                            <description>Periodic transaction timeout interrupt enable</description>
                            <lsb>3</lsb>
                            <msb>3</msb>
                            <access>read-write</access>
                            <enumeratedValues>
                                <enumeratedValue>
                                    <name>0</name>
                                    <description>Disabled</description>
                                    <value>#0</value>
                                </enumeratedValue>
                                <enumeratedValue>
                                    <name>1</name>
                                    <description>Enabled</description>
                                    <value>#1</value>
                                </enumeratedValue>
                            </enumeratedValues>
                        </field>
                        <field>
                            <name>DSTOCS0E</name>
                            <description>OM_DQS timeout for slave0 interrupt enable</description>
                            <lsb>4</lsb>
                            <msb>4</msb>
                            <access>read-write</access>
                            <enumeratedValues>
                                <enumeratedValue>
                                    <name>0</name>
                                    <description>Disabled</description>
                                    <value>#0</value>
                                </enumeratedValue>
                                <enumeratedValue>
                                    <name>1</name>
                                    <description>Enabled</description>
                                    <value>#1</value>
                                </enumeratedValue>
                            </enumeratedValues>
                        </field>
                        <field>
                            <name>DSTOCS1E</name>
                            <description>OM_DQS timeout for slave1 interrupt enable</description>
                            <lsb>5</lsb>
                            <msb>5</msb>
                            <access>read-write</access>
                            <enumeratedValues>
                                <enumeratedValue>
                                    <name>0</name>
                                    <description>Disabled</description>
                                    <value>#0</value>
                                </enumeratedValue>
                                <enumeratedValue>
                                    <name>1</name>
                                    <description>Enabled</description>
                                    <value>#1</value>
                                </enumeratedValue>
                            </enumeratedValues>
                        </field>
                        <field>
                            <name>ECSCS1E</name>
                            <description>ECC error detection for slave1 interrupt enable</description>
                            <lsb>9</lsb>
                            <msb>9</msb>
                            <access>read-write</access>
                            <enumeratedValues>
                                <enumeratedValue>
                                    <name>0</name>
                                    <description>Disabled</description>
                                    <value>#0</value>
                                </enumeratedValue>
                                <enumeratedValue>
                                    <name>1</name>
                                    <description>Enabled</description>
                                    <value>#1</value>
                                </enumeratedValue>
                            </enumeratedValues>
                        </field>
                        <field>
                            <name>INTCS1E</name>
                            <description>Interrupt detection for slave1 interrupt enable</description>
                            <lsb>13</lsb>
                            <msb>13</msb>
                            <access>read-write</access>
                            <enumeratedValues>
                                <enumeratedValue>
                                    <name>0</name>
                                    <description>Disabled</description>
                                    <value>#0</value>
                                </enumeratedValue>
                                <enumeratedValue>
                                    <name>1</name>
                                    <description>Enabled</description>
                                    <value>#1</value>
                                </enumeratedValue>
                            </enumeratedValues>
                        </field>
                        <field>
                            <name>BUSERRCH0E</name>
                            <description>System bus error for ch0 interrupt enable</description>
                            <lsb>20</lsb>
                            <msb>20</msb>
                            <access>read-write</access>
                            <enumeratedValues>
                                <enumeratedValue>
                                    <name>0</name>
                                    <description>Disabled</description>
                                    <value>#0</value>
                                </enumeratedValue>
                                <enumeratedValue>
                                    <name>1</name>
                                    <description>Enabled</description>
                                    <value>#1</value>
                                </enumeratedValue>
                            </enumeratedValues>
                        </field>
                        <field>
                            <name>CAFAILCS0E</name>
                            <description>Calibration failed for slave0 interrupt enable</description>
                            <lsb>28</lsb>
                            <msb>28</msb>
                            <access>read-write</access>
                            <enumeratedValues>
                                <enumeratedValue>
                                    <name>0</name>
                                    <description>Disabled</description>
                                    <value>#0</value>
                                </enumeratedValue>
                                <enumeratedValue>
                                    <name>1</name>
                                    <description>Enabled</description>
                                    <value>#1</value>
                                </enumeratedValue>
                            </enumeratedValues>
                        </field>
                        <field>
                            <name>CAFAILCS1E</name>
                            <description>Calibration failed for slave1 interrupt enable</description>
                            <lsb>29</lsb>
                            <msb>29</msb>
                            <access>read-write</access>
                            <enumeratedValues>
                                <enumeratedValue>
                                    <name>0</name>
                                    <description>Disabled</description>
                                    <value>#0</value>
                                </enumeratedValue>
                                <enumeratedValue>
                                    <name>1</name>
                                    <description>Enabled</description>
                                    <value>#1</value>
                                </enumeratedValue>
                            </enumeratedValues>
                        </field>
                        <field>
                            <name>CASUCCS0E</name>
                            <description>Calibration success for slave0 interrupt enable</description>
                            <lsb>30</lsb>
                            <msb>30</msb>
                            <access>read-write</access>
                            <enumeratedValues>
                                <enumeratedValue>
                                    <name>0</name>
                                    <description>Disabled</description>
                                    <value>#0</value>
                                </enumeratedValue>
                                <enumeratedValue>
                                    <name>1</name>
                                    <description>Enabled</description>
                                    <value>#1</value>
                                </enumeratedValue>
                            </enumeratedValues>
                        </field>
                        <field>
                            <name>CASUCCS1E</name>
                            <description>Calibration success for slave1 interrupt enable</description>
                            <lsb>31</lsb>
                            <msb>31</msb>
                            <access>read-write</access>
                            <enumeratedValues>
                                <enumeratedValue>
                                    <name>0</name>
                                    <description>Disabled</description>
                                    <value>#0</value>
                                </enumeratedValue>
                                <enumeratedValue>
                                    <name>1</name>
                                    <description>Enabled</description>
                                    <value>#1</value>
                                </enumeratedValue>
                            </enumeratedValues>
                        </field>
                    </fields>
                </register>
            </registers>
        </peripheral>
        <peripheral>
            <name>CRC</name>
            <description>CRC Calculator</description>
            <baseAddress>0x40310000</baseAddress>
            <addressBlock>
                <offset>0x00</offset>
                <size>2</size>
                <usage>registers</usage>
            </addressBlock>
            <addressBlock>
                <offset>0x04</offset>
                <size>4</size>
                <usage>registers</usage>
            </addressBlock>
            <addressBlock>
                <offset>0x08</offset>
                <size>4</size>
                <usage>registers</usage>
            </addressBlock>
            <addressBlock>
                <offset>0x0C</offset>
                <size>2</size>
                <usage>registers</usage>
            </addressBlock>
            <registers>
                <register>
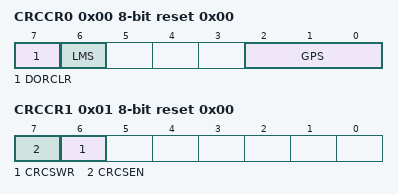
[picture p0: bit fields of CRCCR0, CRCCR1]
                    <name>CRCCR0</name>
                    <description>CRC Control Register 0</description>
                    <addressOffset>0x00</addressOffset>
                    <size>8</size>
                    <access>read-write</access>
                    <resetValue>0x00</resetValue>
                    <resetMask>0xff</resetMask>
                    <fields>
                        <field>
                            <name>GPS</name>
                            <description>CRC Generating Polynomial Switching</description>
                            <lsb>0</lsb>
                            <msb>2</msb>
                            <access>read-write</access>
                            <enumeratedValues>
                                <enumeratedValue>
                                    <name>001</name>
                                    <description>8-bit CRC-8 (X8 + X2 + X + 1)</description>
                                    <value>#001</value>
                                </enumeratedValue>
                                <enumeratedValue>
                                    <name>010</name>
                                    <description>16-bit CRC-16 (X16 + X15 + X2 + 1)</description>
                                    <value>#010</value>
                                </enumeratedValue>
                                <enumeratedValue>
                                    <name>011</name>
                                    <description>16-bit CRC-CCITT (X16 + X12 + X5 + 1)</description>
                                    <value>#011</value>
                                </enumeratedValue>
                                <enumeratedValue>
                                    <name>100</name>
                                    <description>32-bit CRC-32 (X32 + X26 + X23 + X22 + X16 + X12 + X11 +X10 + X8 + X7 + X5 + X4 + X2 + X + 1)</description>
                                    <value>#100</value>
                                </enumeratedValue>
                                <enumeratedValue>
                                    <name>101</name>
                                    <description>32-bit CRC-32C (X32 + X28 + X27 + X26 + X25 + X23 + X22 + X20 + X19 + X18 + X14 + X13 + X11 + X10 + X9 + X8 + X6 + 1)</description>
                                    <value>#101</value>
                                </enumeratedValue>
                                <enumeratedValue>
                                    <name>Others</name>
                                    <description>No calculation is executed</description>
                                    <isDefault>true</isDefault>
                                </enumeratedValue>
                            </enumeratedValues>
                        </field>
                        <field>
                            <name>LMS</name>
                            <description>CRC Calculation Switching</description>
                            <lsb>6</lsb>
                            <msb>6</msb>
                            <access>read-write</access>
                            <enumeratedValues>
                                <enumeratedValue>
                                    <name>0</name>
                                    <description>Generate CRC code for LSB-first communication</description>
                                    <value>#0</value>
                                </enumeratedValue>
                                <enumeratedValue>
                                    <name>1</name>
                                    <description>Generate CRC code for MSB-first communication</description>
                                    <value>#1</value>
                                </enumeratedValue>
                            </enumeratedValues>
                        </field>
                        <field>
                            <name>DORCLR</name>
                            <description>CRCDOR/CRCDOR_HA/CRCDOR_BY Register Clear</description>
                            <lsb>7</lsb>
                            <msb>7</msb>
                            <access>write-only</access>
                            <enumeratedValues>
                                <enumeratedValue>
                                    <name>0</name>
                                    <description>No effect</description>
                                    <value>#0</value>
                                </enumeratedValue>
                                <enumeratedValue>
                                    <name>1</name>
                                    <description>Clear the CRCDOR/CRCDOR_HA/CRCDOR_BY register</description>
                                    <value>#1</value>
                                </enumeratedValue>
                            </enumeratedValues>
                        </field>
                    </fields>
                </register>
                <register>
                    <name>CRCCR1</name>
                    <description>CRC Control Register 1</description>
                    <addressOffset>0x01</addressOffset>
                    <size>8</size>
                    <access>read-write</access>
                    <resetValue>0x00</resetValue>
                    <resetMask>0xff</resetMask>
                    <fields>
                        <field>
                            <name>CRCSWR</name>
                            <description>Snoop-On-Write/Read Switch</description>
                            <lsb>6</lsb>
                            <msb>6</msb>
                            <access>read-write</access>
                            <enumeratedValues>
                                <enumeratedValue>
                                    <name>0</name>
                                    <description>Snoop-on-read</description>
                                    <value>#0</value>
                                </enumeratedValue>
                                <enumeratedValue>
                                    <name>1</name>
                                    <description>Snoop-on-write</description>
                                    <value>#1</value>
                                </enumeratedValue>
                            </enumeratedValues>
                        </field>
                        <field>
                            <name>CRCSEN</name>
                            <description>Snoop Enable</description>
                            <lsb>7</lsb>
                            <msb>7</msb>
                            <access>read-write</access>
                            <enumeratedValues>
                                <enumeratedValue>
                                    <name>0</name>
                                    <description>Disabled</description>
                                    <value>#0</value>
                                </enumeratedValue>
                                <enumeratedValue>
                                    <name>1</name>
                                    <description>Enabled</description>
                                    <value>#1</value>
                                </enumeratedValue>
                            </enumeratedValues>
                        </field>
                    </fields>
                </register>
                <register>
                    <name>CRCDIR</name>
                    <description>CRC Data Input Register</description>
                    <addressOffset>0x04</addressOffset>
                    <size>32</size>
                    <access>read-write</access>
                    <resetValue>0x00000000</resetValue>
                    <resetMask>0xffffffff</resetMask>
                </register>
                <register>
                    <name>CRCDIR_BY</name>
                    <description>CRC Data Input Register</description>
                    <alternateRegister>CRCDIR</alternateRegister>
                    <addressOffset>0x04</addressOffset>
                    <size>8</size>
                    <access>read-write</access>
                    <resetValue>0x00</resetValue>
                    <resetMask>0xff</resetMask>
                </register>
                <register>
                    <name>CRCDOR</name>
                    <description>CRC Data Output Register</description>
                    <addressOffset>0x08</addressOffset>
                    <size>32</size>
                    <access>read-write</access>
                    <resetValue>0x00000000</resetValue>
                    <resetMask>0xffffffff</resetMask>
                </register>
                <register>
                    <name>CRCDOR_HA</name>
                    <description>CRC Data Output Register</description>
                    <alternateRegister>CRCDOR</alternateRegister>
                    <addressOffset>0x08</addressOffset>
                    <size>16</size>
                    <access>read-write</access>
                    <resetValue>0x0000</resetValue>
                    <resetMask>0xffff</resetMask>
                </register>
                <register>
                    <name>CRCDOR_BY</name>
                    <description>CRC Data Output Register</description>
                    <alternateRegister>CRCDOR</alternateRegister>
                    <addressOffset>0x08</addressOffset>
                    <size>8</size>
                    <access>read-write</access>
                    <resetValue>0x00</resetValue>
                    <resetMask>0xff</resetMask>
                </register>
                <register>
                    <name>CRCSAR</name>
                    <description>Snoop Address Register</description>
                    <addressOffset>0x0C</addressOffset>
                    <size>16</size>
                    <access>read-write</access>
                    <resetValue>0x0000</resetValue>
                    <resetMask>0xffff</resetMask>
                    <fields>
                        <field>
                            <name>CRCSA</name>
                            <description>Register Snoop Address</description>
                            <lsb>0</lsb>
                            <msb>13</msb>
                            <access>read-write</access>
                        </field>
                    </fields>
                </register>
            </registers>
        </peripheral>
        <peripheral>
            <name>DOC_B</name>
            <description>Data Operation Circuit</description>
            <baseAddress>0x40311000</baseAddress>
            <addressBlock>
                <offset>0x00</offset>
                <size>1</size>
                <usage>registers</usage>
            </addressBlock>
            <addressBlock>
                <offset>0x04</offset>
                <size>1</size>
                <usage>registers</usage>
            </addressBlock>
            <addressBlock>
                <offset>0x08</offset>
                <size>1</size>
                <usage>registers</usage>
            </addressBlock>
            <addressBlock>
                <offset>0x0C</offset>
                <size>12</size>
                <usage>registers</usage>
            </addressBlock>
            <registers>
                <register>
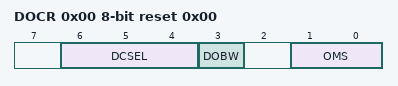
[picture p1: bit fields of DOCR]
                    <name>DOCR</name>
                    <description>DOC Control Register</description>
                    <addressOffset>0x00</addressOffset>
                    <size>8</size>
                    <access>read-write</access>
                    <resetValue>0x00</resetValue>
                    <resetMask>0xff</resetMask>
                    <fields>
                        <field>
                            <name>OMS</name>
                            <description>Operating Mode Select</description>
                            <lsb>0</lsb>
                            <msb>1</msb>
                            <access>read-write</access>
                            <enumeratedValues>
                                <enumeratedValue>
                                    <name>00</name>
                                    <description>Data comparison mode</description>
                                    <value>#00</value>
                                </enumeratedValue>
                                <enumeratedValue>
                                    <name>01</name>
                                    <description>Data addition mode</description>
                                    <value>#01</value>
                                </enumeratedValue>
                                <enumeratedValue>
                                    <name>10</name>
                                    <description>Data subtraction mode</description>
                                    <value>#10</value>
                                </enumeratedValue>
                                <enumeratedValue>
                                    <name>11</name>
                                    <description>Setting prohibited</description>
                                    <value>#11</value>
                                </enumeratedValue>
                            </enumeratedValues>
                        </field>
                        <field>
                            <name>DOBW</name>
                            <description>Data Operation Bit Width Select</description>
                            <lsb>3</lsb>
                            <msb>3</msb>
                            <access>read-write</access>
                            <enumeratedValues>
                                <enumeratedValue>
                                    <name>0</name>
                                    <description>16-bit</description>
                                    <value>#0</value>
                                </enumeratedValue>
                                <enumeratedValue>
                                    <name>1</name>
                                    <description>32-bit</description>
                                    <value>#1</value>
                                </enumeratedValue>
                            </enumeratedValues>
                        </field>
                        <field>
                            <name>DCSEL</name>
                            <description>Detection Condition Select</description>
                            <lsb>4</lsb>
                            <msb>6</msb>
                            <access>read-write</access>
                            <enumeratedValues>
                                <enumeratedValue>
                                    <name>000</name>
                                    <description>Mismatch (DODSR0 ≠ DODIR)</description>
                                    <value>#000</value>
                                </enumeratedValue>
                                <enumeratedValue>
                                    <name>001</name>
                                    <description>Match (DODSR0 = DODIR)</description>
                                    <value>#001</value>
                                </enumeratedValue>
                                <enumeratedValue>
                                    <name>010</name>
                                    <description>Lower (DODSR0 &gt; DODIR)</description>
                                    <value>#010</value>
                                </enumeratedValue>
                                <enumeratedValue>
                                    <name>011</name>
                                    <description>Upper (DODSR0 &lt; DODIR)</description>
                                    <value>#011</value>
                                </enumeratedValue>
                                <enumeratedValue>
                                    <name>100</name>
                                    <description>Inside window (DODSR0 &lt; DODIR &lt; DODSR1)</description>
                                    <value>#100</value>
                                </enumeratedValue>
                                <enumeratedValue>
                                    <name>101</name>
                                    <description>Outside window (DODIR &lt; DODSR0, DODSR1 &lt; DODIR)</description>
                                    <value>#101</value>
                                </enumeratedValue>
                                <enumeratedValue>
                                    <name>Others</name>
                                    <description>Setting prohibited</description>
                                    <isDefault>true</isDefault>
                                </enumeratedValue>
                            </enumeratedValues>
                        </field>
                    </fields>
                </register>
                <register>
                    <name>DOSR</name>
                    <description>DOC Flag Status Register</description>
                    <addressOffset>0x04</addressOffset>
                    <size>8</size>
                    <access>read-only</access>
                    <resetValue>0x00</resetValue>
                    <resetMask>0xff</resetMask>
                    <fields>
                        <field>
                            <name>DOPCF</name>
                            <description>Data Operation Circuit Flag</description>
                            <lsb>0</lsb>
                            <msb>0</msb>
                            <access>read-only</access>
                        </field>
                    </fields>
                </register>
                <register>
                    <name>DOSCR</name>
                    <description>DOC Flag Status Clear Register</description>
                    <addressOffset>0x08</addressOffset>
                    <size>8</size>
                    <access>write-only</access>
                    <resetValue>0x00</resetValue>
                    <resetMask>0xff</resetMask>
                    <fields>
                        <field>
                            <name>DOPCFCL</name>
                            <description>DOPCF Clear</description>
                            <lsb>0</lsb>
                            <msb>0</msb>
                            <access>write-only</access>
                            <enumeratedValues>
                                <enumeratedValue>
                                    <name>0</name>
                                    <description>Maintains the DOPCF flag state.</description>
                                    <value>#0</value>
                                </enumeratedValue>
                                <enumeratedValue>
                                    <name>1</name>
                                    <description>Clears the DOPCF flag.</description>
                                    <value>#1</value>
                                </enumeratedValue>
                            </enumeratedValues>
                        </field>
                    </fields>
                </register>
                <register>
                    <name>DODIR</name>
                    <description>DOC Data Input Register</description>
                    <addressOffset>0x0C</addressOffset>
                    <size>32</size>
                    <access>read-write</access>
                    <resetValue>0x00000000</resetValue>
                    <resetMask>0xffffffff</resetMask>
                </register>
                <register>
                    <name>DODSR0</name>
                    <description>DOC Data Setting Register 0</description>
                    <addressOffset>0x10</addressOffset>
                    <size>32</size>
                    <access>read-write</access>
                    <resetValue>0x00000000</resetValue>
                    <resetMask>0xffffffff</resetMask>
                </register>
                <register>
                    <name>DODSR1</name>
                    <description>DOC Data Setting Register 1</description>
                    <addressOffset>0x14</addressOffset>
                    <size>32</size>
                    <access>read-write</access>
                    <resetValue>0x00000000</resetValue>
                    <resetMask>0xffffffff</resetMask>
                </register>
            </registers>
        </peripheral>
        <peripheral>
            <name>GPT320</name>
            <description>General PWM 32-bit Timer 0</description>
            <baseAddress>0x40322000</baseAddress>
            <addressBlock>
                <offset>0x00</offset>
                <size>68</size>
                <usage>registers</usage>
            </addressBlock>
            <addressBlock>
                <offset>0x48</offset>
                <size>36</size>
                <usage>registers</usage>
            </addressBlock>
            <addressBlock>
                <offset>0x70</offset>
                <size>32</size>
                <usage>registers</usage>
            </addressBlock>
            <addressBlock>
                <offset>0xA4</offset>
                <size>4</size>
                <usage>registers</usage>
            </addressBlock>
            <addressBlock>
                <offset>0xB8</offset>
                <size>8</size>
                <usage>registers</usage>
            </addressBlock>
            <addressBlock>
                <offset>0xD0</offset>
                <size>8</size>
                <usage>registers</usage>
            </addressBlock>
            <registers>
                <register>
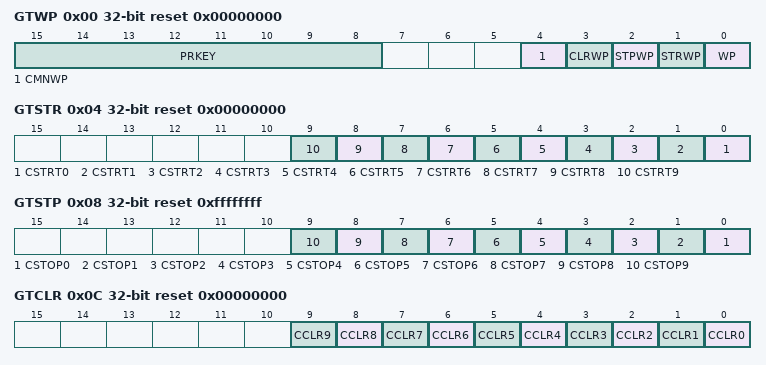
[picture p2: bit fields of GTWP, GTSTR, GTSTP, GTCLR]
                    <name>GTWP</name>
                    <description>General PWM Timer Write-Protection Register</description>
                    <addressOffset>0x00</addressOffset>
                    <size>32</size>
                    <access>read-write</access>
                    <resetValue>0x00000000</resetValue>
                    <resetMask>0xffffffff</resetMask>
                    <fields>
                        <field>
                            <name>WP</name>
                            <description>Register Write Disable</description>
                            <lsb>0</lsb>
                            <msb>0</msb>
                            <access>read-write</access>
                            <enumeratedValues>
                                <enumeratedValue>
                                    <name>0</name>
                                    <description>Write to the register enabled</description>
                                    <value>#0</value>
                                </enumeratedValue>
                                <enumeratedValue>
                                    <name>1</name>
                                    <description>Write to the register disabled</description>
                                    <value>#1</value>
                                </enumeratedValue>
                            </enumeratedValues>
                        </field>
                        <field>
                            <name>STRWP</name>
                            <description>GTSTR.CSTRT Bit Write Disable</description>
                            <lsb>1</lsb>
                            <msb>1</msb>
                            <access>read-write</access>
                            <enumeratedValues>
                                <enumeratedValue>
                                    <name>0</name>
                                    <description>Write to the bit is enabled</description>
                                    <value>#0</value>
                                </enumeratedValue>
                                <enumeratedValue>
                                    <name>1</name>
                                    <description>Write to the bit is disabled</description>
                                    <value>#1</value>
                                </enumeratedValue>
                            </enumeratedValues>
                        </field>
                        <field>
                            <name>STPWP</name>
                            <description>GTSTP.CSTOP Bit Write Disable</description>
                            <lsb>2</lsb>
                            <msb>2</msb>
                            <access>read-write</access>
                            <enumeratedValues>
                                <enumeratedValue>
                                    <name>0</name>
                                    <description>Write to the bit is enabled</description>
                                    <value>#0</value>
                                </enumeratedValue>
                                <enumeratedValue>
                                    <name>1</name>
                                    <description>Write to the bit is disabled</description>
                                    <value>#1</value>
                                </enumeratedValue>
                            </enumeratedValues>
                        </field>
                        <field>
                            <name>CLRWP</name>
                            <description>GTCLR.CCLR Bit Write Disable</description>
                            <lsb>3</lsb>
                            <msb>3</msb>
                            <access>read-write</access>
                            <enumeratedValues>
                                <enumeratedValue>
                                    <name>0</name>
                                    <description>Write to the bit is enabled</description>
                                    <value>#0</value>
                                </enumeratedValue>
                                <enumeratedValue>
                                    <name>1</name>
                                    <description>Write to the bit is disabled</description>
                                    <value>#1</value>
                                </enumeratedValue>
                            </enumeratedValues>
                        </field>
                        <field>
                            <name>CMNWP</name>
                            <description>Common Register Write Disabled</description>
                            <lsb>4</lsb>
                            <msb>4</msb>
                            <access>read-write</access>
                            <enumeratedValues>
                                <enumeratedValue>
                                    <name>0</name>
                                    <description>Write to the register is enabled</description>
                                    <value>#0</value>
                                </enumeratedValue>
                                <enumeratedValue>
                                    <name>1</name>
                                    <description>Write to the register is disabled</description>
                                    <value>#1</value>
                                </enumeratedValue>
                            </enumeratedValues>
                        </field>
                        <field>
                            <name>PRKEY</name>
                            <description>GTWP Key Code</description>
                            <lsb>8</lsb>
                            <msb>15</msb>
                            <access>write-only</access>
                        </field>
                    </fields>
                </register>
                <register>
                    <name>GTSTR</name>
                    <description>General PWM Timer Software Start Register</description>
                    <addressOffset>0x04</addressOffset>
                    <size>32</size>
                    <access>read-write</access>
                    <resetValue>0x00000000</resetValue>
                    <resetMask>0xffffffff</resetMask>
                    <fields>
                        <field>
                            <name>CSTRT0</name>
                            <description>Channel n GTCNT Count Start (n : the same as bit position value)</description>
                            <lsb>0</lsb>
                            <msb>0</msb>
                            <access>read-write</access>
                            <enumeratedValues>
                                <enumeratedValue>
                                    <name>0</name>
                                    <description>GTCNT counter not start</description>
                                    <value>#0</value>
                                </enumeratedValue>
                                <enumeratedValue>
                                    <name>1</name>
                                    <description>GTCNT counter start</description>
                                    <value>#1</value>
                                </enumeratedValue>
                            </enumeratedValues>
                        </field>
                        <field>
                            <name>CSTRT1</name>
                            <description>Channel n GTCNT Count Start (n : the same as bit position value)</description>
                            <lsb>1</lsb>
                            <msb>1</msb>
                            <access>read-write</access>
                            <enumeratedValues>
                                <enumeratedValue>
                                    <name>0</name>
                                    <description>GTCNT counter not start</description>
                                    <value>#0</value>
                                </enumeratedValue>
                                <enumeratedValue>
                                    <name>1</name>
                                    <description>GTCNT counter start</description>
                                    <value>#1</value>
                                </enumeratedValue>
                            </enumeratedValues>
                        </field>
                        <field>
                            <name>CSTRT2</name>
                            <description>Channel n GTCNT Count Start (n : the same as bit position value)</description>
                            <lsb>2</lsb>
                            <msb>2</msb>
                            <access>read-write</access>
                            <enumeratedValues>
                                <enumeratedValue>
                                    <name>0</name>
                                    <description>GTCNT counter not start</description>
                                    <value>#0</value>
                                </enumeratedValue>
                                <enumeratedValue>
                                    <name>1</name>
                                    <description>GTCNT counter start</description>
                                    <value>#1</value>
                                </enumeratedValue>
                            </enumeratedValues>
                        </field>
                        <field>
                            <name>CSTRT3</name>
                            <description>Channel n GTCNT Count Start (n : the same as bit position value)</description>
                            <lsb>3</lsb>
                            <msb>3</msb>
                            <access>read-write</access>
                            <enumeratedValues>
                                <enumeratedValue>
                                    <name>0</name>
                                    <description>GTCNT counter not start</description>
                                    <value>#0</value>
                                </enumeratedValue>
                                <enumeratedValue>
                                    <name>1</name>
                                    <description>GTCNT counter start</description>
                                    <value>#1</value>
                                </enumeratedValue>
                            </enumeratedValues>
                        </field>
                        <field>
                            <name>CSTRT4</name>
                            <description>Channel n GTCNT Count Start (n : the same as bit position value)</description>
                            <lsb>4</lsb>
                            <msb>4</msb>
                            <access>read-write</access>
                            <enumeratedValues>
                                <enumeratedValue>
                                    <name>0</name>
                                    <description>GTCNT counter not start</description>
                                    <value>#0</value>
                                </enumeratedValue>
                                <enumeratedValue>
                                    <name>1</name>
                                    <description>GTCNT counter start</description>
                                    <value>#1</value>
                                </enumeratedValue>
                            </enumeratedValues>
                        </field>
                        <field>
                            <name>CSTRT5</name>
                            <description>Channel n GTCNT Count Start (n : the same as bit position value)</description>
                            <lsb>5</lsb>
                            <msb>5</msb>
                            <access>read-write</access>
                            <enumeratedValues>
                                <enumeratedValue>
                                    <name>0</name>
                                    <description>GTCNT counter not start</description>
                                    <value>#0</value>
                                </enumeratedValue>
                                <enumeratedValue>
                                    <name>1</name>
                                    <description>GTCNT counter start</description>
                                    <value>#1</value>
                                </enumeratedValue>
                            </enumeratedValues>
                        </field>
                        <field>
                            <name>CSTRT6</name>
                            <description>Channel n GTCNT Count Start (n : the same as bit position value)</description>
                            <lsb>6</lsb>
                            <msb>6</msb>
                            <access>read-write</access>
                            <enumeratedValues>
                                <enumeratedValue>
                                    <name>0</name>
                                    <description>GTCNT counter not start</description>
                                    <value>#0</value>
                                </enumeratedValue>
                                <enumeratedValue>
                                    <name>1</name>
                                    <description>GTCNT counter start</description>
                                    <value>#1</value>
                                </enumeratedValue>
                            </enumeratedValues>
                        </field>
                        <field>
                            <name>CSTRT7</name>
                            <description>Channel n GTCNT Count Start (n : the same as bit position value)</description>
                            <lsb>7</lsb>
                            <msb>7</msb>
                            <access>read-write</access>
                            <enumeratedValues>
                                <enumeratedValue>
                                    <name>0</name>
                                    <description>GTCNT counter not start</description>
                                    <value>#0</value>
                                </enumeratedValue>
                                <enumeratedValue>
                                    <name>1</name>
                                    <description>GTCNT counter start</description>
                                    <value>#1</value>
                                </enumeratedValue>
                            </enumeratedValues>
                        </field>
                        <field>
                            <name>CSTRT8</name>
                            <description>Channel n GTCNT Count Start (n : the same as bit position value)</description>
                            <lsb>8</lsb>
                            <msb>8</msb>
                            <access>read-write</access>
                            <enumeratedValues>
                                <enumeratedValue>
                                    <name>0</name>
                                    <description>GTCNT counter not start</description>
                                    <value>#0</value>
                                </enumeratedValue>
                                <enumeratedValue>
                                    <name>1</name>
                                    <description>GTCNT counter start</description>
                                    <value>#1</value>
                                </enumeratedValue>
                            </enumeratedValues>
                        </field>
                        <field>
                            <name>CSTRT9</name>
                            <description>Channel n GTCNT Count Start (n : the same as bit position value)</description>
                            <lsb>9</lsb>
                            <msb>9</msb>
                            <access>read-write</access>
                            <enumeratedValues>
                                <enumeratedValue>
                                    <name>0</name>
                                    <description>GTCNT counter not start</description>
                                    <value>#0</value>
                                </enumeratedValue>
                                <enumeratedValue>
                                    <name>1</name>
                                    <description>GTCNT counter start</description>
                                    <value>#1</value>
                                </enumeratedValue>
                            </enumeratedValues>
                        </field>
                    </fields>
                </register>
                <register>
                    <name>GTSTP</name>
                    <description>General PWM Timer Software Stop Register</description>
                    <addressOffset>0x08</addressOffset>
                    <size>32</size>
                    <access>read-write</access>
                    <resetValue>0xffffffff</resetValue>
                    <resetMask>0xffffffff</resetMask>
                    <fields>
                        <field>
                            <name>CSTOP0</name>
                            <description>Channel n GTCNT Count Stop (n : the same as bit position value)</description>
                            <lsb>0</lsb>
                            <msb>0</msb>
                            <access>read-write</access>
                            <enumeratedValues>
                                <enumeratedValue>
                                    <name>0</name>
                                    <description>GTCNT counter not stop</description>
                                    <value>#0</value>
                                </enumeratedValue>
                                <enumeratedValue>
                                    <name>1</name>
                                    <description>GTCNT counter stop</description>
                                    <value>#1</value>
                                </enumeratedValue>
                            </enumeratedValues>
                        </field>
                        <field>
                            <name>CSTOP1</name>
                            <description>Channel n GTCNT Count Stop (n : the same as bit position value)</description>
                            <lsb>1</lsb>
                            <msb>1</msb>
                            <access>read-write</access>
                            <enumeratedValues>
                                <enumeratedValue>
                                    <name>0</name>
                                    <description>GTCNT counter not stop</description>
                                    <value>#0</value>
                                </enumeratedValue>
                                <enumeratedValue>
                                    <name>1</name>
                                    <description>GTCNT counter stop</description>
                                    <value>#1</value>
                                </enumeratedValue>
                            </enumeratedValues>
                        </field>
                        <field>
                            <name>CSTOP2</name>
                            <description>Channel n GTCNT Count Stop (n : the same as bit position value)</description>
                            <lsb>2</lsb>
                            <msb>2</msb>
                            <access>read-write</access>
                            <enumeratedValues>
                                <enumeratedValue>
                                    <name>0</name>
                                    <description>GTCNT counter not stop</description>
                                    <value>#0</value>
                                </enumeratedValue>
                                <enumeratedValue>
                                    <name>1</name>
                                    <description>GTCNT counter stop</description>
                                    <value>#1</value>
                                </enumeratedValue>
                            </enumeratedValues>
                        </field>
                        <field>
                            <name>CSTOP3</name>
                            <description>Channel n GTCNT Count Stop (n : the same as bit position value)</description>
                            <lsb>3</lsb>
                            <msb>3</msb>
                            <access>read-write</access>
                            <enumeratedValues>
                                <enumeratedValue>
                                    <name>0</name>
                                    <description>GTCNT counter not stop</description>
                                    <value>#0</value>
                                </enumeratedValue>
                                <enumeratedValue>
                                    <name>1</name>
                                    <description>GTCNT counter stop</description>
                                    <value>#1</value>
                                </enumeratedValue>
                            </enumeratedValues>
                        </field>
                        <field>
                            <name>CSTOP4</name>
                            <description>Channel n GTCNT Count Stop (n : the same as bit position value)</description>
                            <lsb>4</lsb>
                            <msb>4</msb>
                            <access>read-write</access>
                            <enumeratedValues>
                                <enumeratedValue>
                                    <name>0</name>
                                    <description>GTCNT counter not stop</description>
                                    <value>#0</value>
                                </enumeratedValue>
                                <enumeratedValue>
                                    <name>1</name>
                                    <description>GTCNT counter stop</description>
                                    <value>#1</value>
                                </enumeratedValue>
                            </enumeratedValues>
                        </field>
                        <field>
                            <name>CSTOP5</name>
                            <description>Channel n GTCNT Count Stop (n : the same as bit position value)</description>
                            <lsb>5</lsb>
                            <msb>5</msb>
                            <access>read-write</access>
                            <enumeratedValues>
                                <enumeratedValue>
                                    <name>0</name>
                                    <description>GTCNT counter not stop</description>
                                    <value>#0</value>
                                </enumeratedValue>
                                <enumeratedValue>
                                    <name>1</name>
                                    <description>GTCNT counter stop</description>
                                    <value>#1</value>
                                </enumeratedValue>
                            </enumeratedValues>
                        </field>
                        <field>
                            <name>CSTOP6</name>
                            <description>Channel n GTCNT Count Stop (n : the same as bit position value)</description>
                            <lsb>6</lsb>
                            <msb>6</msb>
                            <access>read-write</access>
                            <enumeratedValues>
                                <enumeratedValue>
                                    <name>0</name>
                                    <description>GTCNT counter not stop</description>
                                    <value>#0</value>
                                </enumeratedValue>
                                <enumeratedValue>
                                    <name>1</name>
                                    <description>GTCNT counter stop</description>
                                    <value>#1</value>
                                </enumeratedValue>
                            </enumeratedValues>
                        </field>
                        <field>
                            <name>CSTOP7</name>
                            <description>Channel n GTCNT Count Stop (n : the same as bit position value)</description>
                            <lsb>7</lsb>
                            <msb>7</msb>
                            <access>read-write</access>
                            <enumeratedValues>
                                <enumeratedValue>
                                    <name>0</name>
                                    <description>GTCNT counter not stop</description>
                                    <value>#0</value>
                                </enumeratedValue>
                                <enumeratedValue>
                                    <name>1</name>
                                    <description>GTCNT counter stop</description>
                                    <value>#1</value>
                                </enumeratedValue>
                            </enumeratedValues>
                        </field>
                        <field>
                            <name>CSTOP8</name>
                            <description>Channel n GTCNT Count Stop (n : the same as bit position value)</description>
                            <lsb>8</lsb>
                            <msb>8</msb>
                            <access>read-write</access>
                            <enumeratedValues>
                                <enumeratedValue>
                                    <name>0</name>
                                    <description>GTCNT counter not stop</description>
                                    <value>#0</value>
                                </enumeratedValue>
                                <enumeratedValue>
                                    <name>1</name>
                                    <description>GTCNT counter stop</description>
                                    <value>#1</value>
                                </enumeratedValue>
                            </enumeratedValues>
                        </field>
                        <field>
                            <name>CSTOP9</name>
                            <description>Channel n GTCNT Count Stop (n : the same as bit position value)</description>
                            <lsb>9</lsb>
                            <msb>9</msb>
                            <access>read-write</access>
                            <enumeratedValues>
                                <enumeratedValue>
                                    <name>0</name>
                                    <description>GTCNT counter not stop</description>
                                    <value>#0</value>
                                </enumeratedValue>
                                <enumeratedValue>
                                    <name>1</name>
                                    <description>GTCNT counter stop</description>
                                    <value>#1</value>
                                </enumeratedValue>
                            </enumeratedValues>
                        </field>
                    </fields>
                </register>
                <register>
                    <name>GTCLR</name>
                    <description>General PWM Timer Software Clear Register</description>
                    <addressOffset>0x0C</addressOffset>
                    <size>32</size>
                    <access>write-only</access>
                    <resetValue>0x00000000</resetValue>
                    <resetMask>0xffffffff</resetMask>
                    <fields>
                        <field>
                            <name>CCLR0</name>
                            <description>Channel n GTCNT Count Clear (n : the same as bit position value)</description>
                            <lsb>0</lsb>
                            <msb>0</msb>
                            <access>write-only</access>
                            <enumeratedValues>
                                <enumeratedValue>
                                    <name>0</name>
                                    <description>GTCNT counter is not cleared</description>
                                    <value>#0</value>
                                </enumeratedValue>
                                <enumeratedValue>
                                    <name>1</name>
                                    <description>GTCNT counter is cleared</description>
                                    <value>#1</value>
                                </enumeratedValue>
                            </enumeratedValues>
                        </field>
                        <field>
                            <name>CCLR1</name>
                            <description>Channel n GTCNT Count Clear (n : the same as bit position value)</description>
                            <lsb>1</lsb>
                            <msb>1</msb>
                            <access>write-only</access>
                            <enumeratedValues>
                                <enumeratedValue>
                                    <name>0</name>
                                    <description>GTCNT counter is not cleared</description>
                                    <value>#0</value>
                                </enumeratedValue>
                                <enumeratedValue>
                                    <name>1</name>
                                    <description>GTCNT counter is cleared</description>
                                    <value>#1</value>
                                </enumeratedValue>
                            </enumeratedValues>
                        </field>
                        <field>
                            <name>CCLR2</name>
                            <description>Channel n GTCNT Count Clear (n : the same as bit position value)</description>
                            <lsb>2</lsb>
                            <msb>2</msb>
                            <access>write-only</access>
                            <enumeratedValues>
                                <enumeratedValue>
                                    <name>0</name>
                                    <description>GTCNT counter is not cleared</description>
                                    <value>#0</value>
                                </enumeratedValue>
                                <enumeratedValue>
                                    <name>1</name>
                                    <description>GTCNT counter is cleared</description>
                                    <value>#1</value>
                                </enumeratedValue>
                            </enumeratedValues>
                        </field>
                        <field>
                            <name>CCLR3</name>
                            <description>Channel n GTCNT Count Clear (n : the same as bit position value)</description>
                            <lsb>3</lsb>
                            <msb>3</msb>
                            <access>write-only</access>
                            <enumeratedValues>
                                <enumeratedValue>
                                    <name>0</name>
                                    <description>GTCNT counter is not cleared</description>
                                    <value>#0</value>
                                </enumeratedValue>
                                <enumeratedValue>
                                    <name>1</name>
                                    <description>GTCNT counter is cleared</description>
                                    <value>#1</value>
                                </enumeratedValue>
                            </enumeratedValues>
                        </field>
                        <field>
                            <name>CCLR4</name>
                            <description>Channel n GTCNT Count Clear (n : the same as bit position value)</description>
                            <lsb>4</lsb>
                            <msb>4</msb>
                            <access>write-only</access>
                            <enumeratedValues>
                                <enumeratedValue>
                                    <name>0</name>
                                    <description>GTCNT counter is not cleared</description>
                                    <value>#0</value>
                                </enumeratedValue>
                                <enumeratedValue>
                                    <name>1</name>
                                    <description>GTCNT counter is cleared</description>
                                    <value>#1</value>
                                </enumeratedValue>
                            </enumeratedValues>
                        </field>
                        <field>
                            <name>CCLR5</name>
                            <description>Channel n GTCNT Count Clear (n : the same as bit position value)</description>
                            <lsb>5</lsb>
                            <msb>5</msb>
                            <access>write-only</access>
                            <enumeratedValues>
                                <enumeratedValue>
                                    <name>0</name>
                                    <description>GTCNT counter is not cleared</description>
                                    <value>#0</value>
                                </enumeratedValue>
                                <enumeratedValue>
                                    <name>1</name>
                                    <description>GTCNT counter is cleared</description>
                                    <value>#1</value>
                                </enumeratedValue>
                            </enumeratedValues>
                        </field>
                        <field>
                            <name>CCLR6</name>
                            <description>Channel n GTCNT Count Clear (n : the same as bit position value)</description>
                            <lsb>6</lsb>
                            <msb>6</msb>
                            <access>write-only</access>
                            <enumeratedValues>
                                <enumeratedValue>
                                    <name>0</name>
                                    <description>GTCNT counter is not cleared</description>
                                    <value>#0</value>
                                </enumeratedValue>
                                <enumeratedValue>
                                    <name>1</name>
                                    <description>GTCNT counter is cleared</description>
                                    <value>#1</value>
                                </enumeratedValue>
                            </enumeratedValues>
                        </field>
                        <field>
                            <name>CCLR7</name>
                            <description>Channel n GTCNT Count Clear (n : the same as bit position value)</description>
                            <lsb>7</lsb>
                            <msb>7</msb>
                            <access>write-only</access>
                            <enumeratedValues>
                                <enumeratedValue>
                                    <name>0</name>
                                    <description>GTCNT counter is not cleared</description>
                                    <value>#0</value>
                                </enumeratedValue>
                                <enumeratedValue>
                                    <name>1</name>
                                    <description>GTCNT counter is cleared</description>
                                    <value>#1</value>
                                </enumeratedValue>
                            </enumeratedValues>
                        </field>
                        <field>
                            <name>CCLR8</name>
                            <description>Channel n GTCNT Count Clear (n : the same as bit position value)</description>
                            <lsb>8</lsb>
                            <msb>8</msb>
                            <access>write-only</access>
                            <enumeratedValues>
                                <enumeratedValue>
                                    <name>0</name>
                                    <description>GTCNT counter is not cleared</description>
                                    <value>#0</value>
                                </enumeratedValue>
                                <enumeratedValue>
                                    <name>1</name>
                                    <description>GTCNT counter is cleared</description>
                                    <value>#1</value>
                                </enumeratedValue>
                            </enumeratedValues>
                        </field>
                        <field>
                            <name>CCLR9</name>
                            <description>Channel n GTCNT Count Clear (n : the same as bit position value)</description>
                            <lsb>9</lsb>
                            <msb>9</msb>
                            <access>write-only</access>
                            <enumeratedValues>
                                <enumeratedValue>
                                    <name>0</name>
                                    <description>GTCNT counter is not cleared</description>
                                    <value>#0</value>
                                </enumeratedValue>
                                <enumeratedValue>
                                    <name>1</name>
                                    <description>GTCNT counter is cleared</description>
                                    <value>#1</value>
                                </enumeratedValue>
                            </enumeratedValues>
                        </field>
                    </fields>
                </register>
                <register>
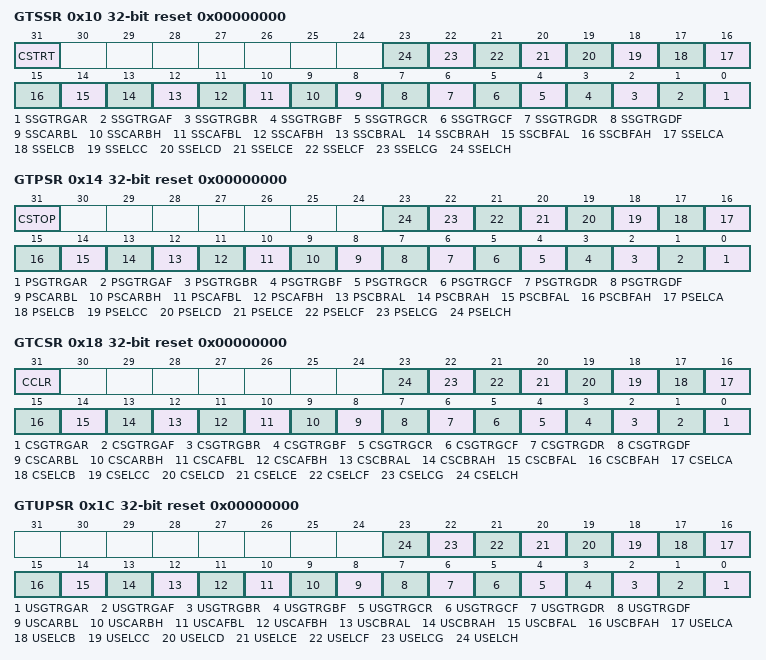
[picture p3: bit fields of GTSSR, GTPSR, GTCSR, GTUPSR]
                    <name>GTSSR</name>
                    <description>General PWM Timer Start Source Select Register</description>
                    <addressOffset>0x10</addressOffset>
                    <size>32</size>
                    <access>read-write</access>
                    <resetValue>0x00000000</resetValue>
                    <resetMask>0xffffffff</resetMask>
                    <fields>
                        <field>
                            <name>SSGTRGAR</name>
                            <description>GTETRGA Pin Rising Input Source Counter Start Enable</description>
                            <lsb>0</lsb>
                            <msb>0</msb>
                            <access>read-write</access>
                            <enumeratedValues>
                                <enumeratedValue>
                                    <name>0</name>
                                    <description>Counter start disabled on the rising edge of GTETRGA input</description>
                                    <value>#0</value>
                                </enumeratedValue>
                                <enumeratedValue>
                                    <name>1</name>
                                    <description>Counter start enabled on the rising edge of GTETRGA input</description>
                                    <value>#1</value>
                                </enumeratedValue>
                            </enumeratedValues>
                        </field>
                        <field>
                            <name>SSGTRGAF</name>
                            <description>GTETRGA Pin Falling Input Source Counter Start Enable</description>
                            <lsb>1</lsb>
                            <msb>1</msb>
                            <access>read-write</access>
                            <enumeratedValues>
                                <enumeratedValue>
                                    <name>0</name>
                                    <description>Counter start disabled on the falling edge of GTETRGA input</description>
                                    <value>#0</value>
                                </enumeratedValue>
                                <enumeratedValue>
                                    <name>1</name>
                                    <description>Counter start enabled on the falling edge of GTETRGA input</description>
                                    <value>#1</value>
                                </enumeratedValue>
                            </enumeratedValues>
                        </field>
                        <field>
                            <name>SSGTRGBR</name>
                            <description>GTETRGB Pin Rising Input Source Counter Start Enable</description>
                            <lsb>2</lsb>
                            <msb>2</msb>
                            <access>read-write</access>
                            <enumeratedValues>
                                <enumeratedValue>
                                    <name>0</name>
                                    <description>Counter start disabled on the rising edge of GTETRGB input</description>
                                    <value>#0</value>
                                </enumeratedValue>
                                <enumeratedValue>
                                    <name>1</name>
                                    <description>Counter start enabled on the rising edge of GTETRGB input</description>
                                    <value>#1</value>
                                </enumeratedValue>
                            </enumeratedValues>
                        </field>
                        <field>
                            <name>SSGTRGBF</name>
                            <description>GTETRGB Pin Falling Input Source Counter Start Enable</description>
                            <lsb>3</lsb>
                            <msb>3</msb>
                            <access>read-write</access>
                            <enumeratedValues>
                                <enumeratedValue>
                                    <name>0</name>
                                    <description>Counter start disabled on the falling edge of GTETRGB input</description>
                                    <value>#0</value>
                                </enumeratedValue>
                                <enumeratedValue>
                                    <name>1</name>
                                    <description>Counter start enabled on the falling edge of GTETRGB input</description>
                                    <value>#1</value>
                                </enumeratedValue>
                            </enumeratedValues>
                        </field>
                        <field>
                            <name>SSGTRGCR</name>
                            <description>GTETRGC Pin Rising Input Source Counter Start Enable</description>
                            <lsb>4</lsb>
                            <msb>4</msb>
                            <access>read-write</access>
                            <enumeratedValues>
                                <enumeratedValue>
                                    <name>0</name>
                                    <description>Counter start disabled on the rising edge of GTETRGC input</description>
                                    <value>#0</value>
                                </enumeratedValue>
                                <enumeratedValue>
                                    <name>1</name>
                                    <description>Counter start enabled on the rising edge of GTETRGC input</description>
                                    <value>#1</value>
                                </enumeratedValue>
                            </enumeratedValues>
                        </field>
                        <field>
                            <name>SSGTRGCF</name>
                            <description>GTETRGC Pin Falling Input Source Counter Start Enable</description>
                            <lsb>5</lsb>
                            <msb>5</msb>
                            <access>read-write</access>
                            <enumeratedValues>
                                <enumeratedValue>
                                    <name>0</name>
                                    <description>Counter start disabled on the falling edge of GTETRGC input</description>
                                    <value>#0</value>
                                </enumeratedValue>
                                <enumeratedValue>
                                    <name>1</name>
                                    <description>Counter start enabled on the falling edge of GTETRGC input</description>
                                    <value>#1</value>
                                </enumeratedValue>
                            </enumeratedValues>
                        </field>
                        <field>
                            <name>SSGTRGDR</name>
                            <description>GTETRGD Pin Rising Input Source Counter Start Enable</description>
                            <lsb>6</lsb>
                            <msb>6</msb>
                            <access>read-write</access>
                            <enumeratedValues>
                                <enumeratedValue>
                                    <name>0</name>
                                    <description>Counter start disabled on the rising edge of GTETRGD input</description>
                                    <value>#0</value>
                                </enumeratedValue>
                                <enumeratedValue>
                                    <name>1</name>
                                    <description>Counter start enabled on the rising edge of GTETRGD input</description>
                                    <value>#1</value>
                                </enumeratedValue>
                            </enumeratedValues>
                        </field>
                        <field>
                            <name>SSGTRGDF</name>
                            <description>GTETRGD Pin Falling Input Source Counter Start Enable</description>
                            <lsb>7</lsb>
                            <msb>7</msb>
                            <access>read-write</access>
                            <enumeratedValues>
                                <enumeratedValue>
                                    <name>0</name>
                                    <description>Counter start disabled on the falling edge of GTETRGD input</description>
                                    <value>#0</value>
                                </enumeratedValue>
                                <enumeratedValue>
                                    <name>1</name>
                                    <description>Counter start enabled on the falling edge of GTETRGD input</description>
                                    <value>#1</value>
                                </enumeratedValue>
                            </enumeratedValues>
                        </field>
                        <field>
                            <name>SSCARBL</name>
                            <description>GTIOCnA Pin Rising Input during GTIOCnB Value Low Source Counter Start Enable</description>
                            <lsb>8</lsb>
                            <msb>8</msb>
                            <access>read-write</access>
                            <enumeratedValues>
                                <enumeratedValue>
                                    <name>0</name>
                                    <description>Counter start disabled on the rising edge of GTIOCnA input when GTIOCnB input is 0</description>
                                    <value>#0</value>
                                </enumeratedValue>
                                <enumeratedValue>
                                    <name>1</name>
                                    <description>Counter start enabled on the rising edge of GTIOCnA input when GTIOCnB input is 0</description>
                                    <value>#1</value>
                                </enumeratedValue>
                            </enumeratedValues>
                        </field>
                        <field>
                            <name>SSCARBH</name>
                            <description>GTIOCnA Pin Rising Input during GTIOCnB Value High Source Counter Start Enable</description>
                            <lsb>9</lsb>
                            <msb>9</msb>
                            <access>read-write</access>
                            <enumeratedValues>
                                <enumeratedValue>
                                    <name>0</name>
                                    <description>Counter start disabled on the rising edge of GTIOCnA input when GTIOCnB input is 1</description>
                                    <value>#0</value>
                                </enumeratedValue>
                                <enumeratedValue>
                                    <name>1</name>
                                    <description>Counter start enabled on the rising edge of GTIOCnA input when GTIOCnB input is 1</description>
                                    <value>#1</value>
                                </enumeratedValue>
                            </enumeratedValues>
                        </field>
                        <field>
                            <name>SSCAFBL</name>
                            <description>GTIOCnA Pin Falling Input during GTIOCnB Value Low Source Counter Start Enable</description>
                            <lsb>10</lsb>
                            <msb>10</msb>
                            <access>read-write</access>
                            <enumeratedValues>
                                <enumeratedValue>
                                    <name>0</name>
                                    <description>Counter start disabled on the falling edge of GTIOCnA input when GTIOCnB input is 0</description>
                                    <value>#0</value>
                                </enumeratedValue>
                                <enumeratedValue>
                                    <name>1</name>
                                    <description>Counter start enabled on the falling edge of GTIOCnA input when GTIOCnB input is 0</description>
                                    <value>#1</value>
                                </enumeratedValue>
                            </enumeratedValues>
                        </field>
                        <field>
                            <name>SSCAFBH</name>
                            <description>GTIOCnA Pin Falling Input during GTIOCnB Value High Source Counter Start Enable</description>
                            <lsb>11</lsb>
                            <msb>11</msb>
                            <access>read-write</access>
                            <enumeratedValues>
                                <enumeratedValue>
                                    <name>0</name>
                                    <description>Counter start disabled on the falling edge of GTIOCnA input when GTIOCnB input is 1</description>
                                    <value>#0</value>
                                </enumeratedValue>
                                <enumeratedValue>
                                    <name>1</name>
                                    <description>Counter start enabled on the falling edge of GTIOCnA input when GTIOCnB input is 1</description>
                                    <value>#1</value>
                                </enumeratedValue>
                            </enumeratedValues>
                        </field>
                        <field>
                            <name>SSCBRAL</name>
                            <description>GTIOCnB Pin Rising Input during GTIOCnA Value Low Source Counter Start Enable</description>
                            <lsb>12</lsb>
                            <msb>12</msb>
                            <access>read-write</access>
                            <enumeratedValues>
                                <enumeratedValue>
                                    <name>0</name>
                                    <description>Counter start disabled on the rising edge of GTIOCnB input when GTIOCnA input is 0</description>
                                    <value>#0</value>
                                </enumeratedValue>
                                <enumeratedValue>
                                    <name>1</name>
                                    <description>Counter start enabled on the rising edge of GTIOCnB input when GTIOCnA input is 0</description>
                                    <value>#1</value>
                                </enumeratedValue>
                            </enumeratedValues>
                        </field>
                        <field>
                            <name>SSCBRAH</name>
                            <description>GTIOCnB Pin Rising Input during GTIOCnA Value High Source Counter Start Enable</description>
                            <lsb>13</lsb>
                            <msb>13</msb>
                            <access>read-write</access>
                            <enumeratedValues>
                                <enumeratedValue>
                                    <name>0</name>
                                    <description>Counter start disabled on the rising edge of GTIOCnB input when GTIOCnA input is 1</description>
                                    <value>#0</value>
                                </enumeratedValue>
                                <enumeratedValue>
                                    <name>1</name>
                                    <description>Counter start enabled on the rising edge of GTIOCnB input when GTIOCnA input is 1</description>
                                    <value>#1</value>
                                </enumeratedValue>
                            </enumeratedValues>
                        </field>
                        <field>
                            <name>SSCBFAL</name>
                            <description>GTIOCnB Pin Falling Input during GTIOCnA Value Low Source Counter Start Enable</description>
                            <lsb>14</lsb>
                            <msb>14</msb>
                            <access>read-write</access>
                            <enumeratedValues>
                                <enumeratedValue>
                                    <name>0</name>
                                    <description>Counter start disabled on the falling edge of GTIOCnB input when GTIOCnA input is 0</description>
                                    <value>#0</value>
                                </enumeratedValue>
                                <enumeratedValue>
                                    <name>1</name>
                                    <description>Counter start enabled on the falling edge of GTIOCnB input when GTIOCnA input is 0</description>
                                    <value>#1</value>
                                </enumeratedValue>
                            </enumeratedValues>
                        </field>
                        <field>
                            <name>SSCBFAH</name>
                            <description>GTIOCnB Pin Falling Input during GTIOCnA Value High Source Counter Start Enable</description>
                            <lsb>15</lsb>
                            <msb>15</msb>
                            <access>read-write</access>
                            <enumeratedValues>
                                <enumeratedValue>
                                    <name>0</name>
                                    <description>Counter start disabled on the falling edge of GTIOCnB input when GTIOCnA input is 1</description>
                                    <value>#0</value>
                                </enumeratedValue>
                                <enumeratedValue>
                                    <name>1</name>
                                    <description>Counter start enabled on the falling edge of GTIOCnB input when GTIOCnA input is 1</description>
                                    <value>#1</value>
                                </enumeratedValue>
                            </enumeratedValues>
                        </field>
                        <field>
                            <name>SSELCA</name>
                            <description>ELC_GPTA Event Source Counter Start Enable</description>
                            <lsb>16</lsb>
                            <msb>16</msb>
                            <access>read-write</access>
                            <enumeratedValues>
                                <enumeratedValue>
                                    <name>0</name>
                                    <description>Counter start disabled at the ELC_GPTA input</description>
                                    <value>#0</value>
                                </enumeratedValue>
                                <enumeratedValue>
                                    <name>1</name>
                                    <description>Counter start enabled at the ELC_GPTA input</description>
                                    <value>#1</value>
                                </enumeratedValue>
                            </enumeratedValues>
                        </field>
                        <field>
                            <name>SSELCB</name>
                            <description>ELC_GPTB Event Source Counter Start Enable</description>
                            <lsb>17</lsb>
                            <msb>17</msb>
                            <access>read-write</access>
                            <enumeratedValues>
                                <enumeratedValue>
                                    <name>0</name>
                                    <description>Counter start disabled at the ELC_GPTB input</description>
                                    <value>#0</value>
                                </enumeratedValue>
                                <enumeratedValue>
                                    <name>1</name>
                                    <description>Counter start enabled at the ELC_GPTB input</description>
                                    <value>#1</value>
                                </enumeratedValue>
                            </enumeratedValues>
                        </field>
                        <field>
                            <name>SSELCC</name>
                            <description>ELC_GPTC Event Source Counter Start Enable</description>
                            <lsb>18</lsb>
                            <msb>18</msb>
                            <access>read-write</access>
                            <enumeratedValues>
                                <enumeratedValue>
                                    <name>0</name>
                                    <description>Counter start disabled at the ELC_GPTC input</description>
                                    <value>#0</value>
                                </enumeratedValue>
                                <enumeratedValue>
                                    <name>1</name>
                                    <description>Counter start enabled at the ELC_GPTC input</description>
                                    <value>#1</value>
                                </enumeratedValue>
                            </enumeratedValues>
                        </field>
                        <field>
                            <name>SSELCD</name>
                            <description>ELC_GPTD Event Source Counter Start Enable</description>
                            <lsb>19</lsb>
                            <msb>19</msb>
                            <access>read-write</access>
                            <enumeratedValues>
                                <enumeratedValue>
                                    <name>0</name>
                                    <description>Counter start disabled at the ELC_GPTD input</description>
                                    <value>#0</value>
                                </enumeratedValue>
                                <enumeratedValue>
                                    <name>1</name>
                                    <description>Counter start enabled at the ELC_GPTD input</description>
                                    <value>#1</value>
                                </enumeratedValue>
                            </enumeratedValues>
                        </field>
                        <field>
                            <name>SSELCE</name>
                            <description>ELC_GPTE Event Source Counter Start Enable</description>
                            <lsb>20</lsb>
                            <msb>20</msb>
                            <access>read-write</access>
                            <enumeratedValues>
                                <enumeratedValue>
                                    <name>0</name>
                                    <description>Counter start disabled at the ELC_GPTE input</description>
                                    <value>#0</value>
                                </enumeratedValue>
                                <enumeratedValue>
                                    <name>1</name>
                                    <description>Counter start enabled at the ELC_GPTE input</description>
                                    <value>#1</value>
                                </enumeratedValue>
                            </enumeratedValues>
                        </field>
                        <field>
                            <name>SSELCF</name>
                            <description>ELC_GPTF Event Source Counter Start Enable</description>
                            <lsb>21</lsb>
                            <msb>21</msb>
                            <access>read-write</access>
                            <enumeratedValues>
                                <enumeratedValue>
                                    <name>0</name>
                                    <description>Counter start disabled at the ELC_GPTF input</description>
                                    <value>#0</value>
                                </enumeratedValue>
                                <enumeratedValue>
                                    <name>1</name>
                                    <description>Counter start enabled at the ELC_GPTF input</description>
                                    <value>#1</value>
                                </enumeratedValue>
                            </enumeratedValues>
                        </field>
                        <field>
                            <name>SSELCG</name>
                            <description>ELC_GPTG Event Source Counter Start Enable</description>
                            <lsb>22</lsb>
                            <msb>22</msb>
                            <access>read-write</access>
                            <enumeratedValues>
                                <enumeratedValue>
                                    <name>0</name>
                                    <description>Counter start disabled at the ELC_GPTG input</description>
                                    <value>#0</value>
                                </enumeratedValue>
                                <enumeratedValue>
                                    <name>1</name>
                                    <description>Counter start enabled at the ELC_GPTG input</description>
                                    <value>#1</value>
                                </enumeratedValue>
                            </enumeratedValues>
                        </field>
                        <field>
                            <name>SSELCH</name>
                            <description>ELC_GPTH Event Source Counter Start Enable</description>
                            <lsb>23</lsb>
                            <msb>23</msb>
                            <access>read-write</access>
                            <enumeratedValues>
                                <enumeratedValue>
                                    <name>0</name>
                                    <description>Counter start disabled at the ELC_GPTH input</description>
                                    <value>#0</value>
                                </enumeratedValue>
                                <enumeratedValue>
                                    <name>1</name>
                                    <description>Counter start enabled at the ELC_GPTH input</description>
                                    <value>#1</value>
                                </enumeratedValue>
                            </enumeratedValues>
                        </field>
                        <field>
                            <name>CSTRT</name>
                            <description>Software Source Counter Start Enable</description>
                            <lsb>31</lsb>
                            <msb>31</msb>
                            <access>read-write</access>
                            <enumeratedValues>
                                <enumeratedValue>
                                    <name>0</name>
                                    <description>Counter start disabled by the GTSTR register</description>
                                    <value>#0</value>
                                </enumeratedValue>
                                <enumeratedValue>
                                    <name>1</name>
                                    <description>Counter start enabled by the GTSTR register</description>
                                    <value>#1</value>
                                </enumeratedValue>
                            </enumeratedValues>
                        </field>
                    </fields>
                </register>
                <register>
                    <name>GTPSR</name>
                    <description>General PWM Timer Stop Source Select Register</description>
                    <addressOffset>0x14</addressOffset>
                    <size>32</size>
                    <access>read-write</access>
                    <resetValue>0x00000000</resetValue>
                    <resetMask>0xffffffff</resetMask>
                    <fields>
                        <field>
                            <name>PSGTRGAR</name>
                            <description>GTETRGA Pin Rising Input Source Counter Stop Enable</description>
                            <lsb>0</lsb>
                            <msb>0</msb>
                            <access>read-write</access>
                            <enumeratedValues>
                                <enumeratedValue>
                                    <name>0</name>
                                    <description>Counter stop disabled on the rising edge of GTETRGA input</description>
                                    <value>#0</value>
                                </enumeratedValue>
                                <enumeratedValue>
                                    <name>1</name>
                                    <description>Counter stop enabled on the rising edge of GTETRGA input</description>
                                    <value>#1</value>
                                </enumeratedValue>
                            </enumeratedValues>
                        </field>
                        <field>
                            <name>PSGTRGAF</name>
                            <description>GTETRGA Pin Falling Input Source Counter Stop Enable</description>
                            <lsb>1</lsb>
                            <msb>1</msb>
                            <access>read-write</access>
                            <enumeratedValues>
                                <enumeratedValue>
                                    <name>0</name>
                                    <description>Counter stop disabled on the falling edge of GTETRGA input</description>
                                    <value>#0</value>
                                </enumeratedValue>
                                <enumeratedValue>
                                    <name>1</name>
                                    <description>Counter stop enabled on the falling edge of GTETRGA input</description>
                                    <value>#1</value>
                                </enumeratedValue>
                            </enumeratedValues>
                        </field>
                        <field>
                            <name>PSGTRGBR</name>
                            <description>GTETRGB Pin Rising Input Source Counter Stop Enable</description>
                            <lsb>2</lsb>
                            <msb>2</msb>
                            <access>read-write</access>
                            <enumeratedValues>
                                <enumeratedValue>
                                    <name>0</name>
                                    <description>Counter stop disabled on the rising edge of GTETRGB input</description>
                                    <value>#0</value>
                                </enumeratedValue>
                                <enumeratedValue>
                                    <name>1</name>
                                    <description>Counter stop enabled on the rising edge of GTETRGB input</description>
                                    <value>#1</value>
                                </enumeratedValue>
                            </enumeratedValues>
                        </field>
                        <field>
                            <name>PSGTRGBF</name>
                            <description>GTETRGB Pin Falling Input Source Counter Stop Enable</description>
                            <lsb>3</lsb>
                            <msb>3</msb>
                            <access>read-write</access>
                            <enumeratedValues>
                                <enumeratedValue>
                                    <name>0</name>
                                    <description>Counter stop disabled on the falling edge of GTETRGB input</description>
                                    <value>#0</value>
                                </enumeratedValue>
                                <enumeratedValue>
                                    <name>1</name>
                                    <description>Counter stop enabled on the falling edge of GTETRGB input</description>
                                    <value>#1</value>
                                </enumeratedValue>
                            </enumeratedValues>
                        </field>
                        <field>
                            <name>PSGTRGCR</name>
                            <description>GTETRGC Pin Rising Input Source Counter Stop Enable</description>
                            <lsb>4</lsb>
                            <msb>4</msb>
                            <access>read-write</access>
                            <enumeratedValues>
                                <enumeratedValue>
                                    <name>0</name>
                                    <description>Counter stop disabled on the rising edge of GTETRGC input</description>
                                    <value>#0</value>
                                </enumeratedValue>
                                <enumeratedValue>
                                    <name>1</name>
                                    <description>Counter stop enabled on the rising edge of GTETRGC input</description>
                                    <value>#1</value>
                                </enumeratedValue>
                            </enumeratedValues>
                        </field>
                        <field>
                            <name>PSGTRGCF</name>
                            <description>GTETRGC Pin Falling Input Source Counter Stop Enable</description>
                            <lsb>5</lsb>
                            <msb>5</msb>
                            <access>read-write</access>
                            <enumeratedValues>
                                <enumeratedValue>
                                    <name>0</name>
                                    <description>Counter stop disabled on the falling edge of GTETRGC input</description>
                                    <value>#0</value>
                                </enumeratedValue>
                                <enumeratedValue>
                                    <name>1</name>
                                    <description>Counter stop enabled on the falling edge of GTETRGC input</description>
                                    <value>#1</value>
                                </enumeratedValue>
                            </enumeratedValues>
                        </field>
                        <field>
                            <name>PSGTRGDR</name>
                            <description>GTETRGD Pin Rising Input Source Counter Stop Enable</description>
                            <lsb>6</lsb>
                            <msb>6</msb>
                            <access>read-write</access>
                            <enumeratedValues>
                                <enumeratedValue>
                                    <name>0</name>
                                    <description>Counter stop disabled on the rising edge of GTETRGD input</description>
                                    <value>#0</value>
                                </enumeratedValue>
                                <enumeratedValue>
                                    <name>1</name>
                                    <description>Counter stop enabled on the rising edge of GTETRGD input</description>
                                    <value>#1</value>
                                </enumeratedValue>
                            </enumeratedValues>
                        </field>
                        <field>
                            <name>PSGTRGDF</name>
                            <description>GTETRGD Pin Falling Input Source Counter Stop Enable</description>
                            <lsb>7</lsb>
                            <msb>7</msb>
                            <access>read-write</access>
                            <enumeratedValues>
                                <enumeratedValue>
                                    <name>0</name>
                                    <description>Counter stop disabled on the falling edge of GTETRGD input</description>
                                    <value>#0</value>
                                </enumeratedValue>
                                <enumeratedValue>
                                    <name>1</name>
                                    <description>Counter stop enabled on the falling edge of GTETRGD input</description>
                                    <value>#1</value>
                                </enumeratedValue>
                            </enumeratedValues>
                        </field>
                        <field>
                            <name>PSCARBL</name>
                            <description>GTIOCnA Pin Rising Input during GTIOCnB Value Low Source Counter Stop Enable</description>
                            <lsb>8</lsb>
                            <msb>8</msb>
                            <access>read-write</access>
                            <enumeratedValues>
                                <enumeratedValue>
                                    <name>0</name>
                                    <description>Counter stop disabled on the rising edge of GTIOCnA input when GTIOCnB input is 0</description>
                                    <value>#0</value>
                                </enumeratedValue>
                                <enumeratedValue>
                                    <name>1</name>
                                    <description>Counter stop enabled on the rising edge of GTIOCnA input when GTIOCnB input is 0</description>
                                    <value>#1</value>
                                </enumeratedValue>
                            </enumeratedValues>
                        </field>
                        <field>
                            <name>PSCARBH</name>
                            <description>GTIOCnA Pin Rising Input during GTIOCnB Value High Source Counter Stop Enable</description>
                            <lsb>9</lsb>
                            <msb>9</msb>
                            <access>read-write</access>
                            <enumeratedValues>
                                <enumeratedValue>
                                    <name>0</name>
                                    <description>Counter stop disabled on the rising edge of GTIOCnA input when GTIOCnB input is 1</description>
                                    <value>#0</value>
                                </enumeratedValue>
                                <enumeratedValue>
                                    <name>1</name>
                                    <description>Counter stop enabled on the rising edge of GTIOCnA input when GTIOCnB input is 1</description>
                                    <value>#1</value>
                                </enumeratedValue>
                            </enumeratedValues>
                        </field>
                        <field>
                            <name>PSCAFBL</name>
                            <description>GTIOCnA Pin Falling Input during GTIOCnB Value Low Source Counter Stop Enable</description>
                            <lsb>10</lsb>
                            <msb>10</msb>
                            <access>read-write</access>
                            <enumeratedValues>
                                <enumeratedValue>
                                    <name>0</name>
                                    <description>Counter stop disabled on the falling edge of GTIOCnA input when GTIOCnB input is 0</description>
                                    <value>#0</value>
                                </enumeratedValue>
                                <enumeratedValue>
                                    <name>1</name>
                                    <description>Counter stop enabled on the falling edge of GTIOCnA input when GTIOCnB input is 0</description>
                                    <value>#1</value>
                                </enumeratedValue>
                            </enumeratedValues>
                        </field>
                        <field>
                            <name>PSCAFBH</name>
                            <description>GTIOCnA Pin Falling Input during GTIOCnB Value High Source Counter Stop Enable</description>
                            <lsb>11</lsb>
                            <msb>11</msb>
                            <access>read-write</access>
                            <enumeratedValues>
                                <enumeratedValue>
                                    <name>0</name>
                                    <description>Counter stop disabled on the falling edge of GTIOCnA input when GTIOCnB input is 1</description>
                                    <value>#0</value>
                                </enumeratedValue>
                                <enumeratedValue>
                                    <name>1</name>
                                    <description>Counter stop enabled on the falling edge of GTIOCnA input when GTIOCnB input is 1</description>
                                    <value>#1</value>
                                </enumeratedValue>
                            </enumeratedValues>
                        </field>
                        <field>
                            <name>PSCBRAL</name>
                            <description>GTIOCnB Pin Rising Input during GTIOCnA Value Low Source Counter Stop Enable</description>
                            <lsb>12</lsb>
                            <msb>12</msb>
                            <access>read-write</access>
                            <enumeratedValues>
                                <enumeratedValue>
                                    <name>0</name>
                                    <description>Counter stop disabled on the rising edge of GTIOCnB input when GTIOCnA input is 0</description>
                                    <value>#0</value>
                                </enumeratedValue>
                                <enumeratedValue>
                                    <name>1</name>
                                    <description>Counter stop enabled on the rising edge of GTIOCnB input when GTIOCnA input is 0</description>
                                    <value>#1</value>
                                </enumeratedValue>
                            </enumeratedValues>
                        </field>
                        <field>
                            <name>PSCBRAH</name>
                            <description>GTIOCnB Pin Rising Input during GTIOCnA Value High Source Counter Stop Enable</description>
                            <lsb>13</lsb>
                            <msb>13</msb>
                            <access>read-write</access>
                            <enumeratedValues>
                                <enumeratedValue>
                                    <name>0</name>
                                    <description>Counter stop disabled on the rising edge of GTIOCnB input when GTIOCnA input is 1</description>
                                    <value>#0</value>
                                </enumeratedValue>
                                <enumeratedValue>
                                    <name>1</name>
                                    <description>Counter stop enabled on the rising edge of GTIOCnB input when GTIOCnA input is 1</description>
                                    <value>#1</value>
                                </enumeratedValue>
                            </enumeratedValues>
                        </field>
                        <field>
                            <name>PSCBFAL</name>
                            <description>GTIOCnB Pin Falling Input during GTIOCnA Value Low Source Counter Stop Enable</description>
                            <lsb>14</lsb>
                            <msb>14</msb>
                            <access>read-write</access>
                            <enumeratedValues>
                                <enumeratedValue>
                                    <name>0</name>
                                    <description>Counter stop disabled on the falling edge of GTIOCnB input when GTIOCnA input is 0</description>
                                    <value>#0</value>
                                </enumeratedValue>
                                <enumeratedValue>
                                    <name>1</name>
                                    <description>Counter stop enabled on the falling edge of GTIOCnB input when GTIOCnA input is 0</description>
                                    <value>#1</value>
                                </enumeratedValue>
                            </enumeratedValues>
                        </field>
                        <field>
                            <name>PSCBFAH</name>
                            <description>GTIOCnB Pin Falling Input during GTIOCnA Value High Source Counter Stop Enable</description>
                            <lsb>15</lsb>
                            <msb>15</msb>
                            <access>read-write</access>
                            <enumeratedValues>
                                <enumeratedValue>
                                    <name>0</name>
                                    <description>Counter stop disabled on the falling edge of GTIOCnB input when GTIOCnA input is 1</description>
                                    <value>#0</value>
                                </enumeratedValue>
                                <enumeratedValue>
                                    <name>1</name>
                                    <description>Counter stop enabled on the falling edge of GTIOCnB input when GTIOCnA input is 1</description>
                                    <value>#1</value>
                                </enumeratedValue>
                            </enumeratedValues>
                        </field>
                        <field>
                            <name>PSELCA</name>
                            <description>ELC_GPTA Event Source Counter Stop Enable</description>
                            <lsb>16</lsb>
                            <msb>16</msb>
                            <access>read-write</access>
                            <enumeratedValues>
                                <enumeratedValue>
                                    <name>0</name>
                                    <description>Counter stop disabled at the ELC_GPTA input</description>
                                    <value>#0</value>
                                </enumeratedValue>
                                <enumeratedValue>
                                    <name>1</name>
                                    <description>Counter stop enabled at the ELC_GPTA input</description>
                                    <value>#1</value>
                                </enumeratedValue>
                            </enumeratedValues>
                        </field>
                        <field>
                            <name>PSELCB</name>
                            <description>ELC_GPTB Event Source Counter Stop Enable</description>
                            <lsb>17</lsb>
                            <msb>17</msb>
                            <access>read-write</access>
                            <enumeratedValues>
                                <enumeratedValue>
                                    <name>0</name>
                                    <description>Counter stop disabled at the ELC_GPTB input</description>
                                    <value>#0</value>
                                </enumeratedValue>
                                <enumeratedValue>
                                    <name>1</name>
                                    <description>Counter stop enabled at the ELC_GPTB input</description>
                                    <value>#1</value>
                                </enumeratedValue>
                            </enumeratedValues>
                        </field>
                        <field>
                            <name>PSELCC</name>
                            <description>ELC_GPTC Event Source Counter Stop Enable</description>
                            <lsb>18</lsb>
                            <msb>18</msb>
                            <access>read-write</access>
                            <enumeratedValues>
                                <enumeratedValue>
                                    <name>0</name>
                                    <description>Counter stop disabled at the ELC_GPTC input</description>
                                    <value>#0</value>
                                </enumeratedValue>
                                <enumeratedValue>
                                    <name>1</name>
                                    <description>Counter stop enabled at the ELC_GPTC input</description>
                                    <value>#1</value>
                                </enumeratedValue>
                            </enumeratedValues>
                        </field>
                        <field>
                            <name>PSELCD</name>
                            <description>ELC_GPTD Event Source Counter Stop Enable</description>
                            <lsb>19</lsb>
                            <msb>19</msb>
                            <access>read-write</access>
                            <enumeratedValues>
                                <enumeratedValue>
                                    <name>0</name>
                                    <description>Counter stop disabled at the ELC_GPTD input</description>
                                    <value>#0</value>
                                </enumeratedValue>
                                <enumeratedValue>
                                    <name>1</name>
                                    <description>Counter stop enabled at the ELC_GPTD input</description>
                                    <value>#1</value>
                                </enumeratedValue>
                            </enumeratedValues>
                        </field>
                        <field>
                            <name>PSELCE</name>
                            <description>ELC_GPTE Event Source Counter Stop Enable</description>
                            <lsb>20</lsb>
                            <msb>20</msb>
                            <access>read-write</access>
                            <enumeratedValues>
                                <enumeratedValue>
                                    <name>0</name>
                                    <description>Counter stop disabled at the ELC_GPTE input</description>
                                    <value>#0</value>
                                </enumeratedValue>
                                <enumeratedValue>
                                    <name>1</name>
                                    <description>Counter stop enabled at the ELC_GPTE input</description>
                                    <value>#1</value>
                                </enumeratedValue>
                            </enumeratedValues>
                        </field>
                        <field>
                            <name>PSELCF</name>
                            <description>ELC_GPTF Event Source Counter Stop Enable</description>
                            <lsb>21</lsb>
                            <msb>21</msb>
                            <access>read-write</access>
                            <enumeratedValues>
                                <enumeratedValue>
                                    <name>0</name>
                                    <description>Counter stop disabled at the ELC_GPTF input</description>
                                    <value>#0</value>
                                </enumeratedValue>
                                <enumeratedValue>
                                    <name>1</name>
                                    <description>Counter stop enabled at the ELC_GPTF input</description>
                                    <value>#1</value>
                                </enumeratedValue>
                            </enumeratedValues>
                        </field>
                        <field>
                            <name>PSELCG</name>
                            <description>ELC_GPTG Event Source Counter Stop Enable</description>
                            <lsb>22</lsb>
                            <msb>22</msb>
                            <access>read-write</access>
                            <enumeratedValues>
                                <enumeratedValue>
                                    <name>0</name>
                                    <description>Counter stop disabled at the ELC_GPTG input</description>
                                    <value>#0</value>
                                </enumeratedValue>
                                <enumeratedValue>
                                    <name>1</name>
                                    <description>Counter stop enabled at the ELC_GPTG input</description>
                                    <value>#1</value>
                                </enumeratedValue>
                            </enumeratedValues>
                        </field>
                        <field>
                            <name>PSELCH</name>
                            <description>ELC_GPTH Event Source Counter Stop Enable</description>
                            <lsb>23</lsb>
                            <msb>23</msb>
                            <access>read-write</access>
                            <enumeratedValues>
                                <enumeratedValue>
                                    <name>0</name>
                                    <description>Counter stop disabled at the ELC_GPTH input</description>
                                    <value>#0</value>
                                </enumeratedValue>
                                <enumeratedValue>
                                    <name>1</name>
                                    <description>Counter stop enabled at the ELC_GPTH input</description>
                                    <value>#1</value>
                                </enumeratedValue>
                            </enumeratedValues>
                        </field>
                        <field>
                            <name>CSTOP</name>
                            <description>Software Source Counter Stop Enable</description>
                            <lsb>31</lsb>
                            <msb>31</msb>
                            <access>read-write</access>
                            <enumeratedValues>
                                <enumeratedValue>
                                    <name>0</name>
                                    <description>Counter stop disabled by the GTSTP register</description>
                                    <value>#0</value>
                                </enumeratedValue>
                                <enumeratedValue>
                                    <name>1</name>
                                    <description>Counter stop enabled by the GTSTP register</description>
                                    <value>#1</value>
                                </enumeratedValue>
                            </enumeratedValues>
                        </field>
                    </fields>
                </register>
                <register>
                    <name>GTCSR</name>
                    <description>General PWM Timer Clear Source Select Register</description>
                    <addressOffset>0x18</addressOffset>
                    <size>32</size>
                    <access>read-write</access>
                    <resetValue>0x00000000</resetValue>
                    <resetMask>0xffffffff</resetMask>
                    <fields>
                        <field>
                            <name>CSGTRGAR</name>
                            <description>GTETRGA Pin Rising Input Source Counter Clear Enable</description>
                            <lsb>0</lsb>
                            <msb>0</msb>
                            <access>read-write</access>
                            <enumeratedValues>
                                <enumeratedValue>
                                    <name>0</name>
                                    <description>Counter clear disabled on the rising edge of GTETRGA input</description>
                                    <value>#0</value>
                                </enumeratedValue>
                                <enumeratedValue>
                                    <name>1</name>
                                    <description>Counter clear enabled on the rising edge of GTETRGA input</description>
                                    <value>#1</value>
                                </enumeratedValue>
                            </enumeratedValues>
                        </field>
                        <field>
                            <name>CSGTRGAF</name>
                            <description>GTETRGA Pin Falling Input Source Counter Clear Enable</description>
                            <lsb>1</lsb>
                            <msb>1</msb>
                            <access>read-write</access>
                            <enumeratedValues>
                                <enumeratedValue>
                                    <name>0</name>
                                    <description>Counter clear disabled on the falling edge of GTETRGA input</description>
                                    <value>#0</value>
                                </enumeratedValue>
                                <enumeratedValue>
                                    <name>1</name>
                                    <description>Counter clear enabled on the falling edge of GTETRGA input</description>
                                    <value>#1</value>
                                </enumeratedValue>
                            </enumeratedValues>
                        </field>
                        <field>
                            <name>CSGTRGBR</name>
                            <description>GTETRGB Pin Rising Input Source Counter Clear Enable</description>
                            <lsb>2</lsb>
                            <msb>2</msb>
                            <access>read-write</access>
                            <enumeratedValues>
                                <enumeratedValue>
                                    <name>0</name>
                                    <description>Disable counter clear on the rising edge of GTETRGB input</description>
                                    <value>#0</value>
                                </enumeratedValue>
                                <enumeratedValue>
                                    <name>1</name>
                                    <description>Enable counter clear on the rising edge of GTETRGB input</description>
                                    <value>#1</value>
                                </enumeratedValue>
                            </enumeratedValues>
                        </field>
                        <field>
                            <name>CSGTRGBF</name>
                            <description>GTETRGB Pin Falling Input Source Counter Clear Enable</description>
                            <lsb>3</lsb>
                            <msb>3</msb>
                            <access>read-write</access>
                            <enumeratedValues>
                                <enumeratedValue>
                                    <name>0</name>
                                    <description>Counter clear disabled on the falling edge of GTETRGB input</description>
                                    <value>#0</value>
                                </enumeratedValue>
                                <enumeratedValue>
                                    <name>1</name>
                                    <description>Counter clear enabled on the falling edge of GTETRGB input</description>
                                    <value>#1</value>
                                </enumeratedValue>
                            </enumeratedValues>
                        </field>
                        <field>
                            <name>CSGTRGCR</name>
                            <description>GTETRGC Pin Rising Input Source Counter Clear Enable</description>
                            <lsb>4</lsb>
                            <msb>4</msb>
                            <access>read-write</access>
                            <enumeratedValues>
                                <enumeratedValue>
                                    <name>0</name>
                                    <description>Disable counter clear on the rising edge of GTETRGC input</description>
                                    <value>#0</value>
                                </enumeratedValue>
                                <enumeratedValue>
                                    <name>1</name>
                                    <description>Enable counter clear on the rising edge of GTETRGC input</description>
                                    <value>#1</value>
                                </enumeratedValue>
                            </enumeratedValues>
                        </field>
                        <field>
                            <name>CSGTRGCF</name>
                            <description>GTETRGC Pin Falling Input Source Counter Clear Enable</description>
                            <lsb>5</lsb>
                            <msb>5</msb>
                            <access>read-write</access>
                            <enumeratedValues>
                                <enumeratedValue>
                                    <name>0</name>
                                    <description>Counter clear disabled on the falling edge of GTETRGC input</description>
                                    <value>#0</value>
                                </enumeratedValue>
                                <enumeratedValue>
                                    <name>1</name>
                                    <description>Counter clear enabled on the falling edge of GTETRGC input</description>
                                    <value>#1</value>
                                </enumeratedValue>
                            </enumeratedValues>
                        </field>
                        <field>
                            <name>CSGTRGDR</name>
                            <description>GTETRGD Pin Rising Input Source Counter Clear Enable</description>
                            <lsb>6</lsb>
                            <msb>6</msb>
                            <access>read-write</access>
                            <enumeratedValues>
                                <enumeratedValue>
                                    <name>0</name>
                                    <description>Disable counter clear on the rising edge of GTETRGD input</description>
                                    <value>#0</value>
                                </enumeratedValue>
                                <enumeratedValue>
                                    <name>1</name>
                                    <description>Enable counter clear on the rising edge of GTETRGD input</description>
                                    <value>#1</value>
                                </enumeratedValue>
                            </enumeratedValues>
                        </field>
                        <field>
                            <name>CSGTRGDF</name>
                            <description>GTETRGD Pin Falling Input Source Counter Clear Enable</description>
                            <lsb>7</lsb>
                            <msb>7</msb>
                            <access>read-write</access>
                            <enumeratedValues>
                                <enumeratedValue>
                                    <name>0</name>
                                    <description>Counter clear disabled on the falling edge of GTETRGD input</description>
                                    <value>#0</value>
                                </enumeratedValue>
                                <enumeratedValue>
                                    <name>1</name>
                                    <description>Counter clear enabled on the falling edge of GTETRGD input</description>
                                    <value>#1</value>
                                </enumeratedValue>
                            </enumeratedValues>
                        </field>
                        <field>
                            <name>CSCARBL</name>
                            <description>GTIOCnA Pin Rising Input during GTIOCnB Value Low Source Counter Clear Enable</description>
                            <lsb>8</lsb>
                            <msb>8</msb>
                            <access>read-write</access>
                            <enumeratedValues>
                                <enumeratedValue>
                                    <name>0</name>
                                    <description>Counter clear disabled on the rising edge of GTIOCnA input when GTIOCnB input is 0</description>
                                    <value>#0</value>
                                </enumeratedValue>
                                <enumeratedValue>
                                    <name>1</name>
                                    <description>Counter clear enabled on the rising edge of GTIOCnA input when GTIOCnB input is 0</description>
                                    <value>#1</value>
                                </enumeratedValue>
                            </enumeratedValues>
                        </field>
                        <field>
                            <name>CSCARBH</name>
                            <description>GTIOCnA Pin Rising Input during GTIOCnB Value High Source Counter Clear Enable</description>
                            <lsb>9</lsb>
                            <msb>9</msb>
                            <access>read-write</access>
                            <enumeratedValues>
                                <enumeratedValue>
                                    <name>0</name>
                                    <description>Counter clear disabled on the rising edge of GTIOCnA input when GTIOCnB input is 1</description>
                                    <value>#0</value>
                                </enumeratedValue>
                                <enumeratedValue>
                                    <name>1</name>
                                    <description>Counter clear enabled on the rising edge of GTIOCnA input when GTIOCnB input is 1</description>
                                    <value>#1</value>
                                </enumeratedValue>
                            </enumeratedValues>
                        </field>
                        <field>
                            <name>CSCAFBL</name>
                            <description>GTIOCnA Pin Falling Input during GTIOCnB Value Low Source Counter Clear Enable</description>
                            <lsb>10</lsb>
                            <msb>10</msb>
                            <access>read-write</access>
                            <enumeratedValues>
                                <enumeratedValue>
                                    <name>0</name>
                                    <description>Counter clear disabled on the falling edge of GTIOCnA input when GTIOCnB input is 0</description>
                                    <value>#0</value>
                                </enumeratedValue>
                                <enumeratedValue>
                                    <name>1</name>
                                    <description>Counter clear enabled on the falling edge of GTIOCnA input when GTIOCnB input is 0</description>
                                    <value>#1</value>
                                </enumeratedValue>
                            </enumeratedValues>
                        </field>
                        <field>
                            <name>CSCAFBH</name>
                            <description>GTIOCnA Pin Falling Input during GTIOCnB Value High Source Counter Clear Enable</description>
                            <lsb>11</lsb>
                            <msb>11</msb>
                            <access>read-write</access>
                            <enumeratedValues>
                                <enumeratedValue>
                                    <name>0</name>
                                    <description>Counter clear disabled on the falling edge of GTIOCnA input when GTIOCnB input is 1</description>
                                    <value>#0</value>
                                </enumeratedValue>
                                <enumeratedValue>
                                    <name>1</name>
                                    <description>Counter clear enabled on the falling edge of GTIOCnA input when GTIOCnB input is 1</description>
                                    <value>#1</value>
                                </enumeratedValue>
                            </enumeratedValues>
                        </field>
                        <field>
                            <name>CSCBRAL</name>
                            <description>GTIOCnB Pin Rising Input during GTIOCnA Value Low Source Counter Clear Enable</description>
                            <lsb>12</lsb>
                            <msb>12</msb>
                            <access>read-write</access>
                            <enumeratedValues>
                                <enumeratedValue>
                                    <name>0</name>
                                    <description>Counter clear disabled on the rising edge of GTIOCnB input when GTIOCnA input is 0</description>
                                    <value>#0</value>
                                </enumeratedValue>
                                <enumeratedValue>
                                    <name>1</name>
                                    <description>Counter clear enabled on the rising edge of GTIOCnB input when GTIOCnA input is 0</description>
                                    <value>#1</value>
                                </enumeratedValue>
                            </enumeratedValues>
                        </field>
                        <field>
                            <name>CSCBRAH</name>
                            <description>GTIOCnB Pin Rising Input during GTIOCnA Value High Source Counter Clear Enable</description>
                            <lsb>13</lsb>
                            <msb>13</msb>
                            <access>read-write</access>
                            <enumeratedValues>
                                <enumeratedValue>
                                    <name>0</name>
                                    <description>Counter clear disabled on the rising edge of GTIOCnB input when GTIOCnA input is 1</description>
                                    <value>#0</value>
                                </enumeratedValue>
                                <enumeratedValue>
                                    <name>1</name>
                                    <description>Counter clear enabled on the rising edge of GTIOCnB input when GTIOCnA input is 1</description>
                                    <value>#1</value>
                                </enumeratedValue>
                            </enumeratedValues>
                        </field>
                        <field>
                            <name>CSCBFAL</name>
                            <description>GTIOCnB Pin Falling Input during GTIOCnA Value Low Source Counter Clear Enable</description>
                            <lsb>14</lsb>
                            <msb>14</msb>
                            <access>read-write</access>
                            <enumeratedValues>
                                <enumeratedValue>
                                    <name>0</name>
                                    <description>Counter clear disabled on the falling edge of GTIOCnB input when GTIOCnA input is 0</description>
                                    <value>#0</value>
                                </enumeratedValue>
                                <enumeratedValue>
                                    <name>1</name>
                                    <description>Counter clear enabled on the falling edge of GTIOCnB input when GTIOCnA input is 0</description>
                                    <value>#1</value>
                                </enumeratedValue>
                            </enumeratedValues>
                        </field>
                        <field>
                            <name>CSCBFAH</name>
                            <description>GTIOCnB Pin Falling Input during GTIOCnA Value High Source Counter Clear Enable</description>
                            <lsb>15</lsb>
                            <msb>15</msb>
                            <access>read-write</access>
                            <enumeratedValues>
                                <enumeratedValue>
                                    <name>0</name>
                                    <description>Counter clear disabled on the falling edge of GTIOCnB input when GTIOCnA input is 1</description>
                                    <value>#0</value>
                                </enumeratedValue>
                                <enumeratedValue>
                                    <name>1</name>
                                    <description>Counter clear enabled on the falling edge of GTIOCnB input when GTIOCnA input is 1</description>
                                    <value>#1</value>
                                </enumeratedValue>
                            </enumeratedValues>
                        </field>
                        <field>
                            <name>CSELCA</name>
                            <description>ELC_GPTA Event Source Counter Clear Enable</description>
                            <lsb>16</lsb>
                            <msb>16</msb>
                            <access>read-write</access>
                            <enumeratedValues>
                                <enumeratedValue>
                                    <name>0</name>
                                    <description>Counter clear disabled at the ELC_GPTA input</description>
                                    <value>#0</value>
                                </enumeratedValue>
                                <enumeratedValue>
                                    <name>1</name>
                                    <description>Counter clear enabled at the ELC_GPTA input</description>
                                    <value>#1</value>
                                </enumeratedValue>
                            </enumeratedValues>
                        </field>
                        <field>
                            <name>CSELCB</name>
                            <description>ELC_GPTB Event Source Counter Clear Enable</description>
                            <lsb>17</lsb>
                            <msb>17</msb>
                            <access>read-write</access>
                            <enumeratedValues>
                                <enumeratedValue>
                                    <name>0</name>
                                    <description>Counter clear disabled at the ELC_GPTB input</description>
                                    <value>#0</value>
                                </enumeratedValue>
                                <enumeratedValue>
                                    <name>1</name>
                                    <description>Counter clear enabled at the ELC_GPTB input</description>
                                    <value>#1</value>
                                </enumeratedValue>
                            </enumeratedValues>
                        </field>
                        <field>
                            <name>CSELCC</name>
                            <description>ELC_GPTC Event Source Counter Clear Enable</description>
                            <lsb>18</lsb>
                            <msb>18</msb>
                            <access>read-write</access>
                            <enumeratedValues>
                                <enumeratedValue>
                                    <name>0</name>
                                    <description>Counter clear disabled at the ELC_GPTC input</description>
                                    <value>#0</value>
                                </enumeratedValue>
                                <enumeratedValue>
                                    <name>1</name>
                                    <description>Counter clear enabled at the ELC_GPTC input</description>
                                    <value>#1</value>
                                </enumeratedValue>
                            </enumeratedValues>
                        </field>
                        <field>
                            <name>CSELCD</name>
                            <description>ELC_GPTD Event Source Counter Clear Enable</description>
                            <lsb>19</lsb>
                            <msb>19</msb>
                            <access>read-write</access>
                            <enumeratedValues>
                                <enumeratedValue>
                                    <name>0</name>
                                    <description>Counter clear disabled at the ELC_GPTD input</description>
                                    <value>#0</value>
                                </enumeratedValue>
                                <enumeratedValue>
                                    <name>1</name>
                                    <description>Counter clear enabled at the ELC_GPTD input</description>
                                    <value>#1</value>
                                </enumeratedValue>
                            </enumeratedValues>
                        </field>
                        <field>
                            <name>CSELCE</name>
                            <description>ELC_GPTE Event Source Counter Clear Enable</description>
                            <lsb>20</lsb>
                            <msb>20</msb>
                            <access>read-write</access>
                            <enumeratedValues>
                                <enumeratedValue>
                                    <name>0</name>
                                    <description>Counter clear disabled at the ELC_GPTE input</description>
                                    <value>#0</value>
                                </enumeratedValue>
                                <enumeratedValue>
                                    <name>1</name>
                                    <description>Counter clear enabled at the ELC_GPTE input</description>
                                    <value>#1</value>
                                </enumeratedValue>
                            </enumeratedValues>
                        </field>
                        <field>
                            <name>CSELCF</name>
                            <description>ELC_GPTF Event Source Counter Clear Enable</description>
                            <lsb>21</lsb>
                            <msb>21</msb>
                            <access>read-write</access>
                            <enumeratedValues>
                                <enumeratedValue>
                                    <name>0</name>
                                    <description>Counter clear disabled at the ELC_GPTF input</description>
                                    <value>#0</value>
                                </enumeratedValue>
                                <enumeratedValue>
                                    <name>1</name>
                                    <description>Counter clear enabled at the ELC_GPTF input</description>
                                    <value>#1</value>
                                </enumeratedValue>
                            </enumeratedValues>
                        </field>
                        <field>
                            <name>CSELCG</name>
                            <description>ELC_GPTG Event Source Counter Clear Enable</description>
                            <lsb>22</lsb>
                            <msb>22</msb>
                            <access>read-write</access>
                            <enumeratedValues>
                                <enumeratedValue>
                                    <name>0</name>
                                    <description>Counter clear disabled at the ELC_GPTG input</description>
                                    <value>#0</value>
                                </enumeratedValue>
                                <enumeratedValue>
                                    <name>1</name>
                                    <description>Counter clear enabled at the ELC_GPTG input</description>
                                    <value>#1</value>
                                </enumeratedValue>
                            </enumeratedValues>
                        </field>
                        <field>
                            <name>CSELCH</name>
                            <description>ELC_GPTH Event Source Counter Clear Enable</description>
                            <lsb>23</lsb>
                            <msb>23</msb>
                            <access>read-write</access>
                            <enumeratedValues>
                                <enumeratedValue>
                                    <name>0</name>
                                    <description>Counter clear disabled at the ELC_GPTH input</description>
                                    <value>#0</value>
                                </enumeratedValue>
                                <enumeratedValue>
                                    <name>1</name>
                                    <description>Counter clear enabled at the ELC_GPTH input</description>
                                    <value>#1</value>
                                </enumeratedValue>
                            </enumeratedValues>
                        </field>
                        <field>
                            <name>CCLR</name>
                            <description>Software Source Counter Clear Enable</description>
                            <lsb>31</lsb>
                            <msb>31</msb>
                            <access>read-write</access>
                            <enumeratedValues>
                                <enumeratedValue>
                                    <name>0</name>
                                    <description>Counter clear disabled by the GTCLR register</description>
                                    <value>#0</value>
                                </enumeratedValue>
                                <enumeratedValue>
                                    <name>1</name>
                                    <description>Counter clear enabled by the GTCLR register</description>
                                    <value>#1</value>
                                </enumeratedValue>
                            </enumeratedValues>
                        </field>
                    </fields>
                </register>
                <register>
                    <name>GTUPSR</name>
                    <description>General PWM Timer Up Count Source Select Register</description>
                    <addressOffset>0x1C</addressOffset>
                    <size>32</size>
                    <access>read-write</access>
                    <resetValue>0x00000000</resetValue>
                    <resetMask>0xffffffff</resetMask>
                    <fields>
                        <field>
                            <name>USGTRGAR</name>
                            <description>GTETRGA Pin Rising Input Source Counter Count Up Enable</description>
                            <lsb>0</lsb>
                            <msb>0</msb>
                            <access>read-write</access>
                            <enumeratedValues>
                                <enumeratedValue>
                                    <name>0</name>
                                    <description>Counter count up disabled on the rising edge of GTETRGA input</description>
                                    <value>#0</value>
                                </enumeratedValue>
                                <enumeratedValue>
                                    <name>1</name>
                                    <description>Counter count up enabled on the rising edge of GTETRGA input</description>
                                    <value>#1</value>
                                </enumeratedValue>
                            </enumeratedValues>
                        </field>
                        <field>
                            <name>USGTRGAF</name>
                            <description>GTETRGA Pin Falling Input Source Counter Count Up Enable</description>
                            <lsb>1</lsb>
                            <msb>1</msb>
                            <access>read-write</access>
                            <enumeratedValues>
                                <enumeratedValue>
                                    <name>0</name>
                                    <description>Counter count up disabled on the falling edge of GTETRGA input</description>
                                    <value>#0</value>
                                </enumeratedValue>
                                <enumeratedValue>
                                    <name>1</name>
                                    <description>Counter count up enabled on the falling edge of GTETRGA input</description>
                                    <value>#1</value>
                                </enumeratedValue>
                            </enumeratedValues>
                        </field>
                        <field>
                            <name>USGTRGBR</name>
                            <description>GTETRGB Pin Rising Input Source Counter Count Up Enable</description>
                            <lsb>2</lsb>
                            <msb>2</msb>
                            <access>read-write</access>
                            <enumeratedValues>
                                <enumeratedValue>
                                    <name>0</name>
                                    <description>Counter count up disabled on the rising edge of GTETRGB input</description>
                                    <value>#0</value>
                                </enumeratedValue>
                                <enumeratedValue>
                                    <name>1</name>
                                    <description>Counter count up enabled on the rising edge of GTETRGB input</description>
                                    <value>#1</value>
                                </enumeratedValue>
                            </enumeratedValues>
                        </field>
                        <field>
                            <name>USGTRGBF</name>
                            <description>GTETRGB Pin Falling Input Source Counter Count Up Enable</description>
                            <lsb>3</lsb>
                            <msb>3</msb>
                            <access>read-write</access>
                            <enumeratedValues>
                                <enumeratedValue>
                                    <name>0</name>
                                    <description>Counter count up disabled on the falling edge of GTETRGB input</description>
                                    <value>#0</value>
                                </enumeratedValue>
                                <enumeratedValue>
                                    <name>1</name>
                                    <description>Counter count up enabled on the falling edge of GTETRGB input</description>
                                    <value>#1</value>
                                </enumeratedValue>
                            </enumeratedValues>
                        </field>
                        <field>
                            <name>USGTRGCR</name>
                            <description>GTETRGC Pin Rising Input Source Counter Count Up Enable</description>
                            <lsb>4</lsb>
                            <msb>4</msb>
                            <access>read-write</access>
                            <enumeratedValues>
                                <enumeratedValue>
                                    <name>0</name>
                                    <description>Counter count up disabled on the rising edge of GTETRGC input</description>
                                    <value>#0</value>
                                </enumeratedValue>
                                <enumeratedValue>
                                    <name>1</name>
                                    <description>Counter count up enabled on the rising edge of GTETRGC input</description>
                                    <value>#1</value>
                                </enumeratedValue>
                            </enumeratedValues>
                        </field>
                        <field>
                            <name>USGTRGCF</name>
                            <description>GTETRGC Pin Falling Input Source Counter Count Up Enable</description>
                            <lsb>5</lsb>
                            <msb>5</msb>
                            <access>read-write</access>
                            <enumeratedValues>
                                <enumeratedValue>
                                    <name>0</name>
                                    <description>Counter count up disabled on the falling edge of GTETRGC input</description>
                                    <value>#0</value>
                                </enumeratedValue>
                                <enumeratedValue>
                                    <name>1</name>
                                    <description>Counter count up enabled on the falling edge of GTETRGC input</description>
                                    <value>#1</value>
                                </enumeratedValue>
                            </enumeratedValues>
                        </field>
                        <field>
                            <name>USGTRGDR</name>
                            <description>GTETRGD Pin Rising Input Source Counter Count Up Enable</description>
                            <lsb>6</lsb>
                            <msb>6</msb>
                            <access>read-write</access>
                            <enumeratedValues>
                                <enumeratedValue>
                                    <name>0</name>
                                    <description>Counter count up disabled on the rising edge of GTETRGD input</description>
                                    <value>#0</value>
                                </enumeratedValue>
                                <enumeratedValue>
                                    <name>1</name>
                                    <description>Counter count up enabled on the rising edge of GTETRGD input</description>
                                    <value>#1</value>
                                </enumeratedValue>
                            </enumeratedValues>
                        </field>
                        <field>
                            <name>USGTRGDF</name>
                            <description>GTETRGD Pin Falling Input Source Counter Count Up Enable</description>
                            <lsb>7</lsb>
                            <msb>7</msb>
                            <access>read-write</access>
                            <enumeratedValues>
                                <enumeratedValue>
                                    <name>0</name>
                                    <description>Counter count up disabled on the falling edge of GTETRGD input</description>
                                    <value>#0</value>
                                </enumeratedValue>
                                <enumeratedValue>
                                    <name>1</name>
                                    <description>Counter count up enabled on the falling edge of GTETRGD input</description>
                                    <value>#1</value>
                                </enumeratedValue>
                            </enumeratedValues>
                        </field>
                        <field>
                            <name>USCARBL</name>
                            <description>GTIOCnA Pin Rising Input during GTIOCnB Value Low Source Counter Count Up Enable</description>
                            <lsb>8</lsb>
                            <msb>8</msb>
                            <access>read-write</access>
                            <enumeratedValues>
                                <enumeratedValue>
                                    <name>0</name>
                                    <description>Counter count up disabled on the rising edge of GTIOCnA input when GTIOCnB input is 0</description>
                                    <value>#0</value>
                                </enumeratedValue>
                                <enumeratedValue>
                                    <name>1</name>
                                    <description>Counter count up enabled on the rising edge of GTIOCnA input when GTIOCnB input is 0</description>
                                    <value>#1</value>
                                </enumeratedValue>
                            </enumeratedValues>
                        </field>
                        <field>
                            <name>USCARBH</name>
                            <description>GTIOCnA Pin Rising Input during GTIOCnB Value High Source Counter Count Up Enable</description>
                            <lsb>9</lsb>
                            <msb>9</msb>
                            <access>read-write</access>
                            <enumeratedValues>
                                <enumeratedValue>
                                    <name>0</name>
                                    <description>Counter count up disabled on the rising edge of GTIOCnA input when GTIOCnB input is 1</description>
                                    <value>#0</value>
                                </enumeratedValue>
                                <enumeratedValue>
                                    <name>1</name>
                                    <description>Counter count up enabled on the rising edge of GTIOCnA input when GTIOCnB input is 1</description>
                                    <value>#1</value>
                                </enumeratedValue>
                            </enumeratedValues>
                        </field>
                        <field>
                            <name>USCAFBL</name>
                            <description>GTIOCnA Pin Falling Input during GTIOCnB Value Low Source Counter Count Up Enable</description>
                            <lsb>10</lsb>
                            <msb>10</msb>
                            <access>read-write</access>
                            <enumeratedValues>
                                <enumeratedValue>
                                    <name>0</name>
                                    <description>Counter count up disabled on the falling edge of GTIOCnA input when GTIOCnB input is 0</description>
                                    <value>#0</value>
                                </enumeratedValue>
                                <enumeratedValue>
                                    <name>1</name>
                                    <description>Counter count up enabled on the falling edge of GTIOCnA input when GTIOCnB input is 0</description>
                                    <value>#1</value>
                                </enumeratedValue>
                            </enumeratedValues>
                        </field>
                        <field>
                            <name>USCAFBH</name>
                            <description>GTIOCnA Pin Falling Input during GTIOCnB Value High Source Counter Count Up Enable</description>
                            <lsb>11</lsb>
                            <msb>11</msb>
                            <access>read-write</access>
                            <enumeratedValues>
                                <enumeratedValue>
                                    <name>0</name>
                                    <description>Counter count up disabled on the falling edge of GTIOCnA input when GTIOCnB input is 1</description>
                                    <value>#0</value>
                                </enumeratedValue>
                                <enumeratedValue>
                                    <name>1</name>
                                    <description>Counter count up enabled on the falling edge of GTIOCnA input when GTIOCnB input is 1</description>
                                    <value>#1</value>
                                </enumeratedValue>
                            </enumeratedValues>
                        </field>
                        <field>
                            <name>USCBRAL</name>
                            <description>GTIOCnB Pin Rising Input during GTIOCnA Value Low Source Counter Count Up Enable</description>
                            <lsb>12</lsb>
                            <msb>12</msb>
                            <access>read-write</access>
                            <enumeratedValues>
                                <enumeratedValue>
                                    <name>0</name>
                                    <description>Counter count up disabled on the rising edge of GTIOCnB input when GTIOCnA input is 0</description>
                                    <value>#0</value>
                                </enumeratedValue>
                                <enumeratedValue>
                                    <name>1</name>
                                    <description>Counter count up enabled on the rising edge of GTIOCnB input when GTIOCnA input is 0</description>
                                    <value>#1</value>
                                </enumeratedValue>
                            </enumeratedValues>
                        </field>
                        <field>
                            <name>USCBRAH</name>
                            <description>GTIOCnB Pin Rising Input during GTIOCnA Value High Source Counter Count Up Enable</description>
                            <lsb>13</lsb>
                            <msb>13</msb>
                            <access>read-write</access>
                            <enumeratedValues>
                                <enumeratedValue>
                                    <name>0</name>
                                    <description>Counter count up disabled on the rising edge of GTIOCnB input when GTIOCnA input is 1</description>
                                    <value>#0</value>
                                </enumeratedValue>
                                <enumeratedValue>
                                    <name>1</name>
                                    <description>Counter count up enabled on the rising edge of GTIOCnB input when GTIOCnA input is 1</description>
                                    <value>#1</value>
                                </enumeratedValue>
                            </enumeratedValues>
                        </field>
                        <field>
                            <name>USCBFAL</name>
                            <description>GTIOCnB Pin Falling Input during GTIOCnA Value Low Source Counter Count Up Enable</description>
                            <lsb>14</lsb>
                            <msb>14</msb>
                            <access>read-write</access>
                            <enumeratedValues>
                                <enumeratedValue>
                                    <name>0</name>
                                    <description>Counter count up disabled on the falling edge of GTIOCnB input when GTIOCnA input is 0</description>
                                    <value>#0</value>
                                </enumeratedValue>
                                <enumeratedValue>
                                    <name>1</name>
                                    <description>Counter count up enabled on the falling edge of GTIOCnB input when GTIOCnA input is 0</description>
                                    <value>#1</value>
                                </enumeratedValue>
                            </enumeratedValues>
                        </field>
                        <field>
                            <name>USCBFAH</name>
                            <description>GTIOCnB Pin Falling Input during GTIOCnA Value High Source Counter Count Up Enable</description>
                            <lsb>15</lsb>
                            <msb>15</msb>
                            <access>read-write</access>
                            <enumeratedValues>
                                <enumeratedValue>
                                    <name>0</name>
                                    <description>Counter count up disabled on the falling edge of GTIOCnB input when GTIOCnA input is 1</description>
                                    <value>#0</value>
                                </enumeratedValue>
                                <enumeratedValue>
                                    <name>1</name>
                                    <description>Counter count up enabled on the falling edge of GTIOCnB input when GTIOCnA input is 1</description>
                                    <value>#1</value>
                                </enumeratedValue>
                            </enumeratedValues>
                        </field>
                        <field>
                            <name>USELCA</name>
                            <description>ELC_GPTA Event Source Counter Count Up Enable</description>
                            <lsb>16</lsb>
                            <msb>16</msb>
                            <access>read-write</access>
                            <enumeratedValues>
                                <enumeratedValue>
                                    <name>0</name>
                                    <description>Counter count up disabled at the ELC_GPTA input</description>
                                    <value>#0</value>
                                </enumeratedValue>
                                <enumeratedValue>
                                    <name>1</name>
                                    <description>Counter count up enabled at the ELC_GPTA input</description>
                                    <value>#1</value>
                                </enumeratedValue>
                            </enumeratedValues>
                        </field>
                        <field>
                            <name>USELCB</name>
                            <description>ELC_GPTB Event Source Counter Count Up Enable</description>
                            <lsb>17</lsb>
                            <msb>17</msb>
                            <access>read-write</access>
                            <enumeratedValues>
                                <enumeratedValue>
                                    <name>0</name>
                                    <description>Counter count up disabled at the ELC_GPTB input</description>
                                    <value>#0</value>
                                </enumeratedValue>
                                <enumeratedValue>
                                    <name>1</name>
                                    <description>Counter count up enabled at the ELC_GPTB input</description>
                                    <value>#1</value>
                                </enumeratedValue>
                            </enumeratedValues>
                        </field>
                        <field>
                            <name>USELCC</name>
                            <description>ELC_GPTC Event Source Counter Count Up Enable</description>
                            <lsb>18</lsb>
                            <msb>18</msb>
                            <access>read-write</access>
                            <enumeratedValues>
                                <enumeratedValue>
                                    <name>0</name>
                                    <description>Counter count up disabled at the ELC_GPTC input</description>
                                    <value>#0</value>
                                </enumeratedValue>
                                <enumeratedValue>
                                    <name>1</name>
                                    <description>Counter count up enabled at the ELC_GPTC input</description>
                                    <value>#1</value>
                                </enumeratedValue>
                            </enumeratedValues>
                        </field>
                        <field>
                            <name>USELCD</name>
                            <description>ELC_GPTD Event Source Counter Count Up Enable</description>
                            <lsb>19</lsb>
                            <msb>19</msb>
                            <access>read-write</access>
                            <enumeratedValues>
                                <enumeratedValue>
                                    <name>0</name>
                                    <description>Counter count up disabled at the ELC_GPTD input</description>
                                    <value>#0</value>
                                </enumeratedValue>
                                <enumeratedValue>
                                    <name>1</name>
                                    <description>Counter count up enabled at the ELC_GPTD input</description>
                                    <value>#1</value>
                                </enumeratedValue>
                            </enumeratedValues>
                        </field>
                        <field>
                            <name>USELCE</name>
                            <description>ELC_GPTE Event Source Counter Count Up Enable</description>
                            <lsb>20</lsb>
                            <msb>20</msb>
                            <access>read-write</access>
                            <enumeratedValues>
                                <enumeratedValue>
                                    <name>0</name>
                                    <description>Counter count up disabled at the ELC_GPTE input</description>
                                    <value>#0</value>
                                </enumeratedValue>
                                <enumeratedValue>
                                    <name>1</name>
                                    <description>Counter count up enabled at the ELC_GPTE input</description>
                                    <value>#1</value>
                                </enumeratedValue>
                            </enumeratedValues>
                        </field>
                        <field>
                            <name>USELCF</name>
                            <description>ELC_GPTF Event Source Counter Count Up Enable</description>
                            <lsb>21</lsb>
                            <msb>21</msb>
                            <access>read-write</access>
                            <enumeratedValues>
                                <enumeratedValue>
                                    <name>0</name>
                                    <description>Counter count up disabled at the ELC_GPTF input</description>
                                    <value>#0</value>
                                </enumeratedValue>
                                <enumeratedValue>
                                    <name>1</name>
                                    <description>Counter count up enabled at the ELC_GPTF input</description>
                                    <value>#1</value>
                                </enumeratedValue>
                            </enumeratedValues>
                        </field>
                        <field>
                            <name>USELCG</name>
                            <description>ELC_GPTG Event Source Counter Count Up Enable</description>
                            <lsb>22</lsb>
                            <msb>22</msb>
                            <access>read-write</access>
                            <enumeratedValues>
                                <enumeratedValue>
                                    <name>0</name>
                                    <description>Counter count up disabled at the ELC_GPTG input</description>
                                    <value>#0</value>
                                </enumeratedValue>
                                <enumeratedValue>
                                    <name>1</name>
                                    <description>Counter count up enabled at the ELC_GPTG input</description>
                                    <value>#1</value>
                                </enumeratedValue>
                            </enumeratedValues>
                        </field>
                        <field>
                            <name>USELCH</name>
                            <description>ELC_GPTH Event Source Counter Count Up Enable</description>
                            <lsb>23</lsb>
                            <msb>23</msb>
                            <access>read-write</access>
                            <enumeratedValues>
                                <enumeratedValue>
                                    <name>0</name>
                                    <description>Counter count up disabled at the ELC_GPTH input</description>
                                    <value>#0</value>
                                </enumeratedValue>
                                <enumeratedValue>
                                    <name>1</name>
                                    <description>Counter count up enabled at the ELC_GPTH input</description>
                                    <value>#1</value>
                                </enumeratedValue>
                            </enumeratedValues>
                        </field>
                    </fields>
                </register>
                <register>
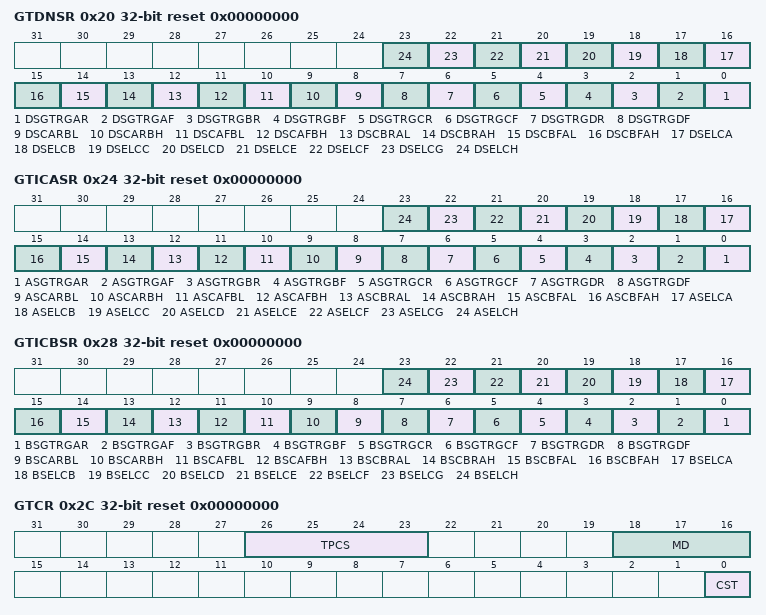
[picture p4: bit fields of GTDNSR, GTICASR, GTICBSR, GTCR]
                    <name>GTDNSR</name>
                    <description>General PWM Timer Down Count Source Select Register</description>
                    <addressOffset>0x20</addressOffset>
                    <size>32</size>
                    <access>read-write</access>
                    <resetValue>0x00000000</resetValue>
                    <resetMask>0xffffffff</resetMask>
                    <fields>
                        <field>
                            <name>DSGTRGAR</name>
                            <description>GTETRGA Pin Rising Input Source Counter Count Down Enable</description>
                            <lsb>0</lsb>
                            <msb>0</msb>
                            <access>read-write</access>
                            <enumeratedValues>
                                <enumeratedValue>
                                    <name>0</name>
                                    <description>Counter count down disabled on the rising edge of GTETRGA input</description>
                                    <value>#0</value>
                                </enumeratedValue>
                                <enumeratedValue>
                                    <name>1</name>
                                    <description>Counter count down enabled on the rising edge of GTETRGA input</description>
                                    <value>#1</value>
                                </enumeratedValue>
                            </enumeratedValues>
                        </field>
                        <field>
                            <name>DSGTRGAF</name>
                            <description>GTETRGA Pin Falling Input Source Counter Count Down Enable</description>
                            <lsb>1</lsb>
                            <msb>1</msb>
                            <access>read-write</access>
                            <enumeratedValues>
                                <enumeratedValue>
                                    <name>0</name>
                                    <description>Counter count down disabled on the falling edge of GTETRGA input</description>
                                    <value>#0</value>
                                </enumeratedValue>
                                <enumeratedValue>
                                    <name>1</name>
                                    <description>Counter count down enabled on the falling edge of GTETRGA input</description>
                                    <value>#1</value>
                                </enumeratedValue>
                            </enumeratedValues>
                        </field>
                        <field>
                            <name>DSGTRGBR</name>
                            <description>GTETRGB Pin Rising Input Source Counter Count Down Enable</description>
                            <lsb>2</lsb>
                            <msb>2</msb>
                            <access>read-write</access>
                            <enumeratedValues>
                                <enumeratedValue>
                                    <name>0</name>
                                    <description>Counter count down disabled on the rising edge of GTETRGB input</description>
                                    <value>#0</value>
                                </enumeratedValue>
                                <enumeratedValue>
                                    <name>1</name>
                                    <description>Counter count down enabled on the rising edge of GTETRGB input</description>
                                    <value>#1</value>
                                </enumeratedValue>
                            </enumeratedValues>
                        </field>
                        <field>
                            <name>DSGTRGBF</name>
                            <description>GTETRGB Pin Falling Input Source Counter Count Down Enable</description>
                            <lsb>3</lsb>
                            <msb>3</msb>
                            <access>read-write</access>
                            <enumeratedValues>
                                <enumeratedValue>
                                    <name>0</name>
                                    <description>Counter count down disabled on the falling edge of GTETRGB input</description>
                                    <value>#0</value>
                                </enumeratedValue>
                                <enumeratedValue>
                                    <name>1</name>
                                    <description>Counter count down enabled on the falling edge of GTETRGB input</description>
                                    <value>#1</value>
                                </enumeratedValue>
                            </enumeratedValues>
                        </field>
                        <field>
                            <name>DSGTRGCR</name>
                            <description>GTETRGC Pin Rising Input Source Counter Count Down Enable</description>
                            <lsb>4</lsb>
                            <msb>4</msb>
                            <access>read-write</access>
                            <enumeratedValues>
                                <enumeratedValue>
                                    <name>0</name>
                                    <description>Counter count down disabled on the rising edge of GTETRGC input</description>
                                    <value>#0</value>
                                </enumeratedValue>
                                <enumeratedValue>
                                    <name>1</name>
                                    <description>Counter count down enabled on the rising edge of GTETRGC input</description>
                                    <value>#1</value>
                                </enumeratedValue>
                            </enumeratedValues>
                        </field>
                        <field>
                            <name>DSGTRGCF</name>
                            <description>GTETRGC Pin Falling Input Source Counter Count Down Enable</description>
                            <lsb>5</lsb>
                            <msb>5</msb>
                            <access>read-write</access>
                            <enumeratedValues>
                                <enumeratedValue>
                                    <name>0</name>
                                    <description>Counter count down disabled on the falling edge of GTETRGC input</description>
                                    <value>#0</value>
                                </enumeratedValue>
                                <enumeratedValue>
                                    <name>1</name>
                                    <description>Counter count down enabled on the falling edge of GTETRGC input</description>
                                    <value>#1</value>
                                </enumeratedValue>
                            </enumeratedValues>
                        </field>
                        <field>
                            <name>DSGTRGDR</name>
                            <description>GTETRGD Pin Rising Input Source Counter Count Down Enable</description>
                            <lsb>6</lsb>
                            <msb>6</msb>
                            <access>read-write</access>
                            <enumeratedValues>
                                <enumeratedValue>
                                    <name>0</name>
                                    <description>Counter count down disabled on the rising edge of GTETRGD input</description>
                                    <value>#0</value>
                                </enumeratedValue>
                                <enumeratedValue>
                                    <name>1</name>
                                    <description>Counter count down enabled on the rising edge of GTETRGD input</description>
                                    <value>#1</value>
                                </enumeratedValue>
                            </enumeratedValues>
                        </field>
                        <field>
                            <name>DSGTRGDF</name>
                            <description>GTETRGD Pin Falling Input Source Counter Count Down Enable</description>
                            <lsb>7</lsb>
                            <msb>7</msb>
                            <access>read-write</access>
                            <enumeratedValues>
                                <enumeratedValue>
                                    <name>0</name>
                                    <description>Counter count down disabled on the falling edge of GTETRGD input</description>
                                    <value>#0</value>
                                </enumeratedValue>
                                <enumeratedValue>
                                    <name>1</name>
                                    <description>Counter count down enabled on the falling edge of GTETRGD input</description>
                                    <value>#1</value>
                                </enumeratedValue>
                            </enumeratedValues>
                        </field>
                        <field>
                            <name>DSCARBL</name>
                            <description>GTIOCnA Pin Rising Input during GTIOCnB Value Low Source Counter Count Down Enable</description>
                            <lsb>8</lsb>
                            <msb>8</msb>
                            <access>read-write</access>
                            <enumeratedValues>
                                <enumeratedValue>
                                    <name>0</name>
                                    <description>Counter count down disabled on the rising edge of GTIOCnA input when GTIOCnB input is 0</description>
                                    <value>#0</value>
                                </enumeratedValue>
                                <enumeratedValue>
                                    <name>1</name>
                                    <description>Counter count down enabled on the rising edge of GTIOCnA input when GTIOCnB input is 0</description>
                                    <value>#1</value>
                                </enumeratedValue>
                            </enumeratedValues>
                        </field>
                        <field>
                            <name>DSCARBH</name>
                            <description>GTIOCnA Pin Rising Input during GTIOCnB Value High Source Counter Count Down Enable</description>
                            <lsb>9</lsb>
                            <msb>9</msb>
                            <access>read-write</access>
                            <enumeratedValues>
                                <enumeratedValue>
                                    <name>0</name>
                                    <description>Counter count down disabled on the rising edge of GTIOCnA input when GTIOCnB input is 1</description>
                                    <value>#0</value>
                                </enumeratedValue>
                                <enumeratedValue>
                                    <name>1</name>
                                    <description>Counter count down enabled on the rising edge of GTIOCnA input when GTIOCnB input is 1</description>
                                    <value>#1</value>
                                </enumeratedValue>
                            </enumeratedValues>
                        </field>
                        <field>
                            <name>DSCAFBL</name>
                            <description>GTIOCnA Pin Falling Input during GTIOCnB Value Low Source Counter Count Down Enable</description>
                            <lsb>10</lsb>
                            <msb>10</msb>
                            <access>read-write</access>
                            <enumeratedValues>
                                <enumeratedValue>
                                    <name>0</name>
                                    <description>Counter count down disabled on the falling edge of GTIOCnA input when GTIOCnB input is 0</description>
                                    <value>#0</value>
                                </enumeratedValue>
                                <enumeratedValue>
                                    <name>1</name>
                                    <description>Counter count down enabled on the falling edge of GTIOCnA input when GTIOCnB input is 0</description>
                                    <value>#1</value>
                                </enumeratedValue>
                            </enumeratedValues>
                        </field>
                        <field>
                            <name>DSCAFBH</name>
                            <description>GTIOCnA Pin Falling Input during GTIOCnB Value High Source Counter Count Down Enable</description>
                            <lsb>11</lsb>
                            <msb>11</msb>
                            <access>read-write</access>
                            <enumeratedValues>
                                <enumeratedValue>
                                    <name>0</name>
                                    <description>Counter count down disabled on the falling edge of GTIOCnA input when GTIOCnB input is 1</description>
                                    <value>#0</value>
                                </enumeratedValue>
                                <enumeratedValue>
                                    <name>1</name>
                                    <description>Counter count down enabled on the falling edge of GTIOCnA input when GTIOCnB input is 1</description>
                                    <value>#1</value>
                                </enumeratedValue>
                            </enumeratedValues>
                        </field>
                        <field>
                            <name>DSCBRAL</name>
                            <description>GTIOCnB Pin Rising Input during GTIOCnA Value Low Source Counter Count Down Enable</description>
                            <lsb>12</lsb>
                            <msb>12</msb>
                            <access>read-write</access>
                            <enumeratedValues>
                                <enumeratedValue>
                                    <name>0</name>
                                    <description>Counter count down disabled on the rising edge of GTIOCnB input when GTIOCnA input is 0</description>
                                    <value>#0</value>
                                </enumeratedValue>
                                <enumeratedValue>
                                    <name>1</name>
                                    <description>Counter count down enabled on the rising edge of GTIOCnB input when GTIOCnA input is 0</description>
                                    <value>#1</value>
                                </enumeratedValue>
                            </enumeratedValues>
                        </field>
                        <field>
                            <name>DSCBRAH</name>
                            <description>GTIOCnB Pin Rising Input during GTIOCnA Value High Source Counter Count Down Enable</description>
                            <lsb>13</lsb>
                            <msb>13</msb>
                            <access>read-write</access>
                            <enumeratedValues>
                                <enumeratedValue>
                                    <name>0</name>
                                    <description>Counter count down disabled on the rising edge of GTIOCnB input when GTIOCnA input is 1</description>
                                    <value>#0</value>
                                </enumeratedValue>
                                <enumeratedValue>
                                    <name>1</name>
                                    <description>Counter count down enabled on the rising edge of GTIOCnB input when GTIOCnA input is 1</description>
                                    <value>#1</value>
                                </enumeratedValue>
                            </enumeratedValues>
                        </field>
                        <field>
                            <name>DSCBFAL</name>
                            <description>GTIOCnB Pin Falling Input during GTIOCnA Value Low Source Counter Count Down Enable</description>
                            <lsb>14</lsb>
                            <msb>14</msb>
                            <access>read-write</access>
                            <enumeratedValues>
                                <enumeratedValue>
                                    <name>0</name>
                                    <description>Counter count down disabled on the falling edge of GTIOCnB input when GTIOCnA input is 0</description>
                                    <value>#0</value>
                                </enumeratedValue>
                                <enumeratedValue>
                                    <name>1</name>
                                    <description>Counter count down enabled on the falling edge of GTIOCnB input when GTIOCnA input is 0</description>
                                    <value>#1</value>
                                </enumeratedValue>
                            </enumeratedValues>
                        </field>
                        <field>
                            <name>DSCBFAH</name>
                            <description>GTIOCnB Pin Falling Input during GTIOCnA Value High Source Counter Count Down Enable</description>
                            <lsb>15</lsb>
                            <msb>15</msb>
                            <access>read-write</access>
                            <enumeratedValues>
                                <enumeratedValue>
                                    <name>0</name>
                                    <description>Counter count down disabled on the falling edge of GTIOCnB input when GTIOCnA input is 1</description>
                                    <value>#0</value>
                                </enumeratedValue>
                                <enumeratedValue>
                                    <name>1</name>
                                    <description>Counter count down enabled on the falling edge of GTIOCnB input when GTIOCnA input is 1</description>
                                    <value>#1</value>
                                </enumeratedValue>
                            </enumeratedValues>
                        </field>
                        <field>
                            <name>DSELCA</name>
                            <description>ELC_GPTA Event Source Counter Count Down Enable</description>
                            <lsb>16</lsb>
                            <msb>16</msb>
                            <access>read-write</access>
                            <enumeratedValues>
                                <enumeratedValue>
                                    <name>0</name>
                                    <description>Counter count down disabled at the ELC_GPTA input</description>
                                    <value>#0</value>
                                </enumeratedValue>
                                <enumeratedValue>
                                    <name>1</name>
                                    <description>Counter count down enabled at the ELC_GPTA input</description>
                                    <value>#1</value>
                                </enumeratedValue>
                            </enumeratedValues>
                        </field>
                        <field>
                            <name>DSELCB</name>
                            <description>ELC_GPTB Event Source Counter Count Down Enable</description>
                            <lsb>17</lsb>
                            <msb>17</msb>
                            <access>read-write</access>
                            <enumeratedValues>
                                <enumeratedValue>
                                    <name>0</name>
                                    <description>Counter count down disabled at the ELC_GPTB input</description>
                                    <value>#0</value>
                                </enumeratedValue>
                                <enumeratedValue>
                                    <name>1</name>
                                    <description>Counter count down enabled at the ELC_GPTB input</description>
                                    <value>#1</value>
                                </enumeratedValue>
                            </enumeratedValues>
                        </field>
                        <field>
                            <name>DSELCC</name>
                            <description>ELC_GPTC Event Source Counter Count Down Enable</description>
                            <lsb>18</lsb>
                            <msb>18</msb>
                            <access>read-write</access>
                            <enumeratedValues>
                                <enumeratedValue>
                                    <name>0</name>
                                    <description>Counter count down disabled at the ELC_GPTC input</description>
                                    <value>#0</value>
                                </enumeratedValue>
                                <enumeratedValue>
                                    <name>1</name>
                                    <description>Counter count down enabled at the ELC_GPTC input</description>
                                    <value>#1</value>
                                </enumeratedValue>
                            </enumeratedValues>
                        </field>
                        <field>
                            <name>DSELCD</name>
                            <description>ELC_GPTD Event Source Counter Count Down Enable</description>
                            <lsb>19</lsb>
                            <msb>19</msb>
                            <access>read-write</access>
                            <enumeratedValues>
                                <enumeratedValue>
                                    <name>0</name>
                                    <description>Counter count down disabled at the ELC_GPTD input</description>
                                    <value>#0</value>
                                </enumeratedValue>
                                <enumeratedValue>
                                    <name>1</name>
                                    <description>Counter count down enabled at the ELC_GPTD input</description>
                                    <value>#1</value>
                                </enumeratedValue>
                            </enumeratedValues>
                        </field>
                        <field>
                            <name>DSELCE</name>
                            <description>ELC_GPTE Event Source Counter Count Down Enable</description>
                            <lsb>20</lsb>
                            <msb>20</msb>
                            <access>read-write</access>
                            <enumeratedValues>
                                <enumeratedValue>
                                    <name>0</name>
                                    <description>Counter count down disabled at the ELC_GPTE input</description>
                                    <value>#0</value>
                                </enumeratedValue>
                                <enumeratedValue>
                                    <name>1</name>
                                    <description>Counter count down enabled at the ELC_GPTE input</description>
                                    <value>#1</value>
                                </enumeratedValue>
                            </enumeratedValues>
                        </field>
                        <field>
                            <name>DSELCF</name>
                            <description>ELC_GPTF Event Source Counter Count Down Enable</description>
                            <lsb>21</lsb>
                            <msb>21</msb>
                            <access>read-write</access>
                            <enumeratedValues>
                                <enumeratedValue>
                                    <name>0</name>
                                    <description>Counter count down disabled at the ELC_GPTF input</description>
                                    <value>#0</value>
                                </enumeratedValue>
                                <enumeratedValue>
                                    <name>1</name>
                                    <description>Counter count down enabled at the ELC_GPTF input</description>
                                    <value>#1</value>
                                </enumeratedValue>
                            </enumeratedValues>
                        </field>
                        <field>
                            <name>DSELCG</name>
                            <description>ELC_GPTG Event Source Counter Count Down Enable</description>
                            <lsb>22</lsb>
                            <msb>22</msb>
                            <access>read-write</access>
                            <enumeratedValues>
                                <enumeratedValue>
                                    <name>0</name>
                                    <description>Counter count down disabled at the ELC_GPTG input</description>
                                    <value>#0</value>
                                </enumeratedValue>
                                <enumeratedValue>
                                    <name>1</name>
                                    <description>Counter count down enabled at the ELC_GPTG input</description>
                                    <value>#1</value>
                                </enumeratedValue>
                            </enumeratedValues>
                        </field>
                        <field>
                            <name>DSELCH</name>
                            <description>ELC_GPTF Event Source Counter Count Down Enable</description>
                            <lsb>23</lsb>
                            <msb>23</msb>
                            <access>read-write</access>
                            <enumeratedValues>
                                <enumeratedValue>
                                    <name>0</name>
                                    <description>Counter count down disabled at the ELC_GPTF input</description>
                                    <value>#0</value>
                                </enumeratedValue>
                                <enumeratedValue>
                                    <name>1</name>
                                    <description>Counter count down enabled at the ELC_GPTF input</description>
                                    <value>#1</value>
                                </enumeratedValue>
                            </enumeratedValues>
                        </field>
                    </fields>
                </register>
                <register>
                    <name>GTICASR</name>
                    <description>General PWM Timer Input Capture Source Select Register A</description>
                    <addressOffset>0x24</addressOffset>
                    <size>32</size>
                    <access>read-write</access>
                    <resetValue>0x00000000</resetValue>
                    <resetMask>0xffffffff</resetMask>
                    <fields>
                        <field>
                            <name>ASGTRGAR</name>
                            <description>GTETRGA Pin Rising Input Source GTCCRA Input Capture Enable</description>
                            <lsb>0</lsb>
                            <msb>0</msb>
                            <access>read-write</access>
                            <enumeratedValues>
                                <enumeratedValue>
                                    <name>0</name>
                                    <description>GTCCRA input capture disabled on the rising edge of GTETRGA input</description>
                                    <value>#0</value>
                                </enumeratedValue>
                                <enumeratedValue>
                                    <name>1</name>
                                    <description>GTCCRA input capture enabled on the rising edge of GTETRGA input</description>
                                    <value>#1</value>
                                </enumeratedValue>
                            </enumeratedValues>
                        </field>
                        <field>
                            <name>ASGTRGAF</name>
                            <description>GTETRGA Pin Falling Input Source GTCCRA Input Capture Enable</description>
                            <lsb>1</lsb>
                            <msb>1</msb>
                            <access>read-write</access>
                            <enumeratedValues>
                                <enumeratedValue>
                                    <name>0</name>
                                    <description>GTCCRA input capture disabled on the falling edge of GTETRGA input</description>
                                    <value>#0</value>
                                </enumeratedValue>
                                <enumeratedValue>
                                    <name>1</name>
                                    <description>GTCCRA input capture enabled on the falling edge of GTETRGA input</description>
                                    <value>#1</value>
                                </enumeratedValue>
                            </enumeratedValues>
                        </field>
                        <field>
                            <name>ASGTRGBR</name>
                            <description>GTETRGB Pin Rising Input Source GTCCRA Input Capture Enable</description>
                            <lsb>2</lsb>
                            <msb>2</msb>
                            <access>read-write</access>
                            <enumeratedValues>
                                <enumeratedValue>
                                    <name>0</name>
                                    <description>GTCCRA input capture disabled on the rising edge of GTETRGB input</description>
                                    <value>#0</value>
                                </enumeratedValue>
                                <enumeratedValue>
                                    <name>1</name>
                                    <description>GTCCRA input capture enabled on the rising edge of GTETRGB input</description>
                                    <value>#1</value>
                                </enumeratedValue>
                            </enumeratedValues>
                        </field>
                        <field>
                            <name>ASGTRGBF</name>
                            <description>GTETRGB Pin Falling Input Source GTCCRA Input Capture Enable</description>
                            <lsb>3</lsb>
                            <msb>3</msb>
                            <access>read-write</access>
                            <enumeratedValues>
                                <enumeratedValue>
                                    <name>0</name>
                                    <description>GTCCRA input capture disabled on the falling edge of GTETRGB input</description>
                                    <value>#0</value>
                                </enumeratedValue>
                                <enumeratedValue>
                                    <name>1</name>
                                    <description>GTCCRA input capture enabled on the falling edge of GTETRGB input</description>
                                    <value>#1</value>
                                </enumeratedValue>
                            </enumeratedValues>
                        </field>
                        <field>
                            <name>ASGTRGCR</name>
                            <description>GTETRGC Pin Rising Input Source GTCCRA Input Capture Enable</description>
                            <lsb>4</lsb>
                            <msb>4</msb>
                            <access>read-write</access>
                            <enumeratedValues>
                                <enumeratedValue>
                                    <name>0</name>
                                    <description>GTCCRA input capture disabled on the rising edge of GTETRGC input</description>
                                    <value>#0</value>
                                </enumeratedValue>
                                <enumeratedValue>
                                    <name>1</name>
                                    <description>GTCCRA input capture enabled on the rising edge of GTETRGC input</description>
                                    <value>#1</value>
                                </enumeratedValue>
                            </enumeratedValues>
                        </field>
                        <field>
                            <name>ASGTRGCF</name>
                            <description>GTETRGC Pin Falling Input Source GTCCRA Input Capture Enable</description>
                            <lsb>5</lsb>
                            <msb>5</msb>
                            <access>read-write</access>
                            <enumeratedValues>
                                <enumeratedValue>
                                    <name>0</name>
                                    <description>GTCCRA input capture disabled on the falling edge of GTETRGC input</description>
                                    <value>#0</value>
                                </enumeratedValue>
                                <enumeratedValue>
                                    <name>1</name>
                                    <description>GTCCRA input capture enabled on the falling edge of GTETRGC input</description>
                                    <value>#1</value>
                                </enumeratedValue>
                            </enumeratedValues>
                        </field>
                        <field>
                            <name>ASGTRGDR</name>
                            <description>GTETRGD Pin Rising Input Source GTCCRA Input Capture Enable</description>
                            <lsb>6</lsb>
                            <msb>6</msb>
                            <access>read-write</access>
                            <enumeratedValues>
                                <enumeratedValue>
                                    <name>0</name>
                                    <description>GTCCRA input capture disabled on the rising edge of GTETRGD input</description>
                                    <value>#0</value>
                                </enumeratedValue>
                                <enumeratedValue>
                                    <name>1</name>
                                    <description>GTCCRA input capture enabled on the rising edge of GTETRGD input</description>
                                    <value>#1</value>
                                </enumeratedValue>
                            </enumeratedValues>
                        </field>
                        <field>
                            <name>ASGTRGDF</name>
                            <description>GTETRGD Pin Falling Input Source GTCCRA Input Capture Enable</description>
                            <lsb>7</lsb>
                            <msb>7</msb>
                            <access>read-write</access>
                            <enumeratedValues>
                                <enumeratedValue>
                                    <name>0</name>
                                    <description>GTCCRA input capture disabled on the falling edge of GTETRGD input</description>
                                    <value>#0</value>
                                </enumeratedValue>
                                <enumeratedValue>
                                    <name>1</name>
                                    <description>GTCCRA input capture enabled on the falling edge of GTETRGD input</description>
                                    <value>#1</value>
                                </enumeratedValue>
                            </enumeratedValues>
                        </field>
                        <field>
                            <name>ASCARBL</name>
                            <description>GTIOCnA Pin Rising Input during GTIOCnB Value Low Source GTCCRA Input Capture Enable</description>
                            <lsb>8</lsb>
                            <msb>8</msb>
                            <access>read-write</access>
                            <enumeratedValues>
                                <enumeratedValue>
                                    <name>0</name>
                                    <description>GTCCRA input capture disabled on the rising edge of GTIOCnA input when GTIOCnB input is 0</description>
                                    <value>#0</value>
                                </enumeratedValue>
                                <enumeratedValue>
                                    <name>1</name>
                                    <description>GTCCRA input capture enabled on the rising edge of GTIOCnA input when GTIOCnB input is 0</description>
                                    <value>#1</value>
                                </enumeratedValue>
                            </enumeratedValues>
                        </field>
                        <field>
                            <name>ASCARBH</name>
                            <description>GTIOCnA Pin Rising Input during GTIOCnB Value High Source GTCCRA Input Capture Enable</description>
                            <lsb>9</lsb>
                            <msb>9</msb>
                            <access>read-write</access>
                            <enumeratedValues>
                                <enumeratedValue>
                                    <name>0</name>
                                    <description>GTCCRA input capture disabled on the rising edge of GTIOCnA input when GTIOCnB input is 1</description>
                                    <value>#0</value>
                                </enumeratedValue>
                                <enumeratedValue>
                                    <name>1</name>
                                    <description>GTCCRA input capture enabled on the rising edge of GTIOCnA input when GTIOCnB input is 1</description>
                                    <value>#1</value>
                                </enumeratedValue>
                            </enumeratedValues>
                        </field>
                        <field>
                            <name>ASCAFBL</name>
                            <description>GTIOCnA Pin Falling Input during GTIOCnB Value Low Source GTCCRA Input Capture Enable</description>
                            <lsb>10</lsb>
                            <msb>10</msb>
                            <access>read-write</access>
                            <enumeratedValues>
                                <enumeratedValue>
                                    <name>0</name>
                                    <description>GTCCRA input capture disabled on the falling edge of GTIOCnA input when GTIOCnB input is 0</description>
                                    <value>#0</value>
                                </enumeratedValue>
                                <enumeratedValue>
                                    <name>1</name>
                                    <description>GTCCRA input capture enabled on the falling edge of GTIOCnA input when GTIOCnB input is 0</description>
                                    <value>#1</value>
                                </enumeratedValue>
                            </enumeratedValues>
                        </field>
                        <field>
                            <name>ASCAFBH</name>
                            <description>GTIOCnA Pin Falling Input during GTIOCnB Value High Source GTCCRA Input Capture Enable</description>
                            <lsb>11</lsb>
                            <msb>11</msb>
                            <access>read-write</access>
                            <enumeratedValues>
                                <enumeratedValue>
                                    <name>0</name>
                                    <description>GTCCRA input capture disabled on the falling edge of GTIOCnA input when GTIOCnB input is 1</description>
                                    <value>#0</value>
                                </enumeratedValue>
                                <enumeratedValue>
                                    <name>1</name>
                                    <description>GTCCRA input capture enabled on the falling edge of GTIOCnA input when GTIOCnB input is 1</description>
                                    <value>#1</value>
                                </enumeratedValue>
                            </enumeratedValues>
                        </field>
                        <field>
                            <name>ASCBRAL</name>
                            <description>GTIOCnB Pin Rising Input during GTIOCnA Value Low Source GTCCRA Input Capture Enable</description>
                            <lsb>12</lsb>
                            <msb>12</msb>
                            <access>read-write</access>
                            <enumeratedValues>
                                <enumeratedValue>
                                    <name>0</name>
                                    <description>GTCCRA input capture disabled on the rising edge of GTIOCnB input when GTIOCnA input is 0</description>
                                    <value>#0</value>
                                </enumeratedValue>
                                <enumeratedValue>
                                    <name>1</name>
                                    <description>GTCCRA input capture enabled on the rising edge of GTIOCnB input when GTIOCnA input is 0</description>
                                    <value>#1</value>
                                </enumeratedValue>
                            </enumeratedValues>
                        </field>
                        <field>
                            <name>ASCBRAH</name>
                            <description>GTIOCnB Pin Rising Input during GTIOCnA Value High Source GTCCRA Input Capture Enable</description>
                            <lsb>13</lsb>
                            <msb>13</msb>
                            <access>read-write</access>
                            <enumeratedValues>
                                <enumeratedValue>
                                    <name>0</name>
                                    <description>GTCCRA input capture disabled on the rising edge of GTIOCnB input when GTIOCnA input is 1</description>
                                    <value>#0</value>
                                </enumeratedValue>
                                <enumeratedValue>
                                    <name>1</name>
                                    <description>GTCCRA input capture enabled on the rising edge of GTIOCnB input when GTIOCnA input is 1</description>
                                    <value>#1</value>
                                </enumeratedValue>
                            </enumeratedValues>
                        </field>
                        <field>
                            <name>ASCBFAL</name>
                            <description>GTIOCnB Pin Falling Input during GTIOCnA Value Low Source GTCCRA Input Capture Enable</description>
                            <lsb>14</lsb>
                            <msb>14</msb>
                            <access>read-write</access>
                            <enumeratedValues>
                                <enumeratedValue>
                                    <name>0</name>
                                    <description>GTCCRA input capture disabled on the falling edge of GTIOCnB input when GTIOCnA input is 0</description>
                                    <value>#0</value>
                                </enumeratedValue>
                                <enumeratedValue>
                                    <name>1</name>
                                    <description>GTCCRA input capture enabled on the falling edge of GTIOCnB input when GTIOCnA input is 0</description>
                                    <value>#1</value>
                                </enumeratedValue>
                            </enumeratedValues>
                        </field>
                        <field>
                            <name>ASCBFAH</name>
                            <description>GTIOCnB Pin Falling Input during GTIOCnA Value High Source GTCCRA Input Capture Enable</description>
                            <lsb>15</lsb>
                            <msb>15</msb>
                            <access>read-write</access>
                            <enumeratedValues>
                                <enumeratedValue>
                                    <name>0</name>
                                    <description>GTCCRA input capture disabled on the falling edge of GTIOCnB input when GTIOCnA input is 1</description>
                                    <value>#0</value>
                                </enumeratedValue>
                                <enumeratedValue>
                                    <name>1</name>
                                    <description>GTCCRA input capture enabled on the falling edge of GTIOCnB input when GTIOCnA input is 1</description>
                                    <value>#1</value>
                                </enumeratedValue>
                            </enumeratedValues>
                        </field>
                        <field>
                            <name>ASELCA</name>
                            <description>ELC_GPTA Event Source GTCCRA Input Capture Enable</description>
                            <lsb>16</lsb>
                            <msb>16</msb>
                            <access>read-write</access>
                            <enumeratedValues>
                                <enumeratedValue>
                                    <name>0</name>
                                    <description>GTCCRA input capture disabled at the ELC_GPTA input</description>
                                    <value>#0</value>
                                </enumeratedValue>
                                <enumeratedValue>
                                    <name>1</name>
                                    <description>GTCCRA input capture enabled at the ELC_GPTA input</description>
                                    <value>#1</value>
                                </enumeratedValue>
                            </enumeratedValues>
                        </field>
                        <field>
                            <name>ASELCB</name>
                            <description>ELC_GPTB Event Source GTCCRA Input Capture Enable</description>
                            <lsb>17</lsb>
                            <msb>17</msb>
                            <access>read-write</access>
                            <enumeratedValues>
                                <enumeratedValue>
                                    <name>0</name>
                                    <description>GTCCRA input capture disabled at the ELC_GPTB input</description>
                                    <value>#0</value>
                                </enumeratedValue>
                                <enumeratedValue>
                                    <name>1</name>
                                    <description>GTCCRA input capture enabled at the ELC_GPTB input</description>
                                    <value>#1</value>
                                </enumeratedValue>
                            </enumeratedValues>
                        </field>
                        <field>
                            <name>ASELCC</name>
                            <description>ELC_GPTC Event Source GTCCRA Input Capture Enable</description>
                            <lsb>18</lsb>
                            <msb>18</msb>
                            <access>read-write</access>
                            <enumeratedValues>
                                <enumeratedValue>
                                    <name>0</name>
                                    <description>GTCCRA input capture disabled at the ELC_GPTC input</description>
                                    <value>#0</value>
                                </enumeratedValue>
                                <enumeratedValue>
                                    <name>1</name>
                                    <description>GTCCRA input capture enabled at the ELC_GPTC input</description>
                                    <value>#1</value>
                                </enumeratedValue>
                            </enumeratedValues>
                        </field>
                        <field>
                            <name>ASELCD</name>
                            <description>ELC_GPTD Event Source GTCCRA Input Capture Enable</description>
                            <lsb>19</lsb>
                            <msb>19</msb>
                            <access>read-write</access>
                            <enumeratedValues>
                                <enumeratedValue>
                                    <name>0</name>
                                    <description>GTCCRA input capture disabled at the ELC_GPTD input</description>
                                    <value>#0</value>
                                </enumeratedValue>
                                <enumeratedValue>
                                    <name>1</name>
                                    <description>GTCCRA input capture enabled at the ELC_GPTD input</description>
                                    <value>#1</value>
                                </enumeratedValue>
                            </enumeratedValues>
                        </field>
                        <field>
                            <name>ASELCE</name>
                            <description>ELC_GPTE Event Source GTCCRA Input Capture Enable</description>
                            <lsb>20</lsb>
                            <msb>20</msb>
                            <access>read-write</access>
                            <enumeratedValues>
                                <enumeratedValue>
                                    <name>0</name>
                                    <description>GTCCRA input capture disabled at the ELC_GPTE input</description>
                                    <value>#0</value>
                                </enumeratedValue>
                                <enumeratedValue>
                                    <name>1</name>
                                    <description>GTCCRA input capture enabled at the ELC_GPTE input</description>
                                    <value>#1</value>
                                </enumeratedValue>
                            </enumeratedValues>
                        </field>
                        <field>
                            <name>ASELCF</name>
                            <description>ELC_GPTF Event Source GTCCRA Input Capture Enable</description>
                            <lsb>21</lsb>
                            <msb>21</msb>
                            <access>read-write</access>
                            <enumeratedValues>
                                <enumeratedValue>
                                    <name>0</name>
                                    <description>GTCCRA input capture disabled at the ELC_GPTF input</description>
                                    <value>#0</value>
                                </enumeratedValue>
                                <enumeratedValue>
                                    <name>1</name>
                                    <description>GTCCRA input capture enabled at the ELC_GPTF input</description>
                                    <value>#1</value>
                                </enumeratedValue>
                            </enumeratedValues>
                        </field>
                        <field>
                            <name>ASELCG</name>
                            <description>ELC_GPTG Event Source GTCCRA Input Capture Enable</description>
                            <lsb>22</lsb>
                            <msb>22</msb>
                            <access>read-write</access>
                            <enumeratedValues>
                                <enumeratedValue>
                                    <name>0</name>
                                    <description>GTCCRA input capture disabled at the ELC_GPTG input</description>
                                    <value>#0</value>
                                </enumeratedValue>
                                <enumeratedValue>
                                    <name>1</name>
                                    <description>GTCCRA input capture enabled at the ELC_GPTG input</description>
                                    <value>#1</value>
                                </enumeratedValue>
                            </enumeratedValues>
                        </field>
                        <field>
                            <name>ASELCH</name>
                            <description>ELC_GPTH Event Source GTCCRA Input Capture Enable</description>
                            <lsb>23</lsb>
                            <msb>23</msb>
                            <access>read-write</access>
                            <enumeratedValues>
                                <enumeratedValue>
                                    <name>0</name>
                                    <description>GTCCRA input capture disabled at the ELC_GPTH input</description>
                                    <value>#0</value>
                                </enumeratedValue>
                                <enumeratedValue>
                                    <name>1</name>
                                    <description>GTCCRA input capture enabled at the ELC_GPTH input</description>
                                    <value>#1</value>
                                </enumeratedValue>
                            </enumeratedValues>
                        </field>
                    </fields>
                </register>
                <register>
                    <name>GTICBSR</name>
                    <description>General PWM Timer Input Capture Source Select Register B</description>
                    <addressOffset>0x28</addressOffset>
                    <size>32</size>
                    <access>read-write</access>
                    <resetValue>0x00000000</resetValue>
                    <resetMask>0xffffffff</resetMask>
                    <fields>
                        <field>
                            <name>BSGTRGAR</name>
                            <description>GTETRGA Pin Rising Input Source GTCCRB Input Capture Enable</description>
                            <lsb>0</lsb>
                            <msb>0</msb>
                            <access>read-write</access>
                            <enumeratedValues>
                                <enumeratedValue>
                                    <name>0</name>
                                    <description>GTCCRB input capture disabled on the rising edge of GTETRGA input</description>
                                    <value>#0</value>
                                </enumeratedValue>
                                <enumeratedValue>
                                    <name>1</name>
                                    <description>GTCCRB input capture enabled on the rising edge of GTETRGA input</description>
                                    <value>#1</value>
                                </enumeratedValue>
                            </enumeratedValues>
                        </field>
                        <field>
                            <name>BSGTRGAF</name>
                            <description>GTETRGA Pin Falling Input Source GTCCRB Input Capture Enable</description>
                            <lsb>1</lsb>
                            <msb>1</msb>
                            <access>read-write</access>
                            <enumeratedValues>
                                <enumeratedValue>
                                    <name>0</name>
                                    <description>GTCCRB input capture disabled on the falling edge of GTETRGA input</description>
                                    <value>#0</value>
                                </enumeratedValue>
                                <enumeratedValue>
                                    <name>1</name>
                                    <description>GTCCRB input capture enabled on the falling edge of GTETRGA input</description>
                                    <value>#1</value>
                                </enumeratedValue>
                            </enumeratedValues>
                        </field>
                        <field>
                            <name>BSGTRGBR</name>
                            <description>GTETRGB Pin Rising Input Source GTCCRB Input Capture Enable</description>
                            <lsb>2</lsb>
                            <msb>2</msb>
                            <access>read-write</access>
                            <enumeratedValues>
                                <enumeratedValue>
                                    <name>0</name>
                                    <description>GTCCRB input capture disabled on the rising edge of GTETRGB input</description>
                                    <value>#0</value>
                                </enumeratedValue>
                                <enumeratedValue>
                                    <name>1</name>
                                    <description>GTCCRB input capture enabled on the rising edge of GTETRGB input</description>
                                    <value>#1</value>
                                </enumeratedValue>
                            </enumeratedValues>
                        </field>
                        <field>
                            <name>BSGTRGBF</name>
                            <description>GTETRGB Pin Falling Input Source GTCCRB Input Capture Enable</description>
                            <lsb>3</lsb>
                            <msb>3</msb>
                            <access>read-write</access>
                            <enumeratedValues>
                                <enumeratedValue>
                                    <name>0</name>
                                    <description>GTCCRB input capture disabled on the falling edge of GTETRGB input</description>
                                    <value>#0</value>
                                </enumeratedValue>
                                <enumeratedValue>
                                    <name>1</name>
                                    <description>GTCCRB input capture enabled on the falling edge of GTETRGB input</description>
                                    <value>#1</value>
                                </enumeratedValue>
                            </enumeratedValues>
                        </field>
                        <field>
                            <name>BSGTRGCR</name>
                            <description>GTETRGC Pin Rising Input Source GTCCRB Input Capture Enable</description>
                            <lsb>4</lsb>
                            <msb>4</msb>
                            <access>read-write</access>
                            <enumeratedValues>
                                <enumeratedValue>
                                    <name>0</name>
                                    <description>GTCCRB input capture disabled on the rising edge of GTETRGC input</description>
                                    <value>#0</value>
                                </enumeratedValue>
                                <enumeratedValue>
                                    <name>1</name>
                                    <description>GTCCRB input capture enabled on the rising edge of GTETRGC input</description>
                                    <value>#1</value>
                                </enumeratedValue>
                            </enumeratedValues>
                        </field>
                        <field>
                            <name>BSGTRGCF</name>
                            <description>GTETRGC Pin Falling Input Source GTCCRB Input Capture Enable</description>
                            <lsb>5</lsb>
                            <msb>5</msb>
                            <access>read-write</access>
                            <enumeratedValues>
                                <enumeratedValue>
                                    <name>0</name>
                                    <description>GTCCRB input capture disabled on the falling edge of GTETRGC input</description>
                                    <value>#0</value>
                                </enumeratedValue>
                                <enumeratedValue>
                                    <name>1</name>
                                    <description>GTCCRB input capture enabled on the falling edge of GTETRGC input</description>
                                    <value>#1</value>
                                </enumeratedValue>
                            </enumeratedValues>
                        </field>
                        <field>
                            <name>BSGTRGDR</name>
                            <description>GTETRGD Pin Rising Input Source GTCCRB Input Capture Enable</description>
                            <lsb>6</lsb>
                            <msb>6</msb>
                            <access>read-write</access>
                            <enumeratedValues>
                                <enumeratedValue>
                                    <name>0</name>
                                    <description>GTCCRB input capture disabled on the rising edge of GTETRGD input</description>
                                    <value>#0</value>
                                </enumeratedValue>
                                <enumeratedValue>
                                    <name>1</name>
                                    <description>GTCCRB input capture enabled on the rising edge of GTETRGD input</description>
                                    <value>#1</value>
                                </enumeratedValue>
                            </enumeratedValues>
                        </field>
                        <field>
                            <name>BSGTRGDF</name>
                            <description>GTETRGD Pin Falling Input Source GTCCRB Input Capture Enable</description>
                            <lsb>7</lsb>
                            <msb>7</msb>
                            <access>read-write</access>
                            <enumeratedValues>
                                <enumeratedValue>
                                    <name>0</name>
                                    <description>GTCCRB input capture disabled on the falling edge of GTETRGD input</description>
                                    <value>#0</value>
                                </enumeratedValue>
                                <enumeratedValue>
                                    <name>1</name>
                                    <description>GTCCRB input capture enabled on the falling edge of GTETRGD input</description>
                                    <value>#1</value>
                                </enumeratedValue>
                            </enumeratedValues>
                        </field>
                        <field>
                            <name>BSCARBL</name>
                            <description>GTIOCnA Pin Rising Input during GTIOCnB Value Low Source GTCCRB Input Capture Enable</description>
                            <lsb>8</lsb>
                            <msb>8</msb>
                            <access>read-write</access>
                            <enumeratedValues>
                                <enumeratedValue>
                                    <name>0</name>
                                    <description>GTCCRB input capture disabled on the rising edge of GTIOCnA input when GTIOCnB input is 0</description>
                                    <value>#0</value>
                                </enumeratedValue>
                                <enumeratedValue>
                                    <name>1</name>
                                    <description>GTCCRB input capture enabled on the rising edge of GTIOCnA input when GTIOCnB input is 0</description>
                                    <value>#1</value>
                                </enumeratedValue>
                            </enumeratedValues>
                        </field>
                        <field>
                            <name>BSCARBH</name>
                            <description>GTIOCnA Pin Rising Input during GTIOCnB Value High Source GTCCRB Input Capture Enable</description>
                            <lsb>9</lsb>
                            <msb>9</msb>
                            <access>read-write</access>
                            <enumeratedValues>
                                <enumeratedValue>
                                    <name>0</name>
                                    <description>GTCCRB input capture disabled on the rising edge of GTIOCnA input when GTIOCnB input is 1</description>
                                    <value>#0</value>
                                </enumeratedValue>
                                <enumeratedValue>
                                    <name>1</name>
                                    <description>GTCCRB input capture enabled on the rising edge of GTIOCnA input when GTIOCnB input is 1</description>
                                    <value>#1</value>
                                </enumeratedValue>
                            </enumeratedValues>
                        </field>
                        <field>
                            <name>BSCAFBL</name>
                            <description>GTIOCnA Pin Falling Input during GTIOCnB Value Low Source GTCCRB Input Capture Enable</description>
                            <lsb>10</lsb>
                            <msb>10</msb>
                            <access>read-write</access>
                            <enumeratedValues>
                                <enumeratedValue>
                                    <name>0</name>
                                    <description>GTCCRB input capture disabled on the falling edge of GTIOCnA input when GTIOCnB input is 0</description>
                                    <value>#0</value>
                                </enumeratedValue>
                                <enumeratedValue>
                                    <name>1</name>
                                    <description>GTCCRB input capture enabled on the falling edge of GTIOCnA input when GTIOCnB input is 0</description>
                                    <value>#1</value>
                                </enumeratedValue>
                            </enumeratedValues>
                        </field>
                        <field>
                            <name>BSCAFBH</name>
                            <description>GTIOCnA Pin Falling Input during GTIOCnB Value High Source GTCCRB Input Capture Enable</description>
                            <lsb>11</lsb>
                            <msb>11</msb>
                            <access>read-write</access>
                            <enumeratedValues>
                                <enumeratedValue>
                                    <name>0</name>
                                    <description>GTCCRB input capture disabled on the falling edge of GTIOCnA input when GTIOCnB input is 1</description>
                                    <value>#0</value>
                                </enumeratedValue>
                                <enumeratedValue>
                                    <name>1</name>
                                    <description>GTCCRB input capture enabled on the falling edge of GTIOCnA input when GTIOCnB input is 1</description>
                                    <value>#1</value>
                                </enumeratedValue>
                            </enumeratedValues>
                        </field>
                        <field>
                            <name>BSCBRAL</name>
                            <description>GTIOCnB Pin Rising Input during GTIOCnA Value Low Source GTCCRB Input Capture Enable</description>
                            <lsb>12</lsb>
                            <msb>12</msb>
                            <access>read-write</access>
                            <enumeratedValues>
                                <enumeratedValue>
                                    <name>0</name>
                                    <description>GTCCRB input capture disabled on the rising edge of GTIOCnB input when GTIOCnA input is 0</description>
                                    <value>#0</value>
                                </enumeratedValue>
                                <enumeratedValue>
                                    <name>1</name>
                                    <description>GTCCRB input capture enabled on the rising edge of GTIOCnB input when GTIOCnA input is 0</description>
                                    <value>#1</value>
                                </enumeratedValue>
                            </enumeratedValues>
                        </field>
                        <field>
                            <name>BSCBRAH</name>
                            <description>GTIOCnB Pin Rising Input during GTIOCnA Value High Source GTCCRB Input Capture Enable</description>
                            <lsb>13</lsb>
                            <msb>13</msb>
                            <access>read-write</access>
                            <enumeratedValues>
                                <enumeratedValue>
                                    <name>0</name>
                                    <description>GTCCRB input capture disabled on the rising edge of GTIOCnB input when GTIOCnA input is 1</description>
                                    <value>#0</value>
                                </enumeratedValue>
                                <enumeratedValue>
                                    <name>1</name>
                                    <description>GTCCRB input capture enabled on the rising edge of GTIOCnB input when GTIOCnA input is 1</description>
                                    <value>#1</value>
                                </enumeratedValue>
                            </enumeratedValues>
                        </field>
                        <field>
                            <name>BSCBFAL</name>
                            <description>GTIOCnB Pin Falling Input during GTIOCnA Value Low Source GTCCRB Input Capture Enable</description>
                            <lsb>14</lsb>
                            <msb>14</msb>
                            <access>read-write</access>
                            <enumeratedValues>
                                <enumeratedValue>
                                    <name>0</name>
                                    <description>GTCCRB input capture disabled on the falling edge of GTIOCnB input when GTIOCnA input is 0</description>
                                    <value>#0</value>
                                </enumeratedValue>
                                <enumeratedValue>
                                    <name>1</name>
                                    <description>GTCCRB input capture enabled on the falling edge of GTIOCnB input when GTIOCnA input is 0</description>
                                    <value>#1</value>
                                </enumeratedValue>
                            </enumeratedValues>
                        </field>
                        <field>
                            <name>BSCBFAH</name>
                            <description>GTIOCnB Pin Falling Input during GTIOCnA Value High Source GTCCRB Input Capture Enable</description>
                            <lsb>15</lsb>
                            <msb>15</msb>
                            <access>read-write</access>
                            <enumeratedValues>
                                <enumeratedValue>
                                    <name>0</name>
                                    <description>GTCCRB input capture disabled on the falling edge of GTIOCnB input when GTIOCnA input is 1</description>
                                    <value>#0</value>
                                </enumeratedValue>
                                <enumeratedValue>
                                    <name>1</name>
                                    <description>GTCCRB input capture enabled on the falling edge of GTIOCnB input when GTIOCnA input is 1</description>
                                    <value>#1</value>
                                </enumeratedValue>
                            </enumeratedValues>
                        </field>
                        <field>
                            <name>BSELCA</name>
                            <description>ELC_GPTA Event Source GTCCRB Input Capture Enable</description>
                            <lsb>16</lsb>
                            <msb>16</msb>
                            <access>read-write</access>
                            <enumeratedValues>
                                <enumeratedValue>
                                    <name>0</name>
                                    <description>GTCCRB input capture disabled at the ELC_GPTA input</description>
                                    <value>#0</value>
                                </enumeratedValue>
                                <enumeratedValue>
                                    <name>1</name>
                                    <description>GTCCRB input capture enabled at the ELC_GPTA input</description>
                                    <value>#1</value>
                                </enumeratedValue>
                            </enumeratedValues>
                        </field>
                        <field>
                            <name>BSELCB</name>
                            <description>ELC_GPTB Event Source GTCCRB Input Capture Enable</description>
                            <lsb>17</lsb>
                            <msb>17</msb>
                            <access>read-write</access>
                            <enumeratedValues>
                                <enumeratedValue>
                                    <name>0</name>
                                    <description>GTCCRB input capture disabled at the ELC_GPTB input</description>
                                    <value>#0</value>
                                </enumeratedValue>
                                <enumeratedValue>
                                    <name>1</name>
                                    <description>GTCCRB input capture enabled at the ELC_GPTB input</description>
                                    <value>#1</value>
                                </enumeratedValue>
                            </enumeratedValues>
                        </field>
                        <field>
                            <name>BSELCC</name>
                            <description>ELC_GPTC Event Source GTCCRB Input Capture Enable</description>
                            <lsb>18</lsb>
                            <msb>18</msb>
                            <access>read-write</access>
                            <enumeratedValues>
                                <enumeratedValue>
                                    <name>0</name>
                                    <description>GTCCRB input capture disabled at the ELC_GPTC input</description>
                                    <value>#0</value>
                                </enumeratedValue>
                                <enumeratedValue>
                                    <name>1</name>
                                    <description>GTCCRB input capture enabled at the ELC_GPTC input</description>
                                    <value>#1</value>
                                </enumeratedValue>
                            </enumeratedValues>
                        </field>
                        <field>
                            <name>BSELCD</name>
                            <description>ELC_GPTD Event Source GTCCRB Input Capture Enable</description>
                            <lsb>19</lsb>
                            <msb>19</msb>
                            <access>read-write</access>
                            <enumeratedValues>
                                <enumeratedValue>
                                    <name>0</name>
                                    <description>GTCCRB input capture disabled at the ELC_GPTD input</description>
                                    <value>#0</value>
                                </enumeratedValue>
                                <enumeratedValue>
                                    <name>1</name>
                                    <description>GTCCRB input capture enabled at the ELC_GPTD input</description>
                                    <value>#1</value>
                                </enumeratedValue>
                            </enumeratedValues>
                        </field>
                        <field>
                            <name>BSELCE</name>
                            <description>ELC_GPTE Event Source GTCCRB Input Capture Enable</description>
                            <lsb>20</lsb>
                            <msb>20</msb>
                            <access>read-write</access>
                            <enumeratedValues>
                                <enumeratedValue>
                                    <name>0</name>
                                    <description>GTCCRB input capture disabled at the ELC_GPTE input</description>
                                    <value>#0</value>
                                </enumeratedValue>
                                <enumeratedValue>
                                    <name>1</name>
                                    <description>GTCCRB input capture enabled at the ELC_GPTE input</description>
                                    <value>#1</value>
                                </enumeratedValue>
                            </enumeratedValues>
                        </field>
                        <field>
                            <name>BSELCF</name>
                            <description>ELC_GPTF Event Source GTCCRB Input Capture Enable</description>
                            <lsb>21</lsb>
                            <msb>21</msb>
                            <access>read-write</access>
                            <enumeratedValues>
                                <enumeratedValue>
                                    <name>0</name>
                                    <description>GTCCRB input capture disabled at the ELC_GPTF input</description>
                                    <value>#0</value>
                                </enumeratedValue>
                                <enumeratedValue>
                                    <name>1</name>
                                    <description>GTCCRB input capture enabled at the ELC_GPTF input</description>
                                    <value>#1</value>
                                </enumeratedValue>
                            </enumeratedValues>
                        </field>
                        <field>
                            <name>BSELCG</name>
                            <description>ELC_GPTG Event Source GTCCRB Input Capture Enable</description>
                            <lsb>22</lsb>
                            <msb>22</msb>
                            <access>read-write</access>
                            <enumeratedValues>
                                <enumeratedValue>
                                    <name>0</name>
                                    <description>GTCCRB input capture disabled at the ELC_GPTG input</description>
                                    <value>#0</value>
                                </enumeratedValue>
                                <enumeratedValue>
                                    <name>1</name>
                                    <description>GTCCRB input capture enabled at the ELC_GPTG input</description>
                                    <value>#1</value>
                                </enumeratedValue>
                            </enumeratedValues>
                        </field>
                        <field>
                            <name>BSELCH</name>
                            <description>ELC_GPTH Event Source GTCCRB Input Capture Enable</description>
                            <lsb>23</lsb>
                            <msb>23</msb>
                            <access>read-write</access>
                            <enumeratedValues>
                                <enumeratedValue>
                                    <name>0</name>
                                    <description>GTCCRB input capture disabled at the ELC_GPTH input</description>
                                    <value>#0</value>
                                </enumeratedValue>
                                <enumeratedValue>
                                    <name>1</name>
                                    <description>GTCCRB input capture enabled at the ELC_GPTH input</description>
                                    <value>#1</value>
                                </enumeratedValue>
                            </enumeratedValues>
                        </field>
                    </fields>
                </register>
                <register>
                    <name>GTCR</name>
                    <description>General PWM Timer Control Register</description>
                    <addressOffset>0x2C</addressOffset>
                    <size>32</size>
                    <access>read-write</access>
                    <resetValue>0x00000000</resetValue>
                    <resetMask>0xffffffff</resetMask>
                    <fields>
                        <field>
                            <name>CST</name>
                            <description>Count Start</description>
                            <lsb>0</lsb>
                            <msb>0</msb>
                            <access>read-write</access>
                            <enumeratedValues>
                                <enumeratedValue>
                                    <name>0</name>
                                    <description>Count operation is stopped</description>
                                    <value>#0</value>
                                </enumeratedValue>
                                <enumeratedValue>
                                    <name>1</name>
                                    <description>Count operation is performed</description>
                                    <value>#1</value>
                                </enumeratedValue>
                            </enumeratedValues>
                        </field>
                        <field>
                            <name>MD</name>
                            <description>Mode Select</description>
                            <lsb>16</lsb>
                            <msb>18</msb>
                            <access>read-write</access>
                            <enumeratedValues>
                                <enumeratedValue>
                                    <name>000</name>
                                    <description>Saw-wave PWM mode (single buffer or double buffer possible)</description>
                                    <value>#000</value>
                                </enumeratedValue>
                                <enumeratedValue>
                                    <name>001</name>
                                    <description>Saw-wave one-shot pulse mode (fixed buffer operation)</description>
                                    <value>#001</value>
                                </enumeratedValue>
                                <enumeratedValue>
                                    <name>010</name>
                                    <description>Setting prohibited</description>
                                    <value>#010</value>
                                </enumeratedValue>
                                <enumeratedValue>
                                    <name>011</name>
                                    <description>Setting prohibited</description>
                                    <value>#011</value>
                                </enumeratedValue>
                                <enumeratedValue>
                                    <name>100</name>
                                    <description>Triangle-wave PWM mode 1 (32-bit transfer at trough) (single buffer or double buffer is possible)</description>
                                    <value>#100</value>
                                </enumeratedValue>
                                <enumeratedValue>
                                    <name>101</name>
                                    <description>Triangle-wave PWM mode 2 (32-bit transfer at crest and trough) (single buffer or double buffer is possible)</description>
                                    <value>#101</value>
                                </enumeratedValue>
                                <enumeratedValue>
                                    <name>110</name>
                                    <description>Triangle-wave PWM mode 3 (64-bit transfer at trough) (fixed buffer operation)</description>
                                    <value>#110</value>
                                </enumeratedValue>
                                <enumeratedValue>
                                    <name>111</name>
                                    <description>Setting prohibited</description>
                                    <value>#111</value>
                                </enumeratedValue>
                            </enumeratedValues>
                        </field>
                        <field>
                            <name>TPCS</name>
                            <description>Timer Prescaler Select</description>
                            <lsb>23</lsb>
                            <msb>26</msb>
                            <access>read-write</access>
                            <enumeratedValues>
                                <enumeratedValue>
                                    <name>0x0</name>
                                    <description>PCLKD/1 </description>
                                    <value>0x0</value>
                                </enumeratedValue>
                                <enumeratedValue>
                                    <name>0x1</name>
                                    <description>PCLKD/2 </description>
                                    <value>0x1</value>
                                </enumeratedValue>
                                <enumeratedValue>
                                    <name>0x2</name>
                                    <description>PCLKD/4 </description>
                                    <value>0x2</value>
                                </enumeratedValue>
                                <enumeratedValue>
                                    <name>0x3</name>
                                    <description>PCLKD/8 </description>
                                    <value>0x3</value>
                                </enumeratedValue>
                                <enumeratedValue>
                                    <name>0x4</name>
                                    <description>PCLKD/16 </description>
                                    <value>0x4</value>
                                </enumeratedValue>
                                <enumeratedValue>
                                    <name>0x5</name>
                                    <description>PCLKD/32 </description>
                                    <value>0x5</value>
                                </enumeratedValue>
                                <enumeratedValue>
                                    <name>0x6</name>
                                    <description>PCLKD/64 </description>
                                    <value>0x6</value>
                                </enumeratedValue>
                                <enumeratedValue>
                                    <name>0x7</name>
                                    <description>Setting prohibited</description>
                                    <value>0x7</value>
                                </enumeratedValue>
                                <enumeratedValue>
                                    <name>0x8</name>
                                    <description>PCLKD/256 </description>
                                    <value>0x8</value>
                                </enumeratedValue>
                                <enumeratedValue>
                                    <name>0x9</name>
                                    <description>Setting prohibited</description>
                                    <value>0x9</value>
                                </enumeratedValue>
                                <enumeratedValue>
                                    <name>0xA</name>
                                    <description>PCLKD/1024 </description>
                                    <value>0xa</value>
                                </enumeratedValue>
                                <enumeratedValue>
                                    <name>0xB</name>
                                    <description>Setting prohibited</description>
                                    <value>0xb</value>
                                </enumeratedValue>
                                <enumeratedValue>
                                    <name>0xC</name>
                                    <description>GTETRGA (Via the POEG)</description>
                                    <value>0xc</value>
                                </enumeratedValue>
                                <enumeratedValue>
                                    <name>0xD</name>
                                    <description>GTETRGB (Via the POEG)</description>
                                    <value>0xd</value>
                                </enumeratedValue>
                                <enumeratedValue>
                                    <name>0xE</name>
                                    <description>GTETRGC (Via the POEG)</description>
                                    <value>0xe</value>
                                </enumeratedValue>
                                <enumeratedValue>
                                    <name>0xF</name>
                                    <description>GTETRGD (Via the POEG)</description>
                                    <value>0xf</value>
                                </enumeratedValue>
                            </enumeratedValues>
                        </field>
                    </fields>
                </register>
                <register>
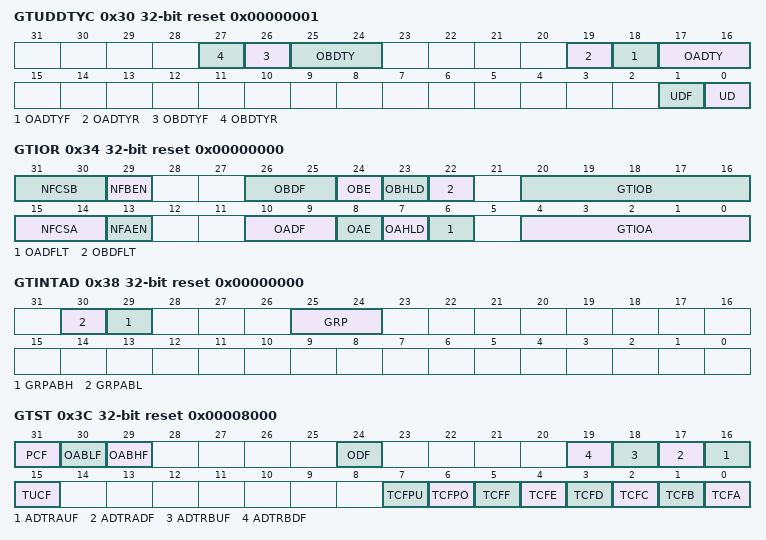
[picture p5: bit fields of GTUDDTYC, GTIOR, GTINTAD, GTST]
                    <name>GTUDDTYC</name>
                    <description>General PWM Timer Count Direction and Duty Setting Register</description>
                    <addressOffset>0x30</addressOffset>
                    <size>32</size>
                    <access>read-write</access>
                    <resetValue>0x00000001</resetValue>
                    <resetMask>0xffffffff</resetMask>
                    <fields>
                        <field>
                            <name>UD</name>
                            <description>Count Direction Setting</description>
                            <lsb>0</lsb>
                            <msb>0</msb>
                            <access>read-write</access>
                            <enumeratedValues>
                                <enumeratedValue>
                                    <name>0</name>
                                    <description>GTCNT counts down</description>
                                    <value>#0</value>
                                </enumeratedValue>
                                <enumeratedValue>
                                    <name>1</name>
                                    <description>GTCNT counts up</description>
                                    <value>#1</value>
                                </enumeratedValue>
                            </enumeratedValues>
                        </field>
                        <field>
                            <name>UDF</name>
                            <description>Forcible Count Direction Setting</description>
                            <lsb>1</lsb>
                            <msb>1</msb>
                            <access>read-write</access>
                            <enumeratedValues>
                                <enumeratedValue>
                                    <name>0</name>
                                    <description>Not forcibly set</description>
                                    <value>#0</value>
                                </enumeratedValue>
                                <enumeratedValue>
                                    <name>1</name>
                                    <description>Forcibly set</description>
                                    <value>#1</value>
                                </enumeratedValue>
                            </enumeratedValues>
                        </field>
                        <field>
                            <name>OADTY</name>
                            <description>GTIOCnA Output Duty Setting</description>
                            <lsb>16</lsb>
                            <msb>17</msb>
                            <access>read-write</access>
                            <enumeratedValues>
                                <enumeratedValue>
                                    <name>00</name>
                                    <description>GTIOCnA pin duty depends on the compare match</description>
                                    <value>#00</value>
                                </enumeratedValue>
                                <enumeratedValue>
                                    <name>01</name>
                                    <description>GTIOCnA pin duty depends on the compare match</description>
                                    <value>#01</value>
                                </enumeratedValue>
                                <enumeratedValue>
                                    <name>10</name>
                                    <description>GTIOCnA pin duty 0%</description>
                                    <value>#10</value>
                                </enumeratedValue>
                                <enumeratedValue>
                                    <name>11</name>
                                    <description>GTIOCnA pin duty 100%</description>
                                    <value>#11</value>
                                </enumeratedValue>
                            </enumeratedValues>
                        </field>
                        <field>
                            <name>OADTYF</name>
                            <description>Forcible GTIOCnA Output Duty Setting</description>
                            <lsb>18</lsb>
                            <msb>18</msb>
                            <access>read-write</access>
                            <enumeratedValues>
                                <enumeratedValue>
                                    <name>0</name>
                                    <description>Not forcibly set</description>
                                    <value>#0</value>
                                </enumeratedValue>
                                <enumeratedValue>
                                    <name>1</name>
                                    <description>Forcibly set</description>
                                    <value>#1</value>
                                </enumeratedValue>
                            </enumeratedValues>
                        </field>
                        <field>
                            <name>OADTYR</name>
                            <description>GTIOCnA Output Value Selecting after Releasing 0%/100% Duty Setting</description>
                            <lsb>19</lsb>
                            <msb>19</msb>
                            <access>read-write</access>
                            <enumeratedValues>
                                <enumeratedValue>
                                    <name>0</name>
                                    <description>The function selected by the GTIOA[3:2] bits is applied to the output value when the duty cycle is set after release from the 0 or 100% duty-cycle setting.</description>
                                    <value>#0</value>
                                </enumeratedValue>
                                <enumeratedValue>
                                    <name>1</name>
                                    <description>The function selected by the GTIOA[3:2] bits is applied to the compare match output value which is masked after release from the 0 or 100% duty-cycle setting.</description>
                                    <value>#1</value>
                                </enumeratedValue>
                            </enumeratedValues>
                        </field>
                        <field>
                            <name>OBDTY</name>
                            <description>GTIOCnB Output Duty Setting</description>
                            <lsb>24</lsb>
                            <msb>25</msb>
                            <access>read-write</access>
                            <enumeratedValues>
                                <enumeratedValue>
                                    <name>00</name>
                                    <description>GTIOCnB pin duty depends on the compare match</description>
                                    <value>#00</value>
                                </enumeratedValue>
                                <enumeratedValue>
                                    <name>01</name>
                                    <description>GTIOCnB pin duty depends on the compare match</description>
                                    <value>#01</value>
                                </enumeratedValue>
                                <enumeratedValue>
                                    <name>10</name>
                                    <description>GTIOCnB pin duty 0%</description>
                                    <value>#10</value>
                                </enumeratedValue>
                                <enumeratedValue>
                                    <name>11</name>
                                    <description>GTIOCnB pin duty 100%</description>
                                    <value>#11</value>
                                </enumeratedValue>
                            </enumeratedValues>
                        </field>
                        <field>
                            <name>OBDTYF</name>
                            <description>Forcible GTIOCnB Output Duty Setting</description>
                            <lsb>26</lsb>
                            <msb>26</msb>
                            <access>read-write</access>
                            <enumeratedValues>
                                <enumeratedValue>
                                    <name>0</name>
                                    <description>Not forcibly set</description>
                                    <value>#0</value>
                                </enumeratedValue>
                                <enumeratedValue>
                                    <name>1</name>
                                    <description>Forcibly set</description>
                                    <value>#1</value>
                                </enumeratedValue>
                            </enumeratedValues>
                        </field>
                        <field>
                            <name>OBDTYR</name>
                            <description>GTIOCnB Output Value Selecting after Releasing 0%/100% Duty Setting</description>
                            <lsb>27</lsb>
                            <msb>27</msb>
                            <access>read-write</access>
                            <enumeratedValues>
                                <enumeratedValue>
                                    <name>0</name>
                                    <description>The function selected by the GTIOB[3:2] bits is applied to the output value when the duty cycle is set after release from the 0 or 100% duty-cycle setting.</description>
                                    <value>#0</value>
                                </enumeratedValue>
                                <enumeratedValue>
                                    <name>1</name>
                                    <description>The function selected by the GTIOB[3:2] bits is applied to the compare match output value which is masked after release from the 0 or 100% duty-cycle setting.</description>
                                    <value>#1</value>
                                </enumeratedValue>
                            </enumeratedValues>
                        </field>
                    </fields>
                </register>
                <register>
                    <name>GTIOR</name>
                    <description>General PWM Timer I/O Control Register</description>
                    <addressOffset>0x34</addressOffset>
                    <size>32</size>
                    <access>read-write</access>
                    <resetValue>0x00000000</resetValue>
                    <resetMask>0xffffffff</resetMask>
                    <fields>
                        <field>
                            <name>GTIOA</name>
                            <description>GTIOCnA Pin Function Select</description>
                            <lsb>0</lsb>
                            <msb>4</msb>
                            <access>read-write</access>
                        </field>
                        <field>
                            <name>OADFLT</name>
                            <description>GTIOCnA Pin Output Value Setting at the Count Stop</description>
                            <lsb>6</lsb>
                            <msb>6</msb>
                            <access>read-write</access>
                            <enumeratedValues>
                                <enumeratedValue>
                                    <name>0</name>
                                    <description>The GTIOCnA pin outputs low when counting stops</description>
                                    <value>#0</value>
                                </enumeratedValue>
                                <enumeratedValue>
                                    <name>1</name>
                                    <description>The GTIOCnA pin outputs high when counting stops</description>
                                    <value>#1</value>
                                </enumeratedValue>
                            </enumeratedValues>
                        </field>
                        <field>
                            <name>OAHLD</name>
                            <description>GTIOCnA Pin Output Setting at the Start/Stop Count</description>
                            <lsb>7</lsb>
                            <msb>7</msb>
                            <access>read-write</access>
                            <enumeratedValues>
                                <enumeratedValue>
                                    <name>0</name>
                                    <description>The GTIOCnA pin output level at the start or stop of counting depends on the register setting</description>
                                    <value>#0</value>
                                </enumeratedValue>
                                <enumeratedValue>
                                    <name>1</name>
                                    <description>The GTIOCnA pin output level is retained at the start or stop of counting</description>
                                    <value>#1</value>
                                </enumeratedValue>
                            </enumeratedValues>
                        </field>
                        <field>
                            <name>OAE</name>
                            <description>GTIOCnA Pin Output Enable</description>
                            <lsb>8</lsb>
                            <msb>8</msb>
                            <access>read-write</access>
                            <enumeratedValues>
                                <enumeratedValue>
                                    <name>0</name>
                                    <description>Output is disabled</description>
                                    <value>#0</value>
                                </enumeratedValue>
                                <enumeratedValue>
                                    <name>1</name>
                                    <description>Output is enabled</description>
                                    <value>#1</value>
                                </enumeratedValue>
                            </enumeratedValues>
                        </field>
                        <field>
                            <name>OADF</name>
                            <description>GTIOCnA Pin Disable Value Setting</description>
                            <lsb>9</lsb>
                            <msb>10</msb>
                            <access>read-write</access>
                            <enumeratedValues>
                                <enumeratedValue>
                                    <name>00</name>
                                    <description>None of the below options are specified</description>
                                    <value>#00</value>
                                </enumeratedValue>
                                <enumeratedValue>
                                    <name>01</name>
                                    <description>GTIOCnA pin is set to Hi-Z in response to controlling the output negation</description>
                                    <value>#01</value>
                                </enumeratedValue>
                                <enumeratedValue>
                                    <name>10</name>
                                    <description>GTIOCnA pin is set to 0 in response to controlling the output negation</description>
                                    <value>#10</value>
                                </enumeratedValue>
                                <enumeratedValue>
                                    <name>11</name>
                                    <description>GTIOCnA pin is set to 1 in response to controlling the output negation</description>
                                    <value>#11</value>
                                </enumeratedValue>
                            </enumeratedValues>
                        </field>
                        <field>
                            <name>NFAEN</name>
                            <description>Noise Filter A Enable</description>
                            <lsb>13</lsb>
                            <msb>13</msb>
                            <access>read-write</access>
                            <enumeratedValues>
                                <enumeratedValue>
                                    <name>0</name>
                                    <description>The noise filter for the GTIOCnA pin is disabled</description>
                                    <value>#0</value>
                                </enumeratedValue>
                                <enumeratedValue>
                                    <name>1</name>
                                    <description>The noise filter for the GTIOCnA pin is enabled</description>
                                    <value>#1</value>
                                </enumeratedValue>
                            </enumeratedValues>
                        </field>
                        <field>
                            <name>NFCSA</name>
                            <description>Noise Filter A Sampling Clock Select</description>
                            <lsb>14</lsb>
                            <msb>15</msb>
                            <access>read-write</access>
                            <enumeratedValues>
                                <enumeratedValue>
                                    <name>00</name>
                                    <description>PCLKD/1</description>
                                    <value>#00</value>
                                </enumeratedValue>
                                <enumeratedValue>
                                    <name>01</name>
                                    <description>PCLKD/4</description>
                                    <value>#01</value>
                                </enumeratedValue>
                                <enumeratedValue>
                                    <name>10</name>
                                    <description>PCLKD/16</description>
                                    <value>#10</value>
                                </enumeratedValue>
                                <enumeratedValue>
                                    <name>11</name>
                                    <description>PCLKD/64</description>
                                    <value>#11</value>
                                </enumeratedValue>
                            </enumeratedValues>
                        </field>
                        <field>
                            <name>GTIOB</name>
                            <description>GTIOCnB Pin Function Select</description>
                            <lsb>16</lsb>
                            <msb>20</msb>
                            <access>read-write</access>
                        </field>
                        <field>
                            <name>OBDFLT</name>
                            <description>GTIOCnB Pin Output Value Setting at the Count Stop</description>
                            <lsb>22</lsb>
                            <msb>22</msb>
                            <access>read-write</access>
                            <enumeratedValues>
                                <enumeratedValue>
                                    <name>0</name>
                                    <description>The GTIOCnB pin outputs low when counting stops</description>
                                    <value>#0</value>
                                </enumeratedValue>
                                <enumeratedValue>
                                    <name>1</name>
                                    <description>The GTIOCnB pin outputs high when counting stops</description>
                                    <value>#1</value>
                                </enumeratedValue>
                            </enumeratedValues>
                        </field>
                        <field>
                            <name>OBHLD</name>
                            <description>GTIOCnB Pin Output Setting at the Start/Stop Count</description>
                            <lsb>23</lsb>
                            <msb>23</msb>
                            <access>read-write</access>
                            <enumeratedValues>
                                <enumeratedValue>
                                    <name>0</name>
                                    <description>The GTIOCnB pin output level at the start/stop of counting depends on the register setting</description>
                                    <value>#0</value>
                                </enumeratedValue>
                                <enumeratedValue>
                                    <name>1</name>
                                    <description>The GTIOCnB pin output level is retained at the start/stop of counting</description>
                                    <value>#1</value>
                                </enumeratedValue>
                            </enumeratedValues>
                        </field>
                        <field>
                            <name>OBE</name>
                            <description>GTIOCnB Pin Output Enable</description>
                            <lsb>24</lsb>
                            <msb>24</msb>
                            <access>read-write</access>
                            <enumeratedValues>
                                <enumeratedValue>
                                    <name>0</name>
                                    <description>Output is disabled</description>
                                    <value>#0</value>
                                </enumeratedValue>
                                <enumeratedValue>
                                    <name>1</name>
                                    <description>Output is enabled</description>
                                    <value>#1</value>
                                </enumeratedValue>
                            </enumeratedValues>
                        </field>
                        <field>
                            <name>OBDF</name>
                            <description>GTIOCnB Pin Disable Value Setting</description>
                            <lsb>25</lsb>
                            <msb>26</msb>
                            <access>read-write</access>
                            <enumeratedValues>
                                <enumeratedValue>
                                    <name>00</name>
                                    <description>None of the below options are specified</description>
                                    <value>#00</value>
                                </enumeratedValue>
                                <enumeratedValue>
                                    <name>01</name>
                                    <description>GTIOCnB pin is set to Hi-Z in response to controlling the output negation</description>
                                    <value>#01</value>
                                </enumeratedValue>
                                <enumeratedValue>
                                    <name>10</name>
                                    <description>GTIOCnB pin is set to 0 in response to controlling the output negation</description>
                                    <value>#10</value>
                                </enumeratedValue>
                                <enumeratedValue>
                                    <name>11</name>
                                    <description>GTIOCnB pin is set to 1 in response to controlling the output negation</description>
                                    <value>#11</value>
                                </enumeratedValue>
                            </enumeratedValues>
                        </field>
                        <field>
                            <name>NFBEN</name>
                            <description>Noise Filter B Enable</description>
                            <lsb>29</lsb>
                            <msb>29</msb>
                            <access>read-write</access>
                            <enumeratedValues>
                                <enumeratedValue>
                                    <name>0</name>
                                    <description>The noise filter for the GTIOCnB pin is disabled</description>
                                    <value>#0</value>
                                </enumeratedValue>
                                <enumeratedValue>
                                    <name>1</name>
                                    <description>The noise filter for the GTIOCnB pin is enabled</description>
                                    <value>#1</value>
                                </enumeratedValue>
                            </enumeratedValues>
                        </field>
                        <field>
                            <name>NFCSB</name>
                            <description>Noise Filter B Sampling Clock Select</description>
                            <lsb>30</lsb>
                            <msb>31</msb>
                            <access>read-write</access>
                            <enumeratedValues>
                                <enumeratedValue>
                                    <name>00</name>
                                    <description>PCLKD/1</description>
                                    <value>#00</value>
                                </enumeratedValue>
                                <enumeratedValue>
                                    <name>01</name>
                                    <description>PCLKD/4</description>
                                    <value>#01</value>
                                </enumeratedValue>
                                <enumeratedValue>
                                    <name>10</name>
                                    <description>PCLKD/16</description>
                                    <value>#10</value>
                                </enumeratedValue>
                                <enumeratedValue>
                                    <name>11</name>
                                    <description>PCLKD/64</description>
                                    <value>#11</value>
                                </enumeratedValue>
                            </enumeratedValues>
                        </field>
                    </fields>
                </register>
                <register>
                    <name>GTINTAD</name>
                    <description>General PWM Timer Interrupt Output Setting Register</description>
                    <addressOffset>0x38</addressOffset>
                    <size>32</size>
                    <access>read-write</access>
                    <resetValue>0x00000000</resetValue>
                    <resetMask>0xffffffff</resetMask>
                    <fields>
                        <field>
                            <name>GRP</name>
                            <description>Output Disable Source Select</description>
                            <lsb>24</lsb>
                            <msb>25</msb>
                            <access>read-write</access>
                            <enumeratedValues>
                                <enumeratedValue>
                                    <name>00</name>
                                    <description>Group A output disable request is selected</description>
                                    <value>#00</value>
                                </enumeratedValue>
                                <enumeratedValue>
                                    <name>01</name>
                                    <description>Group B output disable request is selected</description>
                                    <value>#01</value>
                                </enumeratedValue>
                                <enumeratedValue>
                                    <name>10</name>
                                    <description>Group C output disable request is selected</description>
                                    <value>#10</value>
                                </enumeratedValue>
                                <enumeratedValue>
                                    <name>11</name>
                                    <description>Group D output disable request is selected</description>
                                    <value>#11</value>
                                </enumeratedValue>
                            </enumeratedValues>
                        </field>
                        <field>
                            <name>GRPABH</name>
                            <description>Same Time Output Level High Disable Request Enable</description>
                            <lsb>29</lsb>
                            <msb>29</msb>
                            <access>read-write</access>
                            <enumeratedValues>
                                <enumeratedValue>
                                    <name>0</name>
                                    <description>Same time output level high disable request disabled</description>
                                    <value>#0</value>
                                </enumeratedValue>
                                <enumeratedValue>
                                    <name>1</name>
                                    <description>Same time output level high disable request enabled</description>
                                    <value>#1</value>
                                </enumeratedValue>
                            </enumeratedValues>
                        </field>
                        <field>
                            <name>GRPABL</name>
                            <description>Same Time Output Level Low Disable Request Enable</description>
                            <lsb>30</lsb>
                            <msb>30</msb>
                            <access>read-write</access>
                            <enumeratedValues>
                                <enumeratedValue>
                                    <name>0</name>
                                    <description>Same time output level low disable request disabled</description>
                                    <value>#0</value>
                                </enumeratedValue>
                                <enumeratedValue>
                                    <name>1</name>
                                    <description>Same time output level low disable request enabled</description>
                                    <value>#1</value>
                                </enumeratedValue>
                            </enumeratedValues>
                        </field>
                    </fields>
                </register>
                <register>
                    <name>GTST</name>
                    <description>General PWM Timer Status Register</description>
                    <addressOffset>0x3C</addressOffset>
                    <size>32</size>
                    <access>read-write</access>
                    <resetValue>0x00008000</resetValue>
                    <resetMask>0xffffffff</resetMask>
                    <fields>
                        <field>
                            <name>TCFA</name>
                            <description>Input Capture/Compare Match Flag A</description>
                            <lsb>0</lsb>
                            <msb>0</msb>
                            <access>read-write</access>
                            <enumeratedValues>
                                <enumeratedValue>
                                    <name>0</name>
                                    <description>No input capture/compare match of GTCCRA is generated</description>
                                    <value>#0</value>
                                </enumeratedValue>
                                <enumeratedValue>
                                    <name>1</name>
                                    <description>An input capture/compare match of GTCCRA is generated</description>
                                    <value>#1</value>
                                </enumeratedValue>
                            </enumeratedValues>
                        </field>
                        <field>
                            <name>TCFB</name>
                            <description>Input Capture/Compare Match Flag B</description>
                            <lsb>1</lsb>
                            <msb>1</msb>
                            <access>read-write</access>
                            <enumeratedValues>
                                <enumeratedValue>
                                    <name>0</name>
                                    <description>No input capture/compare match of GTCCRB is generated</description>
                                    <value>#0</value>
                                </enumeratedValue>
                                <enumeratedValue>
                                    <name>1</name>
                                    <description>An input capture/compare match of GTCCRB is generated</description>
                                    <value>#1</value>
                                </enumeratedValue>
                            </enumeratedValues>
                        </field>
                        <field>
                            <name>TCFC</name>
                            <description>Input Compare Match Flag C</description>
                            <lsb>2</lsb>
                            <msb>2</msb>
                            <access>read-write</access>
                            <enumeratedValues>
                                <enumeratedValue>
                                    <name>0</name>
                                    <description>No compare match of GTCCRC is generated</description>
                                    <value>#0</value>
                                </enumeratedValue>
                                <enumeratedValue>
                                    <name>1</name>
                                    <description>A compare match of GTCCRC is generated</description>
                                    <value>#1</value>
                                </enumeratedValue>
                            </enumeratedValues>
                        </field>
                        <field>
                            <name>TCFD</name>
                            <description>Input Compare Match Flag D</description>
                            <lsb>3</lsb>
                            <msb>3</msb>
                            <access>read-write</access>
                            <enumeratedValues>
                                <enumeratedValue>
                                    <name>0</name>
                                    <description>No compare match of GTCCRD is generated</description>
                                    <value>#0</value>
                                </enumeratedValue>
                                <enumeratedValue>
                                    <name>1</name>
                                    <description>A compare match of GTCCRD is generated</description>
                                    <value>#1</value>
                                </enumeratedValue>
                            </enumeratedValues>
                        </field>
                        <field>
                            <name>TCFE</name>
                            <description>Input Compare Match Flag E</description>
                            <lsb>4</lsb>
                            <msb>4</msb>
                            <access>read-write</access>
                            <enumeratedValues>
                                <enumeratedValue>
                                    <name>0</name>
                                    <description>No compare match of GTCCRE is generated</description>
                                    <value>#0</value>
                                </enumeratedValue>
                                <enumeratedValue>
                                    <name>1</name>
                                    <description>A compare match of GTCCRE is generated</description>
                                    <value>#1</value>
                                </enumeratedValue>
                            </enumeratedValues>
                        </field>
                        <field>
                            <name>TCFF</name>
                            <description>Input Compare Match Flag F</description>
                            <lsb>5</lsb>
                            <msb>5</msb>
                            <access>read-write</access>
                            <enumeratedValues>
                                <enumeratedValue>
                                    <name>0</name>
                                    <description>No compare match of GTCCRF is generated</description>
                                    <value>#0</value>
                                </enumeratedValue>
                                <enumeratedValue>
                                    <name>1</name>
                                    <description>A compare match of GTCCRF is generated</description>
                                    <value>#1</value>
                                </enumeratedValue>
                            </enumeratedValues>
                        </field>
                        <field>
                            <name>TCFPO</name>
                            <description>Overflow Flag</description>
                            <lsb>6</lsb>
                            <msb>6</msb>
                            <access>read-write</access>
                            <enumeratedValues>
                                <enumeratedValue>
                                    <name>0</name>
                                    <description>No overflow (crest) occurred</description>
                                    <value>#0</value>
                                </enumeratedValue>
                                <enumeratedValue>
                                    <name>1</name>
                                    <description>An overflow (crest) occurred</description>
                                    <value>#1</value>
                                </enumeratedValue>
                            </enumeratedValues>
                        </field>
                        <field>
                            <name>TCFPU</name>
                            <description>Underflow Flag</description>
                            <lsb>7</lsb>
                            <msb>7</msb>
                            <access>read-write</access>
                            <enumeratedValues>
                                <enumeratedValue>
                                    <name>0</name>
                                    <description>No underflow (trough) occurred</description>
                                    <value>#0</value>
                                </enumeratedValue>
                                <enumeratedValue>
                                    <name>1</name>
                                    <description>An underflow (trough) occurred</description>
                                    <value>#1</value>
                                </enumeratedValue>
                            </enumeratedValues>
                        </field>
                        <field>
                            <name>TUCF</name>
                            <description>Count Direction Flag</description>
                            <lsb>15</lsb>
                            <msb>15</msb>
                            <access>read-only</access>
                            <enumeratedValues>
                                <enumeratedValue>
                                    <name>0</name>
                                    <description>GTCNT counter counts downward</description>
                                    <value>#0</value>
                                </enumeratedValue>
                                <enumeratedValue>
                                    <name>1</name>
                                    <description>GTCNT counter counts upward</description>
                                    <value>#1</value>
                                </enumeratedValue>
                            </enumeratedValues>
                        </field>
                        <field>
                            <name>ADTRAUF</name>
                            <description>GTADTRA Register Compare Match (Up-Counting) A/D Conversion Start Request Flag</description>
                            <lsb>16</lsb>
                            <msb>16</msb>
                            <access>read-write</access>
                            <enumeratedValues>
                                <enumeratedValue>
                                    <name>0</name>
                                    <description>No GTADTRA register compare match has occurred in up-counting.</description>
                                    <value>#0</value>
                                </enumeratedValue>
                                <enumeratedValue>
                                    <name>1</name>
                                    <description>A GTADTRA register compare match has occurred in up-counting.</description>
                                    <value>#1</value>
                                </enumeratedValue>
                            </enumeratedValues>
                        </field>
                        <field>
                            <name>ADTRADF</name>
                            <description>GTADTRA Register Compare Match (Down-Counting) A/D Conversion Start Request Flag</description>
                            <lsb>17</lsb>
                            <msb>17</msb>
                            <access>read-write</access>
                            <enumeratedValues>
                                <enumeratedValue>
                                    <name>0</name>
                                    <description>No GTADTRA register compare match has occurred in down-counting.</description>
                                    <value>#0</value>
                                </enumeratedValue>
                                <enumeratedValue>
                                    <name>1</name>
                                    <description>A GTADTRA register compare match has occurred in down-counting.</description>
                                    <value>#1</value>
                                </enumeratedValue>
                            </enumeratedValues>
                        </field>
                        <field>
                            <name>ADTRBUF</name>
                            <description>GTADTRB Register Compare Match (Up-Counting) A/D Conversion Start Request Flag</description>
                            <lsb>18</lsb>
                            <msb>18</msb>
                            <access>read-write</access>
                            <enumeratedValues>
                                <enumeratedValue>
                                    <name>0</name>
                                    <description>No GTADTRB register compare match has occurred in up-counting.</description>
                                    <value>#0</value>
                                </enumeratedValue>
                                <enumeratedValue>
                                    <name>1</name>
                                    <description>A GTADTRB register compare match has occurred in up-counting.</description>
                                    <value>#1</value>
                                </enumeratedValue>
                            </enumeratedValues>
                        </field>
                        <field>
                            <name>ADTRBDF</name>
                            <description>GTADTRB Register Compare Match (Down-Counting) A/D Conversion Start Request Flag</description>
                            <lsb>19</lsb>
                            <msb>19</msb>
                            <access>read-write</access>
                            <enumeratedValues>
                                <enumeratedValue>
                                    <name>0</name>
                                    <description>No GTADTRB register compare match has occurred in down-counting.</description>
                                    <value>#0</value>
                                </enumeratedValue>
                                <enumeratedValue>
                                    <name>1</name>
                                    <description>A GTADTRB register compare match has occurred in down-counting.</description>
                                    <value>#1</value>
                                </enumeratedValue>
                            </enumeratedValues>
                        </field>
                        <field>
                            <name>ODF</name>
                            <description>Output Disable Flag</description>
                            <lsb>24</lsb>
                            <msb>24</msb>
                            <access>read-only</access>
                            <enumeratedValues>
                                <enumeratedValue>
                                    <name>0</name>
                                    <description>No output disable request is generated</description>
                                    <value>#0</value>
                                </enumeratedValue>
                                <enumeratedValue>
                                    <name>1</name>
                                    <description>An output disable request is generated</description>
                                    <value>#1</value>
                                </enumeratedValue>
                            </enumeratedValues>
                        </field>
                        <field>
                            <name>OABHF</name>
                            <description>Same Time Output Level High Flag</description>
                            <lsb>29</lsb>
                            <msb>29</msb>
                            <access>read-only</access>
                            <enumeratedValues>
                                <enumeratedValue>
                                    <name>0</name>
                                    <description>No simultaneous generation of 1 both for the GTIOCA and GTIOCB pins has occurred.</description>
                                    <value>#0</value>
                                </enumeratedValue>
                                <enumeratedValue>
                                    <name>1</name>
                                    <description>A simultaneous generation of 1 both for the GTIOCA and GTIOCB pins has occurred.</description>
                                    <value>#1</value>
                                </enumeratedValue>
                            </enumeratedValues>
                        </field>
                        <field>
                            <name>OABLF</name>
                            <description>Same Time Output Level Low Flag</description>
                            <lsb>30</lsb>
                            <msb>30</msb>
                            <access>read-only</access>
                            <enumeratedValues>
                                <enumeratedValue>
                                    <name>0</name>
                                    <description>No simultaneous generation of 0 both for the GTIOCA and GTIOCB pins has occurred.</description>
                                    <value>#0</value>
                                </enumeratedValue>
                                <enumeratedValue>
                                    <name>1</name>
                                    <description>A simultaneous generation of 0 both for the GTIOCA and GTIOCB pins has occurred.</description>
                                    <value>#1</value>
                                </enumeratedValue>
                            </enumeratedValues>
                        </field>
                        <field>
                            <name>PCF</name>
                            <description>Period Count Function Finish Flag</description>
                            <lsb>31</lsb>
                            <msb>31</msb>
                            <access>read-write</access>
                            <enumeratedValues>
                                <enumeratedValue>
                                    <name>0</name>
                                    <description>No period count function finish has occurred</description>
                                    <value>#0</value>
                                </enumeratedValue>
                                <enumeratedValue>
                                    <name>1</name>
                                    <description>A period count function finish has occurred</description>
                                    <value>#1</value>
                                </enumeratedValue>
                            </enumeratedValues>
                        </field>
                    </fields>
                </register>
                <register>
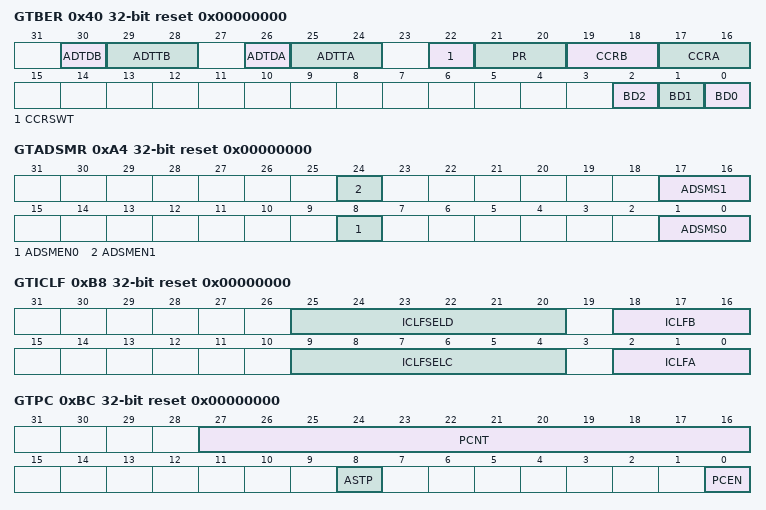
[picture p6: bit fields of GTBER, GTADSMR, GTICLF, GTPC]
                    <name>GTBER</name>
                    <description>General PWM Timer Buffer Enable Register</description>
                    <addressOffset>0x40</addressOffset>
                    <size>32</size>
                    <access>read-write</access>
                    <resetValue>0x00000000</resetValue>
                    <resetMask>0xffffffff</resetMask>
                    <fields>
                        <field>
                            <name>BD0</name>
                            <description>GTCCR Buffer Operation Disable</description>
                            <lsb>0</lsb>
                            <msb>0</msb>
                            <access>read-write</access>
                            <enumeratedValues>
                                <enumeratedValue>
                                    <name>0</name>
                                    <description>Buffer operation is enabled</description>
                                    <value>#0</value>
                                </enumeratedValue>
                                <enumeratedValue>
                                    <name>1</name>
                                    <description>Buffer operation is disabled</description>
                                    <value>#1</value>
                                </enumeratedValue>
                            </enumeratedValues>
                        </field>
                        <field>
                            <name>BD1</name>
                            <description>GTPR Buffer Operation Disable</description>
                            <lsb>1</lsb>
                            <msb>1</msb>
                            <access>read-write</access>
                            <enumeratedValues>
                                <enumeratedValue>
                                    <name>0</name>
                                    <description>Buffer operation is enabled</description>
                                    <value>#0</value>
                                </enumeratedValue>
                                <enumeratedValue>
                                    <name>1</name>
                                    <description>Buffer operation is disabled</description>
                                    <value>#1</value>
                                </enumeratedValue>
                            </enumeratedValues>
                        </field>
                        <field>
                            <name>BD2</name>
                            <description>GTADTRA/GTADTRB Registers Buffer Operation Disable</description>
                            <lsb>2</lsb>
                            <msb>2</msb>
                            <access>read-write</access>
                            <enumeratedValues>
                                <enumeratedValue>
                                    <name>0</name>
                                    <description>Buffer operation is enabled</description>
                                    <value>#0</value>
                                </enumeratedValue>
                                <enumeratedValue>
                                    <name>1</name>
                                    <description>Buffer operation is disabled</description>
                                    <value>#1</value>
                                </enumeratedValue>
                            </enumeratedValues>
                        </field>
                        <field>
                            <name>CCRA</name>
                            <description>GTCCRA Buffer Operation</description>
                            <lsb>16</lsb>
                            <msb>17</msb>
                            <access>read-write</access>
                            <enumeratedValues>
                                <enumeratedValue>
                                    <name>00</name>
                                    <description>No buffer operation</description>
                                    <value>#00</value>
                                </enumeratedValue>
                                <enumeratedValue>
                                    <name>01</name>
                                    <description>Single buffer operation (GTCCRA &lt;----&gt;GTCCRC)</description>
                                    <value>#01</value>
                                </enumeratedValue>
                                <enumeratedValue>
                                    <name>Others</name>
                                    <description>Double buffer operation (GTCCRA &lt;----&gt; GTCCRC &lt;----&gt; GTCCRD)</description>
                                    <isDefault>true</isDefault>
                                </enumeratedValue>
                            </enumeratedValues>
                        </field>
                        <field>
                            <name>CCRB</name>
                            <description>GTCCRB Buffer Operation</description>
                            <lsb>18</lsb>
                            <msb>19</msb>
                            <access>read-write</access>
                            <enumeratedValues>
                                <enumeratedValue>
                                    <name>00</name>
                                    <description>No buffer operation</description>
                                    <value>#00</value>
                                </enumeratedValue>
                                <enumeratedValue>
                                    <name>01</name>
                                    <description>Single buffer operation (GTCCRB &lt;----&gt; GTCCRE)</description>
                                    <value>#01</value>
                                </enumeratedValue>
                                <enumeratedValue>
                                    <name>Others</name>
                                    <description>Double buffer operation (GTCCRB &lt;----&gt; GTCCRE &lt;----&gt; GTCCRF)</description>
                                    <isDefault>true</isDefault>
                                </enumeratedValue>
                            </enumeratedValues>
                        </field>
                        <field>
                            <name>PR</name>
                            <description>GTPR Buffer Operation</description>
                            <lsb>20</lsb>
                            <msb>21</msb>
                            <access>read-write</access>
                            <enumeratedValues>
                                <enumeratedValue>
                                    <name>00</name>
                                    <description>No buffer operation</description>
                                    <value>#00</value>
                                </enumeratedValue>
                                <enumeratedValue>
                                    <name>01</name>
                                    <description>Single buffer operation (GTPBR --&gt; GTPR)</description>
                                    <value>#01</value>
                                </enumeratedValue>
                                <enumeratedValue>
                                    <name>Others</name>
                                    <description>Setting prohibited</description>
                                    <isDefault>true</isDefault>
                                </enumeratedValue>
                            </enumeratedValues>
                        </field>
                        <field>
                            <name>CCRSWT</name>
                            <description>GTCCRA and GTCCRB Forcible Buffer Operation</description>
                            <lsb>22</lsb>
                            <msb>22</msb>
                            <access>write-only</access>
                        </field>
                        <field>
                            <name>ADTTA</name>
                            <description>GTADTRA Register Buffer Transfer Timing Select</description>
                            <lsb>24</lsb>
                            <msb>25</msb>
                            <access>read-write</access>
                            <enumeratedValues>
                                <enumeratedValue>
                                    <name>00</name>
                                    <description>In triangle wave mode, no transfer. In saw-wave mode, no transfer. </description>
                                    <value>#00</value>
                                </enumeratedValue>
                                <enumeratedValue>
                                    <name>01</name>
                                    <description>In triangle wave mode, transfer at crest. In saw-wave mode, transfer at underflow (in down-counting), overflow (in up-counting), or counter clearing. </description>
                                    <value>#01</value>
                                </enumeratedValue>
                                <enumeratedValue>
                                    <name>10</name>
                                    <description>In triangle wave mode, transfer at trough. In saw-wave mode, transfer at underflow (in down-counting), overflow (in up-counting), or counter clearing. </description>
                                    <value>#10</value>
                                </enumeratedValue>
                                <enumeratedValue>
                                    <name>11</name>
                                    <description>In triangle wave, transfer at both crest and trough. In saw-wave mode, transfer at underflow (in down-counting), overflow (in up-counting), or counter clearing. </description>
                                    <value>#11</value>
                                </enumeratedValue>
                            </enumeratedValues>
                        </field>
                        <field>
                            <name>ADTDA</name>
                            <description>GTADTRA Register Double Buffer Operation</description>
                            <lsb>26</lsb>
                            <msb>26</msb>
                            <access>read-write</access>
                            <enumeratedValues>
                                <enumeratedValue>
                                    <name>0</name>
                                    <description>Single buffer operation (GTADTBRA --&gt; GTADTRA)</description>
                                    <value>#0</value>
                                </enumeratedValue>
                                <enumeratedValue>
                                    <name>1</name>
                                    <description>Double buffer operation (GTADTDBRA --&gt; GTADTBRA --&gt; GTADTRA)</description>
                                    <value>#1</value>
                                </enumeratedValue>
                            </enumeratedValues>
                        </field>
                        <field>
                            <name>ADTTB</name>
                            <description>GTADTRB Register Buffer Transfer Timing Select</description>
                            <lsb>28</lsb>
                            <msb>29</msb>
                            <access>read-write</access>
                            <enumeratedValues>
                                <enumeratedValue>
                                    <name>00</name>
                                    <description>In triangle wave mode, no transfer. In saw-wave mode, no transfer. </description>
                                    <value>#00</value>
                                </enumeratedValue>
                                <enumeratedValue>
                                    <name>01</name>
                                    <description>In triangle wave mode, transfer at crest. In saw-wave mode, transfer at underflow (in down-counting), overflow (in up-counting), or counter clearing. </description>
                                    <value>#01</value>
                                </enumeratedValue>
                                <enumeratedValue>
                                    <name>10</name>
                                    <description>In triangle wave mode, transfer at trough. In saw-wave mode, transfer at underflow (in down-counting), overflow (in up-counting), or counter clearing. </description>
                                    <value>#10</value>
                                </enumeratedValue>
                                <enumeratedValue>
                                    <name>11</name>
                                    <description>In triangle wave mode, transfer at both crest and trough. In saw-wave mode, transfer at underflow (in down-counting), overflow (in up-counting), or counter clearing. </description>
                                    <value>#11</value>
                                </enumeratedValue>
                            </enumeratedValues>
                        </field>
                        <field>
                            <name>ADTDB</name>
                            <description>GTADTRB Register Double Buffer Operation</description>
                            <lsb>30</lsb>
                            <msb>30</msb>
                            <access>read-write</access>
                            <enumeratedValues>
                                <enumeratedValue>
                                    <name>0</name>
                                    <description>Single buffer operation (GTADTBRB --&gt; GTADTRB)</description>
                                    <value>#0</value>
                                </enumeratedValue>
                                <enumeratedValue>
                                    <name>1</name>
                                    <description>Double buffer operation (GTADTDBRB --&gt; GTADTBRB --&gt; GTADTRB)</description>
                                    <value>#1</value>
                                </enumeratedValue>
                            </enumeratedValues>
                        </field>
                    </fields>
                </register>
                <register>
                    <name>GTCNT</name>
                    <description>General PWM Timer Counter</description>
                    <addressOffset>0x48</addressOffset>
                    <size>32</size>
                    <access>read-write</access>
                    <resetValue>0x00000000</resetValue>
                    <resetMask>0xffffffff</resetMask>
                </register>
                <register>
                    <name>GTCCRA</name>
                    <description>General PWM Timer Compare Capture Register A</description>
                    <addressOffset>0x4C</addressOffset>
                    <size>32</size>
                    <access>read-write</access>
                    <resetValue>0xffffffff</resetValue>
                    <resetMask>0xffffffff</resetMask>
                </register>
                <register>
                    <name>GTCCRB</name>
                    <description>General PWM Timer Compare Capture Register B</description>
                    <addressOffset>0x50</addressOffset>
                    <size>32</size>
                    <access>read-write</access>
                    <resetValue>0xffffffff</resetValue>
                    <resetMask>0xffffffff</resetMask>
                </register>
                <register>
                    <name>GTCCRC</name>
                    <description>General PWM Timer Compare Capture Register C</description>
                    <addressOffset>0x54</addressOffset>
                    <size>32</size>
                    <access>read-write</access>
                    <resetValue>0xffffffff</resetValue>
                    <resetMask>0xffffffff</resetMask>
                </register>
                <register>
                    <name>GTCCRE</name>
                    <description>General PWM Timer Compare Capture Register E</description>
                    <addressOffset>0x58</addressOffset>
                    <size>32</size>
                    <access>read-write</access>
                    <resetValue>0xffffffff</resetValue>
                    <resetMask>0xffffffff</resetMask>
                </register>
                <register>
                    <name>GTCCRD</name>
                    <description>General PWM Timer Compare Capture Register D</description>
                    <addressOffset>0x5C</addressOffset>
                    <size>32</size>
                    <access>read-write</access>
                    <resetValue>0xffffffff</resetValue>
                    <resetMask>0xffffffff</resetMask>
                </register>
                <register>
                    <name>GTCCRF</name>
                    <description>General PWM Timer Compare Capture Register F</description>
                    <addressOffset>0x60</addressOffset>
                    <size>32</size>
                    <access>read-write</access>
                    <resetValue>0xffffffff</resetValue>
                    <resetMask>0xffffffff</resetMask>
                </register>
                <register>
                    <name>GTPR</name>
                    <description>General PWM Timer Cycle Setting Register</description>
                    <addressOffset>0x64</addressOffset>
                    <size>32</size>
                    <access>read-write</access>
                    <resetValue>0xffffffff</resetValue>
                    <resetMask>0xffffffff</resetMask>
                </register>
                <register>
                    <name>GTPBR</name>
                    <description>General PWM Timer Cycle Setting Buffer Register</description>
                    <addressOffset>0x68</addressOffset>
                    <size>32</size>
                    <access>read-write</access>
                    <resetValue>0xffffffff</resetValue>
                    <resetMask>0xffffffff</resetMask>
                </register>
                <register>
                    <name>GTADTRA</name>
                    <description>A/D Conversion Start Request Timing Register A</description>
                    <addressOffset>0x70</addressOffset>
                    <size>32</size>
                    <access>read-write</access>
                    <resetValue>0xffffffff</resetValue>
                    <resetMask>0xffffffff</resetMask>
                </register>
                <register>
                    <name>GTADTBRA</name>
                    <description>A/D Conversion Start Request Timing Buffer Register A</description>
                    <addressOffset>0x74</addressOffset>
                    <size>32</size>
                    <access>read-write</access>
                    <resetValue>0xffffffff</resetValue>
                    <resetMask>0xffffffff</resetMask>
                </register>
                <register>
                    <name>GTADTDBRA</name>
                    <description>A/D Conversion Start Request Timing Double-Buffer Register A</description>
                    <addressOffset>0x78</addressOffset>
                    <size>32</size>
                    <access>read-write</access>
                    <resetValue>0xffffffff</resetValue>
                    <resetMask>0xffffffff</resetMask>
                </register>
                <register>
                    <name>GTADTRB</name>
                    <description>A/D Conversion Start Request Timing Register B</description>
                    <addressOffset>0x7C</addressOffset>
                    <size>32</size>
                    <access>read-write</access>
                    <resetValue>0xffffffff</resetValue>
                    <resetMask>0xffffffff</resetMask>
                </register>
                <register>
                    <name>GTADTBRB</name>
                    <description>A/D Conversion Start Request Timing Buffer Register B</description>
                    <addressOffset>0x80</addressOffset>
                    <size>32</size>
                    <access>read-write</access>
                    <resetValue>0xffffffff</resetValue>
                    <resetMask>0xffffffff</resetMask>
                </register>
                <register>
                    <name>GTADTDBRB</name>
                    <description>A/D Conversion Start Request Timing Double-Buffer Register B</description>
                    <addressOffset>0x84</addressOffset>
                    <size>32</size>
                    <access>read-write</access>
                    <resetValue>0xffffffff</resetValue>
                    <resetMask>0xffffffff</resetMask>
                </register>
                <register>
                    <name>GTDTCR</name>
                    <description>General PWM Timer Dead Time Control Register</description>
                    <addressOffset>0x88</addressOffset>
                    <size>32</size>
                    <access>read-write</access>
                    <resetValue>0x00000000</resetValue>
                    <resetMask>0xffffffff</resetMask>
                    <fields>
                        <field>
                            <name>TDE</name>
                            <description>Negative-Phase Waveform Setting</description>
                            <lsb>0</lsb>
                            <msb>0</msb>
                            <access>read-write</access>
                            <enumeratedValues>
                                <enumeratedValue>
                                    <name>0</name>
                                    <description>GTCCRB is set without using GTDVU</description>
                                    <value>#0</value>
                                </enumeratedValue>
                                <enumeratedValue>
                                    <name>1</name>
                                    <description>GTDVU is used to set the compare match value for negative-phase waveform with dead time automatically in GTCCRB</description>
                                    <value>#1</value>
                                </enumeratedValue>
                            </enumeratedValues>
                        </field>
                    </fields>
                </register>
                <register>
                    <name>GTDVU</name>
                    <description>General PWM Timer Dead Time Value Register U</description>
                    <addressOffset>0x8C</addressOffset>
                    <size>32</size>
                    <access>read-write</access>
                    <resetValue>0xffffffff</resetValue>
                    <resetMask>0xffffffff</resetMask>
                </register>
                <register>
                    <name>GTADSMR</name>
                    <description>General PWM Timer A/D Conversion Start Request Signal Monitoring Register</description>
                    <addressOffset>0xA4</addressOffset>
                    <size>32</size>
                    <access>read-write</access>
                    <resetValue>0x00000000</resetValue>
                    <resetMask>0xffffffff</resetMask>
                    <fields>
                        <field>
                            <name>ADSMS0</name>
                            <description>A/D Conversion Start Request Signal Monitor 0 Selection</description>
                            <lsb>0</lsb>
                            <msb>1</msb>
                            <access>read-write</access>
                            <enumeratedValues>
                                <enumeratedValue>
                                    <name>00</name>
                                    <description>A/D conversion start request signal generated by the GTADTRA register during up-counting.</description>
                                    <value>#00</value>
                                </enumeratedValue>
                                <enumeratedValue>
                                    <name>01</name>
                                    <description>A/D conversion start request signal generated by the GTADTRA register during down-counting.</description>
                                    <value>#01</value>
                                </enumeratedValue>
                                <enumeratedValue>
                                    <name>10</name>
                                    <description>A/D conversion start request signal generated by the GTADTRB register during up-counting.</description>
                                    <value>#10</value>
                                </enumeratedValue>
                                <enumeratedValue>
                                    <name>11</name>
                                    <description>A/D conversion start request signal generated by the GTADTRB register during down-counting.</description>
                                    <value>#11</value>
                                </enumeratedValue>
                            </enumeratedValues>
                        </field>
                        <field>
                            <name>ADSMEN0</name>
                            <description>A/D Conversion Start Request Signal Monitor 0 Output Enabling</description>
                            <lsb>8</lsb>
                            <msb>8</msb>
                            <access>read-write</access>
                            <enumeratedValues>
                                <enumeratedValue>
                                    <name>0</name>
                                    <description>Output of A/D conversion start request signal monitor 0 is disabled.</description>
                                    <value>#0</value>
                                </enumeratedValue>
                                <enumeratedValue>
                                    <name>1</name>
                                    <description>Output of A/D conversion start request signal monitor 0 is enabled.</description>
                                    <value>#1</value>
                                </enumeratedValue>
                            </enumeratedValues>
                        </field>
                        <field>
                            <name>ADSMS1</name>
                            <description>A/D Conversion Start Request Signal Monitor 1 Selection</description>
                            <lsb>16</lsb>
                            <msb>17</msb>
                            <access>read-write</access>
                            <enumeratedValues>
                                <enumeratedValue>
                                    <name>00</name>
                                    <description>A/D conversion start request signal generated by the GTADTRA register during up-counting.</description>
                                    <value>#00</value>
                                </enumeratedValue>
                                <enumeratedValue>
                                    <name>01</name>
                                    <description>A/D conversion start request signal generated by the GTADTRA register during down-counting.</description>
                                    <value>#01</value>
                                </enumeratedValue>
                                <enumeratedValue>
                                    <name>10</name>
                                    <description>A/D conversion start request signal generated by the GTADTRB register during up-counting.</description>
                                    <value>#10</value>
                                </enumeratedValue>
                                <enumeratedValue>
                                    <name>11</name>
                                    <description>A/D conversion start request signal generated by the GTADTRB register during down-counting.</description>
                                    <value>#11</value>
                                </enumeratedValue>
                            </enumeratedValues>
                        </field>
                        <field>
                            <name>ADSMEN1</name>
                            <description>A/D Conversion Start Request Signal Monitor 1 Output Enabling</description>
                            <lsb>24</lsb>
                            <msb>24</msb>
                            <access>read-write</access>
                            <enumeratedValues>
                                <enumeratedValue>
                                    <name>0</name>
                                    <description>Output of A/D conversion start request signal monitor 1 is disabled.</description>
                                    <value>#0</value>
                                </enumeratedValue>
                                <enumeratedValue>
                                    <name>1</name>
                                    <description>Output of A/D conversion start request signal monitor 1 is enabled.</description>
                                    <value>#1</value>
                                </enumeratedValue>
                            </enumeratedValues>
                        </field>
                    </fields>
                </register>
                <register>
                    <name>GTICLF</name>
                    <description>General PWM Timer Inter Channel Logical Operation Function Setting Register</description>
                    <addressOffset>0xB8</addressOffset>
                    <size>32</size>
                    <access>read-write</access>
                    <resetValue>0x00000000</resetValue>
                    <resetMask>0xffffffff</resetMask>
                    <fields>
                        <field>
                            <name>ICLFA</name>
                            <description>GTIOCnA Output Logical Operation Function Select</description>
                            <lsb>0</lsb>
                            <msb>2</msb>
                            <access>read-write</access>
                            <enumeratedValues>
                                <enumeratedValue>
                                    <name>000</name>
                                    <description>A (no delay)</description>
                                    <value>#000</value>
                                </enumeratedValue>
                                <enumeratedValue>
                                    <name>001</name>
                                    <description>NOT A (no delay)</description>
                                    <value>#001</value>
                                </enumeratedValue>
                                <enumeratedValue>
                                    <name>010</name>
                                    <description>C (1PCLKD delay)</description>
                                    <value>#010</value>
                                </enumeratedValue>
                                <enumeratedValue>
                                    <name>011</name>
                                    <description>NOT C (1PCLKD delay)</description>
                                    <value>#011</value>
                                </enumeratedValue>
                                <enumeratedValue>
                                    <name>100</name>
                                    <description>A AND C (1PCLKD delay)</description>
                                    <value>#100</value>
                                </enumeratedValue>
                                <enumeratedValue>
                                    <name>101</name>
                                    <description>A OR C (1PCLKD delay)</description>
                                    <value>#101</value>
                                </enumeratedValue>
                                <enumeratedValue>
                                    <name>110</name>
                                    <description>A EXOR C (1PCLKD delay)</description>
                                    <value>#110</value>
                                </enumeratedValue>
                                <enumeratedValue>
                                    <name>111</name>
                                    <description>A NOR C (1PCLKD delay)</description>
                                    <value>#111</value>
                                </enumeratedValue>
                            </enumeratedValues>
                        </field>
                        <field>
                            <name>ICLFSELC</name>
                            <description>Inter Channel Signal C Select</description>
                            <lsb>4</lsb>
                            <msb>9</msb>
                            <access>read-write</access>
                            <enumeratedValues>
                                <enumeratedValue>
                                    <name>0x00</name>
                                    <description>GTIOC0A</description>
                                    <value>0x00</value>
                                </enumeratedValue>
                                <enumeratedValue>
                                    <name>0x01</name>
                                    <description>GTIOC0B</description>
                                    <value>0x01</value>
                                </enumeratedValue>
                                <enumeratedValue>
                                    <name>0x02</name>
                                    <description>GTIOC1A</description>
                                    <value>0x02</value>
                                </enumeratedValue>
                                <enumeratedValue>
                                    <name>0x03</name>
                                    <description>GTIOC1B</description>
                                    <value>0x03</value>
                                </enumeratedValue>
                                <enumeratedValue>
                                    <name>0x04</name>
                                    <description>GTIOC2A</description>
                                    <value>0x04</value>
                                </enumeratedValue>
                                <enumeratedValue>
                                    <name>0x05</name>
                                    <description>GTIOC2B</description>
                                    <value>0x05</value>
                                </enumeratedValue>
                                <enumeratedValue>
                                    <name>0x06</name>
                                    <description>GTIOC3A</description>
                                    <value>0x06</value>
                                </enumeratedValue>
                                <enumeratedValue>
                                    <name>0x07</name>
                                    <description>GTIOC3B</description>
                                    <value>0x07</value>
                                </enumeratedValue>
                                <enumeratedValue>
                                    <name>0x08</name>
                                    <description>GTIOC4A</description>
                                    <value>0x08</value>
                                </enumeratedValue>
                                <enumeratedValue>
                                    <name>0x09</name>
                                    <description>GTIOC4B</description>
                                    <value>0x09</value>
                                </enumeratedValue>
                                <enumeratedValue>
                                    <name>0x0A</name>
                                    <description>GTIOC5A</description>
                                    <value>0x0a</value>
                                </enumeratedValue>
                                <enumeratedValue>
                                    <name>0x0B</name>
                                    <description>GTIOC5B</description>
                                    <value>0x0b</value>
                                </enumeratedValue>
                                <enumeratedValue>
                                    <name>0x0C</name>
                                    <description>GTIOC6A</description>
                                    <value>0x0c</value>
                                </enumeratedValue>
                                <enumeratedValue>
                                    <name>0x0D</name>
                                    <description>GTIOC6B</description>
                                    <value>0x0d</value>
                                </enumeratedValue>
                                <enumeratedValue>
                                    <name>0x0E</name>
                                    <description>GTIOC7A</description>
                                    <value>0x0e</value>
                                </enumeratedValue>
                                <enumeratedValue>
                                    <name>0x0F</name>
                                    <description>GTIOC7B</description>
                                    <value>0x0f</value>
                                </enumeratedValue>
                                <enumeratedValue>
                                    <name>0x10</name>
                                    <description>GTIOC8A</description>
                                    <value>0x10</value>
                                </enumeratedValue>
                                <enumeratedValue>
                                    <name>0x11</name>
                                    <description>GTIOC8B</description>
                                    <value>0x11</value>
                                </enumeratedValue>
                                <enumeratedValue>
                                    <name>0x12</name>
                                    <description>GTIOC9A</description>
                                    <value>0x12</value>
                                </enumeratedValue>
                                <enumeratedValue>
                                    <name>0x13</name>
                                    <description>GTIOC9B</description>
                                    <value>0x13</value>
                                </enumeratedValue>
                                <enumeratedValue>
                                    <name>Others</name>
                                    <description>Setting prohibited</description>
                                    <isDefault>true</isDefault>
                                </enumeratedValue>
                            </enumeratedValues>
                        </field>
                        <field>
                            <name>ICLFB</name>
                            <description>GTIOCnB Output Logical Operation Function Select</description>
                            <lsb>16</lsb>
                            <msb>18</msb>
                            <access>read-write</access>
                            <enumeratedValues>
                                <enumeratedValue>
                                    <name>000</name>
                                    <description>B (no delay)</description>
                                    <value>#000</value>
                                </enumeratedValue>
                                <enumeratedValue>
                                    <name>001</name>
                                    <description>NOT B (no delay)</description>
                                    <value>#001</value>
                                </enumeratedValue>
                                <enumeratedValue>
                                    <name>010</name>
                                    <description>D (1PCLKD delay)</description>
                                    <value>#010</value>
                                </enumeratedValue>
                                <enumeratedValue>
                                    <name>011</name>
                                    <description>NOT D (1PCLKD delay)</description>
                                    <value>#011</value>
                                </enumeratedValue>
                                <enumeratedValue>
                                    <name>100</name>
                                    <description>B AND D (1PCLKD delay)</description>
                                    <value>#100</value>
                                </enumeratedValue>
                                <enumeratedValue>
                                    <name>101</name>
                                    <description>B OR D (1PCLKDn delay)</description>
                                    <value>#101</value>
                                </enumeratedValue>
                                <enumeratedValue>
                                    <name>110</name>
                                    <description>B EXOR D (1PCLKD delay)</description>
                                    <value>#110</value>
                                </enumeratedValue>
                                <enumeratedValue>
                                    <name>111</name>
                                    <description>B NOR D (1PCLKD delay)</description>
                                    <value>#111</value>
                                </enumeratedValue>
                            </enumeratedValues>
                        </field>
                        <field>
                            <name>ICLFSELD</name>
                            <description>Inter Channel Signal D Select</description>
                            <lsb>20</lsb>
                            <msb>25</msb>
                            <access>read-write</access>
                            <enumeratedValues>
                                <enumeratedValue>
                                    <name>0x00</name>
                                    <description>GTIOC0A</description>
                                    <value>0x00</value>
                                </enumeratedValue>
                                <enumeratedValue>
                                    <name>0x01</name>
                                    <description>GTIOC0B</description>
                                    <value>0x01</value>
                                </enumeratedValue>
                                <enumeratedValue>
                                    <name>0x02</name>
                                    <description>GTIOC1A</description>
                                    <value>0x02</value>
                                </enumeratedValue>
                                <enumeratedValue>
                                    <name>0x03</name>
                                    <description>GTIOC1B</description>
                                    <value>0x03</value>
                                </enumeratedValue>
                                <enumeratedValue>
                                    <name>0x04</name>
                                    <description>GTIOC2A</description>
                                    <value>0x04</value>
                                </enumeratedValue>
                                <enumeratedValue>
                                    <name>0x05</name>
                                    <description>GTIOC2B</description>
                                    <value>0x05</value>
                                </enumeratedValue>
                                <enumeratedValue>
                                    <name>0x06</name>
                                    <description>GTIOC3A</description>
                                    <value>0x06</value>
                                </enumeratedValue>
                                <enumeratedValue>
                                    <name>0x07</name>
                                    <description>GTIOC3B</description>
                                    <value>0x07</value>
                                </enumeratedValue>
                                <enumeratedValue>
                                    <name>0x08</name>
                                    <description>GTIOC4A</description>
                                    <value>0x08</value>
                                </enumeratedValue>
                                <enumeratedValue>
                                    <name>0x09</name>
                                    <description>GTIOC4B</description>
                                    <value>0x09</value>
                                </enumeratedValue>
                                <enumeratedValue>
                                    <name>0x0A</name>
                                    <description>GTIOC5A</description>
                                    <value>0x0a</value>
                                </enumeratedValue>
                                <enumeratedValue>
                                    <name>0x0B</name>
                                    <description>GTIOC5B</description>
                                    <value>0x0b</value>
                                </enumeratedValue>
                                <enumeratedValue>
                                    <name>0x0C</name>
                                    <description>GTIOC6A</description>
                                    <value>0x0c</value>
                                </enumeratedValue>
                                <enumeratedValue>
                                    <name>0x0D</name>
                                    <description>GTIOC6B</description>
                                    <value>0x0d</value>
                                </enumeratedValue>
                                <enumeratedValue>
                                    <name>0x0E</name>
                                    <description>GTIOC7A</description>
                                    <value>0x0e</value>
                                </enumeratedValue>
                                <enumeratedValue>
                                    <name>0x0F</name>
                                    <description>GTIOC7B</description>
                                    <value>0x0f</value>
                                </enumeratedValue>
                                <enumeratedValue>
                                    <name>0x10</name>
                                    <description>GTIOC8A</description>
                                    <value>0x10</value>
                                </enumeratedValue>
                                <enumeratedValue>
                                    <name>0x11</name>
                                    <description>GTIOC8B</description>
                                    <value>0x11</value>
                                </enumeratedValue>
                                <enumeratedValue>
                                    <name>0x12</name>
                                    <description>GTIOC9A</description>
                                    <value>0x12</value>
                                </enumeratedValue>
                                <enumeratedValue>
                                    <name>0x13</name>
                                    <description>GTIOC9B</description>
                                    <value>0x13</value>
                                </enumeratedValue>
                                <enumeratedValue>
                                    <name>Others</name>
                                    <description>Setting prohibited</description>
                                    <isDefault>true</isDefault>
                                </enumeratedValue>
                            </enumeratedValues>
                        </field>
                    </fields>
                </register>
                <register>
                    <name>GTPC</name>
                    <description>General PWM Timer Period Count Register</description>
                    <addressOffset>0xBC</addressOffset>
                    <size>32</size>
                    <access>read-write</access>
                    <resetValue>0x00000000</resetValue>
                    <resetMask>0xffffffff</resetMask>
                    <fields>
                        <field>
                            <name>PCEN</name>
                            <description>Period Count Function Enable</description>
                            <lsb>0</lsb>
                            <msb>0</msb>
                            <access>read-write</access>
                            <enumeratedValues>
                                <enumeratedValue>
                                    <name>0</name>
                                    <description>Period count function is disabled</description>
                                    <value>#0</value>
                                </enumeratedValue>
                                <enumeratedValue>
                                    <name>1</name>
                                    <description>Period count function is enabled</description>
                                    <value>#1</value>
                                </enumeratedValue>
                            </enumeratedValues>
                        </field>
                        <field>
                            <name>ASTP</name>
                            <description>Automatic Stop Function Enable</description>
                            <lsb>8</lsb>
                            <msb>8</msb>
                            <access>read-write</access>
                            <enumeratedValues>
                                <enumeratedValue>
                                    <name>0</name>
                                    <description>Automatic stop function is disabled</description>
                                    <value>#0</value>
                                </enumeratedValue>
                                <enumeratedValue>
                                    <name>1</name>
                                    <description>Automatic stop function is enabled</description>
                                    <value>#1</value>
                                </enumeratedValue>
                            </enumeratedValues>
                        </field>
                        <field>
                            <name>PCNT</name>
                            <description>Period Counter</description>
                            <lsb>16</lsb>
                            <msb>27</msb>
                            <access>read-write</access>
                        </field>
                    </fields>
                </register>
                <register>
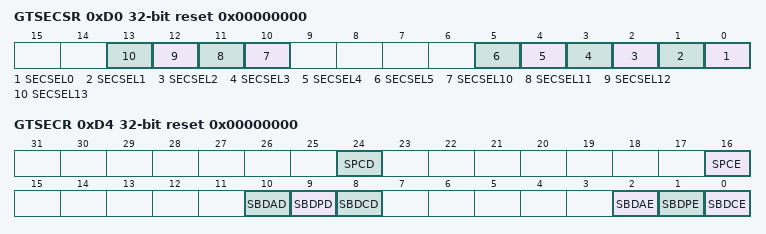
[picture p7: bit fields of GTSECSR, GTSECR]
                    <name>GTSECSR</name>
                    <description>General PWM Timer Operation Enable Bit Simultaneous Control Channel Select Register</description>
                    <addressOffset>0xD0</addressOffset>
                    <size>32</size>
                    <access>read-write</access>
                    <resetValue>0x00000000</resetValue>
                    <resetMask>0xffffffff</resetMask>
                    <fields>
                        <field>
                            <name>SECSEL0</name>
                            <description>Channel 0 Operation Enable Bit Simultaneous Control Channel Select</description>
                            <lsb>0</lsb>
                            <msb>0</msb>
                            <access>read-write</access>
                            <enumeratedValues>
                                <enumeratedValue>
                                    <name>0</name>
                                    <description>Disable simultaneous control</description>
                                    <value>#0</value>
                                </enumeratedValue>
                                <enumeratedValue>
                                    <name>1</name>
                                    <description>Enable simultaneous control</description>
                                    <value>#1</value>
                                </enumeratedValue>
                            </enumeratedValues>
                        </field>
                        <field>
                            <name>SECSEL1</name>
                            <description>Channel 1 Operation Enable Bit Simultaneous Control Channel Select</description>
                            <lsb>1</lsb>
                            <msb>1</msb>
                            <access>read-write</access>
                            <enumeratedValues>
                                <enumeratedValue>
                                    <name>0</name>
                                    <description>Disable simultaneous control</description>
                                    <value>#0</value>
                                </enumeratedValue>
                                <enumeratedValue>
                                    <name>1</name>
                                    <description>Enable simultaneous control</description>
                                    <value>#1</value>
                                </enumeratedValue>
                            </enumeratedValues>
                        </field>
                        <field>
                            <name>SECSEL2</name>
                            <description>Channel 2 Operation Enable Bit Simultaneous Control Channel Select</description>
                            <lsb>2</lsb>
                            <msb>2</msb>
                            <access>read-write</access>
                            <enumeratedValues>
                                <enumeratedValue>
                                    <name>0</name>
                                    <description>Disable simultaneous control</description>
                                    <value>#0</value>
                                </enumeratedValue>
                                <enumeratedValue>
                                    <name>1</name>
                                    <description>Enable simultaneous control</description>
                                    <value>#1</value>
                                </enumeratedValue>
                            </enumeratedValues>
                        </field>
                        <field>
                            <name>SECSEL3</name>
                            <description>Channel 3 Operation Enable Bit Simultaneous Control Channel Select</description>
                            <lsb>3</lsb>
                            <msb>3</msb>
                            <access>read-write</access>
                            <enumeratedValues>
                                <enumeratedValue>
                                    <name>0</name>
                                    <description>Disable simultaneous control</description>
                                    <value>#0</value>
                                </enumeratedValue>
                                <enumeratedValue>
                                    <name>1</name>
                                    <description>Enable simultaneous control</description>
                                    <value>#1</value>
                                </enumeratedValue>
                            </enumeratedValues>
                        </field>
                        <field>
                            <name>SECSEL4</name>
                            <description>Channel 4 Operation Enable Bit Simultaneous Control Channel Select</description>
                            <lsb>4</lsb>
                            <msb>4</msb>
                            <access>read-write</access>
                            <enumeratedValues>
                                <enumeratedValue>
                                    <name>0</name>
                                    <description>Disable simultaneous control</description>
                                    <value>#0</value>
                                </enumeratedValue>
                                <enumeratedValue>
                                    <name>1</name>
                                    <description>Enable simultaneous control</description>
                                    <value>#1</value>
                                </enumeratedValue>
                            </enumeratedValues>
                        </field>
                        <field>
                            <name>SECSEL5</name>
                            <description>Channel 5 Operation Enable Bit Simultaneous Control Channel Select</description>
                            <lsb>5</lsb>
                            <msb>5</msb>
                            <access>read-write</access>
                            <enumeratedValues>
                                <enumeratedValue>
                                    <name>0</name>
                                    <description>Disable simultaneous control</description>
                                    <value>#0</value>
                                </enumeratedValue>
                                <enumeratedValue>
                                    <name>1</name>
                                    <description>Enable simultaneous control</description>
                                    <value>#1</value>
                                </enumeratedValue>
                            </enumeratedValues>
                        </field>
                        <field>
                            <name>SECSEL10</name>
                            <description>Channel 10 Operation Enable Bit Simultaneous Control Channel Select</description>
                            <lsb>10</lsb>
                            <msb>10</msb>
                            <access>read-write</access>
                            <enumeratedValues>
                                <enumeratedValue>
                                    <name>0</name>
                                    <description>Disable simultaneous control</description>
                                    <value>#0</value>
                                </enumeratedValue>
                                <enumeratedValue>
                                    <name>1</name>
                                    <description>Enable simultaneous control</description>
                                    <value>#1</value>
                                </enumeratedValue>
                            </enumeratedValues>
                        </field>
                        <field>
                            <name>SECSEL11</name>
                            <description>Channel 11 Operation Enable Bit Simultaneous Control Channel Select</description>
                            <lsb>11</lsb>
                            <msb>11</msb>
                            <access>read-write</access>
                            <enumeratedValues>
                                <enumeratedValue>
                                    <name>0</name>
                                    <description>Disable simultaneous control</description>
                                    <value>#0</value>
                                </enumeratedValue>
                                <enumeratedValue>
                                    <name>1</name>
                                    <description>Enable simultaneous control</description>
                                    <value>#1</value>
                                </enumeratedValue>
                            </enumeratedValues>
                        </field>
                        <field>
                            <name>SECSEL12</name>
                            <description>Channel 12 Operation Enable Bit Simultaneous Control Channel Select</description>
                            <lsb>12</lsb>
                            <msb>12</msb>
                            <access>read-write</access>
                            <enumeratedValues>
                                <enumeratedValue>
                                    <name>0</name>
                                    <description>Disable simultaneous control</description>
                                    <value>#0</value>
                                </enumeratedValue>
                                <enumeratedValue>
                                    <name>1</name>
                                    <description>Enable simultaneous control</description>
                                    <value>#1</value>
                                </enumeratedValue>
                            </enumeratedValues>
                        </field>
                        <field>
                            <name>SECSEL13</name>
                            <description>Channel 13 Operation Enable Bit Simultaneous Control Channel Select</description>
                            <lsb>13</lsb>
                            <msb>13</msb>
                            <access>read-write</access>
                            <enumeratedValues>
                                <enumeratedValue>
                                    <name>0</name>
                                    <description>Disable simultaneous control</description>
                                    <value>#0</value>
                                </enumeratedValue>
                                <enumeratedValue>
                                    <name>1</name>
                                    <description>Enable simultaneous control</description>
                                    <value>#1</value>
                                </enumeratedValue>
                            </enumeratedValues>
                        </field>
                    </fields>
                </register>
                <register>
                    <name>GTSECR</name>
                    <description>General PWM Timer Operation Enable Bit Simultaneous Control Register</description>
                    <addressOffset>0xD4</addressOffset>
                    <size>32</size>
                    <access>read-write</access>
                    <resetValue>0x00000000</resetValue>
                    <resetMask>0xffffffff</resetMask>
                    <fields>
                        <field>
                            <name>SBDCE</name>
                            <description>GTCCR Register Buffer Operation Simultaneous Enable</description>
                            <lsb>0</lsb>
                            <msb>0</msb>
                            <access>read-write</access>
                            <enumeratedValues>
                                <enumeratedValue>
                                    <name>0</name>
                                    <description>Disable simultaneous enabling GTCCR buffer operations</description>
                                    <value>#0</value>
                                </enumeratedValue>
                                <enumeratedValue>
                                    <name>1</name>
                                    <description>Enable GTCCR register buffer operations simultaneously</description>
                                    <value>#1</value>
                                </enumeratedValue>
                            </enumeratedValues>
                        </field>
                        <field>
                            <name>SBDPE</name>
                            <description>GTPR Register Buffer Operation Simultaneous Enable</description>
                            <lsb>1</lsb>
                            <msb>1</msb>
                            <access>read-write</access>
                            <enumeratedValues>
                                <enumeratedValue>
                                    <name>0</name>
                                    <description>Disable simultaneous enabling GTPR buffer operations</description>
                                    <value>#0</value>
                                </enumeratedValue>
                                <enumeratedValue>
                                    <name>1</name>
                                    <description>Enable GTPR register buffer operations simultaneously</description>
                                    <value>#1</value>
                                </enumeratedValue>
                            </enumeratedValues>
                        </field>
                        <field>
                            <name>SBDAE</name>
                            <description>GTADTR Register Buffer Operation Simultaneous Enable</description>
                            <lsb>2</lsb>
                            <msb>2</msb>
                            <access>read-write</access>
                            <enumeratedValues>
                                <enumeratedValue>
                                    <name>0</name>
                                    <description>Disable simultaneous enabling GTADTR buffer operations</description>
                                    <value>#0</value>
                                </enumeratedValue>
                                <enumeratedValue>
                                    <name>1</name>
                                    <description>Enable GTADTR register buffer operations simultaneously</description>
                                    <value>#1</value>
                                </enumeratedValue>
                            </enumeratedValues>
                        </field>
                        <field>
                            <name>SBDCD</name>
                            <description>GTCCR Register Buffer Operation Simultaneous Disable</description>
                            <lsb>8</lsb>
                            <msb>8</msb>
                            <access>read-write</access>
                            <enumeratedValues>
                                <enumeratedValue>
                                    <name>0</name>
                                    <description>Disable simultaneous disabling GTCCR buffer operations</description>
                                    <value>#0</value>
                                </enumeratedValue>
                                <enumeratedValue>
                                    <name>1</name>
                                    <description>Disable GTCCR register buffer operations simultaneously</description>
                                    <value>#1</value>
                                </enumeratedValue>
                            </enumeratedValues>
                        </field>
                        <field>
                            <name>SBDPD</name>
                            <description>GTPR Register Buffer Operation Simultaneous Disable</description>
                            <lsb>9</lsb>
                            <msb>9</msb>
                            <access>read-write</access>
                            <enumeratedValues>
                                <enumeratedValue>
                                    <name>0</name>
                                    <description>Disable simultaneous disabling GTPR buffer operations</description>
                                    <value>#0</value>
                                </enumeratedValue>
                                <enumeratedValue>
                                    <name>1</name>
                                    <description>Disable GTPR register buffer operations simultaneously</description>
                                    <value>#1</value>
                                </enumeratedValue>
                            </enumeratedValues>
                        </field>
                        <field>
                            <name>SBDAD</name>
                            <description>GTADTR Register Buffer Operation Simultaneous Disable</description>
                            <lsb>10</lsb>
                            <msb>10</msb>
                            <access>read-write</access>
                            <enumeratedValues>
                                <enumeratedValue>
                                    <name>0</name>
                                    <description>Disable simultaneous disabling GTADTR buffer operations</description>
                                    <value>#0</value>
                                </enumeratedValue>
                                <enumeratedValue>
                                    <name>1</name>
                                    <description>Disable GTADTR register buffer operations simultaneously</description>
                                    <value>#1</value>
                                </enumeratedValue>
                            </enumeratedValues>
                        </field>
                        <field>
                            <name>SPCE</name>
                            <description>Period Count Function Simultaneous Enable</description>
                            <lsb>16</lsb>
                            <msb>16</msb>
                            <access>read-write</access>
                            <enumeratedValues>
                                <enumeratedValue>
                                    <name>0</name>
                                    <description>Disable simultaneous enabling period count function</description>
                                    <value>#0</value>
                                </enumeratedValue>
                                <enumeratedValue>
                                    <name>1</name>
                                    <description>Enable period count function simultaneously</description>
                                    <value>#1</value>
                                </enumeratedValue>
                            </enumeratedValues>
                        </field>
                        <field>
                            <name>SPCD</name>
                            <description>Period Count Function Simultaneous Disable</description>
                            <lsb>24</lsb>
                            <msb>24</msb>
                            <access>read-write</access>
                            <enumeratedValues>
                                <enumeratedValue>
                                    <name>0</name>
                                    <description>Disable simultaneous disabling period count function</description>
                                    <value>#0</value>
                                </enumeratedValue>
                                <enumeratedValue>
                                    <name>1</name>
                                    <description>Disable period count function simultaneously</description>
                                    <value>#1</value>
                                </enumeratedValue>
                            </enumeratedValues>
                        </field>
                    </fields>
                </register>
            </registers>
        </peripheral>
        <peripheral derivedFrom="GPT320">
            <name>GPT321</name>
            <description>General PWM 32-bit Timer 1</description>
            <baseAddress>0x40322100</baseAddress>
        </peripheral>
        <peripheral derivedFrom="GPT320">
            <name>GPT322</name>
            <description>General PWM 32-bit Timer 2</description>
            <baseAddress>0x40322200</baseAddress>
        </peripheral>
        <peripheral derivedFrom="GPT320">
            <name>GPT323</name>
            <description>General PWM 32-bit Timer 3</description>
            <baseAddress>0x40322300</baseAddress>
        </peripheral>
        <peripheral derivedFrom="GPT320">
            <name>GPT324</name>
            <description>General PWM 32-bit Timer 4</description>
            <baseAddress>0x40322400</baseAddress>
        </peripheral>
        <peripheral derivedFrom="GPT320">
            <name>GPT325</name>
            <description>General PWM 32-bit Timer 5</description>
            <baseAddress>0x40322500</baseAddress>
        </peripheral>
        <peripheral derivedFrom="GPT320">
            <name>GPT326</name>
            <description>General PWM 32-bit Timer 6</description>
            <baseAddress>0x40322600</baseAddress>
        </peripheral>
        <peripheral derivedFrom="GPT320">
            <name>GPT327</name>
            <description>General PWM 32-bit Timer 7</description>
            <baseAddress>0x40322700</baseAddress>
        </peripheral>
        <peripheral>
            <name>GPT168</name>
            <description>General PWM 16-bit Timer 8</description>
            <baseAddress>0x40322800</baseAddress>
            <addressBlock>
                <offset>0x04</offset>
                <size>44</size>
                <usage>registers</usage>
            </addressBlock>
            <addressBlock>
                <offset>0x38</offset>
                <size>4</size>
                <usage>registers</usage>
            </addressBlock>
            <addressBlock>
                <offset>0x70</offset>
                <size>24</size>
                <usage>registers</usage>
            </addressBlock>
            <addressBlock>
                <offset>0xA4</offset>
                <size>4</size>
                <usage>registers</usage>
            </addressBlock>
            <addressBlock>
                <offset>0xB8</offset>
                <size>4</size>
                <usage>registers</usage>
            </addressBlock>
            <registers>
                <register>
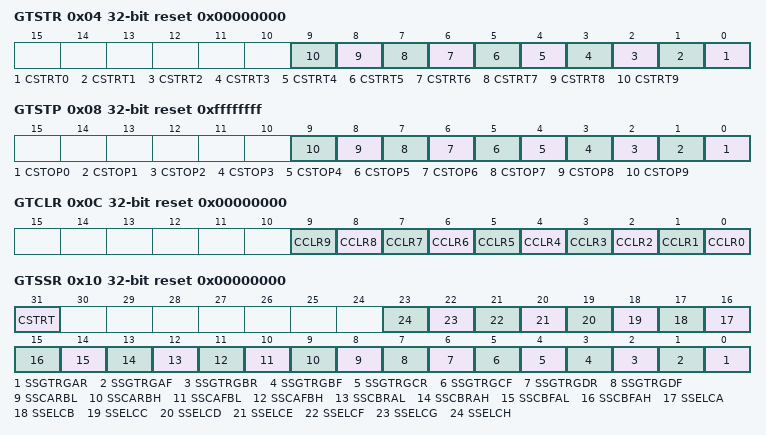
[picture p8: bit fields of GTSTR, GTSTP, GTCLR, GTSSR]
                    <name>GTSTR</name>
                    <description>General PWM Timer Software Start Register</description>
                    <addressOffset>0x04</addressOffset>
                    <size>32</size>
                    <access>read-write</access>
                    <resetValue>0x00000000</resetValue>
                    <resetMask>0xffffffff</resetMask>
                    <fields>
                        <field>
                            <name>CSTRT0</name>
                            <description>Channel n GTCNT Count Start (n : the same as bit position value)</description>
                            <lsb>0</lsb>
                            <msb>0</msb>
                            <access>read-write</access>
                            <enumeratedValues>
                                <enumeratedValue>
                                    <name>0</name>
                                    <description>GTCNT counter not start</description>
                                    <value>#0</value>
                                </enumeratedValue>
                                <enumeratedValue>
                                    <name>1</name>
                                    <description>GTCNT counter start</description>
                                    <value>#1</value>
                                </enumeratedValue>
                            </enumeratedValues>
                        </field>
                        <field>
                            <name>CSTRT1</name>
                            <description>Channel n GTCNT Count Start (n : the same as bit position value)</description>
                            <lsb>1</lsb>
                            <msb>1</msb>
                            <access>read-write</access>
                            <enumeratedValues>
                                <enumeratedValue>
                                    <name>0</name>
                                    <description>GTCNT counter not start</description>
                                    <value>#0</value>
                                </enumeratedValue>
                                <enumeratedValue>
                                    <name>1</name>
                                    <description>GTCNT counter start</description>
                                    <value>#1</value>
                                </enumeratedValue>
                            </enumeratedValues>
                        </field>
                        <field>
                            <name>CSTRT2</name>
                            <description>Channel n GTCNT Count Start (n : the same as bit position value)</description>
                            <lsb>2</lsb>
                            <msb>2</msb>
                            <access>read-write</access>
                            <enumeratedValues>
                                <enumeratedValue>
                                    <name>0</name>
                                    <description>GTCNT counter not start</description>
                                    <value>#0</value>
                                </enumeratedValue>
                                <enumeratedValue>
                                    <name>1</name>
                                    <description>GTCNT counter start</description>
                                    <value>#1</value>
                                </enumeratedValue>
                            </enumeratedValues>
                        </field>
                        <field>
                            <name>CSTRT3</name>
                            <description>Channel n GTCNT Count Start (n : the same as bit position value)</description>
                            <lsb>3</lsb>
                            <msb>3</msb>
                            <access>read-write</access>
                            <enumeratedValues>
                                <enumeratedValue>
                                    <name>0</name>
                                    <description>GTCNT counter not start</description>
                                    <value>#0</value>
                                </enumeratedValue>
                                <enumeratedValue>
                                    <name>1</name>
                                    <description>GTCNT counter start</description>
                                    <value>#1</value>
                                </enumeratedValue>
                            </enumeratedValues>
                        </field>
                        <field>
                            <name>CSTRT4</name>
                            <description>Channel n GTCNT Count Start (n : the same as bit position value)</description>
                            <lsb>4</lsb>
                            <msb>4</msb>
                            <access>read-write</access>
                            <enumeratedValues>
                                <enumeratedValue>
                                    <name>0</name>
                                    <description>GTCNT counter not start</description>
                                    <value>#0</value>
                                </enumeratedValue>
                                <enumeratedValue>
                                    <name>1</name>
                                    <description>GTCNT counter start</description>
                                    <value>#1</value>
                                </enumeratedValue>
                            </enumeratedValues>
                        </field>
                        <field>
                            <name>CSTRT5</name>
                            <description>Channel n GTCNT Count Start (n : the same as bit position value)</description>
                            <lsb>5</lsb>
                            <msb>5</msb>
                            <access>read-write</access>
                            <enumeratedValues>
                                <enumeratedValue>
                                    <name>0</name>
                                    <description>GTCNT counter not start</description>
                                    <value>#0</value>
                                </enumeratedValue>
                                <enumeratedValue>
                                    <name>1</name>
                                    <description>GTCNT counter start</description>
                                    <value>#1</value>
                                </enumeratedValue>
                            </enumeratedValues>
                        </field>
                        <field>
                            <name>CSTRT6</name>
                            <description>Channel n GTCNT Count Start (n : the same as bit position value)</description>
                            <lsb>6</lsb>
                            <msb>6</msb>
                            <access>read-write</access>
                            <enumeratedValues>
                                <enumeratedValue>
                                    <name>0</name>
                                    <description>GTCNT counter not start</description>
                                    <value>#0</value>
                                </enumeratedValue>
                                <enumeratedValue>
                                    <name>1</name>
                                    <description>GTCNT counter start</description>
                                    <value>#1</value>
                                </enumeratedValue>
                            </enumeratedValues>
                        </field>
                        <field>
                            <name>CSTRT7</name>
                            <description>Channel n GTCNT Count Start (n : the same as bit position value)</description>
                            <lsb>7</lsb>
                            <msb>7</msb>
                            <access>read-write</access>
                            <enumeratedValues>
                                <enumeratedValue>
                                    <name>0</name>
                                    <description>GTCNT counter not start</description>
                                    <value>#0</value>
                                </enumeratedValue>
                                <enumeratedValue>
                                    <name>1</name>
                                    <description>GTCNT counter start</description>
                                    <value>#1</value>
                                </enumeratedValue>
                            </enumeratedValues>
                        </field>
                        <field>
                            <name>CSTRT8</name>
                            <description>Channel n GTCNT Count Start (n : the same as bit position value)</description>
                            <lsb>8</lsb>
                            <msb>8</msb>
                            <access>read-write</access>
                            <enumeratedValues>
                                <enumeratedValue>
                                    <name>0</name>
                                    <description>GTCNT counter not start</description>
                                    <value>#0</value>
                                </enumeratedValue>
                                <enumeratedValue>
                                    <name>1</name>
                                    <description>GTCNT counter start</description>
                                    <value>#1</value>
                                </enumeratedValue>
                            </enumeratedValues>
                        </field>
                        <field>
                            <name>CSTRT9</name>
                            <description>Channel n GTCNT Count Start (n : the same as bit position value)</description>
                            <lsb>9</lsb>
                            <msb>9</msb>
                            <access>read-write</access>
                            <enumeratedValues>
                                <enumeratedValue>
                                    <name>0</name>
                                    <description>GTCNT counter not start</description>
                                    <value>#0</value>
                                </enumeratedValue>
                                <enumeratedValue>
                                    <name>1</name>
                                    <description>GTCNT counter start</description>
                                    <value>#1</value>
                                </enumeratedValue>
                            </enumeratedValues>
                        </field>
                    </fields>
                </register>
                <register>
                    <name>GTSTP</name>
                    <description>General PWM Timer Software Stop Register</description>
                    <addressOffset>0x08</addressOffset>
                    <size>32</size>
                    <access>read-write</access>
                    <resetValue>0xffffffff</resetValue>
                    <resetMask>0xffffffff</resetMask>
                    <fields>
                        <field>
                            <name>CSTOP0</name>
                            <description>Channel n GTCNT Count Stop (n : the same as bit position value)</description>
                            <lsb>0</lsb>
                            <msb>0</msb>
                            <access>read-write</access>
                            <enumeratedValues>
                                <enumeratedValue>
                                    <name>0</name>
                                    <description>GTCNT counter not stop</description>
                                    <value>#0</value>
                                </enumeratedValue>
                                <enumeratedValue>
                                    <name>1</name>
                                    <description>GTCNT counter stop</description>
                                    <value>#1</value>
                                </enumeratedValue>
                            </enumeratedValues>
                        </field>
                        <field>
                            <name>CSTOP1</name>
                            <description>Channel n GTCNT Count Stop (n : the same as bit position value)</description>
                            <lsb>1</lsb>
                            <msb>1</msb>
                            <access>read-write</access>
                            <enumeratedValues>
                                <enumeratedValue>
                                    <name>0</name>
                                    <description>GTCNT counter not stop</description>
                                    <value>#0</value>
                                </enumeratedValue>
                                <enumeratedValue>
                                    <name>1</name>
                                    <description>GTCNT counter stop</description>
                                    <value>#1</value>
                                </enumeratedValue>
                            </enumeratedValues>
                        </field>
                        <field>
                            <name>CSTOP2</name>
                            <description>Channel n GTCNT Count Stop (n : the same as bit position value)</description>
                            <lsb>2</lsb>
                            <msb>2</msb>
                            <access>read-write</access>
                            <enumeratedValues>
                                <enumeratedValue>
                                    <name>0</name>
                                    <description>GTCNT counter not stop</description>
                                    <value>#0</value>
                                </enumeratedValue>
                                <enumeratedValue>
                                    <name>1</name>
                                    <description>GTCNT counter stop</description>
                                    <value>#1</value>
                                </enumeratedValue>
                            </enumeratedValues>
                        </field>
                        <field>
                            <name>CSTOP3</name>
                            <description>Channel n GTCNT Count Stop (n : the same as bit position value)</description>
                            <lsb>3</lsb>
                            <msb>3</msb>
                            <access>read-write</access>
                            <enumeratedValues>
                                <enumeratedValue>
                                    <name>0</name>
                                    <description>GTCNT counter not stop</description>
                                    <value>#0</value>
                                </enumeratedValue>
                                <enumeratedValue>
                                    <name>1</name>
                                    <description>GTCNT counter stop</description>
                                    <value>#1</value>
                                </enumeratedValue>
                            </enumeratedValues>
                        </field>
                        <field>
                            <name>CSTOP4</name>
                            <description>Channel n GTCNT Count Stop (n : the same as bit position value)</description>
                            <lsb>4</lsb>
                            <msb>4</msb>
                            <access>read-write</access>
                            <enumeratedValues>
                                <enumeratedValue>
                                    <name>0</name>
                                    <description>GTCNT counter not stop</description>
                                    <value>#0</value>
                                </enumeratedValue>
                                <enumeratedValue>
                                    <name>1</name>
                                    <description>GTCNT counter stop</description>
                                    <value>#1</value>
                                </enumeratedValue>
                            </enumeratedValues>
                        </field>
                        <field>
                            <name>CSTOP5</name>
                            <description>Channel n GTCNT Count Stop (n : the same as bit position value)</description>
                            <lsb>5</lsb>
                            <msb>5</msb>
                            <access>read-write</access>
                            <enumeratedValues>
                                <enumeratedValue>
                                    <name>0</name>
                                    <description>GTCNT counter not stop</description>
                                    <value>#0</value>
                                </enumeratedValue>
                                <enumeratedValue>
                                    <name>1</name>
                                    <description>GTCNT counter stop</description>
                                    <value>#1</value>
                                </enumeratedValue>
                            </enumeratedValues>
                        </field>
                        <field>
                            <name>CSTOP6</name>
                            <description>Channel n GTCNT Count Stop (n : the same as bit position value)</description>
                            <lsb>6</lsb>
                            <msb>6</msb>
                            <access>read-write</access>
                            <enumeratedValues>
                                <enumeratedValue>
                                    <name>0</name>
                                    <description>GTCNT counter not stop</description>
                                    <value>#0</value>
                                </enumeratedValue>
                                <enumeratedValue>
                                    <name>1</name>
                                    <description>GTCNT counter stop</description>
                                    <value>#1</value>
                                </enumeratedValue>
                            </enumeratedValues>
                        </field>
                        <field>
                            <name>CSTOP7</name>
                            <description>Channel n GTCNT Count Stop (n : the same as bit position value)</description>
                            <lsb>7</lsb>
                            <msb>7</msb>
                            <access>read-write</access>
                            <enumeratedValues>
                                <enumeratedValue>
                                    <name>0</name>
                                    <description>GTCNT counter not stop</description>
                                    <value>#0</value>
                                </enumeratedValue>
                                <enumeratedValue>
                                    <name>1</name>
                                    <description>GTCNT counter stop</description>
                                    <value>#1</value>
                                </enumeratedValue>
                            </enumeratedValues>
                        </field>
                        <field>
                            <name>CSTOP8</name>
                            <description>Channel n GTCNT Count Stop (n : the same as bit position value)</description>
                            <lsb>8</lsb>
                            <msb>8</msb>
                            <access>read-write</access>
                            <enumeratedValues>
                                <enumeratedValue>
                                    <name>0</name>
                                    <description>GTCNT counter not stop</description>
                                    <value>#0</value>
                                </enumeratedValue>
                                <enumeratedValue>
                                    <name>1</name>
                                    <description>GTCNT counter stop</description>
                                    <value>#1</value>
                                </enumeratedValue>
                            </enumeratedValues>
                        </field>
                        <field>
                            <name>CSTOP9</name>
                            <description>Channel n GTCNT Count Stop (n : the same as bit position value)</description>
                            <lsb>9</lsb>
                            <msb>9</msb>
                            <access>read-write</access>
                            <enumeratedValues>
                                <enumeratedValue>
                                    <name>0</name>
                                    <description>GTCNT counter not stop</description>
                                    <value>#0</value>
                                </enumeratedValue>
                                <enumeratedValue>
                                    <name>1</name>
                                    <description>GTCNT counter stop</description>
                                    <value>#1</value>
                                </enumeratedValue>
                            </enumeratedValues>
                        </field>
                    </fields>
                </register>
                <register>
                    <name>GTCLR</name>
                    <description>General PWM Timer Software Clear Register</description>
                    <addressOffset>0x0C</addressOffset>
                    <size>32</size>
                    <access>write-only</access>
                    <resetValue>0x00000000</resetValue>
                    <resetMask>0xffffffff</resetMask>
                    <fields>
                        <field>
                            <name>CCLR0</name>
                            <description>Channel n GTCNT Count Clear (n : the same as bit position value)</description>
                            <lsb>0</lsb>
                            <msb>0</msb>
                            <access>write-only</access>
                            <enumeratedValues>
                                <enumeratedValue>
                                    <name>0</name>
                                    <description>GTCNT counter is not cleared</description>
                                    <value>#0</value>
                                </enumeratedValue>
                                <enumeratedValue>
                                    <name>1</name>
                                    <description>GTCNT counter is cleared</description>
                                    <value>#1</value>
                                </enumeratedValue>
                            </enumeratedValues>
                        </field>
                        <field>
                            <name>CCLR1</name>
                            <description>Channel n GTCNT Count Clear (n : the same as bit position value)</description>
                            <lsb>1</lsb>
                            <msb>1</msb>
                            <access>write-only</access>
                            <enumeratedValues>
                                <enumeratedValue>
                                    <name>0</name>
                                    <description>GTCNT counter is not cleared</description>
                                    <value>#0</value>
                                </enumeratedValue>
                                <enumeratedValue>
                                    <name>1</name>
                                    <description>GTCNT counter is cleared</description>
                                    <value>#1</value>
                                </enumeratedValue>
                            </enumeratedValues>
                        </field>
                        <field>
                            <name>CCLR2</name>
                            <description>Channel n GTCNT Count Clear (n : the same as bit position value)</description>
                            <lsb>2</lsb>
                            <msb>2</msb>
                            <access>write-only</access>
                            <enumeratedValues>
                                <enumeratedValue>
                                    <name>0</name>
                                    <description>GTCNT counter is not cleared</description>
                                    <value>#0</value>
                                </enumeratedValue>
                                <enumeratedValue>
                                    <name>1</name>
                                    <description>GTCNT counter is cleared</description>
                                    <value>#1</value>
                                </enumeratedValue>
                            </enumeratedValues>
                        </field>
                        <field>
                            <name>CCLR3</name>
                            <description>Channel n GTCNT Count Clear (n : the same as bit position value)</description>
                            <lsb>3</lsb>
                            <msb>3</msb>
                            <access>write-only</access>
                            <enumeratedValues>
                                <enumeratedValue>
                                    <name>0</name>
                                    <description>GTCNT counter is not cleared</description>
                                    <value>#0</value>
                                </enumeratedValue>
                                <enumeratedValue>
                                    <name>1</name>
                                    <description>GTCNT counter is cleared</description>
                                    <value>#1</value>
                                </enumeratedValue>
                            </enumeratedValues>
                        </field>
                        <field>
                            <name>CCLR4</name>
                            <description>Channel n GTCNT Count Clear (n : the same as bit position value)</description>
                            <lsb>4</lsb>
                            <msb>4</msb>
                            <access>write-only</access>
                            <enumeratedValues>
                                <enumeratedValue>
                                    <name>0</name>
                                    <description>GTCNT counter is not cleared</description>
                                    <value>#0</value>
                                </enumeratedValue>
                                <enumeratedValue>
                                    <name>1</name>
                                    <description>GTCNT counter is cleared</description>
                                    <value>#1</value>
                                </enumeratedValue>
                            </enumeratedValues>
                        </field>
                        <field>
                            <name>CCLR5</name>
                            <description>Channel n GTCNT Count Clear (n : the same as bit position value)</description>
                            <lsb>5</lsb>
                            <msb>5</msb>
                            <access>write-only</access>
                            <enumeratedValues>
                                <enumeratedValue>
                                    <name>0</name>
                                    <description>GTCNT counter is not cleared</description>
                                    <value>#0</value>
                                </enumeratedValue>
                                <enumeratedValue>
                                    <name>1</name>
                                    <description>GTCNT counter is cleared</description>
                                    <value>#1</value>
                                </enumeratedValue>
                            </enumeratedValues>
                        </field>
                        <field>
                            <name>CCLR6</name>
                            <description>Channel n GTCNT Count Clear (n : the same as bit position value)</description>
                            <lsb>6</lsb>
                            <msb>6</msb>
                            <access>write-only</access>
                            <enumeratedValues>
                                <enumeratedValue>
                                    <name>0</name>
                                    <description>GTCNT counter is not cleared</description>
                                    <value>#0</value>
                                </enumeratedValue>
                                <enumeratedValue>
                                    <name>1</name>
                                    <description>GTCNT counter is cleared</description>
                                    <value>#1</value>
                                </enumeratedValue>
                            </enumeratedValues>
                        </field>
                        <field>
                            <name>CCLR7</name>
                            <description>Channel n GTCNT Count Clear (n : the same as bit position value)</description>
                            <lsb>7</lsb>
                            <msb>7</msb>
                            <access>write-only</access>
                            <enumeratedValues>
                                <enumeratedValue>
                                    <name>0</name>
                                    <description>GTCNT counter is not cleared</description>
                                    <value>#0</value>
                                </enumeratedValue>
                                <enumeratedValue>
                                    <name>1</name>
                                    <description>GTCNT counter is cleared</description>
                                    <value>#1</value>
                                </enumeratedValue>
                            </enumeratedValues>
                        </field>
                        <field>
                            <name>CCLR8</name>
                            <description>Channel n GTCNT Count Clear (n : the same as bit position value)</description>
                            <lsb>8</lsb>
                            <msb>8</msb>
                            <access>write-only</access>
                            <enumeratedValues>
                                <enumeratedValue>
                                    <name>0</name>
                                    <description>GTCNT counter is not cleared</description>
                                    <value>#0</value>
                                </enumeratedValue>
                                <enumeratedValue>
                                    <name>1</name>
                                    <description>GTCNT counter is cleared</description>
                                    <value>#1</value>
                                </enumeratedValue>
                            </enumeratedValues>
                        </field>
                        <field>
                            <name>CCLR9</name>
                            <description>Channel n GTCNT Count Clear (n : the same as bit position value)</description>
                            <lsb>9</lsb>
                            <msb>9</msb>
                            <access>write-only</access>
                            <enumeratedValues>
                                <enumeratedValue>
                                    <name>0</name>
                                    <description>GTCNT counter is not cleared</description>
                                    <value>#0</value>
                                </enumeratedValue>
                                <enumeratedValue>
                                    <name>1</name>
                                    <description>GTCNT counter is cleared</description>
                                    <value>#1</value>
                                </enumeratedValue>
                            </enumeratedValues>
                        </field>
                    </fields>
                </register>
                <register>
                    <name>GTSSR</name>
                    <description>General PWM Timer Start Source Select Register</description>
                    <addressOffset>0x10</addressOffset>
                    <size>32</size>
                    <access>read-write</access>
                    <resetValue>0x00000000</resetValue>
                    <resetMask>0xffffffff</resetMask>
                    <fields>
                        <field>
                            <name>SSGTRGAR</name>
                            <description>GTETRGA Pin Rising Input Source Counter Start Enable</description>
                            <lsb>0</lsb>
                            <msb>0</msb>
                            <access>read-write</access>
                            <enumeratedValues>
                                <enumeratedValue>
                                    <name>0</name>
                                    <description>Counter start disabled on the rising edge of GTETRGA input</description>
                                    <value>#0</value>
                                </enumeratedValue>
                                <enumeratedValue>
                                    <name>1</name>
                                    <description>Counter start enabled on the rising edge of GTETRGA input</description>
                                    <value>#1</value>
                                </enumeratedValue>
                            </enumeratedValues>
                        </field>
                        <field>
                            <name>SSGTRGAF</name>
                            <description>GTETRGA Pin Falling Input Source Counter Start Enable</description>
                            <lsb>1</lsb>
                            <msb>1</msb>
                            <access>read-write</access>
                            <enumeratedValues>
                                <enumeratedValue>
                                    <name>0</name>
                                    <description>Counter start disabled on the falling edge of GTETRGA input</description>
                                    <value>#0</value>
                                </enumeratedValue>
                                <enumeratedValue>
                                    <name>1</name>
                                    <description>Counter start enabled on the falling edge of GTETRGA input</description>
                                    <value>#1</value>
                                </enumeratedValue>
                            </enumeratedValues>
                        </field>
                        <field>
                            <name>SSGTRGBR</name>
                            <description>GTETRGB Pin Rising Input Source Counter Start Enable</description>
                            <lsb>2</lsb>
                            <msb>2</msb>
                            <access>read-write</access>
                            <enumeratedValues>
                                <enumeratedValue>
                                    <name>0</name>
                                    <description>Counter start disabled on the rising edge of GTETRGB input</description>
                                    <value>#0</value>
                                </enumeratedValue>
                                <enumeratedValue>
                                    <name>1</name>
                                    <description>Counter start enabled on the rising edge of GTETRGB input</description>
                                    <value>#1</value>
                                </enumeratedValue>
                            </enumeratedValues>
                        </field>
                        <field>
                            <name>SSGTRGBF</name>
                            <description>GTETRGB Pin Falling Input Source Counter Start Enable</description>
                            <lsb>3</lsb>
                            <msb>3</msb>
                            <access>read-write</access>
                            <enumeratedValues>
                                <enumeratedValue>
                                    <name>0</name>
                                    <description>Counter start disabled on the falling edge of GTETRGB input</description>
                                    <value>#0</value>
                                </enumeratedValue>
                                <enumeratedValue>
                                    <name>1</name>
                                    <description>Counter start enabled on the falling edge of GTETRGB input</description>
                                    <value>#1</value>
                                </enumeratedValue>
                            </enumeratedValues>
                        </field>
                        <field>
                            <name>SSGTRGCR</name>
                            <description>GTETRGC Pin Rising Input Source Counter Start Enable</description>
                            <lsb>4</lsb>
                            <msb>4</msb>
                            <access>read-write</access>
                            <enumeratedValues>
                                <enumeratedValue>
                                    <name>0</name>
                                    <description>Counter start disabled on the rising edge of GTETRGC input</description>
                                    <value>#0</value>
                                </enumeratedValue>
                                <enumeratedValue>
                                    <name>1</name>
                                    <description>Counter start enabled on the rising edge of GTETRGC input</description>
                                    <value>#1</value>
                                </enumeratedValue>
                            </enumeratedValues>
                        </field>
                        <field>
                            <name>SSGTRGCF</name>
                            <description>GTETRGC Pin Falling Input Source Counter Start Enable</description>
                            <lsb>5</lsb>
                            <msb>5</msb>
                            <access>read-write</access>
                            <enumeratedValues>
                                <enumeratedValue>
                                    <name>0</name>
                                    <description>Counter start disabled on the falling edge of GTETRGC input</description>
                                    <value>#0</value>
                                </enumeratedValue>
                                <enumeratedValue>
                                    <name>1</name>
                                    <description>Counter start enabled on the falling edge of GTETRGC input</description>
                                    <value>#1</value>
                                </enumeratedValue>
                            </enumeratedValues>
                        </field>
                        <field>
                            <name>SSGTRGDR</name>
                            <description>GTETRGD Pin Rising Input Source Counter Start Enable</description>
                            <lsb>6</lsb>
                            <msb>6</msb>
                            <access>read-write</access>
                            <enumeratedValues>
                                <enumeratedValue>
                                    <name>0</name>
                                    <description>Counter start disabled on the rising edge of GTETRGD input</description>
                                    <value>#0</value>
                                </enumeratedValue>
                                <enumeratedValue>
                                    <name>1</name>
                                    <description>Counter start enabled on the rising edge of GTETRGD input</description>
                                    <value>#1</value>
                                </enumeratedValue>
                            </enumeratedValues>
                        </field>
                        <field>
                            <name>SSGTRGDF</name>
                            <description>GTETRGD Pin Falling Input Source Counter Start Enable</description>
                            <lsb>7</lsb>
                            <msb>7</msb>
                            <access>read-write</access>
                            <enumeratedValues>
                                <enumeratedValue>
                                    <name>0</name>
                                    <description>Counter start disabled on the falling edge of GTETRGD input</description>
                                    <value>#0</value>
                                </enumeratedValue>
                                <enumeratedValue>
                                    <name>1</name>
                                    <description>Counter start enabled on the falling edge of GTETRGD input</description>
                                    <value>#1</value>
                                </enumeratedValue>
                            </enumeratedValues>
                        </field>
                        <field>
                            <name>SSCARBL</name>
                            <description>GTIOCnA Pin Rising Input during GTIOCnB Value Low Source Counter Start Enable</description>
                            <lsb>8</lsb>
                            <msb>8</msb>
                            <access>read-write</access>
                            <enumeratedValues>
                                <enumeratedValue>
                                    <name>0</name>
                                    <description>Counter start disabled on the rising edge of GTIOCnA input when GTIOCnB input is 0</description>
                                    <value>#0</value>
                                </enumeratedValue>
                                <enumeratedValue>
                                    <name>1</name>
                                    <description>Counter start enabled on the rising edge of GTIOCnA input when GTIOCnB input is 0</description>
                                    <value>#1</value>
                                </enumeratedValue>
                            </enumeratedValues>
                        </field>
                        <field>
                            <name>SSCARBH</name>
                            <description>GTIOCnA Pin Rising Input during GTIOCnB Value High Source Counter Start Enable</description>
                            <lsb>9</lsb>
                            <msb>9</msb>
                            <access>read-write</access>
                            <enumeratedValues>
                                <enumeratedValue>
                                    <name>0</name>
                                    <description>Counter start disabled on the rising edge of GTIOCnA input when GTIOCnB input is 1</description>
                                    <value>#0</value>
                                </enumeratedValue>
                                <enumeratedValue>
                                    <name>1</name>
                                    <description>Counter start enabled on the rising edge of GTIOCnA input when GTIOCnB input is 1</description>
                                    <value>#1</value>
                                </enumeratedValue>
                            </enumeratedValues>
                        </field>
                        <field>
                            <name>SSCAFBL</name>
                            <description>GTIOCnA Pin Falling Input during GTIOCnB Value Low Source Counter Start Enable</description>
                            <lsb>10</lsb>
                            <msb>10</msb>
                            <access>read-write</access>
                            <enumeratedValues>
                                <enumeratedValue>
                                    <name>0</name>
                                    <description>Counter start disabled on the falling edge of GTIOCnA input when GTIOCnB input is 0</description>
                                    <value>#0</value>
                                </enumeratedValue>
                                <enumeratedValue>
                                    <name>1</name>
                                    <description>Counter start enabled on the falling edge of GTIOCnA input when GTIOCnB input is 0</description>
                                    <value>#1</value>
                                </enumeratedValue>
                            </enumeratedValues>
                        </field>
                        <field>
                            <name>SSCAFBH</name>
                            <description>GTIOCnA Pin Falling Input during GTIOCnB Value High Source Counter Start Enable</description>
                            <lsb>11</lsb>
                            <msb>11</msb>
                            <access>read-write</access>
                            <enumeratedValues>
                                <enumeratedValue>
                                    <name>0</name>
                                    <description>Counter start disabled on the falling edge of GTIOCnA input when GTIOCnB input is 1</description>
                                    <value>#0</value>
                                </enumeratedValue>
                                <enumeratedValue>
                                    <name>1</name>
                                    <description>Counter start enabled on the falling edge of GTIOCnA input when GTIOCnB input is 1</description>
                                    <value>#1</value>
                                </enumeratedValue>
                            </enumeratedValues>
                        </field>
                        <field>
                            <name>SSCBRAL</name>
                            <description>GTIOCnB Pin Rising Input during GTIOCnA Value Low Source Counter Start Enable</description>
                            <lsb>12</lsb>
                            <msb>12</msb>
                            <access>read-write</access>
                            <enumeratedValues>
                                <enumeratedValue>
                                    <name>0</name>
                                    <description>Counter start disabled on the rising edge of GTIOCnB input when GTIOCnA input is 0</description>
                                    <value>#0</value>
                                </enumeratedValue>
                                <enumeratedValue>
                                    <name>1</name>
                                    <description>Counter start enabled on the rising edge of GTIOCnB input when GTIOCnA input is 0</description>
                                    <value>#1</value>
                                </enumeratedValue>
                            </enumeratedValues>
                        </field>
                        <field>
                            <name>SSCBRAH</name>
                            <description>GTIOCnB Pin Rising Input during GTIOCnA Value High Source Counter Start Enable</description>
                            <lsb>13</lsb>
                            <msb>13</msb>
                            <access>read-write</access>
                            <enumeratedValues>
                                <enumeratedValue>
                                    <name>0</name>
                                    <description>Counter start disabled on the rising edge of GTIOCnB input when GTIOCnA input is 1</description>
                                    <value>#0</value>
                                </enumeratedValue>
                                <enumeratedValue>
                                    <name>1</name>
                                    <description>Counter start enabled on the rising edge of GTIOCnB input when GTIOCnA input is 1</description>
                                    <value>#1</value>
                                </enumeratedValue>
                            </enumeratedValues>
                        </field>
                        <field>
                            <name>SSCBFAL</name>
                            <description>GTIOCnB Pin Falling Input during GTIOCnA Value Low Source Counter Start Enable</description>
                            <lsb>14</lsb>
                            <msb>14</msb>
                            <access>read-write</access>
                            <enumeratedValues>
                                <enumeratedValue>
                                    <name>0</name>
                                    <description>Counter start disabled on the falling edge of GTIOCnB input when GTIOCnA input is 0</description>
                                    <value>#0</value>
                                </enumeratedValue>
                                <enumeratedValue>
                                    <name>1</name>
                                    <description>Counter start enabled on the falling edge of GTIOCnB input when GTIOCnA input is 0</description>
                                    <value>#1</value>
                                </enumeratedValue>
                            </enumeratedValues>
                        </field>
                        <field>
                            <name>SSCBFAH</name>
                            <description>GTIOCnB Pin Falling Input during GTIOCnA Value High Source Counter Start Enable</description>
                            <lsb>15</lsb>
                            <msb>15</msb>
                            <access>read-write</access>
                            <enumeratedValues>
                                <enumeratedValue>
                                    <name>0</name>
                                    <description>Counter start disabled on the falling edge of GTIOCnB input when GTIOCnA input is 1</description>
                                    <value>#0</value>
                                </enumeratedValue>
                                <enumeratedValue>
                                    <name>1</name>
                                    <description>Counter start enabled on the falling edge of GTIOCnB input when GTIOCnA input is 1</description>
                                    <value>#1</value>
                                </enumeratedValue>
                            </enumeratedValues>
                        </field>
                        <field>
                            <name>SSELCA</name>
                            <description>ELC_GPTA Event Source Counter Start Enable</description>
                            <lsb>16</lsb>
                            <msb>16</msb>
                            <access>read-write</access>
                            <enumeratedValues>
                                <enumeratedValue>
                                    <name>0</name>
                                    <description>Counter start disabled at the ELC_GPTA input</description>
                                    <value>#0</value>
                                </enumeratedValue>
                                <enumeratedValue>
                                    <name>1</name>
                                    <description>Counter start enabled at the ELC_GPTA input</description>
                                    <value>#1</value>
                                </enumeratedValue>
                            </enumeratedValues>
                        </field>
                        <field>
                            <name>SSELCB</name>
                            <description>ELC_GPTB Event Source Counter Start Enable</description>
                            <lsb>17</lsb>
                            <msb>17</msb>
                            <access>read-write</access>
                            <enumeratedValues>
                                <enumeratedValue>
                                    <name>0</name>
                                    <description>Counter start disabled at the ELC_GPTB input</description>
                                    <value>#0</value>
                                </enumeratedValue>
                                <enumeratedValue>
                                    <name>1</name>
                                    <description>Counter start enabled at the ELC_GPTB input</description>
                                    <value>#1</value>
                                </enumeratedValue>
                            </enumeratedValues>
                        </field>
                        <field>
                            <name>SSELCC</name>
                            <description>ELC_GPTC Event Source Counter Start Enable</description>
                            <lsb>18</lsb>
                            <msb>18</msb>
                            <access>read-write</access>
                            <enumeratedValues>
                                <enumeratedValue>
                                    <name>0</name>
                                    <description>Counter start disabled at the ELC_GPTC input</description>
                                    <value>#0</value>
                                </enumeratedValue>
                                <enumeratedValue>
                                    <name>1</name>
                                    <description>Counter start enabled at the ELC_GPTC input</description>
                                    <value>#1</value>
                                </enumeratedValue>
                            </enumeratedValues>
                        </field>
                        <field>
                            <name>SSELCD</name>
                            <description>ELC_GPTD Event Source Counter Start Enable</description>
                            <lsb>19</lsb>
                            <msb>19</msb>
                            <access>read-write</access>
                            <enumeratedValues>
                                <enumeratedValue>
                                    <name>0</name>
                                    <description>Counter start disabled at the ELC_GPTD input</description>
                                    <value>#0</value>
                                </enumeratedValue>
                                <enumeratedValue>
                                    <name>1</name>
                                    <description>Counter start enabled at the ELC_GPTD input</description>
                                    <value>#1</value>
                                </enumeratedValue>
                            </enumeratedValues>
                        </field>
                        <field>
                            <name>SSELCE</name>
                            <description>ELC_GPTE Event Source Counter Start Enable</description>
                            <lsb>20</lsb>
                            <msb>20</msb>
                            <access>read-write</access>
                            <enumeratedValues>
                                <enumeratedValue>
                                    <name>0</name>
                                    <description>Counter start disabled at the ELC_GPTE input</description>
                                    <value>#0</value>
                                </enumeratedValue>
                                <enumeratedValue>
                                    <name>1</name>
                                    <description>Counter start enabled at the ELC_GPTE input</description>
                                    <value>#1</value>
                                </enumeratedValue>
                            </enumeratedValues>
                        </field>
                        <field>
                            <name>SSELCF</name>
                            <description>ELC_GPTF Event Source Counter Start Enable</description>
                            <lsb>21</lsb>
                            <msb>21</msb>
                            <access>read-write</access>
                            <enumeratedValues>
                                <enumeratedValue>
                                    <name>0</name>
                                    <description>Counter start disabled at the ELC_GPTF input</description>
                                    <value>#0</value>
                                </enumeratedValue>
                                <enumeratedValue>
                                    <name>1</name>
                                    <description>Counter start enabled at the ELC_GPTF input</description>
                                    <value>#1</value>
                                </enumeratedValue>
                            </enumeratedValues>
                        </field>
                        <field>
                            <name>SSELCG</name>
                            <description>ELC_GPTG Event Source Counter Start Enable</description>
                            <lsb>22</lsb>
                            <msb>22</msb>
                            <access>read-write</access>
                            <enumeratedValues>
                                <enumeratedValue>
                                    <name>0</name>
                                    <description>Counter start disabled at the ELC_GPTG input</description>
                                    <value>#0</value>
                                </enumeratedValue>
                                <enumeratedValue>
                                    <name>1</name>
                                    <description>Counter start enabled at the ELC_GPTG input</description>
                                    <value>#1</value>
                                </enumeratedValue>
                            </enumeratedValues>
                        </field>
                        <field>
                            <name>SSELCH</name>
                            <description>ELC_GPTH Event Source Counter Start Enable</description>
                            <lsb>23</lsb>
                            <msb>23</msb>
                            <access>read-write</access>
                            <enumeratedValues>
                                <enumeratedValue>
                                    <name>0</name>
                                    <description>Counter start disabled at the ELC_GPTH input</description>
                                    <value>#0</value>
                                </enumeratedValue>
                                <enumeratedValue>
                                    <name>1</name>
                                    <description>Counter start enabled at the ELC_GPTH input</description>
                                    <value>#1</value>
                                </enumeratedValue>
                            </enumeratedValues>
                        </field>
                        <field>
                            <name>CSTRT</name>
                            <description>Software Source Counter Start Enable</description>
                            <lsb>31</lsb>
                            <msb>31</msb>
                            <access>read-write</access>
                            <enumeratedValues>
                                <enumeratedValue>
                                    <name>0</name>
                                    <description>Counter start disabled by the GTSTR register</description>
                                    <value>#0</value>
                                </enumeratedValue>
                                <enumeratedValue>
                                    <name>1</name>
                                    <description>Counter start enabled by the GTSTR register</description>
                                    <value>#1</value>
                                </enumeratedValue>
                            </enumeratedValues>
                        </field>
                    </fields>
                </register>
                <register>
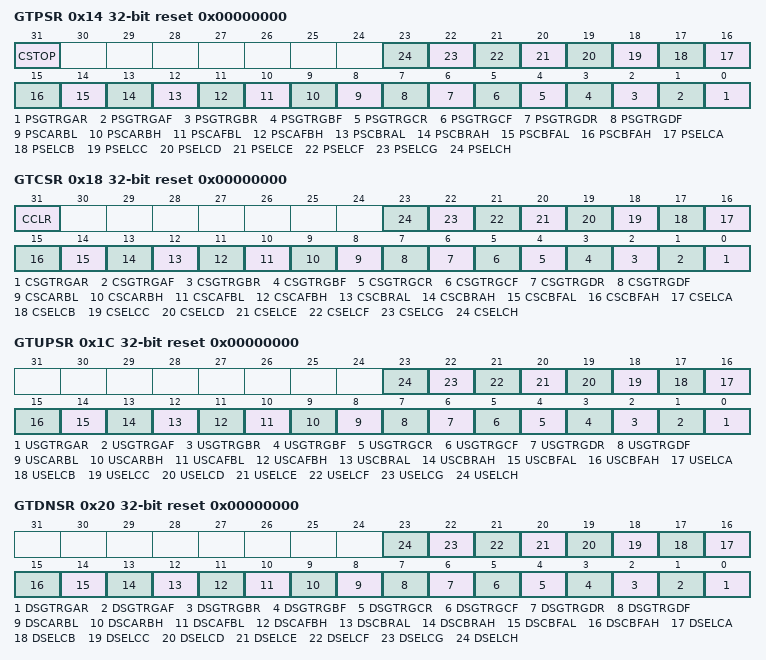
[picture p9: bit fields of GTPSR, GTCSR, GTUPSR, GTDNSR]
                    <name>GTPSR</name>
                    <description>General PWM Timer Stop Source Select Register</description>
                    <addressOffset>0x14</addressOffset>
                    <size>32</size>
                    <access>read-write</access>
                    <resetValue>0x00000000</resetValue>
                    <resetMask>0xffffffff</resetMask>
                    <fields>
                        <field>
                            <name>PSGTRGAR</name>
                            <description>GTETRGA Pin Rising Input Source Counter Stop Enable</description>
                            <lsb>0</lsb>
                            <msb>0</msb>
                            <access>read-write</access>
                            <enumeratedValues>
                                <enumeratedValue>
                                    <name>0</name>
                                    <description>Counter stop disabled on the rising edge of GTETRGA input</description>
                                    <value>#0</value>
                                </enumeratedValue>
                                <enumeratedValue>
                                    <name>1</name>
                                    <description>Counter stop enabled on the rising edge of GTETRGA input</description>
                                    <value>#1</value>
                                </enumeratedValue>
                            </enumeratedValues>
                        </field>
                        <field>
                            <name>PSGTRGAF</name>
                            <description>GTETRGA Pin Falling Input Source Counter Stop Enable</description>
                            <lsb>1</lsb>
                            <msb>1</msb>
                            <access>read-write</access>
                            <enumeratedValues>
                                <enumeratedValue>
                                    <name>0</name>
                                    <description>Counter stop disabled on the falling edge of GTETRGA input</description>
                                    <value>#0</value>
                                </enumeratedValue>
                                <enumeratedValue>
                                    <name>1</name>
                                    <description>Counter stop enabled on the falling edge of GTETRGA input</description>
                                    <value>#1</value>
                                </enumeratedValue>
                            </enumeratedValues>
                        </field>
                        <field>
                            <name>PSGTRGBR</name>
                            <description>GTETRGB Pin Rising Input Source Counter Stop Enable</description>
                            <lsb>2</lsb>
                            <msb>2</msb>
                            <access>read-write</access>
                            <enumeratedValues>
                                <enumeratedValue>
                                    <name>0</name>
                                    <description>Counter stop disabled on the rising edge of GTETRGB input</description>
                                    <value>#0</value>
                                </enumeratedValue>
                                <enumeratedValue>
                                    <name>1</name>
                                    <description>Counter stop enabled on the rising edge of GTETRGB input</description>
                                    <value>#1</value>
                                </enumeratedValue>
                            </enumeratedValues>
                        </field>
                        <field>
                            <name>PSGTRGBF</name>
                            <description>GTETRGB Pin Falling Input Source Counter Stop Enable</description>
                            <lsb>3</lsb>
                            <msb>3</msb>
                            <access>read-write</access>
                            <enumeratedValues>
                                <enumeratedValue>
                                    <name>0</name>
                                    <description>Counter stop disabled on the falling edge of GTETRGB input</description>
                                    <value>#0</value>
                                </enumeratedValue>
                                <enumeratedValue>
                                    <name>1</name>
                                    <description>Counter stop enabled on the falling edge of GTETRGB input</description>
                                    <value>#1</value>
                                </enumeratedValue>
                            </enumeratedValues>
                        </field>
                        <field>
                            <name>PSGTRGCR</name>
                            <description>GTETRGC Pin Rising Input Source Counter Stop Enable</description>
                            <lsb>4</lsb>
                            <msb>4</msb>
                            <access>read-write</access>
                            <enumeratedValues>
                                <enumeratedValue>
                                    <name>0</name>
                                    <description>Counter stop disabled on the rising edge of GTETRGC input</description>
                                    <value>#0</value>
                                </enumeratedValue>
                                <enumeratedValue>
                                    <name>1</name>
                                    <description>Counter stop enabled on the rising edge of GTETRGC input</description>
                                    <value>#1</value>
                                </enumeratedValue>
                            </enumeratedValues>
                        </field>
                        <field>
                            <name>PSGTRGCF</name>
                            <description>GTETRGC Pin Falling Input Source Counter Stop Enable</description>
                            <lsb>5</lsb>
                            <msb>5</msb>
                            <access>read-write</access>
                            <enumeratedValues>
                                <enumeratedValue>
                                    <name>0</name>
                                    <description>Counter stop disabled on the falling edge of GTETRGC input</description>
                                    <value>#0</value>
                                </enumeratedValue>
                                <enumeratedValue>
                                    <name>1</name>
                                    <description>Counter stop enabled on the falling edge of GTETRGC input</description>
                                    <value>#1</value>
                                </enumeratedValue>
                            </enumeratedValues>
                        </field>
                        <field>
                            <name>PSGTRGDR</name>
                            <description>GTETRGD Pin Rising Input Source Counter Stop Enable</description>
                            <lsb>6</lsb>
                            <msb>6</msb>
                            <access>read-write</access>
                            <enumeratedValues>
                                <enumeratedValue>
                                    <name>0</name>
                                    <description>Counter stop disabled on the rising edge of GTETRGD input</description>
                                    <value>#0</value>
                                </enumeratedValue>
                                <enumeratedValue>
                                    <name>1</name>
                                    <description>Counter stop enabled on the rising edge of GTETRGD input</description>
                                    <value>#1</value>
                                </enumeratedValue>
                            </enumeratedValues>
                        </field>
                        <field>
                            <name>PSGTRGDF</name>
                            <description>GTETRGD Pin Falling Input Source Counter Stop Enable</description>
                            <lsb>7</lsb>
                            <msb>7</msb>
                            <access>read-write</access>
                            <enumeratedValues>
                                <enumeratedValue>
                                    <name>0</name>
                                    <description>Counter stop disabled on the falling edge of GTETRGD input</description>
                                    <value>#0</value>
                                </enumeratedValue>
                                <enumeratedValue>
                                    <name>1</name>
                                    <description>Counter stop enabled on the falling edge of GTETRGD input</description>
                                    <value>#1</value>
                                </enumeratedValue>
                            </enumeratedValues>
                        </field>
                        <field>
                            <name>PSCARBL</name>
                            <description>GTIOCnA Pin Rising Input during GTIOCnB Value Low Source Counter Stop Enable</description>
                            <lsb>8</lsb>
                            <msb>8</msb>
                            <access>read-write</access>
                            <enumeratedValues>
                                <enumeratedValue>
                                    <name>0</name>
                                    <description>Counter stop disabled on the rising edge of GTIOCnA input when GTIOCnB input is 0</description>
                                    <value>#0</value>
                                </enumeratedValue>
                                <enumeratedValue>
                                    <name>1</name>
                                    <description>Counter stop enabled on the rising edge of GTIOCnA input when GTIOCnB input is 0</description>
                                    <value>#1</value>
                                </enumeratedValue>
                            </enumeratedValues>
                        </field>
                        <field>
                            <name>PSCARBH</name>
                            <description>GTIOCnA Pin Rising Input during GTIOCnB Value High Source Counter Stop Enable</description>
                            <lsb>9</lsb>
                            <msb>9</msb>
                            <access>read-write</access>
                            <enumeratedValues>
                                <enumeratedValue>
                                    <name>0</name>
                                    <description>Counter stop disabled on the rising edge of GTIOCnA input when GTIOCnB input is 1</description>
                                    <value>#0</value>
                                </enumeratedValue>
                                <enumeratedValue>
                                    <name>1</name>
                                    <description>Counter stop enabled on the rising edge of GTIOCnA input when GTIOCnB input is 1</description>
                                    <value>#1</value>
                                </enumeratedValue>
                            </enumeratedValues>
                        </field>
                        <field>
                            <name>PSCAFBL</name>
                            <description>GTIOCnA Pin Falling Input during GTIOCnB Value Low Source Counter Stop Enable</description>
                            <lsb>10</lsb>
                            <msb>10</msb>
                            <access>read-write</access>
                            <enumeratedValues>
                                <enumeratedValue>
                                    <name>0</name>
                                    <description>Counter stop disabled on the falling edge of GTIOCnA input when GTIOCnB input is 0</description>
                                    <value>#0</value>
                                </enumeratedValue>
                                <enumeratedValue>
                                    <name>1</name>
                                    <description>Counter stop enabled on the falling edge of GTIOCnA input when GTIOCnB input is 0</description>
                                    <value>#1</value>
                                </enumeratedValue>
                            </enumeratedValues>
                        </field>
                        <field>
                            <name>PSCAFBH</name>
                            <description>GTIOCnA Pin Falling Input during GTIOCnB Value High Source Counter Stop Enable</description>
                            <lsb>11</lsb>
                            <msb>11</msb>
                            <access>read-write</access>
                            <enumeratedValues>
                                <enumeratedValue>
                                    <name>0</name>
                                    <description>Counter stop disabled on the falling edge of GTIOCnA input when GTIOCnB input is 1</description>
                                    <value>#0</value>
                                </enumeratedValue>
                                <enumeratedValue>
                                    <name>1</name>
                                    <description>Counter stop enabled on the falling edge of GTIOCnA input when GTIOCnB input is 1</description>
                                    <value>#1</value>
                                </enumeratedValue>
                            </enumeratedValues>
                        </field>
                        <field>
                            <name>PSCBRAL</name>
                            <description>GTIOCnB Pin Rising Input during GTIOCnA Value Low Source Counter Stop Enable</description>
                            <lsb>12</lsb>
                            <msb>12</msb>
                            <access>read-write</access>
                            <enumeratedValues>
                                <enumeratedValue>
                                    <name>0</name>
                                    <description>Counter stop disabled on the rising edge of GTIOCnB input when GTIOCnA input is 0</description>
                                    <value>#0</value>
                                </enumeratedValue>
                                <enumeratedValue>
                                    <name>1</name>
                                    <description>Counter stop enabled on the rising edge of GTIOCnB input when GTIOCnA input is 0</description>
                                    <value>#1</value>
                                </enumeratedValue>
                            </enumeratedValues>
                        </field>
                        <field>
                            <name>PSCBRAH</name>
                            <description>GTIOCnB Pin Rising Input during GTIOCnA Value High Source Counter Stop Enable</description>
                            <lsb>13</lsb>
                            <msb>13</msb>
                            <access>read-write</access>
                            <enumeratedValues>
                                <enumeratedValue>
                                    <name>0</name>
                                    <description>Counter stop disabled on the rising edge of GTIOCnB input when GTIOCnA input is 1</description>
                                    <value>#0</value>
                                </enumeratedValue>
                                <enumeratedValue>
                                    <name>1</name>
                                    <description>Counter stop enabled on the rising edge of GTIOCnB input when GTIOCnA input is 1</description>
                                    <value>#1</value>
                                </enumeratedValue>
                            </enumeratedValues>
                        </field>
                        <field>
                            <name>PSCBFAL</name>
                            <description>GTIOCnB Pin Falling Input during GTIOCnA Value Low Source Counter Stop Enable</description>
                            <lsb>14</lsb>
                            <msb>14</msb>
                            <access>read-write</access>
                            <enumeratedValues>
                                <enumeratedValue>
                                    <name>0</name>
                                    <description>Counter stop disabled on the falling edge of GTIOCnB input when GTIOCnA input is 0</description>
                                    <value>#0</value>
                                </enumeratedValue>
                                <enumeratedValue>
                                    <name>1</name>
                                    <description>Counter stop enabled on the falling edge of GTIOCnB input when GTIOCnA input is 0</description>
                                    <value>#1</value>
                                </enumeratedValue>
                            </enumeratedValues>
                        </field>
                        <field>
                            <name>PSCBFAH</name>
                            <description>GTIOCnB Pin Falling Input during GTIOCnA Value High Source Counter Stop Enable</description>
                            <lsb>15</lsb>
                            <msb>15</msb>
                            <access>read-write</access>
                            <enumeratedValues>
                                <enumeratedValue>
                                    <name>0</name>
                                    <description>Counter stop disabled on the falling edge of GTIOCnB input when GTIOCnA input is 1</description>
                                    <value>#0</value>
                                </enumeratedValue>
                                <enumeratedValue>
                                    <name>1</name>
                                    <description>Counter stop enabled on the falling edge of GTIOCnB input when GTIOCnA input is 1</description>
                                    <value>#1</value>
                                </enumeratedValue>
                            </enumeratedValues>
                        </field>
                        <field>
                            <name>PSELCA</name>
                            <description>ELC_GPTA Event Source Counter Stop Enable</description>
                            <lsb>16</lsb>
                            <msb>16</msb>
                            <access>read-write</access>
                            <enumeratedValues>
                                <enumeratedValue>
                                    <name>0</name>
                                    <description>Counter stop disabled at the ELC_GPTA input</description>
                                    <value>#0</value>
                                </enumeratedValue>
                                <enumeratedValue>
                                    <name>1</name>
                                    <description>Counter stop enabled at the ELC_GPTA input</description>
                                    <value>#1</value>
                                </enumeratedValue>
                            </enumeratedValues>
                        </field>
                        <field>
                            <name>PSELCB</name>
                            <description>ELC_GPTB Event Source Counter Stop Enable</description>
                            <lsb>17</lsb>
                            <msb>17</msb>
                            <access>read-write</access>
                            <enumeratedValues>
                                <enumeratedValue>
                                    <name>0</name>
                                    <description>Counter stop disabled at the ELC_GPTB input</description>
                                    <value>#0</value>
                                </enumeratedValue>
                                <enumeratedValue>
                                    <name>1</name>
                                    <description>Counter stop enabled at the ELC_GPTB input</description>
                                    <value>#1</value>
                                </enumeratedValue>
                            </enumeratedValues>
                        </field>
                        <field>
                            <name>PSELCC</name>
                            <description>ELC_GPTC Event Source Counter Stop Enable</description>
                            <lsb>18</lsb>
                            <msb>18</msb>
                            <access>read-write</access>
                            <enumeratedValues>
                                <enumeratedValue>
                                    <name>0</name>
                                    <description>Counter stop disabled at the ELC_GPTC input</description>
                                    <value>#0</value>
                                </enumeratedValue>
                                <enumeratedValue>
                                    <name>1</name>
                                    <description>Counter stop enabled at the ELC_GPTC input</description>
                                    <value>#1</value>
                                </enumeratedValue>
                            </enumeratedValues>
                        </field>
                        <field>
                            <name>PSELCD</name>
                            <description>ELC_GPTD Event Source Counter Stop Enable</description>
                            <lsb>19</lsb>
                            <msb>19</msb>
                            <access>read-write</access>
                            <enumeratedValues>
                                <enumeratedValue>
                                    <name>0</name>
                                    <description>Counter stop disabled at the ELC_GPTD input</description>
                                    <value>#0</value>
                                </enumeratedValue>
                                <enumeratedValue>
                                    <name>1</name>
                                    <description>Counter stop enabled at the ELC_GPTD input</description>
                                    <value>#1</value>
                                </enumeratedValue>
                            </enumeratedValues>
                        </field>
                        <field>
                            <name>PSELCE</name>
                            <description>ELC_GPTE Event Source Counter Stop Enable</description>
                            <lsb>20</lsb>
                            <msb>20</msb>
                            <access>read-write</access>
                            <enumeratedValues>
                                <enumeratedValue>
                                    <name>0</name>
                                    <description>Counter stop disabled at the ELC_GPTE input</description>
                                    <value>#0</value>
                                </enumeratedValue>
                                <enumeratedValue>
                                    <name>1</name>
                                    <description>Counter stop enabled at the ELC_GPTE input</description>
                                    <value>#1</value>
                                </enumeratedValue>
                            </enumeratedValues>
                        </field>
                        <field>
                            <name>PSELCF</name>
                            <description>ELC_GPTF Event Source Counter Stop Enable</description>
                            <lsb>21</lsb>
                            <msb>21</msb>
                            <access>read-write</access>
                            <enumeratedValues>
                                <enumeratedValue>
                                    <name>0</name>
                                    <description>Counter stop disabled at the ELC_GPTF input</description>
                                    <value>#0</value>
                                </enumeratedValue>
                                <enumeratedValue>
                                    <name>1</name>
                                    <description>Counter stop enabled at the ELC_GPTF input</description>
                                    <value>#1</value>
                                </enumeratedValue>
                            </enumeratedValues>
                        </field>
                        <field>
                            <name>PSELCG</name>
                            <description>ELC_GPTG Event Source Counter Stop Enable</description>
                            <lsb>22</lsb>
                            <msb>22</msb>
                            <access>read-write</access>
                            <enumeratedValues>
                                <enumeratedValue>
                                    <name>0</name>
                                    <description>Counter stop disabled at the ELC_GPTG input</description>
                                    <value>#0</value>
                                </enumeratedValue>
                                <enumeratedValue>
                                    <name>1</name>
                                    <description>Counter stop enabled at the ELC_GPTG input</description>
                                    <value>#1</value>
                                </enumeratedValue>
                            </enumeratedValues>
                        </field>
                        <field>
                            <name>PSELCH</name>
                            <description>ELC_GPTH Event Source Counter Stop Enable</description>
                            <lsb>23</lsb>
                            <msb>23</msb>
                            <access>read-write</access>
                            <enumeratedValues>
                                <enumeratedValue>
                                    <name>0</name>
                                    <description>Counter stop disabled at the ELC_GPTH input</description>
                                    <value>#0</value>
                                </enumeratedValue>
                                <enumeratedValue>
                                    <name>1</name>
                                    <description>Counter stop enabled at the ELC_GPTH input</description>
                                    <value>#1</value>
                                </enumeratedValue>
                            </enumeratedValues>
                        </field>
                        <field>
                            <name>CSTOP</name>
                            <description>Software Source Counter Stop Enable</description>
                            <lsb>31</lsb>
                            <msb>31</msb>
                            <access>read-write</access>
                            <enumeratedValues>
                                <enumeratedValue>
                                    <name>0</name>
                                    <description>Counter stop disabled by the GTSTP register</description>
                                    <value>#0</value>
                                </enumeratedValue>
                                <enumeratedValue>
                                    <name>1</name>
                                    <description>Counter stop enabled by the GTSTP register</description>
                                    <value>#1</value>
                                </enumeratedValue>
                            </enumeratedValues>
                        </field>
                    </fields>
                </register>
                <register>
                    <name>GTCSR</name>
                    <description>General PWM Timer Clear Source Select Register</description>
                    <addressOffset>0x18</addressOffset>
                    <size>32</size>
                    <access>read-write</access>
                    <resetValue>0x00000000</resetValue>
                    <resetMask>0xffffffff</resetMask>
                    <fields>
                        <field>
                            <name>CSGTRGAR</name>
                            <description>GTETRGA Pin Rising Input Source Counter Clear Enable</description>
                            <lsb>0</lsb>
                            <msb>0</msb>
                            <access>read-write</access>
                            <enumeratedValues>
                                <enumeratedValue>
                                    <name>0</name>
                                    <description>Counter clear disabled on the rising edge of GTETRGA input</description>
                                    <value>#0</value>
                                </enumeratedValue>
                                <enumeratedValue>
                                    <name>1</name>
                                    <description>Counter clear enabled on the rising edge of GTETRGA input</description>
                                    <value>#1</value>
                                </enumeratedValue>
                            </enumeratedValues>
                        </field>
                        <field>
                            <name>CSGTRGAF</name>
                            <description>GTETRGA Pin Falling Input Source Counter Clear Enable</description>
                            <lsb>1</lsb>
                            <msb>1</msb>
                            <access>read-write</access>
                            <enumeratedValues>
                                <enumeratedValue>
                                    <name>0</name>
                                    <description>Counter clear disabled on the falling edge of GTETRGA input</description>
                                    <value>#0</value>
                                </enumeratedValue>
                                <enumeratedValue>
                                    <name>1</name>
                                    <description>Counter clear enabled on the falling edge of GTETRGA input</description>
                                    <value>#1</value>
                                </enumeratedValue>
                            </enumeratedValues>
                        </field>
                        <field>
                            <name>CSGTRGBR</name>
                            <description>GTETRGB Pin Rising Input Source Counter Clear Enable</description>
                            <lsb>2</lsb>
                            <msb>2</msb>
                            <access>read-write</access>
                            <enumeratedValues>
                                <enumeratedValue>
                                    <name>0</name>
                                    <description>Disable counter clear on the rising edge of GTETRGB input</description>
                                    <value>#0</value>
                                </enumeratedValue>
                                <enumeratedValue>
                                    <name>1</name>
                                    <description>Enable counter clear on the rising edge of GTETRGB input</description>
                                    <value>#1</value>
                                </enumeratedValue>
                            </enumeratedValues>
                        </field>
                        <field>
                            <name>CSGTRGBF</name>
                            <description>GTETRGB Pin Falling Input Source Counter Clear Enable</description>
                            <lsb>3</lsb>
                            <msb>3</msb>
                            <access>read-write</access>
                            <enumeratedValues>
                                <enumeratedValue>
                                    <name>0</name>
                                    <description>Counter clear disabled on the falling edge of GTETRGB input</description>
                                    <value>#0</value>
                                </enumeratedValue>
                                <enumeratedValue>
                                    <name>1</name>
                                    <description>Counter clear enabled on the falling edge of GTETRGB input</description>
                                    <value>#1</value>
                                </enumeratedValue>
                            </enumeratedValues>
                        </field>
                        <field>
                            <name>CSGTRGCR</name>
                            <description>GTETRGC Pin Rising Input Source Counter Clear Enable</description>
                            <lsb>4</lsb>
                            <msb>4</msb>
                            <access>read-write</access>
                            <enumeratedValues>
                                <enumeratedValue>
                                    <name>0</name>
                                    <description>Disable counter clear on the rising edge of GTETRGC input</description>
                                    <value>#0</value>
                                </enumeratedValue>
                                <enumeratedValue>
                                    <name>1</name>
                                    <description>Enable counter clear on the rising edge of GTETRGC input</description>
                                    <value>#1</value>
                                </enumeratedValue>
                            </enumeratedValues>
                        </field>
                        <field>
                            <name>CSGTRGCF</name>
                            <description>GTETRGC Pin Falling Input Source Counter Clear Enable</description>
                            <lsb>5</lsb>
                            <msb>5</msb>
                            <access>read-write</access>
                            <enumeratedValues>
                                <enumeratedValue>
                                    <name>0</name>
                                    <description>Counter clear disabled on the falling edge of GTETRGC input</description>
                                    <value>#0</value>
                                </enumeratedValue>
                                <enumeratedValue>
                                    <name>1</name>
                                    <description>Counter clear enabled on the falling edge of GTETRGC input</description>
                                    <value>#1</value>
                                </enumeratedValue>
                            </enumeratedValues>
                        </field>
                        <field>
                            <name>CSGTRGDR</name>
                            <description>GTETRGD Pin Rising Input Source Counter Clear Enable</description>
                            <lsb>6</lsb>
                            <msb>6</msb>
                            <access>read-write</access>
                            <enumeratedValues>
                                <enumeratedValue>
                                    <name>0</name>
                                    <description>Disable counter clear on the rising edge of GTETRGD input</description>
                                    <value>#0</value>
                                </enumeratedValue>
                                <enumeratedValue>
                                    <name>1</name>
                                    <description>Enable counter clear on the rising edge of GTETRGD input</description>
                                    <value>#1</value>
                                </enumeratedValue>
                            </enumeratedValues>
                        </field>
                        <field>
                            <name>CSGTRGDF</name>
                            <description>GTETRGD Pin Falling Input Source Counter Clear Enable</description>
                            <lsb>7</lsb>
                            <msb>7</msb>
                            <access>read-write</access>
                            <enumeratedValues>
                                <enumeratedValue>
                                    <name>0</name>
                                    <description>Counter clear disabled on the falling edge of GTETRGD input</description>
                                    <value>#0</value>
                                </enumeratedValue>
                                <enumeratedValue>
                                    <name>1</name>
                                    <description>Counter clear enabled on the falling edge of GTETRGD input</description>
                                    <value>#1</value>
                                </enumeratedValue>
                            </enumeratedValues>
                        </field>
                        <field>
                            <name>CSCARBL</name>
                            <description>GTIOCnA Pin Rising Input during GTIOCnB Value Low Source Counter Clear Enable</description>
                            <lsb>8</lsb>
                            <msb>8</msb>
                            <access>read-write</access>
                            <enumeratedValues>
                                <enumeratedValue>
                                    <name>0</name>
                                    <description>Counter clear disabled on the rising edge of GTIOCnA input when GTIOCnB input is 0</description>
                                    <value>#0</value>
                                </enumeratedValue>
                                <enumeratedValue>
                                    <name>1</name>
                                    <description>Counter clear enabled on the rising edge of GTIOCnA input when GTIOCnB input is 0</description>
                                    <value>#1</value>
                                </enumeratedValue>
                            </enumeratedValues>
                        </field>
                        <field>
                            <name>CSCARBH</name>
                            <description>GTIOCnA Pin Rising Input during GTIOCnB Value High Source Counter Clear Enable</description>
                            <lsb>9</lsb>
                            <msb>9</msb>
                            <access>read-write</access>
                            <enumeratedValues>
                                <enumeratedValue>
                                    <name>0</name>
                                    <description>Counter clear disabled on the rising edge of GTIOCnA input when GTIOCnB input is 1</description>
                                    <value>#0</value>
                                </enumeratedValue>
                                <enumeratedValue>
                                    <name>1</name>
                                    <description>Counter clear enabled on the rising edge of GTIOCnA input when GTIOCnB input is 1</description>
                                    <value>#1</value>
                                </enumeratedValue>
                            </enumeratedValues>
                        </field>
                        <field>
                            <name>CSCAFBL</name>
                            <description>GTIOCnA Pin Falling Input during GTIOCnB Value Low Source Counter Clear Enable</description>
                            <lsb>10</lsb>
                            <msb>10</msb>
                            <access>read-write</access>
                            <enumeratedValues>
                                <enumeratedValue>
                                    <name>0</name>
                                    <description>Counter clear disabled on the falling edge of GTIOCnA input when GTIOCnB input is 0</description>
                                    <value>#0</value>
                                </enumeratedValue>
                                <enumeratedValue>
                                    <name>1</name>
                                    <description>Counter clear enabled on the falling edge of GTIOCnA input when GTIOCnB input is 0</description>
                                    <value>#1</value>
                                </enumeratedValue>
                            </enumeratedValues>
                        </field>
                        <field>
                            <name>CSCAFBH</name>
                            <description>GTIOCnA Pin Falling Input during GTIOCnB Value High Source Counter Clear Enable</description>
                            <lsb>11</lsb>
                            <msb>11</msb>
                            <access>read-write</access>
                            <enumeratedValues>
                                <enumeratedValue>
                                    <name>0</name>
                                    <description>Counter clear disabled on the falling edge of GTIOCnA input when GTIOCnB input is 1</description>
                                    <value>#0</value>
                                </enumeratedValue>
                                <enumeratedValue>
                                    <name>1</name>
                                    <description>Counter clear enabled on the falling edge of GTIOCnA input when GTIOCnB input is 1</description>
                                    <value>#1</value>
                                </enumeratedValue>
                            </enumeratedValues>
                        </field>
                        <field>
                            <name>CSCBRAL</name>
                            <description>GTIOCnB Pin Rising Input during GTIOCnA Value Low Source Counter Clear Enable</description>
                            <lsb>12</lsb>
                            <msb>12</msb>
                            <access>read-write</access>
                            <enumeratedValues>
                                <enumeratedValue>
                                    <name>0</name>
                                    <description>Counter clear disabled on the rising edge of GTIOCnB input when GTIOCnA input is 0</description>
                                    <value>#0</value>
                                </enumeratedValue>
                                <enumeratedValue>
                                    <name>1</name>
                                    <description>Counter clear enabled on the rising edge of GTIOCnB input when GTIOCnA input is 0</description>
                                    <value>#1</value>
                                </enumeratedValue>
                            </enumeratedValues>
                        </field>
                        <field>
                            <name>CSCBRAH</name>
                            <description>GTIOCnB Pin Rising Input during GTIOCnA Value High Source Counter Clear Enable</description>
                            <lsb>13</lsb>
                            <msb>13</msb>
                            <access>read-write</access>
                            <enumeratedValues>
                                <enumeratedValue>
                                    <name>0</name>
                                    <description>Counter clear disabled on the rising edge of GTIOCnB input when GTIOCnA input is 1</description>
                                    <value>#0</value>
                                </enumeratedValue>
                                <enumeratedValue>
                                    <name>1</name>
                                    <description>Counter clear enabled on the rising edge of GTIOCnB input when GTIOCnA input is 1</description>
                                    <value>#1</value>
                                </enumeratedValue>
                            </enumeratedValues>
                        </field>
                        <field>
                            <name>CSCBFAL</name>
                            <description>GTIOCnB Pin Falling Input during GTIOCnA Value Low Source Counter Clear Enable</description>
                            <lsb>14</lsb>
                            <msb>14</msb>
                            <access>read-write</access>
                            <enumeratedValues>
                                <enumeratedValue>
                                    <name>0</name>
                                    <description>Counter clear disabled on the falling edge of GTIOCnB input when GTIOCnA input is 0</description>
                                    <value>#0</value>
                                </enumeratedValue>
                                <enumeratedValue>
                                    <name>1</name>
                                    <description>Counter clear enabled on the falling edge of GTIOCnB input when GTIOCnA input is 0</description>
                                    <value>#1</value>
                                </enumeratedValue>
                            </enumeratedValues>
                        </field>
                        <field>
                            <name>CSCBFAH</name>
                            <description>GTIOCnB Pin Falling Input during GTIOCnA Value High Source Counter Clear Enable</description>
                            <lsb>15</lsb>
                            <msb>15</msb>
                            <access>read-write</access>
                            <enumeratedValues>
                                <enumeratedValue>
                                    <name>0</name>
                                    <description>Counter clear disabled on the falling edge of GTIOCnB input when GTIOCnA input is 1</description>
                                    <value>#0</value>
                                </enumeratedValue>
                                <enumeratedValue>
                                    <name>1</name>
                                    <description>Counter clear enabled on the falling edge of GTIOCnB input when GTIOCnA input is 1</description>
                                    <value>#1</value>
                                </enumeratedValue>
                            </enumeratedValues>
                        </field>
                        <field>
                            <name>CSELCA</name>
                            <description>ELC_GPTA Event Source Counter Clear Enable</description>
                            <lsb>16</lsb>
                            <msb>16</msb>
                            <access>read-write</access>
                            <enumeratedValues>
                                <enumeratedValue>
                                    <name>0</name>
                                    <description>Counter clear disabled at the ELC_GPTA input</description>
                                    <value>#0</value>
                                </enumeratedValue>
                                <enumeratedValue>
                                    <name>1</name>
                                    <description>Counter clear enabled at the ELC_GPTA input</description>
                                    <value>#1</value>
                                </enumeratedValue>
                            </enumeratedValues>
                        </field>
                        <field>
                            <name>CSELCB</name>
                            <description>ELC_GPTB Event Source Counter Clear Enable</description>
                            <lsb>17</lsb>
                            <msb>17</msb>
                            <access>read-write</access>
                            <enumeratedValues>
                                <enumeratedValue>
                                    <name>0</name>
                                    <description>Counter clear disabled at the ELC_GPTB input</description>
                                    <value>#0</value>
                                </enumeratedValue>
                                <enumeratedValue>
                                    <name>1</name>
                                    <description>Counter clear enabled at the ELC_GPTB input</description>
                                    <value>#1</value>
                                </enumeratedValue>
                            </enumeratedValues>
                        </field>
                        <field>
                            <name>CSELCC</name>
                            <description>ELC_GPTC Event Source Counter Clear Enable</description>
                            <lsb>18</lsb>
                            <msb>18</msb>
                            <access>read-write</access>
                            <enumeratedValues>
                                <enumeratedValue>
                                    <name>0</name>
                                    <description>Counter clear disabled at the ELC_GPTC input</description>
                                    <value>#0</value>
                                </enumeratedValue>
                                <enumeratedValue>
                                    <name>1</name>
                                    <description>Counter clear enabled at the ELC_GPTC input</description>
                                    <value>#1</value>
                                </enumeratedValue>
                            </enumeratedValues>
                        </field>
                        <field>
                            <name>CSELCD</name>
                            <description>ELC_GPTD Event Source Counter Clear Enable</description>
                            <lsb>19</lsb>
                            <msb>19</msb>
                            <access>read-write</access>
                            <enumeratedValues>
                                <enumeratedValue>
                                    <name>0</name>
                                    <description>Counter clear disabled at the ELC_GPTD input</description>
                                    <value>#0</value>
                                </enumeratedValue>
                                <enumeratedValue>
                                    <name>1</name>
                                    <description>Counter clear enabled at the ELC_GPTD input</description>
                                    <value>#1</value>
                                </enumeratedValue>
                            </enumeratedValues>
                        </field>
                        <field>
                            <name>CSELCE</name>
                            <description>ELC_GPTE Event Source Counter Clear Enable</description>
                            <lsb>20</lsb>
                            <msb>20</msb>
                            <access>read-write</access>
                            <enumeratedValues>
                                <enumeratedValue>
                                    <name>0</name>
                                    <description>Counter clear disabled at the ELC_GPTE input</description>
                                    <value>#0</value>
                                </enumeratedValue>
                                <enumeratedValue>
                                    <name>1</name>
                                    <description>Counter clear enabled at the ELC_GPTE input</description>
                                    <value>#1</value>
                                </enumeratedValue>
                            </enumeratedValues>
                        </field>
                        <field>
                            <name>CSELCF</name>
                            <description>ELC_GPTF Event Source Counter Clear Enable</description>
                            <lsb>21</lsb>
                            <msb>21</msb>
                            <access>read-write</access>
                            <enumeratedValues>
                                <enumeratedValue>
                                    <name>0</name>
                                    <description>Counter clear disabled at the ELC_GPTF input</description>
                                    <value>#0</value>
                                </enumeratedValue>
                                <enumeratedValue>
                                    <name>1</name>
                                    <description>Counter clear enabled at the ELC_GPTF input</description>
                                    <value>#1</value>
                                </enumeratedValue>
                            </enumeratedValues>
                        </field>
                        <field>
                            <name>CSELCG</name>
                            <description>ELC_GPTG Event Source Counter Clear Enable</description>
                            <lsb>22</lsb>
                            <msb>22</msb>
                            <access>read-write</access>
                            <enumeratedValues>
                                <enumeratedValue>
                                    <name>0</name>
                                    <description>Counter clear disabled at the ELC_GPTG input</description>
                                    <value>#0</value>
                                </enumeratedValue>
                                <enumeratedValue>
                                    <name>1</name>
                                    <description>Counter clear enabled at the ELC_GPTG input</description>
                                    <value>#1</value>
                                </enumeratedValue>
                            </enumeratedValues>
                        </field>
                        <field>
                            <name>CSELCH</name>
                            <description>ELC_GPTH Event Source Counter Clear Enable</description>
                            <lsb>23</lsb>
                            <msb>23</msb>
                            <access>read-write</access>
                            <enumeratedValues>
                                <enumeratedValue>
                                    <name>0</name>
                                    <description>Counter clear disabled at the ELC_GPTH input</description>
                                    <value>#0</value>
                                </enumeratedValue>
                                <enumeratedValue>
                                    <name>1</name>
                                    <description>Counter clear enabled at the ELC_GPTH input</description>
                                    <value>#1</value>
                                </enumeratedValue>
                            </enumeratedValues>
                        </field>
                        <field>
                            <name>CCLR</name>
                            <description>Software Source Counter Clear Enable</description>
                            <lsb>31</lsb>
                            <msb>31</msb>
                            <access>read-write</access>
                            <enumeratedValues>
                                <enumeratedValue>
                                    <name>0</name>
                                    <description>Counter clear disabled by the GTCLR register</description>
                                    <value>#0</value>
                                </enumeratedValue>
                                <enumeratedValue>
                                    <name>1</name>
                                    <description>Counter clear enabled by the GTCLR register</description>
                                    <value>#1</value>
                                </enumeratedValue>
                            </enumeratedValues>
                        </field>
                    </fields>
                </register>
                <register>
                    <name>GTUPSR</name>
                    <description>General PWM Timer Up Count Source Select Register</description>
                    <addressOffset>0x1C</addressOffset>
                    <size>32</size>
                    <access>read-write</access>
                    <resetValue>0x00000000</resetValue>
                    <resetMask>0xffffffff</resetMask>
                    <fields>
                        <field>
                            <name>USGTRGAR</name>
                            <description>GTETRGA Pin Rising Input Source Counter Count Up Enable</description>
                            <lsb>0</lsb>
                            <msb>0</msb>
                            <access>read-write</access>
                            <enumeratedValues>
                                <enumeratedValue>
                                    <name>0</name>
                                    <description>Counter count up disabled on the rising edge of GTETRGA input</description>
                                    <value>#0</value>
                                </enumeratedValue>
                                <enumeratedValue>
                                    <name>1</name>
                                    <description>Counter count up enabled on the rising edge of GTETRGA input</description>
                                    <value>#1</value>
                                </enumeratedValue>
                            </enumeratedValues>
                        </field>
                        <field>
                            <name>USGTRGAF</name>
                            <description>GTETRGA Pin Falling Input Source Counter Count Up Enable</description>
                            <lsb>1</lsb>
                            <msb>1</msb>
                            <access>read-write</access>
                            <enumeratedValues>
                                <enumeratedValue>
                                    <name>0</name>
                                    <description>Counter count up disabled on the falling edge of GTETRGA input</description>
                                    <value>#0</value>
                                </enumeratedValue>
                                <enumeratedValue>
                                    <name>1</name>
                                    <description>Counter count up enabled on the falling edge of GTETRGA input</description>
                                    <value>#1</value>
                                </enumeratedValue>
                            </enumeratedValues>
                        </field>
                        <field>
                            <name>USGTRGBR</name>
                            <description>GTETRGB Pin Rising Input Source Counter Count Up Enable</description>
                            <lsb>2</lsb>
                            <msb>2</msb>
                            <access>read-write</access>
                            <enumeratedValues>
                                <enumeratedValue>
                                    <name>0</name>
                                    <description>Counter count up disabled on the rising edge of GTETRGB input</description>
                                    <value>#0</value>
                                </enumeratedValue>
                                <enumeratedValue>
                                    <name>1</name>
                                    <description>Counter count up enabled on the rising edge of GTETRGB input</description>
                                    <value>#1</value>
                                </enumeratedValue>
                            </enumeratedValues>
                        </field>
                        <field>
                            <name>USGTRGBF</name>
                            <description>GTETRGB Pin Falling Input Source Counter Count Up Enable</description>
                            <lsb>3</lsb>
                            <msb>3</msb>
                            <access>read-write</access>
                            <enumeratedValues>
                                <enumeratedValue>
                                    <name>0</name>
                                    <description>Counter count up disabled on the falling edge of GTETRGB input</description>
                                    <value>#0</value>
                                </enumeratedValue>
                                <enumeratedValue>
                                    <name>1</name>
                                    <description>Counter count up enabled on the falling edge of GTETRGB input</description>
                                    <value>#1</value>
                                </enumeratedValue>
                            </enumeratedValues>
                        </field>
                        <field>
                            <name>USGTRGCR</name>
                            <description>GTETRGC Pin Rising Input Source Counter Count Up Enable</description>
                            <lsb>4</lsb>
                            <msb>4</msb>
                            <access>read-write</access>
                            <enumeratedValues>
                                <enumeratedValue>
                                    <name>0</name>
                                    <description>Counter count up disabled on the rising edge of GTETRGC input</description>
                                    <value>#0</value>
                                </enumeratedValue>
                                <enumeratedValue>
                                    <name>1</name>
                                    <description>Counter count up enabled on the rising edge of GTETRGC input</description>
                                    <value>#1</value>
                                </enumeratedValue>
                            </enumeratedValues>
                        </field>
                        <field>
                            <name>USGTRGCF</name>
                            <description>GTETRGC Pin Falling Input Source Counter Count Up Enable</description>
                            <lsb>5</lsb>
                            <msb>5</msb>
                            <access>read-write</access>
                            <enumeratedValues>
                                <enumeratedValue>
                                    <name>0</name>
                                    <description>Counter count up disabled on the falling edge of GTETRGC input</description>
                                    <value>#0</value>
                                </enumeratedValue>
                                <enumeratedValue>
                                    <name>1</name>
                                    <description>Counter count up enabled on the falling edge of GTETRGC input</description>
                                    <value>#1</value>
                                </enumeratedValue>
                            </enumeratedValues>
                        </field>
                        <field>
                            <name>USGTRGDR</name>
                            <description>GTETRGD Pin Rising Input Source Counter Count Up Enable</description>
                            <lsb>6</lsb>
                            <msb>6</msb>
                            <access>read-write</access>
                            <enumeratedValues>
                                <enumeratedValue>
                                    <name>0</name>
                                    <description>Counter count up disabled on the rising edge of GTETRGD input</description>
                                    <value>#0</value>
                                </enumeratedValue>
                                <enumeratedValue>
                                    <name>1</name>
                                    <description>Counter count up enabled on the rising edge of GTETRGD input</description>
                                    <value>#1</value>
                                </enumeratedValue>
                            </enumeratedValues>
                        </field>
                        <field>
                            <name>USGTRGDF</name>
                            <description>GTETRGD Pin Falling Input Source Counter Count Up Enable</description>
                            <lsb>7</lsb>
                            <msb>7</msb>
                            <access>read-write</access>
                            <enumeratedValues>
                                <enumeratedValue>
                                    <name>0</name>
                                    <description>Counter count up disabled on the falling edge of GTETRGD input</description>
                                    <value>#0</value>
                                </enumeratedValue>
                                <enumeratedValue>
                                    <name>1</name>
                                    <description>Counter count up enabled on the falling edge of GTETRGD input</description>
                                    <value>#1</value>
                                </enumeratedValue>
                            </enumeratedValues>
                        </field>
                        <field>
                            <name>USCARBL</name>
                            <description>GTIOCnA Pin Rising Input during GTIOCnB Value Low Source Counter Count Up Enable</description>
                            <lsb>8</lsb>
                            <msb>8</msb>
                            <access>read-write</access>
                            <enumeratedValues>
                                <enumeratedValue>
                                    <name>0</name>
                                    <description>Counter count up disabled on the rising edge of GTIOCnA input when GTIOCnB input is 0</description>
                                    <value>#0</value>
                                </enumeratedValue>
                                <enumeratedValue>
                                    <name>1</name>
                                    <description>Counter count up enabled on the rising edge of GTIOCnA input when GTIOCnB input is 0</description>
                                    <value>#1</value>
                                </enumeratedValue>
                            </enumeratedValues>
                        </field>
                        <field>
                            <name>USCARBH</name>
                            <description>GTIOCnA Pin Rising Input during GTIOCnB Value High Source Counter Count Up Enable</description>
                            <lsb>9</lsb>
                            <msb>9</msb>
                            <access>read-write</access>
                            <enumeratedValues>
                                <enumeratedValue>
                                    <name>0</name>
                                    <description>Counter count up disabled on the rising edge of GTIOCnA input when GTIOCnB input is 1</description>
                                    <value>#0</value>
                                </enumeratedValue>
                                <enumeratedValue>
                                    <name>1</name>
                                    <description>Counter count up enabled on the rising edge of GTIOCnA input when GTIOCnB input is 1</description>
                                    <value>#1</value>
                                </enumeratedValue>
                            </enumeratedValues>
                        </field>
                        <field>
                            <name>USCAFBL</name>
                            <description>GTIOCnA Pin Falling Input during GTIOCnB Value Low Source Counter Count Up Enable</description>
                            <lsb>10</lsb>
                            <msb>10</msb>
                            <access>read-write</access>
                            <enumeratedValues>
                                <enumeratedValue>
                                    <name>0</name>
                                    <description>Counter count up disabled on the falling edge of GTIOCnA input when GTIOCnB input is 0</description>
                                    <value>#0</value>
                                </enumeratedValue>
                                <enumeratedValue>
                                    <name>1</name>
                                    <description>Counter count up enabled on the falling edge of GTIOCnA input when GTIOCnB input is 0</description>
                                    <value>#1</value>
                                </enumeratedValue>
                            </enumeratedValues>
                        </field>
                        <field>
                            <name>USCAFBH</name>
                            <description>GTIOCnA Pin Falling Input during GTIOCnB Value High Source Counter Count Up Enable</description>
                            <lsb>11</lsb>
                            <msb>11</msb>
                            <access>read-write</access>
                            <enumeratedValues>
                                <enumeratedValue>
                                    <name>0</name>
                                    <description>Counter count up disabled on the falling edge of GTIOCnA input when GTIOCnB input is 1</description>
                                    <value>#0</value>
                                </enumeratedValue>
                                <enumeratedValue>
                                    <name>1</name>
                                    <description>Counter count up enabled on the falling edge of GTIOCnA input when GTIOCnB input is 1</description>
                                    <value>#1</value>
                                </enumeratedValue>
                            </enumeratedValues>
                        </field>
                        <field>
                            <name>USCBRAL</name>
                            <description>GTIOCnB Pin Rising Input during GTIOCnA Value Low Source Counter Count Up Enable</description>
                            <lsb>12</lsb>
                            <msb>12</msb>
                            <access>read-write</access>
                            <enumeratedValues>
                                <enumeratedValue>
                                    <name>0</name>
                                    <description>Counter count up disabled on the rising edge of GTIOCnB input when GTIOCnA input is 0</description>
                                    <value>#0</value>
                                </enumeratedValue>
                                <enumeratedValue>
                                    <name>1</name>
                                    <description>Counter count up enabled on the rising edge of GTIOCnB input when GTIOCnA input is 0</description>
                                    <value>#1</value>
                                </enumeratedValue>
                            </enumeratedValues>
                        </field>
                        <field>
                            <name>USCBRAH</name>
                            <description>GTIOCnB Pin Rising Input during GTIOCnA Value High Source Counter Count Up Enable</description>
                            <lsb>13</lsb>
                            <msb>13</msb>
                            <access>read-write</access>
                            <enumeratedValues>
                                <enumeratedValue>
                                    <name>0</name>
                                    <description>Counter count up disabled on the rising edge of GTIOCnB input when GTIOCnA input is 1</description>
                                    <value>#0</value>
                                </enumeratedValue>
                                <enumeratedValue>
                                    <name>1</name>
                                    <description>Counter count up enabled on the rising edge of GTIOCnB input when GTIOCnA input is 1</description>
                                    <value>#1</value>
                                </enumeratedValue>
                            </enumeratedValues>
                        </field>
                        <field>
                            <name>USCBFAL</name>
                            <description>GTIOCnB Pin Falling Input during GTIOCnA Value Low Source Counter Count Up Enable</description>
                            <lsb>14</lsb>
                            <msb>14</msb>
                            <access>read-write</access>
                            <enumeratedValues>
                                <enumeratedValue>
                                    <name>0</name>
                                    <description>Counter count up disabled on the falling edge of GTIOCnB input when GTIOCnA input is 0</description>
                                    <value>#0</value>
                                </enumeratedValue>
                                <enumeratedValue>
                                    <name>1</name>
                                    <description>Counter count up enabled on the falling edge of GTIOCnB input when GTIOCnA input is 0</description>
                                    <value>#1</value>
                                </enumeratedValue>
                            </enumeratedValues>
                        </field>
                        <field>
                            <name>USCBFAH</name>
                            <description>GTIOCnB Pin Falling Input during GTIOCnA Value High Source Counter Count Up Enable</description>
                            <lsb>15</lsb>
                            <msb>15</msb>
                            <access>read-write</access>
                            <enumeratedValues>
                                <enumeratedValue>
                                    <name>0</name>
                                    <description>Counter count up disabled on the falling edge of GTIOCnB input when GTIOCnA input is 1</description>
                                    <value>#0</value>
                                </enumeratedValue>
                                <enumeratedValue>
                                    <name>1</name>
                                    <description>Counter count up enabled on the falling edge of GTIOCnB input when GTIOCnA input is 1</description>
                                    <value>#1</value>
                                </enumeratedValue>
                            </enumeratedValues>
                        </field>
                        <field>
                            <name>USELCA</name>
                            <description>ELC_GPTA Event Source Counter Count Up Enable</description>
                            <lsb>16</lsb>
                            <msb>16</msb>
                            <access>read-write</access>
                            <enumeratedValues>
                                <enumeratedValue>
                                    <name>0</name>
                                    <description>Counter count up disabled at the ELC_GPTA input</description>
                                    <value>#0</value>
                                </enumeratedValue>
                                <enumeratedValue>
                                    <name>1</name>
                                    <description>Counter count up enabled at the ELC_GPTA input</description>
                                    <value>#1</value>
                                </enumeratedValue>
                            </enumeratedValues>
                        </field>
                        <field>
                            <name>USELCB</name>
                            <description>ELC_GPTB Event Source Counter Count Up Enable</description>
                            <lsb>17</lsb>
                            <msb>17</msb>
                            <access>read-write</access>
                            <enumeratedValues>
                                <enumeratedValue>
                                    <name>0</name>
                                    <description>Counter count up disabled at the ELC_GPTB input</description>
                                    <value>#0</value>
                                </enumeratedValue>
                                <enumeratedValue>
                                    <name>1</name>
                                    <description>Counter count up enabled at the ELC_GPTB input</description>
                                    <value>#1</value>
                                </enumeratedValue>
                            </enumeratedValues>
                        </field>
                        <field>
                            <name>USELCC</name>
                            <description>ELC_GPTC Event Source Counter Count Up Enable</description>
                            <lsb>18</lsb>
                            <msb>18</msb>
                            <access>read-write</access>
                            <enumeratedValues>
                                <enumeratedValue>
                                    <name>0</name>
                                    <description>Counter count up disabled at the ELC_GPTC input</description>
                                    <value>#0</value>
                                </enumeratedValue>
                                <enumeratedValue>
                                    <name>1</name>
                                    <description>Counter count up enabled at the ELC_GPTC input</description>
                                    <value>#1</value>
                                </enumeratedValue>
                            </enumeratedValues>
                        </field>
                        <field>
                            <name>USELCD</name>
                            <description>ELC_GPTD Event Source Counter Count Up Enable</description>
                            <lsb>19</lsb>
                            <msb>19</msb>
                            <access>read-write</access>
                            <enumeratedValues>
                                <enumeratedValue>
                                    <name>0</name>
                                    <description>Counter count up disabled at the ELC_GPTD input</description>
                                    <value>#0</value>
                                </enumeratedValue>
                                <enumeratedValue>
                                    <name>1</name>
                                    <description>Counter count up enabled at the ELC_GPTD input</description>
                                    <value>#1</value>
                                </enumeratedValue>
                            </enumeratedValues>
                        </field>
                        <field>
                            <name>USELCE</name>
                            <description>ELC_GPTE Event Source Counter Count Up Enable</description>
                            <lsb>20</lsb>
                            <msb>20</msb>
                            <access>read-write</access>
                            <enumeratedValues>
                                <enumeratedValue>
                                    <name>0</name>
                                    <description>Counter count up disabled at the ELC_GPTE input</description>
                                    <value>#0</value>
                                </enumeratedValue>
                                <enumeratedValue>
                                    <name>1</name>
                                    <description>Counter count up enabled at the ELC_GPTE input</description>
                                    <value>#1</value>
                                </enumeratedValue>
                            </enumeratedValues>
                        </field>
                        <field>
                            <name>USELCF</name>
                            <description>ELC_GPTF Event Source Counter Count Up Enable</description>
                            <lsb>21</lsb>
                            <msb>21</msb>
                            <access>read-write</access>
                            <enumeratedValues>
                                <enumeratedValue>
                                    <name>0</name>
                                    <description>Counter count up disabled at the ELC_GPTF input</description>
                                    <value>#0</value>
                                </enumeratedValue>
                                <enumeratedValue>
                                    <name>1</name>
                                    <description>Counter count up enabled at the ELC_GPTF input</description>
                                    <value>#1</value>
                                </enumeratedValue>
                            </enumeratedValues>
                        </field>
                        <field>
                            <name>USELCG</name>
                            <description>ELC_GPTG Event Source Counter Count Up Enable</description>
                            <lsb>22</lsb>
                            <msb>22</msb>
                            <access>read-write</access>
                            <enumeratedValues>
                                <enumeratedValue>
                                    <name>0</name>
                                    <description>Counter count up disabled at the ELC_GPTG input</description>
                                    <value>#0</value>
                                </enumeratedValue>
                                <enumeratedValue>
                                    <name>1</name>
                                    <description>Counter count up enabled at the ELC_GPTG input</description>
                                    <value>#1</value>
                                </enumeratedValue>
                            </enumeratedValues>
                        </field>
                        <field>
                            <name>USELCH</name>
                            <description>ELC_GPTH Event Source Counter Count Up Enable</description>
                            <lsb>23</lsb>
                            <msb>23</msb>
                            <access>read-write</access>
                            <enumeratedValues>
                                <enumeratedValue>
                                    <name>0</name>
                                    <description>Counter count up disabled at the ELC_GPTH input</description>
                                    <value>#0</value>
                                </enumeratedValue>
                                <enumeratedValue>
                                    <name>1</name>
                                    <description>Counter count up enabled at the ELC_GPTH input</description>
                                    <value>#1</value>
                                </enumeratedValue>
                            </enumeratedValues>
                        </field>
                    </fields>
                </register>
                <register>
                    <name>GTDNSR</name>
                    <description>General PWM Timer Down Count Source Select Register</description>
                    <addressOffset>0x20</addressOffset>
                    <size>32</size>
                    <access>read-write</access>
                    <resetValue>0x00000000</resetValue>
                    <resetMask>0xffffffff</resetMask>
                    <fields>
                        <field>
                            <name>DSGTRGAR</name>
                            <description>GTETRGA Pin Rising Input Source Counter Count Down Enable</description>
                            <lsb>0</lsb>
                            <msb>0</msb>
                            <access>read-write</access>
                            <enumeratedValues>
                                <enumeratedValue>
                                    <name>0</name>
                                    <description>Counter count down disabled on the rising edge of GTETRGA input</description>
                                    <value>#0</value>
                                </enumeratedValue>
                                <enumeratedValue>
                                    <name>1</name>
                                    <description>Counter count down enabled on the rising edge of GTETRGA input</description>
                                    <value>#1</value>
                                </enumeratedValue>
                            </enumeratedValues>
                        </field>
                        <field>
                            <name>DSGTRGAF</name>
                            <description>GTETRGA Pin Falling Input Source Counter Count Down Enable</description>
                            <lsb>1</lsb>
                            <msb>1</msb>
                            <access>read-write</access>
                            <enumeratedValues>
                                <enumeratedValue>
                                    <name>0</name>
                                    <description>Counter count down disabled on the falling edge of GTETRGA input</description>
                                    <value>#0</value>
                                </enumeratedValue>
                                <enumeratedValue>
                                    <name>1</name>
                                    <description>Counter count down enabled on the falling edge of GTETRGA input</description>
                                    <value>#1</value>
                                </enumeratedValue>
                            </enumeratedValues>
                        </field>
                        <field>
                            <name>DSGTRGBR</name>
                            <description>GTETRGB Pin Rising Input Source Counter Count Down Enable</description>
                            <lsb>2</lsb>
                            <msb>2</msb>
                            <access>read-write</access>
                            <enumeratedValues>
                                <enumeratedValue>
                                    <name>0</name>
                                    <description>Counter count down disabled on the rising edge of GTETRGB input</description>
                                    <value>#0</value>
                                </enumeratedValue>
                                <enumeratedValue>
                                    <name>1</name>
                                    <description>Counter count down enabled on the rising edge of GTETRGB input</description>
                                    <value>#1</value>
                                </enumeratedValue>
                            </enumeratedValues>
                        </field>
                        <field>
                            <name>DSGTRGBF</name>
                            <description>GTETRGB Pin Falling Input Source Counter Count Down Enable</description>
                            <lsb>3</lsb>
                            <msb>3</msb>
                            <access>read-write</access>
                            <enumeratedValues>
                                <enumeratedValue>
                                    <name>0</name>
                                    <description>Counter count down disabled on the falling edge of GTETRGB input</description>
                                    <value>#0</value>
                                </enumeratedValue>
                                <enumeratedValue>
                                    <name>1</name>
                                    <description>Counter count down enabled on the falling edge of GTETRGB input</description>
                                    <value>#1</value>
                                </enumeratedValue>
                            </enumeratedValues>
                        </field>
                        <field>
                            <name>DSGTRGCR</name>
                            <description>GTETRGC Pin Rising Input Source Counter Count Down Enable</description>
                            <lsb>4</lsb>
                            <msb>4</msb>
                            <access>read-write</access>
                            <enumeratedValues>
                                <enumeratedValue>
                                    <name>0</name>
                                    <description>Counter count down disabled on the rising edge of GTETRGC input</description>
                                    <value>#0</value>
                                </enumeratedValue>
                                <enumeratedValue>
                                    <name>1</name>
                                    <description>Counter count down enabled on the rising edge of GTETRGC input</description>
                                    <value>#1</value>
                                </enumeratedValue>
                            </enumeratedValues>
                        </field>
                        <field>
                            <name>DSGTRGCF</name>
                            <description>GTETRGC Pin Falling Input Source Counter Count Down Enable</description>
                            <lsb>5</lsb>
                            <msb>5</msb>
                            <access>read-write</access>
                            <enumeratedValues>
                                <enumeratedValue>
                                    <name>0</name>
                                    <description>Counter count down disabled on the falling edge of GTETRGC input</description>
                                    <value>#0</value>
                                </enumeratedValue>
                                <enumeratedValue>
                                    <name>1</name>
                                    <description>Counter count down enabled on the falling edge of GTETRGC input</description>
                                    <value>#1</value>
                                </enumeratedValue>
                            </enumeratedValues>
                        </field>
                        <field>
                            <name>DSGTRGDR</name>
                            <description>GTETRGD Pin Rising Input Source Counter Count Down Enable</description>
                            <lsb>6</lsb>
                            <msb>6</msb>
                            <access>read-write</access>
                            <enumeratedValues>
                                <enumeratedValue>
                                    <name>0</name>
                                    <description>Counter count down disabled on the rising edge of GTETRGD input</description>
                                    <value>#0</value>
                                </enumeratedValue>
                                <enumeratedValue>
                                    <name>1</name>
                                    <description>Counter count down enabled on the rising edge of GTETRGD input</description>
                                    <value>#1</value>
                                </enumeratedValue>
                            </enumeratedValues>
                        </field>
                        <field>
                            <name>DSGTRGDF</name>
                            <description>GTETRGD Pin Falling Input Source Counter Count Down Enable</description>
                            <lsb>7</lsb>
                            <msb>7</msb>
                            <access>read-write</access>
                            <enumeratedValues>
                                <enumeratedValue>
                                    <name>0</name>
                                    <description>Counter count down disabled on the falling edge of GTETRGD input</description>
                                    <value>#0</value>
                                </enumeratedValue>
                                <enumeratedValue>
                                    <name>1</name>
                                    <description>Counter count down enabled on the falling edge of GTETRGD input</description>
                                    <value>#1</value>
                                </enumeratedValue>
                            </enumeratedValues>
                        </field>
                        <field>
                            <name>DSCARBL</name>
                            <description>GTIOCnA Pin Rising Input during GTIOCnB Value Low Source Counter Count Down Enable</description>
                            <lsb>8</lsb>
                            <msb>8</msb>
                            <access>read-write</access>
                            <enumeratedValues>
                                <enumeratedValue>
                                    <name>0</name>
                                    <description>Counter count down disabled on the rising edge of GTIOCnA input when GTIOCnB input is 0</description>
                                    <value>#0</value>
                                </enumeratedValue>
                                <enumeratedValue>
                                    <name>1</name>
                                    <description>Counter count down enabled on the rising edge of GTIOCnA input when GTIOCnB input is 0</description>
                                    <value>#1</value>
                                </enumeratedValue>
                            </enumeratedValues>
                        </field>
                        <field>
                            <name>DSCARBH</name>
                            <description>GTIOCnA Pin Rising Input during GTIOCnB Value High Source Counter Count Down Enable</description>
                            <lsb>9</lsb>
                            <msb>9</msb>
                            <access>read-write</access>
                            <enumeratedValues>
                                <enumeratedValue>
                                    <name>0</name>
                                    <description>Counter count down disabled on the rising edge of GTIOCnA input when GTIOCnB input is 1</description>
                                    <value>#0</value>
                                </enumeratedValue>
                                <enumeratedValue>
                                    <name>1</name>
                                    <description>Counter count down enabled on the rising edge of GTIOCnA input when GTIOCnB input is 1</description>
                                    <value>#1</value>
                                </enumeratedValue>
                            </enumeratedValues>
                        </field>
                        <field>
                            <name>DSCAFBL</name>
                            <description>GTIOCnA Pin Falling Input during GTIOCnB Value Low Source Counter Count Down Enable</description>
                            <lsb>10</lsb>
                            <msb>10</msb>
                            <access>read-write</access>
                            <enumeratedValues>
                                <enumeratedValue>
                                    <name>0</name>
                                    <description>Counter count down disabled on the falling edge of GTIOCnA input when GTIOCnB input is 0</description>
                                    <value>#0</value>
                                </enumeratedValue>
                                <enumeratedValue>
                                    <name>1</name>
                                    <description>Counter count down enabled on the falling edge of GTIOCnA input when GTIOCnB input is 0</description>
                                    <value>#1</value>
                                </enumeratedValue>
                            </enumeratedValues>
                        </field>
                        <field>
                            <name>DSCAFBH</name>
                            <description>GTIOCnA Pin Falling Input during GTIOCnB Value High Source Counter Count Down Enable</description>
                            <lsb>11</lsb>
                            <msb>11</msb>
                            <access>read-write</access>
                            <enumeratedValues>
                                <enumeratedValue>
                                    <name>0</name>
                                    <description>Counter count down disabled on the falling edge of GTIOCnA input when GTIOCnB input is 1</description>
                                    <value>#0</value>
                                </enumeratedValue>
                                <enumeratedValue>
                                    <name>1</name>
                                    <description>Counter count down enabled on the falling edge of GTIOCnA input when GTIOCnB input is 1</description>
                                    <value>#1</value>
                                </enumeratedValue>
                            </enumeratedValues>
                        </field>
                        <field>
                            <name>DSCBRAL</name>
                            <description>GTIOCnB Pin Rising Input during GTIOCnA Value Low Source Counter Count Down Enable</description>
                            <lsb>12</lsb>
                            <msb>12</msb>
                            <access>read-write</access>
                            <enumeratedValues>
                                <enumeratedValue>
                                    <name>0</name>
                                    <description>Counter count down disabled on the rising edge of GTIOCnB input when GTIOCnA input is 0</description>
                                    <value>#0</value>
                                </enumeratedValue>
                                <enumeratedValue>
                                    <name>1</name>
                                    <description>Counter count down enabled on the rising edge of GTIOCnB input when GTIOCnA input is 0</description>
                                    <value>#1</value>
                                </enumeratedValue>
                            </enumeratedValues>
                        </field>
                        <field>
                            <name>DSCBRAH</name>
                            <description>GTIOCnB Pin Rising Input during GTIOCnA Value High Source Counter Count Down Enable</description>
                            <lsb>13</lsb>
                            <msb>13</msb>
                            <access>read-write</access>
                            <enumeratedValues>
                                <enumeratedValue>
                                    <name>0</name>
                                    <description>Counter count down disabled on the rising edge of GTIOCnB input when GTIOCnA input is 1</description>
                                    <value>#0</value>
                                </enumeratedValue>
                                <enumeratedValue>
                                    <name>1</name>
                                    <description>Counter count down enabled on the rising edge of GTIOCnB input when GTIOCnA input is 1</description>
                                    <value>#1</value>
                                </enumeratedValue>
                            </enumeratedValues>
                        </field>
                        <field>
                            <name>DSCBFAL</name>
                            <description>GTIOCnB Pin Falling Input during GTIOCnA Value Low Source Counter Count Down Enable</description>
                            <lsb>14</lsb>
                            <msb>14</msb>
                            <access>read-write</access>
                            <enumeratedValues>
                                <enumeratedValue>
                                    <name>0</name>
                                    <description>Counter count down disabled on the falling edge of GTIOCnB input when GTIOCnA input is 0</description>
                                    <value>#0</value>
                                </enumeratedValue>
                                <enumeratedValue>
                                    <name>1</name>
                                    <description>Counter count down enabled on the falling edge of GTIOCnB input when GTIOCnA input is 0</description>
                                    <value>#1</value>
                                </enumeratedValue>
                            </enumeratedValues>
                        </field>
                        <field>
                            <name>DSCBFAH</name>
                            <description>GTIOCnB Pin Falling Input during GTIOCnA Value High Source Counter Count Down Enable</description>
                            <lsb>15</lsb>
                            <msb>15</msb>
                            <access>read-write</access>
                            <enumeratedValues>
                                <enumeratedValue>
                                    <name>0</name>
                                    <description>Counter count down disabled on the falling edge of GTIOCnB input when GTIOCnA input is 1</description>
                                    <value>#0</value>
                                </enumeratedValue>
                                <enumeratedValue>
                                    <name>1</name>
                                    <description>Counter count down enabled on the falling edge of GTIOCnB input when GTIOCnA input is 1</description>
                                    <value>#1</value>
                                </enumeratedValue>
                            </enumeratedValues>
                        </field>
                        <field>
                            <name>DSELCA</name>
                            <description>ELC_GPTA Event Source Counter Count Down Enable</description>
                            <lsb>16</lsb>
                            <msb>16</msb>
                            <access>read-write</access>
                            <enumeratedValues>
                                <enumeratedValue>
                                    <name>0</name>
                                    <description>Counter count down disabled at the ELC_GPTA input</description>
                                    <value>#0</value>
                                </enumeratedValue>
                                <enumeratedValue>
                                    <name>1</name>
                                    <description>Counter count down enabled at the ELC_GPTA input</description>
                                    <value>#1</value>
                                </enumeratedValue>
                            </enumeratedValues>
                        </field>
                        <field>
                            <name>DSELCB</name>
                            <description>ELC_GPTB Event Source Counter Count Down Enable</description>
                            <lsb>17</lsb>
                            <msb>17</msb>
                            <access>read-write</access>
                            <enumeratedValues>
                                <enumeratedValue>
                                    <name>0</name>
                                    <description>Counter count down disabled at the ELC_GPTB input</description>
                                    <value>#0</value>
                                </enumeratedValue>
                                <enumeratedValue>
                                    <name>1</name>
                                    <description>Counter count down enabled at the ELC_GPTB input</description>
                                    <value>#1</value>
                                </enumeratedValue>
                            </enumeratedValues>
                        </field>
                        <field>
                            <name>DSELCC</name>
                            <description>ELC_GPTC Event Source Counter Count Down Enable</description>
                            <lsb>18</lsb>
                            <msb>18</msb>
                            <access>read-write</access>
                            <enumeratedValues>
                                <enumeratedValue>
                                    <name>0</name>
                                    <description>Counter count down disabled at the ELC_GPTC input</description>
                                    <value>#0</value>
                                </enumeratedValue>
                                <enumeratedValue>
                                    <name>1</name>
                                    <description>Counter count down enabled at the ELC_GPTC input</description>
                                    <value>#1</value>
                                </enumeratedValue>
                            </enumeratedValues>
                        </field>
                        <field>
                            <name>DSELCD</name>
                            <description>ELC_GPTD Event Source Counter Count Down Enable</description>
                            <lsb>19</lsb>
                            <msb>19</msb>
                            <access>read-write</access>
                            <enumeratedValues>
                                <enumeratedValue>
                                    <name>0</name>
                                    <description>Counter count down disabled at the ELC_GPTD input</description>
                                    <value>#0</value>
                                </enumeratedValue>
                                <enumeratedValue>
                                    <name>1</name>
                                    <description>Counter count down enabled at the ELC_GPTD input</description>
                                    <value>#1</value>
                                </enumeratedValue>
                            </enumeratedValues>
                        </field>
                        <field>
                            <name>DSELCE</name>
                            <description>ELC_GPTE Event Source Counter Count Down Enable</description>
                            <lsb>20</lsb>
                            <msb>20</msb>
                            <access>read-write</access>
                            <enumeratedValues>
                                <enumeratedValue>
                                    <name>0</name>
                                    <description>Counter count down disabled at the ELC_GPTE input</description>
                                    <value>#0</value>
                                </enumeratedValue>
                                <enumeratedValue>
                                    <name>1</name>
                                    <description>Counter count down enabled at the ELC_GPTE input</description>
                                    <value>#1</value>
                                </enumeratedValue>
                            </enumeratedValues>
                        </field>
                        <field>
                            <name>DSELCF</name>
                            <description>ELC_GPTF Event Source Counter Count Down Enable</description>
                            <lsb>21</lsb>
                            <msb>21</msb>
                            <access>read-write</access>
                            <enumeratedValues>
                                <enumeratedValue>
                                    <name>0</name>
                                    <description>Counter count down disabled at the ELC_GPTF input</description>
                                    <value>#0</value>
                                </enumeratedValue>
                                <enumeratedValue>
                                    <name>1</name>
                                    <description>Counter count down enabled at the ELC_GPTF input</description>
                                    <value>#1</value>
                                </enumeratedValue>
                            </enumeratedValues>
                        </field>
                        <field>
                            <name>DSELCG</name>
                            <description>ELC_GPTG Event Source Counter Count Down Enable</description>
                            <lsb>22</lsb>
                            <msb>22</msb>
                            <access>read-write</access>
                            <enumeratedValues>
                                <enumeratedValue>
                                    <name>0</name>
                                    <description>Counter count down disabled at the ELC_GPTG input</description>
                                    <value>#0</value>
                                </enumeratedValue>
                                <enumeratedValue>
                                    <name>1</name>
                                    <description>Counter count down enabled at the ELC_GPTG input</description>
                                    <value>#1</value>
                                </enumeratedValue>
                            </enumeratedValues>
                        </field>
                        <field>
                            <name>DSELCH</name>
                            <description>ELC_GPTF Event Source Counter Count Down Enable</description>
                            <lsb>23</lsb>
                            <msb>23</msb>
                            <access>read-write</access>
                            <enumeratedValues>
                                <enumeratedValue>
                                    <name>0</name>
                                    <description>Counter count down disabled at the ELC_GPTF input</description>
                                    <value>#0</value>
                                </enumeratedValue>
                                <enumeratedValue>
                                    <name>1</name>
                                    <description>Counter count down enabled at the ELC_GPTF input</description>
                                    <value>#1</value>
                                </enumeratedValue>
                            </enumeratedValues>
                        </field>
                    </fields>
                </register>
                <register>
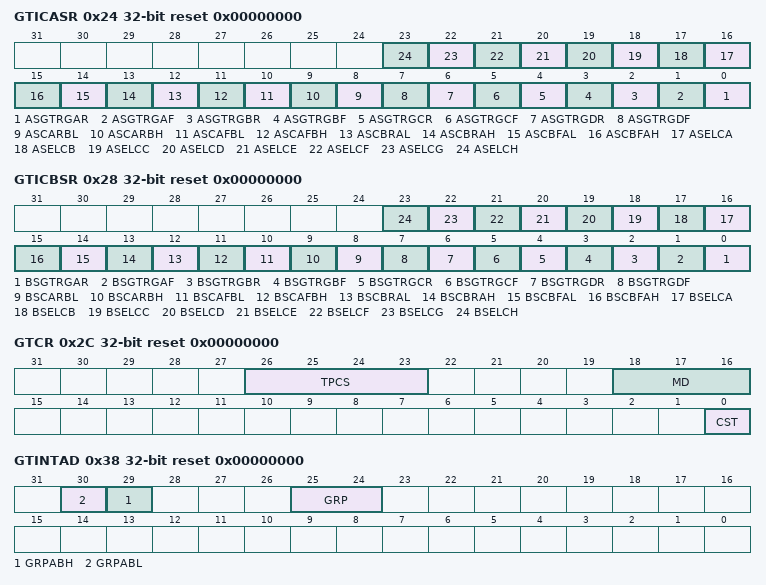
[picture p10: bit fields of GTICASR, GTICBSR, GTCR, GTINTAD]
                    <name>GTICASR</name>
                    <description>General PWM Timer Input Capture Source Select Register A</description>
                    <addressOffset>0x24</addressOffset>
                    <size>32</size>
                    <access>read-write</access>
                    <resetValue>0x00000000</resetValue>
                    <resetMask>0xffffffff</resetMask>
                    <fields>
                        <field>
                            <name>ASGTRGAR</name>
                            <description>GTETRGA Pin Rising Input Source GTCCRA Input Capture Enable</description>
                            <lsb>0</lsb>
                            <msb>0</msb>
                            <access>read-write</access>
                            <enumeratedValues>
                                <enumeratedValue>
                                    <name>0</name>
                                    <description>GTCCRA input capture disabled on the rising edge of GTETRGA input</description>
                                    <value>#0</value>
                                </enumeratedValue>
                                <enumeratedValue>
                                    <name>1</name>
                                    <description>GTCCRA input capture enabled on the rising edge of GTETRGA input</description>
                                    <value>#1</value>
                                </enumeratedValue>
                            </enumeratedValues>
                        </field>
                        <field>
                            <name>ASGTRGAF</name>
                            <description>GTETRGA Pin Falling Input Source GTCCRA Input Capture Enable</description>
                            <lsb>1</lsb>
                            <msb>1</msb>
                            <access>read-write</access>
                            <enumeratedValues>
                                <enumeratedValue>
                                    <name>0</name>
                                    <description>GTCCRA input capture disabled on the falling edge of GTETRGA input</description>
                                    <value>#0</value>
                                </enumeratedValue>
                                <enumeratedValue>
                                    <name>1</name>
                                    <description>GTCCRA input capture enabled on the falling edge of GTETRGA input</description>
                                    <value>#1</value>
                                </enumeratedValue>
                            </enumeratedValues>
                        </field>
                        <field>
                            <name>ASGTRGBR</name>
                            <description>GTETRGB Pin Rising Input Source GTCCRA Input Capture Enable</description>
                            <lsb>2</lsb>
                            <msb>2</msb>
                            <access>read-write</access>
                            <enumeratedValues>
                                <enumeratedValue>
                                    <name>0</name>
                                    <description>GTCCRA input capture disabled on the rising edge of GTETRGB input</description>
                                    <value>#0</value>
                                </enumeratedValue>
                                <enumeratedValue>
                                    <name>1</name>
                                    <description>GTCCRA input capture enabled on the rising edge of GTETRGB input</description>
                                    <value>#1</value>
                                </enumeratedValue>
                            </enumeratedValues>
                        </field>
                        <field>
                            <name>ASGTRGBF</name>
                            <description>GTETRGB Pin Falling Input Source GTCCRA Input Capture Enable</description>
                            <lsb>3</lsb>
                            <msb>3</msb>
                            <access>read-write</access>
                            <enumeratedValues>
                                <enumeratedValue>
                                    <name>0</name>
                                    <description>GTCCRA input capture disabled on the falling edge of GTETRGB input</description>
                                    <value>#0</value>
                                </enumeratedValue>
                                <enumeratedValue>
                                    <name>1</name>
                                    <description>GTCCRA input capture enabled on the falling edge of GTETRGB input</description>
                                    <value>#1</value>
                                </enumeratedValue>
                            </enumeratedValues>
                        </field>
                        <field>
                            <name>ASGTRGCR</name>
                            <description>GTETRGC Pin Rising Input Source GTCCRA Input Capture Enable</description>
                            <lsb>4</lsb>
                            <msb>4</msb>
                            <access>read-write</access>
                            <enumeratedValues>
                                <enumeratedValue>
                                    <name>0</name>
                                    <description>GTCCRA input capture disabled on the rising edge of GTETRGC input</description>
                                    <value>#0</value>
                                </enumeratedValue>
                                <enumeratedValue>
                                    <name>1</name>
                                    <description>GTCCRA input capture enabled on the rising edge of GTETRGC input</description>
                                    <value>#1</value>
                                </enumeratedValue>
                            </enumeratedValues>
                        </field>
                        <field>
                            <name>ASGTRGCF</name>
                            <description>GTETRGC Pin Falling Input Source GTCCRA Input Capture Enable</description>
                            <lsb>5</lsb>
                            <msb>5</msb>
                            <access>read-write</access>
                            <enumeratedValues>
                                <enumeratedValue>
                                    <name>0</name>
                                    <description>GTCCRA input capture disabled on the falling edge of GTETRGC input</description>
                                    <value>#0</value>
                                </enumeratedValue>
                                <enumeratedValue>
                                    <name>1</name>
                                    <description>GTCCRA input capture enabled on the falling edge of GTETRGC input</description>
                                    <value>#1</value>
                                </enumeratedValue>
                            </enumeratedValues>
                        </field>
                        <field>
                            <name>ASGTRGDR</name>
                            <description>GTETRGD Pin Rising Input Source GTCCRA Input Capture Enable</description>
                            <lsb>6</lsb>
                            <msb>6</msb>
                            <access>read-write</access>
                            <enumeratedValues>
                                <enumeratedValue>
                                    <name>0</name>
                                    <description>GTCCRA input capture disabled on the rising edge of GTETRGD input</description>
                                    <value>#0</value>
                                </enumeratedValue>
                                <enumeratedValue>
                                    <name>1</name>
                                    <description>GTCCRA input capture enabled on the rising edge of GTETRGD input</description>
                                    <value>#1</value>
                                </enumeratedValue>
                            </enumeratedValues>
                        </field>
                        <field>
                            <name>ASGTRGDF</name>
                            <description>GTETRGD Pin Falling Input Source GTCCRA Input Capture Enable</description>
                            <lsb>7</lsb>
                            <msb>7</msb>
                            <access>read-write</access>
                            <enumeratedValues>
                                <enumeratedValue>
                                    <name>0</name>
                                    <description>GTCCRA input capture disabled on the falling edge of GTETRGD input</description>
                                    <value>#0</value>
                                </enumeratedValue>
                                <enumeratedValue>
                                    <name>1</name>
                                    <description>GTCCRA input capture enabled on the falling edge of GTETRGD input</description>
                                    <value>#1</value>
                                </enumeratedValue>
                            </enumeratedValues>
                        </field>
                        <field>
                            <name>ASCARBL</name>
                            <description>GTIOCnA Pin Rising Input during GTIOCnB Value Low Source GTCCRA Input Capture Enable</description>
                            <lsb>8</lsb>
                            <msb>8</msb>
                            <access>read-write</access>
                            <enumeratedValues>
                                <enumeratedValue>
                                    <name>0</name>
                                    <description>GTCCRA input capture disabled on the rising edge of GTIOCnA input when GTIOCnB input is 0</description>
                                    <value>#0</value>
                                </enumeratedValue>
                                <enumeratedValue>
                                    <name>1</name>
                                    <description>GTCCRA input capture enabled on the rising edge of GTIOCnA input when GTIOCnB input is 0</description>
                                    <value>#1</value>
                                </enumeratedValue>
                            </enumeratedValues>
                        </field>
                        <field>
                            <name>ASCARBH</name>
                            <description>GTIOCnA Pin Rising Input during GTIOCnB Value High Source GTCCRA Input Capture Enable</description>
                            <lsb>9</lsb>
                            <msb>9</msb>
                            <access>read-write</access>
                            <enumeratedValues>
                                <enumeratedValue>
                                    <name>0</name>
                                    <description>GTCCRA input capture disabled on the rising edge of GTIOCnA input when GTIOCnB input is 1</description>
                                    <value>#0</value>
                                </enumeratedValue>
                                <enumeratedValue>
                                    <name>1</name>
                                    <description>GTCCRA input capture enabled on the rising edge of GTIOCnA input when GTIOCnB input is 1</description>
                                    <value>#1</value>
                                </enumeratedValue>
                            </enumeratedValues>
                        </field>
                        <field>
                            <name>ASCAFBL</name>
                            <description>GTIOCnA Pin Falling Input during GTIOCnB Value Low Source GTCCRA Input Capture Enable</description>
                            <lsb>10</lsb>
                            <msb>10</msb>
                            <access>read-write</access>
                            <enumeratedValues>
                                <enumeratedValue>
                                    <name>0</name>
                                    <description>GTCCRA input capture disabled on the falling edge of GTIOCnA input when GTIOCnB input is 0</description>
                                    <value>#0</value>
                                </enumeratedValue>
                                <enumeratedValue>
                                    <name>1</name>
                                    <description>GTCCRA input capture enabled on the falling edge of GTIOCnA input when GTIOCnB input is 0</description>
                                    <value>#1</value>
                                </enumeratedValue>
                            </enumeratedValues>
                        </field>
                        <field>
                            <name>ASCAFBH</name>
                            <description>GTIOCnA Pin Falling Input during GTIOCnB Value High Source GTCCRA Input Capture Enable</description>
                            <lsb>11</lsb>
                            <msb>11</msb>
                            <access>read-write</access>
                            <enumeratedValues>
                                <enumeratedValue>
                                    <name>0</name>
                                    <description>GTCCRA input capture disabled on the falling edge of GTIOCnA input when GTIOCnB input is 1</description>
                                    <value>#0</value>
                                </enumeratedValue>
                                <enumeratedValue>
                                    <name>1</name>
                                    <description>GTCCRA input capture enabled on the falling edge of GTIOCnA input when GTIOCnB input is 1</description>
                                    <value>#1</value>
                                </enumeratedValue>
                            </enumeratedValues>
                        </field>
                        <field>
                            <name>ASCBRAL</name>
                            <description>GTIOCnB Pin Rising Input during GTIOCnA Value Low Source GTCCRA Input Capture Enable</description>
                            <lsb>12</lsb>
                            <msb>12</msb>
                            <access>read-write</access>
                            <enumeratedValues>
                                <enumeratedValue>
                                    <name>0</name>
                                    <description>GTCCRA input capture disabled on the rising edge of GTIOCnB input when GTIOCnA input is 0</description>
                                    <value>#0</value>
                                </enumeratedValue>
                                <enumeratedValue>
                                    <name>1</name>
                                    <description>GTCCRA input capture enabled on the rising edge of GTIOCnB input when GTIOCnA input is 0</description>
                                    <value>#1</value>
                                </enumeratedValue>
                            </enumeratedValues>
                        </field>
                        <field>
                            <name>ASCBRAH</name>
                            <description>GTIOCnB Pin Rising Input during GTIOCnA Value High Source GTCCRA Input Capture Enable</description>
                            <lsb>13</lsb>
                            <msb>13</msb>
                            <access>read-write</access>
                            <enumeratedValues>
                                <enumeratedValue>
                                    <name>0</name>
                                    <description>GTCCRA input capture disabled on the rising edge of GTIOCnB input when GTIOCnA input is 1</description>
                                    <value>#0</value>
                                </enumeratedValue>
                                <enumeratedValue>
                                    <name>1</name>
                                    <description>GTCCRA input capture enabled on the rising edge of GTIOCnB input when GTIOCnA input is 1</description>
                                    <value>#1</value>
                                </enumeratedValue>
                            </enumeratedValues>
                        </field>
                        <field>
                            <name>ASCBFAL</name>
                            <description>GTIOCnB Pin Falling Input during GTIOCnA Value Low Source GTCCRA Input Capture Enable</description>
                            <lsb>14</lsb>
                            <msb>14</msb>
                            <access>read-write</access>
                            <enumeratedValues>
                                <enumeratedValue>
                                    <name>0</name>
                                    <description>GTCCRA input capture disabled on the falling edge of GTIOCnB input when GTIOCnA input is 0</description>
                                    <value>#0</value>
                                </enumeratedValue>
                                <enumeratedValue>
                                    <name>1</name>
                                    <description>GTCCRA input capture enabled on the falling edge of GTIOCnB input when GTIOCnA input is 0</description>
                                    <value>#1</value>
                                </enumeratedValue>
                            </enumeratedValues>
                        </field>
                        <field>
                            <name>ASCBFAH</name>
                            <description>GTIOCnB Pin Falling Input during GTIOCnA Value High Source GTCCRA Input Capture Enable</description>
                            <lsb>15</lsb>
                            <msb>15</msb>
                            <access>read-write</access>
                            <enumeratedValues>
                                <enumeratedValue>
                                    <name>0</name>
                                    <description>GTCCRA input capture disabled on the falling edge of GTIOCnB input when GTIOCnA input is 1</description>
                                    <value>#0</value>
                                </enumeratedValue>
                                <enumeratedValue>
                                    <name>1</name>
                                    <description>GTCCRA input capture enabled on the falling edge of GTIOCnB input when GTIOCnA input is 1</description>
                                    <value>#1</value>
                                </enumeratedValue>
                            </enumeratedValues>
                        </field>
                        <field>
                            <name>ASELCA</name>
                            <description>ELC_GPTA Event Source GTCCRA Input Capture Enable</description>
                            <lsb>16</lsb>
                            <msb>16</msb>
                            <access>read-write</access>
                            <enumeratedValues>
                                <enumeratedValue>
                                    <name>0</name>
                                    <description>GTCCRA input capture disabled at the ELC_GPTA input</description>
                                    <value>#0</value>
                                </enumeratedValue>
                                <enumeratedValue>
                                    <name>1</name>
                                    <description>GTCCRA input capture enabled at the ELC_GPTA input</description>
                                    <value>#1</value>
                                </enumeratedValue>
                            </enumeratedValues>
                        </field>
                        <field>
                            <name>ASELCB</name>
                            <description>ELC_GPTB Event Source GTCCRA Input Capture Enable</description>
                            <lsb>17</lsb>
                            <msb>17</msb>
                            <access>read-write</access>
                            <enumeratedValues>
                                <enumeratedValue>
                                    <name>0</name>
                                    <description>GTCCRA input capture disabled at the ELC_GPTB input</description>
                                    <value>#0</value>
                                </enumeratedValue>
                                <enumeratedValue>
                                    <name>1</name>
                                    <description>GTCCRA input capture enabled at the ELC_GPTB input</description>
                                    <value>#1</value>
                                </enumeratedValue>
                            </enumeratedValues>
                        </field>
                        <field>
                            <name>ASELCC</name>
                            <description>ELC_GPTC Event Source GTCCRA Input Capture Enable</description>
                            <lsb>18</lsb>
                            <msb>18</msb>
                            <access>read-write</access>
                            <enumeratedValues>
                                <enumeratedValue>
                                    <name>0</name>
                                    <description>GTCCRA input capture disabled at the ELC_GPTC input</description>
                                    <value>#0</value>
                                </enumeratedValue>
                                <enumeratedValue>
                                    <name>1</name>
                                    <description>GTCCRA input capture enabled at the ELC_GPTC input</description>
                                    <value>#1</value>
                                </enumeratedValue>
                            </enumeratedValues>
                        </field>
                        <field>
                            <name>ASELCD</name>
                            <description>ELC_GPTD Event Source GTCCRA Input Capture Enable</description>
                            <lsb>19</lsb>
                            <msb>19</msb>
                            <access>read-write</access>
                            <enumeratedValues>
                                <enumeratedValue>
                                    <name>0</name>
                                    <description>GTCCRA input capture disabled at the ELC_GPTD input</description>
                                    <value>#0</value>
                                </enumeratedValue>
                                <enumeratedValue>
                                    <name>1</name>
                                    <description>GTCCRA input capture enabled at the ELC_GPTD input</description>
                                    <value>#1</value>
                                </enumeratedValue>
                            </enumeratedValues>
                        </field>
                        <field>
                            <name>ASELCE</name>
                            <description>ELC_GPTE Event Source GTCCRA Input Capture Enable</description>
                            <lsb>20</lsb>
                            <msb>20</msb>
                            <access>read-write</access>
                            <enumeratedValues>
                                <enumeratedValue>
                                    <name>0</name>
                                    <description>GTCCRA input capture disabled at the ELC_GPTE input</description>
                                    <value>#0</value>
                                </enumeratedValue>
                                <enumeratedValue>
                                    <name>1</name>
                                    <description>GTCCRA input capture enabled at the ELC_GPTE input</description>
                                    <value>#1</value>
                                </enumeratedValue>
                            </enumeratedValues>
                        </field>
                        <field>
                            <name>ASELCF</name>
                            <description>ELC_GPTF Event Source GTCCRA Input Capture Enable</description>
                            <lsb>21</lsb>
                            <msb>21</msb>
                            <access>read-write</access>
                            <enumeratedValues>
                                <enumeratedValue>
                                    <name>0</name>
                                    <description>GTCCRA input capture disabled at the ELC_GPTF input</description>
                                    <value>#0</value>
                                </enumeratedValue>
                                <enumeratedValue>
                                    <name>1</name>
                                    <description>GTCCRA input capture enabled at the ELC_GPTF input</description>
                                    <value>#1</value>
                                </enumeratedValue>
                            </enumeratedValues>
                        </field>
                        <field>
                            <name>ASELCG</name>
                            <description>ELC_GPTG Event Source GTCCRA Input Capture Enable</description>
                            <lsb>22</lsb>
                            <msb>22</msb>
                            <access>read-write</access>
                            <enumeratedValues>
                                <enumeratedValue>
                                    <name>0</name>
                                    <description>GTCCRA input capture disabled at the ELC_GPTG input</description>
                                    <value>#0</value>
                                </enumeratedValue>
                                <enumeratedValue>
                                    <name>1</name>
                                    <description>GTCCRA input capture enabled at the ELC_GPTG input</description>
                                    <value>#1</value>
                                </enumeratedValue>
                            </enumeratedValues>
                        </field>
                        <field>
                            <name>ASELCH</name>
                            <description>ELC_GPTH Event Source GTCCRA Input Capture Enable</description>
                            <lsb>23</lsb>
                            <msb>23</msb>
                            <access>read-write</access>
                            <enumeratedValues>
                                <enumeratedValue>
                                    <name>0</name>
                                    <description>GTCCRA input capture disabled at the ELC_GPTH input</description>
                                    <value>#0</value>
                                </enumeratedValue>
                                <enumeratedValue>
                                    <name>1</name>
                                    <description>GTCCRA input capture enabled at the ELC_GPTH input</description>
                                    <value>#1</value>
                                </enumeratedValue>
                            </enumeratedValues>
                        </field>
                    </fields>
                </register>
                <register>
                    <name>GTICBSR</name>
                    <description>General PWM Timer Input Capture Source Select Register B</description>
                    <addressOffset>0x28</addressOffset>
                    <size>32</size>
                    <access>read-write</access>
                    <resetValue>0x00000000</resetValue>
                    <resetMask>0xffffffff</resetMask>
                    <fields>
                        <field>
                            <name>BSGTRGAR</name>
                            <description>GTETRGA Pin Rising Input Source GTCCRB Input Capture Enable</description>
                            <lsb>0</lsb>
                            <msb>0</msb>
                            <access>read-write</access>
                            <enumeratedValues>
                                <enumeratedValue>
                                    <name>0</name>
                                    <description>GTCCRB input capture disabled on the rising edge of GTETRGA input</description>
                                    <value>#0</value>
                                </enumeratedValue>
                                <enumeratedValue>
                                    <name>1</name>
                                    <description>GTCCRB input capture enabled on the rising edge of GTETRGA input</description>
                                    <value>#1</value>
                                </enumeratedValue>
                            </enumeratedValues>
                        </field>
                        <field>
                            <name>BSGTRGAF</name>
                            <description>GTETRGA Pin Falling Input Source GTCCRB Input Capture Enable</description>
                            <lsb>1</lsb>
                            <msb>1</msb>
                            <access>read-write</access>
                            <enumeratedValues>
                                <enumeratedValue>
                                    <name>0</name>
                                    <description>GTCCRB input capture disabled on the falling edge of GTETRGA input</description>
                                    <value>#0</value>
                                </enumeratedValue>
                                <enumeratedValue>
                                    <name>1</name>
                                    <description>GTCCRB input capture enabled on the falling edge of GTETRGA input</description>
                                    <value>#1</value>
                                </enumeratedValue>
                            </enumeratedValues>
                        </field>
                        <field>
                            <name>BSGTRGBR</name>
                            <description>GTETRGB Pin Rising Input Source GTCCRB Input Capture Enable</description>
                            <lsb>2</lsb>
                            <msb>2</msb>
                            <access>read-write</access>
                            <enumeratedValues>
                                <enumeratedValue>
                                    <name>0</name>
                                    <description>GTCCRB input capture disabled on the rising edge of GTETRGB input</description>
                                    <value>#0</value>
                                </enumeratedValue>
                                <enumeratedValue>
                                    <name>1</name>
                                    <description>GTCCRB input capture enabled on the rising edge of GTETRGB input</description>
                                    <value>#1</value>
                                </enumeratedValue>
                            </enumeratedValues>
                        </field>
                        <field>
                            <name>BSGTRGBF</name>
                            <description>GTETRGB Pin Falling Input Source GTCCRB Input Capture Enable</description>
                            <lsb>3</lsb>
                            <msb>3</msb>
                            <access>read-write</access>
                            <enumeratedValues>
                                <enumeratedValue>
                                    <name>0</name>
                                    <description>GTCCRB input capture disabled on the falling edge of GTETRGB input</description>
                                    <value>#0</value>
                                </enumeratedValue>
                                <enumeratedValue>
                                    <name>1</name>
                                    <description>GTCCRB input capture enabled on the falling edge of GTETRGB input</description>
                                    <value>#1</value>
                                </enumeratedValue>
                            </enumeratedValues>
                        </field>
                        <field>
                            <name>BSGTRGCR</name>
                            <description>GTETRGC Pin Rising Input Source GTCCRB Input Capture Enable</description>
                            <lsb>4</lsb>
                            <msb>4</msb>
                            <access>read-write</access>
                            <enumeratedValues>
                                <enumeratedValue>
                                    <name>0</name>
                                    <description>GTCCRB input capture disabled on the rising edge of GTETRGC input</description>
                                    <value>#0</value>
                                </enumeratedValue>
                                <enumeratedValue>
                                    <name>1</name>
                                    <description>GTCCRB input capture enabled on the rising edge of GTETRGC input</description>
                                    <value>#1</value>
                                </enumeratedValue>
                            </enumeratedValues>
                        </field>
                        <field>
                            <name>BSGTRGCF</name>
                            <description>GTETRGC Pin Falling Input Source GTCCRB Input Capture Enable</description>
                            <lsb>5</lsb>
                            <msb>5</msb>
                            <access>read-write</access>
                            <enumeratedValues>
                                <enumeratedValue>
                                    <name>0</name>
                                    <description>GTCCRB input capture disabled on the falling edge of GTETRGC input</description>
                                    <value>#0</value>
                                </enumeratedValue>
                                <enumeratedValue>
                                    <name>1</name>
                                    <description>GTCCRB input capture enabled on the falling edge of GTETRGC input</description>
                                    <value>#1</value>
                                </enumeratedValue>
                            </enumeratedValues>
                        </field>
                        <field>
                            <name>BSGTRGDR</name>
                            <description>GTETRGD Pin Rising Input Source GTCCRB Input Capture Enable</description>
                            <lsb>6</lsb>
                            <msb>6</msb>
                            <access>read-write</access>
                            <enumeratedValues>
                                <enumeratedValue>
                                    <name>0</name>
                                    <description>GTCCRB input capture disabled on the rising edge of GTETRGD input</description>
                                    <value>#0</value>
                                </enumeratedValue>
                                <enumeratedValue>
                                    <name>1</name>
                                    <description>GTCCRB input capture enabled on the rising edge of GTETRGD input</description>
                                    <value>#1</value>
                                </enumeratedValue>
                            </enumeratedValues>
                        </field>
                        <field>
                            <name>BSGTRGDF</name>
                            <description>GTETRGD Pin Falling Input Source GTCCRB Input Capture Enable</description>
                            <lsb>7</lsb>
                            <msb>7</msb>
                            <access>read-write</access>
                            <enumeratedValues>
                                <enumeratedValue>
                                    <name>0</name>
                                    <description>GTCCRB input capture disabled on the falling edge of GTETRGD input</description>
                                    <value>#0</value>
                                </enumeratedValue>
                                <enumeratedValue>
                                    <name>1</name>
                                    <description>GTCCRB input capture enabled on the falling edge of GTETRGD input</description>
                                    <value>#1</value>
                                </enumeratedValue>
                            </enumeratedValues>
                        </field>
                        <field>
                            <name>BSCARBL</name>
                            <description>GTIOCnA Pin Rising Input during GTIOCnB Value Low Source GTCCRB Input Capture Enable</description>
                            <lsb>8</lsb>
                            <msb>8</msb>
                            <access>read-write</access>
                            <enumeratedValues>
                                <enumeratedValue>
                                    <name>0</name>
                                    <description>GTCCRB input capture disabled on the rising edge of GTIOCnA input when GTIOCnB input is 0</description>
                                    <value>#0</value>
                                </enumeratedValue>
                                <enumeratedValue>
                                    <name>1</name>
                                    <description>GTCCRB input capture enabled on the rising edge of GTIOCnA input when GTIOCnB input is 0</description>
                                    <value>#1</value>
                                </enumeratedValue>
                            </enumeratedValues>
                        </field>
                        <field>
                            <name>BSCARBH</name>
                            <description>GTIOCnA Pin Rising Input during GTIOCnB Value High Source GTCCRB Input Capture Enable</description>
                            <lsb>9</lsb>
                            <msb>9</msb>
                            <access>read-write</access>
                            <enumeratedValues>
                                <enumeratedValue>
                                    <name>0</name>
                                    <description>GTCCRB input capture disabled on the rising edge of GTIOCnA input when GTIOCnB input is 1</description>
                                    <value>#0</value>
                                </enumeratedValue>
                                <enumeratedValue>
                                    <name>1</name>
                                    <description>GTCCRB input capture enabled on the rising edge of GTIOCnA input when GTIOCnB input is 1</description>
                                    <value>#1</value>
                                </enumeratedValue>
                            </enumeratedValues>
                        </field>
                        <field>
                            <name>BSCAFBL</name>
                            <description>GTIOCnA Pin Falling Input during GTIOCnB Value Low Source GTCCRB Input Capture Enable</description>
                            <lsb>10</lsb>
                            <msb>10</msb>
                            <access>read-write</access>
                            <enumeratedValues>
                                <enumeratedValue>
                                    <name>0</name>
                                    <description>GTCCRB input capture disabled on the falling edge of GTIOCnA input when GTIOCnB input is 0</description>
                                    <value>#0</value>
                                </enumeratedValue>
                                <enumeratedValue>
                                    <name>1</name>
                                    <description>GTCCRB input capture enabled on the falling edge of GTIOCnA input when GTIOCnB input is 0</description>
                                    <value>#1</value>
                                </enumeratedValue>
                            </enumeratedValues>
                        </field>
                        <field>
                            <name>BSCAFBH</name>
                            <description>GTIOCnA Pin Falling Input during GTIOCnB Value High Source GTCCRB Input Capture Enable</description>
                            <lsb>11</lsb>
                            <msb>11</msb>
                            <access>read-write</access>
                            <enumeratedValues>
                                <enumeratedValue>
                                    <name>0</name>
                                    <description>GTCCRB input capture disabled on the falling edge of GTIOCnA input when GTIOCnB input is 1</description>
                                    <value>#0</value>
                                </enumeratedValue>
                                <enumeratedValue>
                                    <name>1</name>
                                    <description>GTCCRB input capture enabled on the falling edge of GTIOCnA input when GTIOCnB input is 1</description>
                                    <value>#1</value>
                                </enumeratedValue>
                            </enumeratedValues>
                        </field>
                        <field>
                            <name>BSCBRAL</name>
                            <description>GTIOCnB Pin Rising Input during GTIOCnA Value Low Source GTCCRB Input Capture Enable</description>
                            <lsb>12</lsb>
                            <msb>12</msb>
                            <access>read-write</access>
                            <enumeratedValues>
                                <enumeratedValue>
                                    <name>0</name>
                                    <description>GTCCRB input capture disabled on the rising edge of GTIOCnB input when GTIOCnA input is 0</description>
                                    <value>#0</value>
                                </enumeratedValue>
                                <enumeratedValue>
                                    <name>1</name>
                                    <description>GTCCRB input capture enabled on the rising edge of GTIOCnB input when GTIOCnA input is 0</description>
                                    <value>#1</value>
                                </enumeratedValue>
                            </enumeratedValues>
                        </field>
                        <field>
                            <name>BSCBRAH</name>
                            <description>GTIOCnB Pin Rising Input during GTIOCnA Value High Source GTCCRB Input Capture Enable</description>
                            <lsb>13</lsb>
                            <msb>13</msb>
                            <access>read-write</access>
                            <enumeratedValues>
                                <enumeratedValue>
                                    <name>0</name>
                                    <description>GTCCRB input capture disabled on the rising edge of GTIOCnB input when GTIOCnA input is 1</description>
                                    <value>#0</value>
                                </enumeratedValue>
                                <enumeratedValue>
                                    <name>1</name>
                                    <description>GTCCRB input capture enabled on the rising edge of GTIOCnB input when GTIOCnA input is 1</description>
                                    <value>#1</value>
                                </enumeratedValue>
                            </enumeratedValues>
                        </field>
                        <field>
                            <name>BSCBFAL</name>
                            <description>GTIOCnB Pin Falling Input during GTIOCnA Value Low Source GTCCRB Input Capture Enable</description>
                            <lsb>14</lsb>
                            <msb>14</msb>
                            <access>read-write</access>
                            <enumeratedValues>
                                <enumeratedValue>
                                    <name>0</name>
                                    <description>GTCCRB input capture disabled on the falling edge of GTIOCnB input when GTIOCnA input is 0</description>
                                    <value>#0</value>
                                </enumeratedValue>
                                <enumeratedValue>
                                    <name>1</name>
                                    <description>GTCCRB input capture enabled on the falling edge of GTIOCnB input when GTIOCnA input is 0</description>
                                    <value>#1</value>
                                </enumeratedValue>
                            </enumeratedValues>
                        </field>
                        <field>
                            <name>BSCBFAH</name>
                            <description>GTIOCnB Pin Falling Input during GTIOCnA Value High Source GTCCRB Input Capture Enable</description>
                            <lsb>15</lsb>
                            <msb>15</msb>
                            <access>read-write</access>
                            <enumeratedValues>
                                <enumeratedValue>
                                    <name>0</name>
                                    <description>GTCCRB input capture disabled on the falling edge of GTIOCnB input when GTIOCnA input is 1</description>
                                    <value>#0</value>
                                </enumeratedValue>
                                <enumeratedValue>
                                    <name>1</name>
                                    <description>GTCCRB input capture enabled on the falling edge of GTIOCnB input when GTIOCnA input is 1</description>
                                    <value>#1</value>
                                </enumeratedValue>
                            </enumeratedValues>
                        </field>
                        <field>
                            <name>BSELCA</name>
                            <description>ELC_GPTA Event Source GTCCRB Input Capture Enable</description>
                            <lsb>16</lsb>
                            <msb>16</msb>
                            <access>read-write</access>
                            <enumeratedValues>
                                <enumeratedValue>
                                    <name>0</name>
                                    <description>GTCCRB input capture disabled at the ELC_GPTA input</description>
                                    <value>#0</value>
                                </enumeratedValue>
                                <enumeratedValue>
                                    <name>1</name>
                                    <description>GTCCRB input capture enabled at the ELC_GPTA input</description>
                                    <value>#1</value>
                                </enumeratedValue>
                            </enumeratedValues>
                        </field>
                        <field>
                            <name>BSELCB</name>
                            <description>ELC_GPTB Event Source GTCCRB Input Capture Enable</description>
                            <lsb>17</lsb>
                            <msb>17</msb>
                            <access>read-write</access>
                            <enumeratedValues>
                                <enumeratedValue>
                                    <name>0</name>
                                    <description>GTCCRB input capture disabled at the ELC_GPTB input</description>
                                    <value>#0</value>
                                </enumeratedValue>
                                <enumeratedValue>
                                    <name>1</name>
                                    <description>GTCCRB input capture enabled at the ELC_GPTB input</description>
                                    <value>#1</value>
                                </enumeratedValue>
                            </enumeratedValues>
                        </field>
                        <field>
                            <name>BSELCC</name>
                            <description>ELC_GPTC Event Source GTCCRB Input Capture Enable</description>
                            <lsb>18</lsb>
                            <msb>18</msb>
                            <access>read-write</access>
                            <enumeratedValues>
                                <enumeratedValue>
                                    <name>0</name>
                                    <description>GTCCRB input capture disabled at the ELC_GPTC input</description>
                                    <value>#0</value>
                                </enumeratedValue>
                                <enumeratedValue>
                                    <name>1</name>
                                    <description>GTCCRB input capture enabled at the ELC_GPTC input</description>
                                    <value>#1</value>
                                </enumeratedValue>
                            </enumeratedValues>
                        </field>
                        <field>
                            <name>BSELCD</name>
                            <description>ELC_GPTD Event Source GTCCRB Input Capture Enable</description>
                            <lsb>19</lsb>
                            <msb>19</msb>
                            <access>read-write</access>
                            <enumeratedValues>
                                <enumeratedValue>
                                    <name>0</name>
                                    <description>GTCCRB input capture disabled at the ELC_GPTD input</description>
                                    <value>#0</value>
                                </enumeratedValue>
                                <enumeratedValue>
                                    <name>1</name>
                                    <description>GTCCRB input capture enabled at the ELC_GPTD input</description>
                                    <value>#1</value>
                                </enumeratedValue>
                            </enumeratedValues>
                        </field>
                        <field>
                            <name>BSELCE</name>
                            <description>ELC_GPTE Event Source GTCCRB Input Capture Enable</description>
                            <lsb>20</lsb>
                            <msb>20</msb>
                            <access>read-write</access>
                            <enumeratedValues>
                                <enumeratedValue>
                                    <name>0</name>
                                    <description>GTCCRB input capture disabled at the ELC_GPTE input</description>
                                    <value>#0</value>
                                </enumeratedValue>
                                <enumeratedValue>
                                    <name>1</name>
                                    <description>GTCCRB input capture enabled at the ELC_GPTE input</description>
                                    <value>#1</value>
                                </enumeratedValue>
                            </enumeratedValues>
                        </field>
                        <field>
                            <name>BSELCF</name>
                            <description>ELC_GPTF Event Source GTCCRB Input Capture Enable</description>
                            <lsb>21</lsb>
                            <msb>21</msb>
                            <access>read-write</access>
                            <enumeratedValues>
                                <enumeratedValue>
                                    <name>0</name>
                                    <description>GTCCRB input capture disabled at the ELC_GPTF input</description>
                                    <value>#0</value>
                                </enumeratedValue>
                                <enumeratedValue>
                                    <name>1</name>
                                    <description>GTCCRB input capture enabled at the ELC_GPTF input</description>
                                    <value>#1</value>
                                </enumeratedValue>
                            </enumeratedValues>
                        </field>
                        <field>
                            <name>BSELCG</name>
                            <description>ELC_GPTG Event Source GTCCRB Input Capture Enable</description>
                            <lsb>22</lsb>
                            <msb>22</msb>
                            <access>read-write</access>
                            <enumeratedValues>
                                <enumeratedValue>
                                    <name>0</name>
                                    <description>GTCCRB input capture disabled at the ELC_GPTG input</description>
                                    <value>#0</value>
                                </enumeratedValue>
                                <enumeratedValue>
                                    <name>1</name>
                                    <description>GTCCRB input capture enabled at the ELC_GPTG input</description>
                                    <value>#1</value>
                                </enumeratedValue>
                            </enumeratedValues>
                        </field>
                        <field>
                            <name>BSELCH</name>
                            <description>ELC_GPTH Event Source GTCCRB Input Capture Enable</description>
                            <lsb>23</lsb>
                            <msb>23</msb>
                            <access>read-write</access>
                            <enumeratedValues>
                                <enumeratedValue>
                                    <name>0</name>
                                    <description>GTCCRB input capture disabled at the ELC_GPTH input</description>
                                    <value>#0</value>
                                </enumeratedValue>
                                <enumeratedValue>
                                    <name>1</name>
                                    <description>GTCCRB input capture enabled at the ELC_GPTH input</description>
                                    <value>#1</value>
                                </enumeratedValue>
                            </enumeratedValues>
                        </field>
                    </fields>
                </register>
                <register>
                    <name>GTCR</name>
                    <description>General PWM Timer Control Register</description>
                    <addressOffset>0x2C</addressOffset>
                    <size>32</size>
                    <access>read-write</access>
                    <resetValue>0x00000000</resetValue>
                    <resetMask>0xffffffff</resetMask>
                    <fields>
                        <field>
                            <name>CST</name>
                            <description>Count Start</description>
                            <lsb>0</lsb>
                            <msb>0</msb>
                            <access>read-write</access>
                            <enumeratedValues>
                                <enumeratedValue>
                                    <name>0</name>
                                    <description>Count operation is stopped</description>
                                    <value>#0</value>
                                </enumeratedValue>
                                <enumeratedValue>
                                    <name>1</name>
                                    <description>Count operation is performed</description>
                                    <value>#1</value>
                                </enumeratedValue>
                            </enumeratedValues>
                        </field>
                        <field>
                            <name>MD</name>
                            <description>Mode Select</description>
                            <lsb>16</lsb>
                            <msb>18</msb>
                            <access>read-write</access>
                            <enumeratedValues>
                                <enumeratedValue>
                                    <name>000</name>
                                    <description>Saw-wave PWM mode (single buffer or double buffer possible)</description>
                                    <value>#000</value>
                                </enumeratedValue>
                                <enumeratedValue>
                                    <name>001</name>
                                    <description>Saw-wave one-shot pulse mode (fixed buffer operation)</description>
                                    <value>#001</value>
                                </enumeratedValue>
                                <enumeratedValue>
                                    <name>010</name>
                                    <description>Setting prohibited</description>
                                    <value>#010</value>
                                </enumeratedValue>
                                <enumeratedValue>
                                    <name>011</name>
                                    <description>Setting prohibited</description>
                                    <value>#011</value>
                                </enumeratedValue>
                                <enumeratedValue>
                                    <name>100</name>
                                    <description>Triangle-wave PWM mode 1 (32-bit transfer at trough) (single buffer or double buffer is possible)</description>
                                    <value>#100</value>
                                </enumeratedValue>
                                <enumeratedValue>
                                    <name>101</name>
                                    <description>Triangle-wave PWM mode 2 (32-bit transfer at crest and trough) (single buffer or double buffer is possible)</description>
                                    <value>#101</value>
                                </enumeratedValue>
                                <enumeratedValue>
                                    <name>110</name>
                                    <description>Triangle-wave PWM mode 3 (64-bit transfer at trough) (fixed buffer operation)</description>
                                    <value>#110</value>
                                </enumeratedValue>
                                <enumeratedValue>
                                    <name>111</name>
                                    <description>Setting prohibited</description>
                                    <value>#111</value>
                                </enumeratedValue>
                            </enumeratedValues>
                        </field>
                        <field>
                            <name>TPCS</name>
                            <description>Timer Prescaler Select</description>
                            <lsb>23</lsb>
                            <msb>26</msb>
                            <access>read-write</access>
                            <enumeratedValues>
                                <enumeratedValue>
                                    <name>0x0</name>
                                    <description>PCLKD/1 </description>
                                    <value>0x0</value>
                                </enumeratedValue>
                                <enumeratedValue>
                                    <name>0x1</name>
                                    <description>PCLKD/2 </description>
                                    <value>0x1</value>
                                </enumeratedValue>
                                <enumeratedValue>
                                    <name>0x2</name>
                                    <description>PCLKD/4 </description>
                                    <value>0x2</value>
                                </enumeratedValue>
                                <enumeratedValue>
                                    <name>0x3</name>
                                    <description>PCLKD/8 </description>
                                    <value>0x3</value>
                                </enumeratedValue>
                                <enumeratedValue>
                                    <name>0x4</name>
                                    <description>PCLKD/16 </description>
                                    <value>0x4</value>
                                </enumeratedValue>
                                <enumeratedValue>
                                    <name>0x5</name>
                                    <description>PCLKD/32 </description>
                                    <value>0x5</value>
                                </enumeratedValue>
                                <enumeratedValue>
                                    <name>0x6</name>
                                    <description>PCLKD/64 </description>
                                    <value>0x6</value>
                                </enumeratedValue>
                                <enumeratedValue>
                                    <name>0x7</name>
                                    <description>Setting prohibited</description>
                                    <value>0x7</value>
                                </enumeratedValue>
                                <enumeratedValue>
                                    <name>0x8</name>
                                    <description>PCLKD/256 </description>
                                    <value>0x8</value>
                                </enumeratedValue>
                                <enumeratedValue>
                                    <name>0x9</name>
                                    <description>Setting prohibited</description>
                                    <value>0x9</value>
                                </enumeratedValue>
                                <enumeratedValue>
                                    <name>0xA</name>
                                    <description>PCLKD/1024 </description>
                                    <value>0xa</value>
                                </enumeratedValue>
                                <enumeratedValue>
                                    <name>0xB</name>
                                    <description>Setting prohibited</description>
                                    <value>0xb</value>
                                </enumeratedValue>
                                <enumeratedValue>
                                    <name>0xC</name>
                                    <description>GTETRGA (Via the POEG)</description>
                                    <value>0xc</value>
                                </enumeratedValue>
                                <enumeratedValue>
                                    <name>0xD</name>
                                    <description>GTETRGB (Via the POEG)</description>
                                    <value>0xd</value>
                                </enumeratedValue>
                                <enumeratedValue>
                                    <name>0xE</name>
                                    <description>GTETRGC (Via the POEG)</description>
                                    <value>0xe</value>
                                </enumeratedValue>
                                <enumeratedValue>
                                    <name>0xF</name>
                                    <description>GTETRGD (Via the POEG)</description>
                                    <value>0xf</value>
                                </enumeratedValue>
                            </enumeratedValues>
                        </field>
                    </fields>
                </register>
                <register>
                    <name>GTINTAD</name>
                    <description>General PWM Timer Interrupt Output Setting Register</description>
                    <addressOffset>0x38</addressOffset>
                    <size>32</size>
                    <access>read-write</access>
                    <resetValue>0x00000000</resetValue>
                    <resetMask>0xffffffff</resetMask>
                    <fields>
                        <field>
                            <name>GRP</name>
                            <description>Output Disable Source Select</description>
                            <lsb>24</lsb>
                            <msb>25</msb>
                            <access>read-write</access>
                            <enumeratedValues>
                                <enumeratedValue>
                                    <name>00</name>
                                    <description>Group A output disable request is selected</description>
                                    <value>#00</value>
                                </enumeratedValue>
                                <enumeratedValue>
                                    <name>01</name>
                                    <description>Group B output disable request is selected</description>
                                    <value>#01</value>
                                </enumeratedValue>
                                <enumeratedValue>
                                    <name>10</name>
                                    <description>Group C output disable request is selected</description>
                                    <value>#10</value>
                                </enumeratedValue>
                                <enumeratedValue>
                                    <name>11</name>
                                    <description>Group D output disable request is selected</description>
                                    <value>#11</value>
                                </enumeratedValue>
                            </enumeratedValues>
                        </field>
                        <field>
                            <name>GRPABH</name>
                            <description>Same Time Output Level High Disable Request Enable</description>
                            <lsb>29</lsb>
                            <msb>29</msb>
                            <access>read-write</access>
                            <enumeratedValues>
                                <enumeratedValue>
                                    <name>0</name>
                                    <description>Same time output level high disable request disabled</description>
                                    <value>#0</value>
                                </enumeratedValue>
                                <enumeratedValue>
                                    <name>1</name>
                                    <description>Same time output level high disable request enabled</description>
                                    <value>#1</value>
                                </enumeratedValue>
                            </enumeratedValues>
                        </field>
                        <field>
                            <name>GRPABL</name>
                            <description>Same Time Output Level Low Disable Request Enable</description>
                            <lsb>30</lsb>
                            <msb>30</msb>
                            <access>read-write</access>
                            <enumeratedValues>
                                <enumeratedValue>
                                    <name>0</name>
                                    <description>Same time output level low disable request disabled</description>
                                    <value>#0</value>
                                </enumeratedValue>
                                <enumeratedValue>
                                    <name>1</name>
                                    <description>Same time output level low disable request enabled</description>
                                    <value>#1</value>
                                </enumeratedValue>
                            </enumeratedValues>
                        </field>
                    </fields>
                </register>
                <register>
                    <name>GTADTRA</name>
                    <description>A/D Conversion Start Request Timing Register A</description>
                    <addressOffset>0x70</addressOffset>
                    <size>32</size>
                    <access>read-write</access>
                    <resetValue>0xffffffff</resetValue>
                    <resetMask>0xffffffff</resetMask>
                </register>
                <register>
                    <name>GTADTBRA</name>
                    <description>A/D Conversion Start Request Timing Buffer Register A</description>
                    <addressOffset>0x74</addressOffset>
                    <size>32</size>
                    <access>read-write</access>
                    <resetValue>0xffffffff</resetValue>
                    <resetMask>0xffffffff</resetMask>
                </register>
                <register>
                    <name>GTADTDBRA</name>
                    <description>A/D Conversion Start Request Timing Double-Buffer Register A</description>
                    <addressOffset>0x78</addressOffset>
                    <size>32</size>
                    <access>read-write</access>
                    <resetValue>0xffffffff</resetValue>
                    <resetMask>0xffffffff</resetMask>
                </register>
                <register>
                    <name>GTADTRB</name>
                    <description>A/D Conversion Start Request Timing Register B</description>
                    <addressOffset>0x7C</addressOffset>
                    <size>32</size>
                    <access>read-write</access>
                    <resetValue>0xffffffff</resetValue>
                    <resetMask>0xffffffff</resetMask>
                </register>
                <register>
                    <name>GTADTBRB</name>
                    <description>A/D Conversion Start Request Timing Buffer Register B</description>
                    <addressOffset>0x80</addressOffset>
                    <size>32</size>
                    <access>read-write</access>
                    <resetValue>0xffffffff</resetValue>
                    <resetMask>0xffffffff</resetMask>
                </register>
                <register>
                    <name>GTADTDBRB</name>
                    <description>A/D Conversion Start Request Timing Double-Buffer Register B</description>
                    <addressOffset>0x84</addressOffset>
                    <size>32</size>
                    <access>read-write</access>
                    <resetValue>0xffffffff</resetValue>
                    <resetMask>0xffffffff</resetMask>
                </register>
                <register>
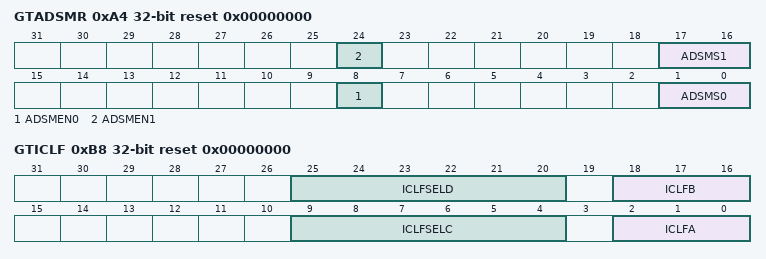
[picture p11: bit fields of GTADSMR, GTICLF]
                    <name>GTADSMR</name>
                    <description>General PWM Timer A/D Conversion Start Request Signal Monitoring Register</description>
                    <addressOffset>0xA4</addressOffset>
                    <size>32</size>
                    <access>read-write</access>
                    <resetValue>0x00000000</resetValue>
                    <resetMask>0xffffffff</resetMask>
                    <fields>
                        <field>
                            <name>ADSMS0</name>
                            <description>A/D Conversion Start Request Signal Monitor 0 Selection</description>
                            <lsb>0</lsb>
                            <msb>1</msb>
                            <access>read-write</access>
                            <enumeratedValues>
                                <enumeratedValue>
                                    <name>00</name>
                                    <description>A/D conversion start request signal generated by the GTADTRA register during up-counting.</description>
                                    <value>#00</value>
                                </enumeratedValue>
                                <enumeratedValue>
                                    <name>01</name>
                                    <description>A/D conversion start request signal generated by the GTADTRA register during down-counting.</description>
                                    <value>#01</value>
                                </enumeratedValue>
                                <enumeratedValue>
                                    <name>10</name>
                                    <description>A/D conversion start request signal generated by the GTADTRB register during up-counting.</description>
                                    <value>#10</value>
                                </enumeratedValue>
                                <enumeratedValue>
                                    <name>11</name>
                                    <description>A/D conversion start request signal generated by the GTADTRB register during down-counting.</description>
                                    <value>#11</value>
                                </enumeratedValue>
                            </enumeratedValues>
                        </field>
                        <field>
                            <name>ADSMEN0</name>
                            <description>A/D Conversion Start Request Signal Monitor 0 Output Enabling</description>
                            <lsb>8</lsb>
                            <msb>8</msb>
                            <access>read-write</access>
                            <enumeratedValues>
                                <enumeratedValue>
                                    <name>0</name>
                                    <description>Output of A/D conversion start request signal monitor 0 is disabled.</description>
                                    <value>#0</value>
                                </enumeratedValue>
                                <enumeratedValue>
                                    <name>1</name>
                                    <description>Output of A/D conversion start request signal monitor 0 is enabled.</description>
                                    <value>#1</value>
                                </enumeratedValue>
                            </enumeratedValues>
                        </field>
                        <field>
                            <name>ADSMS1</name>
                            <description>A/D Conversion Start Request Signal Monitor 1 Selection</description>
                            <lsb>16</lsb>
                            <msb>17</msb>
                            <access>read-write</access>
                            <enumeratedValues>
                                <enumeratedValue>
                                    <name>00</name>
                                    <description>A/D conversion start request signal generated by the GTADTRA register during up-counting.</description>
                                    <value>#00</value>
                                </enumeratedValue>
                                <enumeratedValue>
                                    <name>01</name>
                                    <description>A/D conversion start request signal generated by the GTADTRA register during down-counting.</description>
                                    <value>#01</value>
                                </enumeratedValue>
                                <enumeratedValue>
                                    <name>10</name>
                                    <description>A/D conversion start request signal generated by the GTADTRB register during up-counting.</description>
                                    <value>#10</value>
                                </enumeratedValue>
                                <enumeratedValue>
                                    <name>11</name>
                                    <description>A/D conversion start request signal generated by the GTADTRB register during down-counting.</description>
                                    <value>#11</value>
                                </enumeratedValue>
                            </enumeratedValues>
                        </field>
                        <field>
                            <name>ADSMEN1</name>
                            <description>A/D Conversion Start Request Signal Monitor 1 Output Enabling</description>
                            <lsb>24</lsb>
                            <msb>24</msb>
                            <access>read-write</access>
                            <enumeratedValues>
                                <enumeratedValue>
                                    <name>0</name>
                                    <description>Output of A/D conversion start request signal monitor 1 is disabled.</description>
                                    <value>#0</value>
                                </enumeratedValue>
                                <enumeratedValue>
                                    <name>1</name>
                                    <description>Output of A/D conversion start request signal monitor 1 is enabled.</description>
                                    <value>#1</value>
                                </enumeratedValue>
                            </enumeratedValues>
                        </field>
                    </fields>
                </register>
                <register>
                    <name>GTICLF</name>
                    <description>General PWM Timer Inter Channel Logical Operation Function Setting Register</description>
                    <addressOffset>0xB8</addressOffset>
                    <size>32</size>
                    <access>read-write</access>
                    <resetValue>0x00000000</resetValue>
                    <resetMask>0xffffffff</resetMask>
                    <fields>
                        <field>
                            <name>ICLFA</name>
                            <description>GTIOCnA Output Logical Operation Function Select</description>
                            <lsb>0</lsb>
                            <msb>2</msb>
                            <access>read-write</access>
                            <enumeratedValues>
                                <enumeratedValue>
                                    <name>000</name>
                                    <description>A (no delay)</description>
                                    <value>#000</value>
                                </enumeratedValue>
                                <enumeratedValue>
                                    <name>001</name>
                                    <description>NOT A (no delay)</description>
                                    <value>#001</value>
                                </enumeratedValue>
                                <enumeratedValue>
                                    <name>010</name>
                                    <description>C (1PCLKD delay)</description>
                                    <value>#010</value>
                                </enumeratedValue>
                                <enumeratedValue>
                                    <name>011</name>
                                    <description>NOT C (1PCLKD delay)</description>
                                    <value>#011</value>
                                </enumeratedValue>
                                <enumeratedValue>
                                    <name>100</name>
                                    <description>A AND C (1PCLKD delay)</description>
                                    <value>#100</value>
                                </enumeratedValue>
                                <enumeratedValue>
                                    <name>101</name>
                                    <description>A OR C (1PCLKD delay)</description>
                                    <value>#101</value>
                                </enumeratedValue>
                                <enumeratedValue>
                                    <name>110</name>
                                    <description>A EXOR C (1PCLKD delay)</description>
                                    <value>#110</value>
                                </enumeratedValue>
                                <enumeratedValue>
                                    <name>111</name>
                                    <description>A NOR C (1PCLKD delay)</description>
                                    <value>#111</value>
                                </enumeratedValue>
                            </enumeratedValues>
                        </field>
                        <field>
                            <name>ICLFSELC</name>
                            <description>Inter Channel Signal C Select</description>
                            <lsb>4</lsb>
                            <msb>9</msb>
                            <access>read-write</access>
                            <enumeratedValues>
                                <enumeratedValue>
                                    <name>0x00</name>
                                    <description>GTIOC0A</description>
                                    <value>0x00</value>
                                </enumeratedValue>
                                <enumeratedValue>
                                    <name>0x01</name>
                                    <description>GTIOC0B</description>
                                    <value>0x01</value>
                                </enumeratedValue>
                                <enumeratedValue>
                                    <name>0x02</name>
                                    <description>GTIOC1A</description>
                                    <value>0x02</value>
                                </enumeratedValue>
                                <enumeratedValue>
                                    <name>0x03</name>
                                    <description>GTIOC1B</description>
                                    <value>0x03</value>
                                </enumeratedValue>
                                <enumeratedValue>
                                    <name>0x04</name>
                                    <description>GTIOC2A</description>
                                    <value>0x04</value>
                                </enumeratedValue>
                                <enumeratedValue>
                                    <name>0x05</name>
                                    <description>GTIOC2B</description>
                                    <value>0x05</value>
                                </enumeratedValue>
                                <enumeratedValue>
                                    <name>0x06</name>
                                    <description>GTIOC3A</description>
                                    <value>0x06</value>
                                </enumeratedValue>
                                <enumeratedValue>
                                    <name>0x07</name>
                                    <description>GTIOC3B</description>
                                    <value>0x07</value>
                                </enumeratedValue>
                                <enumeratedValue>
                                    <name>0x08</name>
                                    <description>GTIOC4A</description>
                                    <value>0x08</value>
                                </enumeratedValue>
                                <enumeratedValue>
                                    <name>0x09</name>
                                    <description>GTIOC4B</description>
                                    <value>0x09</value>
                                </enumeratedValue>
                                <enumeratedValue>
                                    <name>0x0A</name>
                                    <description>GTIOC5A</description>
                                    <value>0x0a</value>
                                </enumeratedValue>
                                <enumeratedValue>
                                    <name>0x0B</name>
                                    <description>GTIOC5B</description>
                                    <value>0x0b</value>
                                </enumeratedValue>
                                <enumeratedValue>
                                    <name>0x0C</name>
                                    <description>GTIOC6A</description>
                                    <value>0x0c</value>
                                </enumeratedValue>
                                <enumeratedValue>
                                    <name>0x0D</name>
                                    <description>GTIOC6B</description>
                                    <value>0x0d</value>
                                </enumeratedValue>
                                <enumeratedValue>
                                    <name>0x0E</name>
                                    <description>GTIOC7A</description>
                                    <value>0x0e</value>
                                </enumeratedValue>
                                <enumeratedValue>
                                    <name>0x0F</name>
                                    <description>GTIOC7B</description>
                                    <value>0x0f</value>
                                </enumeratedValue>
                                <enumeratedValue>
                                    <name>0x10</name>
                                    <description>GTIOC8A</description>
                                    <value>0x10</value>
                                </enumeratedValue>
                                <enumeratedValue>
                                    <name>0x11</name>
                                    <description>GTIOC8B</description>
                                    <value>0x11</value>
                                </enumeratedValue>
                                <enumeratedValue>
                                    <name>0x12</name>
                                    <description>GTIOC9A</description>
                                    <value>0x12</value>
                                </enumeratedValue>
                                <enumeratedValue>
                                    <name>0x13</name>
                                    <description>GTIOC9B</description>
                                    <value>0x13</value>
                                </enumeratedValue>
                                <enumeratedValue>
                                    <name>Others</name>
                                    <description>Setting prohibited</description>
                                    <isDefault>true</isDefault>
                                </enumeratedValue>
                            </enumeratedValues>
                        </field>
                        <field>
                            <name>ICLFB</name>
                            <description>GTIOCnB Output Logical Operation Function Select</description>
                            <lsb>16</lsb>
                            <msb>18</msb>
                            <access>read-write</access>
                            <enumeratedValues>
                                <enumeratedValue>
                                    <name>000</name>
                                    <description>B (no delay)</description>
                                    <value>#000</value>
                                </enumeratedValue>
                                <enumeratedValue>
                                    <name>001</name>
                                    <description>NOT B (no delay)</description>
                                    <value>#001</value>
                                </enumeratedValue>
                                <enumeratedValue>
                                    <name>010</name>
                                    <description>D (1PCLKD delay)</description>
                                    <value>#010</value>
                                </enumeratedValue>
                                <enumeratedValue>
                                    <name>011</name>
                                    <description>NOT D (1PCLKD delay)</description>
                                    <value>#011</value>
                                </enumeratedValue>
                                <enumeratedValue>
                                    <name>100</name>
                                    <description>B AND D (1PCLKD delay)</description>
                                    <value>#100</value>
                                </enumeratedValue>
                                <enumeratedValue>
                                    <name>101</name>
                                    <description>B OR D (1PCLKDn delay)</description>
                                    <value>#101</value>
                                </enumeratedValue>
                                <enumeratedValue>
                                    <name>110</name>
                                    <description>B EXOR D (1PCLKD delay)</description>
                                    <value>#110</value>
                                </enumeratedValue>
                                <enumeratedValue>
                                    <name>111</name>
                                    <description>B NOR D (1PCLKD delay)</description>
                                    <value>#111</value>
                                </enumeratedValue>
                            </enumeratedValues>
                        </field>
                        <field>
                            <name>ICLFSELD</name>
                            <description>Inter Channel Signal D Select</description>
                            <lsb>20</lsb>
                            <msb>25</msb>
                            <access>read-write</access>
                            <enumeratedValues>
                                <enumeratedValue>
                                    <name>0x00</name>
                                    <description>GTIOC0A</description>
                                    <value>0x00</value>
                                </enumeratedValue>
                                <enumeratedValue>
                                    <name>0x01</name>
                                    <description>GTIOC0B</description>
                                    <value>0x01</value>
                                </enumeratedValue>
                                <enumeratedValue>
                                    <name>0x02</name>
                                    <description>GTIOC1A</description>
                                    <value>0x02</value>
                                </enumeratedValue>
                                <enumeratedValue>
                                    <name>0x03</name>
                                    <description>GTIOC1B</description>
                                    <value>0x03</value>
                                </enumeratedValue>
                                <enumeratedValue>
                                    <name>0x04</name>
                                    <description>GTIOC2A</description>
                                    <value>0x04</value>
                                </enumeratedValue>
                                <enumeratedValue>
                                    <name>0x05</name>
                                    <description>GTIOC2B</description>
                                    <value>0x05</value>
                                </enumeratedValue>
                                <enumeratedValue>
                                    <name>0x06</name>
                                    <description>GTIOC3A</description>
                                    <value>0x06</value>
                                </enumeratedValue>
                                <enumeratedValue>
                                    <name>0x07</name>
                                    <description>GTIOC3B</description>
                                    <value>0x07</value>
                                </enumeratedValue>
                                <enumeratedValue>
                                    <name>0x08</name>
                                    <description>GTIOC4A</description>
                                    <value>0x08</value>
                                </enumeratedValue>
                                <enumeratedValue>
                                    <name>0x09</name>
                                    <description>GTIOC4B</description>
                                    <value>0x09</value>
                                </enumeratedValue>
                                <enumeratedValue>
                                    <name>0x0A</name>
                                    <description>GTIOC5A</description>
                                    <value>0x0a</value>
                                </enumeratedValue>
                                <enumeratedValue>
                                    <name>0x0B</name>
                                    <description>GTIOC5B</description>
                                    <value>0x0b</value>
                                </enumeratedValue>
                                <enumeratedValue>
                                    <name>0x0C</name>
                                    <description>GTIOC6A</description>
                                    <value>0x0c</value>
                                </enumeratedValue>
                                <enumeratedValue>
                                    <name>0x0D</name>
                                    <description>GTIOC6B</description>
                                    <value>0x0d</value>
                                </enumeratedValue>
                                <enumeratedValue>
                                    <name>0x0E</name>
                                    <description>GTIOC7A</description>
                                    <value>0x0e</value>
                                </enumeratedValue>
                                <enumeratedValue>
                                    <name>0x0F</name>
                                    <description>GTIOC7B</description>
                                    <value>0x0f</value>
                                </enumeratedValue>
                                <enumeratedValue>
                                    <name>0x10</name>
                                    <description>GTIOC8A</description>
                                    <value>0x10</value>
                                </enumeratedValue>
                                <enumeratedValue>
                                    <name>0x11</name>
                                    <description>GTIOC8B</description>
                                    <value>0x11</value>
                                </enumeratedValue>
                                <enumeratedValue>
                                    <name>0x12</name>
                                    <description>GTIOC9A</description>
                                    <value>0x12</value>
                                </enumeratedValue>
                                <enumeratedValue>
                                    <name>0x13</name>
                                    <description>GTIOC9B</description>
                                    <value>0x13</value>
                                </enumeratedValue>
                                <enumeratedValue>
                                    <name>Others</name>
                                    <description>Setting prohibited</description>
                                    <isDefault>true</isDefault>
                                </enumeratedValue>
                            </enumeratedValues>
                        </field>
                    </fields>
                </register>
            </registers>
        </peripheral>
        <peripheral derivedFrom="GPT168">
            <name>GPT169</name>
            <description>General PWM 16-bit Timer 9</description>
            <baseAddress>0x40322900</baseAddress>
        </peripheral>
        <peripheral>
            <name>GPT1610</name>
            <description>General PWM 16-bit Timer 10</description>
            <baseAddress>0x40322A00</baseAddress>
            <addressBlock>
                <offset>0x00</offset>
                <size>4</size>
                <usage>registers</usage>
            </addressBlock>
            <addressBlock>
                <offset>0x30</offset>
                <size>8</size>
                <usage>registers</usage>
            </addressBlock>
            <addressBlock>
                <offset>0x3C</offset>
                <size>8</size>
                <usage>registers</usage>
            </addressBlock>
            <addressBlock>
                <offset>0x48</offset>
                <size>36</size>
                <usage>registers</usage>
            </addressBlock>
            <addressBlock>
                <offset>0x88</offset>
                <size>8</size>
                <usage>registers</usage>
            </addressBlock>
            <addressBlock>
                <offset>0xBC</offset>
                <size>4</size>
                <usage>registers</usage>
            </addressBlock>
            <addressBlock>
                <offset>0xD0</offset>
                <size>8</size>
                <usage>registers</usage>
            </addressBlock>
            <registers>
                <register>
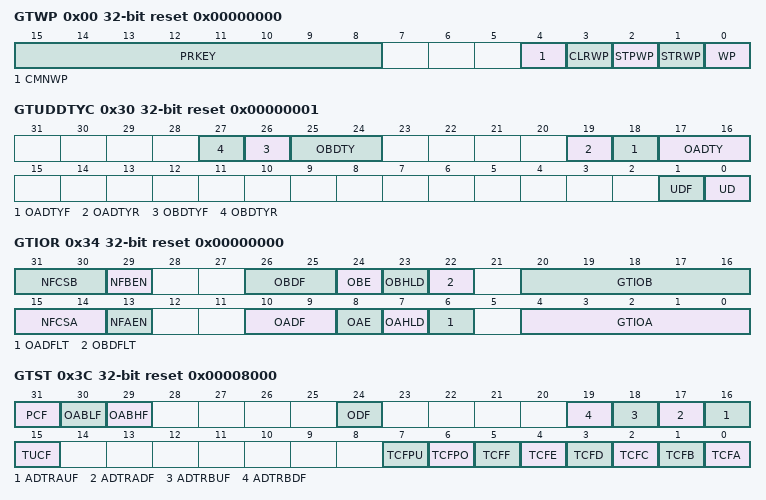
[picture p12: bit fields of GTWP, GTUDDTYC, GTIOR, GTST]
                    <name>GTWP</name>
                    <description>General PWM Timer Write-Protection Register</description>
                    <addressOffset>0x00</addressOffset>
                    <size>32</size>
                    <access>read-write</access>
                    <resetValue>0x00000000</resetValue>
                    <resetMask>0xffffffff</resetMask>
                    <fields>
                        <field>
                            <name>WP</name>
                            <description>Register Write Disable</description>
                            <lsb>0</lsb>
                            <msb>0</msb>
                            <access>read-write</access>
                            <enumeratedValues>
                                <enumeratedValue>
                                    <name>0</name>
                                    <description>Write to the register enabled</description>
                                    <value>#0</value>
                                </enumeratedValue>
                                <enumeratedValue>
                                    <name>1</name>
                                    <description>Write to the register disabled</description>
                                    <value>#1</value>
                                </enumeratedValue>
                            </enumeratedValues>
                        </field>
                        <field>
                            <name>STRWP</name>
                            <description>GTSTR.CSTRT Bit Write Disable</description>
                            <lsb>1</lsb>
                            <msb>1</msb>
                            <access>read-write</access>
                            <enumeratedValues>
                                <enumeratedValue>
                                    <name>0</name>
                                    <description>Write to the bit is enabled</description>
                                    <value>#0</value>
                                </enumeratedValue>
                                <enumeratedValue>
                                    <name>1</name>
                                    <description>Write to the bit is disabled</description>
                                    <value>#1</value>
                                </enumeratedValue>
                            </enumeratedValues>
                        </field>
                        <field>
                            <name>STPWP</name>
                            <description>GTSTP.CSTOP Bit Write Disable</description>
                            <lsb>2</lsb>
                            <msb>2</msb>
                            <access>read-write</access>
                            <enumeratedValues>
                                <enumeratedValue>
                                    <name>0</name>
                                    <description>Write to the bit is enabled</description>
                                    <value>#0</value>
                                </enumeratedValue>
                                <enumeratedValue>
                                    <name>1</name>
                                    <description>Write to the bit is disabled</description>
                                    <value>#1</value>
                                </enumeratedValue>
                            </enumeratedValues>
                        </field>
                        <field>
                            <name>CLRWP</name>
                            <description>GTCLR.CCLR Bit Write Disable</description>
                            <lsb>3</lsb>
                            <msb>3</msb>
                            <access>read-write</access>
                            <enumeratedValues>
                                <enumeratedValue>
                                    <name>0</name>
                                    <description>Write to the bit is enabled</description>
                                    <value>#0</value>
                                </enumeratedValue>
                                <enumeratedValue>
                                    <name>1</name>
                                    <description>Write to the bit is disabled</description>
                                    <value>#1</value>
                                </enumeratedValue>
                            </enumeratedValues>
                        </field>
                        <field>
                            <name>CMNWP</name>
                            <description>Common Register Write Disabled</description>
                            <lsb>4</lsb>
                            <msb>4</msb>
                            <access>read-write</access>
                            <enumeratedValues>
                                <enumeratedValue>
                                    <name>0</name>
                                    <description>Write to the register is enabled</description>
                                    <value>#0</value>
                                </enumeratedValue>
                                <enumeratedValue>
                                    <name>1</name>
                                    <description>Write to the register is disabled</description>
                                    <value>#1</value>
                                </enumeratedValue>
                            </enumeratedValues>
                        </field>
                        <field>
                            <name>PRKEY</name>
                            <description>GTWP Key Code</description>
                            <lsb>8</lsb>
                            <msb>15</msb>
                            <access>write-only</access>
                        </field>
                    </fields>
                </register>
                <register>
                    <name>GTUDDTYC</name>
                    <description>General PWM Timer Count Direction and Duty Setting Register</description>
                    <addressOffset>0x30</addressOffset>
                    <size>32</size>
                    <access>read-write</access>
                    <resetValue>0x00000001</resetValue>
                    <resetMask>0xffffffff</resetMask>
                    <fields>
                        <field>
                            <name>UD</name>
                            <description>Count Direction Setting</description>
                            <lsb>0</lsb>
                            <msb>0</msb>
                            <access>read-write</access>
                            <enumeratedValues>
                                <enumeratedValue>
                                    <name>0</name>
                                    <description>GTCNT counts down</description>
                                    <value>#0</value>
                                </enumeratedValue>
                                <enumeratedValue>
                                    <name>1</name>
                                    <description>GTCNT counts up</description>
                                    <value>#1</value>
                                </enumeratedValue>
                            </enumeratedValues>
                        </field>
                        <field>
                            <name>UDF</name>
                            <description>Forcible Count Direction Setting</description>
                            <lsb>1</lsb>
                            <msb>1</msb>
                            <access>read-write</access>
                            <enumeratedValues>
                                <enumeratedValue>
                                    <name>0</name>
                                    <description>Not forcibly set</description>
                                    <value>#0</value>
                                </enumeratedValue>
                                <enumeratedValue>
                                    <name>1</name>
                                    <description>Forcibly set</description>
                                    <value>#1</value>
                                </enumeratedValue>
                            </enumeratedValues>
                        </field>
                        <field>
                            <name>OADTY</name>
                            <description>GTIOCnA Output Duty Setting</description>
                            <lsb>16</lsb>
                            <msb>17</msb>
                            <access>read-write</access>
                            <enumeratedValues>
                                <enumeratedValue>
                                    <name>00</name>
                                    <description>GTIOCnA pin duty depends on the compare match</description>
                                    <value>#00</value>
                                </enumeratedValue>
                                <enumeratedValue>
                                    <name>01</name>
                                    <description>GTIOCnA pin duty depends on the compare match</description>
                                    <value>#01</value>
                                </enumeratedValue>
                                <enumeratedValue>
                                    <name>10</name>
                                    <description>GTIOCnA pin duty 0%</description>
                                    <value>#10</value>
                                </enumeratedValue>
                                <enumeratedValue>
                                    <name>11</name>
                                    <description>GTIOCnA pin duty 100%</description>
                                    <value>#11</value>
                                </enumeratedValue>
                            </enumeratedValues>
                        </field>
                        <field>
                            <name>OADTYF</name>
                            <description>Forcible GTIOCnA Output Duty Setting</description>
                            <lsb>18</lsb>
                            <msb>18</msb>
                            <access>read-write</access>
                            <enumeratedValues>
                                <enumeratedValue>
                                    <name>0</name>
                                    <description>Not forcibly set</description>
                                    <value>#0</value>
                                </enumeratedValue>
                                <enumeratedValue>
                                    <name>1</name>
                                    <description>Forcibly set</description>
                                    <value>#1</value>
                                </enumeratedValue>
                            </enumeratedValues>
                        </field>
                        <field>
                            <name>OADTYR</name>
                            <description>GTIOCnA Output Value Selecting after Releasing 0%/100% Duty Setting</description>
                            <lsb>19</lsb>
                            <msb>19</msb>
                            <access>read-write</access>
                            <enumeratedValues>
                                <enumeratedValue>
                                    <name>0</name>
                                    <description>The function selected by the GTIOA[3:2] bits is applied to the output value when the duty cycle is set after release from the 0 or 100% duty-cycle setting.</description>
                                    <value>#0</value>
                                </enumeratedValue>
                                <enumeratedValue>
                                    <name>1</name>
                                    <description>The function selected by the GTIOA[3:2] bits is applied to the compare match output value which is masked after release from the 0 or 100% duty-cycle setting.</description>
                                    <value>#1</value>
                                </enumeratedValue>
                            </enumeratedValues>
                        </field>
                        <field>
                            <name>OBDTY</name>
                            <description>GTIOCnB Output Duty Setting</description>
                            <lsb>24</lsb>
                            <msb>25</msb>
                            <access>read-write</access>
                            <enumeratedValues>
                                <enumeratedValue>
                                    <name>00</name>
                                    <description>GTIOCnB pin duty depends on the compare match</description>
                                    <value>#00</value>
                                </enumeratedValue>
                                <enumeratedValue>
                                    <name>01</name>
                                    <description>GTIOCnB pin duty depends on the compare match</description>
                                    <value>#01</value>
                                </enumeratedValue>
                                <enumeratedValue>
                                    <name>10</name>
                                    <description>GTIOCnB pin duty 0%</description>
                                    <value>#10</value>
                                </enumeratedValue>
                                <enumeratedValue>
                                    <name>11</name>
                                    <description>GTIOCnB pin duty 100%</description>
                                    <value>#11</value>
                                </enumeratedValue>
                            </enumeratedValues>
                        </field>
                        <field>
                            <name>OBDTYF</name>
                            <description>Forcible GTIOCnB Output Duty Setting</description>
                            <lsb>26</lsb>
                            <msb>26</msb>
                            <access>read-write</access>
                            <enumeratedValues>
                                <enumeratedValue>
                                    <name>0</name>
                                    <description>Not forcibly set</description>
                                    <value>#0</value>
                                </enumeratedValue>
                                <enumeratedValue>
                                    <name>1</name>
                                    <description>Forcibly set</description>
                                    <value>#1</value>
                                </enumeratedValue>
                            </enumeratedValues>
                        </field>
                        <field>
                            <name>OBDTYR</name>
                            <description>GTIOCnB Output Value Selecting after Releasing 0%/100% Duty Setting</description>
                            <lsb>27</lsb>
                            <msb>27</msb>
                            <access>read-write</access>
                            <enumeratedValues>
                                <enumeratedValue>
                                    <name>0</name>
                                    <description>The function selected by the GTIOB[3:2] bits is applied to the output value when the duty cycle is set after release from the 0 or 100% duty-cycle setting.</description>
                                    <value>#0</value>
                                </enumeratedValue>
                                <enumeratedValue>
                                    <name>1</name>
                                    <description>The function selected by the GTIOB[3:2] bits is applied to the compare match output value which is masked after release from the 0 or 100% duty-cycle setting.</description>
                                    <value>#1</value>
                                </enumeratedValue>
                            </enumeratedValues>
                        </field>
                    </fields>
                </register>
                <register>
                    <name>GTIOR</name>
                    <description>General PWM Timer I/O Control Register</description>
                    <addressOffset>0x34</addressOffset>
                    <size>32</size>
                    <access>read-write</access>
                    <resetValue>0x00000000</resetValue>
                    <resetMask>0xffffffff</resetMask>
                    <fields>
                        <field>
                            <name>GTIOA</name>
                            <description>GTIOCnA Pin Function Select</description>
                            <lsb>0</lsb>
                            <msb>4</msb>
                            <access>read-write</access>
                        </field>
                        <field>
                            <name>OADFLT</name>
                            <description>GTIOCnA Pin Output Value Setting at the Count Stop</description>
                            <lsb>6</lsb>
                            <msb>6</msb>
                            <access>read-write</access>
                            <enumeratedValues>
                                <enumeratedValue>
                                    <name>0</name>
                                    <description>The GTIOCnA pin outputs low when counting stops</description>
                                    <value>#0</value>
                                </enumeratedValue>
                                <enumeratedValue>
                                    <name>1</name>
                                    <description>The GTIOCnA pin outputs high when counting stops</description>
                                    <value>#1</value>
                                </enumeratedValue>
                            </enumeratedValues>
                        </field>
                        <field>
                            <name>OAHLD</name>
                            <description>GTIOCnA Pin Output Setting at the Start/Stop Count</description>
                            <lsb>7</lsb>
                            <msb>7</msb>
                            <access>read-write</access>
                            <enumeratedValues>
                                <enumeratedValue>
                                    <name>0</name>
                                    <description>The GTIOCnA pin output level at the start or stop of counting depends on the register setting</description>
                                    <value>#0</value>
                                </enumeratedValue>
                                <enumeratedValue>
                                    <name>1</name>
                                    <description>The GTIOCnA pin output level is retained at the start or stop of counting</description>
                                    <value>#1</value>
                                </enumeratedValue>
                            </enumeratedValues>
                        </field>
                        <field>
                            <name>OAE</name>
                            <description>GTIOCnA Pin Output Enable</description>
                            <lsb>8</lsb>
                            <msb>8</msb>
                            <access>read-write</access>
                            <enumeratedValues>
                                <enumeratedValue>
                                    <name>0</name>
                                    <description>Output is disabled</description>
                                    <value>#0</value>
                                </enumeratedValue>
                                <enumeratedValue>
                                    <name>1</name>
                                    <description>Output is enabled</description>
                                    <value>#1</value>
                                </enumeratedValue>
                            </enumeratedValues>
                        </field>
                        <field>
                            <name>OADF</name>
                            <description>GTIOCnA Pin Disable Value Setting</description>
                            <lsb>9</lsb>
                            <msb>10</msb>
                            <access>read-write</access>
                            <enumeratedValues>
                                <enumeratedValue>
                                    <name>00</name>
                                    <description>None of the below options are specified</description>
                                    <value>#00</value>
                                </enumeratedValue>
                                <enumeratedValue>
                                    <name>01</name>
                                    <description>GTIOCnA pin is set to Hi-Z in response to controlling the output negation</description>
                                    <value>#01</value>
                                </enumeratedValue>
                                <enumeratedValue>
                                    <name>10</name>
                                    <description>GTIOCnA pin is set to 0 in response to controlling the output negation</description>
                                    <value>#10</value>
                                </enumeratedValue>
                                <enumeratedValue>
                                    <name>11</name>
                                    <description>GTIOCnA pin is set to 1 in response to controlling the output negation</description>
                                    <value>#11</value>
                                </enumeratedValue>
                            </enumeratedValues>
                        </field>
                        <field>
                            <name>NFAEN</name>
                            <description>Noise Filter A Enable</description>
                            <lsb>13</lsb>
                            <msb>13</msb>
                            <access>read-write</access>
                            <enumeratedValues>
                                <enumeratedValue>
                                    <name>0</name>
                                    <description>The noise filter for the GTIOCnA pin is disabled</description>
                                    <value>#0</value>
                                </enumeratedValue>
                                <enumeratedValue>
                                    <name>1</name>
                                    <description>The noise filter for the GTIOCnA pin is enabled</description>
                                    <value>#1</value>
                                </enumeratedValue>
                            </enumeratedValues>
                        </field>
                        <field>
                            <name>NFCSA</name>
                            <description>Noise Filter A Sampling Clock Select</description>
                            <lsb>14</lsb>
                            <msb>15</msb>
                            <access>read-write</access>
                            <enumeratedValues>
                                <enumeratedValue>
                                    <name>00</name>
                                    <description>PCLKD/1</description>
                                    <value>#00</value>
                                </enumeratedValue>
                                <enumeratedValue>
                                    <name>01</name>
                                    <description>PCLKD/4</description>
                                    <value>#01</value>
                                </enumeratedValue>
                                <enumeratedValue>
                                    <name>10</name>
                                    <description>PCLKD/16</description>
                                    <value>#10</value>
                                </enumeratedValue>
                                <enumeratedValue>
                                    <name>11</name>
                                    <description>PCLKD/64</description>
                                    <value>#11</value>
                                </enumeratedValue>
                            </enumeratedValues>
                        </field>
                        <field>
                            <name>GTIOB</name>
                            <description>GTIOCnB Pin Function Select</description>
                            <lsb>16</lsb>
                            <msb>20</msb>
                            <access>read-write</access>
                        </field>
                        <field>
                            <name>OBDFLT</name>
                            <description>GTIOCnB Pin Output Value Setting at the Count Stop</description>
                            <lsb>22</lsb>
                            <msb>22</msb>
                            <access>read-write</access>
                            <enumeratedValues>
                                <enumeratedValue>
                                    <name>0</name>
                                    <description>The GTIOCnB pin outputs low when counting stops</description>
                                    <value>#0</value>
                                </enumeratedValue>
                                <enumeratedValue>
                                    <name>1</name>
                                    <description>The GTIOCnB pin outputs high when counting stops</description>
                                    <value>#1</value>
                                </enumeratedValue>
                            </enumeratedValues>
                        </field>
                        <field>
                            <name>OBHLD</name>
                            <description>GTIOCnB Pin Output Setting at the Start/Stop Count</description>
                            <lsb>23</lsb>
                            <msb>23</msb>
                            <access>read-write</access>
                            <enumeratedValues>
                                <enumeratedValue>
                                    <name>0</name>
                                    <description>The GTIOCnB pin output level at the start/stop of counting depends on the register setting</description>
                                    <value>#0</value>
                                </enumeratedValue>
                                <enumeratedValue>
                                    <name>1</name>
                                    <description>The GTIOCnB pin output level is retained at the start/stop of counting</description>
                                    <value>#1</value>
                                </enumeratedValue>
                            </enumeratedValues>
                        </field>
                        <field>
                            <name>OBE</name>
                            <description>GTIOCnB Pin Output Enable</description>
                            <lsb>24</lsb>
                            <msb>24</msb>
                            <access>read-write</access>
                            <enumeratedValues>
                                <enumeratedValue>
                                    <name>0</name>
                                    <description>Output is disabled</description>
                                    <value>#0</value>
                                </enumeratedValue>
                                <enumeratedValue>
                                    <name>1</name>
                                    <description>Output is enabled</description>
                                    <value>#1</value>
                                </enumeratedValue>
                            </enumeratedValues>
                        </field>
                        <field>
                            <name>OBDF</name>
                            <description>GTIOCnB Pin Disable Value Setting</description>
                            <lsb>25</lsb>
                            <msb>26</msb>
                            <access>read-write</access>
                            <enumeratedValues>
                                <enumeratedValue>
                                    <name>00</name>
                                    <description>None of the below options are specified</description>
                                    <value>#00</value>
                                </enumeratedValue>
                                <enumeratedValue>
                                    <name>01</name>
                                    <description>GTIOCnB pin is set to Hi-Z in response to controlling the output negation</description>
                                    <value>#01</value>
                                </enumeratedValue>
                                <enumeratedValue>
                                    <name>10</name>
                                    <description>GTIOCnB pin is set to 0 in response to controlling the output negation</description>
                                    <value>#10</value>
                                </enumeratedValue>
                                <enumeratedValue>
                                    <name>11</name>
                                    <description>GTIOCnB pin is set to 1 in response to controlling the output negation</description>
                                    <value>#11</value>
                                </enumeratedValue>
                            </enumeratedValues>
                        </field>
                        <field>
                            <name>NFBEN</name>
                            <description>Noise Filter B Enable</description>
                            <lsb>29</lsb>
                            <msb>29</msb>
                            <access>read-write</access>
                            <enumeratedValues>
                                <enumeratedValue>
                                    <name>0</name>
                                    <description>The noise filter for the GTIOCnB pin is disabled</description>
                                    <value>#0</value>
                                </enumeratedValue>
                                <enumeratedValue>
                                    <name>1</name>
                                    <description>The noise filter for the GTIOCnB pin is enabled</description>
                                    <value>#1</value>
                                </enumeratedValue>
                            </enumeratedValues>
                        </field>
                        <field>
                            <name>NFCSB</name>
                            <description>Noise Filter B Sampling Clock Select</description>
                            <lsb>30</lsb>
                            <msb>31</msb>
                            <access>read-write</access>
                            <enumeratedValues>
                                <enumeratedValue>
                                    <name>00</name>
                                    <description>PCLKD/1</description>
                                    <value>#00</value>
                                </enumeratedValue>
                                <enumeratedValue>
                                    <name>01</name>
                                    <description>PCLKD/4</description>
                                    <value>#01</value>
                                </enumeratedValue>
                                <enumeratedValue>
                                    <name>10</name>
                                    <description>PCLKD/16</description>
                                    <value>#10</value>
                                </enumeratedValue>
                                <enumeratedValue>
                                    <name>11</name>
                                    <description>PCLKD/64</description>
                                    <value>#11</value>
                                </enumeratedValue>
                            </enumeratedValues>
                        </field>
                    </fields>
                </register>
                <register>
                    <name>GTST</name>
                    <description>General PWM Timer Status Register</description>
                    <addressOffset>0x3C</addressOffset>
                    <size>32</size>
                    <access>read-write</access>
                    <resetValue>0x00008000</resetValue>
                    <resetMask>0xffffffff</resetMask>
                    <fields>
                        <field>
                            <name>TCFA</name>
                            <description>Input Capture/Compare Match Flag A</description>
                            <lsb>0</lsb>
                            <msb>0</msb>
                            <access>read-write</access>
                            <enumeratedValues>
                                <enumeratedValue>
                                    <name>0</name>
                                    <description>No input capture/compare match of GTCCRA is generated</description>
                                    <value>#0</value>
                                </enumeratedValue>
                                <enumeratedValue>
                                    <name>1</name>
                                    <description>An input capture/compare match of GTCCRA is generated</description>
                                    <value>#1</value>
                                </enumeratedValue>
                            </enumeratedValues>
                        </field>
                        <field>
                            <name>TCFB</name>
                            <description>Input Capture/Compare Match Flag B</description>
                            <lsb>1</lsb>
                            <msb>1</msb>
                            <access>read-write</access>
                            <enumeratedValues>
                                <enumeratedValue>
                                    <name>0</name>
                                    <description>No input capture/compare match of GTCCRB is generated</description>
                                    <value>#0</value>
                                </enumeratedValue>
                                <enumeratedValue>
                                    <name>1</name>
                                    <description>An input capture/compare match of GTCCRB is generated</description>
                                    <value>#1</value>
                                </enumeratedValue>
                            </enumeratedValues>
                        </field>
                        <field>
                            <name>TCFC</name>
                            <description>Input Compare Match Flag C</description>
                            <lsb>2</lsb>
                            <msb>2</msb>
                            <access>read-write</access>
                            <enumeratedValues>
                                <enumeratedValue>
                                    <name>0</name>
                                    <description>No compare match of GTCCRC is generated</description>
                                    <value>#0</value>
                                </enumeratedValue>
                                <enumeratedValue>
                                    <name>1</name>
                                    <description>A compare match of GTCCRC is generated</description>
                                    <value>#1</value>
                                </enumeratedValue>
                            </enumeratedValues>
                        </field>
                        <field>
                            <name>TCFD</name>
                            <description>Input Compare Match Flag D</description>
                            <lsb>3</lsb>
                            <msb>3</msb>
                            <access>read-write</access>
                            <enumeratedValues>
                                <enumeratedValue>
                                    <name>0</name>
                                    <description>No compare match of GTCCRD is generated</description>
                                    <value>#0</value>
                                </enumeratedValue>
                                <enumeratedValue>
                                    <name>1</name>
                                    <description>A compare match of GTCCRD is generated</description>
                                    <value>#1</value>
                                </enumeratedValue>
                            </enumeratedValues>
                        </field>
                        <field>
                            <name>TCFE</name>
                            <description>Input Compare Match Flag E</description>
                            <lsb>4</lsb>
                            <msb>4</msb>
                            <access>read-write</access>
                            <enumeratedValues>
                                <enumeratedValue>
                                    <name>0</name>
                                    <description>No compare match of GTCCRE is generated</description>
                                    <value>#0</value>
                                </enumeratedValue>
                                <enumeratedValue>
                                    <name>1</name>
                                    <description>A compare match of GTCCRE is generated</description>
                                    <value>#1</value>
                                </enumeratedValue>
                            </enumeratedValues>
                        </field>
                        <field>
                            <name>TCFF</name>
                            <description>Input Compare Match Flag F</description>
                            <lsb>5</lsb>
                            <msb>5</msb>
                            <access>read-write</access>
                            <enumeratedValues>
                                <enumeratedValue>
                                    <name>0</name>
                                    <description>No compare match of GTCCRF is generated</description>
                                    <value>#0</value>
                                </enumeratedValue>
                                <enumeratedValue>
                                    <name>1</name>
                                    <description>A compare match of GTCCRF is generated</description>
                                    <value>#1</value>
                                </enumeratedValue>
                            </enumeratedValues>
                        </field>
                        <field>
                            <name>TCFPO</name>
                            <description>Overflow Flag</description>
                            <lsb>6</lsb>
                            <msb>6</msb>
                            <access>read-write</access>
                            <enumeratedValues>
                                <enumeratedValue>
                                    <name>0</name>
                                    <description>No overflow (crest) occurred</description>
                                    <value>#0</value>
                                </enumeratedValue>
                                <enumeratedValue>
                                    <name>1</name>
                                    <description>An overflow (crest) occurred</description>
                                    <value>#1</value>
                                </enumeratedValue>
                            </enumeratedValues>
                        </field>
                        <field>
                            <name>TCFPU</name>
                            <description>Underflow Flag</description>
                            <lsb>7</lsb>
                            <msb>7</msb>
                            <access>read-write</access>
                            <enumeratedValues>
                                <enumeratedValue>
                                    <name>0</name>
                                    <description>No underflow (trough) occurred</description>
                                    <value>#0</value>
                                </enumeratedValue>
                                <enumeratedValue>
                                    <name>1</name>
                                    <description>An underflow (trough) occurred</description>
                                    <value>#1</value>
                                </enumeratedValue>
                            </enumeratedValues>
                        </field>
                        <field>
                            <name>TUCF</name>
                            <description>Count Direction Flag</description>
                            <lsb>15</lsb>
                            <msb>15</msb>
                            <access>read-only</access>
                            <enumeratedValues>
                                <enumeratedValue>
                                    <name>0</name>
                                    <description>GTCNT counter counts downward</description>
                                    <value>#0</value>
                                </enumeratedValue>
                                <enumeratedValue>
                                    <name>1</name>
                                    <description>GTCNT counter counts upward</description>
                                    <value>#1</value>
                                </enumeratedValue>
                            </enumeratedValues>
                        </field>
                        <field>
                            <name>ADTRAUF</name>
                            <description>GTADTRA Register Compare Match (Up-Counting) A/D Conversion Start Request Flag</description>
                            <lsb>16</lsb>
                            <msb>16</msb>
                            <access>read-write</access>
                            <enumeratedValues>
                                <enumeratedValue>
                                    <name>0</name>
                                    <description>No GTADTRA register compare match has occurred in up-counting.</description>
                                    <value>#0</value>
                                </enumeratedValue>
                                <enumeratedValue>
                                    <name>1</name>
                                    <description>A GTADTRA register compare match has occurred in up-counting.</description>
                                    <value>#1</value>
                                </enumeratedValue>
                            </enumeratedValues>
                        </field>
                        <field>
                            <name>ADTRADF</name>
                            <description>GTADTRA Register Compare Match (Down-Counting) A/D Conversion Start Request Flag</description>
                            <lsb>17</lsb>
                            <msb>17</msb>
                            <access>read-write</access>
                            <enumeratedValues>
                                <enumeratedValue>
                                    <name>0</name>
                                    <description>No GTADTRA register compare match has occurred in down-counting.</description>
                                    <value>#0</value>
                                </enumeratedValue>
                                <enumeratedValue>
                                    <name>1</name>
                                    <description>A GTADTRA register compare match has occurred in down-counting.</description>
                                    <value>#1</value>
                                </enumeratedValue>
                            </enumeratedValues>
                        </field>
                        <field>
                            <name>ADTRBUF</name>
                            <description>GTADTRB Register Compare Match (Up-Counting) A/D Conversion Start Request Flag</description>
                            <lsb>18</lsb>
                            <msb>18</msb>
                            <access>read-write</access>
                            <enumeratedValues>
                                <enumeratedValue>
                                    <name>0</name>
                                    <description>No GTADTRB register compare match has occurred in up-counting.</description>
                                    <value>#0</value>
                                </enumeratedValue>
                                <enumeratedValue>
                                    <name>1</name>
                                    <description>A GTADTRB register compare match has occurred in up-counting.</description>
                                    <value>#1</value>
                                </enumeratedValue>
                            </enumeratedValues>
                        </field>
                        <field>
                            <name>ADTRBDF</name>
                            <description>GTADTRB Register Compare Match (Down-Counting) A/D Conversion Start Request Flag</description>
                            <lsb>19</lsb>
                            <msb>19</msb>
                            <access>read-write</access>
                            <enumeratedValues>
                                <enumeratedValue>
                                    <name>0</name>
                                    <description>No GTADTRB register compare match has occurred in down-counting.</description>
                                    <value>#0</value>
                                </enumeratedValue>
                                <enumeratedValue>
                                    <name>1</name>
                                    <description>A GTADTRB register compare match has occurred in down-counting.</description>
                                    <value>#1</value>
                                </enumeratedValue>
                            </enumeratedValues>
                        </field>
                        <field>
                            <name>ODF</name>
                            <description>Output Disable Flag</description>
                            <lsb>24</lsb>
                            <msb>24</msb>
                            <access>read-only</access>
                            <enumeratedValues>
                                <enumeratedValue>
                                    <name>0</name>
                                    <description>No output disable request is generated</description>
                                    <value>#0</value>
                                </enumeratedValue>
                                <enumeratedValue>
                                    <name>1</name>
                                    <description>An output disable request is generated</description>
                                    <value>#1</value>
                                </enumeratedValue>
                            </enumeratedValues>
                        </field>
                        <field>
                            <name>OABHF</name>
                            <description>Same Time Output Level High Flag</description>
                            <lsb>29</lsb>
                            <msb>29</msb>
                            <access>read-only</access>
                            <enumeratedValues>
                                <enumeratedValue>
                                    <name>0</name>
                                    <description>No simultaneous generation of 1 both for the GTIOCA and GTIOCB pins has occurred.</description>
                                    <value>#0</value>
                                </enumeratedValue>
                                <enumeratedValue>
                                    <name>1</name>
                                    <description>A simultaneous generation of 1 both for the GTIOCA and GTIOCB pins has occurred.</description>
                                    <value>#1</value>
                                </enumeratedValue>
                            </enumeratedValues>
                        </field>
                        <field>
                            <name>OABLF</name>
                            <description>Same Time Output Level Low Flag</description>
                            <lsb>30</lsb>
                            <msb>30</msb>
                            <access>read-only</access>
                            <enumeratedValues>
                                <enumeratedValue>
                                    <name>0</name>
                                    <description>No simultaneous generation of 0 both for the GTIOCA and GTIOCB pins has occurred.</description>
                                    <value>#0</value>
                                </enumeratedValue>
                                <enumeratedValue>
                                    <name>1</name>
                                    <description>A simultaneous generation of 0 both for the GTIOCA and GTIOCB pins has occurred.</description>
                                    <value>#1</value>
                                </enumeratedValue>
                            </enumeratedValues>
                        </field>
                        <field>
                            <name>PCF</name>
                            <description>Period Count Function Finish Flag</description>
                            <lsb>31</lsb>
                            <msb>31</msb>
                            <access>read-write</access>
                            <enumeratedValues>
                                <enumeratedValue>
                                    <name>0</name>
                                    <description>No period count function finish has occurred</description>
                                    <value>#0</value>
                                </enumeratedValue>
                                <enumeratedValue>
                                    <name>1</name>
                                    <description>A period count function finish has occurred</description>
                                    <value>#1</value>
                                </enumeratedValue>
                            </enumeratedValues>
                        </field>
                    </fields>
                </register>
                <register>
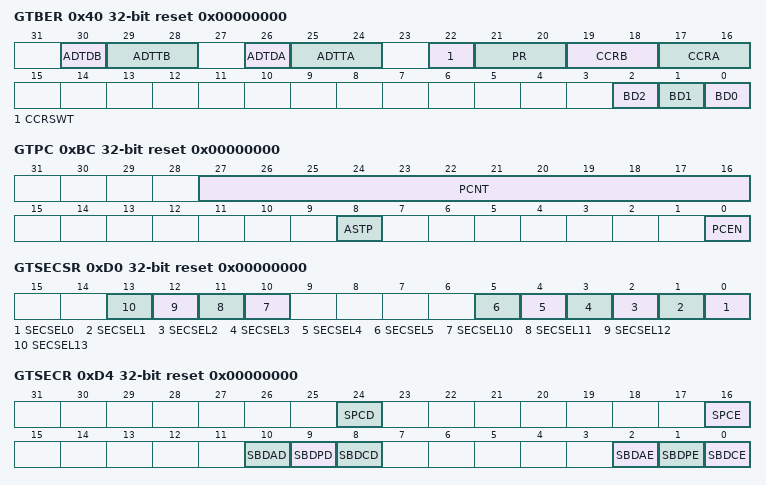
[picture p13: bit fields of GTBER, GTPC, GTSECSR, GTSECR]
                    <name>GTBER</name>
                    <description>General PWM Timer Buffer Enable Register</description>
                    <addressOffset>0x40</addressOffset>
                    <size>32</size>
                    <access>read-write</access>
                    <resetValue>0x00000000</resetValue>
                    <resetMask>0xffffffff</resetMask>
                    <fields>
                        <field>
                            <name>BD0</name>
                            <description>GTCCR Buffer Operation Disable</description>
                            <lsb>0</lsb>
                            <msb>0</msb>
                            <access>read-write</access>
                            <enumeratedValues>
                                <enumeratedValue>
                                    <name>0</name>
                                    <description>Buffer operation is enabled</description>
                                    <value>#0</value>
                                </enumeratedValue>
                                <enumeratedValue>
                                    <name>1</name>
                                    <description>Buffer operation is disabled</description>
                                    <value>#1</value>
                                </enumeratedValue>
                            </enumeratedValues>
                        </field>
                        <field>
                            <name>BD1</name>
                            <description>GTPR Buffer Operation Disable</description>
                            <lsb>1</lsb>
                            <msb>1</msb>
                            <access>read-write</access>
                            <enumeratedValues>
                                <enumeratedValue>
                                    <name>0</name>
                                    <description>Buffer operation is enabled</description>
                                    <value>#0</value>
                                </enumeratedValue>
                                <enumeratedValue>
                                    <name>1</name>
                                    <description>Buffer operation is disabled</description>
                                    <value>#1</value>
                                </enumeratedValue>
                            </enumeratedValues>
                        </field>
                        <field>
                            <name>BD2</name>
                            <description>GTADTRA/GTADTRB Registers Buffer Operation Disable</description>
                            <lsb>2</lsb>
                            <msb>2</msb>
                            <access>read-write</access>
                            <enumeratedValues>
                                <enumeratedValue>
                                    <name>0</name>
                                    <description>Buffer operation is enabled</description>
                                    <value>#0</value>
                                </enumeratedValue>
                                <enumeratedValue>
                                    <name>1</name>
                                    <description>Buffer operation is disabled</description>
                                    <value>#1</value>
                                </enumeratedValue>
                            </enumeratedValues>
                        </field>
                        <field>
                            <name>CCRA</name>
                            <description>GTCCRA Buffer Operation</description>
                            <lsb>16</lsb>
                            <msb>17</msb>
                            <access>read-write</access>
                            <enumeratedValues>
                                <enumeratedValue>
                                    <name>00</name>
                                    <description>No buffer operation</description>
                                    <value>#00</value>
                                </enumeratedValue>
                                <enumeratedValue>
                                    <name>01</name>
                                    <description>Single buffer operation (GTCCRA &lt;----&gt;GTCCRC)</description>
                                    <value>#01</value>
                                </enumeratedValue>
                                <enumeratedValue>
                                    <name>Others</name>
                                    <description>Double buffer operation (GTCCRA &lt;----&gt; GTCCRC &lt;----&gt; GTCCRD)</description>
                                    <isDefault>true</isDefault>
                                </enumeratedValue>
                            </enumeratedValues>
                        </field>
                        <field>
                            <name>CCRB</name>
                            <description>GTCCRB Buffer Operation</description>
                            <lsb>18</lsb>
                            <msb>19</msb>
                            <access>read-write</access>
                            <enumeratedValues>
                                <enumeratedValue>
                                    <name>00</name>
                                    <description>No buffer operation</description>
                                    <value>#00</value>
                                </enumeratedValue>
                                <enumeratedValue>
                                    <name>01</name>
                                    <description>Single buffer operation (GTCCRB &lt;----&gt; GTCCRE)</description>
                                    <value>#01</value>
                                </enumeratedValue>
                                <enumeratedValue>
                                    <name>Others</name>
                                    <description>Double buffer operation (GTCCRB &lt;----&gt; GTCCRE &lt;----&gt; GTCCRF)</description>
                                    <isDefault>true</isDefault>
                                </enumeratedValue>
                            </enumeratedValues>
                        </field>
                        <field>
                            <name>PR</name>
                            <description>GTPR Buffer Operation</description>
                            <lsb>20</lsb>
                            <msb>21</msb>
                            <access>read-write</access>
                            <enumeratedValues>
                                <enumeratedValue>
                                    <name>00</name>
                                    <description>No buffer operation</description>
                                    <value>#00</value>
                                </enumeratedValue>
                                <enumeratedValue>
                                    <name>01</name>
                                    <description>Single buffer operation (GTPBR --&gt; GTPR)</description>
                                    <value>#01</value>
                                </enumeratedValue>
                                <enumeratedValue>
                                    <name>Others</name>
                                    <description>Setting prohibited</description>
                                    <isDefault>true</isDefault>
                                </enumeratedValue>
                            </enumeratedValues>
                        </field>
                        <field>
                            <name>CCRSWT</name>
                            <description>GTCCRA and GTCCRB Forcible Buffer Operation</description>
                            <lsb>22</lsb>
                            <msb>22</msb>
                            <access>write-only</access>
                        </field>
                        <field>
                            <name>ADTTA</name>
                            <description>GTADTRA Register Buffer Transfer Timing Select</description>
                            <lsb>24</lsb>
                            <msb>25</msb>
                            <access>read-write</access>
                            <enumeratedValues>
                                <enumeratedValue>
                                    <name>00</name>
                                    <description>In triangle wave mode, no transfer. In saw-wave mode, no transfer. </description>
                                    <value>#00</value>
                                </enumeratedValue>
                                <enumeratedValue>
                                    <name>01</name>
                                    <description>In triangle wave mode, transfer at crest. In saw-wave mode, transfer at underflow (in down-counting), overflow (in up-counting), or counter clearing. </description>
                                    <value>#01</value>
                                </enumeratedValue>
                                <enumeratedValue>
                                    <name>10</name>
                                    <description>In triangle wave mode, transfer at trough. In saw-wave mode, transfer at underflow (in down-counting), overflow (in up-counting), or counter clearing. </description>
                                    <value>#10</value>
                                </enumeratedValue>
                                <enumeratedValue>
                                    <name>11</name>
                                    <description>In triangle wave, transfer at both crest and trough. In saw-wave mode, transfer at underflow (in down-counting), overflow (in up-counting), or counter clearing. </description>
                                    <value>#11</value>
                                </enumeratedValue>
                            </enumeratedValues>
                        </field>
                        <field>
                            <name>ADTDA</name>
                            <description>GTADTRA Register Double Buffer Operation</description>
                            <lsb>26</lsb>
                            <msb>26</msb>
                            <access>read-write</access>
                            <enumeratedValues>
                                <enumeratedValue>
                                    <name>0</name>
                                    <description>Single buffer operation (GTADTBRA --&gt; GTADTRA)</description>
                                    <value>#0</value>
                                </enumeratedValue>
                                <enumeratedValue>
                                    <name>1</name>
                                    <description>Double buffer operation (GTADTDBRA --&gt; GTADTBRA --&gt; GTADTRA)</description>
                                    <value>#1</value>
                                </enumeratedValue>
                            </enumeratedValues>
                        </field>
                        <field>
                            <name>ADTTB</name>
                            <description>GTADTRB Register Buffer Transfer Timing Select</description>
                            <lsb>28</lsb>
                            <msb>29</msb>
                            <access>read-write</access>
                            <enumeratedValues>
                                <enumeratedValue>
                                    <name>00</name>
                                    <description>In triangle wave mode, no transfer. In saw-wave mode, no transfer. </description>
                                    <value>#00</value>
                                </enumeratedValue>
                                <enumeratedValue>
                                    <name>01</name>
                                    <description>In triangle wave mode, transfer at crest. In saw-wave mode, transfer at underflow (in down-counting), overflow (in up-counting), or counter clearing. </description>
                                    <value>#01</value>
                                </enumeratedValue>
                                <enumeratedValue>
                                    <name>10</name>
                                    <description>In triangle wave mode, transfer at trough. In saw-wave mode, transfer at underflow (in down-counting), overflow (in up-counting), or counter clearing. </description>
                                    <value>#10</value>
                                </enumeratedValue>
                                <enumeratedValue>
                                    <name>11</name>
                                    <description>In triangle wave mode, transfer at both crest and trough. In saw-wave mode, transfer at underflow (in down-counting), overflow (in up-counting), or counter clearing. </description>
                                    <value>#11</value>
                                </enumeratedValue>
                            </enumeratedValues>
                        </field>
                        <field>
                            <name>ADTDB</name>
                            <description>GTADTRB Register Double Buffer Operation</description>
                            <lsb>30</lsb>
                            <msb>30</msb>
                            <access>read-write</access>
                            <enumeratedValues>
                                <enumeratedValue>
                                    <name>0</name>
                                    <description>Single buffer operation (GTADTBRB --&gt; GTADTRB)</description>
                                    <value>#0</value>
                                </enumeratedValue>
                                <enumeratedValue>
                                    <name>1</name>
                                    <description>Double buffer operation (GTADTDBRB --&gt; GTADTBRB --&gt; GTADTRB)</description>
                                    <value>#1</value>
                                </enumeratedValue>
                            </enumeratedValues>
                        </field>
                    </fields>
                </register>
                <register>
                    <name>GTCNT</name>
                    <description>General PWM Timer Counter</description>
                    <addressOffset>0x48</addressOffset>
                    <size>32</size>
                    <access>read-write</access>
                    <resetValue>0x00000000</resetValue>
                    <resetMask>0xffffffff</resetMask>
                </register>
                <register>
                    <name>GTCCRA</name>
                    <description>General PWM Timer Compare Capture Register A</description>
                    <addressOffset>0x4C</addressOffset>
                    <size>32</size>
                    <access>read-write</access>
                    <resetValue>0x0000ffff</resetValue>
                    <resetMask>0xffffffff</resetMask>
                </register>
                <register>
                    <name>GTCCRB</name>
                    <description>General PWM Timer Compare Capture Register B</description>
                    <addressOffset>0x50</addressOffset>
                    <size>32</size>
                    <access>read-write</access>
                    <resetValue>0x0000ffff</resetValue>
                    <resetMask>0xffffffff</resetMask>
                </register>
                <register>
                    <name>GTCCRC</name>
                    <description>General PWM Timer Compare Capture Register C</description>
                    <addressOffset>0x54</addressOffset>
                    <size>32</size>
                    <access>read-write</access>
                    <resetValue>0x0000ffff</resetValue>
                    <resetMask>0xffffffff</resetMask>
                </register>
                <register>
                    <name>GTCCRE</name>
                    <description>General PWM Timer Compare Capture Register E</description>
                    <addressOffset>0x58</addressOffset>
                    <size>32</size>
                    <access>read-write</access>
                    <resetValue>0x0000ffff</resetValue>
                    <resetMask>0xffffffff</resetMask>
                </register>
                <register>
                    <name>GTCCRD</name>
                    <description>General PWM Timer Compare Capture Register D</description>
                    <addressOffset>0x5C</addressOffset>
                    <size>32</size>
                    <access>read-write</access>
                    <resetValue>0x0000ffff</resetValue>
                    <resetMask>0xffffffff</resetMask>
                </register>
                <register>
                    <name>GTCCRF</name>
                    <description>General PWM Timer Compare Capture Register F</description>
                    <addressOffset>0x60</addressOffset>
                    <size>32</size>
                    <access>read-write</access>
                    <resetValue>0x0000ffff</resetValue>
                    <resetMask>0xffffffff</resetMask>
                </register>
                <register>
                    <name>GTPR</name>
                    <description>General PWM Timer Cycle Setting Register</description>
                    <addressOffset>0x64</addressOffset>
                    <size>32</size>
                    <access>read-write</access>
                    <resetValue>0x0000ffff</resetValue>
                    <resetMask>0xffffffff</resetMask>
                </register>
                <register>
                    <name>GTPBR</name>
                    <description>General PWM Timer Cycle Setting Buffer Register</description>
                    <addressOffset>0x68</addressOffset>
                    <size>32</size>
                    <access>read-write</access>
                    <resetValue>0x0000ffff</resetValue>
                    <resetMask>0xffffffff</resetMask>
                </register>
                <register>
                    <name>GTDTCR</name>
                    <description>General PWM Timer Dead Time Control Register</description>
                    <addressOffset>0x88</addressOffset>
                    <size>32</size>
                    <access>read-write</access>
                    <resetValue>0x00000000</resetValue>
                    <resetMask>0xffffffff</resetMask>
                    <fields>
                        <field>
                            <name>TDE</name>
                            <description>Negative-Phase Waveform Setting</description>
                            <lsb>0</lsb>
                            <msb>0</msb>
                            <access>read-write</access>
                            <enumeratedValues>
                                <enumeratedValue>
                                    <name>0</name>
                                    <description>GTCCRB is set without using GTDVU</description>
                                    <value>#0</value>
                                </enumeratedValue>
                                <enumeratedValue>
                                    <name>1</name>
                                    <description>GTDVU is used to set the compare match value for negative-phase waveform with dead time automatically in GTCCRB</description>
                                    <value>#1</value>
                                </enumeratedValue>
                            </enumeratedValues>
                        </field>
                    </fields>
                </register>
                <register>
                    <name>GTDVU</name>
                    <description>General PWM Timer Dead Time Value Register U</description>
                    <addressOffset>0x8C</addressOffset>
                    <size>32</size>
                    <access>read-write</access>
                    <resetValue>0x0000ffff</resetValue>
                    <resetMask>0xffffffff</resetMask>
                </register>
                <register>
                    <name>GTPC</name>
                    <description>General PWM Timer Period Count Register</description>
                    <addressOffset>0xBC</addressOffset>
                    <size>32</size>
                    <access>read-write</access>
                    <resetValue>0x00000000</resetValue>
                    <resetMask>0xffffffff</resetMask>
                    <fields>
                        <field>
                            <name>PCEN</name>
                            <description>Period Count Function Enable</description>
                            <lsb>0</lsb>
                            <msb>0</msb>
                            <access>read-write</access>
                            <enumeratedValues>
                                <enumeratedValue>
                                    <name>0</name>
                                    <description>Period count function is disabled</description>
                                    <value>#0</value>
                                </enumeratedValue>
                                <enumeratedValue>
                                    <name>1</name>
                                    <description>Period count function is enabled</description>
                                    <value>#1</value>
                                </enumeratedValue>
                            </enumeratedValues>
                        </field>
                        <field>
                            <name>ASTP</name>
                            <description>Automatic Stop Function Enable</description>
                            <lsb>8</lsb>
                            <msb>8</msb>
                            <access>read-write</access>
                            <enumeratedValues>
                                <enumeratedValue>
                                    <name>0</name>
                                    <description>Automatic stop function is disabled</description>
                                    <value>#0</value>
                                </enumeratedValue>
                                <enumeratedValue>
                                    <name>1</name>
                                    <description>Automatic stop function is enabled</description>
                                    <value>#1</value>
                                </enumeratedValue>
                            </enumeratedValues>
                        </field>
                        <field>
                            <name>PCNT</name>
                            <description>Period Counter</description>
                            <lsb>16</lsb>
                            <msb>27</msb>
                            <access>read-write</access>
                        </field>
                    </fields>
                </register>
                <register>
                    <name>GTSECSR</name>
                    <description>General PWM Timer Operation Enable Bit Simultaneous Control Channel Select Register</description>
                    <addressOffset>0xD0</addressOffset>
                    <size>32</size>
                    <access>read-write</access>
                    <resetValue>0x00000000</resetValue>
                    <resetMask>0xffffffff</resetMask>
                    <fields>
                        <field>
                            <name>SECSEL0</name>
                            <description>Channel 0 Operation Enable Bit Simultaneous Control Channel Select</description>
                            <lsb>0</lsb>
                            <msb>0</msb>
                            <access>read-write</access>
                            <enumeratedValues>
                                <enumeratedValue>
                                    <name>0</name>
                                    <description>Disable simultaneous control</description>
                                    <value>#0</value>
                                </enumeratedValue>
                                <enumeratedValue>
                                    <name>1</name>
                                    <description>Enable simultaneous control</description>
                                    <value>#1</value>
                                </enumeratedValue>
                            </enumeratedValues>
                        </field>
                        <field>
                            <name>SECSEL1</name>
                            <description>Channel 1 Operation Enable Bit Simultaneous Control Channel Select</description>
                            <lsb>1</lsb>
                            <msb>1</msb>
                            <access>read-write</access>
                            <enumeratedValues>
                                <enumeratedValue>
                                    <name>0</name>
                                    <description>Disable simultaneous control</description>
                                    <value>#0</value>
                                </enumeratedValue>
                                <enumeratedValue>
                                    <name>1</name>
                                    <description>Enable simultaneous control</description>
                                    <value>#1</value>
                                </enumeratedValue>
                            </enumeratedValues>
                        </field>
                        <field>
                            <name>SECSEL2</name>
                            <description>Channel 2 Operation Enable Bit Simultaneous Control Channel Select</description>
                            <lsb>2</lsb>
                            <msb>2</msb>
                            <access>read-write</access>
                            <enumeratedValues>
                                <enumeratedValue>
                                    <name>0</name>
                                    <description>Disable simultaneous control</description>
                                    <value>#0</value>
                                </enumeratedValue>
                                <enumeratedValue>
                                    <name>1</name>
                                    <description>Enable simultaneous control</description>
                                    <value>#1</value>
                                </enumeratedValue>
                            </enumeratedValues>
                        </field>
                        <field>
                            <name>SECSEL3</name>
                            <description>Channel 3 Operation Enable Bit Simultaneous Control Channel Select</description>
                            <lsb>3</lsb>
                            <msb>3</msb>
                            <access>read-write</access>
                            <enumeratedValues>
                                <enumeratedValue>
                                    <name>0</name>
                                    <description>Disable simultaneous control</description>
                                    <value>#0</value>
                                </enumeratedValue>
                                <enumeratedValue>
                                    <name>1</name>
                                    <description>Enable simultaneous control</description>
                                    <value>#1</value>
                                </enumeratedValue>
                            </enumeratedValues>
                        </field>
                        <field>
                            <name>SECSEL4</name>
                            <description>Channel 4 Operation Enable Bit Simultaneous Control Channel Select</description>
                            <lsb>4</lsb>
                            <msb>4</msb>
                            <access>read-write</access>
                            <enumeratedValues>
                                <enumeratedValue>
                                    <name>0</name>
                                    <description>Disable simultaneous control</description>
                                    <value>#0</value>
                                </enumeratedValue>
                                <enumeratedValue>
                                    <name>1</name>
                                    <description>Enable simultaneous control</description>
                                    <value>#1</value>
                                </enumeratedValue>
                            </enumeratedValues>
                        </field>
                        <field>
                            <name>SECSEL5</name>
                            <description>Channel 5 Operation Enable Bit Simultaneous Control Channel Select</description>
                            <lsb>5</lsb>
                            <msb>5</msb>
                            <access>read-write</access>
                            <enumeratedValues>
                                <enumeratedValue>
                                    <name>0</name>
                                    <description>Disable simultaneous control</description>
                                    <value>#0</value>
                                </enumeratedValue>
                                <enumeratedValue>
                                    <name>1</name>
                                    <description>Enable simultaneous control</description>
                                    <value>#1</value>
                                </enumeratedValue>
                            </enumeratedValues>
                        </field>
                        <field>
                            <name>SECSEL10</name>
                            <description>Channel 10 Operation Enable Bit Simultaneous Control Channel Select</description>
                            <lsb>10</lsb>
                            <msb>10</msb>
                            <access>read-write</access>
                            <enumeratedValues>
                                <enumeratedValue>
                                    <name>0</name>
                                    <description>Disable simultaneous control</description>
                                    <value>#0</value>
                                </enumeratedValue>
                                <enumeratedValue>
                                    <name>1</name>
                                    <description>Enable simultaneous control</description>
                                    <value>#1</value>
                                </enumeratedValue>
                            </enumeratedValues>
                        </field>
                        <field>
                            <name>SECSEL11</name>
                            <description>Channel 11 Operation Enable Bit Simultaneous Control Channel Select</description>
                            <lsb>11</lsb>
                            <msb>11</msb>
                            <access>read-write</access>
                            <enumeratedValues>
                                <enumeratedValue>
                                    <name>0</name>
                                    <description>Disable simultaneous control</description>
                                    <value>#0</value>
                                </enumeratedValue>
                                <enumeratedValue>
                                    <name>1</name>
                                    <description>Enable simultaneous control</description>
                                    <value>#1</value>
                                </enumeratedValue>
                            </enumeratedValues>
                        </field>
                        <field>
                            <name>SECSEL12</name>
                            <description>Channel 12 Operation Enable Bit Simultaneous Control Channel Select</description>
                            <lsb>12</lsb>
                            <msb>12</msb>
                            <access>read-write</access>
                            <enumeratedValues>
                                <enumeratedValue>
                                    <name>0</name>
                                    <description>Disable simultaneous control</description>
                                    <value>#0</value>
                                </enumeratedValue>
                                <enumeratedValue>
                                    <name>1</name>
                                    <description>Enable simultaneous control</description>
                                    <value>#1</value>
                                </enumeratedValue>
                            </enumeratedValues>
                        </field>
                        <field>
                            <name>SECSEL13</name>
                            <description>Channel 13 Operation Enable Bit Simultaneous Control Channel Select</description>
                            <lsb>13</lsb>
                            <msb>13</msb>
                            <access>read-write</access>
                            <enumeratedValues>
                                <enumeratedValue>
                                    <name>0</name>
                                    <description>Disable simultaneous control</description>
                                    <value>#0</value>
                                </enumeratedValue>
                                <enumeratedValue>
                                    <name>1</name>
                                    <description>Enable simultaneous control</description>
                                    <value>#1</value>
                                </enumeratedValue>
                            </enumeratedValues>
                        </field>
                    </fields>
                </register>
                <register>
                    <name>GTSECR</name>
                    <description>General PWM Timer Operation Enable Bit Simultaneous Control Register</description>
                    <addressOffset>0xD4</addressOffset>
                    <size>32</size>
                    <access>read-write</access>
                    <resetValue>0x00000000</resetValue>
                    <resetMask>0xffffffff</resetMask>
                    <fields>
                        <field>
                            <name>SBDCE</name>
                            <description>GTCCR Register Buffer Operation Simultaneous Enable</description>
                            <lsb>0</lsb>
                            <msb>0</msb>
                            <access>read-write</access>
                            <enumeratedValues>
                                <enumeratedValue>
                                    <name>0</name>
                                    <description>Disable simultaneous enabling GTCCR buffer operations</description>
                                    <value>#0</value>
                                </enumeratedValue>
                                <enumeratedValue>
                                    <name>1</name>
                                    <description>Enable GTCCR register buffer operations simultaneously</description>
                                    <value>#1</value>
                                </enumeratedValue>
                            </enumeratedValues>
                        </field>
                        <field>
                            <name>SBDPE</name>
                            <description>GTPR Register Buffer Operation Simultaneous Enable</description>
                            <lsb>1</lsb>
                            <msb>1</msb>
                            <access>read-write</access>
                            <enumeratedValues>
                                <enumeratedValue>
                                    <name>0</name>
                                    <description>Disable simultaneous enabling GTPR buffer operations</description>
                                    <value>#0</value>
                                </enumeratedValue>
                                <enumeratedValue>
                                    <name>1</name>
                                    <description>Enable GTPR register buffer operations simultaneously</description>
                                    <value>#1</value>
                                </enumeratedValue>
                            </enumeratedValues>
                        </field>
                        <field>
                            <name>SBDAE</name>
                            <description>GTADTR Register Buffer Operation Simultaneous Enable</description>
                            <lsb>2</lsb>
                            <msb>2</msb>
                            <access>read-write</access>
                            <enumeratedValues>
                                <enumeratedValue>
                                    <name>0</name>
                                    <description>Disable simultaneous enabling GTADTR buffer operations</description>
                                    <value>#0</value>
                                </enumeratedValue>
                                <enumeratedValue>
                                    <name>1</name>
                                    <description>Enable GTADTR register buffer operations simultaneously</description>
                                    <value>#1</value>
                                </enumeratedValue>
                            </enumeratedValues>
                        </field>
                        <field>
                            <name>SBDCD</name>
                            <description>GTCCR Register Buffer Operation Simultaneous Disable</description>
                            <lsb>8</lsb>
                            <msb>8</msb>
                            <access>read-write</access>
                            <enumeratedValues>
                                <enumeratedValue>
                                    <name>0</name>
                                    <description>Disable simultaneous disabling GTCCR buffer operations</description>
                                    <value>#0</value>
                                </enumeratedValue>
                                <enumeratedValue>
                                    <name>1</name>
                                    <description>Disable GTCCR register buffer operations simultaneously</description>
                                    <value>#1</value>
                                </enumeratedValue>
                            </enumeratedValues>
                        </field>
                        <field>
                            <name>SBDPD</name>
                            <description>GTPR Register Buffer Operation Simultaneous Disable</description>
                            <lsb>9</lsb>
                            <msb>9</msb>
                            <access>read-write</access>
                            <enumeratedValues>
                                <enumeratedValue>
                                    <name>0</name>
                                    <description>Disable simultaneous disabling GTPR buffer operations</description>
                                    <value>#0</value>
                                </enumeratedValue>
                                <enumeratedValue>
                                    <name>1</name>
                                    <description>Disable GTPR register buffer operations simultaneously</description>
                                    <value>#1</value>
                                </enumeratedValue>
                            </enumeratedValues>
                        </field>
                        <field>
                            <name>SBDAD</name>
                            <description>GTADTR Register Buffer Operation Simultaneous Disable</description>
                            <lsb>10</lsb>
                            <msb>10</msb>
                            <access>read-write</access>
                            <enumeratedValues>
                                <enumeratedValue>
                                    <name>0</name>
                                    <description>Disable simultaneous disabling GTADTR buffer operations</description>
                                    <value>#0</value>
                                </enumeratedValue>
                                <enumeratedValue>
                                    <name>1</name>
                                    <description>Disable GTADTR register buffer operations simultaneously</description>
                                    <value>#1</value>
                                </enumeratedValue>
                            </enumeratedValues>
                        </field>
                        <field>
                            <name>SPCE</name>
                            <description>Period Count Function Simultaneous Enable</description>
                            <lsb>16</lsb>
                            <msb>16</msb>
                            <access>read-write</access>
                            <enumeratedValues>
                                <enumeratedValue>
                                    <name>0</name>
                                    <description>Disable simultaneous enabling period count function</description>
                                    <value>#0</value>
                                </enumeratedValue>
                                <enumeratedValue>
                                    <name>1</name>
                                    <description>Enable period count function simultaneously</description>
                                    <value>#1</value>
                                </enumeratedValue>
                            </enumeratedValues>
                        </field>
                        <field>
                            <name>SPCD</name>
                            <description>Period Count Function Simultaneous Disable</description>
                            <lsb>24</lsb>
                            <msb>24</msb>
                            <access>read-write</access>
                            <enumeratedValues>
                                <enumeratedValue>
                                    <name>0</name>
                                    <description>Disable simultaneous disabling period count function</description>
                                    <value>#0</value>
                                </enumeratedValue>
                                <enumeratedValue>
                                    <name>1</name>
                                    <description>Disable period count function simultaneously</description>
                                    <value>#1</value>
                                </enumeratedValue>
                            </enumeratedValues>
                        </field>
                    </fields>
                </register>
            </registers>
        </peripheral>
        <peripheral derivedFrom="GPT1610">
            <name>GPT1611</name>
            <description>General PWM 16-bit Timer 11</description>
            <baseAddress>0x40322B00</baseAddress>
        </peripheral>
        <peripheral derivedFrom="GPT1610">
            <name>GPT1612</name>
            <description>General PWM 16-bit Timer 12</description>
            <baseAddress>0x40322C00</baseAddress>
        </peripheral>
        <peripheral derivedFrom="GPT1610">
            <name>GPT1613</name>
            <description>General PWM 16-bit Timer 13</description>
            <baseAddress>0x40322D00</baseAddress>
        </peripheral>
        <peripheral>
            <name>ADC120</name>
            <description>12-bit A/D Converter 0</description>
            <baseAddress>0x40332000</baseAddress>
            <addressBlock>
                <offset>0x00</offset>
                <size>2</size>
                <usage>registers</usage>
            </addressBlock>
            <addressBlock>
                <offset>0x04</offset>
                <size>9</size>
                <usage>registers</usage>
            </addressBlock>
            <addressBlock>
                <offset>0x0E</offset>
                <size>36</size>
                <usage>registers</usage>
            </addressBlock>
            <addressBlock>
                <offset>0x66</offset>
                <size>2</size>
                <usage>registers</usage>
            </addressBlock>
            <addressBlock>
                <offset>0x7A</offset>
                <size>1</size>
                <usage>registers</usage>
            </addressBlock>
            <addressBlock>
                <offset>0x7C</offset>
                <size>1</size>
                <usage>registers</usage>
            </addressBlock>
            <addressBlock>
                <offset>0x80</offset>
                <size>2</size>
                <usage>registers</usage>
            </addressBlock>
            <addressBlock>
                <offset>0x84</offset>
                <size>4</size>
                <usage>registers</usage>
            </addressBlock>
            <addressBlock>
                <offset>0x8C</offset>
                <size>1</size>
                <usage>registers</usage>
            </addressBlock>
            <addressBlock>
                <offset>0x90</offset>
                <size>6</size>
                <usage>registers</usage>
            </addressBlock>
            <addressBlock>
                <offset>0x98</offset>
                <size>2</size>
                <usage>registers</usage>
            </addressBlock>
            <addressBlock>
                <offset>0x9C</offset>
                <size>6</size>
                <usage>registers</usage>
            </addressBlock>
            <addressBlock>
                <offset>0xA4</offset>
                <size>1</size>
                <usage>registers</usage>
            </addressBlock>
            <addressBlock>
                <offset>0xA6</offset>
                <size>1</size>
                <usage>registers</usage>
            </addressBlock>
            <addressBlock>
                <offset>0xA8</offset>
                <size>5</size>
                <usage>registers</usage>
            </addressBlock>
            <addressBlock>
                <offset>0xB0</offset>
                <size>33</size>
                <usage>registers</usage>
            </addressBlock>
            <addressBlock>
                <offset>0xD2</offset>
                <size>1</size>
                <usage>registers</usage>
            </addressBlock>
            <addressBlock>
                <offset>0xDD</offset>
                <size>12</size>
                <usage>registers</usage>
            </addressBlock>
            <addressBlock>
                <offset>0xEC</offset>
                <size>4</size>
                <usage>registers</usage>
            </addressBlock>
            <registers>
                <register>
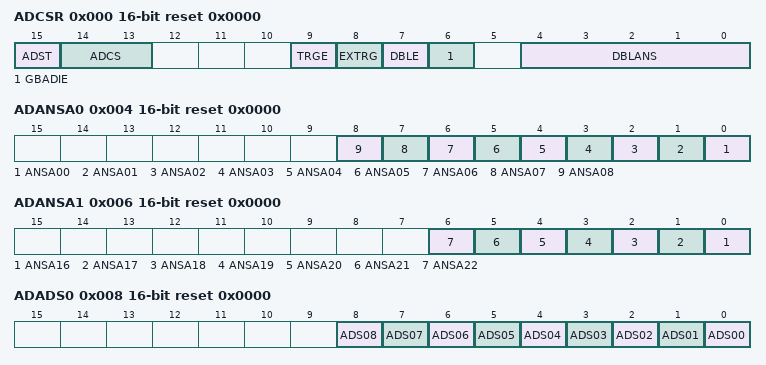
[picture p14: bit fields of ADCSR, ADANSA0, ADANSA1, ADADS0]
                    <name>ADCSR</name>
                    <description>A/D Control Register</description>
                    <addressOffset>0x000</addressOffset>
                    <size>16</size>
                    <access>read-write</access>
                    <resetValue>0x0000</resetValue>
                    <resetMask>0xffff</resetMask>
                    <fields>
                        <field>
                            <name>DBLANS</name>
                            <description>Double Trigger Channel Select</description>
                            <lsb>0</lsb>
                            <msb>4</msb>
                            <access>read-write</access>
                        </field>
                        <field>
                            <name>GBADIE</name>
                            <description>Group B Scan End Interrupt and ELC Event Enable</description>
                            <lsb>6</lsb>
                            <msb>6</msb>
                            <access>read-write</access>
                            <enumeratedValues>
                                <enumeratedValue>
                                    <name>0</name>
                                    <description>Disable ADC12i_GBADI (i = 0, 1) interrupt generation on group B scan completion.</description>
                                    <value>#0</value>
                                </enumeratedValue>
                                <enumeratedValue>
                                    <name>1</name>
                                    <description>Enable ADC12i_GBADI (i = 0, 1) interrupt generation on group B scan completion.</description>
                                    <value>#1</value>
                                </enumeratedValue>
                            </enumeratedValues>
                        </field>
                        <field>
                            <name>DBLE</name>
                            <description>Double Trigger Mode Select</description>
                            <lsb>7</lsb>
                            <msb>7</msb>
                            <access>read-write</access>
                            <enumeratedValues>
                                <enumeratedValue>
                                    <name>0</name>
                                    <description>Deselect double-trigger mode.</description>
                                    <value>#0</value>
                                </enumeratedValue>
                                <enumeratedValue>
                                    <name>1</name>
                                    <description>Select double-trigger mode.</description>
                                    <value>#1</value>
                                </enumeratedValue>
                            </enumeratedValues>
                        </field>
                        <field>
                            <name>EXTRG</name>
                            <description>Trigger Select</description>
                            <lsb>8</lsb>
                            <msb>8</msb>
                            <access>read-write</access>
                            <enumeratedValues>
                                <enumeratedValue>
                                    <name>0</name>
                                    <description>Start A/D conversion by the synchronous trigger (GPT, ELC).</description>
                                    <value>#0</value>
                                </enumeratedValue>
                                <enumeratedValue>
                                    <name>1</name>
                                    <description>Start A/D conversion by the asynchronous trigger (ADTRGn).</description>
                                    <value>#1</value>
                                </enumeratedValue>
                            </enumeratedValues>
                        </field>
                        <field>
                            <name>TRGE</name>
                            <description>Trigger Start Enable</description>
                            <lsb>9</lsb>
                            <msb>9</msb>
                            <access>read-write</access>
                            <enumeratedValues>
                                <enumeratedValue>
                                    <name>0</name>
                                    <description>Disable A/D conversion to be started by the synchronous or asynchronous trigger</description>
                                    <value>#0</value>
                                </enumeratedValue>
                                <enumeratedValue>
                                    <name>1</name>
                                    <description>Enable A/D conversion to be started by the synchronous or asynchronous trigger</description>
                                    <value>#1</value>
                                </enumeratedValue>
                            </enumeratedValues>
                        </field>
                        <field>
                            <name>ADCS</name>
                            <description>Scan Mode Select</description>
                            <lsb>13</lsb>
                            <msb>14</msb>
                            <access>read-write</access>
                            <enumeratedValues>
                                <enumeratedValue>
                                    <name>00</name>
                                    <description>Single scan mode</description>
                                    <value>#00</value>
                                </enumeratedValue>
                                <enumeratedValue>
                                    <name>01</name>
                                    <description>Group scan mode</description>
                                    <value>#01</value>
                                </enumeratedValue>
                                <enumeratedValue>
                                    <name>10</name>
                                    <description>Continuous scan mode</description>
                                    <value>#10</value>
                                </enumeratedValue>
                                <enumeratedValue>
                                    <name>11</name>
                                    <description>Setting prohibited</description>
                                    <value>#11</value>
                                </enumeratedValue>
                            </enumeratedValues>
                        </field>
                        <field>
                            <name>ADST</name>
                            <description>A/D Conversion Start</description>
                            <lsb>15</lsb>
                            <msb>15</msb>
                            <access>read-write</access>
                            <enumeratedValues>
                                <enumeratedValue>
                                    <name>0</name>
                                    <description>Stop A/D conversion process.</description>
                                    <value>#0</value>
                                </enumeratedValue>
                                <enumeratedValue>
                                    <name>1</name>
                                    <description>Start A/D conversion process.</description>
                                    <value>#1</value>
                                </enumeratedValue>
                            </enumeratedValues>
                        </field>
                    </fields>
                </register>
                <register>
                    <name>ADANSA0</name>
                    <description>A/D Channel Select Register A0</description>
                    <addressOffset>0x004</addressOffset>
                    <size>16</size>
                    <access>read-write</access>
                    <resetValue>0x0000</resetValue>
                    <resetMask>0xffff</resetMask>
                    <fields>
                        <field>
                            <name>ANSA00</name>
                            <description>A/D Conversion Channels Select</description>
                            <lsb>0</lsb>
                            <msb>0</msb>
                            <access>read-write</access>
                            <enumeratedValues>
                                <enumeratedValue>
                                    <name>0</name>
                                    <description>Do not select associated input channel.</description>
                                    <value>#0</value>
                                </enumeratedValue>
                                <enumeratedValue>
                                    <name>1</name>
                                    <description>Select associated input channel. </description>
                                    <value>#1</value>
                                </enumeratedValue>
                            </enumeratedValues>
                        </field>
                        <field>
                            <name>ANSA01</name>
                            <description>A/D Conversion Channels Select</description>
                            <lsb>1</lsb>
                            <msb>1</msb>
                            <access>read-write</access>
                            <enumeratedValues>
                                <enumeratedValue>
                                    <name>0</name>
                                    <description>Do not select associated input channel.</description>
                                    <value>#0</value>
                                </enumeratedValue>
                                <enumeratedValue>
                                    <name>1</name>
                                    <description>Select associated input channel. </description>
                                    <value>#1</value>
                                </enumeratedValue>
                            </enumeratedValues>
                        </field>
                        <field>
                            <name>ANSA02</name>
                            <description>A/D Conversion Channels Select</description>
                            <lsb>2</lsb>
                            <msb>2</msb>
                            <access>read-write</access>
                            <enumeratedValues>
                                <enumeratedValue>
                                    <name>0</name>
                                    <description>Do not select associated input channel.</description>
                                    <value>#0</value>
                                </enumeratedValue>
                                <enumeratedValue>
                                    <name>1</name>
                                    <description>Select associated input channel. </description>
                                    <value>#1</value>
                                </enumeratedValue>
                            </enumeratedValues>
                        </field>
                        <field>
                            <name>ANSA03</name>
                            <description>A/D Conversion Channels Select</description>
                            <lsb>3</lsb>
                            <msb>3</msb>
                            <access>read-write</access>
                            <enumeratedValues>
                                <enumeratedValue>
                                    <name>0</name>
                                    <description>Do not select associated input channel.</description>
                                    <value>#0</value>
                                </enumeratedValue>
                                <enumeratedValue>
                                    <name>1</name>
                                    <description>Select associated input channel. </description>
                                    <value>#1</value>
                                </enumeratedValue>
                            </enumeratedValues>
                        </field>
                        <field>
                            <name>ANSA04</name>
                            <description>A/D Conversion Channels Select</description>
                            <lsb>4</lsb>
                            <msb>4</msb>
                            <access>read-write</access>
                            <enumeratedValues>
                                <enumeratedValue>
                                    <name>0</name>
                                    <description>Do not select associated input channel.</description>
                                    <value>#0</value>
                                </enumeratedValue>
                                <enumeratedValue>
                                    <name>1</name>
                                    <description>Select associated input channel. </description>
                                    <value>#1</value>
                                </enumeratedValue>
                            </enumeratedValues>
                        </field>
                        <field>
                            <name>ANSA05</name>
                            <description>A/D Conversion Channels Select</description>
                            <lsb>5</lsb>
                            <msb>5</msb>
                            <access>read-write</access>
                            <enumeratedValues>
                                <enumeratedValue>
                                    <name>0</name>
                                    <description>Do not select associated input channel.</description>
                                    <value>#0</value>
                                </enumeratedValue>
                                <enumeratedValue>
                                    <name>1</name>
                                    <description>Select associated input channel. </description>
                                    <value>#1</value>
                                </enumeratedValue>
                            </enumeratedValues>
                        </field>
                        <field>
                            <name>ANSA06</name>
                            <description>A/D Conversion Channels Select</description>
                            <lsb>6</lsb>
                            <msb>6</msb>
                            <access>read-write</access>
                            <enumeratedValues>
                                <enumeratedValue>
                                    <name>0</name>
                                    <description>Do not select associated input channel.</description>
                                    <value>#0</value>
                                </enumeratedValue>
                                <enumeratedValue>
                                    <name>1</name>
                                    <description>Select associated input channel. </description>
                                    <value>#1</value>
                                </enumeratedValue>
                            </enumeratedValues>
                        </field>
                        <field>
                            <name>ANSA07</name>
                            <description>A/D Conversion Channels Select</description>
                            <lsb>7</lsb>
                            <msb>7</msb>
                            <access>read-write</access>
                            <enumeratedValues>
                                <enumeratedValue>
                                    <name>0</name>
                                    <description>Do not select associated input channel.</description>
                                    <value>#0</value>
                                </enumeratedValue>
                                <enumeratedValue>
                                    <name>1</name>
                                    <description>Select associated input channel. </description>
                                    <value>#1</value>
                                </enumeratedValue>
                            </enumeratedValues>
                        </field>
                        <field>
                            <name>ANSA08</name>
                            <description>A/D Conversion Channels Select</description>
                            <lsb>8</lsb>
                            <msb>8</msb>
                            <access>read-write</access>
                            <enumeratedValues>
                                <enumeratedValue>
                                    <name>0</name>
                                    <description>Do not select associated input channel.</description>
                                    <value>#0</value>
                                </enumeratedValue>
                                <enumeratedValue>
                                    <name>1</name>
                                    <description>Select associated input channel. </description>
                                    <value>#1</value>
                                </enumeratedValue>
                            </enumeratedValues>
                        </field>
                    </fields>
                </register>
                <register>
                    <name>ADANSA1</name>
                    <description>A/D Channel Select Register A1</description>
                    <addressOffset>0x006</addressOffset>
                    <size>16</size>
                    <access>read-write</access>
                    <resetValue>0x0000</resetValue>
                    <resetMask>0xffff</resetMask>
                    <fields>
                        <field>
                            <name>ANSA16</name>
                            <description>A/D Conversion Channels Select</description>
                            <lsb>0</lsb>
                            <msb>0</msb>
                            <access>read-write</access>
                            <enumeratedValues>
                                <enumeratedValue>
                                    <name>0</name>
                                    <description>Do not select associated input channel.</description>
                                    <value>#0</value>
                                </enumeratedValue>
                                <enumeratedValue>
                                    <name>1</name>
                                    <description>Select associated input channel. </description>
                                    <value>#1</value>
                                </enumeratedValue>
                            </enumeratedValues>
                        </field>
                        <field>
                            <name>ANSA17</name>
                            <description>A/D Conversion Channels Select</description>
                            <lsb>1</lsb>
                            <msb>1</msb>
                            <access>read-write</access>
                            <enumeratedValues>
                                <enumeratedValue>
                                    <name>0</name>
                                    <description>Do not select associated input channel.</description>
                                    <value>#0</value>
                                </enumeratedValue>
                                <enumeratedValue>
                                    <name>1</name>
                                    <description>Select associated input channel. </description>
                                    <value>#1</value>
                                </enumeratedValue>
                            </enumeratedValues>
                        </field>
                        <field>
                            <name>ANSA18</name>
                            <description>A/D Conversion Channels Select</description>
                            <lsb>2</lsb>
                            <msb>2</msb>
                            <access>read-write</access>
                            <enumeratedValues>
                                <enumeratedValue>
                                    <name>0</name>
                                    <description>Do not select associated input channel.</description>
                                    <value>#0</value>
                                </enumeratedValue>
                                <enumeratedValue>
                                    <name>1</name>
                                    <description>Select associated input channel. </description>
                                    <value>#1</value>
                                </enumeratedValue>
                            </enumeratedValues>
                        </field>
                        <field>
                            <name>ANSA19</name>
                            <description>A/D Conversion Channels Select</description>
                            <lsb>3</lsb>
                            <msb>3</msb>
                            <access>read-write</access>
                            <enumeratedValues>
                                <enumeratedValue>
                                    <name>0</name>
                                    <description>Do not select associated input channel.</description>
                                    <value>#0</value>
                                </enumeratedValue>
                                <enumeratedValue>
                                    <name>1</name>
                                    <description>Select associated input channel. </description>
                                    <value>#1</value>
                                </enumeratedValue>
                            </enumeratedValues>
                        </field>
                        <field>
                            <name>ANSA20</name>
                            <description>A/D Conversion Channels Select</description>
                            <lsb>4</lsb>
                            <msb>4</msb>
                            <access>read-write</access>
                            <enumeratedValues>
                                <enumeratedValue>
                                    <name>0</name>
                                    <description>Do not select associated input channel.</description>
                                    <value>#0</value>
                                </enumeratedValue>
                                <enumeratedValue>
                                    <name>1</name>
                                    <description>Select associated input channel. </description>
                                    <value>#1</value>
                                </enumeratedValue>
                            </enumeratedValues>
                        </field>
                        <field>
                            <name>ANSA21</name>
                            <description>A/D Conversion Channels Select</description>
                            <lsb>5</lsb>
                            <msb>5</msb>
                            <access>read-write</access>
                            <enumeratedValues>
                                <enumeratedValue>
                                    <name>0</name>
                                    <description>Do not select associated input channel.</description>
                                    <value>#0</value>
                                </enumeratedValue>
                                <enumeratedValue>
                                    <name>1</name>
                                    <description>Select associated input channel. </description>
                                    <value>#1</value>
                                </enumeratedValue>
                            </enumeratedValues>
                        </field>
                        <field>
                            <name>ANSA22</name>
                            <description>A/D Conversion Channels Select</description>
                            <lsb>6</lsb>
                            <msb>6</msb>
                            <access>read-write</access>
                            <enumeratedValues>
                                <enumeratedValue>
                                    <name>0</name>
                                    <description>Do not select associated input channel.</description>
                                    <value>#0</value>
                                </enumeratedValue>
                                <enumeratedValue>
                                    <name>1</name>
                                    <description>Select associated input channel. </description>
                                    <value>#1</value>
                                </enumeratedValue>
                            </enumeratedValues>
                        </field>
                    </fields>
                </register>
                <register>
                    <name>ADADS0</name>
                    <description>A/D-Converted Value Addition/Average Channel Select Register 0</description>
                    <addressOffset>0x008</addressOffset>
                    <size>16</size>
                    <access>read-write</access>
                    <resetValue>0x0000</resetValue>
                    <resetMask>0xffff</resetMask>
                    <fields>
                        <field>
                            <name>ADS00</name>
                            <description>A/D-Converted Value Addition/Average Channel Select</description>
                            <lsb>0</lsb>
                            <msb>0</msb>
                            <access>read-write</access>
                            <enumeratedValues>
                                <enumeratedValue>
                                    <name>0</name>
                                    <description>Do not select associated input channel.</description>
                                    <value>#0</value>
                                </enumeratedValue>
                                <enumeratedValue>
                                    <name>1</name>
                                    <description>Select associated input channel. </description>
                                    <value>#1</value>
                                </enumeratedValue>
                            </enumeratedValues>
                        </field>
                        <field>
                            <name>ADS01</name>
                            <description>A/D-Converted Value Addition/Average Channel Select</description>
                            <lsb>1</lsb>
                            <msb>1</msb>
                            <access>read-write</access>
                            <enumeratedValues>
                                <enumeratedValue>
                                    <name>0</name>
                                    <description>Do not select associated input channel.</description>
                                    <value>#0</value>
                                </enumeratedValue>
                                <enumeratedValue>
                                    <name>1</name>
                                    <description>Select associated input channel. </description>
                                    <value>#1</value>
                                </enumeratedValue>
                            </enumeratedValues>
                        </field>
                        <field>
                            <name>ADS02</name>
                            <description>A/D-Converted Value Addition/Average Channel Select</description>
                            <lsb>2</lsb>
                            <msb>2</msb>
                            <access>read-write</access>
                            <enumeratedValues>
                                <enumeratedValue>
                                    <name>0</name>
                                    <description>Do not select associated input channel.</description>
                                    <value>#0</value>
                                </enumeratedValue>
                                <enumeratedValue>
                                    <name>1</name>
                                    <description>Select associated input channel. </description>
                                    <value>#1</value>
                                </enumeratedValue>
                            </enumeratedValues>
                        </field>
                        <field>
                            <name>ADS03</name>
                            <description>A/D-Converted Value Addition/Average Channel Select</description>
                            <lsb>3</lsb>
                            <msb>3</msb>
                            <access>read-write</access>
                            <enumeratedValues>
                                <enumeratedValue>
                                    <name>0</name>
                                    <description>Do not select associated input channel.</description>
                                    <value>#0</value>
                                </enumeratedValue>
                                <enumeratedValue>
                                    <name>1</name>
                                    <description>Select associated input channel. </description>
                                    <value>#1</value>
                                </enumeratedValue>
                            </enumeratedValues>
                        </field>
                        <field>
                            <name>ADS04</name>
                            <description>A/D-Converted Value Addition/Average Channel Select</description>
                            <lsb>4</lsb>
                            <msb>4</msb>
                            <access>read-write</access>
                            <enumeratedValues>
                                <enumeratedValue>
                                    <name>0</name>
                                    <description>Do not select associated input channel.</description>
                                    <value>#0</value>
                                </enumeratedValue>
                                <enumeratedValue>
                                    <name>1</name>
                                    <description>Select associated input channel. </description>
                                    <value>#1</value>
                                </enumeratedValue>
                            </enumeratedValues>
                        </field>
                        <field>
                            <name>ADS05</name>
                            <description>A/D-Converted Value Addition/Average Channel Select</description>
                            <lsb>5</lsb>
                            <msb>5</msb>
                            <access>read-write</access>
                            <enumeratedValues>
                                <enumeratedValue>
                                    <name>0</name>
                                    <description>Do not select associated input channel.</description>
                                    <value>#0</value>
                                </enumeratedValue>
                                <enumeratedValue>
                                    <name>1</name>
                                    <description>Select associated input channel. </description>
                                    <value>#1</value>
                                </enumeratedValue>
                            </enumeratedValues>
                        </field>
                        <field>
                            <name>ADS06</name>
                            <description>A/D-Converted Value Addition/Average Channel Select</description>
                            <lsb>6</lsb>
                            <msb>6</msb>
                            <access>read-write</access>
                            <enumeratedValues>
                                <enumeratedValue>
                                    <name>0</name>
                                    <description>Do not select associated input channel.</description>
                                    <value>#0</value>
                                </enumeratedValue>
                                <enumeratedValue>
                                    <name>1</name>
                                    <description>Select associated input channel. </description>
                                    <value>#1</value>
                                </enumeratedValue>
                            </enumeratedValues>
                        </field>
                        <field>
                            <name>ADS07</name>
                            <description>A/D-Converted Value Addition/Average Channel Select</description>
                            <lsb>7</lsb>
                            <msb>7</msb>
                            <access>read-write</access>
                            <enumeratedValues>
                                <enumeratedValue>
                                    <name>0</name>
                                    <description>Do not select associated input channel.</description>
                                    <value>#0</value>
                                </enumeratedValue>
                                <enumeratedValue>
                                    <name>1</name>
                                    <description>Select associated input channel. </description>
                                    <value>#1</value>
                                </enumeratedValue>
                            </enumeratedValues>
                        </field>
                        <field>
                            <name>ADS08</name>
                            <description>A/D-Converted Value Addition/Average Channel Select</description>
                            <lsb>8</lsb>
                            <msb>8</msb>
                            <access>read-write</access>
                            <enumeratedValues>
                                <enumeratedValue>
                                    <name>0</name>
                                    <description>Do not select associated input channel.</description>
                                    <value>#0</value>
                                </enumeratedValue>
                                <enumeratedValue>
                                    <name>1</name>
                                    <description>Select associated input channel. </description>
                                    <value>#1</value>
                                </enumeratedValue>
                            </enumeratedValues>
                        </field>
                    </fields>
                </register>
                <register>
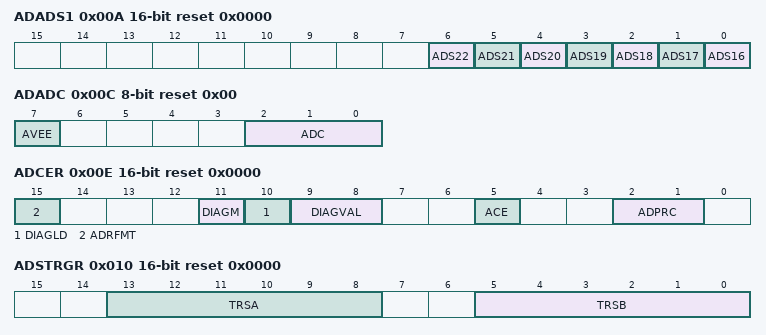
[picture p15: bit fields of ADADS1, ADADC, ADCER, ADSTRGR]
                    <name>ADADS1</name>
                    <description>A/D-Converted Value Addition/Average Channel Select Register 1</description>
                    <addressOffset>0x00A</addressOffset>
                    <size>16</size>
                    <access>read-write</access>
                    <resetValue>0x0000</resetValue>
                    <resetMask>0xffff</resetMask>
                    <fields>
                        <field>
                            <name>ADS16</name>
                            <description>A/D Conversion Channels Select/Average Channel Select</description>
                            <lsb>0</lsb>
                            <msb>0</msb>
                            <access>read-write</access>
                            <enumeratedValues>
                                <enumeratedValue>
                                    <name>0</name>
                                    <description>Do not select associated input channel.</description>
                                    <value>#0</value>
                                </enumeratedValue>
                                <enumeratedValue>
                                    <name>1</name>
                                    <description>Select associated input channel. </description>
                                    <value>#1</value>
                                </enumeratedValue>
                            </enumeratedValues>
                        </field>
                        <field>
                            <name>ADS17</name>
                            <description>A/D Conversion Channels Select/Average Channel Select</description>
                            <lsb>1</lsb>
                            <msb>1</msb>
                            <access>read-write</access>
                            <enumeratedValues>
                                <enumeratedValue>
                                    <name>0</name>
                                    <description>Do not select associated input channel.</description>
                                    <value>#0</value>
                                </enumeratedValue>
                                <enumeratedValue>
                                    <name>1</name>
                                    <description>Select associated input channel. </description>
                                    <value>#1</value>
                                </enumeratedValue>
                            </enumeratedValues>
                        </field>
                        <field>
                            <name>ADS18</name>
                            <description>A/D Conversion Channels Select/Average Channel Select</description>
                            <lsb>2</lsb>
                            <msb>2</msb>
                            <access>read-write</access>
                            <enumeratedValues>
                                <enumeratedValue>
                                    <name>0</name>
                                    <description>Do not select associated input channel.</description>
                                    <value>#0</value>
                                </enumeratedValue>
                                <enumeratedValue>
                                    <name>1</name>
                                    <description>Select associated input channel. </description>
                                    <value>#1</value>
                                </enumeratedValue>
                            </enumeratedValues>
                        </field>
                        <field>
                            <name>ADS19</name>
                            <description>A/D Conversion Channels Select/Average Channel Select</description>
                            <lsb>3</lsb>
                            <msb>3</msb>
                            <access>read-write</access>
                            <enumeratedValues>
                                <enumeratedValue>
                                    <name>0</name>
                                    <description>Do not select associated input channel.</description>
                                    <value>#0</value>
                                </enumeratedValue>
                                <enumeratedValue>
                                    <name>1</name>
                                    <description>Select associated input channel. </description>
                                    <value>#1</value>
                                </enumeratedValue>
                            </enumeratedValues>
                        </field>
                        <field>
                            <name>ADS20</name>
                            <description>A/D Conversion Channels Select/Average Channel Select</description>
                            <lsb>4</lsb>
                            <msb>4</msb>
                            <access>read-write</access>
                            <enumeratedValues>
                                <enumeratedValue>
                                    <name>0</name>
                                    <description>Do not select associated input channel.</description>
                                    <value>#0</value>
                                </enumeratedValue>
                                <enumeratedValue>
                                    <name>1</name>
                                    <description>Select associated input channel. </description>
                                    <value>#1</value>
                                </enumeratedValue>
                            </enumeratedValues>
                        </field>
                        <field>
                            <name>ADS21</name>
                            <description>A/D Conversion Channels Select/Average Channel Select</description>
                            <lsb>5</lsb>
                            <msb>5</msb>
                            <access>read-write</access>
                            <enumeratedValues>
                                <enumeratedValue>
                                    <name>0</name>
                                    <description>Do not select associated input channel.</description>
                                    <value>#0</value>
                                </enumeratedValue>
                                <enumeratedValue>
                                    <name>1</name>
                                    <description>Select associated input channel. </description>
                                    <value>#1</value>
                                </enumeratedValue>
                            </enumeratedValues>
                        </field>
                        <field>
                            <name>ADS22</name>
                            <description>A/D Conversion Channels Select/Average Channel Select</description>
                            <lsb>6</lsb>
                            <msb>6</msb>
                            <access>read-write</access>
                            <enumeratedValues>
                                <enumeratedValue>
                                    <name>0</name>
                                    <description>Do not select associated input channel.</description>
                                    <value>#0</value>
                                </enumeratedValue>
                                <enumeratedValue>
                                    <name>1</name>
                                    <description>Select associated input channel. </description>
                                    <value>#1</value>
                                </enumeratedValue>
                            </enumeratedValues>
                        </field>
                    </fields>
                </register>
                <register>
                    <name>ADADC</name>
                    <description>A/D-Converted Value Addition/Average Count Select Register</description>
                    <addressOffset>0x00C</addressOffset>
                    <size>8</size>
                    <access>read-write</access>
                    <resetValue>0x00</resetValue>
                    <resetMask>0xff</resetMask>
                    <fields>
                        <field>
                            <name>ADC</name>
                            <description>Addition/Average Count Select</description>
                            <lsb>0</lsb>
                            <msb>2</msb>
                            <access>read-write</access>
                            <enumeratedValues>
                                <enumeratedValue>
                                    <name>000</name>
                                    <description>1-time conversion (no addition, same as normal conversion)</description>
                                    <value>#000</value>
                                </enumeratedValue>
                                <enumeratedValue>
                                    <name>001</name>
                                    <description>2-time conversion (1 addition)</description>
                                    <value>#001</value>
                                </enumeratedValue>
                                <enumeratedValue>
                                    <name>010</name>
                                    <description>3-time conversion (2 additions)</description>
                                    <value>#010</value>
                                </enumeratedValue>
                                <enumeratedValue>
                                    <name>011</name>
                                    <description>4-time conversion (3 additions)</description>
                                    <value>#011</value>
                                </enumeratedValue>
                                <enumeratedValue>
                                    <name>101</name>
                                    <description>16-time conversion (15 additions)</description>
                                    <value>#101</value>
                                </enumeratedValue>
                                <enumeratedValue>
                                    <name>Others</name>
                                    <description>Setting prohibited</description>
                                    <isDefault>true</isDefault>
                                </enumeratedValue>
                            </enumeratedValues>
                        </field>
                        <field>
                            <name>AVEE</name>
                            <description>Average Mode Select</description>
                            <lsb>7</lsb>
                            <msb>7</msb>
                            <access>read-write</access>
                            <enumeratedValues>
                                <enumeratedValue>
                                    <name>0</name>
                                    <description>Enable addition mode</description>
                                    <value>#0</value>
                                </enumeratedValue>
                                <enumeratedValue>
                                    <name>1</name>
                                    <description>Enable average mode</description>
                                    <value>#1</value>
                                </enumeratedValue>
                            </enumeratedValues>
                        </field>
                    </fields>
                </register>
                <register>
                    <name>ADCER</name>
                    <description>A/D Control Extended Register</description>
                    <addressOffset>0x00E</addressOffset>
                    <size>16</size>
                    <access>read-write</access>
                    <resetValue>0x0000</resetValue>
                    <resetMask>0xffff</resetMask>
                    <fields>
                        <field>
                            <name>ADPRC</name>
                            <lsb>1</lsb>
                            <msb>2</msb>
                            <access>read-write</access>
                            <enumeratedValues>
                                <enumeratedValue>
                                    <name>00</name>
                                    <description>12-bit accuracy</description>
                                    <value>#00</value>
                                </enumeratedValue>
                                <enumeratedValue>
                                    <name>01</name>
                                    <description>10-bit accuracy</description>
                                    <value>#01</value>
                                </enumeratedValue>
                                <enumeratedValue>
                                    <name>10</name>
                                    <description>8-bit accuracy</description>
                                    <value>#10</value>
                                </enumeratedValue>
                                <enumeratedValue>
                                    <name>11</name>
                                    <description>Setting prohibited</description>
                                    <value>#11</value>
                                </enumeratedValue>
                            </enumeratedValues>
                        </field>
                        <field>
                            <name>ACE</name>
                            <description>A/D Data Register Automatic Clearing Enable</description>
                            <lsb>5</lsb>
                            <msb>5</msb>
                            <access>read-write</access>
                            <enumeratedValues>
                                <enumeratedValue>
                                    <name>0</name>
                                    <description>Disable automatic clearing</description>
                                    <value>#0</value>
                                </enumeratedValue>
                                <enumeratedValue>
                                    <name>1</name>
                                    <description>Enable automatic clearing</description>
                                    <value>#1</value>
                                </enumeratedValue>
                            </enumeratedValues>
                        </field>
                        <field>
                            <name>DIAGVAL</name>
                            <description>Self-Diagnosis Conversion Voltage Select</description>
                            <lsb>8</lsb>
                            <msb>9</msb>
                            <access>read-write</access>
                            <enumeratedValues>
                                <enumeratedValue>
                                    <name>00</name>
                                    <description>Setting prohibited when self-diagnosis is enabled</description>
                                    <value>#00</value>
                                </enumeratedValue>
                                <enumeratedValue>
                                    <name>01</name>
                                    <description>0 volts</description>
                                    <value>#01</value>
                                </enumeratedValue>
                                <enumeratedValue>
                                    <name>10</name>
                                    <description>Reference voltage × 1/2</description>
                                    <value>#10</value>
                                </enumeratedValue>
                                <enumeratedValue>
                                    <name>11</name>
                                    <description>Reference voltage</description>
                                    <value>#11</value>
                                </enumeratedValue>
                            </enumeratedValues>
                        </field>
                        <field>
                            <name>DIAGLD</name>
                            <description>Self-Diagnosis Mode Select</description>
                            <lsb>10</lsb>
                            <msb>10</msb>
                            <access>read-write</access>
                            <enumeratedValues>
                                <enumeratedValue>
                                    <name>0</name>
                                    <description>Select rotation mode for self-diagnosis voltage</description>
                                    <value>#0</value>
                                </enumeratedValue>
                                <enumeratedValue>
                                    <name>1</name>
                                    <description>Select mixed mode for self-diagnosis voltage</description>
                                    <value>#1</value>
                                </enumeratedValue>
                            </enumeratedValues>
                        </field>
                        <field>
                            <name>DIAGM</name>
                            <description>Self-Diagnosis Enable</description>
                            <lsb>11</lsb>
                            <msb>11</msb>
                            <access>read-write</access>
                            <enumeratedValues>
                                <enumeratedValue>
                                    <name>0</name>
                                    <description>Disable ADC12 self-diagnosis</description>
                                    <value>#0</value>
                                </enumeratedValue>
                                <enumeratedValue>
                                    <name>1</name>
                                    <description>Enable ADC12 self-diagnosis</description>
                                    <value>#1</value>
                                </enumeratedValue>
                            </enumeratedValues>
                        </field>
                        <field>
                            <name>ADRFMT</name>
                            <description>A/D Data Register Format Select</description>
                            <lsb>15</lsb>
                            <msb>15</msb>
                            <access>read-write</access>
                            <enumeratedValues>
                                <enumeratedValue>
                                    <name>0</name>
                                    <description>Select right-justified for the A/D data register format</description>
                                    <value>#0</value>
                                </enumeratedValue>
                                <enumeratedValue>
                                    <name>1</name>
                                    <description>Select left-justified for the A/D data register format</description>
                                    <value>#1</value>
                                </enumeratedValue>
                            </enumeratedValues>
                        </field>
                    </fields>
                </register>
                <register>
                    <name>ADSTRGR</name>
                    <description>A/D Conversion Start Trigger Select Register</description>
                    <addressOffset>0x010</addressOffset>
                    <size>16</size>
                    <access>read-write</access>
                    <resetValue>0x0000</resetValue>
                    <resetMask>0xffff</resetMask>
                    <fields>
                        <field>
                            <name>TRSB</name>
                            <description>A/D Conversion Start Trigger Select for Group B</description>
                            <lsb>0</lsb>
                            <msb>5</msb>
                            <access>read-write</access>
                        </field>
                        <field>
                            <name>TRSA</name>
                            <description>A/D Conversion Start Trigger Select</description>
                            <lsb>8</lsb>
                            <msb>13</msb>
                            <access>read-write</access>
                        </field>
                    </fields>
                </register>
                <register>
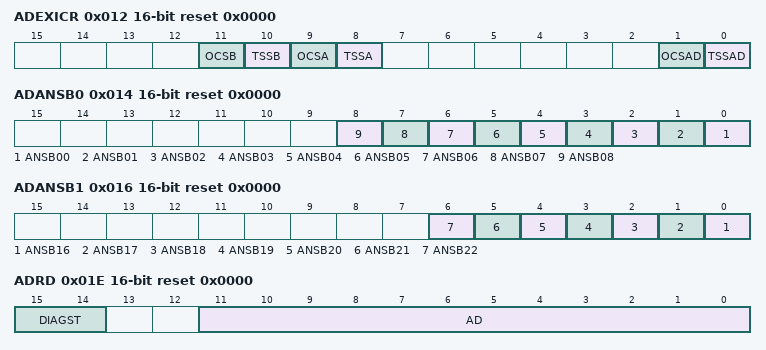
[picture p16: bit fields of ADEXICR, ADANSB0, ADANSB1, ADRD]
                    <name>ADEXICR</name>
                    <description>A/D Conversion Extended Input Control Registers</description>
                    <addressOffset>0x012</addressOffset>
                    <size>16</size>
                    <access>read-write</access>
                    <resetValue>0x0000</resetValue>
                    <resetMask>0xffff</resetMask>
                    <fields>
                        <field>
                            <name>TSSAD</name>
                            <description>Temperature Sensor Output A/D-Converted Value Addition/Average Mode Select</description>
                            <lsb>0</lsb>
                            <msb>0</msb>
                            <access>read-write</access>
                            <enumeratedValues>
                                <enumeratedValue>
                                    <name>0</name>
                                    <description>Do not select addition/average mode for temperature sensor output.</description>
                                    <value>#0</value>
                                </enumeratedValue>
                                <enumeratedValue>
                                    <name>1</name>
                                    <description>Select addition/average mode for temperature sensor output.</description>
                                    <value>#1</value>
                                </enumeratedValue>
                            </enumeratedValues>
                        </field>
                        <field>
                            <name>OCSAD</name>
                            <description>Internal Reference Voltage A/D-Converted Value Addition/Average Mode Select</description>
                            <lsb>1</lsb>
                            <msb>1</msb>
                            <access>read-write</access>
                            <enumeratedValues>
                                <enumeratedValue>
                                    <name>0</name>
                                    <description>Do not select addition/average mode for internal reference voltage.</description>
                                    <value>#0</value>
                                </enumeratedValue>
                                <enumeratedValue>
                                    <name>1</name>
                                    <description>Select addition/average mode for internal reference voltage.</description>
                                    <value>#1</value>
                                </enumeratedValue>
                            </enumeratedValues>
                        </field>
                        <field>
                            <name>TSSA</name>
                            <description>Temperature Sensor Output A/D Conversion Select</description>
                            <lsb>8</lsb>
                            <msb>8</msb>
                            <access>read-write</access>
                            <enumeratedValues>
                                <enumeratedValue>
                                    <name>0</name>
                                    <description>Disable A/D conversion of temperature sensor output</description>
                                    <value>#0</value>
                                </enumeratedValue>
                                <enumeratedValue>
                                    <name>1</name>
                                    <description>Enable A/D conversion of temperature sensor output</description>
                                    <value>#1</value>
                                </enumeratedValue>
                            </enumeratedValues>
                        </field>
                        <field>
                            <name>OCSA</name>
                            <description>Internal Reference Voltage A/D Conversion Select</description>
                            <lsb>9</lsb>
                            <msb>9</msb>
                            <access>read-write</access>
                            <enumeratedValues>
                                <enumeratedValue>
                                    <name>0</name>
                                    <description>Disable A/D conversion of internal reference voltage</description>
                                    <value>#0</value>
                                </enumeratedValue>
                                <enumeratedValue>
                                    <name>1</name>
                                    <description>Enable A/D conversion of internal reference voltage</description>
                                    <value>#1</value>
                                </enumeratedValue>
                            </enumeratedValues>
                        </field>
                        <field>
                            <name>TSSB</name>
                            <description>Temperature Sensor Output A/D Conversion Select for Group B</description>
                            <lsb>10</lsb>
                            <msb>10</msb>
                            <access>read-write</access>
                            <enumeratedValues>
                                <enumeratedValue>
                                    <name>0</name>
                                    <description>Disable A/D conversion of temperature sensor output</description>
                                    <value>#0</value>
                                </enumeratedValue>
                                <enumeratedValue>
                                    <name>1</name>
                                    <description>Enable A/D conversion of temperature sensor output</description>
                                    <value>#1</value>
                                </enumeratedValue>
                            </enumeratedValues>
                        </field>
                        <field>
                            <name>OCSB</name>
                            <description>Internal Reference Voltage A/D Conversion Select for Group B</description>
                            <lsb>11</lsb>
                            <msb>11</msb>
                            <access>read-write</access>
                            <enumeratedValues>
                                <enumeratedValue>
                                    <name>0</name>
                                    <description>Disable A/D conversion of internal reference voltage</description>
                                    <value>#0</value>
                                </enumeratedValue>
                                <enumeratedValue>
                                    <name>1</name>
                                    <description>Enable A/D conversion of internal reference voltage</description>
                                    <value>#1</value>
                                </enumeratedValue>
                            </enumeratedValues>
                        </field>
                    </fields>
                </register>
                <register>
                    <name>ADANSB0</name>
                    <description>A/D Channel Select Register B0</description>
                    <addressOffset>0x014</addressOffset>
                    <size>16</size>
                    <access>read-write</access>
                    <resetValue>0x0000</resetValue>
                    <resetMask>0xffff</resetMask>
                    <fields>
                        <field>
                            <name>ANSB00</name>
                            <description>A/D Conversion Channels Select</description>
                            <lsb>0</lsb>
                            <msb>0</msb>
                            <access>read-write</access>
                            <enumeratedValues>
                                <enumeratedValue>
                                    <name>0</name>
                                    <description>Do not select associated input channel.</description>
                                    <value>#0</value>
                                </enumeratedValue>
                                <enumeratedValue>
                                    <name>1</name>
                                    <description>Select associated input channel. </description>
                                    <value>#1</value>
                                </enumeratedValue>
                            </enumeratedValues>
                        </field>
                        <field>
                            <name>ANSB01</name>
                            <description>A/D Conversion Channels Select</description>
                            <lsb>1</lsb>
                            <msb>1</msb>
                            <access>read-write</access>
                            <enumeratedValues>
                                <enumeratedValue>
                                    <name>0</name>
                                    <description>Do not select associated input channel.</description>
                                    <value>#0</value>
                                </enumeratedValue>
                                <enumeratedValue>
                                    <name>1</name>
                                    <description>Select associated input channel. </description>
                                    <value>#1</value>
                                </enumeratedValue>
                            </enumeratedValues>
                        </field>
                        <field>
                            <name>ANSB02</name>
                            <description>A/D Conversion Channels Select</description>
                            <lsb>2</lsb>
                            <msb>2</msb>
                            <access>read-write</access>
                            <enumeratedValues>
                                <enumeratedValue>
                                    <name>0</name>
                                    <description>Do not select associated input channel.</description>
                                    <value>#0</value>
                                </enumeratedValue>
                                <enumeratedValue>
                                    <name>1</name>
                                    <description>Select associated input channel. </description>
                                    <value>#1</value>
                                </enumeratedValue>
                            </enumeratedValues>
                        </field>
                        <field>
                            <name>ANSB03</name>
                            <description>A/D Conversion Channels Select</description>
                            <lsb>3</lsb>
                            <msb>3</msb>
                            <access>read-write</access>
                            <enumeratedValues>
                                <enumeratedValue>
                                    <name>0</name>
                                    <description>Do not select associated input channel.</description>
                                    <value>#0</value>
                                </enumeratedValue>
                                <enumeratedValue>
                                    <name>1</name>
                                    <description>Select associated input channel. </description>
                                    <value>#1</value>
                                </enumeratedValue>
                            </enumeratedValues>
                        </field>
                        <field>
                            <name>ANSB04</name>
                            <description>A/D Conversion Channels Select</description>
                            <lsb>4</lsb>
                            <msb>4</msb>
                            <access>read-write</access>
                            <enumeratedValues>
                                <enumeratedValue>
                                    <name>0</name>
                                    <description>Do not select associated input channel.</description>
                                    <value>#0</value>
                                </enumeratedValue>
                                <enumeratedValue>
                                    <name>1</name>
                                    <description>Select associated input channel. </description>
                                    <value>#1</value>
                                </enumeratedValue>
                            </enumeratedValues>
                        </field>
                        <field>
                            <name>ANSB05</name>
                            <description>A/D Conversion Channels Select</description>
                            <lsb>5</lsb>
                            <msb>5</msb>
                            <access>read-write</access>
                            <enumeratedValues>
                                <enumeratedValue>
                                    <name>0</name>
                                    <description>Do not select associated input channel.</description>
                                    <value>#0</value>
                                </enumeratedValue>
                                <enumeratedValue>
                                    <name>1</name>
                                    <description>Select associated input channel. </description>
                                    <value>#1</value>
                                </enumeratedValue>
                            </enumeratedValues>
                        </field>
                        <field>
                            <name>ANSB06</name>
                            <description>A/D Conversion Channels Select</description>
                            <lsb>6</lsb>
                            <msb>6</msb>
                            <access>read-write</access>
                            <enumeratedValues>
                                <enumeratedValue>
                                    <name>0</name>
                                    <description>Do not select associated input channel.</description>
                                    <value>#0</value>
                                </enumeratedValue>
                                <enumeratedValue>
                                    <name>1</name>
                                    <description>Select associated input channel. </description>
                                    <value>#1</value>
                                </enumeratedValue>
                            </enumeratedValues>
                        </field>
                        <field>
                            <name>ANSB07</name>
                            <description>A/D Conversion Channels Select</description>
                            <lsb>7</lsb>
                            <msb>7</msb>
                            <access>read-write</access>
                            <enumeratedValues>
                                <enumeratedValue>
                                    <name>0</name>
                                    <description>Do not select associated input channel.</description>
                                    <value>#0</value>
                                </enumeratedValue>
                                <enumeratedValue>
                                    <name>1</name>
                                    <description>Select associated input channel. </description>
                                    <value>#1</value>
                                </enumeratedValue>
                            </enumeratedValues>
                        </field>
                        <field>
                            <name>ANSB08</name>
                            <description>A/D Conversion Channels Select</description>
                            <lsb>8</lsb>
                            <msb>8</msb>
                            <access>read-write</access>
                            <enumeratedValues>
                                <enumeratedValue>
                                    <name>0</name>
                                    <description>Do not select associated input channel.</description>
                                    <value>#0</value>
                                </enumeratedValue>
                                <enumeratedValue>
                                    <name>1</name>
                                    <description>Select associated input channel. </description>
                                    <value>#1</value>
                                </enumeratedValue>
                            </enumeratedValues>
                        </field>
                    </fields>
                </register>
                <register>
                    <name>ADANSB1</name>
                    <description>A/D Channel Select Register B1</description>
                    <addressOffset>0x016</addressOffset>
                    <size>16</size>
                    <access>read-write</access>
                    <resetValue>0x0000</resetValue>
                    <resetMask>0xffff</resetMask>
                    <fields>
                        <field>
                            <name>ANSB16</name>
                            <description>A/D Conversion Channels Select</description>
                            <lsb>0</lsb>
                            <msb>0</msb>
                            <access>read-write</access>
                            <enumeratedValues>
                                <enumeratedValue>
                                    <name>0</name>
                                    <description>Do not select associated input channel.</description>
                                    <value>#0</value>
                                </enumeratedValue>
                                <enumeratedValue>
                                    <name>1</name>
                                    <description>Select associated input channel. </description>
                                    <value>#1</value>
                                </enumeratedValue>
                            </enumeratedValues>
                        </field>
                        <field>
                            <name>ANSB17</name>
                            <description>A/D Conversion Channels Select</description>
                            <lsb>1</lsb>
                            <msb>1</msb>
                            <access>read-write</access>
                            <enumeratedValues>
                                <enumeratedValue>
                                    <name>0</name>
                                    <description>Do not select associated input channel.</description>
                                    <value>#0</value>
                                </enumeratedValue>
                                <enumeratedValue>
                                    <name>1</name>
                                    <description>Select associated input channel. </description>
                                    <value>#1</value>
                                </enumeratedValue>
                            </enumeratedValues>
                        </field>
                        <field>
                            <name>ANSB18</name>
                            <description>A/D Conversion Channels Select</description>
                            <lsb>2</lsb>
                            <msb>2</msb>
                            <access>read-write</access>
                            <enumeratedValues>
                                <enumeratedValue>
                                    <name>0</name>
                                    <description>Do not select associated input channel.</description>
                                    <value>#0</value>
                                </enumeratedValue>
                                <enumeratedValue>
                                    <name>1</name>
                                    <description>Select associated input channel. </description>
                                    <value>#1</value>
                                </enumeratedValue>
                            </enumeratedValues>
                        </field>
                        <field>
                            <name>ANSB19</name>
                            <description>A/D Conversion Channels Select</description>
                            <lsb>3</lsb>
                            <msb>3</msb>
                            <access>read-write</access>
                            <enumeratedValues>
                                <enumeratedValue>
                                    <name>0</name>
                                    <description>Do not select associated input channel.</description>
                                    <value>#0</value>
                                </enumeratedValue>
                                <enumeratedValue>
                                    <name>1</name>
                                    <description>Select associated input channel. </description>
                                    <value>#1</value>
                                </enumeratedValue>
                            </enumeratedValues>
                        </field>
                        <field>
                            <name>ANSB20</name>
                            <description>A/D Conversion Channels Select</description>
                            <lsb>4</lsb>
                            <msb>4</msb>
                            <access>read-write</access>
                            <enumeratedValues>
                                <enumeratedValue>
                                    <name>0</name>
                                    <description>Do not select associated input channel.</description>
                                    <value>#0</value>
                                </enumeratedValue>
                                <enumeratedValue>
                                    <name>1</name>
                                    <description>Select associated input channel. </description>
                                    <value>#1</value>
                                </enumeratedValue>
                            </enumeratedValues>
                        </field>
                        <field>
                            <name>ANSB21</name>
                            <description>A/D Conversion Channels Select</description>
                            <lsb>5</lsb>
                            <msb>5</msb>
                            <access>read-write</access>
                            <enumeratedValues>
                                <enumeratedValue>
                                    <name>0</name>
                                    <description>Do not select associated input channel.</description>
                                    <value>#0</value>
                                </enumeratedValue>
                                <enumeratedValue>
                                    <name>1</name>
                                    <description>Select associated input channel. </description>
                                    <value>#1</value>
                                </enumeratedValue>
                            </enumeratedValues>
                        </field>
                        <field>
                            <name>ANSB22</name>
                            <description>A/D Conversion Channels Select</description>
                            <lsb>6</lsb>
                            <msb>6</msb>
                            <access>read-write</access>
                            <enumeratedValues>
                                <enumeratedValue>
                                    <name>0</name>
                                    <description>Do not select associated input channel.</description>
                                    <value>#0</value>
                                </enumeratedValue>
                                <enumeratedValue>
                                    <name>1</name>
                                    <description>Select associated input channel. </description>
                                    <value>#1</value>
                                </enumeratedValue>
                            </enumeratedValues>
                        </field>
                    </fields>
                </register>
                <register>
                    <name>ADDBLDR</name>
                    <description>A/D Data Duplexing Register</description>
                    <addressOffset>0x018</addressOffset>
                    <size>16</size>
                    <access>read-only</access>
                    <resetValue>0x0000</resetValue>
                    <resetMask>0xffff</resetMask>
                    <fields>
                        <field>
                            <name>ADDBLDR</name>
                            <description>Converted Value 15 to 0</description>
                            <lsb>0</lsb>
                            <msb>15</msb>
                            <access>read-only</access>
                        </field>
                    </fields>
                </register>
                <register>
                    <name>ADTSDR</name>
                    <description>A/D Temperature Sensor Data Register</description>
                    <addressOffset>0x01A</addressOffset>
                    <size>16</size>
                    <access>read-only</access>
                    <resetValue>0x0000</resetValue>
                    <resetMask>0xffff</resetMask>
                    <fields>
                        <field>
                            <name>ADTSDR</name>
                            <description>Converted Value 15 to 0</description>
                            <lsb>0</lsb>
                            <msb>15</msb>
                            <access>read-only</access>
                        </field>
                    </fields>
                </register>
                <register>
                    <name>ADOCDR</name>
                    <description>A/D Internal Reference Voltage Data Register</description>
                    <addressOffset>0x01C</addressOffset>
                    <size>16</size>
                    <access>read-only</access>
                    <resetValue>0x0000</resetValue>
                    <resetMask>0xffff</resetMask>
                    <fields>
                        <field>
                            <name>ADOCDR</name>
                            <description>Converted Value 15 to 0</description>
                            <lsb>0</lsb>
                            <msb>15</msb>
                            <access>read-only</access>
                        </field>
                    </fields>
                </register>
                <register>
                    <name>ADRD</name>
                    <description>A/D Self-Diagnosis Data Register</description>
                    <addressOffset>0x01E</addressOffset>
                    <size>16</size>
                    <access>read-only</access>
                    <resetValue>0x0000</resetValue>
                    <resetMask>0xffff</resetMask>
                    <fields>
                        <field>
                            <name>AD</name>
                            <description>Converted Value 11 to 0</description>
                            <lsb>0</lsb>
                            <msb>11</msb>
                            <access>read-only</access>
                        </field>
                        <field>
                            <name>DIAGST</name>
                            <description>Self-Diagnosis Status</description>
                            <lsb>14</lsb>
                            <msb>15</msb>
                            <access>read-only</access>
                            <enumeratedValues>
                                <enumeratedValue>
                                    <name>00</name>
                                    <description>Self-diagnosis not executed after power-on.</description>
                                    <value>#00</value>
                                </enumeratedValue>
                                <enumeratedValue>
                                    <name>01</name>
                                    <description>Self-diagnosis was executed using the 0 V voltage.</description>
                                    <value>#01</value>
                                </enumeratedValue>
                                <enumeratedValue>
                                    <name>10</name>
                                    <description>Self-diagnosis was executed using the reference voltage × 1/2.</description>
                                    <value>#10</value>
                                </enumeratedValue>
                                <enumeratedValue>
                                    <name>11</name>
                                    <description>Self-diagnosis was executed using the reference voltage .</description>
                                    <value>#11</value>
                                </enumeratedValue>
                            </enumeratedValues>
                        </field>
                    </fields>
                </register>
                <register>
                    <dim>9</dim>
                    <dimIncrement>0x2</dimIncrement>
                    <dimIndex>0-8</dimIndex>
                    <name>ADDR%s</name>
                    <description>A/D Data Registers %s</description>
                    <addressOffset>0x020</addressOffset>
                    <size>16</size>
                    <access>read-only</access>
                    <resetValue>0x0000</resetValue>
                    <resetMask>0xffff</resetMask>
                    <fields>
                        <field>
                            <name>ADDR</name>
                            <description>Converted Value 15 to 0</description>
                            <lsb>0</lsb>
                            <msb>15</msb>
                            <access>read-only</access>
                        </field>
                    </fields>
                </register>
                <register>
                    <dim>4</dim>
                    <dimIncrement>0x2</dimIncrement>
                    <dimIndex>16-19</dimIndex>
                    <name>ADDR%s</name>
                    <description>A/D Data Registers %s</description>
                    <addressOffset>0x020</addressOffset>
                    <size>16</size>
                    <access>read-only</access>
                    <resetValue>0x0000</resetValue>
                    <resetMask>0xffff</resetMask>
                    <fields>
                        <field>
                            <name>ADDR</name>
                            <description>Converted Value 15 to 0</description>
                            <lsb>0</lsb>
                            <msb>15</msb>
                            <access>read-only</access>
                        </field>
                    </fields>
                </register>
                <register>
                    <name>ADVMDR</name>
                    <description>A/D VBATT Monitor Data Register</description>
                    <addressOffset>0x026</addressOffset>
                    <size>16</size>
                    <access>read-only</access>
                    <resetValue>0x0000</resetValue>
                    <resetMask>0xffff</resetMask>
                    <fields>
                        <field>
                            <name>ADDR</name>
                            <description>Converted Value 15 to 0</description>
                            <lsb>0</lsb>
                            <msb>15</msb>
                            <access>read-only</access>
                        </field>
                    </fields>
                </register>
                <register>
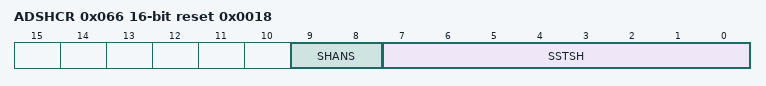
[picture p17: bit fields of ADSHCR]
                    <name>ADSHCR</name>
                    <description>A/D Sample and Hold Circuit Control Register</description>
                    <addressOffset>0x066</addressOffset>
                    <size>16</size>
                    <access>read-write</access>
                    <resetValue>0x0018</resetValue>
                    <resetMask>0xffff</resetMask>
                    <fields>
                        <field>
                            <name>SSTSH</name>
                            <description>Channel-Dedicated Sample-and-Hold Circuit Sampling Time Setting</description>
                            <lsb>0</lsb>
                            <msb>7</msb>
                            <access>read-write</access>
                        </field>
                        <field>
                            <name>SHANS</name>
                            <description>Channel-Dedicated Sample-and-Hold Circuit Bypass Select</description>
                            <lsb>8</lsb>
                            <msb>9</msb>
                            <access>read-write</access>
                            <enumeratedValues>
                                <enumeratedValue>
                                    <name>0</name>
                                    <description>Bypass the circuits</description>
                                    <value>#0</value>
                                </enumeratedValue>
                                <enumeratedValue>
                                    <name>1</name>
                                    <description>Use the circuits</description>
                                    <value>#1</value>
                                </enumeratedValue>
                            </enumeratedValues>
                        </field>
                    </fields>
                </register>
                <register>
                    <name>ADDISCR</name>
                    <description>A/D Disconnection Detection Control Register</description>
                    <addressOffset>0x07A</addressOffset>
                    <size>8</size>
                    <access>read-write</access>
                    <resetValue>0x00</resetValue>
                    <resetMask>0xff</resetMask>
                    <fields>
                        <field>
                            <name>ADNDIS</name>
                            <description>Disconnection Detection Assist Setting</description>
                            <lsb>0</lsb>
                            <msb>3</msb>
                            <access>read-write</access>
                            <enumeratedValues>
                                <enumeratedValue>
                                    <name>0x0</name>
                                    <description>The disconnection detection assist function is disabled</description>
                                    <value>0x0</value>
                                </enumeratedValue>
                                <enumeratedValue>
                                    <name>0x1</name>
                                    <description>Setting prohibited</description>
                                    <value>0x1</value>
                                </enumeratedValue>
                                <enumeratedValue>
                                    <name>Others</name>
                                    <description>The number of states for the discharge or precharge period.</description>
                                    <isDefault>true</isDefault>
                                </enumeratedValue>
                            </enumeratedValues>
                        </field>
                        <field>
                            <name>PCHG</name>
                            <description>Precharge/discharge select</description>
                            <lsb>4</lsb>
                            <msb>4</msb>
                            <access>read-write</access>
                            <enumeratedValues>
                                <enumeratedValue>
                                    <name>0</name>
                                    <description>Discharge</description>
                                    <value>#0</value>
                                </enumeratedValue>
                                <enumeratedValue>
                                    <name>1</name>
                                    <description>Precharge</description>
                                    <value>#1</value>
                                </enumeratedValue>
                            </enumeratedValues>
                        </field>
                    </fields>
                </register>
                <register>
                    <name>ADSHMSR</name>
                    <description>A/D Sample and Hold Operation Mode Selection Register</description>
                    <addressOffset>0x07C</addressOffset>
                    <size>8</size>
                    <access>read-write</access>
                    <resetValue>0x00</resetValue>
                    <resetMask>0xff</resetMask>
                    <fields>
                        <field>
                            <name>SHMD</name>
                            <description>Sampling Operation Selection</description>
                            <lsb>0</lsb>
                            <msb>0</msb>
                            <access>read-write</access>
                            <enumeratedValues>
                                <enumeratedValue>
                                    <name>0</name>
                                    <description>Sampling Operation Selection</description>
                                    <value>#0</value>
                                </enumeratedValue>
                                <enumeratedValue>
                                    <name>1</name>
                                    <description>Enable continuous sampling function</description>
                                    <value>#1</value>
                                </enumeratedValue>
                            </enumeratedValues>
                        </field>
                    </fields>
                </register>
                <register>
                    <name>ADGSPCR</name>
                    <description>A/D Group Scan Priority Control Register</description>
                    <addressOffset>0x080</addressOffset>
                    <size>16</size>
                    <access>read-write</access>
                    <resetValue>0x0000</resetValue>
                    <resetMask>0xffff</resetMask>
                    <fields>
                        <field>
                            <name>PGS</name>
                            <description>Group Priority Operation Setting</description>
                            <lsb>0</lsb>
                            <msb>0</msb>
                            <access>read-write</access>
                            <enumeratedValues>
                                <enumeratedValue>
                                    <name>0</name>
                                    <description>Operate without group priority control.</description>
                                    <value>#0</value>
                                </enumeratedValue>
                                <enumeratedValue>
                                    <name>1</name>
                                    <description>Operate with group priority control.</description>
                                    <value>#1</value>
                                </enumeratedValue>
                            </enumeratedValues>
                        </field>
                        <field>
                            <name>GBRSCN</name>
                            <description>Lower-Priority Group Restart Setting</description>
                            <lsb>1</lsb>
                            <msb>1</msb>
                            <access>read-write</access>
                            <enumeratedValues>
                                <enumeratedValue>
                                    <name>0</name>
                                    <description>Disable rescanning of the group that was stopped in group priority operation</description>
                                    <value>#0</value>
                                </enumeratedValue>
                                <enumeratedValue>
                                    <name>1</name>
                                    <description>Enable rescanning of the group that was stopped in group priority operation.</description>
                                    <value>#1</value>
                                </enumeratedValue>
                            </enumeratedValues>
                        </field>
                        <field>
                            <name>LGRRS</name>
                            <description>Enabled only when PGS = 1 and GBRSCN = 1.</description>
                            <lsb>14</lsb>
                            <msb>14</msb>
                            <access>read-write</access>
                            <enumeratedValues>
                                <enumeratedValue>
                                    <name>0</name>
                                    <description>Start rescanning from the first channel for scanning</description>
                                    <value>#0</value>
                                </enumeratedValue>
                                <enumeratedValue>
                                    <name>1</name>
                                    <description>Start rescanning from the channel for which A/D conversion is not completed.</description>
                                    <value>#1</value>
                                </enumeratedValue>
                            </enumeratedValues>
                        </field>
                        <field>
                            <name>GBRP</name>
                            <description>Single Scan Continuous Start</description>
                            <lsb>15</lsb>
                            <msb>15</msb>
                            <access>read-write</access>
                            <enumeratedValues>
                                <enumeratedValue>
                                    <name>0</name>
                                    <description>Single scan is not continuously activated.</description>
                                    <value>#0</value>
                                </enumeratedValue>
                                <enumeratedValue>
                                    <name>1</name>
                                    <description>Single scan for the group with the lower-priority is continuously activated.</description>
                                    <value>#1</value>
                                </enumeratedValue>
                            </enumeratedValues>
                        </field>
                    </fields>
                </register>
                <register>
                    <name>ADDBLDRA</name>
                    <description>A/D Data Duplexing Register A</description>
                    <addressOffset>0x084</addressOffset>
                    <size>16</size>
                    <access>read-only</access>
                    <resetValue>0x0000</resetValue>
                    <resetMask>0xffff</resetMask>
                    <fields>
                        <field>
                            <name>ADDBLDR</name>
                            <description>Converted Value 15 to 0</description>
                            <lsb>0</lsb>
                            <msb>15</msb>
                            <access>read-only</access>
                        </field>
                    </fields>
                </register>
                <register>
                    <name>ADDBLDRB</name>
                    <description>A/D Data Duplexing Register B</description>
                    <addressOffset>0x086</addressOffset>
                    <size>16</size>
                    <access>read-only</access>
                    <resetValue>0x0000</resetValue>
                    <resetMask>0xffff</resetMask>
                    <fields>
                        <field>
                            <name>ADDBLDR</name>
                            <description>Converted Value 15 to 0</description>
                            <lsb>0</lsb>
                            <msb>15</msb>
                            <access>read-only</access>
                        </field>
                    </fields>
                </register>
                <register>
                    <name>ADWINMON</name>
                    <description>A/D Compare Function Window A/B Status Monitor Register</description>
                    <addressOffset>0x08C</addressOffset>
                    <size>8</size>
                    <access>read-only</access>
                    <resetValue>0x00</resetValue>
                    <resetMask>0xff</resetMask>
                    <fields>
                        <field>
                            <name>MONCOMB</name>
                            <description>Combination Result Monitor</description>
                            <lsb>0</lsb>
                            <msb>0</msb>
                            <access>read-only</access>
                            <enumeratedValues>
                                <enumeratedValue>
                                    <name>0</name>
                                    <description>Window A/B composite conditions are not met.</description>
                                    <value>#0</value>
                                </enumeratedValue>
                                <enumeratedValue>
                                    <name>1</name>
                                    <description>Window A/B composite conditions are met.</description>
                                    <value>#1</value>
                                </enumeratedValue>
                            </enumeratedValues>
                        </field>
                        <field>
                            <name>MONCMPA</name>
                            <description>Comparison Result Monitor A</description>
                            <lsb>4</lsb>
                            <msb>4</msb>
                            <access>read-only</access>
                            <enumeratedValues>
                                <enumeratedValue>
                                    <name>0</name>
                                    <description>Window A comparison conditions are not met.</description>
                                    <value>#0</value>
                                </enumeratedValue>
                                <enumeratedValue>
                                    <name>1</name>
                                    <description>Window A comparison conditions are met.</description>
                                    <value>#1</value>
                                </enumeratedValue>
                            </enumeratedValues>
                        </field>
                        <field>
                            <name>MONCMPB</name>
                            <description>Comparison Result Monitor B</description>
                            <lsb>5</lsb>
                            <msb>5</msb>
                            <access>read-only</access>
                            <enumeratedValues>
                                <enumeratedValue>
                                    <name>0</name>
                                    <description>Window B comparison conditions are not met.</description>
                                    <value>#0</value>
                                </enumeratedValue>
                                <enumeratedValue>
                                    <name>1</name>
                                    <description>Window B comparison conditions are met.</description>
                                    <value>#1</value>
                                </enumeratedValue>
                            </enumeratedValues>
                        </field>
                    </fields>
                </register>
                <register>
                    <name>ADCMPCR</name>
                    <description>A/D Compare Function Control Register</description>
                    <addressOffset>0x090</addressOffset>
                    <size>16</size>
                    <access>read-write</access>
                    <resetValue>0x0000</resetValue>
                    <resetMask>0xffff</resetMask>
                    <fields>
                        <field>
                            <name>CMPAB</name>
                            <description>Window A/B Composite Conditions Setting</description>
                            <lsb>0</lsb>
                            <msb>1</msb>
                            <access>read-write</access>
                            <enumeratedValues>
                                <enumeratedValue>
                                    <name>00</name>
                                    <description>Output ADC12i_WCMPM (i = 0, 1) when window A OR window B comparison conditions are met. Otherwise, output ADC12i_WCMPUM (i = 0, 1).</description>
                                    <value>#00</value>
                                </enumeratedValue>
                                <enumeratedValue>
                                    <name>01</name>
                                    <description>Output ADC12i_WCMPM (i = 0, 1) when window A EXOR window B comparison conditions are met. Otherwise, output ADC12i_WCMPUM (i = 0, 1).</description>
                                    <value>#01</value>
                                </enumeratedValue>
                                <enumeratedValue>
                                    <name>10</name>
                                    <description>Output ADC12i_WCMPM (i = 0, 1) when window A AND window B comparison conditions are met. Otherwise, output ADC12i_WCMPUM (i = 0, 1).</description>
                                    <value>#10</value>
                                </enumeratedValue>
                                <enumeratedValue>
                                    <name>11</name>
                                    <description>Setting prohibited.</description>
                                    <value>#11</value>
                                </enumeratedValue>
                            </enumeratedValues>
                        </field>
                        <field>
                            <name>CMPBE</name>
                            <description>Compare Window B Operation Enable</description>
                            <lsb>9</lsb>
                            <msb>9</msb>
                            <access>read-write</access>
                            <enumeratedValues>
                                <enumeratedValue>
                                    <name>0</name>
                                    <description>Disable compare window B operation. Disable ADC12i_WCMPM (i = 0, 1) and ADC12i_WCMPUM (i = 0, 1) outputs. </description>
                                    <value>#0</value>
                                </enumeratedValue>
                                <enumeratedValue>
                                    <name>1</name>
                                    <description>Enable compare window B operation.</description>
                                    <value>#1</value>
                                </enumeratedValue>
                            </enumeratedValues>
                        </field>
                        <field>
                            <name>CMPAE</name>
                            <description>Compare Window A Operation Enable</description>
                            <lsb>11</lsb>
                            <msb>11</msb>
                            <access>read-write</access>
                            <enumeratedValues>
                                <enumeratedValue>
                                    <name>0</name>
                                    <description>Disable compare window A operation. Disable ADC12i_WCMPM (i = 0, 1) and ADC12i_WCMPUM (i = 0, 1) outputs. </description>
                                    <value>#0</value>
                                </enumeratedValue>
                                <enumeratedValue>
                                    <name>1</name>
                                    <description>Enable compare window A operation.</description>
                                    <value>#1</value>
                                </enumeratedValue>
                            </enumeratedValues>
                        </field>
                        <field>
                            <name>CMPBIE</name>
                            <description>Compare B Interrupt Enable</description>
                            <lsb>13</lsb>
                            <msb>13</msb>
                            <access>read-write</access>
                            <enumeratedValues>
                                <enumeratedValue>
                                    <name>0</name>
                                    <description>Disable ADC12i_CMPBI (i = 0, 1) interrupt when comparison conditions (window B) are met.</description>
                                    <value>#0</value>
                                </enumeratedValue>
                                <enumeratedValue>
                                    <name>1</name>
                                    <description>Enable ADC12i_CMPBI (i = 0, 1) interrupt when comparison conditions (window B) are met.</description>
                                    <value>#1</value>
                                </enumeratedValue>
                            </enumeratedValues>
                        </field>
                        <field>
                            <name>WCMPE</name>
                            <description>Window Function Setting</description>
                            <lsb>14</lsb>
                            <msb>14</msb>
                            <access>read-write</access>
                            <enumeratedValues>
                                <enumeratedValue>
                                    <name>0</name>
                                    <description>Disable window function Window A and window B operate as a comparator to compare the single value on the lower side with the A/D conversion result. </description>
                                    <value>#0</value>
                                </enumeratedValue>
                                <enumeratedValue>
                                    <name>1</name>
                                    <description>Enable window function Window A and window B operate as a comparator to compare the two values on the upper and lower sides with the A/D conversion result. </description>
                                    <value>#1</value>
                                </enumeratedValue>
                            </enumeratedValues>
                        </field>
                        <field>
                            <name>CMPAIE</name>
                            <description>Compare A Interrupt Enable</description>
                            <lsb>15</lsb>
                            <msb>15</msb>
                            <access>read-write</access>
                            <enumeratedValues>
                                <enumeratedValue>
                                    <name>0</name>
                                    <description>Disable ADC12i_CMPAI (i = 0, 1) interrupt when comparison conditions (window A) are met.</description>
                                    <value>#0</value>
                                </enumeratedValue>
                                <enumeratedValue>
                                    <name>1</name>
                                    <description>Enable ADC12i_CMPAI (i = 0, 1) interrupt when comparison conditions (window A) are met.</description>
                                    <value>#1</value>
                                </enumeratedValue>
                            </enumeratedValues>
                        </field>
                    </fields>
                </register>
                <register>
                    <name>ADCMPANSER</name>
                    <description>A/D Compare Function Window A Extended Input Select Register</description>
                    <addressOffset>0x092</addressOffset>
                    <size>8</size>
                    <access>read-write</access>
                    <resetValue>0x00</resetValue>
                    <resetMask>0xff</resetMask>
                    <fields>
                        <field>
                            <name>CMPTSA</name>
                            <description>Temperature Sensor Output Compare Select</description>
                            <lsb>0</lsb>
                            <msb>0</msb>
                            <access>read-write</access>
                            <enumeratedValues>
                                <enumeratedValue>
                                    <name>0</name>
                                    <description>Exclude the temperature sensor output from the compare Window A target range.</description>
                                    <value>#0</value>
                                </enumeratedValue>
                                <enumeratedValue>
                                    <name>1</name>
                                    <description>Include the temperature sensor output in the compare Window A target range.</description>
                                    <value>#1</value>
                                </enumeratedValue>
                            </enumeratedValues>
                        </field>
                        <field>
                            <name>CMPOCA</name>
                            <description>Internal Reference Voltage Compare Select</description>
                            <lsb>1</lsb>
                            <msb>1</msb>
                            <access>read-write</access>
                            <enumeratedValues>
                                <enumeratedValue>
                                    <name>0</name>
                                    <description>Exclude the internal reference voltage from the compare Window A target range.</description>
                                    <value>#0</value>
                                </enumeratedValue>
                                <enumeratedValue>
                                    <name>1</name>
                                    <description>Include the internal reference voltage in the compare Window A target range. </description>
                                    <value>#1</value>
                                </enumeratedValue>
                            </enumeratedValues>
                        </field>
                    </fields>
                </register>
                <register>
                    <name>ADCMPLER</name>
                    <description>A/D Compare Function Window A Extended Input Comparison Condition Setting Register</description>
                    <addressOffset>0x093</addressOffset>
                    <size>8</size>
                    <access>read-write</access>
                    <resetValue>0x00</resetValue>
                    <resetMask>0xff</resetMask>
                    <fields>
                        <field>
                            <name>CMPLTSA</name>
                            <description>Compare Window A Temperature Sensor Output Comparison Condition Select</description>
                            <lsb>0</lsb>
                            <msb>0</msb>
                            <access>read-write</access>
                            <enumeratedValues>
                                <enumeratedValue>
                                    <name>0</name>
                                    <description>When window function is disabled (ADCMPCR.WCMPE = 0) : ADCMPDR0 value &gt; A/D-converted valueCompare Window A Temperature Sensor Output Comparison Condition Select When window function is enabled (ADCMPCR.WCMPE = 1) : Compare Window A Temperature Sensor Output Comparison ConditionA/D-converted value &lt; ADCMPDR0 value, or A/D-converted value &gt; ADCMPDR1 value </description>
                                    <value>#0</value>
                                </enumeratedValue>
                                <enumeratedValue>
                                    <name>1</name>
                                    <description>When window function is disabled (ADCMPCR.WCMPE = 0) : ADCMPDR0 value &lt; A/D-converted value When window function is enabled (ADCMPCR.WCMPE = 1) : ADCMPDR0 value &lt; A/D-converted value &lt; ADCMPDR1 value </description>
                                    <value>#1</value>
                                </enumeratedValue>
                            </enumeratedValues>
                        </field>
                        <field>
                            <name>CMPLOCA</name>
                            <description>Compare Window A Internal Reference Voltage Comparison Condition Select</description>
                            <lsb>1</lsb>
                            <msb>1</msb>
                            <access>read-write</access>
                            <enumeratedValues>
                                <enumeratedValue>
                                    <name>0</name>
                                    <description>When window function is disabled (ADCMPCR.WCMPE = 0) : ADCMPDR0 value &gt; A/D-converted value When window function is enabled (ADCMPCR.WCMPE = 1): A/D-converted value &lt; ADCMPDR0 value, or A/D-converted value &gt; ADCMPDR1 value </description>
                                    <value>#0</value>
                                </enumeratedValue>
                                <enumeratedValue>
                                    <name>1</name>
                                    <description>When window function is disabled (ADCMPCR.WCMPE = 0): ADCMPDR0 value &lt; A/D-converted value When window function is enabled (ADCMPCR.WCMPE = 1): ADCMPDR0 value &lt; A/D-converted value &lt; ADCMPDR1 value </description>
                                    <value>#1</value>
                                </enumeratedValue>
                            </enumeratedValues>
                        </field>
                    </fields>
                </register>
                <register>
                    <name>ADCMPANSR0</name>
                    <description>A/D Compare Function Window A Channel Select Register 0</description>
                    <addressOffset>0x094</addressOffset>
                    <size>16</size>
                    <access>read-write</access>
                    <resetValue>0x0000</resetValue>
                    <resetMask>0xffff</resetMask>
                    <fields>
                        <field>
                            <name>CMPCHA00</name>
                            <description>Compare Window A Channel Select</description>
                            <lsb>0</lsb>
                            <msb>0</msb>
                            <access>read-write</access>
                            <enumeratedValues>
                                <enumeratedValue>
                                    <name>0</name>
                                    <description>Disable compare function for associated input channel</description>
                                    <value>#0</value>
                                </enumeratedValue>
                                <enumeratedValue>
                                    <name>1</name>
                                    <description>Enable compare function for associated input channel</description>
                                    <value>#1</value>
                                </enumeratedValue>
                            </enumeratedValues>
                        </field>
                        <field>
                            <name>CMPCHA01</name>
                            <description>Compare Window A Channel Select</description>
                            <lsb>1</lsb>
                            <msb>1</msb>
                            <access>read-write</access>
                            <enumeratedValues>
                                <enumeratedValue>
                                    <name>0</name>
                                    <description>Disable compare function for associated input channel</description>
                                    <value>#0</value>
                                </enumeratedValue>
                                <enumeratedValue>
                                    <name>1</name>
                                    <description>Enable compare function for associated input channel</description>
                                    <value>#1</value>
                                </enumeratedValue>
                            </enumeratedValues>
                        </field>
                        <field>
                            <name>CMPCHA02</name>
                            <description>Compare Window A Channel Select</description>
                            <lsb>2</lsb>
                            <msb>2</msb>
                            <access>read-write</access>
                            <enumeratedValues>
                                <enumeratedValue>
                                    <name>0</name>
                                    <description>Disable compare function for associated input channel</description>
                                    <value>#0</value>
                                </enumeratedValue>
                                <enumeratedValue>
                                    <name>1</name>
                                    <description>Enable compare function for associated input channel</description>
                                    <value>#1</value>
                                </enumeratedValue>
                            </enumeratedValues>
                        </field>
                        <field>
                            <name>CMPCHA03</name>
                            <description>Compare Window A Channel Select</description>
                            <lsb>3</lsb>
                            <msb>3</msb>
                            <access>read-write</access>
                            <enumeratedValues>
                                <enumeratedValue>
                                    <name>0</name>
                                    <description>Disable compare function for associated input channel</description>
                                    <value>#0</value>
                                </enumeratedValue>
                                <enumeratedValue>
                                    <name>1</name>
                                    <description>Enable compare function for associated input channel</description>
                                    <value>#1</value>
                                </enumeratedValue>
                            </enumeratedValues>
                        </field>
                        <field>
                            <name>CMPCHA04</name>
                            <description>Compare Window A Channel Select</description>
                            <lsb>4</lsb>
                            <msb>4</msb>
                            <access>read-write</access>
                            <enumeratedValues>
                                <enumeratedValue>
                                    <name>0</name>
                                    <description>Disable compare function for associated input channel</description>
                                    <value>#0</value>
                                </enumeratedValue>
                                <enumeratedValue>
                                    <name>1</name>
                                    <description>Enable compare function for associated input channel</description>
                                    <value>#1</value>
                                </enumeratedValue>
                            </enumeratedValues>
                        </field>
                        <field>
                            <name>CMPCHA05</name>
                            <description>Compare Window A Channel Select</description>
                            <lsb>5</lsb>
                            <msb>5</msb>
                            <access>read-write</access>
                            <enumeratedValues>
                                <enumeratedValue>
                                    <name>0</name>
                                    <description>Disable compare function for associated input channel</description>
                                    <value>#0</value>
                                </enumeratedValue>
                                <enumeratedValue>
                                    <name>1</name>
                                    <description>Enable compare function for associated input channel</description>
                                    <value>#1</value>
                                </enumeratedValue>
                            </enumeratedValues>
                        </field>
                        <field>
                            <name>CMPCHA06</name>
                            <description>Compare Window A Channel Select</description>
                            <lsb>6</lsb>
                            <msb>6</msb>
                            <access>read-write</access>
                            <enumeratedValues>
                                <enumeratedValue>
                                    <name>0</name>
                                    <description>Disable compare function for associated input channel</description>
                                    <value>#0</value>
                                </enumeratedValue>
                                <enumeratedValue>
                                    <name>1</name>
                                    <description>Enable compare function for associated input channel</description>
                                    <value>#1</value>
                                </enumeratedValue>
                            </enumeratedValues>
                        </field>
                        <field>
                            <name>CMPCHA07</name>
                            <description>Compare Window A Channel Select</description>
                            <lsb>7</lsb>
                            <msb>7</msb>
                            <access>read-write</access>
                            <enumeratedValues>
                                <enumeratedValue>
                                    <name>0</name>
                                    <description>Disable compare function for associated input channel</description>
                                    <value>#0</value>
                                </enumeratedValue>
                                <enumeratedValue>
                                    <name>1</name>
                                    <description>Enable compare function for associated input channel</description>
                                    <value>#1</value>
                                </enumeratedValue>
                            </enumeratedValues>
                        </field>
                        <field>
                            <name>CMPCHA08</name>
                            <description>Compare Window A Channel Select</description>
                            <lsb>8</lsb>
                            <msb>8</msb>
                            <access>read-write</access>
                            <enumeratedValues>
                                <enumeratedValue>
                                    <name>0</name>
                                    <description>Disable compare function for associated input channel</description>
                                    <value>#0</value>
                                </enumeratedValue>
                                <enumeratedValue>
                                    <name>1</name>
                                    <description>Enable compare function for associated input channel</description>
                                    <value>#1</value>
                                </enumeratedValue>
                            </enumeratedValues>
                        </field>
                        <field>
                            <name>CMPCHA09</name>
                            <description>Compare Window A Channel Select</description>
                            <lsb>9</lsb>
                            <msb>9</msb>
                            <access>read-write</access>
                            <enumeratedValues>
                                <enumeratedValue>
                                    <name>0</name>
                                    <description>Disable compare function for associated input channel</description>
                                    <value>#0</value>
                                </enumeratedValue>
                                <enumeratedValue>
                                    <name>1</name>
                                    <description>Enable compare function for associated input channel</description>
                                    <value>#1</value>
                                </enumeratedValue>
                            </enumeratedValues>
                        </field>
                        <field>
                            <name>CMPCHA10</name>
                            <description>Compare Window A Channel Select</description>
                            <lsb>10</lsb>
                            <msb>10</msb>
                            <access>read-write</access>
                            <enumeratedValues>
                                <enumeratedValue>
                                    <name>0</name>
                                    <description>Disable compare function for associated input channel</description>
                                    <value>#0</value>
                                </enumeratedValue>
                                <enumeratedValue>
                                    <name>1</name>
                                    <description>Enable compare function for associated input channel</description>
                                    <value>#1</value>
                                </enumeratedValue>
                            </enumeratedValues>
                        </field>
                        <field>
                            <name>CMPCHA11</name>
                            <description>Compare Window A Channel Select</description>
                            <lsb>11</lsb>
                            <msb>11</msb>
                            <access>read-write</access>
                            <enumeratedValues>
                                <enumeratedValue>
                                    <name>0</name>
                                    <description>Disable compare function for associated input channel</description>
                                    <value>#0</value>
                                </enumeratedValue>
                                <enumeratedValue>
                                    <name>1</name>
                                    <description>Enable compare function for associated input channel</description>
                                    <value>#1</value>
                                </enumeratedValue>
                            </enumeratedValues>
                        </field>
                        <field>
                            <name>CMPCHA12</name>
                            <description>Compare Window A Channel Select</description>
                            <lsb>12</lsb>
                            <msb>12</msb>
                            <access>read-write</access>
                            <enumeratedValues>
                                <enumeratedValue>
                                    <name>0</name>
                                    <description>Disable compare function for associated input channel</description>
                                    <value>#0</value>
                                </enumeratedValue>
                                <enumeratedValue>
                                    <name>1</name>
                                    <description>Enable compare function for associated input channel</description>
                                    <value>#1</value>
                                </enumeratedValue>
                            </enumeratedValues>
                        </field>
                        <field>
                            <name>CMPCHA13</name>
                            <description>Compare Window A Channel Select</description>
                            <lsb>13</lsb>
                            <msb>13</msb>
                            <access>read-write</access>
                            <enumeratedValues>
                                <enumeratedValue>
                                    <name>0</name>
                                    <description>Disable compare function for associated input channel</description>
                                    <value>#0</value>
                                </enumeratedValue>
                                <enumeratedValue>
                                    <name>1</name>
                                    <description>Enable compare function for associated input channel</description>
                                    <value>#1</value>
                                </enumeratedValue>
                            </enumeratedValues>
                        </field>
                        <field>
                            <name>CMPCHA14</name>
                            <description>Compare Window A Channel Select</description>
                            <lsb>14</lsb>
                            <msb>14</msb>
                            <access>read-write</access>
                            <enumeratedValues>
                                <enumeratedValue>
                                    <name>0</name>
                                    <description>Disable compare function for associated input channel</description>
                                    <value>#0</value>
                                </enumeratedValue>
                                <enumeratedValue>
                                    <name>1</name>
                                    <description>Enable compare function for associated input channel</description>
                                    <value>#1</value>
                                </enumeratedValue>
                            </enumeratedValues>
                        </field>
                        <field>
                            <name>CMPCHA15</name>
                            <description>Compare Window A Channel Select</description>
                            <lsb>15</lsb>
                            <msb>15</msb>
                            <access>read-write</access>
                            <enumeratedValues>
                                <enumeratedValue>
                                    <name>0</name>
                                    <description>Disable compare function for associated input channel</description>
                                    <value>#0</value>
                                </enumeratedValue>
                                <enumeratedValue>
                                    <name>1</name>
                                    <description>Enable compare function for associated input channel</description>
                                    <value>#1</value>
                                </enumeratedValue>
                            </enumeratedValues>
                        </field>
                    </fields>
                </register>
                <register>
                    <name>ADCMPLR0</name>
                    <description>A/D Compare Function Window A Comparison Condition Setting Register 0</description>
                    <addressOffset>0x098</addressOffset>
                    <size>16</size>
                    <access>read-write</access>
                    <resetValue>0x0000</resetValue>
                    <resetMask>0xffff</resetMask>
                    <fields>
                        <field>
                            <name>CMPLCHA00</name>
                            <description>Compare Window A Comparison Condition Select</description>
                            <lsb>0</lsb>
                            <msb>0</msb>
                            <access>read-write</access>
                            <enumeratedValues>
                                <enumeratedValue>
                                    <name>0</name>
                                    <description>When window function is disabled (ADCMPCR.WCMPE = 0): ADCMPDR0 value &gt; A/D-converted value When window function is enabled (ADCMPCR.WCMPE = 1): A/D-converted value &lt; ADCMPDR0 value, or ADCMPDR1 value &lt; A/D-converted value </description>
                                    <value>#0</value>
                                </enumeratedValue>
                                <enumeratedValue>
                                    <name>1</name>
                                    <description>When window function is disabled (ADCMPCR.WCMPE = 0): ADCMPDR0 value &lt; A/D-converted value When window function is enabled (ADCMPCR.WCMPE = 1): ADCMPDR0 value &lt; A/D-converted value &lt; ADCMPDR1 value </description>
                                    <value>#1</value>
                                </enumeratedValue>
                            </enumeratedValues>
                        </field>
                        <field>
                            <name>CMPLCHA01</name>
                            <description>Compare Window A Comparison Condition Select</description>
                            <lsb>1</lsb>
                            <msb>1</msb>
                            <access>read-write</access>
                            <enumeratedValues>
                                <enumeratedValue>
                                    <name>0</name>
                                    <description>When window function is disabled (ADCMPCR.WCMPE = 0): ADCMPDR0 value &gt; A/D-converted value When window function is enabled (ADCMPCR.WCMPE = 1): A/D-converted value &lt; ADCMPDR0 value, or ADCMPDR1 value &lt; A/D-converted value </description>
                                    <value>#0</value>
                                </enumeratedValue>
                                <enumeratedValue>
                                    <name>1</name>
                                    <description>When window function is disabled (ADCMPCR.WCMPE = 0): ADCMPDR0 value &lt; A/D-converted value When window function is enabled (ADCMPCR.WCMPE = 1): ADCMPDR0 value &lt; A/D-converted value &lt; ADCMPDR1 value </description>
                                    <value>#1</value>
                                </enumeratedValue>
                            </enumeratedValues>
                        </field>
                        <field>
                            <name>CMPLCHA02</name>
                            <description>Compare Window A Comparison Condition Select</description>
                            <lsb>2</lsb>
                            <msb>2</msb>
                            <access>read-write</access>
                            <enumeratedValues>
                                <enumeratedValue>
                                    <name>0</name>
                                    <description>When window function is disabled (ADCMPCR.WCMPE = 0): ADCMPDR0 value &gt; A/D-converted value When window function is enabled (ADCMPCR.WCMPE = 1): A/D-converted value &lt; ADCMPDR0 value, or ADCMPDR1 value &lt; A/D-converted value </description>
                                    <value>#0</value>
                                </enumeratedValue>
                                <enumeratedValue>
                                    <name>1</name>
                                    <description>When window function is disabled (ADCMPCR.WCMPE = 0): ADCMPDR0 value &lt; A/D-converted value When window function is enabled (ADCMPCR.WCMPE = 1): ADCMPDR0 value &lt; A/D-converted value &lt; ADCMPDR1 value </description>
                                    <value>#1</value>
                                </enumeratedValue>
                            </enumeratedValues>
                        </field>
                        <field>
                            <name>CMPLCHA03</name>
                            <description>Compare Window A Comparison Condition Select</description>
                            <lsb>3</lsb>
                            <msb>3</msb>
                            <access>read-write</access>
                            <enumeratedValues>
                                <enumeratedValue>
                                    <name>0</name>
                                    <description>When window function is disabled (ADCMPCR.WCMPE = 0): ADCMPDR0 value &gt; A/D-converted value When window function is enabled (ADCMPCR.WCMPE = 1): A/D-converted value &lt; ADCMPDR0 value, or ADCMPDR1 value &lt; A/D-converted value </description>
                                    <value>#0</value>
                                </enumeratedValue>
                                <enumeratedValue>
                                    <name>1</name>
                                    <description>When window function is disabled (ADCMPCR.WCMPE = 0): ADCMPDR0 value &lt; A/D-converted value When window function is enabled (ADCMPCR.WCMPE = 1): ADCMPDR0 value &lt; A/D-converted value &lt; ADCMPDR1 value </description>
                                    <value>#1</value>
                                </enumeratedValue>
                            </enumeratedValues>
                        </field>
                        <field>
                            <name>CMPLCHA04</name>
                            <description>Compare Window A Comparison Condition Select</description>
                            <lsb>4</lsb>
                            <msb>4</msb>
                            <access>read-write</access>
                            <enumeratedValues>
                                <enumeratedValue>
                                    <name>0</name>
                                    <description>When window function is disabled (ADCMPCR.WCMPE = 0): ADCMPDR0 value &gt; A/D-converted value When window function is enabled (ADCMPCR.WCMPE = 1): A/D-converted value &lt; ADCMPDR0 value, or ADCMPDR1 value &lt; A/D-converted value </description>
                                    <value>#0</value>
                                </enumeratedValue>
                                <enumeratedValue>
                                    <name>1</name>
                                    <description>When window function is disabled (ADCMPCR.WCMPE = 0): ADCMPDR0 value &lt; A/D-converted value When window function is enabled (ADCMPCR.WCMPE = 1): ADCMPDR0 value &lt; A/D-converted value &lt; ADCMPDR1 value </description>
                                    <value>#1</value>
                                </enumeratedValue>
                            </enumeratedValues>
                        </field>
                        <field>
                            <name>CMPLCHA05</name>
                            <description>Compare Window A Comparison Condition Select</description>
                            <lsb>5</lsb>
                            <msb>5</msb>
                            <access>read-write</access>
                            <enumeratedValues>
                                <enumeratedValue>
                                    <name>0</name>
                                    <description>When window function is disabled (ADCMPCR.WCMPE = 0): ADCMPDR0 value &gt; A/D-converted value When window function is enabled (ADCMPCR.WCMPE = 1): A/D-converted value &lt; ADCMPDR0 value, or ADCMPDR1 value &lt; A/D-converted value </description>
                                    <value>#0</value>
                                </enumeratedValue>
                                <enumeratedValue>
                                    <name>1</name>
                                    <description>When window function is disabled (ADCMPCR.WCMPE = 0): ADCMPDR0 value &lt; A/D-converted value When window function is enabled (ADCMPCR.WCMPE = 1): ADCMPDR0 value &lt; A/D-converted value &lt; ADCMPDR1 value </description>
                                    <value>#1</value>
                                </enumeratedValue>
                            </enumeratedValues>
                        </field>
                        <field>
                            <name>CMPLCHA06</name>
                            <description>Compare Window A Comparison Condition Select</description>
                            <lsb>6</lsb>
                            <msb>6</msb>
                            <access>read-write</access>
                            <enumeratedValues>
                                <enumeratedValue>
                                    <name>0</name>
                                    <description>When window function is disabled (ADCMPCR.WCMPE = 0): ADCMPDR0 value &gt; A/D-converted value When window function is enabled (ADCMPCR.WCMPE = 1): A/D-converted value &lt; ADCMPDR0 value, or ADCMPDR1 value &lt; A/D-converted value </description>
                                    <value>#0</value>
                                </enumeratedValue>
                                <enumeratedValue>
                                    <name>1</name>
                                    <description>When window function is disabled (ADCMPCR.WCMPE = 0): ADCMPDR0 value &lt; A/D-converted value When window function is enabled (ADCMPCR.WCMPE = 1): ADCMPDR0 value &lt; A/D-converted value &lt; ADCMPDR1 value </description>
                                    <value>#1</value>
                                </enumeratedValue>
                            </enumeratedValues>
                        </field>
                        <field>
                            <name>CMPLCHA07</name>
                            <description>Compare Window A Comparison Condition Select</description>
                            <lsb>7</lsb>
                            <msb>7</msb>
                            <access>read-write</access>
                            <enumeratedValues>
                                <enumeratedValue>
                                    <name>0</name>
                                    <description>When window function is disabled (ADCMPCR.WCMPE = 0): ADCMPDR0 value &gt; A/D-converted value When window function is enabled (ADCMPCR.WCMPE = 1): A/D-converted value &lt; ADCMPDR0 value, or ADCMPDR1 value &lt; A/D-converted value </description>
                                    <value>#0</value>
                                </enumeratedValue>
                                <enumeratedValue>
                                    <name>1</name>
                                    <description>When window function is disabled (ADCMPCR.WCMPE = 0): ADCMPDR0 value &lt; A/D-converted value When window function is enabled (ADCMPCR.WCMPE = 1): ADCMPDR0 value &lt; A/D-converted value &lt; ADCMPDR1 value </description>
                                    <value>#1</value>
                                </enumeratedValue>
                            </enumeratedValues>
                        </field>
                        <field>
                            <name>CMPLCHA08</name>
                            <description>Compare Window A Comparison Condition Select</description>
                            <lsb>8</lsb>
                            <msb>8</msb>
                            <access>read-write</access>
                            <enumeratedValues>
                                <enumeratedValue>
                                    <name>0</name>
                                    <description>When window function is disabled (ADCMPCR.WCMPE = 0): ADCMPDR0 value &gt; A/D-converted value When window function is enabled (ADCMPCR.WCMPE = 1): A/D-converted value &lt; ADCMPDR0 value, or ADCMPDR1 value &lt; A/D-converted value </description>
                                    <value>#0</value>
                                </enumeratedValue>
                                <enumeratedValue>
                                    <name>1</name>
                                    <description>When window function is disabled (ADCMPCR.WCMPE = 0): ADCMPDR0 value &lt; A/D-converted value When window function is enabled (ADCMPCR.WCMPE = 1): ADCMPDR0 value &lt; A/D-converted value &lt; ADCMPDR1 value </description>
                                    <value>#1</value>
                                </enumeratedValue>
                            </enumeratedValues>
                        </field>
                        <field>
                            <name>CMPLCHA09</name>
                            <description>Compare Window A Comparison Condition Select</description>
                            <lsb>9</lsb>
                            <msb>9</msb>
                            <access>read-write</access>
                            <enumeratedValues>
                                <enumeratedValue>
                                    <name>0</name>
                                    <description>When window function is disabled (ADCMPCR.WCMPE = 0): ADCMPDR0 value &gt; A/D-converted value When window function is enabled (ADCMPCR.WCMPE = 1): A/D-converted value &lt; ADCMPDR0 value, or ADCMPDR1 value &lt; A/D-converted value </description>
                                    <value>#0</value>
                                </enumeratedValue>
                                <enumeratedValue>
                                    <name>1</name>
                                    <description>When window function is disabled (ADCMPCR.WCMPE = 0): ADCMPDR0 value &lt; A/D-converted value When window function is enabled (ADCMPCR.WCMPE = 1): ADCMPDR0 value &lt; A/D-converted value &lt; ADCMPDR1 value </description>
                                    <value>#1</value>
                                </enumeratedValue>
                            </enumeratedValues>
                        </field>
                        <field>
                            <name>CMPLCHA10</name>
                            <description>Compare Window A Comparison Condition Select</description>
                            <lsb>10</lsb>
                            <msb>10</msb>
                            <access>read-write</access>
                            <enumeratedValues>
                                <enumeratedValue>
                                    <name>0</name>
                                    <description>When window function is disabled (ADCMPCR.WCMPE = 0): ADCMPDR0 value &gt; A/D-converted value When window function is enabled (ADCMPCR.WCMPE = 1): A/D-converted value &lt; ADCMPDR0 value, or ADCMPDR1 value &lt; A/D-converted value </description>
                                    <value>#0</value>
                                </enumeratedValue>
                                <enumeratedValue>
                                    <name>1</name>
                                    <description>When window function is disabled (ADCMPCR.WCMPE = 0): ADCMPDR0 value &lt; A/D-converted value When window function is enabled (ADCMPCR.WCMPE = 1): ADCMPDR0 value &lt; A/D-converted value &lt; ADCMPDR1 value </description>
                                    <value>#1</value>
                                </enumeratedValue>
                            </enumeratedValues>
                        </field>
                        <field>
                            <name>CMPLCHA11</name>
                            <description>Compare Window A Comparison Condition Select</description>
                            <lsb>11</lsb>
                            <msb>11</msb>
                            <access>read-write</access>
                            <enumeratedValues>
                                <enumeratedValue>
                                    <name>0</name>
                                    <description>When window function is disabled (ADCMPCR.WCMPE = 0): ADCMPDR0 value &gt; A/D-converted value When window function is enabled (ADCMPCR.WCMPE = 1): A/D-converted value &lt; ADCMPDR0 value, or ADCMPDR1 value &lt; A/D-converted value </description>
                                    <value>#0</value>
                                </enumeratedValue>
                                <enumeratedValue>
                                    <name>1</name>
                                    <description>When window function is disabled (ADCMPCR.WCMPE = 0): ADCMPDR0 value &lt; A/D-converted value When window function is enabled (ADCMPCR.WCMPE = 1): ADCMPDR0 value &lt; A/D-converted value &lt; ADCMPDR1 value </description>
                                    <value>#1</value>
                                </enumeratedValue>
                            </enumeratedValues>
                        </field>
                        <field>
                            <name>CMPLCHA12</name>
                            <description>Compare Window A Comparison Condition Select</description>
                            <lsb>12</lsb>
                            <msb>12</msb>
                            <access>read-write</access>
                            <enumeratedValues>
                                <enumeratedValue>
                                    <name>0</name>
                                    <description>When window function is disabled (ADCMPCR.WCMPE = 0): ADCMPDR0 value &gt; A/D-converted value When window function is enabled (ADCMPCR.WCMPE = 1): A/D-converted value &lt; ADCMPDR0 value, or ADCMPDR1 value &lt; A/D-converted value </description>
                                    <value>#0</value>
                                </enumeratedValue>
                                <enumeratedValue>
                                    <name>1</name>
                                    <description>When window function is disabled (ADCMPCR.WCMPE = 0): ADCMPDR0 value &lt; A/D-converted value When window function is enabled (ADCMPCR.WCMPE = 1): ADCMPDR0 value &lt; A/D-converted value &lt; ADCMPDR1 value </description>
                                    <value>#1</value>
                                </enumeratedValue>
                            </enumeratedValues>
                        </field>
                        <field>
                            <name>CMPLCHA13</name>
                            <description>Compare Window A Comparison Condition Select</description>
                            <lsb>13</lsb>
                            <msb>13</msb>
                            <access>read-write</access>
                            <enumeratedValues>
                                <enumeratedValue>
                                    <name>0</name>
                                    <description>When window function is disabled (ADCMPCR.WCMPE = 0): ADCMPDR0 value &gt; A/D-converted value When window function is enabled (ADCMPCR.WCMPE = 1): A/D-converted value &lt; ADCMPDR0 value, or ADCMPDR1 value &lt; A/D-converted value </description>
                                    <value>#0</value>
                                </enumeratedValue>
                                <enumeratedValue>
                                    <name>1</name>
                                    <description>When window function is disabled (ADCMPCR.WCMPE = 0): ADCMPDR0 value &lt; A/D-converted value When window function is enabled (ADCMPCR.WCMPE = 1): ADCMPDR0 value &lt; A/D-converted value &lt; ADCMPDR1 value </description>
                                    <value>#1</value>
                                </enumeratedValue>
                            </enumeratedValues>
                        </field>
                        <field>
                            <name>CMPLCHA14</name>
                            <description>Compare Window A Comparison Condition Select</description>
                            <lsb>14</lsb>
                            <msb>14</msb>
                            <access>read-write</access>
                            <enumeratedValues>
                                <enumeratedValue>
                                    <name>0</name>
                                    <description>When window function is disabled (ADCMPCR.WCMPE = 0): ADCMPDR0 value &gt; A/D-converted value When window function is enabled (ADCMPCR.WCMPE = 1): A/D-converted value &lt; ADCMPDR0 value, or ADCMPDR1 value &lt; A/D-converted value </description>
                                    <value>#0</value>
                                </enumeratedValue>
                                <enumeratedValue>
                                    <name>1</name>
                                    <description>When window function is disabled (ADCMPCR.WCMPE = 0): ADCMPDR0 value &lt; A/D-converted value When window function is enabled (ADCMPCR.WCMPE = 1): ADCMPDR0 value &lt; A/D-converted value &lt; ADCMPDR1 value </description>
                                    <value>#1</value>
                                </enumeratedValue>
                            </enumeratedValues>
                        </field>
                        <field>
                            <name>CMPLCHA15</name>
                            <description>Compare Window A Comparison Condition Select</description>
                            <lsb>15</lsb>
                            <msb>15</msb>
                            <access>read-write</access>
                            <enumeratedValues>
                                <enumeratedValue>
                                    <name>0</name>
                                    <description>When window function is disabled (ADCMPCR.WCMPE = 0): ADCMPDR0 value &gt; A/D-converted value When window function is enabled (ADCMPCR.WCMPE = 1): A/D-converted value &lt; ADCMPDR0 value, or ADCMPDR1 value &lt; A/D-converted value </description>
                                    <value>#0</value>
                                </enumeratedValue>
                                <enumeratedValue>
                                    <name>1</name>
                                    <description>When window function is disabled (ADCMPCR.WCMPE = 0): ADCMPDR0 value &lt; A/D-converted value When window function is enabled (ADCMPCR.WCMPE = 1): ADCMPDR0 value &lt; A/D-converted value &lt; ADCMPDR1 value </description>
                                    <value>#1</value>
                                </enumeratedValue>
                            </enumeratedValues>
                        </field>
                    </fields>
                </register>
                <register>
                    <dim>2</dim>
                    <dimIncrement>0x2</dimIncrement>
                    <dimIndex>0-1</dimIndex>
                    <name>ADCMPDR%s</name>
                    <description>A/D Compare Function Window A Lower-Side/Upper-Side Level Setting Register</description>
                    <addressOffset>0x09C</addressOffset>
                    <size>16</size>
                    <access>read-write</access>
                    <resetValue>0x0000</resetValue>
                    <resetMask>0xffff</resetMask>
                </register>
                <register>
                    <name>ADCMPSR0</name>
                    <description>A/D Compare Function Window A Channel Status Register 0</description>
                    <addressOffset>0x0A0</addressOffset>
                    <size>16</size>
                    <access>read-write</access>
                    <resetValue>0x0000</resetValue>
                    <resetMask>0xffff</resetMask>
                    <fields>
                        <field>
                            <name>CMPSTCHA00</name>
                            <description>Compare Window A Flag</description>
                            <lsb>0</lsb>
                            <msb>0</msb>
                            <access>read-write</access>
                            <enumeratedValues>
                                <enumeratedValue>
                                    <name>0</name>
                                    <description>Comparison conditions are not met.</description>
                                    <value>#0</value>
                                </enumeratedValue>
                                <enumeratedValue>
                                    <name>1</name>
                                    <description>Comparison conditions are met.</description>
                                    <value>#1</value>
                                </enumeratedValue>
                            </enumeratedValues>
                        </field>
                        <field>
                            <name>CMPSTCHA01</name>
                            <description>Compare Window A Flag</description>
                            <lsb>1</lsb>
                            <msb>1</msb>
                            <access>read-write</access>
                            <enumeratedValues>
                                <enumeratedValue>
                                    <name>0</name>
                                    <description>Comparison conditions are not met.</description>
                                    <value>#0</value>
                                </enumeratedValue>
                                <enumeratedValue>
                                    <name>1</name>
                                    <description>Comparison conditions are met.</description>
                                    <value>#1</value>
                                </enumeratedValue>
                            </enumeratedValues>
                        </field>
                        <field>
                            <name>CMPSTCHA02</name>
                            <description>Compare Window A Flag</description>
                            <lsb>2</lsb>
                            <msb>2</msb>
                            <access>read-write</access>
                            <enumeratedValues>
                                <enumeratedValue>
                                    <name>0</name>
                                    <description>Comparison conditions are not met.</description>
                                    <value>#0</value>
                                </enumeratedValue>
                                <enumeratedValue>
                                    <name>1</name>
                                    <description>Comparison conditions are met.</description>
                                    <value>#1</value>
                                </enumeratedValue>
                            </enumeratedValues>
                        </field>
                        <field>
                            <name>CMPSTCHA03</name>
                            <description>Compare Window A Flag</description>
                            <lsb>3</lsb>
                            <msb>3</msb>
                            <access>read-write</access>
                            <enumeratedValues>
                                <enumeratedValue>
                                    <name>0</name>
                                    <description>Comparison conditions are not met.</description>
                                    <value>#0</value>
                                </enumeratedValue>
                                <enumeratedValue>
                                    <name>1</name>
                                    <description>Comparison conditions are met.</description>
                                    <value>#1</value>
                                </enumeratedValue>
                            </enumeratedValues>
                        </field>
                        <field>
                            <name>CMPSTCHA04</name>
                            <description>Compare Window A Flag</description>
                            <lsb>4</lsb>
                            <msb>4</msb>
                            <access>read-write</access>
                            <enumeratedValues>
                                <enumeratedValue>
                                    <name>0</name>
                                    <description>Comparison conditions are not met.</description>
                                    <value>#0</value>
                                </enumeratedValue>
                                <enumeratedValue>
                                    <name>1</name>
                                    <description>Comparison conditions are met.</description>
                                    <value>#1</value>
                                </enumeratedValue>
                            </enumeratedValues>
                        </field>
                        <field>
                            <name>CMPSTCHA05</name>
                            <description>Compare Window A Flag</description>
                            <lsb>5</lsb>
                            <msb>5</msb>
                            <access>read-write</access>
                            <enumeratedValues>
                                <enumeratedValue>
                                    <name>0</name>
                                    <description>Comparison conditions are not met.</description>
                                    <value>#0</value>
                                </enumeratedValue>
                                <enumeratedValue>
                                    <name>1</name>
                                    <description>Comparison conditions are met.</description>
                                    <value>#1</value>
                                </enumeratedValue>
                            </enumeratedValues>
                        </field>
                        <field>
                            <name>CMPSTCHA06</name>
                            <description>Compare Window A Flag</description>
                            <lsb>6</lsb>
                            <msb>6</msb>
                            <access>read-write</access>
                            <enumeratedValues>
                                <enumeratedValue>
                                    <name>0</name>
                                    <description>Comparison conditions are not met.</description>
                                    <value>#0</value>
                                </enumeratedValue>
                                <enumeratedValue>
                                    <name>1</name>
                                    <description>Comparison conditions are met.</description>
                                    <value>#1</value>
                                </enumeratedValue>
                            </enumeratedValues>
                        </field>
                        <field>
                            <name>CMPSTCHA07</name>
                            <description>Compare Window A Flag</description>
                            <lsb>7</lsb>
                            <msb>7</msb>
                            <access>read-write</access>
                            <enumeratedValues>
                                <enumeratedValue>
                                    <name>0</name>
                                    <description>Comparison conditions are not met.</description>
                                    <value>#0</value>
                                </enumeratedValue>
                                <enumeratedValue>
                                    <name>1</name>
                                    <description>Comparison conditions are met.</description>
                                    <value>#1</value>
                                </enumeratedValue>
                            </enumeratedValues>
                        </field>
                        <field>
                            <name>CMPSTCHA08</name>
                            <description>Compare Window A Flag</description>
                            <lsb>8</lsb>
                            <msb>8</msb>
                            <access>read-write</access>
                            <enumeratedValues>
                                <enumeratedValue>
                                    <name>0</name>
                                    <description>Comparison conditions are not met.</description>
                                    <value>#0</value>
                                </enumeratedValue>
                                <enumeratedValue>
                                    <name>1</name>
                                    <description>Comparison conditions are met.</description>
                                    <value>#1</value>
                                </enumeratedValue>
                            </enumeratedValues>
                        </field>
                        <field>
                            <name>CMPSTCHA09</name>
                            <description>Compare Window A Flag</description>
                            <lsb>9</lsb>
                            <msb>9</msb>
                            <access>read-write</access>
                            <enumeratedValues>
                                <enumeratedValue>
                                    <name>0</name>
                                    <description>Comparison conditions are not met.</description>
                                    <value>#0</value>
                                </enumeratedValue>
                                <enumeratedValue>
                                    <name>1</name>
                                    <description>Comparison conditions are met.</description>
                                    <value>#1</value>
                                </enumeratedValue>
                            </enumeratedValues>
                        </field>
                        <field>
                            <name>CMPSTCHA10</name>
                            <description>Compare Window A Flag</description>
                            <lsb>10</lsb>
                            <msb>10</msb>
                            <access>read-write</access>
                            <enumeratedValues>
                                <enumeratedValue>
                                    <name>0</name>
                                    <description>Comparison conditions are not met.</description>
                                    <value>#0</value>
                                </enumeratedValue>
                                <enumeratedValue>
                                    <name>1</name>
                                    <description>Comparison conditions are met.</description>
                                    <value>#1</value>
                                </enumeratedValue>
                            </enumeratedValues>
                        </field>
                        <field>
                            <name>CMPSTCHA11</name>
                            <description>Compare Window A Flag</description>
                            <lsb>11</lsb>
                            <msb>11</msb>
                            <access>read-write</access>
                            <enumeratedValues>
                                <enumeratedValue>
                                    <name>0</name>
                                    <description>Comparison conditions are not met.</description>
                                    <value>#0</value>
                                </enumeratedValue>
                                <enumeratedValue>
                                    <name>1</name>
                                    <description>Comparison conditions are met.</description>
                                    <value>#1</value>
                                </enumeratedValue>
                            </enumeratedValues>
                        </field>
                        <field>
                            <name>CMPSTCHA12</name>
                            <description>Compare Window A Flag</description>
                            <lsb>12</lsb>
                            <msb>12</msb>
                            <access>read-write</access>
                            <enumeratedValues>
                                <enumeratedValue>
                                    <name>0</name>
                                    <description>Comparison conditions are not met.</description>
                                    <value>#0</value>
                                </enumeratedValue>
                                <enumeratedValue>
                                    <name>1</name>
                                    <description>Comparison conditions are met.</description>
                                    <value>#1</value>
                                </enumeratedValue>
                            </enumeratedValues>
                        </field>
                        <field>
                            <name>CMPSTCHA13</name>
                            <description>Compare Window A Flag</description>
                            <lsb>13</lsb>
                            <msb>13</msb>
                            <access>read-write</access>
                            <enumeratedValues>
                                <enumeratedValue>
                                    <name>0</name>
                                    <description>Comparison conditions are not met.</description>
                                    <value>#0</value>
                                </enumeratedValue>
                                <enumeratedValue>
                                    <name>1</name>
                                    <description>Comparison conditions are met.</description>
                                    <value>#1</value>
                                </enumeratedValue>
                            </enumeratedValues>
                        </field>
                        <field>
                            <name>CMPSTCHA14</name>
                            <description>Compare Window A Flag</description>
                            <lsb>14</lsb>
                            <msb>14</msb>
                            <access>read-write</access>
                            <enumeratedValues>
                                <enumeratedValue>
                                    <name>0</name>
                                    <description>Comparison conditions are not met.</description>
                                    <value>#0</value>
                                </enumeratedValue>
                                <enumeratedValue>
                                    <name>1</name>
                                    <description>Comparison conditions are met.</description>
                                    <value>#1</value>
                                </enumeratedValue>
                            </enumeratedValues>
                        </field>
                        <field>
                            <name>CMPSTCHA15</name>
                            <description>Compare Window A Flag</description>
                            <lsb>15</lsb>
                            <msb>15</msb>
                            <access>read-write</access>
                            <enumeratedValues>
                                <enumeratedValue>
                                    <name>0</name>
                                    <description>Comparison conditions are not met.</description>
                                    <value>#0</value>
                                </enumeratedValue>
                                <enumeratedValue>
                                    <name>1</name>
                                    <description>Comparison conditions are met.</description>
                                    <value>#1</value>
                                </enumeratedValue>
                            </enumeratedValues>
                        </field>
                    </fields>
                </register>
                <register>
                    <name>ADCMPSER</name>
                    <description>A/D Compare Function Window A Extended Input Channel Status Register</description>
                    <addressOffset>0x0A4</addressOffset>
                    <size>8</size>
                    <access>read-write</access>
                    <resetValue>0x00</resetValue>
                    <resetMask>0xff</resetMask>
                    <fields>
                        <field>
                            <name>CMPSTTSA</name>
                            <description>Compare Window A Temperature Sensor Output Compare Flag</description>
                            <lsb>0</lsb>
                            <msb>0</msb>
                            <access>read-write</access>
                            <enumeratedValues>
                                <enumeratedValue>
                                    <name>0</name>
                                    <description>Comparison conditions are not met.</description>
                                    <value>#0</value>
                                </enumeratedValue>
                                <enumeratedValue>
                                    <name>1</name>
                                    <description>Comparison conditions are met.</description>
                                    <value>#1</value>
                                </enumeratedValue>
                            </enumeratedValues>
                        </field>
                        <field>
                            <name>CMPSTOCA</name>
                            <description>Compare Window A Internal Reference Voltage Compare Flag</description>
                            <lsb>1</lsb>
                            <msb>1</msb>
                            <access>read-write</access>
                            <enumeratedValues>
                                <enumeratedValue>
                                    <name>0</name>
                                    <description>Comparison conditions are not met.</description>
                                    <value>#0</value>
                                </enumeratedValue>
                                <enumeratedValue>
                                    <name>1</name>
                                    <description>Comparison conditions are met.</description>
                                    <value>#1</value>
                                </enumeratedValue>
                            </enumeratedValues>
                        </field>
                    </fields>
                </register>
                <register>
                    <name>ADCMPBNSR</name>
                    <description>A/D Compare Function Window B Channel Select Register</description>
                    <addressOffset>0x0A6</addressOffset>
                    <size>8</size>
                    <access>read-write</access>
                    <resetValue>0x00</resetValue>
                    <resetMask>0xff</resetMask>
                    <fields>
                        <field>
                            <name>CMPCHB</name>
                            <description>Compare Window B Channel Select</description>
                            <lsb>0</lsb>
                            <msb>5</msb>
                            <access>read-write</access>
                        </field>
                        <field>
                            <name>CMPLB</name>
                            <description>Compare Window B Comparison Condition Setting</description>
                            <lsb>7</lsb>
                            <msb>7</msb>
                            <access>read-write</access>
                            <enumeratedValues>
                                <enumeratedValue>
                                    <name>0</name>
                                    <description>When window function is disabled (ADCMPCR.WCMPE = 0): ADWINLLB value &gt; A/D-converted value When window function is enabled (ADCMPCR.WCMPE = 1): A/D-converted value &lt; ADWINLLB value, or ADWINULB value &lt; A/D-converted value </description>
                                    <value>#0</value>
                                </enumeratedValue>
                                <enumeratedValue>
                                    <name>1</name>
                                    <description>When window function is disabled (ADCMPCR.WCMPE = 0): ADWINLLB value &lt; A/D-converted value When window function is enabled (ADCMPCR.WCMPE = 1): ADWINLLB value &lt; A/D-converted value &lt; ADWINULB value </description>
                                    <value>#1</value>
                                </enumeratedValue>
                            </enumeratedValues>
                        </field>
                    </fields>
                </register>
                <register>
                    <name>ADWINLLB</name>
                    <description>A/D Compare Function Window B Lower-Side/Upper-Side Level Setting Register</description>
                    <addressOffset>0x0A8</addressOffset>
                    <size>16</size>
                    <access>read-write</access>
                    <resetValue>0x0000</resetValue>
                    <resetMask>0xffff</resetMask>
                </register>
                <register>
                    <name>ADWINULB</name>
                    <description>A/D Compare Function Window B Lower-Side/Upper-Side Level Setting Register</description>
                    <addressOffset>0x0AA</addressOffset>
                    <size>16</size>
                    <access>read-write</access>
                    <resetValue>0x0000</resetValue>
                    <resetMask>0xffff</resetMask>
                </register>
                <register>
                    <name>ADCMPBSR</name>
                    <description>A/D Compare Function Window B Status Register</description>
                    <addressOffset>0x0AC</addressOffset>
                    <size>8</size>
                    <access>read-write</access>
                    <resetValue>0x00</resetValue>
                    <resetMask>0xff</resetMask>
                    <fields>
                        <field>
                            <name>CMPSTB</name>
                            <description>Compare Window B Flag</description>
                            <lsb>0</lsb>
                            <msb>0</msb>
                            <access>read-write</access>
                            <enumeratedValues>
                                <enumeratedValue>
                                    <name>0</name>
                                    <description>Comparison conditions are not met.</description>
                                    <value>#0</value>
                                </enumeratedValue>
                                <enumeratedValue>
                                    <name>1</name>
                                    <description>Comparison conditions are met.</description>
                                    <value>#1</value>
                                </enumeratedValue>
                            </enumeratedValues>
                        </field>
                    </fields>
                </register>
                <register>
                    <dim>16</dim>
                    <dimIncrement>0x2</dimIncrement>
                    <dimIndex>0-15</dimIndex>
                    <name>ADBUF%s</name>
                    <description>A/D Data Buffer Registers %s</description>
                    <addressOffset>0x0B0</addressOffset>
                    <size>16</size>
                    <access>read-only</access>
                    <resetValue>0x0000</resetValue>
                    <resetMask>0xffff</resetMask>
                    <fields>
                        <field>
                            <name>ADBUF</name>
                            <description>Converted Value 15 to 0</description>
                            <lsb>0</lsb>
                            <msb>15</msb>
                            <access>read-only</access>
                        </field>
                    </fields>
                </register>
                <register>
                    <name>ADBUFEN</name>
                    <description>A/D Data Buffer Enable Register</description>
                    <addressOffset>0x0D0</addressOffset>
                    <size>8</size>
                    <access>read-write</access>
                    <resetValue>0x00</resetValue>
                    <resetMask>0xff</resetMask>
                    <fields>
                        <field>
                            <name>BUFEN</name>
                            <description>Data Buffer Enable</description>
                            <lsb>0</lsb>
                            <msb>0</msb>
                            <access>read-write</access>
                            <enumeratedValues>
                                <enumeratedValue>
                                    <name>0</name>
                                    <description>The data buffer is not used.</description>
                                    <value>#0</value>
                                </enumeratedValue>
                                <enumeratedValue>
                                    <name>1</name>
                                    <description>The data buffer is used.</description>
                                    <value>#1</value>
                                </enumeratedValue>
                            </enumeratedValues>
                        </field>
                    </fields>
                </register>
                <register>
                    <name>ADBUFPTR</name>
                    <description>A/D Data Buffer Pointer Register</description>
                    <addressOffset>0x0D2</addressOffset>
                    <size>8</size>
                    <access>read-write</access>
                    <resetValue>0x00</resetValue>
                    <resetMask>0xff</resetMask>
                    <fields>
                        <field>
                            <name>BUFPTR</name>
                            <description>Data Buffer Pointer</description>
                            <lsb>0</lsb>
                            <msb>3</msb>
                            <access>read-write</access>
                        </field>
                        <field>
                            <name>PTROVF</name>
                            <description>Pointer Overflow Flag</description>
                            <lsb>4</lsb>
                            <msb>4</msb>
                            <access>read-write</access>
                            <enumeratedValues>
                                <enumeratedValue>
                                    <name>0</name>
                                    <description>The data buffer pointer has not overflowed.</description>
                                    <value>#0</value>
                                </enumeratedValue>
                                <enumeratedValue>
                                    <name>1</name>
                                    <description>The data buffer pointer has overflowed.</description>
                                    <value>#1</value>
                                </enumeratedValue>
                            </enumeratedValues>
                        </field>
                    </fields>
                </register>
                <register>
                    <name>ADSSTRL</name>
                    <description>A/D Sampling State Register</description>
                    <addressOffset>0x0DD</addressOffset>
                    <size>8</size>
                    <access>read-write</access>
                    <resetValue>0x0b</resetValue>
                    <resetMask>0xff</resetMask>
                    <fields>
                        <field>
                            <name>SST</name>
                            <description>Sampling Time Setting</description>
                            <lsb>0</lsb>
                            <msb>7</msb>
                            <access>read-write</access>
                        </field>
                    </fields>
                </register>
                <register>
                    <name>ADSSTRT</name>
                    <description>A/D Sampling State Register</description>
                    <addressOffset>0x0DE</addressOffset>
                    <size>8</size>
                    <access>read-write</access>
                    <resetValue>0x0b</resetValue>
                    <resetMask>0xff</resetMask>
                    <fields>
                        <field>
                            <name>SST</name>
                            <description>Sampling Time Setting</description>
                            <lsb>0</lsb>
                            <msb>7</msb>
                            <access>read-write</access>
                        </field>
                    </fields>
                </register>
                <register>
                    <name>ADSSTRO</name>
                    <description>A/D Sampling State Register</description>
                    <addressOffset>0x0DF</addressOffset>
                    <size>8</size>
                    <access>read-write</access>
                    <resetValue>0x0b</resetValue>
                    <resetMask>0xff</resetMask>
                    <fields>
                        <field>
                            <name>SST</name>
                            <description>Sampling Time Setting</description>
                            <lsb>0</lsb>
                            <msb>7</msb>
                            <access>read-write</access>
                        </field>
                    </fields>
                </register>
                <register>
                    <dim>9</dim>
                    <dimIncrement>0x1</dimIncrement>
                    <dimIndex>0-8</dimIndex>
                    <name>ADSSTR%s</name>
                    <description>A/D Sampling State Register</description>
                    <addressOffset>0x0E0</addressOffset>
                    <size>8</size>
                    <access>read-write</access>
                    <resetValue>0x0b</resetValue>
                    <resetMask>0xff</resetMask>
                    <fields>
                        <field>
                            <name>SST</name>
                            <description>Sampling Time Setting</description>
                            <lsb>0</lsb>
                            <msb>7</msb>
                            <access>read-write</access>
                        </field>
                    </fields>
                </register>
                <register>
                    <name>ADSSTRV</name>
                    <description>A/D Sampling State Register</description>
                    <addressOffset>0x0E3</addressOffset>
                    <size>8</size>
                    <access>read-write</access>
                    <resetValue>0x0b</resetValue>
                    <resetMask>0xff</resetMask>
                    <fields>
                        <field>
                            <name>SST</name>
                            <description>Sampling Time Setting</description>
                            <lsb>0</lsb>
                            <msb>7</msb>
                            <access>read-write</access>
                        </field>
                    </fields>
                </register>
                <register>
                    <dim>4</dim>
                    <dimIncrement>0x1</dimIncrement>
                    <dimIndex>16-19</dimIndex>
                    <name>ADSSTR%s</name>
                    <description>A/D Sampling State Register</description>
                    <addressOffset>0x0EC</addressOffset>
                    <size>8</size>
                    <access>read-write</access>
                    <resetValue>0x0b</resetValue>
                    <resetMask>0xff</resetMask>
                    <fields>
                        <field>
                            <name>SST</name>
                            <description>Sampling Time Setting</description>
                            <lsb>0</lsb>
                            <msb>7</msb>
                            <access>read-write</access>
                        </field>
                    </fields>
                </register>
            </registers>
        </peripheral>
        <peripheral>
            <name>ADC121</name>
            <description>12-bit A/D Converter 1</description>
            <baseAddress>0x40332200</baseAddress>
            <addressBlock>
                <offset>0x00</offset>
                <size>2</size>
                <usage>registers</usage>
            </addressBlock>
            <addressBlock>
                <offset>0x04</offset>
                <size>9</size>
                <usage>registers</usage>
            </addressBlock>
            <addressBlock>
                <offset>0x0E</offset>
                <size>32</size>
                <usage>registers</usage>
            </addressBlock>
            <addressBlock>
                <offset>0x66</offset>
                <size>2</size>
                <usage>registers</usage>
            </addressBlock>
            <addressBlock>
                <offset>0x7A</offset>
                <size>1</size>
                <usage>registers</usage>
            </addressBlock>
            <addressBlock>
                <offset>0x7C</offset>
                <size>1</size>
                <usage>registers</usage>
            </addressBlock>
            <addressBlock>
                <offset>0x80</offset>
                <size>2</size>
                <usage>registers</usage>
            </addressBlock>
            <addressBlock>
                <offset>0x84</offset>
                <size>4</size>
                <usage>registers</usage>
            </addressBlock>
            <addressBlock>
                <offset>0x8C</offset>
                <size>1</size>
                <usage>registers</usage>
            </addressBlock>
            <addressBlock>
                <offset>0x90</offset>
                <size>6</size>
                <usage>registers</usage>
            </addressBlock>
            <addressBlock>
                <offset>0x98</offset>
                <size>2</size>
                <usage>registers</usage>
            </addressBlock>
            <addressBlock>
                <offset>0x9C</offset>
                <size>6</size>
                <usage>registers</usage>
            </addressBlock>
            <addressBlock>
                <offset>0xA4</offset>
                <size>1</size>
                <usage>registers</usage>
            </addressBlock>
            <addressBlock>
                <offset>0xA6</offset>
                <size>1</size>
                <usage>registers</usage>
            </addressBlock>
            <addressBlock>
                <offset>0xA8</offset>
                <size>5</size>
                <usage>registers</usage>
            </addressBlock>
            <addressBlock>
                <offset>0xB0</offset>
                <size>33</size>
                <usage>registers</usage>
            </addressBlock>
            <addressBlock>
                <offset>0xD2</offset>
                <size>1</size>
                <usage>registers</usage>
            </addressBlock>
            <addressBlock>
                <offset>0xDD</offset>
                <size>10</size>
                <usage>registers</usage>
            </addressBlock>
            <registers>
                <register>
                    <name>ADCSR</name>
                    <description>A/D Control Register</description>
                    <addressOffset>0x000</addressOffset>
                    <size>16</size>
                    <access>read-write</access>
                    <resetValue>0x0000</resetValue>
                    <resetMask>0xffff</resetMask>
                    <fields>
                        <field>
                            <name>DBLANS</name>
                            <description>Double Trigger Channel Select</description>
                            <lsb>0</lsb>
                            <msb>4</msb>
                            <access>read-write</access>
                        </field>
                        <field>
                            <name>GBADIE</name>
                            <description>Group B Scan End Interrupt and ELC Event Enable</description>
                            <lsb>6</lsb>
                            <msb>6</msb>
                            <access>read-write</access>
                            <enumeratedValues>
                                <enumeratedValue>
                                    <name>0</name>
                                    <description>Disable ADC12i_GBADI (i = 0, 1) interrupt generation on group B scan completion.</description>
                                    <value>#0</value>
                                </enumeratedValue>
                                <enumeratedValue>
                                    <name>1</name>
                                    <description>Enable ADC12i_GBADI (i = 0, 1) interrupt generation on group B scan completion.</description>
                                    <value>#1</value>
                                </enumeratedValue>
                            </enumeratedValues>
                        </field>
                        <field>
                            <name>DBLE</name>
                            <description>Double Trigger Mode Select</description>
                            <lsb>7</lsb>
                            <msb>7</msb>
                            <access>read-write</access>
                            <enumeratedValues>
                                <enumeratedValue>
                                    <name>0</name>
                                    <description>Deselect double-trigger mode.</description>
                                    <value>#0</value>
                                </enumeratedValue>
                                <enumeratedValue>
                                    <name>1</name>
                                    <description>Select double-trigger mode.</description>
                                    <value>#1</value>
                                </enumeratedValue>
                            </enumeratedValues>
                        </field>
                        <field>
                            <name>EXTRG</name>
                            <description>Trigger Select</description>
                            <lsb>8</lsb>
                            <msb>8</msb>
                            <access>read-write</access>
                            <enumeratedValues>
                                <enumeratedValue>
                                    <name>0</name>
                                    <description>Start A/D conversion by the synchronous trigger (GPT, ELC).</description>
                                    <value>#0</value>
                                </enumeratedValue>
                                <enumeratedValue>
                                    <name>1</name>
                                    <description>Start A/D conversion by the asynchronous trigger (ADTRGn).</description>
                                    <value>#1</value>
                                </enumeratedValue>
                            </enumeratedValues>
                        </field>
                        <field>
                            <name>TRGE</name>
                            <description>Trigger Start Enable</description>
                            <lsb>9</lsb>
                            <msb>9</msb>
                            <access>read-write</access>
                            <enumeratedValues>
                                <enumeratedValue>
                                    <name>0</name>
                                    <description>Disable A/D conversion to be started by the synchronous or asynchronous trigger</description>
                                    <value>#0</value>
                                </enumeratedValue>
                                <enumeratedValue>
                                    <name>1</name>
                                    <description>Enable A/D conversion to be started by the synchronous or asynchronous trigger</description>
                                    <value>#1</value>
                                </enumeratedValue>
                            </enumeratedValues>
                        </field>
                        <field>
                            <name>ADCS</name>
                            <description>Scan Mode Select</description>
                            <lsb>13</lsb>
                            <msb>14</msb>
                            <access>read-write</access>
                            <enumeratedValues>
                                <enumeratedValue>
                                    <name>00</name>
                                    <description>Single scan mode</description>
                                    <value>#00</value>
                                </enumeratedValue>
                                <enumeratedValue>
                                    <name>01</name>
                                    <description>Group scan mode</description>
                                    <value>#01</value>
                                </enumeratedValue>
                                <enumeratedValue>
                                    <name>10</name>
                                    <description>Continuous scan mode</description>
                                    <value>#10</value>
                                </enumeratedValue>
                                <enumeratedValue>
                                    <name>11</name>
                                    <description>Setting prohibited</description>
                                    <value>#11</value>
                                </enumeratedValue>
                            </enumeratedValues>
                        </field>
                        <field>
                            <name>ADST</name>
                            <description>A/D Conversion Start</description>
                            <lsb>15</lsb>
                            <msb>15</msb>
                            <access>read-write</access>
                            <enumeratedValues>
                                <enumeratedValue>
                                    <name>0</name>
                                    <description>Stop A/D conversion process.</description>
                                    <value>#0</value>
                                </enumeratedValue>
                                <enumeratedValue>
                                    <name>1</name>
                                    <description>Start A/D conversion process.</description>
                                    <value>#1</value>
                                </enumeratedValue>
                            </enumeratedValues>
                        </field>
                    </fields>
                </register>
                <register>
                    <name>ADANSA0</name>
                    <description>A/D Channel Select Register A0</description>
                    <addressOffset>0x004</addressOffset>
                    <size>16</size>
                    <access>read-write</access>
                    <resetValue>0x0000</resetValue>
                    <resetMask>0xffff</resetMask>
                    <fields>
                        <field>
                            <name>ANSA00</name>
                            <description>A/D Conversion Channels Select</description>
                            <lsb>0</lsb>
                            <msb>0</msb>
                            <access>read-write</access>
                            <enumeratedValues>
                                <enumeratedValue>
                                    <name>0</name>
                                    <description>Do not select associated input channel.</description>
                                    <value>#0</value>
                                </enumeratedValue>
                                <enumeratedValue>
                                    <name>1</name>
                                    <description>Select associated input channel. </description>
                                    <value>#1</value>
                                </enumeratedValue>
                            </enumeratedValues>
                        </field>
                        <field>
                            <name>ANSA01</name>
                            <description>A/D Conversion Channels Select</description>
                            <lsb>1</lsb>
                            <msb>1</msb>
                            <access>read-write</access>
                            <enumeratedValues>
                                <enumeratedValue>
                                    <name>0</name>
                                    <description>Do not select associated input channel.</description>
                                    <value>#0</value>
                                </enumeratedValue>
                                <enumeratedValue>
                                    <name>1</name>
                                    <description>Select associated input channel. </description>
                                    <value>#1</value>
                                </enumeratedValue>
                            </enumeratedValues>
                        </field>
                        <field>
                            <name>ANSA02</name>
                            <description>A/D Conversion Channels Select</description>
                            <lsb>2</lsb>
                            <msb>2</msb>
                            <access>read-write</access>
                            <enumeratedValues>
                                <enumeratedValue>
                                    <name>0</name>
                                    <description>Do not select associated input channel.</description>
                                    <value>#0</value>
                                </enumeratedValue>
                                <enumeratedValue>
                                    <name>1</name>
                                    <description>Select associated input channel. </description>
                                    <value>#1</value>
                                </enumeratedValue>
                            </enumeratedValues>
                        </field>
                        <field>
                            <name>ANSA03</name>
                            <description>A/D Conversion Channels Select</description>
                            <lsb>3</lsb>
                            <msb>3</msb>
                            <access>read-write</access>
                            <enumeratedValues>
                                <enumeratedValue>
                                    <name>0</name>
                                    <description>Do not select associated input channel.</description>
                                    <value>#0</value>
                                </enumeratedValue>
                                <enumeratedValue>
                                    <name>1</name>
                                    <description>Select associated input channel. </description>
                                    <value>#1</value>
                                </enumeratedValue>
                            </enumeratedValues>
                        </field>
                        <field>
                            <name>ANSA04</name>
                            <description>A/D Conversion Channels Select</description>
                            <lsb>4</lsb>
                            <msb>4</msb>
                            <access>read-write</access>
                            <enumeratedValues>
                                <enumeratedValue>
                                    <name>0</name>
                                    <description>Do not select associated input channel.</description>
                                    <value>#0</value>
                                </enumeratedValue>
                                <enumeratedValue>
                                    <name>1</name>
                                    <description>Select associated input channel. </description>
                                    <value>#1</value>
                                </enumeratedValue>
                            </enumeratedValues>
                        </field>
                        <field>
                            <name>ANSA05</name>
                            <description>A/D Conversion Channels Select</description>
                            <lsb>5</lsb>
                            <msb>5</msb>
                            <access>read-write</access>
                            <enumeratedValues>
                                <enumeratedValue>
                                    <name>0</name>
                                    <description>Do not select associated input channel.</description>
                                    <value>#0</value>
                                </enumeratedValue>
                                <enumeratedValue>
                                    <name>1</name>
                                    <description>Select associated input channel. </description>
                                    <value>#1</value>
                                </enumeratedValue>
                            </enumeratedValues>
                        </field>
                        <field>
                            <name>ANSA06</name>
                            <description>A/D Conversion Channels Select</description>
                            <lsb>6</lsb>
                            <msb>6</msb>
                            <access>read-write</access>
                            <enumeratedValues>
                                <enumeratedValue>
                                    <name>0</name>
                                    <description>Do not select associated input channel.</description>
                                    <value>#0</value>
                                </enumeratedValue>
                                <enumeratedValue>
                                    <name>1</name>
                                    <description>Select associated input channel. </description>
                                    <value>#1</value>
                                </enumeratedValue>
                            </enumeratedValues>
                        </field>
                    </fields>
                </register>
                <register>
                    <name>ADANSA1</name>
                    <description>A/D Channel Select Register A1</description>
                    <addressOffset>0x006</addressOffset>
                    <size>16</size>
                    <access>read-write</access>
                    <resetValue>0x0000</resetValue>
                    <resetMask>0xffff</resetMask>
                    <fields>
                        <field>
                            <name>ANSA16</name>
                            <description>A/D Conversion Channels Select</description>
                            <lsb>0</lsb>
                            <msb>0</msb>
                            <access>read-write</access>
                            <enumeratedValues>
                                <enumeratedValue>
                                    <name>0</name>
                                    <description>Do not select associated input channel.</description>
                                    <value>#0</value>
                                </enumeratedValue>
                                <enumeratedValue>
                                    <name>1</name>
                                    <description>Select associated input channel. </description>
                                    <value>#1</value>
                                </enumeratedValue>
                            </enumeratedValues>
                        </field>
                        <field>
                            <name>ANSA17</name>
                            <description>A/D Conversion Channels Select</description>
                            <lsb>1</lsb>
                            <msb>1</msb>
                            <access>read-write</access>
                            <enumeratedValues>
                                <enumeratedValue>
                                    <name>0</name>
                                    <description>Do not select associated input channel.</description>
                                    <value>#0</value>
                                </enumeratedValue>
                                <enumeratedValue>
                                    <name>1</name>
                                    <description>Select associated input channel. </description>
                                    <value>#1</value>
                                </enumeratedValue>
                            </enumeratedValues>
                        </field>
                        <field>
                            <name>ANSA18</name>
                            <description>A/D Conversion Channels Select</description>
                            <lsb>2</lsb>
                            <msb>2</msb>
                            <access>read-write</access>
                            <enumeratedValues>
                                <enumeratedValue>
                                    <name>0</name>
                                    <description>Do not select associated input channel.</description>
                                    <value>#0</value>
                                </enumeratedValue>
                                <enumeratedValue>
                                    <name>1</name>
                                    <description>Select associated input channel. </description>
                                    <value>#1</value>
                                </enumeratedValue>
                            </enumeratedValues>
                        </field>
                        <field>
                            <name>ANSA19</name>
                            <description>A/D Conversion Channels Select</description>
                            <lsb>3</lsb>
                            <msb>3</msb>
                            <access>read-write</access>
                            <enumeratedValues>
                                <enumeratedValue>
                                    <name>0</name>
                                    <description>Do not select associated input channel.</description>
                                    <value>#0</value>
                                </enumeratedValue>
                                <enumeratedValue>
                                    <name>1</name>
                                    <description>Select associated input channel. </description>
                                    <value>#1</value>
                                </enumeratedValue>
                            </enumeratedValues>
                        </field>
                    </fields>
                </register>
                <register>
                    <name>ADADS0</name>
                    <description>A/D-Converted Value Addition/Average Channel Select Register 0</description>
                    <addressOffset>0x008</addressOffset>
                    <size>16</size>
                    <access>read-write</access>
                    <resetValue>0x0000</resetValue>
                    <resetMask>0xffff</resetMask>
                    <fields>
                        <field>
                            <name>ADS00</name>
                            <description>A/D-Converted Value Addition/Average Channel Select</description>
                            <lsb>0</lsb>
                            <msb>0</msb>
                            <access>read-write</access>
                            <enumeratedValues>
                                <enumeratedValue>
                                    <name>0</name>
                                    <description>Do not select associated input channel.</description>
                                    <value>#0</value>
                                </enumeratedValue>
                                <enumeratedValue>
                                    <name>1</name>
                                    <description>Select associated input channel. </description>
                                    <value>#1</value>
                                </enumeratedValue>
                            </enumeratedValues>
                        </field>
                        <field>
                            <name>ADS01</name>
                            <description>A/D-Converted Value Addition/Average Channel Select</description>
                            <lsb>1</lsb>
                            <msb>1</msb>
                            <access>read-write</access>
                            <enumeratedValues>
                                <enumeratedValue>
                                    <name>0</name>
                                    <description>Do not select associated input channel.</description>
                                    <value>#0</value>
                                </enumeratedValue>
                                <enumeratedValue>
                                    <name>1</name>
                                    <description>Select associated input channel. </description>
                                    <value>#1</value>
                                </enumeratedValue>
                            </enumeratedValues>
                        </field>
                        <field>
                            <name>ADS02</name>
                            <description>A/D-Converted Value Addition/Average Channel Select</description>
                            <lsb>2</lsb>
                            <msb>2</msb>
                            <access>read-write</access>
                            <enumeratedValues>
                                <enumeratedValue>
                                    <name>0</name>
                                    <description>Do not select associated input channel.</description>
                                    <value>#0</value>
                                </enumeratedValue>
                                <enumeratedValue>
                                    <name>1</name>
                                    <description>Select associated input channel. </description>
                                    <value>#1</value>
                                </enumeratedValue>
                            </enumeratedValues>
                        </field>
                        <field>
                            <name>ADS03</name>
                            <description>A/D-Converted Value Addition/Average Channel Select</description>
                            <lsb>3</lsb>
                            <msb>3</msb>
                            <access>read-write</access>
                            <enumeratedValues>
                                <enumeratedValue>
                                    <name>0</name>
                                    <description>Do not select associated input channel.</description>
                                    <value>#0</value>
                                </enumeratedValue>
                                <enumeratedValue>
                                    <name>1</name>
                                    <description>Select associated input channel. </description>
                                    <value>#1</value>
                                </enumeratedValue>
                            </enumeratedValues>
                        </field>
                        <field>
                            <name>ADS04</name>
                            <description>A/D-Converted Value Addition/Average Channel Select</description>
                            <lsb>4</lsb>
                            <msb>4</msb>
                            <access>read-write</access>
                            <enumeratedValues>
                                <enumeratedValue>
                                    <name>0</name>
                                    <description>Do not select associated input channel.</description>
                                    <value>#0</value>
                                </enumeratedValue>
                                <enumeratedValue>
                                    <name>1</name>
                                    <description>Select associated input channel. </description>
                                    <value>#1</value>
                                </enumeratedValue>
                            </enumeratedValues>
                        </field>
                        <field>
                            <name>ADS05</name>
                            <description>A/D-Converted Value Addition/Average Channel Select</description>
                            <lsb>5</lsb>
                            <msb>5</msb>
                            <access>read-write</access>
                            <enumeratedValues>
                                <enumeratedValue>
                                    <name>0</name>
                                    <description>Do not select associated input channel.</description>
                                    <value>#0</value>
                                </enumeratedValue>
                                <enumeratedValue>
                                    <name>1</name>
                                    <description>Select associated input channel. </description>
                                    <value>#1</value>
                                </enumeratedValue>
                            </enumeratedValues>
                        </field>
                        <field>
                            <name>ADS06</name>
                            <description>A/D-Converted Value Addition/Average Channel Select</description>
                            <lsb>6</lsb>
                            <msb>6</msb>
                            <access>read-write</access>
                            <enumeratedValues>
                                <enumeratedValue>
                                    <name>0</name>
                                    <description>Do not select associated input channel.</description>
                                    <value>#0</value>
                                </enumeratedValue>
                                <enumeratedValue>
                                    <name>1</name>
                                    <description>Select associated input channel. </description>
                                    <value>#1</value>
                                </enumeratedValue>
                            </enumeratedValues>
                        </field>
                    </fields>
                </register>
                <register>
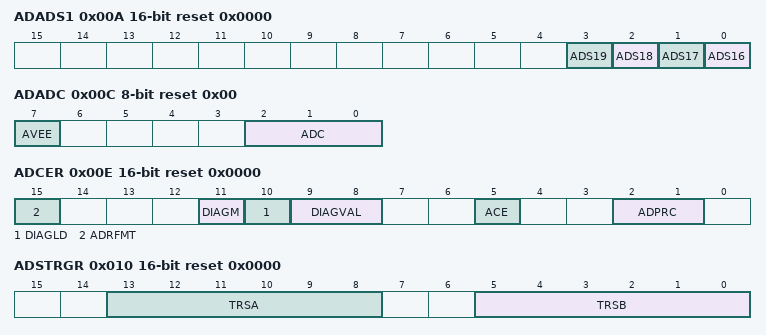
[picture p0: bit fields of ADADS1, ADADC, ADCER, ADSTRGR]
                    <name>ADADS1</name>
                    <description>A/D-Converted Value Addition/Average Channel Select Register 1</description>
                    <addressOffset>0x00A</addressOffset>
                    <size>16</size>
                    <access>read-write</access>
                    <resetValue>0x0000</resetValue>
                    <resetMask>0xffff</resetMask>
                    <fields>
                        <field>
                            <name>ADS16</name>
                            <description>A/D Conversion Channels Select/Average Channel Select</description>
                            <lsb>0</lsb>
                            <msb>0</msb>
                            <access>read-write</access>
                            <enumeratedValues>
                                <enumeratedValue>
                                    <name>0</name>
                                    <description>Do not select associated input channel.</description>
                                    <value>#0</value>
                                </enumeratedValue>
                                <enumeratedValue>
                                    <name>1</name>
                                    <description>Select associated input channel. </description>
                                    <value>#1</value>
                                </enumeratedValue>
                            </enumeratedValues>
                        </field>
                        <field>
                            <name>ADS17</name>
                            <description>A/D Conversion Channels Select/Average Channel Select</description>
                            <lsb>1</lsb>
                            <msb>1</msb>
                            <access>read-write</access>
                            <enumeratedValues>
                                <enumeratedValue>
                                    <name>0</name>
                                    <description>Do not select associated input channel.</description>
                                    <value>#0</value>
                                </enumeratedValue>
                                <enumeratedValue>
                                    <name>1</name>
                                    <description>Select associated input channel. </description>
                                    <value>#1</value>
                                </enumeratedValue>
                            </enumeratedValues>
                        </field>
                        <field>
                            <name>ADS18</name>
                            <description>A/D Conversion Channels Select/Average Channel Select</description>
                            <lsb>2</lsb>
                            <msb>2</msb>
                            <access>read-write</access>
                            <enumeratedValues>
                                <enumeratedValue>
                                    <name>0</name>
                                    <description>Do not select associated input channel.</description>
                                    <value>#0</value>
                                </enumeratedValue>
                                <enumeratedValue>
                                    <name>1</name>
                                    <description>Select associated input channel. </description>
                                    <value>#1</value>
                                </enumeratedValue>
                            </enumeratedValues>
                        </field>
                        <field>
                            <name>ADS19</name>
                            <description>A/D Conversion Channels Select/Average Channel Select</description>
                            <lsb>3</lsb>
                            <msb>3</msb>
                            <access>read-write</access>
                            <enumeratedValues>
                                <enumeratedValue>
                                    <name>0</name>
                                    <description>Do not select associated input channel.</description>
                                    <value>#0</value>
                                </enumeratedValue>
                                <enumeratedValue>
                                    <name>1</name>
                                    <description>Select associated input channel. </description>
                                    <value>#1</value>
                                </enumeratedValue>
                            </enumeratedValues>
                        </field>
                    </fields>
                </register>
                <register>
                    <name>ADADC</name>
                    <description>A/D-Converted Value Addition/Average Count Select Register</description>
                    <addressOffset>0x00C</addressOffset>
                    <size>8</size>
                    <access>read-write</access>
                    <resetValue>0x00</resetValue>
                    <resetMask>0xff</resetMask>
                    <fields>
                        <field>
                            <name>ADC</name>
                            <description>Addition/Average Count Select</description>
                            <lsb>0</lsb>
                            <msb>2</msb>
                            <access>read-write</access>
                            <enumeratedValues>
                                <enumeratedValue>
                                    <name>000</name>
                                    <description>1-time conversion (no addition, same as normal conversion)</description>
                                    <value>#000</value>
                                </enumeratedValue>
                                <enumeratedValue>
                                    <name>001</name>
                                    <description>2-time conversion (1 addition)</description>
                                    <value>#001</value>
                                </enumeratedValue>
                                <enumeratedValue>
                                    <name>010</name>
                                    <description>3-time conversion (2 additions)</description>
                                    <value>#010</value>
                                </enumeratedValue>
                                <enumeratedValue>
                                    <name>011</name>
                                    <description>4-time conversion (3 additions)</description>
                                    <value>#011</value>
                                </enumeratedValue>
                                <enumeratedValue>
                                    <name>101</name>
                                    <description>16-time conversion (15 additions)</description>
                                    <value>#101</value>
                                </enumeratedValue>
                                <enumeratedValue>
                                    <name>Others</name>
                                    <description>Setting prohibited</description>
                                    <isDefault>true</isDefault>
                                </enumeratedValue>
                            </enumeratedValues>
                        </field>
                        <field>
                            <name>AVEE</name>
                            <description>Average Mode Select</description>
                            <lsb>7</lsb>
                            <msb>7</msb>
                            <access>read-write</access>
                            <enumeratedValues>
                                <enumeratedValue>
                                    <name>0</name>
                                    <description>Enable addition mode</description>
                                    <value>#0</value>
                                </enumeratedValue>
                                <enumeratedValue>
                                    <name>1</name>
                                    <description>Enable average mode</description>
                                    <value>#1</value>
                                </enumeratedValue>
                            </enumeratedValues>
                        </field>
                    </fields>
                </register>
                <register>
                    <name>ADCER</name>
                    <description>A/D Control Extended Register</description>
                    <addressOffset>0x00E</addressOffset>
                    <size>16</size>
                    <access>read-write</access>
                    <resetValue>0x0000</resetValue>
                    <resetMask>0xffff</resetMask>
                    <fields>
                        <field>
                            <name>ADPRC</name>
                            <lsb>1</lsb>
                            <msb>2</msb>
                            <access>read-write</access>
                            <enumeratedValues>
                                <enumeratedValue>
                                    <name>00</name>
                                    <description>12-bit accuracy</description>
                                    <value>#00</value>
                                </enumeratedValue>
                                <enumeratedValue>
                                    <name>01</name>
                                    <description>10-bit accuracy</description>
                                    <value>#01</value>
                                </enumeratedValue>
                                <enumeratedValue>
                                    <name>10</name>
                                    <description>8-bit accuracy</description>
                                    <value>#10</value>
                                </enumeratedValue>
                                <enumeratedValue>
                                    <name>11</name>
                                    <description>Setting prohibited</description>
                                    <value>#11</value>
                                </enumeratedValue>
                            </enumeratedValues>
                        </field>
                        <field>
                            <name>ACE</name>
                            <description>A/D Data Register Automatic Clearing Enable</description>
                            <lsb>5</lsb>
                            <msb>5</msb>
                            <access>read-write</access>
                            <enumeratedValues>
                                <enumeratedValue>
                                    <name>0</name>
                                    <description>Disable automatic clearing</description>
                                    <value>#0</value>
                                </enumeratedValue>
                                <enumeratedValue>
                                    <name>1</name>
                                    <description>Enable automatic clearing</description>
                                    <value>#1</value>
                                </enumeratedValue>
                            </enumeratedValues>
                        </field>
                        <field>
                            <name>DIAGVAL</name>
                            <description>Self-Diagnosis Conversion Voltage Select</description>
                            <lsb>8</lsb>
                            <msb>9</msb>
                            <access>read-write</access>
                            <enumeratedValues>
                                <enumeratedValue>
                                    <name>00</name>
                                    <description>Setting prohibited when self-diagnosis is enabled</description>
                                    <value>#00</value>
                                </enumeratedValue>
                                <enumeratedValue>
                                    <name>01</name>
                                    <description>0 volts</description>
                                    <value>#01</value>
                                </enumeratedValue>
                                <enumeratedValue>
                                    <name>10</name>
                                    <description>Reference voltage × 1/2</description>
                                    <value>#10</value>
                                </enumeratedValue>
                                <enumeratedValue>
                                    <name>11</name>
                                    <description>Reference voltage</description>
                                    <value>#11</value>
                                </enumeratedValue>
                            </enumeratedValues>
                        </field>
                        <field>
                            <name>DIAGLD</name>
                            <description>Self-Diagnosis Mode Select</description>
                            <lsb>10</lsb>
                            <msb>10</msb>
                            <access>read-write</access>
                            <enumeratedValues>
                                <enumeratedValue>
                                    <name>0</name>
                                    <description>Select rotation mode for self-diagnosis voltage</description>
                                    <value>#0</value>
                                </enumeratedValue>
                                <enumeratedValue>
                                    <name>1</name>
                                    <description>Select mixed mode for self-diagnosis voltage</description>
                                    <value>#1</value>
                                </enumeratedValue>
                            </enumeratedValues>
                        </field>
                        <field>
                            <name>DIAGM</name>
                            <description>Self-Diagnosis Enable</description>
                            <lsb>11</lsb>
                            <msb>11</msb>
                            <access>read-write</access>
                            <enumeratedValues>
                                <enumeratedValue>
                                    <name>0</name>
                                    <description>Disable ADC12 self-diagnosis</description>
                                    <value>#0</value>
                                </enumeratedValue>
                                <enumeratedValue>
                                    <name>1</name>
                                    <description>Enable ADC12 self-diagnosis</description>
                                    <value>#1</value>
                                </enumeratedValue>
                            </enumeratedValues>
                        </field>
                        <field>
                            <name>ADRFMT</name>
                            <description>A/D Data Register Format Select</description>
                            <lsb>15</lsb>
                            <msb>15</msb>
                            <access>read-write</access>
                            <enumeratedValues>
                                <enumeratedValue>
                                    <name>0</name>
                                    <description>Select right-justified for the A/D data register format</description>
                                    <value>#0</value>
                                </enumeratedValue>
                                <enumeratedValue>
                                    <name>1</name>
                                    <description>Select left-justified for the A/D data register format</description>
                                    <value>#1</value>
                                </enumeratedValue>
                            </enumeratedValues>
                        </field>
                    </fields>
                </register>
                <register>
                    <name>ADSTRGR</name>
                    <description>A/D Conversion Start Trigger Select Register</description>
                    <addressOffset>0x010</addressOffset>
                    <size>16</size>
                    <access>read-write</access>
                    <resetValue>0x0000</resetValue>
                    <resetMask>0xffff</resetMask>
                    <fields>
                        <field>
                            <name>TRSB</name>
                            <description>A/D Conversion Start Trigger Select for Group B</description>
                            <lsb>0</lsb>
                            <msb>5</msb>
                            <access>read-write</access>
                        </field>
                        <field>
                            <name>TRSA</name>
                            <description>A/D Conversion Start Trigger Select</description>
                            <lsb>8</lsb>
                            <msb>13</msb>
                            <access>read-write</access>
                        </field>
                    </fields>
                </register>
                <register>
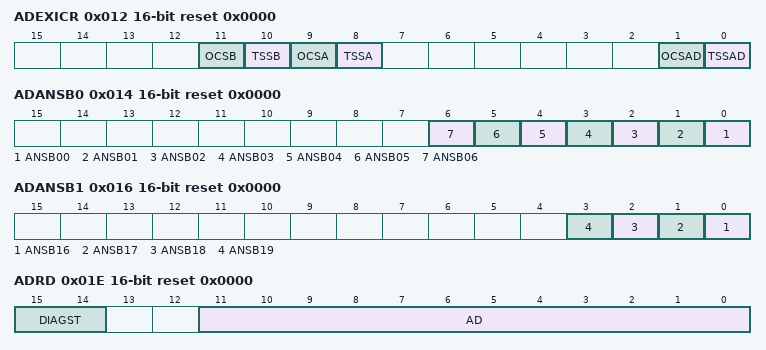
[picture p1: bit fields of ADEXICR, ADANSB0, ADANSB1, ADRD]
                    <name>ADEXICR</name>
                    <description>A/D Conversion Extended Input Control Registers</description>
                    <addressOffset>0x012</addressOffset>
                    <size>16</size>
                    <access>read-write</access>
                    <resetValue>0x0000</resetValue>
                    <resetMask>0xffff</resetMask>
                    <fields>
                        <field>
                            <name>TSSAD</name>
                            <description>Temperature Sensor Output A/D-Converted Value Addition/Average Mode Select</description>
                            <lsb>0</lsb>
                            <msb>0</msb>
                            <access>read-write</access>
                            <enumeratedValues>
                                <enumeratedValue>
                                    <name>0</name>
                                    <description>Do not select addition/average mode for temperature sensor output.</description>
                                    <value>#0</value>
                                </enumeratedValue>
                                <enumeratedValue>
                                    <name>1</name>
                                    <description>Select addition/average mode for temperature sensor output.</description>
                                    <value>#1</value>
                                </enumeratedValue>
                            </enumeratedValues>
                        </field>
                        <field>
                            <name>OCSAD</name>
                            <description>Internal Reference Voltage A/D-Converted Value Addition/Average Mode Select</description>
                            <lsb>1</lsb>
                            <msb>1</msb>
                            <access>read-write</access>
                            <enumeratedValues>
                                <enumeratedValue>
                                    <name>0</name>
                                    <description>Do not select addition/average mode for internal reference voltage.</description>
                                    <value>#0</value>
                                </enumeratedValue>
                                <enumeratedValue>
                                    <name>1</name>
                                    <description>Select addition/average mode for internal reference voltage.</description>
                                    <value>#1</value>
                                </enumeratedValue>
                            </enumeratedValues>
                        </field>
                        <field>
                            <name>TSSA</name>
                            <description>Temperature Sensor Output A/D Conversion Select</description>
                            <lsb>8</lsb>
                            <msb>8</msb>
                            <access>read-write</access>
                            <enumeratedValues>
                                <enumeratedValue>
                                    <name>0</name>
                                    <description>Disable A/D conversion of temperature sensor output</description>
                                    <value>#0</value>
                                </enumeratedValue>
                                <enumeratedValue>
                                    <name>1</name>
                                    <description>Enable A/D conversion of temperature sensor output</description>
                                    <value>#1</value>
                                </enumeratedValue>
                            </enumeratedValues>
                        </field>
                        <field>
                            <name>OCSA</name>
                            <description>Internal Reference Voltage A/D Conversion Select</description>
                            <lsb>9</lsb>
                            <msb>9</msb>
                            <access>read-write</access>
                            <enumeratedValues>
                                <enumeratedValue>
                                    <name>0</name>
                                    <description>Disable A/D conversion of internal reference voltage</description>
                                    <value>#0</value>
                                </enumeratedValue>
                                <enumeratedValue>
                                    <name>1</name>
                                    <description>Enable A/D conversion of internal reference voltage</description>
                                    <value>#1</value>
                                </enumeratedValue>
                            </enumeratedValues>
                        </field>
                        <field>
                            <name>TSSB</name>
                            <description>Temperature Sensor Output A/D Conversion Select for Group B</description>
                            <lsb>10</lsb>
                            <msb>10</msb>
                            <access>read-write</access>
                            <enumeratedValues>
                                <enumeratedValue>
                                    <name>0</name>
                                    <description>Disable A/D conversion of temperature sensor output</description>
                                    <value>#0</value>
                                </enumeratedValue>
                                <enumeratedValue>
                                    <name>1</name>
                                    <description>Enable A/D conversion of temperature sensor output</description>
                                    <value>#1</value>
                                </enumeratedValue>
                            </enumeratedValues>
                        </field>
                        <field>
                            <name>OCSB</name>
                            <description>Internal Reference Voltage A/D Conversion Select for Group B</description>
                            <lsb>11</lsb>
                            <msb>11</msb>
                            <access>read-write</access>
                            <enumeratedValues>
                                <enumeratedValue>
                                    <name>0</name>
                                    <description>Disable A/D conversion of internal reference voltage</description>
                                    <value>#0</value>
                                </enumeratedValue>
                                <enumeratedValue>
                                    <name>1</name>
                                    <description>Enable A/D conversion of internal reference voltage</description>
                                    <value>#1</value>
                                </enumeratedValue>
                            </enumeratedValues>
                        </field>
                    </fields>
                </register>
                <register>
                    <name>ADANSB0</name>
                    <description>A/D Channel Select Register B0</description>
                    <addressOffset>0x014</addressOffset>
                    <size>16</size>
                    <access>read-write</access>
                    <resetValue>0x0000</resetValue>
                    <resetMask>0xffff</resetMask>
                    <fields>
                        <field>
                            <name>ANSB00</name>
                            <description>A/D Conversion Channels Select</description>
                            <lsb>0</lsb>
                            <msb>0</msb>
                            <access>read-write</access>
                            <enumeratedValues>
                                <enumeratedValue>
                                    <name>0</name>
                                    <description>Do not select associated input channel.</description>
                                    <value>#0</value>
                                </enumeratedValue>
                                <enumeratedValue>
                                    <name>1</name>
                                    <description>Select associated input channel. </description>
                                    <value>#1</value>
                                </enumeratedValue>
                            </enumeratedValues>
                        </field>
                        <field>
                            <name>ANSB01</name>
                            <description>A/D Conversion Channels Select</description>
                            <lsb>1</lsb>
                            <msb>1</msb>
                            <access>read-write</access>
                            <enumeratedValues>
                                <enumeratedValue>
                                    <name>0</name>
                                    <description>Do not select associated input channel.</description>
                                    <value>#0</value>
                                </enumeratedValue>
                                <enumeratedValue>
                                    <name>1</name>
                                    <description>Select associated input channel. </description>
                                    <value>#1</value>
                                </enumeratedValue>
                            </enumeratedValues>
                        </field>
                        <field>
                            <name>ANSB02</name>
                            <description>A/D Conversion Channels Select</description>
                            <lsb>2</lsb>
                            <msb>2</msb>
                            <access>read-write</access>
                            <enumeratedValues>
                                <enumeratedValue>
                                    <name>0</name>
                                    <description>Do not select associated input channel.</description>
                                    <value>#0</value>
                                </enumeratedValue>
                                <enumeratedValue>
                                    <name>1</name>
                                    <description>Select associated input channel. </description>
                                    <value>#1</value>
                                </enumeratedValue>
                            </enumeratedValues>
                        </field>
                        <field>
                            <name>ANSB03</name>
                            <description>A/D Conversion Channels Select</description>
                            <lsb>3</lsb>
                            <msb>3</msb>
                            <access>read-write</access>
                            <enumeratedValues>
                                <enumeratedValue>
                                    <name>0</name>
                                    <description>Do not select associated input channel.</description>
                                    <value>#0</value>
                                </enumeratedValue>
                                <enumeratedValue>
                                    <name>1</name>
                                    <description>Select associated input channel. </description>
                                    <value>#1</value>
                                </enumeratedValue>
                            </enumeratedValues>
                        </field>
                        <field>
                            <name>ANSB04</name>
                            <description>A/D Conversion Channels Select</description>
                            <lsb>4</lsb>
                            <msb>4</msb>
                            <access>read-write</access>
                            <enumeratedValues>
                                <enumeratedValue>
                                    <name>0</name>
                                    <description>Do not select associated input channel.</description>
                                    <value>#0</value>
                                </enumeratedValue>
                                <enumeratedValue>
                                    <name>1</name>
                                    <description>Select associated input channel. </description>
                                    <value>#1</value>
                                </enumeratedValue>
                            </enumeratedValues>
                        </field>
                        <field>
                            <name>ANSB05</name>
                            <description>A/D Conversion Channels Select</description>
                            <lsb>5</lsb>
                            <msb>5</msb>
                            <access>read-write</access>
                            <enumeratedValues>
                                <enumeratedValue>
                                    <name>0</name>
                                    <description>Do not select associated input channel.</description>
                                    <value>#0</value>
                                </enumeratedValue>
                                <enumeratedValue>
                                    <name>1</name>
                                    <description>Select associated input channel. </description>
                                    <value>#1</value>
                                </enumeratedValue>
                            </enumeratedValues>
                        </field>
                        <field>
                            <name>ANSB06</name>
                            <description>A/D Conversion Channels Select</description>
                            <lsb>6</lsb>
                            <msb>6</msb>
                            <access>read-write</access>
                            <enumeratedValues>
                                <enumeratedValue>
                                    <name>0</name>
                                    <description>Do not select associated input channel.</description>
                                    <value>#0</value>
                                </enumeratedValue>
                                <enumeratedValue>
                                    <name>1</name>
                                    <description>Select associated input channel. </description>
                                    <value>#1</value>
                                </enumeratedValue>
                            </enumeratedValues>
                        </field>
                    </fields>
                </register>
                <register>
                    <name>ADANSB1</name>
                    <description>A/D Channel Select Register B1</description>
                    <addressOffset>0x016</addressOffset>
                    <size>16</size>
                    <access>read-write</access>
                    <resetValue>0x0000</resetValue>
                    <resetMask>0xffff</resetMask>
                    <fields>
                        <field>
                            <name>ANSB16</name>
                            <description>A/D Conversion Channels Select</description>
                            <lsb>0</lsb>
                            <msb>0</msb>
                            <access>read-write</access>
                            <enumeratedValues>
                                <enumeratedValue>
                                    <name>0</name>
                                    <description>Do not select associated input channel.</description>
                                    <value>#0</value>
                                </enumeratedValue>
                                <enumeratedValue>
                                    <name>1</name>
                                    <description>Select associated input channel. </description>
                                    <value>#1</value>
                                </enumeratedValue>
                            </enumeratedValues>
                        </field>
                        <field>
                            <name>ANSB17</name>
                            <description>A/D Conversion Channels Select</description>
                            <lsb>1</lsb>
                            <msb>1</msb>
                            <access>read-write</access>
                            <enumeratedValues>
                                <enumeratedValue>
                                    <name>0</name>
                                    <description>Do not select associated input channel.</description>
                                    <value>#0</value>
                                </enumeratedValue>
                                <enumeratedValue>
                                    <name>1</name>
                                    <description>Select associated input channel. </description>
                                    <value>#1</value>
                                </enumeratedValue>
                            </enumeratedValues>
                        </field>
                        <field>
                            <name>ANSB18</name>
                            <description>A/D Conversion Channels Select</description>
                            <lsb>2</lsb>
                            <msb>2</msb>
                            <access>read-write</access>
                            <enumeratedValues>
                                <enumeratedValue>
                                    <name>0</name>
                                    <description>Do not select associated input channel.</description>
                                    <value>#0</value>
                                </enumeratedValue>
                                <enumeratedValue>
                                    <name>1</name>
                                    <description>Select associated input channel. </description>
                                    <value>#1</value>
                                </enumeratedValue>
                            </enumeratedValues>
                        </field>
                        <field>
                            <name>ANSB19</name>
                            <description>A/D Conversion Channels Select</description>
                            <lsb>3</lsb>
                            <msb>3</msb>
                            <access>read-write</access>
                            <enumeratedValues>
                                <enumeratedValue>
                                    <name>0</name>
                                    <description>Do not select associated input channel.</description>
                                    <value>#0</value>
                                </enumeratedValue>
                                <enumeratedValue>
                                    <name>1</name>
                                    <description>Select associated input channel. </description>
                                    <value>#1</value>
                                </enumeratedValue>
                            </enumeratedValues>
                        </field>
                    </fields>
                </register>
                <register>
                    <name>ADDBLDR</name>
                    <description>A/D Data Duplexing Register</description>
                    <addressOffset>0x018</addressOffset>
                    <size>16</size>
                    <access>read-only</access>
                    <resetValue>0x0000</resetValue>
                    <resetMask>0xffff</resetMask>
                    <fields>
                        <field>
                            <name>ADDBLDR</name>
                            <description>Converted Value 15 to 0</description>
                            <lsb>0</lsb>
                            <msb>15</msb>
                            <access>read-only</access>
                        </field>
                    </fields>
                </register>
                <register>
                    <name>ADTSDR</name>
                    <description>A/D Temperature Sensor Data Register</description>
                    <addressOffset>0x01A</addressOffset>
                    <size>16</size>
                    <access>read-only</access>
                    <resetValue>0x0000</resetValue>
                    <resetMask>0xffff</resetMask>
                    <fields>
                        <field>
                            <name>ADTSDR</name>
                            <description>Converted Value 15 to 0</description>
                            <lsb>0</lsb>
                            <msb>15</msb>
                            <access>read-only</access>
                        </field>
                    </fields>
                </register>
                <register>
                    <name>ADOCDR</name>
                    <description>A/D Internal Reference Voltage Data Register</description>
                    <addressOffset>0x01C</addressOffset>
                    <size>16</size>
                    <access>read-only</access>
                    <resetValue>0x0000</resetValue>
                    <resetMask>0xffff</resetMask>
                    <fields>
                        <field>
                            <name>ADOCDR</name>
                            <description>Converted Value 15 to 0</description>
                            <lsb>0</lsb>
                            <msb>15</msb>
                            <access>read-only</access>
                        </field>
                    </fields>
                </register>
                <register>
                    <name>ADRD</name>
                    <description>A/D Self-Diagnosis Data Register</description>
                    <addressOffset>0x01E</addressOffset>
                    <size>16</size>
                    <access>read-only</access>
                    <resetValue>0x0000</resetValue>
                    <resetMask>0xffff</resetMask>
                    <fields>
                        <field>
                            <name>AD</name>
                            <description>Converted Value 11 to 0</description>
                            <lsb>0</lsb>
                            <msb>11</msb>
                            <access>read-only</access>
                        </field>
                        <field>
                            <name>DIAGST</name>
                            <description>Self-Diagnosis Status</description>
                            <lsb>14</lsb>
                            <msb>15</msb>
                            <access>read-only</access>
                            <enumeratedValues>
                                <enumeratedValue>
                                    <name>00</name>
                                    <description>Self-diagnosis not executed after power-on.</description>
                                    <value>#00</value>
                                </enumeratedValue>
                                <enumeratedValue>
                                    <name>01</name>
                                    <description>Self-diagnosis was executed using the 0 V voltage.</description>
                                    <value>#01</value>
                                </enumeratedValue>
                                <enumeratedValue>
                                    <name>10</name>
                                    <description>Self-diagnosis was executed using the reference voltage × 1/2.</description>
                                    <value>#10</value>
                                </enumeratedValue>
                                <enumeratedValue>
                                    <name>11</name>
                                    <description>Self-diagnosis was executed using the reference voltage .</description>
                                    <value>#11</value>
                                </enumeratedValue>
                            </enumeratedValues>
                        </field>
                    </fields>
                </register>
                <register>
                    <dim>7</dim>
                    <dimIncrement>0x2</dimIncrement>
                    <dimIndex>0-6</dimIndex>
                    <name>ADDR%s</name>
                    <description>A/D Data Registers %s</description>
                    <addressOffset>0x020</addressOffset>
                    <size>16</size>
                    <access>read-only</access>
                    <resetValue>0x0000</resetValue>
                    <resetMask>0xffff</resetMask>
                    <fields>
                        <field>
                            <name>ADDR</name>
                            <description>Converted Value 15 to 0</description>
                            <lsb>0</lsb>
                            <msb>15</msb>
                            <access>read-only</access>
                        </field>
                    </fields>
                </register>
                <register>
                    <dim>7</dim>
                    <dimIncrement>0x2</dimIncrement>
                    <dimIndex>16-22</dimIndex>
                    <name>ADDR%s</name>
                    <description>A/D Data Registers %s</description>
                    <addressOffset>0x020</addressOffset>
                    <size>16</size>
                    <access>read-only</access>
                    <resetValue>0x0000</resetValue>
                    <resetMask>0xffff</resetMask>
                    <fields>
                        <field>
                            <name>ADDR</name>
                            <description>Converted Value 15 to 0</description>
                            <lsb>0</lsb>
                            <msb>15</msb>
                            <access>read-only</access>
                        </field>
                    </fields>
                </register>
                <register>
                    <name>ADVMDR</name>
                    <description>A/D VBATT Monitor Data Register</description>
                    <addressOffset>0x026</addressOffset>
                    <size>16</size>
                    <access>read-only</access>
                    <resetValue>0x0000</resetValue>
                    <resetMask>0xffff</resetMask>
                    <fields>
                        <field>
                            <name>ADDR</name>
                            <description>Converted Value 15 to 0</description>
                            <lsb>0</lsb>
                            <msb>15</msb>
                            <access>read-only</access>
                        </field>
                    </fields>
                </register>
                <register>
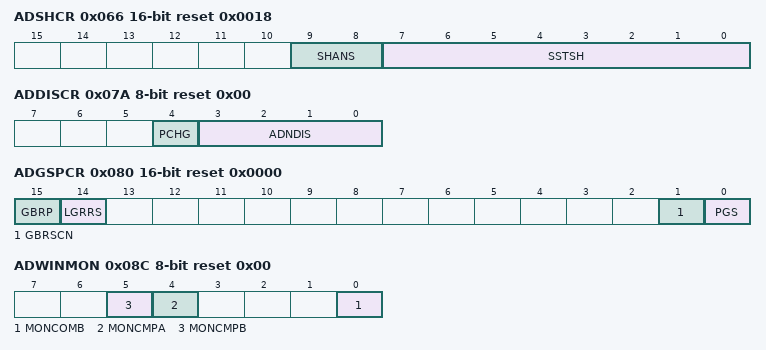
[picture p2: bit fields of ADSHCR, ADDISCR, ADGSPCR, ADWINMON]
                    <name>ADSHCR</name>
                    <description>A/D Sample and Hold Circuit Control Register</description>
                    <addressOffset>0x066</addressOffset>
                    <size>16</size>
                    <access>read-write</access>
                    <resetValue>0x0018</resetValue>
                    <resetMask>0xffff</resetMask>
                    <fields>
                        <field>
                            <name>SSTSH</name>
                            <description>Channel-Dedicated Sample-and-Hold Circuit Sampling Time Setting</description>
                            <lsb>0</lsb>
                            <msb>7</msb>
                            <access>read-write</access>
                        </field>
                        <field>
                            <name>SHANS</name>
                            <description>Channel-Dedicated Sample-and-Hold Circuit Bypass Select</description>
                            <lsb>8</lsb>
                            <msb>9</msb>
                            <access>read-write</access>
                            <enumeratedValues>
                                <enumeratedValue>
                                    <name>0</name>
                                    <description>Bypass the circuits</description>
                                    <value>#0</value>
                                </enumeratedValue>
                                <enumeratedValue>
                                    <name>1</name>
                                    <description>Use the circuits</description>
                                    <value>#1</value>
                                </enumeratedValue>
                            </enumeratedValues>
                        </field>
                    </fields>
                </register>
                <register>
                    <name>ADDISCR</name>
                    <description>A/D Disconnection Detection Control Register</description>
                    <addressOffset>0x07A</addressOffset>
                    <size>8</size>
                    <access>read-write</access>
                    <resetValue>0x00</resetValue>
                    <resetMask>0xff</resetMask>
                    <fields>
                        <field>
                            <name>ADNDIS</name>
                            <description>Disconnection Detection Assist Setting</description>
                            <lsb>0</lsb>
                            <msb>3</msb>
                            <access>read-write</access>
                            <enumeratedValues>
                                <enumeratedValue>
                                    <name>0x0</name>
                                    <description>The disconnection detection assist function is disabled</description>
                                    <value>0x0</value>
                                </enumeratedValue>
                                <enumeratedValue>
                                    <name>0x1</name>
                                    <description>Setting prohibited</description>
                                    <value>0x1</value>
                                </enumeratedValue>
                                <enumeratedValue>
                                    <name>Others</name>
                                    <description>The number of states for the discharge or precharge period.</description>
                                    <isDefault>true</isDefault>
                                </enumeratedValue>
                            </enumeratedValues>
                        </field>
                        <field>
                            <name>PCHG</name>
                            <description>Precharge/discharge select</description>
                            <lsb>4</lsb>
                            <msb>4</msb>
                            <access>read-write</access>
                            <enumeratedValues>
                                <enumeratedValue>
                                    <name>0</name>
                                    <description>Discharge</description>
                                    <value>#0</value>
                                </enumeratedValue>
                                <enumeratedValue>
                                    <name>1</name>
                                    <description>Precharge</description>
                                    <value>#1</value>
                                </enumeratedValue>
                            </enumeratedValues>
                        </field>
                    </fields>
                </register>
                <register>
                    <name>ADSHMSR</name>
                    <description>A/D Sample and Hold Operation Mode Selection Register</description>
                    <addressOffset>0x07C</addressOffset>
                    <size>8</size>
                    <access>read-write</access>
                    <resetValue>0x00</resetValue>
                    <resetMask>0xff</resetMask>
                    <fields>
                        <field>
                            <name>SHMD</name>
                            <description>Sampling Operation Selection</description>
                            <lsb>0</lsb>
                            <msb>0</msb>
                            <access>read-write</access>
                            <enumeratedValues>
                                <enumeratedValue>
                                    <name>0</name>
                                    <description>Sampling Operation Selection</description>
                                    <value>#0</value>
                                </enumeratedValue>
                                <enumeratedValue>
                                    <name>1</name>
                                    <description>Enable continuous sampling function</description>
                                    <value>#1</value>
                                </enumeratedValue>
                            </enumeratedValues>
                        </field>
                    </fields>
                </register>
                <register>
                    <name>ADGSPCR</name>
                    <description>A/D Group Scan Priority Control Register</description>
                    <addressOffset>0x080</addressOffset>
                    <size>16</size>
                    <access>read-write</access>
                    <resetValue>0x0000</resetValue>
                    <resetMask>0xffff</resetMask>
                    <fields>
                        <field>
                            <name>PGS</name>
                            <description>Group Priority Operation Setting</description>
                            <lsb>0</lsb>
                            <msb>0</msb>
                            <access>read-write</access>
                            <enumeratedValues>
                                <enumeratedValue>
                                    <name>0</name>
                                    <description>Operate without group priority control.</description>
                                    <value>#0</value>
                                </enumeratedValue>
                                <enumeratedValue>
                                    <name>1</name>
                                    <description>Operate with group priority control.</description>
                                    <value>#1</value>
                                </enumeratedValue>
                            </enumeratedValues>
                        </field>
                        <field>
                            <name>GBRSCN</name>
                            <description>Lower-Priority Group Restart Setting</description>
                            <lsb>1</lsb>
                            <msb>1</msb>
                            <access>read-write</access>
                            <enumeratedValues>
                                <enumeratedValue>
                                    <name>0</name>
                                    <description>Disable rescanning of the group that was stopped in group priority operation</description>
                                    <value>#0</value>
                                </enumeratedValue>
                                <enumeratedValue>
                                    <name>1</name>
                                    <description>Enable rescanning of the group that was stopped in group priority operation.</description>
                                    <value>#1</value>
                                </enumeratedValue>
                            </enumeratedValues>
                        </field>
                        <field>
                            <name>LGRRS</name>
                            <description>Enabled only when PGS = 1 and GBRSCN = 1.</description>
                            <lsb>14</lsb>
                            <msb>14</msb>
                            <access>read-write</access>
                            <enumeratedValues>
                                <enumeratedValue>
                                    <name>0</name>
                                    <description>Start rescanning from the first channel for scanning</description>
                                    <value>#0</value>
                                </enumeratedValue>
                                <enumeratedValue>
                                    <name>1</name>
                                    <description>Start rescanning from the channel for which A/D conversion is not completed.</description>
                                    <value>#1</value>
                                </enumeratedValue>
                            </enumeratedValues>
                        </field>
                        <field>
                            <name>GBRP</name>
                            <description>Single Scan Continuous Start</description>
                            <lsb>15</lsb>
                            <msb>15</msb>
                            <access>read-write</access>
                            <enumeratedValues>
                                <enumeratedValue>
                                    <name>0</name>
                                    <description>Single scan is not continuously activated.</description>
                                    <value>#0</value>
                                </enumeratedValue>
                                <enumeratedValue>
                                    <name>1</name>
                                    <description>Single scan for the group with the lower-priority is continuously activated.</description>
                                    <value>#1</value>
                                </enumeratedValue>
                            </enumeratedValues>
                        </field>
                    </fields>
                </register>
                <register>
                    <name>ADDBLDRA</name>
                    <description>A/D Data Duplexing Register A</description>
                    <addressOffset>0x084</addressOffset>
                    <size>16</size>
                    <access>read-only</access>
                    <resetValue>0x0000</resetValue>
                    <resetMask>0xffff</resetMask>
                    <fields>
                        <field>
                            <name>ADDBLDR</name>
                            <description>Converted Value 15 to 0</description>
                            <lsb>0</lsb>
                            <msb>15</msb>
                            <access>read-only</access>
                        </field>
                    </fields>
                </register>
                <register>
                    <name>ADDBLDRB</name>
                    <description>A/D Data Duplexing Register B</description>
                    <addressOffset>0x086</addressOffset>
                    <size>16</size>
                    <access>read-only</access>
                    <resetValue>0x0000</resetValue>
                    <resetMask>0xffff</resetMask>
                    <fields>
                        <field>
                            <name>ADDBLDR</name>
                            <description>Converted Value 15 to 0</description>
                            <lsb>0</lsb>
                            <msb>15</msb>
                            <access>read-only</access>
                        </field>
                    </fields>
                </register>
                <register>
                    <name>ADWINMON</name>
                    <description>A/D Compare Function Window A/B Status Monitor Register</description>
                    <addressOffset>0x08C</addressOffset>
                    <size>8</size>
                    <access>read-only</access>
                    <resetValue>0x00</resetValue>
                    <resetMask>0xff</resetMask>
                    <fields>
                        <field>
                            <name>MONCOMB</name>
                            <description>Combination Result Monitor</description>
                            <lsb>0</lsb>
                            <msb>0</msb>
                            <access>read-only</access>
                            <enumeratedValues>
                                <enumeratedValue>
                                    <name>0</name>
                                    <description>Window A/B composite conditions are not met.</description>
                                    <value>#0</value>
                                </enumeratedValue>
                                <enumeratedValue>
                                    <name>1</name>
                                    <description>Window A/B composite conditions are met.</description>
                                    <value>#1</value>
                                </enumeratedValue>
                            </enumeratedValues>
                        </field>
                        <field>
                            <name>MONCMPA</name>
                            <description>Comparison Result Monitor A</description>
                            <lsb>4</lsb>
                            <msb>4</msb>
                            <access>read-only</access>
                            <enumeratedValues>
                                <enumeratedValue>
                                    <name>0</name>
                                    <description>Window A comparison conditions are not met.</description>
                                    <value>#0</value>
                                </enumeratedValue>
                                <enumeratedValue>
                                    <name>1</name>
                                    <description>Window A comparison conditions are met.</description>
                                    <value>#1</value>
                                </enumeratedValue>
                            </enumeratedValues>
                        </field>
                        <field>
                            <name>MONCMPB</name>
                            <description>Comparison Result Monitor B</description>
                            <lsb>5</lsb>
                            <msb>5</msb>
                            <access>read-only</access>
                            <enumeratedValues>
                                <enumeratedValue>
                                    <name>0</name>
                                    <description>Window B comparison conditions are not met.</description>
                                    <value>#0</value>
                                </enumeratedValue>
                                <enumeratedValue>
                                    <name>1</name>
                                    <description>Window B comparison conditions are met.</description>
                                    <value>#1</value>
                                </enumeratedValue>
                            </enumeratedValues>
                        </field>
                    </fields>
                </register>
                <register>
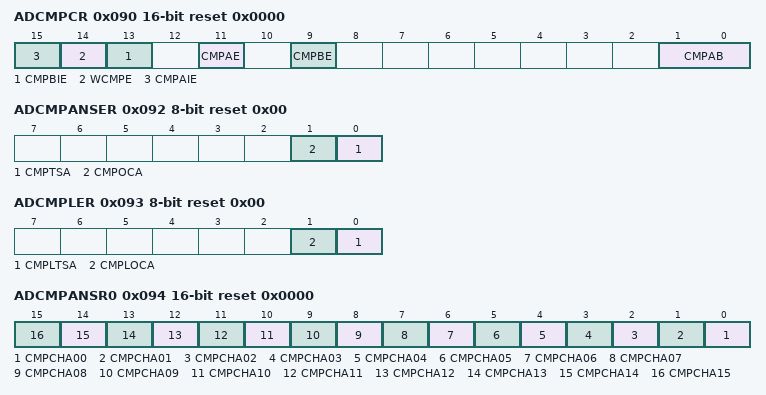
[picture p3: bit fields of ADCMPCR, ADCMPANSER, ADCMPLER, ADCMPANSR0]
                    <name>ADCMPCR</name>
                    <description>A/D Compare Function Control Register</description>
                    <addressOffset>0x090</addressOffset>
                    <size>16</size>
                    <access>read-write</access>
                    <resetValue>0x0000</resetValue>
                    <resetMask>0xffff</resetMask>
                    <fields>
                        <field>
                            <name>CMPAB</name>
                            <description>Window A/B Composite Conditions Setting</description>
                            <lsb>0</lsb>
                            <msb>1</msb>
                            <access>read-write</access>
                            <enumeratedValues>
                                <enumeratedValue>
                                    <name>00</name>
                                    <description>Output ADC12i_WCMPM (i = 0, 1) when window A OR window B comparison conditions are met. Otherwise, output ADC12i_WCMPUM (i = 0, 1).</description>
                                    <value>#00</value>
                                </enumeratedValue>
                                <enumeratedValue>
                                    <name>01</name>
                                    <description>Output ADC12i_WCMPM (i = 0, 1) when window A EXOR window B comparison conditions are met. Otherwise, output ADC12i_WCMPUM (i = 0, 1).</description>
                                    <value>#01</value>
                                </enumeratedValue>
                                <enumeratedValue>
                                    <name>10</name>
                                    <description>Output ADC12i_WCMPM (i = 0, 1) when window A AND window B comparison conditions are met. Otherwise, output ADC12i_WCMPUM (i = 0, 1).</description>
                                    <value>#10</value>
                                </enumeratedValue>
                                <enumeratedValue>
                                    <name>11</name>
                                    <description>Setting prohibited.</description>
                                    <value>#11</value>
                                </enumeratedValue>
                            </enumeratedValues>
                        </field>
                        <field>
                            <name>CMPBE</name>
                            <description>Compare Window B Operation Enable</description>
                            <lsb>9</lsb>
                            <msb>9</msb>
                            <access>read-write</access>
                            <enumeratedValues>
                                <enumeratedValue>
                                    <name>0</name>
                                    <description>Disable compare window B operation. Disable ADC12i_WCMPM (i = 0, 1) and ADC12i_WCMPUM (i = 0, 1) outputs. </description>
                                    <value>#0</value>
                                </enumeratedValue>
                                <enumeratedValue>
                                    <name>1</name>
                                    <description>Enable compare window B operation.</description>
                                    <value>#1</value>
                                </enumeratedValue>
                            </enumeratedValues>
                        </field>
                        <field>
                            <name>CMPAE</name>
                            <description>Compare Window A Operation Enable</description>
                            <lsb>11</lsb>
                            <msb>11</msb>
                            <access>read-write</access>
                            <enumeratedValues>
                                <enumeratedValue>
                                    <name>0</name>
                                    <description>Disable compare window A operation. Disable ADC12i_WCMPM (i = 0, 1) and ADC12i_WCMPUM (i = 0, 1) outputs. </description>
                                    <value>#0</value>
                                </enumeratedValue>
                                <enumeratedValue>
                                    <name>1</name>
                                    <description>Enable compare window A operation.</description>
                                    <value>#1</value>
                                </enumeratedValue>
                            </enumeratedValues>
                        </field>
                        <field>
                            <name>CMPBIE</name>
                            <description>Compare B Interrupt Enable</description>
                            <lsb>13</lsb>
                            <msb>13</msb>
                            <access>read-write</access>
                            <enumeratedValues>
                                <enumeratedValue>
                                    <name>0</name>
                                    <description>Disable ADC12i_CMPBI (i = 0, 1) interrupt when comparison conditions (window B) are met.</description>
                                    <value>#0</value>
                                </enumeratedValue>
                                <enumeratedValue>
                                    <name>1</name>
                                    <description>Enable ADC12i_CMPBI (i = 0, 1) interrupt when comparison conditions (window B) are met.</description>
                                    <value>#1</value>
                                </enumeratedValue>
                            </enumeratedValues>
                        </field>
                        <field>
                            <name>WCMPE</name>
                            <description>Window Function Setting</description>
                            <lsb>14</lsb>
                            <msb>14</msb>
                            <access>read-write</access>
                            <enumeratedValues>
                                <enumeratedValue>
                                    <name>0</name>
                                    <description>Disable window function Window A and window B operate as a comparator to compare the single value on the lower side with the A/D conversion result. </description>
                                    <value>#0</value>
                                </enumeratedValue>
                                <enumeratedValue>
                                    <name>1</name>
                                    <description>Enable window function Window A and window B operate as a comparator to compare the two values on the upper and lower sides with the A/D conversion result. </description>
                                    <value>#1</value>
                                </enumeratedValue>
                            </enumeratedValues>
                        </field>
                        <field>
                            <name>CMPAIE</name>
                            <description>Compare A Interrupt Enable</description>
                            <lsb>15</lsb>
                            <msb>15</msb>
                            <access>read-write</access>
                            <enumeratedValues>
                                <enumeratedValue>
                                    <name>0</name>
                                    <description>Disable ADC12i_CMPAI (i = 0, 1) interrupt when comparison conditions (window A) are met.</description>
                                    <value>#0</value>
                                </enumeratedValue>
                                <enumeratedValue>
                                    <name>1</name>
                                    <description>Enable ADC12i_CMPAI (i = 0, 1) interrupt when comparison conditions (window A) are met.</description>
                                    <value>#1</value>
                                </enumeratedValue>
                            </enumeratedValues>
                        </field>
                    </fields>
                </register>
                <register>
                    <name>ADCMPANSER</name>
                    <description>A/D Compare Function Window A Extended Input Select Register</description>
                    <addressOffset>0x092</addressOffset>
                    <size>8</size>
                    <access>read-write</access>
                    <resetValue>0x00</resetValue>
                    <resetMask>0xff</resetMask>
                    <fields>
                        <field>
                            <name>CMPTSA</name>
                            <description>Temperature Sensor Output Compare Select</description>
                            <lsb>0</lsb>
                            <msb>0</msb>
                            <access>read-write</access>
                            <enumeratedValues>
                                <enumeratedValue>
                                    <name>0</name>
                                    <description>Exclude the temperature sensor output from the compare Window A target range.</description>
                                    <value>#0</value>
                                </enumeratedValue>
                                <enumeratedValue>
                                    <name>1</name>
                                    <description>Include the temperature sensor output in the compare Window A target range.</description>
                                    <value>#1</value>
                                </enumeratedValue>
                            </enumeratedValues>
                        </field>
                        <field>
                            <name>CMPOCA</name>
                            <description>Internal Reference Voltage Compare Select</description>
                            <lsb>1</lsb>
                            <msb>1</msb>
                            <access>read-write</access>
                            <enumeratedValues>
                                <enumeratedValue>
                                    <name>0</name>
                                    <description>Exclude the internal reference voltage from the compare Window A target range.</description>
                                    <value>#0</value>
                                </enumeratedValue>
                                <enumeratedValue>
                                    <name>1</name>
                                    <description>Include the internal reference voltage in the compare Window A target range. </description>
                                    <value>#1</value>
                                </enumeratedValue>
                            </enumeratedValues>
                        </field>
                    </fields>
                </register>
                <register>
                    <name>ADCMPLER</name>
                    <description>A/D Compare Function Window A Extended Input Comparison Condition Setting Register</description>
                    <addressOffset>0x093</addressOffset>
                    <size>8</size>
                    <access>read-write</access>
                    <resetValue>0x00</resetValue>
                    <resetMask>0xff</resetMask>
                    <fields>
                        <field>
                            <name>CMPLTSA</name>
                            <description>Compare Window A Temperature Sensor Output Comparison Condition Select</description>
                            <lsb>0</lsb>
                            <msb>0</msb>
                            <access>read-write</access>
                            <enumeratedValues>
                                <enumeratedValue>
                                    <name>0</name>
                                    <description>When window function is disabled (ADCMPCR.WCMPE = 0) : ADCMPDR0 value &gt; A/D-converted valueCompare Window A Temperature Sensor Output Comparison Condition Select When window function is enabled (ADCMPCR.WCMPE = 1) : Compare Window A Temperature Sensor Output Comparison ConditionA/D-converted value &lt; ADCMPDR0 value, or A/D-converted value &gt; ADCMPDR1 value </description>
                                    <value>#0</value>
                                </enumeratedValue>
                                <enumeratedValue>
                                    <name>1</name>
                                    <description>When window function is disabled (ADCMPCR.WCMPE = 0) : ADCMPDR0 value &lt; A/D-converted value When window function is enabled (ADCMPCR.WCMPE = 1) : ADCMPDR0 value &lt; A/D-converted value &lt; ADCMPDR1 value </description>
                                    <value>#1</value>
                                </enumeratedValue>
                            </enumeratedValues>
                        </field>
                        <field>
                            <name>CMPLOCA</name>
                            <description>Compare Window A Internal Reference Voltage Comparison Condition Select</description>
                            <lsb>1</lsb>
                            <msb>1</msb>
                            <access>read-write</access>
                            <enumeratedValues>
                                <enumeratedValue>
                                    <name>0</name>
                                    <description>When window function is disabled (ADCMPCR.WCMPE = 0) : ADCMPDR0 value &gt; A/D-converted value When window function is enabled (ADCMPCR.WCMPE = 1): A/D-converted value &lt; ADCMPDR0 value, or A/D-converted value &gt; ADCMPDR1 value </description>
                                    <value>#0</value>
                                </enumeratedValue>
                                <enumeratedValue>
                                    <name>1</name>
                                    <description>When window function is disabled (ADCMPCR.WCMPE = 0): ADCMPDR0 value &lt; A/D-converted value When window function is enabled (ADCMPCR.WCMPE = 1): ADCMPDR0 value &lt; A/D-converted value &lt; ADCMPDR1 value </description>
                                    <value>#1</value>
                                </enumeratedValue>
                            </enumeratedValues>
                        </field>
                    </fields>
                </register>
                <register>
                    <name>ADCMPANSR0</name>
                    <description>A/D Compare Function Window A Channel Select Register 0</description>
                    <addressOffset>0x094</addressOffset>
                    <size>16</size>
                    <access>read-write</access>
                    <resetValue>0x0000</resetValue>
                    <resetMask>0xffff</resetMask>
                    <fields>
                        <field>
                            <name>CMPCHA00</name>
                            <description>Compare Window A Channel Select</description>
                            <lsb>0</lsb>
                            <msb>0</msb>
                            <access>read-write</access>
                            <enumeratedValues>
                                <enumeratedValue>
                                    <name>0</name>
                                    <description>Disable compare function for associated input channel</description>
                                    <value>#0</value>
                                </enumeratedValue>
                                <enumeratedValue>
                                    <name>1</name>
                                    <description>Enable compare function for associated input channel</description>
                                    <value>#1</value>
                                </enumeratedValue>
                            </enumeratedValues>
                        </field>
                        <field>
                            <name>CMPCHA01</name>
                            <description>Compare Window A Channel Select</description>
                            <lsb>1</lsb>
                            <msb>1</msb>
                            <access>read-write</access>
                            <enumeratedValues>
                                <enumeratedValue>
                                    <name>0</name>
                                    <description>Disable compare function for associated input channel</description>
                                    <value>#0</value>
                                </enumeratedValue>
                                <enumeratedValue>
                                    <name>1</name>
                                    <description>Enable compare function for associated input channel</description>
                                    <value>#1</value>
                                </enumeratedValue>
                            </enumeratedValues>
                        </field>
                        <field>
                            <name>CMPCHA02</name>
                            <description>Compare Window A Channel Select</description>
                            <lsb>2</lsb>
                            <msb>2</msb>
                            <access>read-write</access>
                            <enumeratedValues>
                                <enumeratedValue>
                                    <name>0</name>
                                    <description>Disable compare function for associated input channel</description>
                                    <value>#0</value>
                                </enumeratedValue>
                                <enumeratedValue>
                                    <name>1</name>
                                    <description>Enable compare function for associated input channel</description>
                                    <value>#1</value>
                                </enumeratedValue>
                            </enumeratedValues>
                        </field>
                        <field>
                            <name>CMPCHA03</name>
                            <description>Compare Window A Channel Select</description>
                            <lsb>3</lsb>
                            <msb>3</msb>
                            <access>read-write</access>
                            <enumeratedValues>
                                <enumeratedValue>
                                    <name>0</name>
                                    <description>Disable compare function for associated input channel</description>
                                    <value>#0</value>
                                </enumeratedValue>
                                <enumeratedValue>
                                    <name>1</name>
                                    <description>Enable compare function for associated input channel</description>
                                    <value>#1</value>
                                </enumeratedValue>
                            </enumeratedValues>
                        </field>
                        <field>
                            <name>CMPCHA04</name>
                            <description>Compare Window A Channel Select</description>
                            <lsb>4</lsb>
                            <msb>4</msb>
                            <access>read-write</access>
                            <enumeratedValues>
                                <enumeratedValue>
                                    <name>0</name>
                                    <description>Disable compare function for associated input channel</description>
                                    <value>#0</value>
                                </enumeratedValue>
                                <enumeratedValue>
                                    <name>1</name>
                                    <description>Enable compare function for associated input channel</description>
                                    <value>#1</value>
                                </enumeratedValue>
                            </enumeratedValues>
                        </field>
                        <field>
                            <name>CMPCHA05</name>
                            <description>Compare Window A Channel Select</description>
                            <lsb>5</lsb>
                            <msb>5</msb>
                            <access>read-write</access>
                            <enumeratedValues>
                                <enumeratedValue>
                                    <name>0</name>
                                    <description>Disable compare function for associated input channel</description>
                                    <value>#0</value>
                                </enumeratedValue>
                                <enumeratedValue>
                                    <name>1</name>
                                    <description>Enable compare function for associated input channel</description>
                                    <value>#1</value>
                                </enumeratedValue>
                            </enumeratedValues>
                        </field>
                        <field>
                            <name>CMPCHA06</name>
                            <description>Compare Window A Channel Select</description>
                            <lsb>6</lsb>
                            <msb>6</msb>
                            <access>read-write</access>
                            <enumeratedValues>
                                <enumeratedValue>
                                    <name>0</name>
                                    <description>Disable compare function for associated input channel</description>
                                    <value>#0</value>
                                </enumeratedValue>
                                <enumeratedValue>
                                    <name>1</name>
                                    <description>Enable compare function for associated input channel</description>
                                    <value>#1</value>
                                </enumeratedValue>
                            </enumeratedValues>
                        </field>
                        <field>
                            <name>CMPCHA07</name>
                            <description>Compare Window A Channel Select</description>
                            <lsb>7</lsb>
                            <msb>7</msb>
                            <access>read-write</access>
                            <enumeratedValues>
                                <enumeratedValue>
                                    <name>0</name>
                                    <description>Disable compare function for associated input channel</description>
                                    <value>#0</value>
                                </enumeratedValue>
                                <enumeratedValue>
                                    <name>1</name>
                                    <description>Enable compare function for associated input channel</description>
                                    <value>#1</value>
                                </enumeratedValue>
                            </enumeratedValues>
                        </field>
                        <field>
                            <name>CMPCHA08</name>
                            <description>Compare Window A Channel Select</description>
                            <lsb>8</lsb>
                            <msb>8</msb>
                            <access>read-write</access>
                            <enumeratedValues>
                                <enumeratedValue>
                                    <name>0</name>
                                    <description>Disable compare function for associated input channel</description>
                                    <value>#0</value>
                                </enumeratedValue>
                                <enumeratedValue>
                                    <name>1</name>
                                    <description>Enable compare function for associated input channel</description>
                                    <value>#1</value>
                                </enumeratedValue>
                            </enumeratedValues>
                        </field>
                        <field>
                            <name>CMPCHA09</name>
                            <description>Compare Window A Channel Select</description>
                            <lsb>9</lsb>
                            <msb>9</msb>
                            <access>read-write</access>
                            <enumeratedValues>
                                <enumeratedValue>
                                    <name>0</name>
                                    <description>Disable compare function for associated input channel</description>
                                    <value>#0</value>
                                </enumeratedValue>
                                <enumeratedValue>
                                    <name>1</name>
                                    <description>Enable compare function for associated input channel</description>
                                    <value>#1</value>
                                </enumeratedValue>
                            </enumeratedValues>
                        </field>
                        <field>
                            <name>CMPCHA10</name>
                            <description>Compare Window A Channel Select</description>
                            <lsb>10</lsb>
                            <msb>10</msb>
                            <access>read-write</access>
                            <enumeratedValues>
                                <enumeratedValue>
                                    <name>0</name>
                                    <description>Disable compare function for associated input channel</description>
                                    <value>#0</value>
                                </enumeratedValue>
                                <enumeratedValue>
                                    <name>1</name>
                                    <description>Enable compare function for associated input channel</description>
                                    <value>#1</value>
                                </enumeratedValue>
                            </enumeratedValues>
                        </field>
                        <field>
                            <name>CMPCHA11</name>
                            <description>Compare Window A Channel Select</description>
                            <lsb>11</lsb>
                            <msb>11</msb>
                            <access>read-write</access>
                            <enumeratedValues>
                                <enumeratedValue>
                                    <name>0</name>
                                    <description>Disable compare function for associated input channel</description>
                                    <value>#0</value>
                                </enumeratedValue>
                                <enumeratedValue>
                                    <name>1</name>
                                    <description>Enable compare function for associated input channel</description>
                                    <value>#1</value>
                                </enumeratedValue>
                            </enumeratedValues>
                        </field>
                        <field>
                            <name>CMPCHA12</name>
                            <description>Compare Window A Channel Select</description>
                            <lsb>12</lsb>
                            <msb>12</msb>
                            <access>read-write</access>
                            <enumeratedValues>
                                <enumeratedValue>
                                    <name>0</name>
                                    <description>Disable compare function for associated input channel</description>
                                    <value>#0</value>
                                </enumeratedValue>
                                <enumeratedValue>
                                    <name>1</name>
                                    <description>Enable compare function for associated input channel</description>
                                    <value>#1</value>
                                </enumeratedValue>
                            </enumeratedValues>
                        </field>
                        <field>
                            <name>CMPCHA13</name>
                            <description>Compare Window A Channel Select</description>
                            <lsb>13</lsb>
                            <msb>13</msb>
                            <access>read-write</access>
                            <enumeratedValues>
                                <enumeratedValue>
                                    <name>0</name>
                                    <description>Disable compare function for associated input channel</description>
                                    <value>#0</value>
                                </enumeratedValue>
                                <enumeratedValue>
                                    <name>1</name>
                                    <description>Enable compare function for associated input channel</description>
                                    <value>#1</value>
                                </enumeratedValue>
                            </enumeratedValues>
                        </field>
                        <field>
                            <name>CMPCHA14</name>
                            <description>Compare Window A Channel Select</description>
                            <lsb>14</lsb>
                            <msb>14</msb>
                            <access>read-write</access>
                            <enumeratedValues>
                                <enumeratedValue>
                                    <name>0</name>
                                    <description>Disable compare function for associated input channel</description>
                                    <value>#0</value>
                                </enumeratedValue>
                                <enumeratedValue>
                                    <name>1</name>
                                    <description>Enable compare function for associated input channel</description>
                                    <value>#1</value>
                                </enumeratedValue>
                            </enumeratedValues>
                        </field>
                        <field>
                            <name>CMPCHA15</name>
                            <description>Compare Window A Channel Select</description>
                            <lsb>15</lsb>
                            <msb>15</msb>
                            <access>read-write</access>
                            <enumeratedValues>
                                <enumeratedValue>
                                    <name>0</name>
                                    <description>Disable compare function for associated input channel</description>
                                    <value>#0</value>
                                </enumeratedValue>
                                <enumeratedValue>
                                    <name>1</name>
                                    <description>Enable compare function for associated input channel</description>
                                    <value>#1</value>
                                </enumeratedValue>
                            </enumeratedValues>
                        </field>
                    </fields>
                </register>
                <register>
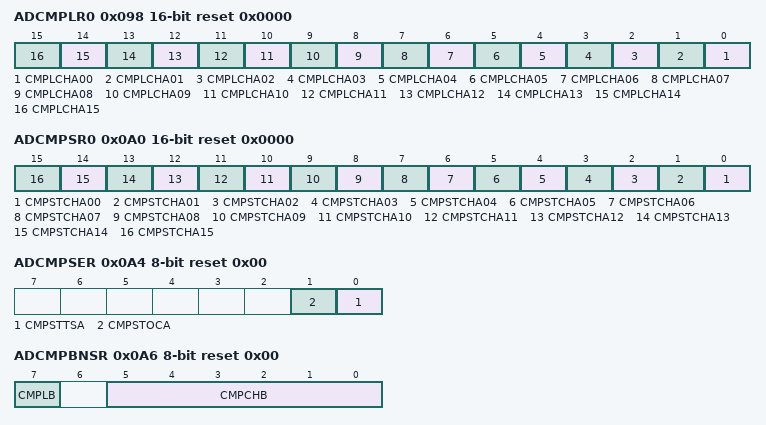
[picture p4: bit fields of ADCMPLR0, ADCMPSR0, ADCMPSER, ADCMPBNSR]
                    <name>ADCMPLR0</name>
                    <description>A/D Compare Function Window A Comparison Condition Setting Register 0</description>
                    <addressOffset>0x098</addressOffset>
                    <size>16</size>
                    <access>read-write</access>
                    <resetValue>0x0000</resetValue>
                    <resetMask>0xffff</resetMask>
                    <fields>
                        <field>
                            <name>CMPLCHA00</name>
                            <description>Compare Window A Comparison Condition Select</description>
                            <lsb>0</lsb>
                            <msb>0</msb>
                            <access>read-write</access>
                            <enumeratedValues>
                                <enumeratedValue>
                                    <name>0</name>
                                    <description>When window function is disabled (ADCMPCR.WCMPE = 0): ADCMPDR0 value &gt; A/D-converted value When window function is enabled (ADCMPCR.WCMPE = 1): A/D-converted value &lt; ADCMPDR0 value, or ADCMPDR1 value &lt; A/D-converted value </description>
                                    <value>#0</value>
                                </enumeratedValue>
                                <enumeratedValue>
                                    <name>1</name>
                                    <description>When window function is disabled (ADCMPCR.WCMPE = 0): ADCMPDR0 value &lt; A/D-converted value When window function is enabled (ADCMPCR.WCMPE = 1): ADCMPDR0 value &lt; A/D-converted value &lt; ADCMPDR1 value </description>
                                    <value>#1</value>
                                </enumeratedValue>
                            </enumeratedValues>
                        </field>
                        <field>
                            <name>CMPLCHA01</name>
                            <description>Compare Window A Comparison Condition Select</description>
                            <lsb>1</lsb>
                            <msb>1</msb>
                            <access>read-write</access>
                            <enumeratedValues>
                                <enumeratedValue>
                                    <name>0</name>
                                    <description>When window function is disabled (ADCMPCR.WCMPE = 0): ADCMPDR0 value &gt; A/D-converted value When window function is enabled (ADCMPCR.WCMPE = 1): A/D-converted value &lt; ADCMPDR0 value, or ADCMPDR1 value &lt; A/D-converted value </description>
                                    <value>#0</value>
                                </enumeratedValue>
                                <enumeratedValue>
                                    <name>1</name>
                                    <description>When window function is disabled (ADCMPCR.WCMPE = 0): ADCMPDR0 value &lt; A/D-converted value When window function is enabled (ADCMPCR.WCMPE = 1): ADCMPDR0 value &lt; A/D-converted value &lt; ADCMPDR1 value </description>
                                    <value>#1</value>
                                </enumeratedValue>
                            </enumeratedValues>
                        </field>
                        <field>
                            <name>CMPLCHA02</name>
                            <description>Compare Window A Comparison Condition Select</description>
                            <lsb>2</lsb>
                            <msb>2</msb>
                            <access>read-write</access>
                            <enumeratedValues>
                                <enumeratedValue>
                                    <name>0</name>
                                    <description>When window function is disabled (ADCMPCR.WCMPE = 0): ADCMPDR0 value &gt; A/D-converted value When window function is enabled (ADCMPCR.WCMPE = 1): A/D-converted value &lt; ADCMPDR0 value, or ADCMPDR1 value &lt; A/D-converted value </description>
                                    <value>#0</value>
                                </enumeratedValue>
                                <enumeratedValue>
                                    <name>1</name>
                                    <description>When window function is disabled (ADCMPCR.WCMPE = 0): ADCMPDR0 value &lt; A/D-converted value When window function is enabled (ADCMPCR.WCMPE = 1): ADCMPDR0 value &lt; A/D-converted value &lt; ADCMPDR1 value </description>
                                    <value>#1</value>
                                </enumeratedValue>
                            </enumeratedValues>
                        </field>
                        <field>
                            <name>CMPLCHA03</name>
                            <description>Compare Window A Comparison Condition Select</description>
                            <lsb>3</lsb>
                            <msb>3</msb>
                            <access>read-write</access>
                            <enumeratedValues>
                                <enumeratedValue>
                                    <name>0</name>
                                    <description>When window function is disabled (ADCMPCR.WCMPE = 0): ADCMPDR0 value &gt; A/D-converted value When window function is enabled (ADCMPCR.WCMPE = 1): A/D-converted value &lt; ADCMPDR0 value, or ADCMPDR1 value &lt; A/D-converted value </description>
                                    <value>#0</value>
                                </enumeratedValue>
                                <enumeratedValue>
                                    <name>1</name>
                                    <description>When window function is disabled (ADCMPCR.WCMPE = 0): ADCMPDR0 value &lt; A/D-converted value When window function is enabled (ADCMPCR.WCMPE = 1): ADCMPDR0 value &lt; A/D-converted value &lt; ADCMPDR1 value </description>
                                    <value>#1</value>
                                </enumeratedValue>
                            </enumeratedValues>
                        </field>
                        <field>
                            <name>CMPLCHA04</name>
                            <description>Compare Window A Comparison Condition Select</description>
                            <lsb>4</lsb>
                            <msb>4</msb>
                            <access>read-write</access>
                            <enumeratedValues>
                                <enumeratedValue>
                                    <name>0</name>
                                    <description>When window function is disabled (ADCMPCR.WCMPE = 0): ADCMPDR0 value &gt; A/D-converted value When window function is enabled (ADCMPCR.WCMPE = 1): A/D-converted value &lt; ADCMPDR0 value, or ADCMPDR1 value &lt; A/D-converted value </description>
                                    <value>#0</value>
                                </enumeratedValue>
                                <enumeratedValue>
                                    <name>1</name>
                                    <description>When window function is disabled (ADCMPCR.WCMPE = 0): ADCMPDR0 value &lt; A/D-converted value When window function is enabled (ADCMPCR.WCMPE = 1): ADCMPDR0 value &lt; A/D-converted value &lt; ADCMPDR1 value </description>
                                    <value>#1</value>
                                </enumeratedValue>
                            </enumeratedValues>
                        </field>
                        <field>
                            <name>CMPLCHA05</name>
                            <description>Compare Window A Comparison Condition Select</description>
                            <lsb>5</lsb>
                            <msb>5</msb>
                            <access>read-write</access>
                            <enumeratedValues>
                                <enumeratedValue>
                                    <name>0</name>
                                    <description>When window function is disabled (ADCMPCR.WCMPE = 0): ADCMPDR0 value &gt; A/D-converted value When window function is enabled (ADCMPCR.WCMPE = 1): A/D-converted value &lt; ADCMPDR0 value, or ADCMPDR1 value &lt; A/D-converted value </description>
                                    <value>#0</value>
                                </enumeratedValue>
                                <enumeratedValue>
                                    <name>1</name>
                                    <description>When window function is disabled (ADCMPCR.WCMPE = 0): ADCMPDR0 value &lt; A/D-converted value When window function is enabled (ADCMPCR.WCMPE = 1): ADCMPDR0 value &lt; A/D-converted value &lt; ADCMPDR1 value </description>
                                    <value>#1</value>
                                </enumeratedValue>
                            </enumeratedValues>
                        </field>
                        <field>
                            <name>CMPLCHA06</name>
                            <description>Compare Window A Comparison Condition Select</description>
                            <lsb>6</lsb>
                            <msb>6</msb>
                            <access>read-write</access>
                            <enumeratedValues>
                                <enumeratedValue>
                                    <name>0</name>
                                    <description>When window function is disabled (ADCMPCR.WCMPE = 0): ADCMPDR0 value &gt; A/D-converted value When window function is enabled (ADCMPCR.WCMPE = 1): A/D-converted value &lt; ADCMPDR0 value, or ADCMPDR1 value &lt; A/D-converted value </description>
                                    <value>#0</value>
                                </enumeratedValue>
                                <enumeratedValue>
                                    <name>1</name>
                                    <description>When window function is disabled (ADCMPCR.WCMPE = 0): ADCMPDR0 value &lt; A/D-converted value When window function is enabled (ADCMPCR.WCMPE = 1): ADCMPDR0 value &lt; A/D-converted value &lt; ADCMPDR1 value </description>
                                    <value>#1</value>
                                </enumeratedValue>
                            </enumeratedValues>
                        </field>
                        <field>
                            <name>CMPLCHA07</name>
                            <description>Compare Window A Comparison Condition Select</description>
                            <lsb>7</lsb>
                            <msb>7</msb>
                            <access>read-write</access>
                            <enumeratedValues>
                                <enumeratedValue>
                                    <name>0</name>
                                    <description>When window function is disabled (ADCMPCR.WCMPE = 0): ADCMPDR0 value &gt; A/D-converted value When window function is enabled (ADCMPCR.WCMPE = 1): A/D-converted value &lt; ADCMPDR0 value, or ADCMPDR1 value &lt; A/D-converted value </description>
                                    <value>#0</value>
                                </enumeratedValue>
                                <enumeratedValue>
                                    <name>1</name>
                                    <description>When window function is disabled (ADCMPCR.WCMPE = 0): ADCMPDR0 value &lt; A/D-converted value When window function is enabled (ADCMPCR.WCMPE = 1): ADCMPDR0 value &lt; A/D-converted value &lt; ADCMPDR1 value </description>
                                    <value>#1</value>
                                </enumeratedValue>
                            </enumeratedValues>
                        </field>
                        <field>
                            <name>CMPLCHA08</name>
                            <description>Compare Window A Comparison Condition Select</description>
                            <lsb>8</lsb>
                            <msb>8</msb>
                            <access>read-write</access>
                            <enumeratedValues>
                                <enumeratedValue>
                                    <name>0</name>
                                    <description>When window function is disabled (ADCMPCR.WCMPE = 0): ADCMPDR0 value &gt; A/D-converted value When window function is enabled (ADCMPCR.WCMPE = 1): A/D-converted value &lt; ADCMPDR0 value, or ADCMPDR1 value &lt; A/D-converted value </description>
                                    <value>#0</value>
                                </enumeratedValue>
                                <enumeratedValue>
                                    <name>1</name>
                                    <description>When window function is disabled (ADCMPCR.WCMPE = 0): ADCMPDR0 value &lt; A/D-converted value When window function is enabled (ADCMPCR.WCMPE = 1): ADCMPDR0 value &lt; A/D-converted value &lt; ADCMPDR1 value </description>
                                    <value>#1</value>
                                </enumeratedValue>
                            </enumeratedValues>
                        </field>
                        <field>
                            <name>CMPLCHA09</name>
                            <description>Compare Window A Comparison Condition Select</description>
                            <lsb>9</lsb>
                            <msb>9</msb>
                            <access>read-write</access>
                            <enumeratedValues>
                                <enumeratedValue>
                                    <name>0</name>
                                    <description>When window function is disabled (ADCMPCR.WCMPE = 0): ADCMPDR0 value &gt; A/D-converted value When window function is enabled (ADCMPCR.WCMPE = 1): A/D-converted value &lt; ADCMPDR0 value, or ADCMPDR1 value &lt; A/D-converted value </description>
                                    <value>#0</value>
                                </enumeratedValue>
                                <enumeratedValue>
                                    <name>1</name>
                                    <description>When window function is disabled (ADCMPCR.WCMPE = 0): ADCMPDR0 value &lt; A/D-converted value When window function is enabled (ADCMPCR.WCMPE = 1): ADCMPDR0 value &lt; A/D-converted value &lt; ADCMPDR1 value </description>
                                    <value>#1</value>
                                </enumeratedValue>
                            </enumeratedValues>
                        </field>
                        <field>
                            <name>CMPLCHA10</name>
                            <description>Compare Window A Comparison Condition Select</description>
                            <lsb>10</lsb>
                            <msb>10</msb>
                            <access>read-write</access>
                            <enumeratedValues>
                                <enumeratedValue>
                                    <name>0</name>
                                    <description>When window function is disabled (ADCMPCR.WCMPE = 0): ADCMPDR0 value &gt; A/D-converted value When window function is enabled (ADCMPCR.WCMPE = 1): A/D-converted value &lt; ADCMPDR0 value, or ADCMPDR1 value &lt; A/D-converted value </description>
                                    <value>#0</value>
                                </enumeratedValue>
                                <enumeratedValue>
                                    <name>1</name>
                                    <description>When window function is disabled (ADCMPCR.WCMPE = 0): ADCMPDR0 value &lt; A/D-converted value When window function is enabled (ADCMPCR.WCMPE = 1): ADCMPDR0 value &lt; A/D-converted value &lt; ADCMPDR1 value </description>
                                    <value>#1</value>
                                </enumeratedValue>
                            </enumeratedValues>
                        </field>
                        <field>
                            <name>CMPLCHA11</name>
                            <description>Compare Window A Comparison Condition Select</description>
                            <lsb>11</lsb>
                            <msb>11</msb>
                            <access>read-write</access>
                            <enumeratedValues>
                                <enumeratedValue>
                                    <name>0</name>
                                    <description>When window function is disabled (ADCMPCR.WCMPE = 0): ADCMPDR0 value &gt; A/D-converted value When window function is enabled (ADCMPCR.WCMPE = 1): A/D-converted value &lt; ADCMPDR0 value, or ADCMPDR1 value &lt; A/D-converted value </description>
                                    <value>#0</value>
                                </enumeratedValue>
                                <enumeratedValue>
                                    <name>1</name>
                                    <description>When window function is disabled (ADCMPCR.WCMPE = 0): ADCMPDR0 value &lt; A/D-converted value When window function is enabled (ADCMPCR.WCMPE = 1): ADCMPDR0 value &lt; A/D-converted value &lt; ADCMPDR1 value </description>
                                    <value>#1</value>
                                </enumeratedValue>
                            </enumeratedValues>
                        </field>
                        <field>
                            <name>CMPLCHA12</name>
                            <description>Compare Window A Comparison Condition Select</description>
                            <lsb>12</lsb>
                            <msb>12</msb>
                            <access>read-write</access>
                            <enumeratedValues>
                                <enumeratedValue>
                                    <name>0</name>
                                    <description>When window function is disabled (ADCMPCR.WCMPE = 0): ADCMPDR0 value &gt; A/D-converted value When window function is enabled (ADCMPCR.WCMPE = 1): A/D-converted value &lt; ADCMPDR0 value, or ADCMPDR1 value &lt; A/D-converted value </description>
                                    <value>#0</value>
                                </enumeratedValue>
                                <enumeratedValue>
                                    <name>1</name>
                                    <description>When window function is disabled (ADCMPCR.WCMPE = 0): ADCMPDR0 value &lt; A/D-converted value When window function is enabled (ADCMPCR.WCMPE = 1): ADCMPDR0 value &lt; A/D-converted value &lt; ADCMPDR1 value </description>
                                    <value>#1</value>
                                </enumeratedValue>
                            </enumeratedValues>
                        </field>
                        <field>
                            <name>CMPLCHA13</name>
                            <description>Compare Window A Comparison Condition Select</description>
                            <lsb>13</lsb>
                            <msb>13</msb>
                            <access>read-write</access>
                            <enumeratedValues>
                                <enumeratedValue>
                                    <name>0</name>
                                    <description>When window function is disabled (ADCMPCR.WCMPE = 0): ADCMPDR0 value &gt; A/D-converted value When window function is enabled (ADCMPCR.WCMPE = 1): A/D-converted value &lt; ADCMPDR0 value, or ADCMPDR1 value &lt; A/D-converted value </description>
                                    <value>#0</value>
                                </enumeratedValue>
                                <enumeratedValue>
                                    <name>1</name>
                                    <description>When window function is disabled (ADCMPCR.WCMPE = 0): ADCMPDR0 value &lt; A/D-converted value When window function is enabled (ADCMPCR.WCMPE = 1): ADCMPDR0 value &lt; A/D-converted value &lt; ADCMPDR1 value </description>
                                    <value>#1</value>
                                </enumeratedValue>
                            </enumeratedValues>
                        </field>
                        <field>
                            <name>CMPLCHA14</name>
                            <description>Compare Window A Comparison Condition Select</description>
                            <lsb>14</lsb>
                            <msb>14</msb>
                            <access>read-write</access>
                            <enumeratedValues>
                                <enumeratedValue>
                                    <name>0</name>
                                    <description>When window function is disabled (ADCMPCR.WCMPE = 0): ADCMPDR0 value &gt; A/D-converted value When window function is enabled (ADCMPCR.WCMPE = 1): A/D-converted value &lt; ADCMPDR0 value, or ADCMPDR1 value &lt; A/D-converted value </description>
                                    <value>#0</value>
                                </enumeratedValue>
                                <enumeratedValue>
                                    <name>1</name>
                                    <description>When window function is disabled (ADCMPCR.WCMPE = 0): ADCMPDR0 value &lt; A/D-converted value When window function is enabled (ADCMPCR.WCMPE = 1): ADCMPDR0 value &lt; A/D-converted value &lt; ADCMPDR1 value </description>
                                    <value>#1</value>
                                </enumeratedValue>
                            </enumeratedValues>
                        </field>
                        <field>
                            <name>CMPLCHA15</name>
                            <description>Compare Window A Comparison Condition Select</description>
                            <lsb>15</lsb>
                            <msb>15</msb>
                            <access>read-write</access>
                            <enumeratedValues>
                                <enumeratedValue>
                                    <name>0</name>
                                    <description>When window function is disabled (ADCMPCR.WCMPE = 0): ADCMPDR0 value &gt; A/D-converted value When window function is enabled (ADCMPCR.WCMPE = 1): A/D-converted value &lt; ADCMPDR0 value, or ADCMPDR1 value &lt; A/D-converted value </description>
                                    <value>#0</value>
                                </enumeratedValue>
                                <enumeratedValue>
                                    <name>1</name>
                                    <description>When window function is disabled (ADCMPCR.WCMPE = 0): ADCMPDR0 value &lt; A/D-converted value When window function is enabled (ADCMPCR.WCMPE = 1): ADCMPDR0 value &lt; A/D-converted value &lt; ADCMPDR1 value </description>
                                    <value>#1</value>
                                </enumeratedValue>
                            </enumeratedValues>
                        </field>
                    </fields>
                </register>
                <register>
                    <dim>2</dim>
                    <dimIncrement>0x2</dimIncrement>
                    <dimIndex>0-1</dimIndex>
                    <name>ADCMPDR%s</name>
                    <description>A/D Compare Function Window A Lower-Side/Upper-Side Level Setting Register</description>
                    <addressOffset>0x09C</addressOffset>
                    <size>16</size>
                    <access>read-write</access>
                    <resetValue>0x0000</resetValue>
                    <resetMask>0xffff</resetMask>
                </register>
                <register>
                    <name>ADCMPSR0</name>
                    <description>A/D Compare Function Window A Channel Status Register 0</description>
                    <addressOffset>0x0A0</addressOffset>
                    <size>16</size>
                    <access>read-write</access>
                    <resetValue>0x0000</resetValue>
                    <resetMask>0xffff</resetMask>
                    <fields>
                        <field>
                            <name>CMPSTCHA00</name>
                            <description>Compare Window A Flag</description>
                            <lsb>0</lsb>
                            <msb>0</msb>
                            <access>read-write</access>
                            <enumeratedValues>
                                <enumeratedValue>
                                    <name>0</name>
                                    <description>Comparison conditions are not met.</description>
                                    <value>#0</value>
                                </enumeratedValue>
                                <enumeratedValue>
                                    <name>1</name>
                                    <description>Comparison conditions are met.</description>
                                    <value>#1</value>
                                </enumeratedValue>
                            </enumeratedValues>
                        </field>
                        <field>
                            <name>CMPSTCHA01</name>
                            <description>Compare Window A Flag</description>
                            <lsb>1</lsb>
                            <msb>1</msb>
                            <access>read-write</access>
                            <enumeratedValues>
                                <enumeratedValue>
                                    <name>0</name>
                                    <description>Comparison conditions are not met.</description>
                                    <value>#0</value>
                                </enumeratedValue>
                                <enumeratedValue>
                                    <name>1</name>
                                    <description>Comparison conditions are met.</description>
                                    <value>#1</value>
                                </enumeratedValue>
                            </enumeratedValues>
                        </field>
                        <field>
                            <name>CMPSTCHA02</name>
                            <description>Compare Window A Flag</description>
                            <lsb>2</lsb>
                            <msb>2</msb>
                            <access>read-write</access>
                            <enumeratedValues>
                                <enumeratedValue>
                                    <name>0</name>
                                    <description>Comparison conditions are not met.</description>
                                    <value>#0</value>
                                </enumeratedValue>
                                <enumeratedValue>
                                    <name>1</name>
                                    <description>Comparison conditions are met.</description>
                                    <value>#1</value>
                                </enumeratedValue>
                            </enumeratedValues>
                        </field>
                        <field>
                            <name>CMPSTCHA03</name>
                            <description>Compare Window A Flag</description>
                            <lsb>3</lsb>
                            <msb>3</msb>
                            <access>read-write</access>
                            <enumeratedValues>
                                <enumeratedValue>
                                    <name>0</name>
                                    <description>Comparison conditions are not met.</description>
                                    <value>#0</value>
                                </enumeratedValue>
                                <enumeratedValue>
                                    <name>1</name>
                                    <description>Comparison conditions are met.</description>
                                    <value>#1</value>
                                </enumeratedValue>
                            </enumeratedValues>
                        </field>
                        <field>
                            <name>CMPSTCHA04</name>
                            <description>Compare Window A Flag</description>
                            <lsb>4</lsb>
                            <msb>4</msb>
                            <access>read-write</access>
                            <enumeratedValues>
                                <enumeratedValue>
                                    <name>0</name>
                                    <description>Comparison conditions are not met.</description>
                                    <value>#0</value>
                                </enumeratedValue>
                                <enumeratedValue>
                                    <name>1</name>
                                    <description>Comparison conditions are met.</description>
                                    <value>#1</value>
                                </enumeratedValue>
                            </enumeratedValues>
                        </field>
                        <field>
                            <name>CMPSTCHA05</name>
                            <description>Compare Window A Flag</description>
                            <lsb>5</lsb>
                            <msb>5</msb>
                            <access>read-write</access>
                            <enumeratedValues>
                                <enumeratedValue>
                                    <name>0</name>
                                    <description>Comparison conditions are not met.</description>
                                    <value>#0</value>
                                </enumeratedValue>
                                <enumeratedValue>
                                    <name>1</name>
                                    <description>Comparison conditions are met.</description>
                                    <value>#1</value>
                                </enumeratedValue>
                            </enumeratedValues>
                        </field>
                        <field>
                            <name>CMPSTCHA06</name>
                            <description>Compare Window A Flag</description>
                            <lsb>6</lsb>
                            <msb>6</msb>
                            <access>read-write</access>
                            <enumeratedValues>
                                <enumeratedValue>
                                    <name>0</name>
                                    <description>Comparison conditions are not met.</description>
                                    <value>#0</value>
                                </enumeratedValue>
                                <enumeratedValue>
                                    <name>1</name>
                                    <description>Comparison conditions are met.</description>
                                    <value>#1</value>
                                </enumeratedValue>
                            </enumeratedValues>
                        </field>
                        <field>
                            <name>CMPSTCHA07</name>
                            <description>Compare Window A Flag</description>
                            <lsb>7</lsb>
                            <msb>7</msb>
                            <access>read-write</access>
                            <enumeratedValues>
                                <enumeratedValue>
                                    <name>0</name>
                                    <description>Comparison conditions are not met.</description>
                                    <value>#0</value>
                                </enumeratedValue>
                                <enumeratedValue>
                                    <name>1</name>
                                    <description>Comparison conditions are met.</description>
                                    <value>#1</value>
                                </enumeratedValue>
                            </enumeratedValues>
                        </field>
                        <field>
                            <name>CMPSTCHA08</name>
                            <description>Compare Window A Flag</description>
                            <lsb>8</lsb>
                            <msb>8</msb>
                            <access>read-write</access>
                            <enumeratedValues>
                                <enumeratedValue>
                                    <name>0</name>
                                    <description>Comparison conditions are not met.</description>
                                    <value>#0</value>
                                </enumeratedValue>
                                <enumeratedValue>
                                    <name>1</name>
                                    <description>Comparison conditions are met.</description>
                                    <value>#1</value>
                                </enumeratedValue>
                            </enumeratedValues>
                        </field>
                        <field>
                            <name>CMPSTCHA09</name>
                            <description>Compare Window A Flag</description>
                            <lsb>9</lsb>
                            <msb>9</msb>
                            <access>read-write</access>
                            <enumeratedValues>
                                <enumeratedValue>
                                    <name>0</name>
                                    <description>Comparison conditions are not met.</description>
                                    <value>#0</value>
                                </enumeratedValue>
                                <enumeratedValue>
                                    <name>1</name>
                                    <description>Comparison conditions are met.</description>
                                    <value>#1</value>
                                </enumeratedValue>
                            </enumeratedValues>
                        </field>
                        <field>
                            <name>CMPSTCHA10</name>
                            <description>Compare Window A Flag</description>
                            <lsb>10</lsb>
                            <msb>10</msb>
                            <access>read-write</access>
                            <enumeratedValues>
                                <enumeratedValue>
                                    <name>0</name>
                                    <description>Comparison conditions are not met.</description>
                                    <value>#0</value>
                                </enumeratedValue>
                                <enumeratedValue>
                                    <name>1</name>
                                    <description>Comparison conditions are met.</description>
                                    <value>#1</value>
                                </enumeratedValue>
                            </enumeratedValues>
                        </field>
                        <field>
                            <name>CMPSTCHA11</name>
                            <description>Compare Window A Flag</description>
                            <lsb>11</lsb>
                            <msb>11</msb>
                            <access>read-write</access>
                            <enumeratedValues>
                                <enumeratedValue>
                                    <name>0</name>
                                    <description>Comparison conditions are not met.</description>
                                    <value>#0</value>
                                </enumeratedValue>
                                <enumeratedValue>
                                    <name>1</name>
                                    <description>Comparison conditions are met.</description>
                                    <value>#1</value>
                                </enumeratedValue>
                            </enumeratedValues>
                        </field>
                        <field>
                            <name>CMPSTCHA12</name>
                            <description>Compare Window A Flag</description>
                            <lsb>12</lsb>
                            <msb>12</msb>
                            <access>read-write</access>
                            <enumeratedValues>
                                <enumeratedValue>
                                    <name>0</name>
                                    <description>Comparison conditions are not met.</description>
                                    <value>#0</value>
                                </enumeratedValue>
                                <enumeratedValue>
                                    <name>1</name>
                                    <description>Comparison conditions are met.</description>
                                    <value>#1</value>
                                </enumeratedValue>
                            </enumeratedValues>
                        </field>
                        <field>
                            <name>CMPSTCHA13</name>
                            <description>Compare Window A Flag</description>
                            <lsb>13</lsb>
                            <msb>13</msb>
                            <access>read-write</access>
                            <enumeratedValues>
                                <enumeratedValue>
                                    <name>0</name>
                                    <description>Comparison conditions are not met.</description>
                                    <value>#0</value>
                                </enumeratedValue>
                                <enumeratedValue>
                                    <name>1</name>
                                    <description>Comparison conditions are met.</description>
                                    <value>#1</value>
                                </enumeratedValue>
                            </enumeratedValues>
                        </field>
                        <field>
                            <name>CMPSTCHA14</name>
                            <description>Compare Window A Flag</description>
                            <lsb>14</lsb>
                            <msb>14</msb>
                            <access>read-write</access>
                            <enumeratedValues>
                                <enumeratedValue>
                                    <name>0</name>
                                    <description>Comparison conditions are not met.</description>
                                    <value>#0</value>
                                </enumeratedValue>
                                <enumeratedValue>
                                    <name>1</name>
                                    <description>Comparison conditions are met.</description>
                                    <value>#1</value>
                                </enumeratedValue>
                            </enumeratedValues>
                        </field>
                        <field>
                            <name>CMPSTCHA15</name>
                            <description>Compare Window A Flag</description>
                            <lsb>15</lsb>
                            <msb>15</msb>
                            <access>read-write</access>
                            <enumeratedValues>
                                <enumeratedValue>
                                    <name>0</name>
                                    <description>Comparison conditions are not met.</description>
                                    <value>#0</value>
                                </enumeratedValue>
                                <enumeratedValue>
                                    <name>1</name>
                                    <description>Comparison conditions are met.</description>
                                    <value>#1</value>
                                </enumeratedValue>
                            </enumeratedValues>
                        </field>
                    </fields>
                </register>
                <register>
                    <name>ADCMPSER</name>
                    <description>A/D Compare Function Window A Extended Input Channel Status Register</description>
                    <addressOffset>0x0A4</addressOffset>
                    <size>8</size>
                    <access>read-write</access>
                    <resetValue>0x00</resetValue>
                    <resetMask>0xff</resetMask>
                    <fields>
                        <field>
                            <name>CMPSTTSA</name>
                            <description>Compare Window A Temperature Sensor Output Compare Flag</description>
                            <lsb>0</lsb>
                            <msb>0</msb>
                            <access>read-write</access>
                            <enumeratedValues>
                                <enumeratedValue>
                                    <name>0</name>
                                    <description>Comparison conditions are not met.</description>
                                    <value>#0</value>
                                </enumeratedValue>
                                <enumeratedValue>
                                    <name>1</name>
                                    <description>Comparison conditions are met.</description>
                                    <value>#1</value>
                                </enumeratedValue>
                            </enumeratedValues>
                        </field>
                        <field>
                            <name>CMPSTOCA</name>
                            <description>Compare Window A Internal Reference Voltage Compare Flag</description>
                            <lsb>1</lsb>
                            <msb>1</msb>
                            <access>read-write</access>
                            <enumeratedValues>
                                <enumeratedValue>
                                    <name>0</name>
                                    <description>Comparison conditions are not met.</description>
                                    <value>#0</value>
                                </enumeratedValue>
                                <enumeratedValue>
                                    <name>1</name>
                                    <description>Comparison conditions are met.</description>
                                    <value>#1</value>
                                </enumeratedValue>
                            </enumeratedValues>
                        </field>
                    </fields>
                </register>
                <register>
                    <name>ADCMPBNSR</name>
                    <description>A/D Compare Function Window B Channel Select Register</description>
                    <addressOffset>0x0A6</addressOffset>
                    <size>8</size>
                    <access>read-write</access>
                    <resetValue>0x00</resetValue>
                    <resetMask>0xff</resetMask>
                    <fields>
                        <field>
                            <name>CMPCHB</name>
                            <description>Compare Window B Channel Select</description>
                            <lsb>0</lsb>
                            <msb>5</msb>
                            <access>read-write</access>
                        </field>
                        <field>
                            <name>CMPLB</name>
                            <description>Compare Window B Comparison Condition Setting</description>
                            <lsb>7</lsb>
                            <msb>7</msb>
                            <access>read-write</access>
                            <enumeratedValues>
                                <enumeratedValue>
                                    <name>0</name>
                                    <description>When window function is disabled (ADCMPCR.WCMPE = 0): ADWINLLB value &gt; A/D-converted value When window function is enabled (ADCMPCR.WCMPE = 1): A/D-converted value &lt; ADWINLLB value, or ADWINULB value &lt; A/D-converted value </description>
                                    <value>#0</value>
                                </enumeratedValue>
                                <enumeratedValue>
                                    <name>1</name>
                                    <description>When window function is disabled (ADCMPCR.WCMPE = 0): ADWINLLB value &lt; A/D-converted value When window function is enabled (ADCMPCR.WCMPE = 1): ADWINLLB value &lt; A/D-converted value &lt; ADWINULB value </description>
                                    <value>#1</value>
                                </enumeratedValue>
                            </enumeratedValues>
                        </field>
                    </fields>
                </register>
                <register>
                    <name>ADWINLLB</name>
                    <description>A/D Compare Function Window B Lower-Side/Upper-Side Level Setting Register</description>
                    <addressOffset>0x0A8</addressOffset>
                    <size>16</size>
                    <access>read-write</access>
                    <resetValue>0x0000</resetValue>
                    <resetMask>0xffff</resetMask>
                </register>
                <register>
                    <name>ADWINULB</name>
                    <description>A/D Compare Function Window B Lower-Side/Upper-Side Level Setting Register</description>
                    <addressOffset>0x0AA</addressOffset>
                    <size>16</size>
                    <access>read-write</access>
                    <resetValue>0x0000</resetValue>
                    <resetMask>0xffff</resetMask>
                </register>
                <register>
                    <name>ADCMPBSR</name>
                    <description>A/D Compare Function Window B Status Register</description>
                    <addressOffset>0x0AC</addressOffset>
                    <size>8</size>
                    <access>read-write</access>
                    <resetValue>0x00</resetValue>
                    <resetMask>0xff</resetMask>
                    <fields>
                        <field>
                            <name>CMPSTB</name>
                            <description>Compare Window B Flag</description>
                            <lsb>0</lsb>
                            <msb>0</msb>
                            <access>read-write</access>
                            <enumeratedValues>
                                <enumeratedValue>
                                    <name>0</name>
                                    <description>Comparison conditions are not met.</description>
                                    <value>#0</value>
                                </enumeratedValue>
                                <enumeratedValue>
                                    <name>1</name>
                                    <description>Comparison conditions are met.</description>
                                    <value>#1</value>
                                </enumeratedValue>
                            </enumeratedValues>
                        </field>
                    </fields>
                </register>
                <register>
                    <dim>16</dim>
                    <dimIncrement>0x2</dimIncrement>
                    <dimIndex>0-15</dimIndex>
                    <name>ADBUF%s</name>
                    <description>A/D Data Buffer Registers %s</description>
                    <addressOffset>0x0B0</addressOffset>
                    <size>16</size>
                    <access>read-only</access>
                    <resetValue>0x0000</resetValue>
                    <resetMask>0xffff</resetMask>
                    <fields>
                        <field>
                            <name>ADBUF</name>
                            <description>Converted Value 15 to 0</description>
                            <lsb>0</lsb>
                            <msb>15</msb>
                            <access>read-only</access>
                        </field>
                    </fields>
                </register>
                <register>
                    <name>ADBUFEN</name>
                    <description>A/D Data Buffer Enable Register</description>
                    <addressOffset>0x0D0</addressOffset>
                    <size>8</size>
                    <access>read-write</access>
                    <resetValue>0x00</resetValue>
                    <resetMask>0xff</resetMask>
                    <fields>
                        <field>
                            <name>BUFEN</name>
                            <description>Data Buffer Enable</description>
                            <lsb>0</lsb>
                            <msb>0</msb>
                            <access>read-write</access>
                            <enumeratedValues>
                                <enumeratedValue>
                                    <name>0</name>
                                    <description>The data buffer is not used.</description>
                                    <value>#0</value>
                                </enumeratedValue>
                                <enumeratedValue>
                                    <name>1</name>
                                    <description>The data buffer is used.</description>
                                    <value>#1</value>
                                </enumeratedValue>
                            </enumeratedValues>
                        </field>
                    </fields>
                </register>
                <register>
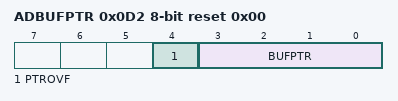
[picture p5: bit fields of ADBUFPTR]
                    <name>ADBUFPTR</name>
                    <description>A/D Data Buffer Pointer Register</description>
                    <addressOffset>0x0D2</addressOffset>
                    <size>8</size>
                    <access>read-write</access>
                    <resetValue>0x00</resetValue>
                    <resetMask>0xff</resetMask>
                    <fields>
                        <field>
                            <name>BUFPTR</name>
                            <description>Data Buffer Pointer</description>
                            <lsb>0</lsb>
                            <msb>3</msb>
                            <access>read-write</access>
                        </field>
                        <field>
                            <name>PTROVF</name>
                            <description>Pointer Overflow Flag</description>
                            <lsb>4</lsb>
                            <msb>4</msb>
                            <access>read-write</access>
                            <enumeratedValues>
                                <enumeratedValue>
                                    <name>0</name>
                                    <description>The data buffer pointer has not overflowed.</description>
                                    <value>#0</value>
                                </enumeratedValue>
                                <enumeratedValue>
                                    <name>1</name>
                                    <description>The data buffer pointer has overflowed.</description>
                                    <value>#1</value>
                                </enumeratedValue>
                            </enumeratedValues>
                        </field>
                    </fields>
                </register>
                <register>
                    <name>ADSSTRL</name>
                    <description>A/D Sampling State Register</description>
                    <addressOffset>0x0DD</addressOffset>
                    <size>8</size>
                    <access>read-write</access>
                    <resetValue>0x0b</resetValue>
                    <resetMask>0xff</resetMask>
                    <fields>
                        <field>
                            <name>SST</name>
                            <description>Sampling Time Setting</description>
                            <lsb>0</lsb>
                            <msb>7</msb>
                            <access>read-write</access>
                        </field>
                    </fields>
                </register>
                <register>
                    <name>ADSSTRT</name>
                    <description>A/D Sampling State Register</description>
                    <addressOffset>0x0DE</addressOffset>
                    <size>8</size>
                    <access>read-write</access>
                    <resetValue>0x0b</resetValue>
                    <resetMask>0xff</resetMask>
                    <fields>
                        <field>
                            <name>SST</name>
                            <description>Sampling Time Setting</description>
                            <lsb>0</lsb>
                            <msb>7</msb>
                            <access>read-write</access>
                        </field>
                    </fields>
                </register>
                <register>
                    <name>ADSSTRO</name>
                    <description>A/D Sampling State Register</description>
                    <addressOffset>0x0DF</addressOffset>
                    <size>8</size>
                    <access>read-write</access>
                    <resetValue>0x0b</resetValue>
                    <resetMask>0xff</resetMask>
                    <fields>
                        <field>
                            <name>SST</name>
                            <description>Sampling Time Setting</description>
                            <lsb>0</lsb>
                            <msb>7</msb>
                            <access>read-write</access>
                        </field>
                    </fields>
                </register>
                <register>
                    <dim>7</dim>
                    <dimIncrement>0x1</dimIncrement>
                    <dimIndex>0-6</dimIndex>
                    <name>ADSSTR%s</name>
                    <description>A/D Sampling State Register</description>
                    <addressOffset>0x0E0</addressOffset>
                    <size>8</size>
                    <access>read-write</access>
                    <resetValue>0x0b</resetValue>
                    <resetMask>0xff</resetMask>
                    <fields>
                        <field>
                            <name>SST</name>
                            <description>Sampling Time Setting</description>
                            <lsb>0</lsb>
                            <msb>7</msb>
                            <access>read-write</access>
                        </field>
                    </fields>
                </register>
                <register>
                    <name>ADSSTRV</name>
                    <description>A/D Sampling State Register</description>
                    <addressOffset>0x0E3</addressOffset>
                    <size>8</size>
                    <access>read-write</access>
                    <resetValue>0x0b</resetValue>
                    <resetMask>0xff</resetMask>
                    <fields>
                        <field>
                            <name>SST</name>
                            <description>Sampling Time Setting</description>
                            <lsb>0</lsb>
                            <msb>7</msb>
                            <access>read-write</access>
                        </field>
                    </fields>
                </register>
            </registers>
        </peripheral>
        <peripheral>
            <name>DAC12</name>
            <description>12-bit D/A converter</description>
            <baseAddress>0x40333000</baseAddress>
            <addressBlock>
                <offset>0x00</offset>
                <size>2</size>
                <usage>registers</usage>
            </addressBlock>
            <addressBlock>
                <offset>0x04</offset>
                <size>3</size>
                <usage>registers</usage>
            </addressBlock>
            <addressBlock>
                <offset>0x08</offset>
                <size>1</size>
                <usage>registers</usage>
            </addressBlock>
            <addressBlock>
                <offset>0x1C</offset>
                <size>1</size>
                <usage>registers</usage>
            </addressBlock>
            <addressBlock>
                <offset>0x10C0</offset>
                <size>1</size>
                <usage>registers</usage>
            </addressBlock>
            <registers>
                <register>
                    <dim>1</dim>
                    <dimIncrement>0x02</dimIncrement>
                    <dimIndex>0</dimIndex>
                    <name>DADR%s</name>
                    <description>D/A Data Register %s</description>
                    <addressOffset>0x00</addressOffset>
                    <size>16</size>
                    <access>read-write</access>
                    <resetValue>0x0000</resetValue>
                    <resetMask>0xffff</resetMask>
                </register>
                <register>
                    <name>DACR</name>
                    <description>D/A Control Register</description>
                    <addressOffset>0x04</addressOffset>
                    <size>8</size>
                    <access>read-write</access>
                    <resetValue>0x1f</resetValue>
                    <resetMask>0xff</resetMask>
                    <fields>
                        <field>
                            <name>DAOE0</name>
                            <description>D/A Output Enable 0</description>
                            <lsb>6</lsb>
                            <msb>6</msb>
                            <access>read-write</access>
                            <enumeratedValues>
                                <enumeratedValue>
                                    <name>0</name>
                                    <description>Disable analog output of channel 0 (DA0)</description>
                                    <value>#0</value>
                                </enumeratedValue>
                                <enumeratedValue>
                                    <name>1</name>
                                    <description>Enable D/A conversion of channel 0 (DA0)</description>
                                    <value>#1</value>
                                </enumeratedValue>
                            </enumeratedValues>
                        </field>
                    </fields>
                </register>
                <register>
                    <name>DADPR</name>
                    <description>DADRn Format Select Register</description>
                    <addressOffset>0x05</addressOffset>
                    <size>8</size>
                    <access>read-write</access>
                    <resetValue>0x00</resetValue>
                    <resetMask>0xff</resetMask>
                    <fields>
                        <field>
                            <name>DPSEL</name>
                            <description>DADRn Format Select</description>
                            <lsb>7</lsb>
                            <msb>7</msb>
                            <access>read-write</access>
                            <enumeratedValues>
                                <enumeratedValue>
                                    <name>0</name>
                                    <description>Right-justified format</description>
                                    <value>#0</value>
                                </enumeratedValue>
                                <enumeratedValue>
                                    <name>1</name>
                                    <description>Left-justified format</description>
                                    <value>#1</value>
                                </enumeratedValue>
                            </enumeratedValues>
                        </field>
                    </fields>
                </register>
                <register>
                    <name>DAADSCR</name>
                    <description>D/A A/D Synchronous Start Control Register</description>
                    <addressOffset>0x06</addressOffset>
                    <size>8</size>
                    <access>read-write</access>
                    <resetValue>0x00</resetValue>
                    <resetMask>0xff</resetMask>
                    <fields>
                        <field>
                            <name>DAADST</name>
                            <description>D/A A/D Synchronous Conversion</description>
                            <lsb>7</lsb>
                            <msb>7</msb>
                            <access>read-write</access>
                            <enumeratedValues>
                                <enumeratedValue>
                                    <name>0</name>
                                    <description>Do not synchronize DAC12 with ADC12 (unit 1) operation (disable interference reduction between D/A and A/D conversion).</description>
                                    <value>#0</value>
                                </enumeratedValue>
                                <enumeratedValue>
                                    <name>1</name>
                                    <description>Synchronize DAC12 with ADC12 (unit 1) operation (enable interference reduction between D/A and A/D conversion).</description>
                                    <value>#1</value>
                                </enumeratedValue>
                            </enumeratedValues>
                        </field>
                    </fields>
                </register>
                <register>
                    <name>DAAMPCR</name>
                    <description>D/A Output Amplifier Control Register</description>
                    <addressOffset>0x08</addressOffset>
                    <size>8</size>
                    <access>read-write</access>
                    <resetValue>0x00</resetValue>
                    <resetMask>0xff</resetMask>
                    <fields>
                        <field>
                            <name>DAAMP0</name>
                            <description>Amplifier Control 0</description>
                            <lsb>6</lsb>
                            <msb>6</msb>
                            <access>read-write</access>
                            <enumeratedValues>
                                <enumeratedValue>
                                    <name>0</name>
                                    <description>Do not use channel 0 output amplifier</description>
                                    <value>#0</value>
                                </enumeratedValue>
                                <enumeratedValue>
                                    <name>1</name>
                                    <description>Use channel 0 output amplifier</description>
                                    <value>#1</value>
                                </enumeratedValue>
                            </enumeratedValues>
                        </field>
                    </fields>
                </register>
                <register>
                    <name>DAASWCR</name>
                    <description>D/A Amplifier Stabilization Wait Control Register</description>
                    <addressOffset>0x1C</addressOffset>
                    <size>8</size>
                    <access>read-write</access>
                    <resetValue>0x00</resetValue>
                    <resetMask>0xff</resetMask>
                    <fields>
                        <field>
                            <name>DAASW0</name>
                            <description>D/A Amplifier Stabilization Wait 0 and D/A internal output control</description>
                            <lsb>6</lsb>
                            <msb>6</msb>
                            <access>read-write</access>
                            <enumeratedValues>
                                <enumeratedValue>
                                    <name>0</name>
                                    <description>For output to external pin: Amplifier stabilization wait off (output) for channel 0 For output to internal module: Disable output for channel 0 </description>
                                    <value>#0</value>
                                </enumeratedValue>
                                <enumeratedValue>
                                    <name>1</name>
                                    <description>For output to external pin: Amplifier stabilization wait on (high-Z) for channel 0 For output to internal module: Enable output for channel 0 </description>
                                    <value>#1</value>
                                </enumeratedValue>
                            </enumeratedValues>
                        </field>
                    </fields>
                </register>
                <register>
                    <name>DAADUSR</name>
                    <description>D/A A/D Synchronous Unit Select Register</description>
                    <addressOffset>0x10C0</addressOffset>
                    <size>8</size>
                    <access>read-write</access>
                    <resetValue>0x00</resetValue>
                    <resetMask>0xff</resetMask>
                    <fields>
                        <field>
                            <name>AMADSEL1</name>
                            <description>A/D Unit 1 Select</description>
                            <lsb>1</lsb>
                            <msb>1</msb>
                            <access>read-write</access>
                            <enumeratedValues>
                                <enumeratedValue>
                                    <name>0</name>
                                    <description>Do not select unit 1</description>
                                    <value>#0</value>
                                </enumeratedValue>
                                <enumeratedValue>
                                    <name>1</name>
                                    <description>Select unit 1</description>
                                    <value>#1</value>
                                </enumeratedValue>
                            </enumeratedValues>
                        </field>
                    </fields>
                </register>
            </registers>
        </peripheral>
        <peripheral>
            <name>CEU</name>
            <description>Capture Engine Unit</description>
            <baseAddress>0x40348000</baseAddress>
            <addressBlock>
                <offset>0x00</offset>
                <size>28</size>
                <usage>registers</usage>
            </addressBlock>
            <addressBlock>
                <offset>0x28</offset>
                <size>40</size>
                <usage>registers</usage>
            </addressBlock>
            <addressBlock>
                <offset>0x5C</offset>
                <size>12</size>
                <usage>registers</usage>
            </addressBlock>
            <addressBlock>
                <offset>0x70</offset>
                <size>8</size>
                <usage>registers</usage>
            </addressBlock>
            <addressBlock>
                <offset>0x7C</offset>
                <size>4</size>
                <usage>registers</usage>
            </addressBlock>
            <addressBlock>
                <offset>0x84</offset>
                <size>4</size>
                <usage>registers</usage>
            </addressBlock>
            <addressBlock>
                <offset>0x90</offset>
                <size>20</size>
                <usage>registers</usage>
            </addressBlock>
            <addressBlock>
                <offset>0x1010</offset>
                <size>8</size>
                <usage>registers</usage>
            </addressBlock>
            <addressBlock>
                <offset>0x1030</offset>
                <size>32</size>
                <usage>registers</usage>
            </addressBlock>
            <addressBlock>
                <offset>0x1060</offset>
                <size>8</size>
                <usage>registers</usage>
            </addressBlock>
            <addressBlock>
                <offset>0x1090</offset>
                <size>16</size>
                <usage>registers</usage>
            </addressBlock>
            <addressBlock>
                <offset>0x2010</offset>
                <size>8</size>
                <usage>registers</usage>
            </addressBlock>
            <addressBlock>
                <offset>0x2030</offset>
                <size>32</size>
                <usage>registers</usage>
            </addressBlock>
            <addressBlock>
                <offset>0x2060</offset>
                <size>8</size>
                <usage>registers</usage>
            </addressBlock>
            <addressBlock>
                <offset>0x2090</offset>
                <size>16</size>
                <usage>registers</usage>
            </addressBlock>
            <registers>
                <register>
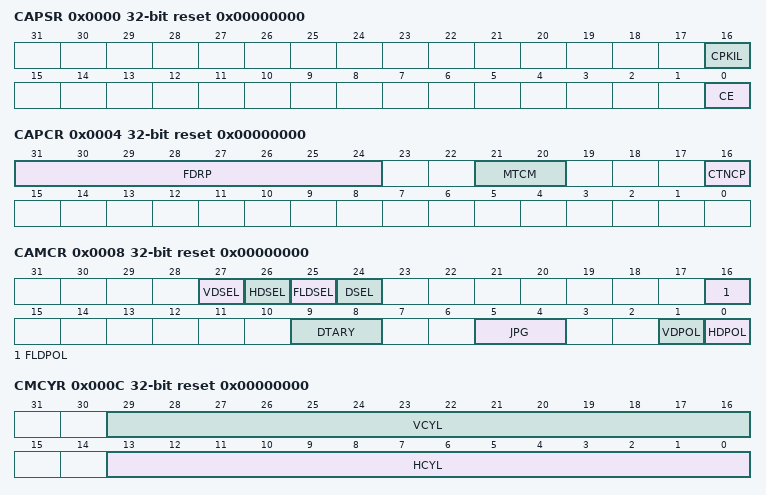
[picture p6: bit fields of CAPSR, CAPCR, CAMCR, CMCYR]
                    <name>CAPSR</name>
                    <description>Capture Start Register</description>
                    <addressOffset>0x0000</addressOffset>
                    <size>32</size>
                    <access>read-write</access>
                    <resetValue>0x00000000</resetValue>
                    <resetMask>0xffffffff</resetMask>
                    <fields>
                        <field>
                            <name>CE</name>
                            <description>Capture enable</description>
                            <lsb>0</lsb>
                            <msb>0</msb>
                            <access>read-write</access>
                            <enumeratedValues>
                                <enumeratedValue>
                                    <name>0</name>
                                    <description>Stops capturing</description>
                                    <value>#0</value>
                                </enumeratedValue>
                                <enumeratedValue>
                                    <name>1</name>
                                    <description>Starts capturing</description>
                                    <value>#1</value>
                                </enumeratedValue>
                            </enumeratedValues>
                        </field>
                        <field>
                            <name>CPKIL</name>
                            <description>Software reset of capturing</description>
                            <lsb>16</lsb>
                            <msb>16</msb>
                            <access>read-write</access>
                            <enumeratedValues>
                                <enumeratedValue>
                                    <name>0</name>
                                    <description>Normal state</description>
                                    <value>#0</value>
                                </enumeratedValue>
                                <enumeratedValue>
                                    <name>1</name>
                                    <description>Software reset of capturing</description>
                                    <value>#1</value>
                                </enumeratedValue>
                            </enumeratedValues>
                        </field>
                    </fields>
                </register>
                <register>
                    <name>CAPCR</name>
                    <description>Capture Control Register</description>
                    <addressOffset>0x0004</addressOffset>
                    <size>32</size>
                    <access>read-write</access>
                    <resetValue>0x00000000</resetValue>
                    <resetMask>0xffffffff</resetMask>
                    <fields>
                        <field>
                            <name>CTNCP</name>
                            <description>Continuous capture</description>
                            <lsb>16</lsb>
                            <msb>16</msb>
                            <access>read-write</access>
                            <enumeratedValues>
                                <enumeratedValue>
                                    <name>0</name>
                                    <description>One-frame capture when CAPSR.CE = 1</description>
                                    <value>#0</value>
                                </enumeratedValue>
                                <enumeratedValue>
                                    <name>1</name>
                                    <description>Continuous capture until CAPSR.CE = 0</description>
                                    <value>#1</value>
                                </enumeratedValue>
                            </enumeratedValues>
                        </field>
                        <field>
                            <name>MTCM</name>
                            <description>Specify the unit for transferring data to a bus bridge module.</description>
                            <lsb>20</lsb>
                            <msb>21</msb>
                            <access>read-write</access>
                            <enumeratedValues>
                                <enumeratedValue>
                                    <name>00</name>
                                    <description>Image capture: Y data and C data are transferred in 32-byte units Data fetch : Data is transferred in 32-byte units </description>
                                    <value>#00</value>
                                </enumeratedValue>
                                <enumeratedValue>
                                    <name>01</name>
                                    <description>Image capture: Y data and C data are transferred in 64-byte units Data fetch : Data is transferred in 64-byte </description>
                                    <value>#01</value>
                                </enumeratedValue>
                                <enumeratedValue>
                                    <name>10</name>
                                    <description>Image capture: Y data and C data are transferred in 128-byte units Data fetch : Data is transferred in 128-byte </description>
                                    <value>#10</value>
                                </enumeratedValue>
                                <enumeratedValue>
                                    <name>11</name>
                                    <description>Image capture: Y data and C data are transferred in 256-byte units Data fetch : Data is transferred in 256-byte </description>
                                    <value>#11</value>
                                </enumeratedValue>
                            </enumeratedValues>
                        </field>
                        <field>
                            <name>FDRP</name>
                            <description>Set the frame drop interval in continuous-frame capture.</description>
                            <lsb>24</lsb>
                            <msb>31</msb>
                            <access>read-write</access>
                        </field>
                    </fields>
                </register>
                <register>
                    <name>CAMCR</name>
                    <description>Capture Interface Control Register</description>
                    <addressOffset>0x0008</addressOffset>
                    <size>32</size>
                    <access>read-write</access>
                    <resetValue>0x00000000</resetValue>
                    <resetMask>0xffffffff</resetMask>
                    <fields>
                        <field>
                            <name>HDPOL</name>
                            <description>Sets the polarity for detection of the horizontal sync signal (HD) input from an external module.</description>
                            <lsb>0</lsb>
                            <msb>0</msb>
                            <access>read-write</access>
                            <enumeratedValues>
                                <enumeratedValue>
                                    <name>0</name>
                                    <description>Horizontal sync signal (HD) from an external module is detected as high active</description>
                                    <value>#0</value>
                                </enumeratedValue>
                                <enumeratedValue>
                                    <name>1</name>
                                    <description>Horizontal sync signal (HD) from an external module is detected as low active</description>
                                    <value>#1</value>
                                </enumeratedValue>
                            </enumeratedValues>
                        </field>
                        <field>
                            <name>VDPOL</name>
                            <description>Sets the polarity for detection of the vertical sync signal (VD) input from an external module.</description>
                            <lsb>1</lsb>
                            <msb>1</msb>
                            <access>read-write</access>
                            <enumeratedValues>
                                <enumeratedValue>
                                    <name>0</name>
                                    <description>Vertical sync signal (VD) from an external module is detected as high active</description>
                                    <value>#0</value>
                                </enumeratedValue>
                                <enumeratedValue>
                                    <name>1</name>
                                    <description>Vertical sync signal (VD) from an external module is detected as low active</description>
                                    <value>#1</value>
                                </enumeratedValue>
                            </enumeratedValues>
                        </field>
                        <field>
                            <name>JPG</name>
                            <description>These bits select the fetched data type.</description>
                            <lsb>4</lsb>
                            <msb>5</msb>
                            <access>read-write</access>
                            <enumeratedValues>
                                <enumeratedValue>
                                    <name>00</name>
                                    <description>Image capture mode (input data are separated into the luminance component data (Y) and the chrominance component data (CbCr) for output to the memory) </description>
                                    <value>#00</value>
                                </enumeratedValue>
                                <enumeratedValue>
                                    <name>01</name>
                                    <description>Data synchronous fetch mode (specified size of input data are output to the specified memory addresses in order of input and in synchronization with the sync signal) </description>
                                    <value>#01</value>
                                </enumeratedValue>
                                <enumeratedValue>
                                    <name>10</name>
                                    <description>Data enable fetch mode (input data are fetched with HD as an enable signal and output to the specified addresses in memory in order of input) </description>
                                    <value>#10</value>
                                </enumeratedValue>
                                <enumeratedValue>
                                    <name>11</name>
                                    <description>Setting prohibited</description>
                                    <value>#11</value>
                                </enumeratedValue>
                            </enumeratedValues>
                        </field>
                        <field>
                            <name>DTARY</name>
                            <description>Set the input order of the luminance component and chrominance component.</description>
                            <lsb>8</lsb>
                            <msb>9</msb>
                            <access>read-write</access>
                            <enumeratedValues>
                                <enumeratedValue>
                                    <name>00</name>
                                    <description>Image input data is fetched in the order of Cb0, Y0, Cr0, and Y1 </description>
                                    <value>#00</value>
                                </enumeratedValue>
                                <enumeratedValue>
                                    <name>01</name>
                                    <description>Image input data is fetched in the order of Cr0, Y0, Cb0, and Y1 </description>
                                    <value>#01</value>
                                </enumeratedValue>
                                <enumeratedValue>
                                    <name>10</name>
                                    <description>Image input data is fetched in the order of Y0, Cb0, Y1, and Cr0 </description>
                                    <value>#10</value>
                                </enumeratedValue>
                                <enumeratedValue>
                                    <name>11</name>
                                    <description>Image input data is fetched in the order of Y0, Cr0, Y1, and Cb0 </description>
                                    <value>#11</value>
                                </enumeratedValue>
                            </enumeratedValues>
                        </field>
                        <field>
                            <name>FLDPOL</name>
                            <description>Sets the polarity of the field identification signal (FLD) from an external module.</description>
                            <lsb>16</lsb>
                            <msb>16</msb>
                            <access>read-write</access>
                            <enumeratedValues>
                                <enumeratedValue>
                                    <name>0</name>
                                    <description>When the FLD signal is high-active, the field is detected as the top field and when low-active, the field is detected as the bottom field. </description>
                                    <value>#0</value>
                                </enumeratedValue>
                                <enumeratedValue>
                                    <name>1</name>
                                    <description>When the FLD signal is low-active, the field is detected as the top field and when high-active, the field is detected as the bottom field. </description>
                                    <value>#1</value>
                                </enumeratedValue>
                            </enumeratedValues>
                        </field>
                        <field>
                            <name>DSEL</name>
                            <description>Sets the edge for fetching the image data (D7 to D0) from an external module.</description>
                            <lsb>24</lsb>
                            <msb>24</msb>
                            <access>read-write</access>
                            <enumeratedValues>
                                <enumeratedValue>
                                    <name>0</name>
                                    <description>D7 to D0 are fetched at the rising edge of the camera clock.</description>
                                    <value>#0</value>
                                </enumeratedValue>
                                <enumeratedValue>
                                    <name>1</name>
                                    <description>D7 to D0 are fetched at the falling edge of the camera clock.</description>
                                    <value>#1</value>
                                </enumeratedValue>
                            </enumeratedValues>
                        </field>
                        <field>
                            <name>FLDSEL</name>
                            <description>Sets the edge for capturing FLD from an external module.</description>
                            <lsb>25</lsb>
                            <msb>25</msb>
                            <access>read-write</access>
                            <enumeratedValues>
                                <enumeratedValue>
                                    <name>0</name>
                                    <description>FLD is captured at the rising edge of the camera clock.</description>
                                    <value>#0</value>
                                </enumeratedValue>
                                <enumeratedValue>
                                    <name>1</name>
                                    <description>FLD is captured at the falling edge of the camera clock.</description>
                                    <value>#1</value>
                                </enumeratedValue>
                            </enumeratedValues>
                        </field>
                        <field>
                            <name>HDSEL</name>
                            <description>Sets the edge for capturing HD from an external module.</description>
                            <lsb>26</lsb>
                            <msb>26</msb>
                            <access>read-write</access>
                            <enumeratedValues>
                                <enumeratedValue>
                                    <name>0</name>
                                    <description>HD is captured at the rising edge of the camera clock.</description>
                                    <value>#0</value>
                                </enumeratedValue>
                                <enumeratedValue>
                                    <name>1</name>
                                    <description>HD is captured at the falling edge of the camera clock.</description>
                                    <value>#1</value>
                                </enumeratedValue>
                            </enumeratedValues>
                        </field>
                        <field>
                            <name>VDSEL</name>
                            <description>Sets the edge for capturing VD from an external module.</description>
                            <lsb>27</lsb>
                            <msb>27</msb>
                            <access>read-write</access>
                            <enumeratedValues>
                                <enumeratedValue>
                                    <name>0</name>
                                    <description>VD is captured at the rising edge of the camera clock.</description>
                                    <value>#0</value>
                                </enumeratedValue>
                                <enumeratedValue>
                                    <name>1</name>
                                    <description>VD is captured at the falling edge of the camera clock.</description>
                                    <value>#1</value>
                                </enumeratedValue>
                            </enumeratedValues>
                        </field>
                    </fields>
                </register>
                <register>
                    <name>CMCYR</name>
                    <description>Capture Interface Cycle Register</description>
                    <addressOffset>0x000C</addressOffset>
                    <size>32</size>
                    <access>read-write</access>
                    <resetValue>0x00000000</resetValue>
                    <resetMask>0xffffffff</resetMask>
                    <fields>
                        <field>
                            <name>HCYL</name>
                            <description>Horizontal Cycle Count of External Module</description>
                            <lsb>0</lsb>
                            <msb>13</msb>
                            <access>read-write</access>
                        </field>
                        <field>
                            <name>VCYL</name>
                            <description>Vertical HD Count of External Module</description>
                            <lsb>16</lsb>
                            <msb>29</msb>
                            <access>read-write</access>
                        </field>
                    </fields>
                </register>
                <register>
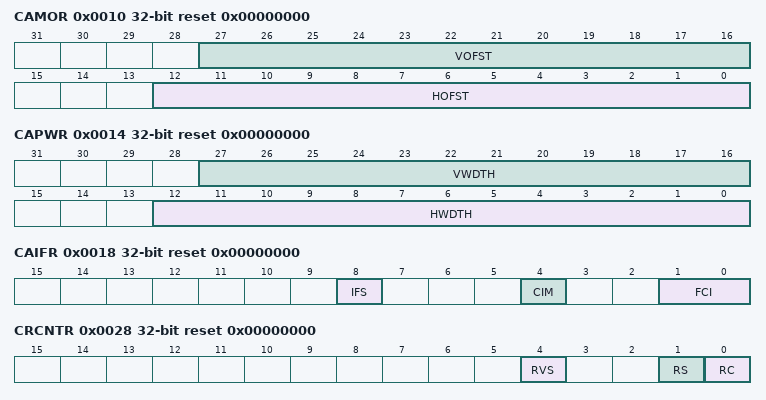
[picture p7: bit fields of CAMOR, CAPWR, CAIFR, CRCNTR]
                    <name>CAMOR</name>
                    <description>Capture Interface Offset Register</description>
                    <addressOffset>0x0010</addressOffset>
                    <size>32</size>
                    <access>read-write</access>
                    <resetValue>0x00000000</resetValue>
                    <resetMask>0xffffffff</resetMask>
                    <fields>
                        <field>
                            <name>HOFST</name>
                            <description>Specify the capture start location in terms of the number of clock cycles from a horizontal sync signal (1-cycle units).</description>
                            <lsb>0</lsb>
                            <msb>12</msb>
                            <access>read-write</access>
                        </field>
                        <field>
                            <name>VOFST</name>
                            <description>Specify the capture start location in terms of the HD count from a vertical sync signal (1-HD units).</description>
                            <lsb>16</lsb>
                            <msb>27</msb>
                            <access>read-write</access>
                        </field>
                    </fields>
                </register>
                <register>
                    <name>CAPWR</name>
                    <description>Capture Interface Width Register</description>
                    <addressOffset>0x0014</addressOffset>
                    <size>32</size>
                    <access>read-write</access>
                    <resetValue>0x00000000</resetValue>
                    <resetMask>0xffffffff</resetMask>
                    <fields>
                        <field>
                            <name>HWDTH</name>
                            <description>Specify the horizontal capture period.</description>
                            <lsb>0</lsb>
                            <msb>12</msb>
                            <access>read-write</access>
                        </field>
                        <field>
                            <name>VWDTH</name>
                            <description>Specify the vertical capture period (4-HD units).</description>
                            <lsb>16</lsb>
                            <msb>27</msb>
                            <access>read-write</access>
                        </field>
                    </fields>
                </register>
                <register>
                    <name>CAIFR</name>
                    <description>Capture Interface Input Format Register</description>
                    <addressOffset>0x0018</addressOffset>
                    <size>32</size>
                    <access>read-write</access>
                    <resetValue>0x00000000</resetValue>
                    <resetMask>0xffffffff</resetMask>
                    <fields>
                        <field>
                            <name>FCI</name>
                            <description>Set the timing to start capturing.</description>
                            <lsb>0</lsb>
                            <msb>1</msb>
                            <access>read-write</access>
                            <enumeratedValues>
                                <enumeratedValue>
                                    <name>00</name>
                                    <description>Capture starts from the VD input immediately after the CEU activation regardless of it being a top or bottom field </description>
                                    <value>#00</value>
                                </enumeratedValue>
                                <enumeratedValue>
                                    <name>01</name>
                                    <description>After the CEU activation, input of a top-field image is waited, and then capture starts from the top field </description>
                                    <value>#01</value>
                                </enumeratedValue>
                                <enumeratedValue>
                                    <name>10</name>
                                    <description>After the CEU activation, input of a bottom-field image is waited, and then capture starts from the bottom field </description>
                                    <value>#10</value>
                                </enumeratedValue>
                                <enumeratedValue>
                                    <name>11</name>
                                    <description>Setting prohibited</description>
                                    <value>#11</value>
                                </enumeratedValue>
                            </enumeratedValues>
                        </field>
                        <field>
                            <name>CIM</name>
                            <description>Sets the images to be captured.</description>
                            <lsb>4</lsb>
                            <msb>4</msb>
                            <access>read-write</access>
                            <enumeratedValues>
                                <enumeratedValue>
                                    <name>0</name>
                                    <description>Capture of frame image (1 VD) or both-field image (2 VD)</description>
                                    <value>#0</value>
                                </enumeratedValue>
                                <enumeratedValue>
                                    <name>1</name>
                                    <description>Capture of one-field image (1 VD)</description>
                                    <value>#1</value>
                                </enumeratedValue>
                            </enumeratedValues>
                        </field>
                        <field>
                            <name>IFS</name>
                            <description>Sets the input mode for capturing images.</description>
                            <lsb>8</lsb>
                            <msb>8</msb>
                            <access>read-write</access>
                            <enumeratedValues>
                                <enumeratedValue>
                                    <name>0</name>
                                    <description>Progressive</description>
                                    <value>#0</value>
                                </enumeratedValue>
                                <enumeratedValue>
                                    <name>1</name>
                                    <description>Interlace</description>
                                    <value>#1</value>
                                </enumeratedValue>
                            </enumeratedValues>
                        </field>
                    </fields>
                </register>
                <register>
                    <name>CRCNTR</name>
                    <description>CEU Register Control Register</description>
                    <addressOffset>0x0028</addressOffset>
                    <size>32</size>
                    <access>read-write</access>
                    <resetValue>0x00000000</resetValue>
                    <resetMask>0xffffffff</resetMask>
                    <fields>
                        <field>
                            <name>RC</name>
                            <description>Specifies switching of the register plane used by the CEU in synchronization with VD.</description>
                            <lsb>0</lsb>
                            <msb>0</msb>
                            <access>read-write</access>
                            <enumeratedValues>
                                <enumeratedValue>
                                    <name>0</name>
                                    <description>Uses the specified register plane in synchronization with VD</description>
                                    <value>#0</value>
                                </enumeratedValue>
                                <enumeratedValue>
                                    <name>1</name>
                                    <description>Switches the register plane in synchronization with VD</description>
                                    <value>#1</value>
                                </enumeratedValue>
                            </enumeratedValues>
                        </field>
                        <field>
                            <name>RS</name>
                            <description>Specifies which register plane is used by the CEU in synchronization with VD.</description>
                            <lsb>1</lsb>
                            <msb>1</msb>
                            <access>read-write</access>
                            <enumeratedValues>
                                <enumeratedValue>
                                    <name>0</name>
                                    <description>Uses plane A of the register</description>
                                    <value>#0</value>
                                </enumeratedValue>
                                <enumeratedValue>
                                    <name>1</name>
                                    <description>Uses plane B of the register</description>
                                    <value>#1</value>
                                </enumeratedValue>
                            </enumeratedValues>
                        </field>
                        <field>
                            <name>RVS</name>
                            <description>Sets the timing to switch the register plane in both-field capture.</description>
                            <lsb>4</lsb>
                            <msb>4</msb>
                            <access>read-write</access>
                            <enumeratedValues>
                                <enumeratedValue>
                                    <name>0</name>
                                    <description>Switches the register plane every 2 VD</description>
                                    <value>#0</value>
                                </enumeratedValue>
                                <enumeratedValue>
                                    <name>1</name>
                                    <description>Switches the register plane every 1 VD</description>
                                    <value>#1</value>
                                </enumeratedValue>
                            </enumeratedValues>
                        </field>
                    </fields>
                </register>
                <register>
                    <name>CRCMPR</name>
                    <description>CEU Register Forcible Control Register</description>
                    <addressOffset>0x002C</addressOffset>
                    <size>32</size>
                    <access>read-write</access>
                    <resetValue>0x00000000</resetValue>
                    <resetMask>0xffffffff</resetMask>
                    <fields>
                        <field>
                            <name>RA</name>
                            <description>Indicates the register plane currently specified.</description>
                            <lsb>0</lsb>
                            <msb>0</msb>
                            <access>read-write</access>
                            <enumeratedValues>
                                <enumeratedValue>
                                    <name>0</name>
                                    <description>Specifies plane A of the register</description>
                                    <value>#0</value>
                                </enumeratedValue>
                                <enumeratedValue>
                                    <name>1</name>
                                    <description>Specifies plane B of the register</description>
                                    <value>#1</value>
                                </enumeratedValue>
                            </enumeratedValues>
                        </field>
                    </fields>
                </register>
                <register>
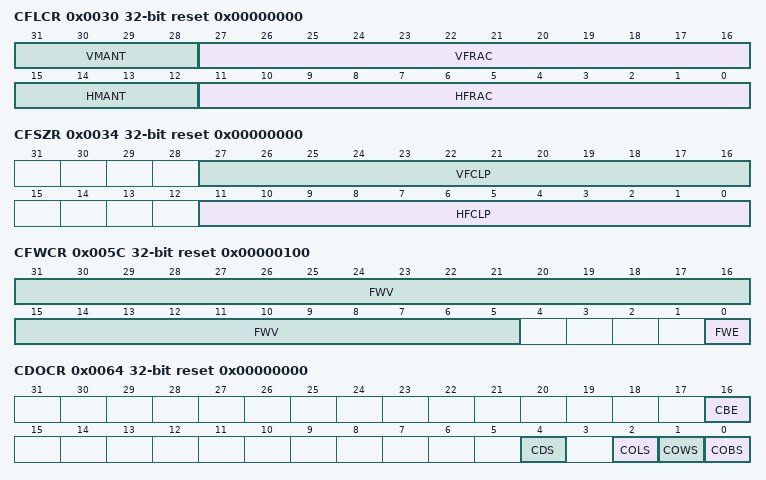
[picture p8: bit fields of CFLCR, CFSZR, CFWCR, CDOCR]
                    <name>CFLCR</name>
                    <description>Capture Filter Control Register</description>
                    <addressOffset>0x0030</addressOffset>
                    <size>32</size>
                    <access>read-write</access>
                    <resetValue>0x00000000</resetValue>
                    <resetMask>0xffffffff</resetMask>
                    <fields>
                        <field>
                            <name>HFRAC</name>
                            <description>Fraction Part of Horizontal Scale-Down Factor</description>
                            <lsb>0</lsb>
                            <msb>11</msb>
                            <access>read-write</access>
                        </field>
                        <field>
                            <name>HMANT</name>
                            <description>Mantissa Part of Horizontal Scale-Down Factor</description>
                            <lsb>12</lsb>
                            <msb>15</msb>
                            <access>read-write</access>
                        </field>
                        <field>
                            <name>VFRAC</name>
                            <description>Fraction Part of Vertical Scale-Down Factor</description>
                            <lsb>16</lsb>
                            <msb>27</msb>
                            <access>read-write</access>
                        </field>
                        <field>
                            <name>VMANT</name>
                            <description>Mantissa Part of Vertical Scale-Down Factor</description>
                            <lsb>28</lsb>
                            <msb>31</msb>
                            <access>read-write</access>
                        </field>
                    </fields>
                </register>
                <register>
                    <name>CFSZR</name>
                    <description>Capture Filter Size Clip Register</description>
                    <addressOffset>0x0034</addressOffset>
                    <size>32</size>
                    <access>read-write</access>
                    <resetValue>0x00000000</resetValue>
                    <resetMask>0xffffffff</resetMask>
                    <fields>
                        <field>
                            <name>HFCLP</name>
                            <description>Specify the horizontal clipping value of the filter output size (8-pixel units).</description>
                            <lsb>0</lsb>
                            <msb>11</msb>
                            <access>read-write</access>
                        </field>
                        <field>
                            <name>VFCLP</name>
                            <description>Specify the vertical clipping value of the filter output size (4-pixel units).</description>
                            <lsb>16</lsb>
                            <msb>27</msb>
                            <access>read-write</access>
                        </field>
                    </fields>
                </register>
                <register>
                    <name>CDWDR</name>
                    <description>Capture Destination Width Register</description>
                    <addressOffset>0x0038</addressOffset>
                    <size>32</size>
                    <access>read-write</access>
                    <resetValue>0x00000000</resetValue>
                    <resetMask>0xffffffff</resetMask>
                    <fields>
                        <field>
                            <name>CHDW</name>
                            <description>Specify the horizontal image size in the memory area where the captured image is to be stored (8-byte units).</description>
                            <lsb>0</lsb>
                            <msb>12</msb>
                            <access>read-write</access>
                        </field>
                    </fields>
                </register>
                <register>
                    <name>CDAYR</name>
                    <description>Capture Data Address Y Register</description>
                    <addressOffset>0x003C</addressOffset>
                    <size>32</size>
                    <access>read-write</access>
                    <resetValue>0x00000000</resetValue>
                    <resetMask>0xffffffff</resetMask>
                    <fields>
                        <field>
                            <name>CAYR</name>
                            <description>Capture Data Address Y</description>
                            <lsb>0</lsb>
                            <msb>31</msb>
                            <access>read-write</access>
                        </field>
                    </fields>
                </register>
                <register>
                    <name>CDACR</name>
                    <description>Capture Data Address C Register</description>
                    <addressOffset>0x0040</addressOffset>
                    <size>32</size>
                    <access>read-write</access>
                    <resetValue>0x00000000</resetValue>
                    <resetMask>0xffffffff</resetMask>
                    <fields>
                        <field>
                            <name>CACR</name>
                            <description>Capture Data Address C</description>
                            <lsb>0</lsb>
                            <msb>31</msb>
                            <access>read-write</access>
                        </field>
                    </fields>
                </register>
                <register>
                    <name>CDBYR</name>
                    <description>Capture Data Bottom-Field Address Y Register</description>
                    <addressOffset>0x0044</addressOffset>
                    <size>32</size>
                    <access>read-write</access>
                    <resetValue>0x00000000</resetValue>
                    <resetMask>0xffffffff</resetMask>
                    <fields>
                        <field>
                            <name>CBYR</name>
                            <description>Set the address for storing the luminance component data of the captured bottom-field data (8-pixel units).</description>
                            <lsb>0</lsb>
                            <msb>31</msb>
                            <access>read-write</access>
                        </field>
                    </fields>
                </register>
                <register>
                    <name>CDBCR</name>
                    <description>Capture Data Bottom-Field Address C Register</description>
                    <addressOffset>0x0048</addressOffset>
                    <size>32</size>
                    <access>read-write</access>
                    <resetValue>0x00000000</resetValue>
                    <resetMask>0xffffffff</resetMask>
                    <fields>
                        <field>
                            <name>CBCR</name>
                            <description>Set the address for storing the chrominance component data of the captured bottom-field data (8-pixel units).</description>
                            <lsb>0</lsb>
                            <msb>31</msb>
                            <access>read-write</access>
                        </field>
                    </fields>
                </register>
                <register>
                    <name>CBDSR</name>
                    <description>Capture Bundle Destination Size Register</description>
                    <addressOffset>0x004C</addressOffset>
                    <size>32</size>
                    <access>read-write</access>
                    <resetValue>0x00000000</resetValue>
                    <resetMask>0xffffffff</resetMask>
                    <fields>
                        <field>
                            <name>CBVS</name>
                            <description>Select the number of lines or number of bytes for output to the memory in a bundle write.</description>
                            <lsb>0</lsb>
                            <msb>22</msb>
                            <access>read-write</access>
                        </field>
                    </fields>
                </register>
                <register>
                    <name>CFWCR</name>
                    <description>Firewall Operation Control Register</description>
                    <addressOffset>0x005C</addressOffset>
                    <size>32</size>
                    <access>read-write</access>
                    <resetValue>0x00000100</resetValue>
                    <resetMask>0xffffffff</resetMask>
                    <fields>
                        <field>
                            <name>FWE</name>
                            <description>Firewall Operation</description>
                            <lsb>0</lsb>
                            <msb>0</msb>
                            <access>read-write</access>
                            <enumeratedValues>
                                <enumeratedValue>
                                    <name>0</name>
                                    <description>Firewall is not activated.</description>
                                    <value>#0</value>
                                </enumeratedValue>
                                <enumeratedValue>
                                    <name>1</name>
                                    <description>Firewall is activated.</description>
                                    <value>#1</value>
                                </enumeratedValue>
                            </enumeratedValues>
                        </field>
                        <field>
                            <name>FWV</name>
                            <description>Specify the upper limit of a write address.</description>
                            <lsb>5</lsb>
                            <msb>31</msb>
                            <access>read-write</access>
                        </field>
                    </fields>
                </register>
                <register>
                    <name>CLFCR</name>
                    <description>Capture Low-Pass Filter Control Register</description>
                    <addressOffset>0x0060</addressOffset>
                    <size>32</size>
                    <access>read-write</access>
                    <resetValue>0x00000000</resetValue>
                    <resetMask>0xffffffff</resetMask>
                    <fields>
                        <field>
                            <name>LPF</name>
                            <description>Enables or disables operation of the low-pass filter.</description>
                            <lsb>0</lsb>
                            <msb>0</msb>
                            <access>read-write</access>
                            <enumeratedValues>
                                <enumeratedValue>
                                    <name>0</name>
                                    <description>Low-pass filter not used</description>
                                    <value>#0</value>
                                </enumeratedValue>
                                <enumeratedValue>
                                    <name>1</name>
                                    <description>Low-pass filter used (only in the horizontal direction)</description>
                                    <value>#1</value>
                                </enumeratedValue>
                            </enumeratedValues>
                        </field>
                    </fields>
                </register>
                <register>
                    <name>CDOCR</name>
                    <description>Capture Data Output Control Register</description>
                    <addressOffset>0x0064</addressOffset>
                    <size>32</size>
                    <access>read-write</access>
                    <resetValue>0x00000000</resetValue>
                    <resetMask>0xffffffff</resetMask>
                    <fields>
                        <field>
                            <name>COBS</name>
                            <description>Controls swapping in 8-bit units for data output from the CEU.</description>
                            <lsb>0</lsb>
                            <msb>0</msb>
                            <access>read-write</access>
                            <enumeratedValues>
                                <enumeratedValue>
                                    <name>0</name>
                                    <description>Data is not swapped in 8-bit units</description>
                                    <value>#0</value>
                                </enumeratedValue>
                                <enumeratedValue>
                                    <name>1</name>
                                    <description>Data is swapped in 8-bit units</description>
                                    <value>#1</value>
                                </enumeratedValue>
                            </enumeratedValues>
                        </field>
                        <field>
                            <name>COWS</name>
                            <description>Controls swapping in 16-bit units for data output from the CEU.</description>
                            <lsb>1</lsb>
                            <msb>1</msb>
                            <access>read-write</access>
                            <enumeratedValues>
                                <enumeratedValue>
                                    <name>0</name>
                                    <description>Data is not swapped in 16-bit units</description>
                                    <value>#0</value>
                                </enumeratedValue>
                                <enumeratedValue>
                                    <name>1</name>
                                    <description>Data is swapped in 16-bit units</description>
                                    <value>#1</value>
                                </enumeratedValue>
                            </enumeratedValues>
                        </field>
                        <field>
                            <name>COLS</name>
                            <description>Controls swapping in 32-bit units for data output from the CEU.</description>
                            <lsb>2</lsb>
                            <msb>2</msb>
                            <access>read-write</access>
                            <enumeratedValues>
                                <enumeratedValue>
                                    <name>0</name>
                                    <description>Data is not swapped in 32-bit units</description>
                                    <value>#0</value>
                                </enumeratedValue>
                                <enumeratedValue>
                                    <name>1</name>
                                    <description>Data is swapped in 32-bit units</description>
                                    <value>#1</value>
                                </enumeratedValue>
                            </enumeratedValues>
                        </field>
                        <field>
                            <name>CDS</name>
                            <description>Sets the image format when outputting the image data captured in the YCbCr422 format to the memory.</description>
                            <lsb>4</lsb>
                            <msb>4</msb>
                            <access>read-write</access>
                            <enumeratedValues>
                                <enumeratedValue>
                                    <name>0</name>
                                    <description>Converts the YCbCr422 format to the YCbCr420 format before outputting data to the memory</description>
                                    <value>#0</value>
                                </enumeratedValue>
                                <enumeratedValue>
                                    <name>1</name>
                                    <description>Outputs data in the YCbCr422 format to the memory without conversion</description>
                                    <value>#1</value>
                                </enumeratedValue>
                            </enumeratedValues>
                        </field>
                        <field>
                            <name>CBE</name>
                            <description> Controls the number of lines of captured data to be written to the memory.</description>
                            <lsb>16</lsb>
                            <msb>16</msb>
                            <access>read-write</access>
                            <enumeratedValues>
                                <enumeratedValue>
                                    <name>0</name>
                                    <description>Normal write</description>
                                    <value>#0</value>
                                </enumeratedValue>
                                <enumeratedValue>
                                    <name>1</name>
                                    <description>Bundle write</description>
                                    <value>#1</value>
                                </enumeratedValue>
                            </enumeratedValues>
                        </field>
                    </fields>
                </register>
                <register>
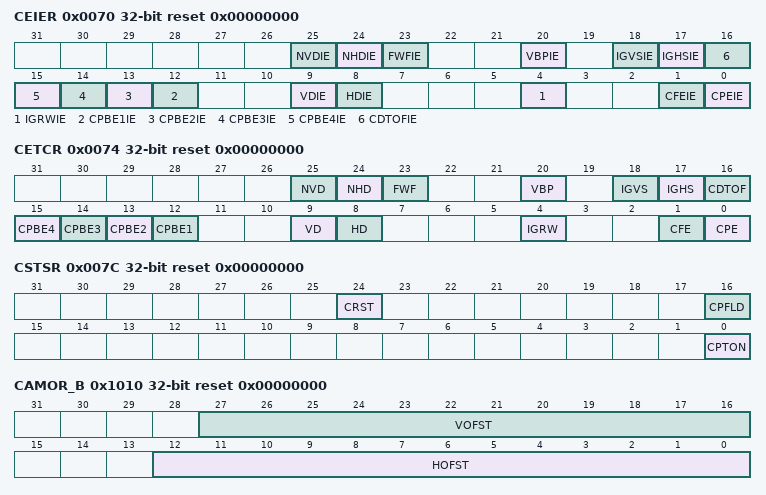
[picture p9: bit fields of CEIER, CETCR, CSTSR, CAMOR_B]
                    <name>CEIER</name>
                    <description>Capture Event Interrupt Enable Register</description>
                    <addressOffset>0x0070</addressOffset>
                    <size>32</size>
                    <access>read-write</access>
                    <resetValue>0x00000000</resetValue>
                    <resetMask>0xffffffff</resetMask>
                    <fields>
                        <field>
                            <name>CPEIE</name>
                            <description>One-Frame Capture End Interrupt Enable</description>
                            <lsb>0</lsb>
                            <msb>0</msb>
                            <access>read-write</access>
                            <enumeratedValues>
                                <enumeratedValue>
                                    <name>0</name>
                                    <description>Disables a one-frame capture end interrupt</description>
                                    <value>#0</value>
                                </enumeratedValue>
                                <enumeratedValue>
                                    <name>1</name>
                                    <description>Enables a one-frame capture end interrupt</description>
                                    <value>#1</value>
                                </enumeratedValue>
                            </enumeratedValues>
                        </field>
                        <field>
                            <name>CFEIE</name>
                            <description>CFE Interrupt Enable</description>
                            <lsb>1</lsb>
                            <msb>1</msb>
                            <access>read-write</access>
                            <enumeratedValues>
                                <enumeratedValue>
                                    <name>0</name>
                                    <description>Disables a CFE interrupt</description>
                                    <value>#0</value>
                                </enumeratedValue>
                                <enumeratedValue>
                                    <name>1</name>
                                    <description>Enables a CFE interrupt</description>
                                    <value>#1</value>
                                </enumeratedValue>
                            </enumeratedValues>
                        </field>
                        <field>
                            <name>IGRWIE</name>
                            <description>Register-Access-During-Capture Interrupt Enable</description>
                            <lsb>4</lsb>
                            <msb>4</msb>
                            <access>read-write</access>
                            <enumeratedValues>
                                <enumeratedValue>
                                    <name>0</name>
                                    <description>Disables a register-access-during-capture interrupt</description>
                                    <value>#0</value>
                                </enumeratedValue>
                                <enumeratedValue>
                                    <name>1</name>
                                    <description>Enables a register-access-during-capture interrupt</description>
                                    <value>#1</value>
                                </enumeratedValue>
                            </enumeratedValues>
                        </field>
                        <field>
                            <name>HDIE</name>
                            <description>HD Interrupt Enable</description>
                            <lsb>8</lsb>
                            <msb>8</msb>
                            <access>read-write</access>
                            <enumeratedValues>
                                <enumeratedValue>
                                    <name>0</name>
                                    <description>Disables an HD interrupt</description>
                                    <value>#0</value>
                                </enumeratedValue>
                                <enumeratedValue>
                                    <name>1</name>
                                    <description>Enables an HD interrupt</description>
                                    <value>#1</value>
                                </enumeratedValue>
                            </enumeratedValues>
                        </field>
                        <field>
                            <name>VDIE</name>
                            <description>VD Interrupt Enable</description>
                            <lsb>9</lsb>
                            <msb>9</msb>
                            <access>read-write</access>
                            <enumeratedValues>
                                <enumeratedValue>
                                    <name>0</name>
                                    <description>Disables a VD interrupt</description>
                                    <value>#0</value>
                                </enumeratedValue>
                                <enumeratedValue>
                                    <name>1</name>
                                    <description>Enables a VD interrupt</description>
                                    <value>#1</value>
                                </enumeratedValue>
                            </enumeratedValues>
                        </field>
                        <field>
                            <name>CPBE1IE</name>
                            <description>CPBE1 Interrupt Enable</description>
                            <lsb>12</lsb>
                            <msb>12</msb>
                            <access>read-write</access>
                            <enumeratedValues>
                                <enumeratedValue>
                                    <name>0</name>
                                    <description>Disables a CPBE1 interrupt</description>
                                    <value>#0</value>
                                </enumeratedValue>
                                <enumeratedValue>
                                    <name>1</name>
                                    <description>Enables a CPBE1 interrupt</description>
                                    <value>#1</value>
                                </enumeratedValue>
                            </enumeratedValues>
                        </field>
                        <field>
                            <name>CPBE2IE</name>
                            <description>CPBE2 Interrupt Enable</description>
                            <lsb>13</lsb>
                            <msb>13</msb>
                            <access>read-write</access>
                            <enumeratedValues>
                                <enumeratedValue>
                                    <name>0</name>
                                    <description>Disables a CPBE2 interrupt</description>
                                    <value>#0</value>
                                </enumeratedValue>
                                <enumeratedValue>
                                    <name>1</name>
                                    <description>Enables a CPBE2 interrupt</description>
                                    <value>#1</value>
                                </enumeratedValue>
                            </enumeratedValues>
                        </field>
                        <field>
                            <name>CPBE3IE</name>
                            <description>CPBE3 Interrupt Enable</description>
                            <lsb>14</lsb>
                            <msb>14</msb>
                            <access>read-write</access>
                            <enumeratedValues>
                                <enumeratedValue>
                                    <name>0</name>
                                    <description>Disables a CPBE3 interrupt</description>
                                    <value>#0</value>
                                </enumeratedValue>
                                <enumeratedValue>
                                    <name>1</name>
                                    <description>Enables a CPBE3 interrupt</description>
                                    <value>#1</value>
                                </enumeratedValue>
                            </enumeratedValues>
                        </field>
                        <field>
                            <name>CPBE4IE</name>
                            <description>CPBE4 Interrupt Enable</description>
                            <lsb>15</lsb>
                            <msb>15</msb>
                            <access>read-write</access>
                            <enumeratedValues>
                                <enumeratedValue>
                                    <name>0</name>
                                    <description>Disables a CPBE4 interrupt</description>
                                    <value>#0</value>
                                </enumeratedValue>
                                <enumeratedValue>
                                    <name>1</name>
                                    <description>Enables a CPBE4 interrupt</description>
                                    <value>#1</value>
                                </enumeratedValue>
                            </enumeratedValues>
                        </field>
                        <field>
                            <name>CDTOFIE</name>
                            <description>CDTOF Interrupt Enable</description>
                            <lsb>16</lsb>
                            <msb>16</msb>
                            <access>read-write</access>
                            <enumeratedValues>
                                <enumeratedValue>
                                    <name>0</name>
                                    <description>Disables a CDTOF interrupt</description>
                                    <value>#0</value>
                                </enumeratedValue>
                                <enumeratedValue>
                                    <name>1</name>
                                    <description>Enables a CDTOF interrupt</description>
                                    <value>#1</value>
                                </enumeratedValue>
                            </enumeratedValues>
                        </field>
                        <field>
                            <name>IGHSIE</name>
                            <description>IGHS Interrupt Enable</description>
                            <lsb>17</lsb>
                            <msb>17</msb>
                            <access>read-write</access>
                            <enumeratedValues>
                                <enumeratedValue>
                                    <name>0</name>
                                    <description>Disables an IGHS interrupt</description>
                                    <value>#0</value>
                                </enumeratedValue>
                                <enumeratedValue>
                                    <name>1</name>
                                    <description>Enables an IGHS interrupt</description>
                                    <value>#1</value>
                                </enumeratedValue>
                            </enumeratedValues>
                        </field>
                        <field>
                            <name>IGVSIE</name>
                            <description>IGVS Interrupt Enable</description>
                            <lsb>18</lsb>
                            <msb>18</msb>
                            <access>read-write</access>
                            <enumeratedValues>
                                <enumeratedValue>
                                    <name>0</name>
                                    <description>Disables an IGVS interrupt</description>
                                    <value>#0</value>
                                </enumeratedValue>
                                <enumeratedValue>
                                    <name>1</name>
                                    <description>Enables an IGVS interrupt</description>
                                    <value>#1</value>
                                </enumeratedValue>
                            </enumeratedValues>
                        </field>
                        <field>
                            <name>VBPIE</name>
                            <description>VBP Interrupt Enable</description>
                            <lsb>20</lsb>
                            <msb>20</msb>
                            <access>read-write</access>
                            <enumeratedValues>
                                <enumeratedValue>
                                    <name>0</name>
                                    <description>Disables a VBP interrupt</description>
                                    <value>#0</value>
                                </enumeratedValue>
                                <enumeratedValue>
                                    <name>1</name>
                                    <description>Enables a VBP interrupt</description>
                                    <value>#1</value>
                                </enumeratedValue>
                            </enumeratedValues>
                        </field>
                        <field>
                            <name>FWFIE</name>
                            <description>FWF Interrupt Enable</description>
                            <lsb>23</lsb>
                            <msb>23</msb>
                            <access>read-write</access>
                            <enumeratedValues>
                                <enumeratedValue>
                                    <name>0</name>
                                    <description>Disables a FWF interrupt</description>
                                    <value>#0</value>
                                </enumeratedValue>
                                <enumeratedValue>
                                    <name>1</name>
                                    <description>Enables a FWF interrupt</description>
                                    <value>#1</value>
                                </enumeratedValue>
                            </enumeratedValues>
                        </field>
                        <field>
                            <name>NHDIE</name>
                            <description>Non-HD Interrupt Enable</description>
                            <lsb>24</lsb>
                            <msb>24</msb>
                            <access>read-write</access>
                            <enumeratedValues>
                                <enumeratedValue>
                                    <name>0</name>
                                    <description>Disables a non-HD interrupt</description>
                                    <value>#0</value>
                                </enumeratedValue>
                                <enumeratedValue>
                                    <name>1</name>
                                    <description>Enables a non-HD interrupt</description>
                                    <value>#1</value>
                                </enumeratedValue>
                            </enumeratedValues>
                        </field>
                        <field>
                            <name>NVDIE</name>
                            <description>Non-VD Interrupt Enable</description>
                            <lsb>25</lsb>
                            <msb>25</msb>
                            <access>read-write</access>
                            <enumeratedValues>
                                <enumeratedValue>
                                    <name>0</name>
                                    <description>Disables a non-VD interrupt</description>
                                    <value>#0</value>
                                </enumeratedValue>
                                <enumeratedValue>
                                    <name>1</name>
                                    <description>Enables a non-VD interrupt</description>
                                    <value>#1</value>
                                </enumeratedValue>
                            </enumeratedValues>
                        </field>
                    </fields>
                </register>
                <register>
                    <name>CETCR</name>
                    <description>Capture Event Flag Clear Register</description>
                    <addressOffset>0x0074</addressOffset>
                    <size>32</size>
                    <access>read-write</access>
                    <resetValue>0x00000000</resetValue>
                    <resetMask>0xfffffcff</resetMask>
                    <fields>
                        <field>
                            <name>CPE</name>
                            <description>An interrupt indicating that capturing of one frame from an external module has finished.</description>
                            <lsb>0</lsb>
                            <msb>0</msb>
                            <access>read-write</access>
                        </field>
                        <field>
                            <name>CFE</name>
                            <description>An interrupt indicating that capturing of one field from an external module has finished.</description>
                            <lsb>1</lsb>
                            <msb>1</msb>
                            <access>read-write</access>
                        </field>
                        <field>
                            <name>IGRW</name>
                            <description>An interrupt indicating that during capturing, access was attempted to a register to which writing during operation is prohibited.</description>
                            <lsb>4</lsb>
                            <msb>4</msb>
                            <access>read-write</access>
                        </field>
                        <field>
                            <name>HD</name>
                            <description>An interrupt indicating that HD (horizontal sync signal) was input from an external module.</description>
                            <lsb>8</lsb>
                            <msb>8</msb>
                            <access>read-write</access>
                        </field>
                        <field>
                            <name>VD</name>
                            <description>An interrupt indicating that VD (vertical sync signal) was input from an external module.</description>
                            <lsb>9</lsb>
                            <msb>9</msb>
                            <access>read-write</access>
                        </field>
                        <field>
                            <name>CPBE1</name>
                            <description>An interrupt indicating that writing to CDAYR and CDACR in a bundle write has finished.</description>
                            <lsb>12</lsb>
                            <msb>12</msb>
                            <access>read-write</access>
                        </field>
                        <field>
                            <name>CPBE2</name>
                            <description>An interrupt indicating that writing to CDAYR2 and CDACR2 in a bundle write has finished.</description>
                            <lsb>13</lsb>
                            <msb>13</msb>
                            <access>read-write</access>
                        </field>
                        <field>
                            <name>CPBE3</name>
                            <description>An interrupt indicating that writing to CDBYR and CDBCR in a bundle write has finished.</description>
                            <lsb>14</lsb>
                            <msb>14</msb>
                            <access>read-write</access>
                        </field>
                        <field>
                            <name>CPBE4</name>
                            <description>An interrupt indicating that writing to CDBYR2 and CDBCR2 in a bundle write has finished.</description>
                            <lsb>15</lsb>
                            <msb>15</msb>
                            <access>read-write</access>
                        </field>
                        <field>
                            <name>CDTOF</name>
                            <description>An interrupt indicating that data overflowed in the CRAM of the write buffer</description>
                            <lsb>16</lsb>
                            <msb>16</msb>
                            <access>read-write</access>
                        </field>
                        <field>
                            <name>IGHS</name>
                            <description>An interrupt generated when the number of HD cycles set in CMCYR differ from the number of HD cycles input from an external module.</description>
                            <lsb>17</lsb>
                            <msb>17</msb>
                            <access>read-write</access>
                        </field>
                        <field>
                            <name>IGVS</name>
                            <description>An interrupt generated when the number of VD cycles set in CMCYR differ from the number of VD cycles input from an external module.</description>
                            <lsb>18</lsb>
                            <msb>18</msb>
                            <access>read-write</access>
                        </field>
                        <field>
                            <name>VBP</name>
                            <description>An interrupt indicating that VD has been input while the CEU holds data (insufficient vertical-sync front porch).</description>
                            <lsb>20</lsb>
                            <msb>20</msb>
                            <access>read-write</access>
                        </field>
                        <field>
                            <name>FWF</name>
                            <description>The interrupt is generated when data is written to the address that exceeds the value specified with CFWCR.FMV.</description>
                            <lsb>23</lsb>
                            <msb>23</msb>
                            <access>read-write</access>
                        </field>
                        <field>
                            <name>NHD</name>
                            <description>An interrupt indicating that no HD was input.</description>
                            <lsb>24</lsb>
                            <msb>24</msb>
                            <access>read-write</access>
                        </field>
                        <field>
                            <name>NVD</name>
                            <description>An interrupt indicating that no VD was input.</description>
                            <lsb>25</lsb>
                            <msb>25</msb>
                            <access>read-write</access>
                        </field>
                    </fields>
                </register>
                <register>
                    <name>CSTSR</name>
                    <description>Capture Status Register</description>
                    <addressOffset>0x007C</addressOffset>
                    <size>32</size>
                    <access>read-only</access>
                    <resetValue>0x00000000</resetValue>
                    <resetMask>0xffffffff</resetMask>
                    <fields>
                        <field>
                            <name>CPTON</name>
                            <description>Indicates that the CEU is operating.</description>
                            <lsb>0</lsb>
                            <msb>0</msb>
                            <access>read-only</access>
                        </field>
                        <field>
                            <name>CPFLD</name>
                            <description>Indicates which field is being captured.</description>
                            <lsb>16</lsb>
                            <msb>16</msb>
                            <access>read-only</access>
                            <enumeratedValues>
                                <enumeratedValue>
                                    <name>0</name>
                                    <description>Bottom field is being captured</description>
                                    <value>#0</value>
                                </enumeratedValue>
                                <enumeratedValue>
                                    <name>1</name>
                                    <description>Top field is being captured</description>
                                    <value>#1</value>
                                </enumeratedValue>
                            </enumeratedValues>
                        </field>
                        <field>
                            <name>CRST</name>
                            <description>Indicates which register plane is currently used.</description>
                            <lsb>24</lsb>
                            <msb>24</msb>
                            <access>read-only</access>
                            <enumeratedValues>
                                <enumeratedValue>
                                    <name>0</name>
                                    <description>Plane A of the register is being used</description>
                                    <value>#0</value>
                                </enumeratedValue>
                                <enumeratedValue>
                                    <name>1</name>
                                    <description>Plane B of the register is being used</description>
                                    <value>#1</value>
                                </enumeratedValue>
                            </enumeratedValues>
                        </field>
                    </fields>
                </register>
                <register>
                    <name>CDSSR</name>
                    <description>Capture Data Size Register</description>
                    <addressOffset>0x0084</addressOffset>
                    <size>32</size>
                    <access>read-only</access>
                    <resetValue>0x00000000</resetValue>
                    <resetMask>0xffffffff</resetMask>
                    <fields>
                        <field>
                            <name>CDSS</name>
                            <description>Indicate the size of data written to the memory in data enable fetch.</description>
                            <lsb>0</lsb>
                            <msb>31</msb>
                            <access>read-only</access>
                        </field>
                    </fields>
                </register>
                <register>
                    <name>CDAYR2</name>
                    <description>Capture Data Address Y Register 2</description>
                    <addressOffset>0x0090</addressOffset>
                    <size>32</size>
                    <access>read-write</access>
                    <resetValue>0x00000000</resetValue>
                    <resetMask>0xffffffff</resetMask>
                    <fields>
                        <field>
                            <name>CAYR2</name>
                            <description>Capture Data Address Y</description>
                            <lsb>0</lsb>
                            <msb>31</msb>
                            <access>read-write</access>
                        </field>
                    </fields>
                </register>
                <register>
                    <name>CDACR2</name>
                    <description>Capture Data Address C Register 2</description>
                    <addressOffset>0x0094</addressOffset>
                    <size>32</size>
                    <access>read-write</access>
                    <resetValue>0x00000000</resetValue>
                    <resetMask>0xffffffff</resetMask>
                    <fields>
                        <field>
                            <name>CACR2</name>
                            <description>Capture Data Address C</description>
                            <lsb>0</lsb>
                            <msb>31</msb>
                            <access>read-write</access>
                        </field>
                    </fields>
                </register>
                <register>
                    <name>CDBYR2</name>
                    <description>Capture Data Bottom-Field Address Y Register 2</description>
                    <addressOffset>0x0098</addressOffset>
                    <size>32</size>
                    <access>read-write</access>
                    <resetValue>0x00000000</resetValue>
                    <resetMask>0xffffffff</resetMask>
                    <fields>
                        <field>
                            <name>CBYR2</name>
                            <description>Set the address for storing the luminance component data of the captured bottom-field data (8-pixel units).</description>
                            <lsb>0</lsb>
                            <msb>31</msb>
                            <access>read-write</access>
                        </field>
                    </fields>
                </register>
                <register>
                    <name>CDBCR2</name>
                    <description>Capture Data Bottom-Field Address C Register 2</description>
                    <addressOffset>0x009C</addressOffset>
                    <size>32</size>
                    <access>read-write</access>
                    <resetValue>0x00000000</resetValue>
                    <resetMask>0xffffffff</resetMask>
                    <fields>
                        <field>
                            <name>CBCR2</name>
                            <description>Set the address for storing the chrominance component data of the captured bottom-field data (8-pixel units).</description>
                            <lsb>0</lsb>
                            <msb>31</msb>
                            <access>read-write</access>
                        </field>
                    </fields>
                </register>
                <register>
                    <name>CBWER</name>
                    <description>CEU Bufferable Write Enable Register</description>
                    <addressOffset>0x00A0</addressOffset>
                    <size>32</size>
                    <access>read-write</access>
                    <resetValue>0x00000000</resetValue>
                    <resetMask>0xffffffff</resetMask>
                    <fields>
                        <field>
                            <name>BWE</name>
                            <lsb>0</lsb>
                            <msb>0</msb>
                            <access>read-write</access>
                            <enumeratedValues>
                                <enumeratedValue>
                                    <name>0</name>
                                    <description>Disables Bufferable Write</description>
                                    <value>#0</value>
                                </enumeratedValue>
                                <enumeratedValue>
                                    <name>1</name>
                                    <description>Enables Bufferable Write</description>
                                    <value>#1</value>
                                </enumeratedValue>
                            </enumeratedValues>
                        </field>
                    </fields>
                </register>
                <register>
                    <name>CAMOR_B</name>
                    <description>Capture Interface Offset Register</description>
                    <addressOffset>0x1010</addressOffset>
                    <size>32</size>
                    <access>read-write</access>
                    <resetValue>0x00000000</resetValue>
                    <resetMask>0xffffffff</resetMask>
                    <fields>
                        <field>
                            <name>HOFST</name>
                            <description>Specify the capture start location in terms of the number of clock cycles from a horizontal sync signal (1-cycle units).</description>
                            <lsb>0</lsb>
                            <msb>12</msb>
                            <access>read-write</access>
                        </field>
                        <field>
                            <name>VOFST</name>
                            <description>Specify the capture start location in terms of the HD count from a vertical sync signal (1-HD units).</description>
                            <lsb>16</lsb>
                            <msb>27</msb>
                            <access>read-write</access>
                        </field>
                    </fields>
                </register>
                <register>
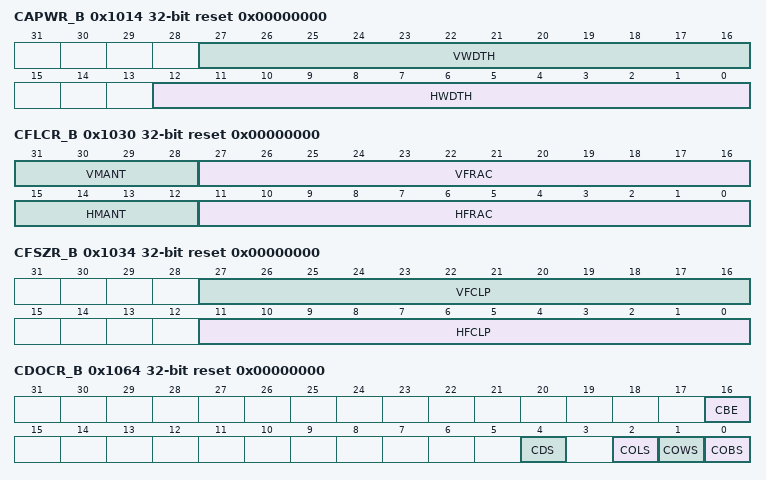
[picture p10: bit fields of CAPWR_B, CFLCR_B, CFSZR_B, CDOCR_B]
                    <name>CAPWR_B</name>
                    <description>Capture Interface Width Register</description>
                    <addressOffset>0x1014</addressOffset>
                    <size>32</size>
                    <access>read-write</access>
                    <resetValue>0x00000000</resetValue>
                    <resetMask>0xffffffff</resetMask>
                    <fields>
                        <field>
                            <name>HWDTH</name>
                            <description>Specify the horizontal capture period.</description>
                            <lsb>0</lsb>
                            <msb>12</msb>
                            <access>read-write</access>
                        </field>
                        <field>
                            <name>VWDTH</name>
                            <description>Specify the vertical capture period (4-HD units).</description>
                            <lsb>16</lsb>
                            <msb>27</msb>
                            <access>read-write</access>
                        </field>
                    </fields>
                </register>
                <register>
                    <name>CFLCR_B</name>
                    <description>Capture Filter Control Register</description>
                    <addressOffset>0x1030</addressOffset>
                    <size>32</size>
                    <access>read-write</access>
                    <resetValue>0x00000000</resetValue>
                    <resetMask>0xffffffff</resetMask>
                    <fields>
                        <field>
                            <name>HFRAC</name>
                            <description>Fraction Part of Horizontal Scale-Down Factor</description>
                            <lsb>0</lsb>
                            <msb>11</msb>
                            <access>read-write</access>
                        </field>
                        <field>
                            <name>HMANT</name>
                            <description>Mantissa Part of Horizontal Scale-Down Factor</description>
                            <lsb>12</lsb>
                            <msb>15</msb>
                            <access>read-write</access>
                        </field>
                        <field>
                            <name>VFRAC</name>
                            <description>Fraction Part of Vertical Scale-Down Factor</description>
                            <lsb>16</lsb>
                            <msb>27</msb>
                            <access>read-write</access>
                        </field>
                        <field>
                            <name>VMANT</name>
                            <description>Mantissa Part of Vertical Scale-Down Factor</description>
                            <lsb>28</lsb>
                            <msb>31</msb>
                            <access>read-write</access>
                        </field>
                    </fields>
                </register>
                <register>
                    <name>CFSZR_B</name>
                    <description>Capture Filter Size Clip Register</description>
                    <addressOffset>0x1034</addressOffset>
                    <size>32</size>
                    <access>read-write</access>
                    <resetValue>0x00000000</resetValue>
                    <resetMask>0xffffffff</resetMask>
                    <fields>
                        <field>
                            <name>HFCLP</name>
                            <description>Specify the horizontal clipping value of the filter output size (8-pixel units).</description>
                            <lsb>0</lsb>
                            <msb>11</msb>
                            <access>read-write</access>
                        </field>
                        <field>
                            <name>VFCLP</name>
                            <description>Specify the vertical clipping value of the filter output size (4-pixel units).</description>
                            <lsb>16</lsb>
                            <msb>27</msb>
                            <access>read-write</access>
                        </field>
                    </fields>
                </register>
                <register>
                    <name>CDWDR_B</name>
                    <description>Capture Destination Width Register</description>
                    <addressOffset>0x1038</addressOffset>
                    <size>32</size>
                    <access>read-write</access>
                    <resetValue>0x00000000</resetValue>
                    <resetMask>0xffffffff</resetMask>
                    <fields>
                        <field>
                            <name>CHDW</name>
                            <description>Specify the horizontal image size in the memory area where the captured image is to be stored (8-byte units).</description>
                            <lsb>0</lsb>
                            <msb>12</msb>
                            <access>read-write</access>
                        </field>
                    </fields>
                </register>
                <register>
                    <name>CDAYR_B</name>
                    <description>Capture Data Address Y Register</description>
                    <addressOffset>0x103C</addressOffset>
                    <size>32</size>
                    <access>read-write</access>
                    <resetValue>0x00000000</resetValue>
                    <resetMask>0xffffffff</resetMask>
                    <fields>
                        <field>
                            <name>CAYR</name>
                            <description>Capture Data Address Y</description>
                            <lsb>0</lsb>
                            <msb>31</msb>
                            <access>read-write</access>
                        </field>
                    </fields>
                </register>
                <register>
                    <name>CDACR_B</name>
                    <description>Capture Data Address C Register</description>
                    <addressOffset>0x1040</addressOffset>
                    <size>32</size>
                    <access>read-write</access>
                    <resetValue>0x00000000</resetValue>
                    <resetMask>0xffffffff</resetMask>
                    <fields>
                        <field>
                            <name>CACR</name>
                            <description>Capture Data Address C</description>
                            <lsb>0</lsb>
                            <msb>31</msb>
                            <access>read-write</access>
                        </field>
                    </fields>
                </register>
                <register>
                    <name>CDBYR_B</name>
                    <description>Capture Data Bottom-Field Address Y Register</description>
                    <addressOffset>0x1044</addressOffset>
                    <size>32</size>
                    <access>read-write</access>
                    <resetValue>0x00000000</resetValue>
                    <resetMask>0xffffffff</resetMask>
                    <fields>
                        <field>
                            <name>CBYR</name>
                            <description>Set the address for storing the luminance component data of the captured bottom-field data (8-pixel units).</description>
                            <lsb>0</lsb>
                            <msb>31</msb>
                            <access>read-write</access>
                        </field>
                    </fields>
                </register>
                <register>
                    <name>CDBCR_B</name>
                    <description>Capture Data Bottom-Field Address C Register</description>
                    <addressOffset>0x1048</addressOffset>
                    <size>32</size>
                    <access>read-write</access>
                    <resetValue>0x00000000</resetValue>
                    <resetMask>0xffffffff</resetMask>
                    <fields>
                        <field>
                            <name>CBCR</name>
                            <description>Set the address for storing the chrominance component data of the captured bottom-field data (8-pixel units).</description>
                            <lsb>0</lsb>
                            <msb>31</msb>
                            <access>read-write</access>
                        </field>
                    </fields>
                </register>
                <register>
                    <name>CBDSR_B</name>
                    <description>Capture Bundle Destination Size Register</description>
                    <addressOffset>0x104C</addressOffset>
                    <size>32</size>
                    <access>read-write</access>
                    <resetValue>0x00000000</resetValue>
                    <resetMask>0xffffffff</resetMask>
                    <fields>
                        <field>
                            <name>CBVS</name>
                            <description>Select the number of lines or number of bytes for output to the memory in a bundle write.</description>
                            <lsb>0</lsb>
                            <msb>22</msb>
                            <access>read-write</access>
                        </field>
                    </fields>
                </register>
                <register>
                    <name>CLFCR_B</name>
                    <description>Capture Low-Pass Filter Control Register</description>
                    <addressOffset>0x1060</addressOffset>
                    <size>32</size>
                    <access>read-write</access>
                    <resetValue>0x00000000</resetValue>
                    <resetMask>0xffffffff</resetMask>
                    <fields>
                        <field>
                            <name>LPF</name>
                            <description>Enables or disables operation of the low-pass filter.</description>
                            <lsb>0</lsb>
                            <msb>0</msb>
                            <access>read-write</access>
                            <enumeratedValues>
                                <enumeratedValue>
                                    <name>0</name>
                                    <description>Low-pass filter not used</description>
                                    <value>#0</value>
                                </enumeratedValue>
                                <enumeratedValue>
                                    <name>1</name>
                                    <description>Low-pass filter used (only in the horizontal direction)</description>
                                    <value>#1</value>
                                </enumeratedValue>
                            </enumeratedValues>
                        </field>
                    </fields>
                </register>
                <register>
                    <name>CDOCR_B</name>
                    <description>Capture Data Output Control Register</description>
                    <addressOffset>0x1064</addressOffset>
                    <size>32</size>
                    <access>read-write</access>
                    <resetValue>0x00000000</resetValue>
                    <resetMask>0xffffffff</resetMask>
                    <fields>
                        <field>
                            <name>COBS</name>
                            <description>Controls swapping in 8-bit units for data output from the CEU.</description>
                            <lsb>0</lsb>
                            <msb>0</msb>
                            <access>read-write</access>
                            <enumeratedValues>
                                <enumeratedValue>
                                    <name>0</name>
                                    <description>Data is not swapped in 8-bit units</description>
                                    <value>#0</value>
                                </enumeratedValue>
                                <enumeratedValue>
                                    <name>1</name>
                                    <description>Data is swapped in 8-bit units</description>
                                    <value>#1</value>
                                </enumeratedValue>
                            </enumeratedValues>
                        </field>
                        <field>
                            <name>COWS</name>
                            <description>Controls swapping in 16-bit units for data output from the CEU.</description>
                            <lsb>1</lsb>
                            <msb>1</msb>
                            <access>read-write</access>
                            <enumeratedValues>
                                <enumeratedValue>
                                    <name>0</name>
                                    <description>Data is not swapped in 16-bit units</description>
                                    <value>#0</value>
                                </enumeratedValue>
                                <enumeratedValue>
                                    <name>1</name>
                                    <description>Data is swapped in 16-bit units</description>
                                    <value>#1</value>
                                </enumeratedValue>
                            </enumeratedValues>
                        </field>
                        <field>
                            <name>COLS</name>
                            <description>Controls swapping in 32-bit units for data output from the CEU.</description>
                            <lsb>2</lsb>
                            <msb>2</msb>
                            <access>read-write</access>
                            <enumeratedValues>
                                <enumeratedValue>
                                    <name>0</name>
                                    <description>Data is not swapped in 32-bit units</description>
                                    <value>#0</value>
                                </enumeratedValue>
                                <enumeratedValue>
                                    <name>1</name>
                                    <description>Data is swapped in 32-bit units</description>
                                    <value>#1</value>
                                </enumeratedValue>
                            </enumeratedValues>
                        </field>
                        <field>
                            <name>CDS</name>
                            <description>Sets the image format when outputting the image data captured in the YCbCr422 format to the memory.</description>
                            <lsb>4</lsb>
                            <msb>4</msb>
                            <access>read-write</access>
                            <enumeratedValues>
                                <enumeratedValue>
                                    <name>0</name>
                                    <description>Converts the YCbCr422 format to the YCbCr420 format before outputting data to the memory</description>
                                    <value>#0</value>
                                </enumeratedValue>
                                <enumeratedValue>
                                    <name>1</name>
                                    <description>Outputs data in the YCbCr422 format to the memory without conversion</description>
                                    <value>#1</value>
                                </enumeratedValue>
                            </enumeratedValues>
                        </field>
                        <field>
                            <name>CBE</name>
                            <description> Controls the number of lines of captured data to be written to the memory.</description>
                            <lsb>16</lsb>
                            <msb>16</msb>
                            <access>read-write</access>
                            <enumeratedValues>
                                <enumeratedValue>
                                    <name>0</name>
                                    <description>Normal write</description>
                                    <value>#0</value>
                                </enumeratedValue>
                                <enumeratedValue>
                                    <name>1</name>
                                    <description>Bundle write</description>
                                    <value>#1</value>
                                </enumeratedValue>
                            </enumeratedValues>
                        </field>
                    </fields>
                </register>
                <register>
                    <name>CDAYR2_B</name>
                    <description>Capture Data Address Y Register 2</description>
                    <addressOffset>0x1090</addressOffset>
                    <size>32</size>
                    <access>read-write</access>
                    <resetValue>0x00000000</resetValue>
                    <resetMask>0xffffffff</resetMask>
                    <fields>
                        <field>
                            <name>CAYR2</name>
                            <description>Capture Data Address Y</description>
                            <lsb>0</lsb>
                            <msb>31</msb>
                            <access>read-write</access>
                        </field>
                    </fields>
                </register>
                <register>
                    <name>CDACR2_B</name>
                    <description>Capture Data Address C Register 2</description>
                    <addressOffset>0x1094</addressOffset>
                    <size>32</size>
                    <access>read-write</access>
                    <resetValue>0x00000000</resetValue>
                    <resetMask>0xffffffff</resetMask>
                    <fields>
                        <field>
                            <name>CACR2</name>
                            <description>Capture Data Address C</description>
                            <lsb>0</lsb>
                            <msb>31</msb>
                            <access>read-write</access>
                        </field>
                    </fields>
                </register>
                <register>
                    <name>CDBYR2_B</name>
                    <description>Capture Data Bottom-Field Address Y Register 2</description>
                    <addressOffset>0x1098</addressOffset>
                    <size>32</size>
                    <access>read-write</access>
                    <resetValue>0x00000000</resetValue>
                    <resetMask>0xffffffff</resetMask>
                    <fields>
                        <field>
                            <name>CBYR2</name>
                            <description>Set the address for storing the luminance component data of the captured bottom-field data (8-pixel units).</description>
                            <lsb>0</lsb>
                            <msb>31</msb>
                            <access>read-write</access>
                        </field>
                    </fields>
                </register>
                <register>
                    <name>CDBCR2_B</name>
                    <description>Capture Data Bottom-Field Address C Register 2</description>
                    <addressOffset>0x109C</addressOffset>
                    <size>32</size>
                    <access>read-write</access>
                    <resetValue>0x00000000</resetValue>
                    <resetMask>0xffffffff</resetMask>
                    <fields>
                        <field>
                            <name>CBCR2</name>
                            <description>Set the address for storing the chrominance component data of the captured bottom-field data (8-pixel units).</description>
                            <lsb>0</lsb>
                            <msb>31</msb>
                            <access>read-write</access>
                        </field>
                    </fields>
                </register>
                <register>
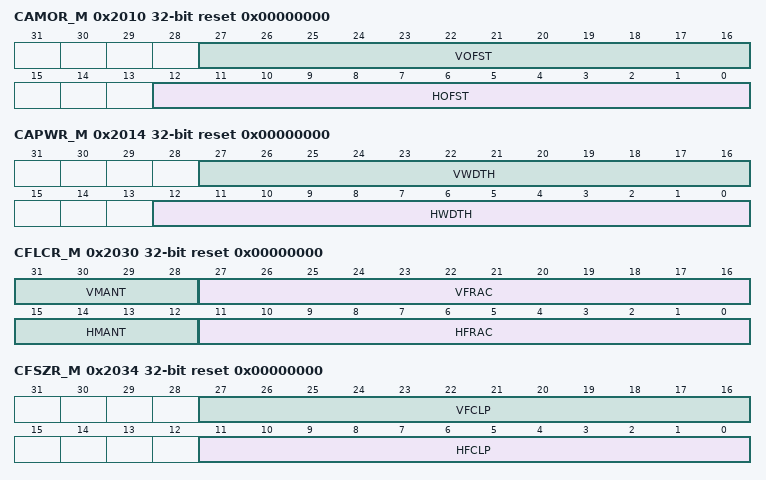
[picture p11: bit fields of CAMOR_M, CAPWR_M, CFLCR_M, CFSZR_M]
                    <name>CAMOR_M</name>
                    <description>Capture Interface Offset Register</description>
                    <addressOffset>0x2010</addressOffset>
                    <size>32</size>
                    <access>read-write</access>
                    <resetValue>0x00000000</resetValue>
                    <resetMask>0xffffffff</resetMask>
                    <fields>
                        <field>
                            <name>HOFST</name>
                            <description>Specify the capture start location in terms of the number of clock cycles from a horizontal sync signal (1-cycle units).</description>
                            <lsb>0</lsb>
                            <msb>12</msb>
                            <access>read-write</access>
                        </field>
                        <field>
                            <name>VOFST</name>
                            <description>Specify the capture start location in terms of the HD count from a vertical sync signal (1-HD units).</description>
                            <lsb>16</lsb>
                            <msb>27</msb>
                            <access>read-write</access>
                        </field>
                    </fields>
                </register>
                <register>
                    <name>CAPWR_M</name>
                    <description>Capture Interface Width Register</description>
                    <addressOffset>0x2014</addressOffset>
                    <size>32</size>
                    <access>read-write</access>
                    <resetValue>0x00000000</resetValue>
                    <resetMask>0xffffffff</resetMask>
                    <fields>
                        <field>
                            <name>HWDTH</name>
                            <description>Specify the horizontal capture period.</description>
                            <lsb>0</lsb>
                            <msb>12</msb>
                            <access>read-write</access>
                        </field>
                        <field>
                            <name>VWDTH</name>
                            <description>Specify the vertical capture period (4-HD units).</description>
                            <lsb>16</lsb>
                            <msb>27</msb>
                            <access>read-write</access>
                        </field>
                    </fields>
                </register>
                <register>
                    <name>CFLCR_M</name>
                    <description>Capture Filter Control Register</description>
                    <addressOffset>0x2030</addressOffset>
                    <size>32</size>
                    <access>read-write</access>
                    <resetValue>0x00000000</resetValue>
                    <resetMask>0xffffffff</resetMask>
                    <fields>
                        <field>
                            <name>HFRAC</name>
                            <description>Fraction Part of Horizontal Scale-Down Factor</description>
                            <lsb>0</lsb>
                            <msb>11</msb>
                            <access>read-write</access>
                        </field>
                        <field>
                            <name>HMANT</name>
                            <description>Mantissa Part of Horizontal Scale-Down Factor</description>
                            <lsb>12</lsb>
                            <msb>15</msb>
                            <access>read-write</access>
                        </field>
                        <field>
                            <name>VFRAC</name>
                            <description>Fraction Part of Vertical Scale-Down Factor</description>
                            <lsb>16</lsb>
                            <msb>27</msb>
                            <access>read-write</access>
                        </field>
                        <field>
                            <name>VMANT</name>
                            <description>Mantissa Part of Vertical Scale-Down Factor</description>
                            <lsb>28</lsb>
                            <msb>31</msb>
                            <access>read-write</access>
                        </field>
                    </fields>
                </register>
                <register>
                    <name>CFSZR_M</name>
                    <description>Capture Filter Size Clip Register</description>
                    <addressOffset>0x2034</addressOffset>
                    <size>32</size>
                    <access>read-write</access>
                    <resetValue>0x00000000</resetValue>
                    <resetMask>0xffffffff</resetMask>
                    <fields>
                        <field>
                            <name>HFCLP</name>
                            <description>Specify the horizontal clipping value of the filter output size (8-pixel units).</description>
                            <lsb>0</lsb>
                            <msb>11</msb>
                            <access>read-write</access>
                        </field>
                        <field>
                            <name>VFCLP</name>
                            <description>Specify the vertical clipping value of the filter output size (4-pixel units).</description>
                            <lsb>16</lsb>
                            <msb>27</msb>
                            <access>read-write</access>
                        </field>
                    </fields>
                </register>
                <register>
                    <name>CDWDR_M</name>
                    <description>Capture Destination Width Register</description>
                    <addressOffset>0x2038</addressOffset>
                    <size>32</size>
                    <access>read-write</access>
                    <resetValue>0x00000000</resetValue>
                    <resetMask>0xffffffff</resetMask>
                    <fields>
                        <field>
                            <name>CHDW</name>
                            <description>Specify the horizontal image size in the memory area where the captured image is to be stored (8-byte units).</description>
                            <lsb>0</lsb>
                            <msb>12</msb>
                            <access>read-write</access>
                        </field>
                    </fields>
                </register>
                <register>
                    <name>CDAYR_M</name>
                    <description>Capture Data Address Y Register</description>
                    <addressOffset>0x203C</addressOffset>
                    <size>32</size>
                    <access>read-write</access>
                    <resetValue>0x00000000</resetValue>
                    <resetMask>0xffffffff</resetMask>
                    <fields>
                        <field>
                            <name>CAYR</name>
                            <description>Capture Data Address Y</description>
                            <lsb>0</lsb>
                            <msb>31</msb>
                            <access>read-write</access>
                        </field>
                    </fields>
                </register>
                <register>
                    <name>CDACR_M</name>
                    <description>Capture Data Address C Register</description>
                    <addressOffset>0x2040</addressOffset>
                    <size>32</size>
                    <access>read-write</access>
                    <resetValue>0x00000000</resetValue>
                    <resetMask>0xffffffff</resetMask>
                    <fields>
                        <field>
                            <name>CACR</name>
                            <description>Capture Data Address C</description>
                            <lsb>0</lsb>
                            <msb>31</msb>
                            <access>read-write</access>
                        </field>
                    </fields>
                </register>
                <register>
                    <name>CDBYR_M</name>
                    <description>Capture Data Bottom-Field Address Y Register</description>
                    <addressOffset>0x2044</addressOffset>
                    <size>32</size>
                    <access>read-write</access>
                    <resetValue>0x00000000</resetValue>
                    <resetMask>0xffffffff</resetMask>
                    <fields>
                        <field>
                            <name>CBYR</name>
                            <description>Set the address for storing the luminance component data of the captured bottom-field data (8-pixel units).</description>
                            <lsb>0</lsb>
                            <msb>31</msb>
                            <access>read-write</access>
                        </field>
                    </fields>
                </register>
                <register>
                    <name>CDBCR_M</name>
                    <description>Capture Data Bottom-Field Address C Register</description>
                    <addressOffset>0x2048</addressOffset>
                    <size>32</size>
                    <access>read-write</access>
                    <resetValue>0x00000000</resetValue>
                    <resetMask>0xffffffff</resetMask>
                    <fields>
                        <field>
                            <name>CBCR</name>
                            <description>Set the address for storing the chrominance component data of the captured bottom-field data (8-pixel units).</description>
                            <lsb>0</lsb>
                            <msb>31</msb>
                            <access>read-write</access>
                        </field>
                    </fields>
                </register>
                <register>
                    <name>CBDSR_M</name>
                    <description>Capture Bundle Destination Size Register</description>
                    <addressOffset>0x204C</addressOffset>
                    <size>32</size>
                    <access>read-write</access>
                    <resetValue>0x00000000</resetValue>
                    <resetMask>0xffffffff</resetMask>
                    <fields>
                        <field>
                            <name>CBVS</name>
                            <description>Select the number of lines or number of bytes for output to the memory in a bundle write.</description>
                            <lsb>0</lsb>
                            <msb>22</msb>
                            <access>read-write</access>
                        </field>
                    </fields>
                </register>
                <register>
                    <name>CLFCR_M</name>
                    <description>Capture Low-Pass Filter Control Register</description>
                    <addressOffset>0x2060</addressOffset>
                    <size>32</size>
                    <access>read-write</access>
                    <resetValue>0x00000000</resetValue>
                    <resetMask>0xffffffff</resetMask>
                    <fields>
                        <field>
                            <name>LPF</name>
                            <description>Enables or disables operation of the low-pass filter.</description>
                            <lsb>0</lsb>
                            <msb>0</msb>
                            <access>read-write</access>
                            <enumeratedValues>
                                <enumeratedValue>
                                    <name>0</name>
                                    <description>Low-pass filter not used</description>
                                    <value>#0</value>
                                </enumeratedValue>
                                <enumeratedValue>
                                    <name>1</name>
                                    <description>Low-pass filter used (only in the horizontal direction)</description>
                                    <value>#1</value>
                                </enumeratedValue>
                            </enumeratedValues>
                        </field>
                    </fields>
                </register>
                <register>
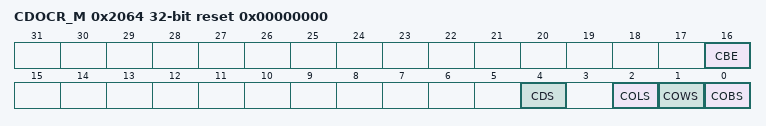
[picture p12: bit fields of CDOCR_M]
                    <name>CDOCR_M</name>
                    <description>Capture Data Output Control Register</description>
                    <addressOffset>0x2064</addressOffset>
                    <size>32</size>
                    <access>read-write</access>
                    <resetValue>0x00000000</resetValue>
                    <resetMask>0xffffffff</resetMask>
                    <fields>
                        <field>
                            <name>COBS</name>
                            <description>Controls swapping in 8-bit units for data output from the CEU.</description>
                            <lsb>0</lsb>
                            <msb>0</msb>
                            <access>read-write</access>
                            <enumeratedValues>
                                <enumeratedValue>
                                    <name>0</name>
                                    <description>Data is not swapped in 8-bit units</description>
                                    <value>#0</value>
                                </enumeratedValue>
                                <enumeratedValue>
                                    <name>1</name>
                                    <description>Data is swapped in 8-bit units</description>
                                    <value>#1</value>
                                </enumeratedValue>
                            </enumeratedValues>
                        </field>
                        <field>
                            <name>COWS</name>
                            <description>Controls swapping in 16-bit units for data output from the CEU.</description>
                            <lsb>1</lsb>
                            <msb>1</msb>
                            <access>read-write</access>
                            <enumeratedValues>
                                <enumeratedValue>
                                    <name>0</name>
                                    <description>Data is not swapped in 16-bit units</description>
                                    <value>#0</value>
                                </enumeratedValue>
                                <enumeratedValue>
                                    <name>1</name>
                                    <description>Data is swapped in 16-bit units</description>
                                    <value>#1</value>
                                </enumeratedValue>
                            </enumeratedValues>
                        </field>
                        <field>
                            <name>COLS</name>
                            <description>Controls swapping in 32-bit units for data output from the CEU.</description>
                            <lsb>2</lsb>
                            <msb>2</msb>
                            <access>read-write</access>
                            <enumeratedValues>
                                <enumeratedValue>
                                    <name>0</name>
                                    <description>Data is not swapped in 32-bit units</description>
                                    <value>#0</value>
                                </enumeratedValue>
                                <enumeratedValue>
                                    <name>1</name>
                                    <description>Data is swapped in 32-bit units</description>
                                    <value>#1</value>
                                </enumeratedValue>
                            </enumeratedValues>
                        </field>
                        <field>
                            <name>CDS</name>
                            <description>Sets the image format when outputting the image data captured in the YCbCr422 format to the memory.</description>
                            <lsb>4</lsb>
                            <msb>4</msb>
                            <access>read-write</access>
                            <enumeratedValues>
                                <enumeratedValue>
                                    <name>0</name>
                                    <description>Converts the YCbCr422 format to the YCbCr420 format before outputting data to the memory</description>
                                    <value>#0</value>
                                </enumeratedValue>
                                <enumeratedValue>
                                    <name>1</name>
                                    <description>Outputs data in the YCbCr422 format to the memory without conversion</description>
                                    <value>#1</value>
                                </enumeratedValue>
                            </enumeratedValues>
                        </field>
                        <field>
                            <name>CBE</name>
                            <description> Controls the number of lines of captured data to be written to the memory.</description>
                            <lsb>16</lsb>
                            <msb>16</msb>
                            <access>read-write</access>
                            <enumeratedValues>
                                <enumeratedValue>
                                    <name>0</name>
                                    <description>Normal write</description>
                                    <value>#0</value>
                                </enumeratedValue>
                                <enumeratedValue>
                                    <name>1</name>
                                    <description>Bundle write</description>
                                    <value>#1</value>
                                </enumeratedValue>
                            </enumeratedValues>
                        </field>
                    </fields>
                </register>
                <register>
                    <name>CDAYR2_M</name>
                    <description>Capture Data Address Y Register 2</description>
                    <addressOffset>0x2090</addressOffset>
                    <size>32</size>
                    <access>read-write</access>
                    <resetValue>0x00000000</resetValue>
                    <resetMask>0xffffffff</resetMask>
                    <fields>
                        <field>
                            <name>CAYR2</name>
                            <description>Capture Data Address Y</description>
                            <lsb>0</lsb>
                            <msb>31</msb>
                            <access>read-write</access>
                        </field>
                    </fields>
                </register>
                <register>
                    <name>CDACR2_M</name>
                    <description>Capture Data Address C Register 2</description>
                    <addressOffset>0x2094</addressOffset>
                    <size>32</size>
                    <access>read-write</access>
                    <resetValue>0x00000000</resetValue>
                    <resetMask>0xffffffff</resetMask>
                    <fields>
                        <field>
                            <name>CACR2</name>
                            <description>Capture Data Address C</description>
                            <lsb>0</lsb>
                            <msb>31</msb>
                            <access>read-write</access>
                        </field>
                    </fields>
                </register>
                <register>
                    <name>CDBYR2_M</name>
                    <description>Capture Data Bottom-Field Address Y Register 2</description>
                    <addressOffset>0x2098</addressOffset>
                    <size>32</size>
                    <access>read-write</access>
                    <resetValue>0x00000000</resetValue>
                    <resetMask>0xffffffff</resetMask>
                    <fields>
                        <field>
                            <name>CBYR2</name>
                            <description>Set the address for storing the luminance component data of the captured bottom-field data (8-pixel units).</description>
                            <lsb>0</lsb>
                            <msb>31</msb>
                            <access>read-write</access>
                        </field>
                    </fields>
                </register>
                <register>
                    <name>CDBCR2_M</name>
                    <description>Capture Data Bottom-Field Address C Register 2</description>
                    <addressOffset>0x209C</addressOffset>
                    <size>32</size>
                    <access>read-write</access>
                    <resetValue>0x00000000</resetValue>
                    <resetMask>0xffffffff</resetMask>
                    <fields>
                        <field>
                            <name>CBCR2</name>
                            <description>Set the address for storing the chrominance component data of the captured bottom-field data (8-pixel units).</description>
                            <lsb>0</lsb>
                            <msb>31</msb>
                            <access>read-write</access>
                        </field>
                    </fields>
                </register>
            </registers>
        </peripheral>
        <peripheral>
            <name>EDMAC0</name>
            <description>DMA Controller for the Ethernet Controller Channel 0</description>
            <baseAddress>0x40354000</baseAddress>
            <addressBlock>
                <offset>0x00</offset>
                <size>4</size>
                <usage>registers</usage>
            </addressBlock>
            <addressBlock>
                <offset>0x08</offset>
                <size>4</size>
                <usage>registers</usage>
            </addressBlock>
            <addressBlock>
                <offset>0x10</offset>
                <size>4</size>
                <usage>registers</usage>
            </addressBlock>
            <addressBlock>
                <offset>0x18</offset>
                <size>4</size>
                <usage>registers</usage>
            </addressBlock>
            <addressBlock>
                <offset>0x20</offset>
                <size>4</size>
                <usage>registers</usage>
            </addressBlock>
            <addressBlock>
                <offset>0x28</offset>
                <size>4</size>
                <usage>registers</usage>
            </addressBlock>
            <addressBlock>
                <offset>0x30</offset>
                <size>4</size>
                <usage>registers</usage>
            </addressBlock>
            <addressBlock>
                <offset>0x38</offset>
                <size>4</size>
                <usage>registers</usage>
            </addressBlock>
            <addressBlock>
                <offset>0x40</offset>
                <size>4</size>
                <usage>registers</usage>
            </addressBlock>
            <addressBlock>
                <offset>0x48</offset>
                <size>4</size>
                <usage>registers</usage>
            </addressBlock>
            <addressBlock>
                <offset>0x50</offset>
                <size>4</size>
                <usage>registers</usage>
            </addressBlock>
            <addressBlock>
                <offset>0x58</offset>
                <size>4</size>
                <usage>registers</usage>
            </addressBlock>
            <addressBlock>
                <offset>0x64</offset>
                <size>16</size>
                <usage>registers</usage>
            </addressBlock>
            <addressBlock>
                <offset>0x78</offset>
                <size>8</size>
                <usage>registers</usage>
            </addressBlock>
            <addressBlock>
                <offset>0xC8</offset>
                <size>8</size>
                <usage>registers</usage>
            </addressBlock>
            <addressBlock>
                <offset>0xD4</offset>
                <size>8</size>
                <usage>registers</usage>
            </addressBlock>
            <registers>
                <register>
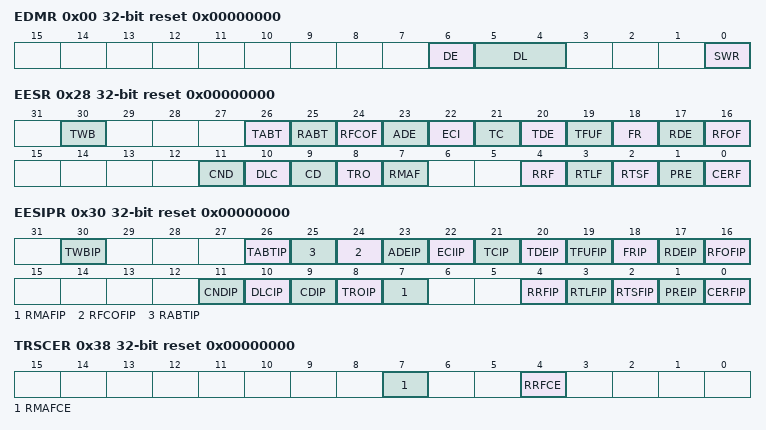
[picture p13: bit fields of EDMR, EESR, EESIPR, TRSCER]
                    <name>EDMR</name>
                    <description>EDMAC Mode Register</description>
                    <addressOffset>0x00</addressOffset>
                    <size>32</size>
                    <access>read-write</access>
                    <resetValue>0x00000000</resetValue>
                    <resetMask>0xffffffff</resetMask>
                    <fields>
                        <field>
                            <name>SWR</name>
                            <description>Software Reset</description>
                            <lsb>0</lsb>
                            <msb>0</msb>
                            <access>read-write</access>
                        </field>
                        <field>
                            <name>DL</name>
                            <description>Transmit/Receive Descriptor Length</description>
                            <lsb>4</lsb>
                            <msb>5</msb>
                            <access>read-write</access>
                            <enumeratedValues>
                                <enumeratedValue>
                                    <name>00</name>
                                    <description>16 bytes</description>
                                    <value>#00</value>
                                </enumeratedValue>
                                <enumeratedValue>
                                    <name>01</name>
                                    <description>32 bytes</description>
                                    <value>#01</value>
                                </enumeratedValue>
                                <enumeratedValue>
                                    <name>10</name>
                                    <description>64 bytes</description>
                                    <value>#10</value>
                                </enumeratedValue>
                                <enumeratedValue>
                                    <name>11</name>
                                    <description>16 bytes.</description>
                                    <value>#11</value>
                                </enumeratedValue>
                            </enumeratedValues>
                        </field>
                        <field>
                            <name>DE</name>
                            <description>Big Endian Mode/Little Endian Mode</description>
                            <lsb>6</lsb>
                            <msb>6</msb>
                            <access>read-write</access>
                            <enumeratedValues>
                                <enumeratedValue>
                                    <name>0</name>
                                    <description>Big endian mode</description>
                                    <value>#0</value>
                                </enumeratedValue>
                                <enumeratedValue>
                                    <name>1</name>
                                    <description>Little endian mode.</description>
                                    <value>#1</value>
                                </enumeratedValue>
                            </enumeratedValues>
                        </field>
                    </fields>
                </register>
                <register>
                    <name>EDTRR</name>
                    <description>EDMAC Transmit Request Register</description>
                    <addressOffset>0x08</addressOffset>
                    <size>32</size>
                    <access>read-write</access>
                    <resetValue>0x00000000</resetValue>
                    <resetMask>0xffffffff</resetMask>
                    <fields>
                        <field>
                            <name>TR</name>
                            <description>Transmit Request</description>
                            <lsb>0</lsb>
                            <msb>0</msb>
                            <access>read-write</access>
                        </field>
                    </fields>
                </register>
                <register>
                    <name>EDRRR</name>
                    <description>EDMAC Receive Request Register</description>
                    <addressOffset>0x10</addressOffset>
                    <size>32</size>
                    <access>read-write</access>
                    <resetValue>0x00000000</resetValue>
                    <resetMask>0xffffffff</resetMask>
                    <fields>
                        <field>
                            <name>RR</name>
                            <description>Receive Request</description>
                            <lsb>0</lsb>
                            <msb>0</msb>
                            <access>read-write</access>
                            <enumeratedValues>
                                <enumeratedValue>
                                    <name>0</name>
                                    <description>Disable the receive function</description>
                                    <value>#0</value>
                                </enumeratedValue>
                                <enumeratedValue>
                                    <name>1</name>
                                    <description>Read receive descriptor and enable the receive function.</description>
                                    <value>#1</value>
                                </enumeratedValue>
                            </enumeratedValues>
                        </field>
                    </fields>
                </register>
                <register>
                    <name>TDLAR</name>
                    <description>Transmit Descriptor List Start Address Register</description>
                    <addressOffset>0x18</addressOffset>
                    <size>32</size>
                    <access>read-write</access>
                    <resetValue>0x00000000</resetValue>
                    <resetMask>0xffffffff</resetMask>
                </register>
                <register>
                    <name>RDLAR</name>
                    <description>Receive Descriptor List Start Address Register</description>
                    <addressOffset>0x20</addressOffset>
                    <size>32</size>
                    <access>read-write</access>
                    <resetValue>0x00000000</resetValue>
                    <resetMask>0xffffffff</resetMask>
                </register>
                <register>
                    <name>EESR</name>
                    <description>ETHERC/EDMAC Status Register</description>
                    <addressOffset>0x28</addressOffset>
                    <size>32</size>
                    <access>read-write</access>
                    <resetValue>0x00000000</resetValue>
                    <resetMask>0xffffffff</resetMask>
                    <fields>
                        <field>
                            <name>CERF</name>
                            <description>CRC Error Flag</description>
                            <lsb>0</lsb>
                            <msb>0</msb>
                            <access>read-write</access>
                            <enumeratedValues>
                                <enumeratedValue>
                                    <name>0</name>
                                    <description>CRC error not detected</description>
                                    <value>#0</value>
                                </enumeratedValue>
                                <enumeratedValue>
                                    <name>1</name>
                                    <description>CRC error detected.</description>
                                    <value>#1</value>
                                </enumeratedValue>
                            </enumeratedValues>
                        </field>
                        <field>
                            <name>PRE</name>
                            <description>PHY-LSI Receive Error Flag</description>
                            <lsb>1</lsb>
                            <msb>1</msb>
                            <access>read-write</access>
                            <enumeratedValues>
                                <enumeratedValue>
                                    <name>0</name>
                                    <description>PHY-LSI receive error not detected</description>
                                    <value>#0</value>
                                </enumeratedValue>
                                <enumeratedValue>
                                    <name>1</name>
                                    <description>PHY-LSI receive error detected.</description>
                                    <value>#1</value>
                                </enumeratedValue>
                            </enumeratedValues>
                        </field>
                        <field>
                            <name>RTSF</name>
                            <description>Frame-Too-Short Error Flag</description>
                            <lsb>2</lsb>
                            <msb>2</msb>
                            <access>read-write</access>
                            <enumeratedValues>
                                <enumeratedValue>
                                    <name>0</name>
                                    <description>Frame-too-short error not detected</description>
                                    <value>#0</value>
                                </enumeratedValue>
                                <enumeratedValue>
                                    <name>1</name>
                                    <description>Frame-too-short error detected.</description>
                                    <value>#1</value>
                                </enumeratedValue>
                            </enumeratedValues>
                        </field>
                        <field>
                            <name>RTLF</name>
                            <description>Frame-Too-Long Error Flag</description>
                            <lsb>3</lsb>
                            <msb>3</msb>
                            <access>read-write</access>
                            <enumeratedValues>
                                <enumeratedValue>
                                    <name>0</name>
                                    <description>Frame-too-long error not detected</description>
                                    <value>#0</value>
                                </enumeratedValue>
                                <enumeratedValue>
                                    <name>1</name>
                                    <description>Frame-too-long error detected.</description>
                                    <value>#1</value>
                                </enumeratedValue>
                            </enumeratedValues>
                        </field>
                        <field>
                            <name>RRF</name>
                            <description>Alignment Error Flag</description>
                            <lsb>4</lsb>
                            <msb>4</msb>
                            <access>read-write</access>
                            <enumeratedValues>
                                <enumeratedValue>
                                    <name>0</name>
                                    <description>Alignment error not detected</description>
                                    <value>#0</value>
                                </enumeratedValue>
                                <enumeratedValue>
                                    <name>1</name>
                                    <description>Alignment error detected.</description>
                                    <value>#1</value>
                                </enumeratedValue>
                            </enumeratedValues>
                        </field>
                        <field>
                            <name>RMAF</name>
                            <description>Multicast Address Frame Receive Flag</description>
                            <lsb>7</lsb>
                            <msb>7</msb>
                            <access>read-write</access>
                            <enumeratedValues>
                                <enumeratedValue>
                                    <name>0</name>
                                    <description>Multicast address frame not received</description>
                                    <value>#0</value>
                                </enumeratedValue>
                                <enumeratedValue>
                                    <name>1</name>
                                    <description>Multicast address frame received.</description>
                                    <value>#1</value>
                                </enumeratedValue>
                            </enumeratedValues>
                        </field>
                        <field>
                            <name>TRO</name>
                            <description>Transmit Retry Over Flag</description>
                            <lsb>8</lsb>
                            <msb>8</msb>
                            <access>read-write</access>
                            <enumeratedValues>
                                <enumeratedValue>
                                    <name>0</name>
                                    <description>Transmit retry-over condition not detected</description>
                                    <value>#0</value>
                                </enumeratedValue>
                                <enumeratedValue>
                                    <name>1</name>
                                    <description>Transmit retry-over condition detected.</description>
                                    <value>#1</value>
                                </enumeratedValue>
                            </enumeratedValues>
                        </field>
                        <field>
                            <name>CD</name>
                            <description>Late Collision Detect Flag</description>
                            <lsb>9</lsb>
                            <msb>9</msb>
                            <access>read-write</access>
                            <enumeratedValues>
                                <enumeratedValue>
                                    <name>0</name>
                                    <description>Late collision not detected</description>
                                    <value>#0</value>
                                </enumeratedValue>
                                <enumeratedValue>
                                    <name>1</name>
                                    <description>Late collision detected during frame transmission.</description>
                                    <value>#1</value>
                                </enumeratedValue>
                            </enumeratedValues>
                        </field>
                        <field>
                            <name>DLC</name>
                            <description>Loss of Carrier Detect Flag</description>
                            <lsb>10</lsb>
                            <msb>10</msb>
                            <access>read-write</access>
                            <enumeratedValues>
                                <enumeratedValue>
                                    <name>0</name>
                                    <description>Loss of carrier not detected</description>
                                    <value>#0</value>
                                </enumeratedValue>
                                <enumeratedValue>
                                    <name>1</name>
                                    <description>Loss of carrier detected during frame transmission.</description>
                                    <value>#1</value>
                                </enumeratedValue>
                            </enumeratedValues>
                        </field>
                        <field>
                            <name>CND</name>
                            <description>Carrier Not Detect Flag</description>
                            <lsb>11</lsb>
                            <msb>11</msb>
                            <access>read-write</access>
                            <enumeratedValues>
                                <enumeratedValue>
                                    <name>0</name>
                                    <description>Carrier detected when transmission started</description>
                                    <value>#0</value>
                                </enumeratedValue>
                                <enumeratedValue>
                                    <name>1</name>
                                    <description>Carrier not detected during preamble transmission.</description>
                                    <value>#1</value>
                                </enumeratedValue>
                            </enumeratedValues>
                        </field>
                        <field>
                            <name>RFOF</name>
                            <description>Receive FIFO Overflow Flag</description>
                            <lsb>16</lsb>
                            <msb>16</msb>
                            <access>read-write</access>
                            <enumeratedValues>
                                <enumeratedValue>
                                    <name>0</name>
                                    <description>No overflow occurred</description>
                                    <value>#0</value>
                                </enumeratedValue>
                                <enumeratedValue>
                                    <name>1</name>
                                    <description>Overflow occurred.</description>
                                    <value>#1</value>
                                </enumeratedValue>
                            </enumeratedValues>
                        </field>
                        <field>
                            <name>RDE</name>
                            <description>Receive Descriptor Empty Flag</description>
                            <lsb>17</lsb>
                            <msb>17</msb>
                            <access>read-write</access>
                            <enumeratedValues>
                                <enumeratedValue>
                                    <name>0</name>
                                    <description>EDMAC detected that the receive descriptor valid bit (RD0.RACT) is 1 </description>
                                    <value>#0</value>
                                </enumeratedValue>
                                <enumeratedValue>
                                    <name>1</name>
                                    <description>EDMAC detected that the receive descriptor valid bit (RD0.RACT) is 0. </description>
                                    <value>#1</value>
                                </enumeratedValue>
                            </enumeratedValues>
                        </field>
                        <field>
                            <name>FR</name>
                            <description>Frame Receive Flag</description>
                            <lsb>18</lsb>
                            <msb>18</msb>
                            <access>read-write</access>
                            <enumeratedValues>
                                <enumeratedValue>
                                    <name>0</name>
                                    <description>Frame not received</description>
                                    <value>#0</value>
                                </enumeratedValue>
                                <enumeratedValue>
                                    <name>1</name>
                                    <description>Frame received and update of the receive descriptor is complete. </description>
                                    <value>#1</value>
                                </enumeratedValue>
                            </enumeratedValues>
                        </field>
                        <field>
                            <name>TFUF</name>
                            <description>Transmit FIFO Underflow Flag</description>
                            <lsb>19</lsb>
                            <msb>19</msb>
                            <access>read-write</access>
                            <enumeratedValues>
                                <enumeratedValue>
                                    <name>0</name>
                                    <description>No underflow occurred</description>
                                    <value>#0</value>
                                </enumeratedValue>
                                <enumeratedValue>
                                    <name>1</name>
                                    <description>Underflow occurred.</description>
                                    <value>#1</value>
                                </enumeratedValue>
                            </enumeratedValues>
                        </field>
                        <field>
                            <name>TDE</name>
                            <description>Transmit Descriptor Empty Flag</description>
                            <lsb>20</lsb>
                            <msb>20</msb>
                            <access>read-write</access>
                            <enumeratedValues>
                                <enumeratedValue>
                                    <name>0</name>
                                    <description>EDMAC detected that the transmit descriptor valid bit (TD0.TACT) is 1 </description>
                                    <value>#0</value>
                                </enumeratedValue>
                                <enumeratedValue>
                                    <name>1</name>
                                    <description>EDMAC detected that the transmit descriptor valid bit (TD0.TACT) is 0. </description>
                                    <value>#1</value>
                                </enumeratedValue>
                            </enumeratedValues>
                        </field>
                        <field>
                            <name>TC</name>
                            <description>Frame Transfer Complete Flag</description>
                            <lsb>21</lsb>
                            <msb>21</msb>
                            <access>read-write</access>
                            <enumeratedValues>
                                <enumeratedValue>
                                    <name>0</name>
                                    <description>Transfer not complete or no transfer requested</description>
                                    <value>#0</value>
                                </enumeratedValue>
                                <enumeratedValue>
                                    <name>1</name>
                                    <description>All frames indicated in the transmit descriptor were completely transferred to the transmit FIFO. </description>
                                    <value>#1</value>
                                </enumeratedValue>
                            </enumeratedValues>
                        </field>
                        <field>
                            <name>ECI</name>
                            <description>ETHERC Status Register Source Flag</description>
                            <lsb>22</lsb>
                            <msb>22</msb>
                            <access>read-only</access>
                            <enumeratedValues>
                                <enumeratedValue>
                                    <name>0</name>
                                    <description>ETHERC status interrupt source not detected</description>
                                    <value>#0</value>
                                </enumeratedValue>
                                <enumeratedValue>
                                    <name>1</name>
                                    <description>ETHERC status interrupt source detected.</description>
                                    <value>#1</value>
                                </enumeratedValue>
                            </enumeratedValues>
                        </field>
                        <field>
                            <name>ADE</name>
                            <description>Address Error Flag</description>
                            <lsb>23</lsb>
                            <msb>23</msb>
                            <access>read-write</access>
                            <enumeratedValues>
                                <enumeratedValue>
                                    <name>0</name>
                                    <description>Invalid memory address not detected (normal operation)</description>
                                    <value>#0</value>
                                </enumeratedValue>
                                <enumeratedValue>
                                    <name>1</name>
                                    <description>Invalid memory address detected.</description>
                                    <value>#1</value>
                                </enumeratedValue>
                            </enumeratedValues>
                        </field>
                        <field>
                            <name>RFCOF</name>
                            <description>Receive Frame Counter Overflow Flag</description>
                            <lsb>24</lsb>
                            <msb>24</msb>
                            <access>read-write</access>
                            <enumeratedValues>
                                <enumeratedValue>
                                    <name>0</name>
                                    <description>Receive frame counter did not overflow</description>
                                    <value>#0</value>
                                </enumeratedValue>
                                <enumeratedValue>
                                    <name>1</name>
                                    <description>Receive frame counter overflowed.</description>
                                    <value>#1</value>
                                </enumeratedValue>
                            </enumeratedValues>
                        </field>
                        <field>
                            <name>RABT</name>
                            <description>Receive Abort Detect Flag</description>
                            <lsb>25</lsb>
                            <msb>25</msb>
                            <access>read-write</access>
                            <enumeratedValues>
                                <enumeratedValue>
                                    <name>0</name>
                                    <description>Frame reception not aborted or no reception requested</description>
                                    <value>#0</value>
                                </enumeratedValue>
                                <enumeratedValue>
                                    <name>1</name>
                                    <description>Frame reception aborted.</description>
                                    <value>#1</value>
                                </enumeratedValue>
                            </enumeratedValues>
                        </field>
                        <field>
                            <name>TABT</name>
                            <description>Transmit Abort Detect Flag</description>
                            <lsb>26</lsb>
                            <msb>26</msb>
                            <access>read-write</access>
                            <enumeratedValues>
                                <enumeratedValue>
                                    <name>0</name>
                                    <description>Frame transmission not aborted or no transmission requested. </description>
                                    <value>#0</value>
                                </enumeratedValue>
                                <enumeratedValue>
                                    <name>1</name>
                                    <description>Frame transmission aborted.</description>
                                    <value>#1</value>
                                </enumeratedValue>
                            </enumeratedValues>
                        </field>
                        <field>
                            <name>TWB</name>
                            <description>Write-Back Complete Flag</description>
                            <lsb>30</lsb>
                            <msb>30</msb>
                            <access>read-write</access>
                            <enumeratedValues>
                                <enumeratedValue>
                                    <name>0</name>
                                    <description>Write-back not complete or no transmission requested</description>
                                    <value>#0</value>
                                </enumeratedValue>
                                <enumeratedValue>
                                    <name>1</name>
                                    <description>Write-back to the transmit descriptor completed.</description>
                                    <value>#1</value>
                                </enumeratedValue>
                            </enumeratedValues>
                        </field>
                    </fields>
                </register>
                <register>
                    <name>EESIPR</name>
                    <description>ETHERC/EDMAC Status Interrupt Enable Register</description>
                    <addressOffset>0x30</addressOffset>
                    <size>32</size>
                    <access>read-write</access>
                    <resetValue>0x00000000</resetValue>
                    <resetMask>0xffffffff</resetMask>
                    <fields>
                        <field>
                            <name>CERFIP</name>
                            <description>CRC Error Interrupt Request Enable</description>
                            <lsb>0</lsb>
                            <msb>0</msb>
                            <access>read-write</access>
                            <enumeratedValues>
                                <enumeratedValue>
                                    <name>0</name>
                                    <description>Disable CRC error interrupt requests</description>
                                    <value>#0</value>
                                </enumeratedValue>
                                <enumeratedValue>
                                    <name>1</name>
                                    <description>Enable CRC error interrupt requests.</description>
                                    <value>#1</value>
                                </enumeratedValue>
                            </enumeratedValues>
                        </field>
                        <field>
                            <name>PREIP</name>
                            <description>PHY-LSI Receive Error Interrupt Request Enable</description>
                            <lsb>1</lsb>
                            <msb>1</msb>
                            <access>read-write</access>
                            <enumeratedValues>
                                <enumeratedValue>
                                    <name>0</name>
                                    <description>Disable PHY-LSI receive error interrupt requests</description>
                                    <value>#0</value>
                                </enumeratedValue>
                                <enumeratedValue>
                                    <name>1</name>
                                    <description>Enable PHY-LSI receive error interrupt requests.</description>
                                    <value>#1</value>
                                </enumeratedValue>
                            </enumeratedValues>
                        </field>
                        <field>
                            <name>RTSFIP</name>
                            <description>Frame-Too-Short Error Interrupt Request Enable</description>
                            <lsb>2</lsb>
                            <msb>2</msb>
                            <access>read-write</access>
                            <enumeratedValues>
                                <enumeratedValue>
                                    <name>0</name>
                                    <description>Disable frame-too-short error interrupt requests</description>
                                    <value>#0</value>
                                </enumeratedValue>
                                <enumeratedValue>
                                    <name>1</name>
                                    <description>Enable frame-too-short error interrupt requests.</description>
                                    <value>#1</value>
                                </enumeratedValue>
                            </enumeratedValues>
                        </field>
                        <field>
                            <name>RTLFIP</name>
                            <description>Frame-Too-Long Error Interrupt Request Enable</description>
                            <lsb>3</lsb>
                            <msb>3</msb>
                            <access>read-write</access>
                            <enumeratedValues>
                                <enumeratedValue>
                                    <name>0</name>
                                    <description>Disable frame-too-long error interrupt requests</description>
                                    <value>#0</value>
                                </enumeratedValue>
                                <enumeratedValue>
                                    <name>1</name>
                                    <description>Enable frame-too-long error interrupt requests.</description>
                                    <value>#1</value>
                                </enumeratedValue>
                            </enumeratedValues>
                        </field>
                        <field>
                            <name>RRFIP</name>
                            <description>Alignment Error Interrupt Request Enable</description>
                            <lsb>4</lsb>
                            <msb>4</msb>
                            <access>read-write</access>
                            <enumeratedValues>
                                <enumeratedValue>
                                    <name>0</name>
                                    <description>Disable alignment error interrupt requests</description>
                                    <value>#0</value>
                                </enumeratedValue>
                                <enumeratedValue>
                                    <name>1</name>
                                    <description>Enable alignment error interrupt requests.</description>
                                    <value>#1</value>
                                </enumeratedValue>
                            </enumeratedValues>
                        </field>
                        <field>
                            <name>RMAFIP</name>
                            <description>Multicast Address Frame Receive Interrupt Request Enable</description>
                            <lsb>7</lsb>
                            <msb>7</msb>
                            <access>read-write</access>
                            <enumeratedValues>
                                <enumeratedValue>
                                    <name>0</name>
                                    <description>Disable multicast address frame receive interrupt requests </description>
                                    <value>#0</value>
                                </enumeratedValue>
                                <enumeratedValue>
                                    <name>1</name>
                                    <description>Enable multicast address frame receive interrupt requests. </description>
                                    <value>#1</value>
                                </enumeratedValue>
                            </enumeratedValues>
                        </field>
                        <field>
                            <name>TROIP</name>
                            <description>Transmit Retry Over Interrupt Request Enable</description>
                            <lsb>8</lsb>
                            <msb>8</msb>
                            <access>read-write</access>
                            <enumeratedValues>
                                <enumeratedValue>
                                    <name>0</name>
                                    <description>Disable transmit retry over interrupt requests</description>
                                    <value>#0</value>
                                </enumeratedValue>
                                <enumeratedValue>
                                    <name>1</name>
                                    <description>Enable transmit retry over interrupt requests.</description>
                                    <value>#1</value>
                                </enumeratedValue>
                            </enumeratedValues>
                        </field>
                        <field>
                            <name>CDIP</name>
                            <description>Late Collision Detect Interrupt Request Enable</description>
                            <lsb>9</lsb>
                            <msb>9</msb>
                            <access>read-write</access>
                            <enumeratedValues>
                                <enumeratedValue>
                                    <name>0</name>
                                    <description>Disable late collision detected interrupt requests</description>
                                    <value>#0</value>
                                </enumeratedValue>
                                <enumeratedValue>
                                    <name>1</name>
                                    <description>Enable late collision detected interrupt requests.</description>
                                    <value>#1</value>
                                </enumeratedValue>
                            </enumeratedValues>
                        </field>
                        <field>
                            <name>DLCIP</name>
                            <description>Loss of Carrier Detect Interrupt Request Enable</description>
                            <lsb>10</lsb>
                            <msb>10</msb>
                            <access>read-write</access>
                            <enumeratedValues>
                                <enumeratedValue>
                                    <name>0</name>
                                    <description>Disable loss of carrier detected interrupt requests</description>
                                    <value>#0</value>
                                </enumeratedValue>
                                <enumeratedValue>
                                    <name>1</name>
                                    <description>Enable loss of carrier detected interrupt requests.</description>
                                    <value>#1</value>
                                </enumeratedValue>
                            </enumeratedValues>
                        </field>
                        <field>
                            <name>CNDIP</name>
                            <description>Carrier Not Detect Interrupt Request Enable</description>
                            <lsb>11</lsb>
                            <msb>11</msb>
                            <access>read-write</access>
                            <enumeratedValues>
                                <enumeratedValue>
                                    <name>0</name>
                                    <description>Disable carrier not detected interrupt requests</description>
                                    <value>#0</value>
                                </enumeratedValue>
                                <enumeratedValue>
                                    <name>1</name>
                                    <description>Enable carrier not detected interrupt requests.</description>
                                    <value>#1</value>
                                </enumeratedValue>
                            </enumeratedValues>
                        </field>
                        <field>
                            <name>RFOFIP</name>
                            <description>Receive FIFO Overflow Interrupt Request Enable</description>
                            <lsb>16</lsb>
                            <msb>16</msb>
                            <access>read-write</access>
                            <enumeratedValues>
                                <enumeratedValue>
                                    <name>0</name>
                                    <description>Disable overflow interrupt requests</description>
                                    <value>#0</value>
                                </enumeratedValue>
                                <enumeratedValue>
                                    <name>1</name>
                                    <description>Enable overflow interrupt requests.</description>
                                    <value>#1</value>
                                </enumeratedValue>
                            </enumeratedValues>
                        </field>
                        <field>
                            <name>RDEIP</name>
                            <description>Receive Descriptor Empty Interrupt Request Enable</description>
                            <lsb>17</lsb>
                            <msb>17</msb>
                            <access>read-write</access>
                            <enumeratedValues>
                                <enumeratedValue>
                                    <name>0</name>
                                    <description>Disable receive descriptor empty interrupt requests</description>
                                    <value>#0</value>
                                </enumeratedValue>
                                <enumeratedValue>
                                    <name>1</name>
                                    <description>Enable receive descriptor empty interrupt requests.</description>
                                    <value>#1</value>
                                </enumeratedValue>
                            </enumeratedValues>
                        </field>
                        <field>
                            <name>FRIP</name>
                            <description>Frame Receive Interrupt Request Enable</description>
                            <lsb>18</lsb>
                            <msb>18</msb>
                            <access>read-write</access>
                            <enumeratedValues>
                                <enumeratedValue>
                                    <name>0</name>
                                    <description>Disable frame reception interrupt requests</description>
                                    <value>#0</value>
                                </enumeratedValue>
                                <enumeratedValue>
                                    <name>1</name>
                                    <description>Enable frame reception interrupt requests.</description>
                                    <value>#1</value>
                                </enumeratedValue>
                            </enumeratedValues>
                        </field>
                        <field>
                            <name>TFUFIP</name>
                            <description>Transmit FIFO Underflow Interrupt Request Enable</description>
                            <lsb>19</lsb>
                            <msb>19</msb>
                            <access>read-write</access>
                            <enumeratedValues>
                                <enumeratedValue>
                                    <name>0</name>
                                    <description>Disable underflow interrupt requests</description>
                                    <value>#0</value>
                                </enumeratedValue>
                                <enumeratedValue>
                                    <name>1</name>
                                    <description>Enable underflow interrupt requests.</description>
                                    <value>#1</value>
                                </enumeratedValue>
                            </enumeratedValues>
                        </field>
                        <field>
                            <name>TDEIP</name>
                            <description>Transmit Descriptor Empty Interrupt Request Enable</description>
                            <lsb>20</lsb>
                            <msb>20</msb>
                            <access>read-write</access>
                            <enumeratedValues>
                                <enumeratedValue>
                                    <name>0</name>
                                    <description>Disable transmit descriptor empty interrupt requests</description>
                                    <value>#0</value>
                                </enumeratedValue>
                                <enumeratedValue>
                                    <name>1</name>
                                    <description>Enable transmit descriptor empty interrupt requests.</description>
                                    <value>#1</value>
                                </enumeratedValue>
                            </enumeratedValues>
                        </field>
                        <field>
                            <name>TCIP</name>
                            <description>Frame Transfer Complete Interrupt Request Enable</description>
                            <lsb>21</lsb>
                            <msb>21</msb>
                            <access>read-write</access>
                            <enumeratedValues>
                                <enumeratedValue>
                                    <name>0</name>
                                    <description>Disable frame transmission complete interrupt requests </description>
                                    <value>#0</value>
                                </enumeratedValue>
                                <enumeratedValue>
                                    <name>1</name>
                                    <description>Enable frame transmission complete interrupt requests. </description>
                                    <value>#1</value>
                                </enumeratedValue>
                            </enumeratedValues>
                        </field>
                        <field>
                            <name>ECIIP</name>
                            <description>ETHERC Status Register Source Interrupt Request Enable</description>
                            <lsb>22</lsb>
                            <msb>22</msb>
                            <access>read-write</access>
                            <enumeratedValues>
                                <enumeratedValue>
                                    <name>0</name>
                                    <description>Disable ETHERC status interrupt requests</description>
                                    <value>#0</value>
                                </enumeratedValue>
                                <enumeratedValue>
                                    <name>1</name>
                                    <description>Enable ETHERC status interrupt requests.</description>
                                    <value>#1</value>
                                </enumeratedValue>
                            </enumeratedValues>
                        </field>
                        <field>
                            <name>ADEIP</name>
                            <description>Address Error Interrupt Request Enable</description>
                            <lsb>23</lsb>
                            <msb>23</msb>
                            <access>read-write</access>
                            <enumeratedValues>
                                <enumeratedValue>
                                    <name>0</name>
                                    <description>Disable address error interrupt requests</description>
                                    <value>#0</value>
                                </enumeratedValue>
                                <enumeratedValue>
                                    <name>1</name>
                                    <description>Enable address error interrupt requests.</description>
                                    <value>#1</value>
                                </enumeratedValue>
                            </enumeratedValues>
                        </field>
                        <field>
                            <name>RFCOFIP</name>
                            <description>Receive Frame Counter Overflow Interrupt Request Enable</description>
                            <lsb>24</lsb>
                            <msb>24</msb>
                            <access>read-write</access>
                            <enumeratedValues>
                                <enumeratedValue>
                                    <name>0</name>
                                    <description>Disable receive frame counter overflow interrupt requests </description>
                                    <value>#0</value>
                                </enumeratedValue>
                                <enumeratedValue>
                                    <name>1</name>
                                    <description>Enable receive frame counter overflow interrupt requests. </description>
                                    <value>#1</value>
                                </enumeratedValue>
                            </enumeratedValues>
                        </field>
                        <field>
                            <name>RABTIP</name>
                            <description>Receive Abort Detect Interrupt Request Enable</description>
                            <lsb>25</lsb>
                            <msb>25</msb>
                            <access>read-write</access>
                            <enumeratedValues>
                                <enumeratedValue>
                                    <name>0</name>
                                    <description>Disable receive abort detected interrupt requests</description>
                                    <value>#0</value>
                                </enumeratedValue>
                                <enumeratedValue>
                                    <name>1</name>
                                    <description>Enable receive abort detected interrupt requests.</description>
                                    <value>#1</value>
                                </enumeratedValue>
                            </enumeratedValues>
                        </field>
                        <field>
                            <name>TABTIP</name>
                            <description>Transmit Abort Detect Interrupt Request Enable</description>
                            <lsb>26</lsb>
                            <msb>26</msb>
                            <access>read-write</access>
                            <enumeratedValues>
                                <enumeratedValue>
                                    <name>0</name>
                                    <description>Disable transmit abort detected interrupt requests</description>
                                    <value>#0</value>
                                </enumeratedValue>
                                <enumeratedValue>
                                    <name>1</name>
                                    <description>Enable transmit abort detected interrupt requests.</description>
                                    <value>#1</value>
                                </enumeratedValue>
                            </enumeratedValues>
                        </field>
                        <field>
                            <name>TWBIP</name>
                            <description>Write-Back Complete Interrupt Request Enable</description>
                            <lsb>30</lsb>
                            <msb>30</msb>
                            <access>read-write</access>
                            <enumeratedValues>
                                <enumeratedValue>
                                    <name>0</name>
                                    <description>Disable write-back complete interrupt requests</description>
                                    <value>#0</value>
                                </enumeratedValue>
                                <enumeratedValue>
                                    <name>1</name>
                                    <description>Enable write-back complete interrupt requests.</description>
                                    <value>#1</value>
                                </enumeratedValue>
                            </enumeratedValues>
                        </field>
                    </fields>
                </register>
                <register>
                    <name>TRSCER</name>
                    <description>ETHERC/EDMAC Transmit/Receive Status Copy Enable Register</description>
                    <addressOffset>0x38</addressOffset>
                    <size>32</size>
                    <access>read-write</access>
                    <resetValue>0x00000000</resetValue>
                    <resetMask>0xffffffff</resetMask>
                    <fields>
                        <field>
                            <name>RRFCE</name>
                            <description>RRF Flag Copy Enable</description>
                            <lsb>4</lsb>
                            <msb>4</msb>
                            <access>read-write</access>
                            <enumeratedValues>
                                <enumeratedValue>
                                    <name>0</name>
                                    <description>Reflect the EESR.RRF flag status in the RD0.RFE bit of the receive descriptor </description>
                                    <value>#0</value>
                                </enumeratedValue>
                                <enumeratedValue>
                                    <name>1</name>
                                    <description>Do not reflect the EESR.RRF flag status in the RD0.RFE bit of the receive descriptor. </description>
                                    <value>#1</value>
                                </enumeratedValue>
                            </enumeratedValues>
                        </field>
                        <field>
                            <name>RMAFCE</name>
                            <description>RMAF Flag Copy Enable</description>
                            <lsb>7</lsb>
                            <msb>7</msb>
                            <access>read-write</access>
                            <enumeratedValues>
                                <enumeratedValue>
                                    <name>0</name>
                                    <description>Reflect the EESR.RMAF flag status in the RD0.RFE bit of the receive descriptor </description>
                                    <value>#0</value>
                                </enumeratedValue>
                                <enumeratedValue>
                                    <name>1</name>
                                    <description>Do not reflect the EESR.RMAF flag status in the RD0.RFE bit of the receive descriptor. </description>
                                    <value>#1</value>
                                </enumeratedValue>
                            </enumeratedValues>
                        </field>
                    </fields>
                </register>
                <register>
                    <name>RMFCR</name>
                    <description>Missed-Frame Counter Register</description>
                    <addressOffset>0x40</addressOffset>
                    <size>32</size>
                    <access>read-write</access>
                    <resetValue>0x00000000</resetValue>
                    <resetMask>0xffffffff</resetMask>
                    <fields>
                        <field>
                            <name>MFC</name>
                            <description>Missed-Frame Counter</description>
                            <lsb>0</lsb>
                            <msb>15</msb>
                            <access>read-write</access>
                        </field>
                    </fields>
                </register>
                <register>
                    <name>TFTR</name>
                    <description>Transmit FIFO Threshold Register</description>
                    <addressOffset>0x48</addressOffset>
                    <size>32</size>
                    <access>read-write</access>
                    <resetValue>0x00000000</resetValue>
                    <resetMask>0xffffffff</resetMask>
                    <fields>
                        <field>
                            <name>TFT</name>
                            <description>Transmit FIFO Threshold</description>
                            <lsb>0</lsb>
                            <msb>10</msb>
                            <access>read-write</access>
                        </field>
                    </fields>
                </register>
                <register>
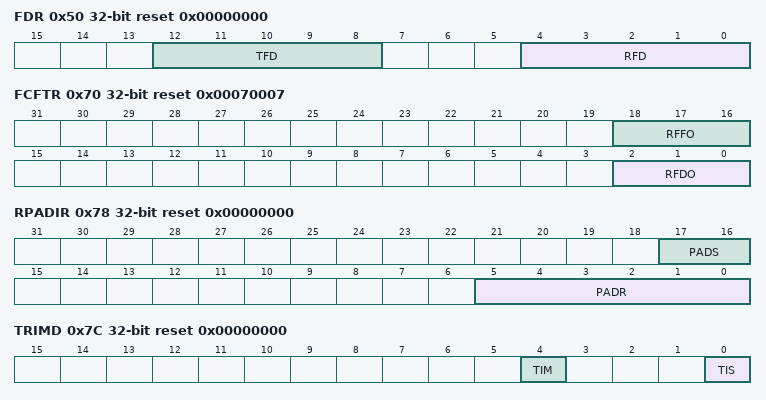
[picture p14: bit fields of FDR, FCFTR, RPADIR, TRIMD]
                    <name>FDR</name>
                    <description>FIFO Depth Register</description>
                    <addressOffset>0x50</addressOffset>
                    <size>32</size>
                    <access>read-write</access>
                    <resetValue>0x00000000</resetValue>
                    <resetMask>0xffffffff</resetMask>
                    <fields>
                        <field>
                            <name>RFD</name>
                            <description>Receive FIFO Depth</description>
                            <lsb>0</lsb>
                            <msb>4</msb>
                            <access>read-write</access>
                            <enumeratedValues>
                                <enumeratedValue>
                                    <name>0x0F</name>
                                    <description>4096 bytes</description>
                                    <value>0x0f</value>
                                </enumeratedValue>
                                <enumeratedValue>
                                    <name>Others</name>
                                    <description>settings prohibited</description>
                                    <isDefault>true</isDefault>
                                </enumeratedValue>
                            </enumeratedValues>
                        </field>
                        <field>
                            <name>TFD</name>
                            <description>Transmit FIFO Depth</description>
                            <lsb>8</lsb>
                            <msb>12</msb>
                            <access>read-write</access>
                            <enumeratedValues>
                                <enumeratedValue>
                                    <name>0x07</name>
                                    <description>2048 bytes</description>
                                    <value>0x07</value>
                                </enumeratedValue>
                                <enumeratedValue>
                                    <name>Others</name>
                                    <description>settings prohibited</description>
                                    <isDefault>true</isDefault>
                                </enumeratedValue>
                            </enumeratedValues>
                        </field>
                    </fields>
                </register>
                <register>
                    <name>RMCR</name>
                    <description>Receive Method Control Register</description>
                    <addressOffset>0x58</addressOffset>
                    <size>32</size>
                    <access>read-write</access>
                    <resetValue>0x00000000</resetValue>
                    <resetMask>0xffffffff</resetMask>
                    <fields>
                        <field>
                            <name>RNR</name>
                            <description>Receive Request Reset</description>
                            <lsb>0</lsb>
                            <msb>0</msb>
                            <access>read-write</access>
                            <enumeratedValues>
                                <enumeratedValue>
                                    <name>0</name>
                                    <description>EDRRR.RR bit (receive request bit) is cleared to 0 when one frame is received </description>
                                    <value>#0</value>
                                </enumeratedValue>
                                <enumeratedValue>
                                    <name>1</name>
                                    <description>EDRRR.RR bit (receive request bit) is not cleared to 0 when one frame is received. </description>
                                    <value>#1</value>
                                </enumeratedValue>
                            </enumeratedValues>
                        </field>
                    </fields>
                </register>
                <register>
                    <name>TFUCR</name>
                    <description>Transmit FIFO Underflow Counter</description>
                    <addressOffset>0x64</addressOffset>
                    <size>32</size>
                    <access>read-write</access>
                    <resetValue>0x00000000</resetValue>
                    <resetMask>0xffffffff</resetMask>
                    <fields>
                        <field>
                            <name>UNDER</name>
                            <description>Transmit FIFO Underflow Count</description>
                            <lsb>0</lsb>
                            <msb>15</msb>
                            <access>read-write</access>
                        </field>
                    </fields>
                </register>
                <register>
                    <name>RFOCR</name>
                    <description>Receive FIFO Overflow Counter</description>
                    <addressOffset>0x68</addressOffset>
                    <size>32</size>
                    <access>read-write</access>
                    <resetValue>0x00000000</resetValue>
                    <resetMask>0xffffffff</resetMask>
                    <fields>
                        <field>
                            <name>OVER</name>
                            <description>Receive FIFO Overflow Count</description>
                            <lsb>0</lsb>
                            <msb>15</msb>
                            <access>read-write</access>
                        </field>
                    </fields>
                </register>
                <register>
                    <name>IOSR</name>
                    <description>Independent Output Signal Setting Register</description>
                    <addressOffset>0x6C</addressOffset>
                    <size>32</size>
                    <access>read-write</access>
                    <resetValue>0x00000000</resetValue>
                    <resetMask>0xffffffff</resetMask>
                    <fields>
                        <field>
                            <name>ELB</name>
                            <description>External Loopback Mode</description>
                            <lsb>0</lsb>
                            <msb>0</msb>
                            <access>read-write</access>
                            <enumeratedValues>
                                <enumeratedValue>
                                    <name>0</name>
                                    <description>Output low on the ET0_EXOUT pin</description>
                                    <value>#0</value>
                                </enumeratedValue>
                                <enumeratedValue>
                                    <name>1</name>
                                    <description>Output high on the ET0_EXOUT pin.</description>
                                    <value>#1</value>
                                </enumeratedValue>
                            </enumeratedValues>
                        </field>
                    </fields>
                </register>
                <register>
                    <name>FCFTR</name>
                    <description>Flow Control Start FIFO Threshold Setting Register</description>
                    <addressOffset>0x70</addressOffset>
                    <size>32</size>
                    <access>read-write</access>
                    <resetValue>0x00070007</resetValue>
                    <resetMask>0xffffffff</resetMask>
                    <fields>
                        <field>
                            <name>RFDO</name>
                            <description>Receive FIFO Data PAUSE Output Threshold</description>
                            <lsb>0</lsb>
                            <msb>2</msb>
                            <access>read-write</access>
                        </field>
                        <field>
                            <name>RFFO</name>
                            <description>Receive FIFO Frame PAUSE Output Threshold</description>
                            <lsb>16</lsb>
                            <msb>18</msb>
                            <access>read-write</access>
                        </field>
                    </fields>
                </register>
                <register>
                    <name>RPADIR</name>
                    <description>Receive Data Padding Insert Register</description>
                    <addressOffset>0x78</addressOffset>
                    <size>32</size>
                    <access>read-write</access>
                    <resetValue>0x00000000</resetValue>
                    <resetMask>0xffffffff</resetMask>
                    <fields>
                        <field>
                            <name>PADR</name>
                            <description>Padding Slot</description>
                            <lsb>0</lsb>
                            <msb>5</msb>
                            <access>read-write</access>
                        </field>
                        <field>
                            <name>PADS</name>
                            <description>Padding Size</description>
                            <lsb>16</lsb>
                            <msb>17</msb>
                            <access>read-write</access>
                            <enumeratedValues>
                                <enumeratedValue>
                                    <name>00</name>
                                    <description>Do not insert padding</description>
                                    <value>#00</value>
                                </enumeratedValue>
                                <enumeratedValue>
                                    <name>Others</name>
                                    <description>settings prohibited</description>
                                    <isDefault>true</isDefault>
                                </enumeratedValue>
                            </enumeratedValues>
                        </field>
                    </fields>
                </register>
                <register>
                    <name>TRIMD</name>
                    <description>Transmit Interrupt Setting Register</description>
                    <addressOffset>0x7C</addressOffset>
                    <size>32</size>
                    <access>read-write</access>
                    <resetValue>0x00000000</resetValue>
                    <resetMask>0xffffffff</resetMask>
                    <fields>
                        <field>
                            <name>TIS</name>
                            <description>Transmit Interrupt Enable</description>
                            <lsb>0</lsb>
                            <msb>0</msb>
                            <access>read-write</access>
                            <enumeratedValues>
                                <enumeratedValue>
                                    <name>0</name>
                                    <description>Disable transmit interrupts</description>
                                    <value>#0</value>
                                </enumeratedValue>
                                <enumeratedValue>
                                    <name>1</name>
                                    <description>Enable transmit Interrupts.</description>
                                    <value>#1</value>
                                </enumeratedValue>
                            </enumeratedValues>
                        </field>
                        <field>
                            <name>TIM</name>
                            <description>Transmit Interrupt Mode</description>
                            <lsb>4</lsb>
                            <msb>4</msb>
                            <access>read-write</access>
                            <enumeratedValues>
                                <enumeratedValue>
                                    <name>0</name>
                                    <description>Select transmission complete interrupt mode, where an interrupt occurs when a frame is transmitted </description>
                                    <value>#0</value>
                                </enumeratedValue>
                                <enumeratedValue>
                                    <name>1</name>
                                    <description>Select write-back complete interrupt mode, where an interrupt occurs when write-back to the transmit descriptor is complete while the TWBI bit is 1. </description>
                                    <value>#1</value>
                                </enumeratedValue>
                            </enumeratedValues>
                        </field>
                    </fields>
                </register>
                <register>
                    <name>RBWAR</name>
                    <description>Receive Buffer Write Address Register</description>
                    <addressOffset>0xC8</addressOffset>
                    <size>32</size>
                    <access>read-only</access>
                    <resetValue>0x00000000</resetValue>
                    <resetMask>0xffffffff</resetMask>
                </register>
                <register>
                    <name>RDFAR</name>
                    <description>Receive Descriptor Fetch Address Register</description>
                    <addressOffset>0xCC</addressOffset>
                    <size>32</size>
                    <access>read-only</access>
                    <resetValue>0x00000000</resetValue>
                    <resetMask>0xffffffff</resetMask>
                </register>
                <register>
                    <name>TBRAR</name>
                    <description>Transmit Buffer Read Address Register</description>
                    <addressOffset>0xD4</addressOffset>
                    <size>32</size>
                    <access>read-only</access>
                    <resetValue>0x00000000</resetValue>
                    <resetMask>0xffffffff</resetMask>
                </register>
                <register>
                    <name>TDFAR</name>
                    <description>Transmit Descriptor Fetch Address Register</description>
                    <addressOffset>0xD8</addressOffset>
                    <size>32</size>
                    <access>read-only</access>
                    <resetValue>0x00000000</resetValue>
                    <resetMask>0xffffffff</resetMask>
                </register>
            </registers>
        </peripheral>
        <peripheral>
            <name>ETHERC0</name>
            <description>Ethernet Controller Channel 0</description>
            <baseAddress>0x40354100</baseAddress>
            <addressBlock>
                <offset>0x00</offset>
                <size>4</size>
                <usage>registers</usage>
            </addressBlock>
            <addressBlock>
                <offset>0x08</offset>
                <size>4</size>
                <usage>registers</usage>
            </addressBlock>
            <addressBlock>
                <offset>0x10</offset>
                <size>4</size>
                <usage>registers</usage>
            </addressBlock>
            <addressBlock>
                <offset>0x18</offset>
                <size>4</size>
                <usage>registers</usage>
            </addressBlock>
            <addressBlock>
                <offset>0x20</offset>
                <size>4</size>
                <usage>registers</usage>
            </addressBlock>
            <addressBlock>
                <offset>0x28</offset>
                <size>4</size>
                <usage>registers</usage>
            </addressBlock>
            <addressBlock>
                <offset>0x40</offset>
                <size>4</size>
                <usage>registers</usage>
            </addressBlock>
            <addressBlock>
                <offset>0x50</offset>
                <size>12</size>
                <usage>registers</usage>
            </addressBlock>
            <addressBlock>
                <offset>0x60</offset>
                <size>16</size>
                <usage>registers</usage>
            </addressBlock>
            <addressBlock>
                <offset>0xC0</offset>
                <size>4</size>
                <usage>registers</usage>
            </addressBlock>
            <addressBlock>
                <offset>0xC8</offset>
                <size>4</size>
                <usage>registers</usage>
            </addressBlock>
            <addressBlock>
                <offset>0xD0</offset>
                <size>16</size>
                <usage>registers</usage>
            </addressBlock>
            <addressBlock>
                <offset>0xE4</offset>
                <size>24</size>
                <usage>registers</usage>
            </addressBlock>
            <registers>
                <register>
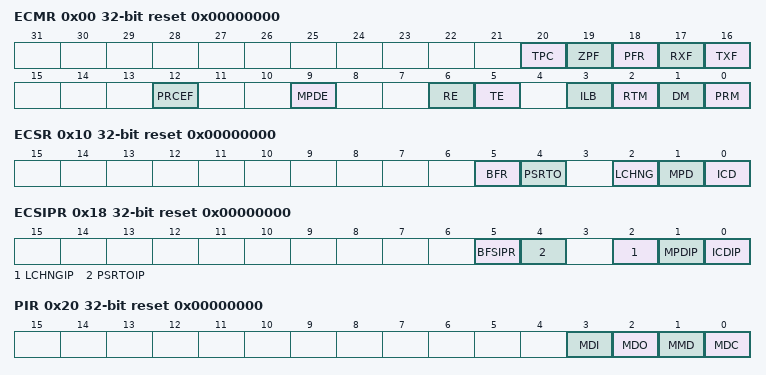
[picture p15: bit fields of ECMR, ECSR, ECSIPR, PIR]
                    <name>ECMR</name>
                    <description>ETHERC Mode Register</description>
                    <addressOffset>0x00</addressOffset>
                    <size>32</size>
                    <access>read-write</access>
                    <resetValue>0x00000000</resetValue>
                    <resetMask>0xffffffff</resetMask>
                    <fields>
                        <field>
                            <name>PRM</name>
                            <description>Promiscuous Mode</description>
                            <lsb>0</lsb>
                            <msb>0</msb>
                            <access>read-write</access>
                            <enumeratedValues>
                                <enumeratedValue>
                                    <name>0</name>
                                    <description>Disable promiscuous mode</description>
                                    <value>#0</value>
                                </enumeratedValue>
                                <enumeratedValue>
                                    <name>1</name>
                                    <description>Enable promiscuous mode.</description>
                                    <value>#1</value>
                                </enumeratedValue>
                            </enumeratedValues>
                        </field>
                        <field>
                            <name>DM</name>
                            <description>Duplex Mode</description>
                            <lsb>1</lsb>
                            <msb>1</msb>
                            <access>read-write</access>
                            <enumeratedValues>
                                <enumeratedValue>
                                    <name>0</name>
                                    <description>Half-duplex mode</description>
                                    <value>#0</value>
                                </enumeratedValue>
                                <enumeratedValue>
                                    <name>1</name>
                                    <description>Full-duplex mode.</description>
                                    <value>#1</value>
                                </enumeratedValue>
                            </enumeratedValues>
                        </field>
                        <field>
                            <name>RTM</name>
                            <description>Bit Rate</description>
                            <lsb>2</lsb>
                            <msb>2</msb>
                            <access>read-write</access>
                            <enumeratedValues>
                                <enumeratedValue>
                                    <name>0</name>
                                    <description>10 Mbps</description>
                                    <value>#0</value>
                                </enumeratedValue>
                                <enumeratedValue>
                                    <name>1</name>
                                    <description>100 Mbps.</description>
                                    <value>#1</value>
                                </enumeratedValue>
                            </enumeratedValues>
                        </field>
                        <field>
                            <name>ILB</name>
                            <description>Internal Loopback Mode</description>
                            <lsb>3</lsb>
                            <msb>3</msb>
                            <access>read-write</access>
                            <enumeratedValues>
                                <enumeratedValue>
                                    <name>0</name>
                                    <description>Perform normal data transmission or reception</description>
                                    <value>#0</value>
                                </enumeratedValue>
                                <enumeratedValue>
                                    <name>1</name>
                                    <description>Loop data back in the ETHERC when full-duplex mode is selected.</description>
                                    <value>#1</value>
                                </enumeratedValue>
                            </enumeratedValues>
                        </field>
                        <field>
                            <name>TE</name>
                            <description>Transmission Enable</description>
                            <lsb>5</lsb>
                            <msb>5</msb>
                            <access>read-write</access>
                            <enumeratedValues>
                                <enumeratedValue>
                                    <name>0</name>
                                    <description>Disable transmit function</description>
                                    <value>#0</value>
                                </enumeratedValue>
                                <enumeratedValue>
                                    <name>1</name>
                                    <description>Enable transmit function.</description>
                                    <value>#1</value>
                                </enumeratedValue>
                            </enumeratedValues>
                        </field>
                        <field>
                            <name>RE</name>
                            <description>Reception Enable</description>
                            <lsb>6</lsb>
                            <msb>6</msb>
                            <access>read-write</access>
                            <enumeratedValues>
                                <enumeratedValue>
                                    <name>0</name>
                                    <description>Disable receive function</description>
                                    <value>#0</value>
                                </enumeratedValue>
                                <enumeratedValue>
                                    <name>1</name>
                                    <description>Enable receive function.</description>
                                    <value>#1</value>
                                </enumeratedValue>
                            </enumeratedValues>
                        </field>
                        <field>
                            <name>MPDE</name>
                            <description>Magic Packet Detection Enable</description>
                            <lsb>9</lsb>
                            <msb>9</msb>
                            <access>read-write</access>
                            <enumeratedValues>
                                <enumeratedValue>
                                    <name>0</name>
                                    <description>Disable Magic Packet detection</description>
                                    <value>#0</value>
                                </enumeratedValue>
                                <enumeratedValue>
                                    <name>1</name>
                                    <description>Enable Magic Packet detection.</description>
                                    <value>#1</value>
                                </enumeratedValue>
                            </enumeratedValues>
                        </field>
                        <field>
                            <name>PRCEF</name>
                            <description>CRC Error Frame Receive Mode</description>
                            <lsb>12</lsb>
                            <msb>12</msb>
                            <access>read-write</access>
                            <enumeratedValues>
                                <enumeratedValue>
                                    <name>0</name>
                                    <description>Notify EDMAC of a CRC error</description>
                                    <value>#0</value>
                                </enumeratedValue>
                                <enumeratedValue>
                                    <name>1</name>
                                    <description>Do not notify EDMAC of a CRC error.</description>
                                    <value>#1</value>
                                </enumeratedValue>
                            </enumeratedValues>
                        </field>
                        <field>
                            <name>TXF</name>
                            <description>Transmit Flow Control Operating Mode</description>
                            <lsb>16</lsb>
                            <msb>16</msb>
                            <access>read-write</access>
                            <enumeratedValues>
                                <enumeratedValue>
                                    <name>0</name>
                                    <description>Disable automatic PAUSE frame transmission (PAUSE frame is not automatically transmitted) </description>
                                    <value>#0</value>
                                </enumeratedValue>
                                <enumeratedValue>
                                    <name>1</name>
                                    <description>Enable automatic PAUSE frame transmission (PAUSE frame is automatically transmitted as required). </description>
                                    <value>#1</value>
                                </enumeratedValue>
                            </enumeratedValues>
                        </field>
                        <field>
                            <name>RXF</name>
                            <description>Receive Flow Control Operating Mode</description>
                            <lsb>17</lsb>
                            <msb>17</msb>
                            <access>read-write</access>
                            <enumeratedValues>
                                <enumeratedValue>
                                    <name>0</name>
                                    <description>Disable PAUSE frame detection</description>
                                    <value>#0</value>
                                </enumeratedValue>
                                <enumeratedValue>
                                    <name>1</name>
                                    <description>Enable PAUSE frame detection.</description>
                                    <value>#1</value>
                                </enumeratedValue>
                            </enumeratedValues>
                        </field>
                        <field>
                            <name>PFR</name>
                            <description>PAUSE Frame Receive Mode</description>
                            <lsb>18</lsb>
                            <msb>18</msb>
                            <access>read-write</access>
                            <enumeratedValues>
                                <enumeratedValue>
                                    <name>0</name>
                                    <description>Do not transfer PAUSE frame to the EDMAC</description>
                                    <value>#0</value>
                                </enumeratedValue>
                                <enumeratedValue>
                                    <name>1</name>
                                    <description>Transfer PAUSE frame to the EDMAC.</description>
                                    <value>#1</value>
                                </enumeratedValue>
                            </enumeratedValues>
                        </field>
                        <field>
                            <name>ZPF</name>
                            <description>0 Time PAUSE Frame Enable</description>
                            <lsb>19</lsb>
                            <msb>19</msb>
                            <access>read-write</access>
                            <enumeratedValues>
                                <enumeratedValue>
                                    <name>0</name>
                                    <description>Do not use PAUSE frames that containing a pause_time parameter of 0 </description>
                                    <value>#0</value>
                                </enumeratedValue>
                                <enumeratedValue>
                                    <name>1</name>
                                    <description>Use PAUSE frames that containing a pause_time parameter of 0.</description>
                                    <value>#1</value>
                                </enumeratedValue>
                            </enumeratedValues>
                        </field>
                        <field>
                            <name>TPC</name>
                            <description>PAUSE Frame Transmit</description>
                            <lsb>20</lsb>
                            <msb>20</msb>
                            <access>read-write</access>
                            <enumeratedValues>
                                <enumeratedValue>
                                    <name>0</name>
                                    <description>Transmit PAUSE frame even during a PAUSE period</description>
                                    <value>#0</value>
                                </enumeratedValue>
                                <enumeratedValue>
                                    <name>1</name>
                                    <description>Do not transmit PAUSE frame during a PAUSE period.</description>
                                    <value>#1</value>
                                </enumeratedValue>
                            </enumeratedValues>
                        </field>
                    </fields>
                </register>
                <register>
                    <name>RFLR</name>
                    <description>Receive Frame Maximum Length Register</description>
                    <addressOffset>0x08</addressOffset>
                    <size>32</size>
                    <access>read-write</access>
                    <resetValue>0x00000000</resetValue>
                    <resetMask>0xffffffff</resetMask>
                    <fields>
                        <field>
                            <name>RFL</name>
                            <description>Receive Frame Maximum Length</description>
                            <lsb>0</lsb>
                            <msb>11</msb>
                            <access>read-write</access>
                        </field>
                    </fields>
                </register>
                <register>
                    <name>ECSR</name>
                    <description>ETHERC Status Register</description>
                    <addressOffset>0x10</addressOffset>
                    <size>32</size>
                    <access>read-write</access>
                    <resetValue>0x00000000</resetValue>
                    <resetMask>0xffffffff</resetMask>
                    <fields>
                        <field>
                            <name>ICD</name>
                            <description>False Carrier Detect Flag</description>
                            <lsb>0</lsb>
                            <msb>0</msb>
                            <access>read-write</access>
                            <enumeratedValues>
                                <enumeratedValue>
                                    <name>0</name>
                                    <description>PHY-LSI has not detected a false carrier on the line</description>
                                    <value>#0</value>
                                </enumeratedValue>
                                <enumeratedValue>
                                    <name>1</name>
                                    <description>PHY-LSI detected a false carrier on the line.</description>
                                    <value>#1</value>
                                </enumeratedValue>
                            </enumeratedValues>
                        </field>
                        <field>
                            <name>MPD</name>
                            <description>Magic Packet Detect Flag</description>
                            <lsb>1</lsb>
                            <msb>1</msb>
                            <access>read-write</access>
                            <enumeratedValues>
                                <enumeratedValue>
                                    <name>0</name>
                                    <description>Magic Packet not detected</description>
                                    <value>#0</value>
                                </enumeratedValue>
                                <enumeratedValue>
                                    <name>1</name>
                                    <description>Magic Packet detected.</description>
                                    <value>#1</value>
                                </enumeratedValue>
                            </enumeratedValues>
                        </field>
                        <field>
                            <name>LCHNG</name>
                            <description>Link Signal Change Flag</description>
                            <lsb>2</lsb>
                            <msb>2</msb>
                            <access>read-write</access>
                            <enumeratedValues>
                                <enumeratedValue>
                                    <name>0</name>
                                    <description>Change in the ET0_LINKSTA signal not detected</description>
                                    <value>#0</value>
                                </enumeratedValue>
                                <enumeratedValue>
                                    <name>1</name>
                                    <description>Change in the ET0_LINKSTA signal detected (high to low, or low to high). </description>
                                    <value>#1</value>
                                </enumeratedValue>
                            </enumeratedValues>
                        </field>
                        <field>
                            <name>PSRTO</name>
                            <description>PAUSE Frame Retransmit Over Flag</description>
                            <lsb>4</lsb>
                            <msb>4</msb>
                            <access>read-write</access>
                            <enumeratedValues>
                                <enumeratedValue>
                                    <name>0</name>
                                    <description>PAUSE frame retransmit count has not reached the upper limit</description>
                                    <value>#0</value>
                                </enumeratedValue>
                                <enumeratedValue>
                                    <name>1</name>
                                    <description>PAUSE frame retransmit count reached the upper limit.</description>
                                    <value>#1</value>
                                </enumeratedValue>
                            </enumeratedValues>
                        </field>
                        <field>
                            <name>BFR</name>
                            <description>Continuous Broadcast Frame Reception Flag</description>
                            <lsb>5</lsb>
                            <msb>5</msb>
                            <access>read-write</access>
                            <enumeratedValues>
                                <enumeratedValue>
                                    <name>0</name>
                                    <description>Continuous reception of broadcast frames not detected</description>
                                    <value>#0</value>
                                </enumeratedValue>
                                <enumeratedValue>
                                    <name>1</name>
                                    <description>Continuous reception of broadcast frames detected.</description>
                                    <value>#1</value>
                                </enumeratedValue>
                            </enumeratedValues>
                        </field>
                    </fields>
                </register>
                <register>
                    <name>ECSIPR</name>
                    <description>ETHERC Interrupt Enable Register</description>
                    <addressOffset>0x18</addressOffset>
                    <size>32</size>
                    <access>read-write</access>
                    <resetValue>0x00000000</resetValue>
                    <resetMask>0xffffffff</resetMask>
                    <fields>
                        <field>
                            <name>ICDIP</name>
                            <description>False Carrier Detect Interrupt Enable</description>
                            <lsb>0</lsb>
                            <msb>0</msb>
                            <access>read-write</access>
                            <enumeratedValues>
                                <enumeratedValue>
                                    <name>0</name>
                                    <description>Disable interrupt notification</description>
                                    <value>#0</value>
                                </enumeratedValue>
                                <enumeratedValue>
                                    <name>1</name>
                                    <description>Enable interrupt notification.</description>
                                    <value>#1</value>
                                </enumeratedValue>
                            </enumeratedValues>
                        </field>
                        <field>
                            <name>MPDIP</name>
                            <description>Magic Packet Detect Interrupt Enable</description>
                            <lsb>1</lsb>
                            <msb>1</msb>
                            <access>read-write</access>
                            <enumeratedValues>
                                <enumeratedValue>
                                    <name>0</name>
                                    <description>Disable interrupt notification</description>
                                    <value>#0</value>
                                </enumeratedValue>
                                <enumeratedValue>
                                    <name>1</name>
                                    <description>Enable interrupt notification.</description>
                                    <value>#1</value>
                                </enumeratedValue>
                            </enumeratedValues>
                        </field>
                        <field>
                            <name>LCHNGIP</name>
                            <description>LINK Signal Change Interrupt Enable</description>
                            <lsb>2</lsb>
                            <msb>2</msb>
                            <access>read-write</access>
                            <enumeratedValues>
                                <enumeratedValue>
                                    <name>0</name>
                                    <description>Disable interrupt notification</description>
                                    <value>#0</value>
                                </enumeratedValue>
                                <enumeratedValue>
                                    <name>1</name>
                                    <description>Enable interrupt notification.</description>
                                    <value>#1</value>
                                </enumeratedValue>
                            </enumeratedValues>
                        </field>
                        <field>
                            <name>PSRTOIP</name>
                            <description>PAUSE Frame Retransmit Over Interrupt Enable</description>
                            <lsb>4</lsb>
                            <msb>4</msb>
                            <access>read-write</access>
                            <enumeratedValues>
                                <enumeratedValue>
                                    <name>0</name>
                                    <description>Disable interrupt notification</description>
                                    <value>#0</value>
                                </enumeratedValue>
                                <enumeratedValue>
                                    <name>1</name>
                                    <description>Enable interrupt notification.</description>
                                    <value>#1</value>
                                </enumeratedValue>
                            </enumeratedValues>
                        </field>
                        <field>
                            <name>BFSIPR</name>
                            <description>Continuous Broadcast Frame Reception Interrupt Enable</description>
                            <lsb>5</lsb>
                            <msb>5</msb>
                            <access>read-write</access>
                            <enumeratedValues>
                                <enumeratedValue>
                                    <name>0</name>
                                    <description>Disable interrupt notification</description>
                                    <value>#0</value>
                                </enumeratedValue>
                                <enumeratedValue>
                                    <name>1</name>
                                    <description>Enable interrupt notification.</description>
                                    <value>#1</value>
                                </enumeratedValue>
                            </enumeratedValues>
                        </field>
                    </fields>
                </register>
                <register>
                    <name>PIR</name>
                    <description>PHY Interface Register</description>
                    <addressOffset>0x20</addressOffset>
                    <size>32</size>
                    <access>read-write</access>
                    <resetValue>0x00000000</resetValue>
                    <resetMask>0xfffffff7</resetMask>
                    <fields>
                        <field>
                            <name>MDC</name>
                            <description>MII/RMII Management Data Clock</description>
                            <lsb>0</lsb>
                            <msb>0</msb>
                            <access>read-write</access>
                        </field>
                        <field>
                            <name>MMD</name>
                            <description>MII/RMII Management Mode</description>
                            <lsb>1</lsb>
                            <msb>1</msb>
                            <access>read-write</access>
                            <enumeratedValues>
                                <enumeratedValue>
                                    <name>0</name>
                                    <description>Read</description>
                                    <value>#0</value>
                                </enumeratedValue>
                                <enumeratedValue>
                                    <name>1</name>
                                    <description>Write.</description>
                                    <value>#1</value>
                                </enumeratedValue>
                            </enumeratedValues>
                        </field>
                        <field>
                            <name>MDO</name>
                            <description>MII/RMII Management Data-Out</description>
                            <lsb>2</lsb>
                            <msb>2</msb>
                            <access>read-write</access>
                        </field>
                        <field>
                            <name>MDI</name>
                            <description>MII/RMII Management Data-In</description>
                            <lsb>3</lsb>
                            <msb>3</msb>
                            <access>read-only</access>
                        </field>
                    </fields>
                </register>
                <register>
                    <name>PSR</name>
                    <description>PHY Status Register</description>
                    <addressOffset>0x28</addressOffset>
                    <size>32</size>
                    <access>read-only</access>
                    <resetValue>0x00000000</resetValue>
                    <resetMask>0xfffffffe</resetMask>
                    <fields>
                        <field>
                            <name>LMON</name>
                            <description>ET0_LINKSTA Pin Status Flag</description>
                            <lsb>0</lsb>
                            <msb>0</msb>
                            <access>read-only</access>
                        </field>
                    </fields>
                </register>
                <register>
                    <name>RDMLR</name>
                    <description>Random Number Generation Counter Upper Limit Setting Register</description>
                    <addressOffset>0x40</addressOffset>
                    <size>32</size>
                    <access>read-write</access>
                    <resetValue>0x00000000</resetValue>
                    <resetMask>0xffff0000</resetMask>
                    <fields>
                        <field>
                            <name>RMD</name>
                            <description>Random Number Generation Counter</description>
                            <lsb>0</lsb>
                            <msb>19</msb>
                            <access>read-write</access>
                        </field>
                    </fields>
                </register>
                <register>
                    <name>IPGR</name>
                    <description>Interpacket Gap Register</description>
                    <addressOffset>0x50</addressOffset>
                    <size>32</size>
                    <access>read-write</access>
                    <resetValue>0x00000014</resetValue>
                    <resetMask>0xffffffff</resetMask>
                    <fields>
                        <field>
                            <name>IPG</name>
                            <lsb>0</lsb>
                            <msb>4</msb>
                            <access>read-write</access>
                        </field>
                    </fields>
                </register>
                <register>
                    <name>APR</name>
                    <description>Automatic PAUSE Frame Register</description>
                    <addressOffset>0x54</addressOffset>
                    <size>32</size>
                    <access>read-write</access>
                    <resetValue>0x00000000</resetValue>
                    <resetMask>0xffffffff</resetMask>
                    <fields>
                        <field>
                            <name>AP</name>
                            <description>Automatic PAUSE Time Setting</description>
                            <lsb>0</lsb>
                            <msb>15</msb>
                            <access>read-write</access>
                        </field>
                    </fields>
                </register>
                <register>
                    <name>MPR</name>
                    <description>Manual PAUSE Frame Register</description>
                    <addressOffset>0x58</addressOffset>
                    <size>32</size>
                    <access>read-write</access>
                    <resetValue>0x00000000</resetValue>
                    <resetMask>0xffff0000</resetMask>
                    <fields>
                        <field>
                            <name>MP</name>
                            <description>Manual PAUSE Time Setting</description>
                            <lsb>0</lsb>
                            <msb>15</msb>
                            <access>read-write</access>
                        </field>
                    </fields>
                </register>
                <register>
                    <name>RFCF</name>
                    <description>Received PAUSE Frame Counter</description>
                    <addressOffset>0x60</addressOffset>
                    <size>32</size>
                    <access>read-only</access>
                    <resetValue>0x00000000</resetValue>
                    <resetMask>0xffffffff</resetMask>
                    <fields>
                        <field>
                            <name>RPAUSE</name>
                            <description>Received PAUSE Frame Count</description>
                            <lsb>0</lsb>
                            <msb>7</msb>
                            <access>read-only</access>
                        </field>
                    </fields>
                </register>
                <register>
                    <name>TPAUSER</name>
                    <description>PAUSE Frame Retransmit Count Setting Register</description>
                    <addressOffset>0x64</addressOffset>
                    <size>32</size>
                    <access>read-write</access>
                    <resetValue>0x00000000</resetValue>
                    <resetMask>0xffffffff</resetMask>
                    <fields>
                        <field>
                            <name>TPAUSE</name>
                            <lsb>0</lsb>
                            <msb>15</msb>
                            <access>read-write</access>
                        </field>
                    </fields>
                </register>
                <register>
                    <name>TPAUSECR</name>
                    <description>PAUSE Frame Retransmit Counter</description>
                    <addressOffset>0x68</addressOffset>
                    <size>32</size>
                    <access>read-only</access>
                    <resetValue>0x00000000</resetValue>
                    <resetMask>0xffffffff</resetMask>
                    <fields>
                        <field>
                            <name>TXP</name>
                            <description>PAUSE Frame Retransmit Count</description>
                            <lsb>0</lsb>
                            <msb>7</msb>
                            <access>read-only</access>
                        </field>
                    </fields>
                </register>
                <register>
                    <name>BCFRR</name>
                    <description>Broadcast Frame Receive Count Setting Register</description>
                    <addressOffset>0x6C</addressOffset>
                    <size>32</size>
                    <access>read-write</access>
                    <resetValue>0x00000000</resetValue>
                    <resetMask>0xffffffff</resetMask>
                    <fields>
                        <field>
                            <name>BCF</name>
                            <lsb>0</lsb>
                            <msb>15</msb>
                            <access>read-write</access>
                        </field>
                    </fields>
                </register>
                <register>
                    <name>MAHR</name>
                    <description>MAC Address Upper Bit Register</description>
                    <addressOffset>0xC0</addressOffset>
                    <size>32</size>
                    <access>read-write</access>
                    <resetValue>0x00000000</resetValue>
                    <resetMask>0xffffffff</resetMask>
                    <fields>
                        <field>
                            <name>MAHR</name>
                            <description>MAC Address Upper Bit</description>
                            <lsb>0</lsb>
                            <msb>31</msb>
                            <access>read-write</access>
                        </field>
                    </fields>
                </register>
                <register>
                    <name>MALR</name>
                    <description>MAC Address Lower Bit Register</description>
                    <addressOffset>0xC8</addressOffset>
                    <size>32</size>
                    <access>read-write</access>
                    <resetValue>0x00000000</resetValue>
                    <resetMask>0xffffffff</resetMask>
                    <fields>
                        <field>
                            <name>MALR</name>
                            <description>MAC Address Lower Bit</description>
                            <lsb>0</lsb>
                            <msb>15</msb>
                            <access>read-write</access>
                        </field>
                    </fields>
                </register>
                <register>
                    <name>TROCR</name>
                    <description>Transmit Retry Over Counter Register</description>
                    <addressOffset>0xD0</addressOffset>
                    <size>32</size>
                    <access>read-write</access>
                    <resetValue>0x00000000</resetValue>
                    <resetMask>0xffffffff</resetMask>
                    <fields>
                        <field>
                            <name>TROCR</name>
                            <description>Transmit Retry Over Counter</description>
                            <lsb>0</lsb>
                            <msb>31</msb>
                            <access>read-write</access>
                        </field>
                    </fields>
                </register>
                <register>
                    <name>CDCR</name>
                    <description>Late Collision Detect Counter Register</description>
                    <addressOffset>0xD4</addressOffset>
                    <size>32</size>
                    <access>read-write</access>
                    <resetValue>0x00000000</resetValue>
                    <resetMask>0xffffffff</resetMask>
                    <fields>
                        <field>
                            <name>CDCR</name>
                            <description>Late Collision Detect Counter</description>
                            <lsb>0</lsb>
                            <msb>31</msb>
                            <access>read-write</access>
                        </field>
                    </fields>
                </register>
                <register>
                    <name>LCCR</name>
                    <description>Lost Carrier Counter Register</description>
                    <addressOffset>0xD8</addressOffset>
                    <size>32</size>
                    <access>read-write</access>
                    <resetValue>0x00000000</resetValue>
                    <resetMask>0xffffffff</resetMask>
                    <fields>
                        <field>
                            <name>LCCR</name>
                            <description>Lost Carrier Counter</description>
                            <lsb>0</lsb>
                            <msb>31</msb>
                            <access>read-write</access>
                        </field>
                    </fields>
                </register>
                <register>
                    <name>CNDCR</name>
                    <description>Carrier Not Detect Counter Register</description>
                    <addressOffset>0xDC</addressOffset>
                    <size>32</size>
                    <access>read-write</access>
                    <resetValue>0x00000000</resetValue>
                    <resetMask>0xffffffff</resetMask>
                    <fields>
                        <field>
                            <name>CNDCR</name>
                            <description>Carrier Not Detect Counter</description>
                            <lsb>0</lsb>
                            <msb>31</msb>
                            <access>read-write</access>
                        </field>
                    </fields>
                </register>
                <register>
                    <name>CEFCR</name>
                    <description>CRC Error Frame Receive Counter Register</description>
                    <addressOffset>0xE4</addressOffset>
                    <size>32</size>
                    <access>read-write</access>
                    <resetValue>0x00000000</resetValue>
                    <resetMask>0xffffffff</resetMask>
                    <fields>
                        <field>
                            <name>CEFCR</name>
                            <description>CRC Error Frame Receive Counter</description>
                            <lsb>0</lsb>
                            <msb>31</msb>
                            <access>read-write</access>
                        </field>
                    </fields>
                </register>
                <register>
                    <name>FRECR</name>
                    <description>Frame Receive Error Counter Register</description>
                    <addressOffset>0xE8</addressOffset>
                    <size>32</size>
                    <access>read-write</access>
                    <resetValue>0x00000000</resetValue>
                    <resetMask>0xffffffff</resetMask>
                    <fields>
                        <field>
                            <name>FRECR</name>
                            <description>Frame Receive Error Counter</description>
                            <lsb>0</lsb>
                            <msb>31</msb>
                            <access>read-write</access>
                        </field>
                    </fields>
                </register>
                <register>
                    <name>TSFRCR</name>
                    <description>Too-Short Frame Receive Counter Register</description>
                    <addressOffset>0xEC</addressOffset>
                    <size>32</size>
                    <access>read-write</access>
                    <resetValue>0x00000000</resetValue>
                    <resetMask>0xffffffff</resetMask>
                    <fields>
                        <field>
                            <name>TSFRCR</name>
                            <description>Too-Short Frame Receive Counter</description>
                            <lsb>0</lsb>
                            <msb>31</msb>
                            <access>read-write</access>
                        </field>
                    </fields>
                </register>
                <register>
                    <name>TLFRCR</name>
                    <description>Too-Long Frame Receive Counter Register</description>
                    <addressOffset>0xF0</addressOffset>
                    <size>32</size>
                    <access>read-write</access>
                    <resetValue>0x00000000</resetValue>
                    <resetMask>0xffffffff</resetMask>
                    <fields>
                        <field>
                            <name>TLFRCR</name>
                            <description>Too-Long Frame Receive Counter</description>
                            <lsb>0</lsb>
                            <msb>31</msb>
                            <access>read-write</access>
                        </field>
                    </fields>
                </register>
                <register>
                    <name>RFCR</name>
                    <description>Received Alignment Error Frame Counter Register</description>
                    <addressOffset>0xF4</addressOffset>
                    <size>32</size>
                    <access>read-write</access>
                    <resetValue>0x00000000</resetValue>
                    <resetMask>0xffffffff</resetMask>
                    <fields>
                        <field>
                            <name>RFCR</name>
                            <description>Received Alignment Error Frame Counter</description>
                            <lsb>0</lsb>
                            <msb>31</msb>
                            <access>read-write</access>
                        </field>
                    </fields>
                </register>
                <register>
                    <name>MAFCR</name>
                    <description>Multicast Address Frame Receive Counter Register</description>
                    <addressOffset>0xF8</addressOffset>
                    <size>32</size>
                    <access>read-write</access>
                    <resetValue>0x00000000</resetValue>
                    <resetMask>0xffffffff</resetMask>
                    <fields>
                        <field>
                            <name>MAFCR</name>
                            <description>Multicast Address Frame Receive Counter</description>
                            <lsb>0</lsb>
                            <msb>31</msb>
                            <access>read-write</access>
                        </field>
                    </fields>
                </register>
            </registers>
        </peripheral>
        <peripheral>
            <name>SCI0_B</name>
            <description>Serial Communication Interface 0</description>
            <baseAddress>0x40358000</baseAddress>
            <addressBlock>
                <offset>0x00</offset>
                <size>4</size>
                <usage>registers</usage>
            </addressBlock>
            <addressBlock>
                <offset>0x04</offset>
                <size>4</size>
                <usage>registers</usage>
            </addressBlock>
            <addressBlock>
                <offset>0x08</offset>
                <size>21</size>
                <usage>registers</usage>
            </addressBlock>
            <addressBlock>
                <offset>0x20</offset>
                <size>8</size>
                <usage>registers</usage>
            </addressBlock>
            <addressBlock>
                <offset>0x2C</offset>
                <size>20</size>
                <usage>registers</usage>
            </addressBlock>
            <addressBlock>
                <offset>0x48</offset>
                <size>28</size>
                <usage>registers</usage>
            </addressBlock>
            <addressBlock>
                <offset>0x68</offset>
                <size>20</size>
                <usage>registers</usage>
            </addressBlock>
            <registers>
                <register>
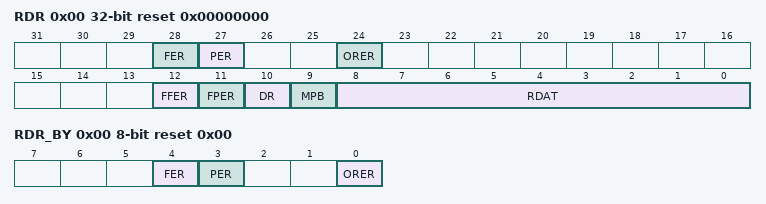
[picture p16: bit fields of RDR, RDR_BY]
                    <name>RDR</name>
                    <description>Receive Data Register</description>
                    <addressOffset>0x00</addressOffset>
                    <size>32</size>
                    <access>read-only</access>
                    <resetValue>0x00000000</resetValue>
                    <resetMask>0xffffffff</resetMask>
                    <fields>
                        <field>
                            <name>RDAT</name>
                            <description>Serial receive data</description>
                            <lsb>0</lsb>
                            <msb>8</msb>
                            <access>read-only</access>
                        </field>
                        <field>
                            <name>MPB</name>
                            <description>Multi-processor flag</description>
                            <lsb>9</lsb>
                            <msb>9</msb>
                            <access>read-only</access>
                            <enumeratedValues>
                                <enumeratedValue>
                                    <name>0</name>
                                    <description>Data transmission cycles</description>
                                    <value>#0</value>
                                </enumeratedValue>
                                <enumeratedValue>
                                    <name>1</name>
                                    <description>ID transmission cycles</description>
                                    <value>#1</value>
                                </enumeratedValue>
                            </enumeratedValues>
                        </field>
                        <field>
                            <name>DR</name>
                            <description>Receive data ready flag</description>
                            <lsb>10</lsb>
                            <msb>10</msb>
                            <access>read-only</access>
                        </field>
                        <field>
                            <name>FPER</name>
                            <description>FIFO parity error flag</description>
                            <lsb>11</lsb>
                            <msb>11</msb>
                            <access>read-only</access>
                            <enumeratedValues>
                                <enumeratedValue>
                                    <name>0</name>
                                    <description>There is no parity error in the data read from the receive-FIFO</description>
                                    <value>#0</value>
                                </enumeratedValue>
                                <enumeratedValue>
                                    <name>1</name>
                                    <description>There is parity error in the data read from the receive-FIFO</description>
                                    <value>#1</value>
                                </enumeratedValue>
                            </enumeratedValues>
                        </field>
                        <field>
                            <name>FFER</name>
                            <description>FIFO framing error flag</description>
                            <lsb>12</lsb>
                            <msb>12</msb>
                            <access>read-only</access>
                            <enumeratedValues>
                                <enumeratedValue>
                                    <name>0</name>
                                    <description>There is no framing error in the data read from the receive-FIFO</description>
                                    <value>#0</value>
                                </enumeratedValue>
                                <enumeratedValue>
                                    <name>1</name>
                                    <description>There is framing error in the data read from the receive-FIFO</description>
                                    <value>#1</value>
                                </enumeratedValue>
                            </enumeratedValues>
                        </field>
                        <field>
                            <name>ORER</name>
                            <description>Overrun Error flag</description>
                            <lsb>24</lsb>
                            <msb>24</msb>
                            <access>read-only</access>
                        </field>
                        <field>
                            <name>PER</name>
                            <description>Parity error flag</description>
                            <lsb>27</lsb>
                            <msb>27</msb>
                            <access>read-only</access>
                        </field>
                        <field>
                            <name>FER</name>
                            <description>Framing error flag</description>
                            <lsb>28</lsb>
                            <msb>28</msb>
                            <access>read-only</access>
                        </field>
                    </fields>
                </register>
                <register>
                    <name>RDR_BY</name>
                    <description>Receive Data Register</description>
                    <alternateRegister>RDR</alternateRegister>
                    <addressOffset>0x00</addressOffset>
                    <size>8</size>
                    <access>read-only</access>
                    <resetValue>0x00</resetValue>
                    <resetMask>0xff</resetMask>
                    <fields>
                        <field>
                            <name>ORER</name>
                            <description>Overrun Error flag</description>
                            <lsb>0</lsb>
                            <msb>0</msb>
                            <access>read-only</access>
                        </field>
                        <field>
                            <name>PER</name>
                            <description>Parity error flag</description>
                            <lsb>3</lsb>
                            <msb>3</msb>
                            <access>read-only</access>
                        </field>
                        <field>
                            <name>FER</name>
                            <description>Framing error flag</description>
                            <lsb>4</lsb>
                            <msb>4</msb>
                            <access>read-only</access>
                        </field>
                    </fields>
                </register>
                <register>
                    <name>TDR</name>
                    <description>Transmit Data Register</description>
                    <addressOffset>0x04</addressOffset>
                    <size>32</size>
                    <access>read-write</access>
                    <resetValue>0xffffffff</resetValue>
                    <resetMask>0xffffffff</resetMask>
                    <fields>
                        <field>
                            <name>TDAT</name>
                            <description>Serial transmit data</description>
                            <lsb>0</lsb>
                            <msb>8</msb>
                            <access>read-write</access>
                        </field>
                        <field>
                            <name>MPBT</name>
                            <description>Multi-processor transfer bit flag</description>
                            <lsb>9</lsb>
                            <msb>9</msb>
                            <access>read-write</access>
                            <enumeratedValues>
                                <enumeratedValue>
                                    <name>0</name>
                                    <description>Data transmission cycles</description>
                                    <value>#0</value>
                                </enumeratedValue>
                                <enumeratedValue>
                                    <name>1</name>
                                    <description>ID transmission cycles</description>
                                    <value>#1</value>
                                </enumeratedValue>
                            </enumeratedValues>
                        </field>
                        <field>
                            <name>TSYNC</name>
                            <description>Transmit SYNC data</description>
                            <lsb>12</lsb>
                            <msb>12</msb>
                            <access>read-write</access>
                            <enumeratedValues>
                                <enumeratedValue>
                                    <name>0</name>
                                    <description>The Start Bit is transmitted as DATA SYNC.</description>
                                    <value>#0</value>
                                </enumeratedValue>
                                <enumeratedValue>
                                    <name>1</name>
                                    <description>The Start Bit is transmitted as COMMAND SYNC.</description>
                                    <value>#1</value>
                                </enumeratedValue>
                            </enumeratedValues>
                        </field>
                    </fields>
                </register>
                <register>
                    <name>TDRLL</name>
                    <description>Transmit Data Register</description>
                    <alternateRegister>TDR</alternateRegister>
                    <addressOffset>0x04</addressOffset>
                    <size>16</size>
                    <access>read-write</access>
                    <resetValue>0xffff</resetValue>
                    <resetMask>0xffff</resetMask>
                </register>
                <register>
                    <name>TDRLH</name>
                    <description>Transmit Data Register</description>
                    <alternateRegister>TDR</alternateRegister>
                    <addressOffset>0x05</addressOffset>
                    <size>16</size>
                    <access>read-write</access>
                    <resetValue>0xffff</resetValue>
                    <resetMask>0xffff</resetMask>
                    <fields>
                        <field>
                            <name>TDAT</name>
                            <description>Serial transmit data</description>
                            <lsb>0</lsb>
                            <msb>0</msb>
                            <access>read-write</access>
                        </field>
                        <field>
                            <name>MPBT</name>
                            <description>Multi-processor transfer bit flag</description>
                            <lsb>1</lsb>
                            <msb>1</msb>
                            <access>read-write</access>
                            <enumeratedValues>
                                <enumeratedValue>
                                    <name>0</name>
                                    <description>Data transmission cycles</description>
                                    <value>#0</value>
                                </enumeratedValue>
                                <enumeratedValue>
                                    <name>1</name>
                                    <description>ID transmission cycles</description>
                                    <value>#1</value>
                                </enumeratedValue>
                            </enumeratedValues>
                        </field>
                        <field>
                            <name>TSYNC</name>
                            <description>Transmit SYNC data</description>
                            <lsb>4</lsb>
                            <msb>4</msb>
                            <access>read-write</access>
                            <enumeratedValues>
                                <enumeratedValue>
                                    <name>0</name>
                                    <description>The Start Bit is transmitted as DATA SYNC.</description>
                                    <value>#0</value>
                                </enumeratedValue>
                                <enumeratedValue>
                                    <name>1</name>
                                    <description>The Start Bit is transmitted as COMMAND SYNC.</description>
                                    <value>#1</value>
                                </enumeratedValue>
                            </enumeratedValues>
                        </field>
                    </fields>
                </register>
                <register>
                    <name>CCR0</name>
                    <description>Common Control Register 0</description>
                    <addressOffset>0x08</addressOffset>
                    <size>32</size>
                    <access>read-write</access>
                    <resetValue>0x00000000</resetValue>
                    <resetMask>0xffffffff</resetMask>
                    <fields>
                        <field>
                            <name>RE</name>
                            <description>Receive Enable</description>
                            <lsb>0</lsb>
                            <msb>0</msb>
                            <access>read-write</access>
                            <enumeratedValues>
                                <enumeratedValue>
                                    <name>0</name>
                                    <description>Serial reception is disabled</description>
                                    <value>#0</value>
                                </enumeratedValue>
                                <enumeratedValue>
                                    <name>1</name>
                                    <description>Serial reception is enabled</description>
                                    <value>#1</value>
                                </enumeratedValue>
                            </enumeratedValues>
                        </field>
                        <field>
                            <name>TE</name>
                            <description>Transmit Enable</description>
                            <lsb>4</lsb>
                            <msb>4</msb>
                            <access>read-write</access>
                            <enumeratedValues>
                                <enumeratedValue>
                                    <name>0</name>
                                    <description>Serial transmission is disabled</description>
                                    <value>#0</value>
                                </enumeratedValue>
                                <enumeratedValue>
                                    <name>1</name>
                                    <description>Serial transmission is enabled</description>
                                    <value>#1</value>
                                </enumeratedValue>
                            </enumeratedValues>
                        </field>
                        <field>
                            <name>MPIE</name>
                            <description>Multi-Processor Interrupt Enable</description>
                            <lsb>8</lsb>
                            <msb>8</msb>
                            <access>read-write</access>
                            <enumeratedValues>
                                <enumeratedValue>
                                    <name>0</name>
                                    <description>Non-multi-processor reception</description>
                                    <value>#0</value>
                                </enumeratedValue>
                                <enumeratedValue>
                                    <name>1</name>
                                    <description>Multi-processor reception When the data with the multi-processor bit set to 0 is received, the data is not read, and setting the status flags to 1 is disabled. When the data with the multi-processor bit set to 1 is received, the MPIE bit is automatically cleared to 0, and non-multi-processor reception is resumed. If you want to continue receiving operation using the multiprocessor function, set this bit to 1 sufficiently earlier than receiving the STOP bit of the next received frame (consider the synchronization delay time). </description>
                                    <value>#1</value>
                                </enumeratedValue>
                            </enumeratedValues>
                        </field>
                        <field>
                            <name>DCME</name>
                            <description>Data Compare Match Enable</description>
                            <lsb>9</lsb>
                            <msb>9</msb>
                            <access>read-write</access>
                            <enumeratedValues>
                                <enumeratedValue>
                                    <name>0</name>
                                    <description>Address match function is disabled</description>
                                    <value>#0</value>
                                </enumeratedValue>
                                <enumeratedValue>
                                    <name>1</name>
                                    <description>Address match function is enabled</description>
                                    <value>#1</value>
                                </enumeratedValue>
                            </enumeratedValues>
                        </field>
                        <field>
                            <name>IDSEL</name>
                            <description>ID Frame Select</description>
                            <lsb>10</lsb>
                            <msb>10</msb>
                            <access>read-write</access>
                            <enumeratedValues>
                                <enumeratedValue>
                                    <name>0</name>
                                    <description>Compare data irrespective of the value of the MPB bit</description>
                                    <value>#0</value>
                                </enumeratedValue>
                                <enumeratedValue>
                                    <name>1</name>
                                    <description>Compare data only when the MPB bit is 1 (ID frame)</description>
                                    <value>#1</value>
                                </enumeratedValue>
                            </enumeratedValues>
                        </field>
                        <field>
                            <name>RIE</name>
                            <description>Receive Interrupt Enable</description>
                            <lsb>16</lsb>
                            <msb>16</msb>
                            <access>read-write</access>
                            <enumeratedValues>
                                <enumeratedValue>
                                    <name>0</name>
                                    <description>SCIn_RXI and SCIn_ERI interrupt requests are disabled</description>
                                    <value>#0</value>
                                </enumeratedValue>
                                <enumeratedValue>
                                    <name>1</name>
                                    <description>SCIn_RXI and SCIn_ERI interrupt requests are enabled</description>
                                    <value>#1</value>
                                </enumeratedValue>
                            </enumeratedValues>
                        </field>
                        <field>
                            <name>TIE</name>
                            <description>Transmit Interrupt Enable</description>
                            <lsb>20</lsb>
                            <msb>20</msb>
                            <access>read-write</access>
                            <enumeratedValues>
                                <enumeratedValue>
                                    <name>0</name>
                                    <description>SCIn_TXI interrupt request is disabled</description>
                                    <value>#0</value>
                                </enumeratedValue>
                                <enumeratedValue>
                                    <name>1</name>
                                    <description>SCIn_TXI interrupt request is enabled</description>
                                    <value>#1</value>
                                </enumeratedValue>
                            </enumeratedValues>
                        </field>
                        <field>
                            <name>TEIE</name>
                            <description>Transmit End Interrupt Enable</description>
                            <lsb>21</lsb>
                            <msb>21</msb>
                            <access>read-write</access>
                            <enumeratedValues>
                                <enumeratedValue>
                                    <name>0</name>
                                    <description>SCIn_TEI interrupt request is disabled</description>
                                    <value>#0</value>
                                </enumeratedValue>
                                <enumeratedValue>
                                    <name>1</name>
                                    <description>SCIn_TEI interrupt request is enabled</description>
                                    <value>#1</value>
                                </enumeratedValue>
                            </enumeratedValues>
                        </field>
                        <field>
                            <name>SSE</name>
                            <description>SSn Pin Function Enable</description>
                            <lsb>24</lsb>
                            <msb>24</msb>
                            <access>read-write</access>
                            <enumeratedValues>
                                <enumeratedValue>
                                    <name>0</name>
                                    <description>SSn pin function is disabled</description>
                                    <value>#0</value>
                                </enumeratedValue>
                                <enumeratedValue>
                                    <name>1</name>
                                    <description>SSn pin function is enabled</description>
                                    <value>#1</value>
                                </enumeratedValue>
                            </enumeratedValues>
                        </field>
                    </fields>
                </register>
                <register>
                    <name>CCR1</name>
                    <description>Common Control Register 1</description>
                    <addressOffset>0x0C</addressOffset>
                    <size>32</size>
                    <access>read-write</access>
                    <resetValue>0x00000010</resetValue>
                    <resetMask>0xffffffff</resetMask>
                    <fields>
                        <field>
                            <name>CTSE</name>
                            <description>CTS Enable</description>
                            <lsb>0</lsb>
                            <msb>0</msb>
                            <access>read-write</access>
                            <enumeratedValues>
                                <enumeratedValue>
                                    <name>0</name>
                                    <description>CTS function is disabled (RTS output function is enabled)</description>
                                    <value>#0</value>
                                </enumeratedValue>
                                <enumeratedValue>
                                    <name>1</name>
                                    <description>CTS function is enabled</description>
                                    <value>#1</value>
                                </enumeratedValue>
                            </enumeratedValues>
                        </field>
                        <field>
                            <name>CTSPEN</name>
                            <description>CTS External Pin Enable</description>
                            <lsb>1</lsb>
                            <msb>1</msb>
                            <access>read-write</access>
                            <enumeratedValues>
                                <enumeratedValue>
                                    <name>0</name>
                                    <description>Alternate setting to use CTS and RTS functions as either 1 pin</description>
                                    <value>#0</value>
                                </enumeratedValue>
                                <enumeratedValue>
                                    <name>1</name>
                                    <description>Dedicated setting for separately using CTS and RTS functions with 2 pins</description>
                                    <value>#1</value>
                                </enumeratedValue>
                            </enumeratedValues>
                        </field>
                        <field>
                            <name>SPB2DT</name>
                            <description>Serial Port Break Data Select</description>
                            <lsb>4</lsb>
                            <msb>4</msb>
                            <access>read-write</access>
                            <enumeratedValues>
                                <enumeratedValue>
                                    <name>0</name>
                                    <description>When TINV is 0, low level is output in TXDn pin. When TINV is 1, high level is output in TXDn pin. </description>
                                    <value>#0</value>
                                </enumeratedValue>
                                <enumeratedValue>
                                    <name>1</name>
                                    <description>When TINV is 0, high level is output in TXDn pin. When TINV is 1, low level is output in TXDn pin. </description>
                                    <value>#1</value>
                                </enumeratedValue>
                            </enumeratedValues>
                        </field>
                        <field>
                            <name>SPB2IO</name>
                            <description>Serial Port Break I/O</description>
                            <lsb>5</lsb>
                            <msb>5</msb>
                            <access>read-write</access>
                            <enumeratedValues>
                                <enumeratedValue>
                                    <name>0</name>
                                    <description>The value of SPB2DT bit is not output in TXDn pin</description>
                                    <value>#0</value>
                                </enumeratedValue>
                                <enumeratedValue>
                                    <name>1</name>
                                    <description>The value of SPB2DT bit is output in TXDn pin</description>
                                    <value>#1</value>
                                </enumeratedValue>
                            </enumeratedValues>
                        </field>
                        <field>
                            <name>PE</name>
                            <description>Parity Enable</description>
                            <lsb>8</lsb>
                            <msb>8</msb>
                            <access>read-write</access>
                            <enumeratedValues>
                                <enumeratedValue>
                                    <name>0</name>
                                    <description>When transmitting: Do not add parity bit When receiving: Do not check parity bit </description>
                                    <value>#0</value>
                                </enumeratedValue>
                                <enumeratedValue>
                                    <name>1</name>
                                    <description>When transmitting: Add parity bit When receiving: Check parity bit </description>
                                    <value>#1</value>
                                </enumeratedValue>
                            </enumeratedValues>
                        </field>
                        <field>
                            <name>PM</name>
                            <description>Parity Mode</description>
                            <lsb>9</lsb>
                            <msb>9</msb>
                            <access>read-write</access>
                            <enumeratedValues>
                                <enumeratedValue>
                                    <name>0</name>
                                    <description>Selects even parity</description>
                                    <value>#0</value>
                                </enumeratedValue>
                                <enumeratedValue>
                                    <name>1</name>
                                    <description>Selects odd parity</description>
                                    <value>#1</value>
                                </enumeratedValue>
                            </enumeratedValues>
                        </field>
                        <field>
                            <name>TINV</name>
                            <description>TXD Invert</description>
                            <lsb>12</lsb>
                            <msb>12</msb>
                            <access>read-write</access>
                            <enumeratedValues>
                                <enumeratedValue>
                                    <name>0</name>
                                    <description>Transmit data is not inverted and output to TXDn</description>
                                    <value>#0</value>
                                </enumeratedValue>
                                <enumeratedValue>
                                    <name>1</name>
                                    <description>Transmit data is inverted and output to TXDn</description>
                                    <value>#1</value>
                                </enumeratedValue>
                            </enumeratedValues>
                        </field>
                        <field>
                            <name>RINV</name>
                            <description>RXD Invert</description>
                            <lsb>13</lsb>
                            <msb>13</msb>
                            <access>read-write</access>
                            <enumeratedValues>
                                <enumeratedValue>
                                    <name>0</name>
                                    <description>Received data from RXDn is not inverted and input</description>
                                    <value>#0</value>
                                </enumeratedValue>
                                <enumeratedValue>
                                    <name>1</name>
                                    <description>Received data from RXDn is inverted and input</description>
                                    <value>#1</value>
                                </enumeratedValue>
                            </enumeratedValues>
                        </field>
                        <field>
                            <name>SPLP</name>
                            <description>Loopback Control</description>
                            <lsb>16</lsb>
                            <msb>16</msb>
                            <access>read-write</access>
                            <enumeratedValues>
                                <enumeratedValue>
                                    <name>0</name>
                                    <description>Normal mode</description>
                                    <value>#0</value>
                                </enumeratedValue>
                                <enumeratedValue>
                                    <name>1</name>
                                    <description>Loopback mode</description>
                                    <value>#1</value>
                                </enumeratedValue>
                            </enumeratedValues>
                        </field>
                        <field>
                            <name>SHARPS</name>
                            <description>Half-Duplex Communication Select</description>
                            <lsb>20</lsb>
                            <msb>20</msb>
                            <access>read-write</access>
                            <enumeratedValues>
                                <enumeratedValue>
                                    <name>0</name>
                                    <description>TXDn pin, RXDn pin independent</description>
                                    <value>#0</value>
                                </enumeratedValue>
                                <enumeratedValue>
                                    <name>1</name>
                                    <description>TXDn/RXDn pin combination use (half-duplex communication using TXDn pin) </description>
                                    <value>#1</value>
                                </enumeratedValue>
                            </enumeratedValues>
                        </field>
                        <field>
                            <name>NFCS</name>
                            <description>Noise Filter Clock Select</description>
                            <lsb>24</lsb>
                            <msb>26</msb>
                            <access>read-write</access>
                            <enumeratedValues>
                                <enumeratedValue>
                                    <name>000</name>
                                    <description>The base clock signal divided by 1</description>
                                    <value>#000</value>
                                </enumeratedValue>
                                <enumeratedValue>
                                    <name>001</name>
                                    <description>The on-chip baud rate generator source clock divided by 1</description>
                                    <value>#001</value>
                                </enumeratedValue>
                                <enumeratedValue>
                                    <name>010</name>
                                    <description>The on-chip baud rate generator source clock divided by 2</description>
                                    <value>#010</value>
                                </enumeratedValue>
                                <enumeratedValue>
                                    <name>011</name>
                                    <description>The on-chip baud rate generator source clock divided by 4</description>
                                    <value>#011</value>
                                </enumeratedValue>
                                <enumeratedValue>
                                    <name>100</name>
                                    <description>The on-chip baud rate generator source clock divided by 8</description>
                                    <value>#100</value>
                                </enumeratedValue>
                                <enumeratedValue>
                                    <name>others</name>
                                    <description>Setting prohibited</description>
                                    <isDefault>true</isDefault>
                                </enumeratedValue>
                            </enumeratedValues>
                        </field>
                        <field>
                            <name>NFEN</name>
                            <description>Digital Noise Filter Function Enable</description>
                            <lsb>28</lsb>
                            <msb>28</msb>
                            <access>read-write</access>
                            <enumeratedValues>
                                <enumeratedValue>
                                    <name>0</name>
                                    <description>In Asynchronous, Manchester, Simple LIN modes: Disable noise cancellation function for RXDn input signal In Simple IIC mode: Disable noise cancellation function for SCLn and SDAn input signals </description>
                                    <value>#0</value>
                                </enumeratedValue>
                                <enumeratedValue>
                                    <name>1</name>
                                    <description>In Asynchronous, Manchester, Simple LIN modes: Enable noise cancellation function for RXDn input signal In Simple IIC mode: Enable noise cancellation function for SCLn and SDAn input signals </description>
                                    <value>#1</value>
                                </enumeratedValue>
                            </enumeratedValues>
                        </field>
                        <field>
                            <name>NFM</name>
                            <description>Noise Filter Mode</description>
                            <lsb>29</lsb>
                            <msb>29</msb>
                            <access>read-write</access>
                            <enumeratedValues>
                                <enumeratedValue>
                                    <name>0</name>
                                    <description>3-point matching mode</description>
                                    <value>#0</value>
                                </enumeratedValue>
                                <enumeratedValue>
                                    <name>1</name>
                                    <description>Majority vote mode</description>
                                    <value>#1</value>
                                </enumeratedValue>
                            </enumeratedValues>
                        </field>
                    </fields>
                </register>
                <register>
                    <name>CCR2</name>
                    <description>Common Control Register 2</description>
                    <addressOffset>0x10</addressOffset>
                    <size>32</size>
                    <access>read-write</access>
                    <resetValue>0xff00ff04</resetValue>
                    <resetMask>0xffffffff</resetMask>
                    <fields>
                        <field>
                            <name>BCP</name>
                            <description>Base Clock Pulse</description>
                            <lsb>0</lsb>
                            <msb>2</msb>
                            <access>read-write</access>
                            <enumeratedValues>
                                <enumeratedValue>
                                    <name>000</name>
                                    <description>93 clock cycles (S = 93)</description>
                                    <value>#000</value>
                                </enumeratedValue>
                                <enumeratedValue>
                                    <name>001</name>
                                    <description>128 clock cycles (S = 128)</description>
                                    <value>#001</value>
                                </enumeratedValue>
                                <enumeratedValue>
                                    <name>010</name>
                                    <description>186 clock cycles (S = 186)</description>
                                    <value>#010</value>
                                </enumeratedValue>
                                <enumeratedValue>
                                    <name>011</name>
                                    <description>512 clock cycles (S = 512)</description>
                                    <value>#011</value>
                                </enumeratedValue>
                                <enumeratedValue>
                                    <name>100</name>
                                    <description>32 clock cycles (S = 32) (Initial value)</description>
                                    <value>#100</value>
                                </enumeratedValue>
                                <enumeratedValue>
                                    <name>101</name>
                                    <description>64 clock cycles (S = 64)</description>
                                    <value>#101</value>
                                </enumeratedValue>
                                <enumeratedValue>
                                    <name>110</name>
                                    <description>372 clock cycles (S = 372)</description>
                                    <value>#110</value>
                                </enumeratedValue>
                                <enumeratedValue>
                                    <name>111</name>
                                    <description>256 clock cycles (S = 256)</description>
                                    <value>#111</value>
                                </enumeratedValue>
                            </enumeratedValues>
                        </field>
                        <field>
                            <name>BGDM</name>
                            <description>Baud Rate Generator Double-Speed Mode Select</description>
                            <lsb>4</lsb>
                            <msb>4</msb>
                            <access>read-write</access>
                            <enumeratedValues>
                                <enumeratedValue>
                                    <name>0</name>
                                    <description>Baud rate generator outputs the clock with single frequency</description>
                                    <value>#0</value>
                                </enumeratedValue>
                                <enumeratedValue>
                                    <name>1</name>
                                    <description>Baud rate generator outputs the clock with doubled frequency</description>
                                    <value>#1</value>
                                </enumeratedValue>
                            </enumeratedValues>
                        </field>
                        <field>
                            <name>ABCS</name>
                            <description>Asynchronous Mode Base Clock Select</description>
                            <lsb>5</lsb>
                            <msb>5</msb>
                            <access>read-write</access>
                            <enumeratedValues>
                                <enumeratedValue>
                                    <name>0</name>
                                    <description>Selects 16 base clock cycles for 1-bit period</description>
                                    <value>#0</value>
                                </enumeratedValue>
                                <enumeratedValue>
                                    <name>1</name>
                                    <description>Selects 8 base clock cycles for 1-bit period</description>
                                    <value>#1</value>
                                </enumeratedValue>
                            </enumeratedValues>
                        </field>
                        <field>
                            <name>ABCSE</name>
                            <description>Asynchronous Mode Extended Base Clock Select</description>
                            <lsb>6</lsb>
                            <msb>6</msb>
                            <access>read-write</access>
                            <enumeratedValues>
                                <enumeratedValue>
                                    <name>0</name>
                                    <description>Clock cycles for 1-bit period is determined by combination between CCR2.BGDM and CCR2.ABCS.</description>
                                    <value>#0</value>
                                </enumeratedValue>
                                <enumeratedValue>
                                    <name>1</name>
                                    <description>Baud rate is 6 base clock cycles for 1-bit period and the clock of a double frequency is output from the baud rate generator.</description>
                                    <value>#1</value>
                                </enumeratedValue>
                            </enumeratedValues>
                        </field>
                        <field>
                            <name>ABCSE2</name>
                            <description>Asynchronous Mode Extended Base Clock Select 2</description>
                            <lsb>7</lsb>
                            <msb>7</msb>
                            <access>read-write</access>
                            <enumeratedValues>
                                <enumeratedValue>
                                    <name>0</name>
                                    <description>Clock cycles for 1-bit period is decided with combination between CCR2.BGDM and CCR2.ABCS.</description>
                                    <value>#0</value>
                                </enumeratedValue>
                                <enumeratedValue>
                                    <name>1</name>
                                    <description>Baud rate is 4 base clock cycles for 1-bit period and the clock of a double frequency is output from the baud rate generator.</description>
                                    <value>#1</value>
                                </enumeratedValue>
                            </enumeratedValues>
                        </field>
                        <field>
                            <name>BRR</name>
                            <description>Bit Rate Setting</description>
                            <lsb>8</lsb>
                            <msb>15</msb>
                            <access>read-write</access>
                        </field>
                        <field>
                            <name>BRME</name>
                            <description>Bit Rate Modulation Enable</description>
                            <lsb>16</lsb>
                            <msb>16</msb>
                            <access>read-write</access>
                            <enumeratedValues>
                                <enumeratedValue>
                                    <name>0</name>
                                    <description>Bit rate modulation function is disabled</description>
                                    <value>#0</value>
                                </enumeratedValue>
                                <enumeratedValue>
                                    <name>1</name>
                                    <description>Bit rate modulation function is enabled</description>
                                    <value>#1</value>
                                </enumeratedValue>
                            </enumeratedValues>
                        </field>
                        <field>
                            <name>CKS</name>
                            <description>Clock Select</description>
                            <lsb>20</lsb>
                            <msb>21</msb>
                            <access>read-write</access>
                            <enumeratedValues>
                                <enumeratedValue>
                                    <name>00</name>
                                    <description>TCLK clock (n = 0)</description>
                                    <value>#00</value>
                                </enumeratedValue>
                                <enumeratedValue>
                                    <name>01</name>
                                    <description>TCLK/4 clock (n = 1)</description>
                                    <value>#01</value>
                                </enumeratedValue>
                                <enumeratedValue>
                                    <name>10</name>
                                    <description>TCLK/16 clock (n = 2)</description>
                                    <value>#10</value>
                                </enumeratedValue>
                                <enumeratedValue>
                                    <name>11</name>
                                    <description>TCLK/64 clock (n = 3)</description>
                                    <value>#11</value>
                                </enumeratedValue>
                            </enumeratedValues>
                        </field>
                        <field>
                            <name>MDDR</name>
                            <description>Modulation Duty Setting</description>
                            <lsb>24</lsb>
                            <msb>31</msb>
                            <access>read-write</access>
                        </field>
                    </fields>
                </register>
                <register>
                    <name>CCR3</name>
                    <description>Common Control Register 3</description>
                    <addressOffset>0x14</addressOffset>
                    <size>32</size>
                    <access>read-write</access>
                    <resetValue>0x00001203</resetValue>
                    <resetMask>0xffffffff</resetMask>
                    <fields>
                        <field>
                            <name>CPHA</name>
                            <description>Clock Phase Select</description>
                            <lsb>0</lsb>
                            <msb>0</msb>
                            <access>read-write</access>
                            <enumeratedValues>
                                <enumeratedValue>
                                    <name>0</name>
                                    <description>Data is sampled at an odd edge and changes at an even edge (clock is delayed)</description>
                                    <value>#0</value>
                                </enumeratedValue>
                                <enumeratedValue>
                                    <name>1</name>
                                    <description>Data changes at an odd edge and is sampled at an even edge (clock is not delayed)</description>
                                    <value>#1</value>
                                </enumeratedValue>
                            </enumeratedValues>
                        </field>
                        <field>
                            <name>CPOL</name>
                            <description>Clock Polarity Select</description>
                            <lsb>1</lsb>
                            <msb>1</msb>
                            <access>read-write</access>
                            <enumeratedValues>
                                <enumeratedValue>
                                    <name>0</name>
                                    <description>SCKn in idle state is 0</description>
                                    <value>#0</value>
                                </enumeratedValue>
                                <enumeratedValue>
                                    <name>1</name>
                                    <description>SCKn in idle state is 1</description>
                                    <value>#1</value>
                                </enumeratedValue>
                            </enumeratedValues>
                        </field>
                        <field>
                            <name>BPEN</name>
                            <description>Synchronizer Bypass Enable</description>
                            <lsb>7</lsb>
                            <msb>7</msb>
                            <access>read-write</access>
                            <enumeratedValues>
                                <enumeratedValue>
                                    <name>0</name>
                                    <description>Synchronizer circuit is not bypassed</description>
                                    <value>#0</value>
                                </enumeratedValue>
                                <enumeratedValue>
                                    <name>1</name>
                                    <description>Synchronizer circuit is bypassed</description>
                                    <value>#1</value>
                                </enumeratedValue>
                            </enumeratedValues>
                        </field>
                        <field>
                            <name>CHR</name>
                            <description>Character Length</description>
                            <lsb>8</lsb>
                            <msb>9</msb>
                            <access>read-write</access>
                            <enumeratedValues>
                                <enumeratedValue>
                                    <name>00</name>
                                    <description>Transmit/receive in 9-bit data length</description>
                                    <value>#00</value>
                                </enumeratedValue>
                                <enumeratedValue>
                                    <name>01</name>
                                    <description>Transmit/receive in 9-bit data length</description>
                                    <value>#01</value>
                                </enumeratedValue>
                                <enumeratedValue>
                                    <name>10</name>
                                    <description>Transmit/receive in 8-bit data length (initial value)</description>
                                    <value>#10</value>
                                </enumeratedValue>
                                <enumeratedValue>
                                    <name>11</name>
                                    <description>Transmit/receive in 7-bit data length</description>
                                    <value>#11</value>
                                </enumeratedValue>
                            </enumeratedValues>
                        </field>
                        <field>
                            <name>LSBF</name>
                            <description>LSB First select</description>
                            <lsb>12</lsb>
                            <msb>12</msb>
                            <access>read-write</access>
                            <enumeratedValues>
                                <enumeratedValue>
                                    <name>0</name>
                                    <description>MSB-first</description>
                                    <value>#0</value>
                                </enumeratedValue>
                                <enumeratedValue>
                                    <name>1</name>
                                    <description>LSB-first</description>
                                    <value>#1</value>
                                </enumeratedValue>
                            </enumeratedValues>
                        </field>
                        <field>
                            <name>SINV</name>
                            <description>Transmitted/Received Data Invert</description>
                            <lsb>13</lsb>
                            <msb>13</msb>
                            <access>read-write</access>
                            <enumeratedValues>
                                <enumeratedValue>
                                    <name>0</name>
                                    <description>TDR contents are transmitted to TSR as is. RSR contents are stored to RDR as is. </description>
                                    <value>#0</value>
                                </enumeratedValue>
                                <enumeratedValue>
                                    <name>1</name>
                                    <description>TDR contents are inverted before being transmitted to TSR. RSR contents are inverted and stored to RDR. </description>
                                    <value>#1</value>
                                </enumeratedValue>
                            </enumeratedValues>
                        </field>
                        <field>
                            <name>STP</name>
                            <description>Stop Bit Length</description>
                            <lsb>14</lsb>
                            <msb>14</msb>
                            <access>read-write</access>
                            <enumeratedValues>
                                <enumeratedValue>
                                    <name>0</name>
                                    <description>1 stop bit/break delimiter length is 1-bit</description>
                                    <value>#0</value>
                                </enumeratedValue>
                                <enumeratedValue>
                                    <name>1</name>
                                    <description>2 stop bits/break delimiter length is 2-bit</description>
                                    <value>#1</value>
                                </enumeratedValue>
                            </enumeratedValues>
                        </field>
                        <field>
                            <name>RXDESEL</name>
                            <description>Asynchronous Start Bit Edge Detection Select</description>
                            <lsb>15</lsb>
                            <msb>15</msb>
                            <access>read-write</access>
                            <enumeratedValues>
                                <enumeratedValue>
                                    <name>0</name>
                                    <description>The low level on the RXDn pin is detected as the start bit</description>
                                    <value>#0</value>
                                </enumeratedValue>
                                <enumeratedValue>
                                    <name>1</name>
                                    <description>A falling edge on the RXDn pin is detected as the start bit</description>
                                    <value>#1</value>
                                </enumeratedValue>
                            </enumeratedValues>
                        </field>
                        <field>
                            <name>MOD</name>
                            <description>Communication Mode Select</description>
                            <lsb>16</lsb>
                            <msb>18</msb>
                            <access>read-write</access>
                            <enumeratedValues>
                                <enumeratedValue>
                                    <name>000</name>
                                    <description>Asynchronous mode (multi-processor mode)</description>
                                    <value>#000</value>
                                </enumeratedValue>
                                <enumeratedValue>
                                    <name>001</name>
                                    <description>Smart card interface mode</description>
                                    <value>#001</value>
                                </enumeratedValue>
                                <enumeratedValue>
                                    <name>010</name>
                                    <description>Clock synchronous mode</description>
                                    <value>#010</value>
                                </enumeratedValue>
                                <enumeratedValue>
                                    <name>011</name>
                                    <description>Simple SPI mode</description>
                                    <value>#011</value>
                                </enumeratedValue>
                                <enumeratedValue>
                                    <name>100</name>
                                    <description>Simple IIC mode</description>
                                    <value>#100</value>
                                </enumeratedValue>
                                <enumeratedValue>
                                    <name>101</name>
                                    <description>Manchester mode</description>
                                    <value>#101</value>
                                </enumeratedValue>
                                <enumeratedValue>
                                    <name>110</name>
                                    <description>Simple LIN mode</description>
                                    <value>#110</value>
                                </enumeratedValue>
                                <enumeratedValue>
                                    <name>111</name>
                                    <description>Setting prohibited</description>
                                    <value>#111</value>
                                </enumeratedValue>
                            </enumeratedValues>
                        </field>
                        <field>
                            <name>MP</name>
                            <description>Multi-Processor Mode</description>
                            <lsb>19</lsb>
                            <msb>19</msb>
                            <access>read-write</access>
                            <enumeratedValues>
                                <enumeratedValue>
                                    <name>0</name>
                                    <description>Multi-processor communications function is disabled</description>
                                    <value>#0</value>
                                </enumeratedValue>
                                <enumeratedValue>
                                    <name>1</name>
                                    <description>Multi-processor communications function is enabled</description>
                                    <value>#1</value>
                                </enumeratedValue>
                            </enumeratedValues>
                        </field>
                        <field>
                            <name>FM</name>
                            <description>FIFO Mode Select</description>
                            <lsb>20</lsb>
                            <msb>20</msb>
                            <access>read-write</access>
                            <enumeratedValues>
                                <enumeratedValue>
                                    <name>0</name>
                                    <description>TDR register and RDR register are non-FIFO buffer configuration</description>
                                    <value>#0</value>
                                </enumeratedValue>
                                <enumeratedValue>
                                    <name>1</name>
                                    <description>TDR register and RDR register are FIFO buffer configuration</description>
                                    <value>#1</value>
                                </enumeratedValue>
                            </enumeratedValues>
                        </field>
                        <field>
                            <name>DEN</name>
                            <description>Driver Enable</description>
                            <lsb>21</lsb>
                            <msb>21</msb>
                            <access>read-write</access>
                            <enumeratedValues>
                                <enumeratedValue>
                                    <name>0</name>
                                    <description>RS-485 driver control function disabled</description>
                                    <value>#0</value>
                                </enumeratedValue>
                                <enumeratedValue>
                                    <name>1</name>
                                    <description>RS-485 driver control function enabled</description>
                                    <value>#1</value>
                                </enumeratedValue>
                            </enumeratedValues>
                        </field>
                        <field>
                            <name>CKE</name>
                            <description>Clock Enable</description>
                            <lsb>24</lsb>
                            <msb>25</msb>
                            <access>read-write</access>
                        </field>
                        <field>
                            <name>ACS0</name>
                            <description>Asynchronous Mode Clock Source Select</description>
                            <lsb>26</lsb>
                            <msb>26</msb>
                            <access>read-write</access>
                            <enumeratedValues>
                                <enumeratedValue>
                                    <name>0</name>
                                    <description>External clock input</description>
                                    <value>#0</value>
                                </enumeratedValue>
                                <enumeratedValue>
                                    <name>1</name>
                                    <description>Logical AND of compare matches output from the internal GPT</description>
                                    <value>#1</value>
                                </enumeratedValue>
                            </enumeratedValues>
                        </field>
                        <field>
                            <name>GM</name>
                            <description>GSM Mode</description>
                            <lsb>28</lsb>
                            <msb>28</msb>
                            <access>read-write</access>
                            <enumeratedValues>
                                <enumeratedValue>
                                    <name>0</name>
                                    <description>Non-GSM mode operation</description>
                                    <value>#0</value>
                                </enumeratedValue>
                                <enumeratedValue>
                                    <name>1</name>
                                    <description>GSM mode operation</description>
                                    <value>#1</value>
                                </enumeratedValue>
                            </enumeratedValues>
                        </field>
                        <field>
                            <name>BLK</name>
                            <description>Block Transfer Mode</description>
                            <lsb>29</lsb>
                            <msb>29</msb>
                            <access>read-write</access>
                            <enumeratedValues>
                                <enumeratedValue>
                                    <name>0</name>
                                    <description>Non-block transfer mode operation</description>
                                    <value>#0</value>
                                </enumeratedValue>
                                <enumeratedValue>
                                    <name>1</name>
                                    <description>Block transfer mode operation</description>
                                    <value>#1</value>
                                </enumeratedValue>
                            </enumeratedValues>
                        </field>
                    </fields>
                </register>
                <register>
                    <name>CCR4</name>
                    <description>Common Control Register 4</description>
                    <addressOffset>0x18</addressOffset>
                    <size>32</size>
                    <access>read-write</access>
                    <resetValue>0x00000000</resetValue>
                    <resetMask>0xffffffff</resetMask>
                    <fields>
                        <field>
                            <name>CMPD</name>
                            <description>Compare Match Data</description>
                            <lsb>0</lsb>
                            <msb>8</msb>
                            <access>read-write</access>
                        </field>
                        <field>
                            <name>ASEN</name>
                            <description>Adjust Receive Sampling Timing Enable</description>
                            <lsb>16</lsb>
                            <msb>16</msb>
                            <access>read-write</access>
                            <enumeratedValues>
                                <enumeratedValue>
                                    <name>0</name>
                                    <description>Adjust sampling timing disabled</description>
                                    <value>#0</value>
                                </enumeratedValue>
                                <enumeratedValue>
                                    <name>1</name>
                                    <description>Adjust sampling timing enabled</description>
                                    <value>#1</value>
                                </enumeratedValue>
                            </enumeratedValues>
                        </field>
                        <field>
                            <name>ATEN</name>
                            <description>Adjust Transmit Timing Enable</description>
                            <lsb>17</lsb>
                            <msb>17</msb>
                            <access>read-write</access>
                            <enumeratedValues>
                                <enumeratedValue>
                                    <name>0</name>
                                    <description>Adjust transmit timing disabled</description>
                                    <value>#0</value>
                                </enumeratedValue>
                                <enumeratedValue>
                                    <name>1</name>
                                    <description>Adjust transmit timing enabled</description>
                                    <value>#1</value>
                                </enumeratedValue>
                            </enumeratedValues>
                        </field>
                        <field>
                            <name>SCKSEL</name>
                            <description>Master receive clock selection</description>
                            <lsb>19</lsb>
                            <msb>19</msb>
                            <access>read-write</access>
                            <enumeratedValues>
                                <enumeratedValue>
                                    <name>0</name>
                                    <description>Master receive clock is disabled</description>
                                    <value>#0</value>
                                </enumeratedValue>
                                <enumeratedValue>
                                    <name>1</name>
                                    <description>Master receive clock is enabled</description>
                                    <value>#1</value>
                                </enumeratedValue>
                            </enumeratedValues>
                        </field>
                        <field>
                            <name>AST</name>
                            <description>Adjustment Value for Receive Sampling Timing</description>
                            <lsb>24</lsb>
                            <msb>26</msb>
                            <access>read-write</access>
                            <enumeratedValues>
                                <enumeratedValue>
                                    <name>000</name>
                                    <description>1-TCLK delay</description>
                                    <value>#000</value>
                                </enumeratedValue>
                                <enumeratedValue>
                                    <name>001</name>
                                    <description>2-TCLK delay</description>
                                    <value>#001</value>
                                </enumeratedValue>
                                <enumeratedValue>
                                    <name>010</name>
                                    <description>3-TCLK delay</description>
                                    <value>#010</value>
                                </enumeratedValue>
                                <enumeratedValue>
                                    <name>011</name>
                                    <description>4-TCLK delay</description>
                                    <value>#011</value>
                                </enumeratedValue>
                                <enumeratedValue>
                                    <name>Others</name>
                                    <description>Setting prohibited</description>
                                    <isDefault>true</isDefault>
                                </enumeratedValue>
                            </enumeratedValues>
                        </field>
                        <field>
                            <name>AJD</name>
                            <description>Adjustment Direction for Receive Sampling Timing</description>
                            <lsb>27</lsb>
                            <msb>27</msb>
                            <access>read-write</access>
                            <enumeratedValues>
                                <enumeratedValue>
                                    <name>0</name>
                                    <description>The sampling timing is adjusted backward to the middle of bit.</description>
                                    <value>#0</value>
                                </enumeratedValue>
                                <enumeratedValue>
                                    <name>1</name>
                                    <description>The sampling timing is adjusted forward to the middle of bit.</description>
                                    <value>#1</value>
                                </enumeratedValue>
                            </enumeratedValues>
                        </field>
                        <field>
                            <name>ATT</name>
                            <description>Adjustment Value for Transmit Timing</description>
                            <lsb>28</lsb>
                            <msb>30</msb>
                            <access>read-write</access>
                        </field>
                        <field>
                            <name>AET</name>
                            <description>Adjustment Edge for Transmit Timing</description>
                            <lsb>31</lsb>
                            <msb>31</msb>
                            <access>read-write</access>
                            <enumeratedValues>
                                <enumeratedValue>
                                    <name>0</name>
                                    <description>When CCR1.TINV is 0, adjust the rising edge timing. When CCR1.TINV is 1, adjust the falling edge timing. </description>
                                    <value>#0</value>
                                </enumeratedValue>
                                <enumeratedValue>
                                    <name>1</name>
                                    <description>When CCR1.TINV is 0, adjust the falling edge timing. When CCR1.TINV is 1, adjust the rising edge timing. </description>
                                    <value>#1</value>
                                </enumeratedValue>
                            </enumeratedValues>
                        </field>
                    </fields>
                </register>
                <register>
                    <name>CESR</name>
                    <description>Communication Enable Status Register</description>
                    <addressOffset>0x1C</addressOffset>
                    <size>8</size>
                    <access>read-only</access>
                    <resetValue>0x00</resetValue>
                    <resetMask>0xff</resetMask>
                    <fields>
                        <field>
                            <name>RIST</name>
                            <description>RE Internal Status</description>
                            <lsb>0</lsb>
                            <msb>0</msb>
                            <access>read-only</access>
                            <enumeratedValues>
                                <enumeratedValue>
                                    <name>0</name>
                                    <description>RE signal internal state value 0</description>
                                    <value>#0</value>
                                </enumeratedValue>
                                <enumeratedValue>
                                    <name>1</name>
                                    <description>RE signal internal state value 1</description>
                                    <value>#1</value>
                                </enumeratedValue>
                            </enumeratedValues>
                        </field>
                        <field>
                            <name>TIST</name>
                            <description>TE Internal Status</description>
                            <lsb>4</lsb>
                            <msb>4</msb>
                            <access>read-only</access>
                            <enumeratedValues>
                                <enumeratedValue>
                                    <name>0</name>
                                    <description>TE signal internal state value 0</description>
                                    <value>#0</value>
                                </enumeratedValue>
                                <enumeratedValue>
                                    <name>1</name>
                                    <description>TE signal internal state value 1</description>
                                    <value>#1</value>
                                </enumeratedValue>
                            </enumeratedValues>
                        </field>
                    </fields>
                </register>
                <register>
                    <name>ICR</name>
                    <description>Simple IIC Control Register</description>
                    <addressOffset>0x20</addressOffset>
                    <size>32</size>
                    <access>read-write</access>
                    <resetValue>0x00000000</resetValue>
                    <resetMask>0xffffffff</resetMask>
                    <fields>
                        <field>
                            <name>IICDL</name>
                            <description>SDA Delay Output Select</description>
                            <lsb>0</lsb>
                            <msb>4</msb>
                            <access>read-write</access>
                        </field>
                        <field>
                            <name>IICINTM</name>
                            <description>IIC Interrupt Mode Select</description>
                            <lsb>8</lsb>
                            <msb>8</msb>
                            <access>read-write</access>
                            <enumeratedValues>
                                <enumeratedValue>
                                    <name>0</name>
                                    <description>Use ACK/NACK interrupts</description>
                                    <value>#0</value>
                                </enumeratedValue>
                                <enumeratedValue>
                                    <name>1</name>
                                    <description>Use reception and transmission interrupts</description>
                                    <value>#1</value>
                                </enumeratedValue>
                            </enumeratedValues>
                        </field>
                        <field>
                            <name>IICCSC</name>
                            <description>Clock Synchronization</description>
                            <lsb>9</lsb>
                            <msb>9</msb>
                            <access>read-write</access>
                            <enumeratedValues>
                                <enumeratedValue>
                                    <name>0</name>
                                    <description>No synchronization with the clock signal</description>
                                    <value>#0</value>
                                </enumeratedValue>
                                <enumeratedValue>
                                    <name>1</name>
                                    <description>Synchronization with the clock signal</description>
                                    <value>#1</value>
                                </enumeratedValue>
                            </enumeratedValues>
                        </field>
                        <field>
                            <name>IICACKT</name>
                            <description>ACK Transmission Data</description>
                            <lsb>13</lsb>
                            <msb>13</msb>
                            <access>read-write</access>
                            <enumeratedValues>
                                <enumeratedValue>
                                    <name>0</name>
                                    <description>ACK transmission</description>
                                    <value>#0</value>
                                </enumeratedValue>
                                <enumeratedValue>
                                    <name>1</name>
                                    <description>NACK transmission and reception of ACK/NACK</description>
                                    <value>#1</value>
                                </enumeratedValue>
                            </enumeratedValues>
                        </field>
                        <field>
                            <name>IICSTAREQ</name>
                            <description>Start Condition Generation</description>
                            <lsb>16</lsb>
                            <msb>16</msb>
                            <access>read-write</access>
                            <enumeratedValues>
                                <enumeratedValue>
                                    <name>0</name>
                                    <description>A start condition is not generated</description>
                                    <value>#0</value>
                                </enumeratedValue>
                                <enumeratedValue>
                                    <name>1</name>
                                    <description>A start condition is generated </description>
                                    <value>#1</value>
                                </enumeratedValue>
                            </enumeratedValues>
                        </field>
                        <field>
                            <name>IICRSTAREQ</name>
                            <description>Restart Condition Generation</description>
                            <lsb>17</lsb>
                            <msb>17</msb>
                            <access>read-write</access>
                            <enumeratedValues>
                                <enumeratedValue>
                                    <name>0</name>
                                    <description>A restart condition is not generated</description>
                                    <value>#0</value>
                                </enumeratedValue>
                                <enumeratedValue>
                                    <name>1</name>
                                    <description>A restart condition is generated </description>
                                    <value>#1</value>
                                </enumeratedValue>
                            </enumeratedValues>
                        </field>
                        <field>
                            <name>IICSTPREQ</name>
                            <description>Stop Condition Generation</description>
                            <lsb>18</lsb>
                            <msb>18</msb>
                            <access>read-write</access>
                            <enumeratedValues>
                                <enumeratedValue>
                                    <name>0</name>
                                    <description>A stop condition is not generated.</description>
                                    <value>#0</value>
                                </enumeratedValue>
                                <enumeratedValue>
                                    <name>1</name>
                                    <description>A stop condition is generated </description>
                                    <value>#1</value>
                                </enumeratedValue>
                            </enumeratedValues>
                        </field>
                        <field>
                            <name>IICSDAS</name>
                            <description>SDA Output Select</description>
                            <lsb>20</lsb>
                            <msb>21</msb>
                            <access>read-write</access>
                            <enumeratedValues>
                                <enumeratedValue>
                                    <name>00</name>
                                    <description>Serial data output</description>
                                    <value>#00</value>
                                </enumeratedValue>
                                <enumeratedValue>
                                    <name>01</name>
                                    <description>Generate a start, restart, or stop condition</description>
                                    <value>#01</value>
                                </enumeratedValue>
                                <enumeratedValue>
                                    <name>10</name>
                                    <description>Output the low level on the SDAn pin</description>
                                    <value>#10</value>
                                </enumeratedValue>
                                <enumeratedValue>
                                    <name>11</name>
                                    <description>Place the SDAn pin in the high-impedance state</description>
                                    <value>#11</value>
                                </enumeratedValue>
                            </enumeratedValues>
                        </field>
                        <field>
                            <name>IICSCLS</name>
                            <description>SCL Output Select</description>
                            <lsb>22</lsb>
                            <msb>23</msb>
                            <access>read-write</access>
                            <enumeratedValues>
                                <enumeratedValue>
                                    <name>00</name>
                                    <description>Serial clock output</description>
                                    <value>#00</value>
                                </enumeratedValue>
                                <enumeratedValue>
                                    <name>01</name>
                                    <description>Generate a start, restart, or stop condition</description>
                                    <value>#01</value>
                                </enumeratedValue>
                                <enumeratedValue>
                                    <name>10</name>
                                    <description>Output the low level on the SCLn pin</description>
                                    <value>#10</value>
                                </enumeratedValue>
                                <enumeratedValue>
                                    <name>11</name>
                                    <description>Place the SCLn pin in the high-impedance state</description>
                                    <value>#11</value>
                                </enumeratedValue>
                            </enumeratedValues>
                        </field>
                    </fields>
                </register>
                <register>
                    <name>FCR</name>
                    <description>FIFO Control Register</description>
                    <addressOffset>0x24</addressOffset>
                    <size>32</size>
                    <access>read-write</access>
                    <resetValue>0x1f1f0000</resetValue>
                    <resetMask>0xffffffff</resetMask>
                    <fields>
                        <field>
                            <name>DRES</name>
                            <description>Receive Data Ready Error Select Bit</description>
                            <lsb>0</lsb>
                            <msb>0</msb>
                            <access>read-write</access>
                            <enumeratedValues>
                                <enumeratedValue>
                                    <name>0</name>
                                    <description>Reception data full interrupt (SCIn_RXI)</description>
                                    <value>#0</value>
                                </enumeratedValue>
                                <enumeratedValue>
                                    <name>1</name>
                                    <description>Receive error interrupt (SCIn_ERI)</description>
                                    <value>#1</value>
                                </enumeratedValue>
                            </enumeratedValues>
                        </field>
                        <field>
                            <name>TTRG</name>
                            <description>Transmit FIFO Data Trigger Number</description>
                            <lsb>8</lsb>
                            <msb>12</msb>
                            <access>read-write</access>
                        </field>
                        <field>
                            <name>TFRST</name>
                            <description>Transmit FIFO Data Register Reset</description>
                            <lsb>15</lsb>
                            <msb>15</msb>
                            <access>write-only</access>
                            <enumeratedValues>
                                <enumeratedValue>
                                    <name>0</name>
                                    <description>When set, this bit is invalid and does not affect operation</description>
                                    <value>#0</value>
                                </enumeratedValue>
                                <enumeratedValue>
                                    <name>1</name>
                                    <description>The number of data stored in Transmit-FIFO (TDR register) is 0</description>
                                    <value>#1</value>
                                </enumeratedValue>
                            </enumeratedValues>
                        </field>
                        <field>
                            <name>RTRG</name>
                            <description>Receive FIFO Data Trigger Number</description>
                            <lsb>16</lsb>
                            <msb>20</msb>
                            <access>read-write</access>
                        </field>
                        <field>
                            <name>RFRST</name>
                            <description>Receive FIFO Data Register Reset</description>
                            <lsb>23</lsb>
                            <msb>23</msb>
                            <access>write-only</access>
                            <enumeratedValues>
                                <enumeratedValue>
                                    <name>0</name>
                                    <description>When set, this bit is invalid and does not affect operation</description>
                                    <value>#0</value>
                                </enumeratedValue>
                                <enumeratedValue>
                                    <name>1</name>
                                    <description>The number of data stored in Receive-FIFO(RDR register) is 0</description>
                                    <value>#1</value>
                                </enumeratedValue>
                            </enumeratedValues>
                        </field>
                        <field>
                            <name>RSTRG</name>
                            <description>RTS Output Active Trigger Number Select</description>
                            <lsb>24</lsb>
                            <msb>28</msb>
                            <access>read-write</access>
                        </field>
                    </fields>
                </register>
                <register>
                    <name>MCR</name>
                    <description>Manchester Control Register</description>
                    <addressOffset>0x2C</addressOffset>
                    <size>32</size>
                    <access>read-write</access>
                    <resetValue>0x00000000</resetValue>
                    <resetMask>0xffffffff</resetMask>
                    <fields>
                        <field>
                            <name>RMPOL</name>
                            <description>Polarity of Received Manchester Code</description>
                            <lsb>0</lsb>
                            <msb>0</msb>
                            <access>read-write</access>
                            <enumeratedValues>
                                <enumeratedValue>
                                    <name>0</name>
                                    <description>Logic 0 is coded as a zero-to-one transition in Manchester code Logic 1 is coded as a one-to-zero transition in Manchester code </description>
                                    <value>#0</value>
                                </enumeratedValue>
                                <enumeratedValue>
                                    <name>1</name>
                                    <description>Logic 0 is coded as a one-to-zero transition in Manchester code Logic 1 is coded as a zero-to-one transition in Manchester code </description>
                                    <value>#1</value>
                                </enumeratedValue>
                            </enumeratedValues>
                        </field>
                        <field>
                            <name>TMPOL</name>
                            <description>Polarity of Transmit Manchester Code</description>
                            <lsb>1</lsb>
                            <msb>1</msb>
                            <access>read-write</access>
                            <enumeratedValues>
                                <enumeratedValue>
                                    <name>0</name>
                                    <description>Logic 0 is coded as a zero-to-one transition in Manchester code Logic 1 is coded as a one-to-zero transition in Manchester code </description>
                                    <value>#0</value>
                                </enumeratedValue>
                                <enumeratedValue>
                                    <name>1</name>
                                    <description>Logic 0 is coded as a one-to-zero transition in Manchester code Logic 1 is coded as a zero-to-one transition in Manchester code </description>
                                    <value>#1</value>
                                </enumeratedValue>
                            </enumeratedValues>
                        </field>
                        <field>
                            <name>ERTEN</name>
                            <description>Manchester Edge Retiming Enable</description>
                            <lsb>2</lsb>
                            <msb>2</msb>
                            <access>read-write</access>
                            <enumeratedValues>
                                <enumeratedValue>
                                    <name>0</name>
                                    <description>Disables the receive retiming function</description>
                                    <value>#0</value>
                                </enumeratedValue>
                                <enumeratedValue>
                                    <name>1</name>
                                    <description>Enables the receive retiming function</description>
                                    <value>#1</value>
                                </enumeratedValue>
                            </enumeratedValues>
                        </field>
                        <field>
                            <name>SYNVAL</name>
                            <description>SYNC value Setting</description>
                            <lsb>4</lsb>
                            <msb>4</msb>
                            <access>read-write</access>
                        </field>
                        <field>
                            <name>SYNSEL</name>
                            <description>SYNC Select</description>
                            <lsb>5</lsb>
                            <msb>5</msb>
                            <access>read-write</access>
                            <enumeratedValues>
                                <enumeratedValue>
                                    <name>0</name>
                                    <description>The start bit pattern is set with the SYNVAL bit</description>
                                    <value>#0</value>
                                </enumeratedValue>
                                <enumeratedValue>
                                    <name>1</name>
                                    <description>The start bit pattern is set with the TSYNC bit</description>
                                    <value>#1</value>
                                </enumeratedValue>
                            </enumeratedValues>
                        </field>
                        <field>
                            <name>SBSEL</name>
                            <description>Start Bit Select</description>
                            <lsb>6</lsb>
                            <msb>6</msb>
                            <access>read-write</access>
                            <enumeratedValues>
                                <enumeratedValue>
                                    <name>0</name>
                                    <description>The start bit area consists of one bit</description>
                                    <value>#0</value>
                                </enumeratedValue>
                                <enumeratedValue>
                                    <name>1</name>
                                    <description>The start bit area consists of three bits (COMMAND SYNC or DATA SYNC) </description>
                                    <value>#1</value>
                                </enumeratedValue>
                            </enumeratedValues>
                        </field>
                        <field>
                            <name>TPLEN</name>
                            <description>Transmit Preface Length</description>
                            <lsb>8</lsb>
                            <msb>11</msb>
                            <access>read-write</access>
                            <enumeratedValues>
                                <enumeratedValue>
                                    <name>0x0</name>
                                    <description>Disables the transmit preface generation</description>
                                    <value>0x0</value>
                                </enumeratedValue>
                                <enumeratedValue>
                                    <name>Others</name>
                                    <description>Transmit preface length (bit length)</description>
                                    <isDefault>true</isDefault>
                                </enumeratedValue>
                            </enumeratedValues>
                        </field>
                        <field>
                            <name>TPPAT</name>
                            <description>Transmit Preface Pattern</description>
                            <lsb>12</lsb>
                            <msb>13</msb>
                            <access>read-write</access>
                            <enumeratedValues>
                                <enumeratedValue>
                                    <name>00</name>
                                    <description>ALL ZERO</description>
                                    <value>#00</value>
                                </enumeratedValue>
                                <enumeratedValue>
                                    <name>01</name>
                                    <description>ZERO ONE</description>
                                    <value>#01</value>
                                </enumeratedValue>
                                <enumeratedValue>
                                    <name>10</name>
                                    <description>ONE ZERO</description>
                                    <value>#10</value>
                                </enumeratedValue>
                                <enumeratedValue>
                                    <name>11</name>
                                    <description>ALL ONE</description>
                                    <value>#11</value>
                                </enumeratedValue>
                            </enumeratedValues>
                        </field>
                        <field>
                            <name>RPLEN</name>
                            <description>Receive Preface Length</description>
                            <lsb>16</lsb>
                            <msb>19</msb>
                            <access>read-write</access>
                            <enumeratedValues>
                                <enumeratedValue>
                                    <name>0x0</name>
                                    <description>Disables the receive preface generation</description>
                                    <value>0x0</value>
                                </enumeratedValue>
                                <enumeratedValue>
                                    <name>Others</name>
                                    <description>Receive preface length (bit length)</description>
                                    <isDefault>true</isDefault>
                                </enumeratedValue>
                            </enumeratedValues>
                        </field>
                        <field>
                            <name>RPPAT</name>
                            <description>Receive Preface Pattern</description>
                            <lsb>20</lsb>
                            <msb>21</msb>
                            <access>read-write</access>
                            <enumeratedValues>
                                <enumeratedValue>
                                    <name>00</name>
                                    <description>ALL ZERO</description>
                                    <value>#00</value>
                                </enumeratedValue>
                                <enumeratedValue>
                                    <name>01</name>
                                    <description>ZERO ONE</description>
                                    <value>#01</value>
                                </enumeratedValue>
                                <enumeratedValue>
                                    <name>10</name>
                                    <description>ONE ZERO</description>
                                    <value>#10</value>
                                </enumeratedValue>
                                <enumeratedValue>
                                    <name>11</name>
                                    <description>ALL ONE</description>
                                    <value>#11</value>
                                </enumeratedValue>
                            </enumeratedValues>
                        </field>
                        <field>
                            <name>PFEREN</name>
                            <description>Preface Error Enable</description>
                            <lsb>24</lsb>
                            <msb>24</msb>
                            <access>read-write</access>
                            <enumeratedValues>
                                <enumeratedValue>
                                    <name>0</name>
                                    <description>Does not handle a preface error as an interrupt source</description>
                                    <value>#0</value>
                                </enumeratedValue>
                                <enumeratedValue>
                                    <name>1</name>
                                    <description>Handles a preface error as an interrupt source</description>
                                    <value>#1</value>
                                </enumeratedValue>
                            </enumeratedValues>
                        </field>
                        <field>
                            <name>SYEREN</name>
                            <description>Receive SYNC Error Enable</description>
                            <lsb>25</lsb>
                            <msb>25</msb>
                            <access>read-write</access>
                            <enumeratedValues>
                                <enumeratedValue>
                                    <name>0</name>
                                    <description>Does not handle a receive SYNC error as an interrupt source</description>
                                    <value>#0</value>
                                </enumeratedValue>
                                <enumeratedValue>
                                    <name>1</name>
                                    <description>Handles a receive SYNC error as an interrupt source</description>
                                    <value>#1</value>
                                </enumeratedValue>
                            </enumeratedValues>
                        </field>
                        <field>
                            <name>SBEREN</name>
                            <description>Start Bit Error Enable</description>
                            <lsb>26</lsb>
                            <msb>26</msb>
                            <access>read-write</access>
                            <enumeratedValues>
                                <enumeratedValue>
                                    <name>0</name>
                                    <description>Does not handle a start bit error as an interrupt source</description>
                                    <value>#0</value>
                                </enumeratedValue>
                                <enumeratedValue>
                                    <name>1</name>
                                    <description>Handles a start bit error as an interrupt source</description>
                                    <value>#1</value>
                                </enumeratedValue>
                            </enumeratedValues>
                        </field>
                    </fields>
                </register>
                <register>
                    <name>DCR</name>
                    <description>Driver Control Register</description>
                    <addressOffset>0x30</addressOffset>
                    <size>32</size>
                    <access>read-write</access>
                    <resetValue>0x00000000</resetValue>
                    <resetMask>0xffffffff</resetMask>
                    <fields>
                        <field>
                            <name>DEPOL</name>
                            <description>Driver Effective Polarity Select</description>
                            <lsb>0</lsb>
                            <msb>0</msb>
                            <access>read-write</access>
                            <enumeratedValues>
                                <enumeratedValue>
                                    <name>0</name>
                                    <description>The DEn signal is active-high</description>
                                    <value>#0</value>
                                </enumeratedValue>
                                <enumeratedValue>
                                    <name>1</name>
                                    <description>The DEn signal is active-low</description>
                                    <value>#1</value>
                                </enumeratedValue>
                            </enumeratedValues>
                        </field>
                        <field>
                            <name>DEAST</name>
                            <description>Driver Assertion Time</description>
                            <lsb>8</lsb>
                            <msb>12</msb>
                            <access>read-write</access>
                        </field>
                        <field>
                            <name>DENGT</name>
                            <description>Driver Negate Time</description>
                            <lsb>16</lsb>
                            <msb>20</msb>
                            <access>read-write</access>
                        </field>
                    </fields>
                </register>
                <register>
                    <name>XCR0</name>
                    <description>Simple LIN Control Register 0</description>
                    <addressOffset>0x34</addressOffset>
                    <size>32</size>
                    <access>read-write</access>
                    <resetValue>0x00000000</resetValue>
                    <resetMask>0xffffffff</resetMask>
                    <fields>
                        <field>
                            <name>TCSS</name>
                            <description>Timer Count Clock Source Selection</description>
                            <lsb>0</lsb>
                            <msb>1</msb>
                            <access>read-write</access>
                            <enumeratedValues>
                                <enumeratedValue>
                                    <name>01</name>
                                    <description>TCLK/4</description>
                                    <value>#01</value>
                                </enumeratedValue>
                                <enumeratedValue>
                                    <name>10</name>
                                    <description>TCLK/16</description>
                                    <value>#10</value>
                                </enumeratedValue>
                                <enumeratedValue>
                                    <name>11</name>
                                    <description>TCLK/64</description>
                                    <value>#11</value>
                                </enumeratedValue>
                            </enumeratedValues>
                        </field>
                        <field>
                            <name>BFE</name>
                            <description>Break Field Enable</description>
                            <lsb>8</lsb>
                            <msb>8</msb>
                            <access>read-write</access>
                            <enumeratedValues>
                                <enumeratedValue>
                                    <name>0</name>
                                    <description>No Break Field</description>
                                    <value>#0</value>
                                </enumeratedValue>
                                <enumeratedValue>
                                    <name>1</name>
                                    <description>With Break Field</description>
                                    <value>#1</value>
                                </enumeratedValue>
                            </enumeratedValues>
                        </field>
                        <field>
                            <name>CF0RE</name>
                            <description>Control Field 0 Enable</description>
                            <lsb>9</lsb>
                            <msb>9</msb>
                            <access>read-write</access>
                            <enumeratedValues>
                                <enumeratedValue>
                                    <name>0</name>
                                    <description>No Control Field 0</description>
                                    <value>#0</value>
                                </enumeratedValue>
                                <enumeratedValue>
                                    <name>1</name>
                                    <description>With Control Field 0</description>
                                    <value>#1</value>
                                </enumeratedValue>
                            </enumeratedValues>
                        </field>
                        <field>
                            <name>CF1DS</name>
                            <description>Control Field1 Compare Data Select</description>
                            <lsb>10</lsb>
                            <msb>11</msb>
                            <access>read-write</access>
                            <enumeratedValues>
                                <enumeratedValue>
                                    <name>00</name>
                                    <description>Select XCR1.PCF1D[7:0] as the compare data</description>
                                    <value>#00</value>
                                </enumeratedValue>
                                <enumeratedValue>
                                    <name>01</name>
                                    <description>Select XCR1.SCF1D[7:0] as the compare data</description>
                                    <value>#01</value>
                                </enumeratedValue>
                                <enumeratedValue>
                                    <name>10</name>
                                    <description>Select both XCR1.PCF1D[7:0] and XCR1.SCF1D[7:0] as the compare data</description>
                                    <value>#10</value>
                                </enumeratedValue>
                                <enumeratedValue>
                                    <name>11</name>
                                    <description>Setting prohibited</description>
                                    <value>#11</value>
                                </enumeratedValue>
                            </enumeratedValues>
                        </field>
                        <field>
                            <name>PIBE</name>
                            <description>Priority Interrupt Bit Enable</description>
                            <lsb>12</lsb>
                            <msb>12</msb>
                            <access>read-write</access>
                            <enumeratedValues>
                                <enumeratedValue>
                                    <name>0</name>
                                    <description>Priority interrupt bit disabled</description>
                                    <value>#0</value>
                                </enumeratedValue>
                                <enumeratedValue>
                                    <name>1</name>
                                    <description>Priority interrupt bit enabled</description>
                                    <value>#1</value>
                                </enumeratedValue>
                            </enumeratedValues>
                        </field>
                        <field>
                            <name>PIBS</name>
                            <description>Priority Interrupt Bit Select</description>
                            <lsb>13</lsb>
                            <msb>15</msb>
                            <access>read-write</access>
                            <enumeratedValues>
                                <enumeratedValue>
                                    <name>000</name>
                                    <description>Bit 0 of Control Field 1</description>
                                    <value>#000</value>
                                </enumeratedValue>
                                <enumeratedValue>
                                    <name>001</name>
                                    <description>Bit 1 of Control Field 1</description>
                                    <value>#001</value>
                                </enumeratedValue>
                                <enumeratedValue>
                                    <name>010</name>
                                    <description>Bit 2 of Control Field 1</description>
                                    <value>#010</value>
                                </enumeratedValue>
                                <enumeratedValue>
                                    <name>011</name>
                                    <description>Bit 3 of Control Field 1</description>
                                    <value>#011</value>
                                </enumeratedValue>
                                <enumeratedValue>
                                    <name>100</name>
                                    <description>Bit 4 of Control Field 1</description>
                                    <value>#100</value>
                                </enumeratedValue>
                                <enumeratedValue>
                                    <name>101</name>
                                    <description>Bit 5 of Control Field 1</description>
                                    <value>#101</value>
                                </enumeratedValue>
                                <enumeratedValue>
                                    <name>110</name>
                                    <description>Bit 6 of Control Field 1</description>
                                    <value>#110</value>
                                </enumeratedValue>
                                <enumeratedValue>
                                    <name>111</name>
                                    <description>Bit 7 of Control Field 1</description>
                                    <value>#111</value>
                                </enumeratedValue>
                            </enumeratedValues>
                        </field>
                        <field>
                            <name>BFOIE</name>
                            <description>Break Field Output Completion Interrupt Enable</description>
                            <lsb>16</lsb>
                            <msb>16</msb>
                            <access>read-write</access>
                            <enumeratedValues>
                                <enumeratedValue>
                                    <name>0</name>
                                    <description>Break Field output completion is not included in SCIn_TXI interrupt factor</description>
                                    <value>#0</value>
                                </enumeratedValue>
                                <enumeratedValue>
                                    <name>1</name>
                                    <description>Break Field output completion is included in SCIn_TXI interrupt factor</description>
                                    <value>#1</value>
                                </enumeratedValue>
                            </enumeratedValues>
                        </field>
                        <field>
                            <name>BCDIE</name>
                            <description>Bus Conflict Detection Interrupt Enable</description>
                            <lsb>17</lsb>
                            <msb>17</msb>
                            <access>read-write</access>
                            <enumeratedValues>
                                <enumeratedValue>
                                    <name>0</name>
                                    <description>Bus conflict detection is not included in SCIn_ERI interrupt factor</description>
                                    <value>#0</value>
                                </enumeratedValue>
                                <enumeratedValue>
                                    <name>1</name>
                                    <description>Bus conflict detection is included in SCIn_ERI interrupt factor</description>
                                    <value>#1</value>
                                </enumeratedValue>
                            </enumeratedValues>
                        </field>
                        <field>
                            <name>BFDIE</name>
                            <description>Break Field Detection Interrupt Enable</description>
                            <lsb>20</lsb>
                            <msb>20</msb>
                            <access>read-write</access>
                            <enumeratedValues>
                                <enumeratedValue>
                                    <name>0</name>
                                    <description>Break Field detection interrupt disabled</description>
                                    <value>#0</value>
                                </enumeratedValue>
                                <enumeratedValue>
                                    <name>1</name>
                                    <description>Break Field detection interrupt enabled</description>
                                    <value>#1</value>
                                </enumeratedValue>
                            </enumeratedValues>
                        </field>
                        <field>
                            <name>COFIE</name>
                            <description>Counter Overflow Interrupt Enable</description>
                            <lsb>21</lsb>
                            <msb>21</msb>
                            <access>read-write</access>
                            <enumeratedValues>
                                <enumeratedValue>
                                    <name>0</name>
                                    <description>Counter overflow is not included in SCIn_ERI interrupt factor</description>
                                    <value>#0</value>
                                </enumeratedValue>
                                <enumeratedValue>
                                    <name>1</name>
                                    <description>Counter overflow is included in SCIn_ERI interrupt factor</description>
                                    <value>#1</value>
                                </enumeratedValue>
                            </enumeratedValues>
                        </field>
                        <field>
                            <name>AEDIE</name>
                            <description>Active Edge Detection Interrupt Enable</description>
                            <lsb>22</lsb>
                            <msb>22</msb>
                            <access>read-write</access>
                            <enumeratedValues>
                                <enumeratedValue>
                                    <name>0</name>
                                    <description>Active edge detection interrupt disabled</description>
                                    <value>#0</value>
                                </enumeratedValue>
                                <enumeratedValue>
                                    <name>1</name>
                                    <description>Active edge detection interrupt enabled</description>
                                    <value>#1</value>
                                </enumeratedValue>
                            </enumeratedValues>
                        </field>
                        <field>
                            <name>BCCS</name>
                            <description>Bus Conflict Detection Clock Selection</description>
                            <lsb>24</lsb>
                            <msb>25</msb>
                            <access>read-write</access>
                            <enumeratedValues>
                                <enumeratedValue>
                                    <name>00</name>
                                    <description>Base clock</description>
                                    <value>#00</value>
                                </enumeratedValue>
                                <enumeratedValue>
                                    <name>01</name>
                                    <description>Base clock/2</description>
                                    <value>#01</value>
                                </enumeratedValue>
                                <enumeratedValue>
                                    <name>10</name>
                                    <description>Base clock/4</description>
                                    <value>#10</value>
                                </enumeratedValue>
                                <enumeratedValue>
                                    <name>11</name>
                                    <description>Setting prohibited</description>
                                    <value>#11</value>
                                </enumeratedValue>
                            </enumeratedValues>
                        </field>
                    </fields>
                </register>
                <register>
                    <name>XCR1</name>
                    <description>Simple LIN Control Register 1</description>
                    <addressOffset>0x38</addressOffset>
                    <size>32</size>
                    <access>read-write</access>
                    <resetValue>0x00000000</resetValue>
                    <resetMask>0xffffffff</resetMask>
                    <fields>
                        <field>
                            <name>TCST</name>
                            <description>Break Field Output Timer Count Start Trigger</description>
                            <lsb>0</lsb>
                            <msb>0</msb>
                            <access>read-write</access>
                            <enumeratedValues>
                                <enumeratedValue>
                                    <name>0</name>
                                    <description>Break Field output timer count stopped</description>
                                    <value>#0</value>
                                </enumeratedValue>
                                <enumeratedValue>
                                    <name>1</name>
                                    <description>Break Field output timer count start</description>
                                    <value>#1</value>
                                </enumeratedValue>
                            </enumeratedValues>
                        </field>
                        <field>
                            <name>SDST</name>
                            <description>Start Frame Detection Enable</description>
                            <lsb>4</lsb>
                            <msb>4</msb>
                            <access>read-write</access>
                            <enumeratedValues>
                                <enumeratedValue>
                                    <name>0</name>
                                    <description>Start Frame/Break Field detection disabled</description>
                                    <value>#0</value>
                                </enumeratedValue>
                                <enumeratedValue>
                                    <name>1</name>
                                    <description>Start Frame/Break Field detection enabled</description>
                                    <value>#1</value>
                                </enumeratedValue>
                            </enumeratedValues>
                        </field>
                        <field>
                            <name>BMEN</name>
                            <description>Bit Rate Measurement Enable</description>
                            <lsb>5</lsb>
                            <msb>5</msb>
                            <access>read-write</access>
                            <enumeratedValues>
                                <enumeratedValue>
                                    <name>0</name>
                                    <description>Bit rate measurement disabled</description>
                                    <value>#0</value>
                                </enumeratedValue>
                                <enumeratedValue>
                                    <name>1</name>
                                    <description>Bit rate measurement enabled</description>
                                    <value>#1</value>
                                </enumeratedValue>
                            </enumeratedValues>
                        </field>
                        <field>
                            <name>PCF1D</name>
                            <description>Priority Compare Data for Control Field 1</description>
                            <lsb>8</lsb>
                            <msb>15</msb>
                            <access>read-write</access>
                        </field>
                        <field>
                            <name>SCF1D</name>
                            <description>Secondary Compare Data for Control Field 1</description>
                            <lsb>16</lsb>
                            <msb>23</msb>
                            <access>read-write</access>
                        </field>
                        <field>
                            <name>CF1CE</name>
                            <description>Control Field 1 Compare Bit Enable</description>
                            <lsb>24</lsb>
                            <msb>31</msb>
                            <access>read-write</access>
                            <enumeratedValues>
                                <enumeratedValue>
                                    <name>0</name>
                                    <description>Control Field 1 bit N compare disabled</description>
                                    <value>#0</value>
                                </enumeratedValue>
                                <enumeratedValue>
                                    <name>1</name>
                                    <description>Control Field 1 bit N compare enabled</description>
                                    <value>#1</value>
                                </enumeratedValue>
                            </enumeratedValues>
                        </field>
                    </fields>
                </register>
                <register>
                    <name>XCR2</name>
                    <description>Simple LIN Control Register 2</description>
                    <addressOffset>0x3C</addressOffset>
                    <size>32</size>
                    <access>read-write</access>
                    <resetValue>0xfffe0000</resetValue>
                    <resetMask>0xffffffff</resetMask>
                    <fields>
                        <field>
                            <name>CF0D</name>
                            <description>Control Field 0 Compare Data</description>
                            <lsb>0</lsb>
                            <msb>7</msb>
                            <access>read-write</access>
                        </field>
                        <field>
                            <name>CF0CE</name>
                            <description>Control Field 0 Compare Bit Enable</description>
                            <lsb>8</lsb>
                            <msb>15</msb>
                            <access>read-write</access>
                            <enumeratedValues>
                                <enumeratedValue>
                                    <name>0</name>
                                    <description>Control Field 0 bit N compare disabled</description>
                                    <value>#0</value>
                                </enumeratedValue>
                                <enumeratedValue>
                                    <name>1</name>
                                    <description>Control Field 0 bit N compare enabled</description>
                                    <value>#1</value>
                                </enumeratedValue>
                            </enumeratedValues>
                        </field>
                        <field>
                            <name>BFLW</name>
                            <description>Break Field Length Setting</description>
                            <lsb>16</lsb>
                            <msb>31</msb>
                            <access>read-write</access>
                        </field>
                    </fields>
                </register>
                <register>
                    <name>CSR</name>
                    <description>Common Status Register</description>
                    <addressOffset>0x48</addressOffset>
                    <size>32</size>
                    <access>read-only</access>
                    <resetValue>0x60008000</resetValue>
                    <resetMask>0xffffffff</resetMask>
                    <fields>
                        <field>
                            <name>ERS</name>
                            <description>Error Signal Status Flag</description>
                            <lsb>4</lsb>
                            <msb>4</msb>
                            <access>read-only</access>
                            <enumeratedValues>
                                <enumeratedValue>
                                    <name>0</name>
                                    <description>Error signal low not responded</description>
                                    <value>#0</value>
                                </enumeratedValue>
                                <enumeratedValue>
                                    <name>1</name>
                                    <description>Error signal low responded</description>
                                    <value>#1</value>
                                </enumeratedValue>
                            </enumeratedValues>
                        </field>
                        <field>
                            <name>RXDMON</name>
                            <description>Serial Input Data Monitor Bit</description>
                            <lsb>15</lsb>
                            <msb>15</msb>
                            <access>read-only</access>
                            <enumeratedValues>
                                <enumeratedValue>
                                    <name>0</name>
                                    <description>When RINV is 0, RXDn pin is the low level. When RINV is 1, RXDn pin is the high level. </description>
                                    <value>#0</value>
                                </enumeratedValue>
                                <enumeratedValue>
                                    <name>1</name>
                                    <description>When RINV is 0, RXDn pin is the high level. When RINV is 1, RXDn pin is the low level. </description>
                                    <value>#1</value>
                                </enumeratedValue>
                            </enumeratedValues>
                        </field>
                        <field>
                            <name>DCMF</name>
                            <description>Data Compare Match Flag</description>
                            <lsb>16</lsb>
                            <msb>16</msb>
                            <access>read-only</access>
                            <enumeratedValues>
                                <enumeratedValue>
                                    <name>0</name>
                                    <description>No matched</description>
                                    <value>#0</value>
                                </enumeratedValue>
                                <enumeratedValue>
                                    <name>1</name>
                                    <description>Matched</description>
                                    <value>#1</value>
                                </enumeratedValue>
                            </enumeratedValues>
                        </field>
                        <field>
                            <name>DPER</name>
                            <description>Data Compare Match Parity Error Flag</description>
                            <lsb>17</lsb>
                            <msb>17</msb>
                            <access>read-only</access>
                            <enumeratedValues>
                                <enumeratedValue>
                                    <name>0</name>
                                    <description>No parity error occurred at address match detection</description>
                                    <value>#0</value>
                                </enumeratedValue>
                                <enumeratedValue>
                                    <name>1</name>
                                    <description>A parity error has occurred at address match detection</description>
                                    <value>#1</value>
                                </enumeratedValue>
                            </enumeratedValues>
                        </field>
                        <field>
                            <name>DFER</name>
                            <description>Data Compare Match Framing Error Flag</description>
                            <lsb>18</lsb>
                            <msb>18</msb>
                            <access>read-only</access>
                            <enumeratedValues>
                                <enumeratedValue>
                                    <name>0</name>
                                    <description>No framing error occurred at address match detection</description>
                                    <value>#0</value>
                                </enumeratedValue>
                                <enumeratedValue>
                                    <name>1</name>
                                    <description>A framing error has occurred at address match detection</description>
                                    <value>#1</value>
                                </enumeratedValue>
                            </enumeratedValues>
                        </field>
                        <field>
                            <name>ORER</name>
                            <description>Overrun Error Flag</description>
                            <lsb>24</lsb>
                            <msb>24</msb>
                            <access>read-only</access>
                            <enumeratedValues>
                                <enumeratedValue>
                                    <name>0</name>
                                    <description>No overrun error occurred</description>
                                    <value>#0</value>
                                </enumeratedValue>
                                <enumeratedValue>
                                    <name>1</name>
                                    <description>An overrun error has occurred</description>
                                    <value>#1</value>
                                </enumeratedValue>
                            </enumeratedValues>
                        </field>
                        <field>
                            <name>MFF</name>
                            <description>Mode Fault Error Flag</description>
                            <lsb>26</lsb>
                            <msb>26</msb>
                            <access>read-only</access>
                            <enumeratedValues>
                                <enumeratedValue>
                                    <name>0</name>
                                    <description>No mode fault error</description>
                                    <value>#0</value>
                                </enumeratedValue>
                                <enumeratedValue>
                                    <name>1</name>
                                    <description>Mode fault error</description>
                                    <value>#1</value>
                                </enumeratedValue>
                            </enumeratedValues>
                        </field>
                        <field>
                            <name>PER</name>
                            <description>Parity Error Flag</description>
                            <lsb>27</lsb>
                            <msb>27</msb>
                            <access>read-only</access>
                            <enumeratedValues>
                                <enumeratedValue>
                                    <name>0</name>
                                    <description>Non-FIFO selected (CCR3.FM = 0): No parity error occurred FIFO selected (CCR3.FM = 1): No parity error in all received data in receive-FIFO </description>
                                    <value>#0</value>
                                </enumeratedValue>
                                <enumeratedValue>
                                    <name>1</name>
                                    <description>Non-FIFO selected (CCR3.FM = 0): A parity error has occurred FIFO selected (CCR3.FM = 1): One or more parity errors occurred in received data in receive-FIFO </description>
                                    <value>#1</value>
                                </enumeratedValue>
                            </enumeratedValues>
                        </field>
                        <field>
                            <name>FER</name>
                            <description>Framing Error Flag</description>
                            <lsb>28</lsb>
                            <msb>28</msb>
                            <access>read-only</access>
                            <enumeratedValues>
                                <enumeratedValue>
                                    <name>0</name>
                                    <description>Non-FIFO selected (CCR3.FM = 0): No framing error occurred FIFO selected (CCR3.FM = 1): No framing error in all received data in receive-FIFO </description>
                                    <value>#0</value>
                                </enumeratedValue>
                                <enumeratedValue>
                                    <name>1</name>
                                    <description>Non-FIFO selected (CCR3.FM = 0): A framing error has occurred FIFO selected (CCR3.FM = 1): One or more framing errors occurred in received data in receive-FIFO </description>
                                    <value>#1</value>
                                </enumeratedValue>
                            </enumeratedValues>
                        </field>
                        <field>
                            <name>TDRE</name>
                            <description>Transmit Data Empty Flag</description>
                            <lsb>29</lsb>
                            <msb>29</msb>
                            <access>read-only</access>
                            <enumeratedValues>
                                <enumeratedValue>
                                    <name>0</name>
                                    <description>Non-FIFO selected (CCR3.FM = 0): Transmit data is in TDR register FIFO selected (CCR3.FM = 1): The quantity of transmit data written in transmit-FIFO exceeds the specified transmit triggering number. </description>
                                    <value>#0</value>
                                </enumeratedValue>
                                <enumeratedValue>
                                    <name>1</name>
                                    <description>Non-FIFO selected (CCR3.FM = 0): No transmit data is in TDR register FIFO selected (CCR3.FM = 1): The quantity of transmit data written in transmit-FIFO is equal to or less than the specified transmit triggering number. </description>
                                    <value>#1</value>
                                </enumeratedValue>
                            </enumeratedValues>
                        </field>
                        <field>
                            <name>TEND</name>
                            <description>Transmit End Flag</description>
                            <lsb>30</lsb>
                            <msb>30</msb>
                            <access>read-only</access>
                            <enumeratedValues>
                                <enumeratedValue>
                                    <name>0</name>
                                    <description>A character is being transmitted or standing by for transmission.</description>
                                    <value>#0</value>
                                </enumeratedValue>
                                <enumeratedValue>
                                    <name>1</name>
                                    <description>Character transfer has been completed, or sending Break Field.</description>
                                    <value>#1</value>
                                </enumeratedValue>
                            </enumeratedValues>
                        </field>
                        <field>
                            <name>RDRF</name>
                            <description>Receive Data Full Flag</description>
                            <lsb>31</lsb>
                            <msb>31</msb>
                            <access>read-only</access>
                            <enumeratedValues>
                                <enumeratedValue>
                                    <name>0</name>
                                    <description>Non-FIFO selected (CCR3.FM = 0): No received data is in RDR register FIFO selected (CCR3.FM = 1): The quantity of receive data written in receive-FIFO falls below the specified receive triggering number. </description>
                                    <value>#0</value>
                                </enumeratedValue>
                                <enumeratedValue>
                                    <name>1</name>
                                    <description>Non-FIFO selected (CCR3.FM = 0): Received data is in RDR register FIFO selected (CCR3.FM = 1): The quantity of receive data written in receive-FIFO is equal to or greater than the specified receive triggering number. </description>
                                    <value>#1</value>
                                </enumeratedValue>
                            </enumeratedValues>
                        </field>
                    </fields>
                </register>
                <register>
                    <name>ISR</name>
                    <description>Simple IIC Status Register</description>
                    <addressOffset>0x4C</addressOffset>
                    <size>32</size>
                    <access>read-only</access>
                    <resetValue>0x00000000</resetValue>
                    <resetMask>0xffffffff</resetMask>
                    <fields>
                        <field>
                            <name>IICACKR</name>
                            <description>ACK Reception Data Flag</description>
                            <lsb>0</lsb>
                            <msb>0</msb>
                            <access>read-only</access>
                            <enumeratedValues>
                                <enumeratedValue>
                                    <name>0</name>
                                    <description>ACK received</description>
                                    <value>#0</value>
                                </enumeratedValue>
                                <enumeratedValue>
                                    <name>1</name>
                                    <description>NACK received</description>
                                    <value>#1</value>
                                </enumeratedValue>
                            </enumeratedValues>
                        </field>
                        <field>
                            <name>IICSTIF</name>
                            <description>Issuing of Start, Restart, or Stop Condition Completed Flag</description>
                            <lsb>3</lsb>
                            <msb>3</msb>
                            <access>read-only</access>
                            <enumeratedValues>
                                <enumeratedValue>
                                    <name>0</name>
                                    <description>There are no requests for generating conditions or a condition is being generated.</description>
                                    <value>#0</value>
                                </enumeratedValue>
                                <enumeratedValue>
                                    <name>1</name>
                                    <description>A start, restart, or stop condition is completely generated.</description>
                                    <value>#1</value>
                                </enumeratedValue>
                            </enumeratedValues>
                        </field>
                    </fields>
                </register>
                <register>
                    <name>FRSR</name>
                    <description>FIFO Receive Status Register</description>
                    <addressOffset>0x50</addressOffset>
                    <size>32</size>
                    <access>read-only</access>
                    <resetValue>0x00000000</resetValue>
                    <resetMask>0xfffffffd</resetMask>
                    <fields>
                        <field>
                            <name>DR</name>
                            <description>Receive Data Ready Flag</description>
                            <lsb>0</lsb>
                            <msb>0</msb>
                            <access>read-only</access>
                            <enumeratedValues>
                                <enumeratedValue>
                                    <name>0</name>
                                    <description>Receiving is in progress, or no received data remains in the receive-FIFO after a successful reception (receive-FIFO is empty)</description>
                                    <value>#0</value>
                                </enumeratedValue>
                                <enumeratedValue>
                                    <name>1</name>
                                    <description>The following receive data is not received for a fixed period after storing data under the threshold in the receive-FIFO</description>
                                    <value>#1</value>
                                </enumeratedValue>
                            </enumeratedValues>
                        </field>
                        <field>
                            <name>R</name>
                            <description>Receive-FIFO Data Count</description>
                            <lsb>8</lsb>
                            <msb>13</msb>
                            <access>read-only</access>
                        </field>
                        <field>
                            <name>PNUM</name>
                            <description>Parity Error Count</description>
                            <lsb>16</lsb>
                            <msb>21</msb>
                            <access>read-only</access>
                        </field>
                        <field>
                            <name>FNUM</name>
                            <description>Framing Error Count</description>
                            <lsb>24</lsb>
                            <msb>29</msb>
                            <access>read-only</access>
                        </field>
                    </fields>
                </register>
                <register>
                    <name>FTSR</name>
                    <description>FIFO Transmit Status Register</description>
                    <addressOffset>0x54</addressOffset>
                    <size>32</size>
                    <access>read-only</access>
                    <resetValue>0x00000000</resetValue>
                    <resetMask>0xffffffff</resetMask>
                    <fields>
                        <field>
                            <name>T</name>
                            <description>Transmit-FIFO Data Count</description>
                            <lsb>0</lsb>
                            <msb>5</msb>
                            <access>read-only</access>
                        </field>
                    </fields>
                </register>
                <register>
                    <name>MSR</name>
                    <description>Manchester Status Register</description>
                    <addressOffset>0x58</addressOffset>
                    <size>32</size>
                    <access>read-only</access>
                    <resetValue>0x00000000</resetValue>
                    <resetMask>0xffffffff</resetMask>
                    <fields>
                        <field>
                            <name>PFER</name>
                            <description>Preface Error Flag</description>
                            <lsb>0</lsb>
                            <msb>0</msb>
                            <access>read-only</access>
                            <enumeratedValues>
                                <enumeratedValue>
                                    <name>0</name>
                                    <description>No preface error detected</description>
                                    <value>#0</value>
                                </enumeratedValue>
                                <enumeratedValue>
                                    <name>1</name>
                                    <description>Preface error detected</description>
                                    <value>#1</value>
                                </enumeratedValue>
                            </enumeratedValues>
                        </field>
                        <field>
                            <name>SYER</name>
                            <description>SYNC Error Flag</description>
                            <lsb>1</lsb>
                            <msb>1</msb>
                            <access>read-only</access>
                            <enumeratedValues>
                                <enumeratedValue>
                                    <name>0</name>
                                    <description>No receive SYNC error detected</description>
                                    <value>#0</value>
                                </enumeratedValue>
                                <enumeratedValue>
                                    <name>1</name>
                                    <description>Receive SYNC error detected</description>
                                    <value>#1</value>
                                </enumeratedValue>
                            </enumeratedValues>
                        </field>
                        <field>
                            <name>SBER</name>
                            <description>Start Bit Error Flag</description>
                            <lsb>2</lsb>
                            <msb>2</msb>
                            <access>read-only</access>
                            <enumeratedValues>
                                <enumeratedValue>
                                    <name>0</name>
                                    <description>No start bit error detected</description>
                                    <value>#0</value>
                                </enumeratedValue>
                                <enumeratedValue>
                                    <name>1</name>
                                    <description>Start bit error detected</description>
                                    <value>#1</value>
                                </enumeratedValue>
                            </enumeratedValues>
                        </field>
                        <field>
                            <name>MER</name>
                            <description>Manchester Error Flag</description>
                            <lsb>4</lsb>
                            <msb>4</msb>
                            <access>read-only</access>
                            <enumeratedValues>
                                <enumeratedValue>
                                    <name>0</name>
                                    <description>No Manchester error occurred</description>
                                    <value>#0</value>
                                </enumeratedValue>
                                <enumeratedValue>
                                    <name>1</name>
                                    <description>Manchester error has occurred</description>
                                    <value>#1</value>
                                </enumeratedValue>
                            </enumeratedValues>
                        </field>
                        <field>
                            <name>RSYNC</name>
                            <description>Receive SYNC Data Bit</description>
                            <lsb>6</lsb>
                            <msb>6</msb>
                            <access>read-only</access>
                            <enumeratedValues>
                                <enumeratedValue>
                                    <name>0</name>
                                    <description>The received start bit is DATA SYNC</description>
                                    <value>#0</value>
                                </enumeratedValue>
                                <enumeratedValue>
                                    <name>1</name>
                                    <description>The received start bit is COMMAND SYNC</description>
                                    <value>#1</value>
                                </enumeratedValue>
                            </enumeratedValues>
                        </field>
                    </fields>
                </register>
                <register>
                    <name>XSR0</name>
                    <description>Simple LIN Status Register 0</description>
                    <addressOffset>0x5C</addressOffset>
                    <size>32</size>
                    <access>read-only</access>
                    <resetValue>0x00000000</resetValue>
                    <resetMask>0xffffffff</resetMask>
                    <fields>
                        <field>
                            <name>SFSF</name>
                            <description>Start Frame Status Flag</description>
                            <lsb>0</lsb>
                            <msb>0</msb>
                            <access>read-only</access>
                            <enumeratedValues>
                                <enumeratedValue>
                                    <name>0</name>
                                    <description>Start Frame detection disabled or Start Frame detection complete</description>
                                    <value>#0</value>
                                </enumeratedValue>
                                <enumeratedValue>
                                    <name>1</name>
                                    <description>Before Start Frame detection or during detection</description>
                                    <value>#1</value>
                                </enumeratedValue>
                            </enumeratedValues>
                        </field>
                        <field>
                            <name>RXDSF</name>
                            <description>RXDn Input Status Flag</description>
                            <lsb>1</lsb>
                            <msb>1</msb>
                            <access>read-only</access>
                            <enumeratedValues>
                                <enumeratedValue>
                                    <name>0</name>
                                    <description>RXDn input to SCI is enabled</description>
                                    <value>#0</value>
                                </enumeratedValue>
                                <enumeratedValue>
                                    <name>1</name>
                                    <description>RXDn input to SCI is disabled</description>
                                    <value>#1</value>
                                </enumeratedValue>
                            </enumeratedValues>
                        </field>
                        <field>
                            <name>BFOF</name>
                            <description>Break Field Output Completion Flag</description>
                            <lsb>8</lsb>
                            <msb>8</msb>
                            <access>read-only</access>
                            <enumeratedValues>
                                <enumeratedValue>
                                    <name>0</name>
                                    <description>Break Field is being output or is not being output</description>
                                    <value>#0</value>
                                </enumeratedValue>
                                <enumeratedValue>
                                    <name>1</name>
                                    <description>Completed BF output</description>
                                    <value>#1</value>
                                </enumeratedValue>
                            </enumeratedValues>
                        </field>
                        <field>
                            <name>BCDF</name>
                            <description>Bus Conflict Detection Flag</description>
                            <lsb>9</lsb>
                            <msb>9</msb>
                            <access>read-only</access>
                            <enumeratedValues>
                                <enumeratedValue>
                                    <name>0</name>
                                    <description>No bus collision detected</description>
                                    <value>#0</value>
                                </enumeratedValue>
                                <enumeratedValue>
                                    <name>1</name>
                                    <description>Detected a bus collision</description>
                                    <value>#1</value>
                                </enumeratedValue>
                            </enumeratedValues>
                        </field>
                        <field>
                            <name>BFDF</name>
                            <description>Break Field Detection Flag</description>
                            <lsb>10</lsb>
                            <msb>10</msb>
                            <access>read-only</access>
                            <enumeratedValues>
                                <enumeratedValue>
                                    <name>0</name>
                                    <description>Break Field is not detected</description>
                                    <value>#0</value>
                                </enumeratedValue>
                                <enumeratedValue>
                                    <name>1</name>
                                    <description>Break Field is detected</description>
                                    <value>#1</value>
                                </enumeratedValue>
                            </enumeratedValues>
                        </field>
                        <field>
                            <name>CF0MF</name>
                            <description>Control Field 0 Compare Match Flag</description>
                            <lsb>11</lsb>
                            <msb>11</msb>
                            <access>read-only</access>
                            <enumeratedValues>
                                <enumeratedValue>
                                    <name>0</name>
                                    <description>Control Field 0 received data does not match the setting data</description>
                                    <value>#0</value>
                                </enumeratedValue>
                                <enumeratedValue>
                                    <name>1</name>
                                    <description>Control Field 0 received data matches the setting data</description>
                                    <value>#1</value>
                                </enumeratedValue>
                            </enumeratedValues>
                        </field>
                        <field>
                            <name>CF1MF</name>
                            <description>Control Field 1 Compare Match Flag</description>
                            <lsb>12</lsb>
                            <msb>12</msb>
                            <access>read-only</access>
                            <enumeratedValues>
                                <enumeratedValue>
                                    <name>0</name>
                                    <description>Control Field 1 received data does not match the setting data</description>
                                    <value>#0</value>
                                </enumeratedValue>
                                <enumeratedValue>
                                    <name>1</name>
                                    <description>Control Field 1 received data matches the setting data</description>
                                    <value>#1</value>
                                </enumeratedValue>
                            </enumeratedValues>
                        </field>
                        <field>
                            <name>PIBDF</name>
                            <description>Priority Interrupt Bit Detection Flag</description>
                            <lsb>13</lsb>
                            <msb>13</msb>
                            <access>read-only</access>
                            <enumeratedValues>
                                <enumeratedValue>
                                    <name>0</name>
                                    <description>Priority interrupt bit is not detected</description>
                                    <value>#0</value>
                                </enumeratedValue>
                                <enumeratedValue>
                                    <name>1</name>
                                    <description>Priority interrupt bit is detected</description>
                                    <value>#1</value>
                                </enumeratedValue>
                            </enumeratedValues>
                        </field>
                        <field>
                            <name>COF</name>
                            <description>Counter Overflow Flag</description>
                            <lsb>14</lsb>
                            <msb>14</msb>
                            <access>read-only</access>
                            <enumeratedValues>
                                <enumeratedValue>
                                    <name>0</name>
                                    <description>Break Field detection counter has not overflowed</description>
                                    <value>#0</value>
                                </enumeratedValue>
                                <enumeratedValue>
                                    <name>1</name>
                                    <description>Break Field detection counter overflowed</description>
                                    <value>#1</value>
                                </enumeratedValue>
                            </enumeratedValues>
                        </field>
                        <field>
                            <name>AEDF</name>
                            <description>Active Edge Detection Flag</description>
                            <lsb>15</lsb>
                            <msb>15</msb>
                            <access>read-only</access>
                            <enumeratedValues>
                                <enumeratedValue>
                                    <name>0</name>
                                    <description>No valid edge detected</description>
                                    <value>#0</value>
                                </enumeratedValue>
                                <enumeratedValue>
                                    <name>1</name>
                                    <description>Detected a valid edge</description>
                                    <value>#1</value>
                                </enumeratedValue>
                            </enumeratedValues>
                        </field>
                        <field>
                            <name>CF0RD</name>
                            <description>Control Field 0 received data</description>
                            <lsb>16</lsb>
                            <msb>23</msb>
                            <access>read-only</access>
                        </field>
                        <field>
                            <name>CF1RD</name>
                            <description>Control Field 1 received data</description>
                            <lsb>24</lsb>
                            <msb>31</msb>
                            <access>read-only</access>
                        </field>
                    </fields>
                </register>
                <register>
                    <name>XSR1</name>
                    <description>Simple LIN Status Register 1</description>
                    <addressOffset>0x60</addressOffset>
                    <size>32</size>
                    <access>read-only</access>
                    <resetValue>0x00000000</resetValue>
                    <resetMask>0xffffffff</resetMask>
                    <fields>
                        <field>
                            <name>TCNT</name>
                            <description>Timer Count Capture Value</description>
                            <lsb>0</lsb>
                            <msb>15</msb>
                            <access>read-only</access>
                        </field>
                    </fields>
                </register>
                <register>
                    <name>CFCLR</name>
                    <description>Common Flag Clear Register</description>
                    <addressOffset>0x68</addressOffset>
                    <size>32</size>
                    <access>write-only</access>
                    <resetValue>0x00000000</resetValue>
                    <resetMask>0xffffffff</resetMask>
                    <fields>
                        <field>
                            <name>ERSC</name>
                            <description>ERS Clear Bit</description>
                            <lsb>4</lsb>
                            <msb>4</msb>
                            <access>write-only</access>
                        </field>
                        <field>
                            <name>DCMFC</name>
                            <description>DCMF Clear Bit</description>
                            <lsb>16</lsb>
                            <msb>16</msb>
                            <access>write-only</access>
                        </field>
                        <field>
                            <name>DPERC</name>
                            <description>DPER Clear Bit</description>
                            <lsb>17</lsb>
                            <msb>17</msb>
                            <access>write-only</access>
                        </field>
                        <field>
                            <name>DFERC</name>
                            <description>DFER Clear Bit</description>
                            <lsb>18</lsb>
                            <msb>18</msb>
                            <access>write-only</access>
                        </field>
                        <field>
                            <name>ORERC</name>
                            <description>ORER Clear Bit</description>
                            <lsb>24</lsb>
                            <msb>24</msb>
                            <access>write-only</access>
                        </field>
                        <field>
                            <name>MFFC</name>
                            <description>MFF Clear Bit</description>
                            <lsb>26</lsb>
                            <msb>26</msb>
                            <access>write-only</access>
                        </field>
                        <field>
                            <name>PERC</name>
                            <description>PER Clear Bit</description>
                            <lsb>27</lsb>
                            <msb>27</msb>
                            <access>write-only</access>
                        </field>
                        <field>
                            <name>FERC</name>
                            <description>FER Clear Bit</description>
                            <lsb>28</lsb>
                            <msb>28</msb>
                            <access>write-only</access>
                        </field>
                        <field>
                            <name>TDREC</name>
                            <description>TDRE Clear Bit</description>
                            <lsb>29</lsb>
                            <msb>29</msb>
                            <access>write-only</access>
                        </field>
                        <field>
                            <name>RDRFC</name>
                            <description>RDRF Clear Bit</description>
                            <lsb>31</lsb>
                            <msb>31</msb>
                            <access>write-only</access>
                        </field>
                    </fields>
                </register>
                <register>
                    <name>ICFCLR</name>
                    <description>Simple IIC Flag Clear Register</description>
                    <addressOffset>0x6C</addressOffset>
                    <size>32</size>
                    <access>write-only</access>
                    <resetValue>0x00000000</resetValue>
                    <resetMask>0xffffffff</resetMask>
                    <fields>
                        <field>
                            <name>IICSTIFC</name>
                            <description>IICSTIF Clear Bit</description>
                            <lsb>3</lsb>
                            <msb>3</msb>
                            <access>write-only</access>
                        </field>
                    </fields>
                </register>
                <register>
                    <name>FFCLR</name>
                    <description>FIFO Flag Clear Register</description>
                    <addressOffset>0x70</addressOffset>
                    <size>32</size>
                    <access>write-only</access>
                    <resetValue>0x00000000</resetValue>
                    <resetMask>0xffffffff</resetMask>
                    <fields>
                        <field>
                            <name>DRC</name>
                            <description>DR Clear Bit</description>
                            <lsb>0</lsb>
                            <msb>0</msb>
                            <access>write-only</access>
                        </field>
                    </fields>
                </register>
                <register>
                    <name>MFCLR</name>
                    <description>Manchester Flag Clear Register</description>
                    <addressOffset>0x74</addressOffset>
                    <size>32</size>
                    <access>write-only</access>
                    <resetValue>0x00000000</resetValue>
                    <resetMask>0xffffffff</resetMask>
                    <fields>
                        <field>
                            <name>PFERC</name>
                            <description>PFER Clear Bit</description>
                            <lsb>0</lsb>
                            <msb>0</msb>
                            <access>write-only</access>
                        </field>
                        <field>
                            <name>SYERC</name>
                            <description>SYER Clear Bit</description>
                            <lsb>1</lsb>
                            <msb>1</msb>
                            <access>write-only</access>
                        </field>
                        <field>
                            <name>SBERC</name>
                            <description>SBER Clear Bit</description>
                            <lsb>2</lsb>
                            <msb>2</msb>
                            <access>write-only</access>
                        </field>
                        <field>
                            <name>MERC</name>
                            <description>MER Clear Bit</description>
                            <lsb>4</lsb>
                            <msb>4</msb>
                            <access>write-only</access>
                        </field>
                    </fields>
                </register>
                <register>
                    <name>XFCLR</name>
                    <description>Simple LIN Flag Clear Register</description>
                    <addressOffset>0x78</addressOffset>
                    <size>32</size>
                    <access>write-only</access>
                    <resetValue>0x00000000</resetValue>
                    <resetMask>0xffffffff</resetMask>
                    <fields>
                        <field>
                            <name>BFOC</name>
                            <description>BFOF Clear Bit</description>
                            <lsb>8</lsb>
                            <msb>8</msb>
                            <access>write-only</access>
                        </field>
                        <field>
                            <name>BCDC</name>
                            <description>BCDF Clear Bit</description>
                            <lsb>9</lsb>
                            <msb>9</msb>
                            <access>write-only</access>
                        </field>
                        <field>
                            <name>BFDC</name>
                            <description>BFDF Clear Bit</description>
                            <lsb>10</lsb>
                            <msb>10</msb>
                            <access>write-only</access>
                        </field>
                        <field>
                            <name>CF0MC</name>
                            <description>CF0MF Clear Bit</description>
                            <lsb>11</lsb>
                            <msb>11</msb>
                            <access>write-only</access>
                        </field>
                        <field>
                            <name>CF1MC</name>
                            <description>CF1MF Clear Bit</description>
                            <lsb>12</lsb>
                            <msb>12</msb>
                            <access>write-only</access>
                        </field>
                        <field>
                            <name>PIBDC</name>
                            <description>PIBDF Clear Bit</description>
                            <lsb>13</lsb>
                            <msb>13</msb>
                            <access>write-only</access>
                        </field>
                        <field>
                            <name>COFC</name>
                            <description>COFF Clear Bit</description>
                            <lsb>14</lsb>
                            <msb>14</msb>
                            <access>write-only</access>
                        </field>
                        <field>
                            <name>AEDC</name>
                            <description>AEDF Clear Bit</description>
                            <lsb>15</lsb>
                            <msb>15</msb>
                            <access>write-only</access>
                        </field>
                    </fields>
                </register>
            </registers>
        </peripheral>
        <peripheral derivedFrom="SCI0_B">
            <name>SCI1_B</name>
            <description>Serial Communication Interface 1</description>
            <baseAddress>0x40358100</baseAddress>
        </peripheral>
        <peripheral derivedFrom="SCI0_B">
            <name>SCI2_B</name>
            <description>Serial Communication Interface 2</description>
            <baseAddress>0x40358200</baseAddress>
        </peripheral>
        <peripheral derivedFrom="SCI0_B">
            <name>SCI3_B</name>
            <description>Serial Communication Interface 3</description>
            <baseAddress>0x40358300</baseAddress>
        </peripheral>
        <peripheral derivedFrom="SCI0_B">
            <name>SCI4_B</name>
            <description>Serial Communication Interface 4</description>
            <baseAddress>0x40358400</baseAddress>
        </peripheral>
        <peripheral derivedFrom="SCI0_B">
            <name>SCI9_B</name>
            <description>Serial Communication Interface 9</description>
            <baseAddress>0x40358900</baseAddress>
        </peripheral>
        <peripheral>
            <name>SPI0_B</name>
            <description>Serial Peripheral Interface 0</description>
            <baseAddress>0x4035C000</baseAddress>
            <addressBlock>
                <offset>0x00</offset>
                <size>52</size>
                <usage>registers</usage>
            </addressBlock>
            <addressBlock>
                <offset>0x40</offset>
                <size>8</size>
                <usage>registers</usage>
            </addressBlock>
            <addressBlock>
                <offset>0x50</offset>
                <size>4</size>
                <usage>registers</usage>
            </addressBlock>
            <addressBlock>
                <offset>0x58</offset>
                <size>12</size>
                <usage>registers</usage>
            </addressBlock>
            <addressBlock>
                <offset>0x68</offset>
                <size>8</size>
                <usage>registers</usage>
            </addressBlock>
            <registers>
                <register>
                    <name>SPDR</name>
                    <description>SPI Data Register</description>
                    <addressOffset>0x00</addressOffset>
                    <size>32</size>
                    <access>read-write</access>
                    <resetValue>0x00000000</resetValue>
                    <resetMask>0xffffffff</resetMask>
                    <fields>
                        <field>
                            <name>SPD</name>
                            <description>These bits are the interface with the buffers that hold data for transmission and reception by the SPI.</description>
                            <lsb>0</lsb>
                            <msb>31</msb>
                            <access>read-write</access>
                        </field>
                    </fields>
                </register>
                <register>
                    <name>SPDECR</name>
                    <description>SPI Delay Control Register</description>
                    <addressOffset>0x04</addressOffset>
                    <size>32</size>
                    <access>read-write</access>
                    <resetValue>0x00000000</resetValue>
                    <resetMask>0xffffffff</resetMask>
                    <fields>
                        <field>
                            <name>SCKDL</name>
                            <description>RSPCK Delay</description>
                            <lsb>0</lsb>
                            <msb>2</msb>
                            <access>read-write</access>
                            <enumeratedValues>
                                <enumeratedValue>
                                    <name>000</name>
                                    <description>1RSPCK</description>
                                    <value>#000</value>
                                </enumeratedValue>
                                <enumeratedValue>
                                    <name>001</name>
                                    <description>2RSPCK</description>
                                    <value>#001</value>
                                </enumeratedValue>
                                <enumeratedValue>
                                    <name>010</name>
                                    <description>3RSPCK</description>
                                    <value>#010</value>
                                </enumeratedValue>
                                <enumeratedValue>
                                    <name>011</name>
                                    <description>4RSPCK</description>
                                    <value>#011</value>
                                </enumeratedValue>
                                <enumeratedValue>
                                    <name>100</name>
                                    <description>5RSPCK</description>
                                    <value>#100</value>
                                </enumeratedValue>
                                <enumeratedValue>
                                    <name>101</name>
                                    <description>6RSPCK</description>
                                    <value>#101</value>
                                </enumeratedValue>
                                <enumeratedValue>
                                    <name>110</name>
                                    <description>7RSPCK</description>
                                    <value>#110</value>
                                </enumeratedValue>
                                <enumeratedValue>
                                    <name>111</name>
                                    <description>8RSPCK</description>
                                    <value>#111</value>
                                </enumeratedValue>
                            </enumeratedValues>
                        </field>
                        <field>
                            <name>SLNDL</name>
                            <description>SSL Negation Delay</description>
                            <lsb>8</lsb>
                            <msb>10</msb>
                            <access>read-write</access>
                            <enumeratedValues>
                                <enumeratedValue>
                                    <name>000</name>
                                    <description>1RSPCK</description>
                                    <value>#000</value>
                                </enumeratedValue>
                                <enumeratedValue>
                                    <name>001</name>
                                    <description>2RSPCK</description>
                                    <value>#001</value>
                                </enumeratedValue>
                                <enumeratedValue>
                                    <name>010</name>
                                    <description>3RSPCK</description>
                                    <value>#010</value>
                                </enumeratedValue>
                                <enumeratedValue>
                                    <name>011</name>
                                    <description>4RSPCK</description>
                                    <value>#011</value>
                                </enumeratedValue>
                                <enumeratedValue>
                                    <name>100</name>
                                    <description>5RSPCK</description>
                                    <value>#100</value>
                                </enumeratedValue>
                                <enumeratedValue>
                                    <name>101</name>
                                    <description>6RSPCK</description>
                                    <value>#101</value>
                                </enumeratedValue>
                                <enumeratedValue>
                                    <name>110</name>
                                    <description>7RSPCK</description>
                                    <value>#110</value>
                                </enumeratedValue>
                                <enumeratedValue>
                                    <name>111</name>
                                    <description>8RSPCK</description>
                                    <value>#111</value>
                                </enumeratedValue>
                            </enumeratedValues>
                        </field>
                        <field>
                            <name>SPNDL</name>
                            <description>SPI Next-Access Delay</description>
                            <lsb>16</lsb>
                            <msb>18</msb>
                            <access>read-write</access>
                            <enumeratedValues>
                                <enumeratedValue>
                                    <name>000</name>
                                    <description>1RSPCK + 5TCLK</description>
                                    <value>#000</value>
                                </enumeratedValue>
                                <enumeratedValue>
                                    <name>001</name>
                                    <description>2RSPCK + 5TCLK</description>
                                    <value>#001</value>
                                </enumeratedValue>
                                <enumeratedValue>
                                    <name>010</name>
                                    <description>3RSPCK + 5TCLK</description>
                                    <value>#010</value>
                                </enumeratedValue>
                                <enumeratedValue>
                                    <name>011</name>
                                    <description>4RSPCK + 5TCLK</description>
                                    <value>#011</value>
                                </enumeratedValue>
                                <enumeratedValue>
                                    <name>100</name>
                                    <description>5RSPCK + 5TCLK</description>
                                    <value>#100</value>
                                </enumeratedValue>
                                <enumeratedValue>
                                    <name>101</name>
                                    <description>6RSPCK + 5TCLK</description>
                                    <value>#101</value>
                                </enumeratedValue>
                                <enumeratedValue>
                                    <name>110</name>
                                    <description>7RSPCK + 5TCLK</description>
                                    <value>#110</value>
                                </enumeratedValue>
                                <enumeratedValue>
                                    <name>111</name>
                                    <description>8RSPCK + 5TCLK</description>
                                    <value>#111</value>
                                </enumeratedValue>
                            </enumeratedValues>
                        </field>
                    </fields>
                </register>
                <register>
                    <name>SPCR</name>
                    <description>SPI Control Register</description>
                    <addressOffset>0x08</addressOffset>
                    <size>32</size>
                    <access>read-write</access>
                    <resetValue>0x00000000</resetValue>
                    <resetMask>0xffffffff</resetMask>
                    <fields>
                        <field>
                            <name>SPE</name>
                            <description>SPI Function Enable</description>
                            <lsb>0</lsb>
                            <msb>0</msb>
                            <access>read-write</access>
                            <enumeratedValues>
                                <enumeratedValue>
                                    <name>0</name>
                                    <description>SPI function is disabled.</description>
                                    <value>#0</value>
                                </enumeratedValue>
                                <enumeratedValue>
                                    <name>1</name>
                                    <description>SPI function is enabled.</description>
                                    <value>#1</value>
                                </enumeratedValue>
                            </enumeratedValues>
                        </field>
                        <field>
                            <name>SPPE</name>
                            <description>Parity Enable</description>
                            <lsb>8</lsb>
                            <msb>8</msb>
                            <access>read-write</access>
                            <enumeratedValues>
                                <enumeratedValue>
                                    <name>0</name>
                                    <description>A parity bit is not added to transmit data. Received-data parity check is not performed. </description>
                                    <value>#0</value>
                                </enumeratedValue>
                                <enumeratedValue>
                                    <name>1</name>
                                    <description>A parity bit is added to transmit data. Received-data parity check is performed. </description>
                                    <value>#1</value>
                                </enumeratedValue>
                            </enumeratedValues>
                        </field>
                        <field>
                            <name>SPOE</name>
                            <description>Parity Mode</description>
                            <lsb>9</lsb>
                            <msb>9</msb>
                            <access>read-write</access>
                            <enumeratedValues>
                                <enumeratedValue>
                                    <name>0</name>
                                    <description>Even parity is used for transmission and reception.</description>
                                    <value>#0</value>
                                </enumeratedValue>
                                <enumeratedValue>
                                    <name>1</name>
                                    <description>Odd parity is used for transmission and reception.</description>
                                    <value>#1</value>
                                </enumeratedValue>
                            </enumeratedValues>
                        </field>
                        <field>
                            <name>PTE</name>
                            <description>Parity Self-Diagnosis Enable</description>
                            <lsb>11</lsb>
                            <msb>11</msb>
                            <access>read-write</access>
                            <enumeratedValues>
                                <enumeratedValue>
                                    <name>0</name>
                                    <description>Parity circuit self-diagnosis function is disabled.</description>
                                    <value>#0</value>
                                </enumeratedValue>
                                <enumeratedValue>
                                    <name>1</name>
                                    <description>Parity circuit self-diagnosis function is enabled.</description>
                                    <value>#1</value>
                                </enumeratedValue>
                            </enumeratedValues>
                        </field>
                        <field>
                            <name>SCKASE</name>
                            <description>RSPCK Auto-Stop Function Enable</description>
                            <lsb>12</lsb>
                            <msb>12</msb>
                            <access>read-write</access>
                            <enumeratedValues>
                                <enumeratedValue>
                                    <name>0</name>
                                    <description>RSPCK auto-stop function is disabled.</description>
                                    <value>#0</value>
                                </enumeratedValue>
                                <enumeratedValue>
                                    <name>1</name>
                                    <description>RSPCK auto-stop function is enabled.</description>
                                    <value>#1</value>
                                </enumeratedValue>
                            </enumeratedValues>
                        </field>
                        <field>
                            <name>BFDS</name>
                            <description>Between Burst Transfer Frames Delay Select</description>
                            <lsb>13</lsb>
                            <msb>13</msb>
                            <access>read-write</access>
                            <enumeratedValues>
                                <enumeratedValue>
                                    <name>0</name>
                                    <description>Delay (RSPCK delay, SSL negation delay and next-access delay) between frames is inserted in burst transfer</description>
                                    <value>#0</value>
                                </enumeratedValue>
                                <enumeratedValue>
                                    <name>1</name>
                                    <description>Delay between frames is not inserted in burst transfer.</description>
                                    <value>#1</value>
                                </enumeratedValue>
                            </enumeratedValues>
                        </field>
                        <field>
                            <name>MODFEN</name>
                            <description>Mode Fault Error Detection Enable</description>
                            <lsb>14</lsb>
                            <msb>14</msb>
                            <access>read-write</access>
                            <enumeratedValues>
                                <enumeratedValue>
                                    <name>0</name>
                                    <description>Mode fault error detection is disabled.</description>
                                    <value>#0</value>
                                </enumeratedValue>
                                <enumeratedValue>
                                    <name>1</name>
                                    <description>Mode fault error detection is enabled.</description>
                                    <value>#1</value>
                                </enumeratedValue>
                            </enumeratedValues>
                        </field>
                        <field>
                            <name>SPEIE</name>
                            <description>SPI Error Interrupt Enable</description>
                            <lsb>16</lsb>
                            <msb>16</msb>
                            <access>read-write</access>
                            <enumeratedValues>
                                <enumeratedValue>
                                    <name>0</name>
                                    <description>SPI error interrupt request is disabled.</description>
                                    <value>#0</value>
                                </enumeratedValue>
                                <enumeratedValue>
                                    <name>1</name>
                                    <description>SPI error interrupt request is enabled.</description>
                                    <value>#1</value>
                                </enumeratedValue>
                            </enumeratedValues>
                        </field>
                        <field>
                            <name>SPRIE</name>
                            <description>SPI Receive Buffer Full Interrupt Enable</description>
                            <lsb>17</lsb>
                            <msb>17</msb>
                            <access>read-write</access>
                            <enumeratedValues>
                                <enumeratedValue>
                                    <name>0</name>
                                    <description>SPI receive buffer full interrupt request is disabled.</description>
                                    <value>#0</value>
                                </enumeratedValue>
                                <enumeratedValue>
                                    <name>1</name>
                                    <description>SPI receive buffer full interrupt request is enabled.</description>
                                    <value>#1</value>
                                </enumeratedValue>
                            </enumeratedValues>
                        </field>
                        <field>
                            <name>SPIIE</name>
                            <description>SPI Idle Interrupt Enable</description>
                            <lsb>18</lsb>
                            <msb>18</msb>
                            <access>read-write</access>
                            <enumeratedValues>
                                <enumeratedValue>
                                    <name>0</name>
                                    <description>Idle interrupt request is disabled.</description>
                                    <value>#0</value>
                                </enumeratedValue>
                                <enumeratedValue>
                                    <name>1</name>
                                    <description>Idle interrupt request is enabled.</description>
                                    <value>#1</value>
                                </enumeratedValue>
                            </enumeratedValues>
                        </field>
                        <field>
                            <name>SPDRES</name>
                            <description>SPI receive data ready error select</description>
                            <lsb>19</lsb>
                            <msb>19</msb>
                            <access>read-write</access>
                            <enumeratedValues>
                                <enumeratedValue>
                                    <name>0</name>
                                    <description>Receive data full interrupt</description>
                                    <value>#0</value>
                                </enumeratedValue>
                                <enumeratedValue>
                                    <name>1</name>
                                    <description>Error interrupt</description>
                                    <value>#1</value>
                                </enumeratedValue>
                            </enumeratedValues>
                        </field>
                        <field>
                            <name>SPTIE</name>
                            <description>SPI Transmit Buffer Empty Interrupt Enable</description>
                            <lsb>20</lsb>
                            <msb>20</msb>
                            <access>read-write</access>
                            <enumeratedValues>
                                <enumeratedValue>
                                    <name>0</name>
                                    <description>SPI transmit buffer empty interrupt request is disabled.</description>
                                    <value>#0</value>
                                </enumeratedValue>
                                <enumeratedValue>
                                    <name>1</name>
                                    <description>SPI transmit buffer empty interrupt request is enabled.</description>
                                    <value>#1</value>
                                </enumeratedValue>
                            </enumeratedValues>
                        </field>
                        <field>
                            <name>CENDIE</name>
                            <description>SPI Communication End Interrupt Enable</description>
                            <lsb>21</lsb>
                            <msb>21</msb>
                            <access>read-write</access>
                            <enumeratedValues>
                                <enumeratedValue>
                                    <name>0</name>
                                    <description>Communication end interrupt request is disabled.</description>
                                    <value>#0</value>
                                </enumeratedValue>
                                <enumeratedValue>
                                    <name>1</name>
                                    <description>Communication end interrupt request is enabled.</description>
                                    <value>#1</value>
                                </enumeratedValue>
                            </enumeratedValues>
                        </field>
                        <field>
                            <name>SPMS</name>
                            <description>SPI Mode Select</description>
                            <lsb>24</lsb>
                            <msb>24</msb>
                            <access>read-write</access>
                            <enumeratedValues>
                                <enumeratedValue>
                                    <name>0</name>
                                    <description>SPI operation (4-wire)</description>
                                    <value>#0</value>
                                </enumeratedValue>
                                <enumeratedValue>
                                    <name>1</name>
                                    <description>Clock synchronous operation (3-wire)</description>
                                    <value>#1</value>
                                </enumeratedValue>
                            </enumeratedValues>
                        </field>
                        <field>
                            <name>SPFRF</name>
                            <description>SPI Frame Format Select</description>
                            <lsb>25</lsb>
                            <msb>25</msb>
                            <access>read-write</access>
                            <enumeratedValues>
                                <enumeratedValue>
                                    <name>0</name>
                                    <description>Motorola-SPI</description>
                                    <value>#0</value>
                                </enumeratedValue>
                                <enumeratedValue>
                                    <name>1</name>
                                    <description>TI-SSP</description>
                                    <value>#1</value>
                                </enumeratedValue>
                            </enumeratedValues>
                        </field>
                        <field>
                            <name>TXMD</name>
                            <description>Communication Mode Select</description>
                            <lsb>28</lsb>
                            <msb>29</msb>
                            <access>read-write</access>
                            <enumeratedValues>
                                <enumeratedValue>
                                    <name>00</name>
                                    <description>Transmit-Receive</description>
                                    <value>#00</value>
                                </enumeratedValue>
                                <enumeratedValue>
                                    <name>01</name>
                                    <description>Transmit only</description>
                                    <value>#01</value>
                                </enumeratedValue>
                                <enumeratedValue>
                                    <name>Others</name>
                                    <description>Receive only</description>
                                    <isDefault>true</isDefault>
                                </enumeratedValue>
                            </enumeratedValues>
                        </field>
                        <field>
                            <name>MSTR</name>
                            <description>SPI Master/Slave Mode Select</description>
                            <lsb>30</lsb>
                            <msb>30</msb>
                            <access>read-write</access>
                            <enumeratedValues>
                                <enumeratedValue>
                                    <name>0</name>
                                    <description>Slave mode</description>
                                    <value>#0</value>
                                </enumeratedValue>
                                <enumeratedValue>
                                    <name>1</name>
                                    <description>Master mode</description>
                                    <value>#1</value>
                                </enumeratedValue>
                            </enumeratedValues>
                        </field>
                        <field>
                            <name>BPEN</name>
                            <description>Synchronization Circuit Bypass Enable</description>
                            <lsb>31</lsb>
                            <msb>31</msb>
                            <access>read-write</access>
                            <enumeratedValues>
                                <enumeratedValue>
                                    <name>0</name>
                                    <description>Non-Bypass</description>
                                    <value>#0</value>
                                </enumeratedValue>
                                <enumeratedValue>
                                    <name>1</name>
                                    <description>Bypass</description>
                                    <value>#1</value>
                                </enumeratedValue>
                            </enumeratedValues>
                        </field>
                    </fields>
                </register>
                <register>
                    <name>SPCR2</name>
                    <description>SPI Control Register 2</description>
                    <addressOffset>0x0C</addressOffset>
                    <size>32</size>
                    <access>read-write</access>
                    <resetValue>0x00000000</resetValue>
                    <resetMask>0xffffffff</resetMask>
                    <fields>
                        <field>
                            <name>RMFM</name>
                            <description>Frame processing count setting in Master Receive only</description>
                            <lsb>0</lsb>
                            <msb>4</msb>
                            <access>read-write</access>
                        </field>
                        <field>
                            <name>RMEDTG</name>
                            <description>End Trigger in Master Receive only</description>
                            <lsb>6</lsb>
                            <msb>6</msb>
                            <access>write-only</access>
                            <enumeratedValues>
                                <enumeratedValue>
                                    <name>1</name>
                                    <description>Receive End (Writable only when Master Receive only) Reading value is always 0 </description>
                                    <value>#1</value>
                                </enumeratedValue>
                            </enumeratedValues>
                        </field>
                        <field>
                            <name>RMSTTG</name>
                            <description>Start Trigger in Master Receive only</description>
                            <lsb>7</lsb>
                            <msb>7</msb>
                            <access>write-only</access>
                            <enumeratedValues>
                                <enumeratedValue>
                                    <name>1</name>
                                    <description>Receive Start (Writable only when Master Receive only)  Reading value is always 0</description>
                                    <value>#1</value>
                                </enumeratedValue>
                            </enumeratedValues>
                        </field>
                        <field>
                            <name>SPDRC</name>
                            <description>SPI received data ready detect adjustment</description>
                            <lsb>8</lsb>
                            <msb>15</msb>
                            <access>read-write</access>
                        </field>
                        <field>
                            <name>SPLP</name>
                            <description>SPI Loopback</description>
                            <lsb>16</lsb>
                            <msb>16</msb>
                            <access>read-write</access>
                            <enumeratedValues>
                                <enumeratedValue>
                                    <name>0</name>
                                    <description>Normal mode</description>
                                    <value>#0</value>
                                </enumeratedValue>
                                <enumeratedValue>
                                    <name>1</name>
                                    <description>Loopback mode (inverted transmit data = receive data)</description>
                                    <value>#1</value>
                                </enumeratedValue>
                            </enumeratedValues>
                        </field>
                        <field>
                            <name>SPLP2</name>
                            <description>SPI Loopback 2</description>
                            <lsb>17</lsb>
                            <msb>17</msb>
                            <access>read-write</access>
                            <enumeratedValues>
                                <enumeratedValue>
                                    <name>0</name>
                                    <description>Normal mode</description>
                                    <value>#0</value>
                                </enumeratedValue>
                                <enumeratedValue>
                                    <name>1</name>
                                    <description>Loopback mode (transmit data = receive data)</description>
                                    <value>#1</value>
                                </enumeratedValue>
                            </enumeratedValues>
                        </field>
                        <field>
                            <name>MOIFV</name>
                            <description>MOSI Idle Fixed Value</description>
                            <lsb>20</lsb>
                            <msb>20</msb>
                            <access>read-write</access>
                            <enumeratedValues>
                                <enumeratedValue>
                                    <name>0</name>
                                    <description>The fixed value of MOSI idle = 0.</description>
                                    <value>#0</value>
                                </enumeratedValue>
                                <enumeratedValue>
                                    <name>1</name>
                                    <description>The fixed value of MOSI idle = 1.</description>
                                    <value>#1</value>
                                </enumeratedValue>
                            </enumeratedValues>
                        </field>
                        <field>
                            <name>MOIFE</name>
                            <description>MOSI Idle Fixed Value Enable</description>
                            <lsb>21</lsb>
                            <msb>21</msb>
                            <access>read-write</access>
                            <enumeratedValues>
                                <enumeratedValue>
                                    <name>0</name>
                                    <description>The MOSI output value is the last data of previous transfer.</description>
                                    <value>#0</value>
                                </enumeratedValue>
                                <enumeratedValue>
                                    <name>1</name>
                                    <description>The MOSI output value is the set MOIFV bit value.</description>
                                    <value>#1</value>
                                </enumeratedValue>
                            </enumeratedValues>
                        </field>
                    </fields>
                </register>
                <register>
                    <name>SPCR3</name>
                    <description>SPI Control Register 3</description>
                    <addressOffset>0x10</addressOffset>
                    <size>32</size>
                    <access>read-write</access>
                    <resetValue>0x0000ff00</resetValue>
                    <resetMask>0xffffffff</resetMask>
                    <fields>
                        <field>
                            <name>SSL0P</name>
                            <description>SSL0 Signal Polarity</description>
                            <lsb>0</lsb>
                            <msb>0</msb>
                            <access>read-write</access>
                            <enumeratedValues>
                                <enumeratedValue>
                                    <name>0</name>
                                    <description>The SSL0 signal is active low.</description>
                                    <value>#0</value>
                                </enumeratedValue>
                                <enumeratedValue>
                                    <name>1</name>
                                    <description>The SSL0 signal is active high.</description>
                                    <value>#1</value>
                                </enumeratedValue>
                            </enumeratedValues>
                        </field>
                        <field>
                            <name>SSL1P</name>
                            <description>SSL1 Signal Polarity</description>
                            <lsb>1</lsb>
                            <msb>1</msb>
                            <access>read-write</access>
                            <enumeratedValues>
                                <enumeratedValue>
                                    <name>0</name>
                                    <description>The SSL1 signal is active low.</description>
                                    <value>#0</value>
                                </enumeratedValue>
                                <enumeratedValue>
                                    <name>1</name>
                                    <description>The SSL1 signal is active high.</description>
                                    <value>#1</value>
                                </enumeratedValue>
                            </enumeratedValues>
                        </field>
                        <field>
                            <name>SSL2P</name>
                            <description>SSL2 Signal Polarity</description>
                            <lsb>2</lsb>
                            <msb>2</msb>
                            <access>read-write</access>
                            <enumeratedValues>
                                <enumeratedValue>
                                    <name>0</name>
                                    <description>The SSL2 signal is active low.</description>
                                    <value>#0</value>
                                </enumeratedValue>
                                <enumeratedValue>
                                    <name>1</name>
                                    <description>The SSL2 signal is active high.</description>
                                    <value>#1</value>
                                </enumeratedValue>
                            </enumeratedValues>
                        </field>
                        <field>
                            <name>SSL3P</name>
                            <description>SSL3 Signal Polarity</description>
                            <lsb>3</lsb>
                            <msb>3</msb>
                            <access>read-write</access>
                            <enumeratedValues>
                                <enumeratedValue>
                                    <name>0</name>
                                    <description>The SSL3 signal is active low.</description>
                                    <value>#0</value>
                                </enumeratedValue>
                                <enumeratedValue>
                                    <name>1</name>
                                    <description>The SSL3 signal is active high.</description>
                                    <value>#1</value>
                                </enumeratedValue>
                            </enumeratedValues>
                        </field>
                        <field>
                            <name>SPBR</name>
                            <description>SPI Bit Rate</description>
                            <lsb>8</lsb>
                            <msb>15</msb>
                            <access>read-write</access>
                        </field>
                        <field>
                            <name>SPSLN</name>
                            <description>SPI Sequence Length</description>
                            <lsb>24</lsb>
                            <msb>26</msb>
                            <access>read-write</access>
                            <enumeratedValues>
                                <enumeratedValue>
                                    <name>000</name>
                                    <description>Sequence Length is 1 (Referenced SPCMDn, n = 0→0→…)</description>
                                    <value>#000</value>
                                </enumeratedValue>
                                <enumeratedValue>
                                    <name>001</name>
                                    <description>Sequence Length is 2 (Referenced SPCMDn, n = 0→1→0→…)</description>
                                    <value>#001</value>
                                </enumeratedValue>
                                <enumeratedValue>
                                    <name>010</name>
                                    <description>Sequence Length is 3 (Referenced SPCMDn, n = 0→1→2→0→…)</description>
                                    <value>#010</value>
                                </enumeratedValue>
                                <enumeratedValue>
                                    <name>011</name>
                                    <description>Sequence Length is 4 (Referenced SPCMDn, n = 0→1→2→3→0→…)</description>
                                    <value>#011</value>
                                </enumeratedValue>
                                <enumeratedValue>
                                    <name>100</name>
                                    <description>Sequence Length is 5 (Referenced SPCMDn, n = 0→1→2→3→4→0→…)</description>
                                    <value>#100</value>
                                </enumeratedValue>
                                <enumeratedValue>
                                    <name>101</name>
                                    <description>Sequence Length is 6 (Referenced SPCMDn, n = 0→1→2→3→4→5→0→…)</description>
                                    <value>#101</value>
                                </enumeratedValue>
                                <enumeratedValue>
                                    <name>110</name>
                                    <description>Sequence Length is 7 (Referenced SPCMDn, n = 0→1→2→3→4→5→6→0→…)</description>
                                    <value>#110</value>
                                </enumeratedValue>
                                <enumeratedValue>
                                    <name>111</name>
                                    <description>Sequence Length is 8 (Referenced SPCMDn, n = 0→1→2→3→4→5→6→7→0→…)</description>
                                    <value>#111</value>
                                </enumeratedValue>
                            </enumeratedValues>
                        </field>
                    </fields>
                </register>
                <register>
                    <dim>8</dim>
                    <dimIncrement>0x04</dimIncrement>
                    <dimIndex>0-7</dimIndex>
                    <name>SPCMD%s</name>
                    <description>SPI Command Register</description>
                    <addressOffset>0x14</addressOffset>
                    <size>32</size>
                    <access>read-write</access>
                    <resetValue>0x00070000</resetValue>
                    <resetMask>0xffffffff</resetMask>
                    <fields>
                        <field>
                            <name>CPHA</name>
                            <description>RSPCK Phase</description>
                            <lsb>0</lsb>
                            <msb>0</msb>
                            <access>read-write</access>
                            <enumeratedValues>
                                <enumeratedValue>
                                    <name>0</name>
                                    <description>Data is sampled at an odd edge and changes at an even edge.</description>
                                    <value>#0</value>
                                </enumeratedValue>
                                <enumeratedValue>
                                    <name>1</name>
                                    <description>Data changes at an odd edge and is sampled at an even edge.</description>
                                    <value>#1</value>
                                </enumeratedValue>
                            </enumeratedValues>
                        </field>
                        <field>
                            <name>CPOL</name>
                            <description>RSPCK Polarity</description>
                            <lsb>1</lsb>
                            <msb>1</msb>
                            <access>read-write</access>
                            <enumeratedValues>
                                <enumeratedValue>
                                    <name>0</name>
                                    <description>RSPCK in idle state is 0.</description>
                                    <value>#0</value>
                                </enumeratedValue>
                                <enumeratedValue>
                                    <name>1</name>
                                    <description>RSPCK in idle state is 1.</description>
                                    <value>#1</value>
                                </enumeratedValue>
                            </enumeratedValues>
                        </field>
                        <field>
                            <name>BRDV</name>
                            <description>Bit Rate Division</description>
                            <lsb>2</lsb>
                            <msb>3</msb>
                            <access>read-write</access>
                            <enumeratedValues>
                                <enumeratedValue>
                                    <name>00</name>
                                    <description>Base bit rate</description>
                                    <value>#00</value>
                                </enumeratedValue>
                                <enumeratedValue>
                                    <name>01</name>
                                    <description>Base bit rate divided by 2</description>
                                    <value>#01</value>
                                </enumeratedValue>
                                <enumeratedValue>
                                    <name>10</name>
                                    <description>Base bit rate divided by 4</description>
                                    <value>#10</value>
                                </enumeratedValue>
                                <enumeratedValue>
                                    <name>11</name>
                                    <description>Base bit rate divided by 8</description>
                                    <value>#11</value>
                                </enumeratedValue>
                            </enumeratedValues>
                        </field>
                        <field>
                            <name>SSLKP</name>
                            <description>SSL Signal Level Hold</description>
                            <lsb>7</lsb>
                            <msb>7</msb>
                            <access>read-write</access>
                            <enumeratedValues>
                                <enumeratedValue>
                                    <name>0</name>
                                    <description>All SSL signals are negated at the end of transfer.</description>
                                    <value>#0</value>
                                </enumeratedValue>
                                <enumeratedValue>
                                    <name>1</name>
                                    <description>SSL signal level is held after the transfer ends until the next access starts.</description>
                                    <value>#1</value>
                                </enumeratedValue>
                            </enumeratedValues>
                        </field>
                        <field>
                            <name>LSBF</name>
                            <description>SPI LSB First</description>
                            <lsb>12</lsb>
                            <msb>12</msb>
                            <access>read-write</access>
                            <enumeratedValues>
                                <enumeratedValue>
                                    <name>0</name>
                                    <description>MSB first</description>
                                    <value>#0</value>
                                </enumeratedValue>
                                <enumeratedValue>
                                    <name>1</name>
                                    <description>LSB first</description>
                                    <value>#1</value>
                                </enumeratedValue>
                            </enumeratedValues>
                        </field>
                        <field>
                            <name>SPNDEN</name>
                            <description>SPI Next-Access Delay Enable</description>
                            <lsb>13</lsb>
                            <msb>13</msb>
                            <access>read-write</access>
                            <enumeratedValues>
                                <enumeratedValue>
                                    <name>0</name>
                                    <description>Next-access delay is 1RSPCK + 5TCLK</description>
                                    <value>#0</value>
                                </enumeratedValue>
                                <enumeratedValue>
                                    <name>1</name>
                                    <description>Next-access delay is the set value of the SPI next-access delay (SPDECR.SPNDL).</description>
                                    <value>#1</value>
                                </enumeratedValue>
                            </enumeratedValues>
                        </field>
                        <field>
                            <name>SLNDEN</name>
                            <description>SSL Negation Delay Setting Enable</description>
                            <lsb>14</lsb>
                            <msb>14</msb>
                            <access>read-write</access>
                            <enumeratedValues>
                                <enumeratedValue>
                                    <name>0</name>
                                    <description>[Master] SSL negation delay is 1RSPCK. [Slave in the TI-SSP] SSL negation delay is 1TCLK </description>
                                    <value>#0</value>
                                </enumeratedValue>
                                <enumeratedValue>
                                    <name>1</name>
                                    <description>SSL negation delay is the set value of the slave select negation delay (SPDECR.SLNDL).</description>
                                    <value>#1</value>
                                </enumeratedValue>
                            </enumeratedValues>
                        </field>
                        <field>
                            <name>SCKDEN</name>
                            <description>RSPCK Delay Setting Enable</description>
                            <lsb>15</lsb>
                            <msb>15</msb>
                            <access>read-write</access>
                            <enumeratedValues>
                                <enumeratedValue>
                                    <name>0</name>
                                    <description>RSPCK delay is 1 RSPCK.</description>
                                    <value>#0</value>
                                </enumeratedValue>
                                <enumeratedValue>
                                    <name>1</name>
                                    <description>RSPCK delay is the set value of the RSPCK delay (SPDECR.SCKDL).</description>
                                    <value>#1</value>
                                </enumeratedValue>
                            </enumeratedValues>
                        </field>
                        <field>
                            <name>SPB</name>
                            <description>SPI Data Length</description>
                            <lsb>16</lsb>
                            <msb>20</msb>
                            <access>read-write</access>
                        </field>
                        <field>
                            <name>SSLA</name>
                            <description>SSL Signal Assertion</description>
                            <lsb>24</lsb>
                            <msb>26</msb>
                            <access>read-write</access>
                            <enumeratedValues>
                                <enumeratedValue>
                                    <name>000</name>
                                    <description>SSL0</description>
                                    <value>#000</value>
                                </enumeratedValue>
                                <enumeratedValue>
                                    <name>001</name>
                                    <description>SSL1</description>
                                    <value>#001</value>
                                </enumeratedValue>
                                <enumeratedValue>
                                    <name>010</name>
                                    <description>SSL2</description>
                                    <value>#010</value>
                                </enumeratedValue>
                                <enumeratedValue>
                                    <name>011</name>
                                    <description>SSL3</description>
                                    <value>#011</value>
                                </enumeratedValue>
                                <enumeratedValue>
                                    <name>Others</name>
                                    <description>Setting prohibited</description>
                                    <isDefault>true</isDefault>
                                </enumeratedValue>
                            </enumeratedValues>
                        </field>
                    </fields>
                </register>
                <register>
                    <name>SPDCR</name>
                    <description>SPI Data Control Register</description>
                    <addressOffset>0x40</addressOffset>
                    <size>32</size>
                    <access>read-write</access>
                    <resetValue>0x00000000</resetValue>
                    <resetMask>0xffffffff</resetMask>
                    <fields>
                        <field>
                            <name>BYSW</name>
                            <description>Byte Swap Operating Mode Select</description>
                            <lsb>0</lsb>
                            <msb>0</msb>
                            <access>read-write</access>
                            <enumeratedValues>
                                <enumeratedValue>
                                    <name>0</name>
                                    <description>Byte Swap OFF</description>
                                    <value>#0</value>
                                </enumeratedValue>
                                <enumeratedValue>
                                    <name>1</name>
                                    <description>Byte Swap ON</description>
                                    <value>#1</value>
                                </enumeratedValue>
                            </enumeratedValues>
                        </field>
                        <field>
                            <name>SPRDTD</name>
                            <description>SPI Receive Data or Transmit Data Select</description>
                            <lsb>3</lsb>
                            <msb>3</msb>
                            <access>read-write</access>
                            <enumeratedValues>
                                <enumeratedValue>
                                    <name>0</name>
                                    <description>The SPDR reads the receive buffer.</description>
                                    <value>#0</value>
                                </enumeratedValue>
                                <enumeratedValue>
                                    <name>1</name>
                                    <description>The SPDR reads the transmit buffer</description>
                                    <value>#1</value>
                                </enumeratedValue>
                            </enumeratedValues>
                        </field>
                        <field>
                            <name>SINV</name>
                            <description>Serial data invert bit</description>
                            <lsb>4</lsb>
                            <msb>4</msb>
                            <access>read-write</access>
                            <enumeratedValues>
                                <enumeratedValue>
                                    <name>0</name>
                                    <description>Not invert serial data</description>
                                    <value>#0</value>
                                </enumeratedValue>
                                <enumeratedValue>
                                    <name>1</name>
                                    <description>Invert serial data.</description>
                                    <value>#1</value>
                                </enumeratedValue>
                            </enumeratedValues>
                        </field>
                        <field>
                            <name>SPFC</name>
                            <description>Frame Count</description>
                            <lsb>8</lsb>
                            <msb>9</msb>
                            <access>read-write</access>
                            <enumeratedValues>
                                <enumeratedValue>
                                    <name>00</name>
                                    <description>1 frame</description>
                                    <value>#00</value>
                                </enumeratedValue>
                                <enumeratedValue>
                                    <name>01</name>
                                    <description>2 frames</description>
                                    <value>#01</value>
                                </enumeratedValue>
                                <enumeratedValue>
                                    <name>10</name>
                                    <description>3 frames</description>
                                    <value>#10</value>
                                </enumeratedValue>
                                <enumeratedValue>
                                    <name>11</name>
                                    <description>4 frames</description>
                                    <value>#11</value>
                                </enumeratedValue>
                            </enumeratedValues>
                        </field>
                    </fields>
                </register>
                <register>
                    <name>SPDCR2</name>
                    <description>SPI Data Control Register 2</description>
                    <addressOffset>0x44</addressOffset>
                    <size>32</size>
                    <access>read-write</access>
                    <resetValue>0x00000000</resetValue>
                    <resetMask>0xffffffff</resetMask>
                    <fields>
                        <field>
                            <name>RTRG</name>
                            <description>Receive FIFO threshold setting</description>
                            <lsb>0</lsb>
                            <msb>1</msb>
                            <access>read-write</access>
                            <enumeratedValues>
                                <enumeratedValue>
                                    <name>00</name>
                                    <description>threshold 0</description>
                                    <value>#00</value>
                                </enumeratedValue>
                                <enumeratedValue>
                                    <name>01</name>
                                    <description>threshold 1</description>
                                    <value>#01</value>
                                </enumeratedValue>
                                <enumeratedValue>
                                    <name>10</name>
                                    <description>threshold 2</description>
                                    <value>#10</value>
                                </enumeratedValue>
                                <enumeratedValue>
                                    <name>11</name>
                                    <description>threshold 3</description>
                                    <value>#11</value>
                                </enumeratedValue>
                            </enumeratedValues>
                        </field>
                        <field>
                            <name>TTRG</name>
                            <description>Transmission FIFO threshold setting</description>
                            <lsb>8</lsb>
                            <msb>9</msb>
                            <access>read-write</access>
                            <enumeratedValues>
                                <enumeratedValue>
                                    <name>00</name>
                                    <description>threshold 0</description>
                                    <value>#00</value>
                                </enumeratedValue>
                                <enumeratedValue>
                                    <name>01</name>
                                    <description>threshold 1</description>
                                    <value>#01</value>
                                </enumeratedValue>
                                <enumeratedValue>
                                    <name>10</name>
                                    <description>threshold 2</description>
                                    <value>#10</value>
                                </enumeratedValue>
                                <enumeratedValue>
                                    <name>11</name>
                                    <description>threshold 3</description>
                                    <value>#11</value>
                                </enumeratedValue>
                            </enumeratedValues>
                        </field>
                    </fields>
                </register>
                <register>
                    <name>SPSR</name>
                    <description>SPI Status Register</description>
                    <addressOffset>0x50</addressOffset>
                    <size>32</size>
                    <access>read-only</access>
                    <resetValue>0x20000000</resetValue>
                    <resetMask>0xffffffff</resetMask>
                    <fields>
                        <field>
                            <name>SPCP</name>
                            <description>SPI Command Pointer</description>
                            <lsb>8</lsb>
                            <msb>10</msb>
                            <access>read-only</access>
                            <enumeratedValues>
                                <enumeratedValue>
                                    <name>000</name>
                                    <description>SPCMD0</description>
                                    <value>#000</value>
                                </enumeratedValue>
                                <enumeratedValue>
                                    <name>001</name>
                                    <description>SPCMD1</description>
                                    <value>#001</value>
                                </enumeratedValue>
                                <enumeratedValue>
                                    <name>010</name>
                                    <description>SPCMD2</description>
                                    <value>#010</value>
                                </enumeratedValue>
                                <enumeratedValue>
                                    <name>011</name>
                                    <description>SPCMD3</description>
                                    <value>#011</value>
                                </enumeratedValue>
                                <enumeratedValue>
                                    <name>100</name>
                                    <description>SPCMD4</description>
                                    <value>#100</value>
                                </enumeratedValue>
                                <enumeratedValue>
                                    <name>101</name>
                                    <description>SPCMD5</description>
                                    <value>#101</value>
                                </enumeratedValue>
                                <enumeratedValue>
                                    <name>110</name>
                                    <description>SPCMD6</description>
                                    <value>#110</value>
                                </enumeratedValue>
                                <enumeratedValue>
                                    <name>111</name>
                                    <description>SPCMD7</description>
                                    <value>#111</value>
                                </enumeratedValue>
                            </enumeratedValues>
                        </field>
                        <field>
                            <name>SPECM</name>
                            <description>SPI Error Command</description>
                            <lsb>12</lsb>
                            <msb>14</msb>
                            <access>read-only</access>
                            <enumeratedValues>
                                <enumeratedValue>
                                    <name>000</name>
                                    <description>SPCMD0</description>
                                    <value>#000</value>
                                </enumeratedValue>
                                <enumeratedValue>
                                    <name>001</name>
                                    <description>SPCMD1</description>
                                    <value>#001</value>
                                </enumeratedValue>
                                <enumeratedValue>
                                    <name>010</name>
                                    <description>SPCMD2</description>
                                    <value>#010</value>
                                </enumeratedValue>
                                <enumeratedValue>
                                    <name>011</name>
                                    <description>SPCMD3</description>
                                    <value>#011</value>
                                </enumeratedValue>
                                <enumeratedValue>
                                    <name>100</name>
                                    <description>SPCMD4</description>
                                    <value>#100</value>
                                </enumeratedValue>
                                <enumeratedValue>
                                    <name>101</name>
                                    <description>SPCMD5</description>
                                    <value>#101</value>
                                </enumeratedValue>
                                <enumeratedValue>
                                    <name>110</name>
                                    <description>SPCMD6</description>
                                    <value>#110</value>
                                </enumeratedValue>
                                <enumeratedValue>
                                    <name>111</name>
                                    <description>SPCMD7</description>
                                    <value>#111</value>
                                </enumeratedValue>
                            </enumeratedValues>
                        </field>
                        <field>
                            <name>SPDRF</name>
                            <description>SPI Receive Data Ready Flag</description>
                            <lsb>23</lsb>
                            <msb>23</msb>
                            <access>read-only</access>
                            <enumeratedValues>
                                <enumeratedValue>
                                    <name>0</name>
                                    <description>Receive data ready not detected</description>
                                    <value>#0</value>
                                </enumeratedValue>
                                <enumeratedValue>
                                    <name>1</name>
                                    <description>Receive data ready detected</description>
                                    <value>#1</value>
                                </enumeratedValue>
                            </enumeratedValues>
                        </field>
                        <field>
                            <name>OVRF</name>
                            <description>Overrun Error Flag</description>
                            <lsb>24</lsb>
                            <msb>24</msb>
                            <access>read-only</access>
                            <enumeratedValues>
                                <enumeratedValue>
                                    <name>0</name>
                                    <description>No overrun error is present.</description>
                                    <value>#0</value>
                                </enumeratedValue>
                                <enumeratedValue>
                                    <name>1</name>
                                    <description>An overrun error is present.</description>
                                    <value>#1</value>
                                </enumeratedValue>
                            </enumeratedValues>
                        </field>
                        <field>
                            <name>IDLNF</name>
                            <description>SPI Idle Flag</description>
                            <lsb>25</lsb>
                            <msb>25</msb>
                            <access>read-only</access>
                            <enumeratedValues>
                                <enumeratedValue>
                                    <name>0</name>
                                    <description>The SPI is in the idle state.</description>
                                    <value>#0</value>
                                </enumeratedValue>
                                <enumeratedValue>
                                    <name>1</name>
                                    <description>The SPI is in the transfer state.</description>
                                    <value>#1</value>
                                </enumeratedValue>
                            </enumeratedValues>
                        </field>
                        <field>
                            <name>MODF</name>
                            <description>Mode Fault Error Flag</description>
                            <lsb>26</lsb>
                            <msb>26</msb>
                            <access>read-only</access>
                            <enumeratedValues>
                                <enumeratedValue>
                                    <name>0</name>
                                    <description>Neither mode fault error nor underrun error is present.</description>
                                    <value>#0</value>
                                </enumeratedValue>
                                <enumeratedValue>
                                    <name>1</name>
                                    <description>A mode fault error or underrun error is present.</description>
                                    <value>#1</value>
                                </enumeratedValue>
                            </enumeratedValues>
                        </field>
                        <field>
                            <name>PERF</name>
                            <description>Parity Error Flag</description>
                            <lsb>27</lsb>
                            <msb>27</msb>
                            <access>read-only</access>
                            <enumeratedValues>
                                <enumeratedValue>
                                    <name>0</name>
                                    <description>No parity error is present.</description>
                                    <value>#0</value>
                                </enumeratedValue>
                                <enumeratedValue>
                                    <name>1</name>
                                    <description>A parity error is present.</description>
                                    <value>#1</value>
                                </enumeratedValue>
                            </enumeratedValues>
                        </field>
                        <field>
                            <name>UDRF</name>
                            <description>Underrun Error Flag</description>
                            <lsb>28</lsb>
                            <msb>28</msb>
                            <access>read-only</access>
                            <enumeratedValues>
                                <enumeratedValue>
                                    <name>0</name>
                                    <description>When MODF=0, neither mode fault error nor underrun error is present. When MODF=1, a mode fault error is present. </description>
                                    <value>#0</value>
                                </enumeratedValue>
                                <enumeratedValue>
                                    <name>1</name>
                                    <description>When MODF=0, neither mode fault error nor underrun error is present. When MODF=1, an underrun error is present. </description>
                                    <value>#1</value>
                                </enumeratedValue>
                            </enumeratedValues>
                        </field>
                        <field>
                            <name>SPTEF</name>
                            <description>SPI Transmit Buffer Empty Flag</description>
                            <lsb>29</lsb>
                            <msb>29</msb>
                            <access>read-only</access>
                            <enumeratedValues>
                                <enumeratedValue>
                                    <name>0</name>
                                    <description>The number of empty stages in the transmit FIFO ≤ the value set in SPDCR2.TTRG</description>
                                    <value>#0</value>
                                </enumeratedValue>
                                <enumeratedValue>
                                    <name>1</name>
                                    <description>The number of empty stages in the transmit FIFO &gt; the value set in SPDCR2.TTRG</description>
                                    <value>#1</value>
                                </enumeratedValue>
                            </enumeratedValues>
                        </field>
                        <field>
                            <name>CENDF</name>
                            <description>Communication End Flag</description>
                            <lsb>30</lsb>
                            <msb>30</msb>
                            <access>read-only</access>
                            <enumeratedValues>
                                <enumeratedValue>
                                    <name>0</name>
                                    <description>The SPI is not communicating or communicating.</description>
                                    <value>#0</value>
                                </enumeratedValue>
                                <enumeratedValue>
                                    <name>1</name>
                                    <description>The SPI communication completed.</description>
                                    <value>#1</value>
                                </enumeratedValue>
                            </enumeratedValues>
                        </field>
                        <field>
                            <name>SPRF</name>
                            <description>SPI Receive Buffer Full Flag</description>
                            <lsb>31</lsb>
                            <msb>31</msb>
                            <access>read-only</access>
                            <enumeratedValues>
                                <enumeratedValue>
                                    <name>0</name>
                                    <description>The number of data stored in the receive FIFO ≤ number of frames set by the SPDCR2.RTRG bit.</description>
                                    <value>#0</value>
                                </enumeratedValue>
                                <enumeratedValue>
                                    <name>1</name>
                                    <description>The number of data stored in the receive FIFO &gt; number of frames set by the SPDCR2.RTRG bit.</description>
                                    <value>#1</value>
                                </enumeratedValue>
                            </enumeratedValues>
                        </field>
                    </fields>
                </register>
                <register>
                    <name>SPTFSR</name>
                    <description>SPI Transfer FIFO Status Register</description>
                    <addressOffset>0x58</addressOffset>
                    <size>32</size>
                    <access>read-only</access>
                    <resetValue>0x00000000</resetValue>
                    <resetMask>0xffffffff</resetMask>
                    <fields>
                        <field>
                            <name>TFDN</name>
                            <description>Transmit FIFO data empty stage number</description>
                            <lsb>0</lsb>
                            <msb>2</msb>
                            <access>read-only</access>
                        </field>
                    </fields>
                </register>
                <register>
                    <name>SPRFSR</name>
                    <description>SPI Receive FIFO Status Register</description>
                    <addressOffset>0x5C</addressOffset>
                    <size>32</size>
                    <access>read-only</access>
                    <resetValue>0x00000004</resetValue>
                    <resetMask>0xffffffff</resetMask>
                    <fields>
                        <field>
                            <name>RFDN</name>
                            <description>Receive FIFO data store stage number</description>
                            <lsb>0</lsb>
                            <msb>2</msb>
                            <access>read-only</access>
                        </field>
                    </fields>
                </register>
                <register>
                    <name>SPPSR</name>
                    <description>SPI Polling Register</description>
                    <addressOffset>0x60</addressOffset>
                    <size>32</size>
                    <access>read-only</access>
                    <resetValue>0x00000000</resetValue>
                    <resetMask>0xffffffff</resetMask>
                    <fields>
                        <field>
                            <name>SPEPS</name>
                            <description>SPI Polling Status</description>
                            <lsb>0</lsb>
                            <msb>0</msb>
                            <access>read-only</access>
                            <enumeratedValues>
                                <enumeratedValue>
                                    <name>0</name>
                                    <description>SPCR.SPE is 0</description>
                                    <value>#0</value>
                                </enumeratedValue>
                                <enumeratedValue>
                                    <name>1</name>
                                    <description>SPCR.SPE is 1</description>
                                    <value>#1</value>
                                </enumeratedValue>
                            </enumeratedValues>
                        </field>
                    </fields>
                </register>
                <register>
                    <name>SPSRC</name>
                    <description>SPI Status Clear Register</description>
                    <addressOffset>0x68</addressOffset>
                    <size>32</size>
                    <access>write-only</access>
                    <resetValue>0x00000000</resetValue>
                    <resetMask>0xffffffff</resetMask>
                    <fields>
                        <field>
                            <name>SPDRFC</name>
                            <description>SPI Receive Data Ready Flag Clear</description>
                            <lsb>23</lsb>
                            <msb>23</msb>
                            <access>write-only</access>
                        </field>
                        <field>
                            <name>OVRFC</name>
                            <description>Overrun Error Flag Clear</description>
                            <lsb>24</lsb>
                            <msb>24</msb>
                            <access>write-only</access>
                        </field>
                        <field>
                            <name>MODFC</name>
                            <description>Mode Fault Error Flag Clear</description>
                            <lsb>26</lsb>
                            <msb>26</msb>
                            <access>write-only</access>
                        </field>
                        <field>
                            <name>PERFC</name>
                            <description>Parity Error Flag Clear</description>
                            <lsb>27</lsb>
                            <msb>27</msb>
                            <access>write-only</access>
                        </field>
                        <field>
                            <name>UDRFC</name>
                            <description>Underrun Error Flag Clear</description>
                            <lsb>28</lsb>
                            <msb>28</msb>
                            <access>write-only</access>
                        </field>
                        <field>
                            <name>SPTEFC</name>
                            <description>SPI Transmit Buffer Empty Flag Clear</description>
                            <lsb>29</lsb>
                            <msb>29</msb>
                            <access>write-only</access>
                        </field>
                        <field>
                            <name>CENDFC</name>
                            <description>Communication End Flag Clear</description>
                            <lsb>30</lsb>
                            <msb>30</msb>
                            <access>write-only</access>
                        </field>
                        <field>
                            <name>SPRFC</name>
                            <description>SPI Receive Buffer Full Flag Clear</description>
                            <lsb>31</lsb>
                            <msb>31</msb>
                            <access>write-only</access>
                        </field>
                    </fields>
                </register>
                <register>
                    <name>SPFCR</name>
                    <description>SPI FIFO Clear Register</description>
                    <addressOffset>0x6C</addressOffset>
                    <size>32</size>
                    <access>write-only</access>
                    <resetValue>0x00000000</resetValue>
                    <resetMask>0xffffffff</resetMask>
                    <fields>
                        <field>
                            <name>SPFRST</name>
                            <description>SPI FIFO clear</description>
                            <lsb>0</lsb>
                            <msb>0</msb>
                            <access>write-only</access>
                        </field>
                    </fields>
                </register>
            </registers>
        </peripheral>
        <peripheral derivedFrom="SPI0_B">
            <name>SPI1_B</name>
            <description>Serial Peripheral Interface 1</description>
            <baseAddress>0x4035C100</baseAddress>
        </peripheral>
        <peripheral>
            <name>ECCMB0</name>
            <description>Error Correction Circuit for MBRAMn</description>
            <baseAddress>0x4036F200</baseAddress>
            <addressBlock>
                <offset>0x00</offset>
                <size>6</size>
                <usage>registers</usage>
            </addressBlock>
            <addressBlock>
                <offset>0x0C</offset>
                <size>8</size>
                <usage>registers</usage>
            </addressBlock>
            <registers>
                <register>
                    <name>EC710CTL</name>
                    <description>ECC Control Register</description>
                    <addressOffset>0x00</addressOffset>
                    <size>32</size>
                    <access>read-write</access>
                    <resetValue>0x00000010</resetValue>
                    <resetMask>0xffffffff</resetMask>
                    <fields>
                        <field>
                            <name>ECEMF</name>
                            <description>ECC Error Message Flag</description>
                            <lsb>0</lsb>
                            <msb>0</msb>
                            <access>read-only</access>
                            <enumeratedValues>
                                <enumeratedValue>
                                    <name>0</name>
                                    <description>There is no bit error in present RAM output data</description>
                                    <value>#0</value>
                                </enumeratedValue>
                                <enumeratedValue>
                                    <name>1</name>
                                    <description>There is bit error in present RAM output data</description>
                                    <value>#1</value>
                                </enumeratedValue>
                            </enumeratedValues>
                        </field>
                        <field>
                            <name>ECER1F</name>
                            <description>ECC Error Detection and Correction Flag</description>
                            <lsb>1</lsb>
                            <msb>1</msb>
                            <access>read-only</access>
                            <enumeratedValues>
                                <enumeratedValue>
                                    <name>0</name>
                                    <description>After clearing this bit, 1-bit error correction has not occurred</description>
                                    <value>#0</value>
                                </enumeratedValue>
                                <enumeratedValue>
                                    <name>1</name>
                                    <description>1-bit error has occurred</description>
                                    <value>#1</value>
                                </enumeratedValue>
                            </enumeratedValues>
                        </field>
                        <field>
                            <name>ECER2F</name>
                            <description>2-bit ECC Error Detection Flag</description>
                            <lsb>2</lsb>
                            <msb>2</msb>
                            <access>read-only</access>
                            <enumeratedValues>
                                <enumeratedValue>
                                    <name>0</name>
                                    <description>After clearing this bit, 2-bit error has not occurred</description>
                                    <value>#0</value>
                                </enumeratedValue>
                                <enumeratedValue>
                                    <name>1</name>
                                    <description>2-bit error has occurred</description>
                                    <value>#1</value>
                                </enumeratedValue>
                            </enumeratedValues>
                        </field>
                        <field>
                            <name>EC1EDIC</name>
                            <description>ECC 1-bit Error Detection Interrupt Control</description>
                            <lsb>3</lsb>
                            <msb>3</msb>
                            <access>read-write</access>
                            <enumeratedValues>
                                <enumeratedValue>
                                    <name>0</name>
                                    <description>Disable 1-bit error detection interrupt request</description>
                                    <value>#0</value>
                                </enumeratedValue>
                                <enumeratedValue>
                                    <name>1</name>
                                    <description>Enable 1-bit error detection interrupt request</description>
                                    <value>#1</value>
                                </enumeratedValue>
                            </enumeratedValues>
                        </field>
                        <field>
                            <name>EC2EDIC</name>
                            <description>ECC 2-bit Error Detection Interrupt Control</description>
                            <lsb>4</lsb>
                            <msb>4</msb>
                            <access>read-write</access>
                            <enumeratedValues>
                                <enumeratedValue>
                                    <name>0</name>
                                    <description>Disable 2-bit error detection interrupt request</description>
                                    <value>#0</value>
                                </enumeratedValue>
                                <enumeratedValue>
                                    <name>1</name>
                                    <description>Enable 2-bit error detection interrupt request</description>
                                    <value>#1</value>
                                </enumeratedValue>
                            </enumeratedValues>
                        </field>
                        <field>
                            <name>EC1ECP</name>
                            <description>ECC 1-bit Error Correction Permission</description>
                            <lsb>5</lsb>
                            <msb>5</msb>
                            <access>read-write</access>
                            <enumeratedValues>
                                <enumeratedValue>
                                    <name>0</name>
                                    <description>At 1-bit error detection, the error correction is executed</description>
                                    <value>#0</value>
                                </enumeratedValue>
                                <enumeratedValue>
                                    <name>1</name>
                                    <description>At 1-bit error detection, the error correction is not executed</description>
                                    <value>#1</value>
                                </enumeratedValue>
                            </enumeratedValues>
                        </field>
                        <field>
                            <name>ECERVF</name>
                            <description>ECC Error Judgment Enable Flag</description>
                            <lsb>6</lsb>
                            <msb>6</msb>
                            <access>read-write</access>
                            <enumeratedValues>
                                <enumeratedValue>
                                    <name>0</name>
                                    <description>Error judgment disable</description>
                                    <value>#0</value>
                                </enumeratedValue>
                                <enumeratedValue>
                                    <name>1</name>
                                    <description>Error judgment enable</description>
                                    <value>#1</value>
                                </enumeratedValue>
                            </enumeratedValues>
                        </field>
                        <field>
                            <name>ECER1C</name>
                            <description>Accumulating ECC Error Detection and Correction Flag Clear</description>
                            <lsb>9</lsb>
                            <msb>9</msb>
                            <access>read-write</access>
                            <enumeratedValues>
                                <enumeratedValue>
                                    <name>0</name>
                                    <description>No effect</description>
                                    <value>#0</value>
                                </enumeratedValue>
                                <enumeratedValue>
                                    <name>1</name>
                                    <description>Clear accumulating ECC error detection and correction flag</description>
                                    <value>#1</value>
                                </enumeratedValue>
                            </enumeratedValues>
                        </field>
                        <field>
                            <name>ECER2C</name>
                            <description>2-bit ECC Error Detection Flag Clear</description>
                            <lsb>10</lsb>
                            <msb>10</msb>
                            <access>read-write</access>
                            <enumeratedValues>
                                <enumeratedValue>
                                    <name>0</name>
                                    <description>No effect</description>
                                    <value>#0</value>
                                </enumeratedValue>
                                <enumeratedValue>
                                    <name>1</name>
                                    <description>Clear 2-bit ECC error detection flag</description>
                                    <value>#1</value>
                                </enumeratedValue>
                            </enumeratedValues>
                        </field>
                        <field>
                            <name>ECOVFF</name>
                            <description>ECC Overflow Detection Flag</description>
                            <lsb>11</lsb>
                            <msb>11</msb>
                            <access>read-only</access>
                            <enumeratedValues>
                                <enumeratedValue>
                                    <name>0</name>
                                    <description>No effect</description>
                                    <value>#0</value>
                                </enumeratedValue>
                                <enumeratedValue>
                                    <name>1</name>
                                    <description>ECC overflow detection flag</description>
                                    <value>#1</value>
                                </enumeratedValue>
                            </enumeratedValues>
                        </field>
                        <field>
                            <name>EMCA</name>
                            <description>Access Control to ECC Mode Select bit</description>
                            <lsb>14</lsb>
                            <msb>15</msb>
                            <access>read-write</access>
                        </field>
                        <field>
                            <name>ECSEDF0</name>
                            <description>ECC Single bit Error Address Detection Flag</description>
                            <lsb>16</lsb>
                            <msb>16</msb>
                            <access>read-only</access>
                            <enumeratedValues>
                                <enumeratedValue>
                                    <name>0</name>
                                    <description>There is no bit error in EC710EAD0 after reset or clearing ECER1F bit</description>
                                    <value>#0</value>
                                </enumeratedValue>
                                <enumeratedValue>
                                    <name>1</name>
                                    <description>Address captured in EC710EAD0 shows that 1-bit error occurred and captured</description>
                                    <value>#1</value>
                                </enumeratedValue>
                            </enumeratedValues>
                        </field>
                        <field>
                            <name>ECDEDF0</name>
                            <description>ECC Dual Bit Error Address Detection Flag</description>
                            <lsb>17</lsb>
                            <msb>17</msb>
                            <access>read-only</access>
                            <enumeratedValues>
                                <enumeratedValue>
                                    <name>0</name>
                                    <description>There is no bit error in EC710EAD0 after reset or clearing ECER2F bit</description>
                                    <value>#0</value>
                                </enumeratedValue>
                                <enumeratedValue>
                                    <name>1</name>
                                    <description>Address captured in EC710EAD0 shows that 2-bit error occurred and captured</description>
                                    <value>#1</value>
                                </enumeratedValue>
                            </enumeratedValues>
                        </field>
                    </fields>
                </register>
                <register>
                    <name>EC710TMC</name>
                    <description>ECC Test Mode Control Register</description>
                    <addressOffset>0x04</addressOffset>
                    <size>16</size>
                    <access>read-write</access>
                    <resetValue>0x0000</resetValue>
                    <resetMask>0xffff</resetMask>
                    <fields>
                        <field>
                            <name>ECDCS</name>
                            <description>ECC Decode Input Select</description>
                            <lsb>1</lsb>
                            <msb>1</msb>
                            <access>read-write</access>
                            <enumeratedValues>
                                <enumeratedValue>
                                    <name>0</name>
                                    <description>Input lower 32 bits of RAM output data to data area of decode circuit</description>
                                    <value>#0</value>
                                </enumeratedValue>
                                <enumeratedValue>
                                    <name>1</name>
                                    <description>Input ECEDB31-0 in EC710TED register to data area of decode circuit</description>
                                    <value>#1</value>
                                </enumeratedValue>
                            </enumeratedValues>
                        </field>
                        <field>
                            <name>ECTMCE</name>
                            <description>ECC Test Mode Control Enable</description>
                            <lsb>7</lsb>
                            <msb>7</msb>
                            <access>read-write</access>
                            <enumeratedValues>
                                <enumeratedValue>
                                    <name>0</name>
                                    <description>The access to test mode register and bit is disabled</description>
                                    <value>#0</value>
                                </enumeratedValue>
                                <enumeratedValue>
                                    <name>1</name>
                                    <description>The access to test mode register and bit is enabled</description>
                                    <value>#1</value>
                                </enumeratedValue>
                            </enumeratedValues>
                        </field>
                        <field>
                            <name>ETMA</name>
                            <description>ECC Test Mode Bit Access Control</description>
                            <lsb>14</lsb>
                            <msb>15</msb>
                            <access>read-write</access>
                        </field>
                    </fields>
                </register>
                <register>
                    <name>EC710TED</name>
                    <description>ECC Test Substitute Data Register</description>
                    <addressOffset>0x0C</addressOffset>
                    <size>32</size>
                    <access>read-write</access>
                    <resetValue>0x00000000</resetValue>
                    <resetMask>0xffffffff</resetMask>
                    <fields>
                        <field>
                            <name>ECEDB</name>
                            <description>ECC Test Substitute Data</description>
                            <lsb>0</lsb>
                            <msb>31</msb>
                            <access>read-write</access>
                        </field>
                    </fields>
                </register>
                <register>
                    <name>EC710EAD0</name>
                    <description>ECC Error Address Register</description>
                    <addressOffset>0x10</addressOffset>
                    <size>32</size>
                    <access>read-only</access>
                    <resetValue>0x00000000</resetValue>
                    <resetMask>0xffffffff</resetMask>
                    <fields>
                        <field>
                            <name>ECEAD</name>
                            <description>ECC Error Address</description>
                            <lsb>0</lsb>
                            <msb>9</msb>
                            <access>read-only</access>
                        </field>
                    </fields>
                </register>
            </registers>
        </peripheral>
        <peripheral derivedFrom="ECCMB0">
            <name>ECCMB1</name>
            <description>Error Correction Circuit for MBRAMn</description>
            <baseAddress>0x4036F300</baseAddress>
        </peripheral>
        <peripheral>
            <name>CANFD0</name>
            <description>CANFD Module 0</description>
            <baseAddress>0x40380000</baseAddress>
            <addressBlock>
                <offset>0x00</offset>
                <size>16</size>
                <usage>registers</usage>
            </addressBlock>
            <addressBlock>
                <offset>0x14</offset>
                <size>34</size>
                <usage>registers</usage>
            </addressBlock>
            <addressBlock>
                <offset>0x38</offset>
                <size>2</size>
                <usage>registers</usage>
            </addressBlock>
            <addressBlock>
                <offset>0x3C</offset>
                <size>120</size>
                <usage>registers</usage>
            </addressBlock>
            <addressBlock>
                <offset>0xB8</offset>
                <size>4</size>
                <usage>registers</usage>
            </addressBlock>
            <addressBlock>
                <offset>0xC0</offset>
                <size>16</size>
                <usage>registers</usage>
            </addressBlock>
            <addressBlock>
                <offset>0xD8</offset>
                <size>4</size>
                <usage>registers</usage>
            </addressBlock>
            <addressBlock>
                <offset>0x100</offset>
                <size>20</size>
                <usage>registers</usage>
            </addressBlock>
            <addressBlock>
                <offset>0x120</offset>
                <size>268</size>
                <usage>registers</usage>
            </addressBlock>
            <addressBlock>
                <offset>0x280</offset>
                <size>256</size>
                <usage>registers</usage>
            </addressBlock>
            <addressBlock>
                <offset>0x520</offset>
                <size>604</size>
                <usage>registers</usage>
            </addressBlock>
            <addressBlock>
                <offset>0x920</offset>
                <size>680</size>
                <usage>registers</usage>
            </addressBlock>
            <addressBlock>
                <offset>0xD20</offset>
                <size>680</size>
                <usage>registers</usage>
            </addressBlock>
            <addressBlock>
                <offset>0x1124</offset>
                <size>676</size>
                <usage>registers</usage>
            </addressBlock>
            <addressBlock>
                <offset>0x1524</offset>
                <size>676</size>
                <usage>registers</usage>
            </addressBlock>
            <registers>
                <register>
                    <name>CFDC0NCFG</name>
                    <description>Nominal Bitrate Configuration Register</description>
                    <addressOffset>0x0000</addressOffset>
                    <size>32</size>
                    <access>read-write</access>
                    <resetValue>0x00000000</resetValue>
                    <resetMask>0xffffffff</resetMask>
                    <fields>
                        <field>
                            <name>NBRP</name>
                            <description>Channel Nominal Baud Rate Prescaler</description>
                            <lsb>0</lsb>
                            <msb>9</msb>
                            <access>read-write</access>
                        </field>
                        <field>
                            <name>NSJW</name>
                            <description>Resynchronization Jump Width</description>
                            <lsb>10</lsb>
                            <msb>16</msb>
                            <access>read-write</access>
                        </field>
                        <field>
                            <name>NTSEG1</name>
                            <description>Timing Segment 1</description>
                            <lsb>17</lsb>
                            <msb>24</msb>
                            <access>read-write</access>
                        </field>
                        <field>
                            <name>NTSEG2</name>
                            <description>Timing Segment 2</description>
                            <lsb>25</lsb>
                            <msb>31</msb>
                            <access>read-write</access>
                        </field>
                    </fields>
                </register>
                <register>
                    <name>CFDC0CTR</name>
                    <description>Control Register</description>
                    <addressOffset>0x0004</addressOffset>
                    <size>32</size>
                    <access>read-write</access>
                    <resetValue>0x00000005</resetValue>
                    <resetMask>0xffffffff</resetMask>
                    <fields>
                        <field>
                            <name>CHMDC</name>
                            <description>Channel Mode Control</description>
                            <lsb>0</lsb>
                            <msb>1</msb>
                            <access>read-write</access>
                            <enumeratedValues>
                                <enumeratedValue>
                                    <name>00</name>
                                    <description>Channel operation mode request</description>
                                    <value>#00</value>
                                </enumeratedValue>
                                <enumeratedValue>
                                    <name>01</name>
                                    <description>Channel reset request</description>
                                    <value>#01</value>
                                </enumeratedValue>
                                <enumeratedValue>
                                    <name>10</name>
                                    <description>Channel halt request</description>
                                    <value>#10</value>
                                </enumeratedValue>
                                <enumeratedValue>
                                    <name>11</name>
                                    <description>Keep current value</description>
                                    <value>#11</value>
                                </enumeratedValue>
                            </enumeratedValues>
                        </field>
                        <field>
                            <name>CSLPR</name>
                            <description>Channel Sleep Request</description>
                            <lsb>2</lsb>
                            <msb>2</msb>
                            <access>read-write</access>
                            <enumeratedValues>
                                <enumeratedValue>
                                    <name>0</name>
                                    <description>Channel sleep request disabled</description>
                                    <value>#0</value>
                                </enumeratedValue>
                                <enumeratedValue>
                                    <name>1</name>
                                    <description>Channel sleep request enabled</description>
                                    <value>#1</value>
                                </enumeratedValue>
                            </enumeratedValues>
                        </field>
                        <field>
                            <name>RTBO</name>
                            <description>Return from Bus-Off</description>
                            <lsb>3</lsb>
                            <msb>3</msb>
                            <access>read-write</access>
                            <enumeratedValues>
                                <enumeratedValue>
                                    <name>0</name>
                                    <description>Channel is not forced to return from bus-off</description>
                                    <value>#0</value>
                                </enumeratedValue>
                                <enumeratedValue>
                                    <name>1</name>
                                    <description>Channel is forced to return from bus-off</description>
                                    <value>#1</value>
                                </enumeratedValue>
                            </enumeratedValues>
                        </field>
                        <field>
                            <name>BEIE</name>
                            <description>Bus Error Interrupt Enable</description>
                            <lsb>8</lsb>
                            <msb>8</msb>
                            <access>read-write</access>
                            <enumeratedValues>
                                <enumeratedValue>
                                    <name>0</name>
                                    <description>Bus error interrupt disabled</description>
                                    <value>#0</value>
                                </enumeratedValue>
                                <enumeratedValue>
                                    <name>1</name>
                                    <description>Bus error interrupt enabled</description>
                                    <value>#1</value>
                                </enumeratedValue>
                            </enumeratedValues>
                        </field>
                        <field>
                            <name>EWIE</name>
                            <description>Error Warning Interrupt Enable</description>
                            <lsb>9</lsb>
                            <msb>9</msb>
                            <access>read-write</access>
                            <enumeratedValues>
                                <enumeratedValue>
                                    <name>0</name>
                                    <description>Error warning interrupt disabled</description>
                                    <value>#0</value>
                                </enumeratedValue>
                                <enumeratedValue>
                                    <name>1</name>
                                    <description>Error warning interrupt enabled</description>
                                    <value>#1</value>
                                </enumeratedValue>
                            </enumeratedValues>
                        </field>
                        <field>
                            <name>EPIE</name>
                            <description>Error Passive Interrupt Enable</description>
                            <lsb>10</lsb>
                            <msb>10</msb>
                            <access>read-write</access>
                            <enumeratedValues>
                                <enumeratedValue>
                                    <name>0</name>
                                    <description>Error passive interrupt disabled</description>
                                    <value>#0</value>
                                </enumeratedValue>
                                <enumeratedValue>
                                    <name>1</name>
                                    <description>Error passive interrupt enabled</description>
                                    <value>#1</value>
                                </enumeratedValue>
                            </enumeratedValues>
                        </field>
                        <field>
                            <name>BOEIE</name>
                            <description>Bus-Off Entry Interrupt Enable</description>
                            <lsb>11</lsb>
                            <msb>11</msb>
                            <access>read-write</access>
                            <enumeratedValues>
                                <enumeratedValue>
                                    <name>0</name>
                                    <description>Bus-off entry interrupt disabled</description>
                                    <value>#0</value>
                                </enumeratedValue>
                                <enumeratedValue>
                                    <name>1</name>
                                    <description>Bus-off entry interrupt enabled</description>
                                    <value>#1</value>
                                </enumeratedValue>
                            </enumeratedValues>
                        </field>
                        <field>
                            <name>BORIE</name>
                            <description>Bus-Off Recovery Interrupt Enable</description>
                            <lsb>12</lsb>
                            <msb>12</msb>
                            <access>read-write</access>
                            <enumeratedValues>
                                <enumeratedValue>
                                    <name>0</name>
                                    <description>Bus-off recovery interrupt disabled</description>
                                    <value>#0</value>
                                </enumeratedValue>
                                <enumeratedValue>
                                    <name>1</name>
                                    <description>Bus-off recovery interrupt enabled</description>
                                    <value>#1</value>
                                </enumeratedValue>
                            </enumeratedValues>
                        </field>
                        <field>
                            <name>OLIE</name>
                            <description>Overload Interrupt Enable</description>
                            <lsb>13</lsb>
                            <msb>13</msb>
                            <access>read-write</access>
                            <enumeratedValues>
                                <enumeratedValue>
                                    <name>0</name>
                                    <description>Overload interrupt disabled</description>
                                    <value>#0</value>
                                </enumeratedValue>
                                <enumeratedValue>
                                    <name>1</name>
                                    <description>Overload interrupt enabled</description>
                                    <value>#1</value>
                                </enumeratedValue>
                            </enumeratedValues>
                        </field>
                        <field>
                            <name>BLIE</name>
                            <description>Bus Lock Interrupt Enable</description>
                            <lsb>14</lsb>
                            <msb>14</msb>
                            <access>read-write</access>
                            <enumeratedValues>
                                <enumeratedValue>
                                    <name>0</name>
                                    <description>Bus lock interrupt disabled</description>
                                    <value>#0</value>
                                </enumeratedValue>
                                <enumeratedValue>
                                    <name>1</name>
                                    <description>Bus lock interrupt enabled</description>
                                    <value>#1</value>
                                </enumeratedValue>
                            </enumeratedValues>
                        </field>
                        <field>
                            <name>ALIE</name>
                            <description>Arbitration Lost Interrupt Enable</description>
                            <lsb>15</lsb>
                            <msb>15</msb>
                            <access>read-write</access>
                            <enumeratedValues>
                                <enumeratedValue>
                                    <name>0</name>
                                    <description>Arbitration lost interrupt disabled</description>
                                    <value>#0</value>
                                </enumeratedValue>
                                <enumeratedValue>
                                    <name>1</name>
                                    <description>Arbitration lost interrupt enabled</description>
                                    <value>#1</value>
                                </enumeratedValue>
                            </enumeratedValues>
                        </field>
                        <field>
                            <name>TAIE</name>
                            <description>Transmission Abort Interrupt Enable</description>
                            <lsb>16</lsb>
                            <msb>16</msb>
                            <access>read-write</access>
                            <enumeratedValues>
                                <enumeratedValue>
                                    <name>0</name>
                                    <description>TX abort interrupt disabled</description>
                                    <value>#0</value>
                                </enumeratedValue>
                                <enumeratedValue>
                                    <name>1</name>
                                    <description>TX abort interrupt enabled</description>
                                    <value>#1</value>
                                </enumeratedValue>
                            </enumeratedValues>
                        </field>
                        <field>
                            <name>EOCOIE</name>
                            <description>Error Occurrence Counter Overflow Interrupt Enable</description>
                            <lsb>17</lsb>
                            <msb>17</msb>
                            <access>read-write</access>
                            <enumeratedValues>
                                <enumeratedValue>
                                    <name>0</name>
                                    <description>Error occurrence counter overflow interrupt disabled</description>
                                    <value>#0</value>
                                </enumeratedValue>
                                <enumeratedValue>
                                    <name>1</name>
                                    <description>Error occurrence counter overflow interrupt enabled</description>
                                    <value>#1</value>
                                </enumeratedValue>
                            </enumeratedValues>
                        </field>
                        <field>
                            <name>SOCOIE</name>
                            <description>Successful Occurrence Counter Overflow Interrupt Enable</description>
                            <lsb>18</lsb>
                            <msb>18</msb>
                            <access>read-write</access>
                            <enumeratedValues>
                                <enumeratedValue>
                                    <name>0</name>
                                    <description>Successful occurrence counter overflow interrupt disabled</description>
                                    <value>#0</value>
                                </enumeratedValue>
                                <enumeratedValue>
                                    <name>1</name>
                                    <description>Successful occurrence counter overflow interrupt enabled</description>
                                    <value>#1</value>
                                </enumeratedValue>
                            </enumeratedValues>
                        </field>
                        <field>
                            <name>TDCVFIE</name>
                            <description>Transceiver Delay Compensation Violation Interrupt Enable</description>
                            <lsb>19</lsb>
                            <msb>19</msb>
                            <access>read-write</access>
                            <enumeratedValues>
                                <enumeratedValue>
                                    <name>0</name>
                                    <description>Transceiver delay compensation violation interrupt disabled</description>
                                    <value>#0</value>
                                </enumeratedValue>
                                <enumeratedValue>
                                    <name>1</name>
                                    <description>Transceiver delay compensation violation interrupt enabled</description>
                                    <value>#1</value>
                                </enumeratedValue>
                            </enumeratedValues>
                        </field>
                        <field>
                            <name>BOM</name>
                            <description>Channel Bus-Off Mode</description>
                            <lsb>21</lsb>
                            <msb>22</msb>
                            <access>read-write</access>
                            <enumeratedValues>
                                <enumeratedValue>
                                    <name>00</name>
                                    <description>Normal mode (comply with ISO 11898-1)</description>
                                    <value>#00</value>
                                </enumeratedValue>
                                <enumeratedValue>
                                    <name>01</name>
                                    <description>Entry to Halt mode automatically at bus-off start</description>
                                    <value>#01</value>
                                </enumeratedValue>
                                <enumeratedValue>
                                    <name>10</name>
                                    <description>Entry to Halt mode automatically at bus-off end</description>
                                    <value>#10</value>
                                </enumeratedValue>
                                <enumeratedValue>
                                    <name>11</name>
                                    <description>Entry to Halt mode (during bus-off recovery period) by software</description>
                                    <value>#11</value>
                                </enumeratedValue>
                            </enumeratedValues>
                        </field>
                        <field>
                            <name>ERRD</name>
                            <description>Channel Error Display</description>
                            <lsb>23</lsb>
                            <msb>23</msb>
                            <access>read-write</access>
                            <enumeratedValues>
                                <enumeratedValue>
                                    <name>0</name>
                                    <description>Only the first set of error codes displayed</description>
                                    <value>#0</value>
                                </enumeratedValue>
                                <enumeratedValue>
                                    <name>1</name>
                                    <description>Accumulated error codes displayed</description>
                                    <value>#1</value>
                                </enumeratedValue>
                            </enumeratedValues>
                        </field>
                        <field>
                            <name>CTME</name>
                            <description>Channel Test Mode Enable</description>
                            <lsb>24</lsb>
                            <msb>24</msb>
                            <access>read-write</access>
                            <enumeratedValues>
                                <enumeratedValue>
                                    <name>0</name>
                                    <description>Channel test mode disabled</description>
                                    <value>#0</value>
                                </enumeratedValue>
                                <enumeratedValue>
                                    <name>1</name>
                                    <description>Channel test mode enabled</description>
                                    <value>#1</value>
                                </enumeratedValue>
                            </enumeratedValues>
                        </field>
                        <field>
                            <name>CTMS</name>
                            <description>Channel Test Mode Select</description>
                            <lsb>25</lsb>
                            <msb>26</msb>
                            <access>read-write</access>
                            <enumeratedValues>
                                <enumeratedValue>
                                    <name>00</name>
                                    <description>Basic test mode</description>
                                    <value>#00</value>
                                </enumeratedValue>
                                <enumeratedValue>
                                    <name>01</name>
                                    <description>Listen-only mode</description>
                                    <value>#01</value>
                                </enumeratedValue>
                                <enumeratedValue>
                                    <name>10</name>
                                    <description>Self-test mode 0 (External loopback mode)</description>
                                    <value>#10</value>
                                </enumeratedValue>
                                <enumeratedValue>
                                    <name>11</name>
                                    <description>Self-test mode 1 (Internal loopback mode)</description>
                                    <value>#11</value>
                                </enumeratedValue>
                            </enumeratedValues>
                        </field>
                        <field>
                            <name>BFT</name>
                            <description>Bit Flip Test</description>
                            <lsb>30</lsb>
                            <msb>30</msb>
                            <access>read-write</access>
                            <enumeratedValues>
                                <enumeratedValue>
                                    <name>0</name>
                                    <description>First data bit of reception stream not inverted</description>
                                    <value>#0</value>
                                </enumeratedValue>
                                <enumeratedValue>
                                    <name>1</name>
                                    <description>First data bit of reception stream inverted</description>
                                    <value>#1</value>
                                </enumeratedValue>
                            </enumeratedValues>
                        </field>
                        <field>
                            <name>ROM</name>
                            <description>Restricted Operation Mode</description>
                            <lsb>31</lsb>
                            <msb>31</msb>
                            <access>read-write</access>
                            <enumeratedValues>
                                <enumeratedValue>
                                    <name>0</name>
                                    <description>Restricted operation mode disabled</description>
                                    <value>#0</value>
                                </enumeratedValue>
                                <enumeratedValue>
                                    <name>1</name>
                                    <description>Restricted operation mode enabled</description>
                                    <value>#1</value>
                                </enumeratedValue>
                            </enumeratedValues>
                        </field>
                    </fields>
                </register>
                <register>
                    <name>CFDC0STS</name>
                    <description>Status Register</description>
                    <addressOffset>0x0008</addressOffset>
                    <size>32</size>
                    <access>read-write</access>
                    <resetValue>0x00000005</resetValue>
                    <resetMask>0xffffffff</resetMask>
                    <fields>
                        <field>
                            <name>CRSTSTS</name>
                            <description>Channel Reset Status</description>
                            <lsb>0</lsb>
                            <msb>0</msb>
                            <access>read-only</access>
                            <enumeratedValues>
                                <enumeratedValue>
                                    <name>0</name>
                                    <description>Channel not in Reset mode</description>
                                    <value>#0</value>
                                </enumeratedValue>
                                <enumeratedValue>
                                    <name>1</name>
                                    <description>Channel in Reset mode</description>
                                    <value>#1</value>
                                </enumeratedValue>
                            </enumeratedValues>
                        </field>
                        <field>
                            <name>CHLTSTS</name>
                            <description>Channel Halt Status</description>
                            <lsb>1</lsb>
                            <msb>1</msb>
                            <access>read-only</access>
                            <enumeratedValues>
                                <enumeratedValue>
                                    <name>0</name>
                                    <description>Channel not in Halt mode</description>
                                    <value>#0</value>
                                </enumeratedValue>
                                <enumeratedValue>
                                    <name>1</name>
                                    <description>Channel in Halt mode</description>
                                    <value>#1</value>
                                </enumeratedValue>
                            </enumeratedValues>
                        </field>
                        <field>
                            <name>CSLPSTS</name>
                            <description>Channel Sleep Status</description>
                            <lsb>2</lsb>
                            <msb>2</msb>
                            <access>read-only</access>
                            <enumeratedValues>
                                <enumeratedValue>
                                    <name>0</name>
                                    <description>Channel not in Sleep mode</description>
                                    <value>#0</value>
                                </enumeratedValue>
                                <enumeratedValue>
                                    <name>1</name>
                                    <description>Channel in Sleep mode</description>
                                    <value>#1</value>
                                </enumeratedValue>
                            </enumeratedValues>
                        </field>
                        <field>
                            <name>EPSTS</name>
                            <description>Channel Error Passive Status</description>
                            <lsb>3</lsb>
                            <msb>3</msb>
                            <access>read-only</access>
                            <enumeratedValues>
                                <enumeratedValue>
                                    <name>0</name>
                                    <description>Channel not in error passive state</description>
                                    <value>#0</value>
                                </enumeratedValue>
                                <enumeratedValue>
                                    <name>1</name>
                                    <description>Channel in error passive state</description>
                                    <value>#1</value>
                                </enumeratedValue>
                            </enumeratedValues>
                        </field>
                        <field>
                            <name>BOSTS</name>
                            <description>Channel Bus-Off Status</description>
                            <lsb>4</lsb>
                            <msb>4</msb>
                            <access>read-only</access>
                            <enumeratedValues>
                                <enumeratedValue>
                                    <name>0</name>
                                    <description>Channel not in bus-off state</description>
                                    <value>#0</value>
                                </enumeratedValue>
                                <enumeratedValue>
                                    <name>1</name>
                                    <description>Channel in bus-off state</description>
                                    <value>#1</value>
                                </enumeratedValue>
                            </enumeratedValues>
                        </field>
                        <field>
                            <name>TRMSTS</name>
                            <description>Channel Transmit Status</description>
                            <lsb>5</lsb>
                            <msb>5</msb>
                            <access>read-only</access>
                            <enumeratedValues>
                                <enumeratedValue>
                                    <name>0</name>
                                    <description>Channel is not transmitting</description>
                                    <value>#0</value>
                                </enumeratedValue>
                                <enumeratedValue>
                                    <name>1</name>
                                    <description>Channel is transmitting</description>
                                    <value>#1</value>
                                </enumeratedValue>
                            </enumeratedValues>
                        </field>
                        <field>
                            <name>RECSTS</name>
                            <description>Channel Receive Status</description>
                            <lsb>6</lsb>
                            <msb>6</msb>
                            <access>read-only</access>
                            <enumeratedValues>
                                <enumeratedValue>
                                    <name>0</name>
                                    <description>Channel is not receiving</description>
                                    <value>#0</value>
                                </enumeratedValue>
                                <enumeratedValue>
                                    <name>1</name>
                                    <description>Channel is receiving</description>
                                    <value>#1</value>
                                </enumeratedValue>
                            </enumeratedValues>
                        </field>
                        <field>
                            <name>COMSTS</name>
                            <description>Channel Communication Status</description>
                            <lsb>7</lsb>
                            <msb>7</msb>
                            <access>read-only</access>
                            <enumeratedValues>
                                <enumeratedValue>
                                    <name>0</name>
                                    <description>Channel is not ready for communication</description>
                                    <value>#0</value>
                                </enumeratedValue>
                                <enumeratedValue>
                                    <name>1</name>
                                    <description>Channel is ready for communication</description>
                                    <value>#1</value>
                                </enumeratedValue>
                            </enumeratedValues>
                        </field>
                        <field>
                            <name>ESIF</name>
                            <description>Error State Indication Flag</description>
                            <lsb>8</lsb>
                            <msb>8</msb>
                            <access>read-write</access>
                            <enumeratedValues>
                                <enumeratedValue>
                                    <name>0</name>
                                    <description>No CANFD message has been received when the ESI flag was set</description>
                                    <value>#0</value>
                                </enumeratedValue>
                                <enumeratedValue>
                                    <name>1</name>
                                    <description>At least one CANFD message was received when the ESI flag was set</description>
                                    <value>#1</value>
                                </enumeratedValue>
                            </enumeratedValues>
                        </field>
                        <field>
                            <name>REC</name>
                            <description>Reception Error Count</description>
                            <lsb>16</lsb>
                            <msb>23</msb>
                            <access>read-only</access>
                        </field>
                        <field>
                            <name>TEC</name>
                            <description>Transmission Error Count</description>
                            <lsb>24</lsb>
                            <msb>31</msb>
                            <access>read-only</access>
                        </field>
                    </fields>
                </register>
                <register>
                    <name>CFDC0ERFL</name>
                    <description> Error Flag Register</description>
                    <addressOffset>0x000C</addressOffset>
                    <size>32</size>
                    <access>read-write</access>
                    <resetValue>0x00000000</resetValue>
                    <resetMask>0xffffffff</resetMask>
                    <fields>
                        <field>
                            <name>BEF</name>
                            <description>Bus Error Flag</description>
                            <lsb>0</lsb>
                            <msb>0</msb>
                            <access>read-write</access>
                            <enumeratedValues>
                                <enumeratedValue>
                                    <name>0</name>
                                    <description>Channel bus error not detected</description>
                                    <value>#0</value>
                                </enumeratedValue>
                                <enumeratedValue>
                                    <name>1</name>
                                    <description>Channel bus error detected</description>
                                    <value>#1</value>
                                </enumeratedValue>
                            </enumeratedValues>
                        </field>
                        <field>
                            <name>EWF</name>
                            <description>Error Warning Flag</description>
                            <lsb>1</lsb>
                            <msb>1</msb>
                            <access>read-write</access>
                            <enumeratedValues>
                                <enumeratedValue>
                                    <name>0</name>
                                    <description>Channel error warning not detected</description>
                                    <value>#0</value>
                                </enumeratedValue>
                                <enumeratedValue>
                                    <name>1</name>
                                    <description>Channel error warning detected</description>
                                    <value>#1</value>
                                </enumeratedValue>
                            </enumeratedValues>
                        </field>
                        <field>
                            <name>EPF</name>
                            <description>Error Passive Flag</description>
                            <lsb>2</lsb>
                            <msb>2</msb>
                            <access>read-write</access>
                            <enumeratedValues>
                                <enumeratedValue>
                                    <name>0</name>
                                    <description>Channel error passive not detected</description>
                                    <value>#0</value>
                                </enumeratedValue>
                                <enumeratedValue>
                                    <name>1</name>
                                    <description>Channel error passive detected</description>
                                    <value>#1</value>
                                </enumeratedValue>
                            </enumeratedValues>
                        </field>
                        <field>
                            <name>BOEF</name>
                            <description>Bus-Off Entry Flag</description>
                            <lsb>3</lsb>
                            <msb>3</msb>
                            <access>read-write</access>
                            <enumeratedValues>
                                <enumeratedValue>
                                    <name>0</name>
                                    <description>Channel bus-off entry not detected</description>
                                    <value>#0</value>
                                </enumeratedValue>
                                <enumeratedValue>
                                    <name>1</name>
                                    <description>Channel bus-off entry detected</description>
                                    <value>#1</value>
                                </enumeratedValue>
                            </enumeratedValues>
                        </field>
                        <field>
                            <name>BORF</name>
                            <description>Bus-Off Recovery Flag</description>
                            <lsb>4</lsb>
                            <msb>4</msb>
                            <access>read-write</access>
                            <enumeratedValues>
                                <enumeratedValue>
                                    <name>0</name>
                                    <description>Channel bus-off recovery not detected</description>
                                    <value>#0</value>
                                </enumeratedValue>
                                <enumeratedValue>
                                    <name>1</name>
                                    <description>Channel bus-off recovery detected</description>
                                    <value>#1</value>
                                </enumeratedValue>
                            </enumeratedValues>
                        </field>
                        <field>
                            <name>OVLF</name>
                            <description>Overload Flag</description>
                            <lsb>5</lsb>
                            <msb>5</msb>
                            <access>read-write</access>
                            <enumeratedValues>
                                <enumeratedValue>
                                    <name>0</name>
                                    <description>Channel overload not detected</description>
                                    <value>#0</value>
                                </enumeratedValue>
                                <enumeratedValue>
                                    <name>1</name>
                                    <description>Channel overload detected</description>
                                    <value>#1</value>
                                </enumeratedValue>
                            </enumeratedValues>
                        </field>
                        <field>
                            <name>BLF</name>
                            <description>Bus Lock Flag</description>
                            <lsb>6</lsb>
                            <msb>6</msb>
                            <access>read-write</access>
                            <enumeratedValues>
                                <enumeratedValue>
                                    <name>0</name>
                                    <description>Channel bus lock not detected</description>
                                    <value>#0</value>
                                </enumeratedValue>
                                <enumeratedValue>
                                    <name>1</name>
                                    <description>Channel bus lock detected</description>
                                    <value>#1</value>
                                </enumeratedValue>
                            </enumeratedValues>
                        </field>
                        <field>
                            <name>ALF</name>
                            <description>Arbitration Lost Flag</description>
                            <lsb>7</lsb>
                            <msb>7</msb>
                            <access>read-write</access>
                            <enumeratedValues>
                                <enumeratedValue>
                                    <name>0</name>
                                    <description>Channel arbitration lost not detected</description>
                                    <value>#0</value>
                                </enumeratedValue>
                                <enumeratedValue>
                                    <name>1</name>
                                    <description>Channel arbitration lost detected</description>
                                    <value>#1</value>
                                </enumeratedValue>
                            </enumeratedValues>
                        </field>
                        <field>
                            <name>SERR</name>
                            <description>Stuff Error</description>
                            <lsb>8</lsb>
                            <msb>8</msb>
                            <access>read-write</access>
                            <enumeratedValues>
                                <enumeratedValue>
                                    <name>0</name>
                                    <description>Channel stuff error not detected</description>
                                    <value>#0</value>
                                </enumeratedValue>
                                <enumeratedValue>
                                    <name>1</name>
                                    <description>Channel stuff error detected</description>
                                    <value>#1</value>
                                </enumeratedValue>
                            </enumeratedValues>
                        </field>
                        <field>
                            <name>FERR</name>
                            <description>Form Error</description>
                            <lsb>9</lsb>
                            <msb>9</msb>
                            <access>read-write</access>
                            <enumeratedValues>
                                <enumeratedValue>
                                    <name>0</name>
                                    <description>Channel form error not detected</description>
                                    <value>#0</value>
                                </enumeratedValue>
                                <enumeratedValue>
                                    <name>1</name>
                                    <description>Channel form error detected</description>
                                    <value>#1</value>
                                </enumeratedValue>
                            </enumeratedValues>
                        </field>
                        <field>
                            <name>AERR</name>
                            <description>Acknowledge Error</description>
                            <lsb>10</lsb>
                            <msb>10</msb>
                            <access>read-write</access>
                            <enumeratedValues>
                                <enumeratedValue>
                                    <name>0</name>
                                    <description>Channel acknowledge error not detected</description>
                                    <value>#0</value>
                                </enumeratedValue>
                                <enumeratedValue>
                                    <name>1</name>
                                    <description>Channel acknowledge error detected</description>
                                    <value>#1</value>
                                </enumeratedValue>
                            </enumeratedValues>
                        </field>
                        <field>
                            <name>CERR</name>
                            <description>CRC Error</description>
                            <lsb>11</lsb>
                            <msb>11</msb>
                            <access>read-write</access>
                            <enumeratedValues>
                                <enumeratedValue>
                                    <name>0</name>
                                    <description>Channel CRC error not detected</description>
                                    <value>#0</value>
                                </enumeratedValue>
                                <enumeratedValue>
                                    <name>1</name>
                                    <description>Channel CRC error detected</description>
                                    <value>#1</value>
                                </enumeratedValue>
                            </enumeratedValues>
                        </field>
                        <field>
                            <name>B1ERR</name>
                            <description>Bit 1 Error</description>
                            <lsb>12</lsb>
                            <msb>12</msb>
                            <access>read-write</access>
                            <enumeratedValues>
                                <enumeratedValue>
                                    <name>0</name>
                                    <description>Channel bit 1 error not detected</description>
                                    <value>#0</value>
                                </enumeratedValue>
                                <enumeratedValue>
                                    <name>1</name>
                                    <description>Channel bit 1 error detected</description>
                                    <value>#1</value>
                                </enumeratedValue>
                            </enumeratedValues>
                        </field>
                        <field>
                            <name>B0ERR</name>
                            <description>Bit 0 Error</description>
                            <lsb>13</lsb>
                            <msb>13</msb>
                            <access>read-write</access>
                            <enumeratedValues>
                                <enumeratedValue>
                                    <name>0</name>
                                    <description>Channel bit 0 error not detected</description>
                                    <value>#0</value>
                                </enumeratedValue>
                                <enumeratedValue>
                                    <name>1</name>
                                    <description>Channel bit 0 error detected</description>
                                    <value>#1</value>
                                </enumeratedValue>
                            </enumeratedValues>
                        </field>
                        <field>
                            <name>ADERR</name>
                            <description>Acknowledge Delimiter Error</description>
                            <lsb>14</lsb>
                            <msb>14</msb>
                            <access>read-write</access>
                            <enumeratedValues>
                                <enumeratedValue>
                                    <name>0</name>
                                    <description>Channel acknowledge delimiter error not detected</description>
                                    <value>#0</value>
                                </enumeratedValue>
                                <enumeratedValue>
                                    <name>1</name>
                                    <description>Channel acknowledge delimiter error detected</description>
                                    <value>#1</value>
                                </enumeratedValue>
                            </enumeratedValues>
                        </field>
                        <field>
                            <name>CRCREG</name>
                            <description>CRC Register value</description>
                            <lsb>16</lsb>
                            <msb>30</msb>
                            <access>read-only</access>
                        </field>
                    </fields>
                </register>
                <register>
                    <name>CFDGCFG</name>
                    <description>Global Configuration Register</description>
                    <addressOffset>0x0014</addressOffset>
                    <size>32</size>
                    <access>read-write</access>
                    <resetValue>0x00000000</resetValue>
                    <resetMask>0xffffffff</resetMask>
                    <fields>
                        <field>
                            <name>TPRI</name>
                            <description>Transmission Priority</description>
                            <lsb>0</lsb>
                            <msb>0</msb>
                            <access>read-write</access>
                            <enumeratedValues>
                                <enumeratedValue>
                                    <name>0</name>
                                    <description>ID priority</description>
                                    <value>#0</value>
                                </enumeratedValue>
                                <enumeratedValue>
                                    <name>1</name>
                                    <description>Message buffer number priority</description>
                                    <value>#1</value>
                                </enumeratedValue>
                            </enumeratedValues>
                        </field>
                        <field>
                            <name>DCE</name>
                            <description>DLC Check Enable</description>
                            <lsb>1</lsb>
                            <msb>1</msb>
                            <access>read-write</access>
                            <enumeratedValues>
                                <enumeratedValue>
                                    <name>0</name>
                                    <description>DLC check disabled</description>
                                    <value>#0</value>
                                </enumeratedValue>
                                <enumeratedValue>
                                    <name>1</name>
                                    <description>DLC check enabled</description>
                                    <value>#1</value>
                                </enumeratedValue>
                            </enumeratedValues>
                        </field>
                        <field>
                            <name>DRE</name>
                            <description>DLC Replacement Enable</description>
                            <lsb>2</lsb>
                            <msb>2</msb>
                            <access>read-write</access>
                            <enumeratedValues>
                                <enumeratedValue>
                                    <name>0</name>
                                    <description>DLC replacement disabled</description>
                                    <value>#0</value>
                                </enumeratedValue>
                                <enumeratedValue>
                                    <name>1</name>
                                    <description>DLC replacement enabled</description>
                                    <value>#1</value>
                                </enumeratedValue>
                            </enumeratedValues>
                        </field>
                        <field>
                            <name>MME</name>
                            <description>Mirror Mode Enable</description>
                            <lsb>3</lsb>
                            <msb>3</msb>
                            <access>read-write</access>
                            <enumeratedValues>
                                <enumeratedValue>
                                    <name>0</name>
                                    <description>Mirror mode disabled</description>
                                    <value>#0</value>
                                </enumeratedValue>
                                <enumeratedValue>
                                    <name>1</name>
                                    <description>Mirror mode enabled</description>
                                    <value>#1</value>
                                </enumeratedValue>
                            </enumeratedValues>
                        </field>
                        <field>
                            <name>DCS</name>
                            <description>Data Link Controller Clock Select</description>
                            <lsb>4</lsb>
                            <msb>4</msb>
                            <access>read-write</access>
                            <enumeratedValues>
                                <enumeratedValue>
                                    <name>0</name>
                                    <description>CANFD core clock (CANFDCLK)</description>
                                    <value>#0</value>
                                </enumeratedValue>
                                <enumeratedValue>
                                    <name>1</name>
                                    <description>External oscillator clock (CANMCLK)</description>
                                    <value>#1</value>
                                </enumeratedValue>
                            </enumeratedValues>
                        </field>
                        <field>
                            <name>CMPOC</name>
                            <description>CANFD Message Payload Overflow Configuration</description>
                            <lsb>5</lsb>
                            <msb>5</msb>
                            <access>read-write</access>
                            <enumeratedValues>
                                <enumeratedValue>
                                    <name>0</name>
                                    <description>Message is rejected</description>
                                    <value>#0</value>
                                </enumeratedValue>
                                <enumeratedValue>
                                    <name>1</name>
                                    <description>Message payload is cut to fit to configured message size</description>
                                    <value>#1</value>
                                </enumeratedValue>
                            </enumeratedValues>
                        </field>
                        <field>
                            <name>TSP</name>
                            <description>Timestamp Prescaler</description>
                            <lsb>8</lsb>
                            <msb>11</msb>
                            <access>read-write</access>
                        </field>
                        <field>
                            <name>TSSS</name>
                            <description>Timestamp Source Select</description>
                            <lsb>12</lsb>
                            <msb>12</msb>
                            <access>read-write</access>
                            <enumeratedValues>
                                <enumeratedValue>
                                    <name>0</name>
                                    <description>Source clock for timestamp counter is peripheral clock</description>
                                    <value>#0</value>
                                </enumeratedValue>
                                <enumeratedValue>
                                    <name>1</name>
                                    <description>Source clock for timestamp counter is bit time clock</description>
                                    <value>#1</value>
                                </enumeratedValue>
                            </enumeratedValues>
                        </field>
                        <field>
                            <name>ITRCP</name>
                            <description>Interval Timer Reference Clock Prescaler</description>
                            <lsb>16</lsb>
                            <msb>31</msb>
                            <access>read-write</access>
                        </field>
                    </fields>
                </register>
                <register>
                    <name>CFDGCTR</name>
                    <description>Global Control Register</description>
                    <addressOffset>0x0018</addressOffset>
                    <size>32</size>
                    <access>read-write</access>
                    <resetValue>0x00000005</resetValue>
                    <resetMask>0xffffffff</resetMask>
                    <fields>
                        <field>
                            <name>GMDC</name>
                            <description>Global Mode Control</description>
                            <lsb>0</lsb>
                            <msb>1</msb>
                            <access>read-write</access>
                            <enumeratedValues>
                                <enumeratedValue>
                                    <name>00</name>
                                    <description>Global operation mode request</description>
                                    <value>#00</value>
                                </enumeratedValue>
                                <enumeratedValue>
                                    <name>01</name>
                                    <description>Global reset mode request</description>
                                    <value>#01</value>
                                </enumeratedValue>
                                <enumeratedValue>
                                    <name>10</name>
                                    <description>Global halt mode request</description>
                                    <value>#10</value>
                                </enumeratedValue>
                                <enumeratedValue>
                                    <name>11</name>
                                    <description>Keep current value</description>
                                    <value>#11</value>
                                </enumeratedValue>
                            </enumeratedValues>
                        </field>
                        <field>
                            <name>GSLPR</name>
                            <description>Global Sleep Request</description>
                            <lsb>2</lsb>
                            <msb>2</msb>
                            <access>read-write</access>
                            <enumeratedValues>
                                <enumeratedValue>
                                    <name>0</name>
                                    <description>Global sleep request disabled</description>
                                    <value>#0</value>
                                </enumeratedValue>
                                <enumeratedValue>
                                    <name>1</name>
                                    <description>Global sleep request enabled</description>
                                    <value>#1</value>
                                </enumeratedValue>
                            </enumeratedValues>
                        </field>
                        <field>
                            <name>DEIE</name>
                            <description>DLC Check Interrupt Enable</description>
                            <lsb>8</lsb>
                            <msb>8</msb>
                            <access>read-write</access>
                            <enumeratedValues>
                                <enumeratedValue>
                                    <name>0</name>
                                    <description>DLC check interrupt disabled</description>
                                    <value>#0</value>
                                </enumeratedValue>
                                <enumeratedValue>
                                    <name>1</name>
                                    <description>DLC check interrupt enabled</description>
                                    <value>#1</value>
                                </enumeratedValue>
                            </enumeratedValues>
                        </field>
                        <field>
                            <name>MEIE</name>
                            <description>Message Lost Error Interrupt Enable</description>
                            <lsb>9</lsb>
                            <msb>9</msb>
                            <access>read-write</access>
                            <enumeratedValues>
                                <enumeratedValue>
                                    <name>0</name>
                                    <description>Message lost error interrupt disabled</description>
                                    <value>#0</value>
                                </enumeratedValue>
                                <enumeratedValue>
                                    <name>1</name>
                                    <description>Message lost error interrupt enabled</description>
                                    <value>#1</value>
                                </enumeratedValue>
                            </enumeratedValues>
                        </field>
                        <field>
                            <name>THLEIE</name>
                            <description>TX History List Entry Lost Interrupt Enable</description>
                            <lsb>10</lsb>
                            <msb>10</msb>
                            <access>read-write</access>
                            <enumeratedValues>
                                <enumeratedValue>
                                    <name>0</name>
                                    <description>TX history list entry lost interrupt disabled</description>
                                    <value>#0</value>
                                </enumeratedValue>
                                <enumeratedValue>
                                    <name>1</name>
                                    <description>TX history list entry lost interrupt enabled</description>
                                    <value>#1</value>
                                </enumeratedValue>
                            </enumeratedValues>
                        </field>
                        <field>
                            <name>CMPOFIE</name>
                            <description>CANFD Message Payload Overflow Flag Interrupt Enable</description>
                            <lsb>11</lsb>
                            <msb>11</msb>
                            <access>read-write</access>
                            <enumeratedValues>
                                <enumeratedValue>
                                    <name>0</name>
                                    <description>CANFD message payload overflow flag interrupt disabled</description>
                                    <value>#0</value>
                                </enumeratedValue>
                                <enumeratedValue>
                                    <name>1</name>
                                    <description>CANFD message payload overflow flag interrupt enabled</description>
                                    <value>#1</value>
                                </enumeratedValue>
                            </enumeratedValues>
                        </field>
                        <field>
                            <name>TSRST</name>
                            <description>Timestamp Reset</description>
                            <lsb>16</lsb>
                            <msb>16</msb>
                            <access>read-write</access>
                            <enumeratedValues>
                                <enumeratedValue>
                                    <name>0</name>
                                    <description>Timestamp not reset</description>
                                    <value>#0</value>
                                </enumeratedValue>
                                <enumeratedValue>
                                    <name>1</name>
                                    <description>Timestamp reset</description>
                                    <value>#1</value>
                                </enumeratedValue>
                            </enumeratedValues>
                        </field>
                    </fields>
                </register>
                <register>
                    <name>CFDGSTS</name>
                    <description>Global Status Register</description>
                    <addressOffset>0x001C</addressOffset>
                    <size>32</size>
                    <access>read-only</access>
                    <resetValue>0x0000000d</resetValue>
                    <resetMask>0xffffffff</resetMask>
                    <fields>
                        <field>
                            <name>GRSTSTS</name>
                            <description>Global Reset Status</description>
                            <lsb>0</lsb>
                            <msb>0</msb>
                            <access>read-only</access>
                            <enumeratedValues>
                                <enumeratedValue>
                                    <name>0</name>
                                    <description>Not in Reset mode</description>
                                    <value>#0</value>
                                </enumeratedValue>
                                <enumeratedValue>
                                    <name>1</name>
                                    <description>In Reset mode</description>
                                    <value>#1</value>
                                </enumeratedValue>
                            </enumeratedValues>
                        </field>
                        <field>
                            <name>GHLTSTS</name>
                            <description>Global Halt Status</description>
                            <lsb>1</lsb>
                            <msb>1</msb>
                            <access>read-only</access>
                            <enumeratedValues>
                                <enumeratedValue>
                                    <name>0</name>
                                    <description>Not in Halt mode</description>
                                    <value>#0</value>
                                </enumeratedValue>
                                <enumeratedValue>
                                    <name>1</name>
                                    <description>In Halt mode</description>
                                    <value>#1</value>
                                </enumeratedValue>
                            </enumeratedValues>
                        </field>
                        <field>
                            <name>GSLPSTS</name>
                            <description>Global Sleep Status</description>
                            <lsb>2</lsb>
                            <msb>2</msb>
                            <access>read-only</access>
                            <enumeratedValues>
                                <enumeratedValue>
                                    <name>0</name>
                                    <description>Not in Sleep mode</description>
                                    <value>#0</value>
                                </enumeratedValue>
                                <enumeratedValue>
                                    <name>1</name>
                                    <description>In Sleep mode</description>
                                    <value>#1</value>
                                </enumeratedValue>
                            </enumeratedValues>
                        </field>
                        <field>
                            <name>GRAMINIT</name>
                            <description>Global RAM Initialization</description>
                            <lsb>3</lsb>
                            <msb>3</msb>
                            <access>read-only</access>
                            <enumeratedValues>
                                <enumeratedValue>
                                    <name>0</name>
                                    <description>RAM initialization is complete</description>
                                    <value>#0</value>
                                </enumeratedValue>
                                <enumeratedValue>
                                    <name>1</name>
                                    <description>RAM initialization is ongoing</description>
                                    <value>#1</value>
                                </enumeratedValue>
                            </enumeratedValues>
                        </field>
                    </fields>
                </register>
                <register>
                    <name>CFDGERFL</name>
                    <description>Global Error Flag Register</description>
                    <addressOffset>0x0020</addressOffset>
                    <size>32</size>
                    <access>read-write</access>
                    <resetValue>0x00000000</resetValue>
                    <resetMask>0xffffffff</resetMask>
                    <fields>
                        <field>
                            <name>DEF</name>
                            <description>DLC Error Flag</description>
                            <lsb>0</lsb>
                            <msb>0</msb>
                            <access>read-write</access>
                            <enumeratedValues>
                                <enumeratedValue>
                                    <name>0</name>
                                    <description>DLC error not detected</description>
                                    <value>#0</value>
                                </enumeratedValue>
                                <enumeratedValue>
                                    <name>1</name>
                                    <description>DLC error detected</description>
                                    <value>#1</value>
                                </enumeratedValue>
                            </enumeratedValues>
                        </field>
                        <field>
                            <name>MES</name>
                            <description>Message Lost Error Status</description>
                            <lsb>1</lsb>
                            <msb>1</msb>
                            <access>read-only</access>
                            <enumeratedValues>
                                <enumeratedValue>
                                    <name>0</name>
                                    <description>Message lost error not detected</description>
                                    <value>#0</value>
                                </enumeratedValue>
                                <enumeratedValue>
                                    <name>1</name>
                                    <description>Message lost error detected</description>
                                    <value>#1</value>
                                </enumeratedValue>
                            </enumeratedValues>
                        </field>
                        <field>
                            <name>THLES</name>
                            <description>TX History List Entry Lost Error Status</description>
                            <lsb>2</lsb>
                            <msb>2</msb>
                            <access>read-only</access>
                            <enumeratedValues>
                                <enumeratedValue>
                                    <name>0</name>
                                    <description>TX history list entry lost error not detected</description>
                                    <value>#0</value>
                                </enumeratedValue>
                                <enumeratedValue>
                                    <name>1</name>
                                    <description>TX history list entry lost error detected</description>
                                    <value>#1</value>
                                </enumeratedValue>
                            </enumeratedValues>
                        </field>
                        <field>
                            <name>CMPOF</name>
                            <description>CANFD Message Payload Overflow Flag</description>
                            <lsb>3</lsb>
                            <msb>3</msb>
                            <access>read-write</access>
                            <enumeratedValues>
                                <enumeratedValue>
                                    <name>0</name>
                                    <description>CANFD message payload overflow not detected</description>
                                    <value>#0</value>
                                </enumeratedValue>
                                <enumeratedValue>
                                    <name>1</name>
                                    <description>CANFD message payload overflow detected</description>
                                    <value>#1</value>
                                </enumeratedValue>
                            </enumeratedValues>
                        </field>
                        <field>
                            <name>EEF0</name>
                            <description>ECC Error Flag</description>
                            <lsb>16</lsb>
                            <msb>16</msb>
                            <access>read-write</access>
                            <enumeratedValues>
                                <enumeratedValue>
                                    <name>0</name>
                                    <description>ECC error not detected during TX-SCAN</description>
                                    <value>#0</value>
                                </enumeratedValue>
                                <enumeratedValue>
                                    <name>1</name>
                                    <description>ECC error detected during TX-SCAN</description>
                                    <value>#1</value>
                                </enumeratedValue>
                            </enumeratedValues>
                        </field>
                    </fields>
                </register>
                <register>
                    <name>CFDGTSC</name>
                    <description>Global Timestamp Counter Register</description>
                    <addressOffset>0x0024</addressOffset>
                    <size>32</size>
                    <access>read-only</access>
                    <resetValue>0x00000000</resetValue>
                    <resetMask>0xffffffff</resetMask>
                    <fields>
                        <field>
                            <name>TS</name>
                            <description>Timestamp value</description>
                            <lsb>0</lsb>
                            <msb>15</msb>
                            <access>read-only</access>
                        </field>
                    </fields>
                </register>
                <register>
                    <name>CFDGAFLECTR</name>
                    <description>Global Acceptance Filter List Entry Control Register</description>
                    <addressOffset>0x0028</addressOffset>
                    <size>32</size>
                    <access>read-write</access>
                    <resetValue>0x00000000</resetValue>
                    <resetMask>0xffffffff</resetMask>
                    <fields>
                        <field>
                            <name>AFLDAE</name>
                            <description>Acceptance Filter List Data Access Enable</description>
                            <lsb>8</lsb>
                            <msb>8</msb>
                            <access>read-write</access>
                            <enumeratedValues>
                                <enumeratedValue>
                                    <name>0</name>
                                    <description>Acceptance Filter List data access disabled</description>
                                    <value>#0</value>
                                </enumeratedValue>
                                <enumeratedValue>
                                    <name>1</name>
                                    <description>Acceptance Filter List data access enabled</description>
                                    <value>#1</value>
                                </enumeratedValue>
                            </enumeratedValues>
                        </field>
                    </fields>
                </register>
                <register>
                    <name>CFDGAFLCFG</name>
                    <description>Global Acceptance Filter List Configuration Register</description>
                    <addressOffset>0x002C</addressOffset>
                    <size>32</size>
                    <access>read-write</access>
                    <resetValue>0x00000000</resetValue>
                    <resetMask>0xffffffff</resetMask>
                    <fields>
                        <field>
                            <name>RNC0</name>
                            <description>Rule Number</description>
                            <lsb>16</lsb>
                            <msb>20</msb>
                            <access>read-write</access>
                        </field>
                    </fields>
                </register>
                <register>
                    <name>CFDRMNB</name>
                    <description>RX Message Buffer Number Register</description>
                    <addressOffset>0x0030</addressOffset>
                    <size>32</size>
                    <access>read-write</access>
                    <resetValue>0x00000000</resetValue>
                    <resetMask>0xffffffff</resetMask>
                    <fields>
                        <field>
                            <name>NRXMB</name>
                            <description>Number of RX Message Buffers</description>
                            <lsb>0</lsb>
                            <msb>4</msb>
                            <access>read-write</access>
                        </field>
                        <field>
                            <name>RMPLS</name>
                            <description>Reception Message Buffer Payload Data Size</description>
                            <lsb>8</lsb>
                            <msb>10</msb>
                            <access>read-write</access>
                            <enumeratedValues>
                                <enumeratedValue>
                                    <name>000</name>
                                    <description>8 bytes</description>
                                    <value>#000</value>
                                </enumeratedValue>
                                <enumeratedValue>
                                    <name>001</name>
                                    <description>12 bytes</description>
                                    <value>#001</value>
                                </enumeratedValue>
                                <enumeratedValue>
                                    <name>010</name>
                                    <description>16 bytes</description>
                                    <value>#010</value>
                                </enumeratedValue>
                                <enumeratedValue>
                                    <name>011</name>
                                    <description>20 bytes</description>
                                    <value>#011</value>
                                </enumeratedValue>
                                <enumeratedValue>
                                    <name>100</name>
                                    <description>24 bytes</description>
                                    <value>#100</value>
                                </enumeratedValue>
                                <enumeratedValue>
                                    <name>101</name>
                                    <description>32 bytes</description>
                                    <value>#101</value>
                                </enumeratedValue>
                                <enumeratedValue>
                                    <name>110</name>
                                    <description>48 bytes</description>
                                    <value>#110</value>
                                </enumeratedValue>
                                <enumeratedValue>
                                    <name>111</name>
                                    <description>64 bytes</description>
                                    <value>#111</value>
                                </enumeratedValue>
                            </enumeratedValues>
                        </field>
                    </fields>
                </register>
                <register>
                    <name>CFDRMND</name>
                    <description>RX Message Buffer New Data Register</description>
                    <addressOffset>0x0034</addressOffset>
                    <size>16</size>
                    <access>read-write</access>
                    <resetValue>0x0000</resetValue>
                    <resetMask>0xffff</resetMask>
                    <fields>
                        <field>
                            <name>RMNS</name>
                            <description>RX Message Buffer New Data Status</description>
                            <lsb>0</lsb>
                            <msb>15</msb>
                            <access>read-write</access>
                            <enumeratedValues>
                                <enumeratedValue>
                                    <name>0</name>
                                    <description>New data not stored in corresponding RX message buffer</description>
                                    <value>#0</value>
                                </enumeratedValue>
                                <enumeratedValue>
                                    <name>1</name>
                                    <description>New data stored in corresponding RX message buffer</description>
                                    <value>#1</value>
                                </enumeratedValue>
                            </enumeratedValues>
                        </field>
                    </fields>
                </register>
                <register>
                    <name>CFDRMIEC</name>
                    <description>RX Message Buffer Interrupt Enable Configuration Register</description>
                    <addressOffset>0x0038</addressOffset>
                    <size>16</size>
                    <access>read-write</access>
                    <resetValue>0x0000</resetValue>
                    <resetMask>0xffff</resetMask>
                    <fields>
                        <field>
                            <name>RMIE</name>
                            <description>RX Message Buffer Interrupt Enable</description>
                            <lsb>0</lsb>
                            <msb>15</msb>
                            <access>read-write</access>
                            <enumeratedValues>
                                <enumeratedValue>
                                    <name>0</name>
                                    <description>RX Message Buffer Interrupt disabled for corresponding RX message buffer</description>
                                    <value>#0</value>
                                </enumeratedValue>
                                <enumeratedValue>
                                    <name>1</name>
                                    <description>RX Message Buffer Interrupt enabled for corresponding RX message buffer</description>
                                    <value>#1</value>
                                </enumeratedValue>
                            </enumeratedValues>
                        </field>
                    </fields>
                </register>
                <register>
                    <dim>2</dim>
                    <dimIncrement>0x04</dimIncrement>
                    <dimIndex>0-1</dimIndex>
                    <name>CFDRFCC%s</name>
                    <description>RX FIFO Configuration/Control Registers %s</description>
                    <addressOffset>0x003C</addressOffset>
                    <size>32</size>
                    <access>read-write</access>
                    <resetValue>0x00000000</resetValue>
                    <resetMask>0xffffffff</resetMask>
                    <fields>
                        <field>
                            <name>RFE</name>
                            <description>RX FIFO Enable</description>
                            <lsb>0</lsb>
                            <msb>0</msb>
                            <access>read-write</access>
                            <enumeratedValues>
                                <enumeratedValue>
                                    <name>0</name>
                                    <description>FIFO disabled</description>
                                    <value>#0</value>
                                </enumeratedValue>
                                <enumeratedValue>
                                    <name>1</name>
                                    <description>FIFO enabled</description>
                                    <value>#1</value>
                                </enumeratedValue>
                            </enumeratedValues>
                        </field>
                        <field>
                            <name>RFIE</name>
                            <description>RX FIFO Interrupt Enable</description>
                            <lsb>1</lsb>
                            <msb>1</msb>
                            <access>read-write</access>
                            <enumeratedValues>
                                <enumeratedValue>
                                    <name>0</name>
                                    <description>FIFO interrupt generation disabled</description>
                                    <value>#0</value>
                                </enumeratedValue>
                                <enumeratedValue>
                                    <name>1</name>
                                    <description>FIFO interrupt generation enabled</description>
                                    <value>#1</value>
                                </enumeratedValue>
                            </enumeratedValues>
                        </field>
                        <field>
                            <name>RFPLS</name>
                            <description>Rx FIFO Payload Data Size Configuration</description>
                            <lsb>4</lsb>
                            <msb>6</msb>
                            <access>read-write</access>
                            <enumeratedValues>
                                <enumeratedValue>
                                    <name>000</name>
                                    <description>8 bytes</description>
                                    <value>#000</value>
                                </enumeratedValue>
                                <enumeratedValue>
                                    <name>001</name>
                                    <description>12 bytes</description>
                                    <value>#001</value>
                                </enumeratedValue>
                                <enumeratedValue>
                                    <name>010</name>
                                    <description>16 bytes</description>
                                    <value>#010</value>
                                </enumeratedValue>
                                <enumeratedValue>
                                    <name>011</name>
                                    <description>20 bytes</description>
                                    <value>#011</value>
                                </enumeratedValue>
                                <enumeratedValue>
                                    <name>100</name>
                                    <description>24 bytes</description>
                                    <value>#100</value>
                                </enumeratedValue>
                                <enumeratedValue>
                                    <name>101</name>
                                    <description>32 bytes</description>
                                    <value>#101</value>
                                </enumeratedValue>
                                <enumeratedValue>
                                    <name>110</name>
                                    <description>48 bytes</description>
                                    <value>#110</value>
                                </enumeratedValue>
                                <enumeratedValue>
                                    <name>111</name>
                                    <description>64 bytes</description>
                                    <value>#111</value>
                                </enumeratedValue>
                            </enumeratedValues>
                        </field>
                        <field>
                            <name>RFDC</name>
                            <description>RX FIFO Depth Configuration</description>
                            <lsb>8</lsb>
                            <msb>10</msb>
                            <access>read-write</access>
                            <enumeratedValues>
                                <enumeratedValue>
                                    <name>000</name>
                                    <description>FIFO Depth = 0 message</description>
                                    <value>#000</value>
                                </enumeratedValue>
                                <enumeratedValue>
                                    <name>001</name>
                                    <description>FIFO Depth = 4 messages</description>
                                    <value>#001</value>
                                </enumeratedValue>
                                <enumeratedValue>
                                    <name>010</name>
                                    <description>FIFO Depth = 8 messages</description>
                                    <value>#010</value>
                                </enumeratedValue>
                                <enumeratedValue>
                                    <name>011</name>
                                    <description>FIFO Depth = 16 messages</description>
                                    <value>#011</value>
                                </enumeratedValue>
                                <enumeratedValue>
                                    <name>100</name>
                                    <description>FIFO Depth = 32 essages</description>
                                    <value>#100</value>
                                </enumeratedValue>
                                <enumeratedValue>
                                    <name>101</name>
                                    <description>FIFO Depth = 48 messages</description>
                                    <value>#101</value>
                                </enumeratedValue>
                                <enumeratedValue>
                                    <name>110</name>
                                    <description>Reserved</description>
                                    <value>#110</value>
                                </enumeratedValue>
                                <enumeratedValue>
                                    <name>111</name>
                                    <description>Reserved</description>
                                    <value>#111</value>
                                </enumeratedValue>
                            </enumeratedValues>
                        </field>
                        <field>
                            <name>RFIM</name>
                            <description>RX FIFO Interrupt Mode</description>
                            <lsb>12</lsb>
                            <msb>12</msb>
                            <access>read-write</access>
                            <enumeratedValues>
                                <enumeratedValue>
                                    <name>0</name>
                                    <description>Interrupt generated when RX FIFO counter reaches RFIGCV value from values smaller than RFIGCV</description>
                                    <value>#0</value>
                                </enumeratedValue>
                                <enumeratedValue>
                                    <name>1</name>
                                    <description>Interrupt generated at the end of every received message storage</description>
                                    <value>#1</value>
                                </enumeratedValue>
                            </enumeratedValues>
                        </field>
                        <field>
                            <name>RFIGCV</name>
                            <description>RX FIFO Interrupt Generation Counter Value</description>
                            <lsb>13</lsb>
                            <msb>15</msb>
                            <access>read-write</access>
                            <enumeratedValues>
                                <enumeratedValue>
                                    <name>000</name>
                                    <description>Interrupt generated when FIFO is 1/8th full</description>
                                    <value>#000</value>
                                </enumeratedValue>
                                <enumeratedValue>
                                    <name>001</name>
                                    <description>Interrupt generated when FIFO is 1/4th full</description>
                                    <value>#001</value>
                                </enumeratedValue>
                                <enumeratedValue>
                                    <name>010</name>
                                    <description>Interrupt generated when FIFO is 3/8th full</description>
                                    <value>#010</value>
                                </enumeratedValue>
                                <enumeratedValue>
                                    <name>011</name>
                                    <description>Interrupt generated when FIFO is 1/2 full</description>
                                    <value>#011</value>
                                </enumeratedValue>
                                <enumeratedValue>
                                    <name>100</name>
                                    <description>Interrupt generated when FIFO is 5/8th full</description>
                                    <value>#100</value>
                                </enumeratedValue>
                                <enumeratedValue>
                                    <name>101</name>
                                    <description>Interrupt generated when FIFO is 3/4th full</description>
                                    <value>#101</value>
                                </enumeratedValue>
                                <enumeratedValue>
                                    <name>110</name>
                                    <description>Interrupt generated when FIFO is 7/8th full</description>
                                    <value>#110</value>
                                </enumeratedValue>
                                <enumeratedValue>
                                    <name>111</name>
                                    <description>Interrupt generated when FIFO is full</description>
                                    <value>#111</value>
                                </enumeratedValue>
                            </enumeratedValues>
                        </field>
                    </fields>
                </register>
                <register>
                    <dim>2</dim>
                    <dimIncrement>0x04</dimIncrement>
                    <dimIndex>0-1</dimIndex>
                    <name>CFDRFSTS%s</name>
                    <description>RX FIFO Status Registers %s</description>
                    <addressOffset>0x0044</addressOffset>
                    <size>32</size>
                    <access>read-write</access>
                    <resetValue>0x00000001</resetValue>
                    <resetMask>0xffffffff</resetMask>
                    <fields>
                        <field>
                            <name>RFEMP</name>
                            <description>RX FIFO Empty</description>
                            <lsb>0</lsb>
                            <msb>0</msb>
                            <access>read-only</access>
                            <enumeratedValues>
                                <enumeratedValue>
                                    <name>0</name>
                                    <description>FIFO not empty</description>
                                    <value>#0</value>
                                </enumeratedValue>
                                <enumeratedValue>
                                    <name>1</name>
                                    <description>FIFO empty</description>
                                    <value>#1</value>
                                </enumeratedValue>
                            </enumeratedValues>
                        </field>
                        <field>
                            <name>RFFLL</name>
                            <description>RX FIFO Full</description>
                            <lsb>1</lsb>
                            <msb>1</msb>
                            <access>read-only</access>
                            <enumeratedValues>
                                <enumeratedValue>
                                    <name>0</name>
                                    <description>FIFO not full</description>
                                    <value>#0</value>
                                </enumeratedValue>
                                <enumeratedValue>
                                    <name>1</name>
                                    <description>FIFO full</description>
                                    <value>#1</value>
                                </enumeratedValue>
                            </enumeratedValues>
                        </field>
                        <field>
                            <name>RFMLT</name>
                            <description>RX FIFO Message Lost</description>
                            <lsb>2</lsb>
                            <msb>2</msb>
                            <access>read-write</access>
                            <enumeratedValues>
                                <enumeratedValue>
                                    <name>0</name>
                                    <description>No message lost in FIFO</description>
                                    <value>#0</value>
                                </enumeratedValue>
                                <enumeratedValue>
                                    <name>1</name>
                                    <description>FIFO message lost</description>
                                    <value>#1</value>
                                </enumeratedValue>
                            </enumeratedValues>
                        </field>
                        <field>
                            <name>RFIF</name>
                            <description>RX FIFO Interrupt Flag</description>
                            <lsb>3</lsb>
                            <msb>3</msb>
                            <access>read-write</access>
                            <enumeratedValues>
                                <enumeratedValue>
                                    <name>0</name>
                                    <description>FIFO interrupt condition not satisfied</description>
                                    <value>#0</value>
                                </enumeratedValue>
                                <enumeratedValue>
                                    <name>1</name>
                                    <description>FIFO interrupt condition satisfied</description>
                                    <value>#1</value>
                                </enumeratedValue>
                            </enumeratedValues>
                        </field>
                        <field>
                            <name>RFMC</name>
                            <description>RX FIFO Message Count</description>
                            <lsb>8</lsb>
                            <msb>13</msb>
                            <access>read-only</access>
                        </field>
                    </fields>
                </register>
                <register>
                    <dim>2</dim>
                    <dimIncrement>0x04</dimIncrement>
                    <dimIndex>0-1</dimIndex>
                    <name>CFDRFPCTR%s</name>
                    <description>RX FIFO Pointer Control Registers %s</description>
                    <addressOffset>0x004C</addressOffset>
                    <size>32</size>
                    <access>write-only</access>
                    <resetValue>0x00000000</resetValue>
                    <resetMask>0xffffffff</resetMask>
                    <fields>
                        <field>
                            <name>RFPC</name>
                            <description>RX FIFO Pointer Control</description>
                            <lsb>0</lsb>
                            <msb>7</msb>
                            <access>write-only</access>
                        </field>
                    </fields>
                </register>
                <register>
                    <name>CFDCFCC</name>
                    <description>Common FIFO Configuration/Control Register</description>
                    <addressOffset>0x0054</addressOffset>
                    <size>32</size>
                    <access>read-write</access>
                    <resetValue>0x00000000</resetValue>
                    <resetMask>0xffffffff</resetMask>
                    <fields>
                        <field>
                            <name>CFE</name>
                            <description>Common FIFO Enable</description>
                            <lsb>0</lsb>
                            <msb>0</msb>
                            <access>read-write</access>
                            <enumeratedValues>
                                <enumeratedValue>
                                    <name>0</name>
                                    <description>FIFO disabled</description>
                                    <value>#0</value>
                                </enumeratedValue>
                                <enumeratedValue>
                                    <name>1</name>
                                    <description>FIFO enabled</description>
                                    <value>#1</value>
                                </enumeratedValue>
                            </enumeratedValues>
                        </field>
                        <field>
                            <name>CFRXIE</name>
                            <description>Common FIFO RX Interrupt Enable</description>
                            <lsb>1</lsb>
                            <msb>1</msb>
                            <access>read-write</access>
                            <enumeratedValues>
                                <enumeratedValue>
                                    <name>0</name>
                                    <description>FIFO interrupt generation disabled for Frame RX</description>
                                    <value>#0</value>
                                </enumeratedValue>
                                <enumeratedValue>
                                    <name>1</name>
                                    <description>FIFO interrupt generation enabled for Frame RX</description>
                                    <value>#1</value>
                                </enumeratedValue>
                            </enumeratedValues>
                        </field>
                        <field>
                            <name>CFTXIE</name>
                            <description>Common FIFO TX Interrupt Enable</description>
                            <lsb>2</lsb>
                            <msb>2</msb>
                            <access>read-write</access>
                            <enumeratedValues>
                                <enumeratedValue>
                                    <name>0</name>
                                    <description>FIFO interrupt generation disabled for Frame TX</description>
                                    <value>#0</value>
                                </enumeratedValue>
                                <enumeratedValue>
                                    <name>1</name>
                                    <description>FIFO interrupt generation enabled for Frame TX</description>
                                    <value>#1</value>
                                </enumeratedValue>
                            </enumeratedValues>
                        </field>
                        <field>
                            <name>CFPLS</name>
                            <description>Common FIFO Payload Data Size Configuration</description>
                            <lsb>4</lsb>
                            <msb>6</msb>
                            <access>read-write</access>
                            <enumeratedValues>
                                <enumeratedValue>
                                    <name>000</name>
                                    <description>8 bytes</description>
                                    <value>#000</value>
                                </enumeratedValue>
                                <enumeratedValue>
                                    <name>001</name>
                                    <description>12 bytes</description>
                                    <value>#001</value>
                                </enumeratedValue>
                                <enumeratedValue>
                                    <name>010</name>
                                    <description>16 bytes</description>
                                    <value>#010</value>
                                </enumeratedValue>
                                <enumeratedValue>
                                    <name>011</name>
                                    <description>20 bytes</description>
                                    <value>#011</value>
                                </enumeratedValue>
                                <enumeratedValue>
                                    <name>100</name>
                                    <description>24 bytes</description>
                                    <value>#100</value>
                                </enumeratedValue>
                                <enumeratedValue>
                                    <name>101</name>
                                    <description>32 bytes</description>
                                    <value>#101</value>
                                </enumeratedValue>
                                <enumeratedValue>
                                    <name>110</name>
                                    <description>48 bytes</description>
                                    <value>#110</value>
                                </enumeratedValue>
                                <enumeratedValue>
                                    <name>111</name>
                                    <description>64 bytes</description>
                                    <value>#111</value>
                                </enumeratedValue>
                            </enumeratedValues>
                        </field>
                        <field>
                            <name>CFM</name>
                            <description>Common FIFO Mode</description>
                            <lsb>8</lsb>
                            <msb>8</msb>
                            <access>read-write</access>
                            <enumeratedValues>
                                <enumeratedValue>
                                    <name>0</name>
                                    <description>RX FIFO mode</description>
                                    <value>#0</value>
                                </enumeratedValue>
                                <enumeratedValue>
                                    <name>1</name>
                                    <description>TX FIFO mode</description>
                                    <value>#1</value>
                                </enumeratedValue>
                            </enumeratedValues>
                        </field>
                        <field>
                            <name>CFITSS</name>
                            <description>Common FIFO Interval Timer Source Select</description>
                            <lsb>10</lsb>
                            <msb>10</msb>
                            <access>read-write</access>
                            <enumeratedValues>
                                <enumeratedValue>
                                    <name>0</name>
                                    <description>Reference clock (× 1 / × 10 period)</description>
                                    <value>#0</value>
                                </enumeratedValue>
                                <enumeratedValue>
                                    <name>1</name>
                                    <description>Bit time clock of related channel (FIFO is linked to fixed channel)</description>
                                    <value>#1</value>
                                </enumeratedValue>
                            </enumeratedValues>
                        </field>
                        <field>
                            <name>CFITR</name>
                            <description>Common FIFO Interval Timer Resolution</description>
                            <lsb>11</lsb>
                            <msb>11</msb>
                            <access>read-write</access>
                            <enumeratedValues>
                                <enumeratedValue>
                                    <name>0</name>
                                    <description>Reference clock period × 1</description>
                                    <value>#0</value>
                                </enumeratedValue>
                                <enumeratedValue>
                                    <name>1</name>
                                    <description>Reference clock period × 10</description>
                                    <value>#1</value>
                                </enumeratedValue>
                            </enumeratedValues>
                        </field>
                        <field>
                            <name>CFIM</name>
                            <description>Common FIFO Interrupt Mode</description>
                            <lsb>12</lsb>
                            <msb>12</msb>
                            <access>read-write</access>
                            <enumeratedValues>
                                <enumeratedValue>
                                    <name>0</name>
                                    <description>RX FIFO mode: RX interrupt generated when Common FIFO counter reaches CFIGCV value from a lower value TX FIFO mode: TX interrupt generated when Common FIFO transmits the last message successfully </description>
                                    <value>#0</value>
                                </enumeratedValue>
                                <enumeratedValue>
                                    <name>1</name>
                                    <description>RX FIFO mode: RX interrupt generated at the end of every received message storage TX FIFO mode: interrupt generated for every successfully transmitted message </description>
                                    <value>#1</value>
                                </enumeratedValue>
                            </enumeratedValues>
                        </field>
                        <field>
                            <name>CFIGCV</name>
                            <description>Common FIFO Interrupt Generation Counter Value</description>
                            <lsb>13</lsb>
                            <msb>15</msb>
                            <access>read-write</access>
                            <enumeratedValues>
                                <enumeratedValue>
                                    <name>000</name>
                                    <description>Interrupt generated when FIFO is 1/8th full</description>
                                    <value>#000</value>
                                </enumeratedValue>
                                <enumeratedValue>
                                    <name>001</name>
                                    <description>Interrupt generated when FIFO is 1/4th full</description>
                                    <value>#001</value>
                                </enumeratedValue>
                                <enumeratedValue>
                                    <name>010</name>
                                    <description>Interrupt generated when FIFO is 3/8th full</description>
                                    <value>#010</value>
                                </enumeratedValue>
                                <enumeratedValue>
                                    <name>011</name>
                                    <description>Interrupt generated when FIFO is 1/2 full</description>
                                    <value>#011</value>
                                </enumeratedValue>
                                <enumeratedValue>
                                    <name>100</name>
                                    <description>Interrupt generated when FIFO is 5/8th full</description>
                                    <value>#100</value>
                                </enumeratedValue>
                                <enumeratedValue>
                                    <name>101</name>
                                    <description>Interrupt generated when FIFO is 3/4th full</description>
                                    <value>#101</value>
                                </enumeratedValue>
                                <enumeratedValue>
                                    <name>110</name>
                                    <description>Interrupt generated when FIFO is 7/8th full</description>
                                    <value>#110</value>
                                </enumeratedValue>
                                <enumeratedValue>
                                    <name>111</name>
                                    <description>Interrupt generated when FIFO is full</description>
                                    <value>#111</value>
                                </enumeratedValue>
                            </enumeratedValues>
                        </field>
                        <field>
                            <name>CFTML</name>
                            <description>Common FIFO TX Message Buffer Link</description>
                            <lsb>16</lsb>
                            <msb>17</msb>
                            <access>read-write</access>
                        </field>
                        <field>
                            <name>CFDC</name>
                            <description>Common FIFO Depth Configuration</description>
                            <lsb>21</lsb>
                            <msb>23</msb>
                            <access>read-write</access>
                            <enumeratedValues>
                                <enumeratedValue>
                                    <name>000</name>
                                    <description>FIFO Depth = 0 message</description>
                                    <value>#000</value>
                                </enumeratedValue>
                                <enumeratedValue>
                                    <name>001</name>
                                    <description>FIFO Depth = 4 messages</description>
                                    <value>#001</value>
                                </enumeratedValue>
                                <enumeratedValue>
                                    <name>010</name>
                                    <description>FIFO Depth = 8 messages</description>
                                    <value>#010</value>
                                </enumeratedValue>
                                <enumeratedValue>
                                    <name>011</name>
                                    <description>FIFO Depth = 16 messages</description>
                                    <value>#011</value>
                                </enumeratedValue>
                                <enumeratedValue>
                                    <name>100</name>
                                    <description>FIFO Depth = 32 messages</description>
                                    <value>#100</value>
                                </enumeratedValue>
                                <enumeratedValue>
                                    <name>101</name>
                                    <description>FIFO Depth = 48 messages</description>
                                    <value>#101</value>
                                </enumeratedValue>
                                <enumeratedValue>
                                    <name>110</name>
                                    <description>FIFO Depth = Reserved</description>
                                    <value>#110</value>
                                </enumeratedValue>
                                <enumeratedValue>
                                    <name>111</name>
                                    <description>FIFO Depth = Reserved</description>
                                    <value>#111</value>
                                </enumeratedValue>
                            </enumeratedValues>
                        </field>
                        <field>
                            <name>CFITT</name>
                            <description>Common FIFO Interval Transmission Time</description>
                            <lsb>24</lsb>
                            <msb>31</msb>
                            <access>read-write</access>
                        </field>
                    </fields>
                </register>
                <register>
                    <name>CFDCFSTS</name>
                    <description>Common FIFO Status Register</description>
                    <addressOffset>0x0058</addressOffset>
                    <size>32</size>
                    <access>read-write</access>
                    <resetValue>0x00000001</resetValue>
                    <resetMask>0xffffffff</resetMask>
                    <fields>
                        <field>
                            <name>CFEMP</name>
                            <description>Common FIFO Empty</description>
                            <lsb>0</lsb>
                            <msb>0</msb>
                            <access>read-only</access>
                            <enumeratedValues>
                                <enumeratedValue>
                                    <name>0</name>
                                    <description>FIFO not empty</description>
                                    <value>#0</value>
                                </enumeratedValue>
                                <enumeratedValue>
                                    <name>1</name>
                                    <description>FIFO empty</description>
                                    <value>#1</value>
                                </enumeratedValue>
                            </enumeratedValues>
                        </field>
                        <field>
                            <name>CFFLL</name>
                            <description>Common FIFO Full</description>
                            <lsb>1</lsb>
                            <msb>1</msb>
                            <access>read-only</access>
                            <enumeratedValues>
                                <enumeratedValue>
                                    <name>0</name>
                                    <description>FIFO not full</description>
                                    <value>#0</value>
                                </enumeratedValue>
                                <enumeratedValue>
                                    <name>1</name>
                                    <description>FIFO full</description>
                                    <value>#1</value>
                                </enumeratedValue>
                            </enumeratedValues>
                        </field>
                        <field>
                            <name>CFMLT</name>
                            <description>Common FIFO Message Lost</description>
                            <lsb>2</lsb>
                            <msb>2</msb>
                            <access>read-write</access>
                            <enumeratedValues>
                                <enumeratedValue>
                                    <name>0</name>
                                    <description>Number of message lost in FIFO</description>
                                    <value>#0</value>
                                </enumeratedValue>
                                <enumeratedValue>
                                    <name>1</name>
                                    <description>FIFO message lost</description>
                                    <value>#1</value>
                                </enumeratedValue>
                            </enumeratedValues>
                        </field>
                        <field>
                            <name>CFRXIF</name>
                            <description>Common RX FIFO Interrupt Flag</description>
                            <lsb>3</lsb>
                            <msb>3</msb>
                            <access>read-write</access>
                            <enumeratedValues>
                                <enumeratedValue>
                                    <name>0</name>
                                    <description>FIFO interrupt condition not satisfied after frame reception</description>
                                    <value>#0</value>
                                </enumeratedValue>
                                <enumeratedValue>
                                    <name>1</name>
                                    <description>FIFO interrupt condition satisfied after frame reception</description>
                                    <value>#1</value>
                                </enumeratedValue>
                            </enumeratedValues>
                        </field>
                        <field>
                            <name>CFTXIF</name>
                            <description>Common TX FIFO Interrupt Flag</description>
                            <lsb>4</lsb>
                            <msb>4</msb>
                            <access>read-write</access>
                            <enumeratedValues>
                                <enumeratedValue>
                                    <name>0</name>
                                    <description>FIFO interrupt condition not satisfied after frame transmission</description>
                                    <value>#0</value>
                                </enumeratedValue>
                                <enumeratedValue>
                                    <name>1</name>
                                    <description>FIFO Interrupt condition satisfied after frame transmission</description>
                                    <value>#1</value>
                                </enumeratedValue>
                            </enumeratedValues>
                        </field>
                        <field>
                            <name>CFMC</name>
                            <description>Common FIFO Message Count</description>
                            <lsb>8</lsb>
                            <msb>13</msb>
                            <access>read-only</access>
                        </field>
                    </fields>
                </register>
                <register>
                    <name>CFDCFPCTR</name>
                    <description>Common FIFO Pointer Control Register</description>
                    <addressOffset>0x005C</addressOffset>
                    <size>32</size>
                    <access>write-only</access>
                    <resetValue>0x00000000</resetValue>
                    <resetMask>0xffffffff</resetMask>
                    <fields>
                        <field>
                            <name>CFPC</name>
                            <description>Common FIFO Pointer Control</description>
                            <lsb>0</lsb>
                            <msb>7</msb>
                            <access>write-only</access>
                        </field>
                    </fields>
                </register>
                <register>
                    <name>CFDFESTS</name>
                    <description>FIFO Empty Status Register</description>
                    <addressOffset>0x0060</addressOffset>
                    <size>32</size>
                    <access>read-only</access>
                    <resetValue>0x00000103</resetValue>
                    <resetMask>0xffffffff</resetMask>
                    <fields>
                        <field>
                            <name>RFXEMP</name>
                            <description>RX FIFO Empty Status</description>
                            <lsb>0</lsb>
                            <msb>1</msb>
                            <access>read-only</access>
                            <enumeratedValues>
                                <enumeratedValue>
                                    <name>0</name>
                                    <description>Corresponding FIFO not empty</description>
                                    <value>#0</value>
                                </enumeratedValue>
                                <enumeratedValue>
                                    <name>1</name>
                                    <description>Corresponding FIFO empty</description>
                                    <value>#1</value>
                                </enumeratedValue>
                            </enumeratedValues>
                        </field>
                        <field>
                            <name>CFEMP</name>
                            <description>Common FIFO Empty Status</description>
                            <lsb>8</lsb>
                            <msb>8</msb>
                            <access>read-only</access>
                            <enumeratedValues>
                                <enumeratedValue>
                                    <name>0</name>
                                    <description>Corresponding FIFO not empty</description>
                                    <value>#0</value>
                                </enumeratedValue>
                                <enumeratedValue>
                                    <name>1</name>
                                    <description>Corresponding FIFO empty</description>
                                    <value>#1</value>
                                </enumeratedValue>
                            </enumeratedValues>
                        </field>
                    </fields>
                </register>
                <register>
                    <name>CFDFFSTS</name>
                    <description>FIFO Full Status Register</description>
                    <addressOffset>0x0064</addressOffset>
                    <size>32</size>
                    <access>read-only</access>
                    <resetValue>0x00000000</resetValue>
                    <resetMask>0xffffffff</resetMask>
                    <fields>
                        <field>
                            <name>RFXFLL</name>
                            <description>RX FIF0 Full Status</description>
                            <lsb>0</lsb>
                            <msb>1</msb>
                            <access>read-only</access>
                            <enumeratedValues>
                                <enumeratedValue>
                                    <name>0</name>
                                    <description>Corresponding FIFO not full</description>
                                    <value>#0</value>
                                </enumeratedValue>
                                <enumeratedValue>
                                    <name>1</name>
                                    <description>Corresponding FIFO full</description>
                                    <value>#1</value>
                                </enumeratedValue>
                            </enumeratedValues>
                        </field>
                        <field>
                            <name>CFFLL</name>
                            <description>Common FIF0 Full Status</description>
                            <lsb>8</lsb>
                            <msb>8</msb>
                            <access>read-only</access>
                            <enumeratedValues>
                                <enumeratedValue>
                                    <name>0</name>
                                    <description>Corresponding FIFO not full</description>
                                    <value>#0</value>
                                </enumeratedValue>
                                <enumeratedValue>
                                    <name>1</name>
                                    <description>Corresponding FIFO full</description>
                                    <value>#1</value>
                                </enumeratedValue>
                            </enumeratedValues>
                        </field>
                    </fields>
                </register>
                <register>
                    <name>CFDFMSTS</name>
                    <description>FIFO Message Lost Status Register</description>
                    <addressOffset>0x0068</addressOffset>
                    <size>32</size>
                    <access>read-only</access>
                    <resetValue>0x00000000</resetValue>
                    <resetMask>0xffffffff</resetMask>
                    <fields>
                        <field>
                            <name>RFXMLT</name>
                            <description>RX FIFO Message Lost Status</description>
                            <lsb>0</lsb>
                            <msb>1</msb>
                            <access>read-only</access>
                            <enumeratedValues>
                                <enumeratedValue>
                                    <name>0</name>
                                    <description>Corresponding FIFO Message Lost flag not set</description>
                                    <value>#0</value>
                                </enumeratedValue>
                                <enumeratedValue>
                                    <name>1</name>
                                    <description>Corresponding FIFO Message Lost flag set</description>
                                    <value>#1</value>
                                </enumeratedValue>
                            </enumeratedValues>
                        </field>
                        <field>
                            <name>CFMLT</name>
                            <description>Common FIFO Message Lost Status</description>
                            <lsb>8</lsb>
                            <msb>8</msb>
                            <access>read-only</access>
                            <enumeratedValues>
                                <enumeratedValue>
                                    <name>0</name>
                                    <description>Corresponding FIFO Message Lost flag not set</description>
                                    <value>#0</value>
                                </enumeratedValue>
                                <enumeratedValue>
                                    <name>1</name>
                                    <description>Corresponding FIFO Message Lost flag set</description>
                                    <value>#1</value>
                                </enumeratedValue>
                            </enumeratedValues>
                        </field>
                    </fields>
                </register>
                <register>
                    <name>CFDRFISTS</name>
                    <description>RX FIFO Interrupt Flag Status Register</description>
                    <addressOffset>0x006C</addressOffset>
                    <size>32</size>
                    <access>read-only</access>
                    <resetValue>0x00000000</resetValue>
                    <resetMask>0xffffffff</resetMask>
                    <fields>
                        <field>
                            <name>RFXIF</name>
                            <description>RX FIFO[x] Interrupt Flag Status</description>
                            <lsb>0</lsb>
                            <msb>1</msb>
                            <access>read-only</access>
                            <enumeratedValues>
                                <enumeratedValue>
                                    <name>0</name>
                                    <description>Corresponding RX FIFO Interrupt flag not set</description>
                                    <value>#0</value>
                                </enumeratedValue>
                                <enumeratedValue>
                                    <name>1</name>
                                    <description>Corresponding RX FIFO Interrupt flag set</description>
                                    <value>#1</value>
                                </enumeratedValue>
                            </enumeratedValues>
                        </field>
                    </fields>
                </register>
                <register>
                    <dim>4</dim>
                    <dimIncrement>0x01</dimIncrement>
                    <dimIndex>0-3</dimIndex>
                    <name>CFDTMC%s</name>
                    <description>TX Message Buffer Control Registers %s</description>
                    <addressOffset>0x0070</addressOffset>
                    <size>8</size>
                    <access>read-write</access>
                    <resetValue>0x00</resetValue>
                    <resetMask>0xff</resetMask>
                    <fields>
                        <field>
                            <name>TMTR</name>
                            <description>TX Message Buffer Transmission Request</description>
                            <lsb>0</lsb>
                            <msb>0</msb>
                            <access>read-write</access>
                            <enumeratedValues>
                                <enumeratedValue>
                                    <name>0</name>
                                    <description>TX Message buffer transmission not requested</description>
                                    <value>#0</value>
                                </enumeratedValue>
                                <enumeratedValue>
                                    <name>1</name>
                                    <description>TX message buffer transmission requested</description>
                                    <value>#1</value>
                                </enumeratedValue>
                            </enumeratedValues>
                        </field>
                        <field>
                            <name>TMTAR</name>
                            <description>TX Message Buffer Transmission Abort Request</description>
                            <lsb>1</lsb>
                            <msb>1</msb>
                            <access>read-write</access>
                            <enumeratedValues>
                                <enumeratedValue>
                                    <name>0</name>
                                    <description>TX message buffer transmission request abort not requested</description>
                                    <value>#0</value>
                                </enumeratedValue>
                                <enumeratedValue>
                                    <name>1</name>
                                    <description>TX message buffer transmission request abort requested</description>
                                    <value>#1</value>
                                </enumeratedValue>
                            </enumeratedValues>
                        </field>
                        <field>
                            <name>TMOM</name>
                            <description>TX Message Buffer One-shot Mode</description>
                            <lsb>2</lsb>
                            <msb>2</msb>
                            <access>read-write</access>
                            <enumeratedValues>
                                <enumeratedValue>
                                    <name>0</name>
                                    <description>TX message buffer not configured in one-shot mode</description>
                                    <value>#0</value>
                                </enumeratedValue>
                                <enumeratedValue>
                                    <name>1</name>
                                    <description>TX message buffer configured in one-shot mode</description>
                                    <value>#1</value>
                                </enumeratedValue>
                            </enumeratedValues>
                        </field>
                    </fields>
                </register>
                <register>
                    <dim>4</dim>
                    <dimIncrement>0x01</dimIncrement>
                    <dimIndex>0-3</dimIndex>
                    <name>CFDTMSTS%s</name>
                    <description>TX Message Buffer Status Registers %s</description>
                    <addressOffset>0x0074</addressOffset>
                    <size>8</size>
                    <access>read-write</access>
                    <resetValue>0x00</resetValue>
                    <resetMask>0xff</resetMask>
                    <fields>
                        <field>
                            <name>TMTSTS</name>
                            <description>TX Message Buffer Transmission Status</description>
                            <lsb>0</lsb>
                            <msb>0</msb>
                            <access>read-only</access>
                            <enumeratedValues>
                                <enumeratedValue>
                                    <name>0</name>
                                    <description>No on-going transmission</description>
                                    <value>#0</value>
                                </enumeratedValue>
                                <enumeratedValue>
                                    <name>1</name>
                                    <description>On-going transmission</description>
                                    <value>#1</value>
                                </enumeratedValue>
                            </enumeratedValues>
                        </field>
                        <field>
                            <name>TMTRF</name>
                            <description>TX Message Buffer Transmission Result Flag</description>
                            <lsb>1</lsb>
                            <msb>2</msb>
                            <access>read-write</access>
                            <enumeratedValues>
                                <enumeratedValue>
                                    <name>00</name>
                                    <description>No result</description>
                                    <value>#00</value>
                                </enumeratedValue>
                                <enumeratedValue>
                                    <name>01</name>
                                    <description>Transmission aborted from the TX message buffer</description>
                                    <value>#01</value>
                                </enumeratedValue>
                                <enumeratedValue>
                                    <name>10</name>
                                    <description>Transmission successful from the TX message buffer and transmission abort was not requested</description>
                                    <value>#10</value>
                                </enumeratedValue>
                                <enumeratedValue>
                                    <name>11</name>
                                    <description>Transmission successful from the TX message buffer and transmission abort was requested</description>
                                    <value>#11</value>
                                </enumeratedValue>
                            </enumeratedValues>
                        </field>
                        <field>
                            <name>TMTRM</name>
                            <description>TX Message Buffer Transmission Request Mirrored</description>
                            <lsb>3</lsb>
                            <msb>3</msb>
                            <access>read-only</access>
                            <enumeratedValues>
                                <enumeratedValue>
                                    <name>0</name>
                                    <description>TX message buffer transmission not requested</description>
                                    <value>#0</value>
                                </enumeratedValue>
                                <enumeratedValue>
                                    <name>1</name>
                                    <description>TX message buffer transmission requested</description>
                                    <value>#1</value>
                                </enumeratedValue>
                            </enumeratedValues>
                        </field>
                        <field>
                            <name>TMTARM</name>
                            <description>TX Message Buffer Transmission Abort Request Mirrored</description>
                            <lsb>4</lsb>
                            <msb>4</msb>
                            <access>read-only</access>
                            <enumeratedValues>
                                <enumeratedValue>
                                    <name>0</name>
                                    <description>TX message buffer transmission request abort not requested</description>
                                    <value>#0</value>
                                </enumeratedValue>
                                <enumeratedValue>
                                    <name>1</name>
                                    <description>TX message buffer transmission request abort requested</description>
                                    <value>#1</value>
                                </enumeratedValue>
                            </enumeratedValues>
                        </field>
                    </fields>
                </register>
                <register>
                    <name>CFDTMTRSTS</name>
                    <description>TX Message Buffer Transmission Request Status Register</description>
                    <addressOffset>0x0078</addressOffset>
                    <size>32</size>
                    <access>read-only</access>
                    <resetValue>0x00000000</resetValue>
                    <resetMask>0xffffffff</resetMask>
                    <fields>
                        <field>
                            <name>CFDTMTRSTS</name>
                            <description>TX Message Buffer Transmission Request Status</description>
                            <lsb>0</lsb>
                            <msb>3</msb>
                            <access>read-only</access>
                            <enumeratedValues>
                                <enumeratedValue>
                                    <name>0</name>
                                    <description>Transmission not requested for corresponding TX message buffer</description>
                                    <value>#0</value>
                                </enumeratedValue>
                                <enumeratedValue>
                                    <name>1</name>
                                    <description>Transmission requested for corresponding TX message buffer</description>
                                    <value>#1</value>
                                </enumeratedValue>
                            </enumeratedValues>
                        </field>
                    </fields>
                </register>
                <register>
                    <name>CFDTMTARSTS</name>
                    <description>TX Message Buffer Transmission Abort Request Status Register</description>
                    <addressOffset>0x007C</addressOffset>
                    <size>32</size>
                    <access>read-only</access>
                    <resetValue>0x00000000</resetValue>
                    <resetMask>0xffffffff</resetMask>
                    <fields>
                        <field>
                            <name>CFDTMTARSTS</name>
                            <description>TX Message Buffer Transmission Abort Request Status</description>
                            <lsb>0</lsb>
                            <msb>3</msb>
                            <access>read-only</access>
                            <enumeratedValues>
                                <enumeratedValue>
                                    <name>0</name>
                                    <description>Transmission abort not requested for corresponding TX message buffer</description>
                                    <value>#0</value>
                                </enumeratedValue>
                                <enumeratedValue>
                                    <name>1</name>
                                    <description>Transmission abort requested for corresponding TX message buffer</description>
                                    <value>#1</value>
                                </enumeratedValue>
                            </enumeratedValues>
                        </field>
                    </fields>
                </register>
                <register>
                    <name>CFDTMTCSTS</name>
                    <description>TX Message Buffer Transmission Completion Status Register</description>
                    <addressOffset>0x0080</addressOffset>
                    <size>32</size>
                    <access>read-only</access>
                    <resetValue>0x00000000</resetValue>
                    <resetMask>0xffffffff</resetMask>
                    <fields>
                        <field>
                            <name>CFDTMTCSTS</name>
                            <description>TX Message Buffer Transmission Completion Status</description>
                            <lsb>0</lsb>
                            <msb>3</msb>
                            <access>read-only</access>
                            <enumeratedValues>
                                <enumeratedValue>
                                    <name>0</name>
                                    <description>Transmission not complete for corresponding TX message buffer</description>
                                    <value>#0</value>
                                </enumeratedValue>
                                <enumeratedValue>
                                    <name>1</name>
                                    <description>Transmission completed for corresponding TX message buffer</description>
                                    <value>#1</value>
                                </enumeratedValue>
                            </enumeratedValues>
                        </field>
                    </fields>
                </register>
                <register>
                    <name>CFDTMTASTS</name>
                    <description>TX Message Buffer Transmission Abort Status Register</description>
                    <addressOffset>0x0084</addressOffset>
                    <size>32</size>
                    <access>read-only</access>
                    <resetValue>0x00000000</resetValue>
                    <resetMask>0xffffffff</resetMask>
                    <fields>
                        <field>
                            <name>CFDTMTASTS</name>
                            <description>TX Message Buffer Transmission Abort Status</description>
                            <lsb>0</lsb>
                            <msb>3</msb>
                            <access>read-only</access>
                            <enumeratedValues>
                                <enumeratedValue>
                                    <name>0</name>
                                    <description>Transmission not aborted for corresponding TX message buffer</description>
                                    <value>#0</value>
                                </enumeratedValue>
                                <enumeratedValue>
                                    <name>1</name>
                                    <description>Transmission aborted for corresponding TX message buffer</description>
                                    <value>#1</value>
                                </enumeratedValue>
                            </enumeratedValues>
                        </field>
                    </fields>
                </register>
                <register>
                    <name>CFDTMIEC</name>
                    <description>TX Message Buffer Interrupt Enable Configuration Register</description>
                    <addressOffset>0x0088</addressOffset>
                    <size>32</size>
                    <access>read-write</access>
                    <resetValue>0x00000000</resetValue>
                    <resetMask>0xffffffff</resetMask>
                    <fields>
                        <field>
                            <name>TMIEg</name>
                            <description>TX Message Buffer Interrupt Enable</description>
                            <lsb>0</lsb>
                            <msb>3</msb>
                            <access>read-write</access>
                            <enumeratedValues>
                                <enumeratedValue>
                                    <name>0</name>
                                    <description>TX message buffer interrupt disabled for corresponding TX message buffer</description>
                                    <value>#0</value>
                                </enumeratedValue>
                                <enumeratedValue>
                                    <name>1</name>
                                    <description>TX message buffer interrupt enabled for corresponding TX message buffer</description>
                                    <value>#1</value>
                                </enumeratedValue>
                            </enumeratedValues>
                        </field>
                    </fields>
                </register>
                <register>
                    <name>CFDTXQCC</name>
                    <description>TX Queue Configuration/Control Register</description>
                    <addressOffset>0x008C</addressOffset>
                    <size>32</size>
                    <access>read-write</access>
                    <resetValue>0x00000000</resetValue>
                    <resetMask>0xffffffff</resetMask>
                    <fields>
                        <field>
                            <name>TXQE</name>
                            <description>TX Queue Enable</description>
                            <lsb>0</lsb>
                            <msb>0</msb>
                            <access>read-write</access>
                            <enumeratedValues>
                                <enumeratedValue>
                                    <name>0</name>
                                    <description>TX Queue disabled</description>
                                    <value>#0</value>
                                </enumeratedValue>
                                <enumeratedValue>
                                    <name>1</name>
                                    <description>TX Queue enabled</description>
                                    <value>#1</value>
                                </enumeratedValue>
                            </enumeratedValues>
                        </field>
                        <field>
                            <name>TXQTXIE</name>
                            <description>TX Queue TX Interrupt Enable</description>
                            <lsb>5</lsb>
                            <msb>5</msb>
                            <access>read-write</access>
                            <enumeratedValues>
                                <enumeratedValue>
                                    <name>0</name>
                                    <description>TX Queue TX interrupt disabled</description>
                                    <value>#0</value>
                                </enumeratedValue>
                                <enumeratedValue>
                                    <name>1</name>
                                    <description>TX Queue TX interrupt enabled</description>
                                    <value>#1</value>
                                </enumeratedValue>
                            </enumeratedValues>
                        </field>
                        <field>
                            <name>TXQIM</name>
                            <description>TX Queue Interrupt Mode</description>
                            <lsb>7</lsb>
                            <msb>7</msb>
                            <access>read-write</access>
                            <enumeratedValues>
                                <enumeratedValue>
                                    <name>0</name>
                                    <description>When the last message is successfully transmitted</description>
                                    <value>#0</value>
                                </enumeratedValue>
                                <enumeratedValue>
                                    <name>1</name>
                                    <description>At every successful transmission</description>
                                    <value>#1</value>
                                </enumeratedValue>
                            </enumeratedValues>
                        </field>
                        <field>
                            <name>TXQDC</name>
                            <description>TX Queue Depth Configuration</description>
                            <lsb>8</lsb>
                            <msb>9</msb>
                            <access>read-write</access>
                            <enumeratedValues>
                                <enumeratedValue>
                                    <name>0x00</name>
                                    <description>0 messages</description>
                                    <value>0x00</value>
                                </enumeratedValue>
                                <enumeratedValue>
                                    <name>0x01</name>
                                    <description>Reserved</description>
                                    <value>0x01</value>
                                </enumeratedValue>
                                <enumeratedValue>
                                    <name>0x10</name>
                                    <description>3 messages</description>
                                    <value>0x10</value>
                                </enumeratedValue>
                                <enumeratedValue>
                                    <name>0x11</name>
                                    <description>4 messages</description>
                                    <value>0x11</value>
                                </enumeratedValue>
                            </enumeratedValues>
                        </field>
                    </fields>
                </register>
                <register>
                    <name>CFDTXQSTS</name>
                    <description>TX Queue Status Register</description>
                    <addressOffset>0x0090</addressOffset>
                    <size>32</size>
                    <access>read-write</access>
                    <resetValue>0x00000001</resetValue>
                    <resetMask>0xffffffff</resetMask>
                    <fields>
                        <field>
                            <name>TXQEMP</name>
                            <description>TX Queue Empty</description>
                            <lsb>0</lsb>
                            <msb>0</msb>
                            <access>read-only</access>
                            <enumeratedValues>
                                <enumeratedValue>
                                    <name>0</name>
                                    <description>TX Queue not empty</description>
                                    <value>#0</value>
                                </enumeratedValue>
                                <enumeratedValue>
                                    <name>1</name>
                                    <description>TX Queue empty</description>
                                    <value>#1</value>
                                </enumeratedValue>
                            </enumeratedValues>
                        </field>
                        <field>
                            <name>TXQFLL</name>
                            <description>TX Queue Full</description>
                            <lsb>1</lsb>
                            <msb>1</msb>
                            <access>read-only</access>
                            <enumeratedValues>
                                <enumeratedValue>
                                    <name>0</name>
                                    <description>TX Queue not full</description>
                                    <value>#0</value>
                                </enumeratedValue>
                                <enumeratedValue>
                                    <name>1</name>
                                    <description>TX Queue full</description>
                                    <value>#1</value>
                                </enumeratedValue>
                            </enumeratedValues>
                        </field>
                        <field>
                            <name>TXQTXIF</name>
                            <description>TX Queue TX Interrupt Flag</description>
                            <lsb>2</lsb>
                            <msb>2</msb>
                            <access>read-write</access>
                            <enumeratedValues>
                                <enumeratedValue>
                                    <name>0</name>
                                    <description>TX Queue interrupt condition not satisfied after a frame TX</description>
                                    <value>#0</value>
                                </enumeratedValue>
                                <enumeratedValue>
                                    <name>1</name>
                                    <description>TX Queue interrupt condition satisfied after a frame TX</description>
                                    <value>#1</value>
                                </enumeratedValue>
                            </enumeratedValues>
                        </field>
                        <field>
                            <name>TXQMC</name>
                            <description>TX Queue Message Count</description>
                            <lsb>8</lsb>
                            <msb>10</msb>
                            <access>read-only</access>
                        </field>
                    </fields>
                </register>
                <register>
                    <name>CFDTXQPCTR</name>
                    <description>TX Queue Pointer Control Register</description>
                    <addressOffset>0x0094</addressOffset>
                    <size>32</size>
                    <access>write-only</access>
                    <resetValue>0x00000000</resetValue>
                    <resetMask>0xffffffff</resetMask>
                    <fields>
                        <field>
                            <name>TXQPC</name>
                            <description>TX Queue Pointer Control</description>
                            <lsb>0</lsb>
                            <msb>7</msb>
                            <access>write-only</access>
                        </field>
                    </fields>
                </register>
                <register>
                    <name>CFDTHLCC</name>
                    <description>TX History List Configuration/Control Register</description>
                    <addressOffset>0x0098</addressOffset>
                    <size>32</size>
                    <access>read-write</access>
                    <resetValue>0x00000000</resetValue>
                    <resetMask>0xffffffff</resetMask>
                    <fields>
                        <field>
                            <name>THLE</name>
                            <description>TX History List Enable</description>
                            <lsb>0</lsb>
                            <msb>0</msb>
                            <access>read-write</access>
                            <enumeratedValues>
                                <enumeratedValue>
                                    <name>0</name>
                                    <description>TX History List disabled</description>
                                    <value>#0</value>
                                </enumeratedValue>
                                <enumeratedValue>
                                    <name>1</name>
                                    <description>TX History List enabled</description>
                                    <value>#1</value>
                                </enumeratedValue>
                            </enumeratedValues>
                        </field>
                        <field>
                            <name>THLIE</name>
                            <description>TX History List Interrupt Enable</description>
                            <lsb>8</lsb>
                            <msb>8</msb>
                            <access>read-write</access>
                            <enumeratedValues>
                                <enumeratedValue>
                                    <name>0</name>
                                    <description>TX History List Interrupt disabled</description>
                                    <value>#0</value>
                                </enumeratedValue>
                                <enumeratedValue>
                                    <name>1</name>
                                    <description>TX History List Interrupt enabled</description>
                                    <value>#1</value>
                                </enumeratedValue>
                            </enumeratedValues>
                        </field>
                        <field>
                            <name>THLIM</name>
                            <description>TX History List Interrupt Mode</description>
                            <lsb>9</lsb>
                            <msb>9</msb>
                            <access>read-write</access>
                            <enumeratedValues>
                                <enumeratedValue>
                                    <name>0</name>
                                    <description>Interrupt generated if TX History List level reaches ¾ of the TX History List depth</description>
                                    <value>#0</value>
                                </enumeratedValue>
                                <enumeratedValue>
                                    <name>1</name>
                                    <description>Interrupt generated for every successfully stored entry</description>
                                    <value>#1</value>
                                </enumeratedValue>
                            </enumeratedValues>
                        </field>
                        <field>
                            <name>THLDTE</name>
                            <description>TX History List Dedicated TX Enable</description>
                            <lsb>10</lsb>
                            <msb>10</msb>
                            <access>read-write</access>
                            <enumeratedValues>
                                <enumeratedValue>
                                    <name>0</name>
                                    <description>TX FIFO + TX Queue</description>
                                    <value>#0</value>
                                </enumeratedValue>
                                <enumeratedValue>
                                    <name>1</name>
                                    <description>Flat TX MB + TX FIFO + TX Queue</description>
                                    <value>#1</value>
                                </enumeratedValue>
                            </enumeratedValues>
                        </field>
                    </fields>
                </register>
                <register>
                    <name>CFDTHLSTS</name>
                    <description>TX History List Status Register</description>
                    <addressOffset>0x009C</addressOffset>
                    <size>32</size>
                    <access>read-write</access>
                    <resetValue>0x00000001</resetValue>
                    <resetMask>0xffffffff</resetMask>
                    <fields>
                        <field>
                            <name>THLEMP</name>
                            <description>TX History List Empty</description>
                            <lsb>0</lsb>
                            <msb>0</msb>
                            <access>read-only</access>
                            <enumeratedValues>
                                <enumeratedValue>
                                    <name>0</name>
                                    <description>TX History List not empty</description>
                                    <value>#0</value>
                                </enumeratedValue>
                                <enumeratedValue>
                                    <name>1</name>
                                    <description>TX History List empty</description>
                                    <value>#1</value>
                                </enumeratedValue>
                            </enumeratedValues>
                        </field>
                        <field>
                            <name>THLFLL</name>
                            <description>TX History List Full</description>
                            <lsb>1</lsb>
                            <msb>1</msb>
                            <access>read-only</access>
                            <enumeratedValues>
                                <enumeratedValue>
                                    <name>0</name>
                                    <description>TX History List not full</description>
                                    <value>#0</value>
                                </enumeratedValue>
                                <enumeratedValue>
                                    <name>1</name>
                                    <description>TX History List full</description>
                                    <value>#1</value>
                                </enumeratedValue>
                            </enumeratedValues>
                        </field>
                        <field>
                            <name>THLELT</name>
                            <description>TX History List Entry Lost</description>
                            <lsb>2</lsb>
                            <msb>2</msb>
                            <access>read-write</access>
                            <enumeratedValues>
                                <enumeratedValue>
                                    <name>0</name>
                                    <description>No entry lost in TX History List</description>
                                    <value>#0</value>
                                </enumeratedValue>
                                <enumeratedValue>
                                    <name>1</name>
                                    <description>TX History List entry Lost</description>
                                    <value>#1</value>
                                </enumeratedValue>
                            </enumeratedValues>
                        </field>
                        <field>
                            <name>THLIF</name>
                            <description>TX History List Interrupt Flag</description>
                            <lsb>3</lsb>
                            <msb>3</msb>
                            <access>read-write</access>
                            <enumeratedValues>
                                <enumeratedValue>
                                    <name>0</name>
                                    <description>TX History List interrupt condition not satisfied</description>
                                    <value>#0</value>
                                </enumeratedValue>
                                <enumeratedValue>
                                    <name>1</name>
                                    <description>TX History List interrupt condition satisfied</description>
                                    <value>#1</value>
                                </enumeratedValue>
                            </enumeratedValues>
                        </field>
                        <field>
                            <name>THLMC</name>
                            <description>TX History List Message Count</description>
                            <lsb>8</lsb>
                            <msb>11</msb>
                            <access>read-only</access>
                        </field>
                    </fields>
                </register>
                <register>
                    <name>CFDTHLPCTR</name>
                    <description>TX History List Pointer Control Register</description>
                    <addressOffset>0x00A0</addressOffset>
                    <size>32</size>
                    <access>write-only</access>
                    <resetValue>0x00000000</resetValue>
                    <resetMask>0xffffffff</resetMask>
                    <fields>
                        <field>
                            <name>THLPC</name>
                            <description>TX History List Pointer Control</description>
                            <lsb>0</lsb>
                            <msb>7</msb>
                            <access>write-only</access>
                        </field>
                    </fields>
                </register>
                <register>
                    <name>CFDGTINTSTS</name>
                    <description>Global TX Interrupt Status Register</description>
                    <addressOffset>0x00A4</addressOffset>
                    <size>32</size>
                    <access>read-only</access>
                    <resetValue>0x00000000</resetValue>
                    <resetMask>0xffffffff</resetMask>
                    <fields>
                        <field>
                            <name>TSIF0</name>
                            <description>TX Successful Interrupt Flag</description>
                            <lsb>0</lsb>
                            <msb>0</msb>
                            <access>read-only</access>
                            <enumeratedValues>
                                <enumeratedValue>
                                    <name>0</name>
                                    <description>Channel n TX Successful Interrupt flag not set</description>
                                    <value>#0</value>
                                </enumeratedValue>
                                <enumeratedValue>
                                    <name>1</name>
                                    <description>Channel n TX Successful Interrupt flag set</description>
                                    <value>#1</value>
                                </enumeratedValue>
                            </enumeratedValues>
                        </field>
                        <field>
                            <name>TAI0</name>
                            <description>TX Abort Interrupt Flag</description>
                            <lsb>1</lsb>
                            <msb>1</msb>
                            <access>read-only</access>
                            <enumeratedValues>
                                <enumeratedValue>
                                    <name>0</name>
                                    <description>Channel n TX Abort Interrupt flag not set</description>
                                    <value>#0</value>
                                </enumeratedValue>
                                <enumeratedValue>
                                    <name>1</name>
                                    <description>Channel n TX Abort Interrupt flag set</description>
                                    <value>#1</value>
                                </enumeratedValue>
                            </enumeratedValues>
                        </field>
                        <field>
                            <name>TQIF0</name>
                            <description>TX Queue Interrupt Flag</description>
                            <lsb>2</lsb>
                            <msb>2</msb>
                            <access>read-only</access>
                            <enumeratedValues>
                                <enumeratedValue>
                                    <name>0</name>
                                    <description>Channel n TX Queue Interrupt flag not set</description>
                                    <value>#0</value>
                                </enumeratedValue>
                                <enumeratedValue>
                                    <name>1</name>
                                    <description>Channel n TX Queue Interrupt flag set</description>
                                    <value>#1</value>
                                </enumeratedValue>
                            </enumeratedValues>
                        </field>
                        <field>
                            <name>CFTIF0</name>
                            <description>COM FIFO TX Mode Interrupt Flag</description>
                            <lsb>3</lsb>
                            <msb>3</msb>
                            <access>read-only</access>
                            <enumeratedValues>
                                <enumeratedValue>
                                    <name>0</name>
                                    <description>Channel n COM FIFO TX Mode Interrupt flag not set</description>
                                    <value>#0</value>
                                </enumeratedValue>
                                <enumeratedValue>
                                    <name>1</name>
                                    <description>Channel n COM FIFO TX Mode Interrupt flag set</description>
                                    <value>#1</value>
                                </enumeratedValue>
                            </enumeratedValues>
                        </field>
                        <field>
                            <name>THIF0</name>
                            <description>TX History List Interrupt</description>
                            <lsb>4</lsb>
                            <msb>4</msb>
                            <access>read-only</access>
                            <enumeratedValues>
                                <enumeratedValue>
                                    <name>0</name>
                                    <description>Channel n TX History List Interrupt flag not set</description>
                                    <value>#0</value>
                                </enumeratedValue>
                                <enumeratedValue>
                                    <name>1</name>
                                    <description>Channel n TX History List Interrupt flag set</description>
                                    <value>#1</value>
                                </enumeratedValue>
                            </enumeratedValues>
                        </field>
                    </fields>
                </register>
                <register>
                    <name>CFDGTSTCFG</name>
                    <description>Global Test Configuration Register</description>
                    <addressOffset>0x00A8</addressOffset>
                    <size>32</size>
                    <access>read-write</access>
                    <resetValue>0x00000000</resetValue>
                    <resetMask>0xffffffff</resetMask>
                    <fields>
                        <field>
                            <name>RTMPS</name>
                            <description>RAM Test Mode Page Select</description>
                            <lsb>16</lsb>
                            <msb>19</msb>
                            <access>read-write</access>
                        </field>
                    </fields>
                </register>
                <register>
                    <name>CFDGTSTCTR</name>
                    <description>Global Test Control Register</description>
                    <addressOffset>0x00AC</addressOffset>
                    <size>32</size>
                    <access>read-write</access>
                    <resetValue>0x00000000</resetValue>
                    <resetMask>0xffffffff</resetMask>
                    <fields>
                        <field>
                            <name>RTME</name>
                            <description>RAM Test Mode Enable</description>
                            <lsb>2</lsb>
                            <msb>2</msb>
                            <access>read-write</access>
                            <enumeratedValues>
                                <enumeratedValue>
                                    <name>0</name>
                                    <description>RAM test mode disabled</description>
                                    <value>#0</value>
                                </enumeratedValue>
                                <enumeratedValue>
                                    <name>1</name>
                                    <description>RAM test mode enabled</description>
                                    <value>#1</value>
                                </enumeratedValue>
                            </enumeratedValues>
                        </field>
                    </fields>
                </register>
                <register>
                    <name>CFDGFDCFG</name>
                    <description>Global FD Configuration Register</description>
                    <addressOffset>0x00B0</addressOffset>
                    <size>32</size>
                    <access>read-write</access>
                    <resetValue>0x00000000</resetValue>
                    <resetMask>0xffffffff</resetMask>
                    <fields>
                        <field>
                            <name>RPED</name>
                            <description>RES Bit Protocol Exception Disable</description>
                            <lsb>0</lsb>
                            <msb>0</msb>
                            <access>read-write</access>
                            <enumeratedValues>
                                <enumeratedValue>
                                    <name>0</name>
                                    <description>Protocol exception event detection enabled</description>
                                    <value>#0</value>
                                </enumeratedValue>
                                <enumeratedValue>
                                    <name>1</name>
                                    <description>Protocol exception event detection disabled</description>
                                    <value>#1</value>
                                </enumeratedValue>
                            </enumeratedValues>
                        </field>
                        <field>
                            <name>TSCCFG</name>
                            <description>Timestamp Capture Configuration</description>
                            <lsb>8</lsb>
                            <msb>9</msb>
                            <access>read-write</access>
                            <enumeratedValues>
                                <enumeratedValue>
                                    <name>00</name>
                                    <description>Timestamp capture at the sample point of SOF (start of frame)</description>
                                    <value>#00</value>
                                </enumeratedValue>
                                <enumeratedValue>
                                    <name>01</name>
                                    <description>Timestamp capture at frame valid indication</description>
                                    <value>#01</value>
                                </enumeratedValue>
                                <enumeratedValue>
                                    <name>10</name>
                                    <description>Timestamp capture at the sample point of RES bit</description>
                                    <value>#10</value>
                                </enumeratedValue>
                                <enumeratedValue>
                                    <name>11</name>
                                    <description>Reserved</description>
                                    <value>#11</value>
                                </enumeratedValue>
                            </enumeratedValues>
                        </field>
                    </fields>
                </register>
                <register>
                    <name>CFDGLOCKK</name>
                    <description>Global Lock Key Register</description>
                    <addressOffset>0x00B8</addressOffset>
                    <size>32</size>
                    <access>write-only</access>
                    <resetValue>0x00000000</resetValue>
                    <resetMask>0xffffffff</resetMask>
                    <fields>
                        <field>
                            <name>LOCK</name>
                            <description>Lock Key</description>
                            <lsb>0</lsb>
                            <msb>15</msb>
                            <access>write-only</access>
                        </field>
                    </fields>
                </register>
                <register>
                    <name>CFDGAFLIGNENT</name>
                    <description>Global AFL Ignore Entry Register</description>
                    <addressOffset>0x00C0</addressOffset>
                    <size>32</size>
                    <access>read-write</access>
                    <resetValue>0x00000000</resetValue>
                    <resetMask>0xffffffff</resetMask>
                    <fields>
                        <field>
                            <name>IRN</name>
                            <description>Ignore Rule Number</description>
                            <lsb>0</lsb>
                            <msb>3</msb>
                            <access>read-write</access>
                        </field>
                    </fields>
                </register>
                <register>
                    <name>CFDGAFLIGNCTR</name>
                    <description>Global AFL Ignore Control Register</description>
                    <addressOffset>0x00C4</addressOffset>
                    <size>32</size>
                    <access>read-write</access>
                    <resetValue>0x00000000</resetValue>
                    <resetMask>0xffffffff</resetMask>
                    <fields>
                        <field>
                            <name>IREN</name>
                            <description>Ignore Rule Enable</description>
                            <lsb>0</lsb>
                            <msb>0</msb>
                            <access>read-write</access>
                            <enumeratedValues>
                                <enumeratedValue>
                                    <name>0</name>
                                    <description>AFL entry number is not ignored</description>
                                    <value>#0</value>
                                </enumeratedValue>
                                <enumeratedValue>
                                    <name>1</name>
                                    <description>AFL entry number is ignored</description>
                                    <value>#1</value>
                                </enumeratedValue>
                            </enumeratedValues>
                        </field>
                        <field>
                            <name>KEY</name>
                            <description>Key Code</description>
                            <lsb>8</lsb>
                            <msb>15</msb>
                            <access>write-only</access>
                        </field>
                    </fields>
                </register>
                <register>
                    <name>CFDCDTCT</name>
                    <description>DMA Transfer Control Register</description>
                    <addressOffset>0x00C8</addressOffset>
                    <size>32</size>
                    <access>read-write</access>
                    <resetValue>0x00000000</resetValue>
                    <resetMask>0xffffffff</resetMask>
                    <fields>
                        <field>
                            <name>RFDMAE0</name>
                            <description>DMA Transfer Enable for RXFIFO 0</description>
                            <lsb>0</lsb>
                            <msb>0</msb>
                            <access>read-write</access>
                            <enumeratedValues>
                                <enumeratedValue>
                                    <name>0</name>
                                    <description>DMA transfer request disabled</description>
                                    <value>#0</value>
                                </enumeratedValue>
                                <enumeratedValue>
                                    <name>1</name>
                                    <description>DMA transfer request enabled</description>
                                    <value>#1</value>
                                </enumeratedValue>
                            </enumeratedValues>
                        </field>
                        <field>
                            <name>RFDMAE1</name>
                            <description>DMA Transfer Enable for RXFIFO 1</description>
                            <lsb>1</lsb>
                            <msb>1</msb>
                            <access>read-write</access>
                            <enumeratedValues>
                                <enumeratedValue>
                                    <name>0</name>
                                    <description>DMA transfer request disabled</description>
                                    <value>#0</value>
                                </enumeratedValue>
                                <enumeratedValue>
                                    <name>1</name>
                                    <description>DMA transfer request enabled</description>
                                    <value>#1</value>
                                </enumeratedValue>
                            </enumeratedValues>
                        </field>
                        <field>
                            <name>CFDMAE</name>
                            <description>DMA Transfer Enable for Common FIFO 0</description>
                            <lsb>8</lsb>
                            <msb>8</msb>
                            <access>read-write</access>
                            <enumeratedValues>
                                <enumeratedValue>
                                    <name>0</name>
                                    <description>DMA transfer request disabled</description>
                                    <value>#0</value>
                                </enumeratedValue>
                                <enumeratedValue>
                                    <name>1</name>
                                    <description>DMA transfer request enabled</description>
                                    <value>#1</value>
                                </enumeratedValue>
                            </enumeratedValues>
                        </field>
                    </fields>
                </register>
                <register>
                    <name>CFDCDTSTS</name>
                    <description>DMA Transfer Status Register</description>
                    <addressOffset>0x00CC</addressOffset>
                    <size>32</size>
                    <access>read-only</access>
                    <resetValue>0x00000000</resetValue>
                    <resetMask>0xffffffff</resetMask>
                    <fields>
                        <field>
                            <name>RFDMASTS0</name>
                            <description>DMA Transfer Status for RX FIFO 0</description>
                            <lsb>0</lsb>
                            <msb>0</msb>
                            <access>read-only</access>
                            <enumeratedValues>
                                <enumeratedValue>
                                    <name>0</name>
                                    <description>DMA transfer stopped</description>
                                    <value>#0</value>
                                </enumeratedValue>
                                <enumeratedValue>
                                    <name>1</name>
                                    <description>DMA transfer on going</description>
                                    <value>#1</value>
                                </enumeratedValue>
                            </enumeratedValues>
                        </field>
                        <field>
                            <name>RFDMASTS1</name>
                            <description>DMA Transfer Status for RX FIFO 1</description>
                            <lsb>1</lsb>
                            <msb>1</msb>
                            <access>read-only</access>
                            <enumeratedValues>
                                <enumeratedValue>
                                    <name>0</name>
                                    <description>DMA transfer stopped</description>
                                    <value>#0</value>
                                </enumeratedValue>
                                <enumeratedValue>
                                    <name>1</name>
                                    <description>DMA transfer on going</description>
                                    <value>#1</value>
                                </enumeratedValue>
                            </enumeratedValues>
                        </field>
                        <field>
                            <name>CFDMASTS</name>
                            <description>DMA Transfer Status only for Common FIFO</description>
                            <lsb>8</lsb>
                            <msb>8</msb>
                            <access>read-only</access>
                            <enumeratedValues>
                                <enumeratedValue>
                                    <name>0</name>
                                    <description>DMA transfer stopped</description>
                                    <value>#0</value>
                                </enumeratedValue>
                                <enumeratedValue>
                                    <name>1</name>
                                    <description>DMA transfer on going</description>
                                    <value>#1</value>
                                </enumeratedValue>
                            </enumeratedValues>
                        </field>
                    </fields>
                </register>
                <register>
                    <name>CFDGRSTC</name>
                    <description>Global SW reset Register</description>
                    <addressOffset>0x00D8</addressOffset>
                    <size>32</size>
                    <access>read-write</access>
                    <resetValue>0x00000000</resetValue>
                    <resetMask>0xffffffff</resetMask>
                    <fields>
                        <field>
                            <name>SRST</name>
                            <description>SW Reset</description>
                            <lsb>0</lsb>
                            <msb>0</msb>
                            <access>read-write</access>
                            <enumeratedValues>
                                <enumeratedValue>
                                    <name>0</name>
                                    <description>Normal state</description>
                                    <value>#0</value>
                                </enumeratedValue>
                                <enumeratedValue>
                                    <name>1</name>
                                    <description>SW reset state</description>
                                    <value>#1</value>
                                </enumeratedValue>
                            </enumeratedValues>
                        </field>
                        <field>
                            <name>KEY</name>
                            <description>Key Code</description>
                            <lsb>8</lsb>
                            <msb>15</msb>
                            <access>write-only</access>
                        </field>
                    </fields>
                </register>
                <register>
                    <name>CFDC0DCFG</name>
                    <description> Data Bitrate Configuration Register</description>
                    <addressOffset>0x0100</addressOffset>
                    <size>32</size>
                    <access>read-write</access>
                    <resetValue>0x00000000</resetValue>
                    <resetMask>0xffffffff</resetMask>
                    <fields>
                        <field>
                            <name>DBRP</name>
                            <description>Channel Data Baud Rate Prescaler</description>
                            <lsb>0</lsb>
                            <msb>7</msb>
                            <access>read-write</access>
                        </field>
                        <field>
                            <name>DTSEG1</name>
                            <description>Timing Segment 1</description>
                            <lsb>8</lsb>
                            <msb>12</msb>
                            <access>read-write</access>
                        </field>
                        <field>
                            <name>DTSEG2</name>
                            <description>Timing Segment 2</description>
                            <lsb>16</lsb>
                            <msb>19</msb>
                            <access>read-write</access>
                        </field>
                        <field>
                            <name>DSJW</name>
                            <description>Resynchronization Jump Width</description>
                            <lsb>24</lsb>
                            <msb>27</msb>
                            <access>read-write</access>
                        </field>
                    </fields>
                </register>
                <register>
                    <name>CFDC0FDCFG</name>
                    <description>CANFD Configuration Register</description>
                    <addressOffset>0x0104</addressOffset>
                    <size>32</size>
                    <access>read-write</access>
                    <resetValue>0x00000000</resetValue>
                    <resetMask>0xbfffffff</resetMask>
                    <fields>
                        <field>
                            <name>EOCCFG</name>
                            <description>Error Occurrence Counter Configuration</description>
                            <lsb>0</lsb>
                            <msb>2</msb>
                            <access>read-write</access>
                            <enumeratedValues>
                                <enumeratedValue>
                                    <name>000</name>
                                    <description>All transmitter or receiver CAN frames</description>
                                    <value>#000</value>
                                </enumeratedValue>
                                <enumeratedValue>
                                    <name>001</name>
                                    <description>All transmitter CAN frames</description>
                                    <value>#001</value>
                                </enumeratedValue>
                                <enumeratedValue>
                                    <name>010</name>
                                    <description>All receiver CAN frames</description>
                                    <value>#010</value>
                                </enumeratedValue>
                                <enumeratedValue>
                                    <name>011</name>
                                    <description>Reserved</description>
                                    <value>#011</value>
                                </enumeratedValue>
                                <enumeratedValue>
                                    <name>100</name>
                                    <description>Only transmitter or receiver CANFD data-phase (fast bits)</description>
                                    <value>#100</value>
                                </enumeratedValue>
                                <enumeratedValue>
                                    <name>101</name>
                                    <description>Only transmitter CANFD data-phase (fast bits)</description>
                                    <value>#101</value>
                                </enumeratedValue>
                                <enumeratedValue>
                                    <name>110</name>
                                    <description>Only receiver CANFD data-phase (fast bits)</description>
                                    <value>#110</value>
                                </enumeratedValue>
                                <enumeratedValue>
                                    <name>111</name>
                                    <description>Reserved</description>
                                    <value>#111</value>
                                </enumeratedValue>
                            </enumeratedValues>
                        </field>
                        <field>
                            <name>TDCOC</name>
                            <description>Transceiver Delay Compensation Offset Configuration</description>
                            <lsb>8</lsb>
                            <msb>8</msb>
                            <access>read-write</access>
                            <enumeratedValues>
                                <enumeratedValue>
                                    <name>0</name>
                                    <description>Measured + offset</description>
                                    <value>#0</value>
                                </enumeratedValue>
                                <enumeratedValue>
                                    <name>1</name>
                                    <description>Offset-only</description>
                                    <value>#1</value>
                                </enumeratedValue>
                            </enumeratedValues>
                        </field>
                        <field>
                            <name>TDCE</name>
                            <description>Transceiver Delay Compensation Enable</description>
                            <lsb>9</lsb>
                            <msb>9</msb>
                            <access>read-write</access>
                            <enumeratedValues>
                                <enumeratedValue>
                                    <name>0</name>
                                    <description>Transceiver delay compensation disabled</description>
                                    <value>#0</value>
                                </enumeratedValue>
                                <enumeratedValue>
                                    <name>1</name>
                                    <description>Transceiver delay compensation enabled</description>
                                    <value>#1</value>
                                </enumeratedValue>
                            </enumeratedValues>
                        </field>
                        <field>
                            <name>ESIC</name>
                            <description>Error State Indication Configuration</description>
                            <lsb>10</lsb>
                            <msb>10</msb>
                            <access>read-write</access>
                            <enumeratedValues>
                                <enumeratedValue>
                                    <name>0</name>
                                    <description>The ESI bit in the frame represents the error state of the node itself</description>
                                    <value>#0</value>
                                </enumeratedValue>
                                <enumeratedValue>
                                    <name>1</name>
                                    <description>The ESI bit in the frame represents the error state of the message buffer if the node itself is not in error passive. If the node is in error passive, then the ESI bit is driven by the node itself.</description>
                                    <value>#1</value>
                                </enumeratedValue>
                            </enumeratedValues>
                        </field>
                        <field>
                            <name>TDCO</name>
                            <description>Transceiver Delay Compensation Offset</description>
                            <lsb>16</lsb>
                            <msb>23</msb>
                            <access>read-write</access>
                        </field>
                        <field>
                            <name>FDOE</name>
                            <description>FD-Only Enable</description>
                            <lsb>28</lsb>
                            <msb>28</msb>
                            <access>read-write</access>
                            <enumeratedValues>
                                <enumeratedValue>
                                    <name>0</name>
                                    <description>FD-only mode disabled</description>
                                    <value>#0</value>
                                </enumeratedValue>
                                <enumeratedValue>
                                    <name>1</name>
                                    <description>FD-only mode enabled</description>
                                    <value>#1</value>
                                </enumeratedValue>
                            </enumeratedValues>
                        </field>
                        <field>
                            <name>REFE</name>
                            <description>RX Edge Filter Enable</description>
                            <lsb>29</lsb>
                            <msb>29</msb>
                            <access>read-write</access>
                            <enumeratedValues>
                                <enumeratedValue>
                                    <name>0</name>
                                    <description>RX edge filter disabled</description>
                                    <value>#0</value>
                                </enumeratedValue>
                                <enumeratedValue>
                                    <name>1</name>
                                    <description>RX edge filter enabled</description>
                                    <value>#1</value>
                                </enumeratedValue>
                            </enumeratedValues>
                        </field>
                        <field>
                            <name>CLOE</name>
                            <description>Classical CAN Enable</description>
                            <lsb>30</lsb>
                            <msb>30</msb>
                            <access>read-write</access>
                            <enumeratedValues>
                                <enumeratedValue>
                                    <name>0</name>
                                    <description>Classical CAN mode disabled</description>
                                    <value>#0</value>
                                </enumeratedValue>
                                <enumeratedValue>
                                    <name>1</name>
                                    <description>Classical CAN mode enabled</description>
                                    <value>#1</value>
                                </enumeratedValue>
                            </enumeratedValues>
                        </field>
                    </fields>
                </register>
                <register>
                    <name>CFDC0FDCTR</name>
                    <description>CANFD Control Register</description>
                    <addressOffset>0x0108</addressOffset>
                    <size>32</size>
                    <access>read-write</access>
                    <resetValue>0x00000000</resetValue>
                    <resetMask>0xffffffff</resetMask>
                    <fields>
                        <field>
                            <name>EOCCLR</name>
                            <description>Error Occurrence Counter Clear</description>
                            <lsb>0</lsb>
                            <msb>0</msb>
                            <access>read-write</access>
                            <enumeratedValues>
                                <enumeratedValue>
                                    <name>0</name>
                                    <description>No error occurrence counter clear</description>
                                    <value>#0</value>
                                </enumeratedValue>
                                <enumeratedValue>
                                    <name>1</name>
                                    <description>Clear error occurrence counter</description>
                                    <value>#1</value>
                                </enumeratedValue>
                            </enumeratedValues>
                        </field>
                        <field>
                            <name>SOCCLR</name>
                            <description>Successful Occurrence Counter Clear</description>
                            <lsb>1</lsb>
                            <msb>1</msb>
                            <access>read-write</access>
                            <enumeratedValues>
                                <enumeratedValue>
                                    <name>0</name>
                                    <description>No successful occurrence counter clear</description>
                                    <value>#0</value>
                                </enumeratedValue>
                                <enumeratedValue>
                                    <name>1</name>
                                    <description>Clear successful occurrence counter</description>
                                    <value>#1</value>
                                </enumeratedValue>
                            </enumeratedValues>
                        </field>
                    </fields>
                </register>
                <register>
                    <name>CFDC0FDSTS</name>
                    <description>CANFD Status Register</description>
                    <addressOffset>0x010C</addressOffset>
                    <size>32</size>
                    <access>read-write</access>
                    <resetValue>0x00000000</resetValue>
                    <resetMask>0xffffffff</resetMask>
                    <fields>
                        <field>
                            <name>TDCR</name>
                            <description>Transceiver Delay Compensation Result</description>
                            <lsb>0</lsb>
                            <msb>7</msb>
                            <access>read-only</access>
                        </field>
                        <field>
                            <name>EOCO</name>
                            <description>Error Occurrence Counter Overflow</description>
                            <lsb>8</lsb>
                            <msb>8</msb>
                            <access>read-write</access>
                            <enumeratedValues>
                                <enumeratedValue>
                                    <name>0</name>
                                    <description>Error occurrence counter has not overflowed</description>
                                    <value>#0</value>
                                </enumeratedValue>
                                <enumeratedValue>
                                    <name>1</name>
                                    <description>Error occurrence counter has overflowed</description>
                                    <value>#1</value>
                                </enumeratedValue>
                            </enumeratedValues>
                        </field>
                        <field>
                            <name>SOCO</name>
                            <description>Successful Occurrence Counter Overflow</description>
                            <lsb>9</lsb>
                            <msb>9</msb>
                            <access>read-write</access>
                            <enumeratedValues>
                                <enumeratedValue>
                                    <name>0</name>
                                    <description>Successful occurrence counter has not overflowed</description>
                                    <value>#0</value>
                                </enumeratedValue>
                                <enumeratedValue>
                                    <name>1</name>
                                    <description>Successful occurrence counter has overflowed</description>
                                    <value>#1</value>
                                </enumeratedValue>
                            </enumeratedValues>
                        </field>
                        <field>
                            <name>TDCVF</name>
                            <description>Transceiver Delay Compensation Violation Flag</description>
                            <lsb>15</lsb>
                            <msb>15</msb>
                            <access>read-write</access>
                            <enumeratedValues>
                                <enumeratedValue>
                                    <name>0</name>
                                    <description>Transceiver delay compensation violation has not occurred</description>
                                    <value>#0</value>
                                </enumeratedValue>
                                <enumeratedValue>
                                    <name>1</name>
                                    <description>Transceiver delay compensation violation has occurred</description>
                                    <value>#1</value>
                                </enumeratedValue>
                            </enumeratedValues>
                        </field>
                        <field>
                            <name>EOC</name>
                            <description>Error Occurrence Counter</description>
                            <lsb>16</lsb>
                            <msb>23</msb>
                            <access>read-only</access>
                        </field>
                        <field>
                            <name>SOC</name>
                            <description>Successful occurrence counter</description>
                            <lsb>24</lsb>
                            <msb>31</msb>
                            <access>read-only</access>
                        </field>
                    </fields>
                </register>
                <register>
                    <name>CFDC0FDCRC</name>
                    <description>CANFD CRC Register</description>
                    <addressOffset>0x0110</addressOffset>
                    <size>32</size>
                    <access>read-only</access>
                    <resetValue>0x00000000</resetValue>
                    <resetMask>0xffffffff</resetMask>
                    <fields>
                        <field>
                            <name>CRCREG</name>
                            <description>CRC Register value</description>
                            <lsb>0</lsb>
                            <msb>20</msb>
                            <access>read-only</access>
                        </field>
                        <field>
                            <name>SCNT</name>
                            <description>Stuff bit count</description>
                            <lsb>24</lsb>
                            <msb>27</msb>
                            <access>read-only</access>
                        </field>
                    </fields>
                </register>
                <register>
                    <dim>16</dim>
                    <dimIncrement>0x0010</dimIncrement>
                    <dimIndex>1-16</dimIndex>
                    <name>CFDGAFLID%s</name>
                    <description>Global Acceptance Filter List ID Registers</description>
                    <addressOffset>0x0120</addressOffset>
                    <size>32</size>
                    <access>read-write</access>
                    <resetValue>0x00000000</resetValue>
                    <resetMask>0xffffffff</resetMask>
                    <fields>
                        <field>
                            <name>GAFLID</name>
                            <description>Global Acceptance Filter List Entry ID Field</description>
                            <lsb>0</lsb>
                            <msb>28</msb>
                            <access>read-write</access>
                        </field>
                        <field>
                            <name>GAFLLB</name>
                            <description>Global Acceptance Filter List Entry Loopback Configuration</description>
                            <lsb>29</lsb>
                            <msb>29</msb>
                            <access>read-write</access>
                            <enumeratedValues>
                                <enumeratedValue>
                                    <name>0</name>
                                    <description>Global Acceptance Filter List entry ID for acceptance filtering with attribute RX</description>
                                    <value>#0</value>
                                </enumeratedValue>
                                <enumeratedValue>
                                    <name>1</name>
                                    <description>Global Acceptance Filter List entry ID for acceptance filtering with attribute TX</description>
                                    <value>#1</value>
                                </enumeratedValue>
                            </enumeratedValues>
                        </field>
                        <field>
                            <name>GAFLRTR</name>
                            <description>Global Acceptance Filter List Entry RTR Field</description>
                            <lsb>30</lsb>
                            <msb>30</msb>
                            <access>read-write</access>
                            <enumeratedValues>
                                <enumeratedValue>
                                    <name>0</name>
                                    <description>Data frame</description>
                                    <value>#0</value>
                                </enumeratedValue>
                                <enumeratedValue>
                                    <name>1</name>
                                    <description>Remote frame</description>
                                    <value>#1</value>
                                </enumeratedValue>
                            </enumeratedValues>
                        </field>
                        <field>
                            <name>GAFLIDE</name>
                            <description>Global Acceptance Filter List Entry IDE Field</description>
                            <lsb>31</lsb>
                            <msb>31</msb>
                            <access>read-write</access>
                            <enumeratedValues>
                                <enumeratedValue>
                                    <name>0</name>
                                    <description>Standard identifier of rule entry ID is valid for acceptance filtering</description>
                                    <value>#0</value>
                                </enumeratedValue>
                                <enumeratedValue>
                                    <name>1</name>
                                    <description>Extended identifier of rule entry ID is valid for acceptance filtering</description>
                                    <value>#1</value>
                                </enumeratedValue>
                            </enumeratedValues>
                        </field>
                    </fields>
                </register>
                <register>
                    <dim>16</dim>
                    <dimIncrement>0x0010</dimIncrement>
                    <dimIndex>1-16</dimIndex>
                    <name>CFDGAFLM%s</name>
                    <description>Global Acceptance Filter List Mask Registers</description>
                    <addressOffset>0x0124</addressOffset>
                    <size>32</size>
                    <access>read-write</access>
                    <resetValue>0x00000000</resetValue>
                    <resetMask>0xffffffff</resetMask>
                    <fields>
                        <field>
                            <name>GAFLIDM</name>
                            <description>Global Acceptance Filter List ID Mask Field</description>
                            <lsb>0</lsb>
                            <msb>28</msb>
                            <access>read-write</access>
                        </field>
                        <field>
                            <name>GAFLIFL1</name>
                            <description>Global Acceptance Filter List Information Label 1</description>
                            <lsb>29</lsb>
                            <msb>29</msb>
                            <access>read-write</access>
                        </field>
                        <field>
                            <name>GAFLRTRM</name>
                            <description>Global Acceptance Filter List Entry RTR Mask</description>
                            <lsb>30</lsb>
                            <msb>30</msb>
                            <access>read-write</access>
                            <enumeratedValues>
                                <enumeratedValue>
                                    <name>0</name>
                                    <description>RTR bit is not used for ID matching</description>
                                    <value>#0</value>
                                </enumeratedValue>
                                <enumeratedValue>
                                    <name>1</name>
                                    <description>RTR bit is used for ID matching</description>
                                    <value>#1</value>
                                </enumeratedValue>
                            </enumeratedValues>
                        </field>
                        <field>
                            <name>GAFLIDEM</name>
                            <description>Global Acceptance Filter List IDE Mask</description>
                            <lsb>31</lsb>
                            <msb>31</msb>
                            <access>read-write</access>
                            <enumeratedValues>
                                <enumeratedValue>
                                    <name>0</name>
                                    <description>IDE bit is not used for ID matching</description>
                                    <value>#0</value>
                                </enumeratedValue>
                                <enumeratedValue>
                                    <name>1</name>
                                    <description>IDE bit is used for ID matching</description>
                                    <value>#1</value>
                                </enumeratedValue>
                            </enumeratedValues>
                        </field>
                    </fields>
                </register>
                <register>
                    <dim>16</dim>
                    <dimIncrement>0x0010</dimIncrement>
                    <dimIndex>1-16</dimIndex>
                    <name>CFDGAFLP0%s</name>
                    <description>Global Acceptance Filter List Pointer 0 Registers</description>
                    <addressOffset>0x0128</addressOffset>
                    <size>32</size>
                    <access>read-write</access>
                    <resetValue>0x00000000</resetValue>
                    <resetMask>0xffffffff</resetMask>
                    <fields>
                        <field>
                            <name>GAFLDLC</name>
                            <description>Global Acceptance Filter List DLC Field</description>
                            <lsb>0</lsb>
                            <msb>3</msb>
                            <access>read-write</access>
                        </field>
                        <field>
                            <name>GAFLIFL0</name>
                            <description>Global Acceptance Filter List Information Label 0</description>
                            <lsb>7</lsb>
                            <msb>7</msb>
                            <access>read-write</access>
                        </field>
                        <field>
                            <name>GAFLRMDP</name>
                            <description>Global Acceptance Filter List RX Message Buffer Direction Pointer</description>
                            <lsb>8</lsb>
                            <msb>12</msb>
                            <access>read-write</access>
                        </field>
                        <field>
                            <name>GAFLRMV</name>
                            <description>Global Acceptance Filter List RX Message Buffer Valid</description>
                            <lsb>15</lsb>
                            <msb>15</msb>
                            <access>read-write</access>
                            <enumeratedValues>
                                <enumeratedValue>
                                    <name>0</name>
                                    <description>Single message buffer direction pointer is invalid</description>
                                    <value>#0</value>
                                </enumeratedValue>
                                <enumeratedValue>
                                    <name>1</name>
                                    <description>Single message buffer direction pointer is valid</description>
                                    <value>#1</value>
                                </enumeratedValue>
                            </enumeratedValues>
                        </field>
                        <field>
                            <name>GAFLPTR</name>
                            <description>Global Acceptance Filter List Pointer</description>
                            <lsb>16</lsb>
                            <msb>31</msb>
                            <access>read-write</access>
                        </field>
                    </fields>
                </register>
                <register>
                    <dim>16</dim>
                    <dimIncrement>0x0010</dimIncrement>
                    <dimIndex>1-16</dimIndex>
                    <name>CFDGAFLP1%s</name>
                    <description>Global Acceptance Filter List Pointer 1 Registers</description>
                    <addressOffset>0x012C</addressOffset>
                    <size>32</size>
                    <access>read-write</access>
                    <resetValue>0x00000000</resetValue>
                    <resetMask>0xffffffff</resetMask>
                    <fields>
                        <field>
                            <name>GAFLFDP0</name>
                            <description>Global Acceptance Filter List FIFO Direction Pointer</description>
                            <lsb>0</lsb>
                            <msb>0</msb>
                            <access>read-write</access>
                            <enumeratedValues>
                                <enumeratedValue>
                                    <name>0</name>
                                    <description>Disable RX FIFO 0 as target for reception</description>
                                    <value>#0</value>
                                </enumeratedValue>
                                <enumeratedValue>
                                    <name>1</name>
                                    <description>Enable RX FIFO 0 as target for reception</description>
                                    <value>#1</value>
                                </enumeratedValue>
                            </enumeratedValues>
                        </field>
                        <field>
                            <name>GAFLFDP1</name>
                            <description>Global Acceptance Filter List FIFO Direction Pointer</description>
                            <lsb>1</lsb>
                            <msb>1</msb>
                            <access>read-write</access>
                            <enumeratedValues>
                                <enumeratedValue>
                                    <name>0</name>
                                    <description>Disable RX FIFO 1 as target for reception</description>
                                    <value>#0</value>
                                </enumeratedValue>
                                <enumeratedValue>
                                    <name>1</name>
                                    <description>Enable RX FIFO 1 as target for reception</description>
                                    <value>#1</value>
                                </enumeratedValue>
                            </enumeratedValues>
                        </field>
                        <field>
                            <name>GAFLFDP8</name>
                            <description>Global Acceptance Filter List FIFO Direction Pointer</description>
                            <lsb>8</lsb>
                            <msb>8</msb>
                            <access>read-write</access>
                            <enumeratedValues>
                                <enumeratedValue>
                                    <name>0</name>
                                    <description>Disable Common FIFO as target for reception</description>
                                    <value>#0</value>
                                </enumeratedValue>
                                <enumeratedValue>
                                    <name>1</name>
                                    <description>Enable Common FIFO as target for reception</description>
                                    <value>#1</value>
                                </enumeratedValue>
                            </enumeratedValues>
                        </field>
                    </fields>
                </register>
                <register>
                    <dim>64</dim>
                    <dimIncrement>0x0004</dimIncrement>
                    <dimIndex>0-63</dimIndex>
                    <name>CFDRPGACC%s</name>
                    <description>RAM Test Page Access Registers %s</description>
                    <addressOffset>0x0280</addressOffset>
                    <size>32</size>
                    <access>read-write</access>
                    <resetValue>0x00000000</resetValue>
                    <resetMask>0xffffffff</resetMask>
                    <fields>
                        <field>
                            <name>RDTA</name>
                            <description>RAM Data Test Access</description>
                            <lsb>0</lsb>
                            <msb>31</msb>
                            <access>read-write</access>
                        </field>
                    </fields>
                </register>
                <register>
                    <dim>2</dim>
                    <dimIncrement>0x004C</dimIncrement>
                    <dimIndex>0-1</dimIndex>
                    <name>CFDRFID%s</name>
                    <description>RX FIFO Access ID Register %s</description>
                    <addressOffset>0x0520</addressOffset>
                    <size>32</size>
                    <access>read-only</access>
                    <resetValue>0x00000000</resetValue>
                    <resetMask>0xffffffff</resetMask>
                    <fields>
                        <field>
                            <name>RFID</name>
                            <description>RX FIFO Buffer ID Field</description>
                            <lsb>0</lsb>
                            <msb>28</msb>
                            <access>read-only</access>
                        </field>
                        <field>
                            <name>RFRTR</name>
                            <description>RX FIFO Buffer RTR bit</description>
                            <lsb>30</lsb>
                            <msb>30</msb>
                            <access>read-only</access>
                            <enumeratedValues>
                                <enumeratedValue>
                                    <name>0</name>
                                    <description>Data frame</description>
                                    <value>#0</value>
                                </enumeratedValue>
                                <enumeratedValue>
                                    <name>1</name>
                                    <description>Remote frame</description>
                                    <value>#1</value>
                                </enumeratedValue>
                            </enumeratedValues>
                        </field>
                        <field>
                            <name>RFIDE</name>
                            <description>RX FIFO Buffer IDE bit</description>
                            <lsb>31</lsb>
                            <msb>31</msb>
                            <access>read-only</access>
                            <enumeratedValues>
                                <enumeratedValue>
                                    <name>0</name>
                                    <description>STD-ID has been received</description>
                                    <value>#0</value>
                                </enumeratedValue>
                                <enumeratedValue>
                                    <name>1</name>
                                    <description>EXT-ID has been received</description>
                                    <value>#1</value>
                                </enumeratedValue>
                            </enumeratedValues>
                        </field>
                    </fields>
                </register>
                <register>
                    <dim>2</dim>
                    <dimIncrement>0x004C</dimIncrement>
                    <dimIndex>0-1</dimIndex>
                    <name>CFDRFPTR%s</name>
                    <description>RX FIFO Access Pointer Register %s</description>
                    <addressOffset>0x0524</addressOffset>
                    <size>32</size>
                    <access>read-only</access>
                    <resetValue>0x00000000</resetValue>
                    <resetMask>0xffffffff</resetMask>
                    <fields>
                        <field>
                            <name>RFTS</name>
                            <description>RX FIFO Timestamp Value</description>
                            <lsb>0</lsb>
                            <msb>15</msb>
                            <access>read-only</access>
                        </field>
                        <field>
                            <name>RFDLC</name>
                            <description>RX FIFO Buffer DLC Field</description>
                            <lsb>28</lsb>
                            <msb>31</msb>
                            <access>read-only</access>
                        </field>
                    </fields>
                </register>
                <register>
                    <dim>2</dim>
                    <dimIncrement>0x004C</dimIncrement>
                    <dimIndex>0-1</dimIndex>
                    <name>CFDRFFDSTS%s</name>
                    <description>RX FIFO Access CANFD Status Register %s</description>
                    <addressOffset>0x0528</addressOffset>
                    <size>32</size>
                    <access>read-only</access>
                    <resetValue>0x00000000</resetValue>
                    <resetMask>0xffffffff</resetMask>
                    <fields>
                        <field>
                            <name>RFESI</name>
                            <description>Error State Indicator bit</description>
                            <lsb>0</lsb>
                            <msb>0</msb>
                            <access>read-only</access>
                            <enumeratedValues>
                                <enumeratedValue>
                                    <name>0</name>
                                    <description>CANFD frame received from error active node</description>
                                    <value>#0</value>
                                </enumeratedValue>
                                <enumeratedValue>
                                    <name>1</name>
                                    <description>CANFD frame received from error passive node</description>
                                    <value>#1</value>
                                </enumeratedValue>
                            </enumeratedValues>
                        </field>
                        <field>
                            <name>RFBRS</name>
                            <description>Bit Rate Switch bit</description>
                            <lsb>1</lsb>
                            <msb>1</msb>
                            <access>read-only</access>
                            <enumeratedValues>
                                <enumeratedValue>
                                    <name>0</name>
                                    <description>CANFD frame received with no bit rate switch</description>
                                    <value>#0</value>
                                </enumeratedValue>
                                <enumeratedValue>
                                    <name>1</name>
                                    <description>CANFD frame received with bit rate switch</description>
                                    <value>#1</value>
                                </enumeratedValue>
                            </enumeratedValues>
                        </field>
                        <field>
                            <name>RFFDF</name>
                            <description>CAN FD Format bit</description>
                            <lsb>2</lsb>
                            <msb>2</msb>
                            <access>read-only</access>
                            <enumeratedValues>
                                <enumeratedValue>
                                    <name>0</name>
                                    <description>Non CANFD frame received</description>
                                    <value>#0</value>
                                </enumeratedValue>
                                <enumeratedValue>
                                    <name>1</name>
                                    <description>CANFD frame received</description>
                                    <value>#1</value>
                                </enumeratedValue>
                            </enumeratedValues>
                        </field>
                        <field>
                            <name>RFIFL</name>
                            <description>RX FIFO Buffer Information Label Field</description>
                            <lsb>8</lsb>
                            <msb>9</msb>
                            <access>read-only</access>
                        </field>
                        <field>
                            <name>CFDRFPTR</name>
                            <description>RX FIFO Buffer Pointer Field</description>
                            <lsb>16</lsb>
                            <msb>31</msb>
                            <access>read-only</access>
                        </field>
                    </fields>
                </register>
                <register>
                    <dim>2</dim>
                    <dimIncrement>0x04C</dimIncrement>
                    <dimIndex>0-1</dimIndex>
                    <name>CFDRFDF%s_0</name>
                    <description>RX FIFO Access Data Field 0 Register %s</description>
                    <addressOffset>0x052C</addressOffset>
                    <size>32</size>
                    <access>read-only</access>
                    <resetValue>0x00000000</resetValue>
                    <resetMask>0xffffffff</resetMask>
                    <fields>
                        <field>
                            <name>RFDB_LL</name>
                            <description>RX FIFO Buffer Data Byte (p × 4)</description>
                            <lsb>0</lsb>
                            <msb>7</msb>
                            <access>read-only</access>
                        </field>
                        <field>
                            <name>RFDB_LH</name>
                            <description>RX FIFO Buffer Data Byte ((p × 4) + 1)</description>
                            <lsb>8</lsb>
                            <msb>15</msb>
                            <access>read-only</access>
                        </field>
                        <field>
                            <name>RFDB_HL</name>
                            <description>RX FIFO Buffer Data Byte ((p × 4) + 2)</description>
                            <lsb>16</lsb>
                            <msb>23</msb>
                            <access>read-only</access>
                        </field>
                        <field>
                            <name>RFDB_HH</name>
                            <description>RX FIFO Buffer Data Byte ((p × 4) + 3)</description>
                            <lsb>24</lsb>
                            <msb>31</msb>
                            <access>read-only</access>
                        </field>
                    </fields>
                </register>
                <register>
                    <dim>2</dim>
                    <dimIncrement>0x04C</dimIncrement>
                    <dimIndex>0-1</dimIndex>
                    <name>CFDRFDF%s_1</name>
                    <description>RX FIFO Access Data Field 1 Register %s</description>
                    <addressOffset>0x0530</addressOffset>
                    <size>32</size>
                    <access>read-only</access>
                    <resetValue>0x00000000</resetValue>
                    <resetMask>0xffffffff</resetMask>
                    <fields>
                        <field>
                            <name>RFDB_LL</name>
                            <description>RX FIFO Buffer Data Byte (p × 4)</description>
                            <lsb>0</lsb>
                            <msb>7</msb>
                            <access>read-only</access>
                        </field>
                        <field>
                            <name>RFDB_LH</name>
                            <description>RX FIFO Buffer Data Byte ((p × 4) + 1)</description>
                            <lsb>8</lsb>
                            <msb>15</msb>
                            <access>read-only</access>
                        </field>
                        <field>
                            <name>RFDB_HL</name>
                            <description>RX FIFO Buffer Data Byte ((p × 4) + 2)</description>
                            <lsb>16</lsb>
                            <msb>23</msb>
                            <access>read-only</access>
                        </field>
                        <field>
                            <name>RFDB_HH</name>
                            <description>RX FIFO Buffer Data Byte ((p × 4) + 3)</description>
                            <lsb>24</lsb>
                            <msb>31</msb>
                            <access>read-only</access>
                        </field>
                    </fields>
                </register>
                <register>
                    <dim>2</dim>
                    <dimIncrement>0x04C</dimIncrement>
                    <dimIndex>0-1</dimIndex>
                    <name>CFDRFDF%s_2</name>
                    <description>RX FIFO Access Data Field 2 Register %s</description>
                    <addressOffset>0x0534</addressOffset>
                    <size>32</size>
                    <access>read-only</access>
                    <resetValue>0x00000000</resetValue>
                    <resetMask>0xffffffff</resetMask>
                    <fields>
                        <field>
                            <name>RFDB_LL</name>
                            <description>RX FIFO Buffer Data Byte (p × 4)</description>
                            <lsb>0</lsb>
                            <msb>7</msb>
                            <access>read-only</access>
                        </field>
                        <field>
                            <name>RFDB_LH</name>
                            <description>RX FIFO Buffer Data Byte ((p × 4) + 1)</description>
                            <lsb>8</lsb>
                            <msb>15</msb>
                            <access>read-only</access>
                        </field>
                        <field>
                            <name>RFDB_HL</name>
                            <description>RX FIFO Buffer Data Byte ((p × 4) + 2)</description>
                            <lsb>16</lsb>
                            <msb>23</msb>
                            <access>read-only</access>
                        </field>
                        <field>
                            <name>RFDB_HH</name>
                            <description>RX FIFO Buffer Data Byte ((p × 4) + 3)</description>
                            <lsb>24</lsb>
                            <msb>31</msb>
                            <access>read-only</access>
                        </field>
                    </fields>
                </register>
                <register>
                    <dim>2</dim>
                    <dimIncrement>0x04C</dimIncrement>
                    <dimIndex>0-1</dimIndex>
                    <name>CFDRFDF%s_3</name>
                    <description>RX FIFO Access Data Field 3 Register %s</description>
                    <addressOffset>0x0538</addressOffset>
                    <size>32</size>
                    <access>read-only</access>
                    <resetValue>0x00000000</resetValue>
                    <resetMask>0xffffffff</resetMask>
                    <fields>
                        <field>
                            <name>RFDB_LL</name>
                            <description>RX FIFO Buffer Data Byte (p × 4)</description>
                            <lsb>0</lsb>
                            <msb>7</msb>
                            <access>read-only</access>
                        </field>
                        <field>
                            <name>RFDB_LH</name>
                            <description>RX FIFO Buffer Data Byte ((p × 4) + 1)</description>
                            <lsb>8</lsb>
                            <msb>15</msb>
                            <access>read-only</access>
                        </field>
                        <field>
                            <name>RFDB_HL</name>
                            <description>RX FIFO Buffer Data Byte ((p × 4) + 2)</description>
                            <lsb>16</lsb>
                            <msb>23</msb>
                            <access>read-only</access>
                        </field>
                        <field>
                            <name>RFDB_HH</name>
                            <description>RX FIFO Buffer Data Byte ((p × 4) + 3)</description>
                            <lsb>24</lsb>
                            <msb>31</msb>
                            <access>read-only</access>
                        </field>
                    </fields>
                </register>
                <register>
                    <dim>2</dim>
                    <dimIncrement>0x04C</dimIncrement>
                    <dimIndex>0-1</dimIndex>
                    <name>CFDRFDF%s_4</name>
                    <description>RX FIFO Access Data Field 4 Register %s</description>
                    <addressOffset>0x053C</addressOffset>
                    <size>32</size>
                    <access>read-only</access>
                    <resetValue>0x00000000</resetValue>
                    <resetMask>0xffffffff</resetMask>
                    <fields>
                        <field>
                            <name>RFDB_LL</name>
                            <description>RX FIFO Buffer Data Byte (p × 4)</description>
                            <lsb>0</lsb>
                            <msb>7</msb>
                            <access>read-only</access>
                        </field>
                        <field>
                            <name>RFDB_LH</name>
                            <description>RX FIFO Buffer Data Byte ((p × 4) + 1)</description>
                            <lsb>8</lsb>
                            <msb>15</msb>
                            <access>read-only</access>
                        </field>
                        <field>
                            <name>RFDB_HL</name>
                            <description>RX FIFO Buffer Data Byte ((p × 4) + 2)</description>
                            <lsb>16</lsb>
                            <msb>23</msb>
                            <access>read-only</access>
                        </field>
                        <field>
                            <name>RFDB_HH</name>
                            <description>RX FIFO Buffer Data Byte ((p × 4) + 3)</description>
                            <lsb>24</lsb>
                            <msb>31</msb>
                            <access>read-only</access>
                        </field>
                    </fields>
                </register>
                <register>
                    <dim>2</dim>
                    <dimIncrement>0x04C</dimIncrement>
                    <dimIndex>0-1</dimIndex>
                    <name>CFDRFDF%s_5</name>
                    <description>RX FIFO Access Data Field 5 Register %s</description>
                    <addressOffset>0x0540</addressOffset>
                    <size>32</size>
                    <access>read-only</access>
                    <resetValue>0x00000000</resetValue>
                    <resetMask>0xffffffff</resetMask>
                    <fields>
                        <field>
                            <name>RFDB_LL</name>
                            <description>RX FIFO Buffer Data Byte (p × 4)</description>
                            <lsb>0</lsb>
                            <msb>7</msb>
                            <access>read-only</access>
                        </field>
                        <field>
                            <name>RFDB_LH</name>
                            <description>RX FIFO Buffer Data Byte ((p × 4) + 1)</description>
                            <lsb>8</lsb>
                            <msb>15</msb>
                            <access>read-only</access>
                        </field>
                        <field>
                            <name>RFDB_HL</name>
                            <description>RX FIFO Buffer Data Byte ((p × 4) + 2)</description>
                            <lsb>16</lsb>
                            <msb>23</msb>
                            <access>read-only</access>
                        </field>
                        <field>
                            <name>RFDB_HH</name>
                            <description>RX FIFO Buffer Data Byte ((p × 4) + 3)</description>
                            <lsb>24</lsb>
                            <msb>31</msb>
                            <access>read-only</access>
                        </field>
                    </fields>
                </register>
                <register>
                    <dim>2</dim>
                    <dimIncrement>0x04C</dimIncrement>
                    <dimIndex>0-1</dimIndex>
                    <name>CFDRFDF%s_6</name>
                    <description>RX FIFO Access Data Field 6 Register %s</description>
                    <addressOffset>0x0544</addressOffset>
                    <size>32</size>
                    <access>read-only</access>
                    <resetValue>0x00000000</resetValue>
                    <resetMask>0xffffffff</resetMask>
                    <fields>
                        <field>
                            <name>RFDB_LL</name>
                            <description>RX FIFO Buffer Data Byte (p × 4)</description>
                            <lsb>0</lsb>
                            <msb>7</msb>
                            <access>read-only</access>
                        </field>
                        <field>
                            <name>RFDB_LH</name>
                            <description>RX FIFO Buffer Data Byte ((p × 4) + 1)</description>
                            <lsb>8</lsb>
                            <msb>15</msb>
                            <access>read-only</access>
                        </field>
                        <field>
                            <name>RFDB_HL</name>
                            <description>RX FIFO Buffer Data Byte ((p × 4) + 2)</description>
                            <lsb>16</lsb>
                            <msb>23</msb>
                            <access>read-only</access>
                        </field>
                        <field>
                            <name>RFDB_HH</name>
                            <description>RX FIFO Buffer Data Byte ((p × 4) + 3)</description>
                            <lsb>24</lsb>
                            <msb>31</msb>
                            <access>read-only</access>
                        </field>
                    </fields>
                </register>
                <register>
                    <dim>2</dim>
                    <dimIncrement>0x04C</dimIncrement>
                    <dimIndex>0-1</dimIndex>
                    <name>CFDRFDF%s_7</name>
                    <description>RX FIFO Access Data Field 7 Register %s</description>
                    <addressOffset>0x0548</addressOffset>
                    <size>32</size>
                    <access>read-only</access>
                    <resetValue>0x00000000</resetValue>
                    <resetMask>0xffffffff</resetMask>
                    <fields>
                        <field>
                            <name>RFDB_LL</name>
                            <description>RX FIFO Buffer Data Byte (p × 4)</description>
                            <lsb>0</lsb>
                            <msb>7</msb>
                            <access>read-only</access>
                        </field>
                        <field>
                            <name>RFDB_LH</name>
                            <description>RX FIFO Buffer Data Byte ((p × 4) + 1)</description>
                            <lsb>8</lsb>
                            <msb>15</msb>
                            <access>read-only</access>
                        </field>
                        <field>
                            <name>RFDB_HL</name>
                            <description>RX FIFO Buffer Data Byte ((p × 4) + 2)</description>
                            <lsb>16</lsb>
                            <msb>23</msb>
                            <access>read-only</access>
                        </field>
                        <field>
                            <name>RFDB_HH</name>
                            <description>RX FIFO Buffer Data Byte ((p × 4) + 3)</description>
                            <lsb>24</lsb>
                            <msb>31</msb>
                            <access>read-only</access>
                        </field>
                    </fields>
                </register>
                <register>
                    <dim>2</dim>
                    <dimIncrement>0x04C</dimIncrement>
                    <dimIndex>0-1</dimIndex>
                    <name>CFDRFDF%s_8</name>
                    <description>RX FIFO Access Data Field 8 Register %s</description>
                    <addressOffset>0x054C</addressOffset>
                    <size>32</size>
                    <access>read-only</access>
                    <resetValue>0x00000000</resetValue>
                    <resetMask>0xffffffff</resetMask>
                    <fields>
                        <field>
                            <name>RFDB_LL</name>
                            <description>RX FIFO Buffer Data Byte (p × 4)</description>
                            <lsb>0</lsb>
                            <msb>7</msb>
                            <access>read-only</access>
                        </field>
                        <field>
                            <name>RFDB_LH</name>
                            <description>RX FIFO Buffer Data Byte ((p × 4) + 1)</description>
                            <lsb>8</lsb>
                            <msb>15</msb>
                            <access>read-only</access>
                        </field>
                        <field>
                            <name>RFDB_HL</name>
                            <description>RX FIFO Buffer Data Byte ((p × 4) + 2)</description>
                            <lsb>16</lsb>
                            <msb>23</msb>
                            <access>read-only</access>
                        </field>
                        <field>
                            <name>RFDB_HH</name>
                            <description>RX FIFO Buffer Data Byte ((p × 4) + 3)</description>
                            <lsb>24</lsb>
                            <msb>31</msb>
                            <access>read-only</access>
                        </field>
                    </fields>
                </register>
                <register>
                    <dim>2</dim>
                    <dimIncrement>0x04C</dimIncrement>
                    <dimIndex>0-1</dimIndex>
                    <name>CFDRFDF%s_9</name>
                    <description>RX FIFO Access Data Field 9 Register %s</description>
                    <addressOffset>0x0550</addressOffset>
                    <size>32</size>
                    <access>read-only</access>
                    <resetValue>0x00000000</resetValue>
                    <resetMask>0xffffffff</resetMask>
                    <fields>
                        <field>
                            <name>RFDB_LL</name>
                            <description>RX FIFO Buffer Data Byte (p × 4)</description>
                            <lsb>0</lsb>
                            <msb>7</msb>
                            <access>read-only</access>
                        </field>
                        <field>
                            <name>RFDB_LH</name>
                            <description>RX FIFO Buffer Data Byte ((p × 4) + 1)</description>
                            <lsb>8</lsb>
                            <msb>15</msb>
                            <access>read-only</access>
                        </field>
                        <field>
                            <name>RFDB_HL</name>
                            <description>RX FIFO Buffer Data Byte ((p × 4) + 2)</description>
                            <lsb>16</lsb>
                            <msb>23</msb>
                            <access>read-only</access>
                        </field>
                        <field>
                            <name>RFDB_HH</name>
                            <description>RX FIFO Buffer Data Byte ((p × 4) + 3)</description>
                            <lsb>24</lsb>
                            <msb>31</msb>
                            <access>read-only</access>
                        </field>
                    </fields>
                </register>
                <register>
                    <dim>2</dim>
                    <dimIncrement>0x04C</dimIncrement>
                    <dimIndex>0-1</dimIndex>
                    <name>CFDRFDF%s_10</name>
                    <description>RX FIFO Access Data Field 10 Register %s</description>
                    <addressOffset>0x0554</addressOffset>
                    <size>32</size>
                    <access>read-only</access>
                    <resetValue>0x00000000</resetValue>
                    <resetMask>0xffffffff</resetMask>
                    <fields>
                        <field>
                            <name>RFDB_LL</name>
                            <description>RX FIFO Buffer Data Byte (p × 4)</description>
                            <lsb>0</lsb>
                            <msb>7</msb>
                            <access>read-only</access>
                        </field>
                        <field>
                            <name>RFDB_LH</name>
                            <description>RX FIFO Buffer Data Byte ((p × 4) + 1)</description>
                            <lsb>8</lsb>
                            <msb>15</msb>
                            <access>read-only</access>
                        </field>
                        <field>
                            <name>RFDB_HL</name>
                            <description>RX FIFO Buffer Data Byte ((p × 4) + 2)</description>
                            <lsb>16</lsb>
                            <msb>23</msb>
                            <access>read-only</access>
                        </field>
                        <field>
                            <name>RFDB_HH</name>
                            <description>RX FIFO Buffer Data Byte ((p × 4) + 3)</description>
                            <lsb>24</lsb>
                            <msb>31</msb>
                            <access>read-only</access>
                        </field>
                    </fields>
                </register>
                <register>
                    <dim>2</dim>
                    <dimIncrement>0x04C</dimIncrement>
                    <dimIndex>0-1</dimIndex>
                    <name>CFDRFDF%s_11</name>
                    <description>RX FIFO Access Data Field 11 Register %s</description>
                    <addressOffset>0x0558</addressOffset>
                    <size>32</size>
                    <access>read-only</access>
                    <resetValue>0x00000000</resetValue>
                    <resetMask>0xffffffff</resetMask>
                    <fields>
                        <field>
                            <name>RFDB_LL</name>
                            <description>RX FIFO Buffer Data Byte (p × 4)</description>
                            <lsb>0</lsb>
                            <msb>7</msb>
                            <access>read-only</access>
                        </field>
                        <field>
                            <name>RFDB_LH</name>
                            <description>RX FIFO Buffer Data Byte ((p × 4) + 1)</description>
                            <lsb>8</lsb>
                            <msb>15</msb>
                            <access>read-only</access>
                        </field>
                        <field>
                            <name>RFDB_HL</name>
                            <description>RX FIFO Buffer Data Byte ((p × 4) + 2)</description>
                            <lsb>16</lsb>
                            <msb>23</msb>
                            <access>read-only</access>
                        </field>
                        <field>
                            <name>RFDB_HH</name>
                            <description>RX FIFO Buffer Data Byte ((p × 4) + 3)</description>
                            <lsb>24</lsb>
                            <msb>31</msb>
                            <access>read-only</access>
                        </field>
                    </fields>
                </register>
                <register>
                    <dim>2</dim>
                    <dimIncrement>0x04C</dimIncrement>
                    <dimIndex>0-1</dimIndex>
                    <name>CFDRFDF%s_12</name>
                    <description>RX FIFO Access Data Field 12 Register %s</description>
                    <addressOffset>0x055C</addressOffset>
                    <size>32</size>
                    <access>read-only</access>
                    <resetValue>0x00000000</resetValue>
                    <resetMask>0xffffffff</resetMask>
                    <fields>
                        <field>
                            <name>RFDB_LL</name>
                            <description>RX FIFO Buffer Data Byte (p × 4)</description>
                            <lsb>0</lsb>
                            <msb>7</msb>
                            <access>read-only</access>
                        </field>
                        <field>
                            <name>RFDB_LH</name>
                            <description>RX FIFO Buffer Data Byte ((p × 4) + 1)</description>
                            <lsb>8</lsb>
                            <msb>15</msb>
                            <access>read-only</access>
                        </field>
                        <field>
                            <name>RFDB_HL</name>
                            <description>RX FIFO Buffer Data Byte ((p × 4) + 2)</description>
                            <lsb>16</lsb>
                            <msb>23</msb>
                            <access>read-only</access>
                        </field>
                        <field>
                            <name>RFDB_HH</name>
                            <description>RX FIFO Buffer Data Byte ((p × 4) + 3)</description>
                            <lsb>24</lsb>
                            <msb>31</msb>
                            <access>read-only</access>
                        </field>
                    </fields>
                </register>
                <register>
                    <dim>2</dim>
                    <dimIncrement>0x04C</dimIncrement>
                    <dimIndex>0-1</dimIndex>
                    <name>CFDRFDF%s_13</name>
                    <description>RX FIFO Access Data Field 13 Register %s</description>
                    <addressOffset>0x0560</addressOffset>
                    <size>32</size>
                    <access>read-only</access>
                    <resetValue>0x00000000</resetValue>
                    <resetMask>0xffffffff</resetMask>
                    <fields>
                        <field>
                            <name>RFDB_LL</name>
                            <description>RX FIFO Buffer Data Byte (p × 4)</description>
                            <lsb>0</lsb>
                            <msb>7</msb>
                            <access>read-only</access>
                        </field>
                        <field>
                            <name>RFDB_LH</name>
                            <description>RX FIFO Buffer Data Byte ((p × 4) + 1)</description>
                            <lsb>8</lsb>
                            <msb>15</msb>
                            <access>read-only</access>
                        </field>
                        <field>
                            <name>RFDB_HL</name>
                            <description>RX FIFO Buffer Data Byte ((p × 4) + 2)</description>
                            <lsb>16</lsb>
                            <msb>23</msb>
                            <access>read-only</access>
                        </field>
                        <field>
                            <name>RFDB_HH</name>
                            <description>RX FIFO Buffer Data Byte ((p × 4) + 3)</description>
                            <lsb>24</lsb>
                            <msb>31</msb>
                            <access>read-only</access>
                        </field>
                    </fields>
                </register>
                <register>
                    <dim>2</dim>
                    <dimIncrement>0x04C</dimIncrement>
                    <dimIndex>0-1</dimIndex>
                    <name>CFDRFDF%s_14</name>
                    <description>RX FIFO Access Data Field 14 Register %s</description>
                    <addressOffset>0x0564</addressOffset>
                    <size>32</size>
                    <access>read-only</access>
                    <resetValue>0x00000000</resetValue>
                    <resetMask>0xffffffff</resetMask>
                    <fields>
                        <field>
                            <name>RFDB_LL</name>
                            <description>RX FIFO Buffer Data Byte (p × 4)</description>
                            <lsb>0</lsb>
                            <msb>7</msb>
                            <access>read-only</access>
                        </field>
                        <field>
                            <name>RFDB_LH</name>
                            <description>RX FIFO Buffer Data Byte ((p × 4) + 1)</description>
                            <lsb>8</lsb>
                            <msb>15</msb>
                            <access>read-only</access>
                        </field>
                        <field>
                            <name>RFDB_HL</name>
                            <description>RX FIFO Buffer Data Byte ((p × 4) + 2)</description>
                            <lsb>16</lsb>
                            <msb>23</msb>
                            <access>read-only</access>
                        </field>
                        <field>
                            <name>RFDB_HH</name>
                            <description>RX FIFO Buffer Data Byte ((p × 4) + 3)</description>
                            <lsb>24</lsb>
                            <msb>31</msb>
                            <access>read-only</access>
                        </field>
                    </fields>
                </register>
                <register>
                    <dim>2</dim>
                    <dimIncrement>0x04C</dimIncrement>
                    <dimIndex>0-1</dimIndex>
                    <name>CFDRFDF%s_15</name>
                    <description>RX FIFO Access Data Field 15 Register %s</description>
                    <addressOffset>0x0568</addressOffset>
                    <size>32</size>
                    <access>read-only</access>
                    <resetValue>0x00000000</resetValue>
                    <resetMask>0xffffffff</resetMask>
                    <fields>
                        <field>
                            <name>RFDB_LL</name>
                            <description>RX FIFO Buffer Data Byte (p × 4)</description>
                            <lsb>0</lsb>
                            <msb>7</msb>
                            <access>read-only</access>
                        </field>
                        <field>
                            <name>RFDB_LH</name>
                            <description>RX FIFO Buffer Data Byte ((p × 4) + 1)</description>
                            <lsb>8</lsb>
                            <msb>15</msb>
                            <access>read-only</access>
                        </field>
                        <field>
                            <name>RFDB_HL</name>
                            <description>RX FIFO Buffer Data Byte ((p × 4) + 2)</description>
                            <lsb>16</lsb>
                            <msb>23</msb>
                            <access>read-only</access>
                        </field>
                        <field>
                            <name>RFDB_HH</name>
                            <description>RX FIFO Buffer Data Byte ((p × 4) + 3)</description>
                            <lsb>24</lsb>
                            <msb>31</msb>
                            <access>read-only</access>
                        </field>
                    </fields>
                </register>
                <register>
                    <name>CFDCFID</name>
                    <description>Common FIFO Access ID Register</description>
                    <addressOffset>0x05B8</addressOffset>
                    <size>32</size>
                    <access>read-write</access>
                    <resetValue>0x00000000</resetValue>
                    <resetMask>0xffffffff</resetMask>
                    <fields>
                        <field>
                            <name>CFID</name>
                            <description>Common FIFO Buffer ID Field</description>
                            <lsb>0</lsb>
                            <msb>28</msb>
                            <access>read-write</access>
                        </field>
                        <field>
                            <name>THLEN</name>
                            <description>THL Entry enable</description>
                            <lsb>29</lsb>
                            <msb>29</msb>
                            <access>read-write</access>
                            <enumeratedValues>
                                <enumeratedValue>
                                    <name>0</name>
                                    <description>Entry will not be stored in THL after successful TX.</description>
                                    <value>#0</value>
                                </enumeratedValue>
                                <enumeratedValue>
                                    <name>1</name>
                                    <description>Entry will be stored in THL after successful TX.</description>
                                    <value>#1</value>
                                </enumeratedValue>
                            </enumeratedValues>
                        </field>
                        <field>
                            <name>CFRTR</name>
                            <description>Common FIFO Buffer RTR Bit</description>
                            <lsb>30</lsb>
                            <msb>30</msb>
                            <access>read-write</access>
                            <enumeratedValues>
                                <enumeratedValue>
                                    <name>0</name>
                                    <description>Data Frame</description>
                                    <value>#0</value>
                                </enumeratedValue>
                                <enumeratedValue>
                                    <name>1</name>
                                    <description>Remote Frame</description>
                                    <value>#1</value>
                                </enumeratedValue>
                            </enumeratedValues>
                        </field>
                        <field>
                            <name>CFIDE</name>
                            <description>Common FIFO Buffer IDE Bit</description>
                            <lsb>31</lsb>
                            <msb>31</msb>
                            <access>read-write</access>
                            <enumeratedValues>
                                <enumeratedValue>
                                    <name>0</name>
                                    <description>STD-ID will be transmitted or has been received</description>
                                    <value>#0</value>
                                </enumeratedValue>
                                <enumeratedValue>
                                    <name>1</name>
                                    <description>EXT-ID will be transmitted or has been received</description>
                                    <value>#1</value>
                                </enumeratedValue>
                            </enumeratedValues>
                        </field>
                    </fields>
                </register>
                <register>
                    <name>CFDCFPTR</name>
                    <description>Common FIFO Access Pointer Register</description>
                    <addressOffset>0x05BC</addressOffset>
                    <size>32</size>
                    <access>read-write</access>
                    <resetValue>0x00000000</resetValue>
                    <resetMask>0xffffffff</resetMask>
                    <fields>
                        <field>
                            <name>CFTS</name>
                            <description>Common FIFO Timestamp Value</description>
                            <lsb>0</lsb>
                            <msb>15</msb>
                            <access>read-write</access>
                        </field>
                        <field>
                            <name>CFDLC</name>
                            <description>Common FIFO Buffer DLC Field</description>
                            <lsb>28</lsb>
                            <msb>31</msb>
                            <access>read-write</access>
                        </field>
                    </fields>
                </register>
                <register>
                    <name>CFDCFFDCSTS</name>
                    <description>Common FIFO Access CANFD Control/Status Register</description>
                    <addressOffset>0x05C0</addressOffset>
                    <size>32</size>
                    <access>read-write</access>
                    <resetValue>0x00000000</resetValue>
                    <resetMask>0xffffffff</resetMask>
                    <fields>
                        <field>
                            <name>CFESI</name>
                            <description>Error State Indicator bit</description>
                            <lsb>0</lsb>
                            <msb>0</msb>
                            <access>read-write</access>
                            <enumeratedValues>
                                <enumeratedValue>
                                    <name>0</name>
                                    <description>CANFD frame received or to transmit by error active node</description>
                                    <value>#0</value>
                                </enumeratedValue>
                                <enumeratedValue>
                                    <name>1</name>
                                    <description>CANFD frame received or to transmit by error passive node</description>
                                    <value>#1</value>
                                </enumeratedValue>
                            </enumeratedValues>
                        </field>
                        <field>
                            <name>CFBRS</name>
                            <description>Bit Rate Switch bit</description>
                            <lsb>1</lsb>
                            <msb>1</msb>
                            <access>read-write</access>
                            <enumeratedValues>
                                <enumeratedValue>
                                    <name>0</name>
                                    <description>CANFD frame received or to transmit with no bit rate switch</description>
                                    <value>#0</value>
                                </enumeratedValue>
                                <enumeratedValue>
                                    <name>1</name>
                                    <description>CANFD frame received or to transmit with bit rate switch</description>
                                    <value>#1</value>
                                </enumeratedValue>
                            </enumeratedValues>
                        </field>
                        <field>
                            <name>CFFDF</name>
                            <description>CAN FD Format bit</description>
                            <lsb>2</lsb>
                            <msb>2</msb>
                            <access>read-write</access>
                            <enumeratedValues>
                                <enumeratedValue>
                                    <name>0</name>
                                    <description>Non CANFD frame received or to transmit</description>
                                    <value>#0</value>
                                </enumeratedValue>
                                <enumeratedValue>
                                    <name>1</name>
                                    <description>CANFD frame received or to transmit</description>
                                    <value>#1</value>
                                </enumeratedValue>
                            </enumeratedValues>
                        </field>
                        <field>
                            <name>CFIFL</name>
                            <description>COMMON FIFO Buffer Information Label Field</description>
                            <lsb>8</lsb>
                            <msb>9</msb>
                            <access>read-write</access>
                        </field>
                        <field>
                            <name>CFPTR</name>
                            <description>Common FIFO Buffer Pointer Field</description>
                            <lsb>16</lsb>
                            <msb>31</msb>
                            <access>read-write</access>
                        </field>
                    </fields>
                </register>
                <register>
                    <dim>16</dim>
                    <dimIncrement>0x004</dimIncrement>
                    <dimIndex>0-15</dimIndex>
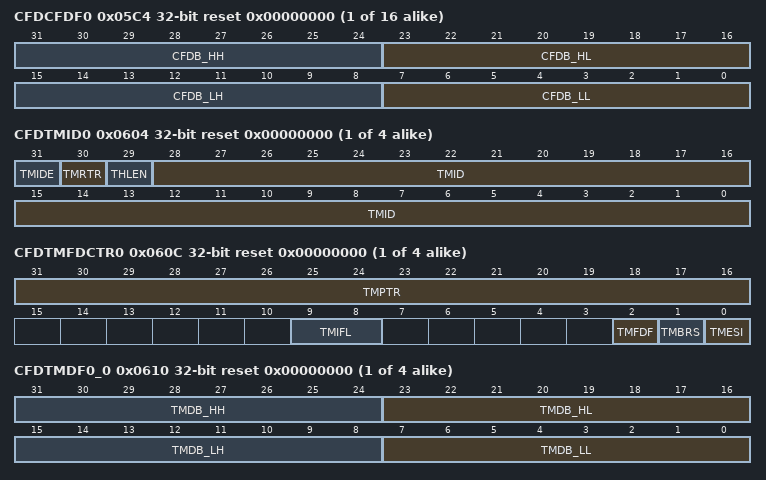
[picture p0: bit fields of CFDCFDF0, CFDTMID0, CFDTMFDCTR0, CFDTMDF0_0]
                    <name>CFDCFDF%s</name>
                    <description>Common FIFO Access Data Field %s Registers</description>
                    <addressOffset>0x05C4</addressOffset>
                    <size>32</size>
                    <access>read-write</access>
                    <resetValue>0x00000000</resetValue>
                    <resetMask>0xffffffff</resetMask>
                    <fields>
                        <field>
                            <name>CFDB_LL</name>
                            <description>Common FIFO Buffer Data Bytes (p × 4)</description>
                            <lsb>0</lsb>
                            <msb>7</msb>
                            <access>read-write</access>
                        </field>
                        <field>
                            <name>CFDB_LH</name>
                            <description>Common FIFO Buffer Data Bytes ((p × 4) + 1)</description>
                            <lsb>8</lsb>
                            <msb>15</msb>
                            <access>read-write</access>
                        </field>
                        <field>
                            <name>CFDB_HL</name>
                            <description>Common FIFO Buffer Data Bytes ((p × 4) + 2)</description>
                            <lsb>16</lsb>
                            <msb>23</msb>
                            <access>read-write</access>
                        </field>
                        <field>
                            <name>CFDB_HH</name>
                            <description>Common FIFO Buffer Data Bytes ((p × 4) + 3)</description>
                            <lsb>24</lsb>
                            <msb>31</msb>
                            <access>read-write</access>
                        </field>
                    </fields>
                </register>
                <register>
                    <dim>4</dim>
                    <dimIncrement>0x004C</dimIncrement>
                    <dimIndex>0-3</dimIndex>
                    <name>CFDTMID%s</name>
                    <description>TX Message Buffer ID Registers</description>
                    <addressOffset>0x0604</addressOffset>
                    <size>32</size>
                    <access>read-write</access>
                    <resetValue>0x00000000</resetValue>
                    <resetMask>0xffffffff</resetMask>
                    <fields>
                        <field>
                            <name>TMID</name>
                            <description>TX Message Buffer ID Field</description>
                            <lsb>0</lsb>
                            <msb>28</msb>
                            <access>read-write</access>
                        </field>
                        <field>
                            <name>THLEN</name>
                            <description>Tx History List Entry</description>
                            <lsb>29</lsb>
                            <msb>29</msb>
                            <access>read-write</access>
                            <enumeratedValues>
                                <enumeratedValue>
                                    <name>0</name>
                                    <description>Entry not stored in THL after successful TX</description>
                                    <value>#0</value>
                                </enumeratedValue>
                                <enumeratedValue>
                                    <name>1</name>
                                    <description>Entry stored in THL after successful TX</description>
                                    <value>#1</value>
                                </enumeratedValue>
                            </enumeratedValues>
                        </field>
                        <field>
                            <name>TMRTR</name>
                            <description>TX Message Buffer RTR bit</description>
                            <lsb>30</lsb>
                            <msb>30</msb>
                            <access>read-write</access>
                            <enumeratedValues>
                                <enumeratedValue>
                                    <name>0</name>
                                    <description>Data frame</description>
                                    <value>#0</value>
                                </enumeratedValue>
                                <enumeratedValue>
                                    <name>1</name>
                                    <description>Remote frame</description>
                                    <value>#1</value>
                                </enumeratedValue>
                            </enumeratedValues>
                        </field>
                        <field>
                            <name>TMIDE</name>
                            <description>TX Message Buffer IDE bit</description>
                            <lsb>31</lsb>
                            <msb>31</msb>
                            <access>read-write</access>
                            <enumeratedValues>
                                <enumeratedValue>
                                    <name>0</name>
                                    <description>STD-ID is transmitted</description>
                                    <value>#0</value>
                                </enumeratedValue>
                                <enumeratedValue>
                                    <name>1</name>
                                    <description>EXT-ID is transmitted</description>
                                    <value>#1</value>
                                </enumeratedValue>
                            </enumeratedValues>
                        </field>
                    </fields>
                </register>
                <register>
                    <dim>4</dim>
                    <dimIncrement>0x004C</dimIncrement>
                    <dimIndex>0-3</dimIndex>
                    <name>CFDTMPTR%s</name>
                    <description>TX Message Buffer Pointer Register </description>
                    <addressOffset>0x0608</addressOffset>
                    <size>32</size>
                    <access>read-write</access>
                    <resetValue>0x00000000</resetValue>
                    <resetMask>0xffffffff</resetMask>
                    <fields>
                        <field>
                            <name>TMDLC</name>
                            <description>TX Message Buffer DLC Field</description>
                            <lsb>28</lsb>
                            <msb>31</msb>
                            <access>read-write</access>
                        </field>
                    </fields>
                </register>
                <register>
                    <dim>4</dim>
                    <dimIncrement>0x004C</dimIncrement>
                    <dimIndex>0-3</dimIndex>
                    <name>CFDTMFDCTR%s</name>
                    <description>TX Message Buffer CANFD Control Register </description>
                    <addressOffset>0x060C</addressOffset>
                    <size>32</size>
                    <access>read-write</access>
                    <resetValue>0x00000000</resetValue>
                    <resetMask>0xffffffff</resetMask>
                    <fields>
                        <field>
                            <name>TMESI</name>
                            <description>Error State Indicator bit</description>
                            <lsb>0</lsb>
                            <msb>0</msb>
                            <access>read-write</access>
                            <enumeratedValues>
                                <enumeratedValue>
                                    <name>0</name>
                                    <description>CANFD frame to transmit by error active node</description>
                                    <value>#0</value>
                                </enumeratedValue>
                                <enumeratedValue>
                                    <name>1</name>
                                    <description>CANFD frame to transmit by error passive node</description>
                                    <value>#1</value>
                                </enumeratedValue>
                            </enumeratedValues>
                        </field>
                        <field>
                            <name>TMBRS</name>
                            <description>Bit Rate Switch bit</description>
                            <lsb>1</lsb>
                            <msb>1</msb>
                            <access>read-write</access>
                            <enumeratedValues>
                                <enumeratedValue>
                                    <name>0</name>
                                    <description>CANFD frame to transmit with no bit rate switch</description>
                                    <value>#0</value>
                                </enumeratedValue>
                                <enumeratedValue>
                                    <name>1</name>
                                    <description>CANFD frame to transmit with bit rate switch</description>
                                    <value>#1</value>
                                </enumeratedValue>
                            </enumeratedValues>
                        </field>
                        <field>
                            <name>TMFDF</name>
                            <description>CAN FD Format bit</description>
                            <lsb>2</lsb>
                            <msb>2</msb>
                            <access>read-write</access>
                            <enumeratedValues>
                                <enumeratedValue>
                                    <name>0</name>
                                    <description>Non CANFD frame to transmit</description>
                                    <value>#0</value>
                                </enumeratedValue>
                                <enumeratedValue>
                                    <name>1</name>
                                    <description>CANFD frame to transmit</description>
                                    <value>#1</value>
                                </enumeratedValue>
                            </enumeratedValues>
                        </field>
                        <field>
                            <name>TMIFL</name>
                            <description>TX Message Buffer Information Label Field</description>
                            <lsb>8</lsb>
                            <msb>9</msb>
                            <access>read-write</access>
                        </field>
                        <field>
                            <name>TMPTR</name>
                            <description>TX Message Buffer Pointer Field</description>
                            <lsb>16</lsb>
                            <msb>31</msb>
                            <access>read-write</access>
                        </field>
                    </fields>
                </register>
                <register>
                    <dim>4</dim>
                    <dimIncrement>0x04c</dimIncrement>
                    <dimIndex>0-3</dimIndex>
                    <name>CFDTMDF%s_0</name>
                    <description>TX Message Buffer Data Field Register</description>
                    <addressOffset>0x0610</addressOffset>
                    <size>32</size>
                    <access>read-write</access>
                    <resetValue>0x00000000</resetValue>
                    <resetMask>0xffffffff</resetMask>
                    <fields>
                        <field>
                            <name>TMDB_LL</name>
                            <description>TX Message Buffer Data Byte ((p × 4)</description>
                            <lsb>0</lsb>
                            <msb>7</msb>
                            <access>read-write</access>
                        </field>
                        <field>
                            <name>TMDB_LH</name>
                            <description>TX Message Buffer Data Byte ((p × 4) + 1)</description>
                            <lsb>8</lsb>
                            <msb>15</msb>
                            <access>read-write</access>
                        </field>
                        <field>
                            <name>TMDB_HL</name>
                            <description>TX Message Buffer Data Byte ((p × 4) + 2)</description>
                            <lsb>16</lsb>
                            <msb>23</msb>
                            <access>read-write</access>
                        </field>
                        <field>
                            <name>TMDB_HH</name>
                            <description>TX Message Buffer Data Byte ((p × 4) + 3)</description>
                            <lsb>24</lsb>
                            <msb>31</msb>
                            <access>read-write</access>
                        </field>
                    </fields>
                </register>
                <register>
                    <dim>4</dim>
                    <dimIncrement>0x04c</dimIncrement>
                    <dimIndex>0-3</dimIndex>
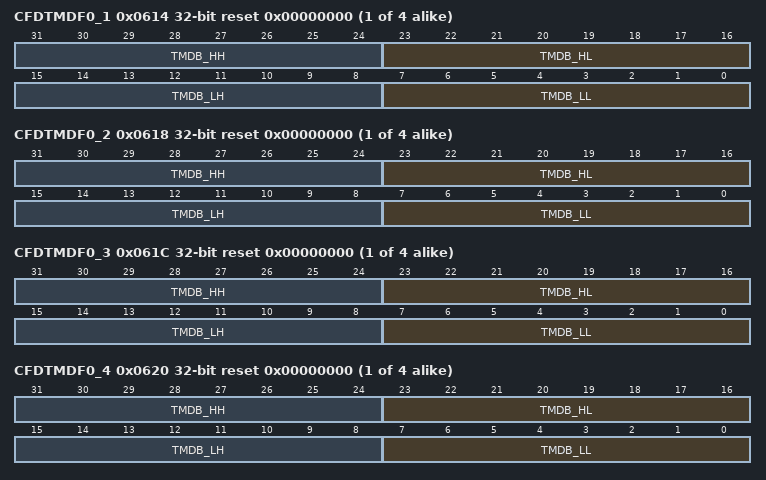
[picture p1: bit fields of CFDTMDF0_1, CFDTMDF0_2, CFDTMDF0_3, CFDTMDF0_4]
                    <name>CFDTMDF%s_1</name>
                    <description>TX Message Buffer Data Field Register</description>
                    <addressOffset>0x0614</addressOffset>
                    <size>32</size>
                    <access>read-write</access>
                    <resetValue>0x00000000</resetValue>
                    <resetMask>0xffffffff</resetMask>
                    <fields>
                        <field>
                            <name>TMDB_LL</name>
                            <description>TX Message Buffer Data Byte ((p × 4)</description>
                            <lsb>0</lsb>
                            <msb>7</msb>
                            <access>read-write</access>
                        </field>
                        <field>
                            <name>TMDB_LH</name>
                            <description>TX Message Buffer Data Byte ((p × 4) + 1)</description>
                            <lsb>8</lsb>
                            <msb>15</msb>
                            <access>read-write</access>
                        </field>
                        <field>
                            <name>TMDB_HL</name>
                            <description>TX Message Buffer Data Byte ((p × 4) + 2)</description>
                            <lsb>16</lsb>
                            <msb>23</msb>
                            <access>read-write</access>
                        </field>
                        <field>
                            <name>TMDB_HH</name>
                            <description>TX Message Buffer Data Byte ((p × 4) + 3)</description>
                            <lsb>24</lsb>
                            <msb>31</msb>
                            <access>read-write</access>
                        </field>
                    </fields>
                </register>
                <register>
                    <dim>4</dim>
                    <dimIncrement>0x04c</dimIncrement>
                    <dimIndex>0-3</dimIndex>
                    <name>CFDTMDF%s_2</name>
                    <description>TX Message Buffer Data Field Register</description>
                    <addressOffset>0x0618</addressOffset>
                    <size>32</size>
                    <access>read-write</access>
                    <resetValue>0x00000000</resetValue>
                    <resetMask>0xffffffff</resetMask>
                    <fields>
                        <field>
                            <name>TMDB_LL</name>
                            <description>TX Message Buffer Data Byte ((p × 4)</description>
                            <lsb>0</lsb>
                            <msb>7</msb>
                            <access>read-write</access>
                        </field>
                        <field>
                            <name>TMDB_LH</name>
                            <description>TX Message Buffer Data Byte ((p × 4) + 1)</description>
                            <lsb>8</lsb>
                            <msb>15</msb>
                            <access>read-write</access>
                        </field>
                        <field>
                            <name>TMDB_HL</name>
                            <description>TX Message Buffer Data Byte ((p × 4) + 2)</description>
                            <lsb>16</lsb>
                            <msb>23</msb>
                            <access>read-write</access>
                        </field>
                        <field>
                            <name>TMDB_HH</name>
                            <description>TX Message Buffer Data Byte ((p × 4) + 3)</description>
                            <lsb>24</lsb>
                            <msb>31</msb>
                            <access>read-write</access>
                        </field>
                    </fields>
                </register>
                <register>
                    <dim>4</dim>
                    <dimIncrement>0x04c</dimIncrement>
                    <dimIndex>0-3</dimIndex>
                    <name>CFDTMDF%s_3</name>
                    <description>TX Message Buffer Data Field Register</description>
                    <addressOffset>0x061C</addressOffset>
                    <size>32</size>
                    <access>read-write</access>
                    <resetValue>0x00000000</resetValue>
                    <resetMask>0xffffffff</resetMask>
                    <fields>
                        <field>
                            <name>TMDB_LL</name>
                            <description>TX Message Buffer Data Byte ((p × 4)</description>
                            <lsb>0</lsb>
                            <msb>7</msb>
                            <access>read-write</access>
                        </field>
                        <field>
                            <name>TMDB_LH</name>
                            <description>TX Message Buffer Data Byte ((p × 4) + 1)</description>
                            <lsb>8</lsb>
                            <msb>15</msb>
                            <access>read-write</access>
                        </field>
                        <field>
                            <name>TMDB_HL</name>
                            <description>TX Message Buffer Data Byte ((p × 4) + 2)</description>
                            <lsb>16</lsb>
                            <msb>23</msb>
                            <access>read-write</access>
                        </field>
                        <field>
                            <name>TMDB_HH</name>
                            <description>TX Message Buffer Data Byte ((p × 4) + 3)</description>
                            <lsb>24</lsb>
                            <msb>31</msb>
                            <access>read-write</access>
                        </field>
                    </fields>
                </register>
                <register>
                    <dim>4</dim>
                    <dimIncrement>0x04c</dimIncrement>
                    <dimIndex>0-3</dimIndex>
                    <name>CFDTMDF%s_4</name>
                    <description>TX Message Buffer Data Field Register</description>
                    <addressOffset>0x0620</addressOffset>
                    <size>32</size>
                    <access>read-write</access>
                    <resetValue>0x00000000</resetValue>
                    <resetMask>0xffffffff</resetMask>
                    <fields>
                        <field>
                            <name>TMDB_LL</name>
                            <description>TX Message Buffer Data Byte ((p × 4)</description>
                            <lsb>0</lsb>
                            <msb>7</msb>
                            <access>read-write</access>
                        </field>
                        <field>
                            <name>TMDB_LH</name>
                            <description>TX Message Buffer Data Byte ((p × 4) + 1)</description>
                            <lsb>8</lsb>
                            <msb>15</msb>
                            <access>read-write</access>
                        </field>
                        <field>
                            <name>TMDB_HL</name>
                            <description>TX Message Buffer Data Byte ((p × 4) + 2)</description>
                            <lsb>16</lsb>
                            <msb>23</msb>
                            <access>read-write</access>
                        </field>
                        <field>
                            <name>TMDB_HH</name>
                            <description>TX Message Buffer Data Byte ((p × 4) + 3)</description>
                            <lsb>24</lsb>
                            <msb>31</msb>
                            <access>read-write</access>
                        </field>
                    </fields>
                </register>
                <register>
                    <dim>4</dim>
                    <dimIncrement>0x04c</dimIncrement>
                    <dimIndex>0-3</dimIndex>
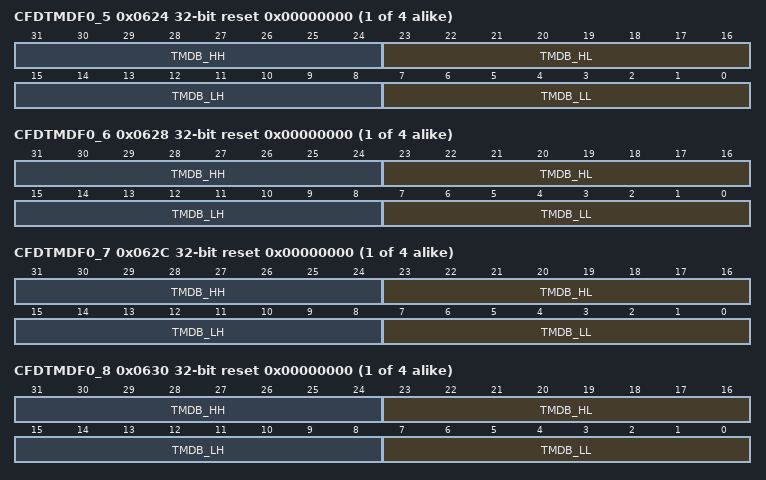
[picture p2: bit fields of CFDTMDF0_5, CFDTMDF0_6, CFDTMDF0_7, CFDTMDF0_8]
                    <name>CFDTMDF%s_5</name>
                    <description>TX Message Buffer Data Field Register</description>
                    <addressOffset>0x0624</addressOffset>
                    <size>32</size>
                    <access>read-write</access>
                    <resetValue>0x00000000</resetValue>
                    <resetMask>0xffffffff</resetMask>
                    <fields>
                        <field>
                            <name>TMDB_LL</name>
                            <description>TX Message Buffer Data Byte ((p × 4)</description>
                            <lsb>0</lsb>
                            <msb>7</msb>
                            <access>read-write</access>
                        </field>
                        <field>
                            <name>TMDB_LH</name>
                            <description>TX Message Buffer Data Byte ((p × 4) + 1)</description>
                            <lsb>8</lsb>
                            <msb>15</msb>
                            <access>read-write</access>
                        </field>
                        <field>
                            <name>TMDB_HL</name>
                            <description>TX Message Buffer Data Byte ((p × 4) + 2)</description>
                            <lsb>16</lsb>
                            <msb>23</msb>
                            <access>read-write</access>
                        </field>
                        <field>
                            <name>TMDB_HH</name>
                            <description>TX Message Buffer Data Byte ((p × 4) + 3)</description>
                            <lsb>24</lsb>
                            <msb>31</msb>
                            <access>read-write</access>
                        </field>
                    </fields>
                </register>
                <register>
                    <dim>4</dim>
                    <dimIncrement>0x04c</dimIncrement>
                    <dimIndex>0-3</dimIndex>
                    <name>CFDTMDF%s_6</name>
                    <description>TX Message Buffer Data Field Register </description>
                    <addressOffset>0x0628</addressOffset>
                    <size>32</size>
                    <access>read-write</access>
                    <resetValue>0x00000000</resetValue>
                    <resetMask>0xffffffff</resetMask>
                    <fields>
                        <field>
                            <name>TMDB_LL</name>
                            <description>TX Message Buffer Data Byte ((p × 4)</description>
                            <lsb>0</lsb>
                            <msb>7</msb>
                            <access>read-write</access>
                        </field>
                        <field>
                            <name>TMDB_LH</name>
                            <description>TX Message Buffer Data Byte ((p × 4) + 1)</description>
                            <lsb>8</lsb>
                            <msb>15</msb>
                            <access>read-write</access>
                        </field>
                        <field>
                            <name>TMDB_HL</name>
                            <description>TX Message Buffer Data Byte ((p × 4) + 2)</description>
                            <lsb>16</lsb>
                            <msb>23</msb>
                            <access>read-write</access>
                        </field>
                        <field>
                            <name>TMDB_HH</name>
                            <description>TX Message Buffer Data Byte ((p × 4) + 3)</description>
                            <lsb>24</lsb>
                            <msb>31</msb>
                            <access>read-write</access>
                        </field>
                    </fields>
                </register>
                <register>
                    <dim>4</dim>
                    <dimIncrement>0x04c</dimIncrement>
                    <dimIndex>0-3</dimIndex>
                    <name>CFDTMDF%s_7</name>
                    <description>TX Message Buffer Data Field Register</description>
                    <addressOffset>0x062C</addressOffset>
                    <size>32</size>
                    <access>read-write</access>
                    <resetValue>0x00000000</resetValue>
                    <resetMask>0xffffffff</resetMask>
                    <fields>
                        <field>
                            <name>TMDB_LL</name>
                            <description>TX Message Buffer Data Byte ((p × 4)</description>
                            <lsb>0</lsb>
                            <msb>7</msb>
                            <access>read-write</access>
                        </field>
                        <field>
                            <name>TMDB_LH</name>
                            <description>TX Message Buffer Data Byte ((p × 4) + 1)</description>
                            <lsb>8</lsb>
                            <msb>15</msb>
                            <access>read-write</access>
                        </field>
                        <field>
                            <name>TMDB_HL</name>
                            <description>TX Message Buffer Data Byte ((p × 4) + 2)</description>
                            <lsb>16</lsb>
                            <msb>23</msb>
                            <access>read-write</access>
                        </field>
                        <field>
                            <name>TMDB_HH</name>
                            <description>TX Message Buffer Data Byte ((p × 4) + 3)</description>
                            <lsb>24</lsb>
                            <msb>31</msb>
                            <access>read-write</access>
                        </field>
                    </fields>
                </register>
                <register>
                    <dim>4</dim>
                    <dimIncrement>0x04c</dimIncrement>
                    <dimIndex>0-3</dimIndex>
                    <name>CFDTMDF%s_8</name>
                    <description>TX Message Buffer Data Field Register</description>
                    <addressOffset>0x0630</addressOffset>
                    <size>32</size>
                    <access>read-write</access>
                    <resetValue>0x00000000</resetValue>
                    <resetMask>0xffffffff</resetMask>
                    <fields>
                        <field>
                            <name>TMDB_LL</name>
                            <description>TX Message Buffer Data Byte ((p × 4)</description>
                            <lsb>0</lsb>
                            <msb>7</msb>
                            <access>read-write</access>
                        </field>
                        <field>
                            <name>TMDB_LH</name>
                            <description>TX Message Buffer Data Byte ((p × 4) + 1)</description>
                            <lsb>8</lsb>
                            <msb>15</msb>
                            <access>read-write</access>
                        </field>
                        <field>
                            <name>TMDB_HL</name>
                            <description>TX Message Buffer Data Byte ((p × 4) + 2)</description>
                            <lsb>16</lsb>
                            <msb>23</msb>
                            <access>read-write</access>
                        </field>
                        <field>
                            <name>TMDB_HH</name>
                            <description>TX Message Buffer Data Byte ((p × 4) + 3)</description>
                            <lsb>24</lsb>
                            <msb>31</msb>
                            <access>read-write</access>
                        </field>
                    </fields>
                </register>
                <register>
                    <dim>4</dim>
                    <dimIncrement>0x04c</dimIncrement>
                    <dimIndex>0-3</dimIndex>
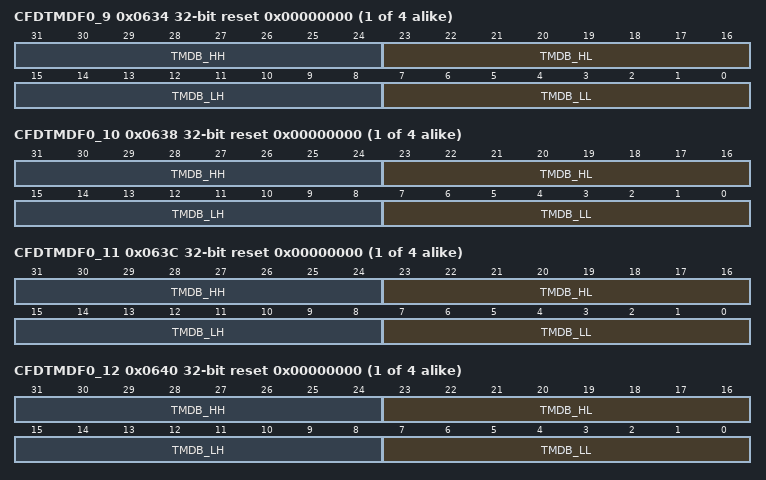
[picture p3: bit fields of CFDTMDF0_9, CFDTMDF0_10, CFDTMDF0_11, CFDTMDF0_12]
                    <name>CFDTMDF%s_9</name>
                    <description>TX Message Buffer Data Field Register</description>
                    <addressOffset>0x0634</addressOffset>
                    <size>32</size>
                    <access>read-write</access>
                    <resetValue>0x00000000</resetValue>
                    <resetMask>0xffffffff</resetMask>
                    <fields>
                        <field>
                            <name>TMDB_LL</name>
                            <description>TX Message Buffer Data Byte ((p × 4)</description>
                            <lsb>0</lsb>
                            <msb>7</msb>
                            <access>read-write</access>
                        </field>
                        <field>
                            <name>TMDB_LH</name>
                            <description>TX Message Buffer Data Byte ((p × 4) + 1)</description>
                            <lsb>8</lsb>
                            <msb>15</msb>
                            <access>read-write</access>
                        </field>
                        <field>
                            <name>TMDB_HL</name>
                            <description>TX Message Buffer Data Byte ((p × 4) + 2)</description>
                            <lsb>16</lsb>
                            <msb>23</msb>
                            <access>read-write</access>
                        </field>
                        <field>
                            <name>TMDB_HH</name>
                            <description>TX Message Buffer Data Byte ((p × 4) + 3)</description>
                            <lsb>24</lsb>
                            <msb>31</msb>
                            <access>read-write</access>
                        </field>
                    </fields>
                </register>
                <register>
                    <dim>4</dim>
                    <dimIncrement>0x04c</dimIncrement>
                    <dimIndex>0-3</dimIndex>
                    <name>CFDTMDF%s_10</name>
                    <description>TX Message Buffer Data Field Register </description>
                    <addressOffset>0x0638</addressOffset>
                    <size>32</size>
                    <access>read-write</access>
                    <resetValue>0x00000000</resetValue>
                    <resetMask>0xffffffff</resetMask>
                    <fields>
                        <field>
                            <name>TMDB_LL</name>
                            <description>TX Message Buffer Data Byte ((p × 4)</description>
                            <lsb>0</lsb>
                            <msb>7</msb>
                            <access>read-write</access>
                        </field>
                        <field>
                            <name>TMDB_LH</name>
                            <description>TX Message Buffer Data Byte ((p × 4) + 1)</description>
                            <lsb>8</lsb>
                            <msb>15</msb>
                            <access>read-write</access>
                        </field>
                        <field>
                            <name>TMDB_HL</name>
                            <description>TX Message Buffer Data Byte ((p × 4) + 2)</description>
                            <lsb>16</lsb>
                            <msb>23</msb>
                            <access>read-write</access>
                        </field>
                        <field>
                            <name>TMDB_HH</name>
                            <description>TX Message Buffer Data Byte ((p × 4) + 3)</description>
                            <lsb>24</lsb>
                            <msb>31</msb>
                            <access>read-write</access>
                        </field>
                    </fields>
                </register>
                <register>
                    <dim>4</dim>
                    <dimIncrement>0x04c</dimIncrement>
                    <dimIndex>0-3</dimIndex>
                    <name>CFDTMDF%s_11</name>
                    <description>TX Message Buffer Data Field Register</description>
                    <addressOffset>0x063C</addressOffset>
                    <size>32</size>
                    <access>read-write</access>
                    <resetValue>0x00000000</resetValue>
                    <resetMask>0xffffffff</resetMask>
                    <fields>
                        <field>
                            <name>TMDB_LL</name>
                            <description>TX Message Buffer Data Byte ((p × 4)</description>
                            <lsb>0</lsb>
                            <msb>7</msb>
                            <access>read-write</access>
                        </field>
                        <field>
                            <name>TMDB_LH</name>
                            <description>TX Message Buffer Data Byte ((p × 4) + 1)</description>
                            <lsb>8</lsb>
                            <msb>15</msb>
                            <access>read-write</access>
                        </field>
                        <field>
                            <name>TMDB_HL</name>
                            <description>TX Message Buffer Data Byte ((p × 4) + 2)</description>
                            <lsb>16</lsb>
                            <msb>23</msb>
                            <access>read-write</access>
                        </field>
                        <field>
                            <name>TMDB_HH</name>
                            <description>TX Message Buffer Data Byte ((p × 4) + 3)</description>
                            <lsb>24</lsb>
                            <msb>31</msb>
                            <access>read-write</access>
                        </field>
                    </fields>
                </register>
                <register>
                    <dim>4</dim>
                    <dimIncrement>0x04c</dimIncrement>
                    <dimIndex>0-3</dimIndex>
                    <name>CFDTMDF%s_12</name>
                    <description>TX Message Buffer Data Field Register</description>
                    <addressOffset>0x0640</addressOffset>
                    <size>32</size>
                    <access>read-write</access>
                    <resetValue>0x00000000</resetValue>
                    <resetMask>0xffffffff</resetMask>
                    <fields>
                        <field>
                            <name>TMDB_LL</name>
                            <description>TX Message Buffer Data Byte ((p × 4)</description>
                            <lsb>0</lsb>
                            <msb>7</msb>
                            <access>read-write</access>
                        </field>
                        <field>
                            <name>TMDB_LH</name>
                            <description>TX Message Buffer Data Byte ((p × 4) + 1)</description>
                            <lsb>8</lsb>
                            <msb>15</msb>
                            <access>read-write</access>
                        </field>
                        <field>
                            <name>TMDB_HL</name>
                            <description>TX Message Buffer Data Byte ((p × 4) + 2)</description>
                            <lsb>16</lsb>
                            <msb>23</msb>
                            <access>read-write</access>
                        </field>
                        <field>
                            <name>TMDB_HH</name>
                            <description>TX Message Buffer Data Byte ((p × 4) + 3)</description>
                            <lsb>24</lsb>
                            <msb>31</msb>
                            <access>read-write</access>
                        </field>
                    </fields>
                </register>
                <register>
                    <dim>4</dim>
                    <dimIncrement>0x04c</dimIncrement>
                    <dimIndex>0-3</dimIndex>
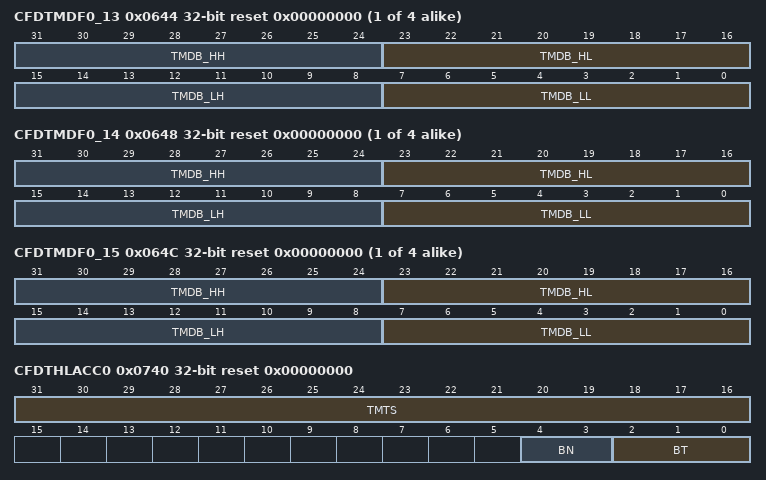
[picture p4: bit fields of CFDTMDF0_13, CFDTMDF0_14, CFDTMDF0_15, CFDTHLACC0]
                    <name>CFDTMDF%s_13</name>
                    <description>TX Message Buffer Data Field Register</description>
                    <addressOffset>0x0644</addressOffset>
                    <size>32</size>
                    <access>read-write</access>
                    <resetValue>0x00000000</resetValue>
                    <resetMask>0xffffffff</resetMask>
                    <fields>
                        <field>
                            <name>TMDB_LL</name>
                            <description>TX Message Buffer Data Byte ((p × 4)</description>
                            <lsb>0</lsb>
                            <msb>7</msb>
                            <access>read-write</access>
                        </field>
                        <field>
                            <name>TMDB_LH</name>
                            <description>TX Message Buffer Data Byte ((p × 4) + 1)</description>
                            <lsb>8</lsb>
                            <msb>15</msb>
                            <access>read-write</access>
                        </field>
                        <field>
                            <name>TMDB_HL</name>
                            <description>TX Message Buffer Data Byte ((p × 4) + 2)</description>
                            <lsb>16</lsb>
                            <msb>23</msb>
                            <access>read-write</access>
                        </field>
                        <field>
                            <name>TMDB_HH</name>
                            <description>TX Message Buffer Data Byte ((p × 4) + 3)</description>
                            <lsb>24</lsb>
                            <msb>31</msb>
                            <access>read-write</access>
                        </field>
                    </fields>
                </register>
                <register>
                    <dim>4</dim>
                    <dimIncrement>0x04c</dimIncrement>
                    <dimIndex>0-3</dimIndex>
                    <name>CFDTMDF%s_14</name>
                    <description>TX Message Buffer Data Field Register</description>
                    <addressOffset>0x0648</addressOffset>
                    <size>32</size>
                    <access>read-write</access>
                    <resetValue>0x00000000</resetValue>
                    <resetMask>0xffffffff</resetMask>
                    <fields>
                        <field>
                            <name>TMDB_LL</name>
                            <description>TX Message Buffer Data Byte ((p × 4)</description>
                            <lsb>0</lsb>
                            <msb>7</msb>
                            <access>read-write</access>
                        </field>
                        <field>
                            <name>TMDB_LH</name>
                            <description>TX Message Buffer Data Byte ((p × 4) + 1)</description>
                            <lsb>8</lsb>
                            <msb>15</msb>
                            <access>read-write</access>
                        </field>
                        <field>
                            <name>TMDB_HL</name>
                            <description>TX Message Buffer Data Byte ((p × 4) + 2)</description>
                            <lsb>16</lsb>
                            <msb>23</msb>
                            <access>read-write</access>
                        </field>
                        <field>
                            <name>TMDB_HH</name>
                            <description>TX Message Buffer Data Byte ((p × 4) + 3)</description>
                            <lsb>24</lsb>
                            <msb>31</msb>
                            <access>read-write</access>
                        </field>
                    </fields>
                </register>
                <register>
                    <dim>4</dim>
                    <dimIncrement>0x04c</dimIncrement>
                    <dimIndex>0-3</dimIndex>
                    <name>CFDTMDF%s_15</name>
                    <description>TX Message Buffer Data Field Register</description>
                    <addressOffset>0x064C</addressOffset>
                    <size>32</size>
                    <access>read-write</access>
                    <resetValue>0x00000000</resetValue>
                    <resetMask>0xffffffff</resetMask>
                    <fields>
                        <field>
                            <name>TMDB_LL</name>
                            <description>TX Message Buffer Data Byte ((p × 4)</description>
                            <lsb>0</lsb>
                            <msb>7</msb>
                            <access>read-write</access>
                        </field>
                        <field>
                            <name>TMDB_LH</name>
                            <description>TX Message Buffer Data Byte ((p × 4) + 1)</description>
                            <lsb>8</lsb>
                            <msb>15</msb>
                            <access>read-write</access>
                        </field>
                        <field>
                            <name>TMDB_HL</name>
                            <description>TX Message Buffer Data Byte ((p × 4) + 2)</description>
                            <lsb>16</lsb>
                            <msb>23</msb>
                            <access>read-write</access>
                        </field>
                        <field>
                            <name>TMDB_HH</name>
                            <description>TX Message Buffer Data Byte ((p × 4) + 3)</description>
                            <lsb>24</lsb>
                            <msb>31</msb>
                            <access>read-write</access>
                        </field>
                    </fields>
                </register>
                <register>
                    <name>CFDTHLACC0</name>
                    <description>TX History List Access Register 0</description>
                    <addressOffset>0x0740</addressOffset>
                    <size>32</size>
                    <access>read-only</access>
                    <resetValue>0x00000000</resetValue>
                    <resetMask>0xffffffff</resetMask>
                    <fields>
                        <field>
                            <name>BT</name>
                            <description>Buffer Type</description>
                            <lsb>0</lsb>
                            <msb>2</msb>
                            <access>read-only</access>
                            <enumeratedValues>
                                <enumeratedValue>
                                    <name>001</name>
                                    <description>Flat TX message buffer</description>
                                    <value>#001</value>
                                </enumeratedValue>
                                <enumeratedValue>
                                    <name>010</name>
                                    <description>TX FIFO message buffer number</description>
                                    <value>#010</value>
                                </enumeratedValue>
                                <enumeratedValue>
                                    <name>100</name>
                                    <description>TX Queue message buffer number</description>
                                    <value>#100</value>
                                </enumeratedValue>
                            </enumeratedValues>
                        </field>
                        <field>
                            <name>BN</name>
                            <description>Buffer Number</description>
                            <lsb>3</lsb>
                            <msb>4</msb>
                            <access>read-only</access>
                        </field>
                        <field>
                            <name>TMTS</name>
                            <description>Transmit Timestamp</description>
                            <lsb>16</lsb>
                            <msb>31</msb>
                            <access>read-only</access>
                        </field>
                    </fields>
                </register>
                <register>
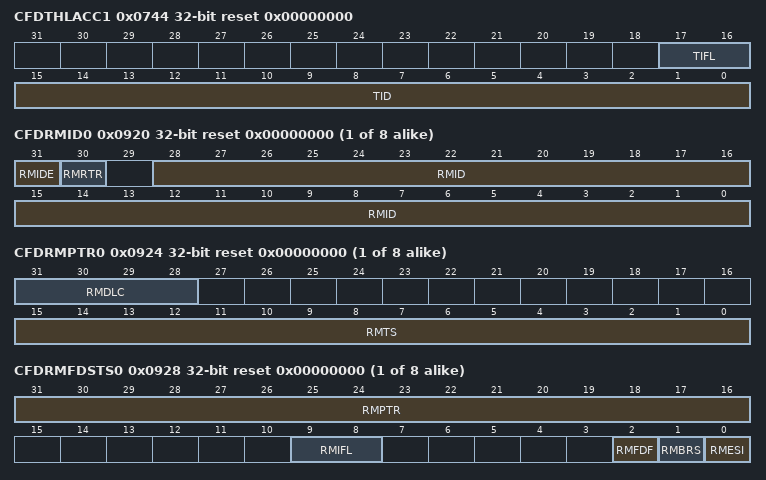
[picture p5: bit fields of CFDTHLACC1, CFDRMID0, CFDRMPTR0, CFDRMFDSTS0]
                    <name>CFDTHLACC1</name>
                    <description>TX History List Access Register 1</description>
                    <addressOffset>0x0744</addressOffset>
                    <size>32</size>
                    <access>read-only</access>
                    <resetValue>0x00000000</resetValue>
                    <resetMask>0xffffffff</resetMask>
                    <fields>
                        <field>
                            <name>TID</name>
                            <description>Transmit ID</description>
                            <lsb>0</lsb>
                            <msb>15</msb>
                            <access>read-only</access>
                        </field>
                        <field>
                            <name>TIFL</name>
                            <description>Transmit Information Label</description>
                            <lsb>16</lsb>
                            <msb>17</msb>
                            <access>read-only</access>
                        </field>
                    </fields>
                </register>
                <register>
                    <dim>8</dim>
                    <dimIncrement>0x004C</dimIncrement>
                    <dimIndex>0-7</dimIndex>
                    <name>CFDRMID%s</name>
                    <description>RX Message Buffer ID Registers</description>
                    <addressOffset>0x0920</addressOffset>
                    <size>32</size>
                    <access>read-only</access>
                    <resetValue>0x00000000</resetValue>
                    <resetMask>0xffffffff</resetMask>
                    <fields>
                        <field>
                            <name>RMID</name>
                            <description>RX Message Buffer ID Field</description>
                            <lsb>0</lsb>
                            <msb>28</msb>
                            <access>read-only</access>
                        </field>
                        <field>
                            <name>RMRTR</name>
                            <description>RX Message Buffer RTR Bit</description>
                            <lsb>30</lsb>
                            <msb>30</msb>
                            <access>read-only</access>
                            <enumeratedValues>
                                <enumeratedValue>
                                    <name>0</name>
                                    <description>Data frame</description>
                                    <value>#0</value>
                                </enumeratedValue>
                                <enumeratedValue>
                                    <name>1</name>
                                    <description>Remote frame</description>
                                    <value>#1</value>
                                </enumeratedValue>
                            </enumeratedValues>
                        </field>
                        <field>
                            <name>RMIDE</name>
                            <description>RX Message Buffer IDE Bit</description>
                            <lsb>31</lsb>
                            <msb>31</msb>
                            <access>read-only</access>
                            <enumeratedValues>
                                <enumeratedValue>
                                    <name>0</name>
                                    <description>STD-ID is stored</description>
                                    <value>#0</value>
                                </enumeratedValue>
                                <enumeratedValue>
                                    <name>1</name>
                                    <description>EXT-ID is stored</description>
                                    <value>#1</value>
                                </enumeratedValue>
                            </enumeratedValues>
                        </field>
                    </fields>
                </register>
                <register>
                    <dim>8</dim>
                    <dimIncrement>0x004C</dimIncrement>
                    <dimIndex>0-7</dimIndex>
                    <name>CFDRMPTR%s</name>
                    <description>RX Message Buffer Pointer Registers</description>
                    <addressOffset>0x0924</addressOffset>
                    <size>32</size>
                    <access>read-only</access>
                    <resetValue>0x00000000</resetValue>
                    <resetMask>0xffffffff</resetMask>
                    <fields>
                        <field>
                            <name>RMTS</name>
                            <description>RX Message Buffer Timestamp Field</description>
                            <lsb>0</lsb>
                            <msb>15</msb>
                            <access>read-only</access>
                        </field>
                        <field>
                            <name>RMDLC</name>
                            <description>RX Message Buffer DLC Field</description>
                            <lsb>28</lsb>
                            <msb>31</msb>
                            <access>read-only</access>
                        </field>
                    </fields>
                </register>
                <register>
                    <dim>8</dim>
                    <dimIncrement>0x004C</dimIncrement>
                    <dimIndex>0-7</dimIndex>
                    <name>CFDRMFDSTS%s</name>
                    <description>RX Message Buffer CANFD Status Registers</description>
                    <addressOffset>0x0928</addressOffset>
                    <size>32</size>
                    <access>read-only</access>
                    <resetValue>0x00000000</resetValue>
                    <resetMask>0xffffffff</resetMask>
                    <fields>
                        <field>
                            <name>RMESI</name>
                            <description>Error State Indicator bit</description>
                            <lsb>0</lsb>
                            <msb>0</msb>
                            <access>read-only</access>
                            <enumeratedValues>
                                <enumeratedValue>
                                    <name>0</name>
                                    <description>CANFD frame received from error active node</description>
                                    <value>#0</value>
                                </enumeratedValue>
                                <enumeratedValue>
                                    <name>1</name>
                                    <description>CANFD frame received from error passive node</description>
                                    <value>#1</value>
                                </enumeratedValue>
                            </enumeratedValues>
                        </field>
                        <field>
                            <name>RMBRS</name>
                            <description>Bit Rate Switch bit</description>
                            <lsb>1</lsb>
                            <msb>1</msb>
                            <access>read-only</access>
                            <enumeratedValues>
                                <enumeratedValue>
                                    <name>0</name>
                                    <description>CANFD frame received with no bit rate switch</description>
                                    <value>#0</value>
                                </enumeratedValue>
                                <enumeratedValue>
                                    <name>1</name>
                                    <description>CANFD frame received with bit rate switch</description>
                                    <value>#1</value>
                                </enumeratedValue>
                            </enumeratedValues>
                        </field>
                        <field>
                            <name>RMFDF</name>
                            <description>CAN FD Format bit</description>
                            <lsb>2</lsb>
                            <msb>2</msb>
                            <access>read-only</access>
                            <enumeratedValues>
                                <enumeratedValue>
                                    <name>0</name>
                                    <description>Non CANFD frame received</description>
                                    <value>#0</value>
                                </enumeratedValue>
                                <enumeratedValue>
                                    <name>1</name>
                                    <description>CANFD frame received</description>
                                    <value>#1</value>
                                </enumeratedValue>
                            </enumeratedValues>
                        </field>
                        <field>
                            <name>RMIFL</name>
                            <description>RX Message Buffer Information Label Field</description>
                            <lsb>8</lsb>
                            <msb>9</msb>
                            <access>read-only</access>
                        </field>
                        <field>
                            <name>RMPTR</name>
                            <description>RX Message Buffer Pointer Field</description>
                            <lsb>16</lsb>
                            <msb>31</msb>
                            <access>read-only</access>
                        </field>
                    </fields>
                </register>
                <register>
                    <dim>8</dim>
                    <dimIncrement>0x004C</dimIncrement>
                    <dimIndex>0-7</dimIndex>
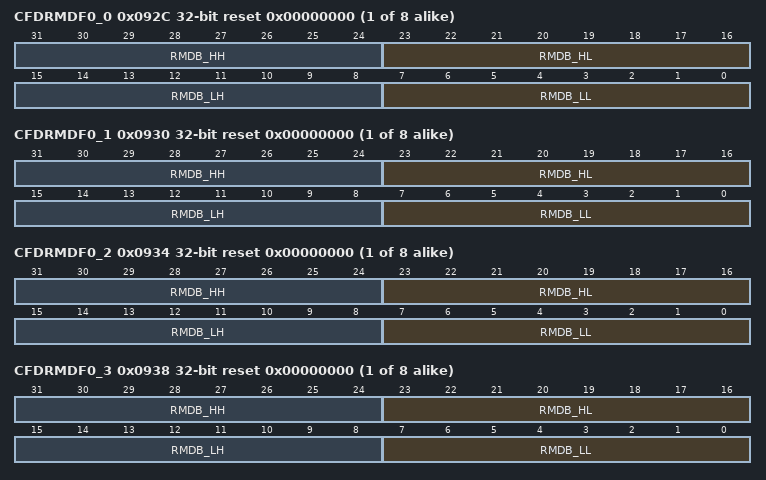
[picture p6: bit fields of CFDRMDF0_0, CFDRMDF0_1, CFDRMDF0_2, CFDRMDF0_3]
                    <name>CFDRMDF%s_0</name>
                    <description>RX Message Buffer Data Field 0 Registers</description>
                    <addressOffset>0x092C</addressOffset>
                    <size>32</size>
                    <access>read-only</access>
                    <resetValue>0x00000000</resetValue>
                    <resetMask>0xffffffff</resetMask>
                    <fields>
                        <field>
                            <name>RMDB_LL</name>
                            <description>RX Message Buffer Data Byte (p × 4)</description>
                            <lsb>0</lsb>
                            <msb>7</msb>
                            <access>read-only</access>
                        </field>
                        <field>
                            <name>RMDB_LH</name>
                            <description>RX Message Buffer Data Byte ((p × 4) + 1)</description>
                            <lsb>8</lsb>
                            <msb>15</msb>
                            <access>read-only</access>
                        </field>
                        <field>
                            <name>RMDB_HL</name>
                            <description>RX Message Buffer Data Byte ((p × 4) + 2)</description>
                            <lsb>16</lsb>
                            <msb>23</msb>
                            <access>read-only</access>
                        </field>
                        <field>
                            <name>RMDB_HH</name>
                            <description>RX Message Buffer Data Byte ((p × 4) + 3)</description>
                            <lsb>24</lsb>
                            <msb>31</msb>
                            <access>read-only</access>
                        </field>
                    </fields>
                </register>
                <register>
                    <dim>8</dim>
                    <dimIncrement>0x004C</dimIncrement>
                    <dimIndex>0-7</dimIndex>
                    <name>CFDRMDF%s_1</name>
                    <description>RX Message Buffer Data Field 1 Registers</description>
                    <addressOffset>0x0930</addressOffset>
                    <size>32</size>
                    <access>read-only</access>
                    <resetValue>0x00000000</resetValue>
                    <resetMask>0xffffffff</resetMask>
                    <fields>
                        <field>
                            <name>RMDB_LL</name>
                            <description>RX Message Buffer Data Byte (p × 4)</description>
                            <lsb>0</lsb>
                            <msb>7</msb>
                            <access>read-only</access>
                        </field>
                        <field>
                            <name>RMDB_LH</name>
                            <description>RX Message Buffer Data Byte ((p × 4) + 1)</description>
                            <lsb>8</lsb>
                            <msb>15</msb>
                            <access>read-only</access>
                        </field>
                        <field>
                            <name>RMDB_HL</name>
                            <description>RX Message Buffer Data Byte ((p × 4) + 2)</description>
                            <lsb>16</lsb>
                            <msb>23</msb>
                            <access>read-only</access>
                        </field>
                        <field>
                            <name>RMDB_HH</name>
                            <description>RX Message Buffer Data Byte ((p × 4) + 3)</description>
                            <lsb>24</lsb>
                            <msb>31</msb>
                            <access>read-only</access>
                        </field>
                    </fields>
                </register>
                <register>
                    <dim>8</dim>
                    <dimIncrement>0x004C</dimIncrement>
                    <dimIndex>0-7</dimIndex>
                    <name>CFDRMDF%s_2</name>
                    <description>RX Message Buffer Data Field 2 Registers</description>
                    <addressOffset>0x0934</addressOffset>
                    <size>32</size>
                    <access>read-only</access>
                    <resetValue>0x00000000</resetValue>
                    <resetMask>0xffffffff</resetMask>
                    <fields>
                        <field>
                            <name>RMDB_LL</name>
                            <description>RX Message Buffer Data Byte (p × 4)</description>
                            <lsb>0</lsb>
                            <msb>7</msb>
                            <access>read-only</access>
                        </field>
                        <field>
                            <name>RMDB_LH</name>
                            <description>RX Message Buffer Data Byte ((p × 4) + 1)</description>
                            <lsb>8</lsb>
                            <msb>15</msb>
                            <access>read-only</access>
                        </field>
                        <field>
                            <name>RMDB_HL</name>
                            <description>RX Message Buffer Data Byte ((p × 4) + 2)</description>
                            <lsb>16</lsb>
                            <msb>23</msb>
                            <access>read-only</access>
                        </field>
                        <field>
                            <name>RMDB_HH</name>
                            <description>RX Message Buffer Data Byte ((p × 4) + 3)</description>
                            <lsb>24</lsb>
                            <msb>31</msb>
                            <access>read-only</access>
                        </field>
                    </fields>
                </register>
                <register>
                    <dim>8</dim>
                    <dimIncrement>0x004C</dimIncrement>
                    <dimIndex>0-7</dimIndex>
                    <name>CFDRMDF%s_3</name>
                    <description>RX Message Buffer Data Field 3 Registers</description>
                    <addressOffset>0x0938</addressOffset>
                    <size>32</size>
                    <access>read-only</access>
                    <resetValue>0x00000000</resetValue>
                    <resetMask>0xffffffff</resetMask>
                    <fields>
                        <field>
                            <name>RMDB_LL</name>
                            <description>RX Message Buffer Data Byte (p × 4)</description>
                            <lsb>0</lsb>
                            <msb>7</msb>
                            <access>read-only</access>
                        </field>
                        <field>
                            <name>RMDB_LH</name>
                            <description>RX Message Buffer Data Byte ((p × 4) + 1)</description>
                            <lsb>8</lsb>
                            <msb>15</msb>
                            <access>read-only</access>
                        </field>
                        <field>
                            <name>RMDB_HL</name>
                            <description>RX Message Buffer Data Byte ((p × 4) + 2)</description>
                            <lsb>16</lsb>
                            <msb>23</msb>
                            <access>read-only</access>
                        </field>
                        <field>
                            <name>RMDB_HH</name>
                            <description>RX Message Buffer Data Byte ((p × 4) + 3)</description>
                            <lsb>24</lsb>
                            <msb>31</msb>
                            <access>read-only</access>
                        </field>
                    </fields>
                </register>
                <register>
                    <dim>8</dim>
                    <dimIncrement>0x004C</dimIncrement>
                    <dimIndex>0-7</dimIndex>
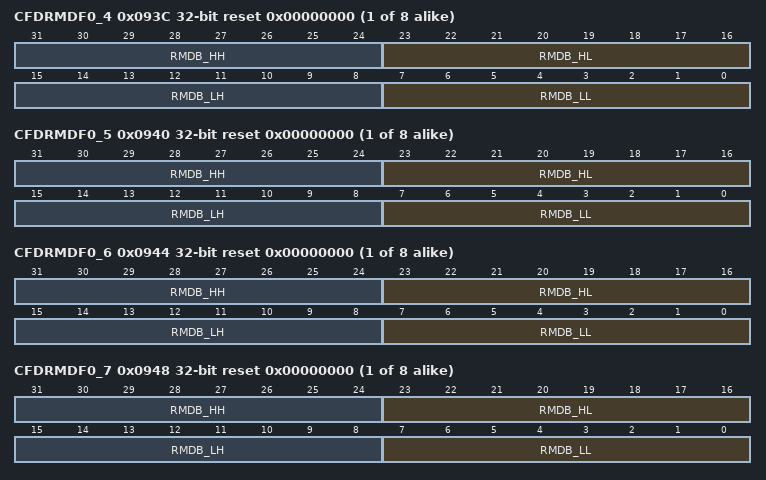
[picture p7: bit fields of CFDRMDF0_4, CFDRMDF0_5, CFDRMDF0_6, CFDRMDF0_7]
                    <name>CFDRMDF%s_4</name>
                    <description>RX Message Buffer Data Field 4 Registers</description>
                    <addressOffset>0x093C</addressOffset>
                    <size>32</size>
                    <access>read-only</access>
                    <resetValue>0x00000000</resetValue>
                    <resetMask>0xffffffff</resetMask>
                    <fields>
                        <field>
                            <name>RMDB_LL</name>
                            <description>RX Message Buffer Data Byte (p × 4)</description>
                            <lsb>0</lsb>
                            <msb>7</msb>
                            <access>read-only</access>
                        </field>
                        <field>
                            <name>RMDB_LH</name>
                            <description>RX Message Buffer Data Byte ((p × 4) + 1)</description>
                            <lsb>8</lsb>
                            <msb>15</msb>
                            <access>read-only</access>
                        </field>
                        <field>
                            <name>RMDB_HL</name>
                            <description>RX Message Buffer Data Byte ((p × 4) + 2)</description>
                            <lsb>16</lsb>
                            <msb>23</msb>
                            <access>read-only</access>
                        </field>
                        <field>
                            <name>RMDB_HH</name>
                            <description>RX Message Buffer Data Byte ((p × 4) + 3)</description>
                            <lsb>24</lsb>
                            <msb>31</msb>
                            <access>read-only</access>
                        </field>
                    </fields>
                </register>
                <register>
                    <dim>8</dim>
                    <dimIncrement>0x004C</dimIncrement>
                    <dimIndex>0-7</dimIndex>
                    <name>CFDRMDF%s_5</name>
                    <description>RX Message Buffer Data Field 5 Registers</description>
                    <addressOffset>0x0940</addressOffset>
                    <size>32</size>
                    <access>read-only</access>
                    <resetValue>0x00000000</resetValue>
                    <resetMask>0xffffffff</resetMask>
                    <fields>
                        <field>
                            <name>RMDB_LL</name>
                            <description>RX Message Buffer Data Byte (p × 4)</description>
                            <lsb>0</lsb>
                            <msb>7</msb>
                            <access>read-only</access>
                        </field>
                        <field>
                            <name>RMDB_LH</name>
                            <description>RX Message Buffer Data Byte ((p × 4) + 1)</description>
                            <lsb>8</lsb>
                            <msb>15</msb>
                            <access>read-only</access>
                        </field>
                        <field>
                            <name>RMDB_HL</name>
                            <description>RX Message Buffer Data Byte ((p × 4) + 2)</description>
                            <lsb>16</lsb>
                            <msb>23</msb>
                            <access>read-only</access>
                        </field>
                        <field>
                            <name>RMDB_HH</name>
                            <description>RX Message Buffer Data Byte ((p × 4) + 3)</description>
                            <lsb>24</lsb>
                            <msb>31</msb>
                            <access>read-only</access>
                        </field>
                    </fields>
                </register>
                <register>
                    <dim>8</dim>
                    <dimIncrement>0x004C</dimIncrement>
                    <dimIndex>0-7</dimIndex>
                    <name>CFDRMDF%s_6</name>
                    <description>RX Message Buffer Data Field 6 Registers</description>
                    <addressOffset>0x0944</addressOffset>
                    <size>32</size>
                    <access>read-only</access>
                    <resetValue>0x00000000</resetValue>
                    <resetMask>0xffffffff</resetMask>
                    <fields>
                        <field>
                            <name>RMDB_LL</name>
                            <description>RX Message Buffer Data Byte (p × 4)</description>
                            <lsb>0</lsb>
                            <msb>7</msb>
                            <access>read-only</access>
                        </field>
                        <field>
                            <name>RMDB_LH</name>
                            <description>RX Message Buffer Data Byte ((p × 4) + 1)</description>
                            <lsb>8</lsb>
                            <msb>15</msb>
                            <access>read-only</access>
                        </field>
                        <field>
                            <name>RMDB_HL</name>
                            <description>RX Message Buffer Data Byte ((p × 4) + 2)</description>
                            <lsb>16</lsb>
                            <msb>23</msb>
                            <access>read-only</access>
                        </field>
                        <field>
                            <name>RMDB_HH</name>
                            <description>RX Message Buffer Data Byte ((p × 4) + 3)</description>
                            <lsb>24</lsb>
                            <msb>31</msb>
                            <access>read-only</access>
                        </field>
                    </fields>
                </register>
                <register>
                    <dim>8</dim>
                    <dimIncrement>0x004C</dimIncrement>
                    <dimIndex>0-7</dimIndex>
                    <name>CFDRMDF%s_7</name>
                    <description>RX Message Buffer Data Field 7 Registers</description>
                    <addressOffset>0x0948</addressOffset>
                    <size>32</size>
                    <access>read-only</access>
                    <resetValue>0x00000000</resetValue>
                    <resetMask>0xffffffff</resetMask>
                    <fields>
                        <field>
                            <name>RMDB_LL</name>
                            <description>RX Message Buffer Data Byte (p × 4)</description>
                            <lsb>0</lsb>
                            <msb>7</msb>
                            <access>read-only</access>
                        </field>
                        <field>
                            <name>RMDB_LH</name>
                            <description>RX Message Buffer Data Byte ((p × 4) + 1)</description>
                            <lsb>8</lsb>
                            <msb>15</msb>
                            <access>read-only</access>
                        </field>
                        <field>
                            <name>RMDB_HL</name>
                            <description>RX Message Buffer Data Byte ((p × 4) + 2)</description>
                            <lsb>16</lsb>
                            <msb>23</msb>
                            <access>read-only</access>
                        </field>
                        <field>
                            <name>RMDB_HH</name>
                            <description>RX Message Buffer Data Byte ((p × 4) + 3)</description>
                            <lsb>24</lsb>
                            <msb>31</msb>
                            <access>read-only</access>
                        </field>
                    </fields>
                </register>
                <register>
                    <dim>8</dim>
                    <dimIncrement>0x004C</dimIncrement>
                    <dimIndex>0-7</dimIndex>
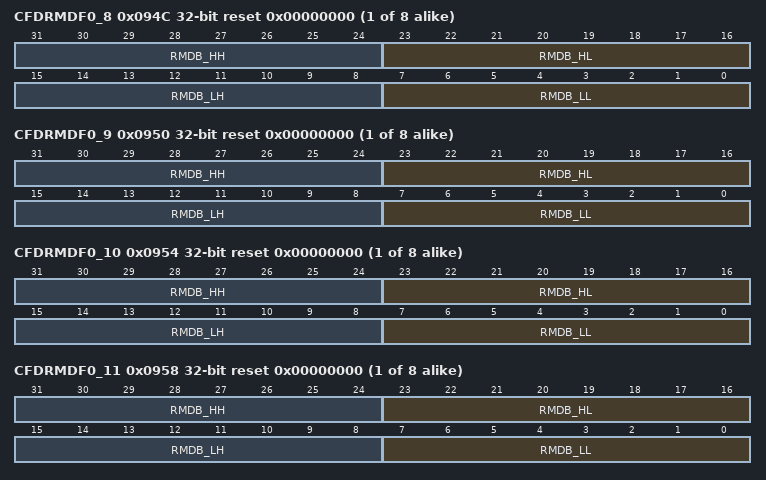
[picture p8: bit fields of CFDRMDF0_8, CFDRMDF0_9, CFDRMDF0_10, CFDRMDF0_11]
                    <name>CFDRMDF%s_8</name>
                    <description>RX Message Buffer Data Field 8 Registers</description>
                    <addressOffset>0x094C</addressOffset>
                    <size>32</size>
                    <access>read-only</access>
                    <resetValue>0x00000000</resetValue>
                    <resetMask>0xffffffff</resetMask>
                    <fields>
                        <field>
                            <name>RMDB_LL</name>
                            <description>RX Message Buffer Data Byte (p × 4)</description>
                            <lsb>0</lsb>
                            <msb>7</msb>
                            <access>read-only</access>
                        </field>
                        <field>
                            <name>RMDB_LH</name>
                            <description>RX Message Buffer Data Byte ((p × 4) + 1)</description>
                            <lsb>8</lsb>
                            <msb>15</msb>
                            <access>read-only</access>
                        </field>
                        <field>
                            <name>RMDB_HL</name>
                            <description>RX Message Buffer Data Byte ((p × 4) + 2)</description>
                            <lsb>16</lsb>
                            <msb>23</msb>
                            <access>read-only</access>
                        </field>
                        <field>
                            <name>RMDB_HH</name>
                            <description>RX Message Buffer Data Byte ((p × 4) + 3)</description>
                            <lsb>24</lsb>
                            <msb>31</msb>
                            <access>read-only</access>
                        </field>
                    </fields>
                </register>
                <register>
                    <dim>8</dim>
                    <dimIncrement>0x004C</dimIncrement>
                    <dimIndex>0-7</dimIndex>
                    <name>CFDRMDF%s_9</name>
                    <description>RX Message Buffer Data Field 9 Registers</description>
                    <addressOffset>0x0950</addressOffset>
                    <size>32</size>
                    <access>read-only</access>
                    <resetValue>0x00000000</resetValue>
                    <resetMask>0xffffffff</resetMask>
                    <fields>
                        <field>
                            <name>RMDB_LL</name>
                            <description>RX Message Buffer Data Byte (p × 4)</description>
                            <lsb>0</lsb>
                            <msb>7</msb>
                            <access>read-only</access>
                        </field>
                        <field>
                            <name>RMDB_LH</name>
                            <description>RX Message Buffer Data Byte ((p × 4) + 1)</description>
                            <lsb>8</lsb>
                            <msb>15</msb>
                            <access>read-only</access>
                        </field>
                        <field>
                            <name>RMDB_HL</name>
                            <description>RX Message Buffer Data Byte ((p × 4) + 2)</description>
                            <lsb>16</lsb>
                            <msb>23</msb>
                            <access>read-only</access>
                        </field>
                        <field>
                            <name>RMDB_HH</name>
                            <description>RX Message Buffer Data Byte ((p × 4) + 3)</description>
                            <lsb>24</lsb>
                            <msb>31</msb>
                            <access>read-only</access>
                        </field>
                    </fields>
                </register>
                <register>
                    <dim>8</dim>
                    <dimIncrement>0x004C</dimIncrement>
                    <dimIndex>0-7</dimIndex>
                    <name>CFDRMDF%s_10</name>
                    <description>RX Message Buffer Data Field 10 Registers</description>
                    <addressOffset>0x0954</addressOffset>
                    <size>32</size>
                    <access>read-only</access>
                    <resetValue>0x00000000</resetValue>
                    <resetMask>0xffffffff</resetMask>
                    <fields>
                        <field>
                            <name>RMDB_LL</name>
                            <description>RX Message Buffer Data Byte (p × 4)</description>
                            <lsb>0</lsb>
                            <msb>7</msb>
                            <access>read-only</access>
                        </field>
                        <field>
                            <name>RMDB_LH</name>
                            <description>RX Message Buffer Data Byte ((p × 4) + 1)</description>
                            <lsb>8</lsb>
                            <msb>15</msb>
                            <access>read-only</access>
                        </field>
                        <field>
                            <name>RMDB_HL</name>
                            <description>RX Message Buffer Data Byte ((p × 4) + 2)</description>
                            <lsb>16</lsb>
                            <msb>23</msb>
                            <access>read-only</access>
                        </field>
                        <field>
                            <name>RMDB_HH</name>
                            <description>RX Message Buffer Data Byte ((p × 4) + 3)</description>
                            <lsb>24</lsb>
                            <msb>31</msb>
                            <access>read-only</access>
                        </field>
                    </fields>
                </register>
                <register>
                    <dim>8</dim>
                    <dimIncrement>0x004C</dimIncrement>
                    <dimIndex>0-7</dimIndex>
                    <name>CFDRMDF%s_11</name>
                    <description>RX Message Buffer Data Field 11 Registers</description>
                    <addressOffset>0x0958</addressOffset>
                    <size>32</size>
                    <access>read-only</access>
                    <resetValue>0x00000000</resetValue>
                    <resetMask>0xffffffff</resetMask>
                    <fields>
                        <field>
                            <name>RMDB_LL</name>
                            <description>RX Message Buffer Data Byte (p × 4)</description>
                            <lsb>0</lsb>
                            <msb>7</msb>
                            <access>read-only</access>
                        </field>
                        <field>
                            <name>RMDB_LH</name>
                            <description>RX Message Buffer Data Byte ((p × 4) + 1)</description>
                            <lsb>8</lsb>
                            <msb>15</msb>
                            <access>read-only</access>
                        </field>
                        <field>
                            <name>RMDB_HL</name>
                            <description>RX Message Buffer Data Byte ((p × 4) + 2)</description>
                            <lsb>16</lsb>
                            <msb>23</msb>
                            <access>read-only</access>
                        </field>
                        <field>
                            <name>RMDB_HH</name>
                            <description>RX Message Buffer Data Byte ((p × 4) + 3)</description>
                            <lsb>24</lsb>
                            <msb>31</msb>
                            <access>read-only</access>
                        </field>
                    </fields>
                </register>
                <register>
                    <dim>8</dim>
                    <dimIncrement>0x004C</dimIncrement>
                    <dimIndex>0-7</dimIndex>
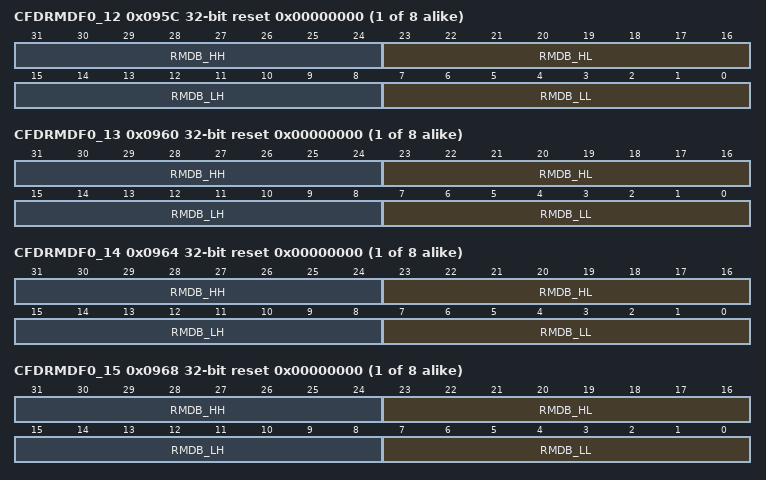
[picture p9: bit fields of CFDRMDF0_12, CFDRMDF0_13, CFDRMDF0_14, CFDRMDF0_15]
                    <name>CFDRMDF%s_12</name>
                    <description>RX Message Buffer Data Field 12 Registers</description>
                    <addressOffset>0x095C</addressOffset>
                    <size>32</size>
                    <access>read-only</access>
                    <resetValue>0x00000000</resetValue>
                    <resetMask>0xffffffff</resetMask>
                    <fields>
                        <field>
                            <name>RMDB_LL</name>
                            <description>RX Message Buffer Data Byte (p × 4)</description>
                            <lsb>0</lsb>
                            <msb>7</msb>
                            <access>read-only</access>
                        </field>
                        <field>
                            <name>RMDB_LH</name>
                            <description>RX Message Buffer Data Byte ((p × 4) + 1)</description>
                            <lsb>8</lsb>
                            <msb>15</msb>
                            <access>read-only</access>
                        </field>
                        <field>
                            <name>RMDB_HL</name>
                            <description>RX Message Buffer Data Byte ((p × 4) + 2)</description>
                            <lsb>16</lsb>
                            <msb>23</msb>
                            <access>read-only</access>
                        </field>
                        <field>
                            <name>RMDB_HH</name>
                            <description>RX Message Buffer Data Byte ((p × 4) + 3)</description>
                            <lsb>24</lsb>
                            <msb>31</msb>
                            <access>read-only</access>
                        </field>
                    </fields>
                </register>
                <register>
                    <dim>8</dim>
                    <dimIncrement>0x004C</dimIncrement>
                    <dimIndex>0-7</dimIndex>
                    <name>CFDRMDF%s_13</name>
                    <description>RX Message Buffer Data Field 13 Registers</description>
                    <addressOffset>0x0960</addressOffset>
                    <size>32</size>
                    <access>read-only</access>
                    <resetValue>0x00000000</resetValue>
                    <resetMask>0xffffffff</resetMask>
                    <fields>
                        <field>
                            <name>RMDB_LL</name>
                            <description>RX Message Buffer Data Byte (p × 4)</description>
                            <lsb>0</lsb>
                            <msb>7</msb>
                            <access>read-only</access>
                        </field>
                        <field>
                            <name>RMDB_LH</name>
                            <description>RX Message Buffer Data Byte ((p × 4) + 1)</description>
                            <lsb>8</lsb>
                            <msb>15</msb>
                            <access>read-only</access>
                        </field>
                        <field>
                            <name>RMDB_HL</name>
                            <description>RX Message Buffer Data Byte ((p × 4) + 2)</description>
                            <lsb>16</lsb>
                            <msb>23</msb>
                            <access>read-only</access>
                        </field>
                        <field>
                            <name>RMDB_HH</name>
                            <description>RX Message Buffer Data Byte ((p × 4) + 3)</description>
                            <lsb>24</lsb>
                            <msb>31</msb>
                            <access>read-only</access>
                        </field>
                    </fields>
                </register>
                <register>
                    <dim>8</dim>
                    <dimIncrement>0x004C</dimIncrement>
                    <dimIndex>0-7</dimIndex>
                    <name>CFDRMDF%s_14</name>
                    <description>RX Message Buffer Data Field 14 Registers</description>
                    <addressOffset>0x0964</addressOffset>
                    <size>32</size>
                    <access>read-only</access>
                    <resetValue>0x00000000</resetValue>
                    <resetMask>0xffffffff</resetMask>
                    <fields>
                        <field>
                            <name>RMDB_LL</name>
                            <description>RX Message Buffer Data Byte (p × 4)</description>
                            <lsb>0</lsb>
                            <msb>7</msb>
                            <access>read-only</access>
                        </field>
                        <field>
                            <name>RMDB_LH</name>
                            <description>RX Message Buffer Data Byte ((p × 4) + 1)</description>
                            <lsb>8</lsb>
                            <msb>15</msb>
                            <access>read-only</access>
                        </field>
                        <field>
                            <name>RMDB_HL</name>
                            <description>RX Message Buffer Data Byte ((p × 4) + 2)</description>
                            <lsb>16</lsb>
                            <msb>23</msb>
                            <access>read-only</access>
                        </field>
                        <field>
                            <name>RMDB_HH</name>
                            <description>RX Message Buffer Data Byte ((p × 4) + 3)</description>
                            <lsb>24</lsb>
                            <msb>31</msb>
                            <access>read-only</access>
                        </field>
                    </fields>
                </register>
                <register>
                    <dim>8</dim>
                    <dimIncrement>0x004C</dimIncrement>
                    <dimIndex>0-7</dimIndex>
                    <name>CFDRMDF%s_15</name>
                    <description>RX Message Buffer Data Field 15 Registers</description>
                    <addressOffset>0x0968</addressOffset>
                    <size>32</size>
                    <access>read-only</access>
                    <resetValue>0x00000000</resetValue>
                    <resetMask>0xffffffff</resetMask>
                    <fields>
                        <field>
                            <name>RMDB_LL</name>
                            <description>RX Message Buffer Data Byte (p × 4)</description>
                            <lsb>0</lsb>
                            <msb>7</msb>
                            <access>read-only</access>
                        </field>
                        <field>
                            <name>RMDB_LH</name>
                            <description>RX Message Buffer Data Byte ((p × 4) + 1)</description>
                            <lsb>8</lsb>
                            <msb>15</msb>
                            <access>read-only</access>
                        </field>
                        <field>
                            <name>RMDB_HL</name>
                            <description>RX Message Buffer Data Byte ((p × 4) + 2)</description>
                            <lsb>16</lsb>
                            <msb>23</msb>
                            <access>read-only</access>
                        </field>
                        <field>
                            <name>RMDB_HH</name>
                            <description>RX Message Buffer Data Byte ((p × 4) + 3)</description>
                            <lsb>24</lsb>
                            <msb>31</msb>
                            <access>read-only</access>
                        </field>
                    </fields>
                </register>
                <register>
                    <dim>8</dim>
                    <dimIncrement>0x004C</dimIncrement>
                    <dimIndex>8-15</dimIndex>
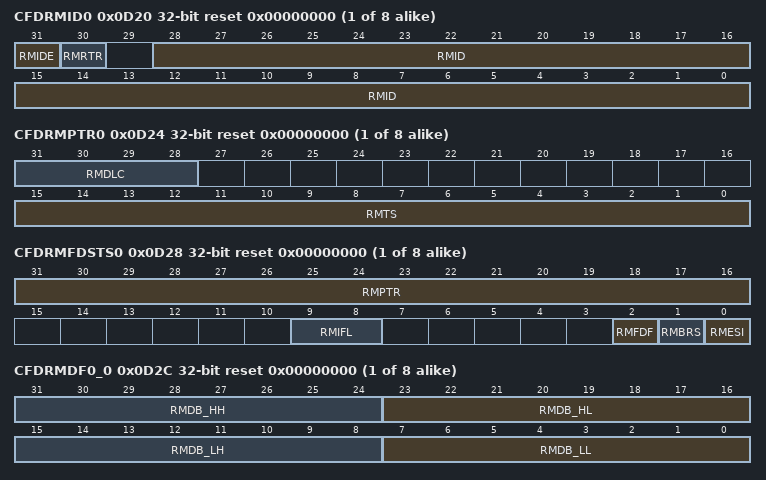
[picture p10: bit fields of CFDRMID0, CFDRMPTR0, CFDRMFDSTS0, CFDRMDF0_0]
                    <name>CFDRMID%s</name>
                    <description>RX Message Buffer ID Registers</description>
                    <addressOffset>0x0D20</addressOffset>
                    <size>32</size>
                    <access>read-only</access>
                    <resetValue>0x00000000</resetValue>
                    <resetMask>0xffffffff</resetMask>
                    <fields>
                        <field>
                            <name>RMID</name>
                            <description>RX Message Buffer ID Field</description>
                            <lsb>0</lsb>
                            <msb>28</msb>
                            <access>read-only</access>
                        </field>
                        <field>
                            <name>RMRTR</name>
                            <description>RX Message Buffer RTR Bit</description>
                            <lsb>30</lsb>
                            <msb>30</msb>
                            <access>read-only</access>
                            <enumeratedValues>
                                <enumeratedValue>
                                    <name>0</name>
                                    <description>Data frame</description>
                                    <value>#0</value>
                                </enumeratedValue>
                                <enumeratedValue>
                                    <name>1</name>
                                    <description>Remote frame</description>
                                    <value>#1</value>
                                </enumeratedValue>
                            </enumeratedValues>
                        </field>
                        <field>
                            <name>RMIDE</name>
                            <description>RX Message Buffer IDE Bit</description>
                            <lsb>31</lsb>
                            <msb>31</msb>
                            <access>read-only</access>
                            <enumeratedValues>
                                <enumeratedValue>
                                    <name>0</name>
                                    <description>STD-ID is stored</description>
                                    <value>#0</value>
                                </enumeratedValue>
                                <enumeratedValue>
                                    <name>1</name>
                                    <description>EXT-ID is stored</description>
                                    <value>#1</value>
                                </enumeratedValue>
                            </enumeratedValues>
                        </field>
                    </fields>
                </register>
                <register>
                    <dim>8</dim>
                    <dimIncrement>0x004C</dimIncrement>
                    <dimIndex>8-15</dimIndex>
                    <name>CFDRMPTR%s</name>
                    <description>RX Message Buffer Pointer Registers</description>
                    <addressOffset>0x0D24</addressOffset>
                    <size>32</size>
                    <access>read-only</access>
                    <resetValue>0x00000000</resetValue>
                    <resetMask>0xffffffff</resetMask>
                    <fields>
                        <field>
                            <name>RMTS</name>
                            <description>RX Message Buffer Timestamp Field</description>
                            <lsb>0</lsb>
                            <msb>15</msb>
                            <access>read-only</access>
                        </field>
                        <field>
                            <name>RMDLC</name>
                            <description>RX Message Buffer DLC Field</description>
                            <lsb>28</lsb>
                            <msb>31</msb>
                            <access>read-only</access>
                        </field>
                    </fields>
                </register>
                <register>
                    <dim>8</dim>
                    <dimIncrement>0x004C</dimIncrement>
                    <dimIndex>8-15</dimIndex>
                    <name>CFDRMFDSTS%s</name>
                    <description>RX Message Buffer CANFD Status Registers</description>
                    <addressOffset>0x0D28</addressOffset>
                    <size>32</size>
                    <access>read-only</access>
                    <resetValue>0x00000000</resetValue>
                    <resetMask>0xffffffff</resetMask>
                    <fields>
                        <field>
                            <name>RMESI</name>
                            <description>Error State Indicator bit</description>
                            <lsb>0</lsb>
                            <msb>0</msb>
                            <access>read-only</access>
                            <enumeratedValues>
                                <enumeratedValue>
                                    <name>0</name>
                                    <description>CANFD frame received from error active node</description>
                                    <value>#0</value>
                                </enumeratedValue>
                                <enumeratedValue>
                                    <name>1</name>
                                    <description>CANFD frame received from error passive node</description>
                                    <value>#1</value>
                                </enumeratedValue>
                            </enumeratedValues>
                        </field>
                        <field>
                            <name>RMBRS</name>
                            <description>Bit Rate Switch bit</description>
                            <lsb>1</lsb>
                            <msb>1</msb>
                            <access>read-only</access>
                            <enumeratedValues>
                                <enumeratedValue>
                                    <name>0</name>
                                    <description>CANFD frame received with no bit rate switch</description>
                                    <value>#0</value>
                                </enumeratedValue>
                                <enumeratedValue>
                                    <name>1</name>
                                    <description>CANFD frame received with bit rate switch</description>
                                    <value>#1</value>
                                </enumeratedValue>
                            </enumeratedValues>
                        </field>
                        <field>
                            <name>RMFDF</name>
                            <description>CAN FD Format bit</description>
                            <lsb>2</lsb>
                            <msb>2</msb>
                            <access>read-only</access>
                            <enumeratedValues>
                                <enumeratedValue>
                                    <name>0</name>
                                    <description>Non CANFD frame received</description>
                                    <value>#0</value>
                                </enumeratedValue>
                                <enumeratedValue>
                                    <name>1</name>
                                    <description>CANFD frame received</description>
                                    <value>#1</value>
                                </enumeratedValue>
                            </enumeratedValues>
                        </field>
                        <field>
                            <name>RMIFL</name>
                            <description>RX Message Buffer Information Label Field</description>
                            <lsb>8</lsb>
                            <msb>9</msb>
                            <access>read-only</access>
                        </field>
                        <field>
                            <name>RMPTR</name>
                            <description>RX Message Buffer Pointer Field</description>
                            <lsb>16</lsb>
                            <msb>31</msb>
                            <access>read-only</access>
                        </field>
                    </fields>
                </register>
                <register>
                    <dim>8</dim>
                    <dimIncrement>0x004C</dimIncrement>
                    <dimIndex>8-15</dimIndex>
                    <name>CFDRMDF%s_0</name>
                    <description>RX Message Buffer Data Field 0 Registers</description>
                    <addressOffset>0x0D2C</addressOffset>
                    <size>32</size>
                    <access>read-only</access>
                    <resetValue>0x00000000</resetValue>
                    <resetMask>0xffffffff</resetMask>
                    <fields>
                        <field>
                            <name>RMDB_LL</name>
                            <description>RX Message Buffer Data Byte (p × 4)</description>
                            <lsb>0</lsb>
                            <msb>7</msb>
                            <access>read-only</access>
                        </field>
                        <field>
                            <name>RMDB_LH</name>
                            <description>RX Message Buffer Data Byte ((p × 4) + 1)</description>
                            <lsb>8</lsb>
                            <msb>15</msb>
                            <access>read-only</access>
                        </field>
                        <field>
                            <name>RMDB_HL</name>
                            <description>RX Message Buffer Data Byte ((p × 4) + 2)</description>
                            <lsb>16</lsb>
                            <msb>23</msb>
                            <access>read-only</access>
                        </field>
                        <field>
                            <name>RMDB_HH</name>
                            <description>RX Message Buffer Data Byte ((p × 4) + 3)</description>
                            <lsb>24</lsb>
                            <msb>31</msb>
                            <access>read-only</access>
                        </field>
                    </fields>
                </register>
                <register>
                    <dim>8</dim>
                    <dimIncrement>0x004C</dimIncrement>
                    <dimIndex>8-15</dimIndex>
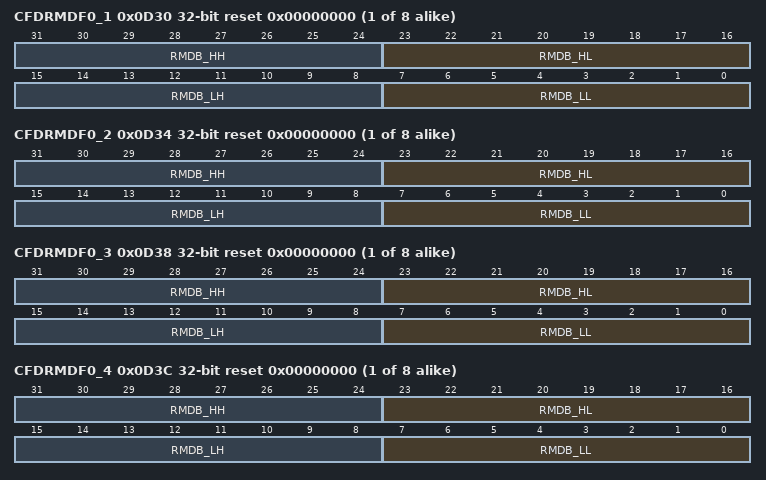
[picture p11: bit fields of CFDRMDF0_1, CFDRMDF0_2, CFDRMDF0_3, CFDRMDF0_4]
                    <name>CFDRMDF%s_1</name>
                    <description>RX Message Buffer Data Field 1 Registers</description>
                    <addressOffset>0x0D30</addressOffset>
                    <size>32</size>
                    <access>read-only</access>
                    <resetValue>0x00000000</resetValue>
                    <resetMask>0xffffffff</resetMask>
                    <fields>
                        <field>
                            <name>RMDB_LL</name>
                            <description>RX Message Buffer Data Byte (p × 4)</description>
                            <lsb>0</lsb>
                            <msb>7</msb>
                            <access>read-only</access>
                        </field>
                        <field>
                            <name>RMDB_LH</name>
                            <description>RX Message Buffer Data Byte ((p × 4) + 1)</description>
                            <lsb>8</lsb>
                            <msb>15</msb>
                            <access>read-only</access>
                        </field>
                        <field>
                            <name>RMDB_HL</name>
                            <description>RX Message Buffer Data Byte ((p × 4) + 2)</description>
                            <lsb>16</lsb>
                            <msb>23</msb>
                            <access>read-only</access>
                        </field>
                        <field>
                            <name>RMDB_HH</name>
                            <description>RX Message Buffer Data Byte ((p × 4) + 3)</description>
                            <lsb>24</lsb>
                            <msb>31</msb>
                            <access>read-only</access>
                        </field>
                    </fields>
                </register>
                <register>
                    <dim>8</dim>
                    <dimIncrement>0x004C</dimIncrement>
                    <dimIndex>8-15</dimIndex>
                    <name>CFDRMDF%s_2</name>
                    <description>RX Message Buffer Data Field 2 Registers</description>
                    <addressOffset>0x0D34</addressOffset>
                    <size>32</size>
                    <access>read-only</access>
                    <resetValue>0x00000000</resetValue>
                    <resetMask>0xffffffff</resetMask>
                    <fields>
                        <field>
                            <name>RMDB_LL</name>
                            <description>RX Message Buffer Data Byte (p × 4)</description>
                            <lsb>0</lsb>
                            <msb>7</msb>
                            <access>read-only</access>
                        </field>
                        <field>
                            <name>RMDB_LH</name>
                            <description>RX Message Buffer Data Byte ((p × 4) + 1)</description>
                            <lsb>8</lsb>
                            <msb>15</msb>
                            <access>read-only</access>
                        </field>
                        <field>
                            <name>RMDB_HL</name>
                            <description>RX Message Buffer Data Byte ((p × 4) + 2)</description>
                            <lsb>16</lsb>
                            <msb>23</msb>
                            <access>read-only</access>
                        </field>
                        <field>
                            <name>RMDB_HH</name>
                            <description>RX Message Buffer Data Byte ((p × 4) + 3)</description>
                            <lsb>24</lsb>
                            <msb>31</msb>
                            <access>read-only</access>
                        </field>
                    </fields>
                </register>
                <register>
                    <dim>8</dim>
                    <dimIncrement>0x004C</dimIncrement>
                    <dimIndex>8-15</dimIndex>
                    <name>CFDRMDF%s_3</name>
                    <description>RX Message Buffer Data Field 3 Registers</description>
                    <addressOffset>0x0D38</addressOffset>
                    <size>32</size>
                    <access>read-only</access>
                    <resetValue>0x00000000</resetValue>
                    <resetMask>0xffffffff</resetMask>
                    <fields>
                        <field>
                            <name>RMDB_LL</name>
                            <description>RX Message Buffer Data Byte (p × 4)</description>
                            <lsb>0</lsb>
                            <msb>7</msb>
                            <access>read-only</access>
                        </field>
                        <field>
                            <name>RMDB_LH</name>
                            <description>RX Message Buffer Data Byte ((p × 4) + 1)</description>
                            <lsb>8</lsb>
                            <msb>15</msb>
                            <access>read-only</access>
                        </field>
                        <field>
                            <name>RMDB_HL</name>
                            <description>RX Message Buffer Data Byte ((p × 4) + 2)</description>
                            <lsb>16</lsb>
                            <msb>23</msb>
                            <access>read-only</access>
                        </field>
                        <field>
                            <name>RMDB_HH</name>
                            <description>RX Message Buffer Data Byte ((p × 4) + 3)</description>
                            <lsb>24</lsb>
                            <msb>31</msb>
                            <access>read-only</access>
                        </field>
                    </fields>
                </register>
                <register>
                    <dim>8</dim>
                    <dimIncrement>0x004C</dimIncrement>
                    <dimIndex>8-15</dimIndex>
                    <name>CFDRMDF%s_4</name>
                    <description>RX Message Buffer Data Field 4 Registers</description>
                    <addressOffset>0x0D3C</addressOffset>
                    <size>32</size>
                    <access>read-only</access>
                    <resetValue>0x00000000</resetValue>
                    <resetMask>0xffffffff</resetMask>
                    <fields>
                        <field>
                            <name>RMDB_LL</name>
                            <description>RX Message Buffer Data Byte (p × 4)</description>
                            <lsb>0</lsb>
                            <msb>7</msb>
                            <access>read-only</access>
                        </field>
                        <field>
                            <name>RMDB_LH</name>
                            <description>RX Message Buffer Data Byte ((p × 4) + 1)</description>
                            <lsb>8</lsb>
                            <msb>15</msb>
                            <access>read-only</access>
                        </field>
                        <field>
                            <name>RMDB_HL</name>
                            <description>RX Message Buffer Data Byte ((p × 4) + 2)</description>
                            <lsb>16</lsb>
                            <msb>23</msb>
                            <access>read-only</access>
                        </field>
                        <field>
                            <name>RMDB_HH</name>
                            <description>RX Message Buffer Data Byte ((p × 4) + 3)</description>
                            <lsb>24</lsb>
                            <msb>31</msb>
                            <access>read-only</access>
                        </field>
                    </fields>
                </register>
                <register>
                    <dim>8</dim>
                    <dimIncrement>0x004C</dimIncrement>
                    <dimIndex>8-15</dimIndex>
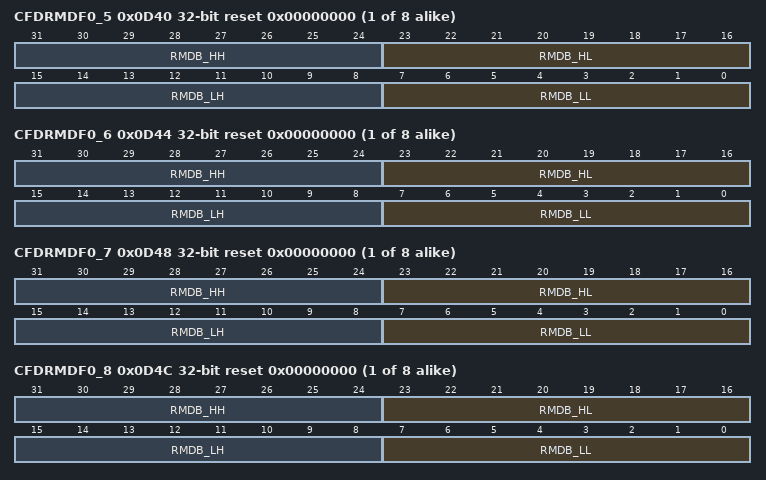
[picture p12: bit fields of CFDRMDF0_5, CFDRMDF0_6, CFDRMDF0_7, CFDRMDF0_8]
                    <name>CFDRMDF%s_5</name>
                    <description>RX Message Buffer Data Field 5 Registers</description>
                    <addressOffset>0x0D40</addressOffset>
                    <size>32</size>
                    <access>read-only</access>
                    <resetValue>0x00000000</resetValue>
                    <resetMask>0xffffffff</resetMask>
                    <fields>
                        <field>
                            <name>RMDB_LL</name>
                            <description>RX Message Buffer Data Byte (p × 4)</description>
                            <lsb>0</lsb>
                            <msb>7</msb>
                            <access>read-only</access>
                        </field>
                        <field>
                            <name>RMDB_LH</name>
                            <description>RX Message Buffer Data Byte ((p × 4) + 1)</description>
                            <lsb>8</lsb>
                            <msb>15</msb>
                            <access>read-only</access>
                        </field>
                        <field>
                            <name>RMDB_HL</name>
                            <description>RX Message Buffer Data Byte ((p × 4) + 2)</description>
                            <lsb>16</lsb>
                            <msb>23</msb>
                            <access>read-only</access>
                        </field>
                        <field>
                            <name>RMDB_HH</name>
                            <description>RX Message Buffer Data Byte ((p × 4) + 3)</description>
                            <lsb>24</lsb>
                            <msb>31</msb>
                            <access>read-only</access>
                        </field>
                    </fields>
                </register>
                <register>
                    <dim>8</dim>
                    <dimIncrement>0x004C</dimIncrement>
                    <dimIndex>8-15</dimIndex>
                    <name>CFDRMDF%s_6</name>
                    <description>RX Message Buffer Data Field 6 Registers</description>
                    <addressOffset>0x0D44</addressOffset>
                    <size>32</size>
                    <access>read-only</access>
                    <resetValue>0x00000000</resetValue>
                    <resetMask>0xffffffff</resetMask>
                    <fields>
                        <field>
                            <name>RMDB_LL</name>
                            <description>RX Message Buffer Data Byte (p × 4)</description>
                            <lsb>0</lsb>
                            <msb>7</msb>
                            <access>read-only</access>
                        </field>
                        <field>
                            <name>RMDB_LH</name>
                            <description>RX Message Buffer Data Byte ((p × 4) + 1)</description>
                            <lsb>8</lsb>
                            <msb>15</msb>
                            <access>read-only</access>
                        </field>
                        <field>
                            <name>RMDB_HL</name>
                            <description>RX Message Buffer Data Byte ((p × 4) + 2)</description>
                            <lsb>16</lsb>
                            <msb>23</msb>
                            <access>read-only</access>
                        </field>
                        <field>
                            <name>RMDB_HH</name>
                            <description>RX Message Buffer Data Byte ((p × 4) + 3)</description>
                            <lsb>24</lsb>
                            <msb>31</msb>
                            <access>read-only</access>
                        </field>
                    </fields>
                </register>
                <register>
                    <dim>8</dim>
                    <dimIncrement>0x004C</dimIncrement>
                    <dimIndex>8-15</dimIndex>
                    <name>CFDRMDF%s_7</name>
                    <description>RX Message Buffer Data Field 7 Registers</description>
                    <addressOffset>0x0D48</addressOffset>
                    <size>32</size>
                    <access>read-only</access>
                    <resetValue>0x00000000</resetValue>
                    <resetMask>0xffffffff</resetMask>
                    <fields>
                        <field>
                            <name>RMDB_LL</name>
                            <description>RX Message Buffer Data Byte (p × 4)</description>
                            <lsb>0</lsb>
                            <msb>7</msb>
                            <access>read-only</access>
                        </field>
                        <field>
                            <name>RMDB_LH</name>
                            <description>RX Message Buffer Data Byte ((p × 4) + 1)</description>
                            <lsb>8</lsb>
                            <msb>15</msb>
                            <access>read-only</access>
                        </field>
                        <field>
                            <name>RMDB_HL</name>
                            <description>RX Message Buffer Data Byte ((p × 4) + 2)</description>
                            <lsb>16</lsb>
                            <msb>23</msb>
                            <access>read-only</access>
                        </field>
                        <field>
                            <name>RMDB_HH</name>
                            <description>RX Message Buffer Data Byte ((p × 4) + 3)</description>
                            <lsb>24</lsb>
                            <msb>31</msb>
                            <access>read-only</access>
                        </field>
                    </fields>
                </register>
                <register>
                    <dim>8</dim>
                    <dimIncrement>0x004C</dimIncrement>
                    <dimIndex>8-15</dimIndex>
                    <name>CFDRMDF%s_8</name>
                    <description>RX Message Buffer Data Field 8 Registers</description>
                    <addressOffset>0x0D4C</addressOffset>
                    <size>32</size>
                    <access>read-only</access>
                    <resetValue>0x00000000</resetValue>
                    <resetMask>0xffffffff</resetMask>
                    <fields>
                        <field>
                            <name>RMDB_LL</name>
                            <description>RX Message Buffer Data Byte (p × 4)</description>
                            <lsb>0</lsb>
                            <msb>7</msb>
                            <access>read-only</access>
                        </field>
                        <field>
                            <name>RMDB_LH</name>
                            <description>RX Message Buffer Data Byte ((p × 4) + 1)</description>
                            <lsb>8</lsb>
                            <msb>15</msb>
                            <access>read-only</access>
                        </field>
                        <field>
                            <name>RMDB_HL</name>
                            <description>RX Message Buffer Data Byte ((p × 4) + 2)</description>
                            <lsb>16</lsb>
                            <msb>23</msb>
                            <access>read-only</access>
                        </field>
                        <field>
                            <name>RMDB_HH</name>
                            <description>RX Message Buffer Data Byte ((p × 4) + 3)</description>
                            <lsb>24</lsb>
                            <msb>31</msb>
                            <access>read-only</access>
                        </field>
                    </fields>
                </register>
                <register>
                    <dim>8</dim>
                    <dimIncrement>0x004C</dimIncrement>
                    <dimIndex>8-15</dimIndex>
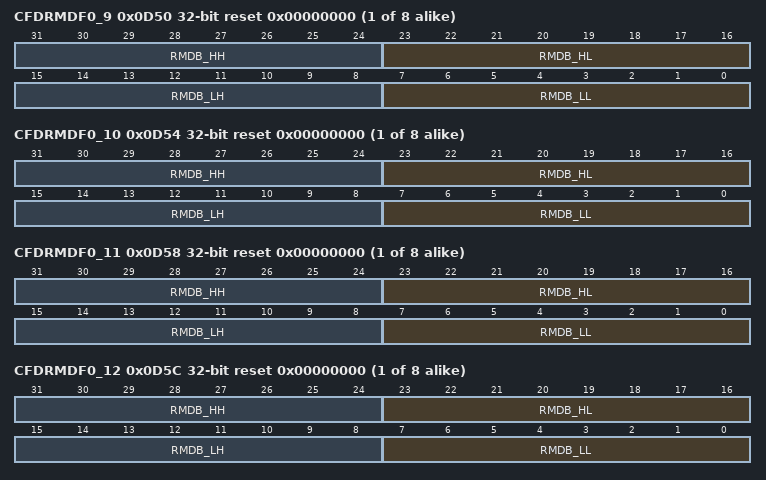
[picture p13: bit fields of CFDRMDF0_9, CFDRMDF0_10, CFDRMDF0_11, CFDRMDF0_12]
                    <name>CFDRMDF%s_9</name>
                    <description>RX Message Buffer Data Field 9 Registers</description>
                    <addressOffset>0x0D50</addressOffset>
                    <size>32</size>
                    <access>read-only</access>
                    <resetValue>0x00000000</resetValue>
                    <resetMask>0xffffffff</resetMask>
                    <fields>
                        <field>
                            <name>RMDB_LL</name>
                            <description>RX Message Buffer Data Byte (p × 4)</description>
                            <lsb>0</lsb>
                            <msb>7</msb>
                            <access>read-only</access>
                        </field>
                        <field>
                            <name>RMDB_LH</name>
                            <description>RX Message Buffer Data Byte ((p × 4) + 1)</description>
                            <lsb>8</lsb>
                            <msb>15</msb>
                            <access>read-only</access>
                        </field>
                        <field>
                            <name>RMDB_HL</name>
                            <description>RX Message Buffer Data Byte ((p × 4) + 2)</description>
                            <lsb>16</lsb>
                            <msb>23</msb>
                            <access>read-only</access>
                        </field>
                        <field>
                            <name>RMDB_HH</name>
                            <description>RX Message Buffer Data Byte ((p × 4) + 3)</description>
                            <lsb>24</lsb>
                            <msb>31</msb>
                            <access>read-only</access>
                        </field>
                    </fields>
                </register>
                <register>
                    <dim>8</dim>
                    <dimIncrement>0x004C</dimIncrement>
                    <dimIndex>8-15</dimIndex>
                    <name>CFDRMDF%s_10</name>
                    <description>RX Message Buffer Data Field 10 Registers</description>
                    <addressOffset>0x0D54</addressOffset>
                    <size>32</size>
                    <access>read-only</access>
                    <resetValue>0x00000000</resetValue>
                    <resetMask>0xffffffff</resetMask>
                    <fields>
                        <field>
                            <name>RMDB_LL</name>
                            <description>RX Message Buffer Data Byte (p × 4)</description>
                            <lsb>0</lsb>
                            <msb>7</msb>
                            <access>read-only</access>
                        </field>
                        <field>
                            <name>RMDB_LH</name>
                            <description>RX Message Buffer Data Byte ((p × 4) + 1)</description>
                            <lsb>8</lsb>
                            <msb>15</msb>
                            <access>read-only</access>
                        </field>
                        <field>
                            <name>RMDB_HL</name>
                            <description>RX Message Buffer Data Byte ((p × 4) + 2)</description>
                            <lsb>16</lsb>
                            <msb>23</msb>
                            <access>read-only</access>
                        </field>
                        <field>
                            <name>RMDB_HH</name>
                            <description>RX Message Buffer Data Byte ((p × 4) + 3)</description>
                            <lsb>24</lsb>
                            <msb>31</msb>
                            <access>read-only</access>
                        </field>
                    </fields>
                </register>
                <register>
                    <dim>8</dim>
                    <dimIncrement>0x004C</dimIncrement>
                    <dimIndex>8-15</dimIndex>
                    <name>CFDRMDF%s_11</name>
                    <description>RX Message Buffer Data Field 11 Registers</description>
                    <addressOffset>0x0D58</addressOffset>
                    <size>32</size>
                    <access>read-only</access>
                    <resetValue>0x00000000</resetValue>
                    <resetMask>0xffffffff</resetMask>
                    <fields>
                        <field>
                            <name>RMDB_LL</name>
                            <description>RX Message Buffer Data Byte (p × 4)</description>
                            <lsb>0</lsb>
                            <msb>7</msb>
                            <access>read-only</access>
                        </field>
                        <field>
                            <name>RMDB_LH</name>
                            <description>RX Message Buffer Data Byte ((p × 4) + 1)</description>
                            <lsb>8</lsb>
                            <msb>15</msb>
                            <access>read-only</access>
                        </field>
                        <field>
                            <name>RMDB_HL</name>
                            <description>RX Message Buffer Data Byte ((p × 4) + 2)</description>
                            <lsb>16</lsb>
                            <msb>23</msb>
                            <access>read-only</access>
                        </field>
                        <field>
                            <name>RMDB_HH</name>
                            <description>RX Message Buffer Data Byte ((p × 4) + 3)</description>
                            <lsb>24</lsb>
                            <msb>31</msb>
                            <access>read-only</access>
                        </field>
                    </fields>
                </register>
                <register>
                    <dim>8</dim>
                    <dimIncrement>0x004C</dimIncrement>
                    <dimIndex>8-15</dimIndex>
                    <name>CFDRMDF%s_12</name>
                    <description>RX Message Buffer Data Field 12 Registers</description>
                    <addressOffset>0x0D5C</addressOffset>
                    <size>32</size>
                    <access>read-only</access>
                    <resetValue>0x00000000</resetValue>
                    <resetMask>0xffffffff</resetMask>
                    <fields>
                        <field>
                            <name>RMDB_LL</name>
                            <description>RX Message Buffer Data Byte (p × 4)</description>
                            <lsb>0</lsb>
                            <msb>7</msb>
                            <access>read-only</access>
                        </field>
                        <field>
                            <name>RMDB_LH</name>
                            <description>RX Message Buffer Data Byte ((p × 4) + 1)</description>
                            <lsb>8</lsb>
                            <msb>15</msb>
                            <access>read-only</access>
                        </field>
                        <field>
                            <name>RMDB_HL</name>
                            <description>RX Message Buffer Data Byte ((p × 4) + 2)</description>
                            <lsb>16</lsb>
                            <msb>23</msb>
                            <access>read-only</access>
                        </field>
                        <field>
                            <name>RMDB_HH</name>
                            <description>RX Message Buffer Data Byte ((p × 4) + 3)</description>
                            <lsb>24</lsb>
                            <msb>31</msb>
                            <access>read-only</access>
                        </field>
                    </fields>
                </register>
                <register>
                    <dim>8</dim>
                    <dimIncrement>0x004C</dimIncrement>
                    <dimIndex>8-15</dimIndex>
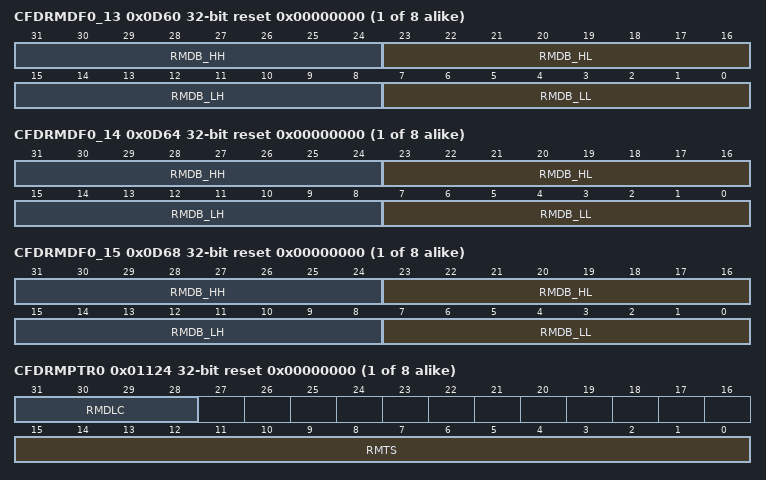
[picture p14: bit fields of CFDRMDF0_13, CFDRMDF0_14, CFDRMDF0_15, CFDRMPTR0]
                    <name>CFDRMDF%s_13</name>
                    <description>RX Message Buffer Data Field 13 Registers</description>
                    <addressOffset>0x0D60</addressOffset>
                    <size>32</size>
                    <access>read-only</access>
                    <resetValue>0x00000000</resetValue>
                    <resetMask>0xffffffff</resetMask>
                    <fields>
                        <field>
                            <name>RMDB_LL</name>
                            <description>RX Message Buffer Data Byte (p × 4)</description>
                            <lsb>0</lsb>
                            <msb>7</msb>
                            <access>read-only</access>
                        </field>
                        <field>
                            <name>RMDB_LH</name>
                            <description>RX Message Buffer Data Byte ((p × 4) + 1)</description>
                            <lsb>8</lsb>
                            <msb>15</msb>
                            <access>read-only</access>
                        </field>
                        <field>
                            <name>RMDB_HL</name>
                            <description>RX Message Buffer Data Byte ((p × 4) + 2)</description>
                            <lsb>16</lsb>
                            <msb>23</msb>
                            <access>read-only</access>
                        </field>
                        <field>
                            <name>RMDB_HH</name>
                            <description>RX Message Buffer Data Byte ((p × 4) + 3)</description>
                            <lsb>24</lsb>
                            <msb>31</msb>
                            <access>read-only</access>
                        </field>
                    </fields>
                </register>
                <register>
                    <dim>8</dim>
                    <dimIncrement>0x004C</dimIncrement>
                    <dimIndex>8-15</dimIndex>
                    <name>CFDRMDF%s_14</name>
                    <description>RX Message Buffer Data Field 14 Registers</description>
                    <addressOffset>0x0D64</addressOffset>
                    <size>32</size>
                    <access>read-only</access>
                    <resetValue>0x00000000</resetValue>
                    <resetMask>0xffffffff</resetMask>
                    <fields>
                        <field>
                            <name>RMDB_LL</name>
                            <description>RX Message Buffer Data Byte (p × 4)</description>
                            <lsb>0</lsb>
                            <msb>7</msb>
                            <access>read-only</access>
                        </field>
                        <field>
                            <name>RMDB_LH</name>
                            <description>RX Message Buffer Data Byte ((p × 4) + 1)</description>
                            <lsb>8</lsb>
                            <msb>15</msb>
                            <access>read-only</access>
                        </field>
                        <field>
                            <name>RMDB_HL</name>
                            <description>RX Message Buffer Data Byte ((p × 4) + 2)</description>
                            <lsb>16</lsb>
                            <msb>23</msb>
                            <access>read-only</access>
                        </field>
                        <field>
                            <name>RMDB_HH</name>
                            <description>RX Message Buffer Data Byte ((p × 4) + 3)</description>
                            <lsb>24</lsb>
                            <msb>31</msb>
                            <access>read-only</access>
                        </field>
                    </fields>
                </register>
                <register>
                    <dim>8</dim>
                    <dimIncrement>0x004C</dimIncrement>
                    <dimIndex>8-15</dimIndex>
                    <name>CFDRMDF%s_15</name>
                    <description>RX Message Buffer Data Field 15 Registers</description>
                    <addressOffset>0x0D68</addressOffset>
                    <size>32</size>
                    <access>read-only</access>
                    <resetValue>0x00000000</resetValue>
                    <resetMask>0xffffffff</resetMask>
                    <fields>
                        <field>
                            <name>RMDB_LL</name>
                            <description>RX Message Buffer Data Byte (p × 4)</description>
                            <lsb>0</lsb>
                            <msb>7</msb>
                            <access>read-only</access>
                        </field>
                        <field>
                            <name>RMDB_LH</name>
                            <description>RX Message Buffer Data Byte ((p × 4) + 1)</description>
                            <lsb>8</lsb>
                            <msb>15</msb>
                            <access>read-only</access>
                        </field>
                        <field>
                            <name>RMDB_HL</name>
                            <description>RX Message Buffer Data Byte ((p × 4) + 2)</description>
                            <lsb>16</lsb>
                            <msb>23</msb>
                            <access>read-only</access>
                        </field>
                        <field>
                            <name>RMDB_HH</name>
                            <description>RX Message Buffer Data Byte ((p × 4) + 3)</description>
                            <lsb>24</lsb>
                            <msb>31</msb>
                            <access>read-only</access>
                        </field>
                    </fields>
                </register>
                <register>
                    <dim>8</dim>
                    <dimIncrement>0x004C</dimIncrement>
                    <dimIndex>16-23</dimIndex>
                    <name>CFDRMPTR%s</name>
                    <description>RX Message Buffer Pointer Registers</description>
                    <addressOffset>0x01124</addressOffset>
                    <size>32</size>
                    <access>read-only</access>
                    <resetValue>0x00000000</resetValue>
                    <resetMask>0xffffffff</resetMask>
                    <fields>
                        <field>
                            <name>RMTS</name>
                            <description>RX Message Buffer Timestamp Field</description>
                            <lsb>0</lsb>
                            <msb>15</msb>
                            <access>read-only</access>
                        </field>
                        <field>
                            <name>RMDLC</name>
                            <description>RX Message Buffer DLC Field</description>
                            <lsb>28</lsb>
                            <msb>31</msb>
                            <access>read-only</access>
                        </field>
                    </fields>
                </register>
                <register>
                    <dim>8</dim>
                    <dimIncrement>0x004C</dimIncrement>
                    <dimIndex>16-23</dimIndex>
                    <name>CFDRMFDSTS%s</name>
                    <description>RX Message Buffer CANFD Status Registers</description>
                    <addressOffset>0x01128</addressOffset>
                    <size>32</size>
                    <access>read-only</access>
                    <resetValue>0x00000000</resetValue>
                    <resetMask>0xffffffff</resetMask>
                    <fields>
                        <field>
                            <name>RMESI</name>
                            <description>Error State Indicator bit</description>
                            <lsb>0</lsb>
                            <msb>0</msb>
                            <access>read-only</access>
                            <enumeratedValues>
                                <enumeratedValue>
                                    <name>0</name>
                                    <description>CANFD frame received from error active node</description>
                                    <value>#0</value>
                                </enumeratedValue>
                                <enumeratedValue>
                                    <name>1</name>
                                    <description>CANFD frame received from error passive node</description>
                                    <value>#1</value>
                                </enumeratedValue>
                            </enumeratedValues>
                        </field>
                        <field>
                            <name>RMBRS</name>
                            <description>Bit Rate Switch bit</description>
                            <lsb>1</lsb>
                            <msb>1</msb>
                            <access>read-only</access>
                            <enumeratedValues>
                                <enumeratedValue>
                                    <name>0</name>
                                    <description>CANFD frame received with no bit rate switch</description>
                                    <value>#0</value>
                                </enumeratedValue>
                                <enumeratedValue>
                                    <name>1</name>
                                    <description>CANFD frame received with bit rate switch</description>
                                    <value>#1</value>
                                </enumeratedValue>
                            </enumeratedValues>
                        </field>
                        <field>
                            <name>RMFDF</name>
                            <description>CAN FD Format bit</description>
                            <lsb>2</lsb>
                            <msb>2</msb>
                            <access>read-only</access>
                            <enumeratedValues>
                                <enumeratedValue>
                                    <name>0</name>
                                    <description>Non CANFD frame received</description>
                                    <value>#0</value>
                                </enumeratedValue>
                                <enumeratedValue>
                                    <name>1</name>
                                    <description>CANFD frame received</description>
                                    <value>#1</value>
                                </enumeratedValue>
                            </enumeratedValues>
                        </field>
                        <field>
                            <name>RMIFL</name>
                            <description>RX Message Buffer Information Label Field</description>
                            <lsb>8</lsb>
                            <msb>9</msb>
                            <access>read-only</access>
                        </field>
                        <field>
                            <name>RMPTR</name>
                            <description>RX Message Buffer Pointer Field</description>
                            <lsb>16</lsb>
                            <msb>31</msb>
                            <access>read-only</access>
                        </field>
                    </fields>
                </register>
                <register>
                    <dim>8</dim>
                    <dimIncrement>0x004C</dimIncrement>
                    <dimIndex>16-23</dimIndex>
                    <name>CFDRMDF%s_0</name>
                    <description>RX Message Buffer Data Field 0 Registers</description>
                    <addressOffset>0x112C</addressOffset>
                    <size>32</size>
                    <access>read-only</access>
                    <resetValue>0x00000000</resetValue>
                    <resetMask>0xffffffff</resetMask>
                    <fields>
                        <field>
                            <name>RMDB_LL</name>
                            <description>RX Message Buffer Data Byte (p × 4)</description>
                            <lsb>0</lsb>
                            <msb>7</msb>
                            <access>read-only</access>
                        </field>
                        <field>
                            <name>RMDB_LH</name>
                            <description>RX Message Buffer Data Byte ((p × 4) + 1)</description>
                            <lsb>8</lsb>
                            <msb>15</msb>
                            <access>read-only</access>
                        </field>
                        <field>
                            <name>RMDB_HL</name>
                            <description>RX Message Buffer Data Byte ((p × 4) + 2)</description>
                            <lsb>16</lsb>
                            <msb>23</msb>
                            <access>read-only</access>
                        </field>
                        <field>
                            <name>RMDB_HH</name>
                            <description>RX Message Buffer Data Byte ((p × 4) + 3)</description>
                            <lsb>24</lsb>
                            <msb>31</msb>
                            <access>read-only</access>
                        </field>
                    </fields>
                </register>
                <register>
                    <dim>8</dim>
                    <dimIncrement>0x004C</dimIncrement>
                    <dimIndex>16-23</dimIndex>
                    <name>CFDRMDF%s_1</name>
                    <description>RX Message Buffer Data Field 1 Registers</description>
                    <addressOffset>0x1130</addressOffset>
                    <size>32</size>
                    <access>read-only</access>
                    <resetValue>0x00000000</resetValue>
                    <resetMask>0xffffffff</resetMask>
                    <fields>
                        <field>
                            <name>RMDB_LL</name>
                            <description>RX Message Buffer Data Byte (p × 4)</description>
                            <lsb>0</lsb>
                            <msb>7</msb>
                            <access>read-only</access>
                        </field>
                        <field>
                            <name>RMDB_LH</name>
                            <description>RX Message Buffer Data Byte ((p × 4) + 1)</description>
                            <lsb>8</lsb>
                            <msb>15</msb>
                            <access>read-only</access>
                        </field>
                        <field>
                            <name>RMDB_HL</name>
                            <description>RX Message Buffer Data Byte ((p × 4) + 2)</description>
                            <lsb>16</lsb>
                            <msb>23</msb>
                            <access>read-only</access>
                        </field>
                        <field>
                            <name>RMDB_HH</name>
                            <description>RX Message Buffer Data Byte ((p × 4) + 3)</description>
                            <lsb>24</lsb>
                            <msb>31</msb>
                            <access>read-only</access>
                        </field>
                    </fields>
                </register>
                <register>
                    <dim>8</dim>
                    <dimIncrement>0x004C</dimIncrement>
                    <dimIndex>16-23</dimIndex>
                    <name>CFDRMDF%s_2</name>
                    <description>RX Message Buffer Data Field 2 Registers</description>
                    <addressOffset>0x1134</addressOffset>
                    <size>32</size>
                    <access>read-only</access>
                    <resetValue>0x00000000</resetValue>
                    <resetMask>0xffffffff</resetMask>
                    <fields>
                        <field>
                            <name>RMDB_LL</name>
                            <description>RX Message Buffer Data Byte (p × 4)</description>
                            <lsb>0</lsb>
                            <msb>7</msb>
                            <access>read-only</access>
                        </field>
                        <field>
                            <name>RMDB_LH</name>
                            <description>RX Message Buffer Data Byte ((p × 4) + 1)</description>
                            <lsb>8</lsb>
                            <msb>15</msb>
                            <access>read-only</access>
                        </field>
                        <field>
                            <name>RMDB_HL</name>
                            <description>RX Message Buffer Data Byte ((p × 4) + 2)</description>
                            <lsb>16</lsb>
                            <msb>23</msb>
                            <access>read-only</access>
                        </field>
                        <field>
                            <name>RMDB_HH</name>
                            <description>RX Message Buffer Data Byte ((p × 4) + 3)</description>
                            <lsb>24</lsb>
                            <msb>31</msb>
                            <access>read-only</access>
                        </field>
                    </fields>
                </register>
                <register>
                    <dim>8</dim>
                    <dimIncrement>0x004C</dimIncrement>
                    <dimIndex>16-23</dimIndex>
                    <name>CFDRMDF%s_3</name>
                    <description>RX Message Buffer Data Field 3 Registers</description>
                    <addressOffset>0x1138</addressOffset>
                    <size>32</size>
                    <access>read-only</access>
                    <resetValue>0x00000000</resetValue>
                    <resetMask>0xffffffff</resetMask>
                    <fields>
                        <field>
                            <name>RMDB_LL</name>
                            <description>RX Message Buffer Data Byte (p × 4)</description>
                            <lsb>0</lsb>
                            <msb>7</msb>
                            <access>read-only</access>
                        </field>
                        <field>
                            <name>RMDB_LH</name>
                            <description>RX Message Buffer Data Byte ((p × 4) + 1)</description>
                            <lsb>8</lsb>
                            <msb>15</msb>
                            <access>read-only</access>
                        </field>
                        <field>
                            <name>RMDB_HL</name>
                            <description>RX Message Buffer Data Byte ((p × 4) + 2)</description>
                            <lsb>16</lsb>
                            <msb>23</msb>
                            <access>read-only</access>
                        </field>
                        <field>
                            <name>RMDB_HH</name>
                            <description>RX Message Buffer Data Byte ((p × 4) + 3)</description>
                            <lsb>24</lsb>
                            <msb>31</msb>
                            <access>read-only</access>
                        </field>
                    </fields>
                </register>
                <register>
                    <dim>8</dim>
                    <dimIncrement>0x004C</dimIncrement>
                    <dimIndex>16-23</dimIndex>
                    <name>CFDRMDF%s_4</name>
                    <description>RX Message Buffer Data Field 4 Registers</description>
                    <addressOffset>0x113C</addressOffset>
                    <size>32</size>
                    <access>read-only</access>
                    <resetValue>0x00000000</resetValue>
                    <resetMask>0xffffffff</resetMask>
                    <fields>
                        <field>
                            <name>RMDB_LL</name>
                            <description>RX Message Buffer Data Byte (p × 4)</description>
                            <lsb>0</lsb>
                            <msb>7</msb>
                            <access>read-only</access>
                        </field>
                        <field>
                            <name>RMDB_LH</name>
                            <description>RX Message Buffer Data Byte ((p × 4) + 1)</description>
                            <lsb>8</lsb>
                            <msb>15</msb>
                            <access>read-only</access>
                        </field>
                        <field>
                            <name>RMDB_HL</name>
                            <description>RX Message Buffer Data Byte ((p × 4) + 2)</description>
                            <lsb>16</lsb>
                            <msb>23</msb>
                            <access>read-only</access>
                        </field>
                        <field>
                            <name>RMDB_HH</name>
                            <description>RX Message Buffer Data Byte ((p × 4) + 3)</description>
                            <lsb>24</lsb>
                            <msb>31</msb>
                            <access>read-only</access>
                        </field>
                    </fields>
                </register>
                <register>
                    <dim>8</dim>
                    <dimIncrement>0x004C</dimIncrement>
                    <dimIndex>16-23</dimIndex>
                    <name>CFDRMDF%s_5</name>
                    <description>RX Message Buffer Data Field 5 Registers</description>
                    <addressOffset>0x1140</addressOffset>
                    <size>32</size>
                    <access>read-only</access>
                    <resetValue>0x00000000</resetValue>
                    <resetMask>0xffffffff</resetMask>
                    <fields>
                        <field>
                            <name>RMDB_LL</name>
                            <description>RX Message Buffer Data Byte (p × 4)</description>
                            <lsb>0</lsb>
                            <msb>7</msb>
                            <access>read-only</access>
                        </field>
                        <field>
                            <name>RMDB_LH</name>
                            <description>RX Message Buffer Data Byte ((p × 4) + 1)</description>
                            <lsb>8</lsb>
                            <msb>15</msb>
                            <access>read-only</access>
                        </field>
                        <field>
                            <name>RMDB_HL</name>
                            <description>RX Message Buffer Data Byte ((p × 4) + 2)</description>
                            <lsb>16</lsb>
                            <msb>23</msb>
                            <access>read-only</access>
                        </field>
                        <field>
                            <name>RMDB_HH</name>
                            <description>RX Message Buffer Data Byte ((p × 4) + 3)</description>
                            <lsb>24</lsb>
                            <msb>31</msb>
                            <access>read-only</access>
                        </field>
                    </fields>
                </register>
                <register>
                    <dim>8</dim>
                    <dimIncrement>0x004C</dimIncrement>
                    <dimIndex>16-23</dimIndex>
                    <name>CFDRMDF%s_6</name>
                    <description>RX Message Buffer Data Field 6 Registers</description>
                    <addressOffset>0x1144</addressOffset>
                    <size>32</size>
                    <access>read-only</access>
                    <resetValue>0x00000000</resetValue>
                    <resetMask>0xffffffff</resetMask>
                    <fields>
                        <field>
                            <name>RMDB_LL</name>
                            <description>RX Message Buffer Data Byte (p × 4)</description>
                            <lsb>0</lsb>
                            <msb>7</msb>
                            <access>read-only</access>
                        </field>
                        <field>
                            <name>RMDB_LH</name>
                            <description>RX Message Buffer Data Byte ((p × 4) + 1)</description>
                            <lsb>8</lsb>
                            <msb>15</msb>
                            <access>read-only</access>
                        </field>
                        <field>
                            <name>RMDB_HL</name>
                            <description>RX Message Buffer Data Byte ((p × 4) + 2)</description>
                            <lsb>16</lsb>
                            <msb>23</msb>
                            <access>read-only</access>
                        </field>
                        <field>
                            <name>RMDB_HH</name>
                            <description>RX Message Buffer Data Byte ((p × 4) + 3)</description>
                            <lsb>24</lsb>
                            <msb>31</msb>
                            <access>read-only</access>
                        </field>
                    </fields>
                </register>
                <register>
                    <dim>8</dim>
                    <dimIncrement>0x004C</dimIncrement>
                    <dimIndex>16-23</dimIndex>
                    <name>CFDRMDF%s_7</name>
                    <description>RX Message Buffer Data Field 7 Registers</description>
                    <addressOffset>0x1148</addressOffset>
                    <size>32</size>
                    <access>read-only</access>
                    <resetValue>0x00000000</resetValue>
                    <resetMask>0xffffffff</resetMask>
                    <fields>
                        <field>
                            <name>RMDB_LL</name>
                            <description>RX Message Buffer Data Byte (p × 4)</description>
                            <lsb>0</lsb>
                            <msb>7</msb>
                            <access>read-only</access>
                        </field>
                        <field>
                            <name>RMDB_LH</name>
                            <description>RX Message Buffer Data Byte ((p × 4) + 1)</description>
                            <lsb>8</lsb>
                            <msb>15</msb>
                            <access>read-only</access>
                        </field>
                        <field>
                            <name>RMDB_HL</name>
                            <description>RX Message Buffer Data Byte ((p × 4) + 2)</description>
                            <lsb>16</lsb>
                            <msb>23</msb>
                            <access>read-only</access>
                        </field>
                        <field>
                            <name>RMDB_HH</name>
                            <description>RX Message Buffer Data Byte ((p × 4) + 3)</description>
                            <lsb>24</lsb>
                            <msb>31</msb>
                            <access>read-only</access>
                        </field>
                    </fields>
                </register>
                <register>
                    <dim>8</dim>
                    <dimIncrement>0x004C</dimIncrement>
                    <dimIndex>16-23</dimIndex>
                    <name>CFDRMDF%s_8</name>
                    <description>RX Message Buffer Data Field 8 Registers</description>
                    <addressOffset>0x114C</addressOffset>
                    <size>32</size>
                    <access>read-only</access>
                    <resetValue>0x00000000</resetValue>
                    <resetMask>0xffffffff</resetMask>
                    <fields>
                        <field>
                            <name>RMDB_LL</name>
                            <description>RX Message Buffer Data Byte (p × 4)</description>
                            <lsb>0</lsb>
                            <msb>7</msb>
                            <access>read-only</access>
                        </field>
                        <field>
                            <name>RMDB_LH</name>
                            <description>RX Message Buffer Data Byte ((p × 4) + 1)</description>
                            <lsb>8</lsb>
                            <msb>15</msb>
                            <access>read-only</access>
                        </field>
                        <field>
                            <name>RMDB_HL</name>
                            <description>RX Message Buffer Data Byte ((p × 4) + 2)</description>
                            <lsb>16</lsb>
                            <msb>23</msb>
                            <access>read-only</access>
                        </field>
                        <field>
                            <name>RMDB_HH</name>
                            <description>RX Message Buffer Data Byte ((p × 4) + 3)</description>
                            <lsb>24</lsb>
                            <msb>31</msb>
                            <access>read-only</access>
                        </field>
                    </fields>
                </register>
                <register>
                    <dim>8</dim>
                    <dimIncrement>0x004C</dimIncrement>
                    <dimIndex>16-23</dimIndex>
                    <name>CFDRMDF%s_9</name>
                    <description>RX Message Buffer Data Field 9 Registers</description>
                    <addressOffset>0x1150</addressOffset>
                    <size>32</size>
                    <access>read-only</access>
                    <resetValue>0x00000000</resetValue>
                    <resetMask>0xffffffff</resetMask>
                    <fields>
                        <field>
                            <name>RMDB_LL</name>
                            <description>RX Message Buffer Data Byte (p × 4)</description>
                            <lsb>0</lsb>
                            <msb>7</msb>
                            <access>read-only</access>
                        </field>
                        <field>
                            <name>RMDB_LH</name>
                            <description>RX Message Buffer Data Byte ((p × 4) + 1)</description>
                            <lsb>8</lsb>
                            <msb>15</msb>
                            <access>read-only</access>
                        </field>
                        <field>
                            <name>RMDB_HL</name>
                            <description>RX Message Buffer Data Byte ((p × 4) + 2)</description>
                            <lsb>16</lsb>
                            <msb>23</msb>
                            <access>read-only</access>
                        </field>
                        <field>
                            <name>RMDB_HH</name>
                            <description>RX Message Buffer Data Byte ((p × 4) + 3)</description>
                            <lsb>24</lsb>
                            <msb>31</msb>
                            <access>read-only</access>
                        </field>
                    </fields>
                </register>
                <register>
                    <dim>8</dim>
                    <dimIncrement>0x004C</dimIncrement>
                    <dimIndex>16-23</dimIndex>
                    <name>CFDRMDF%s_10</name>
                    <description>RX Message Buffer Data Field 10 Registers</description>
                    <addressOffset>0x1154</addressOffset>
                    <size>32</size>
                    <access>read-only</access>
                    <resetValue>0x00000000</resetValue>
                    <resetMask>0xffffffff</resetMask>
                    <fields>
                        <field>
                            <name>RMDB_LL</name>
                            <description>RX Message Buffer Data Byte (p × 4)</description>
                            <lsb>0</lsb>
                            <msb>7</msb>
                            <access>read-only</access>
                        </field>
                        <field>
                            <name>RMDB_LH</name>
                            <description>RX Message Buffer Data Byte ((p × 4) + 1)</description>
                            <lsb>8</lsb>
                            <msb>15</msb>
                            <access>read-only</access>
                        </field>
                        <field>
                            <name>RMDB_HL</name>
                            <description>RX Message Buffer Data Byte ((p × 4) + 2)</description>
                            <lsb>16</lsb>
                            <msb>23</msb>
                            <access>read-only</access>
                        </field>
                        <field>
                            <name>RMDB_HH</name>
                            <description>RX Message Buffer Data Byte ((p × 4) + 3)</description>
                            <lsb>24</lsb>
                            <msb>31</msb>
                            <access>read-only</access>
                        </field>
                    </fields>
                </register>
                <register>
                    <dim>8</dim>
                    <dimIncrement>0x004C</dimIncrement>
                    <dimIndex>16-23</dimIndex>
                    <name>CFDRMDF%s_11</name>
                    <description>RX Message Buffer Data Field 11 Registers</description>
                    <addressOffset>0x1158</addressOffset>
                    <size>32</size>
                    <access>read-only</access>
                    <resetValue>0x00000000</resetValue>
                    <resetMask>0xffffffff</resetMask>
                    <fields>
                        <field>
                            <name>RMDB_LL</name>
                            <description>RX Message Buffer Data Byte (p × 4)</description>
                            <lsb>0</lsb>
                            <msb>7</msb>
                            <access>read-only</access>
                        </field>
                        <field>
                            <name>RMDB_LH</name>
                            <description>RX Message Buffer Data Byte ((p × 4) + 1)</description>
                            <lsb>8</lsb>
                            <msb>15</msb>
                            <access>read-only</access>
                        </field>
                        <field>
                            <name>RMDB_HL</name>
                            <description>RX Message Buffer Data Byte ((p × 4) + 2)</description>
                            <lsb>16</lsb>
                            <msb>23</msb>
                            <access>read-only</access>
                        </field>
                        <field>
                            <name>RMDB_HH</name>
                            <description>RX Message Buffer Data Byte ((p × 4) + 3)</description>
                            <lsb>24</lsb>
                            <msb>31</msb>
                            <access>read-only</access>
                        </field>
                    </fields>
                </register>
                <register>
                    <dim>8</dim>
                    <dimIncrement>0x004C</dimIncrement>
                    <dimIndex>16-23</dimIndex>
                    <name>CFDRMDF%s_12</name>
                    <description>RX Message Buffer Data Field 12 Registers</description>
                    <addressOffset>0x115C</addressOffset>
                    <size>32</size>
                    <access>read-only</access>
                    <resetValue>0x00000000</resetValue>
                    <resetMask>0xffffffff</resetMask>
                    <fields>
                        <field>
                            <name>RMDB_LL</name>
                            <description>RX Message Buffer Data Byte (p × 4)</description>
                            <lsb>0</lsb>
                            <msb>7</msb>
                            <access>read-only</access>
                        </field>
                        <field>
                            <name>RMDB_LH</name>
                            <description>RX Message Buffer Data Byte ((p × 4) + 1)</description>
                            <lsb>8</lsb>
                            <msb>15</msb>
                            <access>read-only</access>
                        </field>
                        <field>
                            <name>RMDB_HL</name>
                            <description>RX Message Buffer Data Byte ((p × 4) + 2)</description>
                            <lsb>16</lsb>
                            <msb>23</msb>
                            <access>read-only</access>
                        </field>
                        <field>
                            <name>RMDB_HH</name>
                            <description>RX Message Buffer Data Byte ((p × 4) + 3)</description>
                            <lsb>24</lsb>
                            <msb>31</msb>
                            <access>read-only</access>
                        </field>
                    </fields>
                </register>
                <register>
                    <dim>8</dim>
                    <dimIncrement>0x004C</dimIncrement>
                    <dimIndex>16-23</dimIndex>
                    <name>CFDRMDF%s_13</name>
                    <description>RX Message Buffer Data Field 13 Registers</description>
                    <addressOffset>0x1160</addressOffset>
                    <size>32</size>
                    <access>read-only</access>
                    <resetValue>0x00000000</resetValue>
                    <resetMask>0xffffffff</resetMask>
                    <fields>
                        <field>
                            <name>RMDB_LL</name>
                            <description>RX Message Buffer Data Byte (p × 4)</description>
                            <lsb>0</lsb>
                            <msb>7</msb>
                            <access>read-only</access>
                        </field>
                        <field>
                            <name>RMDB_LH</name>
                            <description>RX Message Buffer Data Byte ((p × 4) + 1)</description>
                            <lsb>8</lsb>
                            <msb>15</msb>
                            <access>read-only</access>
                        </field>
                        <field>
                            <name>RMDB_HL</name>
                            <description>RX Message Buffer Data Byte ((p × 4) + 2)</description>
                            <lsb>16</lsb>
                            <msb>23</msb>
                            <access>read-only</access>
                        </field>
                        <field>
                            <name>RMDB_HH</name>
                            <description>RX Message Buffer Data Byte ((p × 4) + 3)</description>
                            <lsb>24</lsb>
                            <msb>31</msb>
                            <access>read-only</access>
                        </field>
                    </fields>
                </register>
                <register>
                    <dim>8</dim>
                    <dimIncrement>0x004C</dimIncrement>
                    <dimIndex>16-23</dimIndex>
                    <name>CFDRMDF%s_14</name>
                    <description>RX Message Buffer Data Field 14 Registers</description>
                    <addressOffset>0x1164</addressOffset>
                    <size>32</size>
                    <access>read-only</access>
                    <resetValue>0x00000000</resetValue>
                    <resetMask>0xffffffff</resetMask>
                    <fields>
                        <field>
                            <name>RMDB_LL</name>
                            <description>RX Message Buffer Data Byte (p × 4)</description>
                            <lsb>0</lsb>
                            <msb>7</msb>
                            <access>read-only</access>
                        </field>
                        <field>
                            <name>RMDB_LH</name>
                            <description>RX Message Buffer Data Byte ((p × 4) + 1)</description>
                            <lsb>8</lsb>
                            <msb>15</msb>
                            <access>read-only</access>
                        </field>
                        <field>
                            <name>RMDB_HL</name>
                            <description>RX Message Buffer Data Byte ((p × 4) + 2)</description>
                            <lsb>16</lsb>
                            <msb>23</msb>
                            <access>read-only</access>
                        </field>
                        <field>
                            <name>RMDB_HH</name>
                            <description>RX Message Buffer Data Byte ((p × 4) + 3)</description>
                            <lsb>24</lsb>
                            <msb>31</msb>
                            <access>read-only</access>
                        </field>
                    </fields>
                </register>
                <register>
                    <dim>8</dim>
                    <dimIncrement>0x004C</dimIncrement>
                    <dimIndex>16-23</dimIndex>
                    <name>CFDRMDF%s_15</name>
                    <description>RX Message Buffer Data Field 15 Registers</description>
                    <addressOffset>0x1168</addressOffset>
                    <size>32</size>
                    <access>read-only</access>
                    <resetValue>0x00000000</resetValue>
                    <resetMask>0xffffffff</resetMask>
                    <fields>
                        <field>
                            <name>RMDB_LL</name>
                            <description>RX Message Buffer Data Byte (p × 4)</description>
                            <lsb>0</lsb>
                            <msb>7</msb>
                            <access>read-only</access>
                        </field>
                        <field>
                            <name>RMDB_LH</name>
                            <description>RX Message Buffer Data Byte ((p × 4) + 1)</description>
                            <lsb>8</lsb>
                            <msb>15</msb>
                            <access>read-only</access>
                        </field>
                        <field>
                            <name>RMDB_HL</name>
                            <description>RX Message Buffer Data Byte ((p × 4) + 2)</description>
                            <lsb>16</lsb>
                            <msb>23</msb>
                            <access>read-only</access>
                        </field>
                        <field>
                            <name>RMDB_HH</name>
                            <description>RX Message Buffer Data Byte ((p × 4) + 3)</description>
                            <lsb>24</lsb>
                            <msb>31</msb>
                            <access>read-only</access>
                        </field>
                    </fields>
                </register>
                <register>
                    <dim>8</dim>
                    <dimIncrement>0x004C</dimIncrement>
                    <dimIndex>24-31</dimIndex>
                    <name>CFDRMPTR%s</name>
                    <description>RX Message Buffer Pointer Registers</description>
                    <addressOffset>0x01524</addressOffset>
                    <size>32</size>
                    <access>read-only</access>
                    <resetValue>0x00000000</resetValue>
                    <resetMask>0xffffffff</resetMask>
                    <fields>
                        <field>
                            <name>RMTS</name>
                            <description>RX Message Buffer Timestamp Field</description>
                            <lsb>0</lsb>
                            <msb>15</msb>
                            <access>read-only</access>
                        </field>
                        <field>
                            <name>RMDLC</name>
                            <description>RX Message Buffer DLC Field</description>
                            <lsb>28</lsb>
                            <msb>31</msb>
                            <access>read-only</access>
                        </field>
                    </fields>
                </register>
                <register>
                    <dim>8</dim>
                    <dimIncrement>0x004C</dimIncrement>
                    <dimIndex>24-31</dimIndex>
                    <name>CFDRMFDSTS%s</name>
                    <description>RX Message Buffer CANFD Status Registers</description>
                    <addressOffset>0x01528</addressOffset>
                    <size>32</size>
                    <access>read-only</access>
                    <resetValue>0x00000000</resetValue>
                    <resetMask>0xffffffff</resetMask>
                    <fields>
                        <field>
                            <name>RMESI</name>
                            <description>Error State Indicator bit</description>
                            <lsb>0</lsb>
                            <msb>0</msb>
                            <access>read-only</access>
                            <enumeratedValues>
                                <enumeratedValue>
                                    <name>0</name>
                                    <description>CANFD frame received from error active node</description>
                                    <value>#0</value>
                                </enumeratedValue>
                                <enumeratedValue>
                                    <name>1</name>
                                    <description>CANFD frame received from error passive node</description>
                                    <value>#1</value>
                                </enumeratedValue>
                            </enumeratedValues>
                        </field>
                        <field>
                            <name>RMBRS</name>
                            <description>Bit Rate Switch bit</description>
                            <lsb>1</lsb>
                            <msb>1</msb>
                            <access>read-only</access>
                            <enumeratedValues>
                                <enumeratedValue>
                                    <name>0</name>
                                    <description>CANFD frame received with no bit rate switch</description>
                                    <value>#0</value>
                                </enumeratedValue>
                                <enumeratedValue>
                                    <name>1</name>
                                    <description>CANFD frame received with bit rate switch</description>
                                    <value>#1</value>
                                </enumeratedValue>
                            </enumeratedValues>
                        </field>
                        <field>
                            <name>RMFDF</name>
                            <description>CAN FD Format bit</description>
                            <lsb>2</lsb>
                            <msb>2</msb>
                            <access>read-only</access>
                            <enumeratedValues>
                                <enumeratedValue>
                                    <name>0</name>
                                    <description>Non CANFD frame received</description>
                                    <value>#0</value>
                                </enumeratedValue>
                                <enumeratedValue>
                                    <name>1</name>
                                    <description>CANFD frame received</description>
                                    <value>#1</value>
                                </enumeratedValue>
                            </enumeratedValues>
                        </field>
                        <field>
                            <name>RMIFL</name>
                            <description>RX Message Buffer Information Label Field</description>
                            <lsb>8</lsb>
                            <msb>9</msb>
                            <access>read-only</access>
                        </field>
                        <field>
                            <name>RMPTR</name>
                            <description>RX Message Buffer Pointer Field</description>
                            <lsb>16</lsb>
                            <msb>31</msb>
                            <access>read-only</access>
                        </field>
                    </fields>
                </register>
                <register>
                    <dim>8</dim>
                    <dimIncrement>0x004C</dimIncrement>
                    <dimIndex>24-31</dimIndex>
                    <name>CFDRMDF%s_0</name>
                    <description>RX Message Buffer Data Field 0 Registers</description>
                    <addressOffset>0x152C</addressOffset>
                    <size>32</size>
                    <access>read-only</access>
                    <resetValue>0x00000000</resetValue>
                    <resetMask>0xffffffff</resetMask>
                    <fields>
                        <field>
                            <name>RMDB_LL</name>
                            <description>RX Message Buffer Data Byte (p × 4)</description>
                            <lsb>0</lsb>
                            <msb>7</msb>
                            <access>read-only</access>
                        </field>
                        <field>
                            <name>RMDB_LH</name>
                            <description>RX Message Buffer Data Byte ((p × 4) + 1)</description>
                            <lsb>8</lsb>
                            <msb>15</msb>
                            <access>read-only</access>
                        </field>
                        <field>
                            <name>RMDB_HL</name>
                            <description>RX Message Buffer Data Byte ((p × 4) + 2)</description>
                            <lsb>16</lsb>
                            <msb>23</msb>
                            <access>read-only</access>
                        </field>
                        <field>
                            <name>RMDB_HH</name>
                            <description>RX Message Buffer Data Byte ((p × 4) + 3)</description>
                            <lsb>24</lsb>
                            <msb>31</msb>
                            <access>read-only</access>
                        </field>
                    </fields>
                </register>
                <register>
                    <dim>8</dim>
                    <dimIncrement>0x004C</dimIncrement>
                    <dimIndex>24-31</dimIndex>
                    <name>CFDRMDF%s_1</name>
                    <description>RX Message Buffer Data Field 1 Registers</description>
                    <addressOffset>0x1530</addressOffset>
                    <size>32</size>
                    <access>read-only</access>
                    <resetValue>0x00000000</resetValue>
                    <resetMask>0xffffffff</resetMask>
                    <fields>
                        <field>
                            <name>RMDB_LL</name>
                            <description>RX Message Buffer Data Byte (p × 4)</description>
                            <lsb>0</lsb>
                            <msb>7</msb>
                            <access>read-only</access>
                        </field>
                        <field>
                            <name>RMDB_LH</name>
                            <description>RX Message Buffer Data Byte ((p × 4) + 1)</description>
                            <lsb>8</lsb>
                            <msb>15</msb>
                            <access>read-only</access>
                        </field>
                        <field>
                            <name>RMDB_HL</name>
                            <description>RX Message Buffer Data Byte ((p × 4) + 2)</description>
                            <lsb>16</lsb>
                            <msb>23</msb>
                            <access>read-only</access>
                        </field>
                        <field>
                            <name>RMDB_HH</name>
                            <description>RX Message Buffer Data Byte ((p × 4) + 3)</description>
                            <lsb>24</lsb>
                            <msb>31</msb>
                            <access>read-only</access>
                        </field>
                    </fields>
                </register>
                <register>
                    <dim>8</dim>
                    <dimIncrement>0x004C</dimIncrement>
                    <dimIndex>24-31</dimIndex>
                    <name>CFDRMDF%s_2</name>
                    <description>RX Message Buffer Data Field 2 Registers</description>
                    <addressOffset>0x1534</addressOffset>
                    <size>32</size>
                    <access>read-only</access>
                    <resetValue>0x00000000</resetValue>
                    <resetMask>0xffffffff</resetMask>
                    <fields>
                        <field>
                            <name>RMDB_LL</name>
                            <description>RX Message Buffer Data Byte (p × 4)</description>
                            <lsb>0</lsb>
                            <msb>7</msb>
                            <access>read-only</access>
                        </field>
                        <field>
                            <name>RMDB_LH</name>
                            <description>RX Message Buffer Data Byte ((p × 4) + 1)</description>
                            <lsb>8</lsb>
                            <msb>15</msb>
                            <access>read-only</access>
                        </field>
                        <field>
                            <name>RMDB_HL</name>
                            <description>RX Message Buffer Data Byte ((p × 4) + 2)</description>
                            <lsb>16</lsb>
                            <msb>23</msb>
                            <access>read-only</access>
                        </field>
                        <field>
                            <name>RMDB_HH</name>
                            <description>RX Message Buffer Data Byte ((p × 4) + 3)</description>
                            <lsb>24</lsb>
                            <msb>31</msb>
                            <access>read-only</access>
                        </field>
                    </fields>
                </register>
                <register>
                    <dim>8</dim>
                    <dimIncrement>0x004C</dimIncrement>
                    <dimIndex>24-31</dimIndex>
                    <name>CFDRMDF%s_3</name>
                    <description>RX Message Buffer Data Field 3 Registers</description>
                    <addressOffset>0x1538</addressOffset>
                    <size>32</size>
                    <access>read-only</access>
                    <resetValue>0x00000000</resetValue>
                    <resetMask>0xffffffff</resetMask>
                    <fields>
                        <field>
                            <name>RMDB_LL</name>
                            <description>RX Message Buffer Data Byte (p × 4)</description>
                            <lsb>0</lsb>
                            <msb>7</msb>
                            <access>read-only</access>
                        </field>
                        <field>
                            <name>RMDB_LH</name>
                            <description>RX Message Buffer Data Byte ((p × 4) + 1)</description>
                            <lsb>8</lsb>
                            <msb>15</msb>
                            <access>read-only</access>
                        </field>
                        <field>
                            <name>RMDB_HL</name>
                            <description>RX Message Buffer Data Byte ((p × 4) + 2)</description>
                            <lsb>16</lsb>
                            <msb>23</msb>
                            <access>read-only</access>
                        </field>
                        <field>
                            <name>RMDB_HH</name>
                            <description>RX Message Buffer Data Byte ((p × 4) + 3)</description>
                            <lsb>24</lsb>
                            <msb>31</msb>
                            <access>read-only</access>
                        </field>
                    </fields>
                </register>
                <register>
                    <dim>8</dim>
                    <dimIncrement>0x004C</dimIncrement>
                    <dimIndex>24-31</dimIndex>
                    <name>CFDRMDF%s_4</name>
                    <description>RX Message Buffer Data Field 4 Registers</description>
                    <addressOffset>0x153C</addressOffset>
                    <size>32</size>
                    <access>read-only</access>
                    <resetValue>0x00000000</resetValue>
                    <resetMask>0xffffffff</resetMask>
                    <fields>
                        <field>
                            <name>RMDB_LL</name>
                            <description>RX Message Buffer Data Byte (p × 4)</description>
                            <lsb>0</lsb>
                            <msb>7</msb>
                            <access>read-only</access>
                        </field>
                        <field>
                            <name>RMDB_LH</name>
                            <description>RX Message Buffer Data Byte ((p × 4) + 1)</description>
                            <lsb>8</lsb>
                            <msb>15</msb>
                            <access>read-only</access>
                        </field>
                        <field>
                            <name>RMDB_HL</name>
                            <description>RX Message Buffer Data Byte ((p × 4) + 2)</description>
                            <lsb>16</lsb>
                            <msb>23</msb>
                            <access>read-only</access>
                        </field>
                        <field>
                            <name>RMDB_HH</name>
                            <description>RX Message Buffer Data Byte ((p × 4) + 3)</description>
                            <lsb>24</lsb>
                            <msb>31</msb>
                            <access>read-only</access>
                        </field>
                    </fields>
                </register>
                <register>
                    <dim>8</dim>
                    <dimIncrement>0x004C</dimIncrement>
                    <dimIndex>24-31</dimIndex>
                    <name>CFDRMDF%s_5</name>
                    <description>RX Message Buffer Data Field 5 Registers</description>
                    <addressOffset>0x1540</addressOffset>
                    <size>32</size>
                    <access>read-only</access>
                    <resetValue>0x00000000</resetValue>
                    <resetMask>0xffffffff</resetMask>
                    <fields>
                        <field>
                            <name>RMDB_LL</name>
                            <description>RX Message Buffer Data Byte (p × 4)</description>
                            <lsb>0</lsb>
                            <msb>7</msb>
                            <access>read-only</access>
                        </field>
                        <field>
                            <name>RMDB_LH</name>
                            <description>RX Message Buffer Data Byte ((p × 4) + 1)</description>
                            <lsb>8</lsb>
                            <msb>15</msb>
                            <access>read-only</access>
                        </field>
                        <field>
                            <name>RMDB_HL</name>
                            <description>RX Message Buffer Data Byte ((p × 4) + 2)</description>
                            <lsb>16</lsb>
                            <msb>23</msb>
                            <access>read-only</access>
                        </field>
                        <field>
                            <name>RMDB_HH</name>
                            <description>RX Message Buffer Data Byte ((p × 4) + 3)</description>
                            <lsb>24</lsb>
                            <msb>31</msb>
                            <access>read-only</access>
                        </field>
                    </fields>
                </register>
                <register>
                    <dim>8</dim>
                    <dimIncrement>0x004C</dimIncrement>
                    <dimIndex>24-31</dimIndex>
                    <name>CFDRMDF%s_6</name>
                    <description>RX Message Buffer Data Field 6 Registers</description>
                    <addressOffset>0x1544</addressOffset>
                    <size>32</size>
                    <access>read-only</access>
                    <resetValue>0x00000000</resetValue>
                    <resetMask>0xffffffff</resetMask>
                    <fields>
                        <field>
                            <name>RMDB_LL</name>
                            <description>RX Message Buffer Data Byte (p × 4)</description>
                            <lsb>0</lsb>
                            <msb>7</msb>
                            <access>read-only</access>
                        </field>
                        <field>
                            <name>RMDB_LH</name>
                            <description>RX Message Buffer Data Byte ((p × 4) + 1)</description>
                            <lsb>8</lsb>
                            <msb>15</msb>
                            <access>read-only</access>
                        </field>
                        <field>
                            <name>RMDB_HL</name>
                            <description>RX Message Buffer Data Byte ((p × 4) + 2)</description>
                            <lsb>16</lsb>
                            <msb>23</msb>
                            <access>read-only</access>
                        </field>
                        <field>
                            <name>RMDB_HH</name>
                            <description>RX Message Buffer Data Byte ((p × 4) + 3)</description>
                            <lsb>24</lsb>
                            <msb>31</msb>
                            <access>read-only</access>
                        </field>
                    </fields>
                </register>
                <register>
                    <dim>8</dim>
                    <dimIncrement>0x004C</dimIncrement>
                    <dimIndex>24-31</dimIndex>
                    <name>CFDRMDF%s_7</name>
                    <description>RX Message Buffer Data Field 7 Registers</description>
                    <addressOffset>0x1548</addressOffset>
                    <size>32</size>
                    <access>read-only</access>
                    <resetValue>0x00000000</resetValue>
                    <resetMask>0xffffffff</resetMask>
                    <fields>
                        <field>
                            <name>RMDB_LL</name>
                            <description>RX Message Buffer Data Byte (p × 4)</description>
                            <lsb>0</lsb>
                            <msb>7</msb>
                            <access>read-only</access>
                        </field>
                        <field>
                            <name>RMDB_LH</name>
                            <description>RX Message Buffer Data Byte ((p × 4) + 1)</description>
                            <lsb>8</lsb>
                            <msb>15</msb>
                            <access>read-only</access>
                        </field>
                        <field>
                            <name>RMDB_HL</name>
                            <description>RX Message Buffer Data Byte ((p × 4) + 2)</description>
                            <lsb>16</lsb>
                            <msb>23</msb>
                            <access>read-only</access>
                        </field>
                        <field>
                            <name>RMDB_HH</name>
                            <description>RX Message Buffer Data Byte ((p × 4) + 3)</description>
                            <lsb>24</lsb>
                            <msb>31</msb>
                            <access>read-only</access>
                        </field>
                    </fields>
                </register>
                <register>
                    <dim>8</dim>
                    <dimIncrement>0x004C</dimIncrement>
                    <dimIndex>24-31</dimIndex>
                    <name>CFDRMDF%s_8</name>
                    <description>RX Message Buffer Data Field 8 Registers</description>
                    <addressOffset>0x154C</addressOffset>
                    <size>32</size>
                    <access>read-only</access>
                    <resetValue>0x00000000</resetValue>
                    <resetMask>0xffffffff</resetMask>
                    <fields>
                        <field>
                            <name>RMDB_LL</name>
                            <description>RX Message Buffer Data Byte (p × 4)</description>
                            <lsb>0</lsb>
                            <msb>7</msb>
                            <access>read-only</access>
                        </field>
                        <field>
                            <name>RMDB_LH</name>
                            <description>RX Message Buffer Data Byte ((p × 4) + 1)</description>
                            <lsb>8</lsb>
                            <msb>15</msb>
                            <access>read-only</access>
                        </field>
                        <field>
                            <name>RMDB_HL</name>
                            <description>RX Message Buffer Data Byte ((p × 4) + 2)</description>
                            <lsb>16</lsb>
                            <msb>23</msb>
                            <access>read-only</access>
                        </field>
                        <field>
                            <name>RMDB_HH</name>
                            <description>RX Message Buffer Data Byte ((p × 4) + 3)</description>
                            <lsb>24</lsb>
                            <msb>31</msb>
                            <access>read-only</access>
                        </field>
                    </fields>
                </register>
                <register>
                    <dim>8</dim>
                    <dimIncrement>0x004C</dimIncrement>
                    <dimIndex>24-31</dimIndex>
                    <name>CFDRMDF%s_9</name>
                    <description>RX Message Buffer Data Field 9 Registers</description>
                    <addressOffset>0x1550</addressOffset>
                    <size>32</size>
                    <access>read-only</access>
                    <resetValue>0x00000000</resetValue>
                    <resetMask>0xffffffff</resetMask>
                    <fields>
                        <field>
                            <name>RMDB_LL</name>
                            <description>RX Message Buffer Data Byte (p × 4)</description>
                            <lsb>0</lsb>
                            <msb>7</msb>
                            <access>read-only</access>
                        </field>
                        <field>
                            <name>RMDB_LH</name>
                            <description>RX Message Buffer Data Byte ((p × 4) + 1)</description>
                            <lsb>8</lsb>
                            <msb>15</msb>
                            <access>read-only</access>
                        </field>
                        <field>
                            <name>RMDB_HL</name>
                            <description>RX Message Buffer Data Byte ((p × 4) + 2)</description>
                            <lsb>16</lsb>
                            <msb>23</msb>
                            <access>read-only</access>
                        </field>
                        <field>
                            <name>RMDB_HH</name>
                            <description>RX Message Buffer Data Byte ((p × 4) + 3)</description>
                            <lsb>24</lsb>
                            <msb>31</msb>
                            <access>read-only</access>
                        </field>
                    </fields>
                </register>
                <register>
                    <dim>8</dim>
                    <dimIncrement>0x004C</dimIncrement>
                    <dimIndex>24-31</dimIndex>
                    <name>CFDRMDF%s_10</name>
                    <description>RX Message Buffer Data Field 10 Registers</description>
                    <addressOffset>0x1554</addressOffset>
                    <size>32</size>
                    <access>read-only</access>
                    <resetValue>0x00000000</resetValue>
                    <resetMask>0xffffffff</resetMask>
                    <fields>
                        <field>
                            <name>RMDB_LL</name>
                            <description>RX Message Buffer Data Byte (p × 4)</description>
                            <lsb>0</lsb>
                            <msb>7</msb>
                            <access>read-only</access>
                        </field>
                        <field>
                            <name>RMDB_LH</name>
                            <description>RX Message Buffer Data Byte ((p × 4) + 1)</description>
                            <lsb>8</lsb>
                            <msb>15</msb>
                            <access>read-only</access>
                        </field>
                        <field>
                            <name>RMDB_HL</name>
                            <description>RX Message Buffer Data Byte ((p × 4) + 2)</description>
                            <lsb>16</lsb>
                            <msb>23</msb>
                            <access>read-only</access>
                        </field>
                        <field>
                            <name>RMDB_HH</name>
                            <description>RX Message Buffer Data Byte ((p × 4) + 3)</description>
                            <lsb>24</lsb>
                            <msb>31</msb>
                            <access>read-only</access>
                        </field>
                    </fields>
                </register>
                <register>
                    <dim>8</dim>
                    <dimIncrement>0x004C</dimIncrement>
                    <dimIndex>24-31</dimIndex>
                    <name>CFDRMDF%s_11</name>
                    <description>RX Message Buffer Data Field 11 Registers</description>
                    <addressOffset>0x1558</addressOffset>
                    <size>32</size>
                    <access>read-only</access>
                    <resetValue>0x00000000</resetValue>
                    <resetMask>0xffffffff</resetMask>
                    <fields>
                        <field>
                            <name>RMDB_LL</name>
                            <description>RX Message Buffer Data Byte (p × 4)</description>
                            <lsb>0</lsb>
                            <msb>7</msb>
                            <access>read-only</access>
                        </field>
                        <field>
                            <name>RMDB_LH</name>
                            <description>RX Message Buffer Data Byte ((p × 4) + 1)</description>
                            <lsb>8</lsb>
                            <msb>15</msb>
                            <access>read-only</access>
                        </field>
                        <field>
                            <name>RMDB_HL</name>
                            <description>RX Message Buffer Data Byte ((p × 4) + 2)</description>
                            <lsb>16</lsb>
                            <msb>23</msb>
                            <access>read-only</access>
                        </field>
                        <field>
                            <name>RMDB_HH</name>
                            <description>RX Message Buffer Data Byte ((p × 4) + 3)</description>
                            <lsb>24</lsb>
                            <msb>31</msb>
                            <access>read-only</access>
                        </field>
                    </fields>
                </register>
                <register>
                    <dim>8</dim>
                    <dimIncrement>0x004C</dimIncrement>
                    <dimIndex>24-31</dimIndex>
                    <name>CFDRMDF%s_12</name>
                    <description>RX Message Buffer Data Field 12 Registers</description>
                    <addressOffset>0x155C</addressOffset>
                    <size>32</size>
                    <access>read-only</access>
                    <resetValue>0x00000000</resetValue>
                    <resetMask>0xffffffff</resetMask>
                    <fields>
                        <field>
                            <name>RMDB_LL</name>
                            <description>RX Message Buffer Data Byte (p × 4)</description>
                            <lsb>0</lsb>
                            <msb>7</msb>
                            <access>read-only</access>
                        </field>
                        <field>
                            <name>RMDB_LH</name>
                            <description>RX Message Buffer Data Byte ((p × 4) + 1)</description>
                            <lsb>8</lsb>
                            <msb>15</msb>
                            <access>read-only</access>
                        </field>
                        <field>
                            <name>RMDB_HL</name>
                            <description>RX Message Buffer Data Byte ((p × 4) + 2)</description>
                            <lsb>16</lsb>
                            <msb>23</msb>
                            <access>read-only</access>
                        </field>
                        <field>
                            <name>RMDB_HH</name>
                            <description>RX Message Buffer Data Byte ((p × 4) + 3)</description>
                            <lsb>24</lsb>
                            <msb>31</msb>
                            <access>read-only</access>
                        </field>
                    </fields>
                </register>
                <register>
                    <dim>8</dim>
                    <dimIncrement>0x004C</dimIncrement>
                    <dimIndex>24-31</dimIndex>
                    <name>CFDRMDF%s_13</name>
                    <description>RX Message Buffer Data Field 13 Registers</description>
                    <addressOffset>0x1560</addressOffset>
                    <size>32</size>
                    <access>read-only</access>
                    <resetValue>0x00000000</resetValue>
                    <resetMask>0xffffffff</resetMask>
                    <fields>
                        <field>
                            <name>RMDB_LL</name>
                            <description>RX Message Buffer Data Byte (p × 4)</description>
                            <lsb>0</lsb>
                            <msb>7</msb>
                            <access>read-only</access>
                        </field>
                        <field>
                            <name>RMDB_LH</name>
                            <description>RX Message Buffer Data Byte ((p × 4) + 1)</description>
                            <lsb>8</lsb>
                            <msb>15</msb>
                            <access>read-only</access>
                        </field>
                        <field>
                            <name>RMDB_HL</name>
                            <description>RX Message Buffer Data Byte ((p × 4) + 2)</description>
                            <lsb>16</lsb>
                            <msb>23</msb>
                            <access>read-only</access>
                        </field>
                        <field>
                            <name>RMDB_HH</name>
                            <description>RX Message Buffer Data Byte ((p × 4) + 3)</description>
                            <lsb>24</lsb>
                            <msb>31</msb>
                            <access>read-only</access>
                        </field>
                    </fields>
                </register>
                <register>
                    <dim>8</dim>
                    <dimIncrement>0x004C</dimIncrement>
                    <dimIndex>24-31</dimIndex>
                    <name>CFDRMDF%s_14</name>
                    <description>RX Message Buffer Data Field 14 Registers</description>
                    <addressOffset>0x1564</addressOffset>
                    <size>32</size>
                    <access>read-only</access>
                    <resetValue>0x00000000</resetValue>
                    <resetMask>0xffffffff</resetMask>
                    <fields>
                        <field>
                            <name>RMDB_LL</name>
                            <description>RX Message Buffer Data Byte (p × 4)</description>
                            <lsb>0</lsb>
                            <msb>7</msb>
                            <access>read-only</access>
                        </field>
                        <field>
                            <name>RMDB_LH</name>
                            <description>RX Message Buffer Data Byte ((p × 4) + 1)</description>
                            <lsb>8</lsb>
                            <msb>15</msb>
                            <access>read-only</access>
                        </field>
                        <field>
                            <name>RMDB_HL</name>
                            <description>RX Message Buffer Data Byte ((p × 4) + 2)</description>
                            <lsb>16</lsb>
                            <msb>23</msb>
                            <access>read-only</access>
                        </field>
                        <field>
                            <name>RMDB_HH</name>
                            <description>RX Message Buffer Data Byte ((p × 4) + 3)</description>
                            <lsb>24</lsb>
                            <msb>31</msb>
                            <access>read-only</access>
                        </field>
                    </fields>
                </register>
                <register>
                    <dim>8</dim>
                    <dimIncrement>0x004C</dimIncrement>
                    <dimIndex>24-31</dimIndex>
                    <name>CFDRMDF%s_15</name>
                    <description>RX Message Buffer Data Field 15 Registers</description>
                    <addressOffset>0x1568</addressOffset>
                    <size>32</size>
                    <access>read-only</access>
                    <resetValue>0x00000000</resetValue>
                    <resetMask>0xffffffff</resetMask>
                    <fields>
                        <field>
                            <name>RMDB_LL</name>
                            <description>RX Message Buffer Data Byte (p × 4)</description>
                            <lsb>0</lsb>
                            <msb>7</msb>
                            <access>read-only</access>
                        </field>
                        <field>
                            <name>RMDB_LH</name>
                            <description>RX Message Buffer Data Byte ((p × 4) + 1)</description>
                            <lsb>8</lsb>
                            <msb>15</msb>
                            <access>read-only</access>
                        </field>
                        <field>
                            <name>RMDB_HL</name>
                            <description>RX Message Buffer Data Byte ((p × 4) + 2)</description>
                            <lsb>16</lsb>
                            <msb>23</msb>
                            <access>read-only</access>
                        </field>
                        <field>
                            <name>RMDB_HH</name>
                            <description>RX Message Buffer Data Byte ((p × 4) + 3)</description>
                            <lsb>24</lsb>
                            <msb>31</msb>
                            <access>read-only</access>
                        </field>
                    </fields>
                </register>
            </registers>
        </peripheral>
        <peripheral derivedFrom="CANFD0">
            <name>CANFD1</name>
            <description>CANFD Module 1</description>
            <baseAddress>0x40382000</baseAddress>
        </peripheral>
        <peripheral>
            <name>PORT0</name>
            <description>Pmn Pin Function Port 0 Control Registers Pmn Pin Function Control Register</description>
            <baseAddress>0x40400000</baseAddress>
            <addressBlock>
                <offset>0x00</offset>
                <size>8</size>
                <usage>registers</usage>
            </addressBlock>
            <addressBlock>
                <offset>0x08</offset>
                <size>4</size>
                <usage>registers</usage>
            </addressBlock>
            <registers>
                <register>
                    <name>PCNTR1</name>
                    <description>Port Control Register 1</description>
                    <addressOffset>0x000</addressOffset>
                    <size>32</size>
                    <access>read-write</access>
                    <resetValue>0x00000000</resetValue>
                    <resetMask>0xffffffff</resetMask>
                    <fields>
                        <field>
                            <name>PDR00</name>
                            <description>Pmn Direction</description>
                            <lsb>0</lsb>
                            <msb>0</msb>
                            <access>read-write</access>
                            <enumeratedValues>
                                <enumeratedValue>
                                    <name>0</name>
                                    <description>Input (functions as an input pin)</description>
                                    <value>#0</value>
                                </enumeratedValue>
                                <enumeratedValue>
                                    <name>1</name>
                                    <description>Output (functions as an output pin)</description>
                                    <value>#1</value>
                                </enumeratedValue>
                            </enumeratedValues>
                        </field>
                        <field>
                            <name>PDR01</name>
                            <description>Pmn Direction</description>
                            <lsb>1</lsb>
                            <msb>1</msb>
                            <access>read-write</access>
                            <enumeratedValues>
                                <enumeratedValue>
                                    <name>0</name>
                                    <description>Input (functions as an input pin)</description>
                                    <value>#0</value>
                                </enumeratedValue>
                                <enumeratedValue>
                                    <name>1</name>
                                    <description>Output (functions as an output pin)</description>
                                    <value>#1</value>
                                </enumeratedValue>
                            </enumeratedValues>
                        </field>
                        <field>
                            <name>PDR02</name>
                            <description>Pmn Direction</description>
                            <lsb>2</lsb>
                            <msb>2</msb>
                            <access>read-write</access>
                            <enumeratedValues>
                                <enumeratedValue>
                                    <name>0</name>
                                    <description>Input (functions as an input pin)</description>
                                    <value>#0</value>
                                </enumeratedValue>
                                <enumeratedValue>
                                    <name>1</name>
                                    <description>Output (functions as an output pin)</description>
                                    <value>#1</value>
                                </enumeratedValue>
                            </enumeratedValues>
                        </field>
                        <field>
                            <name>PDR03</name>
                            <description>Pmn Direction</description>
                            <lsb>3</lsb>
                            <msb>3</msb>
                            <access>read-write</access>
                            <enumeratedValues>
                                <enumeratedValue>
                                    <name>0</name>
                                    <description>Input (functions as an input pin)</description>
                                    <value>#0</value>
                                </enumeratedValue>
                                <enumeratedValue>
                                    <name>1</name>
                                    <description>Output (functions as an output pin)</description>
                                    <value>#1</value>
                                </enumeratedValue>
                            </enumeratedValues>
                        </field>
                        <field>
                            <name>PDR04</name>
                            <description>Pmn Direction</description>
                            <lsb>4</lsb>
                            <msb>4</msb>
                            <access>read-write</access>
                            <enumeratedValues>
                                <enumeratedValue>
                                    <name>0</name>
                                    <description>Input (functions as an input pin)</description>
                                    <value>#0</value>
                                </enumeratedValue>
                                <enumeratedValue>
                                    <name>1</name>
                                    <description>Output (functions as an output pin)</description>
                                    <value>#1</value>
                                </enumeratedValue>
                            </enumeratedValues>
                        </field>
                        <field>
                            <name>PDR05</name>
                            <description>Pmn Direction</description>
                            <lsb>5</lsb>
                            <msb>5</msb>
                            <access>read-write</access>
                            <enumeratedValues>
                                <enumeratedValue>
                                    <name>0</name>
                                    <description>Input (functions as an input pin)</description>
                                    <value>#0</value>
                                </enumeratedValue>
                                <enumeratedValue>
                                    <name>1</name>
                                    <description>Output (functions as an output pin)</description>
                                    <value>#1</value>
                                </enumeratedValue>
                            </enumeratedValues>
                        </field>
                        <field>
                            <name>PDR06</name>
                            <description>Pmn Direction</description>
                            <lsb>6</lsb>
                            <msb>6</msb>
                            <access>read-write</access>
                            <enumeratedValues>
                                <enumeratedValue>
                                    <name>0</name>
                                    <description>Input (functions as an input pin)</description>
                                    <value>#0</value>
                                </enumeratedValue>
                                <enumeratedValue>
                                    <name>1</name>
                                    <description>Output (functions as an output pin)</description>
                                    <value>#1</value>
                                </enumeratedValue>
                            </enumeratedValues>
                        </field>
                        <field>
                            <name>PDR07</name>
                            <description>Pmn Direction</description>
                            <lsb>7</lsb>
                            <msb>7</msb>
                            <access>read-write</access>
                            <enumeratedValues>
                                <enumeratedValue>
                                    <name>0</name>
                                    <description>Input (functions as an input pin)</description>
                                    <value>#0</value>
                                </enumeratedValue>
                                <enumeratedValue>
                                    <name>1</name>
                                    <description>Output (functions as an output pin)</description>
                                    <value>#1</value>
                                </enumeratedValue>
                            </enumeratedValues>
                        </field>
                        <field>
                            <name>PDR08</name>
                            <description>Pmn Direction</description>
                            <lsb>8</lsb>
                            <msb>8</msb>
                            <access>read-write</access>
                            <enumeratedValues>
                                <enumeratedValue>
                                    <name>0</name>
                                    <description>Input (functions as an input pin)</description>
                                    <value>#0</value>
                                </enumeratedValue>
                                <enumeratedValue>
                                    <name>1</name>
                                    <description>Output (functions as an output pin)</description>
                                    <value>#1</value>
                                </enumeratedValue>
                            </enumeratedValues>
                        </field>
                        <field>
                            <name>PDR09</name>
                            <description>Pmn Direction</description>
                            <lsb>9</lsb>
                            <msb>9</msb>
                            <access>read-write</access>
                            <enumeratedValues>
                                <enumeratedValue>
                                    <name>0</name>
                                    <description>Input (functions as an input pin)</description>
                                    <value>#0</value>
                                </enumeratedValue>
                                <enumeratedValue>
                                    <name>1</name>
                                    <description>Output (functions as an output pin)</description>
                                    <value>#1</value>
                                </enumeratedValue>
                            </enumeratedValues>
                        </field>
                        <field>
                            <name>PDR10</name>
                            <description>Pmn Direction</description>
                            <lsb>10</lsb>
                            <msb>10</msb>
                            <access>read-write</access>
                            <enumeratedValues>
                                <enumeratedValue>
                                    <name>0</name>
                                    <description>Input (functions as an input pin)</description>
                                    <value>#0</value>
                                </enumeratedValue>
                                <enumeratedValue>
                                    <name>1</name>
                                    <description>Output (functions as an output pin)</description>
                                    <value>#1</value>
                                </enumeratedValue>
                            </enumeratedValues>
                        </field>
                        <field>
                            <name>PDR11</name>
                            <description>Pmn Direction</description>
                            <lsb>11</lsb>
                            <msb>11</msb>
                            <access>read-write</access>
                            <enumeratedValues>
                                <enumeratedValue>
                                    <name>0</name>
                                    <description>Input (functions as an input pin)</description>
                                    <value>#0</value>
                                </enumeratedValue>
                                <enumeratedValue>
                                    <name>1</name>
                                    <description>Output (functions as an output pin)</description>
                                    <value>#1</value>
                                </enumeratedValue>
                            </enumeratedValues>
                        </field>
                        <field>
                            <name>PDR12</name>
                            <description>Pmn Direction</description>
                            <lsb>12</lsb>
                            <msb>12</msb>
                            <access>read-write</access>
                            <enumeratedValues>
                                <enumeratedValue>
                                    <name>0</name>
                                    <description>Input (functions as an input pin)</description>
                                    <value>#0</value>
                                </enumeratedValue>
                                <enumeratedValue>
                                    <name>1</name>
                                    <description>Output (functions as an output pin)</description>
                                    <value>#1</value>
                                </enumeratedValue>
                            </enumeratedValues>
                        </field>
                        <field>
                            <name>PDR13</name>
                            <description>Pmn Direction</description>
                            <lsb>13</lsb>
                            <msb>13</msb>
                            <access>read-write</access>
                            <enumeratedValues>
                                <enumeratedValue>
                                    <name>0</name>
                                    <description>Input (functions as an input pin)</description>
                                    <value>#0</value>
                                </enumeratedValue>
                                <enumeratedValue>
                                    <name>1</name>
                                    <description>Output (functions as an output pin)</description>
                                    <value>#1</value>
                                </enumeratedValue>
                            </enumeratedValues>
                        </field>
                        <field>
                            <name>PDR14</name>
                            <description>Pmn Direction</description>
                            <lsb>14</lsb>
                            <msb>14</msb>
                            <access>read-write</access>
                            <enumeratedValues>
                                <enumeratedValue>
                                    <name>0</name>
                                    <description>Input (functions as an input pin)</description>
                                    <value>#0</value>
                                </enumeratedValue>
                                <enumeratedValue>
                                    <name>1</name>
                                    <description>Output (functions as an output pin)</description>
                                    <value>#1</value>
                                </enumeratedValue>
                            </enumeratedValues>
                        </field>
                        <field>
                            <name>PDR15</name>
                            <description>Pmn Direction</description>
                            <lsb>15</lsb>
                            <msb>15</msb>
                            <access>read-write</access>
                            <enumeratedValues>
                                <enumeratedValue>
                                    <name>0</name>
                                    <description>Input (functions as an input pin)</description>
                                    <value>#0</value>
                                </enumeratedValue>
                                <enumeratedValue>
                                    <name>1</name>
                                    <description>Output (functions as an output pin)</description>
                                    <value>#1</value>
                                </enumeratedValue>
                            </enumeratedValues>
                        </field>
                        <field>
                            <name>PODR00</name>
                            <description>Pmn Output Data</description>
                            <lsb>16</lsb>
                            <msb>16</msb>
                            <access>read-write</access>
                            <enumeratedValues>
                                <enumeratedValue>
                                    <name>0</name>
                                    <description>Low output</description>
                                    <value>#0</value>
                                </enumeratedValue>
                                <enumeratedValue>
                                    <name>1</name>
                                    <description>High output</description>
                                    <value>#1</value>
                                </enumeratedValue>
                            </enumeratedValues>
                        </field>
                        <field>
                            <name>PODR01</name>
                            <description>Pmn Output Data</description>
                            <lsb>17</lsb>
                            <msb>17</msb>
                            <access>read-write</access>
                            <enumeratedValues>
                                <enumeratedValue>
                                    <name>0</name>
                                    <description>Low output</description>
                                    <value>#0</value>
                                </enumeratedValue>
                                <enumeratedValue>
                                    <name>1</name>
                                    <description>High output</description>
                                    <value>#1</value>
                                </enumeratedValue>
                            </enumeratedValues>
                        </field>
                        <field>
                            <name>PODR02</name>
                            <description>Pmn Output Data</description>
                            <lsb>18</lsb>
                            <msb>18</msb>
                            <access>read-write</access>
                            <enumeratedValues>
                                <enumeratedValue>
                                    <name>0</name>
                                    <description>Low output</description>
                                    <value>#0</value>
                                </enumeratedValue>
                                <enumeratedValue>
                                    <name>1</name>
                                    <description>High output</description>
                                    <value>#1</value>
                                </enumeratedValue>
                            </enumeratedValues>
                        </field>
                        <field>
                            <name>PODR03</name>
                            <description>Pmn Output Data</description>
                            <lsb>19</lsb>
                            <msb>19</msb>
                            <access>read-write</access>
                            <enumeratedValues>
                                <enumeratedValue>
                                    <name>0</name>
                                    <description>Low output</description>
                                    <value>#0</value>
                                </enumeratedValue>
                                <enumeratedValue>
                                    <name>1</name>
                                    <description>High output</description>
                                    <value>#1</value>
                                </enumeratedValue>
                            </enumeratedValues>
                        </field>
                        <field>
                            <name>PODR04</name>
                            <description>Pmn Output Data</description>
                            <lsb>20</lsb>
                            <msb>20</msb>
                            <access>read-write</access>
                            <enumeratedValues>
                                <enumeratedValue>
                                    <name>0</name>
                                    <description>Low output</description>
                                    <value>#0</value>
                                </enumeratedValue>
                                <enumeratedValue>
                                    <name>1</name>
                                    <description>High output</description>
                                    <value>#1</value>
                                </enumeratedValue>
                            </enumeratedValues>
                        </field>
                        <field>
                            <name>PODR05</name>
                            <description>Pmn Output Data</description>
                            <lsb>21</lsb>
                            <msb>21</msb>
                            <access>read-write</access>
                            <enumeratedValues>
                                <enumeratedValue>
                                    <name>0</name>
                                    <description>Low output</description>
                                    <value>#0</value>
                                </enumeratedValue>
                                <enumeratedValue>
                                    <name>1</name>
                                    <description>High output</description>
                                    <value>#1</value>
                                </enumeratedValue>
                            </enumeratedValues>
                        </field>
                        <field>
                            <name>PODR06</name>
                            <description>Pmn Output Data</description>
                            <lsb>22</lsb>
                            <msb>22</msb>
                            <access>read-write</access>
                            <enumeratedValues>
                                <enumeratedValue>
                                    <name>0</name>
                                    <description>Low output</description>
                                    <value>#0</value>
                                </enumeratedValue>
                                <enumeratedValue>
                                    <name>1</name>
                                    <description>High output</description>
                                    <value>#1</value>
                                </enumeratedValue>
                            </enumeratedValues>
                        </field>
                        <field>
                            <name>PODR07</name>
                            <description>Pmn Output Data</description>
                            <lsb>23</lsb>
                            <msb>23</msb>
                            <access>read-write</access>
                            <enumeratedValues>
                                <enumeratedValue>
                                    <name>0</name>
                                    <description>Low output</description>
                                    <value>#0</value>
                                </enumeratedValue>
                                <enumeratedValue>
                                    <name>1</name>
                                    <description>High output</description>
                                    <value>#1</value>
                                </enumeratedValue>
                            </enumeratedValues>
                        </field>
                        <field>
                            <name>PODR08</name>
                            <description>Pmn Output Data</description>
                            <lsb>24</lsb>
                            <msb>24</msb>
                            <access>read-write</access>
                            <enumeratedValues>
                                <enumeratedValue>
                                    <name>0</name>
                                    <description>Low output</description>
                                    <value>#0</value>
                                </enumeratedValue>
                                <enumeratedValue>
                                    <name>1</name>
                                    <description>High output</description>
                                    <value>#1</value>
                                </enumeratedValue>
                            </enumeratedValues>
                        </field>
                        <field>
                            <name>PODR09</name>
                            <description>Pmn Output Data</description>
                            <lsb>25</lsb>
                            <msb>25</msb>
                            <access>read-write</access>
                            <enumeratedValues>
                                <enumeratedValue>
                                    <name>0</name>
                                    <description>Low output</description>
                                    <value>#0</value>
                                </enumeratedValue>
                                <enumeratedValue>
                                    <name>1</name>
                                    <description>High output</description>
                                    <value>#1</value>
                                </enumeratedValue>
                            </enumeratedValues>
                        </field>
                        <field>
                            <name>PODR10</name>
                            <description>Pmn Output Data</description>
                            <lsb>26</lsb>
                            <msb>26</msb>
                            <access>read-write</access>
                            <enumeratedValues>
                                <enumeratedValue>
                                    <name>0</name>
                                    <description>Low output</description>
                                    <value>#0</value>
                                </enumeratedValue>
                                <enumeratedValue>
                                    <name>1</name>
                                    <description>High output</description>
                                    <value>#1</value>
                                </enumeratedValue>
                            </enumeratedValues>
                        </field>
                        <field>
                            <name>PODR11</name>
                            <description>Pmn Output Data</description>
                            <lsb>27</lsb>
                            <msb>27</msb>
                            <access>read-write</access>
                            <enumeratedValues>
                                <enumeratedValue>
                                    <name>0</name>
                                    <description>Low output</description>
                                    <value>#0</value>
                                </enumeratedValue>
                                <enumeratedValue>
                                    <name>1</name>
                                    <description>High output</description>
                                    <value>#1</value>
                                </enumeratedValue>
                            </enumeratedValues>
                        </field>
                        <field>
                            <name>PODR12</name>
                            <description>Pmn Output Data</description>
                            <lsb>28</lsb>
                            <msb>28</msb>
                            <access>read-write</access>
                            <enumeratedValues>
                                <enumeratedValue>
                                    <name>0</name>
                                    <description>Low output</description>
                                    <value>#0</value>
                                </enumeratedValue>
                                <enumeratedValue>
                                    <name>1</name>
                                    <description>High output</description>
                                    <value>#1</value>
                                </enumeratedValue>
                            </enumeratedValues>
                        </field>
                        <field>
                            <name>PODR13</name>
                            <description>Pmn Output Data</description>
                            <lsb>29</lsb>
                            <msb>29</msb>
                            <access>read-write</access>
                            <enumeratedValues>
                                <enumeratedValue>
                                    <name>0</name>
                                    <description>Low output</description>
                                    <value>#0</value>
                                </enumeratedValue>
                                <enumeratedValue>
                                    <name>1</name>
                                    <description>High output</description>
                                    <value>#1</value>
                                </enumeratedValue>
                            </enumeratedValues>
                        </field>
                        <field>
                            <name>PODR14</name>
                            <description>Pmn Output Data</description>
                            <lsb>30</lsb>
                            <msb>30</msb>
                            <access>read-write</access>
                            <enumeratedValues>
                                <enumeratedValue>
                                    <name>0</name>
                                    <description>Low output</description>
                                    <value>#0</value>
                                </enumeratedValue>
                                <enumeratedValue>
                                    <name>1</name>
                                    <description>High output</description>
                                    <value>#1</value>
                                </enumeratedValue>
                            </enumeratedValues>
                        </field>
                        <field>
                            <name>PODR15</name>
                            <description>Pmn Output Data</description>
                            <lsb>31</lsb>
                            <msb>31</msb>
                            <access>read-write</access>
                            <enumeratedValues>
                                <enumeratedValue>
                                    <name>0</name>
                                    <description>Low output</description>
                                    <value>#0</value>
                                </enumeratedValue>
                                <enumeratedValue>
                                    <name>1</name>
                                    <description>High output</description>
                                    <value>#1</value>
                                </enumeratedValue>
                            </enumeratedValues>
                        </field>
                    </fields>
                </register>
                <register>
                    <name>PDR</name>
                    <description>Port Control Register 1</description>
                    <alternateRegister>PCNTR1</alternateRegister>
                    <addressOffset>0x000</addressOffset>
                    <size>16</size>
                    <access>read-write</access>
                    <resetValue>0x0000</resetValue>
                    <resetMask>0xffff</resetMask>
                    <fields>
                        <field>
                            <name>PODR00</name>
                            <description>Pmn Output Data</description>
                            <lsb>0</lsb>
                            <msb>0</msb>
                            <access>read-write</access>
                            <enumeratedValues>
                                <enumeratedValue>
                                    <name>0</name>
                                    <description>Low output</description>
                                    <value>#0</value>
                                </enumeratedValue>
                                <enumeratedValue>
                                    <name>1</name>
                                    <description>High output</description>
                                    <value>#1</value>
                                </enumeratedValue>
                            </enumeratedValues>
                        </field>
                        <field>
                            <name>PODR01</name>
                            <description>Pmn Output Data</description>
                            <lsb>1</lsb>
                            <msb>1</msb>
                            <access>read-write</access>
                            <enumeratedValues>
                                <enumeratedValue>
                                    <name>0</name>
                                    <description>Low output</description>
                                    <value>#0</value>
                                </enumeratedValue>
                                <enumeratedValue>
                                    <name>1</name>
                                    <description>High output</description>
                                    <value>#1</value>
                                </enumeratedValue>
                            </enumeratedValues>
                        </field>
                        <field>
                            <name>PODR02</name>
                            <description>Pmn Output Data</description>
                            <lsb>2</lsb>
                            <msb>2</msb>
                            <access>read-write</access>
                            <enumeratedValues>
                                <enumeratedValue>
                                    <name>0</name>
                                    <description>Low output</description>
                                    <value>#0</value>
                                </enumeratedValue>
                                <enumeratedValue>
                                    <name>1</name>
                                    <description>High output</description>
                                    <value>#1</value>
                                </enumeratedValue>
                            </enumeratedValues>
                        </field>
                        <field>
                            <name>PODR03</name>
                            <description>Pmn Output Data</description>
                            <lsb>3</lsb>
                            <msb>3</msb>
                            <access>read-write</access>
                            <enumeratedValues>
                                <enumeratedValue>
                                    <name>0</name>
                                    <description>Low output</description>
                                    <value>#0</value>
                                </enumeratedValue>
                                <enumeratedValue>
                                    <name>1</name>
                                    <description>High output</description>
                                    <value>#1</value>
                                </enumeratedValue>
                            </enumeratedValues>
                        </field>
                        <field>
                            <name>PODR04</name>
                            <description>Pmn Output Data</description>
                            <lsb>4</lsb>
                            <msb>4</msb>
                            <access>read-write</access>
                            <enumeratedValues>
                                <enumeratedValue>
                                    <name>0</name>
                                    <description>Low output</description>
                                    <value>#0</value>
                                </enumeratedValue>
                                <enumeratedValue>
                                    <name>1</name>
                                    <description>High output</description>
                                    <value>#1</value>
                                </enumeratedValue>
                            </enumeratedValues>
                        </field>
                        <field>
                            <name>PODR05</name>
                            <description>Pmn Output Data</description>
                            <lsb>5</lsb>
                            <msb>5</msb>
                            <access>read-write</access>
                            <enumeratedValues>
                                <enumeratedValue>
                                    <name>0</name>
                                    <description>Low output</description>
                                    <value>#0</value>
                                </enumeratedValue>
                                <enumeratedValue>
                                    <name>1</name>
                                    <description>High output</description>
                                    <value>#1</value>
                                </enumeratedValue>
                            </enumeratedValues>
                        </field>
                        <field>
                            <name>PODR06</name>
                            <description>Pmn Output Data</description>
                            <lsb>6</lsb>
                            <msb>6</msb>
                            <access>read-write</access>
                            <enumeratedValues>
                                <enumeratedValue>
                                    <name>0</name>
                                    <description>Low output</description>
                                    <value>#0</value>
                                </enumeratedValue>
                                <enumeratedValue>
                                    <name>1</name>
                                    <description>High output</description>
                                    <value>#1</value>
                                </enumeratedValue>
                            </enumeratedValues>
                        </field>
                        <field>
                            <name>PODR07</name>
                            <description>Pmn Output Data</description>
                            <lsb>7</lsb>
                            <msb>7</msb>
                            <access>read-write</access>
                            <enumeratedValues>
                                <enumeratedValue>
                                    <name>0</name>
                                    <description>Low output</description>
                                    <value>#0</value>
                                </enumeratedValue>
                                <enumeratedValue>
                                    <name>1</name>
                                    <description>High output</description>
                                    <value>#1</value>
                                </enumeratedValue>
                            </enumeratedValues>
                        </field>
                        <field>
                            <name>PODR08</name>
                            <description>Pmn Output Data</description>
                            <lsb>8</lsb>
                            <msb>8</msb>
                            <access>read-write</access>
                            <enumeratedValues>
                                <enumeratedValue>
                                    <name>0</name>
                                    <description>Low output</description>
                                    <value>#0</value>
                                </enumeratedValue>
                                <enumeratedValue>
                                    <name>1</name>
                                    <description>High output</description>
                                    <value>#1</value>
                                </enumeratedValue>
                            </enumeratedValues>
                        </field>
                        <field>
                            <name>PODR09</name>
                            <description>Pmn Output Data</description>
                            <lsb>9</lsb>
                            <msb>9</msb>
                            <access>read-write</access>
                            <enumeratedValues>
                                <enumeratedValue>
                                    <name>0</name>
                                    <description>Low output</description>
                                    <value>#0</value>
                                </enumeratedValue>
                                <enumeratedValue>
                                    <name>1</name>
                                    <description>High output</description>
                                    <value>#1</value>
                                </enumeratedValue>
                            </enumeratedValues>
                        </field>
                        <field>
                            <name>PODR10</name>
                            <description>Pmn Output Data</description>
                            <lsb>10</lsb>
                            <msb>10</msb>
                            <access>read-write</access>
                            <enumeratedValues>
                                <enumeratedValue>
                                    <name>0</name>
                                    <description>Low output</description>
                                    <value>#0</value>
                                </enumeratedValue>
                                <enumeratedValue>
                                    <name>1</name>
                                    <description>High output</description>
                                    <value>#1</value>
                                </enumeratedValue>
                            </enumeratedValues>
                        </field>
                        <field>
                            <name>PODR11</name>
                            <description>Pmn Output Data</description>
                            <lsb>11</lsb>
                            <msb>11</msb>
                            <access>read-write</access>
                            <enumeratedValues>
                                <enumeratedValue>
                                    <name>0</name>
                                    <description>Low output</description>
                                    <value>#0</value>
                                </enumeratedValue>
                                <enumeratedValue>
                                    <name>1</name>
                                    <description>High output</description>
                                    <value>#1</value>
                                </enumeratedValue>
                            </enumeratedValues>
                        </field>
                        <field>
                            <name>PODR12</name>
                            <description>Pmn Output Data</description>
                            <lsb>12</lsb>
                            <msb>12</msb>
                            <access>read-write</access>
                            <enumeratedValues>
                                <enumeratedValue>
                                    <name>0</name>
                                    <description>Low output</description>
                                    <value>#0</value>
                                </enumeratedValue>
                                <enumeratedValue>
                                    <name>1</name>
                                    <description>High output</description>
                                    <value>#1</value>
                                </enumeratedValue>
                            </enumeratedValues>
                        </field>
                        <field>
                            <name>PODR13</name>
                            <description>Pmn Output Data</description>
                            <lsb>13</lsb>
                            <msb>13</msb>
                            <access>read-write</access>
                            <enumeratedValues>
                                <enumeratedValue>
                                    <name>0</name>
                                    <description>Low output</description>
                                    <value>#0</value>
                                </enumeratedValue>
                                <enumeratedValue>
                                    <name>1</name>
                                    <description>High output</description>
                                    <value>#1</value>
                                </enumeratedValue>
                            </enumeratedValues>
                        </field>
                        <field>
                            <name>PODR14</name>
                            <description>Pmn Output Data</description>
                            <lsb>14</lsb>
                            <msb>14</msb>
                            <access>read-write</access>
                            <enumeratedValues>
                                <enumeratedValue>
                                    <name>0</name>
                                    <description>Low output</description>
                                    <value>#0</value>
                                </enumeratedValue>
                                <enumeratedValue>
                                    <name>1</name>
                                    <description>High output</description>
                                    <value>#1</value>
                                </enumeratedValue>
                            </enumeratedValues>
                        </field>
                        <field>
                            <name>PODR15</name>
                            <description>Pmn Output Data</description>
                            <lsb>15</lsb>
                            <msb>15</msb>
                            <access>read-write</access>
                            <enumeratedValues>
                                <enumeratedValue>
                                    <name>0</name>
                                    <description>Low output</description>
                                    <value>#0</value>
                                </enumeratedValue>
                                <enumeratedValue>
                                    <name>1</name>
                                    <description>High output</description>
                                    <value>#1</value>
                                </enumeratedValue>
                            </enumeratedValues>
                        </field>
                    </fields>
                </register>
                <register>
                    <name>PODR</name>
                    <description>Port Control Register 1</description>
                    <alternateRegister>PCNTR1</alternateRegister>
                    <addressOffset>0x002</addressOffset>
                    <size>16</size>
                    <access>read-write</access>
                    <resetValue>0x0000</resetValue>
                    <resetMask>0xffff</resetMask>
                    <fields>
                        <field>
                            <name>PDR00</name>
                            <description>Pmn Direction</description>
                            <lsb>0</lsb>
                            <msb>0</msb>
                            <access>read-write</access>
                            <enumeratedValues>
                                <enumeratedValue>
                                    <name>0</name>
                                    <description>Input (functions as an input pin)</description>
                                    <value>#0</value>
                                </enumeratedValue>
                                <enumeratedValue>
                                    <name>1</name>
                                    <description>Output (functions as an output pin)</description>
                                    <value>#1</value>
                                </enumeratedValue>
                            </enumeratedValues>
                        </field>
                        <field>
                            <name>PDR01</name>
                            <description>Pmn Direction</description>
                            <lsb>1</lsb>
                            <msb>1</msb>
                            <access>read-write</access>
                            <enumeratedValues>
                                <enumeratedValue>
                                    <name>0</name>
                                    <description>Input (functions as an input pin)</description>
                                    <value>#0</value>
                                </enumeratedValue>
                                <enumeratedValue>
                                    <name>1</name>
                                    <description>Output (functions as an output pin)</description>
                                    <value>#1</value>
                                </enumeratedValue>
                            </enumeratedValues>
                        </field>
                        <field>
                            <name>PDR02</name>
                            <description>Pmn Direction</description>
                            <lsb>2</lsb>
                            <msb>2</msb>
                            <access>read-write</access>
                            <enumeratedValues>
                                <enumeratedValue>
                                    <name>0</name>
                                    <description>Input (functions as an input pin)</description>
                                    <value>#0</value>
                                </enumeratedValue>
                                <enumeratedValue>
                                    <name>1</name>
                                    <description>Output (functions as an output pin)</description>
                                    <value>#1</value>
                                </enumeratedValue>
                            </enumeratedValues>
                        </field>
                        <field>
                            <name>PDR03</name>
                            <description>Pmn Direction</description>
                            <lsb>3</lsb>
                            <msb>3</msb>
                            <access>read-write</access>
                            <enumeratedValues>
                                <enumeratedValue>
                                    <name>0</name>
                                    <description>Input (functions as an input pin)</description>
                                    <value>#0</value>
                                </enumeratedValue>
                                <enumeratedValue>
                                    <name>1</name>
                                    <description>Output (functions as an output pin)</description>
                                    <value>#1</value>
                                </enumeratedValue>
                            </enumeratedValues>
                        </field>
                        <field>
                            <name>PDR04</name>
                            <description>Pmn Direction</description>
                            <lsb>4</lsb>
                            <msb>4</msb>
                            <access>read-write</access>
                            <enumeratedValues>
                                <enumeratedValue>
                                    <name>0</name>
                                    <description>Input (functions as an input pin)</description>
                                    <value>#0</value>
                                </enumeratedValue>
                                <enumeratedValue>
                                    <name>1</name>
                                    <description>Output (functions as an output pin)</description>
                                    <value>#1</value>
                                </enumeratedValue>
                            </enumeratedValues>
                        </field>
                        <field>
                            <name>PDR05</name>
                            <description>Pmn Direction</description>
                            <lsb>5</lsb>
                            <msb>5</msb>
                            <access>read-write</access>
                            <enumeratedValues>
                                <enumeratedValue>
                                    <name>0</name>
                                    <description>Input (functions as an input pin)</description>
                                    <value>#0</value>
                                </enumeratedValue>
                                <enumeratedValue>
                                    <name>1</name>
                                    <description>Output (functions as an output pin)</description>
                                    <value>#1</value>
                                </enumeratedValue>
                            </enumeratedValues>
                        </field>
                        <field>
                            <name>PDR06</name>
                            <description>Pmn Direction</description>
                            <lsb>6</lsb>
                            <msb>6</msb>
                            <access>read-write</access>
                            <enumeratedValues>
                                <enumeratedValue>
                                    <name>0</name>
                                    <description>Input (functions as an input pin)</description>
                                    <value>#0</value>
                                </enumeratedValue>
                                <enumeratedValue>
                                    <name>1</name>
                                    <description>Output (functions as an output pin)</description>
                                    <value>#1</value>
                                </enumeratedValue>
                            </enumeratedValues>
                        </field>
                        <field>
                            <name>PDR07</name>
                            <description>Pmn Direction</description>
                            <lsb>7</lsb>
                            <msb>7</msb>
                            <access>read-write</access>
                            <enumeratedValues>
                                <enumeratedValue>
                                    <name>0</name>
                                    <description>Input (functions as an input pin)</description>
                                    <value>#0</value>
                                </enumeratedValue>
                                <enumeratedValue>
                                    <name>1</name>
                                    <description>Output (functions as an output pin)</description>
                                    <value>#1</value>
                                </enumeratedValue>
                            </enumeratedValues>
                        </field>
                        <field>
                            <name>PDR08</name>
                            <description>Pmn Direction</description>
                            <lsb>8</lsb>
                            <msb>8</msb>
                            <access>read-write</access>
                            <enumeratedValues>
                                <enumeratedValue>
                                    <name>0</name>
                                    <description>Input (functions as an input pin)</description>
                                    <value>#0</value>
                                </enumeratedValue>
                                <enumeratedValue>
                                    <name>1</name>
                                    <description>Output (functions as an output pin)</description>
                                    <value>#1</value>
                                </enumeratedValue>
                            </enumeratedValues>
                        </field>
                        <field>
                            <name>PDR09</name>
                            <description>Pmn Direction</description>
                            <lsb>9</lsb>
                            <msb>9</msb>
                            <access>read-write</access>
                            <enumeratedValues>
                                <enumeratedValue>
                                    <name>0</name>
                                    <description>Input (functions as an input pin)</description>
                                    <value>#0</value>
                                </enumeratedValue>
                                <enumeratedValue>
                                    <name>1</name>
                                    <description>Output (functions as an output pin)</description>
                                    <value>#1</value>
                                </enumeratedValue>
                            </enumeratedValues>
                        </field>
                        <field>
                            <name>PDR10</name>
                            <description>Pmn Direction</description>
                            <lsb>10</lsb>
                            <msb>10</msb>
                            <access>read-write</access>
                            <enumeratedValues>
                                <enumeratedValue>
                                    <name>0</name>
                                    <description>Input (functions as an input pin)</description>
                                    <value>#0</value>
                                </enumeratedValue>
                                <enumeratedValue>
                                    <name>1</name>
                                    <description>Output (functions as an output pin)</description>
                                    <value>#1</value>
                                </enumeratedValue>
                            </enumeratedValues>
                        </field>
                        <field>
                            <name>PDR11</name>
                            <description>Pmn Direction</description>
                            <lsb>11</lsb>
                            <msb>11</msb>
                            <access>read-write</access>
                            <enumeratedValues>
                                <enumeratedValue>
                                    <name>0</name>
                                    <description>Input (functions as an input pin)</description>
                                    <value>#0</value>
                                </enumeratedValue>
                                <enumeratedValue>
                                    <name>1</name>
                                    <description>Output (functions as an output pin)</description>
                                    <value>#1</value>
                                </enumeratedValue>
                            </enumeratedValues>
                        </field>
                        <field>
                            <name>PDR12</name>
                            <description>Pmn Direction</description>
                            <lsb>12</lsb>
                            <msb>12</msb>
                            <access>read-write</access>
                            <enumeratedValues>
                                <enumeratedValue>
                                    <name>0</name>
                                    <description>Input (functions as an input pin)</description>
                                    <value>#0</value>
                                </enumeratedValue>
                                <enumeratedValue>
                                    <name>1</name>
                                    <description>Output (functions as an output pin)</description>
                                    <value>#1</value>
                                </enumeratedValue>
                            </enumeratedValues>
                        </field>
                        <field>
                            <name>PDR13</name>
                            <description>Pmn Direction</description>
                            <lsb>13</lsb>
                            <msb>13</msb>
                            <access>read-write</access>
                            <enumeratedValues>
                                <enumeratedValue>
                                    <name>0</name>
                                    <description>Input (functions as an input pin)</description>
                                    <value>#0</value>
                                </enumeratedValue>
                                <enumeratedValue>
                                    <name>1</name>
                                    <description>Output (functions as an output pin)</description>
                                    <value>#1</value>
                                </enumeratedValue>
                            </enumeratedValues>
                        </field>
                        <field>
                            <name>PDR14</name>
                            <description>Pmn Direction</description>
                            <lsb>14</lsb>
                            <msb>14</msb>
                            <access>read-write</access>
                            <enumeratedValues>
                                <enumeratedValue>
                                    <name>0</name>
                                    <description>Input (functions as an input pin)</description>
                                    <value>#0</value>
                                </enumeratedValue>
                                <enumeratedValue>
                                    <name>1</name>
                                    <description>Output (functions as an output pin)</description>
                                    <value>#1</value>
                                </enumeratedValue>
                            </enumeratedValues>
                        </field>
                        <field>
                            <name>PDR15</name>
                            <description>Pmn Direction</description>
                            <lsb>15</lsb>
                            <msb>15</msb>
                            <access>read-write</access>
                            <enumeratedValues>
                                <enumeratedValue>
                                    <name>0</name>
                                    <description>Input (functions as an input pin)</description>
                                    <value>#0</value>
                                </enumeratedValue>
                                <enumeratedValue>
                                    <name>1</name>
                                    <description>Output (functions as an output pin)</description>
                                    <value>#1</value>
                                </enumeratedValue>
                            </enumeratedValues>
                        </field>
                    </fields>
                </register>
                <register>
                    <name>PCNTR2</name>
                    <description>Port Control Register 2</description>
                    <addressOffset>0x004</addressOffset>
                    <size>32</size>
                    <access>read-only</access>
                    <resetValue>0x00000000</resetValue>
                    <resetMask>0xffff0000</resetMask>
                    <fields>
                        <field>
                            <name>PIDR00</name>
                            <description>Pmn State</description>
                            <lsb>0</lsb>
                            <msb>0</msb>
                            <access>read-only</access>
                            <enumeratedValues>
                                <enumeratedValue>
                                    <name>0</name>
                                    <description>Low level</description>
                                    <value>#0</value>
                                </enumeratedValue>
                                <enumeratedValue>
                                    <name>1</name>
                                    <description>High level</description>
                                    <value>#1</value>
                                </enumeratedValue>
                            </enumeratedValues>
                        </field>
                        <field>
                            <name>PIDR01</name>
                            <description>Pmn State</description>
                            <lsb>1</lsb>
                            <msb>1</msb>
                            <access>read-only</access>
                            <enumeratedValues>
                                <enumeratedValue>
                                    <name>0</name>
                                    <description>Low level</description>
                                    <value>#0</value>
                                </enumeratedValue>
                                <enumeratedValue>
                                    <name>1</name>
                                    <description>High level</description>
                                    <value>#1</value>
                                </enumeratedValue>
                            </enumeratedValues>
                        </field>
                        <field>
                            <name>PIDR02</name>
                            <description>Pmn State</description>
                            <lsb>2</lsb>
                            <msb>2</msb>
                            <access>read-only</access>
                            <enumeratedValues>
                                <enumeratedValue>
                                    <name>0</name>
                                    <description>Low level</description>
                                    <value>#0</value>
                                </enumeratedValue>
                                <enumeratedValue>
                                    <name>1</name>
                                    <description>High level</description>
                                    <value>#1</value>
                                </enumeratedValue>
                            </enumeratedValues>
                        </field>
                        <field>
                            <name>PIDR03</name>
                            <description>Pmn State</description>
                            <lsb>3</lsb>
                            <msb>3</msb>
                            <access>read-only</access>
                            <enumeratedValues>
                                <enumeratedValue>
                                    <name>0</name>
                                    <description>Low level</description>
                                    <value>#0</value>
                                </enumeratedValue>
                                <enumeratedValue>
                                    <name>1</name>
                                    <description>High level</description>
                                    <value>#1</value>
                                </enumeratedValue>
                            </enumeratedValues>
                        </field>
                        <field>
                            <name>PIDR04</name>
                            <description>Pmn State</description>
                            <lsb>4</lsb>
                            <msb>4</msb>
                            <access>read-only</access>
                            <enumeratedValues>
                                <enumeratedValue>
                                    <name>0</name>
                                    <description>Low level</description>
                                    <value>#0</value>
                                </enumeratedValue>
                                <enumeratedValue>
                                    <name>1</name>
                                    <description>High level</description>
                                    <value>#1</value>
                                </enumeratedValue>
                            </enumeratedValues>
                        </field>
                        <field>
                            <name>PIDR05</name>
                            <description>Pmn State</description>
                            <lsb>5</lsb>
                            <msb>5</msb>
                            <access>read-only</access>
                            <enumeratedValues>
                                <enumeratedValue>
                                    <name>0</name>
                                    <description>Low level</description>
                                    <value>#0</value>
                                </enumeratedValue>
                                <enumeratedValue>
                                    <name>1</name>
                                    <description>High level</description>
                                    <value>#1</value>
                                </enumeratedValue>
                            </enumeratedValues>
                        </field>
                        <field>
                            <name>PIDR06</name>
                            <description>Pmn State</description>
                            <lsb>6</lsb>
                            <msb>6</msb>
                            <access>read-only</access>
                            <enumeratedValues>
                                <enumeratedValue>
                                    <name>0</name>
                                    <description>Low level</description>
                                    <value>#0</value>
                                </enumeratedValue>
                                <enumeratedValue>
                                    <name>1</name>
                                    <description>High level</description>
                                    <value>#1</value>
                                </enumeratedValue>
                            </enumeratedValues>
                        </field>
                        <field>
                            <name>PIDR07</name>
                            <description>Pmn State</description>
                            <lsb>7</lsb>
                            <msb>7</msb>
                            <access>read-only</access>
                            <enumeratedValues>
                                <enumeratedValue>
                                    <name>0</name>
                                    <description>Low level</description>
                                    <value>#0</value>
                                </enumeratedValue>
                                <enumeratedValue>
                                    <name>1</name>
                                    <description>High level</description>
                                    <value>#1</value>
                                </enumeratedValue>
                            </enumeratedValues>
                        </field>
                        <field>
                            <name>PIDR08</name>
                            <description>Pmn State</description>
                            <lsb>8</lsb>
                            <msb>8</msb>
                            <access>read-only</access>
                            <enumeratedValues>
                                <enumeratedValue>
                                    <name>0</name>
                                    <description>Low level</description>
                                    <value>#0</value>
                                </enumeratedValue>
                                <enumeratedValue>
                                    <name>1</name>
                                    <description>High level</description>
                                    <value>#1</value>
                                </enumeratedValue>
                            </enumeratedValues>
                        </field>
                        <field>
                            <name>PIDR09</name>
                            <description>Pmn State</description>
                            <lsb>9</lsb>
                            <msb>9</msb>
                            <access>read-only</access>
                            <enumeratedValues>
                                <enumeratedValue>
                                    <name>0</name>
                                    <description>Low level</description>
                                    <value>#0</value>
                                </enumeratedValue>
                                <enumeratedValue>
                                    <name>1</name>
                                    <description>High level</description>
                                    <value>#1</value>
                                </enumeratedValue>
                            </enumeratedValues>
                        </field>
                        <field>
                            <name>PIDR10</name>
                            <description>Pmn State</description>
                            <lsb>10</lsb>
                            <msb>10</msb>
                            <access>read-only</access>
                            <enumeratedValues>
                                <enumeratedValue>
                                    <name>0</name>
                                    <description>Low level</description>
                                    <value>#0</value>
                                </enumeratedValue>
                                <enumeratedValue>
                                    <name>1</name>
                                    <description>High level</description>
                                    <value>#1</value>
                                </enumeratedValue>
                            </enumeratedValues>
                        </field>
                        <field>
                            <name>PIDR11</name>
                            <description>Pmn State</description>
                            <lsb>11</lsb>
                            <msb>11</msb>
                            <access>read-only</access>
                            <enumeratedValues>
                                <enumeratedValue>
                                    <name>0</name>
                                    <description>Low level</description>
                                    <value>#0</value>
                                </enumeratedValue>
                                <enumeratedValue>
                                    <name>1</name>
                                    <description>High level</description>
                                    <value>#1</value>
                                </enumeratedValue>
                            </enumeratedValues>
                        </field>
                        <field>
                            <name>PIDR12</name>
                            <description>Pmn State</description>
                            <lsb>12</lsb>
                            <msb>12</msb>
                            <access>read-only</access>
                            <enumeratedValues>
                                <enumeratedValue>
                                    <name>0</name>
                                    <description>Low level</description>
                                    <value>#0</value>
                                </enumeratedValue>
                                <enumeratedValue>
                                    <name>1</name>
                                    <description>High level</description>
                                    <value>#1</value>
                                </enumeratedValue>
                            </enumeratedValues>
                        </field>
                        <field>
                            <name>PIDR13</name>
                            <description>Pmn State</description>
                            <lsb>13</lsb>
                            <msb>13</msb>
                            <access>read-only</access>
                            <enumeratedValues>
                                <enumeratedValue>
                                    <name>0</name>
                                    <description>Low level</description>
                                    <value>#0</value>
                                </enumeratedValue>
                                <enumeratedValue>
                                    <name>1</name>
                                    <description>High level</description>
                                    <value>#1</value>
                                </enumeratedValue>
                            </enumeratedValues>
                        </field>
                        <field>
                            <name>PIDR14</name>
                            <description>Pmn State</description>
                            <lsb>14</lsb>
                            <msb>14</msb>
                            <access>read-only</access>
                            <enumeratedValues>
                                <enumeratedValue>
                                    <name>0</name>
                                    <description>Low level</description>
                                    <value>#0</value>
                                </enumeratedValue>
                                <enumeratedValue>
                                    <name>1</name>
                                    <description>High level</description>
                                    <value>#1</value>
                                </enumeratedValue>
                            </enumeratedValues>
                        </field>
                        <field>
                            <name>PIDR15</name>
                            <description>Pmn State</description>
                            <lsb>15</lsb>
                            <msb>15</msb>
                            <access>read-only</access>
                            <enumeratedValues>
                                <enumeratedValue>
                                    <name>0</name>
                                    <description>Low level</description>
                                    <value>#0</value>
                                </enumeratedValue>
                                <enumeratedValue>
                                    <name>1</name>
                                    <description>High level</description>
                                    <value>#1</value>
                                </enumeratedValue>
                            </enumeratedValues>
                        </field>
                    </fields>
                </register>
                <register>
                    <name>PIDR</name>
                    <description>Port Control Register 2</description>
                    <alternateRegister>PCNTR2</alternateRegister>
                    <addressOffset>0x004</addressOffset>
                    <size>16</size>
                    <access>read-only</access>
                    <resetValue>0x0000</resetValue>
                    <resetMask>0xffff</resetMask>
                </register>
                <register>
                    <name>PCNTR3</name>
                    <description>Port Control Register 3</description>
                    <addressOffset>0x008</addressOffset>
                    <size>32</size>
                    <access>write-only</access>
                    <resetValue>0x00000000</resetValue>
                    <resetMask>0xffffffff</resetMask>
                    <fields>
                        <field>
                            <name>POSR00</name>
                            <description>Pmn Output Set</description>
                            <lsb>0</lsb>
                            <msb>0</msb>
                            <access>write-only</access>
                            <enumeratedValues>
                                <enumeratedValue>
                                    <name>0</name>
                                    <description>No effect on output</description>
                                    <value>#0</value>
                                </enumeratedValue>
                                <enumeratedValue>
                                    <name>1</name>
                                    <description>High output</description>
                                    <value>#1</value>
                                </enumeratedValue>
                            </enumeratedValues>
                        </field>
                        <field>
                            <name>POSR01</name>
                            <description>Pmn Output Set</description>
                            <lsb>1</lsb>
                            <msb>1</msb>
                            <access>write-only</access>
                            <enumeratedValues>
                                <enumeratedValue>
                                    <name>0</name>
                                    <description>No effect on output</description>
                                    <value>#0</value>
                                </enumeratedValue>
                                <enumeratedValue>
                                    <name>1</name>
                                    <description>High output</description>
                                    <value>#1</value>
                                </enumeratedValue>
                            </enumeratedValues>
                        </field>
                        <field>
                            <name>POSR02</name>
                            <description>Pmn Output Set</description>
                            <lsb>2</lsb>
                            <msb>2</msb>
                            <access>write-only</access>
                            <enumeratedValues>
                                <enumeratedValue>
                                    <name>0</name>
                                    <description>No effect on output</description>
                                    <value>#0</value>
                                </enumeratedValue>
                                <enumeratedValue>
                                    <name>1</name>
                                    <description>High output</description>
                                    <value>#1</value>
                                </enumeratedValue>
                            </enumeratedValues>
                        </field>
                        <field>
                            <name>POSR03</name>
                            <description>Pmn Output Set</description>
                            <lsb>3</lsb>
                            <msb>3</msb>
                            <access>write-only</access>
                            <enumeratedValues>
                                <enumeratedValue>
                                    <name>0</name>
                                    <description>No effect on output</description>
                                    <value>#0</value>
                                </enumeratedValue>
                                <enumeratedValue>
                                    <name>1</name>
                                    <description>High output</description>
                                    <value>#1</value>
                                </enumeratedValue>
                            </enumeratedValues>
                        </field>
                        <field>
                            <name>POSR04</name>
                            <description>Pmn Output Set</description>
                            <lsb>4</lsb>
                            <msb>4</msb>
                            <access>write-only</access>
                            <enumeratedValues>
                                <enumeratedValue>
                                    <name>0</name>
                                    <description>No effect on output</description>
                                    <value>#0</value>
                                </enumeratedValue>
                                <enumeratedValue>
                                    <name>1</name>
                                    <description>High output</description>
                                    <value>#1</value>
                                </enumeratedValue>
                            </enumeratedValues>
                        </field>
                        <field>
                            <name>POSR05</name>
                            <description>Pmn Output Set</description>
                            <lsb>5</lsb>
                            <msb>5</msb>
                            <access>write-only</access>
                            <enumeratedValues>
                                <enumeratedValue>
                                    <name>0</name>
                                    <description>No effect on output</description>
                                    <value>#0</value>
                                </enumeratedValue>
                                <enumeratedValue>
                                    <name>1</name>
                                    <description>High output</description>
                                    <value>#1</value>
                                </enumeratedValue>
                            </enumeratedValues>
                        </field>
                        <field>
                            <name>POSR06</name>
                            <description>Pmn Output Set</description>
                            <lsb>6</lsb>
                            <msb>6</msb>
                            <access>write-only</access>
                            <enumeratedValues>
                                <enumeratedValue>
                                    <name>0</name>
                                    <description>No effect on output</description>
                                    <value>#0</value>
                                </enumeratedValue>
                                <enumeratedValue>
                                    <name>1</name>
                                    <description>High output</description>
                                    <value>#1</value>
                                </enumeratedValue>
                            </enumeratedValues>
                        </field>
                        <field>
                            <name>POSR07</name>
                            <description>Pmn Output Set</description>
                            <lsb>7</lsb>
                            <msb>7</msb>
                            <access>write-only</access>
                            <enumeratedValues>
                                <enumeratedValue>
                                    <name>0</name>
                                    <description>No effect on output</description>
                                    <value>#0</value>
                                </enumeratedValue>
                                <enumeratedValue>
                                    <name>1</name>
                                    <description>High output</description>
                                    <value>#1</value>
                                </enumeratedValue>
                            </enumeratedValues>
                        </field>
                        <field>
                            <name>POSR08</name>
                            <description>Pmn Output Set</description>
                            <lsb>8</lsb>
                            <msb>8</msb>
                            <access>write-only</access>
                            <enumeratedValues>
                                <enumeratedValue>
                                    <name>0</name>
                                    <description>No effect on output</description>
                                    <value>#0</value>
                                </enumeratedValue>
                                <enumeratedValue>
                                    <name>1</name>
                                    <description>High output</description>
                                    <value>#1</value>
                                </enumeratedValue>
                            </enumeratedValues>
                        </field>
                        <field>
                            <name>POSR09</name>
                            <description>Pmn Output Set</description>
                            <lsb>9</lsb>
                            <msb>9</msb>
                            <access>write-only</access>
                            <enumeratedValues>
                                <enumeratedValue>
                                    <name>0</name>
                                    <description>No effect on output</description>
                                    <value>#0</value>
                                </enumeratedValue>
                                <enumeratedValue>
                                    <name>1</name>
                                    <description>High output</description>
                                    <value>#1</value>
                                </enumeratedValue>
                            </enumeratedValues>
                        </field>
                        <field>
                            <name>POSR10</name>
                            <description>Pmn Output Set</description>
                            <lsb>10</lsb>
                            <msb>10</msb>
                            <access>write-only</access>
                            <enumeratedValues>
                                <enumeratedValue>
                                    <name>0</name>
                                    <description>No effect on output</description>
                                    <value>#0</value>
                                </enumeratedValue>
                                <enumeratedValue>
                                    <name>1</name>
                                    <description>High output</description>
                                    <value>#1</value>
                                </enumeratedValue>
                            </enumeratedValues>
                        </field>
                        <field>
                            <name>POSR11</name>
                            <description>Pmn Output Set</description>
                            <lsb>11</lsb>
                            <msb>11</msb>
                            <access>write-only</access>
                            <enumeratedValues>
                                <enumeratedValue>
                                    <name>0</name>
                                    <description>No effect on output</description>
                                    <value>#0</value>
                                </enumeratedValue>
                                <enumeratedValue>
                                    <name>1</name>
                                    <description>High output</description>
                                    <value>#1</value>
                                </enumeratedValue>
                            </enumeratedValues>
                        </field>
                        <field>
                            <name>POSR12</name>
                            <description>Pmn Output Set</description>
                            <lsb>12</lsb>
                            <msb>12</msb>
                            <access>write-only</access>
                            <enumeratedValues>
                                <enumeratedValue>
                                    <name>0</name>
                                    <description>No effect on output</description>
                                    <value>#0</value>
                                </enumeratedValue>
                                <enumeratedValue>
                                    <name>1</name>
                                    <description>High output</description>
                                    <value>#1</value>
                                </enumeratedValue>
                            </enumeratedValues>
                        </field>
                        <field>
                            <name>POSR13</name>
                            <description>Pmn Output Set</description>
                            <lsb>13</lsb>
                            <msb>13</msb>
                            <access>write-only</access>
                            <enumeratedValues>
                                <enumeratedValue>
                                    <name>0</name>
                                    <description>No effect on output</description>
                                    <value>#0</value>
                                </enumeratedValue>
                                <enumeratedValue>
                                    <name>1</name>
                                    <description>High output</description>
                                    <value>#1</value>
                                </enumeratedValue>
                            </enumeratedValues>
                        </field>
                        <field>
                            <name>POSR14</name>
                            <description>Pmn Output Set</description>
                            <lsb>14</lsb>
                            <msb>14</msb>
                            <access>write-only</access>
                            <enumeratedValues>
                                <enumeratedValue>
                                    <name>0</name>
                                    <description>No effect on output</description>
                                    <value>#0</value>
                                </enumeratedValue>
                                <enumeratedValue>
                                    <name>1</name>
                                    <description>High output</description>
                                    <value>#1</value>
                                </enumeratedValue>
                            </enumeratedValues>
                        </field>
                        <field>
                            <name>POSR15</name>
                            <description>Pmn Output Set</description>
                            <lsb>15</lsb>
                            <msb>15</msb>
                            <access>write-only</access>
                            <enumeratedValues>
                                <enumeratedValue>
                                    <name>0</name>
                                    <description>No effect on output</description>
                                    <value>#0</value>
                                </enumeratedValue>
                                <enumeratedValue>
                                    <name>1</name>
                                    <description>High output</description>
                                    <value>#1</value>
                                </enumeratedValue>
                            </enumeratedValues>
                        </field>
                        <field>
                            <name>PORR00</name>
                            <description>Pmn Output Reset</description>
                            <lsb>16</lsb>
                            <msb>16</msb>
                            <access>write-only</access>
                            <enumeratedValues>
                                <enumeratedValue>
                                    <name>0</name>
                                    <description>No effect on output</description>
                                    <value>#0</value>
                                </enumeratedValue>
                                <enumeratedValue>
                                    <name>1</name>
                                    <description>Low output</description>
                                    <value>#1</value>
                                </enumeratedValue>
                            </enumeratedValues>
                        </field>
                        <field>
                            <name>PORR01</name>
                            <description>Pmn Output Reset</description>
                            <lsb>17</lsb>
                            <msb>17</msb>
                            <access>write-only</access>
                            <enumeratedValues>
                                <enumeratedValue>
                                    <name>0</name>
                                    <description>No effect on output</description>
                                    <value>#0</value>
                                </enumeratedValue>
                                <enumeratedValue>
                                    <name>1</name>
                                    <description>Low output</description>
                                    <value>#1</value>
                                </enumeratedValue>
                            </enumeratedValues>
                        </field>
                        <field>
                            <name>PORR02</name>
                            <description>Pmn Output Reset</description>
                            <lsb>18</lsb>
                            <msb>18</msb>
                            <access>write-only</access>
                            <enumeratedValues>
                                <enumeratedValue>
                                    <name>0</name>
                                    <description>No effect on output</description>
                                    <value>#0</value>
                                </enumeratedValue>
                                <enumeratedValue>
                                    <name>1</name>
                                    <description>Low output</description>
                                    <value>#1</value>
                                </enumeratedValue>
                            </enumeratedValues>
                        </field>
                        <field>
                            <name>PORR03</name>
                            <description>Pmn Output Reset</description>
                            <lsb>19</lsb>
                            <msb>19</msb>
                            <access>write-only</access>
                            <enumeratedValues>
                                <enumeratedValue>
                                    <name>0</name>
                                    <description>No effect on output</description>
                                    <value>#0</value>
                                </enumeratedValue>
                                <enumeratedValue>
                                    <name>1</name>
                                    <description>Low output</description>
                                    <value>#1</value>
                                </enumeratedValue>
                            </enumeratedValues>
                        </field>
                        <field>
                            <name>PORR04</name>
                            <description>Pmn Output Reset</description>
                            <lsb>20</lsb>
                            <msb>20</msb>
                            <access>write-only</access>
                            <enumeratedValues>
                                <enumeratedValue>
                                    <name>0</name>
                                    <description>No effect on output</description>
                                    <value>#0</value>
                                </enumeratedValue>
                                <enumeratedValue>
                                    <name>1</name>
                                    <description>Low output</description>
                                    <value>#1</value>
                                </enumeratedValue>
                            </enumeratedValues>
                        </field>
                        <field>
                            <name>PORR05</name>
                            <description>Pmn Output Reset</description>
                            <lsb>21</lsb>
                            <msb>21</msb>
                            <access>write-only</access>
                            <enumeratedValues>
                                <enumeratedValue>
                                    <name>0</name>
                                    <description>No effect on output</description>
                                    <value>#0</value>
                                </enumeratedValue>
                                <enumeratedValue>
                                    <name>1</name>
                                    <description>Low output</description>
                                    <value>#1</value>
                                </enumeratedValue>
                            </enumeratedValues>
                        </field>
                        <field>
                            <name>PORR06</name>
                            <description>Pmn Output Reset</description>
                            <lsb>22</lsb>
                            <msb>22</msb>
                            <access>write-only</access>
                            <enumeratedValues>
                                <enumeratedValue>
                                    <name>0</name>
                                    <description>No effect on output</description>
                                    <value>#0</value>
                                </enumeratedValue>
                                <enumeratedValue>
                                    <name>1</name>
                                    <description>Low output</description>
                                    <value>#1</value>
                                </enumeratedValue>
                            </enumeratedValues>
                        </field>
                        <field>
                            <name>PORR07</name>
                            <description>Pmn Output Reset</description>
                            <lsb>23</lsb>
                            <msb>23</msb>
                            <access>write-only</access>
                            <enumeratedValues>
                                <enumeratedValue>
                                    <name>0</name>
                                    <description>No effect on output</description>
                                    <value>#0</value>
                                </enumeratedValue>
                                <enumeratedValue>
                                    <name>1</name>
                                    <description>Low output</description>
                                    <value>#1</value>
                                </enumeratedValue>
                            </enumeratedValues>
                        </field>
                        <field>
                            <name>PORR08</name>
                            <description>Pmn Output Reset</description>
                            <lsb>24</lsb>
                            <msb>24</msb>
                            <access>write-only</access>
                            <enumeratedValues>
                                <enumeratedValue>
                                    <name>0</name>
                                    <description>No effect on output</description>
                                    <value>#0</value>
                                </enumeratedValue>
                                <enumeratedValue>
                                    <name>1</name>
                                    <description>Low output</description>
                                    <value>#1</value>
                                </enumeratedValue>
                            </enumeratedValues>
                        </field>
                        <field>
                            <name>PORR09</name>
                            <description>Pmn Output Reset</description>
                            <lsb>25</lsb>
                            <msb>25</msb>
                            <access>write-only</access>
                            <enumeratedValues>
                                <enumeratedValue>
                                    <name>0</name>
                                    <description>No effect on output</description>
                                    <value>#0</value>
                                </enumeratedValue>
                                <enumeratedValue>
                                    <name>1</name>
                                    <description>Low output</description>
                                    <value>#1</value>
                                </enumeratedValue>
                            </enumeratedValues>
                        </field>
                        <field>
                            <name>PORR10</name>
                            <description>Pmn Output Reset</description>
                            <lsb>26</lsb>
                            <msb>26</msb>
                            <access>write-only</access>
                            <enumeratedValues>
                                <enumeratedValue>
                                    <name>0</name>
                                    <description>No effect on output</description>
                                    <value>#0</value>
                                </enumeratedValue>
                                <enumeratedValue>
                                    <name>1</name>
                                    <description>Low output</description>
                                    <value>#1</value>
                                </enumeratedValue>
                            </enumeratedValues>
                        </field>
                        <field>
                            <name>PORR11</name>
                            <description>Pmn Output Reset</description>
                            <lsb>27</lsb>
                            <msb>27</msb>
                            <access>write-only</access>
                            <enumeratedValues>
                                <enumeratedValue>
                                    <name>0</name>
                                    <description>No effect on output</description>
                                    <value>#0</value>
                                </enumeratedValue>
                                <enumeratedValue>
                                    <name>1</name>
                                    <description>Low output</description>
                                    <value>#1</value>
                                </enumeratedValue>
                            </enumeratedValues>
                        </field>
                        <field>
                            <name>PORR12</name>
                            <description>Pmn Output Reset</description>
                            <lsb>28</lsb>
                            <msb>28</msb>
                            <access>write-only</access>
                            <enumeratedValues>
                                <enumeratedValue>
                                    <name>0</name>
                                    <description>No effect on output</description>
                                    <value>#0</value>
                                </enumeratedValue>
                                <enumeratedValue>
                                    <name>1</name>
                                    <description>Low output</description>
                                    <value>#1</value>
                                </enumeratedValue>
                            </enumeratedValues>
                        </field>
                        <field>
                            <name>PORR13</name>
                            <description>Pmn Output Reset</description>
                            <lsb>29</lsb>
                            <msb>29</msb>
                            <access>write-only</access>
                            <enumeratedValues>
                                <enumeratedValue>
                                    <name>0</name>
                                    <description>No effect on output</description>
                                    <value>#0</value>
                                </enumeratedValue>
                                <enumeratedValue>
                                    <name>1</name>
                                    <description>Low output</description>
                                    <value>#1</value>
                                </enumeratedValue>
                            </enumeratedValues>
                        </field>
                        <field>
                            <name>PORR14</name>
                            <description>Pmn Output Reset</description>
                            <lsb>30</lsb>
                            <msb>30</msb>
                            <access>write-only</access>
                            <enumeratedValues>
                                <enumeratedValue>
                                    <name>0</name>
                                    <description>No effect on output</description>
                                    <value>#0</value>
                                </enumeratedValue>
                                <enumeratedValue>
                                    <name>1</name>
                                    <description>Low output</description>
                                    <value>#1</value>
                                </enumeratedValue>
                            </enumeratedValues>
                        </field>
                        <field>
                            <name>PORR15</name>
                            <description>Pmn Output Reset</description>
                            <lsb>31</lsb>
                            <msb>31</msb>
                            <access>write-only</access>
                            <enumeratedValues>
                                <enumeratedValue>
                                    <name>0</name>
                                    <description>No effect on output</description>
                                    <value>#0</value>
                                </enumeratedValue>
                                <enumeratedValue>
                                    <name>1</name>
                                    <description>Low output</description>
                                    <value>#1</value>
                                </enumeratedValue>
                            </enumeratedValues>
                        </field>
                    </fields>
                </register>
                <register>
                    <name>POSR</name>
                    <description>Port Control Register 3</description>
                    <alternateRegister>PCNTR3</alternateRegister>
                    <addressOffset>0x008</addressOffset>
                    <size>16</size>
                    <access>write-only</access>
                    <resetValue>0x0000</resetValue>
                    <resetMask>0xffff</resetMask>
                    <fields>
                        <field>
                            <name>PORR00</name>
                            <description>Pmn Output Reset</description>
                            <lsb>0</lsb>
                            <msb>0</msb>
                            <access>write-only</access>
                            <enumeratedValues>
                                <enumeratedValue>
                                    <name>0</name>
                                    <description>No effect on output</description>
                                    <value>#0</value>
                                </enumeratedValue>
                                <enumeratedValue>
                                    <name>1</name>
                                    <description>Low output</description>
                                    <value>#1</value>
                                </enumeratedValue>
                            </enumeratedValues>
                        </field>
                        <field>
                            <name>PORR01</name>
                            <description>Pmn Output Reset</description>
                            <lsb>1</lsb>
                            <msb>1</msb>
                            <access>write-only</access>
                            <enumeratedValues>
                                <enumeratedValue>
                                    <name>0</name>
                                    <description>No effect on output</description>
                                    <value>#0</value>
                                </enumeratedValue>
                                <enumeratedValue>
                                    <name>1</name>
                                    <description>Low output</description>
                                    <value>#1</value>
                                </enumeratedValue>
                            </enumeratedValues>
                        </field>
                        <field>
                            <name>PORR02</name>
                            <description>Pmn Output Reset</description>
                            <lsb>2</lsb>
                            <msb>2</msb>
                            <access>write-only</access>
                            <enumeratedValues>
                                <enumeratedValue>
                                    <name>0</name>
                                    <description>No effect on output</description>
                                    <value>#0</value>
                                </enumeratedValue>
                                <enumeratedValue>
                                    <name>1</name>
                                    <description>Low output</description>
                                    <value>#1</value>
                                </enumeratedValue>
                            </enumeratedValues>
                        </field>
                        <field>
                            <name>PORR03</name>
                            <description>Pmn Output Reset</description>
                            <lsb>3</lsb>
                            <msb>3</msb>
                            <access>write-only</access>
                            <enumeratedValues>
                                <enumeratedValue>
                                    <name>0</name>
                                    <description>No effect on output</description>
                                    <value>#0</value>
                                </enumeratedValue>
                                <enumeratedValue>
                                    <name>1</name>
                                    <description>Low output</description>
                                    <value>#1</value>
                                </enumeratedValue>
                            </enumeratedValues>
                        </field>
                        <field>
                            <name>PORR04</name>
                            <description>Pmn Output Reset</description>
                            <lsb>4</lsb>
                            <msb>4</msb>
                            <access>write-only</access>
                            <enumeratedValues>
                                <enumeratedValue>
                                    <name>0</name>
                                    <description>No effect on output</description>
                                    <value>#0</value>
                                </enumeratedValue>
                                <enumeratedValue>
                                    <name>1</name>
                                    <description>Low output</description>
                                    <value>#1</value>
                                </enumeratedValue>
                            </enumeratedValues>
                        </field>
                        <field>
                            <name>PORR05</name>
                            <description>Pmn Output Reset</description>
                            <lsb>5</lsb>
                            <msb>5</msb>
                            <access>write-only</access>
                            <enumeratedValues>
                                <enumeratedValue>
                                    <name>0</name>
                                    <description>No effect on output</description>
                                    <value>#0</value>
                                </enumeratedValue>
                                <enumeratedValue>
                                    <name>1</name>
                                    <description>Low output</description>
                                    <value>#1</value>
                                </enumeratedValue>
                            </enumeratedValues>
                        </field>
                        <field>
                            <name>PORR06</name>
                            <description>Pmn Output Reset</description>
                            <lsb>6</lsb>
                            <msb>6</msb>
                            <access>write-only</access>
                            <enumeratedValues>
                                <enumeratedValue>
                                    <name>0</name>
                                    <description>No effect on output</description>
                                    <value>#0</value>
                                </enumeratedValue>
                                <enumeratedValue>
                                    <name>1</name>
                                    <description>Low output</description>
                                    <value>#1</value>
                                </enumeratedValue>
                            </enumeratedValues>
                        </field>
                        <field>
                            <name>PORR07</name>
                            <description>Pmn Output Reset</description>
                            <lsb>7</lsb>
                            <msb>7</msb>
                            <access>write-only</access>
                            <enumeratedValues>
                                <enumeratedValue>
                                    <name>0</name>
                                    <description>No effect on output</description>
                                    <value>#0</value>
                                </enumeratedValue>
                                <enumeratedValue>
                                    <name>1</name>
                                    <description>Low output</description>
                                    <value>#1</value>
                                </enumeratedValue>
                            </enumeratedValues>
                        </field>
                        <field>
                            <name>PORR08</name>
                            <description>Pmn Output Reset</description>
                            <lsb>8</lsb>
                            <msb>8</msb>
                            <access>write-only</access>
                            <enumeratedValues>
                                <enumeratedValue>
                                    <name>0</name>
                                    <description>No effect on output</description>
                                    <value>#0</value>
                                </enumeratedValue>
                                <enumeratedValue>
                                    <name>1</name>
                                    <description>Low output</description>
                                    <value>#1</value>
                                </enumeratedValue>
                            </enumeratedValues>
                        </field>
                        <field>
                            <name>PORR09</name>
                            <description>Pmn Output Reset</description>
                            <lsb>9</lsb>
                            <msb>9</msb>
                            <access>write-only</access>
                            <enumeratedValues>
                                <enumeratedValue>
                                    <name>0</name>
                                    <description>No effect on output</description>
                                    <value>#0</value>
                                </enumeratedValue>
                                <enumeratedValue>
                                    <name>1</name>
                                    <description>Low output</description>
                                    <value>#1</value>
                                </enumeratedValue>
                            </enumeratedValues>
                        </field>
                        <field>
                            <name>PORR10</name>
                            <description>Pmn Output Reset</description>
                            <lsb>10</lsb>
                            <msb>10</msb>
                            <access>write-only</access>
                            <enumeratedValues>
                                <enumeratedValue>
                                    <name>0</name>
                                    <description>No effect on output</description>
                                    <value>#0</value>
                                </enumeratedValue>
                                <enumeratedValue>
                                    <name>1</name>
                                    <description>Low output</description>
                                    <value>#1</value>
                                </enumeratedValue>
                            </enumeratedValues>
                        </field>
                        <field>
                            <name>PORR11</name>
                            <description>Pmn Output Reset</description>
                            <lsb>11</lsb>
                            <msb>11</msb>
                            <access>write-only</access>
                            <enumeratedValues>
                                <enumeratedValue>
                                    <name>0</name>
                                    <description>No effect on output</description>
                                    <value>#0</value>
                                </enumeratedValue>
                                <enumeratedValue>
                                    <name>1</name>
                                    <description>Low output</description>
                                    <value>#1</value>
                                </enumeratedValue>
                            </enumeratedValues>
                        </field>
                        <field>
                            <name>PORR12</name>
                            <description>Pmn Output Reset</description>
                            <lsb>12</lsb>
                            <msb>12</msb>
                            <access>write-only</access>
                            <enumeratedValues>
                                <enumeratedValue>
                                    <name>0</name>
                                    <description>No effect on output</description>
                                    <value>#0</value>
                                </enumeratedValue>
                                <enumeratedValue>
                                    <name>1</name>
                                    <description>Low output</description>
                                    <value>#1</value>
                                </enumeratedValue>
                            </enumeratedValues>
                        </field>
                        <field>
                            <name>PORR13</name>
                            <description>Pmn Output Reset</description>
                            <lsb>13</lsb>
                            <msb>13</msb>
                            <access>write-only</access>
                            <enumeratedValues>
                                <enumeratedValue>
                                    <name>0</name>
                                    <description>No effect on output</description>
                                    <value>#0</value>
                                </enumeratedValue>
                                <enumeratedValue>
                                    <name>1</name>
                                    <description>Low output</description>
                                    <value>#1</value>
                                </enumeratedValue>
                            </enumeratedValues>
                        </field>
                        <field>
                            <name>PORR14</name>
                            <description>Pmn Output Reset</description>
                            <lsb>14</lsb>
                            <msb>14</msb>
                            <access>write-only</access>
                            <enumeratedValues>
                                <enumeratedValue>
                                    <name>0</name>
                                    <description>No effect on output</description>
                                    <value>#0</value>
                                </enumeratedValue>
                                <enumeratedValue>
                                    <name>1</name>
                                    <description>Low output</description>
                                    <value>#1</value>
                                </enumeratedValue>
                            </enumeratedValues>
                        </field>
                        <field>
                            <name>PORR15</name>
                            <description>Pmn Output Reset</description>
                            <lsb>15</lsb>
                            <msb>15</msb>
                            <access>write-only</access>
                            <enumeratedValues>
                                <enumeratedValue>
                                    <name>0</name>
                                    <description>No effect on output</description>
                                    <value>#0</value>
                                </enumeratedValue>
                                <enumeratedValue>
                                    <name>1</name>
                                    <description>Low output</description>
                                    <value>#1</value>
                                </enumeratedValue>
                            </enumeratedValues>
                        </field>
                    </fields>
                </register>
                <register>
                    <name>PORR</name>
                    <description>Port Control Register 3</description>
                    <alternateRegister>PCNTR3</alternateRegister>
                    <addressOffset>0x00A</addressOffset>
                    <size>16</size>
                    <access>write-only</access>
                    <resetValue>0x0000</resetValue>
                    <resetMask>0xffff</resetMask>
                    <fields>
                        <field>
                            <name>POSR00</name>
                            <description>Pmn Output Set</description>
                            <lsb>0</lsb>
                            <msb>0</msb>
                            <access>write-only</access>
                            <enumeratedValues>
                                <enumeratedValue>
                                    <name>0</name>
                                    <description>No effect on output</description>
                                    <value>#0</value>
                                </enumeratedValue>
                                <enumeratedValue>
                                    <name>1</name>
                                    <description>High output</description>
                                    <value>#1</value>
                                </enumeratedValue>
                            </enumeratedValues>
                        </field>
                        <field>
                            <name>POSR01</name>
                            <description>Pmn Output Set</description>
                            <lsb>1</lsb>
                            <msb>1</msb>
                            <access>write-only</access>
                            <enumeratedValues>
                                <enumeratedValue>
                                    <name>0</name>
                                    <description>No effect on output</description>
                                    <value>#0</value>
                                </enumeratedValue>
                                <enumeratedValue>
                                    <name>1</name>
                                    <description>High output</description>
                                    <value>#1</value>
                                </enumeratedValue>
                            </enumeratedValues>
                        </field>
                        <field>
                            <name>POSR02</name>
                            <description>Pmn Output Set</description>
                            <lsb>2</lsb>
                            <msb>2</msb>
                            <access>write-only</access>
                            <enumeratedValues>
                                <enumeratedValue>
                                    <name>0</name>
                                    <description>No effect on output</description>
                                    <value>#0</value>
                                </enumeratedValue>
                                <enumeratedValue>
                                    <name>1</name>
                                    <description>High output</description>
                                    <value>#1</value>
                                </enumeratedValue>
                            </enumeratedValues>
                        </field>
                        <field>
                            <name>POSR03</name>
                            <description>Pmn Output Set</description>
                            <lsb>3</lsb>
                            <msb>3</msb>
                            <access>write-only</access>
                            <enumeratedValues>
                                <enumeratedValue>
                                    <name>0</name>
                                    <description>No effect on output</description>
                                    <value>#0</value>
                                </enumeratedValue>
                                <enumeratedValue>
                                    <name>1</name>
                                    <description>High output</description>
                                    <value>#1</value>
                                </enumeratedValue>
                            </enumeratedValues>
                        </field>
                        <field>
                            <name>POSR04</name>
                            <description>Pmn Output Set</description>
                            <lsb>4</lsb>
                            <msb>4</msb>
                            <access>write-only</access>
                            <enumeratedValues>
                                <enumeratedValue>
                                    <name>0</name>
                                    <description>No effect on output</description>
                                    <value>#0</value>
                                </enumeratedValue>
                                <enumeratedValue>
                                    <name>1</name>
                                    <description>High output</description>
                                    <value>#1</value>
                                </enumeratedValue>
                            </enumeratedValues>
                        </field>
                        <field>
                            <name>POSR05</name>
                            <description>Pmn Output Set</description>
                            <lsb>5</lsb>
                            <msb>5</msb>
                            <access>write-only</access>
                            <enumeratedValues>
                                <enumeratedValue>
                                    <name>0</name>
                                    <description>No effect on output</description>
                                    <value>#0</value>
                                </enumeratedValue>
                                <enumeratedValue>
                                    <name>1</name>
                                    <description>High output</description>
                                    <value>#1</value>
                                </enumeratedValue>
                            </enumeratedValues>
                        </field>
                        <field>
                            <name>POSR06</name>
                            <description>Pmn Output Set</description>
                            <lsb>6</lsb>
                            <msb>6</msb>
                            <access>write-only</access>
                            <enumeratedValues>
                                <enumeratedValue>
                                    <name>0</name>
                                    <description>No effect on output</description>
                                    <value>#0</value>
                                </enumeratedValue>
                                <enumeratedValue>
                                    <name>1</name>
                                    <description>High output</description>
                                    <value>#1</value>
                                </enumeratedValue>
                            </enumeratedValues>
                        </field>
                        <field>
                            <name>POSR07</name>
                            <description>Pmn Output Set</description>
                            <lsb>7</lsb>
                            <msb>7</msb>
                            <access>write-only</access>
                            <enumeratedValues>
                                <enumeratedValue>
                                    <name>0</name>
                                    <description>No effect on output</description>
                                    <value>#0</value>
                                </enumeratedValue>
                                <enumeratedValue>
                                    <name>1</name>
                                    <description>High output</description>
                                    <value>#1</value>
                                </enumeratedValue>
                            </enumeratedValues>
                        </field>
                        <field>
                            <name>POSR08</name>
                            <description>Pmn Output Set</description>
                            <lsb>8</lsb>
                            <msb>8</msb>
                            <access>write-only</access>
                            <enumeratedValues>
                                <enumeratedValue>
                                    <name>0</name>
                                    <description>No effect on output</description>
                                    <value>#0</value>
                                </enumeratedValue>
                                <enumeratedValue>
                                    <name>1</name>
                                    <description>High output</description>
                                    <value>#1</value>
                                </enumeratedValue>
                            </enumeratedValues>
                        </field>
                        <field>
                            <name>POSR09</name>
                            <description>Pmn Output Set</description>
                            <lsb>9</lsb>
                            <msb>9</msb>
                            <access>write-only</access>
                            <enumeratedValues>
                                <enumeratedValue>
                                    <name>0</name>
                                    <description>No effect on output</description>
                                    <value>#0</value>
                                </enumeratedValue>
                                <enumeratedValue>
                                    <name>1</name>
                                    <description>High output</description>
                                    <value>#1</value>
                                </enumeratedValue>
                            </enumeratedValues>
                        </field>
                        <field>
                            <name>POSR10</name>
                            <description>Pmn Output Set</description>
                            <lsb>10</lsb>
                            <msb>10</msb>
                            <access>write-only</access>
                            <enumeratedValues>
                                <enumeratedValue>
                                    <name>0</name>
                                    <description>No effect on output</description>
                                    <value>#0</value>
                                </enumeratedValue>
                                <enumeratedValue>
                                    <name>1</name>
                                    <description>High output</description>
                                    <value>#1</value>
                                </enumeratedValue>
                            </enumeratedValues>
                        </field>
                        <field>
                            <name>POSR11</name>
                            <description>Pmn Output Set</description>
                            <lsb>11</lsb>
                            <msb>11</msb>
                            <access>write-only</access>
                            <enumeratedValues>
                                <enumeratedValue>
                                    <name>0</name>
                                    <description>No effect on output</description>
                                    <value>#0</value>
                                </enumeratedValue>
                                <enumeratedValue>
                                    <name>1</name>
                                    <description>High output</description>
                                    <value>#1</value>
                                </enumeratedValue>
                            </enumeratedValues>
                        </field>
                        <field>
                            <name>POSR12</name>
                            <description>Pmn Output Set</description>
                            <lsb>12</lsb>
                            <msb>12</msb>
                            <access>write-only</access>
                            <enumeratedValues>
                                <enumeratedValue>
                                    <name>0</name>
                                    <description>No effect on output</description>
                                    <value>#0</value>
                                </enumeratedValue>
                                <enumeratedValue>
                                    <name>1</name>
                                    <description>High output</description>
                                    <value>#1</value>
                                </enumeratedValue>
                            </enumeratedValues>
                        </field>
                        <field>
                            <name>POSR13</name>
                            <description>Pmn Output Set</description>
                            <lsb>13</lsb>
                            <msb>13</msb>
                            <access>write-only</access>
                            <enumeratedValues>
                                <enumeratedValue>
                                    <name>0</name>
                                    <description>No effect on output</description>
                                    <value>#0</value>
                                </enumeratedValue>
                                <enumeratedValue>
                                    <name>1</name>
                                    <description>High output</description>
                                    <value>#1</value>
                                </enumeratedValue>
                            </enumeratedValues>
                        </field>
                        <field>
                            <name>POSR14</name>
                            <description>Pmn Output Set</description>
                            <lsb>14</lsb>
                            <msb>14</msb>
                            <access>write-only</access>
                            <enumeratedValues>
                                <enumeratedValue>
                                    <name>0</name>
                                    <description>No effect on output</description>
                                    <value>#0</value>
                                </enumeratedValue>
                                <enumeratedValue>
                                    <name>1</name>
                                    <description>High output</description>
                                    <value>#1</value>
                                </enumeratedValue>
                            </enumeratedValues>
                        </field>
                        <field>
                            <name>POSR15</name>
                            <description>Pmn Output Set</description>
                            <lsb>15</lsb>
                            <msb>15</msb>
                            <access>write-only</access>
                            <enumeratedValues>
                                <enumeratedValue>
                                    <name>0</name>
                                    <description>No effect on output</description>
                                    <value>#0</value>
                                </enumeratedValue>
                                <enumeratedValue>
                                    <name>1</name>
                                    <description>High output</description>
                                    <value>#1</value>
                                </enumeratedValue>
                            </enumeratedValues>
                        </field>
                    </fields>
                </register>
            </registers>
        </peripheral>
        <peripheral>
            <name>PORT1</name>
            <description>Pmn Pin Function Port 1 Control Registers Pmn Pin Function Control Register</description>
            <baseAddress>0x40400020</baseAddress>
            <addressBlock>
                <offset>0x00</offset>
                <size>16</size>
                <usage>registers</usage>
            </addressBlock>
            <registers>
                <register>
                    <name>PCNTR1</name>
                    <description>Port Control Register 1</description>
                    <addressOffset>0x000</addressOffset>
                    <size>32</size>
                    <access>read-write</access>
                    <resetValue>0x00000000</resetValue>
                    <resetMask>0xffffffff</resetMask>
                    <fields>
                        <field>
                            <name>PDR00</name>
                            <description>Pmn Direction</description>
                            <lsb>0</lsb>
                            <msb>0</msb>
                            <access>read-write</access>
                            <enumeratedValues>
                                <enumeratedValue>
                                    <name>0</name>
                                    <description>Input (functions as an input pin)</description>
                                    <value>#0</value>
                                </enumeratedValue>
                                <enumeratedValue>
                                    <name>1</name>
                                    <description>Output (functions as an output pin)</description>
                                    <value>#1</value>
                                </enumeratedValue>
                            </enumeratedValues>
                        </field>
                        <field>
                            <name>PDR01</name>
                            <description>Pmn Direction</description>
                            <lsb>1</lsb>
                            <msb>1</msb>
                            <access>read-write</access>
                            <enumeratedValues>
                                <enumeratedValue>
                                    <name>0</name>
                                    <description>Input (functions as an input pin)</description>
                                    <value>#0</value>
                                </enumeratedValue>
                                <enumeratedValue>
                                    <name>1</name>
                                    <description>Output (functions as an output pin)</description>
                                    <value>#1</value>
                                </enumeratedValue>
                            </enumeratedValues>
                        </field>
                        <field>
                            <name>PDR02</name>
                            <description>Pmn Direction</description>
                            <lsb>2</lsb>
                            <msb>2</msb>
                            <access>read-write</access>
                            <enumeratedValues>
                                <enumeratedValue>
                                    <name>0</name>
                                    <description>Input (functions as an input pin)</description>
                                    <value>#0</value>
                                </enumeratedValue>
                                <enumeratedValue>
                                    <name>1</name>
                                    <description>Output (functions as an output pin)</description>
                                    <value>#1</value>
                                </enumeratedValue>
                            </enumeratedValues>
                        </field>
                        <field>
                            <name>PDR03</name>
                            <description>Pmn Direction</description>
                            <lsb>3</lsb>
                            <msb>3</msb>
                            <access>read-write</access>
                            <enumeratedValues>
                                <enumeratedValue>
                                    <name>0</name>
                                    <description>Input (functions as an input pin)</description>
                                    <value>#0</value>
                                </enumeratedValue>
                                <enumeratedValue>
                                    <name>1</name>
                                    <description>Output (functions as an output pin)</description>
                                    <value>#1</value>
                                </enumeratedValue>
                            </enumeratedValues>
                        </field>
                        <field>
                            <name>PDR04</name>
                            <description>Pmn Direction</description>
                            <lsb>4</lsb>
                            <msb>4</msb>
                            <access>read-write</access>
                            <enumeratedValues>
                                <enumeratedValue>
                                    <name>0</name>
                                    <description>Input (functions as an input pin)</description>
                                    <value>#0</value>
                                </enumeratedValue>
                                <enumeratedValue>
                                    <name>1</name>
                                    <description>Output (functions as an output pin)</description>
                                    <value>#1</value>
                                </enumeratedValue>
                            </enumeratedValues>
                        </field>
                        <field>
                            <name>PDR05</name>
                            <description>Pmn Direction</description>
                            <lsb>5</lsb>
                            <msb>5</msb>
                            <access>read-write</access>
                            <enumeratedValues>
                                <enumeratedValue>
                                    <name>0</name>
                                    <description>Input (functions as an input pin)</description>
                                    <value>#0</value>
                                </enumeratedValue>
                                <enumeratedValue>
                                    <name>1</name>
                                    <description>Output (functions as an output pin)</description>
                                    <value>#1</value>
                                </enumeratedValue>
                            </enumeratedValues>
                        </field>
                        <field>
                            <name>PDR06</name>
                            <description>Pmn Direction</description>
                            <lsb>6</lsb>
                            <msb>6</msb>
                            <access>read-write</access>
                            <enumeratedValues>
                                <enumeratedValue>
                                    <name>0</name>
                                    <description>Input (functions as an input pin)</description>
                                    <value>#0</value>
                                </enumeratedValue>
                                <enumeratedValue>
                                    <name>1</name>
                                    <description>Output (functions as an output pin)</description>
                                    <value>#1</value>
                                </enumeratedValue>
                            </enumeratedValues>
                        </field>
                        <field>
                            <name>PDR07</name>
                            <description>Pmn Direction</description>
                            <lsb>7</lsb>
                            <msb>7</msb>
                            <access>read-write</access>
                            <enumeratedValues>
                                <enumeratedValue>
                                    <name>0</name>
                                    <description>Input (functions as an input pin)</description>
                                    <value>#0</value>
                                </enumeratedValue>
                                <enumeratedValue>
                                    <name>1</name>
                                    <description>Output (functions as an output pin)</description>
                                    <value>#1</value>
                                </enumeratedValue>
                            </enumeratedValues>
                        </field>
                        <field>
                            <name>PDR08</name>
                            <description>Pmn Direction</description>
                            <lsb>8</lsb>
                            <msb>8</msb>
                            <access>read-write</access>
                            <enumeratedValues>
                                <enumeratedValue>
                                    <name>0</name>
                                    <description>Input (functions as an input pin)</description>
                                    <value>#0</value>
                                </enumeratedValue>
                                <enumeratedValue>
                                    <name>1</name>
                                    <description>Output (functions as an output pin)</description>
                                    <value>#1</value>
                                </enumeratedValue>
                            </enumeratedValues>
                        </field>
                        <field>
                            <name>PDR09</name>
                            <description>Pmn Direction</description>
                            <lsb>9</lsb>
                            <msb>9</msb>
                            <access>read-write</access>
                            <enumeratedValues>
                                <enumeratedValue>
                                    <name>0</name>
                                    <description>Input (functions as an input pin)</description>
                                    <value>#0</value>
                                </enumeratedValue>
                                <enumeratedValue>
                                    <name>1</name>
                                    <description>Output (functions as an output pin)</description>
                                    <value>#1</value>
                                </enumeratedValue>
                            </enumeratedValues>
                        </field>
                        <field>
                            <name>PDR10</name>
                            <description>Pmn Direction</description>
                            <lsb>10</lsb>
                            <msb>10</msb>
                            <access>read-write</access>
                            <enumeratedValues>
                                <enumeratedValue>
                                    <name>0</name>
                                    <description>Input (functions as an input pin)</description>
                                    <value>#0</value>
                                </enumeratedValue>
                                <enumeratedValue>
                                    <name>1</name>
                                    <description>Output (functions as an output pin)</description>
                                    <value>#1</value>
                                </enumeratedValue>
                            </enumeratedValues>
                        </field>
                        <field>
                            <name>PDR11</name>
                            <description>Pmn Direction</description>
                            <lsb>11</lsb>
                            <msb>11</msb>
                            <access>read-write</access>
                            <enumeratedValues>
                                <enumeratedValue>
                                    <name>0</name>
                                    <description>Input (functions as an input pin)</description>
                                    <value>#0</value>
                                </enumeratedValue>
                                <enumeratedValue>
                                    <name>1</name>
                                    <description>Output (functions as an output pin)</description>
                                    <value>#1</value>
                                </enumeratedValue>
                            </enumeratedValues>
                        </field>
                        <field>
                            <name>PDR12</name>
                            <description>Pmn Direction</description>
                            <lsb>12</lsb>
                            <msb>12</msb>
                            <access>read-write</access>
                            <enumeratedValues>
                                <enumeratedValue>
                                    <name>0</name>
                                    <description>Input (functions as an input pin)</description>
                                    <value>#0</value>
                                </enumeratedValue>
                                <enumeratedValue>
                                    <name>1</name>
                                    <description>Output (functions as an output pin)</description>
                                    <value>#1</value>
                                </enumeratedValue>
                            </enumeratedValues>
                        </field>
                        <field>
                            <name>PDR13</name>
                            <description>Pmn Direction</description>
                            <lsb>13</lsb>
                            <msb>13</msb>
                            <access>read-write</access>
                            <enumeratedValues>
                                <enumeratedValue>
                                    <name>0</name>
                                    <description>Input (functions as an input pin)</description>
                                    <value>#0</value>
                                </enumeratedValue>
                                <enumeratedValue>
                                    <name>1</name>
                                    <description>Output (functions as an output pin)</description>
                                    <value>#1</value>
                                </enumeratedValue>
                            </enumeratedValues>
                        </field>
                        <field>
                            <name>PDR14</name>
                            <description>Pmn Direction</description>
                            <lsb>14</lsb>
                            <msb>14</msb>
                            <access>read-write</access>
                            <enumeratedValues>
                                <enumeratedValue>
                                    <name>0</name>
                                    <description>Input (functions as an input pin)</description>
                                    <value>#0</value>
                                </enumeratedValue>
                                <enumeratedValue>
                                    <name>1</name>
                                    <description>Output (functions as an output pin)</description>
                                    <value>#1</value>
                                </enumeratedValue>
                            </enumeratedValues>
                        </field>
                        <field>
                            <name>PDR15</name>
                            <description>Pmn Direction</description>
                            <lsb>15</lsb>
                            <msb>15</msb>
                            <access>read-write</access>
                            <enumeratedValues>
                                <enumeratedValue>
                                    <name>0</name>
                                    <description>Input (functions as an input pin)</description>
                                    <value>#0</value>
                                </enumeratedValue>
                                <enumeratedValue>
                                    <name>1</name>
                                    <description>Output (functions as an output pin)</description>
                                    <value>#1</value>
                                </enumeratedValue>
                            </enumeratedValues>
                        </field>
                        <field>
                            <name>PODR00</name>
                            <description>Pmn Output Data</description>
                            <lsb>16</lsb>
                            <msb>16</msb>
                            <access>read-write</access>
                            <enumeratedValues>
                                <enumeratedValue>
                                    <name>0</name>
                                    <description>Low output</description>
                                    <value>#0</value>
                                </enumeratedValue>
                                <enumeratedValue>
                                    <name>1</name>
                                    <description>High output</description>
                                    <value>#1</value>
                                </enumeratedValue>
                            </enumeratedValues>
                        </field>
                        <field>
                            <name>PODR01</name>
                            <description>Pmn Output Data</description>
                            <lsb>17</lsb>
                            <msb>17</msb>
                            <access>read-write</access>
                            <enumeratedValues>
                                <enumeratedValue>
                                    <name>0</name>
                                    <description>Low output</description>
                                    <value>#0</value>
                                </enumeratedValue>
                                <enumeratedValue>
                                    <name>1</name>
                                    <description>High output</description>
                                    <value>#1</value>
                                </enumeratedValue>
                            </enumeratedValues>
                        </field>
                        <field>
                            <name>PODR02</name>
                            <description>Pmn Output Data</description>
                            <lsb>18</lsb>
                            <msb>18</msb>
                            <access>read-write</access>
                            <enumeratedValues>
                                <enumeratedValue>
                                    <name>0</name>
                                    <description>Low output</description>
                                    <value>#0</value>
                                </enumeratedValue>
                                <enumeratedValue>
                                    <name>1</name>
                                    <description>High output</description>
                                    <value>#1</value>
                                </enumeratedValue>
                            </enumeratedValues>
                        </field>
                        <field>
                            <name>PODR03</name>
                            <description>Pmn Output Data</description>
                            <lsb>19</lsb>
                            <msb>19</msb>
                            <access>read-write</access>
                            <enumeratedValues>
                                <enumeratedValue>
                                    <name>0</name>
                                    <description>Low output</description>
                                    <value>#0</value>
                                </enumeratedValue>
                                <enumeratedValue>
                                    <name>1</name>
                                    <description>High output</description>
                                    <value>#1</value>
                                </enumeratedValue>
                            </enumeratedValues>
                        </field>
                        <field>
                            <name>PODR04</name>
                            <description>Pmn Output Data</description>
                            <lsb>20</lsb>
                            <msb>20</msb>
                            <access>read-write</access>
                            <enumeratedValues>
                                <enumeratedValue>
                                    <name>0</name>
                                    <description>Low output</description>
                                    <value>#0</value>
                                </enumeratedValue>
                                <enumeratedValue>
                                    <name>1</name>
                                    <description>High output</description>
                                    <value>#1</value>
                                </enumeratedValue>
                            </enumeratedValues>
                        </field>
                        <field>
                            <name>PODR05</name>
                            <description>Pmn Output Data</description>
                            <lsb>21</lsb>
                            <msb>21</msb>
                            <access>read-write</access>
                            <enumeratedValues>
                                <enumeratedValue>
                                    <name>0</name>
                                    <description>Low output</description>
                                    <value>#0</value>
                                </enumeratedValue>
                                <enumeratedValue>
                                    <name>1</name>
                                    <description>High output</description>
                                    <value>#1</value>
                                </enumeratedValue>
                            </enumeratedValues>
                        </field>
                        <field>
                            <name>PODR06</name>
                            <description>Pmn Output Data</description>
                            <lsb>22</lsb>
                            <msb>22</msb>
                            <access>read-write</access>
                            <enumeratedValues>
                                <enumeratedValue>
                                    <name>0</name>
                                    <description>Low output</description>
                                    <value>#0</value>
                                </enumeratedValue>
                                <enumeratedValue>
                                    <name>1</name>
                                    <description>High output</description>
                                    <value>#1</value>
                                </enumeratedValue>
                            </enumeratedValues>
                        </field>
                        <field>
                            <name>PODR07</name>
                            <description>Pmn Output Data</description>
                            <lsb>23</lsb>
                            <msb>23</msb>
                            <access>read-write</access>
                            <enumeratedValues>
                                <enumeratedValue>
                                    <name>0</name>
                                    <description>Low output</description>
                                    <value>#0</value>
                                </enumeratedValue>
                                <enumeratedValue>
                                    <name>1</name>
                                    <description>High output</description>
                                    <value>#1</value>
                                </enumeratedValue>
                            </enumeratedValues>
                        </field>
                        <field>
                            <name>PODR08</name>
                            <description>Pmn Output Data</description>
                            <lsb>24</lsb>
                            <msb>24</msb>
                            <access>read-write</access>
                            <enumeratedValues>
                                <enumeratedValue>
                                    <name>0</name>
                                    <description>Low output</description>
                                    <value>#0</value>
                                </enumeratedValue>
                                <enumeratedValue>
                                    <name>1</name>
                                    <description>High output</description>
                                    <value>#1</value>
                                </enumeratedValue>
                            </enumeratedValues>
                        </field>
                        <field>
                            <name>PODR09</name>
                            <description>Pmn Output Data</description>
                            <lsb>25</lsb>
                            <msb>25</msb>
                            <access>read-write</access>
                            <enumeratedValues>
                                <enumeratedValue>
                                    <name>0</name>
                                    <description>Low output</description>
                                    <value>#0</value>
                                </enumeratedValue>
                                <enumeratedValue>
                                    <name>1</name>
                                    <description>High output</description>
                                    <value>#1</value>
                                </enumeratedValue>
                            </enumeratedValues>
                        </field>
                        <field>
                            <name>PODR10</name>
                            <description>Pmn Output Data</description>
                            <lsb>26</lsb>
                            <msb>26</msb>
                            <access>read-write</access>
                            <enumeratedValues>
                                <enumeratedValue>
                                    <name>0</name>
                                    <description>Low output</description>
                                    <value>#0</value>
                                </enumeratedValue>
                                <enumeratedValue>
                                    <name>1</name>
                                    <description>High output</description>
                                    <value>#1</value>
                                </enumeratedValue>
                            </enumeratedValues>
                        </field>
                        <field>
                            <name>PODR11</name>
                            <description>Pmn Output Data</description>
                            <lsb>27</lsb>
                            <msb>27</msb>
                            <access>read-write</access>
                            <enumeratedValues>
                                <enumeratedValue>
                                    <name>0</name>
                                    <description>Low output</description>
                                    <value>#0</value>
                                </enumeratedValue>
                                <enumeratedValue>
                                    <name>1</name>
                                    <description>High output</description>
                                    <value>#1</value>
                                </enumeratedValue>
                            </enumeratedValues>
                        </field>
                        <field>
                            <name>PODR12</name>
                            <description>Pmn Output Data</description>
                            <lsb>28</lsb>
                            <msb>28</msb>
                            <access>read-write</access>
                            <enumeratedValues>
                                <enumeratedValue>
                                    <name>0</name>
                                    <description>Low output</description>
                                    <value>#0</value>
                                </enumeratedValue>
                                <enumeratedValue>
                                    <name>1</name>
                                    <description>High output</description>
                                    <value>#1</value>
                                </enumeratedValue>
                            </enumeratedValues>
                        </field>
                        <field>
                            <name>PODR13</name>
                            <description>Pmn Output Data</description>
                            <lsb>29</lsb>
                            <msb>29</msb>
                            <access>read-write</access>
                            <enumeratedValues>
                                <enumeratedValue>
                                    <name>0</name>
                                    <description>Low output</description>
                                    <value>#0</value>
                                </enumeratedValue>
                                <enumeratedValue>
                                    <name>1</name>
                                    <description>High output</description>
                                    <value>#1</value>
                                </enumeratedValue>
                            </enumeratedValues>
                        </field>
                        <field>
                            <name>PODR14</name>
                            <description>Pmn Output Data</description>
                            <lsb>30</lsb>
                            <msb>30</msb>
                            <access>read-write</access>
                            <enumeratedValues>
                                <enumeratedValue>
                                    <name>0</name>
                                    <description>Low output</description>
                                    <value>#0</value>
                                </enumeratedValue>
                                <enumeratedValue>
                                    <name>1</name>
                                    <description>High output</description>
                                    <value>#1</value>
                                </enumeratedValue>
                            </enumeratedValues>
                        </field>
                        <field>
                            <name>PODR15</name>
                            <description>Pmn Output Data</description>
                            <lsb>31</lsb>
                            <msb>31</msb>
                            <access>read-write</access>
                            <enumeratedValues>
                                <enumeratedValue>
                                    <name>0</name>
                                    <description>Low output</description>
                                    <value>#0</value>
                                </enumeratedValue>
                                <enumeratedValue>
                                    <name>1</name>
                                    <description>High output</description>
                                    <value>#1</value>
                                </enumeratedValue>
                            </enumeratedValues>
                        </field>
                    </fields>
                </register>
                <register>
                    <name>PDR</name>
                    <description>Port Control Register 1</description>
                    <alternateRegister>PCNTR1</alternateRegister>
                    <addressOffset>0x000</addressOffset>
                    <size>16</size>
                    <access>read-write</access>
                    <resetValue>0x0000</resetValue>
                    <resetMask>0xffff</resetMask>
                    <fields>
                        <field>
                            <name>PODR00</name>
                            <description>Pmn Output Data</description>
                            <lsb>0</lsb>
                            <msb>0</msb>
                            <access>read-write</access>
                            <enumeratedValues>
                                <enumeratedValue>
                                    <name>0</name>
                                    <description>Low output</description>
                                    <value>#0</value>
                                </enumeratedValue>
                                <enumeratedValue>
                                    <name>1</name>
                                    <description>High output</description>
                                    <value>#1</value>
                                </enumeratedValue>
                            </enumeratedValues>
                        </field>
                        <field>
                            <name>PODR01</name>
                            <description>Pmn Output Data</description>
                            <lsb>1</lsb>
                            <msb>1</msb>
                            <access>read-write</access>
                            <enumeratedValues>
                                <enumeratedValue>
                                    <name>0</name>
                                    <description>Low output</description>
                                    <value>#0</value>
                                </enumeratedValue>
                                <enumeratedValue>
                                    <name>1</name>
                                    <description>High output</description>
                                    <value>#1</value>
                                </enumeratedValue>
                            </enumeratedValues>
                        </field>
                        <field>
                            <name>PODR02</name>
                            <description>Pmn Output Data</description>
                            <lsb>2</lsb>
                            <msb>2</msb>
                            <access>read-write</access>
                            <enumeratedValues>
                                <enumeratedValue>
                                    <name>0</name>
                                    <description>Low output</description>
                                    <value>#0</value>
                                </enumeratedValue>
                                <enumeratedValue>
                                    <name>1</name>
                                    <description>High output</description>
                                    <value>#1</value>
                                </enumeratedValue>
                            </enumeratedValues>
                        </field>
                        <field>
                            <name>PODR03</name>
                            <description>Pmn Output Data</description>
                            <lsb>3</lsb>
                            <msb>3</msb>
                            <access>read-write</access>
                            <enumeratedValues>
                                <enumeratedValue>
                                    <name>0</name>
                                    <description>Low output</description>
                                    <value>#0</value>
                                </enumeratedValue>
                                <enumeratedValue>
                                    <name>1</name>
                                    <description>High output</description>
                                    <value>#1</value>
                                </enumeratedValue>
                            </enumeratedValues>
                        </field>
                        <field>
                            <name>PODR04</name>
                            <description>Pmn Output Data</description>
                            <lsb>4</lsb>
                            <msb>4</msb>
                            <access>read-write</access>
                            <enumeratedValues>
                                <enumeratedValue>
                                    <name>0</name>
                                    <description>Low output</description>
                                    <value>#0</value>
                                </enumeratedValue>
                                <enumeratedValue>
                                    <name>1</name>
                                    <description>High output</description>
                                    <value>#1</value>
                                </enumeratedValue>
                            </enumeratedValues>
                        </field>
                        <field>
                            <name>PODR05</name>
                            <description>Pmn Output Data</description>
                            <lsb>5</lsb>
                            <msb>5</msb>
                            <access>read-write</access>
                            <enumeratedValues>
                                <enumeratedValue>
                                    <name>0</name>
                                    <description>Low output</description>
                                    <value>#0</value>
                                </enumeratedValue>
                                <enumeratedValue>
                                    <name>1</name>
                                    <description>High output</description>
                                    <value>#1</value>
                                </enumeratedValue>
                            </enumeratedValues>
                        </field>
                        <field>
                            <name>PODR06</name>
                            <description>Pmn Output Data</description>
                            <lsb>6</lsb>
                            <msb>6</msb>
                            <access>read-write</access>
                            <enumeratedValues>
                                <enumeratedValue>
                                    <name>0</name>
                                    <description>Low output</description>
                                    <value>#0</value>
                                </enumeratedValue>
                                <enumeratedValue>
                                    <name>1</name>
                                    <description>High output</description>
                                    <value>#1</value>
                                </enumeratedValue>
                            </enumeratedValues>
                        </field>
                        <field>
                            <name>PODR07</name>
                            <description>Pmn Output Data</description>
                            <lsb>7</lsb>
                            <msb>7</msb>
                            <access>read-write</access>
                            <enumeratedValues>
                                <enumeratedValue>
                                    <name>0</name>
                                    <description>Low output</description>
                                    <value>#0</value>
                                </enumeratedValue>
                                <enumeratedValue>
                                    <name>1</name>
                                    <description>High output</description>
                                    <value>#1</value>
                                </enumeratedValue>
                            </enumeratedValues>
                        </field>
                        <field>
                            <name>PODR08</name>
                            <description>Pmn Output Data</description>
                            <lsb>8</lsb>
                            <msb>8</msb>
                            <access>read-write</access>
                            <enumeratedValues>
                                <enumeratedValue>
                                    <name>0</name>
                                    <description>Low output</description>
                                    <value>#0</value>
                                </enumeratedValue>
                                <enumeratedValue>
                                    <name>1</name>
                                    <description>High output</description>
                                    <value>#1</value>
                                </enumeratedValue>
                            </enumeratedValues>
                        </field>
                        <field>
                            <name>PODR09</name>
                            <description>Pmn Output Data</description>
                            <lsb>9</lsb>
                            <msb>9</msb>
                            <access>read-write</access>
                            <enumeratedValues>
                                <enumeratedValue>
                                    <name>0</name>
                                    <description>Low output</description>
                                    <value>#0</value>
                                </enumeratedValue>
                                <enumeratedValue>
                                    <name>1</name>
                                    <description>High output</description>
                                    <value>#1</value>
                                </enumeratedValue>
                            </enumeratedValues>
                        </field>
                        <field>
                            <name>PODR10</name>
                            <description>Pmn Output Data</description>
                            <lsb>10</lsb>
                            <msb>10</msb>
                            <access>read-write</access>
                            <enumeratedValues>
                                <enumeratedValue>
                                    <name>0</name>
                                    <description>Low output</description>
                                    <value>#0</value>
                                </enumeratedValue>
                                <enumeratedValue>
                                    <name>1</name>
                                    <description>High output</description>
                                    <value>#1</value>
                                </enumeratedValue>
                            </enumeratedValues>
                        </field>
                        <field>
                            <name>PODR11</name>
                            <description>Pmn Output Data</description>
                            <lsb>11</lsb>
                            <msb>11</msb>
                            <access>read-write</access>
                            <enumeratedValues>
                                <enumeratedValue>
                                    <name>0</name>
                                    <description>Low output</description>
                                    <value>#0</value>
                                </enumeratedValue>
                                <enumeratedValue>
                                    <name>1</name>
                                    <description>High output</description>
                                    <value>#1</value>
                                </enumeratedValue>
                            </enumeratedValues>
                        </field>
                        <field>
                            <name>PODR12</name>
                            <description>Pmn Output Data</description>
                            <lsb>12</lsb>
                            <msb>12</msb>
                            <access>read-write</access>
                            <enumeratedValues>
                                <enumeratedValue>
                                    <name>0</name>
                                    <description>Low output</description>
                                    <value>#0</value>
                                </enumeratedValue>
                                <enumeratedValue>
                                    <name>1</name>
                                    <description>High output</description>
                                    <value>#1</value>
                                </enumeratedValue>
                            </enumeratedValues>
                        </field>
                        <field>
                            <name>PODR13</name>
                            <description>Pmn Output Data</description>
                            <lsb>13</lsb>
                            <msb>13</msb>
                            <access>read-write</access>
                            <enumeratedValues>
                                <enumeratedValue>
                                    <name>0</name>
                                    <description>Low output</description>
                                    <value>#0</value>
                                </enumeratedValue>
                                <enumeratedValue>
                                    <name>1</name>
                                    <description>High output</description>
                                    <value>#1</value>
                                </enumeratedValue>
                            </enumeratedValues>
                        </field>
                        <field>
                            <name>PODR14</name>
                            <description>Pmn Output Data</description>
                            <lsb>14</lsb>
                            <msb>14</msb>
                            <access>read-write</access>
                            <enumeratedValues>
                                <enumeratedValue>
                                    <name>0</name>
                                    <description>Low output</description>
                                    <value>#0</value>
                                </enumeratedValue>
                                <enumeratedValue>
                                    <name>1</name>
                                    <description>High output</description>
                                    <value>#1</value>
                                </enumeratedValue>
                            </enumeratedValues>
                        </field>
                        <field>
                            <name>PODR15</name>
                            <description>Pmn Output Data</description>
                            <lsb>15</lsb>
                            <msb>15</msb>
                            <access>read-write</access>
                            <enumeratedValues>
                                <enumeratedValue>
                                    <name>0</name>
                                    <description>Low output</description>
                                    <value>#0</value>
                                </enumeratedValue>
                                <enumeratedValue>
                                    <name>1</name>
                                    <description>High output</description>
                                    <value>#1</value>
                                </enumeratedValue>
                            </enumeratedValues>
                        </field>
                    </fields>
                </register>
                <register>
                    <name>PODR</name>
                    <description>Port Control Register 1</description>
                    <alternateRegister>PCNTR1</alternateRegister>
                    <addressOffset>0x002</addressOffset>
                    <size>16</size>
                    <access>read-write</access>
                    <resetValue>0x0000</resetValue>
                    <resetMask>0xffff</resetMask>
                    <fields>
                        <field>
                            <name>PDR00</name>
                            <description>Pmn Direction</description>
                            <lsb>0</lsb>
                            <msb>0</msb>
                            <access>read-write</access>
                            <enumeratedValues>
                                <enumeratedValue>
                                    <name>0</name>
                                    <description>Input (functions as an input pin)</description>
                                    <value>#0</value>
                                </enumeratedValue>
                                <enumeratedValue>
                                    <name>1</name>
                                    <description>Output (functions as an output pin)</description>
                                    <value>#1</value>
                                </enumeratedValue>
                            </enumeratedValues>
                        </field>
                        <field>
                            <name>PDR01</name>
                            <description>Pmn Direction</description>
                            <lsb>1</lsb>
                            <msb>1</msb>
                            <access>read-write</access>
                            <enumeratedValues>
                                <enumeratedValue>
                                    <name>0</name>
                                    <description>Input (functions as an input pin)</description>
                                    <value>#0</value>
                                </enumeratedValue>
                                <enumeratedValue>
                                    <name>1</name>
                                    <description>Output (functions as an output pin)</description>
                                    <value>#1</value>
                                </enumeratedValue>
                            </enumeratedValues>
                        </field>
                        <field>
                            <name>PDR02</name>
                            <description>Pmn Direction</description>
                            <lsb>2</lsb>
                            <msb>2</msb>
                            <access>read-write</access>
                            <enumeratedValues>
                                <enumeratedValue>
                                    <name>0</name>
                                    <description>Input (functions as an input pin)</description>
                                    <value>#0</value>
                                </enumeratedValue>
                                <enumeratedValue>
                                    <name>1</name>
                                    <description>Output (functions as an output pin)</description>
                                    <value>#1</value>
                                </enumeratedValue>
                            </enumeratedValues>
                        </field>
                        <field>
                            <name>PDR03</name>
                            <description>Pmn Direction</description>
                            <lsb>3</lsb>
                            <msb>3</msb>
                            <access>read-write</access>
                            <enumeratedValues>
                                <enumeratedValue>
                                    <name>0</name>
                                    <description>Input (functions as an input pin)</description>
                                    <value>#0</value>
                                </enumeratedValue>
                                <enumeratedValue>
                                    <name>1</name>
                                    <description>Output (functions as an output pin)</description>
                                    <value>#1</value>
                                </enumeratedValue>
                            </enumeratedValues>
                        </field>
                        <field>
                            <name>PDR04</name>
                            <description>Pmn Direction</description>
                            <lsb>4</lsb>
                            <msb>4</msb>
                            <access>read-write</access>
                            <enumeratedValues>
                                <enumeratedValue>
                                    <name>0</name>
                                    <description>Input (functions as an input pin)</description>
                                    <value>#0</value>
                                </enumeratedValue>
                                <enumeratedValue>
                                    <name>1</name>
                                    <description>Output (functions as an output pin)</description>
                                    <value>#1</value>
                                </enumeratedValue>
                            </enumeratedValues>
                        </field>
                        <field>
                            <name>PDR05</name>
                            <description>Pmn Direction</description>
                            <lsb>5</lsb>
                            <msb>5</msb>
                            <access>read-write</access>
                            <enumeratedValues>
                                <enumeratedValue>
                                    <name>0</name>
                                    <description>Input (functions as an input pin)</description>
                                    <value>#0</value>
                                </enumeratedValue>
                                <enumeratedValue>
                                    <name>1</name>
                                    <description>Output (functions as an output pin)</description>
                                    <value>#1</value>
                                </enumeratedValue>
                            </enumeratedValues>
                        </field>
                        <field>
                            <name>PDR06</name>
                            <description>Pmn Direction</description>
                            <lsb>6</lsb>
                            <msb>6</msb>
                            <access>read-write</access>
                            <enumeratedValues>
                                <enumeratedValue>
                                    <name>0</name>
                                    <description>Input (functions as an input pin)</description>
                                    <value>#0</value>
                                </enumeratedValue>
                                <enumeratedValue>
                                    <name>1</name>
                                    <description>Output (functions as an output pin)</description>
                                    <value>#1</value>
                                </enumeratedValue>
                            </enumeratedValues>
                        </field>
                        <field>
                            <name>PDR07</name>
                            <description>Pmn Direction</description>
                            <lsb>7</lsb>
                            <msb>7</msb>
                            <access>read-write</access>
                            <enumeratedValues>
                                <enumeratedValue>
                                    <name>0</name>
                                    <description>Input (functions as an input pin)</description>
                                    <value>#0</value>
                                </enumeratedValue>
                                <enumeratedValue>
                                    <name>1</name>
                                    <description>Output (functions as an output pin)</description>
                                    <value>#1</value>
                                </enumeratedValue>
                            </enumeratedValues>
                        </field>
                        <field>
                            <name>PDR08</name>
                            <description>Pmn Direction</description>
                            <lsb>8</lsb>
                            <msb>8</msb>
                            <access>read-write</access>
                            <enumeratedValues>
                                <enumeratedValue>
                                    <name>0</name>
                                    <description>Input (functions as an input pin)</description>
                                    <value>#0</value>
                                </enumeratedValue>
                                <enumeratedValue>
                                    <name>1</name>
                                    <description>Output (functions as an output pin)</description>
                                    <value>#1</value>
                                </enumeratedValue>
                            </enumeratedValues>
                        </field>
                        <field>
                            <name>PDR09</name>
                            <description>Pmn Direction</description>
                            <lsb>9</lsb>
                            <msb>9</msb>
                            <access>read-write</access>
                            <enumeratedValues>
                                <enumeratedValue>
                                    <name>0</name>
                                    <description>Input (functions as an input pin)</description>
                                    <value>#0</value>
                                </enumeratedValue>
                                <enumeratedValue>
                                    <name>1</name>
                                    <description>Output (functions as an output pin)</description>
                                    <value>#1</value>
                                </enumeratedValue>
                            </enumeratedValues>
                        </field>
                        <field>
                            <name>PDR10</name>
                            <description>Pmn Direction</description>
                            <lsb>10</lsb>
                            <msb>10</msb>
                            <access>read-write</access>
                            <enumeratedValues>
                                <enumeratedValue>
                                    <name>0</name>
                                    <description>Input (functions as an input pin)</description>
                                    <value>#0</value>
                                </enumeratedValue>
                                <enumeratedValue>
                                    <name>1</name>
                                    <description>Output (functions as an output pin)</description>
                                    <value>#1</value>
                                </enumeratedValue>
                            </enumeratedValues>
                        </field>
                        <field>
                            <name>PDR11</name>
                            <description>Pmn Direction</description>
                            <lsb>11</lsb>
                            <msb>11</msb>
                            <access>read-write</access>
                            <enumeratedValues>
                                <enumeratedValue>
                                    <name>0</name>
                                    <description>Input (functions as an input pin)</description>
                                    <value>#0</value>
                                </enumeratedValue>
                                <enumeratedValue>
                                    <name>1</name>
                                    <description>Output (functions as an output pin)</description>
                                    <value>#1</value>
                                </enumeratedValue>
                            </enumeratedValues>
                        </field>
                        <field>
                            <name>PDR12</name>
                            <description>Pmn Direction</description>
                            <lsb>12</lsb>
                            <msb>12</msb>
                            <access>read-write</access>
                            <enumeratedValues>
                                <enumeratedValue>
                                    <name>0</name>
                                    <description>Input (functions as an input pin)</description>
                                    <value>#0</value>
                                </enumeratedValue>
                                <enumeratedValue>
                                    <name>1</name>
                                    <description>Output (functions as an output pin)</description>
                                    <value>#1</value>
                                </enumeratedValue>
                            </enumeratedValues>
                        </field>
                        <field>
                            <name>PDR13</name>
                            <description>Pmn Direction</description>
                            <lsb>13</lsb>
                            <msb>13</msb>
                            <access>read-write</access>
                            <enumeratedValues>
                                <enumeratedValue>
                                    <name>0</name>
                                    <description>Input (functions as an input pin)</description>
                                    <value>#0</value>
                                </enumeratedValue>
                                <enumeratedValue>
                                    <name>1</name>
                                    <description>Output (functions as an output pin)</description>
                                    <value>#1</value>
                                </enumeratedValue>
                            </enumeratedValues>
                        </field>
                        <field>
                            <name>PDR14</name>
                            <description>Pmn Direction</description>
                            <lsb>14</lsb>
                            <msb>14</msb>
                            <access>read-write</access>
                            <enumeratedValues>
                                <enumeratedValue>
                                    <name>0</name>
                                    <description>Input (functions as an input pin)</description>
                                    <value>#0</value>
                                </enumeratedValue>
                                <enumeratedValue>
                                    <name>1</name>
                                    <description>Output (functions as an output pin)</description>
                                    <value>#1</value>
                                </enumeratedValue>
                            </enumeratedValues>
                        </field>
                        <field>
                            <name>PDR15</name>
                            <description>Pmn Direction</description>
                            <lsb>15</lsb>
                            <msb>15</msb>
                            <access>read-write</access>
                            <enumeratedValues>
                                <enumeratedValue>
                                    <name>0</name>
                                    <description>Input (functions as an input pin)</description>
                                    <value>#0</value>
                                </enumeratedValue>
                                <enumeratedValue>
                                    <name>1</name>
                                    <description>Output (functions as an output pin)</description>
                                    <value>#1</value>
                                </enumeratedValue>
                            </enumeratedValues>
                        </field>
                    </fields>
                </register>
                <register>
                    <name>PCNTR2</name>
                    <description>Port Control Register 2</description>
                    <addressOffset>0x004</addressOffset>
                    <size>32</size>
                    <access>read-only</access>
                    <resetValue>0x00000000</resetValue>
                    <resetMask>0xffff0000</resetMask>
                    <fields>
                        <field>
                            <name>PIDR00</name>
                            <description>Pmn State</description>
                            <lsb>0</lsb>
                            <msb>0</msb>
                            <access>read-only</access>
                            <enumeratedValues>
                                <enumeratedValue>
                                    <name>0</name>
                                    <description>Low level</description>
                                    <value>#0</value>
                                </enumeratedValue>
                                <enumeratedValue>
                                    <name>1</name>
                                    <description>High level</description>
                                    <value>#1</value>
                                </enumeratedValue>
                            </enumeratedValues>
                        </field>
                        <field>
                            <name>PIDR01</name>
                            <description>Pmn State</description>
                            <lsb>1</lsb>
                            <msb>1</msb>
                            <access>read-only</access>
                            <enumeratedValues>
                                <enumeratedValue>
                                    <name>0</name>
                                    <description>Low level</description>
                                    <value>#0</value>
                                </enumeratedValue>
                                <enumeratedValue>
                                    <name>1</name>
                                    <description>High level</description>
                                    <value>#1</value>
                                </enumeratedValue>
                            </enumeratedValues>
                        </field>
                        <field>
                            <name>PIDR02</name>
                            <description>Pmn State</description>
                            <lsb>2</lsb>
                            <msb>2</msb>
                            <access>read-only</access>
                            <enumeratedValues>
                                <enumeratedValue>
                                    <name>0</name>
                                    <description>Low level</description>
                                    <value>#0</value>
                                </enumeratedValue>
                                <enumeratedValue>
                                    <name>1</name>
                                    <description>High level</description>
                                    <value>#1</value>
                                </enumeratedValue>
                            </enumeratedValues>
                        </field>
                        <field>
                            <name>PIDR03</name>
                            <description>Pmn State</description>
                            <lsb>3</lsb>
                            <msb>3</msb>
                            <access>read-only</access>
                            <enumeratedValues>
                                <enumeratedValue>
                                    <name>0</name>
                                    <description>Low level</description>
                                    <value>#0</value>
                                </enumeratedValue>
                                <enumeratedValue>
                                    <name>1</name>
                                    <description>High level</description>
                                    <value>#1</value>
                                </enumeratedValue>
                            </enumeratedValues>
                        </field>
                        <field>
                            <name>PIDR04</name>
                            <description>Pmn State</description>
                            <lsb>4</lsb>
                            <msb>4</msb>
                            <access>read-only</access>
                            <enumeratedValues>
                                <enumeratedValue>
                                    <name>0</name>
                                    <description>Low level</description>
                                    <value>#0</value>
                                </enumeratedValue>
                                <enumeratedValue>
                                    <name>1</name>
                                    <description>High level</description>
                                    <value>#1</value>
                                </enumeratedValue>
                            </enumeratedValues>
                        </field>
                        <field>
                            <name>PIDR05</name>
                            <description>Pmn State</description>
                            <lsb>5</lsb>
                            <msb>5</msb>
                            <access>read-only</access>
                            <enumeratedValues>
                                <enumeratedValue>
                                    <name>0</name>
                                    <description>Low level</description>
                                    <value>#0</value>
                                </enumeratedValue>
                                <enumeratedValue>
                                    <name>1</name>
                                    <description>High level</description>
                                    <value>#1</value>
                                </enumeratedValue>
                            </enumeratedValues>
                        </field>
                        <field>
                            <name>PIDR06</name>
                            <description>Pmn State</description>
                            <lsb>6</lsb>
                            <msb>6</msb>
                            <access>read-only</access>
                            <enumeratedValues>
                                <enumeratedValue>
                                    <name>0</name>
                                    <description>Low level</description>
                                    <value>#0</value>
                                </enumeratedValue>
                                <enumeratedValue>
                                    <name>1</name>
                                    <description>High level</description>
                                    <value>#1</value>
                                </enumeratedValue>
                            </enumeratedValues>
                        </field>
                        <field>
                            <name>PIDR07</name>
                            <description>Pmn State</description>
                            <lsb>7</lsb>
                            <msb>7</msb>
                            <access>read-only</access>
                            <enumeratedValues>
                                <enumeratedValue>
                                    <name>0</name>
                                    <description>Low level</description>
                                    <value>#0</value>
                                </enumeratedValue>
                                <enumeratedValue>
                                    <name>1</name>
                                    <description>High level</description>
                                    <value>#1</value>
                                </enumeratedValue>
                            </enumeratedValues>
                        </field>
                        <field>
                            <name>PIDR08</name>
                            <description>Pmn State</description>
                            <lsb>8</lsb>
                            <msb>8</msb>
                            <access>read-only</access>
                            <enumeratedValues>
                                <enumeratedValue>
                                    <name>0</name>
                                    <description>Low level</description>
                                    <value>#0</value>
                                </enumeratedValue>
                                <enumeratedValue>
                                    <name>1</name>
                                    <description>High level</description>
                                    <value>#1</value>
                                </enumeratedValue>
                            </enumeratedValues>
                        </field>
                        <field>
                            <name>PIDR09</name>
                            <description>Pmn State</description>
                            <lsb>9</lsb>
                            <msb>9</msb>
                            <access>read-only</access>
                            <enumeratedValues>
                                <enumeratedValue>
                                    <name>0</name>
                                    <description>Low level</description>
                                    <value>#0</value>
                                </enumeratedValue>
                                <enumeratedValue>
                                    <name>1</name>
                                    <description>High level</description>
                                    <value>#1</value>
                                </enumeratedValue>
                            </enumeratedValues>
                        </field>
                        <field>
                            <name>PIDR10</name>
                            <description>Pmn State</description>
                            <lsb>10</lsb>
                            <msb>10</msb>
                            <access>read-only</access>
                            <enumeratedValues>
                                <enumeratedValue>
                                    <name>0</name>
                                    <description>Low level</description>
                                    <value>#0</value>
                                </enumeratedValue>
                                <enumeratedValue>
                                    <name>1</name>
                                    <description>High level</description>
                                    <value>#1</value>
                                </enumeratedValue>
                            </enumeratedValues>
                        </field>
                        <field>
                            <name>PIDR11</name>
                            <description>Pmn State</description>
                            <lsb>11</lsb>
                            <msb>11</msb>
                            <access>read-only</access>
                            <enumeratedValues>
                                <enumeratedValue>
                                    <name>0</name>
                                    <description>Low level</description>
                                    <value>#0</value>
                                </enumeratedValue>
                                <enumeratedValue>
                                    <name>1</name>
                                    <description>High level</description>
                                    <value>#1</value>
                                </enumeratedValue>
                            </enumeratedValues>
                        </field>
                        <field>
                            <name>PIDR12</name>
                            <description>Pmn State</description>
                            <lsb>12</lsb>
                            <msb>12</msb>
                            <access>read-only</access>
                            <enumeratedValues>
                                <enumeratedValue>
                                    <name>0</name>
                                    <description>Low level</description>
                                    <value>#0</value>
                                </enumeratedValue>
                                <enumeratedValue>
                                    <name>1</name>
                                    <description>High level</description>
                                    <value>#1</value>
                                </enumeratedValue>
                            </enumeratedValues>
                        </field>
                        <field>
                            <name>PIDR13</name>
                            <description>Pmn State</description>
                            <lsb>13</lsb>
                            <msb>13</msb>
                            <access>read-only</access>
                            <enumeratedValues>
                                <enumeratedValue>
                                    <name>0</name>
                                    <description>Low level</description>
                                    <value>#0</value>
                                </enumeratedValue>
                                <enumeratedValue>
                                    <name>1</name>
                                    <description>High level</description>
                                    <value>#1</value>
                                </enumeratedValue>
                            </enumeratedValues>
                        </field>
                        <field>
                            <name>PIDR14</name>
                            <description>Pmn State</description>
                            <lsb>14</lsb>
                            <msb>14</msb>
                            <access>read-only</access>
                            <enumeratedValues>
                                <enumeratedValue>
                                    <name>0</name>
                                    <description>Low level</description>
                                    <value>#0</value>
                                </enumeratedValue>
                                <enumeratedValue>
                                    <name>1</name>
                                    <description>High level</description>
                                    <value>#1</value>
                                </enumeratedValue>
                            </enumeratedValues>
                        </field>
                        <field>
                            <name>PIDR15</name>
                            <description>Pmn State</description>
                            <lsb>15</lsb>
                            <msb>15</msb>
                            <access>read-only</access>
                            <enumeratedValues>
                                <enumeratedValue>
                                    <name>0</name>
                                    <description>Low level</description>
                                    <value>#0</value>
                                </enumeratedValue>
                                <enumeratedValue>
                                    <name>1</name>
                                    <description>High level</description>
                                    <value>#1</value>
                                </enumeratedValue>
                            </enumeratedValues>
                        </field>
                        <field>
                            <name>EIDR00</name>
                            <description>Port Event Input Data</description>
                            <lsb>16</lsb>
                            <msb>16</msb>
                            <access>read-only</access>
                            <enumeratedValues>
                                <enumeratedValue>
                                    <name>0</name>
                                    <description>Low input</description>
                                    <value>#0</value>
                                </enumeratedValue>
                                <enumeratedValue>
                                    <name>1</name>
                                    <description>High input</description>
                                    <value>#1</value>
                                </enumeratedValue>
                            </enumeratedValues>
                        </field>
                        <field>
                            <name>EIDR01</name>
                            <description>Port Event Input Data</description>
                            <lsb>17</lsb>
                            <msb>17</msb>
                            <access>read-only</access>
                            <enumeratedValues>
                                <enumeratedValue>
                                    <name>0</name>
                                    <description>Low input</description>
                                    <value>#0</value>
                                </enumeratedValue>
                                <enumeratedValue>
                                    <name>1</name>
                                    <description>High input</description>
                                    <value>#1</value>
                                </enumeratedValue>
                            </enumeratedValues>
                        </field>
                        <field>
                            <name>EIDR02</name>
                            <description>Port Event Input Data</description>
                            <lsb>18</lsb>
                            <msb>18</msb>
                            <access>read-only</access>
                            <enumeratedValues>
                                <enumeratedValue>
                                    <name>0</name>
                                    <description>Low input</description>
                                    <value>#0</value>
                                </enumeratedValue>
                                <enumeratedValue>
                                    <name>1</name>
                                    <description>High input</description>
                                    <value>#1</value>
                                </enumeratedValue>
                            </enumeratedValues>
                        </field>
                        <field>
                            <name>EIDR03</name>
                            <description>Port Event Input Data</description>
                            <lsb>19</lsb>
                            <msb>19</msb>
                            <access>read-only</access>
                            <enumeratedValues>
                                <enumeratedValue>
                                    <name>0</name>
                                    <description>Low input</description>
                                    <value>#0</value>
                                </enumeratedValue>
                                <enumeratedValue>
                                    <name>1</name>
                                    <description>High input</description>
                                    <value>#1</value>
                                </enumeratedValue>
                            </enumeratedValues>
                        </field>
                        <field>
                            <name>EIDR04</name>
                            <description>Port Event Input Data</description>
                            <lsb>20</lsb>
                            <msb>20</msb>
                            <access>read-only</access>
                            <enumeratedValues>
                                <enumeratedValue>
                                    <name>0</name>
                                    <description>Low input</description>
                                    <value>#0</value>
                                </enumeratedValue>
                                <enumeratedValue>
                                    <name>1</name>
                                    <description>High input</description>
                                    <value>#1</value>
                                </enumeratedValue>
                            </enumeratedValues>
                        </field>
                        <field>
                            <name>EIDR05</name>
                            <description>Port Event Input Data</description>
                            <lsb>21</lsb>
                            <msb>21</msb>
                            <access>read-only</access>
                            <enumeratedValues>
                                <enumeratedValue>
                                    <name>0</name>
                                    <description>Low input</description>
                                    <value>#0</value>
                                </enumeratedValue>
                                <enumeratedValue>
                                    <name>1</name>
                                    <description>High input</description>
                                    <value>#1</value>
                                </enumeratedValue>
                            </enumeratedValues>
                        </field>
                        <field>
                            <name>EIDR06</name>
                            <description>Port Event Input Data</description>
                            <lsb>22</lsb>
                            <msb>22</msb>
                            <access>read-only</access>
                            <enumeratedValues>
                                <enumeratedValue>
                                    <name>0</name>
                                    <description>Low input</description>
                                    <value>#0</value>
                                </enumeratedValue>
                                <enumeratedValue>
                                    <name>1</name>
                                    <description>High input</description>
                                    <value>#1</value>
                                </enumeratedValue>
                            </enumeratedValues>
                        </field>
                        <field>
                            <name>EIDR07</name>
                            <description>Port Event Input Data</description>
                            <lsb>23</lsb>
                            <msb>23</msb>
                            <access>read-only</access>
                            <enumeratedValues>
                                <enumeratedValue>
                                    <name>0</name>
                                    <description>Low input</description>
                                    <value>#0</value>
                                </enumeratedValue>
                                <enumeratedValue>
                                    <name>1</name>
                                    <description>High input</description>
                                    <value>#1</value>
                                </enumeratedValue>
                            </enumeratedValues>
                        </field>
                        <field>
                            <name>EIDR08</name>
                            <description>Port Event Input Data</description>
                            <lsb>24</lsb>
                            <msb>24</msb>
                            <access>read-only</access>
                            <enumeratedValues>
                                <enumeratedValue>
                                    <name>0</name>
                                    <description>Low input</description>
                                    <value>#0</value>
                                </enumeratedValue>
                                <enumeratedValue>
                                    <name>1</name>
                                    <description>High input</description>
                                    <value>#1</value>
                                </enumeratedValue>
                            </enumeratedValues>
                        </field>
                        <field>
                            <name>EIDR09</name>
                            <description>Port Event Input Data</description>
                            <lsb>25</lsb>
                            <msb>25</msb>
                            <access>read-only</access>
                            <enumeratedValues>
                                <enumeratedValue>
                                    <name>0</name>
                                    <description>Low input</description>
                                    <value>#0</value>
                                </enumeratedValue>
                                <enumeratedValue>
                                    <name>1</name>
                                    <description>High input</description>
                                    <value>#1</value>
                                </enumeratedValue>
                            </enumeratedValues>
                        </field>
                        <field>
                            <name>EIDR10</name>
                            <description>Port Event Input Data</description>
                            <lsb>26</lsb>
                            <msb>26</msb>
                            <access>read-only</access>
                            <enumeratedValues>
                                <enumeratedValue>
                                    <name>0</name>
                                    <description>Low input</description>
                                    <value>#0</value>
                                </enumeratedValue>
                                <enumeratedValue>
                                    <name>1</name>
                                    <description>High input</description>
                                    <value>#1</value>
                                </enumeratedValue>
                            </enumeratedValues>
                        </field>
                        <field>
                            <name>EIDR11</name>
                            <description>Port Event Input Data</description>
                            <lsb>27</lsb>
                            <msb>27</msb>
                            <access>read-only</access>
                            <enumeratedValues>
                                <enumeratedValue>
                                    <name>0</name>
                                    <description>Low input</description>
                                    <value>#0</value>
                                </enumeratedValue>
                                <enumeratedValue>
                                    <name>1</name>
                                    <description>High input</description>
                                    <value>#1</value>
                                </enumeratedValue>
                            </enumeratedValues>
                        </field>
                        <field>
                            <name>EIDR12</name>
                            <description>Port Event Input Data</description>
                            <lsb>28</lsb>
                            <msb>28</msb>
                            <access>read-only</access>
                            <enumeratedValues>
                                <enumeratedValue>
                                    <name>0</name>
                                    <description>Low input</description>
                                    <value>#0</value>
                                </enumeratedValue>
                                <enumeratedValue>
                                    <name>1</name>
                                    <description>High input</description>
                                    <value>#1</value>
                                </enumeratedValue>
                            </enumeratedValues>
                        </field>
                        <field>
                            <name>EIDR13</name>
                            <description>Port Event Input Data</description>
                            <lsb>29</lsb>
                            <msb>29</msb>
                            <access>read-only</access>
                            <enumeratedValues>
                                <enumeratedValue>
                                    <name>0</name>
                                    <description>Low input</description>
                                    <value>#0</value>
                                </enumeratedValue>
                                <enumeratedValue>
                                    <name>1</name>
                                    <description>High input</description>
                                    <value>#1</value>
                                </enumeratedValue>
                            </enumeratedValues>
                        </field>
                        <field>
                            <name>EIDR14</name>
                            <description>Port Event Input Data</description>
                            <lsb>30</lsb>
                            <msb>30</msb>
                            <access>read-only</access>
                            <enumeratedValues>
                                <enumeratedValue>
                                    <name>0</name>
                                    <description>Low input</description>
                                    <value>#0</value>
                                </enumeratedValue>
                                <enumeratedValue>
                                    <name>1</name>
                                    <description>High input</description>
                                    <value>#1</value>
                                </enumeratedValue>
                            </enumeratedValues>
                        </field>
                        <field>
                            <name>EIDR15</name>
                            <description>Port Event Input Data</description>
                            <lsb>31</lsb>
                            <msb>31</msb>
                            <access>read-only</access>
                            <enumeratedValues>
                                <enumeratedValue>
                                    <name>0</name>
                                    <description>Low input</description>
                                    <value>#0</value>
                                </enumeratedValue>
                                <enumeratedValue>
                                    <name>1</name>
                                    <description>High input</description>
                                    <value>#1</value>
                                </enumeratedValue>
                            </enumeratedValues>
                        </field>
                    </fields>
                </register>
                <register>
                    <name>PIDR</name>
                    <description>Port Control Register 2</description>
                    <alternateRegister>PCNTR2</alternateRegister>
                    <addressOffset>0x004</addressOffset>
                    <size>16</size>
                    <access>read-only</access>
                    <resetValue>0x0000</resetValue>
                    <resetMask>0xffff</resetMask>
                    <fields>
                        <field>
                            <name>EIDR00</name>
                            <description>Port Event Input Data</description>
                            <lsb>0</lsb>
                            <msb>0</msb>
                            <access>read-only</access>
                            <enumeratedValues>
                                <enumeratedValue>
                                    <name>0</name>
                                    <description>Low input</description>
                                    <value>#0</value>
                                </enumeratedValue>
                                <enumeratedValue>
                                    <name>1</name>
                                    <description>High input</description>
                                    <value>#1</value>
                                </enumeratedValue>
                            </enumeratedValues>
                        </field>
                        <field>
                            <name>EIDR01</name>
                            <description>Port Event Input Data</description>
                            <lsb>1</lsb>
                            <msb>1</msb>
                            <access>read-only</access>
                            <enumeratedValues>
                                <enumeratedValue>
                                    <name>0</name>
                                    <description>Low input</description>
                                    <value>#0</value>
                                </enumeratedValue>
                                <enumeratedValue>
                                    <name>1</name>
                                    <description>High input</description>
                                    <value>#1</value>
                                </enumeratedValue>
                            </enumeratedValues>
                        </field>
                        <field>
                            <name>EIDR02</name>
                            <description>Port Event Input Data</description>
                            <lsb>2</lsb>
                            <msb>2</msb>
                            <access>read-only</access>
                            <enumeratedValues>
                                <enumeratedValue>
                                    <name>0</name>
                                    <description>Low input</description>
                                    <value>#0</value>
                                </enumeratedValue>
                                <enumeratedValue>
                                    <name>1</name>
                                    <description>High input</description>
                                    <value>#1</value>
                                </enumeratedValue>
                            </enumeratedValues>
                        </field>
                        <field>
                            <name>EIDR03</name>
                            <description>Port Event Input Data</description>
                            <lsb>3</lsb>
                            <msb>3</msb>
                            <access>read-only</access>
                            <enumeratedValues>
                                <enumeratedValue>
                                    <name>0</name>
                                    <description>Low input</description>
                                    <value>#0</value>
                                </enumeratedValue>
                                <enumeratedValue>
                                    <name>1</name>
                                    <description>High input</description>
                                    <value>#1</value>
                                </enumeratedValue>
                            </enumeratedValues>
                        </field>
                        <field>
                            <name>EIDR04</name>
                            <description>Port Event Input Data</description>
                            <lsb>4</lsb>
                            <msb>4</msb>
                            <access>read-only</access>
                            <enumeratedValues>
                                <enumeratedValue>
                                    <name>0</name>
                                    <description>Low input</description>
                                    <value>#0</value>
                                </enumeratedValue>
                                <enumeratedValue>
                                    <name>1</name>
                                    <description>High input</description>
                                    <value>#1</value>
                                </enumeratedValue>
                            </enumeratedValues>
                        </field>
                        <field>
                            <name>EIDR05</name>
                            <description>Port Event Input Data</description>
                            <lsb>5</lsb>
                            <msb>5</msb>
                            <access>read-only</access>
                            <enumeratedValues>
                                <enumeratedValue>
                                    <name>0</name>
                                    <description>Low input</description>
                                    <value>#0</value>
                                </enumeratedValue>
                                <enumeratedValue>
                                    <name>1</name>
                                    <description>High input</description>
                                    <value>#1</value>
                                </enumeratedValue>
                            </enumeratedValues>
                        </field>
                        <field>
                            <name>EIDR06</name>
                            <description>Port Event Input Data</description>
                            <lsb>6</lsb>
                            <msb>6</msb>
                            <access>read-only</access>
                            <enumeratedValues>
                                <enumeratedValue>
                                    <name>0</name>
                                    <description>Low input</description>
                                    <value>#0</value>
                                </enumeratedValue>
                                <enumeratedValue>
                                    <name>1</name>
                                    <description>High input</description>
                                    <value>#1</value>
                                </enumeratedValue>
                            </enumeratedValues>
                        </field>
                        <field>
                            <name>EIDR07</name>
                            <description>Port Event Input Data</description>
                            <lsb>7</lsb>
                            <msb>7</msb>
                            <access>read-only</access>
                            <enumeratedValues>
                                <enumeratedValue>
                                    <name>0</name>
                                    <description>Low input</description>
                                    <value>#0</value>
                                </enumeratedValue>
                                <enumeratedValue>
                                    <name>1</name>
                                    <description>High input</description>
                                    <value>#1</value>
                                </enumeratedValue>
                            </enumeratedValues>
                        </field>
                        <field>
                            <name>EIDR08</name>
                            <description>Port Event Input Data</description>
                            <lsb>8</lsb>
                            <msb>8</msb>
                            <access>read-only</access>
                            <enumeratedValues>
                                <enumeratedValue>
                                    <name>0</name>
                                    <description>Low input</description>
                                    <value>#0</value>
                                </enumeratedValue>
                                <enumeratedValue>
                                    <name>1</name>
                                    <description>High input</description>
                                    <value>#1</value>
                                </enumeratedValue>
                            </enumeratedValues>
                        </field>
                        <field>
                            <name>EIDR09</name>
                            <description>Port Event Input Data</description>
                            <lsb>9</lsb>
                            <msb>9</msb>
                            <access>read-only</access>
                            <enumeratedValues>
                                <enumeratedValue>
                                    <name>0</name>
                                    <description>Low input</description>
                                    <value>#0</value>
                                </enumeratedValue>
                                <enumeratedValue>
                                    <name>1</name>
                                    <description>High input</description>
                                    <value>#1</value>
                                </enumeratedValue>
                            </enumeratedValues>
                        </field>
                        <field>
                            <name>EIDR10</name>
                            <description>Port Event Input Data</description>
                            <lsb>10</lsb>
                            <msb>10</msb>
                            <access>read-only</access>
                            <enumeratedValues>
                                <enumeratedValue>
                                    <name>0</name>
                                    <description>Low input</description>
                                    <value>#0</value>
                                </enumeratedValue>
                                <enumeratedValue>
                                    <name>1</name>
                                    <description>High input</description>
                                    <value>#1</value>
                                </enumeratedValue>
                            </enumeratedValues>
                        </field>
                        <field>
                            <name>EIDR11</name>
                            <description>Port Event Input Data</description>
                            <lsb>11</lsb>
                            <msb>11</msb>
                            <access>read-only</access>
                            <enumeratedValues>
                                <enumeratedValue>
                                    <name>0</name>
                                    <description>Low input</description>
                                    <value>#0</value>
                                </enumeratedValue>
                                <enumeratedValue>
                                    <name>1</name>
                                    <description>High input</description>
                                    <value>#1</value>
                                </enumeratedValue>
                            </enumeratedValues>
                        </field>
                        <field>
                            <name>EIDR12</name>
                            <description>Port Event Input Data</description>
                            <lsb>12</lsb>
                            <msb>12</msb>
                            <access>read-only</access>
                            <enumeratedValues>
                                <enumeratedValue>
                                    <name>0</name>
                                    <description>Low input</description>
                                    <value>#0</value>
                                </enumeratedValue>
                                <enumeratedValue>
                                    <name>1</name>
                                    <description>High input</description>
                                    <value>#1</value>
                                </enumeratedValue>
                            </enumeratedValues>
                        </field>
                        <field>
                            <name>EIDR13</name>
                            <description>Port Event Input Data</description>
                            <lsb>13</lsb>
                            <msb>13</msb>
                            <access>read-only</access>
                            <enumeratedValues>
                                <enumeratedValue>
                                    <name>0</name>
                                    <description>Low input</description>
                                    <value>#0</value>
                                </enumeratedValue>
                                <enumeratedValue>
                                    <name>1</name>
                                    <description>High input</description>
                                    <value>#1</value>
                                </enumeratedValue>
                            </enumeratedValues>
                        </field>
                        <field>
                            <name>EIDR14</name>
                            <description>Port Event Input Data</description>
                            <lsb>14</lsb>
                            <msb>14</msb>
                            <access>read-only</access>
                            <enumeratedValues>
                                <enumeratedValue>
                                    <name>0</name>
                                    <description>Low input</description>
                                    <value>#0</value>
                                </enumeratedValue>
                                <enumeratedValue>
                                    <name>1</name>
                                    <description>High input</description>
                                    <value>#1</value>
                                </enumeratedValue>
                            </enumeratedValues>
                        </field>
                        <field>
                            <name>EIDR15</name>
                            <description>Port Event Input Data</description>
                            <lsb>15</lsb>
                            <msb>15</msb>
                            <access>read-only</access>
                            <enumeratedValues>
                                <enumeratedValue>
                                    <name>0</name>
                                    <description>Low input</description>
                                    <value>#0</value>
                                </enumeratedValue>
                                <enumeratedValue>
                                    <name>1</name>
                                    <description>High input</description>
                                    <value>#1</value>
                                </enumeratedValue>
                            </enumeratedValues>
                        </field>
                    </fields>
                </register>
                <register>
                    <name>EIDR</name>
                    <description>Port Control Register 2</description>
                    <alternateRegister>PCNTR2</alternateRegister>
                    <addressOffset>0x006</addressOffset>
                    <size>16</size>
                    <access>read-only</access>
                    <resetValue>0x0000</resetValue>
                    <resetMask>0x0000</resetMask>
                    <fields>
                        <field>
                            <name>PIDR00</name>
                            <description>Pmn State</description>
                            <lsb>0</lsb>
                            <msb>0</msb>
                            <access>read-only</access>
                            <enumeratedValues>
                                <enumeratedValue>
                                    <name>0</name>
                                    <description>Low level</description>
                                    <value>#0</value>
                                </enumeratedValue>
                                <enumeratedValue>
                                    <name>1</name>
                                    <description>High level</description>
                                    <value>#1</value>
                                </enumeratedValue>
                            </enumeratedValues>
                        </field>
                        <field>
                            <name>PIDR01</name>
                            <description>Pmn State</description>
                            <lsb>1</lsb>
                            <msb>1</msb>
                            <access>read-only</access>
                            <enumeratedValues>
                                <enumeratedValue>
                                    <name>0</name>
                                    <description>Low level</description>
                                    <value>#0</value>
                                </enumeratedValue>
                                <enumeratedValue>
                                    <name>1</name>
                                    <description>High level</description>
                                    <value>#1</value>
                                </enumeratedValue>
                            </enumeratedValues>
                        </field>
                        <field>
                            <name>PIDR02</name>
                            <description>Pmn State</description>
                            <lsb>2</lsb>
                            <msb>2</msb>
                            <access>read-only</access>
                            <enumeratedValues>
                                <enumeratedValue>
                                    <name>0</name>
                                    <description>Low level</description>
                                    <value>#0</value>
                                </enumeratedValue>
                                <enumeratedValue>
                                    <name>1</name>
                                    <description>High level</description>
                                    <value>#1</value>
                                </enumeratedValue>
                            </enumeratedValues>
                        </field>
                        <field>
                            <name>PIDR03</name>
                            <description>Pmn State</description>
                            <lsb>3</lsb>
                            <msb>3</msb>
                            <access>read-only</access>
                            <enumeratedValues>
                                <enumeratedValue>
                                    <name>0</name>
                                    <description>Low level</description>
                                    <value>#0</value>
                                </enumeratedValue>
                                <enumeratedValue>
                                    <name>1</name>
                                    <description>High level</description>
                                    <value>#1</value>
                                </enumeratedValue>
                            </enumeratedValues>
                        </field>
                        <field>
                            <name>PIDR04</name>
                            <description>Pmn State</description>
                            <lsb>4</lsb>
                            <msb>4</msb>
                            <access>read-only</access>
                            <enumeratedValues>
                                <enumeratedValue>
                                    <name>0</name>
                                    <description>Low level</description>
                                    <value>#0</value>
                                </enumeratedValue>
                                <enumeratedValue>
                                    <name>1</name>
                                    <description>High level</description>
                                    <value>#1</value>
                                </enumeratedValue>
                            </enumeratedValues>
                        </field>
                        <field>
                            <name>PIDR05</name>
                            <description>Pmn State</description>
                            <lsb>5</lsb>
                            <msb>5</msb>
                            <access>read-only</access>
                            <enumeratedValues>
                                <enumeratedValue>
                                    <name>0</name>
                                    <description>Low level</description>
                                    <value>#0</value>
                                </enumeratedValue>
                                <enumeratedValue>
                                    <name>1</name>
                                    <description>High level</description>
                                    <value>#1</value>
                                </enumeratedValue>
                            </enumeratedValues>
                        </field>
                        <field>
                            <name>PIDR06</name>
                            <description>Pmn State</description>
                            <lsb>6</lsb>
                            <msb>6</msb>
                            <access>read-only</access>
                            <enumeratedValues>
                                <enumeratedValue>
                                    <name>0</name>
                                    <description>Low level</description>
                                    <value>#0</value>
                                </enumeratedValue>
                                <enumeratedValue>
                                    <name>1</name>
                                    <description>High level</description>
                                    <value>#1</value>
                                </enumeratedValue>
                            </enumeratedValues>
                        </field>
                        <field>
                            <name>PIDR07</name>
                            <description>Pmn State</description>
                            <lsb>7</lsb>
                            <msb>7</msb>
                            <access>read-only</access>
                            <enumeratedValues>
                                <enumeratedValue>
                                    <name>0</name>
                                    <description>Low level</description>
                                    <value>#0</value>
                                </enumeratedValue>
                                <enumeratedValue>
                                    <name>1</name>
                                    <description>High level</description>
                                    <value>#1</value>
                                </enumeratedValue>
                            </enumeratedValues>
                        </field>
                        <field>
                            <name>PIDR08</name>
                            <description>Pmn State</description>
                            <lsb>8</lsb>
                            <msb>8</msb>
                            <access>read-only</access>
                            <enumeratedValues>
                                <enumeratedValue>
                                    <name>0</name>
                                    <description>Low level</description>
                                    <value>#0</value>
                                </enumeratedValue>
                                <enumeratedValue>
                                    <name>1</name>
                                    <description>High level</description>
                                    <value>#1</value>
                                </enumeratedValue>
                            </enumeratedValues>
                        </field>
                        <field>
                            <name>PIDR09</name>
                            <description>Pmn State</description>
                            <lsb>9</lsb>
                            <msb>9</msb>
                            <access>read-only</access>
                            <enumeratedValues>
                                <enumeratedValue>
                                    <name>0</name>
                                    <description>Low level</description>
                                    <value>#0</value>
                                </enumeratedValue>
                                <enumeratedValue>
                                    <name>1</name>
                                    <description>High level</description>
                                    <value>#1</value>
                                </enumeratedValue>
                            </enumeratedValues>
                        </field>
                        <field>
                            <name>PIDR10</name>
                            <description>Pmn State</description>
                            <lsb>10</lsb>
                            <msb>10</msb>
                            <access>read-only</access>
                            <enumeratedValues>
                                <enumeratedValue>
                                    <name>0</name>
                                    <description>Low level</description>
                                    <value>#0</value>
                                </enumeratedValue>
                                <enumeratedValue>
                                    <name>1</name>
                                    <description>High level</description>
                                    <value>#1</value>
                                </enumeratedValue>
                            </enumeratedValues>
                        </field>
                        <field>
                            <name>PIDR11</name>
                            <description>Pmn State</description>
                            <lsb>11</lsb>
                            <msb>11</msb>
                            <access>read-only</access>
                            <enumeratedValues>
                                <enumeratedValue>
                                    <name>0</name>
                                    <description>Low level</description>
                                    <value>#0</value>
                                </enumeratedValue>
                                <enumeratedValue>
                                    <name>1</name>
                                    <description>High level</description>
                                    <value>#1</value>
                                </enumeratedValue>
                            </enumeratedValues>
                        </field>
                        <field>
                            <name>PIDR12</name>
                            <description>Pmn State</description>
                            <lsb>12</lsb>
                            <msb>12</msb>
                            <access>read-only</access>
                            <enumeratedValues>
                                <enumeratedValue>
                                    <name>0</name>
                                    <description>Low level</description>
                                    <value>#0</value>
                                </enumeratedValue>
                                <enumeratedValue>
                                    <name>1</name>
                                    <description>High level</description>
                                    <value>#1</value>
                                </enumeratedValue>
                            </enumeratedValues>
                        </field>
                        <field>
                            <name>PIDR13</name>
                            <description>Pmn State</description>
                            <lsb>13</lsb>
                            <msb>13</msb>
                            <access>read-only</access>
                            <enumeratedValues>
                                <enumeratedValue>
                                    <name>0</name>
                                    <description>Low level</description>
                                    <value>#0</value>
                                </enumeratedValue>
                                <enumeratedValue>
                                    <name>1</name>
                                    <description>High level</description>
                                    <value>#1</value>
                                </enumeratedValue>
                            </enumeratedValues>
                        </field>
                        <field>
                            <name>PIDR14</name>
                            <description>Pmn State</description>
                            <lsb>14</lsb>
                            <msb>14</msb>
                            <access>read-only</access>
                            <enumeratedValues>
                                <enumeratedValue>
                                    <name>0</name>
                                    <description>Low level</description>
                                    <value>#0</value>
                                </enumeratedValue>
                                <enumeratedValue>
                                    <name>1</name>
                                    <description>High level</description>
                                    <value>#1</value>
                                </enumeratedValue>
                            </enumeratedValues>
                        </field>
                        <field>
                            <name>PIDR15</name>
                            <description>Pmn State</description>
                            <lsb>15</lsb>
                            <msb>15</msb>
                            <access>read-only</access>
                            <enumeratedValues>
                                <enumeratedValue>
                                    <name>0</name>
                                    <description>Low level</description>
                                    <value>#0</value>
                                </enumeratedValue>
                                <enumeratedValue>
                                    <name>1</name>
                                    <description>High level</description>
                                    <value>#1</value>
                                </enumeratedValue>
                            </enumeratedValues>
                        </field>
                    </fields>
                </register>
                <register>
                    <name>PCNTR3</name>
                    <description>Port Control Register 3</description>
                    <addressOffset>0x008</addressOffset>
                    <size>32</size>
                    <access>write-only</access>
                    <resetValue>0x00000000</resetValue>
                    <resetMask>0xffffffff</resetMask>
                    <fields>
                        <field>
                            <name>POSR00</name>
                            <description>Pmn Output Set</description>
                            <lsb>0</lsb>
                            <msb>0</msb>
                            <access>write-only</access>
                            <enumeratedValues>
                                <enumeratedValue>
                                    <name>0</name>
                                    <description>No effect on output</description>
                                    <value>#0</value>
                                </enumeratedValue>
                                <enumeratedValue>
                                    <name>1</name>
                                    <description>High output</description>
                                    <value>#1</value>
                                </enumeratedValue>
                            </enumeratedValues>
                        </field>
                        <field>
                            <name>POSR01</name>
                            <description>Pmn Output Set</description>
                            <lsb>1</lsb>
                            <msb>1</msb>
                            <access>write-only</access>
                            <enumeratedValues>
                                <enumeratedValue>
                                    <name>0</name>
                                    <description>No effect on output</description>
                                    <value>#0</value>
                                </enumeratedValue>
                                <enumeratedValue>
                                    <name>1</name>
                                    <description>High output</description>
                                    <value>#1</value>
                                </enumeratedValue>
                            </enumeratedValues>
                        </field>
                        <field>
                            <name>POSR02</name>
                            <description>Pmn Output Set</description>
                            <lsb>2</lsb>
                            <msb>2</msb>
                            <access>write-only</access>
                            <enumeratedValues>
                                <enumeratedValue>
                                    <name>0</name>
                                    <description>No effect on output</description>
                                    <value>#0</value>
                                </enumeratedValue>
                                <enumeratedValue>
                                    <name>1</name>
                                    <description>High output</description>
                                    <value>#1</value>
                                </enumeratedValue>
                            </enumeratedValues>
                        </field>
                        <field>
                            <name>POSR03</name>
                            <description>Pmn Output Set</description>
                            <lsb>3</lsb>
                            <msb>3</msb>
                            <access>write-only</access>
                            <enumeratedValues>
                                <enumeratedValue>
                                    <name>0</name>
                                    <description>No effect on output</description>
                                    <value>#0</value>
                                </enumeratedValue>
                                <enumeratedValue>
                                    <name>1</name>
                                    <description>High output</description>
                                    <value>#1</value>
                                </enumeratedValue>
                            </enumeratedValues>
                        </field>
                        <field>
                            <name>POSR04</name>
                            <description>Pmn Output Set</description>
                            <lsb>4</lsb>
                            <msb>4</msb>
                            <access>write-only</access>
                            <enumeratedValues>
                                <enumeratedValue>
                                    <name>0</name>
                                    <description>No effect on output</description>
                                    <value>#0</value>
                                </enumeratedValue>
                                <enumeratedValue>
                                    <name>1</name>
                                    <description>High output</description>
                                    <value>#1</value>
                                </enumeratedValue>
                            </enumeratedValues>
                        </field>
                        <field>
                            <name>POSR05</name>
                            <description>Pmn Output Set</description>
                            <lsb>5</lsb>
                            <msb>5</msb>
                            <access>write-only</access>
                            <enumeratedValues>
                                <enumeratedValue>
                                    <name>0</name>
                                    <description>No effect on output</description>
                                    <value>#0</value>
                                </enumeratedValue>
                                <enumeratedValue>
                                    <name>1</name>
                                    <description>High output</description>
                                    <value>#1</value>
                                </enumeratedValue>
                            </enumeratedValues>
                        </field>
                        <field>
                            <name>POSR06</name>
                            <description>Pmn Output Set</description>
                            <lsb>6</lsb>
                            <msb>6</msb>
                            <access>write-only</access>
                            <enumeratedValues>
                                <enumeratedValue>
                                    <name>0</name>
                                    <description>No effect on output</description>
                                    <value>#0</value>
                                </enumeratedValue>
                                <enumeratedValue>
                                    <name>1</name>
                                    <description>High output</description>
                                    <value>#1</value>
                                </enumeratedValue>
                            </enumeratedValues>
                        </field>
                        <field>
                            <name>POSR07</name>
                            <description>Pmn Output Set</description>
                            <lsb>7</lsb>
                            <msb>7</msb>
                            <access>write-only</access>
                            <enumeratedValues>
                                <enumeratedValue>
                                    <name>0</name>
                                    <description>No effect on output</description>
                                    <value>#0</value>
                                </enumeratedValue>
                                <enumeratedValue>
                                    <name>1</name>
                                    <description>High output</description>
                                    <value>#1</value>
                                </enumeratedValue>
                            </enumeratedValues>
                        </field>
                        <field>
                            <name>POSR08</name>
                            <description>Pmn Output Set</description>
                            <lsb>8</lsb>
                            <msb>8</msb>
                            <access>write-only</access>
                            <enumeratedValues>
                                <enumeratedValue>
                                    <name>0</name>
                                    <description>No effect on output</description>
                                    <value>#0</value>
                                </enumeratedValue>
                                <enumeratedValue>
                                    <name>1</name>
                                    <description>High output</description>
                                    <value>#1</value>
                                </enumeratedValue>
                            </enumeratedValues>
                        </field>
                        <field>
                            <name>POSR09</name>
                            <description>Pmn Output Set</description>
                            <lsb>9</lsb>
                            <msb>9</msb>
                            <access>write-only</access>
                            <enumeratedValues>
                                <enumeratedValue>
                                    <name>0</name>
                                    <description>No effect on output</description>
                                    <value>#0</value>
                                </enumeratedValue>
                                <enumeratedValue>
                                    <name>1</name>
                                    <description>High output</description>
                                    <value>#1</value>
                                </enumeratedValue>
                            </enumeratedValues>
                        </field>
                        <field>
                            <name>POSR10</name>
                            <description>Pmn Output Set</description>
                            <lsb>10</lsb>
                            <msb>10</msb>
                            <access>write-only</access>
                            <enumeratedValues>
                                <enumeratedValue>
                                    <name>0</name>
                                    <description>No effect on output</description>
                                    <value>#0</value>
                                </enumeratedValue>
                                <enumeratedValue>
                                    <name>1</name>
                                    <description>High output</description>
                                    <value>#1</value>
                                </enumeratedValue>
                            </enumeratedValues>
                        </field>
                        <field>
                            <name>POSR11</name>
                            <description>Pmn Output Set</description>
                            <lsb>11</lsb>
                            <msb>11</msb>
                            <access>write-only</access>
                            <enumeratedValues>
                                <enumeratedValue>
                                    <name>0</name>
                                    <description>No effect on output</description>
                                    <value>#0</value>
                                </enumeratedValue>
                                <enumeratedValue>
                                    <name>1</name>
                                    <description>High output</description>
                                    <value>#1</value>
                                </enumeratedValue>
                            </enumeratedValues>
                        </field>
                        <field>
                            <name>POSR12</name>
                            <description>Pmn Output Set</description>
                            <lsb>12</lsb>
                            <msb>12</msb>
                            <access>write-only</access>
                            <enumeratedValues>
                                <enumeratedValue>
                                    <name>0</name>
                                    <description>No effect on output</description>
                                    <value>#0</value>
                                </enumeratedValue>
                                <enumeratedValue>
                                    <name>1</name>
                                    <description>High output</description>
                                    <value>#1</value>
                                </enumeratedValue>
                            </enumeratedValues>
                        </field>
                        <field>
                            <name>POSR13</name>
                            <description>Pmn Output Set</description>
                            <lsb>13</lsb>
                            <msb>13</msb>
                            <access>write-only</access>
                            <enumeratedValues>
                                <enumeratedValue>
                                    <name>0</name>
                                    <description>No effect on output</description>
                                    <value>#0</value>
                                </enumeratedValue>
                                <enumeratedValue>
                                    <name>1</name>
                                    <description>High output</description>
                                    <value>#1</value>
                                </enumeratedValue>
                            </enumeratedValues>
                        </field>
                        <field>
                            <name>POSR14</name>
                            <description>Pmn Output Set</description>
                            <lsb>14</lsb>
                            <msb>14</msb>
                            <access>write-only</access>
                            <enumeratedValues>
                                <enumeratedValue>
                                    <name>0</name>
                                    <description>No effect on output</description>
                                    <value>#0</value>
                                </enumeratedValue>
                                <enumeratedValue>
                                    <name>1</name>
                                    <description>High output</description>
                                    <value>#1</value>
                                </enumeratedValue>
                            </enumeratedValues>
                        </field>
                        <field>
                            <name>POSR15</name>
                            <description>Pmn Output Set</description>
                            <lsb>15</lsb>
                            <msb>15</msb>
                            <access>write-only</access>
                            <enumeratedValues>
                                <enumeratedValue>
                                    <name>0</name>
                                    <description>No effect on output</description>
                                    <value>#0</value>
                                </enumeratedValue>
                                <enumeratedValue>
                                    <name>1</name>
                                    <description>High output</description>
                                    <value>#1</value>
                                </enumeratedValue>
                            </enumeratedValues>
                        </field>
                        <field>
                            <name>PORR00</name>
                            <description>Pmn Output Reset</description>
                            <lsb>16</lsb>
                            <msb>16</msb>
                            <access>write-only</access>
                            <enumeratedValues>
                                <enumeratedValue>
                                    <name>0</name>
                                    <description>No effect on output</description>
                                    <value>#0</value>
                                </enumeratedValue>
                                <enumeratedValue>
                                    <name>1</name>
                                    <description>Low output</description>
                                    <value>#1</value>
                                </enumeratedValue>
                            </enumeratedValues>
                        </field>
                        <field>
                            <name>PORR01</name>
                            <description>Pmn Output Reset</description>
                            <lsb>17</lsb>
                            <msb>17</msb>
                            <access>write-only</access>
                            <enumeratedValues>
                                <enumeratedValue>
                                    <name>0</name>
                                    <description>No effect on output</description>
                                    <value>#0</value>
                                </enumeratedValue>
                                <enumeratedValue>
                                    <name>1</name>
                                    <description>Low output</description>
                                    <value>#1</value>
                                </enumeratedValue>
                            </enumeratedValues>
                        </field>
                        <field>
                            <name>PORR02</name>
                            <description>Pmn Output Reset</description>
                            <lsb>18</lsb>
                            <msb>18</msb>
                            <access>write-only</access>
                            <enumeratedValues>
                                <enumeratedValue>
                                    <name>0</name>
                                    <description>No effect on output</description>
                                    <value>#0</value>
                                </enumeratedValue>
                                <enumeratedValue>
                                    <name>1</name>
                                    <description>Low output</description>
                                    <value>#1</value>
                                </enumeratedValue>
                            </enumeratedValues>
                        </field>
                        <field>
                            <name>PORR03</name>
                            <description>Pmn Output Reset</description>
                            <lsb>19</lsb>
                            <msb>19</msb>
                            <access>write-only</access>
                            <enumeratedValues>
                                <enumeratedValue>
                                    <name>0</name>
                                    <description>No effect on output</description>
                                    <value>#0</value>
                                </enumeratedValue>
                                <enumeratedValue>
                                    <name>1</name>
                                    <description>Low output</description>
                                    <value>#1</value>
                                </enumeratedValue>
                            </enumeratedValues>
                        </field>
                        <field>
                            <name>PORR04</name>
                            <description>Pmn Output Reset</description>
                            <lsb>20</lsb>
                            <msb>20</msb>
                            <access>write-only</access>
                            <enumeratedValues>
                                <enumeratedValue>
                                    <name>0</name>
                                    <description>No effect on output</description>
                                    <value>#0</value>
                                </enumeratedValue>
                                <enumeratedValue>
                                    <name>1</name>
                                    <description>Low output</description>
                                    <value>#1</value>
                                </enumeratedValue>
                            </enumeratedValues>
                        </field>
                        <field>
                            <name>PORR05</name>
                            <description>Pmn Output Reset</description>
                            <lsb>21</lsb>
                            <msb>21</msb>
                            <access>write-only</access>
                            <enumeratedValues>
                                <enumeratedValue>
                                    <name>0</name>
                                    <description>No effect on output</description>
                                    <value>#0</value>
                                </enumeratedValue>
                                <enumeratedValue>
                                    <name>1</name>
                                    <description>Low output</description>
                                    <value>#1</value>
                                </enumeratedValue>
                            </enumeratedValues>
                        </field>
                        <field>
                            <name>PORR06</name>
                            <description>Pmn Output Reset</description>
                            <lsb>22</lsb>
                            <msb>22</msb>
                            <access>write-only</access>
                            <enumeratedValues>
                                <enumeratedValue>
                                    <name>0</name>
                                    <description>No effect on output</description>
                                    <value>#0</value>
                                </enumeratedValue>
                                <enumeratedValue>
                                    <name>1</name>
                                    <description>Low output</description>
                                    <value>#1</value>
                                </enumeratedValue>
                            </enumeratedValues>
                        </field>
                        <field>
                            <name>PORR07</name>
                            <description>Pmn Output Reset</description>
                            <lsb>23</lsb>
                            <msb>23</msb>
                            <access>write-only</access>
                            <enumeratedValues>
                                <enumeratedValue>
                                    <name>0</name>
                                    <description>No effect on output</description>
                                    <value>#0</value>
                                </enumeratedValue>
                                <enumeratedValue>
                                    <name>1</name>
                                    <description>Low output</description>
                                    <value>#1</value>
                                </enumeratedValue>
                            </enumeratedValues>
                        </field>
                        <field>
                            <name>PORR08</name>
                            <description>Pmn Output Reset</description>
                            <lsb>24</lsb>
                            <msb>24</msb>
                            <access>write-only</access>
                            <enumeratedValues>
                                <enumeratedValue>
                                    <name>0</name>
                                    <description>No effect on output</description>
                                    <value>#0</value>
                                </enumeratedValue>
                                <enumeratedValue>
                                    <name>1</name>
                                    <description>Low output</description>
                                    <value>#1</value>
                                </enumeratedValue>
                            </enumeratedValues>
                        </field>
                        <field>
                            <name>PORR09</name>
                            <description>Pmn Output Reset</description>
                            <lsb>25</lsb>
                            <msb>25</msb>
                            <access>write-only</access>
                            <enumeratedValues>
                                <enumeratedValue>
                                    <name>0</name>
                                    <description>No effect on output</description>
                                    <value>#0</value>
                                </enumeratedValue>
                                <enumeratedValue>
                                    <name>1</name>
                                    <description>Low output</description>
                                    <value>#1</value>
                                </enumeratedValue>
                            </enumeratedValues>
                        </field>
                        <field>
                            <name>PORR10</name>
                            <description>Pmn Output Reset</description>
                            <lsb>26</lsb>
                            <msb>26</msb>
                            <access>write-only</access>
                            <enumeratedValues>
                                <enumeratedValue>
                                    <name>0</name>
                                    <description>No effect on output</description>
                                    <value>#0</value>
                                </enumeratedValue>
                                <enumeratedValue>
                                    <name>1</name>
                                    <description>Low output</description>
                                    <value>#1</value>
                                </enumeratedValue>
                            </enumeratedValues>
                        </field>
                        <field>
                            <name>PORR11</name>
                            <description>Pmn Output Reset</description>
                            <lsb>27</lsb>
                            <msb>27</msb>
                            <access>write-only</access>
                            <enumeratedValues>
                                <enumeratedValue>
                                    <name>0</name>
                                    <description>No effect on output</description>
                                    <value>#0</value>
                                </enumeratedValue>
                                <enumeratedValue>
                                    <name>1</name>
                                    <description>Low output</description>
                                    <value>#1</value>
                                </enumeratedValue>
                            </enumeratedValues>
                        </field>
                        <field>
                            <name>PORR12</name>
                            <description>Pmn Output Reset</description>
                            <lsb>28</lsb>
                            <msb>28</msb>
                            <access>write-only</access>
                            <enumeratedValues>
                                <enumeratedValue>
                                    <name>0</name>
                                    <description>No effect on output</description>
                                    <value>#0</value>
                                </enumeratedValue>
                                <enumeratedValue>
                                    <name>1</name>
                                    <description>Low output</description>
                                    <value>#1</value>
                                </enumeratedValue>
                            </enumeratedValues>
                        </field>
                        <field>
                            <name>PORR13</name>
                            <description>Pmn Output Reset</description>
                            <lsb>29</lsb>
                            <msb>29</msb>
                            <access>write-only</access>
                            <enumeratedValues>
                                <enumeratedValue>
                                    <name>0</name>
                                    <description>No effect on output</description>
                                    <value>#0</value>
                                </enumeratedValue>
                                <enumeratedValue>
                                    <name>1</name>
                                    <description>Low output</description>
                                    <value>#1</value>
                                </enumeratedValue>
                            </enumeratedValues>
                        </field>
                        <field>
                            <name>PORR14</name>
                            <description>Pmn Output Reset</description>
                            <lsb>30</lsb>
                            <msb>30</msb>
                            <access>write-only</access>
                            <enumeratedValues>
                                <enumeratedValue>
                                    <name>0</name>
                                    <description>No effect on output</description>
                                    <value>#0</value>
                                </enumeratedValue>
                                <enumeratedValue>
                                    <name>1</name>
                                    <description>Low output</description>
                                    <value>#1</value>
                                </enumeratedValue>
                            </enumeratedValues>
                        </field>
                        <field>
                            <name>PORR15</name>
                            <description>Pmn Output Reset</description>
                            <lsb>31</lsb>
                            <msb>31</msb>
                            <access>write-only</access>
                            <enumeratedValues>
                                <enumeratedValue>
                                    <name>0</name>
                                    <description>No effect on output</description>
                                    <value>#0</value>
                                </enumeratedValue>
                                <enumeratedValue>
                                    <name>1</name>
                                    <description>Low output</description>
                                    <value>#1</value>
                                </enumeratedValue>
                            </enumeratedValues>
                        </field>
                    </fields>
                </register>
                <register>
                    <name>POSR</name>
                    <description>Port Control Register 3</description>
                    <alternateRegister>PCNTR3</alternateRegister>
                    <addressOffset>0x008</addressOffset>
                    <size>16</size>
                    <access>write-only</access>
                    <resetValue>0x0000</resetValue>
                    <resetMask>0xffff</resetMask>
                    <fields>
                        <field>
                            <name>PORR00</name>
                            <description>Pmn Output Reset</description>
                            <lsb>0</lsb>
                            <msb>0</msb>
                            <access>write-only</access>
                            <enumeratedValues>
                                <enumeratedValue>
                                    <name>0</name>
                                    <description>No effect on output</description>
                                    <value>#0</value>
                                </enumeratedValue>
                                <enumeratedValue>
                                    <name>1</name>
                                    <description>Low output</description>
                                    <value>#1</value>
                                </enumeratedValue>
                            </enumeratedValues>
                        </field>
                        <field>
                            <name>PORR01</name>
                            <description>Pmn Output Reset</description>
                            <lsb>1</lsb>
                            <msb>1</msb>
                            <access>write-only</access>
                            <enumeratedValues>
                                <enumeratedValue>
                                    <name>0</name>
                                    <description>No effect on output</description>
                                    <value>#0</value>
                                </enumeratedValue>
                                <enumeratedValue>
                                    <name>1</name>
                                    <description>Low output</description>
                                    <value>#1</value>
                                </enumeratedValue>
                            </enumeratedValues>
                        </field>
                        <field>
                            <name>PORR02</name>
                            <description>Pmn Output Reset</description>
                            <lsb>2</lsb>
                            <msb>2</msb>
                            <access>write-only</access>
                            <enumeratedValues>
                                <enumeratedValue>
                                    <name>0</name>
                                    <description>No effect on output</description>
                                    <value>#0</value>
                                </enumeratedValue>
                                <enumeratedValue>
                                    <name>1</name>
                                    <description>Low output</description>
                                    <value>#1</value>
                                </enumeratedValue>
                            </enumeratedValues>
                        </field>
                        <field>
                            <name>PORR03</name>
                            <description>Pmn Output Reset</description>
                            <lsb>3</lsb>
                            <msb>3</msb>
                            <access>write-only</access>
                            <enumeratedValues>
                                <enumeratedValue>
                                    <name>0</name>
                                    <description>No effect on output</description>
                                    <value>#0</value>
                                </enumeratedValue>
                                <enumeratedValue>
                                    <name>1</name>
                                    <description>Low output</description>
                                    <value>#1</value>
                                </enumeratedValue>
                            </enumeratedValues>
                        </field>
                        <field>
                            <name>PORR04</name>
                            <description>Pmn Output Reset</description>
                            <lsb>4</lsb>
                            <msb>4</msb>
                            <access>write-only</access>
                            <enumeratedValues>
                                <enumeratedValue>
                                    <name>0</name>
                                    <description>No effect on output</description>
                                    <value>#0</value>
                                </enumeratedValue>
                                <enumeratedValue>
                                    <name>1</name>
                                    <description>Low output</description>
                                    <value>#1</value>
                                </enumeratedValue>
                            </enumeratedValues>
                        </field>
                        <field>
                            <name>PORR05</name>
                            <description>Pmn Output Reset</description>
                            <lsb>5</lsb>
                            <msb>5</msb>
                            <access>write-only</access>
                            <enumeratedValues>
                                <enumeratedValue>
                                    <name>0</name>
                                    <description>No effect on output</description>
                                    <value>#0</value>
                                </enumeratedValue>
                                <enumeratedValue>
                                    <name>1</name>
                                    <description>Low output</description>
                                    <value>#1</value>
                                </enumeratedValue>
                            </enumeratedValues>
                        </field>
                        <field>
                            <name>PORR06</name>
                            <description>Pmn Output Reset</description>
                            <lsb>6</lsb>
                            <msb>6</msb>
                            <access>write-only</access>
                            <enumeratedValues>
                                <enumeratedValue>
                                    <name>0</name>
                                    <description>No effect on output</description>
                                    <value>#0</value>
                                </enumeratedValue>
                                <enumeratedValue>
                                    <name>1</name>
                                    <description>Low output</description>
                                    <value>#1</value>
                                </enumeratedValue>
                            </enumeratedValues>
                        </field>
                        <field>
                            <name>PORR07</name>
                            <description>Pmn Output Reset</description>
                            <lsb>7</lsb>
                            <msb>7</msb>
                            <access>write-only</access>
                            <enumeratedValues>
                                <enumeratedValue>
                                    <name>0</name>
                                    <description>No effect on output</description>
                                    <value>#0</value>
                                </enumeratedValue>
                                <enumeratedValue>
                                    <name>1</name>
                                    <description>Low output</description>
                                    <value>#1</value>
                                </enumeratedValue>
                            </enumeratedValues>
                        </field>
                        <field>
                            <name>PORR08</name>
                            <description>Pmn Output Reset</description>
                            <lsb>8</lsb>
                            <msb>8</msb>
                            <access>write-only</access>
                            <enumeratedValues>
                                <enumeratedValue>
                                    <name>0</name>
                                    <description>No effect on output</description>
                                    <value>#0</value>
                                </enumeratedValue>
                                <enumeratedValue>
                                    <name>1</name>
                                    <description>Low output</description>
                                    <value>#1</value>
                                </enumeratedValue>
                            </enumeratedValues>
                        </field>
                        <field>
                            <name>PORR09</name>
                            <description>Pmn Output Reset</description>
                            <lsb>9</lsb>
                            <msb>9</msb>
                            <access>write-only</access>
                            <enumeratedValues>
                                <enumeratedValue>
                                    <name>0</name>
                                    <description>No effect on output</description>
                                    <value>#0</value>
                                </enumeratedValue>
                                <enumeratedValue>
                                    <name>1</name>
                                    <description>Low output</description>
                                    <value>#1</value>
                                </enumeratedValue>
                            </enumeratedValues>
                        </field>
                        <field>
                            <name>PORR10</name>
                            <description>Pmn Output Reset</description>
                            <lsb>10</lsb>
                            <msb>10</msb>
                            <access>write-only</access>
                            <enumeratedValues>
                                <enumeratedValue>
                                    <name>0</name>
                                    <description>No effect on output</description>
                                    <value>#0</value>
                                </enumeratedValue>
                                <enumeratedValue>
                                    <name>1</name>
                                    <description>Low output</description>
                                    <value>#1</value>
                                </enumeratedValue>
                            </enumeratedValues>
                        </field>
                        <field>
                            <name>PORR11</name>
                            <description>Pmn Output Reset</description>
                            <lsb>11</lsb>
                            <msb>11</msb>
                            <access>write-only</access>
                            <enumeratedValues>
                                <enumeratedValue>
                                    <name>0</name>
                                    <description>No effect on output</description>
                                    <value>#0</value>
                                </enumeratedValue>
                                <enumeratedValue>
                                    <name>1</name>
                                    <description>Low output</description>
                                    <value>#1</value>
                                </enumeratedValue>
                            </enumeratedValues>
                        </field>
                        <field>
                            <name>PORR12</name>
                            <description>Pmn Output Reset</description>
                            <lsb>12</lsb>
                            <msb>12</msb>
                            <access>write-only</access>
                            <enumeratedValues>
                                <enumeratedValue>
                                    <name>0</name>
                                    <description>No effect on output</description>
                                    <value>#0</value>
                                </enumeratedValue>
                                <enumeratedValue>
                                    <name>1</name>
                                    <description>Low output</description>
                                    <value>#1</value>
                                </enumeratedValue>
                            </enumeratedValues>
                        </field>
                        <field>
                            <name>PORR13</name>
                            <description>Pmn Output Reset</description>
                            <lsb>13</lsb>
                            <msb>13</msb>
                            <access>write-only</access>
                            <enumeratedValues>
                                <enumeratedValue>
                                    <name>0</name>
                                    <description>No effect on output</description>
                                    <value>#0</value>
                                </enumeratedValue>
                                <enumeratedValue>
                                    <name>1</name>
                                    <description>Low output</description>
                                    <value>#1</value>
                                </enumeratedValue>
                            </enumeratedValues>
                        </field>
                        <field>
                            <name>PORR14</name>
                            <description>Pmn Output Reset</description>
                            <lsb>14</lsb>
                            <msb>14</msb>
                            <access>write-only</access>
                            <enumeratedValues>
                                <enumeratedValue>
                                    <name>0</name>
                                    <description>No effect on output</description>
                                    <value>#0</value>
                                </enumeratedValue>
                                <enumeratedValue>
                                    <name>1</name>
                                    <description>Low output</description>
                                    <value>#1</value>
                                </enumeratedValue>
                            </enumeratedValues>
                        </field>
                        <field>
                            <name>PORR15</name>
                            <description>Pmn Output Reset</description>
                            <lsb>15</lsb>
                            <msb>15</msb>
                            <access>write-only</access>
                            <enumeratedValues>
                                <enumeratedValue>
                                    <name>0</name>
                                    <description>No effect on output</description>
                                    <value>#0</value>
                                </enumeratedValue>
                                <enumeratedValue>
                                    <name>1</name>
                                    <description>Low output</description>
                                    <value>#1</value>
                                </enumeratedValue>
                            </enumeratedValues>
                        </field>
                    </fields>
                </register>
                <register>
                    <name>PORR</name>
                    <description>Port Control Register 3</description>
                    <alternateRegister>PCNTR3</alternateRegister>
                    <addressOffset>0x00A</addressOffset>
                    <size>16</size>
                    <access>write-only</access>
                    <resetValue>0x0000</resetValue>
                    <resetMask>0xffff</resetMask>
                    <fields>
                        <field>
                            <name>POSR00</name>
                            <description>Pmn Output Set</description>
                            <lsb>0</lsb>
                            <msb>0</msb>
                            <access>write-only</access>
                            <enumeratedValues>
                                <enumeratedValue>
                                    <name>0</name>
                                    <description>No effect on output</description>
                                    <value>#0</value>
                                </enumeratedValue>
                                <enumeratedValue>
                                    <name>1</name>
                                    <description>High output</description>
                                    <value>#1</value>
                                </enumeratedValue>
                            </enumeratedValues>
                        </field>
                        <field>
                            <name>POSR01</name>
                            <description>Pmn Output Set</description>
                            <lsb>1</lsb>
                            <msb>1</msb>
                            <access>write-only</access>
                            <enumeratedValues>
                                <enumeratedValue>
                                    <name>0</name>
                                    <description>No effect on output</description>
                                    <value>#0</value>
                                </enumeratedValue>
                                <enumeratedValue>
                                    <name>1</name>
                                    <description>High output</description>
                                    <value>#1</value>
                                </enumeratedValue>
                            </enumeratedValues>
                        </field>
                        <field>
                            <name>POSR02</name>
                            <description>Pmn Output Set</description>
                            <lsb>2</lsb>
                            <msb>2</msb>
                            <access>write-only</access>
                            <enumeratedValues>
                                <enumeratedValue>
                                    <name>0</name>
                                    <description>No effect on output</description>
                                    <value>#0</value>
                                </enumeratedValue>
                                <enumeratedValue>
                                    <name>1</name>
                                    <description>High output</description>
                                    <value>#1</value>
                                </enumeratedValue>
                            </enumeratedValues>
                        </field>
                        <field>
                            <name>POSR03</name>
                            <description>Pmn Output Set</description>
                            <lsb>3</lsb>
                            <msb>3</msb>
                            <access>write-only</access>
                            <enumeratedValues>
                                <enumeratedValue>
                                    <name>0</name>
                                    <description>No effect on output</description>
                                    <value>#0</value>
                                </enumeratedValue>
                                <enumeratedValue>
                                    <name>1</name>
                                    <description>High output</description>
                                    <value>#1</value>
                                </enumeratedValue>
                            </enumeratedValues>
                        </field>
                        <field>
                            <name>POSR04</name>
                            <description>Pmn Output Set</description>
                            <lsb>4</lsb>
                            <msb>4</msb>
                            <access>write-only</access>
                            <enumeratedValues>
                                <enumeratedValue>
                                    <name>0</name>
                                    <description>No effect on output</description>
                                    <value>#0</value>
                                </enumeratedValue>
                                <enumeratedValue>
                                    <name>1</name>
                                    <description>High output</description>
                                    <value>#1</value>
                                </enumeratedValue>
                            </enumeratedValues>
                        </field>
                        <field>
                            <name>POSR05</name>
                            <description>Pmn Output Set</description>
                            <lsb>5</lsb>
                            <msb>5</msb>
                            <access>write-only</access>
                            <enumeratedValues>
                                <enumeratedValue>
                                    <name>0</name>
                                    <description>No effect on output</description>
                                    <value>#0</value>
                                </enumeratedValue>
                                <enumeratedValue>
                                    <name>1</name>
                                    <description>High output</description>
                                    <value>#1</value>
                                </enumeratedValue>
                            </enumeratedValues>
                        </field>
                        <field>
                            <name>POSR06</name>
                            <description>Pmn Output Set</description>
                            <lsb>6</lsb>
                            <msb>6</msb>
                            <access>write-only</access>
                            <enumeratedValues>
                                <enumeratedValue>
                                    <name>0</name>
                                    <description>No effect on output</description>
                                    <value>#0</value>
                                </enumeratedValue>
                                <enumeratedValue>
                                    <name>1</name>
                                    <description>High output</description>
                                    <value>#1</value>
                                </enumeratedValue>
                            </enumeratedValues>
                        </field>
                        <field>
                            <name>POSR07</name>
                            <description>Pmn Output Set</description>
                            <lsb>7</lsb>
                            <msb>7</msb>
                            <access>write-only</access>
                            <enumeratedValues>
                                <enumeratedValue>
                                    <name>0</name>
                                    <description>No effect on output</description>
                                    <value>#0</value>
                                </enumeratedValue>
                                <enumeratedValue>
                                    <name>1</name>
                                    <description>High output</description>
                                    <value>#1</value>
                                </enumeratedValue>
                            </enumeratedValues>
                        </field>
                        <field>
                            <name>POSR08</name>
                            <description>Pmn Output Set</description>
                            <lsb>8</lsb>
                            <msb>8</msb>
                            <access>write-only</access>
                            <enumeratedValues>
                                <enumeratedValue>
                                    <name>0</name>
                                    <description>No effect on output</description>
                                    <value>#0</value>
                                </enumeratedValue>
                                <enumeratedValue>
                                    <name>1</name>
                                    <description>High output</description>
                                    <value>#1</value>
                                </enumeratedValue>
                            </enumeratedValues>
                        </field>
                        <field>
                            <name>POSR09</name>
                            <description>Pmn Output Set</description>
                            <lsb>9</lsb>
                            <msb>9</msb>
                            <access>write-only</access>
                            <enumeratedValues>
                                <enumeratedValue>
                                    <name>0</name>
                                    <description>No effect on output</description>
                                    <value>#0</value>
                                </enumeratedValue>
                                <enumeratedValue>
                                    <name>1</name>
                                    <description>High output</description>
                                    <value>#1</value>
                                </enumeratedValue>
                            </enumeratedValues>
                        </field>
                        <field>
                            <name>POSR10</name>
                            <description>Pmn Output Set</description>
                            <lsb>10</lsb>
                            <msb>10</msb>
                            <access>write-only</access>
                            <enumeratedValues>
                                <enumeratedValue>
                                    <name>0</name>
                                    <description>No effect on output</description>
                                    <value>#0</value>
                                </enumeratedValue>
                                <enumeratedValue>
                                    <name>1</name>
                                    <description>High output</description>
                                    <value>#1</value>
                                </enumeratedValue>
                            </enumeratedValues>
                        </field>
                        <field>
                            <name>POSR11</name>
                            <description>Pmn Output Set</description>
                            <lsb>11</lsb>
                            <msb>11</msb>
                            <access>write-only</access>
                            <enumeratedValues>
                                <enumeratedValue>
                                    <name>0</name>
                                    <description>No effect on output</description>
                                    <value>#0</value>
                                </enumeratedValue>
                                <enumeratedValue>
                                    <name>1</name>
                                    <description>High output</description>
                                    <value>#1</value>
                                </enumeratedValue>
                            </enumeratedValues>
                        </field>
                        <field>
                            <name>POSR12</name>
                            <description>Pmn Output Set</description>
                            <lsb>12</lsb>
                            <msb>12</msb>
                            <access>write-only</access>
                            <enumeratedValues>
                                <enumeratedValue>
                                    <name>0</name>
                                    <description>No effect on output</description>
                                    <value>#0</value>
                                </enumeratedValue>
                                <enumeratedValue>
                                    <name>1</name>
                                    <description>High output</description>
                                    <value>#1</value>
                                </enumeratedValue>
                            </enumeratedValues>
                        </field>
                        <field>
                            <name>POSR13</name>
                            <description>Pmn Output Set</description>
                            <lsb>13</lsb>
                            <msb>13</msb>
                            <access>write-only</access>
                            <enumeratedValues>
                                <enumeratedValue>
                                    <name>0</name>
                                    <description>No effect on output</description>
                                    <value>#0</value>
                                </enumeratedValue>
                                <enumeratedValue>
                                    <name>1</name>
                                    <description>High output</description>
                                    <value>#1</value>
                                </enumeratedValue>
                            </enumeratedValues>
                        </field>
                        <field>
                            <name>POSR14</name>
                            <description>Pmn Output Set</description>
                            <lsb>14</lsb>
                            <msb>14</msb>
                            <access>write-only</access>
                            <enumeratedValues>
                                <enumeratedValue>
                                    <name>0</name>
                                    <description>No effect on output</description>
                                    <value>#0</value>
                                </enumeratedValue>
                                <enumeratedValue>
                                    <name>1</name>
                                    <description>High output</description>
                                    <value>#1</value>
                                </enumeratedValue>
                            </enumeratedValues>
                        </field>
                        <field>
                            <name>POSR15</name>
                            <description>Pmn Output Set</description>
                            <lsb>15</lsb>
                            <msb>15</msb>
                            <access>write-only</access>
                            <enumeratedValues>
                                <enumeratedValue>
                                    <name>0</name>
                                    <description>No effect on output</description>
                                    <value>#0</value>
                                </enumeratedValue>
                                <enumeratedValue>
                                    <name>1</name>
                                    <description>High output</description>
                                    <value>#1</value>
                                </enumeratedValue>
                            </enumeratedValues>
                        </field>
                    </fields>
                </register>
                <register>
                    <name>PCNTR4</name>
                    <description>Port Control Register 4</description>
                    <addressOffset>0x00C</addressOffset>
                    <size>32</size>
                    <access>read-write</access>
                    <resetValue>0x00000000</resetValue>
                    <resetMask>0xffffffff</resetMask>
                    <fields>
                        <field>
                            <name>EOSR00</name>
                            <description>Pmn Event Output Set</description>
                            <lsb>0</lsb>
                            <msb>0</msb>
                            <access>read-write</access>
                            <enumeratedValues>
                                <enumeratedValue>
                                    <name>0</name>
                                    <description>No effect on output</description>
                                    <value>#0</value>
                                </enumeratedValue>
                                <enumeratedValue>
                                    <name>1</name>
                                    <description>High output</description>
                                    <value>#1</value>
                                </enumeratedValue>
                            </enumeratedValues>
                        </field>
                        <field>
                            <name>EOSR01</name>
                            <description>Pmn Event Output Set</description>
                            <lsb>1</lsb>
                            <msb>1</msb>
                            <access>read-write</access>
                            <enumeratedValues>
                                <enumeratedValue>
                                    <name>0</name>
                                    <description>No effect on output</description>
                                    <value>#0</value>
                                </enumeratedValue>
                                <enumeratedValue>
                                    <name>1</name>
                                    <description>High output</description>
                                    <value>#1</value>
                                </enumeratedValue>
                            </enumeratedValues>
                        </field>
                        <field>
                            <name>EOSR02</name>
                            <description>Pmn Event Output Set</description>
                            <lsb>2</lsb>
                            <msb>2</msb>
                            <access>read-write</access>
                            <enumeratedValues>
                                <enumeratedValue>
                                    <name>0</name>
                                    <description>No effect on output</description>
                                    <value>#0</value>
                                </enumeratedValue>
                                <enumeratedValue>
                                    <name>1</name>
                                    <description>High output</description>
                                    <value>#1</value>
                                </enumeratedValue>
                            </enumeratedValues>
                        </field>
                        <field>
                            <name>EOSR03</name>
                            <description>Pmn Event Output Set</description>
                            <lsb>3</lsb>
                            <msb>3</msb>
                            <access>read-write</access>
                            <enumeratedValues>
                                <enumeratedValue>
                                    <name>0</name>
                                    <description>No effect on output</description>
                                    <value>#0</value>
                                </enumeratedValue>
                                <enumeratedValue>
                                    <name>1</name>
                                    <description>High output</description>
                                    <value>#1</value>
                                </enumeratedValue>
                            </enumeratedValues>
                        </field>
                        <field>
                            <name>EOSR04</name>
                            <description>Pmn Event Output Set</description>
                            <lsb>4</lsb>
                            <msb>4</msb>
                            <access>read-write</access>
                            <enumeratedValues>
                                <enumeratedValue>
                                    <name>0</name>
                                    <description>No effect on output</description>
                                    <value>#0</value>
                                </enumeratedValue>
                                <enumeratedValue>
                                    <name>1</name>
                                    <description>High output</description>
                                    <value>#1</value>
                                </enumeratedValue>
                            </enumeratedValues>
                        </field>
                        <field>
                            <name>EOSR05</name>
                            <description>Pmn Event Output Set</description>
                            <lsb>5</lsb>
                            <msb>5</msb>
                            <access>read-write</access>
                            <enumeratedValues>
                                <enumeratedValue>
                                    <name>0</name>
                                    <description>No effect on output</description>
                                    <value>#0</value>
                                </enumeratedValue>
                                <enumeratedValue>
                                    <name>1</name>
                                    <description>High output</description>
                                    <value>#1</value>
                                </enumeratedValue>
                            </enumeratedValues>
                        </field>
                        <field>
                            <name>EOSR06</name>
                            <description>Pmn Event Output Set</description>
                            <lsb>6</lsb>
                            <msb>6</msb>
                            <access>read-write</access>
                            <enumeratedValues>
                                <enumeratedValue>
                                    <name>0</name>
                                    <description>No effect on output</description>
                                    <value>#0</value>
                                </enumeratedValue>
                                <enumeratedValue>
                                    <name>1</name>
                                    <description>High output</description>
                                    <value>#1</value>
                                </enumeratedValue>
                            </enumeratedValues>
                        </field>
                        <field>
                            <name>EOSR07</name>
                            <description>Pmn Event Output Set</description>
                            <lsb>7</lsb>
                            <msb>7</msb>
                            <access>read-write</access>
                            <enumeratedValues>
                                <enumeratedValue>
                                    <name>0</name>
                                    <description>No effect on output</description>
                                    <value>#0</value>
                                </enumeratedValue>
                                <enumeratedValue>
                                    <name>1</name>
                                    <description>High output</description>
                                    <value>#1</value>
                                </enumeratedValue>
                            </enumeratedValues>
                        </field>
                        <field>
                            <name>EOSR08</name>
                            <description>Pmn Event Output Set</description>
                            <lsb>8</lsb>
                            <msb>8</msb>
                            <access>read-write</access>
                            <enumeratedValues>
                                <enumeratedValue>
                                    <name>0</name>
                                    <description>No effect on output</description>
                                    <value>#0</value>
                                </enumeratedValue>
                                <enumeratedValue>
                                    <name>1</name>
                                    <description>High output</description>
                                    <value>#1</value>
                                </enumeratedValue>
                            </enumeratedValues>
                        </field>
                        <field>
                            <name>EOSR09</name>
                            <description>Pmn Event Output Set</description>
                            <lsb>9</lsb>
                            <msb>9</msb>
                            <access>read-write</access>
                            <enumeratedValues>
                                <enumeratedValue>
                                    <name>0</name>
                                    <description>No effect on output</description>
                                    <value>#0</value>
                                </enumeratedValue>
                                <enumeratedValue>
                                    <name>1</name>
                                    <description>High output</description>
                                    <value>#1</value>
                                </enumeratedValue>
                            </enumeratedValues>
                        </field>
                        <field>
                            <name>EOSR10</name>
                            <description>Pmn Event Output Set</description>
                            <lsb>10</lsb>
                            <msb>10</msb>
                            <access>read-write</access>
                            <enumeratedValues>
                                <enumeratedValue>
                                    <name>0</name>
                                    <description>No effect on output</description>
                                    <value>#0</value>
                                </enumeratedValue>
                                <enumeratedValue>
                                    <name>1</name>
                                    <description>High output</description>
                                    <value>#1</value>
                                </enumeratedValue>
                            </enumeratedValues>
                        </field>
                        <field>
                            <name>EOSR11</name>
                            <description>Pmn Event Output Set</description>
                            <lsb>11</lsb>
                            <msb>11</msb>
                            <access>read-write</access>
                            <enumeratedValues>
                                <enumeratedValue>
                                    <name>0</name>
                                    <description>No effect on output</description>
                                    <value>#0</value>
                                </enumeratedValue>
                                <enumeratedValue>
                                    <name>1</name>
                                    <description>High output</description>
                                    <value>#1</value>
                                </enumeratedValue>
                            </enumeratedValues>
                        </field>
                        <field>
                            <name>EOSR12</name>
                            <description>Pmn Event Output Set</description>
                            <lsb>12</lsb>
                            <msb>12</msb>
                            <access>read-write</access>
                            <enumeratedValues>
                                <enumeratedValue>
                                    <name>0</name>
                                    <description>No effect on output</description>
                                    <value>#0</value>
                                </enumeratedValue>
                                <enumeratedValue>
                                    <name>1</name>
                                    <description>High output</description>
                                    <value>#1</value>
                                </enumeratedValue>
                            </enumeratedValues>
                        </field>
                        <field>
                            <name>EOSR13</name>
                            <description>Pmn Event Output Set</description>
                            <lsb>13</lsb>
                            <msb>13</msb>
                            <access>read-write</access>
                            <enumeratedValues>
                                <enumeratedValue>
                                    <name>0</name>
                                    <description>No effect on output</description>
                                    <value>#0</value>
                                </enumeratedValue>
                                <enumeratedValue>
                                    <name>1</name>
                                    <description>High output</description>
                                    <value>#1</value>
                                </enumeratedValue>
                            </enumeratedValues>
                        </field>
                        <field>
                            <name>EOSR14</name>
                            <description>Pmn Event Output Set</description>
                            <lsb>14</lsb>
                            <msb>14</msb>
                            <access>read-write</access>
                            <enumeratedValues>
                                <enumeratedValue>
                                    <name>0</name>
                                    <description>No effect on output</description>
                                    <value>#0</value>
                                </enumeratedValue>
                                <enumeratedValue>
                                    <name>1</name>
                                    <description>High output</description>
                                    <value>#1</value>
                                </enumeratedValue>
                            </enumeratedValues>
                        </field>
                        <field>
                            <name>EOSR15</name>
                            <description>Pmn Event Output Set</description>
                            <lsb>15</lsb>
                            <msb>15</msb>
                            <access>read-write</access>
                            <enumeratedValues>
                                <enumeratedValue>
                                    <name>0</name>
                                    <description>No effect on output</description>
                                    <value>#0</value>
                                </enumeratedValue>
                                <enumeratedValue>
                                    <name>1</name>
                                    <description>High output</description>
                                    <value>#1</value>
                                </enumeratedValue>
                            </enumeratedValues>
                        </field>
                        <field>
                            <name>EORR00</name>
                            <description>Pmn Event Output Reset</description>
                            <lsb>16</lsb>
                            <msb>16</msb>
                            <access>read-write</access>
                            <enumeratedValues>
                                <enumeratedValue>
                                    <name>0</name>
                                    <description>No effect on output</description>
                                    <value>#0</value>
                                </enumeratedValue>
                                <enumeratedValue>
                                    <name>1</name>
                                    <description>Low output</description>
                                    <value>#1</value>
                                </enumeratedValue>
                            </enumeratedValues>
                        </field>
                        <field>
                            <name>EORR01</name>
                            <description>Pmn Event Output Reset</description>
                            <lsb>17</lsb>
                            <msb>17</msb>
                            <access>read-write</access>
                            <enumeratedValues>
                                <enumeratedValue>
                                    <name>0</name>
                                    <description>No effect on output</description>
                                    <value>#0</value>
                                </enumeratedValue>
                                <enumeratedValue>
                                    <name>1</name>
                                    <description>Low output</description>
                                    <value>#1</value>
                                </enumeratedValue>
                            </enumeratedValues>
                        </field>
                        <field>
                            <name>EORR02</name>
                            <description>Pmn Event Output Reset</description>
                            <lsb>18</lsb>
                            <msb>18</msb>
                            <access>read-write</access>
                            <enumeratedValues>
                                <enumeratedValue>
                                    <name>0</name>
                                    <description>No effect on output</description>
                                    <value>#0</value>
                                </enumeratedValue>
                                <enumeratedValue>
                                    <name>1</name>
                                    <description>Low output</description>
                                    <value>#1</value>
                                </enumeratedValue>
                            </enumeratedValues>
                        </field>
                        <field>
                            <name>EORR03</name>
                            <description>Pmn Event Output Reset</description>
                            <lsb>19</lsb>
                            <msb>19</msb>
                            <access>read-write</access>
                            <enumeratedValues>
                                <enumeratedValue>
                                    <name>0</name>
                                    <description>No effect on output</description>
                                    <value>#0</value>
                                </enumeratedValue>
                                <enumeratedValue>
                                    <name>1</name>
                                    <description>Low output</description>
                                    <value>#1</value>
                                </enumeratedValue>
                            </enumeratedValues>
                        </field>
                        <field>
                            <name>EORR04</name>
                            <description>Pmn Event Output Reset</description>
                            <lsb>20</lsb>
                            <msb>20</msb>
                            <access>read-write</access>
                            <enumeratedValues>
                                <enumeratedValue>
                                    <name>0</name>
                                    <description>No effect on output</description>
                                    <value>#0</value>
                                </enumeratedValue>
                                <enumeratedValue>
                                    <name>1</name>
                                    <description>Low output</description>
                                    <value>#1</value>
                                </enumeratedValue>
                            </enumeratedValues>
                        </field>
                        <field>
                            <name>EORR05</name>
                            <description>Pmn Event Output Reset</description>
                            <lsb>21</lsb>
                            <msb>21</msb>
                            <access>read-write</access>
                            <enumeratedValues>
                                <enumeratedValue>
                                    <name>0</name>
                                    <description>No effect on output</description>
                                    <value>#0</value>
                                </enumeratedValue>
                                <enumeratedValue>
                                    <name>1</name>
                                    <description>Low output</description>
                                    <value>#1</value>
                                </enumeratedValue>
                            </enumeratedValues>
                        </field>
                        <field>
                            <name>EORR06</name>
                            <description>Pmn Event Output Reset</description>
                            <lsb>22</lsb>
                            <msb>22</msb>
                            <access>read-write</access>
                            <enumeratedValues>
                                <enumeratedValue>
                                    <name>0</name>
                                    <description>No effect on output</description>
                                    <value>#0</value>
                                </enumeratedValue>
                                <enumeratedValue>
                                    <name>1</name>
                                    <description>Low output</description>
                                    <value>#1</value>
                                </enumeratedValue>
                            </enumeratedValues>
                        </field>
                        <field>
                            <name>EORR07</name>
                            <description>Pmn Event Output Reset</description>
                            <lsb>23</lsb>
                            <msb>23</msb>
                            <access>read-write</access>
                            <enumeratedValues>
                                <enumeratedValue>
                                    <name>0</name>
                                    <description>No effect on output</description>
                                    <value>#0</value>
                                </enumeratedValue>
                                <enumeratedValue>
                                    <name>1</name>
                                    <description>Low output</description>
                                    <value>#1</value>
                                </enumeratedValue>
                            </enumeratedValues>
                        </field>
                        <field>
                            <name>EORR08</name>
                            <description>Pmn Event Output Reset</description>
                            <lsb>24</lsb>
                            <msb>24</msb>
                            <access>read-write</access>
                            <enumeratedValues>
                                <enumeratedValue>
                                    <name>0</name>
                                    <description>No effect on output</description>
                                    <value>#0</value>
                                </enumeratedValue>
                                <enumeratedValue>
                                    <name>1</name>
                                    <description>Low output</description>
                                    <value>#1</value>
                                </enumeratedValue>
                            </enumeratedValues>
                        </field>
                        <field>
                            <name>EORR09</name>
                            <description>Pmn Event Output Reset</description>
                            <lsb>25</lsb>
                            <msb>25</msb>
                            <access>read-write</access>
                            <enumeratedValues>
                                <enumeratedValue>
                                    <name>0</name>
                                    <description>No effect on output</description>
                                    <value>#0</value>
                                </enumeratedValue>
                                <enumeratedValue>
                                    <name>1</name>
                                    <description>Low output</description>
                                    <value>#1</value>
                                </enumeratedValue>
                            </enumeratedValues>
                        </field>
                        <field>
                            <name>EORR10</name>
                            <description>Pmn Event Output Reset</description>
                            <lsb>26</lsb>
                            <msb>26</msb>
                            <access>read-write</access>
                            <enumeratedValues>
                                <enumeratedValue>
                                    <name>0</name>
                                    <description>No effect on output</description>
                                    <value>#0</value>
                                </enumeratedValue>
                                <enumeratedValue>
                                    <name>1</name>
                                    <description>Low output</description>
                                    <value>#1</value>
                                </enumeratedValue>
                            </enumeratedValues>
                        </field>
                        <field>
                            <name>EORR11</name>
                            <description>Pmn Event Output Reset</description>
                            <lsb>27</lsb>
                            <msb>27</msb>
                            <access>read-write</access>
                            <enumeratedValues>
                                <enumeratedValue>
                                    <name>0</name>
                                    <description>No effect on output</description>
                                    <value>#0</value>
                                </enumeratedValue>
                                <enumeratedValue>
                                    <name>1</name>
                                    <description>Low output</description>
                                    <value>#1</value>
                                </enumeratedValue>
                            </enumeratedValues>
                        </field>
                        <field>
                            <name>EORR12</name>
                            <description>Pmn Event Output Reset</description>
                            <lsb>28</lsb>
                            <msb>28</msb>
                            <access>read-write</access>
                            <enumeratedValues>
                                <enumeratedValue>
                                    <name>0</name>
                                    <description>No effect on output</description>
                                    <value>#0</value>
                                </enumeratedValue>
                                <enumeratedValue>
                                    <name>1</name>
                                    <description>Low output</description>
                                    <value>#1</value>
                                </enumeratedValue>
                            </enumeratedValues>
                        </field>
                        <field>
                            <name>EORR13</name>
                            <description>Pmn Event Output Reset</description>
                            <lsb>29</lsb>
                            <msb>29</msb>
                            <access>read-write</access>
                            <enumeratedValues>
                                <enumeratedValue>
                                    <name>0</name>
                                    <description>No effect on output</description>
                                    <value>#0</value>
                                </enumeratedValue>
                                <enumeratedValue>
                                    <name>1</name>
                                    <description>Low output</description>
                                    <value>#1</value>
                                </enumeratedValue>
                            </enumeratedValues>
                        </field>
                        <field>
                            <name>EORR14</name>
                            <description>Pmn Event Output Reset</description>
                            <lsb>30</lsb>
                            <msb>30</msb>
                            <access>read-write</access>
                            <enumeratedValues>
                                <enumeratedValue>
                                    <name>0</name>
                                    <description>No effect on output</description>
                                    <value>#0</value>
                                </enumeratedValue>
                                <enumeratedValue>
                                    <name>1</name>
                                    <description>Low output</description>
                                    <value>#1</value>
                                </enumeratedValue>
                            </enumeratedValues>
                        </field>
                        <field>
                            <name>EORR15</name>
                            <description>Pmn Event Output Reset</description>
                            <lsb>31</lsb>
                            <msb>31</msb>
                            <access>read-write</access>
                            <enumeratedValues>
                                <enumeratedValue>
                                    <name>0</name>
                                    <description>No effect on output</description>
                                    <value>#0</value>
                                </enumeratedValue>
                                <enumeratedValue>
                                    <name>1</name>
                                    <description>Low output</description>
                                    <value>#1</value>
                                </enumeratedValue>
                            </enumeratedValues>
                        </field>
                    </fields>
                </register>
                <register>
                    <name>EOSR</name>
                    <description>Port Control Register 4</description>
                    <alternateRegister>PCNTR4</alternateRegister>
                    <addressOffset>0x00C</addressOffset>
                    <size>16</size>
                    <access>read-write</access>
                    <resetValue>0x0000</resetValue>
                    <resetMask>0xffff</resetMask>
                    <fields>
                        <field>
                            <name>EORR00</name>
                            <description>Pmn Event Output Reset</description>
                            <lsb>0</lsb>
                            <msb>0</msb>
                            <access>read-write</access>
                            <enumeratedValues>
                                <enumeratedValue>
                                    <name>0</name>
                                    <description>No effect on output</description>
                                    <value>#0</value>
                                </enumeratedValue>
                                <enumeratedValue>
                                    <name>1</name>
                                    <description>Low output</description>
                                    <value>#1</value>
                                </enumeratedValue>
                            </enumeratedValues>
                        </field>
                        <field>
                            <name>EORR01</name>
                            <description>Pmn Event Output Reset</description>
                            <lsb>1</lsb>
                            <msb>1</msb>
                            <access>read-write</access>
                            <enumeratedValues>
                                <enumeratedValue>
                                    <name>0</name>
                                    <description>No effect on output</description>
                                    <value>#0</value>
                                </enumeratedValue>
                                <enumeratedValue>
                                    <name>1</name>
                                    <description>Low output</description>
                                    <value>#1</value>
                                </enumeratedValue>
                            </enumeratedValues>
                        </field>
                        <field>
                            <name>EORR02</name>
                            <description>Pmn Event Output Reset</description>
                            <lsb>2</lsb>
                            <msb>2</msb>
                            <access>read-write</access>
                            <enumeratedValues>
                                <enumeratedValue>
                                    <name>0</name>
                                    <description>No effect on output</description>
                                    <value>#0</value>
                                </enumeratedValue>
                                <enumeratedValue>
                                    <name>1</name>
                                    <description>Low output</description>
                                    <value>#1</value>
                                </enumeratedValue>
                            </enumeratedValues>
                        </field>
                        <field>
                            <name>EORR03</name>
                            <description>Pmn Event Output Reset</description>
                            <lsb>3</lsb>
                            <msb>3</msb>
                            <access>read-write</access>
                            <enumeratedValues>
                                <enumeratedValue>
                                    <name>0</name>
                                    <description>No effect on output</description>
                                    <value>#0</value>
                                </enumeratedValue>
                                <enumeratedValue>
                                    <name>1</name>
                                    <description>Low output</description>
                                    <value>#1</value>
                                </enumeratedValue>
                            </enumeratedValues>
                        </field>
                        <field>
                            <name>EORR04</name>
                            <description>Pmn Event Output Reset</description>
                            <lsb>4</lsb>
                            <msb>4</msb>
                            <access>read-write</access>
                            <enumeratedValues>
                                <enumeratedValue>
                                    <name>0</name>
                                    <description>No effect on output</description>
                                    <value>#0</value>
                                </enumeratedValue>
                                <enumeratedValue>
                                    <name>1</name>
                                    <description>Low output</description>
                                    <value>#1</value>
                                </enumeratedValue>
                            </enumeratedValues>
                        </field>
                        <field>
                            <name>EORR05</name>
                            <description>Pmn Event Output Reset</description>
                            <lsb>5</lsb>
                            <msb>5</msb>
                            <access>read-write</access>
                            <enumeratedValues>
                                <enumeratedValue>
                                    <name>0</name>
                                    <description>No effect on output</description>
                                    <value>#0</value>
                                </enumeratedValue>
                                <enumeratedValue>
                                    <name>1</name>
                                    <description>Low output</description>
                                    <value>#1</value>
                                </enumeratedValue>
                            </enumeratedValues>
                        </field>
                        <field>
                            <name>EORR06</name>
                            <description>Pmn Event Output Reset</description>
                            <lsb>6</lsb>
                            <msb>6</msb>
                            <access>read-write</access>
                            <enumeratedValues>
                                <enumeratedValue>
                                    <name>0</name>
                                    <description>No effect on output</description>
                                    <value>#0</value>
                                </enumeratedValue>
                                <enumeratedValue>
                                    <name>1</name>
                                    <description>Low output</description>
                                    <value>#1</value>
                                </enumeratedValue>
                            </enumeratedValues>
                        </field>
                        <field>
                            <name>EORR07</name>
                            <description>Pmn Event Output Reset</description>
                            <lsb>7</lsb>
                            <msb>7</msb>
                            <access>read-write</access>
                            <enumeratedValues>
                                <enumeratedValue>
                                    <name>0</name>
                                    <description>No effect on output</description>
                                    <value>#0</value>
                                </enumeratedValue>
                                <enumeratedValue>
                                    <name>1</name>
                                    <description>Low output</description>
                                    <value>#1</value>
                                </enumeratedValue>
                            </enumeratedValues>
                        </field>
                        <field>
                            <name>EORR08</name>
                            <description>Pmn Event Output Reset</description>
                            <lsb>8</lsb>
                            <msb>8</msb>
                            <access>read-write</access>
                            <enumeratedValues>
                                <enumeratedValue>
                                    <name>0</name>
                                    <description>No effect on output</description>
                                    <value>#0</value>
                                </enumeratedValue>
                                <enumeratedValue>
                                    <name>1</name>
                                    <description>Low output</description>
                                    <value>#1</value>
                                </enumeratedValue>
                            </enumeratedValues>
                        </field>
                        <field>
                            <name>EORR09</name>
                            <description>Pmn Event Output Reset</description>
                            <lsb>9</lsb>
                            <msb>9</msb>
                            <access>read-write</access>
                            <enumeratedValues>
                                <enumeratedValue>
                                    <name>0</name>
                                    <description>No effect on output</description>
                                    <value>#0</value>
                                </enumeratedValue>
                                <enumeratedValue>
                                    <name>1</name>
                                    <description>Low output</description>
                                    <value>#1</value>
                                </enumeratedValue>
                            </enumeratedValues>
                        </field>
                        <field>
                            <name>EORR10</name>
                            <description>Pmn Event Output Reset</description>
                            <lsb>10</lsb>
                            <msb>10</msb>
                            <access>read-write</access>
                            <enumeratedValues>
                                <enumeratedValue>
                                    <name>0</name>
                                    <description>No effect on output</description>
                                    <value>#0</value>
                                </enumeratedValue>
                                <enumeratedValue>
                                    <name>1</name>
                                    <description>Low output</description>
                                    <value>#1</value>
                                </enumeratedValue>
                            </enumeratedValues>
                        </field>
                        <field>
                            <name>EORR11</name>
                            <description>Pmn Event Output Reset</description>
                            <lsb>11</lsb>
                            <msb>11</msb>
                            <access>read-write</access>
                            <enumeratedValues>
                                <enumeratedValue>
                                    <name>0</name>
                                    <description>No effect on output</description>
                                    <value>#0</value>
                                </enumeratedValue>
                                <enumeratedValue>
                                    <name>1</name>
                                    <description>Low output</description>
                                    <value>#1</value>
                                </enumeratedValue>
                            </enumeratedValues>
                        </field>
                        <field>
                            <name>EORR12</name>
                            <description>Pmn Event Output Reset</description>
                            <lsb>12</lsb>
                            <msb>12</msb>
                            <access>read-write</access>
                            <enumeratedValues>
                                <enumeratedValue>
                                    <name>0</name>
                                    <description>No effect on output</description>
                                    <value>#0</value>
                                </enumeratedValue>
                                <enumeratedValue>
                                    <name>1</name>
                                    <description>Low output</description>
                                    <value>#1</value>
                                </enumeratedValue>
                            </enumeratedValues>
                        </field>
                        <field>
                            <name>EORR13</name>
                            <description>Pmn Event Output Reset</description>
                            <lsb>13</lsb>
                            <msb>13</msb>
                            <access>read-write</access>
                            <enumeratedValues>
                                <enumeratedValue>
                                    <name>0</name>
                                    <description>No effect on output</description>
                                    <value>#0</value>
                                </enumeratedValue>
                                <enumeratedValue>
                                    <name>1</name>
                                    <description>Low output</description>
                                    <value>#1</value>
                                </enumeratedValue>
                            </enumeratedValues>
                        </field>
                        <field>
                            <name>EORR14</name>
                            <description>Pmn Event Output Reset</description>
                            <lsb>14</lsb>
                            <msb>14</msb>
                            <access>read-write</access>
                            <enumeratedValues>
                                <enumeratedValue>
                                    <name>0</name>
                                    <description>No effect on output</description>
                                    <value>#0</value>
                                </enumeratedValue>
                                <enumeratedValue>
                                    <name>1</name>
                                    <description>Low output</description>
                                    <value>#1</value>
                                </enumeratedValue>
                            </enumeratedValues>
                        </field>
                        <field>
                            <name>EORR15</name>
                            <description>Pmn Event Output Reset</description>
                            <lsb>15</lsb>
                            <msb>15</msb>
                            <access>read-write</access>
                            <enumeratedValues>
                                <enumeratedValue>
                                    <name>0</name>
                                    <description>No effect on output</description>
                                    <value>#0</value>
                                </enumeratedValue>
                                <enumeratedValue>
                                    <name>1</name>
                                    <description>Low output</description>
                                    <value>#1</value>
                                </enumeratedValue>
                            </enumeratedValues>
                        </field>
                    </fields>
                </register>
                <register>
                    <name>EORR</name>
                    <description>Port Control Register 4</description>
                    <alternateRegister>PCNTR4</alternateRegister>
                    <addressOffset>0x00E</addressOffset>
                    <size>16</size>
                    <access>read-write</access>
                    <resetValue>0x0000</resetValue>
                    <resetMask>0xffff</resetMask>
                    <fields>
                        <field>
                            <name>EOSR00</name>
                            <description>Pmn Event Output Set</description>
                            <lsb>0</lsb>
                            <msb>0</msb>
                            <access>read-write</access>
                            <enumeratedValues>
                                <enumeratedValue>
                                    <name>0</name>
                                    <description>No effect on output</description>
                                    <value>#0</value>
                                </enumeratedValue>
                                <enumeratedValue>
                                    <name>1</name>
                                    <description>High output</description>
                                    <value>#1</value>
                                </enumeratedValue>
                            </enumeratedValues>
                        </field>
                        <field>
                            <name>EOSR01</name>
                            <description>Pmn Event Output Set</description>
                            <lsb>1</lsb>
                            <msb>1</msb>
                            <access>read-write</access>
                            <enumeratedValues>
                                <enumeratedValue>
                                    <name>0</name>
                                    <description>No effect on output</description>
                                    <value>#0</value>
                                </enumeratedValue>
                                <enumeratedValue>
                                    <name>1</name>
                                    <description>High output</description>
                                    <value>#1</value>
                                </enumeratedValue>
                            </enumeratedValues>
                        </field>
                        <field>
                            <name>EOSR02</name>
                            <description>Pmn Event Output Set</description>
                            <lsb>2</lsb>
                            <msb>2</msb>
                            <access>read-write</access>
                            <enumeratedValues>
                                <enumeratedValue>
                                    <name>0</name>
                                    <description>No effect on output</description>
                                    <value>#0</value>
                                </enumeratedValue>
                                <enumeratedValue>
                                    <name>1</name>
                                    <description>High output</description>
                                    <value>#1</value>
                                </enumeratedValue>
                            </enumeratedValues>
                        </field>
                        <field>
                            <name>EOSR03</name>
                            <description>Pmn Event Output Set</description>
                            <lsb>3</lsb>
                            <msb>3</msb>
                            <access>read-write</access>
                            <enumeratedValues>
                                <enumeratedValue>
                                    <name>0</name>
                                    <description>No effect on output</description>
                                    <value>#0</value>
                                </enumeratedValue>
                                <enumeratedValue>
                                    <name>1</name>
                                    <description>High output</description>
                                    <value>#1</value>
                                </enumeratedValue>
                            </enumeratedValues>
                        </field>
                        <field>
                            <name>EOSR04</name>
                            <description>Pmn Event Output Set</description>
                            <lsb>4</lsb>
                            <msb>4</msb>
                            <access>read-write</access>
                            <enumeratedValues>
                                <enumeratedValue>
                                    <name>0</name>
                                    <description>No effect on output</description>
                                    <value>#0</value>
                                </enumeratedValue>
                                <enumeratedValue>
                                    <name>1</name>
                                    <description>High output</description>
                                    <value>#1</value>
                                </enumeratedValue>
                            </enumeratedValues>
                        </field>
                        <field>
                            <name>EOSR05</name>
                            <description>Pmn Event Output Set</description>
                            <lsb>5</lsb>
                            <msb>5</msb>
                            <access>read-write</access>
                            <enumeratedValues>
                                <enumeratedValue>
                                    <name>0</name>
                                    <description>No effect on output</description>
                                    <value>#0</value>
                                </enumeratedValue>
                                <enumeratedValue>
                                    <name>1</name>
                                    <description>High output</description>
                                    <value>#1</value>
                                </enumeratedValue>
                            </enumeratedValues>
                        </field>
                        <field>
                            <name>EOSR06</name>
                            <description>Pmn Event Output Set</description>
                            <lsb>6</lsb>
                            <msb>6</msb>
                            <access>read-write</access>
                            <enumeratedValues>
                                <enumeratedValue>
                                    <name>0</name>
                                    <description>No effect on output</description>
                                    <value>#0</value>
                                </enumeratedValue>
                                <enumeratedValue>
                                    <name>1</name>
                                    <description>High output</description>
                                    <value>#1</value>
                                </enumeratedValue>
                            </enumeratedValues>
                        </field>
                        <field>
                            <name>EOSR07</name>
                            <description>Pmn Event Output Set</description>
                            <lsb>7</lsb>
                            <msb>7</msb>
                            <access>read-write</access>
                            <enumeratedValues>
                                <enumeratedValue>
                                    <name>0</name>
                                    <description>No effect on output</description>
                                    <value>#0</value>
                                </enumeratedValue>
                                <enumeratedValue>
                                    <name>1</name>
                                    <description>High output</description>
                                    <value>#1</value>
                                </enumeratedValue>
                            </enumeratedValues>
                        </field>
                        <field>
                            <name>EOSR08</name>
                            <description>Pmn Event Output Set</description>
                            <lsb>8</lsb>
                            <msb>8</msb>
                            <access>read-write</access>
                            <enumeratedValues>
                                <enumeratedValue>
                                    <name>0</name>
                                    <description>No effect on output</description>
                                    <value>#0</value>
                                </enumeratedValue>
                                <enumeratedValue>
                                    <name>1</name>
                                    <description>High output</description>
                                    <value>#1</value>
                                </enumeratedValue>
                            </enumeratedValues>
                        </field>
                        <field>
                            <name>EOSR09</name>
                            <description>Pmn Event Output Set</description>
                            <lsb>9</lsb>
                            <msb>9</msb>
                            <access>read-write</access>
                            <enumeratedValues>
                                <enumeratedValue>
                                    <name>0</name>
                                    <description>No effect on output</description>
                                    <value>#0</value>
                                </enumeratedValue>
                                <enumeratedValue>
                                    <name>1</name>
                                    <description>High output</description>
                                    <value>#1</value>
                                </enumeratedValue>
                            </enumeratedValues>
                        </field>
                        <field>
                            <name>EOSR10</name>
                            <description>Pmn Event Output Set</description>
                            <lsb>10</lsb>
                            <msb>10</msb>
                            <access>read-write</access>
                            <enumeratedValues>
                                <enumeratedValue>
                                    <name>0</name>
                                    <description>No effect on output</description>
                                    <value>#0</value>
                                </enumeratedValue>
                                <enumeratedValue>
                                    <name>1</name>
                                    <description>High output</description>
                                    <value>#1</value>
                                </enumeratedValue>
                            </enumeratedValues>
                        </field>
                        <field>
                            <name>EOSR11</name>
                            <description>Pmn Event Output Set</description>
                            <lsb>11</lsb>
                            <msb>11</msb>
                            <access>read-write</access>
                            <enumeratedValues>
                                <enumeratedValue>
                                    <name>0</name>
                                    <description>No effect on output</description>
                                    <value>#0</value>
                                </enumeratedValue>
                                <enumeratedValue>
                                    <name>1</name>
                                    <description>High output</description>
                                    <value>#1</value>
                                </enumeratedValue>
                            </enumeratedValues>
                        </field>
                        <field>
                            <name>EOSR12</name>
                            <description>Pmn Event Output Set</description>
                            <lsb>12</lsb>
                            <msb>12</msb>
                            <access>read-write</access>
                            <enumeratedValues>
                                <enumeratedValue>
                                    <name>0</name>
                                    <description>No effect on output</description>
                                    <value>#0</value>
                                </enumeratedValue>
                                <enumeratedValue>
                                    <name>1</name>
                                    <description>High output</description>
                                    <value>#1</value>
                                </enumeratedValue>
                            </enumeratedValues>
                        </field>
                        <field>
                            <name>EOSR13</name>
                            <description>Pmn Event Output Set</description>
                            <lsb>13</lsb>
                            <msb>13</msb>
                            <access>read-write</access>
                            <enumeratedValues>
                                <enumeratedValue>
                                    <name>0</name>
                                    <description>No effect on output</description>
                                    <value>#0</value>
                                </enumeratedValue>
                                <enumeratedValue>
                                    <name>1</name>
                                    <description>High output</description>
                                    <value>#1</value>
                                </enumeratedValue>
                            </enumeratedValues>
                        </field>
                        <field>
                            <name>EOSR14</name>
                            <description>Pmn Event Output Set</description>
                            <lsb>14</lsb>
                            <msb>14</msb>
                            <access>read-write</access>
                            <enumeratedValues>
                                <enumeratedValue>
                                    <name>0</name>
                                    <description>No effect on output</description>
                                    <value>#0</value>
                                </enumeratedValue>
                                <enumeratedValue>
                                    <name>1</name>
                                    <description>High output</description>
                                    <value>#1</value>
                                </enumeratedValue>
                            </enumeratedValues>
                        </field>
                        <field>
                            <name>EOSR15</name>
                            <description>Pmn Event Output Set</description>
                            <lsb>15</lsb>
                            <msb>15</msb>
                            <access>read-write</access>
                            <enumeratedValues>
                                <enumeratedValue>
                                    <name>0</name>
                                    <description>No effect on output</description>
                                    <value>#0</value>
                                </enumeratedValue>
                                <enumeratedValue>
                                    <name>1</name>
                                    <description>High output</description>
                                    <value>#1</value>
                                </enumeratedValue>
                            </enumeratedValues>
                        </field>
                    </fields>
                </register>
            </registers>
        </peripheral>
        <peripheral derivedFrom="PORT1">
            <name>PORT2</name>
            <description>Pmn Pin Function Port 2 Control Registers Pmn Pin Function Control Register</description>
            <baseAddress>0x40400040</baseAddress>
        </peripheral>
        <peripheral derivedFrom="PORT1">
            <name>PORT3</name>
            <description>Pmn Pin Function Port 3 Control Registers Pmn Pin Function Control Register</description>
            <baseAddress>0x40400060</baseAddress>
        </peripheral>
        <peripheral derivedFrom="PORT1">
            <name>PORT4</name>
            <description>Pmn Pin Function Port 4 Control Registers Pmn Pin Function Control Register</description>
            <baseAddress>0x40400080</baseAddress>
        </peripheral>
        <peripheral derivedFrom="PORT0">
            <name>PORT5</name>
            <description>Pmn Pin Function Port 5 Control Registers Pmn Pin Function Control Register</description>
            <baseAddress>0x404000A0</baseAddress>
        </peripheral>
        <peripheral derivedFrom="PORT0">
            <name>PORT6</name>
            <description>Pmn Pin Function Port 6 Control Registers Pmn Pin Function Control Register</description>
            <baseAddress>0x404000C0</baseAddress>
        </peripheral>
        <peripheral derivedFrom="PORT0">
            <name>PORT7</name>
            <description>Pmn Pin Function Port 7 Control Registers Pmn Pin Function Control Register</description>
            <baseAddress>0x404000E0</baseAddress>
        </peripheral>
        <peripheral derivedFrom="PORT0">
            <name>PORT8</name>
            <description>Pmn Pin Function Port 8 Control Registers Pmn Pin Function Control Register</description>
            <baseAddress>0x40400100</baseAddress>
        </peripheral>
        <peripheral derivedFrom="PORT0">
            <name>PORT9</name>
            <description>Pmn Pin Function Port 9 Control Registers Pmn Pin Function Control Register</description>
            <baseAddress>0x40400120</baseAddress>
        </peripheral>
        <peripheral>
            <name>PORTA</name>
            <description>Pmn Pin Function Port A Control Registers Pmn Pin Function Control Register</description>
            <baseAddress>0x40400140</baseAddress>
            <addressBlock>
                <offset>0x00</offset>
                <size>8</size>
                <usage>registers</usage>
            </addressBlock>
            <addressBlock>
                <offset>0x08</offset>
                <size>4</size>
                <usage>registers</usage>
            </addressBlock>
            <registers>
                <register>
                    <name>PCNTR1</name>
                    <description>Port Control Register 1</description>
                    <addressOffset>0x000</addressOffset>
                    <size>32</size>
                    <access>read-write</access>
                    <resetValue>0x00000000</resetValue>
                    <resetMask>0xffffffff</resetMask>
                    <fields>
                        <field>
                            <name>PDR00</name>
                            <description>Pmn Direction</description>
                            <lsb>0</lsb>
                            <msb>0</msb>
                            <access>read-write</access>
                            <enumeratedValues>
                                <enumeratedValue>
                                    <name>0</name>
                                    <description>Input (functions as an input pin)</description>
                                    <value>#0</value>
                                </enumeratedValue>
                                <enumeratedValue>
                                    <name>1</name>
                                    <description>Output (functions as an output pin)</description>
                                    <value>#1</value>
                                </enumeratedValue>
                            </enumeratedValues>
                        </field>
                        <field>
                            <name>PDR01</name>
                            <description>Pmn Direction</description>
                            <lsb>1</lsb>
                            <msb>1</msb>
                            <access>read-write</access>
                            <enumeratedValues>
                                <enumeratedValue>
                                    <name>0</name>
                                    <description>Input (functions as an input pin)</description>
                                    <value>#0</value>
                                </enumeratedValue>
                                <enumeratedValue>
                                    <name>1</name>
                                    <description>Output (functions as an output pin)</description>
                                    <value>#1</value>
                                </enumeratedValue>
                            </enumeratedValues>
                        </field>
                        <field>
                            <name>PDR02</name>
                            <description>Pmn Direction</description>
                            <lsb>2</lsb>
                            <msb>2</msb>
                            <access>read-write</access>
                            <enumeratedValues>
                                <enumeratedValue>
                                    <name>0</name>
                                    <description>Input (functions as an input pin)</description>
                                    <value>#0</value>
                                </enumeratedValue>
                                <enumeratedValue>
                                    <name>1</name>
                                    <description>Output (functions as an output pin)</description>
                                    <value>#1</value>
                                </enumeratedValue>
                            </enumeratedValues>
                        </field>
                        <field>
                            <name>PDR03</name>
                            <description>Pmn Direction</description>
                            <lsb>3</lsb>
                            <msb>3</msb>
                            <access>read-write</access>
                            <enumeratedValues>
                                <enumeratedValue>
                                    <name>0</name>
                                    <description>Input (functions as an input pin)</description>
                                    <value>#0</value>
                                </enumeratedValue>
                                <enumeratedValue>
                                    <name>1</name>
                                    <description>Output (functions as an output pin)</description>
                                    <value>#1</value>
                                </enumeratedValue>
                            </enumeratedValues>
                        </field>
                        <field>
                            <name>PDR04</name>
                            <description>Pmn Direction</description>
                            <lsb>4</lsb>
                            <msb>4</msb>
                            <access>read-write</access>
                            <enumeratedValues>
                                <enumeratedValue>
                                    <name>0</name>
                                    <description>Input (functions as an input pin)</description>
                                    <value>#0</value>
                                </enumeratedValue>
                                <enumeratedValue>
                                    <name>1</name>
                                    <description>Output (functions as an output pin)</description>
                                    <value>#1</value>
                                </enumeratedValue>
                            </enumeratedValues>
                        </field>
                        <field>
                            <name>PDR05</name>
                            <description>Pmn Direction</description>
                            <lsb>5</lsb>
                            <msb>5</msb>
                            <access>read-write</access>
                            <enumeratedValues>
                                <enumeratedValue>
                                    <name>0</name>
                                    <description>Input (functions as an input pin)</description>
                                    <value>#0</value>
                                </enumeratedValue>
                                <enumeratedValue>
                                    <name>1</name>
                                    <description>Output (functions as an output pin)</description>
                                    <value>#1</value>
                                </enumeratedValue>
                            </enumeratedValues>
                        </field>
                        <field>
                            <name>PDR06</name>
                            <description>Pmn Direction</description>
                            <lsb>6</lsb>
                            <msb>6</msb>
                            <access>read-write</access>
                            <enumeratedValues>
                                <enumeratedValue>
                                    <name>0</name>
                                    <description>Input (functions as an input pin)</description>
                                    <value>#0</value>
                                </enumeratedValue>
                                <enumeratedValue>
                                    <name>1</name>
                                    <description>Output (functions as an output pin)</description>
                                    <value>#1</value>
                                </enumeratedValue>
                            </enumeratedValues>
                        </field>
                        <field>
                            <name>PDR07</name>
                            <description>Pmn Direction</description>
                            <lsb>7</lsb>
                            <msb>7</msb>
                            <access>read-write</access>
                            <enumeratedValues>
                                <enumeratedValue>
                                    <name>0</name>
                                    <description>Input (functions as an input pin)</description>
                                    <value>#0</value>
                                </enumeratedValue>
                                <enumeratedValue>
                                    <name>1</name>
                                    <description>Output (functions as an output pin)</description>
                                    <value>#1</value>
                                </enumeratedValue>
                            </enumeratedValues>
                        </field>
                        <field>
                            <name>PDR08</name>
                            <description>Pmn Direction</description>
                            <lsb>8</lsb>
                            <msb>8</msb>
                            <access>read-write</access>
                            <enumeratedValues>
                                <enumeratedValue>
                                    <name>0</name>
                                    <description>Input (functions as an input pin)</description>
                                    <value>#0</value>
                                </enumeratedValue>
                                <enumeratedValue>
                                    <name>1</name>
                                    <description>Output (functions as an output pin)</description>
                                    <value>#1</value>
                                </enumeratedValue>
                            </enumeratedValues>
                        </field>
                        <field>
                            <name>PDR09</name>
                            <description>Pmn Direction</description>
                            <lsb>9</lsb>
                            <msb>9</msb>
                            <access>read-write</access>
                            <enumeratedValues>
                                <enumeratedValue>
                                    <name>0</name>
                                    <description>Input (functions as an input pin)</description>
                                    <value>#0</value>
                                </enumeratedValue>
                                <enumeratedValue>
                                    <name>1</name>
                                    <description>Output (functions as an output pin)</description>
                                    <value>#1</value>
                                </enumeratedValue>
                            </enumeratedValues>
                        </field>
                        <field>
                            <name>PDR10</name>
                            <description>Pmn Direction</description>
                            <lsb>10</lsb>
                            <msb>10</msb>
                            <access>read-write</access>
                            <enumeratedValues>
                                <enumeratedValue>
                                    <name>0</name>
                                    <description>Input (functions as an input pin)</description>
                                    <value>#0</value>
                                </enumeratedValue>
                                <enumeratedValue>
                                    <name>1</name>
                                    <description>Output (functions as an output pin)</description>
                                    <value>#1</value>
                                </enumeratedValue>
                            </enumeratedValues>
                        </field>
                        <field>
                            <name>PDR11</name>
                            <description>Pmn Direction</description>
                            <lsb>11</lsb>
                            <msb>11</msb>
                            <access>read-write</access>
                            <enumeratedValues>
                                <enumeratedValue>
                                    <name>0</name>
                                    <description>Input (functions as an input pin)</description>
                                    <value>#0</value>
                                </enumeratedValue>
                                <enumeratedValue>
                                    <name>1</name>
                                    <description>Output (functions as an output pin)</description>
                                    <value>#1</value>
                                </enumeratedValue>
                            </enumeratedValues>
                        </field>
                        <field>
                            <name>PDR12</name>
                            <description>Pmn Direction</description>
                            <lsb>12</lsb>
                            <msb>12</msb>
                            <access>read-write</access>
                            <enumeratedValues>
                                <enumeratedValue>
                                    <name>0</name>
                                    <description>Input (functions as an input pin)</description>
                                    <value>#0</value>
                                </enumeratedValue>
                                <enumeratedValue>
                                    <name>1</name>
                                    <description>Output (functions as an output pin)</description>
                                    <value>#1</value>
                                </enumeratedValue>
                            </enumeratedValues>
                        </field>
                        <field>
                            <name>PDR13</name>
                            <description>Pmn Direction</description>
                            <lsb>13</lsb>
                            <msb>13</msb>
                            <access>read-write</access>
                            <enumeratedValues>
                                <enumeratedValue>
                                    <name>0</name>
                                    <description>Input (functions as an input pin)</description>
                                    <value>#0</value>
                                </enumeratedValue>
                                <enumeratedValue>
                                    <name>1</name>
                                    <description>Output (functions as an output pin)</description>
                                    <value>#1</value>
                                </enumeratedValue>
                            </enumeratedValues>
                        </field>
                        <field>
                            <name>PDR14</name>
                            <description>Pmn Direction</description>
                            <lsb>14</lsb>
                            <msb>14</msb>
                            <access>read-write</access>
                            <enumeratedValues>
                                <enumeratedValue>
                                    <name>0</name>
                                    <description>Input (functions as an input pin)</description>
                                    <value>#0</value>
                                </enumeratedValue>
                                <enumeratedValue>
                                    <name>1</name>
                                    <description>Output (functions as an output pin)</description>
                                    <value>#1</value>
                                </enumeratedValue>
                            </enumeratedValues>
                        </field>
                        <field>
                            <name>PDR15</name>
                            <description>Pmn Direction</description>
                            <lsb>15</lsb>
                            <msb>15</msb>
                            <access>read-write</access>
                            <enumeratedValues>
                                <enumeratedValue>
                                    <name>0</name>
                                    <description>Input (functions as an input pin)</description>
                                    <value>#0</value>
                                </enumeratedValue>
                                <enumeratedValue>
                                    <name>1</name>
                                    <description>Output (functions as an output pin)</description>
                                    <value>#1</value>
                                </enumeratedValue>
                            </enumeratedValues>
                        </field>
                        <field>
                            <name>PODR00</name>
                            <description>Pmn Output Data</description>
                            <lsb>16</lsb>
                            <msb>16</msb>
                            <access>read-write</access>
                            <enumeratedValues>
                                <enumeratedValue>
                                    <name>0</name>
                                    <description>Low output</description>
                                    <value>#0</value>
                                </enumeratedValue>
                                <enumeratedValue>
                                    <name>1</name>
                                    <description>High output</description>
                                    <value>#1</value>
                                </enumeratedValue>
                            </enumeratedValues>
                        </field>
                        <field>
                            <name>PODR01</name>
                            <description>Pmn Output Data</description>
                            <lsb>17</lsb>
                            <msb>17</msb>
                            <access>read-write</access>
                            <enumeratedValues>
                                <enumeratedValue>
                                    <name>0</name>
                                    <description>Low output</description>
                                    <value>#0</value>
                                </enumeratedValue>
                                <enumeratedValue>
                                    <name>1</name>
                                    <description>High output</description>
                                    <value>#1</value>
                                </enumeratedValue>
                            </enumeratedValues>
                        </field>
                        <field>
                            <name>PODR02</name>
                            <description>Pmn Output Data</description>
                            <lsb>18</lsb>
                            <msb>18</msb>
                            <access>read-write</access>
                            <enumeratedValues>
                                <enumeratedValue>
                                    <name>0</name>
                                    <description>Low output</description>
                                    <value>#0</value>
                                </enumeratedValue>
                                <enumeratedValue>
                                    <name>1</name>
                                    <description>High output</description>
                                    <value>#1</value>
                                </enumeratedValue>
                            </enumeratedValues>
                        </field>
                        <field>
                            <name>PODR03</name>
                            <description>Pmn Output Data</description>
                            <lsb>19</lsb>
                            <msb>19</msb>
                            <access>read-write</access>
                            <enumeratedValues>
                                <enumeratedValue>
                                    <name>0</name>
                                    <description>Low output</description>
                                    <value>#0</value>
                                </enumeratedValue>
                                <enumeratedValue>
                                    <name>1</name>
                                    <description>High output</description>
                                    <value>#1</value>
                                </enumeratedValue>
                            </enumeratedValues>
                        </field>
                        <field>
                            <name>PODR04</name>
                            <description>Pmn Output Data</description>
                            <lsb>20</lsb>
                            <msb>20</msb>
                            <access>read-write</access>
                            <enumeratedValues>
                                <enumeratedValue>
                                    <name>0</name>
                                    <description>Low output</description>
                                    <value>#0</value>
                                </enumeratedValue>
                                <enumeratedValue>
                                    <name>1</name>
                                    <description>High output</description>
                                    <value>#1</value>
                                </enumeratedValue>
                            </enumeratedValues>
                        </field>
                        <field>
                            <name>PODR05</name>
                            <description>Pmn Output Data</description>
                            <lsb>21</lsb>
                            <msb>21</msb>
                            <access>read-write</access>
                            <enumeratedValues>
                                <enumeratedValue>
                                    <name>0</name>
                                    <description>Low output</description>
                                    <value>#0</value>
                                </enumeratedValue>
                                <enumeratedValue>
                                    <name>1</name>
                                    <description>High output</description>
                                    <value>#1</value>
                                </enumeratedValue>
                            </enumeratedValues>
                        </field>
                        <field>
                            <name>PODR06</name>
                            <description>Pmn Output Data</description>
                            <lsb>22</lsb>
                            <msb>22</msb>
                            <access>read-write</access>
                            <enumeratedValues>
                                <enumeratedValue>
                                    <name>0</name>
                                    <description>Low output</description>
                                    <value>#0</value>
                                </enumeratedValue>
                                <enumeratedValue>
                                    <name>1</name>
                                    <description>High output</description>
                                    <value>#1</value>
                                </enumeratedValue>
                            </enumeratedValues>
                        </field>
                        <field>
                            <name>PODR07</name>
                            <description>Pmn Output Data</description>
                            <lsb>23</lsb>
                            <msb>23</msb>
                            <access>read-write</access>
                            <enumeratedValues>
                                <enumeratedValue>
                                    <name>0</name>
                                    <description>Low output</description>
                                    <value>#0</value>
                                </enumeratedValue>
                                <enumeratedValue>
                                    <name>1</name>
                                    <description>High output</description>
                                    <value>#1</value>
                                </enumeratedValue>
                            </enumeratedValues>
                        </field>
                        <field>
                            <name>PODR08</name>
                            <description>Pmn Output Data</description>
                            <lsb>24</lsb>
                            <msb>24</msb>
                            <access>read-write</access>
                            <enumeratedValues>
                                <enumeratedValue>
                                    <name>0</name>
                                    <description>Low output</description>
                                    <value>#0</value>
                                </enumeratedValue>
                                <enumeratedValue>
                                    <name>1</name>
                                    <description>High output</description>
                                    <value>#1</value>
                                </enumeratedValue>
                            </enumeratedValues>
                        </field>
                        <field>
                            <name>PODR09</name>
                            <description>Pmn Output Data</description>
                            <lsb>25</lsb>
                            <msb>25</msb>
                            <access>read-write</access>
                            <enumeratedValues>
                                <enumeratedValue>
                                    <name>0</name>
                                    <description>Low output</description>
                                    <value>#0</value>
                                </enumeratedValue>
                                <enumeratedValue>
                                    <name>1</name>
                                    <description>High output</description>
                                    <value>#1</value>
                                </enumeratedValue>
                            </enumeratedValues>
                        </field>
                        <field>
                            <name>PODR10</name>
                            <description>Pmn Output Data</description>
                            <lsb>26</lsb>
                            <msb>26</msb>
                            <access>read-write</access>
                            <enumeratedValues>
                                <enumeratedValue>
                                    <name>0</name>
                                    <description>Low output</description>
                                    <value>#0</value>
                                </enumeratedValue>
                                <enumeratedValue>
                                    <name>1</name>
                                    <description>High output</description>
                                    <value>#1</value>
                                </enumeratedValue>
                            </enumeratedValues>
                        </field>
                        <field>
                            <name>PODR11</name>
                            <description>Pmn Output Data</description>
                            <lsb>27</lsb>
                            <msb>27</msb>
                            <access>read-write</access>
                            <enumeratedValues>
                                <enumeratedValue>
                                    <name>0</name>
                                    <description>Low output</description>
                                    <value>#0</value>
                                </enumeratedValue>
                                <enumeratedValue>
                                    <name>1</name>
                                    <description>High output</description>
                                    <value>#1</value>
                                </enumeratedValue>
                            </enumeratedValues>
                        </field>
                        <field>
                            <name>PODR12</name>
                            <description>Pmn Output Data</description>
                            <lsb>28</lsb>
                            <msb>28</msb>
                            <access>read-write</access>
                            <enumeratedValues>
                                <enumeratedValue>
                                    <name>0</name>
                                    <description>Low output</description>
                                    <value>#0</value>
                                </enumeratedValue>
                                <enumeratedValue>
                                    <name>1</name>
                                    <description>High output</description>
                                    <value>#1</value>
                                </enumeratedValue>
                            </enumeratedValues>
                        </field>
                        <field>
                            <name>PODR13</name>
                            <description>Pmn Output Data</description>
                            <lsb>29</lsb>
                            <msb>29</msb>
                            <access>read-write</access>
                            <enumeratedValues>
                                <enumeratedValue>
                                    <name>0</name>
                                    <description>Low output</description>
                                    <value>#0</value>
                                </enumeratedValue>
                                <enumeratedValue>
                                    <name>1</name>
                                    <description>High output</description>
                                    <value>#1</value>
                                </enumeratedValue>
                            </enumeratedValues>
                        </field>
                        <field>
                            <name>PODR14</name>
                            <description>Pmn Output Data</description>
                            <lsb>30</lsb>
                            <msb>30</msb>
                            <access>read-write</access>
                            <enumeratedValues>
                                <enumeratedValue>
                                    <name>0</name>
                                    <description>Low output</description>
                                    <value>#0</value>
                                </enumeratedValue>
                                <enumeratedValue>
                                    <name>1</name>
                                    <description>High output</description>
                                    <value>#1</value>
                                </enumeratedValue>
                            </enumeratedValues>
                        </field>
                        <field>
                            <name>PODR15</name>
                            <description>Pmn Output Data</description>
                            <lsb>31</lsb>
                            <msb>31</msb>
                            <access>read-write</access>
                            <enumeratedValues>
                                <enumeratedValue>
                                    <name>0</name>
                                    <description>Low output</description>
                                    <value>#0</value>
                                </enumeratedValue>
                                <enumeratedValue>
                                    <name>1</name>
                                    <description>High output</description>
                                    <value>#1</value>
                                </enumeratedValue>
                            </enumeratedValues>
                        </field>
                    </fields>
                </register>
                <register>
                    <name>PDR</name>
                    <description>Port Control Register 1</description>
                    <alternateRegister>PCNTR1</alternateRegister>
                    <addressOffset>0x000</addressOffset>
                    <size>16</size>
                    <access>read-write</access>
                    <resetValue>0x0000</resetValue>
                    <resetMask>0xffff</resetMask>
                    <fields>
                        <field>
                            <name>PODR00</name>
                            <description>Pmn Output Data</description>
                            <lsb>0</lsb>
                            <msb>0</msb>
                            <access>read-write</access>
                            <enumeratedValues>
                                <enumeratedValue>
                                    <name>0</name>
                                    <description>Low output</description>
                                    <value>#0</value>
                                </enumeratedValue>
                                <enumeratedValue>
                                    <name>1</name>
                                    <description>High output</description>
                                    <value>#1</value>
                                </enumeratedValue>
                            </enumeratedValues>
                        </field>
                        <field>
                            <name>PODR01</name>
                            <description>Pmn Output Data</description>
                            <lsb>1</lsb>
                            <msb>1</msb>
                            <access>read-write</access>
                            <enumeratedValues>
                                <enumeratedValue>
                                    <name>0</name>
                                    <description>Low output</description>
                                    <value>#0</value>
                                </enumeratedValue>
                                <enumeratedValue>
                                    <name>1</name>
                                    <description>High output</description>
                                    <value>#1</value>
                                </enumeratedValue>
                            </enumeratedValues>
                        </field>
                        <field>
                            <name>PODR02</name>
                            <description>Pmn Output Data</description>
                            <lsb>2</lsb>
                            <msb>2</msb>
                            <access>read-write</access>
                            <enumeratedValues>
                                <enumeratedValue>
                                    <name>0</name>
                                    <description>Low output</description>
                                    <value>#0</value>
                                </enumeratedValue>
                                <enumeratedValue>
                                    <name>1</name>
                                    <description>High output</description>
                                    <value>#1</value>
                                </enumeratedValue>
                            </enumeratedValues>
                        </field>
                        <field>
                            <name>PODR03</name>
                            <description>Pmn Output Data</description>
                            <lsb>3</lsb>
                            <msb>3</msb>
                            <access>read-write</access>
                            <enumeratedValues>
                                <enumeratedValue>
                                    <name>0</name>
                                    <description>Low output</description>
                                    <value>#0</value>
                                </enumeratedValue>
                                <enumeratedValue>
                                    <name>1</name>
                                    <description>High output</description>
                                    <value>#1</value>
                                </enumeratedValue>
                            </enumeratedValues>
                        </field>
                        <field>
                            <name>PODR04</name>
                            <description>Pmn Output Data</description>
                            <lsb>4</lsb>
                            <msb>4</msb>
                            <access>read-write</access>
                            <enumeratedValues>
                                <enumeratedValue>
                                    <name>0</name>
                                    <description>Low output</description>
                                    <value>#0</value>
                                </enumeratedValue>
                                <enumeratedValue>
                                    <name>1</name>
                                    <description>High output</description>
                                    <value>#1</value>
                                </enumeratedValue>
                            </enumeratedValues>
                        </field>
                        <field>
                            <name>PODR05</name>
                            <description>Pmn Output Data</description>
                            <lsb>5</lsb>
                            <msb>5</msb>
                            <access>read-write</access>
                            <enumeratedValues>
                                <enumeratedValue>
                                    <name>0</name>
                                    <description>Low output</description>
                                    <value>#0</value>
                                </enumeratedValue>
                                <enumeratedValue>
                                    <name>1</name>
                                    <description>High output</description>
                                    <value>#1</value>
                                </enumeratedValue>
                            </enumeratedValues>
                        </field>
                        <field>
                            <name>PODR06</name>
                            <description>Pmn Output Data</description>
                            <lsb>6</lsb>
                            <msb>6</msb>
                            <access>read-write</access>
                            <enumeratedValues>
                                <enumeratedValue>
                                    <name>0</name>
                                    <description>Low output</description>
                                    <value>#0</value>
                                </enumeratedValue>
                                <enumeratedValue>
                                    <name>1</name>
                                    <description>High output</description>
                                    <value>#1</value>
                                </enumeratedValue>
                            </enumeratedValues>
                        </field>
                        <field>
                            <name>PODR07</name>
                            <description>Pmn Output Data</description>
                            <lsb>7</lsb>
                            <msb>7</msb>
                            <access>read-write</access>
                            <enumeratedValues>
                                <enumeratedValue>
                                    <name>0</name>
                                    <description>Low output</description>
                                    <value>#0</value>
                                </enumeratedValue>
                                <enumeratedValue>
                                    <name>1</name>
                                    <description>High output</description>
                                    <value>#1</value>
                                </enumeratedValue>
                            </enumeratedValues>
                        </field>
                        <field>
                            <name>PODR08</name>
                            <description>Pmn Output Data</description>
                            <lsb>8</lsb>
                            <msb>8</msb>
                            <access>read-write</access>
                            <enumeratedValues>
                                <enumeratedValue>
                                    <name>0</name>
                                    <description>Low output</description>
                                    <value>#0</value>
                                </enumeratedValue>
                                <enumeratedValue>
                                    <name>1</name>
                                    <description>High output</description>
                                    <value>#1</value>
                                </enumeratedValue>
                            </enumeratedValues>
                        </field>
                        <field>
                            <name>PODR09</name>
                            <description>Pmn Output Data</description>
                            <lsb>9</lsb>
                            <msb>9</msb>
                            <access>read-write</access>
                            <enumeratedValues>
                                <enumeratedValue>
                                    <name>0</name>
                                    <description>Low output</description>
                                    <value>#0</value>
                                </enumeratedValue>
                                <enumeratedValue>
                                    <name>1</name>
                                    <description>High output</description>
                                    <value>#1</value>
                                </enumeratedValue>
                            </enumeratedValues>
                        </field>
                        <field>
                            <name>PODR10</name>
                            <description>Pmn Output Data</description>
                            <lsb>10</lsb>
                            <msb>10</msb>
                            <access>read-write</access>
                            <enumeratedValues>
                                <enumeratedValue>
                                    <name>0</name>
                                    <description>Low output</description>
                                    <value>#0</value>
                                </enumeratedValue>
                                <enumeratedValue>
                                    <name>1</name>
                                    <description>High output</description>
                                    <value>#1</value>
                                </enumeratedValue>
                            </enumeratedValues>
                        </field>
                        <field>
                            <name>PODR11</name>
                            <description>Pmn Output Data</description>
                            <lsb>11</lsb>
                            <msb>11</msb>
                            <access>read-write</access>
                            <enumeratedValues>
                                <enumeratedValue>
                                    <name>0</name>
                                    <description>Low output</description>
                                    <value>#0</value>
                                </enumeratedValue>
                                <enumeratedValue>
                                    <name>1</name>
                                    <description>High output</description>
                                    <value>#1</value>
                                </enumeratedValue>
                            </enumeratedValues>
                        </field>
                        <field>
                            <name>PODR12</name>
                            <description>Pmn Output Data</description>
                            <lsb>12</lsb>
                            <msb>12</msb>
                            <access>read-write</access>
                            <enumeratedValues>
                                <enumeratedValue>
                                    <name>0</name>
                                    <description>Low output</description>
                                    <value>#0</value>
                                </enumeratedValue>
                                <enumeratedValue>
                                    <name>1</name>
                                    <description>High output</description>
                                    <value>#1</value>
                                </enumeratedValue>
                            </enumeratedValues>
                        </field>
                        <field>
                            <name>PODR13</name>
                            <description>Pmn Output Data</description>
                            <lsb>13</lsb>
                            <msb>13</msb>
                            <access>read-write</access>
                            <enumeratedValues>
                                <enumeratedValue>
                                    <name>0</name>
                                    <description>Low output</description>
                                    <value>#0</value>
                                </enumeratedValue>
                                <enumeratedValue>
                                    <name>1</name>
                                    <description>High output</description>
                                    <value>#1</value>
                                </enumeratedValue>
                            </enumeratedValues>
                        </field>
                        <field>
                            <name>PODR14</name>
                            <description>Pmn Output Data</description>
                            <lsb>14</lsb>
                            <msb>14</msb>
                            <access>read-write</access>
                            <enumeratedValues>
                                <enumeratedValue>
                                    <name>0</name>
                                    <description>Low output</description>
                                    <value>#0</value>
                                </enumeratedValue>
                                <enumeratedValue>
                                    <name>1</name>
                                    <description>High output</description>
                                    <value>#1</value>
                                </enumeratedValue>
                            </enumeratedValues>
                        </field>
                        <field>
                            <name>PODR15</name>
                            <description>Pmn Output Data</description>
                            <lsb>15</lsb>
                            <msb>15</msb>
                            <access>read-write</access>
                            <enumeratedValues>
                                <enumeratedValue>
                                    <name>0</name>
                                    <description>Low output</description>
                                    <value>#0</value>
                                </enumeratedValue>
                                <enumeratedValue>
                                    <name>1</name>
                                    <description>High output</description>
                                    <value>#1</value>
                                </enumeratedValue>
                            </enumeratedValues>
                        </field>
                    </fields>
                </register>
                <register>
                    <name>PODR</name>
                    <description>Port Control Register 1</description>
                    <alternateRegister>PCNTR1</alternateRegister>
                    <addressOffset>0x002</addressOffset>
                    <size>16</size>
                    <access>read-write</access>
                    <resetValue>0x0000</resetValue>
                    <resetMask>0xffff</resetMask>
                    <fields>
                        <field>
                            <name>PDR00</name>
                            <description>Pmn Direction</description>
                            <lsb>0</lsb>
                            <msb>0</msb>
                            <access>read-write</access>
                            <enumeratedValues>
                                <enumeratedValue>
                                    <name>0</name>
                                    <description>Input (functions as an input pin)</description>
                                    <value>#0</value>
                                </enumeratedValue>
                                <enumeratedValue>
                                    <name>1</name>
                                    <description>Output (functions as an output pin)</description>
                                    <value>#1</value>
                                </enumeratedValue>
                            </enumeratedValues>
                        </field>
                        <field>
                            <name>PDR01</name>
                            <description>Pmn Direction</description>
                            <lsb>1</lsb>
                            <msb>1</msb>
                            <access>read-write</access>
                            <enumeratedValues>
                                <enumeratedValue>
                                    <name>0</name>
                                    <description>Input (functions as an input pin)</description>
                                    <value>#0</value>
                                </enumeratedValue>
                                <enumeratedValue>
                                    <name>1</name>
                                    <description>Output (functions as an output pin)</description>
                                    <value>#1</value>
                                </enumeratedValue>
                            </enumeratedValues>
                        </field>
                        <field>
                            <name>PDR02</name>
                            <description>Pmn Direction</description>
                            <lsb>2</lsb>
                            <msb>2</msb>
                            <access>read-write</access>
                            <enumeratedValues>
                                <enumeratedValue>
                                    <name>0</name>
                                    <description>Input (functions as an input pin)</description>
                                    <value>#0</value>
                                </enumeratedValue>
                                <enumeratedValue>
                                    <name>1</name>
                                    <description>Output (functions as an output pin)</description>
                                    <value>#1</value>
                                </enumeratedValue>
                            </enumeratedValues>
                        </field>
                        <field>
                            <name>PDR03</name>
                            <description>Pmn Direction</description>
                            <lsb>3</lsb>
                            <msb>3</msb>
                            <access>read-write</access>
                            <enumeratedValues>
                                <enumeratedValue>
                                    <name>0</name>
                                    <description>Input (functions as an input pin)</description>
                                    <value>#0</value>
                                </enumeratedValue>
                                <enumeratedValue>
                                    <name>1</name>
                                    <description>Output (functions as an output pin)</description>
                                    <value>#1</value>
                                </enumeratedValue>
                            </enumeratedValues>
                        </field>
                        <field>
                            <name>PDR04</name>
                            <description>Pmn Direction</description>
                            <lsb>4</lsb>
                            <msb>4</msb>
                            <access>read-write</access>
                            <enumeratedValues>
                                <enumeratedValue>
                                    <name>0</name>
                                    <description>Input (functions as an input pin)</description>
                                    <value>#0</value>
                                </enumeratedValue>
                                <enumeratedValue>
                                    <name>1</name>
                                    <description>Output (functions as an output pin)</description>
                                    <value>#1</value>
                                </enumeratedValue>
                            </enumeratedValues>
                        </field>
                        <field>
                            <name>PDR05</name>
                            <description>Pmn Direction</description>
                            <lsb>5</lsb>
                            <msb>5</msb>
                            <access>read-write</access>
                            <enumeratedValues>
                                <enumeratedValue>
                                    <name>0</name>
                                    <description>Input (functions as an input pin)</description>
                                    <value>#0</value>
                                </enumeratedValue>
                                <enumeratedValue>
                                    <name>1</name>
                                    <description>Output (functions as an output pin)</description>
                                    <value>#1</value>
                                </enumeratedValue>
                            </enumeratedValues>
                        </field>
                        <field>
                            <name>PDR06</name>
                            <description>Pmn Direction</description>
                            <lsb>6</lsb>
                            <msb>6</msb>
                            <access>read-write</access>
                            <enumeratedValues>
                                <enumeratedValue>
                                    <name>0</name>
                                    <description>Input (functions as an input pin)</description>
                                    <value>#0</value>
                                </enumeratedValue>
                                <enumeratedValue>
                                    <name>1</name>
                                    <description>Output (functions as an output pin)</description>
                                    <value>#1</value>
                                </enumeratedValue>
                            </enumeratedValues>
                        </field>
                        <field>
                            <name>PDR07</name>
                            <description>Pmn Direction</description>
                            <lsb>7</lsb>
                            <msb>7</msb>
                            <access>read-write</access>
                            <enumeratedValues>
                                <enumeratedValue>
                                    <name>0</name>
                                    <description>Input (functions as an input pin)</description>
                                    <value>#0</value>
                                </enumeratedValue>
                                <enumeratedValue>
                                    <name>1</name>
                                    <description>Output (functions as an output pin)</description>
                                    <value>#1</value>
                                </enumeratedValue>
                            </enumeratedValues>
                        </field>
                        <field>
                            <name>PDR08</name>
                            <description>Pmn Direction</description>
                            <lsb>8</lsb>
                            <msb>8</msb>
                            <access>read-write</access>
                            <enumeratedValues>
                                <enumeratedValue>
                                    <name>0</name>
                                    <description>Input (functions as an input pin)</description>
                                    <value>#0</value>
                                </enumeratedValue>
                                <enumeratedValue>
                                    <name>1</name>
                                    <description>Output (functions as an output pin)</description>
                                    <value>#1</value>
                                </enumeratedValue>
                            </enumeratedValues>
                        </field>
                        <field>
                            <name>PDR09</name>
                            <description>Pmn Direction</description>
                            <lsb>9</lsb>
                            <msb>9</msb>
                            <access>read-write</access>
                            <enumeratedValues>
                                <enumeratedValue>
                                    <name>0</name>
                                    <description>Input (functions as an input pin)</description>
                                    <value>#0</value>
                                </enumeratedValue>
                                <enumeratedValue>
                                    <name>1</name>
                                    <description>Output (functions as an output pin)</description>
                                    <value>#1</value>
                                </enumeratedValue>
                            </enumeratedValues>
                        </field>
                        <field>
                            <name>PDR10</name>
                            <description>Pmn Direction</description>
                            <lsb>10</lsb>
                            <msb>10</msb>
                            <access>read-write</access>
                            <enumeratedValues>
                                <enumeratedValue>
                                    <name>0</name>
                                    <description>Input (functions as an input pin)</description>
                                    <value>#0</value>
                                </enumeratedValue>
                                <enumeratedValue>
                                    <name>1</name>
                                    <description>Output (functions as an output pin)</description>
                                    <value>#1</value>
                                </enumeratedValue>
                            </enumeratedValues>
                        </field>
                        <field>
                            <name>PDR11</name>
                            <description>Pmn Direction</description>
                            <lsb>11</lsb>
                            <msb>11</msb>
                            <access>read-write</access>
                            <enumeratedValues>
                                <enumeratedValue>
                                    <name>0</name>
                                    <description>Input (functions as an input pin)</description>
                                    <value>#0</value>
                                </enumeratedValue>
                                <enumeratedValue>
                                    <name>1</name>
                                    <description>Output (functions as an output pin)</description>
                                    <value>#1</value>
                                </enumeratedValue>
                            </enumeratedValues>
                        </field>
                        <field>
                            <name>PDR12</name>
                            <description>Pmn Direction</description>
                            <lsb>12</lsb>
                            <msb>12</msb>
                            <access>read-write</access>
                            <enumeratedValues>
                                <enumeratedValue>
                                    <name>0</name>
                                    <description>Input (functions as an input pin)</description>
                                    <value>#0</value>
                                </enumeratedValue>
                                <enumeratedValue>
                                    <name>1</name>
                                    <description>Output (functions as an output pin)</description>
                                    <value>#1</value>
                                </enumeratedValue>
                            </enumeratedValues>
                        </field>
                        <field>
                            <name>PDR13</name>
                            <description>Pmn Direction</description>
                            <lsb>13</lsb>
                            <msb>13</msb>
                            <access>read-write</access>
                            <enumeratedValues>
                                <enumeratedValue>
                                    <name>0</name>
                                    <description>Input (functions as an input pin)</description>
                                    <value>#0</value>
                                </enumeratedValue>
                                <enumeratedValue>
                                    <name>1</name>
                                    <description>Output (functions as an output pin)</description>
                                    <value>#1</value>
                                </enumeratedValue>
                            </enumeratedValues>
                        </field>
                        <field>
                            <name>PDR14</name>
                            <description>Pmn Direction</description>
                            <lsb>14</lsb>
                            <msb>14</msb>
                            <access>read-write</access>
                            <enumeratedValues>
                                <enumeratedValue>
                                    <name>0</name>
                                    <description>Input (functions as an input pin)</description>
                                    <value>#0</value>
                                </enumeratedValue>
                                <enumeratedValue>
                                    <name>1</name>
                                    <description>Output (functions as an output pin)</description>
                                    <value>#1</value>
                                </enumeratedValue>
                            </enumeratedValues>
                        </field>
                        <field>
                            <name>PDR15</name>
                            <description>Pmn Direction</description>
                            <lsb>15</lsb>
                            <msb>15</msb>
                            <access>read-write</access>
                            <enumeratedValues>
                                <enumeratedValue>
                                    <name>0</name>
                                    <description>Input (functions as an input pin)</description>
                                    <value>#0</value>
                                </enumeratedValue>
                                <enumeratedValue>
                                    <name>1</name>
                                    <description>Output (functions as an output pin)</description>
                                    <value>#1</value>
                                </enumeratedValue>
                            </enumeratedValues>
                        </field>
                    </fields>
                </register>
                <register>
                    <name>PCNTR2</name>
                    <description>Port Control Register 2</description>
                    <addressOffset>0x004</addressOffset>
                    <size>32</size>
                    <access>read-only</access>
                    <resetValue>0x00000000</resetValue>
                    <resetMask>0xffff0000</resetMask>
                    <fields>
                        <field>
                            <name>PIDR00</name>
                            <description>Pmn State</description>
                            <lsb>0</lsb>
                            <msb>0</msb>
                            <access>read-only</access>
                            <enumeratedValues>
                                <enumeratedValue>
                                    <name>0</name>
                                    <description>Low level</description>
                                    <value>#0</value>
                                </enumeratedValue>
                                <enumeratedValue>
                                    <name>1</name>
                                    <description>High level</description>
                                    <value>#1</value>
                                </enumeratedValue>
                            </enumeratedValues>
                        </field>
                        <field>
                            <name>PIDR01</name>
                            <description>Pmn State</description>
                            <lsb>1</lsb>
                            <msb>1</msb>
                            <access>read-only</access>
                            <enumeratedValues>
                                <enumeratedValue>
                                    <name>0</name>
                                    <description>Low level</description>
                                    <value>#0</value>
                                </enumeratedValue>
                                <enumeratedValue>
                                    <name>1</name>
                                    <description>High level</description>
                                    <value>#1</value>
                                </enumeratedValue>
                            </enumeratedValues>
                        </field>
                        <field>
                            <name>PIDR02</name>
                            <description>Pmn State</description>
                            <lsb>2</lsb>
                            <msb>2</msb>
                            <access>read-only</access>
                            <enumeratedValues>
                                <enumeratedValue>
                                    <name>0</name>
                                    <description>Low level</description>
                                    <value>#0</value>
                                </enumeratedValue>
                                <enumeratedValue>
                                    <name>1</name>
                                    <description>High level</description>
                                    <value>#1</value>
                                </enumeratedValue>
                            </enumeratedValues>
                        </field>
                        <field>
                            <name>PIDR03</name>
                            <description>Pmn State</description>
                            <lsb>3</lsb>
                            <msb>3</msb>
                            <access>read-only</access>
                            <enumeratedValues>
                                <enumeratedValue>
                                    <name>0</name>
                                    <description>Low level</description>
                                    <value>#0</value>
                                </enumeratedValue>
                                <enumeratedValue>
                                    <name>1</name>
                                    <description>High level</description>
                                    <value>#1</value>
                                </enumeratedValue>
                            </enumeratedValues>
                        </field>
                        <field>
                            <name>PIDR04</name>
                            <description>Pmn State</description>
                            <lsb>4</lsb>
                            <msb>4</msb>
                            <access>read-only</access>
                            <enumeratedValues>
                                <enumeratedValue>
                                    <name>0</name>
                                    <description>Low level</description>
                                    <value>#0</value>
                                </enumeratedValue>
                                <enumeratedValue>
                                    <name>1</name>
                                    <description>High level</description>
                                    <value>#1</value>
                                </enumeratedValue>
                            </enumeratedValues>
                        </field>
                        <field>
                            <name>PIDR05</name>
                            <description>Pmn State</description>
                            <lsb>5</lsb>
                            <msb>5</msb>
                            <access>read-only</access>
                            <enumeratedValues>
                                <enumeratedValue>
                                    <name>0</name>
                                    <description>Low level</description>
                                    <value>#0</value>
                                </enumeratedValue>
                                <enumeratedValue>
                                    <name>1</name>
                                    <description>High level</description>
                                    <value>#1</value>
                                </enumeratedValue>
                            </enumeratedValues>
                        </field>
                        <field>
                            <name>PIDR06</name>
                            <description>Pmn State</description>
                            <lsb>6</lsb>
                            <msb>6</msb>
                            <access>read-only</access>
                            <enumeratedValues>
                                <enumeratedValue>
                                    <name>0</name>
                                    <description>Low level</description>
                                    <value>#0</value>
                                </enumeratedValue>
                                <enumeratedValue>
                                    <name>1</name>
                                    <description>High level</description>
                                    <value>#1</value>
                                </enumeratedValue>
                            </enumeratedValues>
                        </field>
                        <field>
                            <name>PIDR07</name>
                            <description>Pmn State</description>
                            <lsb>7</lsb>
                            <msb>7</msb>
                            <access>read-only</access>
                            <enumeratedValues>
                                <enumeratedValue>
                                    <name>0</name>
                                    <description>Low level</description>
                                    <value>#0</value>
                                </enumeratedValue>
                                <enumeratedValue>
                                    <name>1</name>
                                    <description>High level</description>
                                    <value>#1</value>
                                </enumeratedValue>
                            </enumeratedValues>
                        </field>
                        <field>
                            <name>PIDR08</name>
                            <description>Pmn State</description>
                            <lsb>8</lsb>
                            <msb>8</msb>
                            <access>read-only</access>
                            <enumeratedValues>
                                <enumeratedValue>
                                    <name>0</name>
                                    <description>Low level</description>
                                    <value>#0</value>
                                </enumeratedValue>
                                <enumeratedValue>
                                    <name>1</name>
                                    <description>High level</description>
                                    <value>#1</value>
                                </enumeratedValue>
                            </enumeratedValues>
                        </field>
                        <field>
                            <name>PIDR09</name>
                            <description>Pmn State</description>
                            <lsb>9</lsb>
                            <msb>9</msb>
                            <access>read-only</access>
                            <enumeratedValues>
                                <enumeratedValue>
                                    <name>0</name>
                                    <description>Low level</description>
                                    <value>#0</value>
                                </enumeratedValue>
                                <enumeratedValue>
                                    <name>1</name>
                                    <description>High level</description>
                                    <value>#1</value>
                                </enumeratedValue>
                            </enumeratedValues>
                        </field>
                        <field>
                            <name>PIDR10</name>
                            <description>Pmn State</description>
                            <lsb>10</lsb>
                            <msb>10</msb>
                            <access>read-only</access>
                            <enumeratedValues>
                                <enumeratedValue>
                                    <name>0</name>
                                    <description>Low level</description>
                                    <value>#0</value>
                                </enumeratedValue>
                                <enumeratedValue>
                                    <name>1</name>
                                    <description>High level</description>
                                    <value>#1</value>
                                </enumeratedValue>
                            </enumeratedValues>
                        </field>
                        <field>
                            <name>PIDR11</name>
                            <description>Pmn State</description>
                            <lsb>11</lsb>
                            <msb>11</msb>
                            <access>read-only</access>
                            <enumeratedValues>
                                <enumeratedValue>
                                    <name>0</name>
                                    <description>Low level</description>
                                    <value>#0</value>
                                </enumeratedValue>
                                <enumeratedValue>
                                    <name>1</name>
                                    <description>High level</description>
                                    <value>#1</value>
                                </enumeratedValue>
                            </enumeratedValues>
                        </field>
                        <field>
                            <name>PIDR12</name>
                            <description>Pmn State</description>
                            <lsb>12</lsb>
                            <msb>12</msb>
                            <access>read-only</access>
                            <enumeratedValues>
                                <enumeratedValue>
                                    <name>0</name>
                                    <description>Low level</description>
                                    <value>#0</value>
                                </enumeratedValue>
                                <enumeratedValue>
                                    <name>1</name>
                                    <description>High level</description>
                                    <value>#1</value>
                                </enumeratedValue>
                            </enumeratedValues>
                        </field>
                        <field>
                            <name>PIDR13</name>
                            <description>Pmn State</description>
                            <lsb>13</lsb>
                            <msb>13</msb>
                            <access>read-only</access>
                            <enumeratedValues>
                                <enumeratedValue>
                                    <name>0</name>
                                    <description>Low level</description>
                                    <value>#0</value>
                                </enumeratedValue>
                                <enumeratedValue>
                                    <name>1</name>
                                    <description>High level</description>
                                    <value>#1</value>
                                </enumeratedValue>
                            </enumeratedValues>
                        </field>
                        <field>
                            <name>PIDR14</name>
                            <description>Pmn State</description>
                            <lsb>14</lsb>
                            <msb>14</msb>
                            <access>read-only</access>
                            <enumeratedValues>
                                <enumeratedValue>
                                    <name>0</name>
                                    <description>Low level</description>
                                    <value>#0</value>
                                </enumeratedValue>
                                <enumeratedValue>
                                    <name>1</name>
                                    <description>High level</description>
                                    <value>#1</value>
                                </enumeratedValue>
                            </enumeratedValues>
                        </field>
                        <field>
                            <name>PIDR15</name>
                            <description>Pmn State</description>
                            <lsb>15</lsb>
                            <msb>15</msb>
                            <access>read-only</access>
                            <enumeratedValues>
                                <enumeratedValue>
                                    <name>0</name>
                                    <description>Low level</description>
                                    <value>#0</value>
                                </enumeratedValue>
                                <enumeratedValue>
                                    <name>1</name>
                                    <description>High level</description>
                                    <value>#1</value>
                                </enumeratedValue>
                            </enumeratedValues>
                        </field>
                    </fields>
                </register>
                <register>
                    <name>PIDR</name>
                    <description>Port Control Register 2</description>
                    <alternateRegister>PCNTR2</alternateRegister>
                    <addressOffset>0x004</addressOffset>
                    <size>16</size>
                    <access>read-only</access>
                    <resetValue>0x0000</resetValue>
                    <resetMask>0xffff</resetMask>
                </register>
                <register>
                    <name>PCNTR3</name>
                    <description>Port Control Register 3</description>
                    <addressOffset>0x008</addressOffset>
                    <size>32</size>
                    <access>write-only</access>
                    <resetValue>0x00000000</resetValue>
                    <resetMask>0xffffffff</resetMask>
                    <fields>
                        <field>
                            <name>POSR00</name>
                            <description>Pmn Output Set</description>
                            <lsb>0</lsb>
                            <msb>0</msb>
                            <access>write-only</access>
                            <enumeratedValues>
                                <enumeratedValue>
                                    <name>0</name>
                                    <description>No effect on output</description>
                                    <value>#0</value>
                                </enumeratedValue>
                                <enumeratedValue>
                                    <name>1</name>
                                    <description>High output</description>
                                    <value>#1</value>
                                </enumeratedValue>
                            </enumeratedValues>
                        </field>
                        <field>
                            <name>POSR01</name>
                            <description>Pmn Output Set</description>
                            <lsb>1</lsb>
                            <msb>1</msb>
                            <access>write-only</access>
                            <enumeratedValues>
                                <enumeratedValue>
                                    <name>0</name>
                                    <description>No effect on output</description>
                                    <value>#0</value>
                                </enumeratedValue>
                                <enumeratedValue>
                                    <name>1</name>
                                    <description>High output</description>
                                    <value>#1</value>
                                </enumeratedValue>
                            </enumeratedValues>
                        </field>
                        <field>
                            <name>POSR02</name>
                            <description>Pmn Output Set</description>
                            <lsb>2</lsb>
                            <msb>2</msb>
                            <access>write-only</access>
                            <enumeratedValues>
                                <enumeratedValue>
                                    <name>0</name>
                                    <description>No effect on output</description>
                                    <value>#0</value>
                                </enumeratedValue>
                                <enumeratedValue>
                                    <name>1</name>
                                    <description>High output</description>
                                    <value>#1</value>
                                </enumeratedValue>
                            </enumeratedValues>
                        </field>
                        <field>
                            <name>POSR03</name>
                            <description>Pmn Output Set</description>
                            <lsb>3</lsb>
                            <msb>3</msb>
                            <access>write-only</access>
                            <enumeratedValues>
                                <enumeratedValue>
                                    <name>0</name>
                                    <description>No effect on output</description>
                                    <value>#0</value>
                                </enumeratedValue>
                                <enumeratedValue>
                                    <name>1</name>
                                    <description>High output</description>
                                    <value>#1</value>
                                </enumeratedValue>
                            </enumeratedValues>
                        </field>
                        <field>
                            <name>POSR04</name>
                            <description>Pmn Output Set</description>
                            <lsb>4</lsb>
                            <msb>4</msb>
                            <access>write-only</access>
                            <enumeratedValues>
                                <enumeratedValue>
                                    <name>0</name>
                                    <description>No effect on output</description>
                                    <value>#0</value>
                                </enumeratedValue>
                                <enumeratedValue>
                                    <name>1</name>
                                    <description>High output</description>
                                    <value>#1</value>
                                </enumeratedValue>
                            </enumeratedValues>
                        </field>
                        <field>
                            <name>POSR05</name>
                            <description>Pmn Output Set</description>
                            <lsb>5</lsb>
                            <msb>5</msb>
                            <access>write-only</access>
                            <enumeratedValues>
                                <enumeratedValue>
                                    <name>0</name>
                                    <description>No effect on output</description>
                                    <value>#0</value>
                                </enumeratedValue>
                                <enumeratedValue>
                                    <name>1</name>
                                    <description>High output</description>
                                    <value>#1</value>
                                </enumeratedValue>
                            </enumeratedValues>
                        </field>
                        <field>
                            <name>POSR06</name>
                            <description>Pmn Output Set</description>
                            <lsb>6</lsb>
                            <msb>6</msb>
                            <access>write-only</access>
                            <enumeratedValues>
                                <enumeratedValue>
                                    <name>0</name>
                                    <description>No effect on output</description>
                                    <value>#0</value>
                                </enumeratedValue>
                                <enumeratedValue>
                                    <name>1</name>
                                    <description>High output</description>
                                    <value>#1</value>
                                </enumeratedValue>
                            </enumeratedValues>
                        </field>
                        <field>
                            <name>POSR07</name>
                            <description>Pmn Output Set</description>
                            <lsb>7</lsb>
                            <msb>7</msb>
                            <access>write-only</access>
                            <enumeratedValues>
                                <enumeratedValue>
                                    <name>0</name>
                                    <description>No effect on output</description>
                                    <value>#0</value>
                                </enumeratedValue>
                                <enumeratedValue>
                                    <name>1</name>
                                    <description>High output</description>
                                    <value>#1</value>
                                </enumeratedValue>
                            </enumeratedValues>
                        </field>
                        <field>
                            <name>POSR08</name>
                            <description>Pmn Output Set</description>
                            <lsb>8</lsb>
                            <msb>8</msb>
                            <access>write-only</access>
                            <enumeratedValues>
                                <enumeratedValue>
                                    <name>0</name>
                                    <description>No effect on output</description>
                                    <value>#0</value>
                                </enumeratedValue>
                                <enumeratedValue>
                                    <name>1</name>
                                    <description>High output</description>
                                    <value>#1</value>
                                </enumeratedValue>
                            </enumeratedValues>
                        </field>
                        <field>
                            <name>POSR09</name>
                            <description>Pmn Output Set</description>
                            <lsb>9</lsb>
                            <msb>9</msb>
                            <access>write-only</access>
                            <enumeratedValues>
                                <enumeratedValue>
                                    <name>0</name>
                                    <description>No effect on output</description>
                                    <value>#0</value>
                                </enumeratedValue>
                                <enumeratedValue>
                                    <name>1</name>
                                    <description>High output</description>
                                    <value>#1</value>
                                </enumeratedValue>
                            </enumeratedValues>
                        </field>
                        <field>
                            <name>POSR10</name>
                            <description>Pmn Output Set</description>
                            <lsb>10</lsb>
                            <msb>10</msb>
                            <access>write-only</access>
                            <enumeratedValues>
                                <enumeratedValue>
                                    <name>0</name>
                                    <description>No effect on output</description>
                                    <value>#0</value>
                                </enumeratedValue>
                                <enumeratedValue>
                                    <name>1</name>
                                    <description>High output</description>
                                    <value>#1</value>
                                </enumeratedValue>
                            </enumeratedValues>
                        </field>
                        <field>
                            <name>POSR11</name>
                            <description>Pmn Output Set</description>
                            <lsb>11</lsb>
                            <msb>11</msb>
                            <access>write-only</access>
                            <enumeratedValues>
                                <enumeratedValue>
                                    <name>0</name>
                                    <description>No effect on output</description>
                                    <value>#0</value>
                                </enumeratedValue>
                                <enumeratedValue>
                                    <name>1</name>
                                    <description>High output</description>
                                    <value>#1</value>
                                </enumeratedValue>
                            </enumeratedValues>
                        </field>
                        <field>
                            <name>POSR12</name>
                            <description>Pmn Output Set</description>
                            <lsb>12</lsb>
                            <msb>12</msb>
                            <access>write-only</access>
                            <enumeratedValues>
                                <enumeratedValue>
                                    <name>0</name>
                                    <description>No effect on output</description>
                                    <value>#0</value>
                                </enumeratedValue>
                                <enumeratedValue>
                                    <name>1</name>
                                    <description>High output</description>
                                    <value>#1</value>
                                </enumeratedValue>
                            </enumeratedValues>
                        </field>
                        <field>
                            <name>POSR13</name>
                            <description>Pmn Output Set</description>
                            <lsb>13</lsb>
                            <msb>13</msb>
                            <access>write-only</access>
                            <enumeratedValues>
                                <enumeratedValue>
                                    <name>0</name>
                                    <description>No effect on output</description>
                                    <value>#0</value>
                                </enumeratedValue>
                                <enumeratedValue>
                                    <name>1</name>
                                    <description>High output</description>
                                    <value>#1</value>
                                </enumeratedValue>
                            </enumeratedValues>
                        </field>
                        <field>
                            <name>POSR14</name>
                            <description>Pmn Output Set</description>
                            <lsb>14</lsb>
                            <msb>14</msb>
                            <access>write-only</access>
                            <enumeratedValues>
                                <enumeratedValue>
                                    <name>0</name>
                                    <description>No effect on output</description>
                                    <value>#0</value>
                                </enumeratedValue>
                                <enumeratedValue>
                                    <name>1</name>
                                    <description>High output</description>
                                    <value>#1</value>
                                </enumeratedValue>
                            </enumeratedValues>
                        </field>
                        <field>
                            <name>POSR15</name>
                            <description>Pmn Output Set</description>
                            <lsb>15</lsb>
                            <msb>15</msb>
                            <access>write-only</access>
                            <enumeratedValues>
                                <enumeratedValue>
                                    <name>0</name>
                                    <description>No effect on output</description>
                                    <value>#0</value>
                                </enumeratedValue>
                                <enumeratedValue>
                                    <name>1</name>
                                    <description>High output</description>
                                    <value>#1</value>
                                </enumeratedValue>
                            </enumeratedValues>
                        </field>
                        <field>
                            <name>PORR00</name>
                            <description>Pmn Output Reset</description>
                            <lsb>16</lsb>
                            <msb>16</msb>
                            <access>write-only</access>
                            <enumeratedValues>
                                <enumeratedValue>
                                    <name>0</name>
                                    <description>No effect on output</description>
                                    <value>#0</value>
                                </enumeratedValue>
                                <enumeratedValue>
                                    <name>1</name>
                                    <description>Low output</description>
                                    <value>#1</value>
                                </enumeratedValue>
                            </enumeratedValues>
                        </field>
                        <field>
                            <name>PORR01</name>
                            <description>Pmn Output Reset</description>
                            <lsb>17</lsb>
                            <msb>17</msb>
                            <access>write-only</access>
                            <enumeratedValues>
                                <enumeratedValue>
                                    <name>0</name>
                                    <description>No effect on output</description>
                                    <value>#0</value>
                                </enumeratedValue>
                                <enumeratedValue>
                                    <name>1</name>
                                    <description>Low output</description>
                                    <value>#1</value>
                                </enumeratedValue>
                            </enumeratedValues>
                        </field>
                        <field>
                            <name>PORR02</name>
                            <description>Pmn Output Reset</description>
                            <lsb>18</lsb>
                            <msb>18</msb>
                            <access>write-only</access>
                            <enumeratedValues>
                                <enumeratedValue>
                                    <name>0</name>
                                    <description>No effect on output</description>
                                    <value>#0</value>
                                </enumeratedValue>
                                <enumeratedValue>
                                    <name>1</name>
                                    <description>Low output</description>
                                    <value>#1</value>
                                </enumeratedValue>
                            </enumeratedValues>
                        </field>
                        <field>
                            <name>PORR03</name>
                            <description>Pmn Output Reset</description>
                            <lsb>19</lsb>
                            <msb>19</msb>
                            <access>write-only</access>
                            <enumeratedValues>
                                <enumeratedValue>
                                    <name>0</name>
                                    <description>No effect on output</description>
                                    <value>#0</value>
                                </enumeratedValue>
                                <enumeratedValue>
                                    <name>1</name>
                                    <description>Low output</description>
                                    <value>#1</value>
                                </enumeratedValue>
                            </enumeratedValues>
                        </field>
                        <field>
                            <name>PORR04</name>
                            <description>Pmn Output Reset</description>
                            <lsb>20</lsb>
                            <msb>20</msb>
                            <access>write-only</access>
                            <enumeratedValues>
                                <enumeratedValue>
                                    <name>0</name>
                                    <description>No effect on output</description>
                                    <value>#0</value>
                                </enumeratedValue>
                                <enumeratedValue>
                                    <name>1</name>
                                    <description>Low output</description>
                                    <value>#1</value>
                                </enumeratedValue>
                            </enumeratedValues>
                        </field>
                        <field>
                            <name>PORR05</name>
                            <description>Pmn Output Reset</description>
                            <lsb>21</lsb>
                            <msb>21</msb>
                            <access>write-only</access>
                            <enumeratedValues>
                                <enumeratedValue>
                                    <name>0</name>
                                    <description>No effect on output</description>
                                    <value>#0</value>
                                </enumeratedValue>
                                <enumeratedValue>
                                    <name>1</name>
                                    <description>Low output</description>
                                    <value>#1</value>
                                </enumeratedValue>
                            </enumeratedValues>
                        </field>
                        <field>
                            <name>PORR06</name>
                            <description>Pmn Output Reset</description>
                            <lsb>22</lsb>
                            <msb>22</msb>
                            <access>write-only</access>
                            <enumeratedValues>
                                <enumeratedValue>
                                    <name>0</name>
                                    <description>No effect on output</description>
                                    <value>#0</value>
                                </enumeratedValue>
                                <enumeratedValue>
                                    <name>1</name>
                                    <description>Low output</description>
                                    <value>#1</value>
                                </enumeratedValue>
                            </enumeratedValues>
                        </field>
                        <field>
                            <name>PORR07</name>
                            <description>Pmn Output Reset</description>
                            <lsb>23</lsb>
                            <msb>23</msb>
                            <access>write-only</access>
                            <enumeratedValues>
                                <enumeratedValue>
                                    <name>0</name>
                                    <description>No effect on output</description>
                                    <value>#0</value>
                                </enumeratedValue>
                                <enumeratedValue>
                                    <name>1</name>
                                    <description>Low output</description>
                                    <value>#1</value>
                                </enumeratedValue>
                            </enumeratedValues>
                        </field>
                        <field>
                            <name>PORR08</name>
                            <description>Pmn Output Reset</description>
                            <lsb>24</lsb>
                            <msb>24</msb>
                            <access>write-only</access>
                            <enumeratedValues>
                                <enumeratedValue>
                                    <name>0</name>
                                    <description>No effect on output</description>
                                    <value>#0</value>
                                </enumeratedValue>
                                <enumeratedValue>
                                    <name>1</name>
                                    <description>Low output</description>
                                    <value>#1</value>
                                </enumeratedValue>
                            </enumeratedValues>
                        </field>
                        <field>
                            <name>PORR09</name>
                            <description>Pmn Output Reset</description>
                            <lsb>25</lsb>
                            <msb>25</msb>
                            <access>write-only</access>
                            <enumeratedValues>
                                <enumeratedValue>
                                    <name>0</name>
                                    <description>No effect on output</description>
                                    <value>#0</value>
                                </enumeratedValue>
                                <enumeratedValue>
                                    <name>1</name>
                                    <description>Low output</description>
                                    <value>#1</value>
                                </enumeratedValue>
                            </enumeratedValues>
                        </field>
                        <field>
                            <name>PORR10</name>
                            <description>Pmn Output Reset</description>
                            <lsb>26</lsb>
                            <msb>26</msb>
                            <access>write-only</access>
                            <enumeratedValues>
                                <enumeratedValue>
                                    <name>0</name>
                                    <description>No effect on output</description>
                                    <value>#0</value>
                                </enumeratedValue>
                                <enumeratedValue>
                                    <name>1</name>
                                    <description>Low output</description>
                                    <value>#1</value>
                                </enumeratedValue>
                            </enumeratedValues>
                        </field>
                        <field>
                            <name>PORR11</name>
                            <description>Pmn Output Reset</description>
                            <lsb>27</lsb>
                            <msb>27</msb>
                            <access>write-only</access>
                            <enumeratedValues>
                                <enumeratedValue>
                                    <name>0</name>
                                    <description>No effect on output</description>
                                    <value>#0</value>
                                </enumeratedValue>
                                <enumeratedValue>
                                    <name>1</name>
                                    <description>Low output</description>
                                    <value>#1</value>
                                </enumeratedValue>
                            </enumeratedValues>
                        </field>
                        <field>
                            <name>PORR12</name>
                            <description>Pmn Output Reset</description>
                            <lsb>28</lsb>
                            <msb>28</msb>
                            <access>write-only</access>
                            <enumeratedValues>
                                <enumeratedValue>
                                    <name>0</name>
                                    <description>No effect on output</description>
                                    <value>#0</value>
                                </enumeratedValue>
                                <enumeratedValue>
                                    <name>1</name>
                                    <description>Low output</description>
                                    <value>#1</value>
                                </enumeratedValue>
                            </enumeratedValues>
                        </field>
                        <field>
                            <name>PORR13</name>
                            <description>Pmn Output Reset</description>
                            <lsb>29</lsb>
                            <msb>29</msb>
                            <access>write-only</access>
                            <enumeratedValues>
                                <enumeratedValue>
                                    <name>0</name>
                                    <description>No effect on output</description>
                                    <value>#0</value>
                                </enumeratedValue>
                                <enumeratedValue>
                                    <name>1</name>
                                    <description>Low output</description>
                                    <value>#1</value>
                                </enumeratedValue>
                            </enumeratedValues>
                        </field>
                        <field>
                            <name>PORR14</name>
                            <description>Pmn Output Reset</description>
                            <lsb>30</lsb>
                            <msb>30</msb>
                            <access>write-only</access>
                            <enumeratedValues>
                                <enumeratedValue>
                                    <name>0</name>
                                    <description>No effect on output</description>
                                    <value>#0</value>
                                </enumeratedValue>
                                <enumeratedValue>
                                    <name>1</name>
                                    <description>Low output</description>
                                    <value>#1</value>
                                </enumeratedValue>
                            </enumeratedValues>
                        </field>
                        <field>
                            <name>PORR15</name>
                            <description>Pmn Output Reset</description>
                            <lsb>31</lsb>
                            <msb>31</msb>
                            <access>write-only</access>
                            <enumeratedValues>
                                <enumeratedValue>
                                    <name>0</name>
                                    <description>No effect on output</description>
                                    <value>#0</value>
                                </enumeratedValue>
                                <enumeratedValue>
                                    <name>1</name>
                                    <description>Low output</description>
                                    <value>#1</value>
                                </enumeratedValue>
                            </enumeratedValues>
                        </field>
                    </fields>
                </register>
                <register>
                    <name>POSR</name>
                    <description>Port Control Register 3</description>
                    <alternateRegister>PCNTR3</alternateRegister>
                    <addressOffset>0x008</addressOffset>
                    <size>16</size>
                    <access>write-only</access>
                    <resetValue>0x0000</resetValue>
                    <resetMask>0xffff</resetMask>
                    <fields>
                        <field>
                            <name>PORR00</name>
                            <description>Pmn Output Reset</description>
                            <lsb>0</lsb>
                            <msb>0</msb>
                            <access>write-only</access>
                            <enumeratedValues>
                                <enumeratedValue>
                                    <name>0</name>
                                    <description>No effect on output</description>
                                    <value>#0</value>
                                </enumeratedValue>
                                <enumeratedValue>
                                    <name>1</name>
                                    <description>Low output</description>
                                    <value>#1</value>
                                </enumeratedValue>
                            </enumeratedValues>
                        </field>
                        <field>
                            <name>PORR01</name>
                            <description>Pmn Output Reset</description>
                            <lsb>1</lsb>
                            <msb>1</msb>
                            <access>write-only</access>
                            <enumeratedValues>
                                <enumeratedValue>
                                    <name>0</name>
                                    <description>No effect on output</description>
                                    <value>#0</value>
                                </enumeratedValue>
                                <enumeratedValue>
                                    <name>1</name>
                                    <description>Low output</description>
                                    <value>#1</value>
                                </enumeratedValue>
                            </enumeratedValues>
                        </field>
                        <field>
                            <name>PORR02</name>
                            <description>Pmn Output Reset</description>
                            <lsb>2</lsb>
                            <msb>2</msb>
                            <access>write-only</access>
                            <enumeratedValues>
                                <enumeratedValue>
                                    <name>0</name>
                                    <description>No effect on output</description>
                                    <value>#0</value>
                                </enumeratedValue>
                                <enumeratedValue>
                                    <name>1</name>
                                    <description>Low output</description>
                                    <value>#1</value>
                                </enumeratedValue>
                            </enumeratedValues>
                        </field>
                        <field>
                            <name>PORR03</name>
                            <description>Pmn Output Reset</description>
                            <lsb>3</lsb>
                            <msb>3</msb>
                            <access>write-only</access>
                            <enumeratedValues>
                                <enumeratedValue>
                                    <name>0</name>
                                    <description>No effect on output</description>
                                    <value>#0</value>
                                </enumeratedValue>
                                <enumeratedValue>
                                    <name>1</name>
                                    <description>Low output</description>
                                    <value>#1</value>
                                </enumeratedValue>
                            </enumeratedValues>
                        </field>
                        <field>
                            <name>PORR04</name>
                            <description>Pmn Output Reset</description>
                            <lsb>4</lsb>
                            <msb>4</msb>
                            <access>write-only</access>
                            <enumeratedValues>
                                <enumeratedValue>
                                    <name>0</name>
                                    <description>No effect on output</description>
                                    <value>#0</value>
                                </enumeratedValue>
                                <enumeratedValue>
                                    <name>1</name>
                                    <description>Low output</description>
                                    <value>#1</value>
                                </enumeratedValue>
                            </enumeratedValues>
                        </field>
                        <field>
                            <name>PORR05</name>
                            <description>Pmn Output Reset</description>
                            <lsb>5</lsb>
                            <msb>5</msb>
                            <access>write-only</access>
                            <enumeratedValues>
                                <enumeratedValue>
                                    <name>0</name>
                                    <description>No effect on output</description>
                                    <value>#0</value>
                                </enumeratedValue>
                                <enumeratedValue>
                                    <name>1</name>
                                    <description>Low output</description>
                                    <value>#1</value>
                                </enumeratedValue>
                            </enumeratedValues>
                        </field>
                        <field>
                            <name>PORR06</name>
                            <description>Pmn Output Reset</description>
                            <lsb>6</lsb>
                            <msb>6</msb>
                            <access>write-only</access>
                            <enumeratedValues>
                                <enumeratedValue>
                                    <name>0</name>
                                    <description>No effect on output</description>
                                    <value>#0</value>
                                </enumeratedValue>
                                <enumeratedValue>
                                    <name>1</name>
                                    <description>Low output</description>
                                    <value>#1</value>
                                </enumeratedValue>
                            </enumeratedValues>
                        </field>
                        <field>
                            <name>PORR07</name>
                            <description>Pmn Output Reset</description>
                            <lsb>7</lsb>
                            <msb>7</msb>
                            <access>write-only</access>
                            <enumeratedValues>
                                <enumeratedValue>
                                    <name>0</name>
                                    <description>No effect on output</description>
                                    <value>#0</value>
                                </enumeratedValue>
                                <enumeratedValue>
                                    <name>1</name>
                                    <description>Low output</description>
                                    <value>#1</value>
                                </enumeratedValue>
                            </enumeratedValues>
                        </field>
                        <field>
                            <name>PORR08</name>
                            <description>Pmn Output Reset</description>
                            <lsb>8</lsb>
                            <msb>8</msb>
                            <access>write-only</access>
                            <enumeratedValues>
                                <enumeratedValue>
                                    <name>0</name>
                                    <description>No effect on output</description>
                                    <value>#0</value>
                                </enumeratedValue>
                                <enumeratedValue>
                                    <name>1</name>
                                    <description>Low output</description>
                                    <value>#1</value>
                                </enumeratedValue>
                            </enumeratedValues>
                        </field>
                        <field>
                            <name>PORR09</name>
                            <description>Pmn Output Reset</description>
                            <lsb>9</lsb>
                            <msb>9</msb>
                            <access>write-only</access>
                            <enumeratedValues>
                                <enumeratedValue>
                                    <name>0</name>
                                    <description>No effect on output</description>
                                    <value>#0</value>
                                </enumeratedValue>
                                <enumeratedValue>
                                    <name>1</name>
                                    <description>Low output</description>
                                    <value>#1</value>
                                </enumeratedValue>
                            </enumeratedValues>
                        </field>
                        <field>
                            <name>PORR10</name>
                            <description>Pmn Output Reset</description>
                            <lsb>10</lsb>
                            <msb>10</msb>
                            <access>write-only</access>
                            <enumeratedValues>
                                <enumeratedValue>
                                    <name>0</name>
                                    <description>No effect on output</description>
                                    <value>#0</value>
                                </enumeratedValue>
                                <enumeratedValue>
                                    <name>1</name>
                                    <description>Low output</description>
                                    <value>#1</value>
                                </enumeratedValue>
                            </enumeratedValues>
                        </field>
                        <field>
                            <name>PORR11</name>
                            <description>Pmn Output Reset</description>
                            <lsb>11</lsb>
                            <msb>11</msb>
                            <access>write-only</access>
                            <enumeratedValues>
                                <enumeratedValue>
                                    <name>0</name>
                                    <description>No effect on output</description>
                                    <value>#0</value>
                                </enumeratedValue>
                                <enumeratedValue>
                                    <name>1</name>
                                    <description>Low output</description>
                                    <value>#1</value>
                                </enumeratedValue>
                            </enumeratedValues>
                        </field>
                        <field>
                            <name>PORR12</name>
                            <description>Pmn Output Reset</description>
                            <lsb>12</lsb>
                            <msb>12</msb>
                            <access>write-only</access>
                            <enumeratedValues>
                                <enumeratedValue>
                                    <name>0</name>
                                    <description>No effect on output</description>
                                    <value>#0</value>
                                </enumeratedValue>
                                <enumeratedValue>
                                    <name>1</name>
                                    <description>Low output</description>
                                    <value>#1</value>
                                </enumeratedValue>
                            </enumeratedValues>
                        </field>
                        <field>
                            <name>PORR13</name>
                            <description>Pmn Output Reset</description>
                            <lsb>13</lsb>
                            <msb>13</msb>
                            <access>write-only</access>
                            <enumeratedValues>
                                <enumeratedValue>
                                    <name>0</name>
                                    <description>No effect on output</description>
                                    <value>#0</value>
                                </enumeratedValue>
                                <enumeratedValue>
                                    <name>1</name>
                                    <description>Low output</description>
                                    <value>#1</value>
                                </enumeratedValue>
                            </enumeratedValues>
                        </field>
                        <field>
                            <name>PORR14</name>
                            <description>Pmn Output Reset</description>
                            <lsb>14</lsb>
                            <msb>14</msb>
                            <access>write-only</access>
                            <enumeratedValues>
                                <enumeratedValue>
                                    <name>0</name>
                                    <description>No effect on output</description>
                                    <value>#0</value>
                                </enumeratedValue>
                                <enumeratedValue>
                                    <name>1</name>
                                    <description>Low output</description>
                                    <value>#1</value>
                                </enumeratedValue>
                            </enumeratedValues>
                        </field>
                        <field>
                            <name>PORR15</name>
                            <description>Pmn Output Reset</description>
                            <lsb>15</lsb>
                            <msb>15</msb>
                            <access>write-only</access>
                            <enumeratedValues>
                                <enumeratedValue>
                                    <name>0</name>
                                    <description>No effect on output</description>
                                    <value>#0</value>
                                </enumeratedValue>
                                <enumeratedValue>
                                    <name>1</name>
                                    <description>Low output</description>
                                    <value>#1</value>
                                </enumeratedValue>
                            </enumeratedValues>
                        </field>
                    </fields>
                </register>
                <register>
                    <name>PORR</name>
                    <description>Port Control Register 3</description>
                    <alternateRegister>PCNTR3</alternateRegister>
                    <addressOffset>0x00A</addressOffset>
                    <size>16</size>
                    <access>write-only</access>
                    <resetValue>0x0000</resetValue>
                    <resetMask>0xffff</resetMask>
                    <fields>
                        <field>
                            <name>POSR00</name>
                            <description>Pmn Output Set</description>
                            <lsb>0</lsb>
                            <msb>0</msb>
                            <access>write-only</access>
                            <enumeratedValues>
                                <enumeratedValue>
                                    <name>0</name>
                                    <description>No effect on output</description>
                                    <value>#0</value>
                                </enumeratedValue>
                                <enumeratedValue>
                                    <name>1</name>
                                    <description>High output</description>
                                    <value>#1</value>
                                </enumeratedValue>
                            </enumeratedValues>
                        </field>
                        <field>
                            <name>POSR01</name>
                            <description>Pmn Output Set</description>
                            <lsb>1</lsb>
                            <msb>1</msb>
                            <access>write-only</access>
                            <enumeratedValues>
                                <enumeratedValue>
                                    <name>0</name>
                                    <description>No effect on output</description>
                                    <value>#0</value>
                                </enumeratedValue>
                                <enumeratedValue>
                                    <name>1</name>
                                    <description>High output</description>
                                    <value>#1</value>
                                </enumeratedValue>
                            </enumeratedValues>
                        </field>
                        <field>
                            <name>POSR02</name>
                            <description>Pmn Output Set</description>
                            <lsb>2</lsb>
                            <msb>2</msb>
                            <access>write-only</access>
                            <enumeratedValues>
                                <enumeratedValue>
                                    <name>0</name>
                                    <description>No effect on output</description>
                                    <value>#0</value>
                                </enumeratedValue>
                                <enumeratedValue>
                                    <name>1</name>
                                    <description>High output</description>
                                    <value>#1</value>
                                </enumeratedValue>
                            </enumeratedValues>
                        </field>
                        <field>
                            <name>POSR03</name>
                            <description>Pmn Output Set</description>
                            <lsb>3</lsb>
                            <msb>3</msb>
                            <access>write-only</access>
                            <enumeratedValues>
                                <enumeratedValue>
                                    <name>0</name>
                                    <description>No effect on output</description>
                                    <value>#0</value>
                                </enumeratedValue>
                                <enumeratedValue>
                                    <name>1</name>
                                    <description>High output</description>
                                    <value>#1</value>
                                </enumeratedValue>
                            </enumeratedValues>
                        </field>
                        <field>
                            <name>POSR04</name>
                            <description>Pmn Output Set</description>
                            <lsb>4</lsb>
                            <msb>4</msb>
                            <access>write-only</access>
                            <enumeratedValues>
                                <enumeratedValue>
                                    <name>0</name>
                                    <description>No effect on output</description>
                                    <value>#0</value>
                                </enumeratedValue>
                                <enumeratedValue>
                                    <name>1</name>
                                    <description>High output</description>
                                    <value>#1</value>
                                </enumeratedValue>
                            </enumeratedValues>
                        </field>
                        <field>
                            <name>POSR05</name>
                            <description>Pmn Output Set</description>
                            <lsb>5</lsb>
                            <msb>5</msb>
                            <access>write-only</access>
                            <enumeratedValues>
                                <enumeratedValue>
                                    <name>0</name>
                                    <description>No effect on output</description>
                                    <value>#0</value>
                                </enumeratedValue>
                                <enumeratedValue>
                                    <name>1</name>
                                    <description>High output</description>
                                    <value>#1</value>
                                </enumeratedValue>
                            </enumeratedValues>
                        </field>
                        <field>
                            <name>POSR06</name>
                            <description>Pmn Output Set</description>
                            <lsb>6</lsb>
                            <msb>6</msb>
                            <access>write-only</access>
                            <enumeratedValues>
                                <enumeratedValue>
                                    <name>0</name>
                                    <description>No effect on output</description>
                                    <value>#0</value>
                                </enumeratedValue>
                                <enumeratedValue>
                                    <name>1</name>
                                    <description>High output</description>
                                    <value>#1</value>
                                </enumeratedValue>
                            </enumeratedValues>
                        </field>
                        <field>
                            <name>POSR07</name>
                            <description>Pmn Output Set</description>
                            <lsb>7</lsb>
                            <msb>7</msb>
                            <access>write-only</access>
                            <enumeratedValues>
                                <enumeratedValue>
                                    <name>0</name>
                                    <description>No effect on output</description>
                                    <value>#0</value>
                                </enumeratedValue>
                                <enumeratedValue>
                                    <name>1</name>
                                    <description>High output</description>
                                    <value>#1</value>
                                </enumeratedValue>
                            </enumeratedValues>
                        </field>
                        <field>
                            <name>POSR08</name>
                            <description>Pmn Output Set</description>
                            <lsb>8</lsb>
                            <msb>8</msb>
                            <access>write-only</access>
                            <enumeratedValues>
                                <enumeratedValue>
                                    <name>0</name>
                                    <description>No effect on output</description>
                                    <value>#0</value>
                                </enumeratedValue>
                                <enumeratedValue>
                                    <name>1</name>
                                    <description>High output</description>
                                    <value>#1</value>
                                </enumeratedValue>
                            </enumeratedValues>
                        </field>
                        <field>
                            <name>POSR09</name>
                            <description>Pmn Output Set</description>
                            <lsb>9</lsb>
                            <msb>9</msb>
                            <access>write-only</access>
                            <enumeratedValues>
                                <enumeratedValue>
                                    <name>0</name>
                                    <description>No effect on output</description>
                                    <value>#0</value>
                                </enumeratedValue>
                                <enumeratedValue>
                                    <name>1</name>
                                    <description>High output</description>
                                    <value>#1</value>
                                </enumeratedValue>
                            </enumeratedValues>
                        </field>
                        <field>
                            <name>POSR10</name>
                            <description>Pmn Output Set</description>
                            <lsb>10</lsb>
                            <msb>10</msb>
                            <access>write-only</access>
                            <enumeratedValues>
                                <enumeratedValue>
                                    <name>0</name>
                                    <description>No effect on output</description>
                                    <value>#0</value>
                                </enumeratedValue>
                                <enumeratedValue>
                                    <name>1</name>
                                    <description>High output</description>
                                    <value>#1</value>
                                </enumeratedValue>
                            </enumeratedValues>
                        </field>
                        <field>
                            <name>POSR11</name>
                            <description>Pmn Output Set</description>
                            <lsb>11</lsb>
                            <msb>11</msb>
                            <access>write-only</access>
                            <enumeratedValues>
                                <enumeratedValue>
                                    <name>0</name>
                                    <description>No effect on output</description>
                                    <value>#0</value>
                                </enumeratedValue>
                                <enumeratedValue>
                                    <name>1</name>
                                    <description>High output</description>
                                    <value>#1</value>
                                </enumeratedValue>
                            </enumeratedValues>
                        </field>
                        <field>
                            <name>POSR12</name>
                            <description>Pmn Output Set</description>
                            <lsb>12</lsb>
                            <msb>12</msb>
                            <access>write-only</access>
                            <enumeratedValues>
                                <enumeratedValue>
                                    <name>0</name>
                                    <description>No effect on output</description>
                                    <value>#0</value>
                                </enumeratedValue>
                                <enumeratedValue>
                                    <name>1</name>
                                    <description>High output</description>
                                    <value>#1</value>
                                </enumeratedValue>
                            </enumeratedValues>
                        </field>
                        <field>
                            <name>POSR13</name>
                            <description>Pmn Output Set</description>
                            <lsb>13</lsb>
                            <msb>13</msb>
                            <access>write-only</access>
                            <enumeratedValues>
                                <enumeratedValue>
                                    <name>0</name>
                                    <description>No effect on output</description>
                                    <value>#0</value>
                                </enumeratedValue>
                                <enumeratedValue>
                                    <name>1</name>
                                    <description>High output</description>
                                    <value>#1</value>
                                </enumeratedValue>
                            </enumeratedValues>
                        </field>
                        <field>
                            <name>POSR14</name>
                            <description>Pmn Output Set</description>
                            <lsb>14</lsb>
                            <msb>14</msb>
                            <access>write-only</access>
                            <enumeratedValues>
                                <enumeratedValue>
                                    <name>0</name>
                                    <description>No effect on output</description>
                                    <value>#0</value>
                                </enumeratedValue>
                                <enumeratedValue>
                                    <name>1</name>
                                    <description>High output</description>
                                    <value>#1</value>
                                </enumeratedValue>
                            </enumeratedValues>
                        </field>
                        <field>
                            <name>POSR15</name>
                            <description>Pmn Output Set</description>
                            <lsb>15</lsb>
                            <msb>15</msb>
                            <access>write-only</access>
                            <enumeratedValues>
                                <enumeratedValue>
                                    <name>0</name>
                                    <description>No effect on output</description>
                                    <value>#0</value>
                                </enumeratedValue>
                                <enumeratedValue>
                                    <name>1</name>
                                    <description>High output</description>
                                    <value>#1</value>
                                </enumeratedValue>
                            </enumeratedValues>
                        </field>
                    </fields>
                </register>
            </registers>
        </peripheral>
        <peripheral>
            <name>PORTB</name>
            <description>Pmn Pin Function Port B Control Registers Pmn Pin Function Control Register</description>
            <baseAddress>0x40400160</baseAddress>
            <addressBlock>
                <offset>0x00</offset>
                <size>8</size>
                <usage>registers</usage>
            </addressBlock>
            <addressBlock>
                <offset>0x08</offset>
                <size>4</size>
                <usage>registers</usage>
            </addressBlock>
            <registers>
                <register>
                    <name>PCNTR1</name>
                    <description>Port Control Register 1</description>
                    <addressOffset>0x000</addressOffset>
                    <size>32</size>
                    <access>read-write</access>
                    <resetValue>0x00000000</resetValue>
                    <resetMask>0xffffffff</resetMask>
                    <fields>
                        <field>
                            <name>PDR00</name>
                            <description>Pmn Direction</description>
                            <lsb>0</lsb>
                            <msb>0</msb>
                            <access>read-write</access>
                            <enumeratedValues>
                                <enumeratedValue>
                                    <name>0</name>
                                    <description>Input (functions as an input pin)</description>
                                    <value>#0</value>
                                </enumeratedValue>
                                <enumeratedValue>
                                    <name>1</name>
                                    <description>Output (functions as an output pin)</description>
                                    <value>#1</value>
                                </enumeratedValue>
                            </enumeratedValues>
                        </field>
                        <field>
                            <name>PDR01</name>
                            <description>Pmn Direction</description>
                            <lsb>1</lsb>
                            <msb>1</msb>
                            <access>read-write</access>
                            <enumeratedValues>
                                <enumeratedValue>
                                    <name>0</name>
                                    <description>Input (functions as an input pin)</description>
                                    <value>#0</value>
                                </enumeratedValue>
                                <enumeratedValue>
                                    <name>1</name>
                                    <description>Output (functions as an output pin)</description>
                                    <value>#1</value>
                                </enumeratedValue>
                            </enumeratedValues>
                        </field>
                        <field>
                            <name>PDR02</name>
                            <description>Pmn Direction</description>
                            <lsb>2</lsb>
                            <msb>2</msb>
                            <access>read-write</access>
                            <enumeratedValues>
                                <enumeratedValue>
                                    <name>0</name>
                                    <description>Input (functions as an input pin)</description>
                                    <value>#0</value>
                                </enumeratedValue>
                                <enumeratedValue>
                                    <name>1</name>
                                    <description>Output (functions as an output pin)</description>
                                    <value>#1</value>
                                </enumeratedValue>
                            </enumeratedValues>
                        </field>
                        <field>
                            <name>PDR03</name>
                            <description>Pmn Direction</description>
                            <lsb>3</lsb>
                            <msb>3</msb>
                            <access>read-write</access>
                            <enumeratedValues>
                                <enumeratedValue>
                                    <name>0</name>
                                    <description>Input (functions as an input pin)</description>
                                    <value>#0</value>
                                </enumeratedValue>
                                <enumeratedValue>
                                    <name>1</name>
                                    <description>Output (functions as an output pin)</description>
                                    <value>#1</value>
                                </enumeratedValue>
                            </enumeratedValues>
                        </field>
                        <field>
                            <name>PDR04</name>
                            <description>Pmn Direction</description>
                            <lsb>4</lsb>
                            <msb>4</msb>
                            <access>read-write</access>
                            <enumeratedValues>
                                <enumeratedValue>
                                    <name>0</name>
                                    <description>Input (functions as an input pin)</description>
                                    <value>#0</value>
                                </enumeratedValue>
                                <enumeratedValue>
                                    <name>1</name>
                                    <description>Output (functions as an output pin)</description>
                                    <value>#1</value>
                                </enumeratedValue>
                            </enumeratedValues>
                        </field>
                        <field>
                            <name>PDR05</name>
                            <description>Pmn Direction</description>
                            <lsb>5</lsb>
                            <msb>5</msb>
                            <access>read-write</access>
                            <enumeratedValues>
                                <enumeratedValue>
                                    <name>0</name>
                                    <description>Input (functions as an input pin)</description>
                                    <value>#0</value>
                                </enumeratedValue>
                                <enumeratedValue>
                                    <name>1</name>
                                    <description>Output (functions as an output pin)</description>
                                    <value>#1</value>
                                </enumeratedValue>
                            </enumeratedValues>
                        </field>
                        <field>
                            <name>PDR06</name>
                            <description>Pmn Direction</description>
                            <lsb>6</lsb>
                            <msb>6</msb>
                            <access>read-write</access>
                            <enumeratedValues>
                                <enumeratedValue>
                                    <name>0</name>
                                    <description>Input (functions as an input pin)</description>
                                    <value>#0</value>
                                </enumeratedValue>
                                <enumeratedValue>
                                    <name>1</name>
                                    <description>Output (functions as an output pin)</description>
                                    <value>#1</value>
                                </enumeratedValue>
                            </enumeratedValues>
                        </field>
                        <field>
                            <name>PDR07</name>
                            <description>Pmn Direction</description>
                            <lsb>7</lsb>
                            <msb>7</msb>
                            <access>read-write</access>
                            <enumeratedValues>
                                <enumeratedValue>
                                    <name>0</name>
                                    <description>Input (functions as an input pin)</description>
                                    <value>#0</value>
                                </enumeratedValue>
                                <enumeratedValue>
                                    <name>1</name>
                                    <description>Output (functions as an output pin)</description>
                                    <value>#1</value>
                                </enumeratedValue>
                            </enumeratedValues>
                        </field>
                        <field>
                            <name>PDR08</name>
                            <description>Pmn Direction</description>
                            <lsb>8</lsb>
                            <msb>8</msb>
                            <access>read-write</access>
                            <enumeratedValues>
                                <enumeratedValue>
                                    <name>0</name>
                                    <description>Input (functions as an input pin)</description>
                                    <value>#0</value>
                                </enumeratedValue>
                                <enumeratedValue>
                                    <name>1</name>
                                    <description>Output (functions as an output pin)</description>
                                    <value>#1</value>
                                </enumeratedValue>
                            </enumeratedValues>
                        </field>
                        <field>
                            <name>PDR09</name>
                            <description>Pmn Direction</description>
                            <lsb>9</lsb>
                            <msb>9</msb>
                            <access>read-write</access>
                            <enumeratedValues>
                                <enumeratedValue>
                                    <name>0</name>
                                    <description>Input (functions as an input pin)</description>
                                    <value>#0</value>
                                </enumeratedValue>
                                <enumeratedValue>
                                    <name>1</name>
                                    <description>Output (functions as an output pin)</description>
                                    <value>#1</value>
                                </enumeratedValue>
                            </enumeratedValues>
                        </field>
                        <field>
                            <name>PDR10</name>
                            <description>Pmn Direction</description>
                            <lsb>10</lsb>
                            <msb>10</msb>
                            <access>read-write</access>
                            <enumeratedValues>
                                <enumeratedValue>
                                    <name>0</name>
                                    <description>Input (functions as an input pin)</description>
                                    <value>#0</value>
                                </enumeratedValue>
                                <enumeratedValue>
                                    <name>1</name>
                                    <description>Output (functions as an output pin)</description>
                                    <value>#1</value>
                                </enumeratedValue>
                            </enumeratedValues>
                        </field>
                        <field>
                            <name>PDR11</name>
                            <description>Pmn Direction</description>
                            <lsb>11</lsb>
                            <msb>11</msb>
                            <access>read-write</access>
                            <enumeratedValues>
                                <enumeratedValue>
                                    <name>0</name>
                                    <description>Input (functions as an input pin)</description>
                                    <value>#0</value>
                                </enumeratedValue>
                                <enumeratedValue>
                                    <name>1</name>
                                    <description>Output (functions as an output pin)</description>
                                    <value>#1</value>
                                </enumeratedValue>
                            </enumeratedValues>
                        </field>
                        <field>
                            <name>PDR12</name>
                            <description>Pmn Direction</description>
                            <lsb>12</lsb>
                            <msb>12</msb>
                            <access>read-write</access>
                            <enumeratedValues>
                                <enumeratedValue>
                                    <name>0</name>
                                    <description>Input (functions as an input pin)</description>
                                    <value>#0</value>
                                </enumeratedValue>
                                <enumeratedValue>
                                    <name>1</name>
                                    <description>Output (functions as an output pin)</description>
                                    <value>#1</value>
                                </enumeratedValue>
                            </enumeratedValues>
                        </field>
                        <field>
                            <name>PDR13</name>
                            <description>Pmn Direction</description>
                            <lsb>13</lsb>
                            <msb>13</msb>
                            <access>read-write</access>
                            <enumeratedValues>
                                <enumeratedValue>
                                    <name>0</name>
                                    <description>Input (functions as an input pin)</description>
                                    <value>#0</value>
                                </enumeratedValue>
                                <enumeratedValue>
                                    <name>1</name>
                                    <description>Output (functions as an output pin)</description>
                                    <value>#1</value>
                                </enumeratedValue>
                            </enumeratedValues>
                        </field>
                        <field>
                            <name>PDR14</name>
                            <description>Pmn Direction</description>
                            <lsb>14</lsb>
                            <msb>14</msb>
                            <access>read-write</access>
                            <enumeratedValues>
                                <enumeratedValue>
                                    <name>0</name>
                                    <description>Input (functions as an input pin)</description>
                                    <value>#0</value>
                                </enumeratedValue>
                                <enumeratedValue>
                                    <name>1</name>
                                    <description>Output (functions as an output pin)</description>
                                    <value>#1</value>
                                </enumeratedValue>
                            </enumeratedValues>
                        </field>
                        <field>
                            <name>PDR15</name>
                            <description>Pmn Direction</description>
                            <lsb>15</lsb>
                            <msb>15</msb>
                            <access>read-write</access>
                            <enumeratedValues>
                                <enumeratedValue>
                                    <name>0</name>
                                    <description>Input (functions as an input pin)</description>
                                    <value>#0</value>
                                </enumeratedValue>
                                <enumeratedValue>
                                    <name>1</name>
                                    <description>Output (functions as an output pin)</description>
                                    <value>#1</value>
                                </enumeratedValue>
                            </enumeratedValues>
                        </field>
                        <field>
                            <name>PODR00</name>
                            <description>Pmn Output Data</description>
                            <lsb>16</lsb>
                            <msb>16</msb>
                            <access>read-write</access>
                            <enumeratedValues>
                                <enumeratedValue>
                                    <name>0</name>
                                    <description>Low output</description>
                                    <value>#0</value>
                                </enumeratedValue>
                                <enumeratedValue>
                                    <name>1</name>
                                    <description>High output</description>
                                    <value>#1</value>
                                </enumeratedValue>
                            </enumeratedValues>
                        </field>
                        <field>
                            <name>PODR01</name>
                            <description>Pmn Output Data</description>
                            <lsb>17</lsb>
                            <msb>17</msb>
                            <access>read-write</access>
                            <enumeratedValues>
                                <enumeratedValue>
                                    <name>0</name>
                                    <description>Low output</description>
                                    <value>#0</value>
                                </enumeratedValue>
                                <enumeratedValue>
                                    <name>1</name>
                                    <description>High output</description>
                                    <value>#1</value>
                                </enumeratedValue>
                            </enumeratedValues>
                        </field>
                        <field>
                            <name>PODR02</name>
                            <description>Pmn Output Data</description>
                            <lsb>18</lsb>
                            <msb>18</msb>
                            <access>read-write</access>
                            <enumeratedValues>
                                <enumeratedValue>
                                    <name>0</name>
                                    <description>Low output</description>
                                    <value>#0</value>
                                </enumeratedValue>
                                <enumeratedValue>
                                    <name>1</name>
                                    <description>High output</description>
                                    <value>#1</value>
                                </enumeratedValue>
                            </enumeratedValues>
                        </field>
                        <field>
                            <name>PODR03</name>
                            <description>Pmn Output Data</description>
                            <lsb>19</lsb>
                            <msb>19</msb>
                            <access>read-write</access>
                            <enumeratedValues>
                                <enumeratedValue>
                                    <name>0</name>
                                    <description>Low output</description>
                                    <value>#0</value>
                                </enumeratedValue>
                                <enumeratedValue>
                                    <name>1</name>
                                    <description>High output</description>
                                    <value>#1</value>
                                </enumeratedValue>
                            </enumeratedValues>
                        </field>
                        <field>
                            <name>PODR04</name>
                            <description>Pmn Output Data</description>
                            <lsb>20</lsb>
                            <msb>20</msb>
                            <access>read-write</access>
                            <enumeratedValues>
                                <enumeratedValue>
                                    <name>0</name>
                                    <description>Low output</description>
                                    <value>#0</value>
                                </enumeratedValue>
                                <enumeratedValue>
                                    <name>1</name>
                                    <description>High output</description>
                                    <value>#1</value>
                                </enumeratedValue>
                            </enumeratedValues>
                        </field>
                        <field>
                            <name>PODR05</name>
                            <description>Pmn Output Data</description>
                            <lsb>21</lsb>
                            <msb>21</msb>
                            <access>read-write</access>
                            <enumeratedValues>
                                <enumeratedValue>
                                    <name>0</name>
                                    <description>Low output</description>
                                    <value>#0</value>
                                </enumeratedValue>
                                <enumeratedValue>
                                    <name>1</name>
                                    <description>High output</description>
                                    <value>#1</value>
                                </enumeratedValue>
                            </enumeratedValues>
                        </field>
                        <field>
                            <name>PODR06</name>
                            <description>Pmn Output Data</description>
                            <lsb>22</lsb>
                            <msb>22</msb>
                            <access>read-write</access>
                            <enumeratedValues>
                                <enumeratedValue>
                                    <name>0</name>
                                    <description>Low output</description>
                                    <value>#0</value>
                                </enumeratedValue>
                                <enumeratedValue>
                                    <name>1</name>
                                    <description>High output</description>
                                    <value>#1</value>
                                </enumeratedValue>
                            </enumeratedValues>
                        </field>
                        <field>
                            <name>PODR07</name>
                            <description>Pmn Output Data</description>
                            <lsb>23</lsb>
                            <msb>23</msb>
                            <access>read-write</access>
                            <enumeratedValues>
                                <enumeratedValue>
                                    <name>0</name>
                                    <description>Low output</description>
                                    <value>#0</value>
                                </enumeratedValue>
                                <enumeratedValue>
                                    <name>1</name>
                                    <description>High output</description>
                                    <value>#1</value>
                                </enumeratedValue>
                            </enumeratedValues>
                        </field>
                        <field>
                            <name>PODR08</name>
                            <description>Pmn Output Data</description>
                            <lsb>24</lsb>
                            <msb>24</msb>
                            <access>read-write</access>
                            <enumeratedValues>
                                <enumeratedValue>
                                    <name>0</name>
                                    <description>Low output</description>
                                    <value>#0</value>
                                </enumeratedValue>
                                <enumeratedValue>
                                    <name>1</name>
                                    <description>High output</description>
                                    <value>#1</value>
                                </enumeratedValue>
                            </enumeratedValues>
                        </field>
                        <field>
                            <name>PODR09</name>
                            <description>Pmn Output Data</description>
                            <lsb>25</lsb>
                            <msb>25</msb>
                            <access>read-write</access>
                            <enumeratedValues>
                                <enumeratedValue>
                                    <name>0</name>
                                    <description>Low output</description>
                                    <value>#0</value>
                                </enumeratedValue>
                                <enumeratedValue>
                                    <name>1</name>
                                    <description>High output</description>
                                    <value>#1</value>
                                </enumeratedValue>
                            </enumeratedValues>
                        </field>
                        <field>
                            <name>PODR10</name>
                            <description>Pmn Output Data</description>
                            <lsb>26</lsb>
                            <msb>26</msb>
                            <access>read-write</access>
                            <enumeratedValues>
                                <enumeratedValue>
                                    <name>0</name>
                                    <description>Low output</description>
                                    <value>#0</value>
                                </enumeratedValue>
                                <enumeratedValue>
                                    <name>1</name>
                                    <description>High output</description>
                                    <value>#1</value>
                                </enumeratedValue>
                            </enumeratedValues>
                        </field>
                        <field>
                            <name>PODR11</name>
                            <description>Pmn Output Data</description>
                            <lsb>27</lsb>
                            <msb>27</msb>
                            <access>read-write</access>
                            <enumeratedValues>
                                <enumeratedValue>
                                    <name>0</name>
                                    <description>Low output</description>
                                    <value>#0</value>
                                </enumeratedValue>
                                <enumeratedValue>
                                    <name>1</name>
                                    <description>High output</description>
                                    <value>#1</value>
                                </enumeratedValue>
                            </enumeratedValues>
                        </field>
                        <field>
                            <name>PODR12</name>
                            <description>Pmn Output Data</description>
                            <lsb>28</lsb>
                            <msb>28</msb>
                            <access>read-write</access>
                            <enumeratedValues>
                                <enumeratedValue>
                                    <name>0</name>
                                    <description>Low output</description>
                                    <value>#0</value>
                                </enumeratedValue>
                                <enumeratedValue>
                                    <name>1</name>
                                    <description>High output</description>
                                    <value>#1</value>
                                </enumeratedValue>
                            </enumeratedValues>
                        </field>
                        <field>
                            <name>PODR13</name>
                            <description>Pmn Output Data</description>
                            <lsb>29</lsb>
                            <msb>29</msb>
                            <access>read-write</access>
                            <enumeratedValues>
                                <enumeratedValue>
                                    <name>0</name>
                                    <description>Low output</description>
                                    <value>#0</value>
                                </enumeratedValue>
                                <enumeratedValue>
                                    <name>1</name>
                                    <description>High output</description>
                                    <value>#1</value>
                                </enumeratedValue>
                            </enumeratedValues>
                        </field>
                        <field>
                            <name>PODR14</name>
                            <description>Pmn Output Data</description>
                            <lsb>30</lsb>
                            <msb>30</msb>
                            <access>read-write</access>
                            <enumeratedValues>
                                <enumeratedValue>
                                    <name>0</name>
                                    <description>Low output</description>
                                    <value>#0</value>
                                </enumeratedValue>
                                <enumeratedValue>
                                    <name>1</name>
                                    <description>High output</description>
                                    <value>#1</value>
                                </enumeratedValue>
                            </enumeratedValues>
                        </field>
                        <field>
                            <name>PODR15</name>
                            <description>Pmn Output Data</description>
                            <lsb>31</lsb>
                            <msb>31</msb>
                            <access>read-write</access>
                            <enumeratedValues>
                                <enumeratedValue>
                                    <name>0</name>
                                    <description>Low output</description>
                                    <value>#0</value>
                                </enumeratedValue>
                                <enumeratedValue>
                                    <name>1</name>
                                    <description>High output</description>
                                    <value>#1</value>
                                </enumeratedValue>
                            </enumeratedValues>
                        </field>
                    </fields>
                </register>
                <register>
                    <name>PDR</name>
                    <description>Port Control Register 1</description>
                    <alternateRegister>PCNTR1</alternateRegister>
                    <addressOffset>0x000</addressOffset>
                    <size>16</size>
                    <access>read-write</access>
                    <resetValue>0x0000</resetValue>
                    <resetMask>0xffff</resetMask>
                    <fields>
                        <field>
                            <name>PODR00</name>
                            <description>Pmn Output Data</description>
                            <lsb>0</lsb>
                            <msb>0</msb>
                            <access>read-write</access>
                            <enumeratedValues>
                                <enumeratedValue>
                                    <name>0</name>
                                    <description>Low output</description>
                                    <value>#0</value>
                                </enumeratedValue>
                                <enumeratedValue>
                                    <name>1</name>
                                    <description>High output</description>
                                    <value>#1</value>
                                </enumeratedValue>
                            </enumeratedValues>
                        </field>
                        <field>
                            <name>PODR01</name>
                            <description>Pmn Output Data</description>
                            <lsb>1</lsb>
                            <msb>1</msb>
                            <access>read-write</access>
                            <enumeratedValues>
                                <enumeratedValue>
                                    <name>0</name>
                                    <description>Low output</description>
                                    <value>#0</value>
                                </enumeratedValue>
                                <enumeratedValue>
                                    <name>1</name>
                                    <description>High output</description>
                                    <value>#1</value>
                                </enumeratedValue>
                            </enumeratedValues>
                        </field>
                        <field>
                            <name>PODR02</name>
                            <description>Pmn Output Data</description>
                            <lsb>2</lsb>
                            <msb>2</msb>
                            <access>read-write</access>
                            <enumeratedValues>
                                <enumeratedValue>
                                    <name>0</name>
                                    <description>Low output</description>
                                    <value>#0</value>
                                </enumeratedValue>
                                <enumeratedValue>
                                    <name>1</name>
                                    <description>High output</description>
                                    <value>#1</value>
                                </enumeratedValue>
                            </enumeratedValues>
                        </field>
                        <field>
                            <name>PODR03</name>
                            <description>Pmn Output Data</description>
                            <lsb>3</lsb>
                            <msb>3</msb>
                            <access>read-write</access>
                            <enumeratedValues>
                                <enumeratedValue>
                                    <name>0</name>
                                    <description>Low output</description>
                                    <value>#0</value>
                                </enumeratedValue>
                                <enumeratedValue>
                                    <name>1</name>
                                    <description>High output</description>
                                    <value>#1</value>
                                </enumeratedValue>
                            </enumeratedValues>
                        </field>
                        <field>
                            <name>PODR04</name>
                            <description>Pmn Output Data</description>
                            <lsb>4</lsb>
                            <msb>4</msb>
                            <access>read-write</access>
                            <enumeratedValues>
                                <enumeratedValue>
                                    <name>0</name>
                                    <description>Low output</description>
                                    <value>#0</value>
                                </enumeratedValue>
                                <enumeratedValue>
                                    <name>1</name>
                                    <description>High output</description>
                                    <value>#1</value>
                                </enumeratedValue>
                            </enumeratedValues>
                        </field>
                        <field>
                            <name>PODR05</name>
                            <description>Pmn Output Data</description>
                            <lsb>5</lsb>
                            <msb>5</msb>
                            <access>read-write</access>
                            <enumeratedValues>
                                <enumeratedValue>
                                    <name>0</name>
                                    <description>Low output</description>
                                    <value>#0</value>
                                </enumeratedValue>
                                <enumeratedValue>
                                    <name>1</name>
                                    <description>High output</description>
                                    <value>#1</value>
                                </enumeratedValue>
                            </enumeratedValues>
                        </field>
                        <field>
                            <name>PODR06</name>
                            <description>Pmn Output Data</description>
                            <lsb>6</lsb>
                            <msb>6</msb>
                            <access>read-write</access>
                            <enumeratedValues>
                                <enumeratedValue>
                                    <name>0</name>
                                    <description>Low output</description>
                                    <value>#0</value>
                                </enumeratedValue>
                                <enumeratedValue>
                                    <name>1</name>
                                    <description>High output</description>
                                    <value>#1</value>
                                </enumeratedValue>
                            </enumeratedValues>
                        </field>
                        <field>
                            <name>PODR07</name>
                            <description>Pmn Output Data</description>
                            <lsb>7</lsb>
                            <msb>7</msb>
                            <access>read-write</access>
                            <enumeratedValues>
                                <enumeratedValue>
                                    <name>0</name>
                                    <description>Low output</description>
                                    <value>#0</value>
                                </enumeratedValue>
                                <enumeratedValue>
                                    <name>1</name>
                                    <description>High output</description>
                                    <value>#1</value>
                                </enumeratedValue>
                            </enumeratedValues>
                        </field>
                        <field>
                            <name>PODR08</name>
                            <description>Pmn Output Data</description>
                            <lsb>8</lsb>
                            <msb>8</msb>
                            <access>read-write</access>
                            <enumeratedValues>
                                <enumeratedValue>
                                    <name>0</name>
                                    <description>Low output</description>
                                    <value>#0</value>
                                </enumeratedValue>
                                <enumeratedValue>
                                    <name>1</name>
                                    <description>High output</description>
                                    <value>#1</value>
                                </enumeratedValue>
                            </enumeratedValues>
                        </field>
                        <field>
                            <name>PODR09</name>
                            <description>Pmn Output Data</description>
                            <lsb>9</lsb>
                            <msb>9</msb>
                            <access>read-write</access>
                            <enumeratedValues>
                                <enumeratedValue>
                                    <name>0</name>
                                    <description>Low output</description>
                                    <value>#0</value>
                                </enumeratedValue>
                                <enumeratedValue>
                                    <name>1</name>
                                    <description>High output</description>
                                    <value>#1</value>
                                </enumeratedValue>
                            </enumeratedValues>
                        </field>
                        <field>
                            <name>PODR10</name>
                            <description>Pmn Output Data</description>
                            <lsb>10</lsb>
                            <msb>10</msb>
                            <access>read-write</access>
                            <enumeratedValues>
                                <enumeratedValue>
                                    <name>0</name>
                                    <description>Low output</description>
                                    <value>#0</value>
                                </enumeratedValue>
                                <enumeratedValue>
                                    <name>1</name>
                                    <description>High output</description>
                                    <value>#1</value>
                                </enumeratedValue>
                            </enumeratedValues>
                        </field>
                        <field>
                            <name>PODR11</name>
                            <description>Pmn Output Data</description>
                            <lsb>11</lsb>
                            <msb>11</msb>
                            <access>read-write</access>
                            <enumeratedValues>
                                <enumeratedValue>
                                    <name>0</name>
                                    <description>Low output</description>
                                    <value>#0</value>
                                </enumeratedValue>
                                <enumeratedValue>
                                    <name>1</name>
                                    <description>High output</description>
                                    <value>#1</value>
                                </enumeratedValue>
                            </enumeratedValues>
                        </field>
                        <field>
                            <name>PODR12</name>
                            <description>Pmn Output Data</description>
                            <lsb>12</lsb>
                            <msb>12</msb>
                            <access>read-write</access>
                            <enumeratedValues>
                                <enumeratedValue>
                                    <name>0</name>
                                    <description>Low output</description>
                                    <value>#0</value>
                                </enumeratedValue>
                                <enumeratedValue>
                                    <name>1</name>
                                    <description>High output</description>
                                    <value>#1</value>
                                </enumeratedValue>
                            </enumeratedValues>
                        </field>
                        <field>
                            <name>PODR13</name>
                            <description>Pmn Output Data</description>
                            <lsb>13</lsb>
                            <msb>13</msb>
                            <access>read-write</access>
                            <enumeratedValues>
                                <enumeratedValue>
                                    <name>0</name>
                                    <description>Low output</description>
                                    <value>#0</value>
                                </enumeratedValue>
                                <enumeratedValue>
                                    <name>1</name>
                                    <description>High output</description>
                                    <value>#1</value>
                                </enumeratedValue>
                            </enumeratedValues>
                        </field>
                        <field>
                            <name>PODR14</name>
                            <description>Pmn Output Data</description>
                            <lsb>14</lsb>
                            <msb>14</msb>
                            <access>read-write</access>
                            <enumeratedValues>
                                <enumeratedValue>
                                    <name>0</name>
                                    <description>Low output</description>
                                    <value>#0</value>
                                </enumeratedValue>
                                <enumeratedValue>
                                    <name>1</name>
                                    <description>High output</description>
                                    <value>#1</value>
                                </enumeratedValue>
                            </enumeratedValues>
                        </field>
                        <field>
                            <name>PODR15</name>
                            <description>Pmn Output Data</description>
                            <lsb>15</lsb>
                            <msb>15</msb>
                            <access>read-write</access>
                            <enumeratedValues>
                                <enumeratedValue>
                                    <name>0</name>
                                    <description>Low output</description>
                                    <value>#0</value>
                                </enumeratedValue>
                                <enumeratedValue>
                                    <name>1</name>
                                    <description>High output</description>
                                    <value>#1</value>
                                </enumeratedValue>
                            </enumeratedValues>
                        </field>
                    </fields>
                </register>
                <register>
                    <name>PODR</name>
                    <description>Port Control Register 1</description>
                    <alternateRegister>PCNTR1</alternateRegister>
                    <addressOffset>0x002</addressOffset>
                    <size>16</size>
                    <access>read-write</access>
                    <resetValue>0x0000</resetValue>
                    <resetMask>0xffff</resetMask>
                    <fields>
                        <field>
                            <name>PDR00</name>
                            <description>Pmn Direction</description>
                            <lsb>0</lsb>
                            <msb>0</msb>
                            <access>read-write</access>
                            <enumeratedValues>
                                <enumeratedValue>
                                    <name>0</name>
                                    <description>Input (functions as an input pin)</description>
                                    <value>#0</value>
                                </enumeratedValue>
                                <enumeratedValue>
                                    <name>1</name>
                                    <description>Output (functions as an output pin)</description>
                                    <value>#1</value>
                                </enumeratedValue>
                            </enumeratedValues>
                        </field>
                        <field>
                            <name>PDR01</name>
                            <description>Pmn Direction</description>
                            <lsb>1</lsb>
                            <msb>1</msb>
                            <access>read-write</access>
                            <enumeratedValues>
                                <enumeratedValue>
                                    <name>0</name>
                                    <description>Input (functions as an input pin)</description>
                                    <value>#0</value>
                                </enumeratedValue>
                                <enumeratedValue>
                                    <name>1</name>
                                    <description>Output (functions as an output pin)</description>
                                    <value>#1</value>
                                </enumeratedValue>
                            </enumeratedValues>
                        </field>
                        <field>
                            <name>PDR02</name>
                            <description>Pmn Direction</description>
                            <lsb>2</lsb>
                            <msb>2</msb>
                            <access>read-write</access>
                            <enumeratedValues>
                                <enumeratedValue>
                                    <name>0</name>
                                    <description>Input (functions as an input pin)</description>
                                    <value>#0</value>
                                </enumeratedValue>
                                <enumeratedValue>
                                    <name>1</name>
                                    <description>Output (functions as an output pin)</description>
                                    <value>#1</value>
                                </enumeratedValue>
                            </enumeratedValues>
                        </field>
                        <field>
                            <name>PDR03</name>
                            <description>Pmn Direction</description>
                            <lsb>3</lsb>
                            <msb>3</msb>
                            <access>read-write</access>
                            <enumeratedValues>
                                <enumeratedValue>
                                    <name>0</name>
                                    <description>Input (functions as an input pin)</description>
                                    <value>#0</value>
                                </enumeratedValue>
                                <enumeratedValue>
                                    <name>1</name>
                                    <description>Output (functions as an output pin)</description>
                                    <value>#1</value>
                                </enumeratedValue>
                            </enumeratedValues>
                        </field>
                        <field>
                            <name>PDR04</name>
                            <description>Pmn Direction</description>
                            <lsb>4</lsb>
                            <msb>4</msb>
                            <access>read-write</access>
                            <enumeratedValues>
                                <enumeratedValue>
                                    <name>0</name>
                                    <description>Input (functions as an input pin)</description>
                                    <value>#0</value>
                                </enumeratedValue>
                                <enumeratedValue>
                                    <name>1</name>
                                    <description>Output (functions as an output pin)</description>
                                    <value>#1</value>
                                </enumeratedValue>
                            </enumeratedValues>
                        </field>
                        <field>
                            <name>PDR05</name>
                            <description>Pmn Direction</description>
                            <lsb>5</lsb>
                            <msb>5</msb>
                            <access>read-write</access>
                            <enumeratedValues>
                                <enumeratedValue>
                                    <name>0</name>
                                    <description>Input (functions as an input pin)</description>
                                    <value>#0</value>
                                </enumeratedValue>
                                <enumeratedValue>
                                    <name>1</name>
                                    <description>Output (functions as an output pin)</description>
                                    <value>#1</value>
                                </enumeratedValue>
                            </enumeratedValues>
                        </field>
                        <field>
                            <name>PDR06</name>
                            <description>Pmn Direction</description>
                            <lsb>6</lsb>
                            <msb>6</msb>
                            <access>read-write</access>
                            <enumeratedValues>
                                <enumeratedValue>
                                    <name>0</name>
                                    <description>Input (functions as an input pin)</description>
                                    <value>#0</value>
                                </enumeratedValue>
                                <enumeratedValue>
                                    <name>1</name>
                                    <description>Output (functions as an output pin)</description>
                                    <value>#1</value>
                                </enumeratedValue>
                            </enumeratedValues>
                        </field>
                        <field>
                            <name>PDR07</name>
                            <description>Pmn Direction</description>
                            <lsb>7</lsb>
                            <msb>7</msb>
                            <access>read-write</access>
                            <enumeratedValues>
                                <enumeratedValue>
                                    <name>0</name>
                                    <description>Input (functions as an input pin)</description>
                                    <value>#0</value>
                                </enumeratedValue>
                                <enumeratedValue>
                                    <name>1</name>
                                    <description>Output (functions as an output pin)</description>
                                    <value>#1</value>
                                </enumeratedValue>
                            </enumeratedValues>
                        </field>
                        <field>
                            <name>PDR08</name>
                            <description>Pmn Direction</description>
                            <lsb>8</lsb>
                            <msb>8</msb>
                            <access>read-write</access>
                            <enumeratedValues>
                                <enumeratedValue>
                                    <name>0</name>
                                    <description>Input (functions as an input pin)</description>
                                    <value>#0</value>
                                </enumeratedValue>
                                <enumeratedValue>
                                    <name>1</name>
                                    <description>Output (functions as an output pin)</description>
                                    <value>#1</value>
                                </enumeratedValue>
                            </enumeratedValues>
                        </field>
                        <field>
                            <name>PDR09</name>
                            <description>Pmn Direction</description>
                            <lsb>9</lsb>
                            <msb>9</msb>
                            <access>read-write</access>
                            <enumeratedValues>
                                <enumeratedValue>
                                    <name>0</name>
                                    <description>Input (functions as an input pin)</description>
                                    <value>#0</value>
                                </enumeratedValue>
                                <enumeratedValue>
                                    <name>1</name>
                                    <description>Output (functions as an output pin)</description>
                                    <value>#1</value>
                                </enumeratedValue>
                            </enumeratedValues>
                        </field>
                        <field>
                            <name>PDR10</name>
                            <description>Pmn Direction</description>
                            <lsb>10</lsb>
                            <msb>10</msb>
                            <access>read-write</access>
                            <enumeratedValues>
                                <enumeratedValue>
                                    <name>0</name>
                                    <description>Input (functions as an input pin)</description>
                                    <value>#0</value>
                                </enumeratedValue>
                                <enumeratedValue>
                                    <name>1</name>
                                    <description>Output (functions as an output pin)</description>
                                    <value>#1</value>
                                </enumeratedValue>
                            </enumeratedValues>
                        </field>
                        <field>
                            <name>PDR11</name>
                            <description>Pmn Direction</description>
                            <lsb>11</lsb>
                            <msb>11</msb>
                            <access>read-write</access>
                            <enumeratedValues>
                                <enumeratedValue>
                                    <name>0</name>
                                    <description>Input (functions as an input pin)</description>
                                    <value>#0</value>
                                </enumeratedValue>
                                <enumeratedValue>
                                    <name>1</name>
                                    <description>Output (functions as an output pin)</description>
                                    <value>#1</value>
                                </enumeratedValue>
                            </enumeratedValues>
                        </field>
                        <field>
                            <name>PDR12</name>
                            <description>Pmn Direction</description>
                            <lsb>12</lsb>
                            <msb>12</msb>
                            <access>read-write</access>
                            <enumeratedValues>
                                <enumeratedValue>
                                    <name>0</name>
                                    <description>Input (functions as an input pin)</description>
                                    <value>#0</value>
                                </enumeratedValue>
                                <enumeratedValue>
                                    <name>1</name>
                                    <description>Output (functions as an output pin)</description>
                                    <value>#1</value>
                                </enumeratedValue>
                            </enumeratedValues>
                        </field>
                        <field>
                            <name>PDR13</name>
                            <description>Pmn Direction</description>
                            <lsb>13</lsb>
                            <msb>13</msb>
                            <access>read-write</access>
                            <enumeratedValues>
                                <enumeratedValue>
                                    <name>0</name>
                                    <description>Input (functions as an input pin)</description>
                                    <value>#0</value>
                                </enumeratedValue>
                                <enumeratedValue>
                                    <name>1</name>
                                    <description>Output (functions as an output pin)</description>
                                    <value>#1</value>
                                </enumeratedValue>
                            </enumeratedValues>
                        </field>
                        <field>
                            <name>PDR14</name>
                            <description>Pmn Direction</description>
                            <lsb>14</lsb>
                            <msb>14</msb>
                            <access>read-write</access>
                            <enumeratedValues>
                                <enumeratedValue>
                                    <name>0</name>
                                    <description>Input (functions as an input pin)</description>
                                    <value>#0</value>
                                </enumeratedValue>
                                <enumeratedValue>
                                    <name>1</name>
                                    <description>Output (functions as an output pin)</description>
                                    <value>#1</value>
                                </enumeratedValue>
                            </enumeratedValues>
                        </field>
                        <field>
                            <name>PDR15</name>
                            <description>Pmn Direction</description>
                            <lsb>15</lsb>
                            <msb>15</msb>
                            <access>read-write</access>
                            <enumeratedValues>
                                <enumeratedValue>
                                    <name>0</name>
                                    <description>Input (functions as an input pin)</description>
                                    <value>#0</value>
                                </enumeratedValue>
                                <enumeratedValue>
                                    <name>1</name>
                                    <description>Output (functions as an output pin)</description>
                                    <value>#1</value>
                                </enumeratedValue>
                            </enumeratedValues>
                        </field>
                    </fields>
                </register>
                <register>
                    <name>PCNTR2</name>
                    <description>Port Control Register 2</description>
                    <addressOffset>0x004</addressOffset>
                    <size>32</size>
                    <access>read-only</access>
                    <resetValue>0x00000000</resetValue>
                    <resetMask>0xffff0000</resetMask>
                    <fields>
                        <field>
                            <name>PIDR00</name>
                            <description>Pmn State</description>
                            <lsb>0</lsb>
                            <msb>0</msb>
                            <access>read-only</access>
                            <enumeratedValues>
                                <enumeratedValue>
                                    <name>0</name>
                                    <description>Low level</description>
                                    <value>#0</value>
                                </enumeratedValue>
                                <enumeratedValue>
                                    <name>1</name>
                                    <description>High level</description>
                                    <value>#1</value>
                                </enumeratedValue>
                            </enumeratedValues>
                        </field>
                        <field>
                            <name>PIDR01</name>
                            <description>Pmn State</description>
                            <lsb>1</lsb>
                            <msb>1</msb>
                            <access>read-only</access>
                            <enumeratedValues>
                                <enumeratedValue>
                                    <name>0</name>
                                    <description>Low level</description>
                                    <value>#0</value>
                                </enumeratedValue>
                                <enumeratedValue>
                                    <name>1</name>
                                    <description>High level</description>
                                    <value>#1</value>
                                </enumeratedValue>
                            </enumeratedValues>
                        </field>
                        <field>
                            <name>PIDR02</name>
                            <description>Pmn State</description>
                            <lsb>2</lsb>
                            <msb>2</msb>
                            <access>read-only</access>
                            <enumeratedValues>
                                <enumeratedValue>
                                    <name>0</name>
                                    <description>Low level</description>
                                    <value>#0</value>
                                </enumeratedValue>
                                <enumeratedValue>
                                    <name>1</name>
                                    <description>High level</description>
                                    <value>#1</value>
                                </enumeratedValue>
                            </enumeratedValues>
                        </field>
                        <field>
                            <name>PIDR03</name>
                            <description>Pmn State</description>
                            <lsb>3</lsb>
                            <msb>3</msb>
                            <access>read-only</access>
                            <enumeratedValues>
                                <enumeratedValue>
                                    <name>0</name>
                                    <description>Low level</description>
                                    <value>#0</value>
                                </enumeratedValue>
                                <enumeratedValue>
                                    <name>1</name>
                                    <description>High level</description>
                                    <value>#1</value>
                                </enumeratedValue>
                            </enumeratedValues>
                        </field>
                        <field>
                            <name>PIDR04</name>
                            <description>Pmn State</description>
                            <lsb>4</lsb>
                            <msb>4</msb>
                            <access>read-only</access>
                            <enumeratedValues>
                                <enumeratedValue>
                                    <name>0</name>
                                    <description>Low level</description>
                                    <value>#0</value>
                                </enumeratedValue>
                                <enumeratedValue>
                                    <name>1</name>
                                    <description>High level</description>
                                    <value>#1</value>
                                </enumeratedValue>
                            </enumeratedValues>
                        </field>
                        <field>
                            <name>PIDR05</name>
                            <description>Pmn State</description>
                            <lsb>5</lsb>
                            <msb>5</msb>
                            <access>read-only</access>
                            <enumeratedValues>
                                <enumeratedValue>
                                    <name>0</name>
                                    <description>Low level</description>
                                    <value>#0</value>
                                </enumeratedValue>
                                <enumeratedValue>
                                    <name>1</name>
                                    <description>High level</description>
                                    <value>#1</value>
                                </enumeratedValue>
                            </enumeratedValues>
                        </field>
                        <field>
                            <name>PIDR06</name>
                            <description>Pmn State</description>
                            <lsb>6</lsb>
                            <msb>6</msb>
                            <access>read-only</access>
                            <enumeratedValues>
                                <enumeratedValue>
                                    <name>0</name>
                                    <description>Low level</description>
                                    <value>#0</value>
                                </enumeratedValue>
                                <enumeratedValue>
                                    <name>1</name>
                                    <description>High level</description>
                                    <value>#1</value>
                                </enumeratedValue>
                            </enumeratedValues>
                        </field>
                        <field>
                            <name>PIDR07</name>
                            <description>Pmn State</description>
                            <lsb>7</lsb>
                            <msb>7</msb>
                            <access>read-only</access>
                            <enumeratedValues>
                                <enumeratedValue>
                                    <name>0</name>
                                    <description>Low level</description>
                                    <value>#0</value>
                                </enumeratedValue>
                                <enumeratedValue>
                                    <name>1</name>
                                    <description>High level</description>
                                    <value>#1</value>
                                </enumeratedValue>
                            </enumeratedValues>
                        </field>
                        <field>
                            <name>PIDR08</name>
                            <description>Pmn State</description>
                            <lsb>8</lsb>
                            <msb>8</msb>
                            <access>read-only</access>
                            <enumeratedValues>
                                <enumeratedValue>
                                    <name>0</name>
                                    <description>Low level</description>
                                    <value>#0</value>
                                </enumeratedValue>
                                <enumeratedValue>
                                    <name>1</name>
                                    <description>High level</description>
                                    <value>#1</value>
                                </enumeratedValue>
                            </enumeratedValues>
                        </field>
                        <field>
                            <name>PIDR09</name>
                            <description>Pmn State</description>
                            <lsb>9</lsb>
                            <msb>9</msb>
                            <access>read-only</access>
                            <enumeratedValues>
                                <enumeratedValue>
                                    <name>0</name>
                                    <description>Low level</description>
                                    <value>#0</value>
                                </enumeratedValue>
                                <enumeratedValue>
                                    <name>1</name>
                                    <description>High level</description>
                                    <value>#1</value>
                                </enumeratedValue>
                            </enumeratedValues>
                        </field>
                        <field>
                            <name>PIDR10</name>
                            <description>Pmn State</description>
                            <lsb>10</lsb>
                            <msb>10</msb>
                            <access>read-only</access>
                            <enumeratedValues>
                                <enumeratedValue>
                                    <name>0</name>
                                    <description>Low level</description>
                                    <value>#0</value>
                                </enumeratedValue>
                                <enumeratedValue>
                                    <name>1</name>
                                    <description>High level</description>
                                    <value>#1</value>
                                </enumeratedValue>
                            </enumeratedValues>
                        </field>
                        <field>
                            <name>PIDR11</name>
                            <description>Pmn State</description>
                            <lsb>11</lsb>
                            <msb>11</msb>
                            <access>read-only</access>
                            <enumeratedValues>
                                <enumeratedValue>
                                    <name>0</name>
                                    <description>Low level</description>
                                    <value>#0</value>
                                </enumeratedValue>
                                <enumeratedValue>
                                    <name>1</name>
                                    <description>High level</description>
                                    <value>#1</value>
                                </enumeratedValue>
                            </enumeratedValues>
                        </field>
                        <field>
                            <name>PIDR12</name>
                            <description>Pmn State</description>
                            <lsb>12</lsb>
                            <msb>12</msb>
                            <access>read-only</access>
                            <enumeratedValues>
                                <enumeratedValue>
                                    <name>0</name>
                                    <description>Low level</description>
                                    <value>#0</value>
                                </enumeratedValue>
                                <enumeratedValue>
                                    <name>1</name>
                                    <description>High level</description>
                                    <value>#1</value>
                                </enumeratedValue>
                            </enumeratedValues>
                        </field>
                        <field>
                            <name>PIDR13</name>
                            <description>Pmn State</description>
                            <lsb>13</lsb>
                            <msb>13</msb>
                            <access>read-only</access>
                            <enumeratedValues>
                                <enumeratedValue>
                                    <name>0</name>
                                    <description>Low level</description>
                                    <value>#0</value>
                                </enumeratedValue>
                                <enumeratedValue>
                                    <name>1</name>
                                    <description>High level</description>
                                    <value>#1</value>
                                </enumeratedValue>
                            </enumeratedValues>
                        </field>
                        <field>
                            <name>PIDR14</name>
                            <description>Pmn State</description>
                            <lsb>14</lsb>
                            <msb>14</msb>
                            <access>read-only</access>
                            <enumeratedValues>
                                <enumeratedValue>
                                    <name>0</name>
                                    <description>Low level</description>
                                    <value>#0</value>
                                </enumeratedValue>
                                <enumeratedValue>
                                    <name>1</name>
                                    <description>High level</description>
                                    <value>#1</value>
                                </enumeratedValue>
                            </enumeratedValues>
                        </field>
                        <field>
                            <name>PIDR15</name>
                            <description>Pmn State</description>
                            <lsb>15</lsb>
                            <msb>15</msb>
                            <access>read-only</access>
                            <enumeratedValues>
                                <enumeratedValue>
                                    <name>0</name>
                                    <description>Low level</description>
                                    <value>#0</value>
                                </enumeratedValue>
                                <enumeratedValue>
                                    <name>1</name>
                                    <description>High level</description>
                                    <value>#1</value>
                                </enumeratedValue>
                            </enumeratedValues>
                        </field>
                    </fields>
                </register>
                <register>
                    <name>PIDR</name>
                    <description>Port Control Register 2</description>
                    <alternateRegister>PCNTR2</alternateRegister>
                    <addressOffset>0x004</addressOffset>
                    <size>16</size>
                    <access>read-only</access>
                    <resetValue>0x0000</resetValue>
                    <resetMask>0xffff</resetMask>
                </register>
                <register>
                    <name>PCNTR3</name>
                    <description>Port Control Register 3</description>
                    <addressOffset>0x008</addressOffset>
                    <size>32</size>
                    <access>write-only</access>
                    <resetValue>0x00000000</resetValue>
                    <resetMask>0xffffffff</resetMask>
                    <fields>
                        <field>
                            <name>POSR00</name>
                            <description>Pmn Output Set</description>
                            <lsb>0</lsb>
                            <msb>0</msb>
                            <access>write-only</access>
                            <enumeratedValues>
                                <enumeratedValue>
                                    <name>0</name>
                                    <description>No effect on output</description>
                                    <value>#0</value>
                                </enumeratedValue>
                                <enumeratedValue>
                                    <name>1</name>
                                    <description>High output</description>
                                    <value>#1</value>
                                </enumeratedValue>
                            </enumeratedValues>
                        </field>
                        <field>
                            <name>POSR01</name>
                            <description>Pmn Output Set</description>
                            <lsb>1</lsb>
                            <msb>1</msb>
                            <access>write-only</access>
                            <enumeratedValues>
                                <enumeratedValue>
                                    <name>0</name>
                                    <description>No effect on output</description>
                                    <value>#0</value>
                                </enumeratedValue>
                                <enumeratedValue>
                                    <name>1</name>
                                    <description>High output</description>
                                    <value>#1</value>
                                </enumeratedValue>
                            </enumeratedValues>
                        </field>
                        <field>
                            <name>POSR02</name>
                            <description>Pmn Output Set</description>
                            <lsb>2</lsb>
                            <msb>2</msb>
                            <access>write-only</access>
                            <enumeratedValues>
                                <enumeratedValue>
                                    <name>0</name>
                                    <description>No effect on output</description>
                                    <value>#0</value>
                                </enumeratedValue>
                                <enumeratedValue>
                                    <name>1</name>
                                    <description>High output</description>
                                    <value>#1</value>
                                </enumeratedValue>
                            </enumeratedValues>
                        </field>
                        <field>
                            <name>POSR03</name>
                            <description>Pmn Output Set</description>
                            <lsb>3</lsb>
                            <msb>3</msb>
                            <access>write-only</access>
                            <enumeratedValues>
                                <enumeratedValue>
                                    <name>0</name>
                                    <description>No effect on output</description>
                                    <value>#0</value>
                                </enumeratedValue>
                                <enumeratedValue>
                                    <name>1</name>
                                    <description>High output</description>
                                    <value>#1</value>
                                </enumeratedValue>
                            </enumeratedValues>
                        </field>
                        <field>
                            <name>POSR04</name>
                            <description>Pmn Output Set</description>
                            <lsb>4</lsb>
                            <msb>4</msb>
                            <access>write-only</access>
                            <enumeratedValues>
                                <enumeratedValue>
                                    <name>0</name>
                                    <description>No effect on output</description>
                                    <value>#0</value>
                                </enumeratedValue>
                                <enumeratedValue>
                                    <name>1</name>
                                    <description>High output</description>
                                    <value>#1</value>
                                </enumeratedValue>
                            </enumeratedValues>
                        </field>
                        <field>
                            <name>POSR05</name>
                            <description>Pmn Output Set</description>
                            <lsb>5</lsb>
                            <msb>5</msb>
                            <access>write-only</access>
                            <enumeratedValues>
                                <enumeratedValue>
                                    <name>0</name>
                                    <description>No effect on output</description>
                                    <value>#0</value>
                                </enumeratedValue>
                                <enumeratedValue>
                                    <name>1</name>
                                    <description>High output</description>
                                    <value>#1</value>
                                </enumeratedValue>
                            </enumeratedValues>
                        </field>
                        <field>
                            <name>POSR06</name>
                            <description>Pmn Output Set</description>
                            <lsb>6</lsb>
                            <msb>6</msb>
                            <access>write-only</access>
                            <enumeratedValues>
                                <enumeratedValue>
                                    <name>0</name>
                                    <description>No effect on output</description>
                                    <value>#0</value>
                                </enumeratedValue>
                                <enumeratedValue>
                                    <name>1</name>
                                    <description>High output</description>
                                    <value>#1</value>
                                </enumeratedValue>
                            </enumeratedValues>
                        </field>
                        <field>
                            <name>POSR07</name>
                            <description>Pmn Output Set</description>
                            <lsb>7</lsb>
                            <msb>7</msb>
                            <access>write-only</access>
                            <enumeratedValues>
                                <enumeratedValue>
                                    <name>0</name>
                                    <description>No effect on output</description>
                                    <value>#0</value>
                                </enumeratedValue>
                                <enumeratedValue>
                                    <name>1</name>
                                    <description>High output</description>
                                    <value>#1</value>
                                </enumeratedValue>
                            </enumeratedValues>
                        </field>
                        <field>
                            <name>POSR08</name>
                            <description>Pmn Output Set</description>
                            <lsb>8</lsb>
                            <msb>8</msb>
                            <access>write-only</access>
                            <enumeratedValues>
                                <enumeratedValue>
                                    <name>0</name>
                                    <description>No effect on output</description>
                                    <value>#0</value>
                                </enumeratedValue>
                                <enumeratedValue>
                                    <name>1</name>
                                    <description>High output</description>
                                    <value>#1</value>
                                </enumeratedValue>
                            </enumeratedValues>
                        </field>
                        <field>
                            <name>POSR09</name>
                            <description>Pmn Output Set</description>
                            <lsb>9</lsb>
                            <msb>9</msb>
                            <access>write-only</access>
                            <enumeratedValues>
                                <enumeratedValue>
                                    <name>0</name>
                                    <description>No effect on output</description>
                                    <value>#0</value>
                                </enumeratedValue>
                                <enumeratedValue>
                                    <name>1</name>
                                    <description>High output</description>
                                    <value>#1</value>
                                </enumeratedValue>
                            </enumeratedValues>
                        </field>
                        <field>
                            <name>POSR10</name>
                            <description>Pmn Output Set</description>
                            <lsb>10</lsb>
                            <msb>10</msb>
                            <access>write-only</access>
                            <enumeratedValues>
                                <enumeratedValue>
                                    <name>0</name>
                                    <description>No effect on output</description>
                                    <value>#0</value>
                                </enumeratedValue>
                                <enumeratedValue>
                                    <name>1</name>
                                    <description>High output</description>
                                    <value>#1</value>
                                </enumeratedValue>
                            </enumeratedValues>
                        </field>
                        <field>
                            <name>POSR11</name>
                            <description>Pmn Output Set</description>
                            <lsb>11</lsb>
                            <msb>11</msb>
                            <access>write-only</access>
                            <enumeratedValues>
                                <enumeratedValue>
                                    <name>0</name>
                                    <description>No effect on output</description>
                                    <value>#0</value>
                                </enumeratedValue>
                                <enumeratedValue>
                                    <name>1</name>
                                    <description>High output</description>
                                    <value>#1</value>
                                </enumeratedValue>
                            </enumeratedValues>
                        </field>
                        <field>
                            <name>POSR12</name>
                            <description>Pmn Output Set</description>
                            <lsb>12</lsb>
                            <msb>12</msb>
                            <access>write-only</access>
                            <enumeratedValues>
                                <enumeratedValue>
                                    <name>0</name>
                                    <description>No effect on output</description>
                                    <value>#0</value>
                                </enumeratedValue>
                                <enumeratedValue>
                                    <name>1</name>
                                    <description>High output</description>
                                    <value>#1</value>
                                </enumeratedValue>
                            </enumeratedValues>
                        </field>
                        <field>
                            <name>POSR13</name>
                            <description>Pmn Output Set</description>
                            <lsb>13</lsb>
                            <msb>13</msb>
                            <access>write-only</access>
                            <enumeratedValues>
                                <enumeratedValue>
                                    <name>0</name>
                                    <description>No effect on output</description>
                                    <value>#0</value>
                                </enumeratedValue>
                                <enumeratedValue>
                                    <name>1</name>
                                    <description>High output</description>
                                    <value>#1</value>
                                </enumeratedValue>
                            </enumeratedValues>
                        </field>
                        <field>
                            <name>POSR14</name>
                            <description>Pmn Output Set</description>
                            <lsb>14</lsb>
                            <msb>14</msb>
                            <access>write-only</access>
                            <enumeratedValues>
                                <enumeratedValue>
                                    <name>0</name>
                                    <description>No effect on output</description>
                                    <value>#0</value>
                                </enumeratedValue>
                                <enumeratedValue>
                                    <name>1</name>
                                    <description>High output</description>
                                    <value>#1</value>
                                </enumeratedValue>
                            </enumeratedValues>
                        </field>
                        <field>
                            <name>POSR15</name>
                            <description>Pmn Output Set</description>
                            <lsb>15</lsb>
                            <msb>15</msb>
                            <access>write-only</access>
                            <enumeratedValues>
                                <enumeratedValue>
                                    <name>0</name>
                                    <description>No effect on output</description>
                                    <value>#0</value>
                                </enumeratedValue>
                                <enumeratedValue>
                                    <name>1</name>
                                    <description>High output</description>
                                    <value>#1</value>
                                </enumeratedValue>
                            </enumeratedValues>
                        </field>
                        <field>
                            <name>PORR00</name>
                            <description>Pmn Output Reset</description>
                            <lsb>16</lsb>
                            <msb>16</msb>
                            <access>write-only</access>
                            <enumeratedValues>
                                <enumeratedValue>
                                    <name>0</name>
                                    <description>No effect on output</description>
                                    <value>#0</value>
                                </enumeratedValue>
                                <enumeratedValue>
                                    <name>1</name>
                                    <description>Low output</description>
                                    <value>#1</value>
                                </enumeratedValue>
                            </enumeratedValues>
                        </field>
                        <field>
                            <name>PORR01</name>
                            <description>Pmn Output Reset</description>
                            <lsb>17</lsb>
                            <msb>17</msb>
                            <access>write-only</access>
                            <enumeratedValues>
                                <enumeratedValue>
                                    <name>0</name>
                                    <description>No effect on output</description>
                                    <value>#0</value>
                                </enumeratedValue>
                                <enumeratedValue>
                                    <name>1</name>
                                    <description>Low output</description>
                                    <value>#1</value>
                                </enumeratedValue>
                            </enumeratedValues>
                        </field>
                        <field>
                            <name>PORR02</name>
                            <description>Pmn Output Reset</description>
                            <lsb>18</lsb>
                            <msb>18</msb>
                            <access>write-only</access>
                            <enumeratedValues>
                                <enumeratedValue>
                                    <name>0</name>
                                    <description>No effect on output</description>
                                    <value>#0</value>
                                </enumeratedValue>
                                <enumeratedValue>
                                    <name>1</name>
                                    <description>Low output</description>
                                    <value>#1</value>
                                </enumeratedValue>
                            </enumeratedValues>
                        </field>
                        <field>
                            <name>PORR03</name>
                            <description>Pmn Output Reset</description>
                            <lsb>19</lsb>
                            <msb>19</msb>
                            <access>write-only</access>
                            <enumeratedValues>
                                <enumeratedValue>
                                    <name>0</name>
                                    <description>No effect on output</description>
                                    <value>#0</value>
                                </enumeratedValue>
                                <enumeratedValue>
                                    <name>1</name>
                                    <description>Low output</description>
                                    <value>#1</value>
                                </enumeratedValue>
                            </enumeratedValues>
                        </field>
                        <field>
                            <name>PORR04</name>
                            <description>Pmn Output Reset</description>
                            <lsb>20</lsb>
                            <msb>20</msb>
                            <access>write-only</access>
                            <enumeratedValues>
                                <enumeratedValue>
                                    <name>0</name>
                                    <description>No effect on output</description>
                                    <value>#0</value>
                                </enumeratedValue>
                                <enumeratedValue>
                                    <name>1</name>
                                    <description>Low output</description>
                                    <value>#1</value>
                                </enumeratedValue>
                            </enumeratedValues>
                        </field>
                        <field>
                            <name>PORR05</name>
                            <description>Pmn Output Reset</description>
                            <lsb>21</lsb>
                            <msb>21</msb>
                            <access>write-only</access>
                            <enumeratedValues>
                                <enumeratedValue>
                                    <name>0</name>
                                    <description>No effect on output</description>
                                    <value>#0</value>
                                </enumeratedValue>
                                <enumeratedValue>
                                    <name>1</name>
                                    <description>Low output</description>
                                    <value>#1</value>
                                </enumeratedValue>
                            </enumeratedValues>
                        </field>
                        <field>
                            <name>PORR06</name>
                            <description>Pmn Output Reset</description>
                            <lsb>22</lsb>
                            <msb>22</msb>
                            <access>write-only</access>
                            <enumeratedValues>
                                <enumeratedValue>
                                    <name>0</name>
                                    <description>No effect on output</description>
                                    <value>#0</value>
                                </enumeratedValue>
                                <enumeratedValue>
                                    <name>1</name>
                                    <description>Low output</description>
                                    <value>#1</value>
                                </enumeratedValue>
                            </enumeratedValues>
                        </field>
                        <field>
                            <name>PORR07</name>
                            <description>Pmn Output Reset</description>
                            <lsb>23</lsb>
                            <msb>23</msb>
                            <access>write-only</access>
                            <enumeratedValues>
                                <enumeratedValue>
                                    <name>0</name>
                                    <description>No effect on output</description>
                                    <value>#0</value>
                                </enumeratedValue>
                                <enumeratedValue>
                                    <name>1</name>
                                    <description>Low output</description>
                                    <value>#1</value>
                                </enumeratedValue>
                            </enumeratedValues>
                        </field>
                        <field>
                            <name>PORR08</name>
                            <description>Pmn Output Reset</description>
                            <lsb>24</lsb>
                            <msb>24</msb>
                            <access>write-only</access>
                            <enumeratedValues>
                                <enumeratedValue>
                                    <name>0</name>
                                    <description>No effect on output</description>
                                    <value>#0</value>
                                </enumeratedValue>
                                <enumeratedValue>
                                    <name>1</name>
                                    <description>Low output</description>
                                    <value>#1</value>
                                </enumeratedValue>
                            </enumeratedValues>
                        </field>
                        <field>
                            <name>PORR09</name>
                            <description>Pmn Output Reset</description>
                            <lsb>25</lsb>
                            <msb>25</msb>
                            <access>write-only</access>
                            <enumeratedValues>
                                <enumeratedValue>
                                    <name>0</name>
                                    <description>No effect on output</description>
                                    <value>#0</value>
                                </enumeratedValue>
                                <enumeratedValue>
                                    <name>1</name>
                                    <description>Low output</description>
                                    <value>#1</value>
                                </enumeratedValue>
                            </enumeratedValues>
                        </field>
                        <field>
                            <name>PORR10</name>
                            <description>Pmn Output Reset</description>
                            <lsb>26</lsb>
                            <msb>26</msb>
                            <access>write-only</access>
                            <enumeratedValues>
                                <enumeratedValue>
                                    <name>0</name>
                                    <description>No effect on output</description>
                                    <value>#0</value>
                                </enumeratedValue>
                                <enumeratedValue>
                                    <name>1</name>
                                    <description>Low output</description>
                                    <value>#1</value>
                                </enumeratedValue>
                            </enumeratedValues>
                        </field>
                        <field>
                            <name>PORR11</name>
                            <description>Pmn Output Reset</description>
                            <lsb>27</lsb>
                            <msb>27</msb>
                            <access>write-only</access>
                            <enumeratedValues>
                                <enumeratedValue>
                                    <name>0</name>
                                    <description>No effect on output</description>
                                    <value>#0</value>
                                </enumeratedValue>
                                <enumeratedValue>
                                    <name>1</name>
                                    <description>Low output</description>
                                    <value>#1</value>
                                </enumeratedValue>
                            </enumeratedValues>
                        </field>
                        <field>
                            <name>PORR12</name>
                            <description>Pmn Output Reset</description>
                            <lsb>28</lsb>
                            <msb>28</msb>
                            <access>write-only</access>
                            <enumeratedValues>
                                <enumeratedValue>
                                    <name>0</name>
                                    <description>No effect on output</description>
                                    <value>#0</value>
                                </enumeratedValue>
                                <enumeratedValue>
                                    <name>1</name>
                                    <description>Low output</description>
                                    <value>#1</value>
                                </enumeratedValue>
                            </enumeratedValues>
                        </field>
                        <field>
                            <name>PORR13</name>
                            <description>Pmn Output Reset</description>
                            <lsb>29</lsb>
                            <msb>29</msb>
                            <access>write-only</access>
                            <enumeratedValues>
                                <enumeratedValue>
                                    <name>0</name>
                                    <description>No effect on output</description>
                                    <value>#0</value>
                                </enumeratedValue>
                                <enumeratedValue>
                                    <name>1</name>
                                    <description>Low output</description>
                                    <value>#1</value>
                                </enumeratedValue>
                            </enumeratedValues>
                        </field>
                        <field>
                            <name>PORR14</name>
                            <description>Pmn Output Reset</description>
                            <lsb>30</lsb>
                            <msb>30</msb>
                            <access>write-only</access>
                            <enumeratedValues>
                                <enumeratedValue>
                                    <name>0</name>
                                    <description>No effect on output</description>
                                    <value>#0</value>
                                </enumeratedValue>
                                <enumeratedValue>
                                    <name>1</name>
                                    <description>Low output</description>
                                    <value>#1</value>
                                </enumeratedValue>
                            </enumeratedValues>
                        </field>
                        <field>
                            <name>PORR15</name>
                            <description>Pmn Output Reset</description>
                            <lsb>31</lsb>
                            <msb>31</msb>
                            <access>write-only</access>
                            <enumeratedValues>
                                <enumeratedValue>
                                    <name>0</name>
                                    <description>No effect on output</description>
                                    <value>#0</value>
                                </enumeratedValue>
                                <enumeratedValue>
                                    <name>1</name>
                                    <description>Low output</description>
                                    <value>#1</value>
                                </enumeratedValue>
                            </enumeratedValues>
                        </field>
                    </fields>
                </register>
                <register>
                    <name>POSR</name>
                    <description>Port Control Register 3</description>
                    <alternateRegister>PCNTR3</alternateRegister>
                    <addressOffset>0x008</addressOffset>
                    <size>16</size>
                    <access>write-only</access>
                    <resetValue>0x0000</resetValue>
                    <resetMask>0xffff</resetMask>
                    <fields>
                        <field>
                            <name>PORR00</name>
                            <description>Pmn Output Reset</description>
                            <lsb>0</lsb>
                            <msb>0</msb>
                            <access>write-only</access>
                            <enumeratedValues>
                                <enumeratedValue>
                                    <name>0</name>
                                    <description>No effect on output</description>
                                    <value>#0</value>
                                </enumeratedValue>
                                <enumeratedValue>
                                    <name>1</name>
                                    <description>Low output</description>
                                    <value>#1</value>
                                </enumeratedValue>
                            </enumeratedValues>
                        </field>
                        <field>
                            <name>PORR01</name>
                            <description>Pmn Output Reset</description>
                            <lsb>1</lsb>
                            <msb>1</msb>
                            <access>write-only</access>
                            <enumeratedValues>
                                <enumeratedValue>
                                    <name>0</name>
                                    <description>No effect on output</description>
                                    <value>#0</value>
                                </enumeratedValue>
                                <enumeratedValue>
                                    <name>1</name>
                                    <description>Low output</description>
                                    <value>#1</value>
                                </enumeratedValue>
                            </enumeratedValues>
                        </field>
                        <field>
                            <name>PORR02</name>
                            <description>Pmn Output Reset</description>
                            <lsb>2</lsb>
                            <msb>2</msb>
                            <access>write-only</access>
                            <enumeratedValues>
                                <enumeratedValue>
                                    <name>0</name>
                                    <description>No effect on output</description>
                                    <value>#0</value>
                                </enumeratedValue>
                                <enumeratedValue>
                                    <name>1</name>
                                    <description>Low output</description>
                                    <value>#1</value>
                                </enumeratedValue>
                            </enumeratedValues>
                        </field>
                        <field>
                            <name>PORR03</name>
                            <description>Pmn Output Reset</description>
                            <lsb>3</lsb>
                            <msb>3</msb>
                            <access>write-only</access>
                            <enumeratedValues>
                                <enumeratedValue>
                                    <name>0</name>
                                    <description>No effect on output</description>
                                    <value>#0</value>
                                </enumeratedValue>
                                <enumeratedValue>
                                    <name>1</name>
                                    <description>Low output</description>
                                    <value>#1</value>
                                </enumeratedValue>
                            </enumeratedValues>
                        </field>
                        <field>
                            <name>PORR04</name>
                            <description>Pmn Output Reset</description>
                            <lsb>4</lsb>
                            <msb>4</msb>
                            <access>write-only</access>
                            <enumeratedValues>
                                <enumeratedValue>
                                    <name>0</name>
                                    <description>No effect on output</description>
                                    <value>#0</value>
                                </enumeratedValue>
                                <enumeratedValue>
                                    <name>1</name>
                                    <description>Low output</description>
                                    <value>#1</value>
                                </enumeratedValue>
                            </enumeratedValues>
                        </field>
                        <field>
                            <name>PORR05</name>
                            <description>Pmn Output Reset</description>
                            <lsb>5</lsb>
                            <msb>5</msb>
                            <access>write-only</access>
                            <enumeratedValues>
                                <enumeratedValue>
                                    <name>0</name>
                                    <description>No effect on output</description>
                                    <value>#0</value>
                                </enumeratedValue>
                                <enumeratedValue>
                                    <name>1</name>
                                    <description>Low output</description>
                                    <value>#1</value>
                                </enumeratedValue>
                            </enumeratedValues>
                        </field>
                        <field>
                            <name>PORR06</name>
                            <description>Pmn Output Reset</description>
                            <lsb>6</lsb>
                            <msb>6</msb>
                            <access>write-only</access>
                            <enumeratedValues>
                                <enumeratedValue>
                                    <name>0</name>
                                    <description>No effect on output</description>
                                    <value>#0</value>
                                </enumeratedValue>
                                <enumeratedValue>
                                    <name>1</name>
                                    <description>Low output</description>
                                    <value>#1</value>
                                </enumeratedValue>
                            </enumeratedValues>
                        </field>
                        <field>
                            <name>PORR07</name>
                            <description>Pmn Output Reset</description>
                            <lsb>7</lsb>
                            <msb>7</msb>
                            <access>write-only</access>
                            <enumeratedValues>
                                <enumeratedValue>
                                    <name>0</name>
                                    <description>No effect on output</description>
                                    <value>#0</value>
                                </enumeratedValue>
                                <enumeratedValue>
                                    <name>1</name>
                                    <description>Low output</description>
                                    <value>#1</value>
                                </enumeratedValue>
                            </enumeratedValues>
                        </field>
                        <field>
                            <name>PORR08</name>
                            <description>Pmn Output Reset</description>
                            <lsb>8</lsb>
                            <msb>8</msb>
                            <access>write-only</access>
                            <enumeratedValues>
                                <enumeratedValue>
                                    <name>0</name>
                                    <description>No effect on output</description>
                                    <value>#0</value>
                                </enumeratedValue>
                                <enumeratedValue>
                                    <name>1</name>
                                    <description>Low output</description>
                                    <value>#1</value>
                                </enumeratedValue>
                            </enumeratedValues>
                        </field>
                        <field>
                            <name>PORR09</name>
                            <description>Pmn Output Reset</description>
                            <lsb>9</lsb>
                            <msb>9</msb>
                            <access>write-only</access>
                            <enumeratedValues>
                                <enumeratedValue>
                                    <name>0</name>
                                    <description>No effect on output</description>
                                    <value>#0</value>
                                </enumeratedValue>
                                <enumeratedValue>
                                    <name>1</name>
                                    <description>Low output</description>
                                    <value>#1</value>
                                </enumeratedValue>
                            </enumeratedValues>
                        </field>
                        <field>
                            <name>PORR10</name>
                            <description>Pmn Output Reset</description>
                            <lsb>10</lsb>
                            <msb>10</msb>
                            <access>write-only</access>
                            <enumeratedValues>
                                <enumeratedValue>
                                    <name>0</name>
                                    <description>No effect on output</description>
                                    <value>#0</value>
                                </enumeratedValue>
                                <enumeratedValue>
                                    <name>1</name>
                                    <description>Low output</description>
                                    <value>#1</value>
                                </enumeratedValue>
                            </enumeratedValues>
                        </field>
                        <field>
                            <name>PORR11</name>
                            <description>Pmn Output Reset</description>
                            <lsb>11</lsb>
                            <msb>11</msb>
                            <access>write-only</access>
                            <enumeratedValues>
                                <enumeratedValue>
                                    <name>0</name>
                                    <description>No effect on output</description>
                                    <value>#0</value>
                                </enumeratedValue>
                                <enumeratedValue>
                                    <name>1</name>
                                    <description>Low output</description>
                                    <value>#1</value>
                                </enumeratedValue>
                            </enumeratedValues>
                        </field>
                        <field>
                            <name>PORR12</name>
                            <description>Pmn Output Reset</description>
                            <lsb>12</lsb>
                            <msb>12</msb>
                            <access>write-only</access>
                            <enumeratedValues>
                                <enumeratedValue>
                                    <name>0</name>
                                    <description>No effect on output</description>
                                    <value>#0</value>
                                </enumeratedValue>
                                <enumeratedValue>
                                    <name>1</name>
                                    <description>Low output</description>
                                    <value>#1</value>
                                </enumeratedValue>
                            </enumeratedValues>
                        </field>
                        <field>
                            <name>PORR13</name>
                            <description>Pmn Output Reset</description>
                            <lsb>13</lsb>
                            <msb>13</msb>
                            <access>write-only</access>
                            <enumeratedValues>
                                <enumeratedValue>
                                    <name>0</name>
                                    <description>No effect on output</description>
                                    <value>#0</value>
                                </enumeratedValue>
                                <enumeratedValue>
                                    <name>1</name>
                                    <description>Low output</description>
                                    <value>#1</value>
                                </enumeratedValue>
                            </enumeratedValues>
                        </field>
                        <field>
                            <name>PORR14</name>
                            <description>Pmn Output Reset</description>
                            <lsb>14</lsb>
                            <msb>14</msb>
                            <access>write-only</access>
                            <enumeratedValues>
                                <enumeratedValue>
                                    <name>0</name>
                                    <description>No effect on output</description>
                                    <value>#0</value>
                                </enumeratedValue>
                                <enumeratedValue>
                                    <name>1</name>
                                    <description>Low output</description>
                                    <value>#1</value>
                                </enumeratedValue>
                            </enumeratedValues>
                        </field>
                        <field>
                            <name>PORR15</name>
                            <description>Pmn Output Reset</description>
                            <lsb>15</lsb>
                            <msb>15</msb>
                            <access>write-only</access>
                            <enumeratedValues>
                                <enumeratedValue>
                                    <name>0</name>
                                    <description>No effect on output</description>
                                    <value>#0</value>
                                </enumeratedValue>
                                <enumeratedValue>
                                    <name>1</name>
                                    <description>Low output</description>
                                    <value>#1</value>
                                </enumeratedValue>
                            </enumeratedValues>
                        </field>
                    </fields>
                </register>
                <register>
                    <name>PORR</name>
                    <description>Port Control Register 3</description>
                    <alternateRegister>PCNTR3</alternateRegister>
                    <addressOffset>0x00A</addressOffset>
                    <size>16</size>
                    <access>write-only</access>
                    <resetValue>0x0000</resetValue>
                    <resetMask>0xffff</resetMask>
                    <fields>
                        <field>
                            <name>POSR00</name>
                            <description>Pmn Output Set</description>
                            <lsb>0</lsb>
                            <msb>0</msb>
                            <access>write-only</access>
                            <enumeratedValues>
                                <enumeratedValue>
                                    <name>0</name>
                                    <description>No effect on output</description>
                                    <value>#0</value>
                                </enumeratedValue>
                                <enumeratedValue>
                                    <name>1</name>
                                    <description>High output</description>
                                    <value>#1</value>
                                </enumeratedValue>
                            </enumeratedValues>
                        </field>
                        <field>
                            <name>POSR01</name>
                            <description>Pmn Output Set</description>
                            <lsb>1</lsb>
                            <msb>1</msb>
                            <access>write-only</access>
                            <enumeratedValues>
                                <enumeratedValue>
                                    <name>0</name>
                                    <description>No effect on output</description>
                                    <value>#0</value>
                                </enumeratedValue>
                                <enumeratedValue>
                                    <name>1</name>
                                    <description>High output</description>
                                    <value>#1</value>
                                </enumeratedValue>
                            </enumeratedValues>
                        </field>
                        <field>
                            <name>POSR02</name>
                            <description>Pmn Output Set</description>
                            <lsb>2</lsb>
                            <msb>2</msb>
                            <access>write-only</access>
                            <enumeratedValues>
                                <enumeratedValue>
                                    <name>0</name>
                                    <description>No effect on output</description>
                                    <value>#0</value>
                                </enumeratedValue>
                                <enumeratedValue>
                                    <name>1</name>
                                    <description>High output</description>
                                    <value>#1</value>
                                </enumeratedValue>
                            </enumeratedValues>
                        </field>
                        <field>
                            <name>POSR03</name>
                            <description>Pmn Output Set</description>
                            <lsb>3</lsb>
                            <msb>3</msb>
                            <access>write-only</access>
                            <enumeratedValues>
                                <enumeratedValue>
                                    <name>0</name>
                                    <description>No effect on output</description>
                                    <value>#0</value>
                                </enumeratedValue>
                                <enumeratedValue>
                                    <name>1</name>
                                    <description>High output</description>
                                    <value>#1</value>
                                </enumeratedValue>
                            </enumeratedValues>
                        </field>
                        <field>
                            <name>POSR04</name>
                            <description>Pmn Output Set</description>
                            <lsb>4</lsb>
                            <msb>4</msb>
                            <access>write-only</access>
                            <enumeratedValues>
                                <enumeratedValue>
                                    <name>0</name>
                                    <description>No effect on output</description>
                                    <value>#0</value>
                                </enumeratedValue>
                                <enumeratedValue>
                                    <name>1</name>
                                    <description>High output</description>
                                    <value>#1</value>
                                </enumeratedValue>
                            </enumeratedValues>
                        </field>
                        <field>
                            <name>POSR05</name>
                            <description>Pmn Output Set</description>
                            <lsb>5</lsb>
                            <msb>5</msb>
                            <access>write-only</access>
                            <enumeratedValues>
                                <enumeratedValue>
                                    <name>0</name>
                                    <description>No effect on output</description>
                                    <value>#0</value>
                                </enumeratedValue>
                                <enumeratedValue>
                                    <name>1</name>
                                    <description>High output</description>
                                    <value>#1</value>
                                </enumeratedValue>
                            </enumeratedValues>
                        </field>
                        <field>
                            <name>POSR06</name>
                            <description>Pmn Output Set</description>
                            <lsb>6</lsb>
                            <msb>6</msb>
                            <access>write-only</access>
                            <enumeratedValues>
                                <enumeratedValue>
                                    <name>0</name>
                                    <description>No effect on output</description>
                                    <value>#0</value>
                                </enumeratedValue>
                                <enumeratedValue>
                                    <name>1</name>
                                    <description>High output</description>
                                    <value>#1</value>
                                </enumeratedValue>
                            </enumeratedValues>
                        </field>
                        <field>
                            <name>POSR07</name>
                            <description>Pmn Output Set</description>
                            <lsb>7</lsb>
                            <msb>7</msb>
                            <access>write-only</access>
                            <enumeratedValues>
                                <enumeratedValue>
                                    <name>0</name>
                                    <description>No effect on output</description>
                                    <value>#0</value>
                                </enumeratedValue>
                                <enumeratedValue>
                                    <name>1</name>
                                    <description>High output</description>
                                    <value>#1</value>
                                </enumeratedValue>
                            </enumeratedValues>
                        </field>
                        <field>
                            <name>POSR08</name>
                            <description>Pmn Output Set</description>
                            <lsb>8</lsb>
                            <msb>8</msb>
                            <access>write-only</access>
                            <enumeratedValues>
                                <enumeratedValue>
                                    <name>0</name>
                                    <description>No effect on output</description>
                                    <value>#0</value>
                                </enumeratedValue>
                                <enumeratedValue>
                                    <name>1</name>
                                    <description>High output</description>
                                    <value>#1</value>
                                </enumeratedValue>
                            </enumeratedValues>
                        </field>
                        <field>
                            <name>POSR09</name>
                            <description>Pmn Output Set</description>
                            <lsb>9</lsb>
                            <msb>9</msb>
                            <access>write-only</access>
                            <enumeratedValues>
                                <enumeratedValue>
                                    <name>0</name>
                                    <description>No effect on output</description>
                                    <value>#0</value>
                                </enumeratedValue>
                                <enumeratedValue>
                                    <name>1</name>
                                    <description>High output</description>
                                    <value>#1</value>
                                </enumeratedValue>
                            </enumeratedValues>
                        </field>
                        <field>
                            <name>POSR10</name>
                            <description>Pmn Output Set</description>
                            <lsb>10</lsb>
                            <msb>10</msb>
                            <access>write-only</access>
                            <enumeratedValues>
                                <enumeratedValue>
                                    <name>0</name>
                                    <description>No effect on output</description>
                                    <value>#0</value>
                                </enumeratedValue>
                                <enumeratedValue>
                                    <name>1</name>
                                    <description>High output</description>
                                    <value>#1</value>
                                </enumeratedValue>
                            </enumeratedValues>
                        </field>
                        <field>
                            <name>POSR11</name>
                            <description>Pmn Output Set</description>
                            <lsb>11</lsb>
                            <msb>11</msb>
                            <access>write-only</access>
                            <enumeratedValues>
                                <enumeratedValue>
                                    <name>0</name>
                                    <description>No effect on output</description>
                                    <value>#0</value>
                                </enumeratedValue>
                                <enumeratedValue>
                                    <name>1</name>
                                    <description>High output</description>
                                    <value>#1</value>
                                </enumeratedValue>
                            </enumeratedValues>
                        </field>
                        <field>
                            <name>POSR12</name>
                            <description>Pmn Output Set</description>
                            <lsb>12</lsb>
                            <msb>12</msb>
                            <access>write-only</access>
                            <enumeratedValues>
                                <enumeratedValue>
                                    <name>0</name>
                                    <description>No effect on output</description>
                                    <value>#0</value>
                                </enumeratedValue>
                                <enumeratedValue>
                                    <name>1</name>
                                    <description>High output</description>
                                    <value>#1</value>
                                </enumeratedValue>
                            </enumeratedValues>
                        </field>
                        <field>
                            <name>POSR13</name>
                            <description>Pmn Output Set</description>
                            <lsb>13</lsb>
                            <msb>13</msb>
                            <access>write-only</access>
                            <enumeratedValues>
                                <enumeratedValue>
                                    <name>0</name>
                                    <description>No effect on output</description>
                                    <value>#0</value>
                                </enumeratedValue>
                                <enumeratedValue>
                                    <name>1</name>
                                    <description>High output</description>
                                    <value>#1</value>
                                </enumeratedValue>
                            </enumeratedValues>
                        </field>
                        <field>
                            <name>POSR14</name>
                            <description>Pmn Output Set</description>
                            <lsb>14</lsb>
                            <msb>14</msb>
                            <access>write-only</access>
                            <enumeratedValues>
                                <enumeratedValue>
                                    <name>0</name>
                                    <description>No effect on output</description>
                                    <value>#0</value>
                                </enumeratedValue>
                                <enumeratedValue>
                                    <name>1</name>
                                    <description>High output</description>
                                    <value>#1</value>
                                </enumeratedValue>
                            </enumeratedValues>
                        </field>
                        <field>
                            <name>POSR15</name>
                            <description>Pmn Output Set</description>
                            <lsb>15</lsb>
                            <msb>15</msb>
                            <access>write-only</access>
                            <enumeratedValues>
                                <enumeratedValue>
                                    <name>0</name>
                                    <description>No effect on output</description>
                                    <value>#0</value>
                                </enumeratedValue>
                                <enumeratedValue>
                                    <name>1</name>
                                    <description>High output</description>
                                    <value>#1</value>
                                </enumeratedValue>
                            </enumeratedValues>
                        </field>
                    </fields>
                </register>
            </registers>
        </peripheral>
        <peripheral>
            <name>PFS</name>
            <description>Pmn Pin Function Control Register</description>
            <baseAddress>0x40400800</baseAddress>
            <addressBlock>
                <offset>0x00</offset>
                <size>48</size>
                <usage>registers</usage>
            </addressBlock>
            <addressBlock>
                <offset>0x38</offset>
                <size>40</size>
                <usage>registers</usage>
            </addressBlock>
            <addressBlock>
                <offset>0x70</offset>
                <size>20</size>
                <usage>registers</usage>
            </addressBlock>
            <addressBlock>
                <offset>0x84</offset>
                <size>4</size>
                <usage>registers</usage>
            </addressBlock>
            <addressBlock>
                <offset>0x88</offset>
                <size>28</size>
                <usage>registers</usage>
            </addressBlock>
            <addressBlock>
                <offset>0xA4</offset>
                <size>4</size>
                <usage>registers</usage>
            </addressBlock>
            <addressBlock>
                <offset>0xA8</offset>
                <size>4</size>
                <usage>registers</usage>
            </addressBlock>
            <addressBlock>
                <offset>0xAC</offset>
                <size>4</size>
                <usage>registers</usage>
            </addressBlock>
            <addressBlock>
                <offset>0xB0</offset>
                <size>8</size>
                <usage>registers</usage>
            </addressBlock>
            <addressBlock>
                <offset>0xC0</offset>
                <size>544</size>
                <usage>registers</usage>
            </addressBlock>
            <addressBlock>
                <offset>0x500</offset>
                <size>1</size>
                <usage>registers</usage>
            </addressBlock>
            <addressBlock>
                <offset>0x514</offset>
                <size>1</size>
                <usage>registers</usage>
            </addressBlock>
            <addressBlock>
                <offset>0x530</offset>
                <size>48</size>
                <usage>registers</usage>
            </addressBlock>
            <registers>
                <register>
                    <dim>10</dim>
                    <dimIncrement>0x004</dimIncrement>
                    <dimIndex>0-9</dimIndex>
                    <name>P00%sPFS</name>
                    <description>Port 00%s Pin Function Select Register</description>
                    <addressOffset>0x000</addressOffset>
                    <size>32</size>
                    <access>read-write</access>
                    <resetValue>0x00000000</resetValue>
                    <resetMask>0xffffffff</resetMask>
                    <fields>
                        <field>
                            <name>PODR</name>
                            <description>Port Output Data</description>
                            <lsb>0</lsb>
                            <msb>0</msb>
                            <access>read-write</access>
                            <enumeratedValues>
                                <enumeratedValue>
                                    <name>0</name>
                                    <description>Low output</description>
                                    <value>#0</value>
                                </enumeratedValue>
                                <enumeratedValue>
                                    <name>1</name>
                                    <description>High output</description>
                                    <value>#1</value>
                                </enumeratedValue>
                            </enumeratedValues>
                        </field>
                        <field>
                            <name>PIDR</name>
                            <description>Pmn State</description>
                            <lsb>1</lsb>
                            <msb>1</msb>
                            <access>read-only</access>
                            <enumeratedValues>
                                <enumeratedValue>
                                    <name>0</name>
                                    <description>Low level</description>
                                    <value>#0</value>
                                </enumeratedValue>
                                <enumeratedValue>
                                    <name>1</name>
                                    <description>High level</description>
                                    <value>#1</value>
                                </enumeratedValue>
                            </enumeratedValues>
                        </field>
                        <field>
                            <name>PDR</name>
                            <description>Port Direction</description>
                            <lsb>2</lsb>
                            <msb>2</msb>
                            <access>read-write</access>
                            <enumeratedValues>
                                <enumeratedValue>
                                    <name>0</name>
                                    <description>Input (functions as an input pin)</description>
                                    <value>#0</value>
                                </enumeratedValue>
                                <enumeratedValue>
                                    <name>1</name>
                                    <description>Output (functions as an output pin)</description>
                                    <value>#1</value>
                                </enumeratedValue>
                            </enumeratedValues>
                        </field>
                        <field>
                            <name>PCR</name>
                            <description>Pull-up Control</description>
                            <lsb>4</lsb>
                            <msb>4</msb>
                            <access>read-write</access>
                            <enumeratedValues>
                                <enumeratedValue>
                                    <name>0</name>
                                    <description>Disable input pull-up</description>
                                    <value>#0</value>
                                </enumeratedValue>
                                <enumeratedValue>
                                    <name>1</name>
                                    <description>Enable input pull-up</description>
                                    <value>#1</value>
                                </enumeratedValue>
                            </enumeratedValues>
                        </field>
                        <field>
                            <name>NCODR</name>
                            <description>N-Channel Open-Drain Control</description>
                            <lsb>6</lsb>
                            <msb>6</msb>
                            <access>read-write</access>
                            <enumeratedValues>
                                <enumeratedValue>
                                    <name>0</name>
                                    <description>CMOS output</description>
                                    <value>#0</value>
                                </enumeratedValue>
                                <enumeratedValue>
                                    <name>1</name>
                                    <description>NMOS open-drain output</description>
                                    <value>#1</value>
                                </enumeratedValue>
                            </enumeratedValues>
                        </field>
                        <field>
                            <name>DSCR</name>
                            <description>Port Drive Capability</description>
                            <lsb>10</lsb>
                            <msb>11</msb>
                            <access>read-write</access>
                            <enumeratedValues>
                                <enumeratedValue>
                                    <name>00</name>
                                    <description>Low drive</description>
                                    <value>#00</value>
                                </enumeratedValue>
                                <enumeratedValue>
                                    <name>01</name>
                                    <description>Middle drive</description>
                                    <value>#01</value>
                                </enumeratedValue>
                                <enumeratedValue>
                                    <name>10</name>
                                    <description>High-speed high-drive</description>
                                    <value>#10</value>
                                </enumeratedValue>
                                <enumeratedValue>
                                    <name>11</name>
                                    <description>High drive</description>
                                    <value>#11</value>
                                </enumeratedValue>
                            </enumeratedValues>
                        </field>
                        <field>
                            <name>EOFR</name>
                            <description>Event on Falling/Event on Rising</description>
                            <lsb>12</lsb>
                            <msb>13</msb>
                            <access>read-write</access>
                            <enumeratedValues>
                                <enumeratedValue>
                                    <name>00</name>
                                    <description>Don't care</description>
                                    <value>#00</value>
                                </enumeratedValue>
                                <enumeratedValue>
                                    <name>01</name>
                                    <description>Detect rising edge</description>
                                    <value>#01</value>
                                </enumeratedValue>
                                <enumeratedValue>
                                    <name>10</name>
                                    <description>Detect falling edge</description>
                                    <value>#10</value>
                                </enumeratedValue>
                                <enumeratedValue>
                                    <name>11</name>
                                    <description>Detect both edges</description>
                                    <value>#11</value>
                                </enumeratedValue>
                            </enumeratedValues>
                        </field>
                        <field>
                            <name>ISEL</name>
                            <description>IRQ Input Enable</description>
                            <lsb>14</lsb>
                            <msb>14</msb>
                            <access>read-write</access>
                            <enumeratedValues>
                                <enumeratedValue>
                                    <name>0</name>
                                    <description>Not used as an IRQn input pin</description>
                                    <value>#0</value>
                                </enumeratedValue>
                                <enumeratedValue>
                                    <name>1</name>
                                    <description>Used as an IRQn input pin</description>
                                    <value>#1</value>
                                </enumeratedValue>
                            </enumeratedValues>
                        </field>
                        <field>
                            <name>ASEL</name>
                            <description>Analog Input Enable</description>
                            <lsb>15</lsb>
                            <msb>15</msb>
                            <access>read-write</access>
                            <enumeratedValues>
                                <enumeratedValue>
                                    <name>0</name>
                                    <description>Not used as an analog pin</description>
                                    <value>#0</value>
                                </enumeratedValue>
                                <enumeratedValue>
                                    <name>1</name>
                                    <description>Used as an analog pin</description>
                                    <value>#1</value>
                                </enumeratedValue>
                            </enumeratedValues>
                        </field>
                        <field>
                            <name>PMR</name>
                            <description>Port Mode Control</description>
                            <lsb>16</lsb>
                            <msb>16</msb>
                            <access>read-write</access>
                            <enumeratedValues>
                                <enumeratedValue>
                                    <name>0</name>
                                    <description>Used as a general I/O pin</description>
                                    <value>#0</value>
                                </enumeratedValue>
                                <enumeratedValue>
                                    <name>1</name>
                                    <description>Used as an I/O port for peripheral functions</description>
                                    <value>#1</value>
                                </enumeratedValue>
                            </enumeratedValues>
                        </field>
                        <field>
                            <name>PSEL</name>
                            <description>Peripheral Select</description>
                            <lsb>24</lsb>
                            <msb>28</msb>
                            <access>read-write</access>
                        </field>
                    </fields>
                </register>
                <register>
                    <dim>10</dim>
                    <dimIncrement>0x004</dimIncrement>
                    <dimIndex>0-9</dimIndex>
                    <name>P00%sPFS_HA</name>
                    <description>Port 00%s Pin Function Select Register</description>
                    <alternateRegister>P00%sPFS</alternateRegister>
                    <addressOffset>0x000</addressOffset>
                    <size>16</size>
                    <access>read-write</access>
                    <resetValue>0x0000</resetValue>
                    <resetMask>0xffff</resetMask>
                    <fields>
                        <field>
                            <name>PMR</name>
                            <description>Port Mode Control</description>
                            <lsb>0</lsb>
                            <msb>0</msb>
                            <access>read-write</access>
                            <enumeratedValues>
                                <enumeratedValue>
                                    <name>0</name>
                                    <description>Used as a general I/O pin</description>
                                    <value>#0</value>
                                </enumeratedValue>
                                <enumeratedValue>
                                    <name>1</name>
                                    <description>Used as an I/O port for peripheral functions</description>
                                    <value>#1</value>
                                </enumeratedValue>
                            </enumeratedValues>
                        </field>
                        <field>
                            <name>PSEL</name>
                            <description>Peripheral Select</description>
                            <lsb>8</lsb>
                            <msb>12</msb>
                            <access>read-write</access>
                        </field>
                    </fields>
                </register>
                <register>
                    <dim>10</dim>
                    <dimIncrement>0x004</dimIncrement>
                    <dimIndex>0-9</dimIndex>
                    <name>P00%sPFS_BY</name>
                    <description>Port 00%s Pin Function Select Register</description>
                    <alternateRegister>P00%sPFS</alternateRegister>
                    <addressOffset>0x000</addressOffset>
                    <size>8</size>
                    <access>read-write</access>
                    <resetValue>0x00</resetValue>
                    <resetMask>0xff</resetMask>
                    <fields>
                        <field>
                            <name>PSEL</name>
                            <description>Peripheral Select</description>
                            <lsb>0</lsb>
                            <msb>4</msb>
                            <access>read-write</access>
                        </field>
                    </fields>
                </register>
                <register>
                    <dim>2</dim>
                    <dimIncrement>0x004</dimIncrement>
                    <dimIndex>10-11</dimIndex>
                    <name>P0%sPFS</name>
                    <description>Port 0%s Pin Function Select Register</description>
                    <addressOffset>0x028</addressOffset>
                    <size>32</size>
                    <access>read-write</access>
                    <resetValue>0x00000000</resetValue>
                    <resetMask>0xffffffff</resetMask>
                    <fields>
                        <field>
                            <name>PODR</name>
                            <description>Port Output Data</description>
                            <lsb>0</lsb>
                            <msb>0</msb>
                            <access>read-write</access>
                            <enumeratedValues>
                                <enumeratedValue>
                                    <name>0</name>
                                    <description>Low output</description>
                                    <value>#0</value>
                                </enumeratedValue>
                                <enumeratedValue>
                                    <name>1</name>
                                    <description>High output</description>
                                    <value>#1</value>
                                </enumeratedValue>
                            </enumeratedValues>
                        </field>
                        <field>
                            <name>PIDR</name>
                            <description>Pmn State</description>
                            <lsb>1</lsb>
                            <msb>1</msb>
                            <access>read-only</access>
                            <enumeratedValues>
                                <enumeratedValue>
                                    <name>0</name>
                                    <description>Low level</description>
                                    <value>#0</value>
                                </enumeratedValue>
                                <enumeratedValue>
                                    <name>1</name>
                                    <description>High level</description>
                                    <value>#1</value>
                                </enumeratedValue>
                            </enumeratedValues>
                        </field>
                        <field>
                            <name>PDR</name>
                            <description>Port Direction</description>
                            <lsb>2</lsb>
                            <msb>2</msb>
                            <access>read-write</access>
                            <enumeratedValues>
                                <enumeratedValue>
                                    <name>0</name>
                                    <description>Input (functions as an input pin)</description>
                                    <value>#0</value>
                                </enumeratedValue>
                                <enumeratedValue>
                                    <name>1</name>
                                    <description>Output (functions as an output pin)</description>
                                    <value>#1</value>
                                </enumeratedValue>
                            </enumeratedValues>
                        </field>
                        <field>
                            <name>PCR</name>
                            <description>Pull-up Control</description>
                            <lsb>4</lsb>
                            <msb>4</msb>
                            <access>read-write</access>
                            <enumeratedValues>
                                <enumeratedValue>
                                    <name>0</name>
                                    <description>Disable input pull-up</description>
                                    <value>#0</value>
                                </enumeratedValue>
                                <enumeratedValue>
                                    <name>1</name>
                                    <description>Enable input pull-up</description>
                                    <value>#1</value>
                                </enumeratedValue>
                            </enumeratedValues>
                        </field>
                        <field>
                            <name>NCODR</name>
                            <description>N-Channel Open-Drain Control</description>
                            <lsb>6</lsb>
                            <msb>6</msb>
                            <access>read-write</access>
                            <enumeratedValues>
                                <enumeratedValue>
                                    <name>0</name>
                                    <description>CMOS output</description>
                                    <value>#0</value>
                                </enumeratedValue>
                                <enumeratedValue>
                                    <name>1</name>
                                    <description>NMOS open-drain output</description>
                                    <value>#1</value>
                                </enumeratedValue>
                            </enumeratedValues>
                        </field>
                        <field>
                            <name>DSCR</name>
                            <description>Port Drive Capability</description>
                            <lsb>10</lsb>
                            <msb>11</msb>
                            <access>read-write</access>
                            <enumeratedValues>
                                <enumeratedValue>
                                    <name>00</name>
                                    <description>Low drive</description>
                                    <value>#00</value>
                                </enumeratedValue>
                                <enumeratedValue>
                                    <name>01</name>
                                    <description>Middle drive</description>
                                    <value>#01</value>
                                </enumeratedValue>
                                <enumeratedValue>
                                    <name>10</name>
                                    <description>High-speed high-drive</description>
                                    <value>#10</value>
                                </enumeratedValue>
                                <enumeratedValue>
                                    <name>11</name>
                                    <description>High drive</description>
                                    <value>#11</value>
                                </enumeratedValue>
                            </enumeratedValues>
                        </field>
                        <field>
                            <name>EOFR</name>
                            <description>Event on Falling/Event on Rising</description>
                            <lsb>12</lsb>
                            <msb>13</msb>
                            <access>read-write</access>
                            <enumeratedValues>
                                <enumeratedValue>
                                    <name>00</name>
                                    <description>Don't care</description>
                                    <value>#00</value>
                                </enumeratedValue>
                                <enumeratedValue>
                                    <name>01</name>
                                    <description>Detect rising edge</description>
                                    <value>#01</value>
                                </enumeratedValue>
                                <enumeratedValue>
                                    <name>10</name>
                                    <description>Detect falling edge</description>
                                    <value>#10</value>
                                </enumeratedValue>
                                <enumeratedValue>
                                    <name>11</name>
                                    <description>Detect both edges</description>
                                    <value>#11</value>
                                </enumeratedValue>
                            </enumeratedValues>
                        </field>
                        <field>
                            <name>ISEL</name>
                            <description>IRQ Input Enable</description>
                            <lsb>14</lsb>
                            <msb>14</msb>
                            <access>read-write</access>
                            <enumeratedValues>
                                <enumeratedValue>
                                    <name>0</name>
                                    <description>Not used as an IRQn input pin</description>
                                    <value>#0</value>
                                </enumeratedValue>
                                <enumeratedValue>
                                    <name>1</name>
                                    <description>Used as an IRQn input pin</description>
                                    <value>#1</value>
                                </enumeratedValue>
                            </enumeratedValues>
                        </field>
                        <field>
                            <name>ASEL</name>
                            <description>Analog Input Enable</description>
                            <lsb>15</lsb>
                            <msb>15</msb>
                            <access>read-write</access>
                            <enumeratedValues>
                                <enumeratedValue>
                                    <name>0</name>
                                    <description>Not used as an analog pin</description>
                                    <value>#0</value>
                                </enumeratedValue>
                                <enumeratedValue>
                                    <name>1</name>
                                    <description>Used as an analog pin</description>
                                    <value>#1</value>
                                </enumeratedValue>
                            </enumeratedValues>
                        </field>
                        <field>
                            <name>PMR</name>
                            <description>Port Mode Control</description>
                            <lsb>16</lsb>
                            <msb>16</msb>
                            <access>read-write</access>
                            <enumeratedValues>
                                <enumeratedValue>
                                    <name>0</name>
                                    <description>Used as a general I/O pin</description>
                                    <value>#0</value>
                                </enumeratedValue>
                                <enumeratedValue>
                                    <name>1</name>
                                    <description>Used as an I/O port for peripheral functions</description>
                                    <value>#1</value>
                                </enumeratedValue>
                            </enumeratedValues>
                        </field>
                        <field>
                            <name>PSEL</name>
                            <description>Peripheral Select</description>
                            <lsb>24</lsb>
                            <msb>28</msb>
                            <access>read-write</access>
                        </field>
                    </fields>
                </register>
                <register>
                    <dim>2</dim>
                    <dimIncrement>0x004</dimIncrement>
                    <dimIndex>10-11</dimIndex>
                    <name>P0%sPFS_HA</name>
                    <description>Port 0%s Pin Function Select Register</description>
                    <alternateRegister>P0%sPFS</alternateRegister>
                    <addressOffset>0x028</addressOffset>
                    <size>16</size>
                    <access>read-write</access>
                    <resetValue>0x0000</resetValue>
                    <resetMask>0xffff</resetMask>
                    <fields>
                        <field>
                            <name>PMR</name>
                            <description>Port Mode Control</description>
                            <lsb>0</lsb>
                            <msb>0</msb>
                            <access>read-write</access>
                            <enumeratedValues>
                                <enumeratedValue>
                                    <name>0</name>
                                    <description>Used as a general I/O pin</description>
                                    <value>#0</value>
                                </enumeratedValue>
                                <enumeratedValue>
                                    <name>1</name>
                                    <description>Used as an I/O port for peripheral functions</description>
                                    <value>#1</value>
                                </enumeratedValue>
                            </enumeratedValues>
                        </field>
                        <field>
                            <name>PSEL</name>
                            <description>Peripheral Select</description>
                            <lsb>8</lsb>
                            <msb>12</msb>
                            <access>read-write</access>
                        </field>
                    </fields>
                </register>
                <register>
                    <dim>2</dim>
                    <dimIncrement>0x004</dimIncrement>
                    <dimIndex>10-11</dimIndex>
                    <name>P0%sPFS_BY</name>
                    <description>Port 0%s Pin Function Select Register</description>
                    <alternateRegister>P0%sPFS</alternateRegister>
                    <addressOffset>0x028</addressOffset>
                    <size>8</size>
                    <access>read-write</access>
                    <resetValue>0x00</resetValue>
                    <resetMask>0xff</resetMask>
                    <fields>
                        <field>
                            <name>PSEL</name>
                            <description>Peripheral Select</description>
                            <lsb>0</lsb>
                            <msb>4</msb>
                            <access>read-write</access>
                        </field>
                    </fields>
                </register>
                <register>
                    <dim>2</dim>
                    <dimIncrement>0x004</dimIncrement>
                    <dimIndex>14-15</dimIndex>
                    <name>P0%sPFS</name>
                    <description>Port 0%s Pin Function Select Register</description>
                    <addressOffset>0x038</addressOffset>
                    <size>32</size>
                    <access>read-write</access>
                    <resetValue>0x00000000</resetValue>
                    <resetMask>0xffffffff</resetMask>
                    <fields>
                        <field>
                            <name>PODR</name>
                            <description>Port Output Data</description>
                            <lsb>0</lsb>
                            <msb>0</msb>
                            <access>read-write</access>
                            <enumeratedValues>
                                <enumeratedValue>
                                    <name>0</name>
                                    <description>Low output</description>
                                    <value>#0</value>
                                </enumeratedValue>
                                <enumeratedValue>
                                    <name>1</name>
                                    <description>High output</description>
                                    <value>#1</value>
                                </enumeratedValue>
                            </enumeratedValues>
                        </field>
                        <field>
                            <name>PIDR</name>
                            <description>Pmn State</description>
                            <lsb>1</lsb>
                            <msb>1</msb>
                            <access>read-only</access>
                            <enumeratedValues>
                                <enumeratedValue>
                                    <name>0</name>
                                    <description>Low level</description>
                                    <value>#0</value>
                                </enumeratedValue>
                                <enumeratedValue>
                                    <name>1</name>
                                    <description>High level</description>
                                    <value>#1</value>
                                </enumeratedValue>
                            </enumeratedValues>
                        </field>
                        <field>
                            <name>PDR</name>
                            <description>Port Direction</description>
                            <lsb>2</lsb>
                            <msb>2</msb>
                            <access>read-write</access>
                            <enumeratedValues>
                                <enumeratedValue>
                                    <name>0</name>
                                    <description>Input (functions as an input pin)</description>
                                    <value>#0</value>
                                </enumeratedValue>
                                <enumeratedValue>
                                    <name>1</name>
                                    <description>Output (functions as an output pin)</description>
                                    <value>#1</value>
                                </enumeratedValue>
                            </enumeratedValues>
                        </field>
                        <field>
                            <name>PCR</name>
                            <description>Pull-up Control</description>
                            <lsb>4</lsb>
                            <msb>4</msb>
                            <access>read-write</access>
                            <enumeratedValues>
                                <enumeratedValue>
                                    <name>0</name>
                                    <description>Disable input pull-up</description>
                                    <value>#0</value>
                                </enumeratedValue>
                                <enumeratedValue>
                                    <name>1</name>
                                    <description>Enable input pull-up</description>
                                    <value>#1</value>
                                </enumeratedValue>
                            </enumeratedValues>
                        </field>
                        <field>
                            <name>NCODR</name>
                            <description>N-Channel Open-Drain Control</description>
                            <lsb>6</lsb>
                            <msb>6</msb>
                            <access>read-write</access>
                            <enumeratedValues>
                                <enumeratedValue>
                                    <name>0</name>
                                    <description>CMOS output</description>
                                    <value>#0</value>
                                </enumeratedValue>
                                <enumeratedValue>
                                    <name>1</name>
                                    <description>NMOS open-drain output</description>
                                    <value>#1</value>
                                </enumeratedValue>
                            </enumeratedValues>
                        </field>
                        <field>
                            <name>DSCR</name>
                            <description>Port Drive Capability</description>
                            <lsb>10</lsb>
                            <msb>11</msb>
                            <access>read-write</access>
                            <enumeratedValues>
                                <enumeratedValue>
                                    <name>00</name>
                                    <description>Low drive</description>
                                    <value>#00</value>
                                </enumeratedValue>
                                <enumeratedValue>
                                    <name>01</name>
                                    <description>Middle drive</description>
                                    <value>#01</value>
                                </enumeratedValue>
                                <enumeratedValue>
                                    <name>10</name>
                                    <description>High-speed high-drive</description>
                                    <value>#10</value>
                                </enumeratedValue>
                                <enumeratedValue>
                                    <name>11</name>
                                    <description>High drive</description>
                                    <value>#11</value>
                                </enumeratedValue>
                            </enumeratedValues>
                        </field>
                        <field>
                            <name>EOFR</name>
                            <description>Event on Falling/Event on Rising</description>
                            <lsb>12</lsb>
                            <msb>13</msb>
                            <access>read-write</access>
                            <enumeratedValues>
                                <enumeratedValue>
                                    <name>00</name>
                                    <description>Don't care</description>
                                    <value>#00</value>
                                </enumeratedValue>
                                <enumeratedValue>
                                    <name>01</name>
                                    <description>Detect rising edge</description>
                                    <value>#01</value>
                                </enumeratedValue>
                                <enumeratedValue>
                                    <name>10</name>
                                    <description>Detect falling edge</description>
                                    <value>#10</value>
                                </enumeratedValue>
                                <enumeratedValue>
                                    <name>11</name>
                                    <description>Detect both edges</description>
                                    <value>#11</value>
                                </enumeratedValue>
                            </enumeratedValues>
                        </field>
                        <field>
                            <name>ISEL</name>
                            <description>IRQ Input Enable</description>
                            <lsb>14</lsb>
                            <msb>14</msb>
                            <access>read-write</access>
                            <enumeratedValues>
                                <enumeratedValue>
                                    <name>0</name>
                                    <description>Not used as an IRQn input pin</description>
                                    <value>#0</value>
                                </enumeratedValue>
                                <enumeratedValue>
                                    <name>1</name>
                                    <description>Used as an IRQn input pin</description>
                                    <value>#1</value>
                                </enumeratedValue>
                            </enumeratedValues>
                        </field>
                        <field>
                            <name>ASEL</name>
                            <description>Analog Input Enable</description>
                            <lsb>15</lsb>
                            <msb>15</msb>
                            <access>read-write</access>
                            <enumeratedValues>
                                <enumeratedValue>
                                    <name>0</name>
                                    <description>Not used as an analog pin</description>
                                    <value>#0</value>
                                </enumeratedValue>
                                <enumeratedValue>
                                    <name>1</name>
                                    <description>Used as an analog pin</description>
                                    <value>#1</value>
                                </enumeratedValue>
                            </enumeratedValues>
                        </field>
                        <field>
                            <name>PMR</name>
                            <description>Port Mode Control</description>
                            <lsb>16</lsb>
                            <msb>16</msb>
                            <access>read-write</access>
                            <enumeratedValues>
                                <enumeratedValue>
                                    <name>0</name>
                                    <description>Used as a general I/O pin</description>
                                    <value>#0</value>
                                </enumeratedValue>
                                <enumeratedValue>
                                    <name>1</name>
                                    <description>Used as an I/O port for peripheral functions</description>
                                    <value>#1</value>
                                </enumeratedValue>
                            </enumeratedValues>
                        </field>
                        <field>
                            <name>PSEL</name>
                            <description>Peripheral Select</description>
                            <lsb>24</lsb>
                            <msb>28</msb>
                            <access>read-write</access>
                        </field>
                    </fields>
                </register>
                <register>
                    <dim>2</dim>
                    <dimIncrement>0x004</dimIncrement>
                    <dimIndex>14-15</dimIndex>
                    <name>P0%sPFS_HA</name>
                    <description>Port 0%s Pin Function Select Register</description>
                    <alternateRegister>P0%sPFS</alternateRegister>
                    <addressOffset>0x038</addressOffset>
                    <size>16</size>
                    <access>read-write</access>
                    <resetValue>0x0000</resetValue>
                    <resetMask>0xffff</resetMask>
                    <fields>
                        <field>
                            <name>PMR</name>
                            <description>Port Mode Control</description>
                            <lsb>0</lsb>
                            <msb>0</msb>
                            <access>read-write</access>
                            <enumeratedValues>
                                <enumeratedValue>
                                    <name>0</name>
                                    <description>Used as a general I/O pin</description>
                                    <value>#0</value>
                                </enumeratedValue>
                                <enumeratedValue>
                                    <name>1</name>
                                    <description>Used as an I/O port for peripheral functions</description>
                                    <value>#1</value>
                                </enumeratedValue>
                            </enumeratedValues>
                        </field>
                        <field>
                            <name>PSEL</name>
                            <description>Peripheral Select</description>
                            <lsb>8</lsb>
                            <msb>12</msb>
                            <access>read-write</access>
                        </field>
                    </fields>
                </register>
                <register>
                    <dim>2</dim>
                    <dimIncrement>0x004</dimIncrement>
                    <dimIndex>14-15</dimIndex>
                    <name>P0%sPFS_BY</name>
                    <description>Port 0%s Pin Function Select Register</description>
                    <alternateRegister>P0%sPFS</alternateRegister>
                    <addressOffset>0x038</addressOffset>
                    <size>8</size>
                    <access>read-write</access>
                    <resetValue>0x00</resetValue>
                    <resetMask>0xff</resetMask>
                    <fields>
                        <field>
                            <name>PSEL</name>
                            <description>Peripheral Select</description>
                            <lsb>0</lsb>
                            <msb>4</msb>
                            <access>read-write</access>
                        </field>
                    </fields>
                </register>
                <register>
                    <dim>8</dim>
                    <dimIncrement>0x004</dimIncrement>
                    <dimIndex>0-7</dimIndex>
                    <name>P10%sPFS</name>
                    <description>Port 10%s Pin Function Select Register</description>
                    <addressOffset>0x040</addressOffset>
                    <size>32</size>
                    <access>read-write</access>
                    <resetValue>0x00000000</resetValue>
                    <resetMask>0xffffffff</resetMask>
                    <fields>
                        <field>
                            <name>PODR</name>
                            <description>Port Output Data</description>
                            <lsb>0</lsb>
                            <msb>0</msb>
                            <access>read-write</access>
                            <enumeratedValues>
                                <enumeratedValue>
                                    <name>0</name>
                                    <description>Low output</description>
                                    <value>#0</value>
                                </enumeratedValue>
                                <enumeratedValue>
                                    <name>1</name>
                                    <description>High output</description>
                                    <value>#1</value>
                                </enumeratedValue>
                            </enumeratedValues>
                        </field>
                        <field>
                            <name>PIDR</name>
                            <description>Pmn State</description>
                            <lsb>1</lsb>
                            <msb>1</msb>
                            <access>read-only</access>
                            <enumeratedValues>
                                <enumeratedValue>
                                    <name>0</name>
                                    <description>Low level</description>
                                    <value>#0</value>
                                </enumeratedValue>
                                <enumeratedValue>
                                    <name>1</name>
                                    <description>High level</description>
                                    <value>#1</value>
                                </enumeratedValue>
                            </enumeratedValues>
                        </field>
                        <field>
                            <name>PDR</name>
                            <description>Port Direction</description>
                            <lsb>2</lsb>
                            <msb>2</msb>
                            <access>read-write</access>
                            <enumeratedValues>
                                <enumeratedValue>
                                    <name>0</name>
                                    <description>Input (functions as an input pin)</description>
                                    <value>#0</value>
                                </enumeratedValue>
                                <enumeratedValue>
                                    <name>1</name>
                                    <description>Output (functions as an output pin)</description>
                                    <value>#1</value>
                                </enumeratedValue>
                            </enumeratedValues>
                        </field>
                        <field>
                            <name>PCR</name>
                            <description>Pull-up Control</description>
                            <lsb>4</lsb>
                            <msb>4</msb>
                            <access>read-write</access>
                            <enumeratedValues>
                                <enumeratedValue>
                                    <name>0</name>
                                    <description>Disable input pull-up</description>
                                    <value>#0</value>
                                </enumeratedValue>
                                <enumeratedValue>
                                    <name>1</name>
                                    <description>Enable input pull-up</description>
                                    <value>#1</value>
                                </enumeratedValue>
                            </enumeratedValues>
                        </field>
                        <field>
                            <name>NCODR</name>
                            <description>N-Channel Open-Drain Control</description>
                            <lsb>6</lsb>
                            <msb>6</msb>
                            <access>read-write</access>
                            <enumeratedValues>
                                <enumeratedValue>
                                    <name>0</name>
                                    <description>CMOS output</description>
                                    <value>#0</value>
                                </enumeratedValue>
                                <enumeratedValue>
                                    <name>1</name>
                                    <description>NMOS open-drain output</description>
                                    <value>#1</value>
                                </enumeratedValue>
                            </enumeratedValues>
                        </field>
                        <field>
                            <name>DSCR</name>
                            <description>Port Drive Capability</description>
                            <lsb>10</lsb>
                            <msb>11</msb>
                            <access>read-write</access>
                            <enumeratedValues>
                                <enumeratedValue>
                                    <name>00</name>
                                    <description>Low drive</description>
                                    <value>#00</value>
                                </enumeratedValue>
                                <enumeratedValue>
                                    <name>01</name>
                                    <description>Middle drive</description>
                                    <value>#01</value>
                                </enumeratedValue>
                                <enumeratedValue>
                                    <name>10</name>
                                    <description>High-speed high-drive</description>
                                    <value>#10</value>
                                </enumeratedValue>
                                <enumeratedValue>
                                    <name>11</name>
                                    <description>High drive</description>
                                    <value>#11</value>
                                </enumeratedValue>
                            </enumeratedValues>
                        </field>
                        <field>
                            <name>EOFR</name>
                            <description>Event on Falling/Event on Rising</description>
                            <lsb>12</lsb>
                            <msb>13</msb>
                            <access>read-write</access>
                            <enumeratedValues>
                                <enumeratedValue>
                                    <name>00</name>
                                    <description>Don't care</description>
                                    <value>#00</value>
                                </enumeratedValue>
                                <enumeratedValue>
                                    <name>01</name>
                                    <description>Detect rising edge</description>
                                    <value>#01</value>
                                </enumeratedValue>
                                <enumeratedValue>
                                    <name>10</name>
                                    <description>Detect falling edge</description>
                                    <value>#10</value>
                                </enumeratedValue>
                                <enumeratedValue>
                                    <name>11</name>
                                    <description>Detect both edges</description>
                                    <value>#11</value>
                                </enumeratedValue>
                            </enumeratedValues>
                        </field>
                        <field>
                            <name>ISEL</name>
                            <description>IRQ Input Enable</description>
                            <lsb>14</lsb>
                            <msb>14</msb>
                            <access>read-write</access>
                            <enumeratedValues>
                                <enumeratedValue>
                                    <name>0</name>
                                    <description>Not used as an IRQn input pin</description>
                                    <value>#0</value>
                                </enumeratedValue>
                                <enumeratedValue>
                                    <name>1</name>
                                    <description>Used as an IRQn input pin</description>
                                    <value>#1</value>
                                </enumeratedValue>
                            </enumeratedValues>
                        </field>
                        <field>
                            <name>ASEL</name>
                            <description>Analog Input Enable</description>
                            <lsb>15</lsb>
                            <msb>15</msb>
                            <access>read-write</access>
                            <enumeratedValues>
                                <enumeratedValue>
                                    <name>0</name>
                                    <description>Not used as an analog pin</description>
                                    <value>#0</value>
                                </enumeratedValue>
                                <enumeratedValue>
                                    <name>1</name>
                                    <description>Used as an analog pin</description>
                                    <value>#1</value>
                                </enumeratedValue>
                            </enumeratedValues>
                        </field>
                        <field>
                            <name>PMR</name>
                            <description>Port Mode Control</description>
                            <lsb>16</lsb>
                            <msb>16</msb>
                            <access>read-write</access>
                            <enumeratedValues>
                                <enumeratedValue>
                                    <name>0</name>
                                    <description>Used as a general I/O pin</description>
                                    <value>#0</value>
                                </enumeratedValue>
                                <enumeratedValue>
                                    <name>1</name>
                                    <description>Used as an I/O port for peripheral functions</description>
                                    <value>#1</value>
                                </enumeratedValue>
                            </enumeratedValues>
                        </field>
                        <field>
                            <name>PSEL</name>
                            <description>Peripheral Select</description>
                            <lsb>24</lsb>
                            <msb>28</msb>
                            <access>read-write</access>
                        </field>
                    </fields>
                </register>
                <register>
                    <dim>8</dim>
                    <dimIncrement>0x004</dimIncrement>
                    <dimIndex>0-7</dimIndex>
                    <name>P10%sPFS_HA</name>
                    <description>Port 10%s Pin Function Select Register</description>
                    <alternateRegister>P10%sPFS</alternateRegister>
                    <addressOffset>0x040</addressOffset>
                    <size>16</size>
                    <access>read-write</access>
                    <resetValue>0x0000</resetValue>
                    <resetMask>0xffff</resetMask>
                    <fields>
                        <field>
                            <name>PMR</name>
                            <description>Port Mode Control</description>
                            <lsb>0</lsb>
                            <msb>0</msb>
                            <access>read-write</access>
                            <enumeratedValues>
                                <enumeratedValue>
                                    <name>0</name>
                                    <description>Used as a general I/O pin</description>
                                    <value>#0</value>
                                </enumeratedValue>
                                <enumeratedValue>
                                    <name>1</name>
                                    <description>Used as an I/O port for peripheral functions</description>
                                    <value>#1</value>
                                </enumeratedValue>
                            </enumeratedValues>
                        </field>
                        <field>
                            <name>PSEL</name>
                            <description>Peripheral Select</description>
                            <lsb>8</lsb>
                            <msb>12</msb>
                            <access>read-write</access>
                        </field>
                    </fields>
                </register>
                <register>
                    <dim>8</dim>
                    <dimIncrement>0x004</dimIncrement>
                    <dimIndex>0-7</dimIndex>
                    <name>P10%sPFS_BY</name>
                    <description>Port 10%s Pin Function Select Register</description>
                    <alternateRegister>P10%sPFS</alternateRegister>
                    <addressOffset>0x040</addressOffset>
                    <size>8</size>
                    <access>read-write</access>
                    <resetValue>0x00</resetValue>
                    <resetMask>0xff</resetMask>
                    <fields>
                        <field>
                            <name>PSEL</name>
                            <description>Peripheral Select</description>
                            <lsb>0</lsb>
                            <msb>4</msb>
                            <access>read-write</access>
                        </field>
                    </fields>
                </register>
                <register>
                    <dim>4</dim>
                    <dimIncrement>0x004</dimIncrement>
                    <dimIndex>12-15</dimIndex>
                    <name>P1%sPFS</name>
                    <description>Port 1%s Pin Function Select Register</description>
                    <addressOffset>0x070</addressOffset>
                    <size>32</size>
                    <access>read-write</access>
                    <resetValue>0x00000000</resetValue>
                    <resetMask>0xffffffff</resetMask>
                    <fields>
                        <field>
                            <name>PODR</name>
                            <description>Port Output Data</description>
                            <lsb>0</lsb>
                            <msb>0</msb>
                            <access>read-write</access>
                            <enumeratedValues>
                                <enumeratedValue>
                                    <name>0</name>
                                    <description>Low output</description>
                                    <value>#0</value>
                                </enumeratedValue>
                                <enumeratedValue>
                                    <name>1</name>
                                    <description>High output</description>
                                    <value>#1</value>
                                </enumeratedValue>
                            </enumeratedValues>
                        </field>
                        <field>
                            <name>PIDR</name>
                            <description>Pmn State</description>
                            <lsb>1</lsb>
                            <msb>1</msb>
                            <access>read-only</access>
                            <enumeratedValues>
                                <enumeratedValue>
                                    <name>0</name>
                                    <description>Low level</description>
                                    <value>#0</value>
                                </enumeratedValue>
                                <enumeratedValue>
                                    <name>1</name>
                                    <description>High level</description>
                                    <value>#1</value>
                                </enumeratedValue>
                            </enumeratedValues>
                        </field>
                        <field>
                            <name>PDR</name>
                            <description>Port Direction</description>
                            <lsb>2</lsb>
                            <msb>2</msb>
                            <access>read-write</access>
                            <enumeratedValues>
                                <enumeratedValue>
                                    <name>0</name>
                                    <description>Input (functions as an input pin)</description>
                                    <value>#0</value>
                                </enumeratedValue>
                                <enumeratedValue>
                                    <name>1</name>
                                    <description>Output (functions as an output pin)</description>
                                    <value>#1</value>
                                </enumeratedValue>
                            </enumeratedValues>
                        </field>
                        <field>
                            <name>PCR</name>
                            <description>Pull-up Control</description>
                            <lsb>4</lsb>
                            <msb>4</msb>
                            <access>read-write</access>
                            <enumeratedValues>
                                <enumeratedValue>
                                    <name>0</name>
                                    <description>Disable input pull-up</description>
                                    <value>#0</value>
                                </enumeratedValue>
                                <enumeratedValue>
                                    <name>1</name>
                                    <description>Enable input pull-up</description>
                                    <value>#1</value>
                                </enumeratedValue>
                            </enumeratedValues>
                        </field>
                        <field>
                            <name>NCODR</name>
                            <description>N-Channel Open-Drain Control</description>
                            <lsb>6</lsb>
                            <msb>6</msb>
                            <access>read-write</access>
                            <enumeratedValues>
                                <enumeratedValue>
                                    <name>0</name>
                                    <description>CMOS output</description>
                                    <value>#0</value>
                                </enumeratedValue>
                                <enumeratedValue>
                                    <name>1</name>
                                    <description>NMOS open-drain output</description>
                                    <value>#1</value>
                                </enumeratedValue>
                            </enumeratedValues>
                        </field>
                        <field>
                            <name>DSCR</name>
                            <description>Port Drive Capability</description>
                            <lsb>10</lsb>
                            <msb>11</msb>
                            <access>read-write</access>
                            <enumeratedValues>
                                <enumeratedValue>
                                    <name>00</name>
                                    <description>Low drive</description>
                                    <value>#00</value>
                                </enumeratedValue>
                                <enumeratedValue>
                                    <name>01</name>
                                    <description>Middle drive</description>
                                    <value>#01</value>
                                </enumeratedValue>
                                <enumeratedValue>
                                    <name>10</name>
                                    <description>High-speed high-drive</description>
                                    <value>#10</value>
                                </enumeratedValue>
                                <enumeratedValue>
                                    <name>11</name>
                                    <description>High drive</description>
                                    <value>#11</value>
                                </enumeratedValue>
                            </enumeratedValues>
                        </field>
                        <field>
                            <name>EOFR</name>
                            <description>Event on Falling/Event on Rising</description>
                            <lsb>12</lsb>
                            <msb>13</msb>
                            <access>read-write</access>
                            <enumeratedValues>
                                <enumeratedValue>
                                    <name>00</name>
                                    <description>Don't care</description>
                                    <value>#00</value>
                                </enumeratedValue>
                                <enumeratedValue>
                                    <name>01</name>
                                    <description>Detect rising edge</description>
                                    <value>#01</value>
                                </enumeratedValue>
                                <enumeratedValue>
                                    <name>10</name>
                                    <description>Detect falling edge</description>
                                    <value>#10</value>
                                </enumeratedValue>
                                <enumeratedValue>
                                    <name>11</name>
                                    <description>Detect both edges</description>
                                    <value>#11</value>
                                </enumeratedValue>
                            </enumeratedValues>
                        </field>
                        <field>
                            <name>ISEL</name>
                            <description>IRQ Input Enable</description>
                            <lsb>14</lsb>
                            <msb>14</msb>
                            <access>read-write</access>
                            <enumeratedValues>
                                <enumeratedValue>
                                    <name>0</name>
                                    <description>Not used as an IRQn input pin</description>
                                    <value>#0</value>
                                </enumeratedValue>
                                <enumeratedValue>
                                    <name>1</name>
                                    <description>Used as an IRQn input pin</description>
                                    <value>#1</value>
                                </enumeratedValue>
                            </enumeratedValues>
                        </field>
                        <field>
                            <name>ASEL</name>
                            <description>Analog Input Enable</description>
                            <lsb>15</lsb>
                            <msb>15</msb>
                            <access>read-write</access>
                            <enumeratedValues>
                                <enumeratedValue>
                                    <name>0</name>
                                    <description>Not used as an analog pin</description>
                                    <value>#0</value>
                                </enumeratedValue>
                                <enumeratedValue>
                                    <name>1</name>
                                    <description>Used as an analog pin</description>
                                    <value>#1</value>
                                </enumeratedValue>
                            </enumeratedValues>
                        </field>
                        <field>
                            <name>PMR</name>
                            <description>Port Mode Control</description>
                            <lsb>16</lsb>
                            <msb>16</msb>
                            <access>read-write</access>
                            <enumeratedValues>
                                <enumeratedValue>
                                    <name>0</name>
                                    <description>Used as a general I/O pin</description>
                                    <value>#0</value>
                                </enumeratedValue>
                                <enumeratedValue>
                                    <name>1</name>
                                    <description>Used as an I/O port for peripheral functions</description>
                                    <value>#1</value>
                                </enumeratedValue>
                            </enumeratedValues>
                        </field>
                        <field>
                            <name>PSEL</name>
                            <description>Peripheral Select</description>
                            <lsb>24</lsb>
                            <msb>28</msb>
                            <access>read-write</access>
                        </field>
                    </fields>
                </register>
                <register>
                    <dim>4</dim>
                    <dimIncrement>0x004</dimIncrement>
                    <dimIndex>12-15</dimIndex>
                    <name>P1%sPFS_HA</name>
                    <description>Port 1%s Pin Function Select Register</description>
                    <alternateRegister>P1%sPFS</alternateRegister>
                    <addressOffset>0x070</addressOffset>
                    <size>16</size>
                    <access>read-write</access>
                    <resetValue>0x0000</resetValue>
                    <resetMask>0xffff</resetMask>
                    <fields>
                        <field>
                            <name>PMR</name>
                            <description>Port Mode Control</description>
                            <lsb>0</lsb>
                            <msb>0</msb>
                            <access>read-write</access>
                            <enumeratedValues>
                                <enumeratedValue>
                                    <name>0</name>
                                    <description>Used as a general I/O pin</description>
                                    <value>#0</value>
                                </enumeratedValue>
                                <enumeratedValue>
                                    <name>1</name>
                                    <description>Used as an I/O port for peripheral functions</description>
                                    <value>#1</value>
                                </enumeratedValue>
                            </enumeratedValues>
                        </field>
                        <field>
                            <name>PSEL</name>
                            <description>Peripheral Select</description>
                            <lsb>8</lsb>
                            <msb>12</msb>
                            <access>read-write</access>
                        </field>
                    </fields>
                </register>
                <register>
                    <dim>4</dim>
                    <dimIncrement>0x004</dimIncrement>
                    <dimIndex>12-15</dimIndex>
                    <name>P1%sPFS_BY</name>
                    <description>Port 1%s Pin Function Select Register</description>
                    <alternateRegister>P1%sPFS</alternateRegister>
                    <addressOffset>0x070</addressOffset>
                    <size>8</size>
                    <access>read-write</access>
                    <resetValue>0x00</resetValue>
                    <resetMask>0xff</resetMask>
                    <fields>
                        <field>
                            <name>PSEL</name>
                            <description>Peripheral Select</description>
                            <lsb>0</lsb>
                            <msb>4</msb>
                            <access>read-write</access>
                        </field>
                    </fields>
                </register>
                <register>
                    <name>P200PFS</name>
                    <description>Port 200 Pin Function Select Register</description>
                    <addressOffset>0x080</addressOffset>
                    <size>32</size>
                    <access>read-write</access>
                    <resetValue>0x00000000</resetValue>
                    <resetMask>0xffffffff</resetMask>
                    <fields>
                        <field>
                            <name>PODR</name>
                            <description>Port Output Data</description>
                            <lsb>0</lsb>
                            <msb>0</msb>
                            <access>read-write</access>
                            <enumeratedValues>
                                <enumeratedValue>
                                    <name>0</name>
                                    <description>Low output</description>
                                    <value>#0</value>
                                </enumeratedValue>
                                <enumeratedValue>
                                    <name>1</name>
                                    <description>High output</description>
                                    <value>#1</value>
                                </enumeratedValue>
                            </enumeratedValues>
                        </field>
                        <field>
                            <name>PIDR</name>
                            <description>Pmn State</description>
                            <lsb>1</lsb>
                            <msb>1</msb>
                            <access>read-only</access>
                            <enumeratedValues>
                                <enumeratedValue>
                                    <name>0</name>
                                    <description>Low level</description>
                                    <value>#0</value>
                                </enumeratedValue>
                                <enumeratedValue>
                                    <name>1</name>
                                    <description>High level</description>
                                    <value>#1</value>
                                </enumeratedValue>
                            </enumeratedValues>
                        </field>
                        <field>
                            <name>PDR</name>
                            <description>Port Direction</description>
                            <lsb>2</lsb>
                            <msb>2</msb>
                            <access>read-write</access>
                            <enumeratedValues>
                                <enumeratedValue>
                                    <name>0</name>
                                    <description>Input (functions as an input pin)</description>
                                    <value>#0</value>
                                </enumeratedValue>
                                <enumeratedValue>
                                    <name>1</name>
                                    <description>Output (functions as an output pin)</description>
                                    <value>#1</value>
                                </enumeratedValue>
                            </enumeratedValues>
                        </field>
                        <field>
                            <name>PCR</name>
                            <description>Pull-up Control</description>
                            <lsb>4</lsb>
                            <msb>4</msb>
                            <access>read-write</access>
                            <enumeratedValues>
                                <enumeratedValue>
                                    <name>0</name>
                                    <description>Disable input pull-up</description>
                                    <value>#0</value>
                                </enumeratedValue>
                                <enumeratedValue>
                                    <name>1</name>
                                    <description>Enable input pull-up</description>
                                    <value>#1</value>
                                </enumeratedValue>
                            </enumeratedValues>
                        </field>
                        <field>
                            <name>NCODR</name>
                            <description>N-Channel Open-Drain Control</description>
                            <lsb>6</lsb>
                            <msb>6</msb>
                            <access>read-write</access>
                            <enumeratedValues>
                                <enumeratedValue>
                                    <name>0</name>
                                    <description>CMOS output</description>
                                    <value>#0</value>
                                </enumeratedValue>
                                <enumeratedValue>
                                    <name>1</name>
                                    <description>NMOS open-drain output</description>
                                    <value>#1</value>
                                </enumeratedValue>
                            </enumeratedValues>
                        </field>
                        <field>
                            <name>DSCR</name>
                            <description>Port Drive Capability</description>
                            <lsb>10</lsb>
                            <msb>11</msb>
                            <access>read-write</access>
                            <enumeratedValues>
                                <enumeratedValue>
                                    <name>00</name>
                                    <description>Low drive</description>
                                    <value>#00</value>
                                </enumeratedValue>
                                <enumeratedValue>
                                    <name>01</name>
                                    <description>Middle drive</description>
                                    <value>#01</value>
                                </enumeratedValue>
                                <enumeratedValue>
                                    <name>10</name>
                                    <description>High-speed high-drive</description>
                                    <value>#10</value>
                                </enumeratedValue>
                                <enumeratedValue>
                                    <name>11</name>
                                    <description>High drive</description>
                                    <value>#11</value>
                                </enumeratedValue>
                            </enumeratedValues>
                        </field>
                        <field>
                            <name>EOFR</name>
                            <description>Event on Falling/Event on Rising</description>
                            <lsb>12</lsb>
                            <msb>13</msb>
                            <access>read-write</access>
                            <enumeratedValues>
                                <enumeratedValue>
                                    <name>00</name>
                                    <description>Don't care</description>
                                    <value>#00</value>
                                </enumeratedValue>
                                <enumeratedValue>
                                    <name>01</name>
                                    <description>Detect rising edge</description>
                                    <value>#01</value>
                                </enumeratedValue>
                                <enumeratedValue>
                                    <name>10</name>
                                    <description>Detect falling edge</description>
                                    <value>#10</value>
                                </enumeratedValue>
                                <enumeratedValue>
                                    <name>11</name>
                                    <description>Detect both edges</description>
                                    <value>#11</value>
                                </enumeratedValue>
                            </enumeratedValues>
                        </field>
                        <field>
                            <name>ISEL</name>
                            <description>IRQ Input Enable</description>
                            <lsb>14</lsb>
                            <msb>14</msb>
                            <access>read-write</access>
                            <enumeratedValues>
                                <enumeratedValue>
                                    <name>0</name>
                                    <description>Not used as an IRQn input pin</description>
                                    <value>#0</value>
                                </enumeratedValue>
                                <enumeratedValue>
                                    <name>1</name>
                                    <description>Used as an IRQn input pin</description>
                                    <value>#1</value>
                                </enumeratedValue>
                            </enumeratedValues>
                        </field>
                        <field>
                            <name>ASEL</name>
                            <description>Analog Input Enable</description>
                            <lsb>15</lsb>
                            <msb>15</msb>
                            <access>read-write</access>
                            <enumeratedValues>
                                <enumeratedValue>
                                    <name>0</name>
                                    <description>Not used as an analog pin</description>
                                    <value>#0</value>
                                </enumeratedValue>
                                <enumeratedValue>
                        <field>
                            <name>ICLFA</name>
                            <description>GTIOCnA Output Logical Operation Function Select</description>
                            <lsb>0</lsb>
                            <msb>2</msb>
                            <access>read-write</access>
                            <enumeratedValues>
                                <enumeratedValue>
                                    <name>000</name>
                                    <description>A (no delay)</description>
                                    <value>#000</value>
                                </enumeratedValue>
                                <enumeratedValue>
                                    <name>001</name>
                                    <description>NOT A (no delay)</description>
                                    <value>#001</value>
                                </enumeratedValue>
                                <enumeratedValue>
                                    <name>010</name>
                                    <description>C (1PCLKD delay)</description>
                                    <value>#010</value>
                                </enumeratedValue>
                                <enumeratedValue>
                                    <name>011</name>
                                    <description>NOT C (1PCLKD delay)</description>
                                    <value>#011</value>
                                </enumeratedValue>
                                <enumeratedValue>
                                    <name>100</name>
                                    <description>A AND C (1PCLKD delay)</description>
                                    <value>#100</value>
                                </enumeratedValue>
                                <enumeratedValue>
                                    <name>101</name>
                                    <description>A OR C (1PCLKD delay)</description>
                                    <value>#101</value>
                                </enumeratedValue>
                                <enumeratedValue>
                                    <name>110</name>
                                    <description>A EXOR C (1PCLKD delay)</description>
                                    <value>#110</value>
                                </enumeratedValue>
                                <enumeratedValue>
                                    <name>111</name>
                                    <description>A NOR C (1PCLKD delay)</description>
                                    <value>#111</value>
                                </enumeratedValue>
                            </enumeratedValues>
                        </field>
                        <field>
                            <name>ICLFSELC</name>
                            <description>Inter Channel Signal C Select</description>
                            <lsb>4</lsb>
                            <msb>9</msb>
                            <access>read-write</access>
                            <enumeratedValues>
                                <enumeratedValue>
                                    <name>0x00</name>
                                    <description>GTIOC0A</description>
                                    <value>0x00</value>
                                </enumeratedValue>
                                <enumeratedValue>
                                    <name>0x01</name>
                                    <description>GTIOC0B</description>
                                    <value>0x01</value>
                                </enumeratedValue>
                                <enumeratedValue>
                                    <name>0x02</name>
                                    <description>GTIOC1A</description>
                                    <value>0x02</value>
                                </enumeratedValue>
                                <enumeratedValue>
                                    <name>0x03</name>
                                    <description>GTIOC1B</description>
                                    <value>0x03</value>
                                </enumeratedValue>
                                <enumeratedValue>
                                    <name>0x04</name>
                                    <description>GTIOC2A</description>
                                    <value>0x04</value>
                                </enumeratedValue>
                                <enumeratedValue>
                                    <name>0x05</name>
                                    <description>GTIOC2B</description>
                                    <value>0x05</value>
                                </enumeratedValue>
                                <enumeratedValue>
                                    <name>0x06</name>
                                    <description>GTIOC3A</description>
                                    <value>0x06</value>
                                </enumeratedValue>
                                <enumeratedValue>
                                    <name>0x07</name>
                                    <description>GTIOC3B</description>
                                    <value>0x07</value>
                                </enumeratedValue>
                                <enumeratedValue>
                                    <name>0x08</name>
                                    <description>GTIOC4A</description>
                                    <value>0x08</value>
                                </enumeratedValue>
                                <enumeratedValue>
                                    <name>0x09</name>
                                    <description>GTIOC4B</description>
                                    <value>0x09</value>
                                </enumeratedValue>
                                <enumeratedValue>
                                    <name>0x0A</name>
                                    <description>GTIOC5A</description>
                                    <value>0x0a</value>
                                </enumeratedValue>
                                <enumeratedValue>
                                    <name>0x0B</name>
                                    <description>GTIOC5B</description>
                                    <value>0x0b</value>
                                </enumeratedValue>
                                <enumeratedValue>
                                    <name>0x0C</name>
                                    <description>GTIOC6A</description>
                                    <value>0x0c</value>
                                </enumeratedValue>
                                <enumeratedValue>
                                    <name>0x0D</name>
                                    <description>GTIOC6B</description>
                                    <value>0x0d</value>
                                </enumeratedValue>
                                <enumeratedValue>
                                    <name>0x0E</name>
                                    <description>GTIOC7A</description>
                                    <value>0x0e</value>
                                </enumeratedValue>
                                <enumeratedValue>
                                    <name>0x0F</name>
                                    <description>GTIOC7B</description>
                                    <value>0x0f</value>
                                </enumeratedValue>
                                <enumeratedValue>
                                    <name>0x10</name>
                                    <description>GTIOC8A</description>
                                    <value>0x10</value>
                                </enumeratedValue>
                                <enumeratedValue>
                                    <name>0x11</name>
                                    <description>GTIOC8B</description>
                                    <value>0x11</value>
                                </enumeratedValue>
                                <enumeratedValue>
                                    <name>0x12</name>
                                    <description>GTIOC9A</description>
                                    <value>0x12</value>
                                </enumeratedValue>
                                <enumeratedValue>
                                    <name>0x13</name>
                                    <description>GTIOC9B</description>
                                    <value>0x13</value>
                                </enumeratedValue>
                                <enumeratedValue>
                                    <name>Others</name>
                                    <description>Setting prohibited</description>
                                    <isDefault>true</isDefault>
                                </enumeratedValue>
                            </enumeratedValues>
                        </field>
                        <field>
                            <name>ICLFB</name>
                            <description>GTIOCnB Output Logical Operation Function Select</description>
                            <lsb>16</lsb>
                            <msb>18</msb>
                            <access>read-write</access>
                            <enumeratedValues>
                                <enumeratedValue>
                                    <name>000</name>
                                    <description>B (no delay)</description>
                                    <value>#000</value>
                                </enumeratedValue>
                                <enumeratedValue>
                                    <name>001</name>
                                    <description>NOT B (no delay)</description>
                                    <value>#001</value>
                                </enumeratedValue>
                                <enumeratedValue>
                                    <name>010</name>
                                    <description>D (1PCLKD delay)</description>
                                    <value>#010</value>
                                </enumeratedValue>
                                <enumeratedValue>
                                    <name>011</name>
                                    <description>NOT D (1PCLKD delay)</description>
                                    <value>#011</value>
                                </enumeratedValue>
                                <enumeratedValue>
                                    <name>100</name>
                                    <description>B AND D (1PCLKD delay)</description>
                                    <value>#100</value>
                                </enumeratedValue>
                                <enumeratedValue>
                                    <name>101</name>
                                    <description>B OR D (1PCLKDn delay)</description>
                                    <value>#101</value>
                                </enumeratedValue>
                                <enumeratedValue>
                                    <name>110</name>
                                    <description>B EXOR D (1PCLKD delay)</description>
                                    <value>#110</value>
                                </enumeratedValue>
                                <enumeratedValue>
                                    <name>111</name>
                                    <description>B NOR D (1PCLKD delay)</description>
                                    <value>#111</value>
                                </enumeratedValue>
                            </enumeratedValues>
                        </field>
                        <field>
                            <name>ICLFSELD</name>
                            <description>Inter Channel Signal D Select</description>
                            <lsb>20</lsb>
                            <msb>25</msb>
                            <access>read-write</access>
                            <enumeratedValues>
                                <enumeratedValue>
                                    <name>0x00</name>
                                    <description>GTIOC0A</description>
                                    <value>0x00</value>
                                </enumeratedValue>
                                <enumeratedValue>
                                    <name>0x01</name>
                                    <description>GTIOC0B</description>
                                    <value>0x01</value>
                                </enumeratedValue>
                                <enumeratedValue>
                                    <name>0x02</name>
                                    <description>GTIOC1A</description>
                                    <value>0x02</value>
                                </enumeratedValue>
                                <enumeratedValue>
                                    <name>0x03</name>
                                    <description>GTIOC1B</description>
                                    <value>0x03</value>
                                </enumeratedValue>
                                <enumeratedValue>
                                    <name>0x04</name>
                                    <description>GTIOC2A</description>
                                    <value>0x04</value>
                                </enumeratedValue>
                                <enumeratedValue>
                                    <name>0x05</name>
                                    <description>GTIOC2B</description>
                                    <value>0x05</value>
                                </enumeratedValue>
                                <enumeratedValue>
                                    <name>0x06</name>
                                    <description>GTIOC3A</description>
                                    <value>0x06</value>
                                </enumeratedValue>
                                <enumeratedValue>
                                    <name>0x07</name>
                                    <description>GTIOC3B</description>
                                    <value>0x07</value>
                                </enumeratedValue>
                                <enumeratedValue>
                                    <name>0x08</name>
                                    <description>GTIOC4A</description>
                                    <value>0x08</value>
                                </enumeratedValue>
                                <enumeratedValue>
                                    <name>0x09</name>
                                    <description>GTIOC4B</description>
                                    <value>0x09</value>
                                </enumeratedValue>
                                <enumeratedValue>
                                    <name>0x0A</name>
                                    <description>GTIOC5A</description>
                                    <value>0x0a</value>
                                </enumeratedValue>
                                <enumeratedValue>
                                    <name>0x0B</name>
                                    <description>GTIOC5B</description>
                                    <value>0x0b</value>
                                </enumeratedValue>
                                <enumeratedValue>
                                    <name>0x0C</name>
                                    <description>GTIOC6A</description>
                                    <value>0x0c</value>
                                </enumeratedValue>
                                <enumeratedValue>
                                    <name>0x0D</name>
                                    <description>GTIOC6B</description>
                                    <value>0x0d</value>
                                </enumeratedValue>
                                <enumeratedValue>
                                    <name>0x0E</name>
                                    <description>GTIOC7A</description>
                                    <value>0x0e</value>
                                </enumeratedValue>
                                <enumeratedValue>
                                    <name>0x0F</name>
                                    <description>GTIOC7B</description>
                                    <value>0x0f</value>
                                </enumeratedValue>
                                <enumeratedValue>
                                    <name>0x10</name>
                                    <description>GTIOC8A</description>
                                    <value>0x10</value>
                                </enumeratedValue>
                                <enumeratedValue>
                                    <name>0x11</name>
                                    <description>GTIOC8B</description>
                                    <value>0x11</value>
                                </enumeratedValue>
                                <enumeratedValue>
                                    <name>0x12</name>
                                    <description>GTIOC9A</description>
                                    <value>0x12</value>
                                </enumeratedValue>
                                <enumeratedValue>
                                    <name>0x13</name>
                                    <description>GTIOC9B</description>
                                    <value>0x13</value>
                                </enumeratedValue>
                                <enumeratedValue>
                                    <name>Others</name>
                                    <description>Setting prohibited</description>
                                    <isDefault>true</isDefault>
                                </enumeratedValue>
                            </enumeratedValues>
                        </field>
                    </fields>
                </register>
            </registers>
        </peripheral>
        <peripheral derivedFrom="GPT168_NS">
            <name>GPT169_NS</name>
            <description>General PWM 16-bit Timer 9</description>
            <baseAddress>0x50322900</baseAddress>
        </peripheral>
        <peripheral>
            <name>GPT1610_NS</name>
            <description>General PWM 16-bit Timer 10</description>
            <baseAddress>0x50322A00</baseAddress>
            <addressBlock>
                <offset>0x00</offset>
                <size>4</size>
                <usage>registers</usage>
            </addressBlock>
            <addressBlock>
                <offset>0x30</offset>
                <size>8</size>
                <usage>registers</usage>
            </addressBlock>
            <addressBlock>
                <offset>0x3C</offset>
                <size>8</size>
                <usage>registers</usage>
            </addressBlock>
            <addressBlock>
                <offset>0x48</offset>
                <size>36</size>
                <usage>registers</usage>
            </addressBlock>
            <addressBlock>
                <offset>0x88</offset>
                <size>8</size>
                <usage>registers</usage>
            </addressBlock>
            <addressBlock>
                <offset>0xBC</offset>
                <size>4</size>
                <usage>registers</usage>
            </addressBlock>
            <addressBlock>
                <offset>0xD0</offset>
                <size>8</size>
                <usage>registers</usage>
            </addressBlock>
            <registers>
                <register>
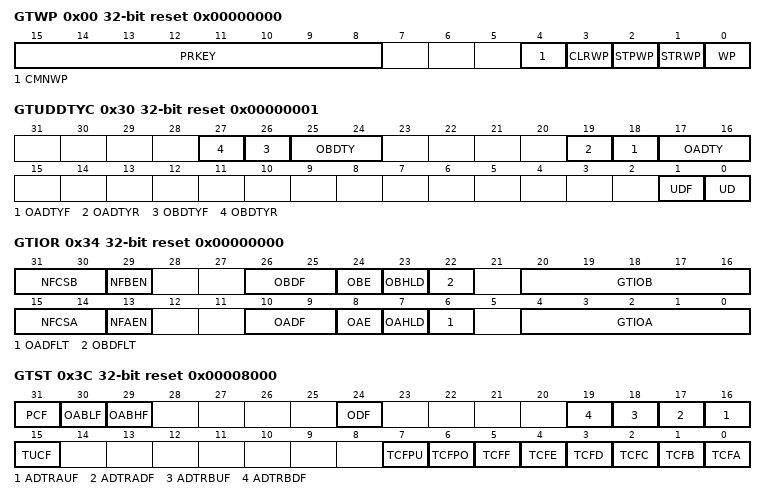
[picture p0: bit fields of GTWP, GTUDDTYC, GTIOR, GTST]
                    <name>GTWP</name>
                    <description>General PWM Timer Write-Protection Register</description>
                    <addressOffset>0x00</addressOffset>
                    <size>32</size>
                    <access>read-write</access>
                    <resetValue>0x00000000</resetValue>
                    <resetMask>0xffffffff</resetMask>
                    <fields>
                        <field>
                            <name>WP</name>
                            <description>Register Write Disable</description>
                            <lsb>0</lsb>
                            <msb>0</msb>
                            <access>read-write</access>
                            <enumeratedValues>
                                <enumeratedValue>
                                    <name>0</name>
                                    <description>Write to the register enabled</description>
                                    <value>#0</value>
                                </enumeratedValue>
                                <enumeratedValue>
                                    <name>1</name>
                                    <description>Write to the register disabled</description>
                                    <value>#1</value>
                                </enumeratedValue>
                            </enumeratedValues>
                        </field>
                        <field>
                            <name>STRWP</name>
                            <description>GTSTR.CSTRT Bit Write Disable</description>
                            <lsb>1</lsb>
                            <msb>1</msb>
                            <access>read-write</access>
                            <enumeratedValues>
                                <enumeratedValue>
                                    <name>0</name>
                                    <description>Write to the bit is enabled</description>
                                    <value>#0</value>
                                </enumeratedValue>
                                <enumeratedValue>
                                    <name>1</name>
                                    <description>Write to the bit is disabled</description>
                                    <value>#1</value>
                                </enumeratedValue>
                            </enumeratedValues>
                        </field>
                        <field>
                            <name>STPWP</name>
                            <description>GTSTP.CSTOP Bit Write Disable</description>
                            <lsb>2</lsb>
                            <msb>2</msb>
                            <access>read-write</access>
                            <enumeratedValues>
                                <enumeratedValue>
                                    <name>0</name>
                                    <description>Write to the bit is enabled</description>
                                    <value>#0</value>
                                </enumeratedValue>
                                <enumeratedValue>
                                    <name>1</name>
                                    <description>Write to the bit is disabled</description>
                                    <value>#1</value>
                                </enumeratedValue>
                            </enumeratedValues>
                        </field>
                        <field>
                            <name>CLRWP</name>
                            <description>GTCLR.CCLR Bit Write Disable</description>
                            <lsb>3</lsb>
                            <msb>3</msb>
                            <access>read-write</access>
                            <enumeratedValues>
                                <enumeratedValue>
                                    <name>0</name>
                                    <description>Write to the bit is enabled</description>
                                    <value>#0</value>
                                </enumeratedValue>
                                <enumeratedValue>
                                    <name>1</name>
                                    <description>Write to the bit is disabled</description>
                                    <value>#1</value>
                                </enumeratedValue>
                            </enumeratedValues>
                        </field>
                        <field>
                            <name>CMNWP</name>
                            <description>Common Register Write Disabled</description>
                            <lsb>4</lsb>
                            <msb>4</msb>
                            <access>read-write</access>
                            <enumeratedValues>
                                <enumeratedValue>
                                    <name>0</name>
                                    <description>Write to the register is enabled</description>
                                    <value>#0</value>
                                </enumeratedValue>
                                <enumeratedValue>
                                    <name>1</name>
                                    <description>Write to the register is disabled</description>
                                    <value>#1</value>
                                </enumeratedValue>
                            </enumeratedValues>
                        </field>
                        <field>
                            <name>PRKEY</name>
                            <description>GTWP Key Code</description>
                            <lsb>8</lsb>
                            <msb>15</msb>
                            <access>write-only</access>
                        </field>
                    </fields>
                </register>
                <register>
                    <name>GTUDDTYC</name>
                    <description>General PWM Timer Count Direction and Duty Setting Register</description>
                    <addressOffset>0x30</addressOffset>
                    <size>32</size>
                    <access>read-write</access>
                    <resetValue>0x00000001</resetValue>
                    <resetMask>0xffffffff</resetMask>
                    <fields>
                        <field>
                            <name>UD</name>
                            <description>Count Direction Setting</description>
                            <lsb>0</lsb>
                            <msb>0</msb>
                            <access>read-write</access>
                            <enumeratedValues>
                                <enumeratedValue>
                                    <name>0</name>
                                    <description>GTCNT counts down</description>
                                    <value>#0</value>
                                </enumeratedValue>
                                <enumeratedValue>
                                    <name>1</name>
                                    <description>GTCNT counts up</description>
                                    <value>#1</value>
                                </enumeratedValue>
                            </enumeratedValues>
                        </field>
                        <field>
                            <name>UDF</name>
                            <description>Forcible Count Direction Setting</description>
                            <lsb>1</lsb>
                            <msb>1</msb>
                            <access>read-write</access>
                            <enumeratedValues>
                                <enumeratedValue>
                                    <name>0</name>
                                    <description>Not forcibly set</description>
                                    <value>#0</value>
                                </enumeratedValue>
                                <enumeratedValue>
                                    <name>1</name>
                                    <description>Forcibly set</description>
                                    <value>#1</value>
                                </enumeratedValue>
                            </enumeratedValues>
                        </field>
                        <field>
                            <name>OADTY</name>
                            <description>GTIOCnA Output Duty Setting</description>
                            <lsb>16</lsb>
                            <msb>17</msb>
                            <access>read-write</access>
                            <enumeratedValues>
                                <enumeratedValue>
                                    <name>00</name>
                                    <description>GTIOCnA pin duty depends on the compare match</description>
                                    <value>#00</value>
                                </enumeratedValue>
                                <enumeratedValue>
                                    <name>01</name>
                                    <description>GTIOCnA pin duty depends on the compare match</description>
                                    <value>#01</value>
                                </enumeratedValue>
                                <enumeratedValue>
                                    <name>10</name>
                                    <description>GTIOCnA pin duty 0%</description>
                                    <value>#10</value>
                                </enumeratedValue>
                                <enumeratedValue>
                                    <name>11</name>
                                    <description>GTIOCnA pin duty 100%</description>
                                    <value>#11</value>
                                </enumeratedValue>
                            </enumeratedValues>
                        </field>
                        <field>
                            <name>OADTYF</name>
                            <description>Forcible GTIOCnA Output Duty Setting</description>
                            <lsb>18</lsb>
                            <msb>18</msb>
                            <access>read-write</access>
                            <enumeratedValues>
                                <enumeratedValue>
                                    <name>0</name>
                                    <description>Not forcibly set</description>
                                    <value>#0</value>
                                </enumeratedValue>
                                <enumeratedValue>
                                    <name>1</name>
                                    <description>Forcibly set</description>
                                    <value>#1</value>
                                </enumeratedValue>
                            </enumeratedValues>
                        </field>
                        <field>
                            <name>OADTYR</name>
                            <description>GTIOCnA Output Value Selecting after Releasing 0%/100% Duty Setting</description>
                            <lsb>19</lsb>
                            <msb>19</msb>
                            <access>read-write</access>
                            <enumeratedValues>
                                <enumeratedValue>
                                    <name>0</name>
                                    <description>The function selected by the GTIOA[3:2] bits is applied to the output value when the duty cycle is set after release from the 0 or 100% duty-cycle setting.</description>
                                    <value>#0</value>
                                </enumeratedValue>
                                <enumeratedValue>
                                    <name>1</name>
                                    <description>The function selected by the GTIOA[3:2] bits is applied to the compare match output value which is masked after release from the 0 or 100% duty-cycle setting.</description>
                                    <value>#1</value>
                                </enumeratedValue>
                            </enumeratedValues>
                        </field>
                        <field>
                            <name>OBDTY</name>
                            <description>GTIOCnB Output Duty Setting</description>
                            <lsb>24</lsb>
                            <msb>25</msb>
                            <access>read-write</access>
                            <enumeratedValues>
                                <enumeratedValue>
                                    <name>00</name>
                                    <description>GTIOCnB pin duty depends on the compare match</description>
                                    <value>#00</value>
                                </enumeratedValue>
                                <enumeratedValue>
                                    <name>01</name>
                                    <description>GTIOCnB pin duty depends on the compare match</description>
                                    <value>#01</value>
                                </enumeratedValue>
                                <enumeratedValue>
                                    <name>10</name>
                                    <description>GTIOCnB pin duty 0%</description>
                                    <value>#10</value>
                                </enumeratedValue>
                                <enumeratedValue>
                                    <name>11</name>
                                    <description>GTIOCnB pin duty 100%</description>
                                    <value>#11</value>
                                </enumeratedValue>
                            </enumeratedValues>
                        </field>
                        <field>
                            <name>OBDTYF</name>
                            <description>Forcible GTIOCnB Output Duty Setting</description>
                            <lsb>26</lsb>
                            <msb>26</msb>
                            <access>read-write</access>
                            <enumeratedValues>
                                <enumeratedValue>
                                    <name>0</name>
                                    <description>Not forcibly set</description>
                                    <value>#0</value>
                                </enumeratedValue>
                                <enumeratedValue>
                                    <name>1</name>
                                    <description>Forcibly set</description>
                                    <value>#1</value>
                                </enumeratedValue>
                            </enumeratedValues>
                        </field>
                        <field>
                            <name>OBDTYR</name>
                            <description>GTIOCnB Output Value Selecting after Releasing 0%/100% Duty Setting</description>
                            <lsb>27</lsb>
                            <msb>27</msb>
                            <access>read-write</access>
                            <enumeratedValues>
                                <enumeratedValue>
                                    <name>0</name>
                                    <description>The function selected by the GTIOB[3:2] bits is applied to the output value when the duty cycle is set after release from the 0 or 100% duty-cycle setting.</description>
                                    <value>#0</value>
                                </enumeratedValue>
                                <enumeratedValue>
                                    <name>1</name>
                                    <description>The function selected by the GTIOB[3:2] bits is applied to the compare match output value which is masked after release from the 0 or 100% duty-cycle setting.</description>
                                    <value>#1</value>
                                </enumeratedValue>
                            </enumeratedValues>
                        </field>
                    </fields>
                </register>
                <register>
                    <name>GTIOR</name>
                    <description>General PWM Timer I/O Control Register</description>
                    <addressOffset>0x34</addressOffset>
                    <size>32</size>
                    <access>read-write</access>
                    <resetValue>0x00000000</resetValue>
                    <resetMask>0xffffffff</resetMask>
                    <fields>
                        <field>
                            <name>GTIOA</name>
                            <description>GTIOCnA Pin Function Select</description>
                            <lsb>0</lsb>
                            <msb>4</msb>
                            <access>read-write</access>
                        </field>
                        <field>
                            <name>OADFLT</name>
                            <description>GTIOCnA Pin Output Value Setting at the Count Stop</description>
                            <lsb>6</lsb>
                            <msb>6</msb>
                            <access>read-write</access>
                            <enumeratedValues>
                                <enumeratedValue>
                                    <name>0</name>
                                    <description>The GTIOCnA pin outputs low when counting stops</description>
                                    <value>#0</value>
                                </enumeratedValue>
                                <enumeratedValue>
                                    <name>1</name>
                                    <description>The GTIOCnA pin outputs high when counting stops</description>
                                    <value>#1</value>
                                </enumeratedValue>
                            </enumeratedValues>
                        </field>
                        <field>
                            <name>OAHLD</name>
                            <description>GTIOCnA Pin Output Setting at the Start/Stop Count</description>
                            <lsb>7</lsb>
                            <msb>7</msb>
                            <access>read-write</access>
                            <enumeratedValues>
                                <enumeratedValue>
                                    <name>0</name>
                                    <description>The GTIOCnA pin output level at the start or stop of counting depends on the register setting</description>
                                    <value>#0</value>
                                </enumeratedValue>
                                <enumeratedValue>
                                    <name>1</name>
                                    <description>The GTIOCnA pin output level is retained at the start or stop of counting</description>
                                    <value>#1</value>
                                </enumeratedValue>
                            </enumeratedValues>
                        </field>
                        <field>
                            <name>OAE</name>
                            <description>GTIOCnA Pin Output Enable</description>
                            <lsb>8</lsb>
                            <msb>8</msb>
                            <access>read-write</access>
                            <enumeratedValues>
                                <enumeratedValue>
                                    <name>0</name>
                                    <description>Output is disabled</description>
                                    <value>#0</value>
                                </enumeratedValue>
                                <enumeratedValue>
                                    <name>1</name>
                                    <description>Output is enabled</description>
                                    <value>#1</value>
                                </enumeratedValue>
                            </enumeratedValues>
                        </field>
                        <field>
                            <name>OADF</name>
                            <description>GTIOCnA Pin Disable Value Setting</description>
                            <lsb>9</lsb>
                            <msb>10</msb>
                            <access>read-write</access>
                            <enumeratedValues>
                                <enumeratedValue>
                                    <name>00</name>
                                    <description>None of the below options are specified</description>
                                    <value>#00</value>
                                </enumeratedValue>
                                <enumeratedValue>
                                    <name>01</name>
                                    <description>GTIOCnA pin is set to Hi-Z in response to controlling the output negation</description>
                                    <value>#01</value>
                                </enumeratedValue>
                                <enumeratedValue>
                                    <name>10</name>
                                    <description>GTIOCnA pin is set to 0 in response to controlling the output negation</description>
                                    <value>#10</value>
                                </enumeratedValue>
                                <enumeratedValue>
                                    <name>11</name>
                                    <description>GTIOCnA pin is set to 1 in response to controlling the output negation</description>
                                    <value>#11</value>
                                </enumeratedValue>
                            </enumeratedValues>
                        </field>
                        <field>
                            <name>NFAEN</name>
                            <description>Noise Filter A Enable</description>
                            <lsb>13</lsb>
                            <msb>13</msb>
                            <access>read-write</access>
                            <enumeratedValues>
                                <enumeratedValue>
                                    <name>0</name>
                                    <description>The noise filter for the GTIOCnA pin is disabled</description>
                                    <value>#0</value>
                                </enumeratedValue>
                                <enumeratedValue>
                                    <name>1</name>
                                    <description>The noise filter for the GTIOCnA pin is enabled</description>
                                    <value>#1</value>
                                </enumeratedValue>
                            </enumeratedValues>
                        </field>
                        <field>
                            <name>NFCSA</name>
                            <description>Noise Filter A Sampling Clock Select</description>
                            <lsb>14</lsb>
                            <msb>15</msb>
                            <access>read-write</access>
                            <enumeratedValues>
                                <enumeratedValue>
                                    <name>00</name>
                                    <description>PCLKD/1</description>
                                    <value>#00</value>
                                </enumeratedValue>
                                <enumeratedValue>
                                    <name>01</name>
                                    <description>PCLKD/4</description>
                                    <value>#01</value>
                                </enumeratedValue>
                                <enumeratedValue>
                                    <name>10</name>
                                    <description>PCLKD/16</description>
                                    <value>#10</value>
                                </enumeratedValue>
                                <enumeratedValue>
                                    <name>11</name>
                                    <description>PCLKD/64</description>
                                    <value>#11</value>
                                </enumeratedValue>
                            </enumeratedValues>
                        </field>
                        <field>
                            <name>GTIOB</name>
                            <description>GTIOCnB Pin Function Select</description>
                            <lsb>16</lsb>
                            <msb>20</msb>
                            <access>read-write</access>
                        </field>
                        <field>
                            <name>OBDFLT</name>
                            <description>GTIOCnB Pin Output Value Setting at the Count Stop</description>
                            <lsb>22</lsb>
                            <msb>22</msb>
                            <access>read-write</access>
                            <enumeratedValues>
                                <enumeratedValue>
                                    <name>0</name>
                                    <description>The GTIOCnB pin outputs low when counting stops</description>
                                    <value>#0</value>
                                </enumeratedValue>
                                <enumeratedValue>
                                    <name>1</name>
                                    <description>The GTIOCnB pin outputs high when counting stops</description>
                                    <value>#1</value>
                                </enumeratedValue>
                            </enumeratedValues>
                        </field>
                        <field>
                            <name>OBHLD</name>
                            <description>GTIOCnB Pin Output Setting at the Start/Stop Count</description>
                            <lsb>23</lsb>
                            <msb>23</msb>
                            <access>read-write</access>
                            <enumeratedValues>
                                <enumeratedValue>
                                    <name>0</name>
                                    <description>The GTIOCnB pin output level at the start/stop of counting depends on the register setting</description>
                                    <value>#0</value>
                                </enumeratedValue>
                                <enumeratedValue>
                                    <name>1</name>
                                    <description>The GTIOCnB pin output level is retained at the start/stop of counting</description>
                                    <value>#1</value>
                                </enumeratedValue>
                            </enumeratedValues>
                        </field>
                        <field>
                            <name>OBE</name>
                            <description>GTIOCnB Pin Output Enable</description>
                            <lsb>24</lsb>
                            <msb>24</msb>
                            <access>read-write</access>
                            <enumeratedValues>
                                <enumeratedValue>
                                    <name>0</name>
                                    <description>Output is disabled</description>
                                    <value>#0</value>
                                </enumeratedValue>
                                <enumeratedValue>
                                    <name>1</name>
                                    <description>Output is enabled</description>
                                    <value>#1</value>
                                </enumeratedValue>
                            </enumeratedValues>
                        </field>
                        <field>
                            <name>OBDF</name>
                            <description>GTIOCnB Pin Disable Value Setting</description>
                            <lsb>25</lsb>
                            <msb>26</msb>
                            <access>read-write</access>
                            <enumeratedValues>
                                <enumeratedValue>
                                    <name>00</name>
                                    <description>None of the below options are specified</description>
                                    <value>#00</value>
                                </enumeratedValue>
                                <enumeratedValue>
                                    <name>01</name>
                                    <description>GTIOCnB pin is set to Hi-Z in response to controlling the output negation</description>
                                    <value>#01</value>
                                </enumeratedValue>
                                <enumeratedValue>
                                    <name>10</name>
                                    <description>GTIOCnB pin is set to 0 in response to controlling the output negation</description>
                                    <value>#10</value>
                                </enumeratedValue>
                                <enumeratedValue>
                                    <name>11</name>
                                    <description>GTIOCnB pin is set to 1 in response to controlling the output negation</description>
                                    <value>#11</value>
                                </enumeratedValue>
                            </enumeratedValues>
                        </field>
                        <field>
                            <name>NFBEN</name>
                            <description>Noise Filter B Enable</description>
                            <lsb>29</lsb>
                            <msb>29</msb>
                            <access>read-write</access>
                            <enumeratedValues>
                                <enumeratedValue>
                                    <name>0</name>
                                    <description>The noise filter for the GTIOCnB pin is disabled</description>
                                    <value>#0</value>
                                </enumeratedValue>
                                <enumeratedValue>
                                    <name>1</name>
                                    <description>The noise filter for the GTIOCnB pin is enabled</description>
                                    <value>#1</value>
                                </enumeratedValue>
                            </enumeratedValues>
                        </field>
                        <field>
                            <name>NFCSB</name>
                            <description>Noise Filter B Sampling Clock Select</description>
                            <lsb>30</lsb>
                            <msb>31</msb>
                            <access>read-write</access>
                            <enumeratedValues>
                                <enumeratedValue>
                                    <name>00</name>
                                    <description>PCLKD/1</description>
                                    <value>#00</value>
                                </enumeratedValue>
                                <enumeratedValue>
                                    <name>01</name>
                                    <description>PCLKD/4</description>
                                    <value>#01</value>
                                </enumeratedValue>
                                <enumeratedValue>
                                    <name>10</name>
                                    <description>PCLKD/16</description>
                                    <value>#10</value>
                                </enumeratedValue>
                                <enumeratedValue>
                                    <name>11</name>
                                    <description>PCLKD/64</description>
                                    <value>#11</value>
                                </enumeratedValue>
                            </enumeratedValues>
                        </field>
                    </fields>
                </register>
                <register>
                    <name>GTST</name>
                    <description>General PWM Timer Status Register</description>
                    <addressOffset>0x3C</addressOffset>
                    <size>32</size>
                    <access>read-write</access>
                    <resetValue>0x00008000</resetValue>
                    <resetMask>0xffffffff</resetMask>
                    <fields>
                        <field>
                            <name>TCFA</name>
                            <description>Input Capture/Compare Match Flag A</description>
                            <lsb>0</lsb>
                            <msb>0</msb>
                            <access>read-write</access>
                            <enumeratedValues>
                                <enumeratedValue>
                                    <name>0</name>
                                    <description>No input capture/compare match of GTCCRA is generated</description>
                                    <value>#0</value>
                                </enumeratedValue>
                                <enumeratedValue>
                                    <name>1</name>
                                    <description>An input capture/compare match of GTCCRA is generated</description>
                                    <value>#1</value>
                                </enumeratedValue>
                            </enumeratedValues>
                        </field>
                        <field>
                            <name>TCFB</name>
                            <description>Input Capture/Compare Match Flag B</description>
                            <lsb>1</lsb>
                            <msb>1</msb>
                            <access>read-write</access>
                            <enumeratedValues>
                                <enumeratedValue>
                                    <name>0</name>
                                    <description>No input capture/compare match of GTCCRB is generated</description>
                                    <value>#0</value>
                                </enumeratedValue>
                                <enumeratedValue>
                                    <name>1</name>
                                    <description>An input capture/compare match of GTCCRB is generated</description>
                                    <value>#1</value>
                                </enumeratedValue>
                            </enumeratedValues>
                        </field>
                        <field>
                            <name>TCFC</name>
                            <description>Input Compare Match Flag C</description>
                            <lsb>2</lsb>
                            <msb>2</msb>
                            <access>read-write</access>
                            <enumeratedValues>
                                <enumeratedValue>
                                    <name>0</name>
                                    <description>No compare match of GTCCRC is generated</description>
                                    <value>#0</value>
                                </enumeratedValue>
                                <enumeratedValue>
                                    <name>1</name>
                                    <description>A compare match of GTCCRC is generated</description>
                                    <value>#1</value>
                                </enumeratedValue>
                            </enumeratedValues>
                        </field>
                        <field>
                            <name>TCFD</name>
                            <description>Input Compare Match Flag D</description>
                            <lsb>3</lsb>
                            <msb>3</msb>
                            <access>read-write</access>
                            <enumeratedValues>
                                <enumeratedValue>
                                    <name>0</name>
                                    <description>No compare match of GTCCRD is generated</description>
                                    <value>#0</value>
                                </enumeratedValue>
                                <enumeratedValue>
                                    <name>1</name>
                                    <description>A compare match of GTCCRD is generated</description>
                                    <value>#1</value>
                                </enumeratedValue>
                            </enumeratedValues>
                        </field>
                        <field>
                            <name>TCFE</name>
                            <description>Input Compare Match Flag E</description>
                            <lsb>4</lsb>
                            <msb>4</msb>
                            <access>read-write</access>
                            <enumeratedValues>
                                <enumeratedValue>
                                    <name>0</name>
                                    <description>No compare match of GTCCRE is generated</description>
                                    <value>#0</value>
                                </enumeratedValue>
                                <enumeratedValue>
                                    <name>1</name>
                                    <description>A compare match of GTCCRE is generated</description>
                                    <value>#1</value>
                                </enumeratedValue>
                            </enumeratedValues>
                        </field>
                        <field>
                            <name>TCFF</name>
                            <description>Input Compare Match Flag F</description>
                            <lsb>5</lsb>
                            <msb>5</msb>
                            <access>read-write</access>
                            <enumeratedValues>
                                <enumeratedValue>
                                    <name>0</name>
                                    <description>No compare match of GTCCRF is generated</description>
                                    <value>#0</value>
                                </enumeratedValue>
                                <enumeratedValue>
                                    <name>1</name>
                                    <description>A compare match of GTCCRF is generated</description>
                                    <value>#1</value>
                                </enumeratedValue>
                            </enumeratedValues>
                        </field>
                        <field>
                            <name>TCFPO</name>
                            <description>Overflow Flag</description>
                            <lsb>6</lsb>
                            <msb>6</msb>
                            <access>read-write</access>
                            <enumeratedValues>
                                <enumeratedValue>
                                    <name>0</name>
                                    <description>No overflow (crest) occurred</description>
                                    <value>#0</value>
                                </enumeratedValue>
                                <enumeratedValue>
                                    <name>1</name>
                                    <description>An overflow (crest) occurred</description>
                                    <value>#1</value>
                                </enumeratedValue>
                            </enumeratedValues>
                        </field>
                        <field>
                            <name>TCFPU</name>
                            <description>Underflow Flag</description>
                            <lsb>7</lsb>
                            <msb>7</msb>
                            <access>read-write</access>
                            <enumeratedValues>
                                <enumeratedValue>
                                    <name>0</name>
                                    <description>No underflow (trough) occurred</description>
                                    <value>#0</value>
                                </enumeratedValue>
                                <enumeratedValue>
                                    <name>1</name>
                                    <description>An underflow (trough) occurred</description>
                                    <value>#1</value>
                                </enumeratedValue>
                            </enumeratedValues>
                        </field>
                        <field>
                            <name>TUCF</name>
                            <description>Count Direction Flag</description>
                            <lsb>15</lsb>
                            <msb>15</msb>
                            <access>read-only</access>
                            <enumeratedValues>
                                <enumeratedValue>
                                    <name>0</name>
                                    <description>GTCNT counter counts downward</description>
                                    <value>#0</value>
                                </enumeratedValue>
                                <enumeratedValue>
                                    <name>1</name>
                                    <description>GTCNT counter counts upward</description>
                                    <value>#1</value>
                                </enumeratedValue>
                            </enumeratedValues>
                        </field>
                        <field>
                            <name>ADTRAUF</name>
                            <description>GTADTRA Register Compare Match (Up-Counting) A/D Conversion Start Request Flag</description>
                            <lsb>16</lsb>
                            <msb>16</msb>
                            <access>read-write</access>
                            <enumeratedValues>
                                <enumeratedValue>
                                    <name>0</name>
                                    <description>No GTADTRA register compare match has occurred in up-counting.</description>
                                    <value>#0</value>
                                </enumeratedValue>
                                <enumeratedValue>
                                    <name>1</name>
                                    <description>A GTADTRA register compare match has occurred in up-counting.</description>
                                    <value>#1</value>
                                </enumeratedValue>
                            </enumeratedValues>
                        </field>
                        <field>
                            <name>ADTRADF</name>
                            <description>GTADTRA Register Compare Match (Down-Counting) A/D Conversion Start Request Flag</description>
                            <lsb>17</lsb>
                            <msb>17</msb>
                            <access>read-write</access>
                            <enumeratedValues>
                                <enumeratedValue>
                                    <name>0</name>
                                    <description>No GTADTRA register compare match has occurred in down-counting.</description>
                                    <value>#0</value>
                                </enumeratedValue>
                                <enumeratedValue>
                                    <name>1</name>
                                    <description>A GTADTRA register compare match has occurred in down-counting.</description>
                                    <value>#1</value>
                                </enumeratedValue>
                            </enumeratedValues>
                        </field>
                        <field>
                            <name>ADTRBUF</name>
                            <description>GTADTRB Register Compare Match (Up-Counting) A/D Conversion Start Request Flag</description>
                            <lsb>18</lsb>
                            <msb>18</msb>
                            <access>read-write</access>
                            <enumeratedValues>
                                <enumeratedValue>
                                    <name>0</name>
                                    <description>No GTADTRB register compare match has occurred in up-counting.</description>
                                    <value>#0</value>
                                </enumeratedValue>
                                <enumeratedValue>
                                    <name>1</name>
                                    <description>A GTADTRB register compare match has occurred in up-counting.</description>
                                    <value>#1</value>
                                </enumeratedValue>
                            </enumeratedValues>
                        </field>
                        <field>
                            <name>ADTRBDF</name>
                            <description>GTADTRB Register Compare Match (Down-Counting) A/D Conversion Start Request Flag</description>
                            <lsb>19</lsb>
                            <msb>19</msb>
                            <access>read-write</access>
                            <enumeratedValues>
                                <enumeratedValue>
                                    <name>0</name>
                                    <description>No GTADTRB register compare match has occurred in down-counting.</description>
                                    <value>#0</value>
                                </enumeratedValue>
                                <enumeratedValue>
                                    <name>1</name>
                                    <description>A GTADTRB register compare match has occurred in down-counting.</description>
                                    <value>#1</value>
                                </enumeratedValue>
                            </enumeratedValues>
                        </field>
                        <field>
                            <name>ODF</name>
                            <description>Output Disable Flag</description>
                            <lsb>24</lsb>
                            <msb>24</msb>
                            <access>read-only</access>
                            <enumeratedValues>
                                <enumeratedValue>
                                    <name>0</name>
                                    <description>No output disable request is generated</description>
                                    <value>#0</value>
                                </enumeratedValue>
                                <enumeratedValue>
                                    <name>1</name>
                                    <description>An output disable request is generated</description>
                                    <value>#1</value>
                                </enumeratedValue>
                            </enumeratedValues>
                        </field>
                        <field>
                            <name>OABHF</name>
                            <description>Same Time Output Level High Flag</description>
                            <lsb>29</lsb>
                            <msb>29</msb>
                            <access>read-only</access>
                            <enumeratedValues>
                                <enumeratedValue>
                                    <name>0</name>
                                    <description>No simultaneous generation of 1 both for the GTIOCA and GTIOCB pins has occurred.</description>
                                    <value>#0</value>
                                </enumeratedValue>
                                <enumeratedValue>
                                    <name>1</name>
                                    <description>A simultaneous generation of 1 both for the GTIOCA and GTIOCB pins has occurred.</description>
                                    <value>#1</value>
                                </enumeratedValue>
                            </enumeratedValues>
                        </field>
                        <field>
                            <name>OABLF</name>
                            <description>Same Time Output Level Low Flag</description>
                            <lsb>30</lsb>
                            <msb>30</msb>
                            <access>read-only</access>
                            <enumeratedValues>
                                <enumeratedValue>
                                    <name>0</name>
                                    <description>No simultaneous generation of 0 both for the GTIOCA and GTIOCB pins has occurred.</description>
                                    <value>#0</value>
                                </enumeratedValue>
                                <enumeratedValue>
                                    <name>1</name>
                                    <description>A simultaneous generation of 0 both for the GTIOCA and GTIOCB pins has occurred.</description>
                                    <value>#1</value>
                                </enumeratedValue>
                            </enumeratedValues>
                        </field>
                        <field>
                            <name>PCF</name>
                            <description>Period Count Function Finish Flag</description>
                            <lsb>31</lsb>
                            <msb>31</msb>
                            <access>read-write</access>
                            <enumeratedValues>
                                <enumeratedValue>
                                    <name>0</name>
                                    <description>No period count function finish has occurred</description>
                                    <value>#0</value>
                                </enumeratedValue>
                                <enumeratedValue>
                                    <name>1</name>
                                    <description>A period count function finish has occurred</description>
                                    <value>#1</value>
                                </enumeratedValue>
                            </enumeratedValues>
                        </field>
                    </fields>
                </register>
                <register>
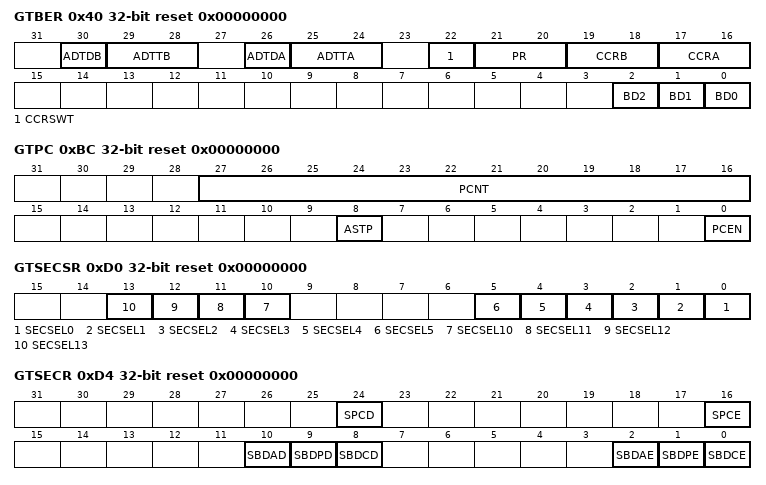
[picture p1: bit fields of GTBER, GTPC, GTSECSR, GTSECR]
                    <name>GTBER</name>
                    <description>General PWM Timer Buffer Enable Register</description>
                    <addressOffset>0x40</addressOffset>
                    <size>32</size>
                    <access>read-write</access>
                    <resetValue>0x00000000</resetValue>
                    <resetMask>0xffffffff</resetMask>
                    <fields>
                        <field>
                            <name>BD0</name>
                            <description>GTCCR Buffer Operation Disable</description>
                            <lsb>0</lsb>
                            <msb>0</msb>
                            <access>read-write</access>
                            <enumeratedValues>
                                <enumeratedValue>
                                    <name>0</name>
                                    <description>Buffer operation is enabled</description>
                                    <value>#0</value>
                                </enumeratedValue>
                                <enumeratedValue>
                                    <name>1</name>
                                    <description>Buffer operation is disabled</description>
                                    <value>#1</value>
                                </enumeratedValue>
                            </enumeratedValues>
                        </field>
                        <field>
                            <name>BD1</name>
                            <description>GTPR Buffer Operation Disable</description>
                            <lsb>1</lsb>
                            <msb>1</msb>
                            <access>read-write</access>
                            <enumeratedValues>
                                <enumeratedValue>
                                    <name>0</name>
                                    <description>Buffer operation is enabled</description>
                                    <value>#0</value>
                                </enumeratedValue>
                                <enumeratedValue>
                                    <name>1</name>
                                    <description>Buffer operation is disabled</description>
                                    <value>#1</value>
                                </enumeratedValue>
                            </enumeratedValues>
                        </field>
                        <field>
                            <name>BD2</name>
                            <description>GTADTRA/GTADTRB Registers Buffer Operation Disable</description>
                            <lsb>2</lsb>
                            <msb>2</msb>
                            <access>read-write</access>
                            <enumeratedValues>
                                <enumeratedValue>
                                    <name>0</name>
                                    <description>Buffer operation is enabled</description>
                                    <value>#0</value>
                                </enumeratedValue>
                                <enumeratedValue>
                                    <name>1</name>
                                    <description>Buffer operation is disabled</description>
                                    <value>#1</value>
                                </enumeratedValue>
                            </enumeratedValues>
                        </field>
                        <field>
                            <name>CCRA</name>
                            <description>GTCCRA Buffer Operation</description>
                            <lsb>16</lsb>
                            <msb>17</msb>
                            <access>read-write</access>
                            <enumeratedValues>
                                <enumeratedValue>
                                    <name>00</name>
                                    <description>No buffer operation</description>
                                    <value>#00</value>
                                </enumeratedValue>
                                <enumeratedValue>
                                    <name>01</name>
                                    <description>Single buffer operation (GTCCRA &lt;----&gt;GTCCRC)</description>
                                    <value>#01</value>
                                </enumeratedValue>
                                <enumeratedValue>
                                    <name>Others</name>
                                    <description>Double buffer operation (GTCCRA &lt;----&gt; GTCCRC &lt;----&gt; GTCCRD)</description>
                                    <isDefault>true</isDefault>
                                </enumeratedValue>
                            </enumeratedValues>
                        </field>
                        <field>
                            <name>CCRB</name>
                            <description>GTCCRB Buffer Operation</description>
                            <lsb>18</lsb>
                            <msb>19</msb>
                            <access>read-write</access>
                            <enumeratedValues>
                                <enumeratedValue>
                                    <name>00</name>
                                    <description>No buffer operation</description>
                                    <value>#00</value>
                                </enumeratedValue>
                                <enumeratedValue>
                                    <name>01</name>
                                    <description>Single buffer operation (GTCCRB &lt;----&gt; GTCCRE)</description>
                                    <value>#01</value>
                                </enumeratedValue>
                                <enumeratedValue>
                                    <name>Others</name>
                                    <description>Double buffer operation (GTCCRB &lt;----&gt; GTCCRE &lt;----&gt; GTCCRF)</description>
                                    <isDefault>true</isDefault>
                                </enumeratedValue>
                            </enumeratedValues>
                        </field>
                        <field>
                            <name>PR</name>
                            <description>GTPR Buffer Operation</description>
                            <lsb>20</lsb>
                            <msb>21</msb>
                            <access>read-write</access>
                            <enumeratedValues>
                                <enumeratedValue>
                                    <name>00</name>
                                    <description>No buffer operation</description>
                                    <value>#00</value>
                                </enumeratedValue>
                                <enumeratedValue>
                                    <name>01</name>
                                    <description>Single buffer operation (GTPBR --&gt; GTPR)</description>
                                    <value>#01</value>
                                </enumeratedValue>
                                <enumeratedValue>
                                    <name>Others</name>
                                    <description>Setting prohibited</description>
                                    <isDefault>true</isDefault>
                                </enumeratedValue>
                            </enumeratedValues>
                        </field>
                        <field>
                            <name>CCRSWT</name>
                            <description>GTCCRA and GTCCRB Forcible Buffer Operation</description>
                            <lsb>22</lsb>
                            <msb>22</msb>
                            <access>write-only</access>
                        </field>
                        <field>
                            <name>ADTTA</name>
                            <description>GTADTRA Register Buffer Transfer Timing Select</description>
                            <lsb>24</lsb>
                            <msb>25</msb>
                            <access>read-write</access>
                            <enumeratedValues>
                                <enumeratedValue>
                                    <name>00</name>
                                    <description>In triangle wave mode, no transfer. In saw-wave mode, no transfer. </description>
                                    <value>#00</value>
                                </enumeratedValue>
                                <enumeratedValue>
                                    <name>01</name>
                                    <description>In triangle wave mode, transfer at crest. In saw-wave mode, transfer at underflow (in down-counting), overflow (in up-counting), or counter clearing. </description>
                                    <value>#01</value>
                                </enumeratedValue>
                                <enumeratedValue>
                                    <name>10</name>
                                    <description>In triangle wave mode, transfer at trough. In saw-wave mode, transfer at underflow (in down-counting), overflow (in up-counting), or counter clearing. </description>
                                    <value>#10</value>
                                </enumeratedValue>
                                <enumeratedValue>
                                    <name>11</name>
                                    <description>In triangle wave, transfer at both crest and trough. In saw-wave mode, transfer at underflow (in down-counting), overflow (in up-counting), or counter clearing. </description>
                                    <value>#11</value>
                                </enumeratedValue>
                            </enumeratedValues>
                        </field>
                        <field>
                            <name>ADTDA</name>
                            <description>GTADTRA Register Double Buffer Operation</description>
                            <lsb>26</lsb>
                            <msb>26</msb>
                            <access>read-write</access>
                            <enumeratedValues>
                                <enumeratedValue>
                                    <name>0</name>
                                    <description>Single buffer operation (GTADTBRA --&gt; GTADTRA)</description>
                                    <value>#0</value>
                                </enumeratedValue>
                                <enumeratedValue>
                                    <name>1</name>
                                    <description>Double buffer operation (GTADTDBRA --&gt; GTADTBRA --&gt; GTADTRA)</description>
                                    <value>#1</value>
                                </enumeratedValue>
                            </enumeratedValues>
                        </field>
                        <field>
                            <name>ADTTB</name>
                            <description>GTADTRB Register Buffer Transfer Timing Select</description>
                            <lsb>28</lsb>
                            <msb>29</msb>
                            <access>read-write</access>
                            <enumeratedValues>
                                <enumeratedValue>
                                    <name>00</name>
                                    <description>In triangle wave mode, no transfer. In saw-wave mode, no transfer. </description>
                                    <value>#00</value>
                                </enumeratedValue>
                                <enumeratedValue>
                                    <name>01</name>
                                    <description>In triangle wave mode, transfer at crest. In saw-wave mode, transfer at underflow (in down-counting), overflow (in up-counting), or counter clearing. </description>
                                    <value>#01</value>
                                </enumeratedValue>
                                <enumeratedValue>
                                    <name>10</name>
                                    <description>In triangle wave mode, transfer at trough. In saw-wave mode, transfer at underflow (in down-counting), overflow (in up-counting), or counter clearing. </description>
                                    <value>#10</value>
                                </enumeratedValue>
                                <enumeratedValue>
                                    <name>11</name>
                                    <description>In triangle wave mode, transfer at both crest and trough. In saw-wave mode, transfer at underflow (in down-counting), overflow (in up-counting), or counter clearing. </description>
                                    <value>#11</value>
                                </enumeratedValue>
                            </enumeratedValues>
                        </field>
                        <field>
                            <name>ADTDB</name>
                            <description>GTADTRB Register Double Buffer Operation</description>
                            <lsb>30</lsb>
                            <msb>30</msb>
                            <access>read-write</access>
                            <enumeratedValues>
                                <enumeratedValue>
                                    <name>0</name>
                                    <description>Single buffer operation (GTADTBRB --&gt; GTADTRB)</description>
                                    <value>#0</value>
                                </enumeratedValue>
                                <enumeratedValue>
                                    <name>1</name>
                                    <description>Double buffer operation (GTADTDBRB --&gt; GTADTBRB --&gt; GTADTRB)</description>
                                    <value>#1</value>
                                </enumeratedValue>
                            </enumeratedValues>
                        </field>
                    </fields>
                </register>
                <register>
                    <name>GTCNT</name>
                    <description>General PWM Timer Counter</description>
                    <addressOffset>0x48</addressOffset>
                    <size>32</size>
                    <access>read-write</access>
                    <resetValue>0x00000000</resetValue>
                    <resetMask>0xffffffff</resetMask>
                </register>
                <register>
                    <name>GTCCRA</name>
                    <description>General PWM Timer Compare Capture Register A</description>
                    <addressOffset>0x4C</addressOffset>
                    <size>32</size>
                    <access>read-write</access>
                    <resetValue>0x0000ffff</resetValue>
                    <resetMask>0xffffffff</resetMask>
                </register>
                <register>
                    <name>GTCCRB</name>
                    <description>General PWM Timer Compare Capture Register B</description>
                    <addressOffset>0x50</addressOffset>
                    <size>32</size>
                    <access>read-write</access>
                    <resetValue>0x0000ffff</resetValue>
                    <resetMask>0xffffffff</resetMask>
                </register>
                <register>
                    <name>GTCCRC</name>
                    <description>General PWM Timer Compare Capture Register C</description>
                    <addressOffset>0x54</addressOffset>
                    <size>32</size>
                    <access>read-write</access>
                    <resetValue>0x0000ffff</resetValue>
                    <resetMask>0xffffffff</resetMask>
                </register>
                <register>
                    <name>GTCCRE</name>
                    <description>General PWM Timer Compare Capture Register E</description>
                    <addressOffset>0x58</addressOffset>
                    <size>32</size>
                    <access>read-write</access>
                    <resetValue>0x0000ffff</resetValue>
                    <resetMask>0xffffffff</resetMask>
                </register>
                <register>
                    <name>GTCCRD</name>
                    <description>General PWM Timer Compare Capture Register D</description>
                    <addressOffset>0x5C</addressOffset>
                    <size>32</size>
                    <access>read-write</access>
                    <resetValue>0x0000ffff</resetValue>
                    <resetMask>0xffffffff</resetMask>
                </register>
                <register>
                    <name>GTCCRF</name>
                    <description>General PWM Timer Compare Capture Register F</description>
                    <addressOffset>0x60</addressOffset>
                    <size>32</size>
                    <access>read-write</access>
                    <resetValue>0x0000ffff</resetValue>
                    <resetMask>0xffffffff</resetMask>
                </register>
                <register>
                    <name>GTPR</name>
                    <description>General PWM Timer Cycle Setting Register</description>
                    <addressOffset>0x64</addressOffset>
                    <size>32</size>
                    <access>read-write</access>
                    <resetValue>0x0000ffff</resetValue>
                    <resetMask>0xffffffff</resetMask>
                </register>
                <register>
                    <name>GTPBR</name>
                    <description>General PWM Timer Cycle Setting Buffer Register</description>
                    <addressOffset>0x68</addressOffset>
                    <size>32</size>
                    <access>read-write</access>
                    <resetValue>0x0000ffff</resetValue>
                    <resetMask>0xffffffff</resetMask>
                </register>
                <register>
                    <name>GTDTCR</name>
                    <description>General PWM Timer Dead Time Control Register</description>
                    <addressOffset>0x88</addressOffset>
                    <size>32</size>
                    <access>read-write</access>
                    <resetValue>0x00000000</resetValue>
                    <resetMask>0xffffffff</resetMask>
                    <fields>
                        <field>
                            <name>TDE</name>
                            <description>Negative-Phase Waveform Setting</description>
                            <lsb>0</lsb>
                            <msb>0</msb>
                            <access>read-write</access>
                            <enumeratedValues>
                                <enumeratedValue>
                                    <name>0</name>
                                    <description>GTCCRB is set without using GTDVU</description>
                                    <value>#0</value>
                                </enumeratedValue>
                                <enumeratedValue>
                                    <name>1</name>
                                    <description>GTDVU is used to set the compare match value for negative-phase waveform with dead time automatically in GTCCRB</description>
                                    <value>#1</value>
                                </enumeratedValue>
                            </enumeratedValues>
                        </field>
                    </fields>
                </register>
                <register>
                    <name>GTDVU</name>
                    <description>General PWM Timer Dead Time Value Register U</description>
                    <addressOffset>0x8C</addressOffset>
                    <size>32</size>
                    <access>read-write</access>
                    <resetValue>0x0000ffff</resetValue>
                    <resetMask>0xffffffff</resetMask>
                </register>
                <register>
                    <name>GTPC</name>
                    <description>General PWM Timer Period Count Register</description>
                    <addressOffset>0xBC</addressOffset>
                    <size>32</size>
                    <access>read-write</access>
                    <resetValue>0x00000000</resetValue>
                    <resetMask>0xffffffff</resetMask>
                    <fields>
                        <field>
                            <name>PCEN</name>
                            <description>Period Count Function Enable</description>
                            <lsb>0</lsb>
                            <msb>0</msb>
                            <access>read-write</access>
                            <enumeratedValues>
                                <enumeratedValue>
                                    <name>0</name>
                                    <description>Period count function is disabled</description>
                                    <value>#0</value>
                                </enumeratedValue>
                                <enumeratedValue>
                                    <name>1</name>
                                    <description>Period count function is enabled</description>
                                    <value>#1</value>
                                </enumeratedValue>
                            </enumeratedValues>
                        </field>
                        <field>
                            <name>ASTP</name>
                            <description>Automatic Stop Function Enable</description>
                            <lsb>8</lsb>
                            <msb>8</msb>
                            <access>read-write</access>
                            <enumeratedValues>
                                <enumeratedValue>
                                    <name>0</name>
                                    <description>Automatic stop function is disabled</description>
                                    <value>#0</value>
                                </enumeratedValue>
                                <enumeratedValue>
                                    <name>1</name>
                                    <description>Automatic stop function is enabled</description>
                                    <value>#1</value>
                                </enumeratedValue>
                            </enumeratedValues>
                        </field>
                        <field>
                            <name>PCNT</name>
                            <description>Period Counter</description>
                            <lsb>16</lsb>
                            <msb>27</msb>
                            <access>read-write</access>
                        </field>
                    </fields>
                </register>
                <register>
                    <name>GTSECSR</name>
                    <description>General PWM Timer Operation Enable Bit Simultaneous Control Channel Select Register</description>
                    <addressOffset>0xD0</addressOffset>
                    <size>32</size>
                    <access>read-write</access>
                    <resetValue>0x00000000</resetValue>
                    <resetMask>0xffffffff</resetMask>
                    <fields>
                        <field>
                            <name>SECSEL0</name>
                            <description>Channel 0 Operation Enable Bit Simultaneous Control Channel Select</description>
                            <lsb>0</lsb>
                            <msb>0</msb>
                            <access>read-write</access>
                            <enumeratedValues>
                                <enumeratedValue>
                                    <name>0</name>
                                    <description>Disable simultaneous control</description>
                                    <value>#0</value>
                                </enumeratedValue>
                                <enumeratedValue>
                                    <name>1</name>
                                    <description>Enable simultaneous control</description>
                                    <value>#1</value>
                                </enumeratedValue>
                            </enumeratedValues>
                        </field>
                        <field>
                            <name>SECSEL1</name>
                            <description>Channel 1 Operation Enable Bit Simultaneous Control Channel Select</description>
                            <lsb>1</lsb>
                            <msb>1</msb>
                            <access>read-write</access>
                            <enumeratedValues>
                                <enumeratedValue>
                                    <name>0</name>
                                    <description>Disable simultaneous control</description>
                                    <value>#0</value>
                                </enumeratedValue>
                                <enumeratedValue>
                                    <name>1</name>
                                    <description>Enable simultaneous control</description>
                                    <value>#1</value>
                                </enumeratedValue>
                            </enumeratedValues>
                        </field>
                        <field>
                            <name>SECSEL2</name>
                            <description>Channel 2 Operation Enable Bit Simultaneous Control Channel Select</description>
                            <lsb>2</lsb>
                            <msb>2</msb>
                            <access>read-write</access>
                            <enumeratedValues>
                                <enumeratedValue>
                                    <name>0</name>
                                    <description>Disable simultaneous control</description>
                                    <value>#0</value>
                                </enumeratedValue>
                                <enumeratedValue>
                                    <name>1</name>
                                    <description>Enable simultaneous control</description>
                                    <value>#1</value>
                                </enumeratedValue>
                            </enumeratedValues>
                        </field>
                        <field>
                            <name>SECSEL3</name>
                            <description>Channel 3 Operation Enable Bit Simultaneous Control Channel Select</description>
                            <lsb>3</lsb>
                            <msb>3</msb>
                            <access>read-write</access>
                            <enumeratedValues>
                                <enumeratedValue>
                                    <name>0</name>
                                    <description>Disable simultaneous control</description>
                                    <value>#0</value>
                                </enumeratedValue>
                                <enumeratedValue>
                                    <name>1</name>
                                    <description>Enable simultaneous control</description>
                                    <value>#1</value>
                                </enumeratedValue>
                            </enumeratedValues>
                        </field>
                        <field>
                            <name>SECSEL4</name>
                            <description>Channel 4 Operation Enable Bit Simultaneous Control Channel Select</description>
                            <lsb>4</lsb>
                            <msb>4</msb>
                            <access>read-write</access>
                            <enumeratedValues>
                                <enumeratedValue>
                                    <name>0</name>
                                    <description>Disable simultaneous control</description>
                                    <value>#0</value>
                                </enumeratedValue>
                                <enumeratedValue>
                                    <name>1</name>
                                    <description>Enable simultaneous control</description>
                                    <value>#1</value>
                                </enumeratedValue>
                            </enumeratedValues>
                        </field>
                        <field>
                            <name>SECSEL5</name>
                            <description>Channel 5 Operation Enable Bit Simultaneous Control Channel Select</description>
                            <lsb>5</lsb>
                            <msb>5</msb>
                            <access>read-write</access>
                            <enumeratedValues>
                                <enumeratedValue>
                                    <name>0</name>
                                    <description>Disable simultaneous control</description>
                                    <value>#0</value>
                                </enumeratedValue>
                                <enumeratedValue>
                                    <name>1</name>
                                    <description>Enable simultaneous control</description>
                                    <value>#1</value>
                                </enumeratedValue>
                            </enumeratedValues>
                        </field>
                        <field>
                            <name>SECSEL10</name>
                            <description>Channel 10 Operation Enable Bit Simultaneous Control Channel Select</description>
                            <lsb>10</lsb>
                            <msb>10</msb>
                            <access>read-write</access>
                            <enumeratedValues>
                                <enumeratedValue>
                                    <name>0</name>
                                    <description>Disable simultaneous control</description>
                                    <value>#0</value>
                                </enumeratedValue>
                                <enumeratedValue>
                                    <name>1</name>
                                    <description>Enable simultaneous control</description>
                                    <value>#1</value>
                                </enumeratedValue>
                            </enumeratedValues>
                        </field>
                        <field>
                            <name>SECSEL11</name>
                            <description>Channel 11 Operation Enable Bit Simultaneous Control Channel Select</description>
                            <lsb>11</lsb>
                            <msb>11</msb>
                            <access>read-write</access>
                            <enumeratedValues>
                                <enumeratedValue>
                                    <name>0</name>
                                    <description>Disable simultaneous control</description>
                                    <value>#0</value>
                                </enumeratedValue>
                                <enumeratedValue>
                                    <name>1</name>
                                    <description>Enable simultaneous control</description>
                                    <value>#1</value>
                                </enumeratedValue>
                            </enumeratedValues>
                        </field>
                        <field>
                            <name>SECSEL12</name>
                            <description>Channel 12 Operation Enable Bit Simultaneous Control Channel Select</description>
                            <lsb>12</lsb>
                            <msb>12</msb>
                            <access>read-write</access>
                            <enumeratedValues>
                                <enumeratedValue>
                                    <name>0</name>
                                    <description>Disable simultaneous control</description>
                                    <value>#0</value>
                                </enumeratedValue>
                                <enumeratedValue>
                                    <name>1</name>
                                    <description>Enable simultaneous control</description>
                                    <value>#1</value>
                                </enumeratedValue>
                            </enumeratedValues>
                        </field>
                        <field>
                            <name>SECSEL13</name>
                            <description>Channel 13 Operation Enable Bit Simultaneous Control Channel Select</description>
                            <lsb>13</lsb>
                            <msb>13</msb>
                            <access>read-write</access>
                            <enumeratedValues>
                                <enumeratedValue>
                                    <name>0</name>
                                    <description>Disable simultaneous control</description>
                                    <value>#0</value>
                                </enumeratedValue>
                                <enumeratedValue>
                                    <name>1</name>
                                    <description>Enable simultaneous control</description>
                                    <value>#1</value>
                                </enumeratedValue>
                            </enumeratedValues>
                        </field>
                    </fields>
                </register>
                <register>
                    <name>GTSECR</name>
                    <description>General PWM Timer Operation Enable Bit Simultaneous Control Register</description>
                    <addressOffset>0xD4</addressOffset>
                    <size>32</size>
                    <access>read-write</access>
                    <resetValue>0x00000000</resetValue>
                    <resetMask>0xffffffff</resetMask>
                    <fields>
                        <field>
                            <name>SBDCE</name>
                            <description>GTCCR Register Buffer Operation Simultaneous Enable</description>
                            <lsb>0</lsb>
                            <msb>0</msb>
                            <access>read-write</access>
                            <enumeratedValues>
                                <enumeratedValue>
                                    <name>0</name>
                                    <description>Disable simultaneous enabling GTCCR buffer operations</description>
                                    <value>#0</value>
                                </enumeratedValue>
                                <enumeratedValue>
                                    <name>1</name>
                                    <description>Enable GTCCR register buffer operations simultaneously</description>
                                    <value>#1</value>
                                </enumeratedValue>
                            </enumeratedValues>
                        </field>
                        <field>
                            <name>SBDPE</name>
                            <description>GTPR Register Buffer Operation Simultaneous Enable</description>
                            <lsb>1</lsb>
                            <msb>1</msb>
                            <access>read-write</access>
                            <enumeratedValues>
                                <enumeratedValue>
                                    <name>0</name>
                                    <description>Disable simultaneous enabling GTPR buffer operations</description>
                                    <value>#0</value>
                                </enumeratedValue>
                                <enumeratedValue>
                                    <name>1</name>
                                    <description>Enable GTPR register buffer operations simultaneously</description>
                                    <value>#1</value>
                                </enumeratedValue>
                            </enumeratedValues>
                        </field>
                        <field>
                            <name>SBDAE</name>
                            <description>GTADTR Register Buffer Operation Simultaneous Enable</description>
                            <lsb>2</lsb>
                            <msb>2</msb>
                            <access>read-write</access>
                            <enumeratedValues>
                                <enumeratedValue>
                                    <name>0</name>
                                    <description>Disable simultaneous enabling GTADTR buffer operations</description>
                                    <value>#0</value>
                                </enumeratedValue>
                                <enumeratedValue>
                                    <name>1</name>
                                    <description>Enable GTADTR register buffer operations simultaneously</description>
                                    <value>#1</value>
                                </enumeratedValue>
                            </enumeratedValues>
                        </field>
                        <field>
                            <name>SBDCD</name>
                            <description>GTCCR Register Buffer Operation Simultaneous Disable</description>
                            <lsb>8</lsb>
                            <msb>8</msb>
                            <access>read-write</access>
                            <enumeratedValues>
                                <enumeratedValue>
                                    <name>0</name>
                                    <description>Disable simultaneous disabling GTCCR buffer operations</description>
                                    <value>#0</value>
                                </enumeratedValue>
                                <enumeratedValue>
                                    <name>1</name>
                                    <description>Disable GTCCR register buffer operations simultaneously</description>
                                    <value>#1</value>
                                </enumeratedValue>
                            </enumeratedValues>
                        </field>
                        <field>
                            <name>SBDPD</name>
                            <description>GTPR Register Buffer Operation Simultaneous Disable</description>
                            <lsb>9</lsb>
                            <msb>9</msb>
                            <access>read-write</access>
                            <enumeratedValues>
                                <enumeratedValue>
                                    <name>0</name>
                                    <description>Disable simultaneous disabling GTPR buffer operations</description>
                                    <value>#0</value>
                                </enumeratedValue>
                                <enumeratedValue>
                                    <name>1</name>
                                    <description>Disable GTPR register buffer operations simultaneously</description>
                                    <value>#1</value>
                                </enumeratedValue>
                            </enumeratedValues>
                        </field>
                        <field>
                            <name>SBDAD</name>
                            <description>GTADTR Register Buffer Operation Simultaneous Disable</description>
                            <lsb>10</lsb>
                            <msb>10</msb>
                            <access>read-write</access>
                            <enumeratedValues>
                                <enumeratedValue>
                                    <name>0</name>
                                    <description>Disable simultaneous disabling GTADTR buffer operations</description>
                                    <value>#0</value>
                                </enumeratedValue>
                                <enumeratedValue>
                                    <name>1</name>
                                    <description>Disable GTADTR register buffer operations simultaneously</description>
                                    <value>#1</value>
                                </enumeratedValue>
                            </enumeratedValues>
                        </field>
                        <field>
                            <name>SPCE</name>
                            <description>Period Count Function Simultaneous Enable</description>
                            <lsb>16</lsb>
                            <msb>16</msb>
                            <access>read-write</access>
                            <enumeratedValues>
                                <enumeratedValue>
                                    <name>0</name>
                                    <description>Disable simultaneous enabling period count function</description>
                                    <value>#0</value>
                                </enumeratedValue>
                                <enumeratedValue>
                                    <name>1</name>
                                    <description>Enable period count function simultaneously</description>
                                    <value>#1</value>
                                </enumeratedValue>
                            </enumeratedValues>
                        </field>
                        <field>
                            <name>SPCD</name>
                            <description>Period Count Function Simultaneous Disable</description>
                            <lsb>24</lsb>
                            <msb>24</msb>
                            <access>read-write</access>
                            <enumeratedValues>
                                <enumeratedValue>
                                    <name>0</name>
                                    <description>Disable simultaneous disabling period count function</description>
                                    <value>#0</value>
                                </enumeratedValue>
                                <enumeratedValue>
                                    <name>1</name>
                                    <description>Disable period count function simultaneously</description>
                                    <value>#1</value>
                                </enumeratedValue>
                            </enumeratedValues>
                        </field>
                    </fields>
                </register>
            </registers>
        </peripheral>
        <peripheral derivedFrom="GPT1610_NS">
            <name>GPT1611_NS</name>
            <description>General PWM 16-bit Timer 11</description>
            <baseAddress>0x50322B00</baseAddress>
        </peripheral>
        <peripheral derivedFrom="GPT1610_NS">
            <name>GPT1612_NS</name>
            <description>General PWM 16-bit Timer 12</description>
            <baseAddress>0x50322C00</baseAddress>
        </peripheral>
        <peripheral derivedFrom="GPT1610_NS">
            <name>GPT1613_NS</name>
            <description>General PWM 16-bit Timer 13</description>
            <baseAddress>0x50322D00</baseAddress>
        </peripheral>
        <peripheral>
            <name>ADC120_NS</name>
            <description>12-bit A/D Converter 0</description>
            <baseAddress>0x50332000</baseAddress>
            <addressBlock>
                <offset>0x00</offset>
                <size>2</size>
                <usage>registers</usage>
            </addressBlock>
            <addressBlock>
                <offset>0x04</offset>
                <size>9</size>
                <usage>registers</usage>
            </addressBlock>
            <addressBlock>
                <offset>0x0E</offset>
                <size>36</size>
                <usage>registers</usage>
            </addressBlock>
            <addressBlock>
                <offset>0x66</offset>
                <size>2</size>
                <usage>registers</usage>
            </addressBlock>
            <addressBlock>
                <offset>0x7A</offset>
                <size>1</size>
                <usage>registers</usage>
            </addressBlock>
            <addressBlock>
                <offset>0x7C</offset>
                <size>1</size>
                <usage>registers</usage>
            </addressBlock>
            <addressBlock>
                <offset>0x80</offset>
                <size>2</size>
                <usage>registers</usage>
            </addressBlock>
            <addressBlock>
                <offset>0x84</offset>
                <size>4</size>
                <usage>registers</usage>
            </addressBlock>
            <addressBlock>
                <offset>0x8C</offset>
                <size>1</size>
                <usage>registers</usage>
            </addressBlock>
            <addressBlock>
                <offset>0x90</offset>
                <size>6</size>
                <usage>registers</usage>
            </addressBlock>
            <addressBlock>
                <offset>0x98</offset>
                <size>2</size>
                <usage>registers</usage>
            </addressBlock>
            <addressBlock>
                <offset>0x9C</offset>
                <size>6</size>
                <usage>registers</usage>
            </addressBlock>
            <addressBlock>
                <offset>0xA4</offset>
                <size>1</size>
                <usage>registers</usage>
            </addressBlock>
            <addressBlock>
                <offset>0xA6</offset>
                <size>1</size>
                <usage>registers</usage>
            </addressBlock>
            <addressBlock>
                <offset>0xA8</offset>
                <size>5</size>
                <usage>registers</usage>
            </addressBlock>
            <addressBlock>
                <offset>0xB0</offset>
                <size>33</size>
                <usage>registers</usage>
            </addressBlock>
            <addressBlock>
                <offset>0xD2</offset>
                <size>1</size>
                <usage>registers</usage>
            </addressBlock>
            <addressBlock>
                <offset>0xDD</offset>
                <size>12</size>
                <usage>registers</usage>
            </addressBlock>
            <addressBlock>
                <offset>0xEC</offset>
                <size>4</size>
                <usage>registers</usage>
            </addressBlock>
            <registers>
                <register>
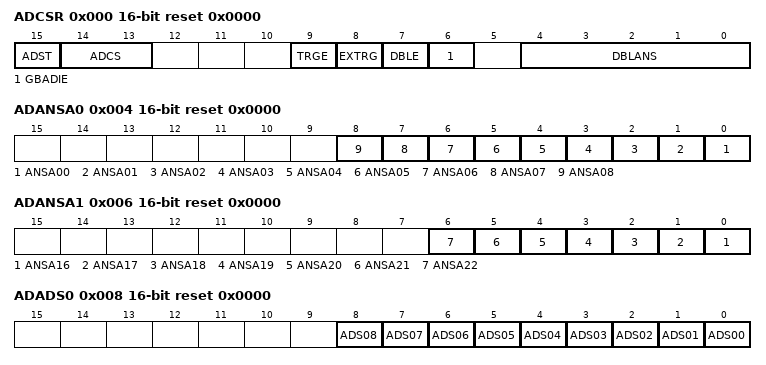
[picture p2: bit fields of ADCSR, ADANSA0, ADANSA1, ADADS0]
                    <name>ADCSR</name>
                    <description>A/D Control Register</description>
                    <addressOffset>0x000</addressOffset>
                    <size>16</size>
                    <access>read-write</access>
                    <resetValue>0x0000</resetValue>
                    <resetMask>0xffff</resetMask>
                    <fields>
                        <field>
                            <name>DBLANS</name>
                            <description>Double Trigger Channel Select</description>
                            <lsb>0</lsb>
                            <msb>4</msb>
                            <access>read-write</access>
                        </field>
                        <field>
                            <name>GBADIE</name>
                            <description>Group B Scan End Interrupt and ELC Event Enable</description>
                            <lsb>6</lsb>
                            <msb>6</msb>
                            <access>read-write</access>
                            <enumeratedValues>
                                <enumeratedValue>
                                    <name>0</name>
                                    <description>Disable ADC12i_GBADI (i = 0, 1) interrupt generation on group B scan completion.</description>
                                    <value>#0</value>
                                </enumeratedValue>
                                <enumeratedValue>
                                    <name>1</name>
                                    <description>Enable ADC12i_GBADI (i = 0, 1) interrupt generation on group B scan completion.</description>
                                    <value>#1</value>
                                </enumeratedValue>
                            </enumeratedValues>
                        </field>
                        <field>
                            <name>DBLE</name>
                            <description>Double Trigger Mode Select</description>
                            <lsb>7</lsb>
                            <msb>7</msb>
                            <access>read-write</access>
                            <enumeratedValues>
                                <enumeratedValue>
                                    <name>0</name>
                                    <description>Deselect double-trigger mode.</description>
                                    <value>#0</value>
                                </enumeratedValue>
                                <enumeratedValue>
                                    <name>1</name>
                                    <description>Select double-trigger mode.</description>
                                    <value>#1</value>
                                </enumeratedValue>
                            </enumeratedValues>
                        </field>
                        <field>
                            <name>EXTRG</name>
                            <description>Trigger Select</description>
                            <lsb>8</lsb>
                            <msb>8</msb>
                            <access>read-write</access>
                            <enumeratedValues>
                                <enumeratedValue>
                                    <name>0</name>
                                    <description>Start A/D conversion by the synchronous trigger (GPT, ELC).</description>
                                    <value>#0</value>
                                </enumeratedValue>
                                <enumeratedValue>
                                    <name>1</name>
                                    <description>Start A/D conversion by the asynchronous trigger (ADTRGn).</description>
                                    <value>#1</value>
                                </enumeratedValue>
                            </enumeratedValues>
                        </field>
                        <field>
                            <name>TRGE</name>
                            <description>Trigger Start Enable</description>
                            <lsb>9</lsb>
                            <msb>9</msb>
                            <access>read-write</access>
                            <enumeratedValues>
                                <enumeratedValue>
                                    <name>0</name>
                                    <description>Disable A/D conversion to be started by the synchronous or asynchronous trigger</description>
                                    <value>#0</value>
                                </enumeratedValue>
                                <enumeratedValue>
                                    <name>1</name>
                                    <description>Enable A/D conversion to be started by the synchronous or asynchronous trigger</description>
                                    <value>#1</value>
                                </enumeratedValue>
                            </enumeratedValues>
                        </field>
                        <field>
                            <name>ADCS</name>
                            <description>Scan Mode Select</description>
                            <lsb>13</lsb>
                            <msb>14</msb>
                            <access>read-write</access>
                            <enumeratedValues>
                                <enumeratedValue>
                                    <name>00</name>
                                    <description>Single scan mode</description>
                                    <value>#00</value>
                                </enumeratedValue>
                                <enumeratedValue>
                                    <name>01</name>
                                    <description>Group scan mode</description>
                                    <value>#01</value>
                                </enumeratedValue>
                                <enumeratedValue>
                                    <name>10</name>
                                    <description>Continuous scan mode</description>
                                    <value>#10</value>
                                </enumeratedValue>
                                <enumeratedValue>
                                    <name>11</name>
                                    <description>Setting prohibited</description>
                                    <value>#11</value>
                                </enumeratedValue>
                            </enumeratedValues>
                        </field>
                        <field>
                            <name>ADST</name>
                            <description>A/D Conversion Start</description>
                            <lsb>15</lsb>
                            <msb>15</msb>
                            <access>read-write</access>
                            <enumeratedValues>
                                <enumeratedValue>
                                    <name>0</name>
                                    <description>Stop A/D conversion process.</description>
                                    <value>#0</value>
                                </enumeratedValue>
                                <enumeratedValue>
                                    <name>1</name>
                                    <description>Start A/D conversion process.</description>
                                    <value>#1</value>
                                </enumeratedValue>
                            </enumeratedValues>
                        </field>
                    </fields>
                </register>
                <register>
                    <name>ADANSA0</name>
                    <description>A/D Channel Select Register A0</description>
                    <addressOffset>0x004</addressOffset>
                    <size>16</size>
                    <access>read-write</access>
                    <resetValue>0x0000</resetValue>
                    <resetMask>0xffff</resetMask>
                    <fields>
                        <field>
                            <name>ANSA00</name>
                            <description>A/D Conversion Channels Select</description>
                            <lsb>0</lsb>
                            <msb>0</msb>
                            <access>read-write</access>
                            <enumeratedValues>
                                <enumeratedValue>
                                    <name>0</name>
                                    <description>Do not select associated input channel.</description>
                                    <value>#0</value>
                                </enumeratedValue>
                                <enumeratedValue>
                                    <name>1</name>
                                    <description>Select associated input channel. </description>
                                    <value>#1</value>
                                </enumeratedValue>
                            </enumeratedValues>
                        </field>
                        <field>
                            <name>ANSA01</name>
                            <description>A/D Conversion Channels Select</description>
                            <lsb>1</lsb>
                            <msb>1</msb>
                            <access>read-write</access>
                            <enumeratedValues>
                                <enumeratedValue>
                                    <name>0</name>
                                    <description>Do not select associated input channel.</description>
                                    <value>#0</value>
                                </enumeratedValue>
                                <enumeratedValue>
                                    <name>1</name>
                                    <description>Select associated input channel. </description>
                                    <value>#1</value>
                                </enumeratedValue>
                            </enumeratedValues>
                        </field>
                        <field>
                            <name>ANSA02</name>
                            <description>A/D Conversion Channels Select</description>
                            <lsb>2</lsb>
                            <msb>2</msb>
                            <access>read-write</access>
                            <enumeratedValues>
                                <enumeratedValue>
                                    <name>0</name>
                                    <description>Do not select associated input channel.</description>
                                    <value>#0</value>
                                </enumeratedValue>
                                <enumeratedValue>
                                    <name>1</name>
                                    <description>Select associated input channel. </description>
                                    <value>#1</value>
                                </enumeratedValue>
                            </enumeratedValues>
                        </field>
                        <field>
                            <name>ANSA03</name>
                            <description>A/D Conversion Channels Select</description>
                            <lsb>3</lsb>
                            <msb>3</msb>
                            <access>read-write</access>
                            <enumeratedValues>
                                <enumeratedValue>
                                    <name>0</name>
                                    <description>Do not select associated input channel.</description>
                                    <value>#0</value>
                                </enumeratedValue>
                                <enumeratedValue>
                                    <name>1</name>
                                    <description>Select associated input channel. </description>
                                    <value>#1</value>
                                </enumeratedValue>
                            </enumeratedValues>
                        </field>
                        <field>
                            <name>ANSA04</name>
                            <description>A/D Conversion Channels Select</description>
                            <lsb>4</lsb>
                            <msb>4</msb>
                            <access>read-write</access>
                            <enumeratedValues>
                                <enumeratedValue>
                                    <name>0</name>
                                    <description>Do not select associated input channel.</description>
                                    <value>#0</value>
                                </enumeratedValue>
                                <enumeratedValue>
                                    <name>1</name>
                                    <description>Select associated input channel. </description>
                                    <value>#1</value>
                                </enumeratedValue>
                            </enumeratedValues>
                        </field>
                        <field>
                            <name>ANSA05</name>
                            <description>A/D Conversion Channels Select</description>
                            <lsb>5</lsb>
                            <msb>5</msb>
                            <access>read-write</access>
                            <enumeratedValues>
                                <enumeratedValue>
                                    <name>0</name>
                                    <description>Do not select associated input channel.</description>
                                    <value>#0</value>
                                </enumeratedValue>
                                <enumeratedValue>
                                    <name>1</name>
                                    <description>Select associated input channel. </description>
                                    <value>#1</value>
                                </enumeratedValue>
                            </enumeratedValues>
                        </field>
                        <field>
                            <name>ANSA06</name>
                            <description>A/D Conversion Channels Select</description>
                            <lsb>6</lsb>
                            <msb>6</msb>
                            <access>read-write</access>
                            <enumeratedValues>
                                <enumeratedValue>
                                    <name>0</name>
                                    <description>Do not select associated input channel.</description>
                                    <value>#0</value>
                                </enumeratedValue>
                                <enumeratedValue>
                                    <name>1</name>
                                    <description>Select associated input channel. </description>
                                    <value>#1</value>
                                </enumeratedValue>
                            </enumeratedValues>
                        </field>
                        <field>
                            <name>ANSA07</name>
                            <description>A/D Conversion Channels Select</description>
                            <lsb>7</lsb>
                            <msb>7</msb>
                            <access>read-write</access>
                            <enumeratedValues>
                                <enumeratedValue>
                                    <name>0</name>
                                    <description>Do not select associated input channel.</description>
                                    <value>#0</value>
                                </enumeratedValue>
                                <enumeratedValue>
                                    <name>1</name>
                                    <description>Select associated input channel. </description>
                                    <value>#1</value>
                                </enumeratedValue>
                            </enumeratedValues>
                        </field>
                        <field>
                            <name>ANSA08</name>
                            <description>A/D Conversion Channels Select</description>
                            <lsb>8</lsb>
                            <msb>8</msb>
                            <access>read-write</access>
                            <enumeratedValues>
                                <enumeratedValue>
                                    <name>0</name>
                                    <description>Do not select associated input channel.</description>
                                    <value>#0</value>
                                </enumeratedValue>
                                <enumeratedValue>
                                    <name>1</name>
                                    <description>Select associated input channel. </description>
                                    <value>#1</value>
                                </enumeratedValue>
                            </enumeratedValues>
                        </field>
                    </fields>
                </register>
                <register>
                    <name>ADANSA1</name>
                    <description>A/D Channel Select Register A1</description>
                    <addressOffset>0x006</addressOffset>
                    <size>16</size>
                    <access>read-write</access>
                    <resetValue>0x0000</resetValue>
                    <resetMask>0xffff</resetMask>
                    <fields>
                        <field>
                            <name>ANSA16</name>
                            <description>A/D Conversion Channels Select</description>
                            <lsb>0</lsb>
                            <msb>0</msb>
                            <access>read-write</access>
                            <enumeratedValues>
                                <enumeratedValue>
                                    <name>0</name>
                                    <description>Do not select associated input channel.</description>
                                    <value>#0</value>
                                </enumeratedValue>
                                <enumeratedValue>
                                    <name>1</name>
                                    <description>Select associated input channel. </description>
                                    <value>#1</value>
                                </enumeratedValue>
                            </enumeratedValues>
                        </field>
                        <field>
                            <name>ANSA17</name>
                            <description>A/D Conversion Channels Select</description>
                            <lsb>1</lsb>
                            <msb>1</msb>
                            <access>read-write</access>
                            <enumeratedValues>
                                <enumeratedValue>
                                    <name>0</name>
                                    <description>Do not select associated input channel.</description>
                                    <value>#0</value>
                                </enumeratedValue>
                                <enumeratedValue>
                                    <name>1</name>
                                    <description>Select associated input channel. </description>
                                    <value>#1</value>
                                </enumeratedValue>
                            </enumeratedValues>
                        </field>
                        <field>
                            <name>ANSA18</name>
                            <description>A/D Conversion Channels Select</description>
                            <lsb>2</lsb>
                            <msb>2</msb>
                            <access>read-write</access>
                            <enumeratedValues>
                                <enumeratedValue>
                                    <name>0</name>
                                    <description>Do not select associated input channel.</description>
                                    <value>#0</value>
                                </enumeratedValue>
                                <enumeratedValue>
                                    <name>1</name>
                                    <description>Select associated input channel. </description>
                                    <value>#1</value>
                                </enumeratedValue>
                            </enumeratedValues>
                        </field>
                        <field>
                            <name>ANSA19</name>
                            <description>A/D Conversion Channels Select</description>
                            <lsb>3</lsb>
                            <msb>3</msb>
                            <access>read-write</access>
                            <enumeratedValues>
                                <enumeratedValue>
                                    <name>0</name>
                                    <description>Do not select associated input channel.</description>
                                    <value>#0</value>
                                </enumeratedValue>
                                <enumeratedValue>
                                    <name>1</name>
                                    <description>Select associated input channel. </description>
                                    <value>#1</value>
                                </enumeratedValue>
                            </enumeratedValues>
                        </field>
                        <field>
                            <name>ANSA20</name>
                            <description>A/D Conversion Channels Select</description>
                            <lsb>4</lsb>
                            <msb>4</msb>
                            <access>read-write</access>
                            <enumeratedValues>
                                <enumeratedValue>
                                    <name>0</name>
                                    <description>Do not select associated input channel.</description>
                                    <value>#0</value>
                                </enumeratedValue>
                                <enumeratedValue>
                                    <name>1</name>
                                    <description>Select associated input channel. </description>
                                    <value>#1</value>
                                </enumeratedValue>
                            </enumeratedValues>
                        </field>
                        <field>
                            <name>ANSA21</name>
                            <description>A/D Conversion Channels Select</description>
                            <lsb>5</lsb>
                            <msb>5</msb>
                            <access>read-write</access>
                            <enumeratedValues>
                                <enumeratedValue>
                                    <name>0</name>
                                    <description>Do not select associated input channel.</description>
                                    <value>#0</value>
                                </enumeratedValue>
                                <enumeratedValue>
                                    <name>1</name>
                                    <description>Select associated input channel. </description>
                                    <value>#1</value>
                                </enumeratedValue>
                            </enumeratedValues>
                        </field>
                        <field>
                            <name>ANSA22</name>
                            <description>A/D Conversion Channels Select</description>
                            <lsb>6</lsb>
                            <msb>6</msb>
                            <access>read-write</access>
                            <enumeratedValues>
                                <enumeratedValue>
                                    <name>0</name>
                                    <description>Do not select associated input channel.</description>
                                    <value>#0</value>
                                </enumeratedValue>
                                <enumeratedValue>
                                    <name>1</name>
                                    <description>Select associated input channel. </description>
                                    <value>#1</value>
                                </enumeratedValue>
                            </enumeratedValues>
                        </field>
                    </fields>
                </register>
                <register>
                    <name>ADADS0</name>
                    <description>A/D-Converted Value Addition/Average Channel Select Register 0</description>
                    <addressOffset>0x008</addressOffset>
                    <size>16</size>
                    <access>read-write</access>
                    <resetValue>0x0000</resetValue>
                    <resetMask>0xffff</resetMask>
                    <fields>
                        <field>
                            <name>ADS00</name>
                            <description>A/D-Converted Value Addition/Average Channel Select</description>
                            <lsb>0</lsb>
                            <msb>0</msb>
                            <access>read-write</access>
                            <enumeratedValues>
                                <enumeratedValue>
                                    <name>0</name>
                                    <description>Do not select associated input channel.</description>
                                    <value>#0</value>
                                </enumeratedValue>
                                <enumeratedValue>
                                    <name>1</name>
                                    <description>Select associated input channel. </description>
                                    <value>#1</value>
                                </enumeratedValue>
                            </enumeratedValues>
                        </field>
                        <field>
                            <name>ADS01</name>
                            <description>A/D-Converted Value Addition/Average Channel Select</description>
                            <lsb>1</lsb>
                            <msb>1</msb>
                            <access>read-write</access>
                            <enumeratedValues>
                                <enumeratedValue>
                                    <name>0</name>
                                    <description>Do not select associated input channel.</description>
                                    <value>#0</value>
                                </enumeratedValue>
                                <enumeratedValue>
                                    <name>1</name>
                                    <description>Select associated input channel. </description>
                                    <value>#1</value>
                                </enumeratedValue>
                            </enumeratedValues>
                        </field>
                        <field>
                            <name>ADS02</name>
                            <description>A/D-Converted Value Addition/Average Channel Select</description>
                            <lsb>2</lsb>
                            <msb>2</msb>
                            <access>read-write</access>
                            <enumeratedValues>
                                <enumeratedValue>
                                    <name>0</name>
                                    <description>Do not select associated input channel.</description>
                                    <value>#0</value>
                                </enumeratedValue>
                                <enumeratedValue>
                                    <name>1</name>
                                    <description>Select associated input channel. </description>
                                    <value>#1</value>
                                </enumeratedValue>
                            </enumeratedValues>
                        </field>
                        <field>
                            <name>ADS03</name>
                            <description>A/D-Converted Value Addition/Average Channel Select</description>
                            <lsb>3</lsb>
                            <msb>3</msb>
                            <access>read-write</access>
                            <enumeratedValues>
                                <enumeratedValue>
                                    <name>0</name>
                                    <description>Do not select associated input channel.</description>
                                    <value>#0</value>
                                </enumeratedValue>
                                <enumeratedValue>
                                    <name>1</name>
                                    <description>Select associated input channel. </description>
                                    <value>#1</value>
                                </enumeratedValue>
                            </enumeratedValues>
                        </field>
                        <field>
                            <name>ADS04</name>
                            <description>A/D-Converted Value Addition/Average Channel Select</description>
                            <lsb>4</lsb>
                            <msb>4</msb>
                            <access>read-write</access>
                            <enumeratedValues>
                                <enumeratedValue>
                                    <name>0</name>
                                    <description>Do not select associated input channel.</description>
                                    <value>#0</value>
                                </enumeratedValue>
                                <enumeratedValue>
                                    <name>1</name>
                                    <description>Select associated input channel. </description>
                                    <value>#1</value>
                                </enumeratedValue>
                            </enumeratedValues>
                        </field>
                        <field>
                            <name>ADS05</name>
                            <description>A/D-Converted Value Addition/Average Channel Select</description>
                            <lsb>5</lsb>
                            <msb>5</msb>
                            <access>read-write</access>
                            <enumeratedValues>
                                <enumeratedValue>
                                    <name>0</name>
                                    <description>Do not select associated input channel.</description>
                                    <value>#0</value>
                                </enumeratedValue>
                                <enumeratedValue>
                                    <name>1</name>
                                    <description>Select associated input channel. </description>
                                    <value>#1</value>
                                </enumeratedValue>
                            </enumeratedValues>
                        </field>
                        <field>
                            <name>ADS06</name>
                            <description>A/D-Converted Value Addition/Average Channel Select</description>
                            <lsb>6</lsb>
                            <msb>6</msb>
                            <access>read-write</access>
                            <enumeratedValues>
                                <enumeratedValue>
                                    <name>0</name>
                                    <description>Do not select associated input channel.</description>
                                    <value>#0</value>
                                </enumeratedValue>
                                <enumeratedValue>
                                    <name>1</name>
                                    <description>Select associated input channel. </description>
                                    <value>#1</value>
                                </enumeratedValue>
                            </enumeratedValues>
                        </field>
                        <field>
                            <name>ADS07</name>
                            <description>A/D-Converted Value Addition/Average Channel Select</description>
                            <lsb>7</lsb>
                            <msb>7</msb>
                            <access>read-write</access>
                            <enumeratedValues>
                                <enumeratedValue>
                                    <name>0</name>
                                    <description>Do not select associated input channel.</description>
                                    <value>#0</value>
                                </enumeratedValue>
                                <enumeratedValue>
                                    <name>1</name>
                                    <description>Select associated input channel. </description>
                                    <value>#1</value>
                                </enumeratedValue>
                            </enumeratedValues>
                        </field>
                        <field>
                            <name>ADS08</name>
                            <description>A/D-Converted Value Addition/Average Channel Select</description>
                            <lsb>8</lsb>
                            <msb>8</msb>
                            <access>read-write</access>
                            <enumeratedValues>
                                <enumeratedValue>
                                    <name>0</name>
                                    <description>Do not select associated input channel.</description>
                                    <value>#0</value>
                                </enumeratedValue>
                                <enumeratedValue>
                                    <name>1</name>
                                    <description>Select associated input channel. </description>
                                    <value>#1</value>
                                </enumeratedValue>
                            </enumeratedValues>
                        </field>
                    </fields>
                </register>
                <register>
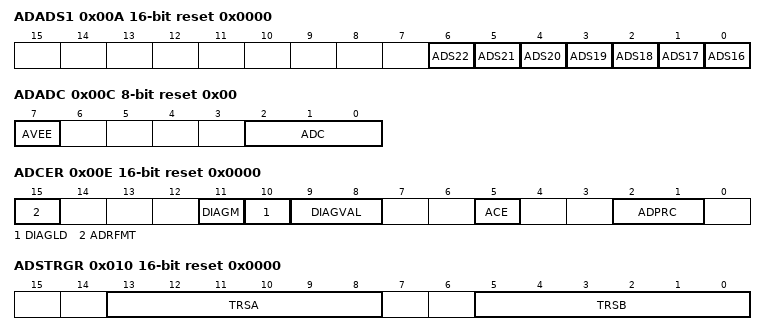
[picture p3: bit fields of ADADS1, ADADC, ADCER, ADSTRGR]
                    <name>ADADS1</name>
                    <description>A/D-Converted Value Addition/Average Channel Select Register 1</description>
                    <addressOffset>0x00A</addressOffset>
                    <size>16</size>
                    <access>read-write</access>
                    <resetValue>0x0000</resetValue>
                    <resetMask>0xffff</resetMask>
                    <fields>
                        <field>
                            <name>ADS16</name>
                            <description>A/D Conversion Channels Select/Average Channel Select</description>
                            <lsb>0</lsb>
                            <msb>0</msb>
                            <access>read-write</access>
                            <enumeratedValues>
                                <enumeratedValue>
                                    <name>0</name>
                                    <description>Do not select associated input channel.</description>
                                    <value>#0</value>
                                </enumeratedValue>
                                <enumeratedValue>
                                    <name>1</name>
                                    <description>Select associated input channel. </description>
                                    <value>#1</value>
                                </enumeratedValue>
                            </enumeratedValues>
                        </field>
                        <field>
                            <name>ADS17</name>
                            <description>A/D Conversion Channels Select/Average Channel Select</description>
                            <lsb>1</lsb>
                            <msb>1</msb>
                            <access>read-write</access>
                            <enumeratedValues>
                                <enumeratedValue>
                                    <name>0</name>
                                    <description>Do not select associated input channel.</description>
                                    <value>#0</value>
                                </enumeratedValue>
                                <enumeratedValue>
                                    <name>1</name>
                                    <description>Select associated input channel. </description>
                                    <value>#1</value>
                                </enumeratedValue>
                            </enumeratedValues>
                        </field>
                        <field>
                            <name>ADS18</name>
                            <description>A/D Conversion Channels Select/Average Channel Select</description>
                            <lsb>2</lsb>
                            <msb>2</msb>
                            <access>read-write</access>
                            <enumeratedValues>
                                <enumeratedValue>
                                    <name>0</name>
                                    <description>Do not select associated input channel.</description>
                                    <value>#0</value>
                                </enumeratedValue>
                                <enumeratedValue>
                                    <name>1</name>
                                    <description>Select associated input channel. </description>
                                    <value>#1</value>
                                </enumeratedValue>
                            </enumeratedValues>
                        </field>
                        <field>
                            <name>ADS19</name>
                            <description>A/D Conversion Channels Select/Average Channel Select</description>
                            <lsb>3</lsb>
                            <msb>3</msb>
                            <access>read-write</access>
                            <enumeratedValues>
                                <enumeratedValue>
                                    <name>0</name>
                                    <description>Do not select associated input channel.</description>
                                    <value>#0</value>
                                </enumeratedValue>
                                <enumeratedValue>
                                    <name>1</name>
                                    <description>Select associated input channel. </description>
                                    <value>#1</value>
                                </enumeratedValue>
                            </enumeratedValues>
                        </field>
                        <field>
                            <name>ADS20</name>
                            <description>A/D Conversion Channels Select/Average Channel Select</description>
                            <lsb>4</lsb>
                            <msb>4</msb>
                            <access>read-write</access>
                            <enumeratedValues>
                                <enumeratedValue>
                                    <name>0</name>
                                    <description>Do not select associated input channel.</description>
                                    <value>#0</value>
                                </enumeratedValue>
                                <enumeratedValue>
                                    <name>1</name>
                                    <description>Select associated input channel. </description>
                                    <value>#1</value>
                                </enumeratedValue>
                            </enumeratedValues>
                        </field>
                        <field>
                            <name>ADS21</name>
                            <description>A/D Conversion Channels Select/Average Channel Select</description>
                            <lsb>5</lsb>
                            <msb>5</msb>
                            <access>read-write</access>
                            <enumeratedValues>
                                <enumeratedValue>
                                    <name>0</name>
                                    <description>Do not select associated input channel.</description>
                                    <value>#0</value>
                                </enumeratedValue>
                                <enumeratedValue>
                                    <name>1</name>
                                    <description>Select associated input channel. </description>
                                    <value>#1</value>
                                </enumeratedValue>
                            </enumeratedValues>
                        </field>
                        <field>
                            <name>ADS22</name>
                            <description>A/D Conversion Channels Select/Average Channel Select</description>
                            <lsb>6</lsb>
                            <msb>6</msb>
                            <access>read-write</access>
                            <enumeratedValues>
                                <enumeratedValue>
                                    <name>0</name>
                                    <description>Do not select associated input channel.</description>
                                    <value>#0</value>
                                </enumeratedValue>
                                <enumeratedValue>
                                    <name>1</name>
                                    <description>Select associated input channel. </description>
                                    <value>#1</value>
                                </enumeratedValue>
                            </enumeratedValues>
                        </field>
                    </fields>
                </register>
                <register>
                    <name>ADADC</name>
                    <description>A/D-Converted Value Addition/Average Count Select Register</description>
                    <addressOffset>0x00C</addressOffset>
                    <size>8</size>
                    <access>read-write</access>
                    <resetValue>0x00</resetValue>
                    <resetMask>0xff</resetMask>
                    <fields>
                        <field>
                            <name>ADC</name>
                            <description>Addition/Average Count Select</description>
                            <lsb>0</lsb>
                            <msb>2</msb>
                            <access>read-write</access>
                            <enumeratedValues>
                                <enumeratedValue>
                                    <name>000</name>
                                    <description>1-time conversion (no addition, same as normal conversion)</description>
                                    <value>#000</value>
                                </enumeratedValue>
                                <enumeratedValue>
                                    <name>001</name>
                                    <description>2-time conversion (1 addition)</description>
                                    <value>#001</value>
                                </enumeratedValue>
                                <enumeratedValue>
                                    <name>010</name>
                                    <description>3-time conversion (2 additions)</description>
                                    <value>#010</value>
                                </enumeratedValue>
                                <enumeratedValue>
                                    <name>011</name>
                                    <description>4-time conversion (3 additions)</description>
                                    <value>#011</value>
                                </enumeratedValue>
                                <enumeratedValue>
                                    <name>101</name>
                                    <description>16-time conversion (15 additions)</description>
                                    <value>#101</value>
                                </enumeratedValue>
                                <enumeratedValue>
                                    <name>Others</name>
                                    <description>Setting prohibited</description>
                                    <isDefault>true</isDefault>
                                </enumeratedValue>
                            </enumeratedValues>
                        </field>
                        <field>
                            <name>AVEE</name>
                            <description>Average Mode Select</description>
                            <lsb>7</lsb>
                            <msb>7</msb>
                            <access>read-write</access>
                            <enumeratedValues>
                                <enumeratedValue>
                                    <name>0</name>
                                    <description>Enable addition mode</description>
                                    <value>#0</value>
                                </enumeratedValue>
                                <enumeratedValue>
                                    <name>1</name>
                                    <description>Enable average mode</description>
                                    <value>#1</value>
                                </enumeratedValue>
                            </enumeratedValues>
                        </field>
                    </fields>
                </register>
                <register>
                    <name>ADCER</name>
                    <description>A/D Control Extended Register</description>
                    <addressOffset>0x00E</addressOffset>
                    <size>16</size>
                    <access>read-write</access>
                    <resetValue>0x0000</resetValue>
                    <resetMask>0xffff</resetMask>
                    <fields>
                        <field>
                            <name>ADPRC</name>
                            <lsb>1</lsb>
                            <msb>2</msb>
                            <access>read-write</access>
                            <enumeratedValues>
                                <enumeratedValue>
                                    <name>00</name>
                                    <description>12-bit accuracy</description>
                                    <value>#00</value>
                                </enumeratedValue>
                                <enumeratedValue>
                                    <name>01</name>
                                    <description>10-bit accuracy</description>
                                    <value>#01</value>
                                </enumeratedValue>
                                <enumeratedValue>
                                    <name>10</name>
                                    <description>8-bit accuracy</description>
                                    <value>#10</value>
                                </enumeratedValue>
                                <enumeratedValue>
                                    <name>11</name>
                                    <description>Setting prohibited</description>
                                    <value>#11</value>
                                </enumeratedValue>
                            </enumeratedValues>
                        </field>
                        <field>
                            <name>ACE</name>
                            <description>A/D Data Register Automatic Clearing Enable</description>
                            <lsb>5</lsb>
                            <msb>5</msb>
                            <access>read-write</access>
                            <enumeratedValues>
                                <enumeratedValue>
                                    <name>0</name>
                                    <description>Disable automatic clearing</description>
                                    <value>#0</value>
                                </enumeratedValue>
                                <enumeratedValue>
                                    <name>1</name>
                                    <description>Enable automatic clearing</description>
                                    <value>#1</value>
                                </enumeratedValue>
                            </enumeratedValues>
                        </field>
                        <field>
                            <name>DIAGVAL</name>
                            <description>Self-Diagnosis Conversion Voltage Select</description>
                            <lsb>8</lsb>
                            <msb>9</msb>
                            <access>read-write</access>
                            <enumeratedValues>
                                <enumeratedValue>
                                    <name>00</name>
                                    <description>Setting prohibited when self-diagnosis is enabled</description>
                                    <value>#00</value>
                                </enumeratedValue>
                                <enumeratedValue>
                                    <name>01</name>
                                    <description>0 volts</description>
                                    <value>#01</value>
                                </enumeratedValue>
                                <enumeratedValue>
                                    <name>10</name>
                                    <description>Reference voltage × 1/2</description>
                                    <value>#10</value>
                                </enumeratedValue>
                                <enumeratedValue>
                                    <name>11</name>
                                    <description>Reference voltage</description>
                                    <value>#11</value>
                                </enumeratedValue>
                            </enumeratedValues>
                        </field>
                        <field>
                            <name>DIAGLD</name>
                            <description>Self-Diagnosis Mode Select</description>
                            <lsb>10</lsb>
                            <msb>10</msb>
                            <access>read-write</access>
                            <enumeratedValues>
                                <enumeratedValue>
                                    <name>0</name>
                                    <description>Select rotation mode for self-diagnosis voltage</description>
                                    <value>#0</value>
                                </enumeratedValue>
                                <enumeratedValue>
                                    <name>1</name>
                                    <description>Select mixed mode for self-diagnosis voltage</description>
                                    <value>#1</value>
                                </enumeratedValue>
                            </enumeratedValues>
                        </field>
                        <field>
                            <name>DIAGM</name>
                            <description>Self-Diagnosis Enable</description>
                            <lsb>11</lsb>
                            <msb>11</msb>
                            <access>read-write</access>
                            <enumeratedValues>
                                <enumeratedValue>
                                    <name>0</name>
                                    <description>Disable ADC12 self-diagnosis</description>
                                    <value>#0</value>
                                </enumeratedValue>
                                <enumeratedValue>
                                    <name>1</name>
                                    <description>Enable ADC12 self-diagnosis</description>
                                    <value>#1</value>
                                </enumeratedValue>
                            </enumeratedValues>
                        </field>
                        <field>
                            <name>ADRFMT</name>
                            <description>A/D Data Register Format Select</description>
                            <lsb>15</lsb>
                            <msb>15</msb>
                            <access>read-write</access>
                            <enumeratedValues>
                                <enumeratedValue>
                                    <name>0</name>
                                    <description>Select right-justified for the A/D data register format</description>
                                    <value>#0</value>
                                </enumeratedValue>
                                <enumeratedValue>
                                    <name>1</name>
                                    <description>Select left-justified for the A/D data register format</description>
                                    <value>#1</value>
                                </enumeratedValue>
                            </enumeratedValues>
                        </field>
                    </fields>
                </register>
                <register>
                    <name>ADSTRGR</name>
                    <description>A/D Conversion Start Trigger Select Register</description>
                    <addressOffset>0x010</addressOffset>
                    <size>16</size>
                    <access>read-write</access>
                    <resetValue>0x0000</resetValue>
                    <resetMask>0xffff</resetMask>
                    <fields>
                        <field>
                            <name>TRSB</name>
                            <description>A/D Conversion Start Trigger Select for Group B</description>
                            <lsb>0</lsb>
                            <msb>5</msb>
                            <access>read-write</access>
                        </field>
                        <field>
                            <name>TRSA</name>
                            <description>A/D Conversion Start Trigger Select</description>
                            <lsb>8</lsb>
                            <msb>13</msb>
                            <access>read-write</access>
                        </field>
                    </fields>
                </register>
                <register>
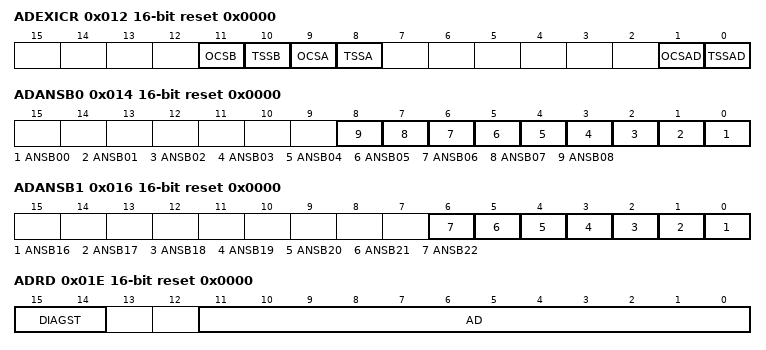
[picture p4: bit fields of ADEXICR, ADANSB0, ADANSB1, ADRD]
                    <name>ADEXICR</name>
                    <description>A/D Conversion Extended Input Control Registers</description>
                    <addressOffset>0x012</addressOffset>
                    <size>16</size>
                    <access>read-write</access>
                    <resetValue>0x0000</resetValue>
                    <resetMask>0xffff</resetMask>
                    <fields>
                        <field>
                            <name>TSSAD</name>
                            <description>Temperature Sensor Output A/D-Converted Value Addition/Average Mode Select</description>
                            <lsb>0</lsb>
                            <msb>0</msb>
                            <access>read-write</access>
                            <enumeratedValues>
                                <enumeratedValue>
                                    <name>0</name>
                                    <description>Do not select addition/average mode for temperature sensor output.</description>
                                    <value>#0</value>
                                </enumeratedValue>
                                <enumeratedValue>
                                    <name>1</name>
                                    <description>Select addition/average mode for temperature sensor output.</description>
                                    <value>#1</value>
                                </enumeratedValue>
                            </enumeratedValues>
                        </field>
                        <field>
                            <name>OCSAD</name>
                            <description>Internal Reference Voltage A/D-Converted Value Addition/Average Mode Select</description>
                            <lsb>1</lsb>
                            <msb>1</msb>
                            <access>read-write</access>
                            <enumeratedValues>
                                <enumeratedValue>
                                    <name>0</name>
                                    <description>Do not select addition/average mode for internal reference voltage.</description>
                                    <value>#0</value>
                                </enumeratedValue>
                                <enumeratedValue>
                                    <name>1</name>
                                    <description>Select addition/average mode for internal reference voltage.</description>
                                    <value>#1</value>
                                </enumeratedValue>
                            </enumeratedValues>
                        </field>
                        <field>
                            <name>TSSA</name>
                            <description>Temperature Sensor Output A/D Conversion Select</description>
                            <lsb>8</lsb>
                            <msb>8</msb>
                            <access>read-write</access>
                            <enumeratedValues>
                                <enumeratedValue>
                                    <name>0</name>
                                    <description>Disable A/D conversion of temperature sensor output</description>
                                    <value>#0</value>
                                </enumeratedValue>
                                <enumeratedValue>
                                    <name>1</name>
                                    <description>Enable A/D conversion of temperature sensor output</description>
                                    <value>#1</value>
                                </enumeratedValue>
                            </enumeratedValues>
                        </field>
                        <field>
                            <name>OCSA</name>
                            <description>Internal Reference Voltage A/D Conversion Select</description>
                            <lsb>9</lsb>
                            <msb>9</msb>
                            <access>read-write</access>
                            <enumeratedValues>
                                <enumeratedValue>
                                    <name>0</name>
                                    <description>Disable A/D conversion of internal reference voltage</description>
                                    <value>#0</value>
                                </enumeratedValue>
                                <enumeratedValue>
                                    <name>1</name>
                                    <description>Enable A/D conversion of internal reference voltage</description>
                                    <value>#1</value>
                                </enumeratedValue>
                            </enumeratedValues>
                        </field>
                        <field>
                            <name>TSSB</name>
                            <description>Temperature Sensor Output A/D Conversion Select for Group B</description>
                            <lsb>10</lsb>
                            <msb>10</msb>
                            <access>read-write</access>
                            <enumeratedValues>
                                <enumeratedValue>
                                    <name>0</name>
                                    <description>Disable A/D conversion of temperature sensor output</description>
                                    <value>#0</value>
                                </enumeratedValue>
                                <enumeratedValue>
                                    <name>1</name>
                                    <description>Enable A/D conversion of temperature sensor output</description>
                                    <value>#1</value>
                                </enumeratedValue>
                            </enumeratedValues>
                        </field>
                        <field>
                            <name>OCSB</name>
                            <description>Internal Reference Voltage A/D Conversion Select for Group B</description>
                            <lsb>11</lsb>
                            <msb>11</msb>
                            <access>read-write</access>
                            <enumeratedValues>
                                <enumeratedValue>
                                    <name>0</name>
                                    <description>Disable A/D conversion of internal reference voltage</description>
                                    <value>#0</value>
                                </enumeratedValue>
                                <enumeratedValue>
                                    <name>1</name>
                                    <description>Enable A/D conversion of internal reference voltage</description>
                                    <value>#1</value>
                                </enumeratedValue>
                            </enumeratedValues>
                        </field>
                    </fields>
                </register>
                <register>
                    <name>ADANSB0</name>
                    <description>A/D Channel Select Register B0</description>
                    <addressOffset>0x014</addressOffset>
                    <size>16</size>
                    <access>read-write</access>
                    <resetValue>0x0000</resetValue>
                    <resetMask>0xffff</resetMask>
                    <fields>
                        <field>
                            <name>ANSB00</name>
                            <description>A/D Conversion Channels Select</description>
                            <lsb>0</lsb>
                            <msb>0</msb>
                            <access>read-write</access>
                            <enumeratedValues>
                                <enumeratedValue>
                                    <name>0</name>
                                    <description>Do not select associated input channel.</description>
                                    <value>#0</value>
                                </enumeratedValue>
                                <enumeratedValue>
                                    <name>1</name>
                                    <description>Select associated input channel. </description>
                                    <value>#1</value>
                                </enumeratedValue>
                            </enumeratedValues>
                        </field>
                        <field>
                            <name>ANSB01</name>
                            <description>A/D Conversion Channels Select</description>
                            <lsb>1</lsb>
                            <msb>1</msb>
                            <access>read-write</access>
                            <enumeratedValues>
                                <enumeratedValue>
                                    <name>0</name>
                                    <description>Do not select associated input channel.</description>
                                    <value>#0</value>
                                </enumeratedValue>
                                <enumeratedValue>
                                    <name>1</name>
                                    <description>Select associated input channel. </description>
                                    <value>#1</value>
                                </enumeratedValue>
                            </enumeratedValues>
                        </field>
                        <field>
                            <name>ANSB02</name>
                            <description>A/D Conversion Channels Select</description>
                            <lsb>2</lsb>
                            <msb>2</msb>
                            <access>read-write</access>
                            <enumeratedValues>
                                <enumeratedValue>
                                    <name>0</name>
                                    <description>Do not select associated input channel.</description>
                                    <value>#0</value>
                                </enumeratedValue>
                                <enumeratedValue>
                                    <name>1</name>
                                    <description>Select associated input channel. </description>
                                    <value>#1</value>
                                </enumeratedValue>
                            </enumeratedValues>
                        </field>
                        <field>
                            <name>ANSB03</name>
                            <description>A/D Conversion Channels Select</description>
                            <lsb>3</lsb>
                            <msb>3</msb>
                            <access>read-write</access>
                            <enumeratedValues>
                                <enumeratedValue>
                                    <name>0</name>
                                    <description>Do not select associated input channel.</description>
                                    <value>#0</value>
                                </enumeratedValue>
                                <enumeratedValue>
                                    <name>1</name>
                                    <description>Select associated input channel. </description>
                                    <value>#1</value>
                                </enumeratedValue>
                            </enumeratedValues>
                        </field>
                        <field>
                            <name>ANSB04</name>
                            <description>A/D Conversion Channels Select</description>
                            <lsb>4</lsb>
                            <msb>4</msb>
                            <access>read-write</access>
                            <enumeratedValues>
                                <enumeratedValue>
                                    <name>0</name>
                                    <description>Do not select associated input channel.</description>
                                    <value>#0</value>
                                </enumeratedValue>
                                <enumeratedValue>
                                    <name>1</name>
                                    <description>Select associated input channel. </description>
                                    <value>#1</value>
                                </enumeratedValue>
                            </enumeratedValues>
                        </field>
                        <field>
                            <name>ANSB05</name>
                            <description>A/D Conversion Channels Select</description>
                            <lsb>5</lsb>
                            <msb>5</msb>
                            <access>read-write</access>
                            <enumeratedValues>
                                <enumeratedValue>
                                    <name>0</name>
                                    <description>Do not select associated input channel.</description>
                                    <value>#0</value>
                                </enumeratedValue>
                                <enumeratedValue>
                                    <name>1</name>
                                    <description>Select associated input channel. </description>
                                    <value>#1</value>
                                </enumeratedValue>
                            </enumeratedValues>
                        </field>
                        <field>
                            <name>ANSB06</name>
                            <description>A/D Conversion Channels Select</description>
                            <lsb>6</lsb>
                            <msb>6</msb>
                            <access>read-write</access>
                            <enumeratedValues>
                                <enumeratedValue>
                                    <name>0</name>
                                    <description>Do not select associated input channel.</description>
                                    <value>#0</value>
                                </enumeratedValue>
                                <enumeratedValue>
                                    <name>1</name>
                                    <description>Select associated input channel. </description>
                                    <value>#1</value>
                                </enumeratedValue>
                            </enumeratedValues>
                        </field>
                        <field>
                            <name>ANSB07</name>
                            <description>A/D Conversion Channels Select</description>
                            <lsb>7</lsb>
                            <msb>7</msb>
                            <access>read-write</access>
                            <enumeratedValues>
                                <enumeratedValue>
                                    <name>0</name>
                                    <description>Do not select associated input channel.</description>
                                    <value>#0</value>
                                </enumeratedValue>
                                <enumeratedValue>
                                    <name>1</name>
                                    <description>Select associated input channel. </description>
                                    <value>#1</value>
                                </enumeratedValue>
                            </enumeratedValues>
                        </field>
                        <field>
                            <name>ANSB08</name>
                            <description>A/D Conversion Channels Select</description>
                            <lsb>8</lsb>
                            <msb>8</msb>
                            <access>read-write</access>
                            <enumeratedValues>
                                <enumeratedValue>
                                    <name>0</name>
                                    <description>Do not select associated input channel.</description>
                                    <value>#0</value>
                                </enumeratedValue>
                                <enumeratedValue>
                                    <name>1</name>
                                    <description>Select associated input channel. </description>
                                    <value>#1</value>
                                </enumeratedValue>
                            </enumeratedValues>
                        </field>
                    </fields>
                </register>
                <register>
                    <name>ADANSB1</name>
                    <description>A/D Channel Select Register B1</description>
                    <addressOffset>0x016</addressOffset>
                    <size>16</size>
                    <access>read-write</access>
                    <resetValue>0x0000</resetValue>
                    <resetMask>0xffff</resetMask>
                    <fields>
                        <field>
                            <name>ANSB16</name>
                            <description>A/D Conversion Channels Select</description>
                            <lsb>0</lsb>
                            <msb>0</msb>
                            <access>read-write</access>
                            <enumeratedValues>
                                <enumeratedValue>
                                    <name>0</name>
                                    <description>Do not select associated input channel.</description>
                                    <value>#0</value>
                                </enumeratedValue>
                                <enumeratedValue>
                                    <name>1</name>
                                    <description>Select associated input channel. </description>
                                    <value>#1</value>
                                </enumeratedValue>
                            </enumeratedValues>
                        </field>
                        <field>
                            <name>ANSB17</name>
                            <description>A/D Conversion Channels Select</description>
                            <lsb>1</lsb>
                            <msb>1</msb>
                            <access>read-write</access>
                            <enumeratedValues>
                                <enumeratedValue>
                                    <name>0</name>
                                    <description>Do not select associated input channel.</description>
                                    <value>#0</value>
                                </enumeratedValue>
                                <enumeratedValue>
                                    <name>1</name>
                                    <description>Select associated input channel. </description>
                                    <value>#1</value>
                                </enumeratedValue>
                            </enumeratedValues>
                        </field>
                        <field>
                            <name>ANSB18</name>
                            <description>A/D Conversion Channels Select</description>
                            <lsb>2</lsb>
                            <msb>2</msb>
                            <access>read-write</access>
                            <enumeratedValues>
                                <enumeratedValue>
                                    <name>0</name>
                                    <description>Do not select associated input channel.</description>
                                    <value>#0</value>
                                </enumeratedValue>
                                <enumeratedValue>
                                    <name>1</name>
                                    <description>Select associated input channel. </description>
                                    <value>#1</value>
                                </enumeratedValue>
                            </enumeratedValues>
                        </field>
                        <field>
                            <name>ANSB19</name>
                            <description>A/D Conversion Channels Select</description>
                            <lsb>3</lsb>
                            <msb>3</msb>
                            <access>read-write</access>
                            <enumeratedValues>
                                <enumeratedValue>
                                    <name>0</name>
                                    <description>Do not select associated input channel.</description>
                                    <value>#0</value>
                                </enumeratedValue>
                                <enumeratedValue>
                                    <name>1</name>
                                    <description>Select associated input channel. </description>
                                    <value>#1</value>
                                </enumeratedValue>
                            </enumeratedValues>
                        </field>
                        <field>
                            <name>ANSB20</name>
                            <description>A/D Conversion Channels Select</description>
                            <lsb>4</lsb>
                            <msb>4</msb>
                            <access>read-write</access>
                            <enumeratedValues>
                                <enumeratedValue>
                                    <name>0</name>
                                    <description>Do not select associated input channel.</description>
                                    <value>#0</value>
                                </enumeratedValue>
                                <enumeratedValue>
                                    <name>1</name>
                                    <description>Select associated input channel. </description>
                                    <value>#1</value>
                                </enumeratedValue>
                            </enumeratedValues>
                        </field>
                        <field>
                            <name>ANSB21</name>
                            <description>A/D Conversion Channels Select</description>
                            <lsb>5</lsb>
                            <msb>5</msb>
                            <access>read-write</access>
                            <enumeratedValues>
                                <enumeratedValue>
                                    <name>0</name>
                                    <description>Do not select associated input channel.</description>
                                    <value>#0</value>
                                </enumeratedValue>
                                <enumeratedValue>
                                    <name>1</name>
                                    <description>Select associated input channel. </description>
                                    <value>#1</value>
                                </enumeratedValue>
                            </enumeratedValues>
                        </field>
                        <field>
                            <name>ANSB22</name>
                            <description>A/D Conversion Channels Select</description>
                            <lsb>6</lsb>
                            <msb>6</msb>
                            <access>read-write</access>
                            <enumeratedValues>
                                <enumeratedValue>
                                    <name>0</name>
                                    <description>Do not select associated input channel.</description>
                                    <value>#0</value>
                                </enumeratedValue>
                                <enumeratedValue>
                                    <name>1</name>
                                    <description>Select associated input channel. </description>
                                    <value>#1</value>
                                </enumeratedValue>
                            </enumeratedValues>
                        </field>
                    </fields>
                </register>
                <register>
                    <name>ADDBLDR</name>
                    <description>A/D Data Duplexing Register</description>
                    <addressOffset>0x018</addressOffset>
                    <size>16</size>
                    <access>read-only</access>
                    <resetValue>0x0000</resetValue>
                    <resetMask>0xffff</resetMask>
                    <fields>
                        <field>
                            <name>ADDBLDR</name>
                            <description>Converted Value 15 to 0</description>
                            <lsb>0</lsb>
                            <msb>15</msb>
                            <access>read-only</access>
                        </field>
                    </fields>
                </register>
                <register>
                    <name>ADTSDR</name>
                    <description>A/D Temperature Sensor Data Register</description>
                    <addressOffset>0x01A</addressOffset>
                    <size>16</size>
                    <access>read-only</access>
                    <resetValue>0x0000</resetValue>
                    <resetMask>0xffff</resetMask>
                    <fields>
                        <field>
                            <name>ADTSDR</name>
                            <description>Converted Value 15 to 0</description>
                            <lsb>0</lsb>
                            <msb>15</msb>
                            <access>read-only</access>
                        </field>
                    </fields>
                </register>
                <register>
                    <name>ADOCDR</name>
                    <description>A/D Internal Reference Voltage Data Register</description>
                    <addressOffset>0x01C</addressOffset>
                    <size>16</size>
                    <access>read-only</access>
                    <resetValue>0x0000</resetValue>
                    <resetMask>0xffff</resetMask>
                    <fields>
                        <field>
                            <name>ADOCDR</name>
                            <description>Converted Value 15 to 0</description>
                            <lsb>0</lsb>
                            <msb>15</msb>
                            <access>read-only</access>
                        </field>
                    </fields>
                </register>
                <register>
                    <name>ADRD</name>
                    <description>A/D Self-Diagnosis Data Register</description>
                    <addressOffset>0x01E</addressOffset>
                    <size>16</size>
                    <access>read-only</access>
                    <resetValue>0x0000</resetValue>
                    <resetMask>0xffff</resetMask>
                    <fields>
                        <field>
                            <name>AD</name>
                            <description>Converted Value 11 to 0</description>
                            <lsb>0</lsb>
                            <msb>11</msb>
                            <access>read-only</access>
                        </field>
                        <field>
                            <name>DIAGST</name>
                            <description>Self-Diagnosis Status</description>
                            <lsb>14</lsb>
                            <msb>15</msb>
                            <access>read-only</access>
                            <enumeratedValues>
                                <enumeratedValue>
                                    <name>00</name>
                                    <description>Self-diagnosis not executed after power-on.</description>
                                    <value>#00</value>
                                </enumeratedValue>
                                <enumeratedValue>
                                    <name>01</name>
                                    <description>Self-diagnosis was executed using the 0 V voltage.</description>
                                    <value>#01</value>
                                </enumeratedValue>
                                <enumeratedValue>
                                    <name>10</name>
                                    <description>Self-diagnosis was executed using the reference voltage × 1/2.</description>
                                    <value>#10</value>
                                </enumeratedValue>
                                <enumeratedValue>
                                    <name>11</name>
                                    <description>Self-diagnosis was executed using the reference voltage .</description>
                                    <value>#11</value>
                                </enumeratedValue>
                            </enumeratedValues>
                        </field>
                    </fields>
                </register>
                <register>
                    <dim>9</dim>
                    <dimIncrement>0x2</dimIncrement>
                    <dimIndex>0-8</dimIndex>
                    <name>ADDR%s</name>
                    <description>A/D Data Registers %s</description>
                    <addressOffset>0x020</addressOffset>
                    <size>16</size>
                    <access>read-only</access>
                    <resetValue>0x0000</resetValue>
                    <resetMask>0xffff</resetMask>
                    <fields>
                        <field>
                            <name>ADDR</name>
                            <description>Converted Value 15 to 0</description>
                            <lsb>0</lsb>
                            <msb>15</msb>
                            <access>read-only</access>
                        </field>
                    </fields>
                </register>
                <register>
                    <dim>4</dim>
                    <dimIncrement>0x2</dimIncrement>
                    <dimIndex>16-19</dimIndex>
                    <name>ADDR%s</name>
                    <description>A/D Data Registers %s</description>
                    <addressOffset>0x020</addressOffset>
                    <size>16</size>
                    <access>read-only</access>
                    <resetValue>0x0000</resetValue>
                    <resetMask>0xffff</resetMask>
                    <fields>
                        <field>
                            <name>ADDR</name>
                            <description>Converted Value 15 to 0</description>
                            <lsb>0</lsb>
                            <msb>15</msb>
                            <access>read-only</access>
                        </field>
                    </fields>
                </register>
                <register>
                    <name>ADVMDR</name>
                    <description>A/D VBATT Monitor Data Register</description>
                    <addressOffset>0x026</addressOffset>
                    <size>16</size>
                    <access>read-only</access>
                    <resetValue>0x0000</resetValue>
                    <resetMask>0xffff</resetMask>
                    <fields>
                        <field>
                            <name>ADDR</name>
                            <description>Converted Value 15 to 0</description>
                            <lsb>0</lsb>
                            <msb>15</msb>
                            <access>read-only</access>
                        </field>
                    </fields>
                </register>
                <register>
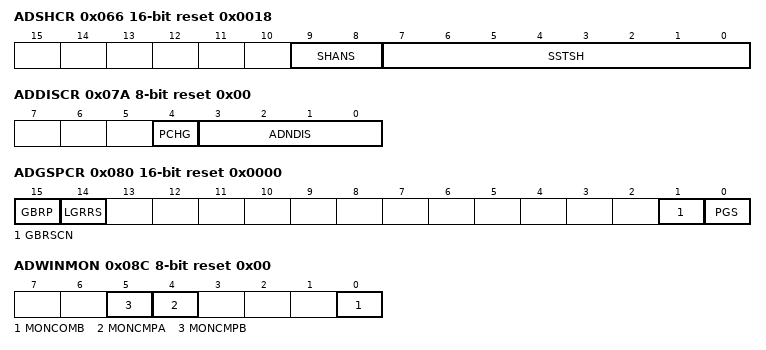
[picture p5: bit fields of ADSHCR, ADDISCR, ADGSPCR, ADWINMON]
                    <name>ADSHCR</name>
                    <description>A/D Sample and Hold Circuit Control Register</description>
                    <addressOffset>0x066</addressOffset>
                    <size>16</size>
                    <access>read-write</access>
                    <resetValue>0x0018</resetValue>
                    <resetMask>0xffff</resetMask>
                    <fields>
                        <field>
                            <name>SSTSH</name>
                            <description>Channel-Dedicated Sample-and-Hold Circuit Sampling Time Setting</description>
                            <lsb>0</lsb>
                            <msb>7</msb>
                            <access>read-write</access>
                        </field>
                        <field>
                            <name>SHANS</name>
                            <description>Channel-Dedicated Sample-and-Hold Circuit Bypass Select</description>
                            <lsb>8</lsb>
                            <msb>9</msb>
                            <access>read-write</access>
                            <enumeratedValues>
                                <enumeratedValue>
                                    <name>0</name>
                                    <description>Bypass the circuits</description>
                                    <value>#0</value>
                                </enumeratedValue>
                                <enumeratedValue>
                                    <name>1</name>
                                    <description>Use the circuits</description>
                                    <value>#1</value>
                                </enumeratedValue>
                            </enumeratedValues>
                        </field>
                    </fields>
                </register>
                <register>
                    <name>ADDISCR</name>
                    <description>A/D Disconnection Detection Control Register</description>
                    <addressOffset>0x07A</addressOffset>
                    <size>8</size>
                    <access>read-write</access>
                    <resetValue>0x00</resetValue>
                    <resetMask>0xff</resetMask>
                    <fields>
                        <field>
                            <name>ADNDIS</name>
                            <description>Disconnection Detection Assist Setting</description>
                            <lsb>0</lsb>
                            <msb>3</msb>
                            <access>read-write</access>
                            <enumeratedValues>
                                <enumeratedValue>
                                    <name>0x0</name>
                                    <description>The disconnection detection assist function is disabled</description>
                                    <value>0x0</value>
                                </enumeratedValue>
                                <enumeratedValue>
                                    <name>0x1</name>
                                    <description>Setting prohibited</description>
                                    <value>0x1</value>
                                </enumeratedValue>
                                <enumeratedValue>
                                    <name>Others</name>
                                    <description>The number of states for the discharge or precharge period.</description>
                                    <isDefault>true</isDefault>
                                </enumeratedValue>
                            </enumeratedValues>
                        </field>
                        <field>
                            <name>PCHG</name>
                            <description>Precharge/discharge select</description>
                            <lsb>4</lsb>
                            <msb>4</msb>
                            <access>read-write</access>
                            <enumeratedValues>
                                <enumeratedValue>
                                    <name>0</name>
                                    <description>Discharge</description>
                                    <value>#0</value>
                                </enumeratedValue>
                                <enumeratedValue>
                                    <name>1</name>
                                    <description>Precharge</description>
                                    <value>#1</value>
                                </enumeratedValue>
                            </enumeratedValues>
                        </field>
                    </fields>
                </register>
                <register>
                    <name>ADSHMSR</name>
                    <description>A/D Sample and Hold Operation Mode Selection Register</description>
                    <addressOffset>0x07C</addressOffset>
                    <size>8</size>
                    <access>read-write</access>
                    <resetValue>0x00</resetValue>
                    <resetMask>0xff</resetMask>
                    <fields>
                        <field>
                            <name>SHMD</name>
                            <description>Sampling Operation Selection</description>
                            <lsb>0</lsb>
                            <msb>0</msb>
                            <access>read-write</access>
                            <enumeratedValues>
                                <enumeratedValue>
                                    <name>0</name>
                                    <description>Sampling Operation Selection</description>
                                    <value>#0</value>
                                </enumeratedValue>
                                <enumeratedValue>
                                    <name>1</name>
                                    <description>Enable continuous sampling function</description>
                                    <value>#1</value>
                                </enumeratedValue>
                            </enumeratedValues>
                        </field>
                    </fields>
                </register>
                <register>
                    <name>ADGSPCR</name>
                    <description>A/D Group Scan Priority Control Register</description>
                    <addressOffset>0x080</addressOffset>
                    <size>16</size>
                    <access>read-write</access>
                    <resetValue>0x0000</resetValue>
                    <resetMask>0xffff</resetMask>
                    <fields>
                        <field>
                            <name>PGS</name>
                            <description>Group Priority Operation Setting</description>
                            <lsb>0</lsb>
                            <msb>0</msb>
                            <access>read-write</access>
                            <enumeratedValues>
                                <enumeratedValue>
                                    <name>0</name>
                                    <description>Operate without group priority control.</description>
                                    <value>#0</value>
                                </enumeratedValue>
                                <enumeratedValue>
                                    <name>1</name>
                                    <description>Operate with group priority control.</description>
                                    <value>#1</value>
                                </enumeratedValue>
                            </enumeratedValues>
                        </field>
                        <field>
                            <name>GBRSCN</name>
                            <description>Lower-Priority Group Restart Setting</description>
                            <lsb>1</lsb>
                            <msb>1</msb>
                            <access>read-write</access>
                            <enumeratedValues>
                                <enumeratedValue>
                                    <name>0</name>
                                    <description>Disable rescanning of the group that was stopped in group priority operation</description>
                                    <value>#0</value>
                                </enumeratedValue>
                                <enumeratedValue>
                                    <name>1</name>
                                    <description>Enable rescanning of the group that was stopped in group priority operation.</description>
                                    <value>#1</value>
                                </enumeratedValue>
                            </enumeratedValues>
                        </field>
                        <field>
                            <name>LGRRS</name>
                            <description>Enabled only when PGS = 1 and GBRSCN = 1.</description>
                            <lsb>14</lsb>
                            <msb>14</msb>
                            <access>read-write</access>
                            <enumeratedValues>
                                <enumeratedValue>
                                    <name>0</name>
                                    <description>Start rescanning from the first channel for scanning</description>
                                    <value>#0</value>
                                </enumeratedValue>
                                <enumeratedValue>
                                    <name>1</name>
                                    <description>Start rescanning from the channel for which A/D conversion is not completed.</description>
                                    <value>#1</value>
                                </enumeratedValue>
                            </enumeratedValues>
                        </field>
                        <field>
                            <name>GBRP</name>
                            <description>Single Scan Continuous Start</description>
                            <lsb>15</lsb>
                            <msb>15</msb>
                            <access>read-write</access>
                            <enumeratedValues>
                                <enumeratedValue>
                                    <name>0</name>
                                    <description>Single scan is not continuously activated.</description>
                                    <value>#0</value>
                                </enumeratedValue>
                                <enumeratedValue>
                                    <name>1</name>
                                    <description>Single scan for the group with the lower-priority is continuously activated.</description>
                                    <value>#1</value>
                                </enumeratedValue>
                            </enumeratedValues>
                        </field>
                    </fields>
                </register>
                <register>
                    <name>ADDBLDRA</name>
                    <description>A/D Data Duplexing Register A</description>
                    <addressOffset>0x084</addressOffset>
                    <size>16</size>
                    <access>read-only</access>
                    <resetValue>0x0000</resetValue>
                    <resetMask>0xffff</resetMask>
                    <fields>
                        <field>
                            <name>ADDBLDR</name>
                            <description>Converted Value 15 to 0</description>
                            <lsb>0</lsb>
                            <msb>15</msb>
                            <access>read-only</access>
                        </field>
                    </fields>
                </register>
                <register>
                    <name>ADDBLDRB</name>
                    <description>A/D Data Duplexing Register B</description>
                    <addressOffset>0x086</addressOffset>
                    <size>16</size>
                    <access>read-only</access>
                    <resetValue>0x0000</resetValue>
                    <resetMask>0xffff</resetMask>
                    <fields>
                        <field>
                            <name>ADDBLDR</name>
                            <description>Converted Value 15 to 0</description>
                            <lsb>0</lsb>
                            <msb>15</msb>
                            <access>read-only</access>
                        </field>
                    </fields>
                </register>
                <register>
                    <name>ADWINMON</name>
                    <description>A/D Compare Function Window A/B Status Monitor Register</description>
                    <addressOffset>0x08C</addressOffset>
                    <size>8</size>
                    <access>read-only</access>
                    <resetValue>0x00</resetValue>
                    <resetMask>0xff</resetMask>
                    <fields>
                        <field>
                            <name>MONCOMB</name>
                            <description>Combination Result Monitor</description>
                            <lsb>0</lsb>
                            <msb>0</msb>
                            <access>read-only</access>
                            <enumeratedValues>
                                <enumeratedValue>
                                    <name>0</name>
                                    <description>Window A/B composite conditions are not met.</description>
                                    <value>#0</value>
                                </enumeratedValue>
                                <enumeratedValue>
                                    <name>1</name>
                                    <description>Window A/B composite conditions are met.</description>
                                    <value>#1</value>
                                </enumeratedValue>
                            </enumeratedValues>
                        </field>
                        <field>
                            <name>MONCMPA</name>
                            <description>Comparison Result Monitor A</description>
                            <lsb>4</lsb>
                            <msb>4</msb>
                            <access>read-only</access>
                            <enumeratedValues>
                                <enumeratedValue>
                                    <name>0</name>
                                    <description>Window A comparison conditions are not met.</description>
                                    <value>#0</value>
                                </enumeratedValue>
                                <enumeratedValue>
                                    <name>1</name>
                                    <description>Window A comparison conditions are met.</description>
                                    <value>#1</value>
                                </enumeratedValue>
                            </enumeratedValues>
                        </field>
                        <field>
                            <name>MONCMPB</name>
                            <description>Comparison Result Monitor B</description>
                            <lsb>5</lsb>
                            <msb>5</msb>
                            <access>read-only</access>
                            <enumeratedValues>
                                <enumeratedValue>
                                    <name>0</name>
                                    <description>Window B comparison conditions are not met.</description>
                                    <value>#0</value>
                                </enumeratedValue>
                                <enumeratedValue>
                                    <name>1</name>
                                    <description>Window B comparison conditions are met.</description>
                                    <value>#1</value>
                                </enumeratedValue>
                            </enumeratedValues>
                        </field>
                    </fields>
                </register>
                <register>
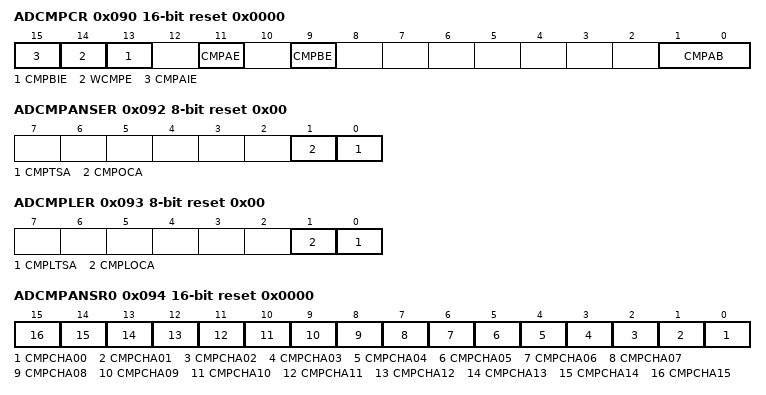
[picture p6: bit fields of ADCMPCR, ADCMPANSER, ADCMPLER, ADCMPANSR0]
                    <name>ADCMPCR</name>
                    <description>A/D Compare Function Control Register</description>
                    <addressOffset>0x090</addressOffset>
                    <size>16</size>
                    <access>read-write</access>
                    <resetValue>0x0000</resetValue>
                    <resetMask>0xffff</resetMask>
                    <fields>
                        <field>
                            <name>CMPAB</name>
                            <description>Window A/B Composite Conditions Setting</description>
                            <lsb>0</lsb>
                            <msb>1</msb>
                            <access>read-write</access>
                            <enumeratedValues>
                                <enumeratedValue>
                                    <name>00</name>
                                    <description>Output ADC12i_WCMPM (i = 0, 1) when window A OR window B comparison conditions are met. Otherwise, output ADC12i_WCMPUM (i = 0, 1).</description>
                                    <value>#00</value>
                                </enumeratedValue>
                                <enumeratedValue>
                                    <name>01</name>
                                    <description>Output ADC12i_WCMPM (i = 0, 1) when window A EXOR window B comparison conditions are met. Otherwise, output ADC12i_WCMPUM (i = 0, 1).</description>
                                    <value>#01</value>
                                </enumeratedValue>
                                <enumeratedValue>
                                    <name>10</name>
                                    <description>Output ADC12i_WCMPM (i = 0, 1) when window A AND window B comparison conditions are met. Otherwise, output ADC12i_WCMPUM (i = 0, 1).</description>
                                    <value>#10</value>
                                </enumeratedValue>
                                <enumeratedValue>
                                    <name>11</name>
                                    <description>Setting prohibited.</description>
                                    <value>#11</value>
                                </enumeratedValue>
                            </enumeratedValues>
                        </field>
                        <field>
                            <name>CMPBE</name>
                            <description>Compare Window B Operation Enable</description>
                            <lsb>9</lsb>
                            <msb>9</msb>
                            <access>read-write</access>
                            <enumeratedValues>
                                <enumeratedValue>
                                    <name>0</name>
                                    <description>Disable compare window B operation. Disable ADC12i_WCMPM (i = 0, 1) and ADC12i_WCMPUM (i = 0, 1) outputs. </description>
                                    <value>#0</value>
                                </enumeratedValue>
                                <enumeratedValue>
                                    <name>1</name>
                                    <description>Enable compare window B operation.</description>
                                    <value>#1</value>
                                </enumeratedValue>
                            </enumeratedValues>
                        </field>
                        <field>
                            <name>CMPAE</name>
                            <description>Compare Window A Operation Enable</description>
                            <lsb>11</lsb>
                            <msb>11</msb>
                            <access>read-write</access>
                            <enumeratedValues>
                                <enumeratedValue>
                                    <name>0</name>
                                    <description>Disable compare window A operation. Disable ADC12i_WCMPM (i = 0, 1) and ADC12i_WCMPUM (i = 0, 1) outputs. </description>
                                    <value>#0</value>
                                </enumeratedValue>
                                <enumeratedValue>
                                    <name>1</name>
                                    <description>Enable compare window A operation.</description>
                                    <value>#1</value>
                                </enumeratedValue>
                            </enumeratedValues>
                        </field>
                        <field>
                            <name>CMPBIE</name>
                            <description>Compare B Interrupt Enable</description>
                            <lsb>13</lsb>
                            <msb>13</msb>
                            <access>read-write</access>
                            <enumeratedValues>
                                <enumeratedValue>
                                    <name>0</name>
                                    <description>Disable ADC12i_CMPBI (i = 0, 1) interrupt when comparison conditions (window B) are met.</description>
                                    <value>#0</value>
                                </enumeratedValue>
                                <enumeratedValue>
                                    <name>1</name>
                                    <description>Enable ADC12i_CMPBI (i = 0, 1) interrupt when comparison conditions (window B) are met.</description>
                                    <value>#1</value>
                                </enumeratedValue>
                            </enumeratedValues>
                        </field>
                        <field>
                            <name>WCMPE</name>
                            <description>Window Function Setting</description>
                            <lsb>14</lsb>
                            <msb>14</msb>
                            <access>read-write</access>
                            <enumeratedValues>
                                <enumeratedValue>
                                    <name>0</name>
                                    <description>Disable window function Window A and window B operate as a comparator to compare the single value on the lower side with the A/D conversion result. </description>
                                    <value>#0</value>
                                </enumeratedValue>
                                <enumeratedValue>
                                    <name>1</name>
                                    <description>Enable window function Window A and window B operate as a comparator to compare the two values on the upper and lower sides with the A/D conversion result. </description>
                                    <value>#1</value>
                                </enumeratedValue>
                            </enumeratedValues>
                        </field>
                        <field>
                            <name>CMPAIE</name>
                            <description>Compare A Interrupt Enable</description>
                            <lsb>15</lsb>
                            <msb>15</msb>
                            <access>read-write</access>
                            <enumeratedValues>
                                <enumeratedValue>
                                    <name>0</name>
                                    <description>Disable ADC12i_CMPAI (i = 0, 1) interrupt when comparison conditions (window A) are met.</description>
                                    <value>#0</value>
                                </enumeratedValue>
                                <enumeratedValue>
                                    <name>1</name>
                                    <description>Enable ADC12i_CMPAI (i = 0, 1) interrupt when comparison conditions (window A) are met.</description>
                                    <value>#1</value>
                                </enumeratedValue>
                            </enumeratedValues>
                        </field>
                    </fields>
                </register>
                <register>
                    <name>ADCMPANSER</name>
                    <description>A/D Compare Function Window A Extended Input Select Register</description>
                    <addressOffset>0x092</addressOffset>
                    <size>8</size>
                    <access>read-write</access>
                    <resetValue>0x00</resetValue>
                    <resetMask>0xff</resetMask>
                    <fields>
                        <field>
                            <name>CMPTSA</name>
                            <description>Temperature Sensor Output Compare Select</description>
                            <lsb>0</lsb>
                            <msb>0</msb>
                            <access>read-write</access>
                            <enumeratedValues>
                                <enumeratedValue>
                                    <name>0</name>
                                    <description>Exclude the temperature sensor output from the compare Window A target range.</description>
                                    <value>#0</value>
                                </enumeratedValue>
                                <enumeratedValue>
                                    <name>1</name>
                                    <description>Include the temperature sensor output in the compare Window A target range.</description>
                                    <value>#1</value>
                                </enumeratedValue>
                            </enumeratedValues>
                        </field>
                        <field>
                            <name>CMPOCA</name>
                            <description>Internal Reference Voltage Compare Select</description>
                            <lsb>1</lsb>
                            <msb>1</msb>
                            <access>read-write</access>
                            <enumeratedValues>
                                <enumeratedValue>
                                    <name>0</name>
                                    <description>Exclude the internal reference voltage from the compare Window A target range.</description>
                                    <value>#0</value>
                                </enumeratedValue>
                                <enumeratedValue>
                                    <name>1</name>
                                    <description>Include the internal reference voltage in the compare Window A target range. </description>
                                    <value>#1</value>
                                </enumeratedValue>
                            </enumeratedValues>
                        </field>
                    </fields>
                </register>
                <register>
                    <name>ADCMPLER</name>
                    <description>A/D Compare Function Window A Extended Input Comparison Condition Setting Register</description>
                    <addressOffset>0x093</addressOffset>
                    <size>8</size>
                    <access>read-write</access>
                    <resetValue>0x00</resetValue>
                    <resetMask>0xff</resetMask>
                    <fields>
                        <field>
                            <name>CMPLTSA</name>
                            <description>Compare Window A Temperature Sensor Output Comparison Condition Select</description>
                            <lsb>0</lsb>
                            <msb>0</msb>
                            <access>read-write</access>
                            <enumeratedValues>
                                <enumeratedValue>
                                    <name>0</name>
                                    <description>When window function is disabled (ADCMPCR.WCMPE = 0) : ADCMPDR0 value &gt; A/D-converted valueCompare Window A Temperature Sensor Output Comparison Condition Select When window function is enabled (ADCMPCR.WCMPE = 1) : Compare Window A Temperature Sensor Output Comparison ConditionA/D-converted value &lt; ADCMPDR0 value, or A/D-converted value &gt; ADCMPDR1 value </description>
                                    <value>#0</value>
                                </enumeratedValue>
                                <enumeratedValue>
                                    <name>1</name>
                                    <description>When window function is disabled (ADCMPCR.WCMPE = 0) : ADCMPDR0 value &lt; A/D-converted value When window function is enabled (ADCMPCR.WCMPE = 1) : ADCMPDR0 value &lt; A/D-converted value &lt; ADCMPDR1 value </description>
                                    <value>#1</value>
                                </enumeratedValue>
                            </enumeratedValues>
                        </field>
                        <field>
                            <name>CMPLOCA</name>
                            <description>Compare Window A Internal Reference Voltage Comparison Condition Select</description>
                            <lsb>1</lsb>
                            <msb>1</msb>
                            <access>read-write</access>
                            <enumeratedValues>
                                <enumeratedValue>
                                    <name>0</name>
                                    <description>When window function is disabled (ADCMPCR.WCMPE = 0) : ADCMPDR0 value &gt; A/D-converted value When window function is enabled (ADCMPCR.WCMPE = 1): A/D-converted value &lt; ADCMPDR0 value, or A/D-converted value &gt; ADCMPDR1 value </description>
                                    <value>#0</value>
                                </enumeratedValue>
                                <enumeratedValue>
                                    <name>1</name>
                                    <description>When window function is disabled (ADCMPCR.WCMPE = 0): ADCMPDR0 value &lt; A/D-converted value When window function is enabled (ADCMPCR.WCMPE = 1): ADCMPDR0 value &lt; A/D-converted value &lt; ADCMPDR1 value </description>
                                    <value>#1</value>
                                </enumeratedValue>
                            </enumeratedValues>
                        </field>
                    </fields>
                </register>
                <register>
                    <name>ADCMPANSR0</name>
                    <description>A/D Compare Function Window A Channel Select Register 0</description>
                    <addressOffset>0x094</addressOffset>
                    <size>16</size>
                    <access>read-write</access>
                    <resetValue>0x0000</resetValue>
                    <resetMask>0xffff</resetMask>
                    <fields>
                        <field>
                            <name>CMPCHA00</name>
                            <description>Compare Window A Channel Select</description>
                            <lsb>0</lsb>
                            <msb>0</msb>
                            <access>read-write</access>
                            <enumeratedValues>
                                <enumeratedValue>
                                    <name>0</name>
                                    <description>Disable compare function for associated input channel</description>
                                    <value>#0</value>
                                </enumeratedValue>
                                <enumeratedValue>
                                    <name>1</name>
                                    <description>Enable compare function for associated input channel</description>
                                    <value>#1</value>
                                </enumeratedValue>
                            </enumeratedValues>
                        </field>
                        <field>
                            <name>CMPCHA01</name>
                            <description>Compare Window A Channel Select</description>
                            <lsb>1</lsb>
                            <msb>1</msb>
                            <access>read-write</access>
                            <enumeratedValues>
                                <enumeratedValue>
                                    <name>0</name>
                                    <description>Disable compare function for associated input channel</description>
                                    <value>#0</value>
                                </enumeratedValue>
                                <enumeratedValue>
                                    <name>1</name>
                                    <description>Enable compare function for associated input channel</description>
                                    <value>#1</value>
                                </enumeratedValue>
                            </enumeratedValues>
                        </field>
                        <field>
                            <name>CMPCHA02</name>
                            <description>Compare Window A Channel Select</description>
                            <lsb>2</lsb>
                            <msb>2</msb>
                            <access>read-write</access>
                            <enumeratedValues>
                                <enumeratedValue>
                                    <name>0</name>
                                    <description>Disable compare function for associated input channel</description>
                                    <value>#0</value>
                                </enumeratedValue>
                                <enumeratedValue>
                                    <name>1</name>
                                    <description>Enable compare function for associated input channel</description>
                                    <value>#1</value>
                                </enumeratedValue>
                            </enumeratedValues>
                        </field>
                        <field>
                            <name>CMPCHA03</name>
                            <description>Compare Window A Channel Select</description>
                            <lsb>3</lsb>
                            <msb>3</msb>
                            <access>read-write</access>
                            <enumeratedValues>
                                <enumeratedValue>
                                    <name>0</name>
                                    <description>Disable compare function for associated input channel</description>
                                    <value>#0</value>
                                </enumeratedValue>
                                <enumeratedValue>
                                    <name>1</name>
                                    <description>Enable compare function for associated input channel</description>
                                    <value>#1</value>
                                </enumeratedValue>
                            </enumeratedValues>
                        </field>
                        <field>
                            <name>CMPCHA04</name>
                            <description>Compare Window A Channel Select</description>
                            <lsb>4</lsb>
                            <msb>4</msb>
                            <access>read-write</access>
                            <enumeratedValues>
                                <enumeratedValue>
                                    <name>0</name>
                                    <description>Disable compare function for associated input channel</description>
                                    <value>#0</value>
                                </enumeratedValue>
                                <enumeratedValue>
                                    <name>1</name>
                                    <description>Enable compare function for associated input channel</description>
                                    <value>#1</value>
                                </enumeratedValue>
                            </enumeratedValues>
                        </field>
                        <field>
                            <name>CMPCHA05</name>
                            <description>Compare Window A Channel Select</description>
                            <lsb>5</lsb>
                            <msb>5</msb>
                            <access>read-write</access>
                            <enumeratedValues>
                                <enumeratedValue>
                                    <name>0</name>
                                    <description>Disable compare function for associated input channel</description>
                                    <value>#0</value>
                                </enumeratedValue>
                                <enumeratedValue>
                                    <name>1</name>
                                    <description>Enable compare function for associated input channel</description>
                                    <value>#1</value>
                                </enumeratedValue>
                            </enumeratedValues>
                        </field>
                        <field>
                            <name>CMPCHA06</name>
                            <description>Compare Window A Channel Select</description>
                            <lsb>6</lsb>
                            <msb>6</msb>
                            <access>read-write</access>
                            <enumeratedValues>
                                <enumeratedValue>
                                    <name>0</name>
                                    <description>Disable compare function for associated input channel</description>
                                    <value>#0</value>
                                </enumeratedValue>
                                <enumeratedValue>
                                    <name>1</name>
                                    <description>Enable compare function for associated input channel</description>
                                    <value>#1</value>
                                </enumeratedValue>
                            </enumeratedValues>
                        </field>
                        <field>
                            <name>CMPCHA07</name>
                            <description>Compare Window A Channel Select</description>
                            <lsb>7</lsb>
                            <msb>7</msb>
                            <access>read-write</access>
                            <enumeratedValues>
                                <enumeratedValue>
                                    <name>0</name>
                                    <description>Disable compare function for associated input channel</description>
                                    <value>#0</value>
                                </enumeratedValue>
                                <enumeratedValue>
                                    <name>1</name>
                                    <description>Enable compare function for associated input channel</description>
                                    <value>#1</value>
                                </enumeratedValue>
                            </enumeratedValues>
                        </field>
                        <field>
                            <name>CMPCHA08</name>
                            <description>Compare Window A Channel Select</description>
                            <lsb>8</lsb>
                            <msb>8</msb>
                            <access>read-write</access>
                            <enumeratedValues>
                                <enumeratedValue>
                                    <name>0</name>
                                    <description>Disable compare function for associated input channel</description>
                                    <value>#0</value>
                                </enumeratedValue>
                                <enumeratedValue>
                                    <name>1</name>
                                    <description>Enable compare function for associated input channel</description>
                                    <value>#1</value>
                                </enumeratedValue>
                            </enumeratedValues>
                        </field>
                        <field>
                            <name>CMPCHA09</name>
                            <description>Compare Window A Channel Select</description>
                            <lsb>9</lsb>
                            <msb>9</msb>
                            <access>read-write</access>
                            <enumeratedValues>
                                <enumeratedValue>
                                    <name>0</name>
                                    <description>Disable compare function for associated input channel</description>
                                    <value>#0</value>
                                </enumeratedValue>
                                <enumeratedValue>
                                    <name>1</name>
                                    <description>Enable compare function for associated input channel</description>
                                    <value>#1</value>
                                </enumeratedValue>
                            </enumeratedValues>
                        </field>
                        <field>
                            <name>CMPCHA10</name>
                            <description>Compare Window A Channel Select</description>
                            <lsb>10</lsb>
                            <msb>10</msb>
                            <access>read-write</access>
                            <enumeratedValues>
                                <enumeratedValue>
                                    <name>0</name>
                                    <description>Disable compare function for associated input channel</description>
                                    <value>#0</value>
                                </enumeratedValue>
                                <enumeratedValue>
                                    <name>1</name>
                                    <description>Enable compare function for associated input channel</description>
                                    <value>#1</value>
                                </enumeratedValue>
                            </enumeratedValues>
                        </field>
                        <field>
                            <name>CMPCHA11</name>
                            <description>Compare Window A Channel Select</description>
                            <lsb>11</lsb>
                            <msb>11</msb>
                            <access>read-write</access>
                            <enumeratedValues>
                                <enumeratedValue>
                                    <name>0</name>
                                    <description>Disable compare function for associated input channel</description>
                                    <value>#0</value>
                                </enumeratedValue>
                                <enumeratedValue>
                                    <name>1</name>
                                    <description>Enable compare function for associated input channel</description>
                                    <value>#1</value>
                                </enumeratedValue>
                            </enumeratedValues>
                        </field>
                        <field>
                            <name>CMPCHA12</name>
                            <description>Compare Window A Channel Select</description>
                            <lsb>12</lsb>
                            <msb>12</msb>
                            <access>read-write</access>
                            <enumeratedValues>
                                <enumeratedValue>
                                    <name>0</name>
                                    <description>Disable compare function for associated input channel</description>
                                    <value>#0</value>
                                </enumeratedValue>
                                <enumeratedValue>
                                    <name>1</name>
                                    <description>Enable compare function for associated input channel</description>
                                    <value>#1</value>
                                </enumeratedValue>
                            </enumeratedValues>
                        </field>
                        <field>
                            <name>CMPCHA13</name>
                            <description>Compare Window A Channel Select</description>
                            <lsb>13</lsb>
                            <msb>13</msb>
                            <access>read-write</access>
                            <enumeratedValues>
                                <enumeratedValue>
                                    <name>0</name>
                                    <description>Disable compare function for associated input channel</description>
                                    <value>#0</value>
                                </enumeratedValue>
                                <enumeratedValue>
                                    <name>1</name>
                                    <description>Enable compare function for associated input channel</description>
                                    <value>#1</value>
                                </enumeratedValue>
                            </enumeratedValues>
                        </field>
                        <field>
                            <name>CMPCHA14</name>
                            <description>Compare Window A Channel Select</description>
                            <lsb>14</lsb>
                            <msb>14</msb>
                            <access>read-write</access>
                            <enumeratedValues>
                                <enumeratedValue>
                                    <name>0</name>
                                    <description>Disable compare function for associated input channel</description>
                                    <value>#0</value>
                                </enumeratedValue>
                                <enumeratedValue>
                                    <name>1</name>
                                    <description>Enable compare function for associated input channel</description>
                                    <value>#1</value>
                                </enumeratedValue>
                            </enumeratedValues>
                        </field>
                        <field>
                            <name>CMPCHA15</name>
                            <description>Compare Window A Channel Select</description>
                            <lsb>15</lsb>
                            <msb>15</msb>
                            <access>read-write</access>
                            <enumeratedValues>
                                <enumeratedValue>
                                    <name>0</name>
                                    <description>Disable compare function for associated input channel</description>
                                    <value>#0</value>
                                </enumeratedValue>
                                <enumeratedValue>
                                    <name>1</name>
                                    <description>Enable compare function for associated input channel</description>
                                    <value>#1</value>
                                </enumeratedValue>
                            </enumeratedValues>
                        </field>
                    </fields>
                </register>
                <register>
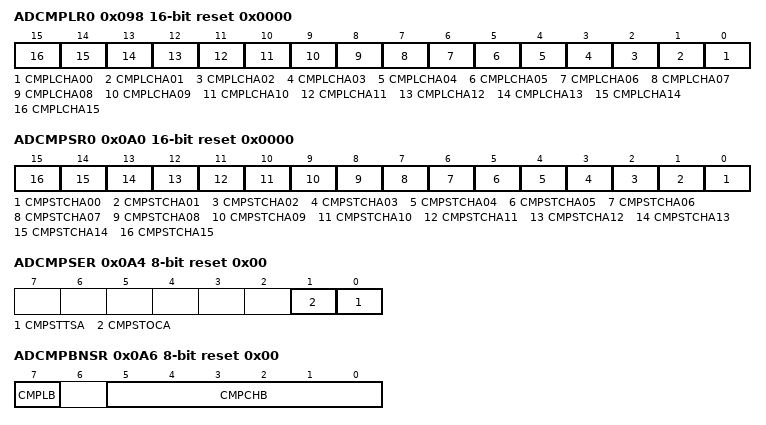
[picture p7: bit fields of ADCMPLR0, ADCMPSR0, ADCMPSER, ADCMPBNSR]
                    <name>ADCMPLR0</name>
                    <description>A/D Compare Function Window A Comparison Condition Setting Register 0</description>
                    <addressOffset>0x098</addressOffset>
                    <size>16</size>
                    <access>read-write</access>
                    <resetValue>0x0000</resetValue>
                    <resetMask>0xffff</resetMask>
                    <fields>
                        <field>
                            <name>CMPLCHA00</name>
                            <description>Compare Window A Comparison Condition Select</description>
                            <lsb>0</lsb>
                            <msb>0</msb>
                            <access>read-write</access>
                            <enumeratedValues>
                                <enumeratedValue>
                                    <name>0</name>
                                    <description>When window function is disabled (ADCMPCR.WCMPE = 0): ADCMPDR0 value &gt; A/D-converted value When window function is enabled (ADCMPCR.WCMPE = 1): A/D-converted value &lt; ADCMPDR0 value, or ADCMPDR1 value &lt; A/D-converted value </description>
                                    <value>#0</value>
                                </enumeratedValue>
                                <enumeratedValue>
                                    <name>1</name>
                                    <description>When window function is disabled (ADCMPCR.WCMPE = 0): ADCMPDR0 value &lt; A/D-converted value When window function is enabled (ADCMPCR.WCMPE = 1): ADCMPDR0 value &lt; A/D-converted value &lt; ADCMPDR1 value </description>
                                    <value>#1</value>
                                </enumeratedValue>
                            </enumeratedValues>
                        </field>
                        <field>
                            <name>CMPLCHA01</name>
                            <description>Compare Window A Comparison Condition Select</description>
                            <lsb>1</lsb>
                            <msb>1</msb>
                            <access>read-write</access>
                            <enumeratedValues>
                                <enumeratedValue>
                                    <name>0</name>
                                    <description>When window function is disabled (ADCMPCR.WCMPE = 0): ADCMPDR0 value &gt; A/D-converted value When window function is enabled (ADCMPCR.WCMPE = 1): A/D-converted value &lt; ADCMPDR0 value, or ADCMPDR1 value &lt; A/D-converted value </description>
                                    <value>#0</value>
                                </enumeratedValue>
                                <enumeratedValue>
                                    <name>1</name>
                                    <description>When window function is disabled (ADCMPCR.WCMPE = 0): ADCMPDR0 value &lt; A/D-converted value When window function is enabled (ADCMPCR.WCMPE = 1): ADCMPDR0 value &lt; A/D-converted value &lt; ADCMPDR1 value </description>
                                    <value>#1</value>
                                </enumeratedValue>
                            </enumeratedValues>
                        </field>
                        <field>
                            <name>CMPLCHA02</name>
                            <description>Compare Window A Comparison Condition Select</description>
                            <lsb>2</lsb>
                            <msb>2</msb>
                            <access>read-write</access>
                            <enumeratedValues>
                                <enumeratedValue>
                                    <name>0</name>
                                    <description>When window function is disabled (ADCMPCR.WCMPE = 0): ADCMPDR0 value &gt; A/D-converted value When window function is enabled (ADCMPCR.WCMPE = 1): A/D-converted value &lt; ADCMPDR0 value, or ADCMPDR1 value &lt; A/D-converted value </description>
                                    <value>#0</value>
                                </enumeratedValue>
                                <enumeratedValue>
                                    <name>1</name>
                                    <description>When window function is disabled (ADCMPCR.WCMPE = 0): ADCMPDR0 value &lt; A/D-converted value When window function is enabled (ADCMPCR.WCMPE = 1): ADCMPDR0 value &lt; A/D-converted value &lt; ADCMPDR1 value </description>
                                    <value>#1</value>
                                </enumeratedValue>
                            </enumeratedValues>
                        </field>
                        <field>
                            <name>CMPLCHA03</name>
                            <description>Compare Window A Comparison Condition Select</description>
                            <lsb>3</lsb>
                            <msb>3</msb>
                            <access>read-write</access>
                            <enumeratedValues>
                                <enumeratedValue>
                                    <name>0</name>
                                    <description>When window function is disabled (ADCMPCR.WCMPE = 0): ADCMPDR0 value &gt; A/D-converted value When window function is enabled (ADCMPCR.WCMPE = 1): A/D-converted value &lt; ADCMPDR0 value, or ADCMPDR1 value &lt; A/D-converted value </description>
                                    <value>#0</value>
                                </enumeratedValue>
                                <enumeratedValue>
                                    <name>1</name>
                                    <description>When window function is disabled (ADCMPCR.WCMPE = 0): ADCMPDR0 value &lt; A/D-converted value When window function is enabled (ADCMPCR.WCMPE = 1): ADCMPDR0 value &lt; A/D-converted value &lt; ADCMPDR1 value </description>
                                    <value>#1</value>
                                </enumeratedValue>
                            </enumeratedValues>
                        </field>
                        <field>
                            <name>CMPLCHA04</name>
                            <description>Compare Window A Comparison Condition Select</description>
                            <lsb>4</lsb>
                            <msb>4</msb>
                            <access>read-write</access>
                            <enumeratedValues>
                                <enumeratedValue>
                                    <name>0</name>
                                    <description>When window function is disabled (ADCMPCR.WCMPE = 0): ADCMPDR0 value &gt; A/D-converted value When window function is enabled (ADCMPCR.WCMPE = 1): A/D-converted value &lt; ADCMPDR0 value, or ADCMPDR1 value &lt; A/D-converted value </description>
                                    <value>#0</value>
                                </enumeratedValue>
                                <enumeratedValue>
                                    <name>1</name>
                                    <description>When window function is disabled (ADCMPCR.WCMPE = 0): ADCMPDR0 value &lt; A/D-converted value When window function is enabled (ADCMPCR.WCMPE = 1): ADCMPDR0 value &lt; A/D-converted value &lt; ADCMPDR1 value </description>
                                    <value>#1</value>
                                </enumeratedValue>
                            </enumeratedValues>
                        </field>
                        <field>
                            <name>CMPLCHA05</name>
                            <description>Compare Window A Comparison Condition Select</description>
                            <lsb>5</lsb>
                            <msb>5</msb>
                            <access>read-write</access>
                            <enumeratedValues>
                                <enumeratedValue>
                                    <name>0</name>
                                    <description>When window function is disabled (ADCMPCR.WCMPE = 0): ADCMPDR0 value &gt; A/D-converted value When window function is enabled (ADCMPCR.WCMPE = 1): A/D-converted value &lt; ADCMPDR0 value, or ADCMPDR1 value &lt; A/D-converted value </description>
                                    <value>#0</value>
                                </enumeratedValue>
                                <enumeratedValue>
                                    <name>1</name>
                                    <description>When window function is disabled (ADCMPCR.WCMPE = 0): ADCMPDR0 value &lt; A/D-converted value When window function is enabled (ADCMPCR.WCMPE = 1): ADCMPDR0 value &lt; A/D-converted value &lt; ADCMPDR1 value </description>
                                    <value>#1</value>
                                </enumeratedValue>
                            </enumeratedValues>
                        </field>
                        <field>
                            <name>CMPLCHA06</name>
                            <description>Compare Window A Comparison Condition Select</description>
                            <lsb>6</lsb>
                            <msb>6</msb>
                            <access>read-write</access>
                            <enumeratedValues>
                                <enumeratedValue>
                                    <name>0</name>
                                    <description>When window function is disabled (ADCMPCR.WCMPE = 0): ADCMPDR0 value &gt; A/D-converted value When window function is enabled (ADCMPCR.WCMPE = 1): A/D-converted value &lt; ADCMPDR0 value, or ADCMPDR1 value &lt; A/D-converted value </description>
                                    <value>#0</value>
                                </enumeratedValue>
                                <enumeratedValue>
                                    <name>1</name>
                                    <description>When window function is disabled (ADCMPCR.WCMPE = 0): ADCMPDR0 value &lt; A/D-converted value When window function is enabled (ADCMPCR.WCMPE = 1): ADCMPDR0 value &lt; A/D-converted value &lt; ADCMPDR1 value </description>
                                    <value>#1</value>
                                </enumeratedValue>
                            </enumeratedValues>
                        </field>
                        <field>
                            <name>CMPLCHA07</name>
                            <description>Compare Window A Comparison Condition Select</description>
                            <lsb>7</lsb>
                            <msb>7</msb>
                            <access>read-write</access>
                            <enumeratedValues>
                                <enumeratedValue>
                                    <name>0</name>
                                    <description>When window function is disabled (ADCMPCR.WCMPE = 0): ADCMPDR0 value &gt; A/D-converted value When window function is enabled (ADCMPCR.WCMPE = 1): A/D-converted value &lt; ADCMPDR0 value, or ADCMPDR1 value &lt; A/D-converted value </description>
                                    <value>#0</value>
                                </enumeratedValue>
                                <enumeratedValue>
                                    <name>1</name>
                                    <description>When window function is disabled (ADCMPCR.WCMPE = 0): ADCMPDR0 value &lt; A/D-converted value When window function is enabled (ADCMPCR.WCMPE = 1): ADCMPDR0 value &lt; A/D-converted value &lt; ADCMPDR1 value </description>
                                    <value>#1</value>
                                </enumeratedValue>
                            </enumeratedValues>
                        </field>
                        <field>
                            <name>CMPLCHA08</name>
                            <description>Compare Window A Comparison Condition Select</description>
                            <lsb>8</lsb>
                            <msb>8</msb>
                            <access>read-write</access>
                            <enumeratedValues>
                                <enumeratedValue>
                                    <name>0</name>
                                    <description>When window function is disabled (ADCMPCR.WCMPE = 0): ADCMPDR0 value &gt; A/D-converted value When window function is enabled (ADCMPCR.WCMPE = 1): A/D-converted value &lt; ADCMPDR0 value, or ADCMPDR1 value &lt; A/D-converted value </description>
                                    <value>#0</value>
                                </enumeratedValue>
                                <enumeratedValue>
                                    <name>1</name>
                                    <description>When window function is disabled (ADCMPCR.WCMPE = 0): ADCMPDR0 value &lt; A/D-converted value When window function is enabled (ADCMPCR.WCMPE = 1): ADCMPDR0 value &lt; A/D-converted value &lt; ADCMPDR1 value </description>
                                    <value>#1</value>
                                </enumeratedValue>
                            </enumeratedValues>
                        </field>
                        <field>
                            <name>CMPLCHA09</name>
                            <description>Compare Window A Comparison Condition Select</description>
                            <lsb>9</lsb>
                            <msb>9</msb>
                            <access>read-write</access>
                            <enumeratedValues>
                                <enumeratedValue>
                                    <name>0</name>
                                    <description>When window function is disabled (ADCMPCR.WCMPE = 0): ADCMPDR0 value &gt; A/D-converted value When window function is enabled (ADCMPCR.WCMPE = 1): A/D-converted value &lt; ADCMPDR0 value, or ADCMPDR1 value &lt; A/D-converted value </description>
                                    <value>#0</value>
                                </enumeratedValue>
                                <enumeratedValue>
                                    <name>1</name>
                                    <description>When window function is disabled (ADCMPCR.WCMPE = 0): ADCMPDR0 value &lt; A/D-converted value When window function is enabled (ADCMPCR.WCMPE = 1): ADCMPDR0 value &lt; A/D-converted value &lt; ADCMPDR1 value </description>
                                    <value>#1</value>
                                </enumeratedValue>
                            </enumeratedValues>
                        </field>
                        <field>
                            <name>CMPLCHA10</name>
                            <description>Compare Window A Comparison Condition Select</description>
                            <lsb>10</lsb>
                            <msb>10</msb>
                            <access>read-write</access>
                            <enumeratedValues>
                                <enumeratedValue>
                                    <name>0</name>
                                    <description>When window function is disabled (ADCMPCR.WCMPE = 0): ADCMPDR0 value &gt; A/D-converted value When window function is enabled (ADCMPCR.WCMPE = 1): A/D-converted value &lt; ADCMPDR0 value, or ADCMPDR1 value &lt; A/D-converted value </description>
                                    <value>#0</value>
                                </enumeratedValue>
                                <enumeratedValue>
                                    <name>1</name>
                                    <description>When window function is disabled (ADCMPCR.WCMPE = 0): ADCMPDR0 value &lt; A/D-converted value When window function is enabled (ADCMPCR.WCMPE = 1): ADCMPDR0 value &lt; A/D-converted value &lt; ADCMPDR1 value </description>
                                    <value>#1</value>
                                </enumeratedValue>
                            </enumeratedValues>
                        </field>
                        <field>
                            <name>CMPLCHA11</name>
                            <description>Compare Window A Comparison Condition Select</description>
                            <lsb>11</lsb>
                            <msb>11</msb>
                            <access>read-write</access>
                            <enumeratedValues>
                                <enumeratedValue>
                                    <name>0</name>
                                    <description>When window function is disabled (ADCMPCR.WCMPE = 0): ADCMPDR0 value &gt; A/D-converted value When window function is enabled (ADCMPCR.WCMPE = 1): A/D-converted value &lt; ADCMPDR0 value, or ADCMPDR1 value &lt; A/D-converted value </description>
                                    <value>#0</value>
                                </enumeratedValue>
                                <enumeratedValue>
                                    <name>1</name>
                                    <description>When window function is disabled (ADCMPCR.WCMPE = 0): ADCMPDR0 value &lt; A/D-converted value When window function is enabled (ADCMPCR.WCMPE = 1): ADCMPDR0 value &lt; A/D-converted value &lt; ADCMPDR1 value </description>
                                    <value>#1</value>
                                </enumeratedValue>
                            </enumeratedValues>
                        </field>
                        <field>
                            <name>CMPLCHA12</name>
                            <description>Compare Window A Comparison Condition Select</description>
                            <lsb>12</lsb>
                            <msb>12</msb>
                            <access>read-write</access>
                            <enumeratedValues>
                                <enumeratedValue>
                                    <name>0</name>
                                    <description>When window function is disabled (ADCMPCR.WCMPE = 0): ADCMPDR0 value &gt; A/D-converted value When window function is enabled (ADCMPCR.WCMPE = 1): A/D-converted value &lt; ADCMPDR0 value, or ADCMPDR1 value &lt; A/D-converted value </description>
                                    <value>#0</value>
                                </enumeratedValue>
                                <enumeratedValue>
                                    <name>1</name>
                                    <description>When window function is disabled (ADCMPCR.WCMPE = 0): ADCMPDR0 value &lt; A/D-converted value When window function is enabled (ADCMPCR.WCMPE = 1): ADCMPDR0 value &lt; A/D-converted value &lt; ADCMPDR1 value </description>
                                    <value>#1</value>
                                </enumeratedValue>
                            </enumeratedValues>
                        </field>
                        <field>
                            <name>CMPLCHA13</name>
                            <description>Compare Window A Comparison Condition Select</description>
                            <lsb>13</lsb>
                            <msb>13</msb>
                            <access>read-write</access>
                            <enumeratedValues>
                                <enumeratedValue>
                                    <name>0</name>
                                    <description>When window function is disabled (ADCMPCR.WCMPE = 0): ADCMPDR0 value &gt; A/D-converted value When window function is enabled (ADCMPCR.WCMPE = 1): A/D-converted value &lt; ADCMPDR0 value, or ADCMPDR1 value &lt; A/D-converted value </description>
                                    <value>#0</value>
                                </enumeratedValue>
                                <enumeratedValue>
                                    <name>1</name>
                                    <description>When window function is disabled (ADCMPCR.WCMPE = 0): ADCMPDR0 value &lt; A/D-converted value When window function is enabled (ADCMPCR.WCMPE = 1): ADCMPDR0 value &lt; A/D-converted value &lt; ADCMPDR1 value </description>
                                    <value>#1</value>
                                </enumeratedValue>
                            </enumeratedValues>
                        </field>
                        <field>
                            <name>CMPLCHA14</name>
                            <description>Compare Window A Comparison Condition Select</description>
                            <lsb>14</lsb>
                            <msb>14</msb>
                            <access>read-write</access>
                            <enumeratedValues>
                                <enumeratedValue>
                                    <name>0</name>
                                    <description>When window function is disabled (ADCMPCR.WCMPE = 0): ADCMPDR0 value &gt; A/D-converted value When window function is enabled (ADCMPCR.WCMPE = 1): A/D-converted value &lt; ADCMPDR0 value, or ADCMPDR1 value &lt; A/D-converted value </description>
                                    <value>#0</value>
                                </enumeratedValue>
                                <enumeratedValue>
                                    <name>1</name>
                                    <description>When window function is disabled (ADCMPCR.WCMPE = 0): ADCMPDR0 value &lt; A/D-converted value When window function is enabled (ADCMPCR.WCMPE = 1): ADCMPDR0 value &lt; A/D-converted value &lt; ADCMPDR1 value </description>
                                    <value>#1</value>
                                </enumeratedValue>
                            </enumeratedValues>
                        </field>
                        <field>
                            <name>CMPLCHA15</name>
                            <description>Compare Window A Comparison Condition Select</description>
                            <lsb>15</lsb>
                            <msb>15</msb>
                            <access>read-write</access>
                            <enumeratedValues>
                                <enumeratedValue>
                                    <name>0</name>
                                    <description>When window function is disabled (ADCMPCR.WCMPE = 0): ADCMPDR0 value &gt; A/D-converted value When window function is enabled (ADCMPCR.WCMPE = 1): A/D-converted value &lt; ADCMPDR0 value, or ADCMPDR1 value &lt; A/D-converted value </description>
                                    <value>#0</value>
                                </enumeratedValue>
                                <enumeratedValue>
                                    <name>1</name>
                                    <description>When window function is disabled (ADCMPCR.WCMPE = 0): ADCMPDR0 value &lt; A/D-converted value When window function is enabled (ADCMPCR.WCMPE = 1): ADCMPDR0 value &lt; A/D-converted value &lt; ADCMPDR1 value </description>
                                    <value>#1</value>
                                </enumeratedValue>
                            </enumeratedValues>
                        </field>
                    </fields>
                </register>
                <register>
                    <dim>2</dim>
                    <dimIncrement>0x2</dimIncrement>
                    <dimIndex>0-1</dimIndex>
                    <name>ADCMPDR%s</name>
                    <description>A/D Compare Function Window A Lower-Side/Upper-Side Level Setting Register</description>
                    <addressOffset>0x09C</addressOffset>
                    <size>16</size>
                    <access>read-write</access>
                    <resetValue>0x0000</resetValue>
                    <resetMask>0xffff</resetMask>
                </register>
                <register>
                    <name>ADCMPSR0</name>
                    <description>A/D Compare Function Window A Channel Status Register 0</description>
                    <addressOffset>0x0A0</addressOffset>
                    <size>16</size>
                    <access>read-write</access>
                    <resetValue>0x0000</resetValue>
                    <resetMask>0xffff</resetMask>
                    <fields>
                        <field>
                            <name>CMPSTCHA00</name>
                            <description>Compare Window A Flag</description>
                            <lsb>0</lsb>
                            <msb>0</msb>
                            <access>read-write</access>
                            <enumeratedValues>
                                <enumeratedValue>
                                    <name>0</name>
                                    <description>Comparison conditions are not met.</description>
                                    <value>#0</value>
                                </enumeratedValue>
                                <enumeratedValue>
                                    <name>1</name>
                                    <description>Comparison conditions are met.</description>
                                    <value>#1</value>
                                </enumeratedValue>
                            </enumeratedValues>
                        </field>
                        <field>
                            <name>CMPSTCHA01</name>
                            <description>Compare Window A Flag</description>
                            <lsb>1</lsb>
                            <msb>1</msb>
                            <access>read-write</access>
                            <enumeratedValues>
                                <enumeratedValue>
                                    <name>0</name>
                                    <description>Comparison conditions are not met.</description>
                                    <value>#0</value>
                                </enumeratedValue>
                                <enumeratedValue>
                                    <name>1</name>
                                    <description>Comparison conditions are met.</description>
                                    <value>#1</value>
                                </enumeratedValue>
                            </enumeratedValues>
                        </field>
                        <field>
                            <name>CMPSTCHA02</name>
                            <description>Compare Window A Flag</description>
                            <lsb>2</lsb>
                            <msb>2</msb>
                            <access>read-write</access>
                            <enumeratedValues>
                                <enumeratedValue>
                                    <name>0</name>
                                    <description>Comparison conditions are not met.</description>
                                    <value>#0</value>
                                </enumeratedValue>
                                <enumeratedValue>
                                    <name>1</name>
                                    <description>Comparison conditions are met.</description>
                                    <value>#1</value>
                                </enumeratedValue>
                            </enumeratedValues>
                        </field>
                        <field>
                            <name>CMPSTCHA03</name>
                            <description>Compare Window A Flag</description>
                            <lsb>3</lsb>
                            <msb>3</msb>
                            <access>read-write</access>
                            <enumeratedValues>
                                <enumeratedValue>
                                    <name>0</name>
                                    <description>Comparison conditions are not met.</description>
                                    <value>#0</value>
                                </enumeratedValue>
                                <enumeratedValue>
                                    <name>1</name>
                                    <description>Comparison conditions are met.</description>
                                    <value>#1</value>
                                </enumeratedValue>
                            </enumeratedValues>
                        </field>
                        <field>
                            <name>CMPSTCHA04</name>
                            <description>Compare Window A Flag</description>
                            <lsb>4</lsb>
                            <msb>4</msb>
                            <access>read-write</access>
                            <enumeratedValues>
                                <enumeratedValue>
                                    <name>0</name>
                                    <description>Comparison conditions are not met.</description>
                                    <value>#0</value>
                                </enumeratedValue>
                                <enumeratedValue>
                                    <name>1</name>
                                    <description>Comparison conditions are met.</description>
                                    <value>#1</value>
                                </enumeratedValue>
                            </enumeratedValues>
                        </field>
                        <field>
                            <name>CMPSTCHA05</name>
                            <description>Compare Window A Flag</description>
                            <lsb>5</lsb>
                            <msb>5</msb>
                            <access>read-write</access>
                            <enumeratedValues>
                                <enumeratedValue>
                                    <name>0</name>
                                    <description>Comparison conditions are not met.</description>
                                    <value>#0</value>
                                </enumeratedValue>
                                <enumeratedValue>
                                    <name>1</name>
                                    <description>Comparison conditions are met.</description>
                                    <value>#1</value>
                                </enumeratedValue>
                            </enumeratedValues>
                        </field>
                        <field>
                            <name>CMPSTCHA06</name>
                            <description>Compare Window A Flag</description>
                            <lsb>6</lsb>
                            <msb>6</msb>
                            <access>read-write</access>
                            <enumeratedValues>
                                <enumeratedValue>
                                    <name>0</name>
                                    <description>Comparison conditions are not met.</description>
                                    <value>#0</value>
                                </enumeratedValue>
                                <enumeratedValue>
                                    <name>1</name>
                                    <description>Comparison conditions are met.</description>
                                    <value>#1</value>
                                </enumeratedValue>
                            </enumeratedValues>
                        </field>
                        <field>
                            <name>CMPSTCHA07</name>
                            <description>Compare Window A Flag</description>
                            <lsb>7</lsb>
                            <msb>7</msb>
                            <access>read-write</access>
                            <enumeratedValues>
                                <enumeratedValue>
                                    <name>0</name>
                                    <description>Comparison conditions are not met.</description>
                                    <value>#0</value>
                                </enumeratedValue>
                                <enumeratedValue>
                                    <name>1</name>
                                    <description>Comparison conditions are met.</description>
                                    <value>#1</value>
                                </enumeratedValue>
                            </enumeratedValues>
                        </field>
                        <field>
                            <name>CMPSTCHA08</name>
                            <description>Compare Window A Flag</description>
                            <lsb>8</lsb>
                            <msb>8</msb>
                            <access>read-write</access>
                            <enumeratedValues>
                                <enumeratedValue>
                                    <name>0</name>
                                    <description>Comparison conditions are not met.</description>
                                    <value>#0</value>
                                </enumeratedValue>
                                <enumeratedValue>
                                    <name>1</name>
                                    <description>Comparison conditions are met.</description>
                                    <value>#1</value>
                                </enumeratedValue>
                            </enumeratedValues>
                        </field>
                        <field>
                            <name>CMPSTCHA09</name>
                            <description>Compare Window A Flag</description>
                            <lsb>9</lsb>
                            <msb>9</msb>
                            <access>read-write</access>
                            <enumeratedValues>
                                <enumeratedValue>
                                    <name>0</name>
                                    <description>Comparison conditions are not met.</description>
                                    <value>#0</value>
                                </enumeratedValue>
                                <enumeratedValue>
                                    <name>1</name>
                                    <description>Comparison conditions are met.</description>
                                    <value>#1</value>
                                </enumeratedValue>
                            </enumeratedValues>
                        </field>
                        <field>
                            <name>CMPSTCHA10</name>
                            <description>Compare Window A Flag</description>
                            <lsb>10</lsb>
                            <msb>10</msb>
                            <access>read-write</access>
                            <enumeratedValues>
                                <enumeratedValue>
                                    <name>0</name>
                                    <description>Comparison conditions are not met.</description>
                                    <value>#0</value>
                                </enumeratedValue>
                                <enumeratedValue>
                                    <name>1</name>
                                    <description>Comparison conditions are met.</description>
                                    <value>#1</value>
                                </enumeratedValue>
                            </enumeratedValues>
                        </field>
                        <field>
                            <name>CMPSTCHA11</name>
                            <description>Compare Window A Flag</description>
                            <lsb>11</lsb>
                            <msb>11</msb>
                            <access>read-write</access>
                            <enumeratedValues>
                                <enumeratedValue>
                                    <name>0</name>
                                    <description>Comparison conditions are not met.</description>
                                    <value>#0</value>
                                </enumeratedValue>
                                <enumeratedValue>
                                    <name>1</name>
                                    <description>Comparison conditions are met.</description>
                                    <value>#1</value>
                                </enumeratedValue>
                            </enumeratedValues>
                        </field>
                        <field>
                            <name>CMPSTCHA12</name>
                            <description>Compare Window A Flag</description>
                            <lsb>12</lsb>
                            <msb>12</msb>
                            <access>read-write</access>
                            <enumeratedValues>
                                <enumeratedValue>
                                    <name>0</name>
                                    <description>Comparison conditions are not met.</description>
                                    <value>#0</value>
                                </enumeratedValue>
                                <enumeratedValue>
                                    <name>1</name>
                                    <description>Comparison conditions are met.</description>
                                    <value>#1</value>
                                </enumeratedValue>
                            </enumeratedValues>
                        </field>
                        <field>
                            <name>CMPSTCHA13</name>
                            <description>Compare Window A Flag</description>
                            <lsb>13</lsb>
                            <msb>13</msb>
                            <access>read-write</access>
                            <enumeratedValues>
                                <enumeratedValue>
                                    <name>0</name>
                                    <description>Comparison conditions are not met.</description>
                                    <value>#0</value>
                                </enumeratedValue>
                                <enumeratedValue>
                                    <name>1</name>
                                    <description>Comparison conditions are met.</description>
                                    <value>#1</value>
                                </enumeratedValue>
                            </enumeratedValues>
                        </field>
                        <field>
                            <name>CMPSTCHA14</name>
                            <description>Compare Window A Flag</description>
                            <lsb>14</lsb>
                            <msb>14</msb>
                            <access>read-write</access>
                            <enumeratedValues>
                                <enumeratedValue>
                                    <name>0</name>
                                    <description>Comparison conditions are not met.</description>
                                    <value>#0</value>
                                </enumeratedValue>
                                <enumeratedValue>
                                    <name>1</name>
                                    <description>Comparison conditions are met.</description>
                                    <value>#1</value>
                                </enumeratedValue>
                            </enumeratedValues>
                        </field>
                        <field>
                            <name>CMPSTCHA15</name>
                            <description>Compare Window A Flag</description>
                            <lsb>15</lsb>
                            <msb>15</msb>
                            <access>read-write</access>
                            <enumeratedValues>
                                <enumeratedValue>
                                    <name>0</name>
                                    <description>Comparison conditions are not met.</description>
                                    <value>#0</value>
                                </enumeratedValue>
                                <enumeratedValue>
                                    <name>1</name>
                                    <description>Comparison conditions are met.</description>
                                    <value>#1</value>
                                </enumeratedValue>
                            </enumeratedValues>
                        </field>
                    </fields>
                </register>
                <register>
                    <name>ADCMPSER</name>
                    <description>A/D Compare Function Window A Extended Input Channel Status Register</description>
                    <addressOffset>0x0A4</addressOffset>
                    <size>8</size>
                    <access>read-write</access>
                    <resetValue>0x00</resetValue>
                    <resetMask>0xff</resetMask>
                    <fields>
                        <field>
                            <name>CMPSTTSA</name>
                            <description>Compare Window A Temperature Sensor Output Compare Flag</description>
                            <lsb>0</lsb>
                            <msb>0</msb>
                            <access>read-write</access>
                            <enumeratedValues>
                                <enumeratedValue>
                                    <name>0</name>
                                    <description>Comparison conditions are not met.</description>
                                    <value>#0</value>
                                </enumeratedValue>
                                <enumeratedValue>
                                    <name>1</name>
                                    <description>Comparison conditions are met.</description>
                                    <value>#1</value>
                                </enumeratedValue>
                            </enumeratedValues>
                        </field>
                        <field>
                            <name>CMPSTOCA</name>
                            <description>Compare Window A Internal Reference Voltage Compare Flag</description>
                            <lsb>1</lsb>
                            <msb>1</msb>
                            <access>read-write</access>
                            <enumeratedValues>
                                <enumeratedValue>
                                    <name>0</name>
                                    <description>Comparison conditions are not met.</description>
                                    <value>#0</value>
                                </enumeratedValue>
                                <enumeratedValue>
                                    <name>1</name>
                                    <description>Comparison conditions are met.</description>
                                    <value>#1</value>
                                </enumeratedValue>
                            </enumeratedValues>
                        </field>
                    </fields>
                </register>
                <register>
                    <name>ADCMPBNSR</name>
                    <description>A/D Compare Function Window B Channel Select Register</description>
                    <addressOffset>0x0A6</addressOffset>
                    <size>8</size>
                    <access>read-write</access>
                    <resetValue>0x00</resetValue>
                    <resetMask>0xff</resetMask>
                    <fields>
                        <field>
                            <name>CMPCHB</name>
                            <description>Compare Window B Channel Select</description>
                            <lsb>0</lsb>
                            <msb>5</msb>
                            <access>read-write</access>
                        </field>
                        <field>
                            <name>CMPLB</name>
                            <description>Compare Window B Comparison Condition Setting</description>
                            <lsb>7</lsb>
                            <msb>7</msb>
                            <access>read-write</access>
                            <enumeratedValues>
                                <enumeratedValue>
                                    <name>0</name>
                                    <description>When window function is disabled (ADCMPCR.WCMPE = 0): ADWINLLB value &gt; A/D-converted value When window function is enabled (ADCMPCR.WCMPE = 1): A/D-converted value &lt; ADWINLLB value, or ADWINULB value &lt; A/D-converted value </description>
                                    <value>#0</value>
                                </enumeratedValue>
                                <enumeratedValue>
                                    <name>1</name>
                                    <description>When window function is disabled (ADCMPCR.WCMPE = 0): ADWINLLB value &lt; A/D-converted value When window function is enabled (ADCMPCR.WCMPE = 1): ADWINLLB value &lt; A/D-converted value &lt; ADWINULB value </description>
                                    <value>#1</value>
                                </enumeratedValue>
                            </enumeratedValues>
                        </field>
                    </fields>
                </register>
                <register>
                    <name>ADWINLLB</name>
                    <description>A/D Compare Function Window B Lower-Side/Upper-Side Level Setting Register</description>
                    <addressOffset>0x0A8</addressOffset>
                    <size>16</size>
                    <access>read-write</access>
                    <resetValue>0x0000</resetValue>
                    <resetMask>0xffff</resetMask>
                </register>
                <register>
                    <name>ADWINULB</name>
                    <description>A/D Compare Function Window B Lower-Side/Upper-Side Level Setting Register</description>
                    <addressOffset>0x0AA</addressOffset>
                    <size>16</size>
                    <access>read-write</access>
                    <resetValue>0x0000</resetValue>
                    <resetMask>0xffff</resetMask>
                </register>
                <register>
                    <name>ADCMPBSR</name>
                    <description>A/D Compare Function Window B Status Register</description>
                    <addressOffset>0x0AC</addressOffset>
                    <size>8</size>
                    <access>read-write</access>
                    <resetValue>0x00</resetValue>
                    <resetMask>0xff</resetMask>
                    <fields>
                        <field>
                            <name>CMPSTB</name>
                            <description>Compare Window B Flag</description>
                            <lsb>0</lsb>
                            <msb>0</msb>
                            <access>read-write</access>
                            <enumeratedValues>
                                <enumeratedValue>
                                    <name>0</name>
                                    <description>Comparison conditions are not met.</description>
                                    <value>#0</value>
                                </enumeratedValue>
                                <enumeratedValue>
                                    <name>1</name>
                                    <description>Comparison conditions are met.</description>
                                    <value>#1</value>
                                </enumeratedValue>
                            </enumeratedValues>
                        </field>
                    </fields>
                </register>
                <register>
                    <dim>16</dim>
                    <dimIncrement>0x2</dimIncrement>
                    <dimIndex>0-15</dimIndex>
                    <name>ADBUF%s</name>
                    <description>A/D Data Buffer Registers %s</description>
                    <addressOffset>0x0B0</addressOffset>
                    <size>16</size>
                    <access>read-only</access>
                    <resetValue>0x0000</resetValue>
                    <resetMask>0xffff</resetMask>
                    <fields>
                        <field>
                            <name>ADBUF</name>
                            <description>Converted Value 15 to 0</description>
                            <lsb>0</lsb>
                            <msb>15</msb>
                            <access>read-only</access>
                        </field>
                    </fields>
                </register>
                <register>
                    <name>ADBUFEN</name>
                    <description>A/D Data Buffer Enable Register</description>
                    <addressOffset>0x0D0</addressOffset>
                    <size>8</size>
                    <access>read-write</access>
                    <resetValue>0x00</resetValue>
                    <resetMask>0xff</resetMask>
                    <fields>
                        <field>
                            <name>BUFEN</name>
                            <description>Data Buffer Enable</description>
                            <lsb>0</lsb>
                            <msb>0</msb>
                            <access>read-write</access>
                            <enumeratedValues>
                                <enumeratedValue>
                                    <name>0</name>
                                    <description>The data buffer is not used.</description>
                                    <value>#0</value>
                                </enumeratedValue>
                                <enumeratedValue>
                                    <name>1</name>
                                    <description>The data buffer is used.</description>
                                    <value>#1</value>
                                </enumeratedValue>
                            </enumeratedValues>
                        </field>
                    </fields>
                </register>
                <register>
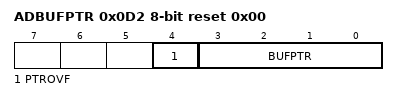
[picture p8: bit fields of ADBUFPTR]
                    <name>ADBUFPTR</name>
                    <description>A/D Data Buffer Pointer Register</description>
                    <addressOffset>0x0D2</addressOffset>
                    <size>8</size>
                    <access>read-write</access>
                    <resetValue>0x00</resetValue>
                    <resetMask>0xff</resetMask>
                    <fields>
                        <field>
                            <name>BUFPTR</name>
                            <description>Data Buffer Pointer</description>
                            <lsb>0</lsb>
                            <msb>3</msb>
                            <access>read-write</access>
                        </field>
                        <field>
                            <name>PTROVF</name>
                            <description>Pointer Overflow Flag</description>
                            <lsb>4</lsb>
                            <msb>4</msb>
                            <access>read-write</access>
                            <enumeratedValues>
                                <enumeratedValue>
                                    <name>0</name>
                                    <description>The data buffer pointer has not overflowed.</description>
                                    <value>#0</value>
                                </enumeratedValue>
                                <enumeratedValue>
                                    <name>1</name>
                                    <description>The data buffer pointer has overflowed.</description>
                                    <value>#1</value>
                                </enumeratedValue>
                            </enumeratedValues>
                        </field>
                    </fields>
                </register>
                <register>
                    <name>ADSSTRL</name>
                    <description>A/D Sampling State Register</description>
                    <addressOffset>0x0DD</addressOffset>
                    <size>8</size>
                    <access>read-write</access>
                    <resetValue>0x0b</resetValue>
                    <resetMask>0xff</resetMask>
                    <fields>
                        <field>
                            <name>SST</name>
                            <description>Sampling Time Setting</description>
                            <lsb>0</lsb>
                            <msb>7</msb>
                            <access>read-write</access>
                        </field>
                    </fields>
                </register>
                <register>
                    <name>ADSSTRT</name>
                    <description>A/D Sampling State Register</description>
                    <addressOffset>0x0DE</addressOffset>
                    <size>8</size>
                    <access>read-write</access>
                    <resetValue>0x0b</resetValue>
                    <resetMask>0xff</resetMask>
                    <fields>
                        <field>
                            <name>SST</name>
                            <description>Sampling Time Setting</description>
                            <lsb>0</lsb>
                            <msb>7</msb>
                            <access>read-write</access>
                        </field>
                    </fields>
                </register>
                <register>
                    <name>ADSSTRO</name>
                    <description>A/D Sampling State Register</description>
                    <addressOffset>0x0DF</addressOffset>
                    <size>8</size>
                    <access>read-write</access>
                    <resetValue>0x0b</resetValue>
                    <resetMask>0xff</resetMask>
                    <fields>
                        <field>
                            <name>SST</name>
                            <description>Sampling Time Setting</description>
                            <lsb>0</lsb>
                            <msb>7</msb>
                            <access>read-write</access>
                        </field>
                    </fields>
                </register>
                <register>
                    <dim>9</dim>
                    <dimIncrement>0x1</dimIncrement>
                    <dimIndex>0-8</dimIndex>
                    <name>ADSSTR%s</name>
                    <description>A/D Sampling State Register</description>
                    <addressOffset>0x0E0</addressOffset>
                    <size>8</size>
                    <access>read-write</access>
                    <resetValue>0x0b</resetValue>
                    <resetMask>0xff</resetMask>
                    <fields>
                        <field>
                            <name>SST</name>
                            <description>Sampling Time Setting</description>
                            <lsb>0</lsb>
                            <msb>7</msb>
                            <access>read-write</access>
                        </field>
                    </fields>
                </register>
                <register>
                    <name>ADSSTRV</name>
                    <description>A/D Sampling State Register</description>
                    <addressOffset>0x0E3</addressOffset>
                    <size>8</size>
                    <access>read-write</access>
                    <resetValue>0x0b</resetValue>
                    <resetMask>0xff</resetMask>
                    <fields>
                        <field>
                            <name>SST</name>
                            <description>Sampling Time Setting</description>
                            <lsb>0</lsb>
                            <msb>7</msb>
                            <access>read-write</access>
                        </field>
                    </fields>
                </register>
                <register>
                    <dim>4</dim>
                    <dimIncrement>0x1</dimIncrement>
                    <dimIndex>16-19</dimIndex>
                    <name>ADSSTR%s</name>
                    <description>A/D Sampling State Register</description>
                    <addressOffset>0x0EC</addressOffset>
                    <size>8</size>
                    <access>read-write</access>
                    <resetValue>0x0b</resetValue>
                    <resetMask>0xff</resetMask>
                    <fields>
                        <field>
                            <name>SST</name>
                            <description>Sampling Time Setting</description>
                            <lsb>0</lsb>
                            <msb>7</msb>
                            <access>read-write</access>
                        </field>
                    </fields>
                </register>
            </registers>
        </peripheral>
        <peripheral>
            <name>ADC121_NS</name>
            <description>12-bit A/D Converter 1</description>
            <baseAddress>0x50332200</baseAddress>
            <addressBlock>
                <offset>0x00</offset>
                <size>2</size>
                <usage>registers</usage>
            </addressBlock>
            <addressBlock>
                <offset>0x04</offset>
                <size>9</size>
                <usage>registers</usage>
            </addressBlock>
            <addressBlock>
                <offset>0x0E</offset>
                <size>32</size>
                <usage>registers</usage>
            </addressBlock>
            <addressBlock>
                <offset>0x66</offset>
                <size>2</size>
                <usage>registers</usage>
            </addressBlock>
            <addressBlock>
                <offset>0x7A</offset>
                <size>1</size>
                <usage>registers</usage>
            </addressBlock>
            <addressBlock>
                <offset>0x7C</offset>
                <size>1</size>
                <usage>registers</usage>
            </addressBlock>
            <addressBlock>
                <offset>0x80</offset>
                <size>2</size>
                <usage>registers</usage>
            </addressBlock>
            <addressBlock>
                <offset>0x84</offset>
                <size>4</size>
                <usage>registers</usage>
            </addressBlock>
            <addressBlock>
                <offset>0x8C</offset>
                <size>1</size>
                <usage>registers</usage>
            </addressBlock>
            <addressBlock>
                <offset>0x90</offset>
                <size>6</size>
                <usage>registers</usage>
            </addressBlock>
            <addressBlock>
                <offset>0x98</offset>
                <size>2</size>
                <usage>registers</usage>
            </addressBlock>
            <addressBlock>
                <offset>0x9C</offset>
                <size>6</size>
                <usage>registers</usage>
            </addressBlock>
            <addressBlock>
                <offset>0xA4</offset>
                <size>1</size>
                <usage>registers</usage>
            </addressBlock>
            <addressBlock>
                <offset>0xA6</offset>
                <size>1</size>
                <usage>registers</usage>
            </addressBlock>
            <addressBlock>
                <offset>0xA8</offset>
                <size>5</size>
                <usage>registers</usage>
            </addressBlock>
            <addressBlock>
                <offset>0xB0</offset>
                <size>33</size>
                <usage>registers</usage>
            </addressBlock>
            <addressBlock>
                <offset>0xD2</offset>
                <size>1</size>
                <usage>registers</usage>
            </addressBlock>
            <addressBlock>
                <offset>0xDD</offset>
                <size>10</size>
                <usage>registers</usage>
            </addressBlock>
            <registers>
                <register>
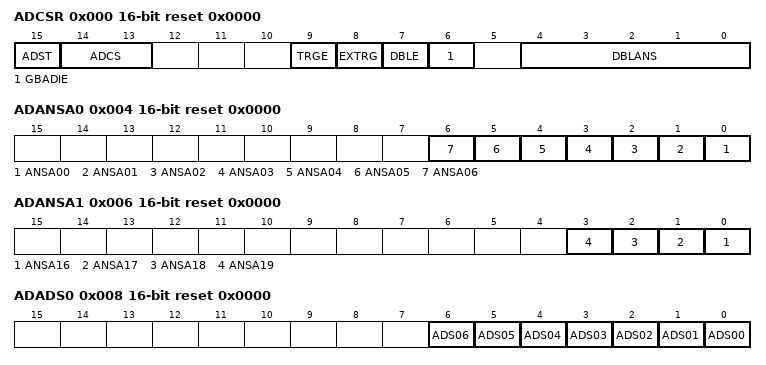
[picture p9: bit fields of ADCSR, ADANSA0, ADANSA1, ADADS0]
                    <name>ADCSR</name>
                    <description>A/D Control Register</description>
                    <addressOffset>0x000</addressOffset>
                    <size>16</size>
                    <access>read-write</access>
                    <resetValue>0x0000</resetValue>
                    <resetMask>0xffff</resetMask>
                    <fields>
                        <field>
                            <name>DBLANS</name>
                            <description>Double Trigger Channel Select</description>
                            <lsb>0</lsb>
                            <msb>4</msb>
                            <access>read-write</access>
                        </field>
                        <field>
                            <name>GBADIE</name>
                            <description>Group B Scan End Interrupt and ELC Event Enable</description>
                            <lsb>6</lsb>
                            <msb>6</msb>
                            <access>read-write</access>
                            <enumeratedValues>
                                <enumeratedValue>
                                    <name>0</name>
                                    <description>Disable ADC12i_GBADI (i = 0, 1) interrupt generation on group B scan completion.</description>
                                    <value>#0</value>
                                </enumeratedValue>
                                <enumeratedValue>
                                    <name>1</name>
                                    <description>Enable ADC12i_GBADI (i = 0, 1) interrupt generation on group B scan completion.</description>
                                    <value>#1</value>
                                </enumeratedValue>
                            </enumeratedValues>
                        </field>
                        <field>
                            <name>DBLE</name>
                            <description>Double Trigger Mode Select</description>
                            <lsb>7</lsb>
                            <msb>7</msb>
                            <access>read-write</access>
                            <enumeratedValues>
                                <enumeratedValue>
                                    <name>0</name>
                                    <description>Deselect double-trigger mode.</description>
                                    <value>#0</value>
                                </enumeratedValue>
                                <enumeratedValue>
                                    <name>1</name>
                                    <description>Select double-trigger mode.</description>
                                    <value>#1</value>
                                </enumeratedValue>
                            </enumeratedValues>
                        </field>
                        <field>
                            <name>EXTRG</name>
                            <description>Trigger Select</description>
                            <lsb>8</lsb>
                            <msb>8</msb>
                            <access>read-write</access>
                            <enumeratedValues>
                                <enumeratedValue>
                                    <name>0</name>
                                    <description>Start A/D conversion by the synchronous trigger (GPT, ELC).</description>
                                    <value>#0</value>
                                </enumeratedValue>
                                <enumeratedValue>
                                    <name>1</name>
                                    <description>Start A/D conversion by the asynchronous trigger (ADTRGn).</description>
                                    <value>#1</value>
                                </enumeratedValue>
                            </enumeratedValues>
                        </field>
                        <field>
                            <name>TRGE</name>
                            <description>Trigger Start Enable</description>
                            <lsb>9</lsb>
                            <msb>9</msb>
                            <access>read-write</access>
                            <enumeratedValues>
                                <enumeratedValue>
                                    <name>0</name>
                                    <description>Disable A/D conversion to be started by the synchronous or asynchronous trigger</description>
                                    <value>#0</value>
                                </enumeratedValue>
                                <enumeratedValue>
                                    <name>1</name>
                                    <description>Enable A/D conversion to be started by the synchronous or asynchronous trigger</description>
                                    <value>#1</value>
                                </enumeratedValue>
                            </enumeratedValues>
                        </field>
                        <field>
                            <name>ADCS</name>
                            <description>Scan Mode Select</description>
                            <lsb>13</lsb>
                            <msb>14</msb>
                            <access>read-write</access>
                            <enumeratedValues>
                                <enumeratedValue>
                                    <name>00</name>
                                    <description>Single scan mode</description>
                                    <value>#00</value>
                                </enumeratedValue>
                                <enumeratedValue>
                                    <name>01</name>
                                    <description>Group scan mode</description>
                                    <value>#01</value>
                                </enumeratedValue>
                                <enumeratedValue>
                                    <name>10</name>
                                    <description>Continuous scan mode</description>
                                    <value>#10</value>
                                </enumeratedValue>
                                <enumeratedValue>
                                    <name>11</name>
                                    <description>Setting prohibited</description>
                                    <value>#11</value>
                                </enumeratedValue>
                            </enumeratedValues>
                        </field>
                        <field>
                            <name>ADST</name>
                            <description>A/D Conversion Start</description>
                            <lsb>15</lsb>
                            <msb>15</msb>
                            <access>read-write</access>
                            <enumeratedValues>
                                <enumeratedValue>
                                    <name>0</name>
                                    <description>Stop A/D conversion process.</description>
                                    <value>#0</value>
                                </enumeratedValue>
                                <enumeratedValue>
                                    <name>1</name>
                                    <description>Start A/D conversion process.</description>
                                    <value>#1</value>
                                </enumeratedValue>
                            </enumeratedValues>
                        </field>
                    </fields>
                </register>
                <register>
                    <name>ADANSA0</name>
                    <description>A/D Channel Select Register A0</description>
                    <addressOffset>0x004</addressOffset>
                    <size>16</size>
                    <access>read-write</access>
                    <resetValue>0x0000</resetValue>
                    <resetMask>0xffff</resetMask>
                    <fields>
                        <field>
                            <name>ANSA00</name>
                            <description>A/D Conversion Channels Select</description>
                            <lsb>0</lsb>
                            <msb>0</msb>
                            <access>read-write</access>
                            <enumeratedValues>
                                <enumeratedValue>
                                    <name>0</name>
                                    <description>Do not select associated input channel.</description>
                                    <value>#0</value>
                                </enumeratedValue>
                                <enumeratedValue>
                                    <name>1</name>
                                    <description>Select associated input channel. </description>
                                    <value>#1</value>
                                </enumeratedValue>
                            </enumeratedValues>
                        </field>
                        <field>
                            <name>ANSA01</name>
                            <description>A/D Conversion Channels Select</description>
                            <lsb>1</lsb>
                            <msb>1</msb>
                            <access>read-write</access>
                            <enumeratedValues>
                                <enumeratedValue>
                                    <name>0</name>
                                    <description>Do not select associated input channel.</description>
                                    <value>#0</value>
                                </enumeratedValue>
                                <enumeratedValue>
                                    <name>1</name>
                                    <description>Select associated input channel. </description>
                                    <value>#1</value>
                                </enumeratedValue>
                            </enumeratedValues>
                        </field>
                        <field>
                            <name>ANSA02</name>
                            <description>A/D Conversion Channels Select</description>
                            <lsb>2</lsb>
                            <msb>2</msb>
                            <access>read-write</access>
                            <enumeratedValues>
                                <enumeratedValue>
                                    <name>0</name>
                                    <description>Do not select associated input channel.</description>
                                    <value>#0</value>
                                </enumeratedValue>
                                <enumeratedValue>
                                    <name>1</name>
                                    <description>Select associated input channel. </description>
                                    <value>#1</value>
                                </enumeratedValue>
                            </enumeratedValues>
                        </field>
                        <field>
                            <name>ANSA03</name>
                            <description>A/D Conversion Channels Select</description>
                            <lsb>3</lsb>
                            <msb>3</msb>
                            <access>read-write</access>
                            <enumeratedValues>
                                <enumeratedValue>
                                    <name>0</name>
                                    <description>Do not select associated input channel.</description>
                                    <value>#0</value>
                                </enumeratedValue>
                                <enumeratedValue>
                                    <name>1</name>
                                    <description>Select associated input channel. </description>
                                    <value>#1</value>
                                </enumeratedValue>
                            </enumeratedValues>
                        </field>
                        <field>
                            <name>ANSA04</name>
                            <description>A/D Conversion Channels Select</description>
                            <lsb>4</lsb>
                            <msb>4</msb>
                            <access>read-write</access>
                            <enumeratedValues>
                                <enumeratedValue>
                                    <name>0</name>
                                    <description>Do not select associated input channel.</description>
                                    <value>#0</value>
                                </enumeratedValue>
                                <enumeratedValue>
                                    <name>1</name>
                                    <description>Select associated input channel. </description>
                                    <value>#1</value>
                                </enumeratedValue>
                            </enumeratedValues>
                        </field>
                        <field>
                            <name>ANSA05</name>
                            <description>A/D Conversion Channels Select</description>
                            <lsb>5</lsb>
                            <msb>5</msb>
                            <access>read-write</access>
                            <enumeratedValues>
                                <enumeratedValue>
                                    <name>0</name>
                                    <description>Do not select associated input channel.</description>
                                    <value>#0</value>
                                </enumeratedValue>
                                <enumeratedValue>
                                    <name>1</name>
                                    <description>Select associated input channel. </description>
                                    <value>#1</value>
                                </enumeratedValue>
                            </enumeratedValues>
                        </field>
                        <field>
                            <name>ANSA06</name>
                            <description>A/D Conversion Channels Select</description>
                            <lsb>6</lsb>
                            <msb>6</msb>
                            <access>read-write</access>
                            <enumeratedValues>
                                <enumeratedValue>
                                    <name>0</name>
                                    <description>Do not select associated input channel.</description>
                                    <value>#0</value>
                                </enumeratedValue>
                                <enumeratedValue>
                                    <name>1</name>
                                    <description>Select associated input channel. </description>
                                    <value>#1</value>
                                </enumeratedValue>
                            </enumeratedValues>
                        </field>
                    </fields>
                </register>
                <register>
                    <name>ADANSA1</name>
                    <description>A/D Channel Select Register A1</description>
                    <addressOffset>0x006</addressOffset>
                    <size>16</size>
                    <access>read-write</access>
                    <resetValue>0x0000</resetValue>
                    <resetMask>0xffff</resetMask>
                    <fields>
                        <field>
                            <name>ANSA16</name>
                            <description>A/D Conversion Channels Select</description>
                            <lsb>0</lsb>
                            <msb>0</msb>
                            <access>read-write</access>
                            <enumeratedValues>
                                <enumeratedValue>
                                    <name>0</name>
                                    <description>Do not select associated input channel.</description>
                                    <value>#0</value>
                                </enumeratedValue>
                                <enumeratedValue>
                                    <name>1</name>
                                    <description>Select associated input channel. </description>
                                    <value>#1</value>
                                </enumeratedValue>
                            </enumeratedValues>
                        </field>
                        <field>
                            <name>ANSA17</name>
                            <description>A/D Conversion Channels Select</description>
                            <lsb>1</lsb>
                            <msb>1</msb>
                            <access>read-write</access>
                            <enumeratedValues>
                                <enumeratedValue>
                                    <name>0</name>
                                    <description>Do not select associated input channel.</description>
                                    <value>#0</value>
                                </enumeratedValue>
                                <enumeratedValue>
                                    <name>1</name>
                                    <description>Select associated input channel. </description>
                                    <value>#1</value>
                                </enumeratedValue>
                            </enumeratedValues>
                        </field>
                        <field>
                            <name>ANSA18</name>
                            <description>A/D Conversion Channels Select</description>
                            <lsb>2</lsb>
                            <msb>2</msb>
                            <access>read-write</access>
                            <enumeratedValues>
                                <enumeratedValue>
                                    <name>0</name>
                                    <description>Do not select associated input channel.</description>
                                    <value>#0</value>
                                </enumeratedValue>
                                <enumeratedValue>
                                    <name>1</name>
                                    <description>Select associated input channel. </description>
                                    <value>#1</value>
                                </enumeratedValue>
                            </enumeratedValues>
                        </field>
                        <field>
                            <name>ANSA19</name>
                            <description>A/D Conversion Channels Select</description>
                            <lsb>3</lsb>
                            <msb>3</msb>
                            <access>read-write</access>
                            <enumeratedValues>
                                <enumeratedValue>
                                    <name>0</name>
                                    <description>Do not select associated input channel.</description>
                                    <value>#0</value>
                                </enumeratedValue>
                                <enumeratedValue>
                                    <name>1</name>
                                    <description>Select associated input channel. </description>
                                    <value>#1</value>
                                </enumeratedValue>
                            </enumeratedValues>
                        </field>
                    </fields>
                </register>
                <register>
                    <name>ADADS0</name>
                    <description>A/D-Converted Value Addition/Average Channel Select Register 0</description>
                    <addressOffset>0x008</addressOffset>
                    <size>16</size>
                    <access>read-write</access>
                    <resetValue>0x0000</resetValue>
                    <resetMask>0xffff</resetMask>
                    <fields>
                        <field>
                            <name>ADS00</name>
                            <description>A/D-Converted Value Addition/Average Channel Select</description>
                            <lsb>0</lsb>
                            <msb>0</msb>
                            <access>read-write</access>
                            <enumeratedValues>
                                <enumeratedValue>
                                    <name>0</name>
                                    <description>Do not select associated input channel.</description>
                                    <value>#0</value>
                                </enumeratedValue>
                                <enumeratedValue>
                                    <name>1</name>
                                    <description>Select associated input channel. </description>
                                    <value>#1</value>
                                </enumeratedValue>
                            </enumeratedValues>
                        </field>
                        <field>
                            <name>ADS01</name>
                            <description>A/D-Converted Value Addition/Average Channel Select</description>
                            <lsb>1</lsb>
                            <msb>1</msb>
                            <access>read-write</access>
                            <enumeratedValues>
                                <enumeratedValue>
                                    <name>0</name>
                                    <description>Do not select associated input channel.</description>
                                    <value>#0</value>
                                </enumeratedValue>
                                <enumeratedValue>
                                    <name>1</name>
                                    <description>Select associated input channel. </description>
                                    <value>#1</value>
                                </enumeratedValue>
                            </enumeratedValues>
                        </field>
                        <field>
                            <name>ADS02</name>
                            <description>A/D-Converted Value Addition/Average Channel Select</description>
                            <lsb>2</lsb>
                            <msb>2</msb>
                            <access>read-write</access>
                            <enumeratedValues>
                                <enumeratedValue>
                                    <name>0</name>
                                    <description>Do not select associated input channel.</description>
                                    <value>#0</value>
                                </enumeratedValue>
                                <enumeratedValue>
                                    <name>1</name>
                                    <description>Select associated input channel. </description>
                                    <value>#1</value>
                                </enumeratedValue>
                            </enumeratedValues>
                        </field>
                        <field>
                            <name>ADS03</name>
                            <description>A/D-Converted Value Addition/Average Channel Select</description>
                            <lsb>3</lsb>
                            <msb>3</msb>
                            <access>read-write</access>
                            <enumeratedValues>
                                <enumeratedValue>
                                    <name>0</name>
                                    <description>Do not select associated input channel.</description>
                                    <value>#0</value>
                                </enumeratedValue>
                                <enumeratedValue>
                                    <name>1</name>
                                    <description>Select associated input channel. </description>
                                    <value>#1</value>
                                </enumeratedValue>
                            </enumeratedValues>
                        </field>
                        <field>
                            <name>ADS04</name>
                            <description>A/D-Converted Value Addition/Average Channel Select</description>
                            <lsb>4</lsb>
                            <msb>4</msb>
                            <access>read-write</access>
                            <enumeratedValues>
                                <enumeratedValue>
                                    <name>0</name>
                                    <description>Do not select associated input channel.</description>
                                    <value>#0</value>
                                </enumeratedValue>
                                <enumeratedValue>
                                    <name>1</name>
                                    <description>Select associated input channel. </description>
                                    <value>#1</value>
                                </enumeratedValue>
                            </enumeratedValues>
                        </field>
                        <field>
                            <name>ADS05</name>
                            <description>A/D-Converted Value Addition/Average Channel Select</description>
                            <lsb>5</lsb>
                            <msb>5</msb>
                            <access>read-write</access>
                            <enumeratedValues>
                                <enumeratedValue>
                                    <name>0</name>
                                    <description>Do not select associated input channel.</description>
                                    <value>#0</value>
                                </enumeratedValue>
                                <enumeratedValue>
                                    <name>1</name>
                                    <description>Select associated input channel. </description>
                                    <value>#1</value>
                                </enumeratedValue>
                            </enumeratedValues>
                        </field>
                        <field>
                            <name>ADS06</name>
                            <description>A/D-Converted Value Addition/Average Channel Select</description>
                            <lsb>6</lsb>
                            <msb>6</msb>
                            <access>read-write</access>
                            <enumeratedValues>
                                <enumeratedValue>
                                    <name>0</name>
                                    <description>Do not select associated input channel.</description>
                                    <value>#0</value>
                                </enumeratedValue>
                                <enumeratedValue>
                                    <name>1</name>
                                    <description>Select associated input channel. </description>
                                    <value>#1</value>
                                </enumeratedValue>
                            </enumeratedValues>
                        </field>
                    </fields>
                </register>
                <register>
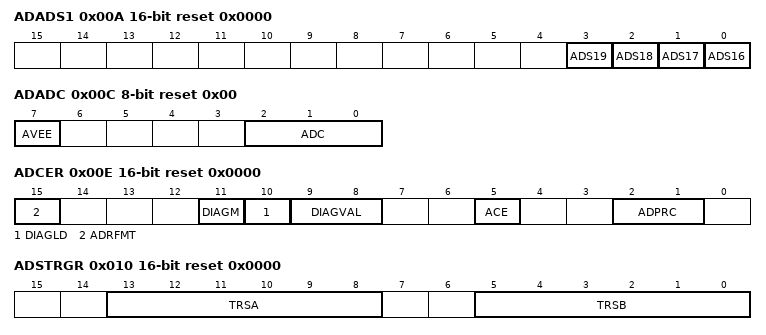
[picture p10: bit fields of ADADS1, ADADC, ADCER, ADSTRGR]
                    <name>ADADS1</name>
                    <description>A/D-Converted Value Addition/Average Channel Select Register 1</description>
                    <addressOffset>0x00A</addressOffset>
                    <size>16</size>
                    <access>read-write</access>
                    <resetValue>0x0000</resetValue>
                    <resetMask>0xffff</resetMask>
                    <fields>
                        <field>
                            <name>ADS16</name>
                            <description>A/D Conversion Channels Select/Average Channel Select</description>
                            <lsb>0</lsb>
                            <msb>0</msb>
                            <access>read-write</access>
                            <enumeratedValues>
                                <enumeratedValue>
                                    <name>0</name>
                                    <description>Do not select associated input channel.</description>
                                    <value>#0</value>
                                </enumeratedValue>
                                <enumeratedValue>
                                    <name>1</name>
                                    <description>Select associated input channel. </description>
                                    <value>#1</value>
                                </enumeratedValue>
                            </enumeratedValues>
                        </field>
                        <field>
                            <name>ADS17</name>
                            <description>A/D Conversion Channels Select/Average Channel Select</description>
                            <lsb>1</lsb>
                            <msb>1</msb>
                            <access>read-write</access>
                            <enumeratedValues>
                                <enumeratedValue>
                                    <name>0</name>
                                    <description>Do not select associated input channel.</description>
                                    <value>#0</value>
                                </enumeratedValue>
                                <enumeratedValue>
                                    <name>1</name>
                                    <description>Select associated input channel. </description>
                                    <value>#1</value>
                                </enumeratedValue>
                            </enumeratedValues>
                        </field>
                        <field>
                            <name>ADS18</name>
                            <description>A/D Conversion Channels Select/Average Channel Select</description>
                            <lsb>2</lsb>
                            <msb>2</msb>
                            <access>read-write</access>
                            <enumeratedValues>
                                <enumeratedValue>
                                    <name>0</name>
                                    <description>Do not select associated input channel.</description>
                                    <value>#0</value>
                                </enumeratedValue>
                                <enumeratedValue>
                                    <name>1</name>
                                    <description>Select associated input channel. </description>
                                    <value>#1</value>
                                </enumeratedValue>
                            </enumeratedValues>
                        </field>
                        <field>
                            <name>ADS19</name>
                            <description>A/D Conversion Channels Select/Average Channel Select</description>
                            <lsb>3</lsb>
                            <msb>3</msb>
                            <access>read-write</access>
                            <enumeratedValues>
                                <enumeratedValue>
                                    <name>0</name>
                                    <description>Do not select associated input channel.</description>
                                    <value>#0</value>
                                </enumeratedValue>
                                <enumeratedValue>
                                    <name>1</name>
                                    <description>Select associated input channel. </description>
                                    <value>#1</value>
                                </enumeratedValue>
                            </enumeratedValues>
                        </field>
                    </fields>
                </register>
                <register>
                    <name>ADADC</name>
                    <description>A/D-Converted Value Addition/Average Count Select Register</description>
                    <addressOffset>0x00C</addressOffset>
                    <size>8</size>
                    <access>read-write</access>
                    <resetValue>0x00</resetValue>
                    <resetMask>0xff</resetMask>
                    <fields>
                        <field>
                            <name>ADC</name>
                            <description>Addition/Average Count Select</description>
                            <lsb>0</lsb>
                            <msb>2</msb>
                            <access>read-write</access>
                            <enumeratedValues>
                                <enumeratedValue>
                                    <name>000</name>
                                    <description>1-time conversion (no addition, same as normal conversion)</description>
                                    <value>#000</value>
                                </enumeratedValue>
                                <enumeratedValue>
                                    <name>001</name>
                                    <description>2-time conversion (1 addition)</description>
                                    <value>#001</value>
                                </enumeratedValue>
                                <enumeratedValue>
                                    <name>010</name>
                                    <description>3-time conversion (2 additions)</description>
                                    <value>#010</value>
                                </enumeratedValue>
                                <enumeratedValue>
                                    <name>011</name>
                                    <description>4-time conversion (3 additions)</description>
                                    <value>#011</value>
                                </enumeratedValue>
                                <enumeratedValue>
                                    <name>101</name>
                                    <description>16-time conversion (15 additions)</description>
                                    <value>#101</value>
                                </enumeratedValue>
                                <enumeratedValue>
                                    <name>Others</name>
                                    <description>Setting prohibited</description>
                                    <isDefault>true</isDefault>
                                </enumeratedValue>
                            </enumeratedValues>
                        </field>
                        <field>
                            <name>AVEE</name>
                            <description>Average Mode Select</description>
                            <lsb>7</lsb>
                            <msb>7</msb>
                            <access>read-write</access>
                            <enumeratedValues>
                                <enumeratedValue>
                                    <name>0</name>
                                    <description>Enable addition mode</description>
                                    <value>#0</value>
                                </enumeratedValue>
                                <enumeratedValue>
                                    <name>1</name>
                                    <description>Enable average mode</description>
                                    <value>#1</value>
                                </enumeratedValue>
                            </enumeratedValues>
                        </field>
                    </fields>
                </register>
                <register>
                    <name>ADCER</name>
                    <description>A/D Control Extended Register</description>
                    <addressOffset>0x00E</addressOffset>
                    <size>16</size>
                    <access>read-write</access>
                    <resetValue>0x0000</resetValue>
                    <resetMask>0xffff</resetMask>
                    <fields>
                        <field>
                            <name>ADPRC</name>
                            <lsb>1</lsb>
                            <msb>2</msb>
                            <access>read-write</access>
                            <enumeratedValues>
                                <enumeratedValue>
                                    <name>00</name>
                                    <description>12-bit accuracy</description>
                                    <value>#00</value>
                                </enumeratedValue>
                                <enumeratedValue>
                                    <name>01</name>
                                    <description>10-bit accuracy</description>
                                    <value>#01</value>
                                </enumeratedValue>
                                <enumeratedValue>
                                    <name>10</name>
                                    <description>8-bit accuracy</description>
                                    <value>#10</value>
                                </enumeratedValue>
                                <enumeratedValue>
                                    <name>11</name>
                                    <description>Setting prohibited</description>
                                    <value>#11</value>
                                </enumeratedValue>
                            </enumeratedValues>
                        </field>
                        <field>
                            <name>ACE</name>
                            <description>A/D Data Register Automatic Clearing Enable</description>
                            <lsb>5</lsb>
                            <msb>5</msb>
                            <access>read-write</access>
                            <enumeratedValues>
                                <enumeratedValue>
                                    <name>0</name>
                                    <description>Disable automatic clearing</description>
                                    <value>#0</value>
                                </enumeratedValue>
                                <enumeratedValue>
                                    <name>1</name>
                                    <description>Enable automatic clearing</description>
                                    <value>#1</value>
                                </enumeratedValue>
                            </enumeratedValues>
                        </field>
                        <field>
                            <name>DIAGVAL</name>
                            <description>Self-Diagnosis Conversion Voltage Select</description>
                            <lsb>8</lsb>
                            <msb>9</msb>
                            <access>read-write</access>
                            <enumeratedValues>
                                <enumeratedValue>
                                    <name>00</name>
                                    <description>Setting prohibited when self-diagnosis is enabled</description>
                                    <value>#00</value>
                                </enumeratedValue>
                                <enumeratedValue>
                                    <name>01</name>
                                    <description>0 volts</description>
                                    <value>#01</value>
                                </enumeratedValue>
                                <enumeratedValue>
                                    <name>10</name>
                                    <description>Reference voltage × 1/2</description>
                                    <value>#10</value>
                                </enumeratedValue>
                                <enumeratedValue>
                                    <name>11</name>
                                    <description>Reference voltage</description>
                                    <value>#11</value>
                                </enumeratedValue>
                            </enumeratedValues>
                        </field>
                        <field>
                            <name>DIAGLD</name>
                            <description>Self-Diagnosis Mode Select</description>
                            <lsb>10</lsb>
                            <msb>10</msb>
                            <access>read-write</access>
                            <enumeratedValues>
                                <enumeratedValue>
                                    <name>0</name>
                                    <description>Select rotation mode for self-diagnosis voltage</description>
                                    <value>#0</value>
                                </enumeratedValue>
                                <enumeratedValue>
                                    <name>1</name>
                                    <description>Select mixed mode for self-diagnosis voltage</description>
                                    <value>#1</value>
                                </enumeratedValue>
                            </enumeratedValues>
                        </field>
                        <field>
                            <name>DIAGM</name>
                            <description>Self-Diagnosis Enable</description>
                            <lsb>11</lsb>
                            <msb>11</msb>
                            <access>read-write</access>
                            <enumeratedValues>
                                <enumeratedValue>
                                    <name>0</name>
                                    <description>Disable ADC12 self-diagnosis</description>
                                    <value>#0</value>
                                </enumeratedValue>
                                <enumeratedValue>
                                    <name>1</name>
                                    <description>Enable ADC12 self-diagnosis</description>
                                    <value>#1</value>
                                </enumeratedValue>
                            </enumeratedValues>
                        </field>
                        <field>
                            <name>ADRFMT</name>
                            <description>A/D Data Register Format Select</description>
                            <lsb>15</lsb>
                            <msb>15</msb>
                            <access>read-write</access>
                            <enumeratedValues>
                                <enumeratedValue>
                                    <name>0</name>
                                    <description>Select right-justified for the A/D data register format</description>
                                    <value>#0</value>
                                </enumeratedValue>
                                <enumeratedValue>
                                    <name>1</name>
                                    <description>Select left-justified for the A/D data register format</description>
                                    <value>#1</value>
                                </enumeratedValue>
                            </enumeratedValues>
                        </field>
                    </fields>
                </register>
                <register>
                    <name>ADSTRGR</name>
                    <description>A/D Conversion Start Trigger Select Register</description>
                    <addressOffset>0x010</addressOffset>
                    <size>16</size>
                    <access>read-write</access>
                    <resetValue>0x0000</resetValue>
                    <resetMask>0xffff</resetMask>
                    <fields>
                        <field>
                            <name>TRSB</name>
                            <description>A/D Conversion Start Trigger Select for Group B</description>
                            <lsb>0</lsb>
                            <msb>5</msb>
                            <access>read-write</access>
                        </field>
                        <field>
                            <name>TRSA</name>
                            <description>A/D Conversion Start Trigger Select</description>
                            <lsb>8</lsb>
                            <msb>13</msb>
                            <access>read-write</access>
                        </field>
                    </fields>
                </register>
                <register>
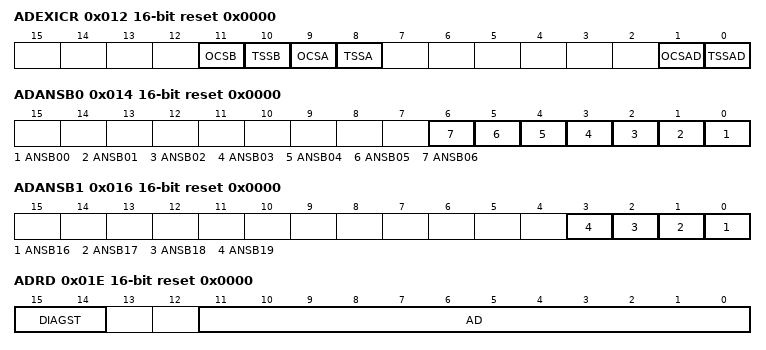
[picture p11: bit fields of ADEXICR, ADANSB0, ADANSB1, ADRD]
                    <name>ADEXICR</name>
                    <description>A/D Conversion Extended Input Control Registers</description>
                    <addressOffset>0x012</addressOffset>
                    <size>16</size>
                    <access>read-write</access>
                    <resetValue>0x0000</resetValue>
                    <resetMask>0xffff</resetMask>
                    <fields>
                        <field>
                            <name>TSSAD</name>
                            <description>Temperature Sensor Output A/D-Converted Value Addition/Average Mode Select</description>
                            <lsb>0</lsb>
                            <msb>0</msb>
                            <access>read-write</access>
                            <enumeratedValues>
                                <enumeratedValue>
                                    <name>0</name>
                                    <description>Do not select addition/average mode for temperature sensor output.</description>
                                    <value>#0</value>
                                </enumeratedValue>
                                <enumeratedValue>
                                    <name>1</name>
                                    <description>Select addition/average mode for temperature sensor output.</description>
                                    <value>#1</value>
                                </enumeratedValue>
                            </enumeratedValues>
                        </field>
                        <field>
                            <name>OCSAD</name>
                            <description>Internal Reference Voltage A/D-Converted Value Addition/Average Mode Select</description>
                            <lsb>1</lsb>
                            <msb>1</msb>
                            <access>read-write</access>
                            <enumeratedValues>
                                <enumeratedValue>
                                    <name>0</name>
                                    <description>Do not select addition/average mode for internal reference voltage.</description>
                                    <value>#0</value>
                                </enumeratedValue>
                                <enumeratedValue>
                                    <name>1</name>
                                    <description>Select addition/average mode for internal reference voltage.</description>
                                    <value>#1</value>
                                </enumeratedValue>
                            </enumeratedValues>
                        </field>
                        <field>
                            <name>TSSA</name>
                            <description>Temperature Sensor Output A/D Conversion Select</description>
                            <lsb>8</lsb>
                            <msb>8</msb>
                            <access>read-write</access>
                            <enumeratedValues>
                                <enumeratedValue>
                                    <name>0</name>
                                    <description>Disable A/D conversion of temperature sensor output</description>
                                    <value>#0</value>
                                </enumeratedValue>
                                <enumeratedValue>
                                    <name>1</name>
                                    <description>Enable A/D conversion of temperature sensor output</description>
                                    <value>#1</value>
                                </enumeratedValue>
                            </enumeratedValues>
                        </field>
                        <field>
                            <name>OCSA</name>
                            <description>Internal Reference Voltage A/D Conversion Select</description>
                            <lsb>9</lsb>
                            <msb>9</msb>
                            <access>read-write</access>
                            <enumeratedValues>
                                <enumeratedValue>
                                    <name>0</name>
                                    <description>Disable A/D conversion of internal reference voltage</description>
                                    <value>#0</value>
                                </enumeratedValue>
                                <enumeratedValue>
                                    <name>1</name>
                                    <description>Enable A/D conversion of internal reference voltage</description>
                                    <value>#1</value>
                                </enumeratedValue>
                            </enumeratedValues>
                        </field>
                        <field>
                            <name>TSSB</name>
                            <description>Temperature Sensor Output A/D Conversion Select for Group B</description>
                            <lsb>10</lsb>
                            <msb>10</msb>
                            <access>read-write</access>
                            <enumeratedValues>
                                <enumeratedValue>
                                    <name>0</name>
                                    <description>Disable A/D conversion of temperature sensor output</description>
                                    <value>#0</value>
                                </enumeratedValue>
                                <enumeratedValue>
                                    <name>1</name>
                                    <description>Enable A/D conversion of temperature sensor output</description>
                                    <value>#1</value>
                                </enumeratedValue>
                            </enumeratedValues>
                        </field>
                        <field>
                            <name>OCSB</name>
                            <description>Internal Reference Voltage A/D Conversion Select for Group B</description>
                            <lsb>11</lsb>
                            <msb>11</msb>
                            <access>read-write</access>
                            <enumeratedValues>
                                <enumeratedValue>
                                    <name>0</name>
                                    <description>Disable A/D conversion of internal reference voltage</description>
                                    <value>#0</value>
                                </enumeratedValue>
                                <enumeratedValue>
                                    <name>1</name>
                                    <description>Enable A/D conversion of internal reference voltage</description>
                                    <value>#1</value>
                                </enumeratedValue>
                            </enumeratedValues>
                        </field>
                    </fields>
                </register>
                <register>
                    <name>ADANSB0</name>
                    <description>A/D Channel Select Register B0</description>
                    <addressOffset>0x014</addressOffset>
                    <size>16</size>
                    <access>read-write</access>
                    <resetValue>0x0000</resetValue>
                    <resetMask>0xffff</resetMask>
                    <fields>
                        <field>
                            <name>ANSB00</name>
                            <description>A/D Conversion Channels Select</description>
                            <lsb>0</lsb>
                            <msb>0</msb>
                            <access>read-write</access>
                            <enumeratedValues>
                                <enumeratedValue>
                                    <name>0</name>
                                    <description>Do not select associated input channel.</description>
                                    <value>#0</value>
                                </enumeratedValue>
                                <enumeratedValue>
                                    <name>1</name>
                                    <description>Select associated input channel. </description>
                                    <value>#1</value>
                                </enumeratedValue>
                            </enumeratedValues>
                        </field>
                        <field>
                            <name>ANSB01</name>
                            <description>A/D Conversion Channels Select</description>
                            <lsb>1</lsb>
                            <msb>1</msb>
                            <access>read-write</access>
                            <enumeratedValues>
                                <enumeratedValue>
                                    <name>0</name>
                                    <description>Do not select associated input channel.</description>
                                    <value>#0</value>
                                </enumeratedValue>
                                <enumeratedValue>
                                    <name>1</name>
                                    <description>Select associated input channel. </description>
                                    <value>#1</value>
                                </enumeratedValue>
                            </enumeratedValues>
                        </field>
                        <field>
                            <name>ANSB02</name>
                            <description>A/D Conversion Channels Select</description>
                            <lsb>2</lsb>
                            <msb>2</msb>
                            <access>read-write</access>
                            <enumeratedValues>
                                <enumeratedValue>
                                    <name>0</name>
                                    <description>Do not select associated input channel.</description>
                                    <value>#0</value>
                                </enumeratedValue>
                                <enumeratedValue>
                                    <name>1</name>
                                    <description>Select associated input channel. </description>
                                    <value>#1</value>
                                </enumeratedValue>
                            </enumeratedValues>
                        </field>
                        <field>
                            <name>ANSB03</name>
                            <description>A/D Conversion Channels Select</description>
                            <lsb>3</lsb>
                            <msb>3</msb>
                            <access>read-write</access>
                            <enumeratedValues>
                                <enumeratedValue>
                                    <name>0</name>
                                    <description>Do not select associated input channel.</description>
                                    <value>#0</value>
                                </enumeratedValue>
                                <enumeratedValue>
                                    <name>1</name>
                                    <description>Select associated input channel. </description>
                                    <value>#1</value>
                                </enumeratedValue>
                            </enumeratedValues>
                        </field>
                        <field>
                            <name>ANSB04</name>
                            <description>A/D Conversion Channels Select</description>
                            <lsb>4</lsb>
                            <msb>4</msb>
                            <access>read-write</access>
                            <enumeratedValues>
                                <enumeratedValue>
                                    <name>0</name>
                                    <description>Do not select associated input channel.</description>
                                    <value>#0</value>
                                </enumeratedValue>
                                <enumeratedValue>
                                    <name>1</name>
                                    <description>Select associated input channel. </description>
                                    <value>#1</value>
                                </enumeratedValue>
                            </enumeratedValues>
                        </field>
                        <field>
                            <name>ANSB05</name>
                            <description>A/D Conversion Channels Select</description>
                            <lsb>5</lsb>
                            <msb>5</msb>
                            <access>read-write</access>
                            <enumeratedValues>
                                <enumeratedValue>
                                    <name>0</name>
                                    <description>Do not select associated input channel.</description>
                                    <value>#0</value>
                                </enumeratedValue>
                                <enumeratedValue>
                                    <name>1</name>
                                    <description>Select associated input channel. </description>
                                    <value>#1</value>
                                </enumeratedValue>
                            </enumeratedValues>
                        </field>
                        <field>
                            <name>ANSB06</name>
                            <description>A/D Conversion Channels Select</description>
                            <lsb>6</lsb>
                            <msb>6</msb>
                            <access>read-write</access>
                            <enumeratedValues>
                                <enumeratedValue>
                                    <name>0</name>
                                    <description>Do not select associated input channel.</description>
                                    <value>#0</value>
                                </enumeratedValue>
                                <enumeratedValue>
                                    <name>1</name>
                                    <description>Select associated input channel. </description>
                                    <value>#1</value>
                                </enumeratedValue>
                            </enumeratedValues>
                        </field>
                    </fields>
                </register>
                <register>
                    <name>ADANSB1</name>
                    <description>A/D Channel Select Register B1</description>
                    <addressOffset>0x016</addressOffset>
                    <size>16</size>
                    <access>read-write</access>
                    <resetValue>0x0000</resetValue>
                    <resetMask>0xffff</resetMask>
                    <fields>
                        <field>
                            <name>ANSB16</name>
                            <description>A/D Conversion Channels Select</description>
                            <lsb>0</lsb>
                            <msb>0</msb>
                            <access>read-write</access>
                            <enumeratedValues>
                                <enumeratedValue>
                                    <name>0</name>
                                    <description>Do not select associated input channel.</description>
                                    <value>#0</value>
                                </enumeratedValue>
                                <enumeratedValue>
                                    <name>1</name>
                                    <description>Select associated input channel. </description>
                                    <value>#1</value>
                                </enumeratedValue>
                            </enumeratedValues>
                        </field>
                        <field>
                            <name>ANSB17</name>
                            <description>A/D Conversion Channels Select</description>
                            <lsb>1</lsb>
                            <msb>1</msb>
                            <access>read-write</access>
                            <enumeratedValues>
                                <enumeratedValue>
                                    <name>0</name>
                                    <description>Do not select associated input channel.</description>
                                    <value>#0</value>
                                </enumeratedValue>
                                <enumeratedValue>
                                    <name>1</name>
                                    <description>Select associated input channel. </description>
                                    <value>#1</value>
                                </enumeratedValue>
                            </enumeratedValues>
                        </field>
                        <field>
                            <name>ANSB18</name>
                            <description>A/D Conversion Channels Select</description>
                            <lsb>2</lsb>
                            <msb>2</msb>
                            <access>read-write</access>
                            <enumeratedValues>
                                <enumeratedValue>
                                    <name>0</name>
                                    <description>Do not select associated input channel.</description>
                                    <value>#0</value>
                                </enumeratedValue>
                                <enumeratedValue>
                                    <name>1</name>
                                    <description>Select associated input channel. </description>
                                    <value>#1</value>
                                </enumeratedValue>
                            </enumeratedValues>
                        </field>
                        <field>
                            <name>ANSB19</name>
                            <description>A/D Conversion Channels Select</description>
                            <lsb>3</lsb>
                            <msb>3</msb>
                            <access>read-write</access>
                            <enumeratedValues>
                                <enumeratedValue>
                                    <name>0</name>
                                    <description>Do not select associated input channel.</description>
                                    <value>#0</value>
                                </enumeratedValue>
                                <enumeratedValue>
                                    <name>1</name>
                                    <description>Select associated input channel. </description>
                                    <value>#1</value>
                                </enumeratedValue>
                            </enumeratedValues>
                        </field>
                    </fields>
                </register>
                <register>
                    <name>ADDBLDR</name>
                    <description>A/D Data Duplexing Register</description>
                    <addressOffset>0x018</addressOffset>
                    <size>16</size>
                    <access>read-only</access>
                    <resetValue>0x0000</resetValue>
                    <resetMask>0xffff</resetMask>
                    <fields>
                        <field>
                            <name>ADDBLDR</name>
                            <description>Converted Value 15 to 0</description>
                            <lsb>0</lsb>
                            <msb>15</msb>
                            <access>read-only</access>
                        </field>
                    </fields>
                </register>
                <register>
                    <name>ADTSDR</name>
                    <description>A/D Temperature Sensor Data Register</description>
                    <addressOffset>0x01A</addressOffset>
                    <size>16</size>
                    <access>read-only</access>
                    <resetValue>0x0000</resetValue>
                    <resetMask>0xffff</resetMask>
                    <fields>
                        <field>
                            <name>ADTSDR</name>
                            <description>Converted Value 15 to 0</description>
                            <lsb>0</lsb>
                            <msb>15</msb>
                            <access>read-only</access>
                        </field>
                    </fields>
                </register>
                <register>
                    <name>ADOCDR</name>
                    <description>A/D Internal Reference Voltage Data Register</description>
                    <addressOffset>0x01C</addressOffset>
                    <size>16</size>
                    <access>read-only</access>
                    <resetValue>0x0000</resetValue>
                    <resetMask>0xffff</resetMask>
                    <fields>
                        <field>
                            <name>ADOCDR</name>
                            <description>Converted Value 15 to 0</description>
                            <lsb>0</lsb>
                            <msb>15</msb>
                            <access>read-only</access>
                        </field>
                    </fields>
                </register>
                <register>
                    <name>ADRD</name>
                    <description>A/D Self-Diagnosis Data Register</description>
                    <addressOffset>0x01E</addressOffset>
                    <size>16</size>
                    <access>read-only</access>
                    <resetValue>0x0000</resetValue>
                    <resetMask>0xffff</resetMask>
                    <fields>
                        <field>
                            <name>AD</name>
                            <description>Converted Value 11 to 0</description>
                            <lsb>0</lsb>
                            <msb>11</msb>
                            <access>read-only</access>
                        </field>
                        <field>
                            <name>DIAGST</name>
                            <description>Self-Diagnosis Status</description>
                            <lsb>14</lsb>
                            <msb>15</msb>
                            <access>read-only</access>
                            <enumeratedValues>
                                <enumeratedValue>
                                    <name>00</name>
                                    <description>Self-diagnosis not executed after power-on.</description>
                                    <value>#00</value>
                                </enumeratedValue>
                                <enumeratedValue>
                                    <name>01</name>
                                    <description>Self-diagnosis was executed using the 0 V voltage.</description>
                                    <value>#01</value>
                                </enumeratedValue>
                                <enumeratedValue>
                                    <name>10</name>
                                    <description>Self-diagnosis was executed using the reference voltage × 1/2.</description>
                                    <value>#10</value>
                                </enumeratedValue>
                                <enumeratedValue>
                                    <name>11</name>
                                    <description>Self-diagnosis was executed using the reference voltage .</description>
                                    <value>#11</value>
                                </enumeratedValue>
                            </enumeratedValues>
                        </field>
                    </fields>
                </register>
                <register>
                    <dim>7</dim>
                    <dimIncrement>0x2</dimIncrement>
                    <dimIndex>0-6</dimIndex>
                    <name>ADDR%s</name>
                    <description>A/D Data Registers %s</description>
                    <addressOffset>0x020</addressOffset>
                    <size>16</size>
                    <access>read-only</access>
                    <resetValue>0x0000</resetValue>
                    <resetMask>0xffff</resetMask>
                    <fields>
                        <field>
                            <name>ADDR</name>
                            <description>Converted Value 15 to 0</description>
                            <lsb>0</lsb>
                            <msb>15</msb>
                            <access>read-only</access>
                        </field>
                    </fields>
                </register>
                <register>
                    <dim>7</dim>
                    <dimIncrement>0x2</dimIncrement>
                    <dimIndex>16-22</dimIndex>
                    <name>ADDR%s</name>
                    <description>A/D Data Registers %s</description>
                    <addressOffset>0x020</addressOffset>
                    <size>16</size>
                    <access>read-only</access>
                    <resetValue>0x0000</resetValue>
                    <resetMask>0xffff</resetMask>
                    <fields>
                        <field>
                            <name>ADDR</name>
                            <description>Converted Value 15 to 0</description>
                            <lsb>0</lsb>
                            <msb>15</msb>
                            <access>read-only</access>
                        </field>
                    </fields>
                </register>
                <register>
                    <name>ADVMDR</name>
                    <description>A/D VBATT Monitor Data Register</description>
                    <addressOffset>0x026</addressOffset>
                    <size>16</size>
                    <access>read-only</access>
                    <resetValue>0x0000</resetValue>
                    <resetMask>0xffff</resetMask>
                    <fields>
                        <field>
                            <name>ADDR</name>
                            <description>Converted Value 15 to 0</description>
                            <lsb>0</lsb>
                            <msb>15</msb>
                            <access>read-only</access>
                        </field>
                    </fields>
                </register>
                <register>
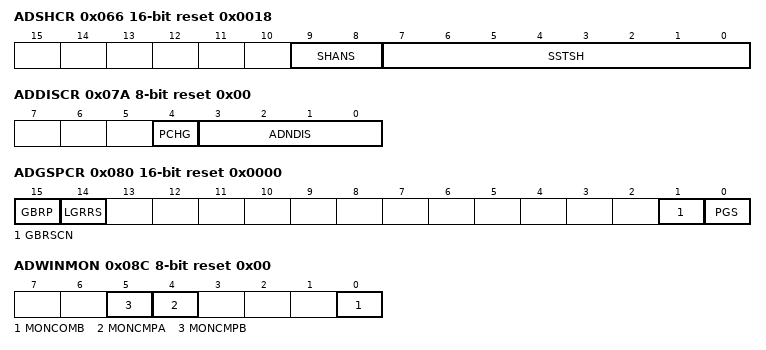
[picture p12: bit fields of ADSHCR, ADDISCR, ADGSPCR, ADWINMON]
                    <name>ADSHCR</name>
                    <description>A/D Sample and Hold Circuit Control Register</description>
                    <addressOffset>0x066</addressOffset>
                    <size>16</size>
                    <access>read-write</access>
                    <resetValue>0x0018</resetValue>
                    <resetMask>0xffff</resetMask>
                    <fields>
                        <field>
                            <name>SSTSH</name>
                            <description>Channel-Dedicated Sample-and-Hold Circuit Sampling Time Setting</description>
                            <lsb>0</lsb>
                            <msb>7</msb>
                            <access>read-write</access>
                        </field>
                        <field>
                            <name>SHANS</name>
                            <description>Channel-Dedicated Sample-and-Hold Circuit Bypass Select</description>
                            <lsb>8</lsb>
                            <msb>9</msb>
                            <access>read-write</access>
                            <enumeratedValues>
                                <enumeratedValue>
                                    <name>0</name>
                                    <description>Bypass the circuits</description>
                                    <value>#0</value>
                                </enumeratedValue>
                                <enumeratedValue>
                                    <name>1</name>
                                    <description>Use the circuits</description>
                                    <value>#1</value>
                                </enumeratedValue>
                            </enumeratedValues>
                        </field>
                    </fields>
                </register>
                <register>
                    <name>ADDISCR</name>
                    <description>A/D Disconnection Detection Control Register</description>
                    <addressOffset>0x07A</addressOffset>
                    <size>8</size>
                    <access>read-write</access>
                    <resetValue>0x00</resetValue>
                    <resetMask>0xff</resetMask>
                    <fields>
                        <field>
                            <name>ADNDIS</name>
                            <description>Disconnection Detection Assist Setting</description>
                            <lsb>0</lsb>
                            <msb>3</msb>
                            <access>read-write</access>
                            <enumeratedValues>
                                <enumeratedValue>
                                    <name>0x0</name>
                                    <description>The disconnection detection assist function is disabled</description>
                                    <value>0x0</value>
                                </enumeratedValue>
                                <enumeratedValue>
                                    <name>0x1</name>
                                    <description>Setting prohibited</description>
                                    <value>0x1</value>
                                </enumeratedValue>
                                <enumeratedValue>
                                    <name>Others</name>
                                    <description>The number of states for the discharge or precharge period.</description>
                                    <isDefault>true</isDefault>
                                </enumeratedValue>
                            </enumeratedValues>
                        </field>
                        <field>
                            <name>PCHG</name>
                            <description>Precharge/discharge select</description>
                            <lsb>4</lsb>
                            <msb>4</msb>
                            <access>read-write</access>
                            <enumeratedValues>
                                <enumeratedValue>
                                    <name>0</name>
                                    <description>Discharge</description>
                                    <value>#0</value>
                                </enumeratedValue>
                                <enumeratedValue>
                                    <name>1</name>
                                    <description>Precharge</description>
                                    <value>#1</value>
                                </enumeratedValue>
                            </enumeratedValues>
                        </field>
                    </fields>
                </register>
                <register>
                    <name>ADSHMSR</name>
                    <description>A/D Sample and Hold Operation Mode Selection Register</description>
                    <addressOffset>0x07C</addressOffset>
                    <size>8</size>
                    <access>read-write</access>
                    <resetValue>0x00</resetValue>
                    <resetMask>0xff</resetMask>
                    <fields>
                        <field>
                            <name>SHMD</name>
                            <description>Sampling Operation Selection</description>
                            <lsb>0</lsb>
                            <msb>0</msb>
                            <access>read-write</access>
                            <enumeratedValues>
                                <enumeratedValue>
                                    <name>0</name>
                                    <description>Sampling Operation Selection</description>
                                    <value>#0</value>
                                </enumeratedValue>
                                <enumeratedValue>
                                    <name>1</name>
                                    <description>Enable continuous sampling function</description>
                                    <value>#1</value>
                                </enumeratedValue>
                            </enumeratedValues>
                        </field>
                    </fields>
                </register>
                <register>
                    <name>ADGSPCR</name>
                    <description>A/D Group Scan Priority Control Register</description>
                    <addressOffset>0x080</addressOffset>
                    <size>16</size>
                    <access>read-write</access>
                    <resetValue>0x0000</resetValue>
                    <resetMask>0xffff</resetMask>
                    <fields>
                        <field>
                            <name>PGS</name>
                            <description>Group Priority Operation Setting</description>
                            <lsb>0</lsb>
                            <msb>0</msb>
                            <access>read-write</access>
                            <enumeratedValues>
                                <enumeratedValue>
                                    <name>0</name>
                                    <description>Operate without group priority control.</description>
                                    <value>#0</value>
                                </enumeratedValue>
                                <enumeratedValue>
                                    <name>1</name>
                                    <description>Operate with group priority control.</description>
                                    <value>#1</value>
                                </enumeratedValue>
                            </enumeratedValues>
                        </field>
                        <field>
                            <name>GBRSCN</name>
                            <description>Lower-Priority Group Restart Setting</description>
                            <lsb>1</lsb>
                            <msb>1</msb>
                            <access>read-write</access>
                            <enumeratedValues>
                                <enumeratedValue>
                                    <name>0</name>
                                    <description>Disable rescanning of the group that was stopped in group priority operation</description>
                                    <value>#0</value>
                                </enumeratedValue>
                                <enumeratedValue>
                                    <name>1</name>
                                    <description>Enable rescanning of the group that was stopped in group priority operation.</description>
                                    <value>#1</value>
                                </enumeratedValue>
                            </enumeratedValues>
                        </field>
                        <field>
                            <name>LGRRS</name>
                            <description>Enabled only when PGS = 1 and GBRSCN = 1.</description>
                            <lsb>14</lsb>
                            <msb>14</msb>
                            <access>read-write</access>
                            <enumeratedValues>
                                <enumeratedValue>
                                    <name>0</name>
                                    <description>Start rescanning from the first channel for scanning</description>
                                    <value>#0</value>
                                </enumeratedValue>
                                <enumeratedValue>
                                    <name>1</name>
                                    <description>Start rescanning from the channel for which A/D conversion is not completed.</description>
                                    <value>#1</value>
                                </enumeratedValue>
                            </enumeratedValues>
                        </field>
                        <field>
                            <name>GBRP</name>
                            <description>Single Scan Continuous Start</description>
                            <lsb>15</lsb>
                            <msb>15</msb>
                            <access>read-write</access>
                            <enumeratedValues>
                                <enumeratedValue>
                                    <name>0</name>
                                    <description>Single scan is not continuously activated.</description>
                                    <value>#0</value>
                                </enumeratedValue>
                                <enumeratedValue>
                                    <name>1</name>
                                    <description>Single scan for the group with the lower-priority is continuously activated.</description>
                                    <value>#1</value>
                                </enumeratedValue>
                            </enumeratedValues>
                        </field>
                    </fields>
                </register>
                <register>
                    <name>ADDBLDRA</name>
                    <description>A/D Data Duplexing Register A</description>
                    <addressOffset>0x084</addressOffset>
                    <size>16</size>
                    <access>read-only</access>
                    <resetValue>0x0000</resetValue>
                    <resetMask>0xffff</resetMask>
                    <fields>
                        <field>
                            <name>ADDBLDR</name>
                            <description>Converted Value 15 to 0</description>
                            <lsb>0</lsb>
                            <msb>15</msb>
                            <access>read-only</access>
                        </field>
                    </fields>
                </register>
                <register>
                    <name>ADDBLDRB</name>
                    <description>A/D Data Duplexing Register B</description>
                    <addressOffset>0x086</addressOffset>
                    <size>16</size>
                    <access>read-only</access>
                    <resetValue>0x0000</resetValue>
                    <resetMask>0xffff</resetMask>
                    <fields>
                        <field>
                            <name>ADDBLDR</name>
                            <description>Converted Value 15 to 0</description>
                            <lsb>0</lsb>
                            <msb>15</msb>
                            <access>read-only</access>
                        </field>
                    </fields>
                </register>
                <register>
                    <name>ADWINMON</name>
                    <description>A/D Compare Function Window A/B Status Monitor Register</description>
                    <addressOffset>0x08C</addressOffset>
                    <size>8</size>
                    <access>read-only</access>
                    <resetValue>0x00</resetValue>
                    <resetMask>0xff</resetMask>
                    <fields>
                        <field>
                            <name>MONCOMB</name>
                            <description>Combination Result Monitor</description>
                            <lsb>0</lsb>
                            <msb>0</msb>
                            <access>read-only</access>
                            <enumeratedValues>
                                <enumeratedValue>
                                    <name>0</name>
                                    <description>Window A/B composite conditions are not met.</description>
                                    <value>#0</value>
                                </enumeratedValue>
                                <enumeratedValue>
                                    <name>1</name>
                                    <description>Window A/B composite conditions are met.</description>
                                    <value>#1</value>
                                </enumeratedValue>
                            </enumeratedValues>
                        </field>
                        <field>
                            <name>MONCMPA</name>
                            <description>Comparison Result Monitor A</description>
                            <lsb>4</lsb>
                            <msb>4</msb>
                            <access>read-only</access>
                            <enumeratedValues>
                                <enumeratedValue>
                                    <name>0</name>
                                    <description>Window A comparison conditions are not met.</description>
                                    <value>#0</value>
                                </enumeratedValue>
                                <enumeratedValue>
                                    <name>1</name>
                                    <description>Window A comparison conditions are met.</description>
                                    <value>#1</value>
                                </enumeratedValue>
                            </enumeratedValues>
                        </field>
                        <field>
                            <name>MONCMPB</name>
                            <description>Comparison Result Monitor B</description>
                            <lsb>5</lsb>
                            <msb>5</msb>
                            <access>read-only</access>
                            <enumeratedValues>
                                <enumeratedValue>
                                    <name>0</name>
                                    <description>Window B comparison conditions are not met.</description>
                                    <value>#0</value>
                                </enumeratedValue>
                                <enumeratedValue>
                                    <name>1</name>
                                    <description>Window B comparison conditions are met.</description>
                                    <value>#1</value>
                                </enumeratedValue>
                            </enumeratedValues>
                        </field>
                    </fields>
                </register>
                <register>
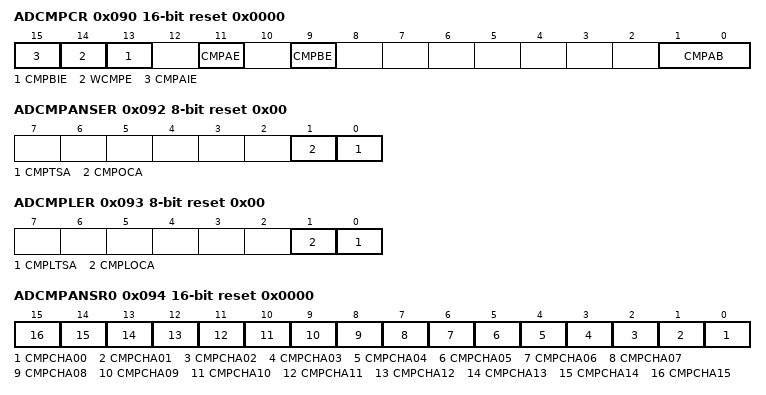
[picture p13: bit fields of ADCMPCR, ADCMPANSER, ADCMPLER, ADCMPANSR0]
                    <name>ADCMPCR</name>
                    <description>A/D Compare Function Control Register</description>
                    <addressOffset>0x090</addressOffset>
                    <size>16</size>
                    <access>read-write</access>
                    <resetValue>0x0000</resetValue>
                    <resetMask>0xffff</resetMask>
                    <fields>
                        <field>
                            <name>CMPAB</name>
                            <description>Window A/B Composite Conditions Setting</description>
                            <lsb>0</lsb>
                            <msb>1</msb>
                            <access>read-write</access>
                            <enumeratedValues>
                                <enumeratedValue>
                                    <name>00</name>
                                    <description>Output ADC12i_WCMPM (i = 0, 1) when window A OR window B comparison conditions are met. Otherwise, output ADC12i_WCMPUM (i = 0, 1).</description>
                                    <value>#00</value>
                                </enumeratedValue>
                                <enumeratedValue>
                                    <name>01</name>
                                    <description>Output ADC12i_WCMPM (i = 0, 1) when window A EXOR window B comparison conditions are met. Otherwise, output ADC12i_WCMPUM (i = 0, 1).</description>
                                    <value>#01</value>
                                </enumeratedValue>
                                <enumeratedValue>
                                    <name>10</name>
                                    <description>Output ADC12i_WCMPM (i = 0, 1) when window A AND window B comparison conditions are met. Otherwise, output ADC12i_WCMPUM (i = 0, 1).</description>
                                    <value>#10</value>
                                </enumeratedValue>
                                <enumeratedValue>
                                    <name>11</name>
                                    <description>Setting prohibited.</description>
                                    <value>#11</value>
                                </enumeratedValue>
                            </enumeratedValues>
                        </field>
                        <field>
                            <name>CMPBE</name>
                            <description>Compare Window B Operation Enable</description>
                            <lsb>9</lsb>
                            <msb>9</msb>
                            <access>read-write</access>
                            <enumeratedValues>
                                <enumeratedValue>
                                    <name>0</name>
                                    <description>Disable compare window B operation. Disable ADC12i_WCMPM (i = 0, 1) and ADC12i_WCMPUM (i = 0, 1) outputs. </description>
                                    <value>#0</value>
                                </enumeratedValue>
                                <enumeratedValue>
                                    <name>1</name>
                                    <description>Enable compare window B operation.</description>
                                    <value>#1</value>
                                </enumeratedValue>
                            </enumeratedValues>
                        </field>
                        <field>
                            <name>CMPAE</name>
                            <description>Compare Window A Operation Enable</description>
                            <lsb>11</lsb>
                            <msb>11</msb>
                            <access>read-write</access>
                            <enumeratedValues>
                                <enumeratedValue>
                                    <name>0</name>
                                    <description>Disable compare window A operation. Disable ADC12i_WCMPM (i = 0, 1) and ADC12i_WCMPUM (i = 0, 1) outputs. </description>
                                    <value>#0</value>
                                </enumeratedValue>
                                <enumeratedValue>
                                    <name>1</name>
                                    <description>Enable compare window A operation.</description>
                                    <value>#1</value>
                                </enumeratedValue>
                            </enumeratedValues>
                        </field>
                        <field>
                            <name>CMPBIE</name>
                            <description>Compare B Interrupt Enable</description>
                            <lsb>13</lsb>
                            <msb>13</msb>
                            <access>read-write</access>
                            <enumeratedValues>
                                <enumeratedValue>
                                    <name>0</name>
                                    <description>Disable ADC12i_CMPBI (i = 0, 1) interrupt when comparison conditions (window B) are met.</description>
                                    <value>#0</value>
                                </enumeratedValue>
                                <enumeratedValue>
                                    <name>1</name>
                                    <description>Enable ADC12i_CMPBI (i = 0, 1) interrupt when comparison conditions (window B) are met.</description>
                                    <value>#1</value>
                                </enumeratedValue>
                            </enumeratedValues>
                        </field>
                        <field>
                            <name>WCMPE</name>
                            <description>Window Function Setting</description>
                            <lsb>14</lsb>
                            <msb>14</msb>
                            <access>read-write</access>
                            <enumeratedValues>
                                <enumeratedValue>
                                    <name>0</name>
                                    <description>Disable window function Window A and window B operate as a comparator to compare the single value on the lower side with the A/D conversion result. </description>
                                    <value>#0</value>
                                </enumeratedValue>
                                <enumeratedValue>
                                    <name>1</name>
                                    <description>Enable window function Window A and window B operate as a comparator to compare the two values on the upper and lower sides with the A/D conversion result. </description>
                                    <value>#1</value>
                                </enumeratedValue>
                            </enumeratedValues>
                        </field>
                        <field>
                            <name>CMPAIE</name>
                            <description>Compare A Interrupt Enable</description>
                            <lsb>15</lsb>
                            <msb>15</msb>
                            <access>read-write</access>
                            <enumeratedValues>
                                <enumeratedValue>
                                    <name>0</name>
                                    <description>Disable ADC12i_CMPAI (i = 0, 1) interrupt when comparison conditions (window A) are met.</description>
                                    <value>#0</value>
                                </enumeratedValue>
                                <enumeratedValue>
                                    <name>1</name>
                                    <description>Enable ADC12i_CMPAI (i = 0, 1) interrupt when comparison conditions (window A) are met.</description>
                                    <value>#1</value>
                                </enumeratedValue>
                            </enumeratedValues>
                        </field>
                    </fields>
                </register>
                <register>
                    <name>ADCMPANSER</name>
                    <description>A/D Compare Function Window A Extended Input Select Register</description>
                    <addressOffset>0x092</addressOffset>
                    <size>8</size>
                    <access>read-write</access>
                    <resetValue>0x00</resetValue>
                    <resetMask>0xff</resetMask>
                    <fields>
                        <field>
                            <name>CMPTSA</name>
                            <description>Temperature Sensor Output Compare Select</description>
                            <lsb>0</lsb>
                            <msb>0</msb>
                            <access>read-write</access>
                            <enumeratedValues>
                                <enumeratedValue>
                                    <name>0</name>
                                    <description>Exclude the temperature sensor output from the compare Window A target range.</description>
                                    <value>#0</value>
                                </enumeratedValue>
                                <enumeratedValue>
                                    <name>1</name>
                                    <description>Include the temperature sensor output in the compare Window A target range.</description>
                                    <value>#1</value>
                                </enumeratedValue>
                            </enumeratedValues>
                        </field>
                        <field>
                            <name>CMPOCA</name>
                            <description>Internal Reference Voltage Compare Select</description>
                            <lsb>1</lsb>
                            <msb>1</msb>
                            <access>read-write</access>
                            <enumeratedValues>
                                <enumeratedValue>
                                    <name>0</name>
                                    <description>Exclude the internal reference voltage from the compare Window A target range.</description>
                                    <value>#0</value>
                                </enumeratedValue>
                                <enumeratedValue>
                                    <name>1</name>
                                    <description>Include the internal reference voltage in the compare Window A target range. </description>
                                    <value>#1</value>
                                </enumeratedValue>
                            </enumeratedValues>
                        </field>
                    </fields>
                </register>
                <register>
                    <name>ADCMPLER</name>
                    <description>A/D Compare Function Window A Extended Input Comparison Condition Setting Register</description>
                    <addressOffset>0x093</addressOffset>
                    <size>8</size>
                    <access>read-write</access>
                    <resetValue>0x00</resetValue>
                    <resetMask>0xff</resetMask>
                    <fields>
                        <field>
                            <name>CMPLTSA</name>
                            <description>Compare Window A Temperature Sensor Output Comparison Condition Select</description>
                            <lsb>0</lsb>
                            <msb>0</msb>
                            <access>read-write</access>
                            <enumeratedValues>
                                <enumeratedValue>
                                    <name>0</name>
                                    <description>When window function is disabled (ADCMPCR.WCMPE = 0) : ADCMPDR0 value &gt; A/D-converted valueCompare Window A Temperature Sensor Output Comparison Condition Select When window function is enabled (ADCMPCR.WCMPE = 1) : Compare Window A Temperature Sensor Output Comparison ConditionA/D-converted value &lt; ADCMPDR0 value, or A/D-converted value &gt; ADCMPDR1 value </description>
                                    <value>#0</value>
                                </enumeratedValue>
                                <enumeratedValue>
                                    <name>1</name>
                                    <description>When window function is disabled (ADCMPCR.WCMPE = 0) : ADCMPDR0 value &lt; A/D-converted value When window function is enabled (ADCMPCR.WCMPE = 1) : ADCMPDR0 value &lt; A/D-converted value &lt; ADCMPDR1 value </description>
                                    <value>#1</value>
                                </enumeratedValue>
                            </enumeratedValues>
                        </field>
                        <field>
                            <name>CMPLOCA</name>
                            <description>Compare Window A Internal Reference Voltage Comparison Condition Select</description>
                            <lsb>1</lsb>
                            <msb>1</msb>
                            <access>read-write</access>
                            <enumeratedValues>
                                <enumeratedValue>
                                    <name>0</name>
                                    <description>When window function is disabled (ADCMPCR.WCMPE = 0) : ADCMPDR0 value &gt; A/D-converted value When window function is enabled (ADCMPCR.WCMPE = 1): A/D-converted value &lt; ADCMPDR0 value, or A/D-converted value &gt; ADCMPDR1 value </description>
                                    <value>#0</value>
                                </enumeratedValue>
                                <enumeratedValue>
                                    <name>1</name>
                                    <description>When window function is disabled (ADCMPCR.WCMPE = 0): ADCMPDR0 value &lt; A/D-converted value When window function is enabled (ADCMPCR.WCMPE = 1): ADCMPDR0 value &lt; A/D-converted value &lt; ADCMPDR1 value </description>
                                    <value>#1</value>
                                </enumeratedValue>
                            </enumeratedValues>
                        </field>
                    </fields>
                </register>
                <register>
                    <name>ADCMPANSR0</name>
                    <description>A/D Compare Function Window A Channel Select Register 0</description>
                    <addressOffset>0x094</addressOffset>
                    <size>16</size>
                    <access>read-write</access>
                    <resetValue>0x0000</resetValue>
                    <resetMask>0xffff</resetMask>
                    <fields>
                        <field>
                            <name>CMPCHA00</name>
                            <description>Compare Window A Channel Select</description>
                            <lsb>0</lsb>
                            <msb>0</msb>
                            <access>read-write</access>
                            <enumeratedValues>
                                <enumeratedValue>
                                    <name>0</name>
                                    <description>Disable compare function for associated input channel</description>
                                    <value>#0</value>
                                </enumeratedValue>
                                <enumeratedValue>
                                    <name>1</name>
                                    <description>Enable compare function for associated input channel</description>
                                    <value>#1</value>
                                </enumeratedValue>
                            </enumeratedValues>
                        </field>
                        <field>
                            <name>CMPCHA01</name>
                            <description>Compare Window A Channel Select</description>
                            <lsb>1</lsb>
                            <msb>1</msb>
                            <access>read-write</access>
                            <enumeratedValues>
                                <enumeratedValue>
                                    <name>0</name>
                                    <description>Disable compare function for associated input channel</description>
                                    <value>#0</value>
                                </enumeratedValue>
                                <enumeratedValue>
                                    <name>1</name>
                                    <description>Enable compare function for associated input channel</description>
                                    <value>#1</value>
                                </enumeratedValue>
                            </enumeratedValues>
                        </field>
                        <field>
                            <name>CMPCHA02</name>
                            <description>Compare Window A Channel Select</description>
                            <lsb>2</lsb>
                            <msb>2</msb>
                            <access>read-write</access>
                            <enumeratedValues>
                                <enumeratedValue>
                                    <name>0</name>
                                    <description>Disable compare function for associated input channel</description>
                                    <value>#0</value>
                                </enumeratedValue>
                                <enumeratedValue>
                                    <name>1</name>
                                    <description>Enable compare function for associated input channel</description>
                                    <value>#1</value>
                                </enumeratedValue>
                            </enumeratedValues>
                        </field>
                        <field>
                            <name>CMPCHA03</name>
                            <description>Compare Window A Channel Select</description>
                            <lsb>3</lsb>
                            <msb>3</msb>
                            <access>read-write</access>
                            <enumeratedValues>
                                <enumeratedValue>
                                    <name>0</name>
                                    <description>Disable compare function for associated input channel</description>
                                    <value>#0</value>
                                </enumeratedValue>
                                <enumeratedValue>
                                    <name>1</name>
                                    <description>Enable compare function for associated input channel</description>
                                    <value>#1</value>
                                </enumeratedValue>
                            </enumeratedValues>
                        </field>
                        <field>
                            <name>CMPCHA04</name>
                            <description>Compare Window A Channel Select</description>
                            <lsb>4</lsb>
                            <msb>4</msb>
                            <access>read-write</access>
                            <enumeratedValues>
                                <enumeratedValue>
                                    <name>0</name>
                                    <description>Disable compare function for associated input channel</description>
                                    <value>#0</value>
                                </enumeratedValue>
                                <enumeratedValue>
                                    <name>1</name>
                                    <description>Enable compare function for associated input channel</description>
                                    <value>#1</value>
                                </enumeratedValue>
                            </enumeratedValues>
                        </field>
                        <field>
                            <name>CMPCHA05</name>
                            <description>Compare Window A Channel Select</description>
                            <lsb>5</lsb>
                            <msb>5</msb>
                            <access>read-write</access>
                            <enumeratedValues>
                                <enumeratedValue>
                                    <name>0</name>
                                    <description>Disable compare function for associated input channel</description>
                                    <value>#0</value>
                                </enumeratedValue>
                                <enumeratedValue>
                                    <name>1</name>
                                    <description>Enable compare function for associated input channel</description>
                                    <value>#1</value>
                                </enumeratedValue>
                            </enumeratedValues>
                        </field>
                        <field>
                            <name>CMPCHA06</name>
                            <description>Compare Window A Channel Select</description>
                            <lsb>6</lsb>
                            <msb>6</msb>
                            <access>read-write</access>
                            <enumeratedValues>
                                <enumeratedValue>
                                    <name>0</name>
                                    <description>Disable compare function for associated input channel</description>
                                    <value>#0</value>
                                </enumeratedValue>
                                <enumeratedValue>
                                    <name>1</name>
                                    <description>Enable compare function for associated input channel</description>
                                    <value>#1</value>
                                </enumeratedValue>
                            </enumeratedValues>
                        </field>
                        <field>
                            <name>CMPCHA07</name>
                            <description>Compare Window A Channel Select</description>
                            <lsb>7</lsb>
                            <msb>7</msb>
                            <access>read-write</access>
                            <enumeratedValues>
                                <enumeratedValue>
                                    <name>0</name>
                                    <description>Disable compare function for associated input channel</description>
                                    <value>#0</value>
                                </enumeratedValue>
                                <enumeratedValue>
                                    <name>1</name>
                                    <description>Enable compare function for associated input channel</description>
                                    <value>#1</value>
                                </enumeratedValue>
                            </enumeratedValues>
                        </field>
                        <field>
                            <name>CMPCHA08</name>
                            <description>Compare Window A Channel Select</description>
                            <lsb>8</lsb>
                            <msb>8</msb>
                            <access>read-write</access>
                            <enumeratedValues>
                                <enumeratedValue>
                                    <name>0</name>
                                    <description>Disable compare function for associated input channel</description>
                                    <value>#0</value>
                                </enumeratedValue>
                                <enumeratedValue>
                                    <name>1</name>
                                    <description>Enable compare function for associated input channel</description>
                                    <value>#1</value>
                                </enumeratedValue>
                            </enumeratedValues>
                        </field>
                        <field>
                            <name>CMPCHA09</name>
                            <description>Compare Window A Channel Select</description>
                            <lsb>9</lsb>
                            <msb>9</msb>
                            <access>read-write</access>
                            <enumeratedValues>
                                <enumeratedValue>
                                    <name>0</name>
                                    <description>Disable compare function for associated input channel</description>
                                    <value>#0</value>
                                </enumeratedValue>
                                <enumeratedValue>
                                    <name>1</name>
                                    <description>Enable compare function for associated input channel</description>
                                    <value>#1</value>
                                </enumeratedValue>
                            </enumeratedValues>
                        </field>
                        <field>
                            <name>CMPCHA10</name>
                            <description>Compare Window A Channel Select</description>
                            <lsb>10</lsb>
                            <msb>10</msb>
                            <access>read-write</access>
                            <enumeratedValues>
                                <enumeratedValue>
                                    <name>0</name>
                                    <description>Disable compare function for associated input channel</description>
                                    <value>#0</value>
                                </enumeratedValue>
                                <enumeratedValue>
                                    <name>1</name>
                                    <description>Enable compare function for associated input channel</description>
                                    <value>#1</value>
                                </enumeratedValue>
                            </enumeratedValues>
                        </field>
                        <field>
                            <name>CMPCHA11</name>
                            <description>Compare Window A Channel Select</description>
                            <lsb>11</lsb>
                            <msb>11</msb>
                            <access>read-write</access>
                            <enumeratedValues>
                                <enumeratedValue>
                                    <name>0</name>
                                    <description>Disable compare function for associated input channel</description>
                                    <value>#0</value>
                                </enumeratedValue>
                                <enumeratedValue>
                                    <name>1</name>
                                    <description>Enable compare function for associated input channel</description>
                                    <value>#1</value>
                                </enumeratedValue>
                            </enumeratedValues>
                        </field>
                        <field>
                            <name>CMPCHA12</name>
                            <description>Compare Window A Channel Select</description>
                            <lsb>12</lsb>
                            <msb>12</msb>
                            <access>read-write</access>
                            <enumeratedValues>
                                <enumeratedValue>
                                    <name>0</name>
                                    <description>Disable compare function for associated input channel</description>
                                    <value>#0</value>
                                </enumeratedValue>
                                <enumeratedValue>
                                    <name>1</name>
                                    <description>Enable compare function for associated input channel</description>
                                    <value>#1</value>
                                </enumeratedValue>
                            </enumeratedValues>
                        </field>
                        <field>
                            <name>CMPCHA13</name>
                            <description>Compare Window A Channel Select</description>
                            <lsb>13</lsb>
                            <msb>13</msb>
                            <access>read-write</access>
                            <enumeratedValues>
                                <enumeratedValue>
                                    <name>0</name>
                                    <description>Disable compare function for associated input channel</description>
                                    <value>#0</value>
                                </enumeratedValue>
                                <enumeratedValue>
                                    <name>1</name>
                                    <description>Enable compare function for associated input channel</description>
                                    <value>#1</value>
                                </enumeratedValue>
                            </enumeratedValues>
                        </field>
                        <field>
                            <name>CMPCHA14</name>
                            <description>Compare Window A Channel Select</description>
                            <lsb>14</lsb>
                            <msb>14</msb>
                            <access>read-write</access>
                            <enumeratedValues>
                                <enumeratedValue>
                                    <name>0</name>
                                    <description>Disable compare function for associated input channel</description>
                                    <value>#0</value>
                                </enumeratedValue>
                                <enumeratedValue>
                                    <name>1</name>
                                    <description>Enable compare function for associated input channel</description>
                                    <value>#1</value>
                                </enumeratedValue>
                            </enumeratedValues>
                        </field>
                        <field>
                            <name>CMPCHA15</name>
                            <description>Compare Window A Channel Select</description>
                            <lsb>15</lsb>
                            <msb>15</msb>
                            <access>read-write</access>
                            <enumeratedValues>
                                <enumeratedValue>
                                    <name>0</name>
                                    <description>Disable compare function for associated input channel</description>
                                    <value>#0</value>
                                </enumeratedValue>
                                <enumeratedValue>
                                    <name>1</name>
                                    <description>Enable compare function for associated input channel</description>
                                    <value>#1</value>
                                </enumeratedValue>
                            </enumeratedValues>
                        </field>
                    </fields>
                </register>
                <register>
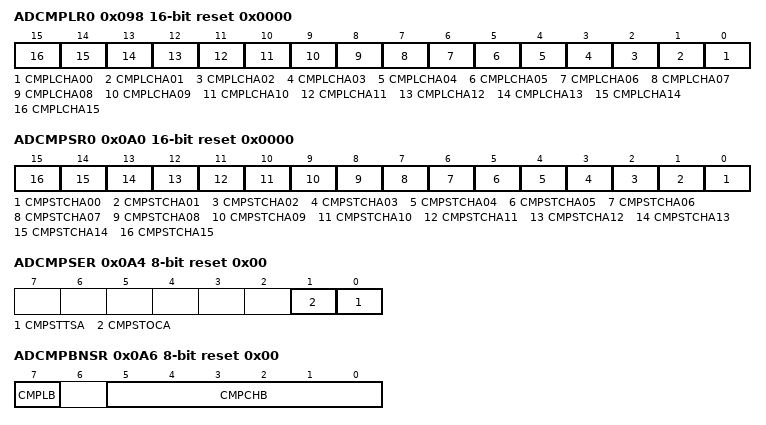
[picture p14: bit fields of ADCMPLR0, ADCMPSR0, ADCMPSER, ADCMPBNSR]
                    <name>ADCMPLR0</name>
                    <description>A/D Compare Function Window A Comparison Condition Setting Register 0</description>
                    <addressOffset>0x098</addressOffset>
                    <size>16</size>
                    <access>read-write</access>
                    <resetValue>0x0000</resetValue>
                    <resetMask>0xffff</resetMask>
                    <fields>
                        <field>
                            <name>CMPLCHA00</name>
                            <description>Compare Window A Comparison Condition Select</description>
                            <lsb>0</lsb>
                            <msb>0</msb>
                            <access>read-write</access>
                            <enumeratedValues>
                                <enumeratedValue>
                                    <name>0</name>
                                    <description>When window function is disabled (ADCMPCR.WCMPE = 0): ADCMPDR0 value &gt; A/D-converted value When window function is enabled (ADCMPCR.WCMPE = 1): A/D-converted value &lt; ADCMPDR0 value, or ADCMPDR1 value &lt; A/D-converted value </description>
                                    <value>#0</value>
                                </enumeratedValue>
                                <enumeratedValue>
                                    <name>1</name>
                                    <description>When window function is disabled (ADCMPCR.WCMPE = 0): ADCMPDR0 value &lt; A/D-converted value When window function is enabled (ADCMPCR.WCMPE = 1): ADCMPDR0 value &lt; A/D-converted value &lt; ADCMPDR1 value </description>
                                    <value>#1</value>
                                </enumeratedValue>
                            </enumeratedValues>
                        </field>
                        <field>
                            <name>CMPLCHA01</name>
                            <description>Compare Window A Comparison Condition Select</description>
                            <lsb>1</lsb>
                            <msb>1</msb>
                            <access>read-write</access>
                            <enumeratedValues>
                                <enumeratedValue>
                                    <name>0</name>
                                    <description>When window function is disabled (ADCMPCR.WCMPE = 0): ADCMPDR0 value &gt; A/D-converted value When window function is enabled (ADCMPCR.WCMPE = 1): A/D-converted value &lt; ADCMPDR0 value, or ADCMPDR1 value &lt; A/D-converted value </description>
                                    <value>#0</value>
                                </enumeratedValue>
                                <enumeratedValue>
                                    <name>1</name>
                                    <description>When window function is disabled (ADCMPCR.WCMPE = 0): ADCMPDR0 value &lt; A/D-converted value When window function is enabled (ADCMPCR.WCMPE = 1): ADCMPDR0 value &lt; A/D-converted value &lt; ADCMPDR1 value </description>
                                    <value>#1</value>
                                </enumeratedValue>
                            </enumeratedValues>
                        </field>
                        <field>
                            <name>CMPLCHA02</name>
                            <description>Compare Window A Comparison Condition Select</description>
                            <lsb>2</lsb>
                            <msb>2</msb>
                            <access>read-write</access>
                            <enumeratedValues>
                                <enumeratedValue>
                                    <name>0</name>
                                    <description>When window function is disabled (ADCMPCR.WCMPE = 0): ADCMPDR0 value &gt; A/D-converted value When window function is enabled (ADCMPCR.WCMPE = 1): A/D-converted value &lt; ADCMPDR0 value, or ADCMPDR1 value &lt; A/D-converted value </description>
                                    <value>#0</value>
                                </enumeratedValue>
                                <enumeratedValue>
                                    <name>1</name>
                                    <description>When window function is disabled (ADCMPCR.WCMPE = 0): ADCMPDR0 value &lt; A/D-converted value When window function is enabled (ADCMPCR.WCMPE = 1): ADCMPDR0 value &lt; A/D-converted value &lt; ADCMPDR1 value </description>
                                    <value>#1</value>
                                </enumeratedValue>
                            </enumeratedValues>
                        </field>
                        <field>
                            <name>CMPLCHA03</name>
                            <description>Compare Window A Comparison Condition Select</description>
                            <lsb>3</lsb>
                            <msb>3</msb>
                            <access>read-write</access>
                            <enumeratedValues>
                                <enumeratedValue>
                                    <name>0</name>
                                    <description>When window function is disabled (ADCMPCR.WCMPE = 0): ADCMPDR0 value &gt; A/D-converted value When window function is enabled (ADCMPCR.WCMPE = 1): A/D-converted value &lt; ADCMPDR0 value, or ADCMPDR1 value &lt; A/D-converted value </description>
                                    <value>#0</value>
                                </enumeratedValue>
                                <enumeratedValue>
                                    <name>1</name>
                                    <description>When window function is disabled (ADCMPCR.WCMPE = 0): ADCMPDR0 value &lt; A/D-converted value When window function is enabled (ADCMPCR.WCMPE = 1): ADCMPDR0 value &lt; A/D-converted value &lt; ADCMPDR1 value </description>
                                    <value>#1</value>
                                </enumeratedValue>
                            </enumeratedValues>
                        </field>
                        <field>
                            <name>CMPLCHA04</name>
                            <description>Compare Window A Comparison Condition Select</description>
                            <lsb>4</lsb>
                            <msb>4</msb>
                            <access>read-write</access>
                            <enumeratedValues>
                                <enumeratedValue>
                                    <name>0</name>
                                    <description>When window function is disabled (ADCMPCR.WCMPE = 0): ADCMPDR0 value &gt; A/D-converted value When window function is enabled (ADCMPCR.WCMPE = 1): A/D-converted value &lt; ADCMPDR0 value, or ADCMPDR1 value &lt; A/D-converted value </description>
                                    <value>#0</value>
                                </enumeratedValue>
                                <enumeratedValue>
                                    <name>1</name>
                                    <description>When window function is disabled (ADCMPCR.WCMPE = 0): ADCMPDR0 value &lt; A/D-converted value When window function is enabled (ADCMPCR.WCMPE = 1): ADCMPDR0 value &lt; A/D-converted value &lt; ADCMPDR1 value </description>
                                    <value>#1</value>
                                </enumeratedValue>
                            </enumeratedValues>
                        </field>
                        <field>
                            <name>CMPLCHA05</name>
                            <description>Compare Window A Comparison Condition Select</description>
                            <lsb>5</lsb>
                            <msb>5</msb>
                            <access>read-write</access>
                            <enumeratedValues>
                                <enumeratedValue>
                                    <name>0</name>
                                    <description>When window function is disabled (ADCMPCR.WCMPE = 0): ADCMPDR0 value &gt; A/D-converted value When window function is enabled (ADCMPCR.WCMPE = 1): A/D-converted value &lt; ADCMPDR0 value, or ADCMPDR1 value &lt; A/D-converted value </description>
                                    <value>#0</value>
                                </enumeratedValue>
                                <enumeratedValue>
                                    <name>1</name>
                                    <description>When window function is disabled (ADCMPCR.WCMPE = 0): ADCMPDR0 value &lt; A/D-converted value When window function is enabled (ADCMPCR.WCMPE = 1): ADCMPDR0 value &lt; A/D-converted value &lt; ADCMPDR1 value </description>
                                    <value>#1</value>
                                </enumeratedValue>
                            </enumeratedValues>
                        </field>
                        <field>
                            <name>CMPLCHA06</name>
                            <description>Compare Window A Comparison Condition Select</description>
                            <lsb>6</lsb>
                            <msb>6</msb>
                            <access>read-write</access>
                            <enumeratedValues>
                                <enumeratedValue>
                                    <name>0</name>
                                    <description>When window function is disabled (ADCMPCR.WCMPE = 0): ADCMPDR0 value &gt; A/D-converted value When window function is enabled (ADCMPCR.WCMPE = 1): A/D-converted value &lt; ADCMPDR0 value, or ADCMPDR1 value &lt; A/D-converted value </description>
                                    <value>#0</value>
                                </enumeratedValue>
                                <enumeratedValue>
                                    <name>1</name>
                                    <description>When window function is disabled (ADCMPCR.WCMPE = 0): ADCMPDR0 value &lt; A/D-converted value When window function is enabled (ADCMPCR.WCMPE = 1): ADCMPDR0 value &lt; A/D-converted value &lt; ADCMPDR1 value </description>
                                    <value>#1</value>
                                </enumeratedValue>
                            </enumeratedValues>
                        </field>
                        <field>
                            <name>CMPLCHA07</name>
                            <description>Compare Window A Comparison Condition Select</description>
                            <lsb>7</lsb>
                            <msb>7</msb>
                            <access>read-write</access>
                            <enumeratedValues>
                                <enumeratedValue>
                                    <name>0</name>
                                    <description>When window function is disabled (ADCMPCR.WCMPE = 0): ADCMPDR0 value &gt; A/D-converted value When window function is enabled (ADCMPCR.WCMPE = 1): A/D-converted value &lt; ADCMPDR0 value, or ADCMPDR1 value &lt; A/D-converted value </description>
                                    <value>#0</value>
                                </enumeratedValue>
                                <enumeratedValue>
                                    <name>1</name>
                                    <description>When window function is disabled (ADCMPCR.WCMPE = 0): ADCMPDR0 value &lt; A/D-converted value When window function is enabled (ADCMPCR.WCMPE = 1): ADCMPDR0 value &lt; A/D-converted value &lt; ADCMPDR1 value </description>
                                    <value>#1</value>
                                </enumeratedValue>
                            </enumeratedValues>
                        </field>
                        <field>
                            <name>CMPLCHA08</name>
                            <description>Compare Window A Comparison Condition Select</description>
                            <lsb>8</lsb>
                            <msb>8</msb>
                            <access>read-write</access>
                            <enumeratedValues>
                                <enumeratedValue>
                                    <name>0</name>
                                    <description>When window function is disabled (ADCMPCR.WCMPE = 0): ADCMPDR0 value &gt; A/D-converted value When window function is enabled (ADCMPCR.WCMPE = 1): A/D-converted value &lt; ADCMPDR0 value, or ADCMPDR1 value &lt; A/D-converted value </description>
                                    <value>#0</value>
                                </enumeratedValue>
                                <enumeratedValue>
                                    <name>1</name>
                                    <description>When window function is disabled (ADCMPCR.WCMPE = 0): ADCMPDR0 value &lt; A/D-converted value When window function is enabled (ADCMPCR.WCMPE = 1): ADCMPDR0 value &lt; A/D-converted value &lt; ADCMPDR1 value </description>
                                    <value>#1</value>
                                </enumeratedValue>
                            </enumeratedValues>
                        </field>
                        <field>
                            <name>CMPLCHA09</name>
                            <description>Compare Window A Comparison Condition Select</description>
                            <lsb>9</lsb>
                            <msb>9</msb>
                            <access>read-write</access>
                            <enumeratedValues>
                                <enumeratedValue>
                                    <name>0</name>
                                    <description>When window function is disabled (ADCMPCR.WCMPE = 0): ADCMPDR0 value &gt; A/D-converted value When window function is enabled (ADCMPCR.WCMPE = 1): A/D-converted value &lt; ADCMPDR0 value, or ADCMPDR1 value &lt; A/D-converted value </description>
                                    <value>#0</value>
                                </enumeratedValue>
                                <enumeratedValue>
                                    <name>1</name>
                                    <description>When window function is disabled (ADCMPCR.WCMPE = 0): ADCMPDR0 value &lt; A/D-converted value When window function is enabled (ADCMPCR.WCMPE = 1): ADCMPDR0 value &lt; A/D-converted value &lt; ADCMPDR1 value </description>
                                    <value>#1</value>
                                </enumeratedValue>
                            </enumeratedValues>
                        </field>
                        <field>
                            <name>CMPLCHA10</name>
                            <description>Compare Window A Comparison Condition Select</description>
                            <lsb>10</lsb>
                            <msb>10</msb>
                            <access>read-write</access>
                            <enumeratedValues>
                                <enumeratedValue>
                                    <name>0</name>
                                    <description>When window function is disabled (ADCMPCR.WCMPE = 0): ADCMPDR0 value &gt; A/D-converted value When window function is enabled (ADCMPCR.WCMPE = 1): A/D-converted value &lt; ADCMPDR0 value, or ADCMPDR1 value &lt; A/D-converted value </description>
                                    <value>#0</value>
                                </enumeratedValue>
                                <enumeratedValue>
                                    <name>1</name>
                                    <description>When window function is disabled (ADCMPCR.WCMPE = 0): ADCMPDR0 value &lt; A/D-converted value When window function is enabled (ADCMPCR.WCMPE = 1): ADCMPDR0 value &lt; A/D-converted value &lt; ADCMPDR1 value </description>
                                    <value>#1</value>
                                </enumeratedValue>
                            </enumeratedValues>
                        </field>
                        <field>
                            <name>CMPLCHA11</name>
                            <description>Compare Window A Comparison Condition Select</description>
                            <lsb>11</lsb>
                            <msb>11</msb>
                            <access>read-write</access>
                            <enumeratedValues>
                                <enumeratedValue>
                                    <name>0</name>
                                    <description>When window function is disabled (ADCMPCR.WCMPE = 0): ADCMPDR0 value &gt; A/D-converted value When window function is enabled (ADCMPCR.WCMPE = 1): A/D-converted value &lt; ADCMPDR0 value, or ADCMPDR1 value &lt; A/D-converted value </description>
                                    <value>#0</value>
                                </enumeratedValue>
                                <enumeratedValue>
                                    <name>1</name>
                                    <description>When window function is disabled (ADCMPCR.WCMPE = 0): ADCMPDR0 value &lt; A/D-converted value When window function is enabled (ADCMPCR.WCMPE = 1): ADCMPDR0 value &lt; A/D-converted value &lt; ADCMPDR1 value </description>
                                    <value>#1</value>
                                </enumeratedValue>
                            </enumeratedValues>
                        </field>
                        <field>
                            <name>CMPLCHA12</name>
                            <description>Compare Window A Comparison Condition Select</description>
                            <lsb>12</lsb>
                            <msb>12</msb>
                            <access>read-write</access>
                            <enumeratedValues>
                                <enumeratedValue>
                                    <name>0</name>
                                    <description>When window function is disabled (ADCMPCR.WCMPE = 0): ADCMPDR0 value &gt; A/D-converted value When window function is enabled (ADCMPCR.WCMPE = 1): A/D-converted value &lt; ADCMPDR0 value, or ADCMPDR1 value &lt; A/D-converted value </description>
                                    <value>#0</value>
                                </enumeratedValue>
                                <enumeratedValue>
                                    <name>1</name>
                                    <description>When window function is disabled (ADCMPCR.WCMPE = 0): ADCMPDR0 value &lt; A/D-converted value When window function is enabled (ADCMPCR.WCMPE = 1): ADCMPDR0 value &lt; A/D-converted value &lt; ADCMPDR1 value </description>
                                    <value>#1</value>
                                </enumeratedValue>
                            </enumeratedValues>
                        </field>
                        <field>
                            <name>CMPLCHA13</name>
                            <description>Compare Window A Comparison Condition Select</description>
                            <lsb>13</lsb>
                            <msb>13</msb>
                            <access>read-write</access>
                            <enumeratedValues>
                                <enumeratedValue>
                                    <name>0</name>
                                    <description>When window function is disabled (ADCMPCR.WCMPE = 0): ADCMPDR0 value &gt; A/D-converted value When window function is enabled (ADCMPCR.WCMPE = 1): A/D-converted value &lt; ADCMPDR0 value, or ADCMPDR1 value &lt; A/D-converted value </description>
                                    <value>#0</value>
                                </enumeratedValue>
                                <enumeratedValue>
                                    <name>1</name>
                                    <description>When window function is disabled (ADCMPCR.WCMPE = 0): ADCMPDR0 value &lt; A/D-converted value When window function is enabled (ADCMPCR.WCMPE = 1): ADCMPDR0 value &lt; A/D-converted value &lt; ADCMPDR1 value </description>
                                    <value>#1</value>
                                </enumeratedValue>
                            </enumeratedValues>
                        </field>
                        <field>
                            <name>CMPLCHA14</name>
                            <description>Compare Window A Comparison Condition Select</description>
                            <lsb>14</lsb>
                            <msb>14</msb>
                            <access>read-write</access>
                            <enumeratedValues>
                                <enumeratedValue>
                                    <name>0</name>
                                    <description>When window function is disabled (ADCMPCR.WCMPE = 0): ADCMPDR0 value &gt; A/D-converted value When window function is enabled (ADCMPCR.WCMPE = 1): A/D-converted value &lt; ADCMPDR0 value, or ADCMPDR1 value &lt; A/D-converted value </description>
                                    <value>#0</value>
                                </enumeratedValue>
                                <enumeratedValue>
                                    <name>1</name>
                                    <description>When window function is disabled (ADCMPCR.WCMPE = 0): ADCMPDR0 value &lt; A/D-converted value When window function is enabled (ADCMPCR.WCMPE = 1): ADCMPDR0 value &lt; A/D-converted value &lt; ADCMPDR1 value </description>
                                    <value>#1</value>
                                </enumeratedValue>
                            </enumeratedValues>
                        </field>
                        <field>
                            <name>CMPLCHA15</name>
                            <description>Compare Window A Comparison Condition Select</description>
                            <lsb>15</lsb>
                            <msb>15</msb>
                            <access>read-write</access>
                            <enumeratedValues>
                                <enumeratedValue>
                                    <name>0</name>
                                    <description>When window function is disabled (ADCMPCR.WCMPE = 0): ADCMPDR0 value &gt; A/D-converted value When window function is enabled (ADCMPCR.WCMPE = 1): A/D-converted value &lt; ADCMPDR0 value, or ADCMPDR1 value &lt; A/D-converted value </description>
                                    <value>#0</value>
                                </enumeratedValue>
                                <enumeratedValue>
                                    <name>1</name>
                                    <description>When window function is disabled (ADCMPCR.WCMPE = 0): ADCMPDR0 value &lt; A/D-converted value When window function is enabled (ADCMPCR.WCMPE = 1): ADCMPDR0 value &lt; A/D-converted value &lt; ADCMPDR1 value </description>
                                    <value>#1</value>
                                </enumeratedValue>
                            </enumeratedValues>
                        </field>
                    </fields>
                </register>
                <register>
                    <dim>2</dim>
                    <dimIncrement>0x2</dimIncrement>
                    <dimIndex>0-1</dimIndex>
                    <name>ADCMPDR%s</name>
                    <description>A/D Compare Function Window A Lower-Side/Upper-Side Level Setting Register</description>
                    <addressOffset>0x09C</addressOffset>
                    <size>16</size>
                    <access>read-write</access>
                    <resetValue>0x0000</resetValue>
                    <resetMask>0xffff</resetMask>
                </register>
                <register>
                    <name>ADCMPSR0</name>
                    <description>A/D Compare Function Window A Channel Status Register 0</description>
                    <addressOffset>0x0A0</addressOffset>
                    <size>16</size>
                    <access>read-write</access>
                    <resetValue>0x0000</resetValue>
                    <resetMask>0xffff</resetMask>
                    <fields>
                        <field>
                            <name>CMPSTCHA00</name>
                            <description>Compare Window A Flag</description>
                            <lsb>0</lsb>
                            <msb>0</msb>
                            <access>read-write</access>
                            <enumeratedValues>
                                <enumeratedValue>
                                    <name>0</name>
                                    <description>Comparison conditions are not met.</description>
                                    <value>#0</value>
                                </enumeratedValue>
                                <enumeratedValue>
                                    <name>1</name>
                                    <description>Comparison conditions are met.</description>
                                    <value>#1</value>
                                </enumeratedValue>
                            </enumeratedValues>
                        </field>
                        <field>
                            <name>CMPSTCHA01</name>
                            <description>Compare Window A Flag</description>
                            <lsb>1</lsb>
                            <msb>1</msb>
                            <access>read-write</access>
                            <enumeratedValues>
                                <enumeratedValue>
                                    <name>0</name>
                                    <description>Comparison conditions are not met.</description>
                                    <value>#0</value>
                                </enumeratedValue>
                                <enumeratedValue>
                                    <name>1</name>
                                    <description>Comparison conditions are met.</description>
                                    <value>#1</value>
                                </enumeratedValue>
                            </enumeratedValues>
                        </field>
                        <field>
                            <name>CMPSTCHA02</name>
                            <description>Compare Window A Flag</description>
                            <lsb>2</lsb>
                            <msb>2</msb>
                            <access>read-write</access>
                            <enumeratedValues>
                                <enumeratedValue>
                                    <name>0</name>
                                    <description>Comparison conditions are not met.</description>
                                    <value>#0</value>
                                </enumeratedValue>
                                <enumeratedValue>
                                    <name>1</name>
                                    <description>Comparison conditions are met.</description>
                                    <value>#1</value>
                                </enumeratedValue>
                            </enumeratedValues>
                        </field>
                        <field>
                            <name>CMPSTCHA03</name>
                            <description>Compare Window A Flag</description>
                            <lsb>3</lsb>
                            <msb>3</msb>
                            <access>read-write</access>
                            <enumeratedValues>
                                <enumeratedValue>
                                    <name>0</name>
                                    <description>Comparison conditions are not met.</description>
                                    <value>#0</value>
                                </enumeratedValue>
                                <enumeratedValue>
                                    <name>1</name>
                                    <description>Comparison conditions are met.</description>
                                    <value>#1</value>
                                </enumeratedValue>
                            </enumeratedValues>
                        </field>
                        <field>
                            <name>CMPSTCHA04</name>
                            <description>Compare Window A Flag</description>
                            <lsb>4</lsb>
                            <msb>4</msb>
                            <access>read-write</access>
                            <enumeratedValues>
                                <enumeratedValue>
                                    <name>0</name>
                                    <description>Comparison conditions are not met.</description>
                                    <value>#0</value>
                                </enumeratedValue>
                                <enumeratedValue>
                                    <name>1</name>
                                    <description>Comparison conditions are met.</description>
                                    <value>#1</value>
                                </enumeratedValue>
                            </enumeratedValues>
                        </field>
                        <field>
                            <name>CMPSTCHA05</name>
                            <description>Compare Window A Flag</description>
                            <lsb>5</lsb>
                            <msb>5</msb>
                            <access>read-write</access>
                            <enumeratedValues>
                                <enumeratedValue>
                                    <name>0</name>
                                    <description>Comparison conditions are not met.</description>
                                    <value>#0</value>
                                </enumeratedValue>
                                <enumeratedValue>
                                    <name>1</name>
                                    <description>Comparison conditions are met.</description>
                                    <value>#1</value>
                                </enumeratedValue>
                            </enumeratedValues>
                        </field>
                        <field>
                            <name>CMPSTCHA06</name>
                            <description>Compare Window A Flag</description>
                            <lsb>6</lsb>
                            <msb>6</msb>
                            <access>read-write</access>
                            <enumeratedValues>
                                <enumeratedValue>
                                    <name>0</name>
                                    <description>Comparison conditions are not met.</description>
                                    <value>#0</value>
                                </enumeratedValue>
                                <enumeratedValue>
                                    <name>1</name>
                                    <description>Comparison conditions are met.</description>
                                    <value>#1</value>
                                </enumeratedValue>
                            </enumeratedValues>
                        </field>
                        <field>
                            <name>CMPSTCHA07</name>
                            <description>Compare Window A Flag</description>
                            <lsb>7</lsb>
                            <msb>7</msb>
                            <access>read-write</access>
                            <enumeratedValues>
                                <enumeratedValue>
                                    <name>0</name>
                                    <description>Comparison conditions are not met.</description>
                                    <value>#0</value>
                                </enumeratedValue>
                                <enumeratedValue>
                                    <name>1</name>
                                    <description>Comparison conditions are met.</description>
                                    <value>#1</value>
                                </enumeratedValue>
                            </enumeratedValues>
                        </field>
                        <field>
                            <name>CMPSTCHA08</name>
                            <description>Compare Window A Flag</description>
                            <lsb>8</lsb>
                            <msb>8</msb>
                            <access>read-write</access>
                            <enumeratedValues>
                                <enumeratedValue>
                                    <name>0</name>
                                    <description>Comparison conditions are not met.</description>
                                    <value>#0</value>
                                </enumeratedValue>
                                <enumeratedValue>
                                    <name>1</name>
                                    <description>Comparison conditions are met.</description>
                                    <value>#1</value>
                                </enumeratedValue>
                            </enumeratedValues>
                        </field>
                        <field>
                            <name>CMPSTCHA09</name>
                            <description>Compare Window A Flag</description>
                            <lsb>9</lsb>
                            <msb>9</msb>
                            <access>read-write</access>
                            <enumeratedValues>
                                <enumeratedValue>
                                    <name>0</name>
                                    <description>Comparison conditions are not met.</description>
                                    <value>#0</value>
                                </enumeratedValue>
                                <enumeratedValue>
                                    <name>1</name>
                                    <description>Comparison conditions are met.</description>
                                    <value>#1</value>
                                </enumeratedValue>
                            </enumeratedValues>
                        </field>
                        <field>
                            <name>CMPSTCHA10</name>
                            <description>Compare Window A Flag</description>
                            <lsb>10</lsb>
                            <msb>10</msb>
                            <access>read-write</access>
                            <enumeratedValues>
                                <enumeratedValue>
                                    <name>0</name>
                                    <description>Comparison conditions are not met.</description>
                                    <value>#0</value>
                                </enumeratedValue>
                                <enumeratedValue>
                                    <name>1</name>
                                    <description>Comparison conditions are met.</description>
                                    <value>#1</value>
                                </enumeratedValue>
                            </enumeratedValues>
                        </field>
                        <field>
                            <name>CMPSTCHA11</name>
                            <description>Compare Window A Flag</description>
                            <lsb>11</lsb>
                            <msb>11</msb>
                            <access>read-write</access>
                            <enumeratedValues>
                                <enumeratedValue>
                                    <name>0</name>
                                    <description>Comparison conditions are not met.</description>
                                    <value>#0</value>
                                </enumeratedValue>
                                <enumeratedValue>
                                    <name>1</name>
                                    <description>Comparison conditions are met.</description>
                                    <value>#1</value>
                                </enumeratedValue>
                            </enumeratedValues>
                        </field>
                        <field>
                            <name>CMPSTCHA12</name>
                            <description>Compare Window A Flag</description>
                            <lsb>12</lsb>
                            <msb>12</msb>
                            <access>read-write</access>
                            <enumeratedValues>
                                <enumeratedValue>
                                    <name>0</name>
                                    <description>Comparison conditions are not met.</description>
                                    <value>#0</value>
                                </enumeratedValue>
                                <enumeratedValue>
                                    <name>1</name>
                                    <description>Comparison conditions are met.</description>
                                    <value>#1</value>
                                </enumeratedValue>
                            </enumeratedValues>
                        </field>
                        <field>
                            <name>CMPSTCHA13</name>
                            <description>Compare Window A Flag</description>
                            <lsb>13</lsb>
                            <msb>13</msb>
                            <access>read-write</access>
                            <enumeratedValues>
                                <enumeratedValue>
                                    <name>0</name>
                                    <description>Comparison conditions are not met.</description>
                                    <value>#0</value>
                                </enumeratedValue>
                                <enumeratedValue>
                                    <name>1</name>
                                    <description>Comparison conditions are met.</description>
                                    <value>#1</value>
                                </enumeratedValue>
                            </enumeratedValues>
                        </field>
                        <field>
                            <name>CMPSTCHA14</name>
                            <description>Compare Window A Flag</description>
                            <lsb>14</lsb>
                            <msb>14</msb>
                            <access>read-write</access>
                            <enumeratedValues>
                                <enumeratedValue>
                                    <name>0</name>
                                    <description>Comparison conditions are not met.</description>
                                    <value>#0</value>
                                </enumeratedValue>
                                <enumeratedValue>
                                    <name>1</name>
                                    <description>Comparison conditions are met.</description>
                                    <value>#1</value>
                                </enumeratedValue>
                            </enumeratedValues>
                        </field>
                        <field>
                            <name>CMPSTCHA15</name>
                            <description>Compare Window A Flag</description>
                            <lsb>15</lsb>
                            <msb>15</msb>
                            <access>read-write</access>
                            <enumeratedValues>
                                <enumeratedValue>
                                    <name>0</name>
                                    <description>Comparison conditions are not met.</description>
                                    <value>#0</value>
                                </enumeratedValue>
                                <enumeratedValue>
                                    <name>1</name>
                                    <description>Comparison conditions are met.</description>
                                    <value>#1</value>
                                </enumeratedValue>
                            </enumeratedValues>
                        </field>
                    </fields>
                </register>
                <register>
                    <name>ADCMPSER</name>
                    <description>A/D Compare Function Window A Extended Input Channel Status Register</description>
                    <addressOffset>0x0A4</addressOffset>
                    <size>8</size>
                    <access>read-write</access>
                    <resetValue>0x00</resetValue>
                    <resetMask>0xff</resetMask>
                    <fields>
                        <field>
                            <name>CMPSTTSA</name>
                            <description>Compare Window A Temperature Sensor Output Compare Flag</description>
                            <lsb>0</lsb>
                            <msb>0</msb>
                            <access>read-write</access>
                            <enumeratedValues>
                                <enumeratedValue>
                                    <name>0</name>
                                    <description>Comparison conditions are not met.</description>
                                    <value>#0</value>
                                </enumeratedValue>
                                <enumeratedValue>
                                    <name>1</name>
                                    <description>Comparison conditions are met.</description>
                                    <value>#1</value>
                                </enumeratedValue>
                            </enumeratedValues>
                        </field>
                        <field>
                            <name>CMPSTOCA</name>
                            <description>Compare Window A Internal Reference Voltage Compare Flag</description>
                            <lsb>1</lsb>
                            <msb>1</msb>
                            <access>read-write</access>
                            <enumeratedValues>
                                <enumeratedValue>
                                    <name>0</name>
                                    <description>Comparison conditions are not met.</description>
                                    <value>#0</value>
                                </enumeratedValue>
                                <enumeratedValue>
                                    <name>1</name>
                                    <description>Comparison conditions are met.</description>
                                    <value>#1</value>
                                </enumeratedValue>
                            </enumeratedValues>
                        </field>
                    </fields>
                </register>
                <register>
                    <name>ADCMPBNSR</name>
                    <description>A/D Compare Function Window B Channel Select Register</description>
                    <addressOffset>0x0A6</addressOffset>
                    <size>8</size>
                    <access>read-write</access>
                    <resetValue>0x00</resetValue>
                    <resetMask>0xff</resetMask>
                    <fields>
                        <field>
                            <name>CMPCHB</name>
                            <description>Compare Window B Channel Select</description>
                            <lsb>0</lsb>
                            <msb>5</msb>
                            <access>read-write</access>
                        </field>
                        <field>
                            <name>CMPLB</name>
                            <description>Compare Window B Comparison Condition Setting</description>
                            <lsb>7</lsb>
                            <msb>7</msb>
                            <access>read-write</access>
                            <enumeratedValues>
                                <enumeratedValue>
                                    <name>0</name>
                                    <description>When window function is disabled (ADCMPCR.WCMPE = 0): ADWINLLB value &gt; A/D-converted value When window function is enabled (ADCMPCR.WCMPE = 1): A/D-converted value &lt; ADWINLLB value, or ADWINULB value &lt; A/D-converted value </description>
                                    <value>#0</value>
                                </enumeratedValue>
                                <enumeratedValue>
                                    <name>1</name>
                                    <description>When window function is disabled (ADCMPCR.WCMPE = 0): ADWINLLB value &lt; A/D-converted value When window function is enabled (ADCMPCR.WCMPE = 1): ADWINLLB value &lt; A/D-converted value &lt; ADWINULB value </description>
                                    <value>#1</value>
                                </enumeratedValue>
                            </enumeratedValues>
                        </field>
                    </fields>
                </register>
                <register>
                    <name>ADWINLLB</name>
                    <description>A/D Compare Function Window B Lower-Side/Upper-Side Level Setting Register</description>
                    <addressOffset>0x0A8</addressOffset>
                    <size>16</size>
                    <access>read-write</access>
                    <resetValue>0x0000</resetValue>
                    <resetMask>0xffff</resetMask>
                </register>
                <register>
                    <name>ADWINULB</name>
                    <description>A/D Compare Function Window B Lower-Side/Upper-Side Level Setting Register</description>
                    <addressOffset>0x0AA</addressOffset>
                    <size>16</size>
                    <access>read-write</access>
                    <resetValue>0x0000</resetValue>
                    <resetMask>0xffff</resetMask>
                </register>
                <register>
                    <name>ADCMPBSR</name>
                    <description>A/D Compare Function Window B Status Register</description>
                    <addressOffset>0x0AC</addressOffset>
                    <size>8</size>
                    <access>read-write</access>
                    <resetValue>0x00</resetValue>
                    <resetMask>0xff</resetMask>
                    <fields>
                        <field>
                            <name>CMPSTB</name>
                            <description>Compare Window B Flag</description>
                            <lsb>0</lsb>
                            <msb>0</msb>
                            <access>read-write</access>
                            <enumeratedValues>
                                <enumeratedValue>
                                    <name>0</name>
                                    <description>Comparison conditions are not met.</description>
                                    <value>#0</value>
                                </enumeratedValue>
                                <enumeratedValue>
                                    <name>1</name>
                                    <description>Comparison conditions are met.</description>
                                    <value>#1</value>
                                </enumeratedValue>
                            </enumeratedValues>
                        </field>
                    </fields>
                </register>
                <register>
                    <dim>16</dim>
                    <dimIncrement>0x2</dimIncrement>
                    <dimIndex>0-15</dimIndex>
                    <name>ADBUF%s</name>
                    <description>A/D Data Buffer Registers %s</description>
                    <addressOffset>0x0B0</addressOffset>
                    <size>16</size>
                    <access>read-only</access>
                    <resetValue>0x0000</resetValue>
                    <resetMask>0xffff</resetMask>
                    <fields>
                        <field>
                            <name>ADBUF</name>
                            <description>Converted Value 15 to 0</description>
                            <lsb>0</lsb>
                            <msb>15</msb>
                            <access>read-only</access>
                        </field>
                    </fields>
                </register>
                <register>
                    <name>ADBUFEN</name>
                    <description>A/D Data Buffer Enable Register</description>
                    <addressOffset>0x0D0</addressOffset>
                    <size>8</size>
                    <access>read-write</access>
                    <resetValue>0x00</resetValue>
                    <resetMask>0xff</resetMask>
                    <fields>
                        <field>
                            <name>BUFEN</name>
                            <description>Data Buffer Enable</description>
                            <lsb>0</lsb>
                            <msb>0</msb>
                            <access>read-write</access>
                            <enumeratedValues>
                                <enumeratedValue>
                                    <name>0</name>
                                    <description>The data buffer is not used.</description>
                                    <value>#0</value>
                                </enumeratedValue>
                                <enumeratedValue>
                                    <name>1</name>
                                    <description>The data buffer is used.</description>
                                    <value>#1</value>
                                </enumeratedValue>
                            </enumeratedValues>
                        </field>
                    </fields>
                </register>
                <register>
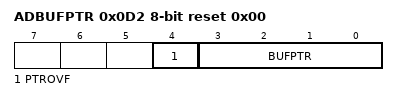
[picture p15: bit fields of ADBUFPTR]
                    <name>ADBUFPTR</name>
                    <description>A/D Data Buffer Pointer Register</description>
                    <addressOffset>0x0D2</addressOffset>
                    <size>8</size>
                    <access>read-write</access>
                    <resetValue>0x00</resetValue>
                    <resetMask>0xff</resetMask>
                    <fields>
                        <field>
                            <name>BUFPTR</name>
                            <description>Data Buffer Pointer</description>
                            <lsb>0</lsb>
                            <msb>3</msb>
                            <access>read-write</access>
                        </field>
                        <field>
                            <name>PTROVF</name>
                            <description>Pointer Overflow Flag</description>
                            <lsb>4</lsb>
                            <msb>4</msb>
                            <access>read-write</access>
                            <enumeratedValues>
                                <enumeratedValue>
                                    <name>0</name>
                                    <description>The data buffer pointer has not overflowed.</description>
                                    <value>#0</value>
                                </enumeratedValue>
                                <enumeratedValue>
                                    <name>1</name>
                                    <description>The data buffer pointer has overflowed.</description>
                                    <value>#1</value>
                                </enumeratedValue>
                            </enumeratedValues>
                        </field>
                    </fields>
                </register>
                <register>
                    <name>ADSSTRL</name>
                    <description>A/D Sampling State Register</description>
                    <addressOffset>0x0DD</addressOffset>
                    <size>8</size>
                    <access>read-write</access>
                    <resetValue>0x0b</resetValue>
                    <resetMask>0xff</resetMask>
                    <fields>
                        <field>
                            <name>SST</name>
                            <description>Sampling Time Setting</description>
                            <lsb>0</lsb>
                            <msb>7</msb>
                            <access>read-write</access>
                        </field>
                    </fields>
                </register>
                <register>
                    <name>ADSSTRT</name>
                    <description>A/D Sampling State Register</description>
                    <addressOffset>0x0DE</addressOffset>
                    <size>8</size>
                    <access>read-write</access>
                    <resetValue>0x0b</resetValue>
                    <resetMask>0xff</resetMask>
                    <fields>
                        <field>
                            <name>SST</name>
                            <description>Sampling Time Setting</description>
                            <lsb>0</lsb>
                            <msb>7</msb>
                            <access>read-write</access>
                        </field>
                    </fields>
                </register>
                <register>
                    <name>ADSSTRO</name>
                    <description>A/D Sampling State Register</description>
                    <addressOffset>0x0DF</addressOffset>
                    <size>8</size>
                    <access>read-write</access>
                    <resetValue>0x0b</resetValue>
                    <resetMask>0xff</resetMask>
                    <fields>
                        <field>
                            <name>SST</name>
                            <description>Sampling Time Setting</description>
                            <lsb>0</lsb>
                            <msb>7</msb>
                            <access>read-write</access>
                        </field>
                    </fields>
                </register>
                <register>
                    <dim>7</dim>
                    <dimIncrement>0x1</dimIncrement>
                    <dimIndex>0-6</dimIndex>
                    <name>ADSSTR%s</name>
                    <description>A/D Sampling State Register</description>
                    <addressOffset>0x0E0</addressOffset>
                    <size>8</size>
                    <access>read-write</access>
                    <resetValue>0x0b</resetValue>
                    <resetMask>0xff</resetMask>
                    <fields>
                        <field>
                            <name>SST</name>
                            <description>Sampling Time Setting</description>
                            <lsb>0</lsb>
                            <msb>7</msb>
                            <access>read-write</access>
                        </field>
                    </fields>
                </register>
                <register>
                    <name>ADSSTRV</name>
                    <description>A/D Sampling State Register</description>
                    <addressOffset>0x0E3</addressOffset>
                    <size>8</size>
                    <access>read-write</access>
                    <resetValue>0x0b</resetValue>
                    <resetMask>0xff</resetMask>
                    <fields>
                        <field>
                            <name>SST</name>
                            <description>Sampling Time Setting</description>
                            <lsb>0</lsb>
                            <msb>7</msb>
                            <access>read-write</access>
                        </field>
                    </fields>
                </register>
            </registers>
        </peripheral>
        <peripheral>
            <name>DAC12_NS</name>
            <description>12-bit D/A converter</description>
            <baseAddress>0x50333000</baseAddress>
            <addressBlock>
                <offset>0x00</offset>
                <size>2</size>
                <usage>registers</usage>
            </addressBlock>
            <addressBlock>
                <offset>0x04</offset>
                <size>3</size>
                <usage>registers</usage>
            </addressBlock>
            <addressBlock>
                <offset>0x08</offset>
                <size>1</size>
                <usage>registers</usage>
            </addressBlock>
            <addressBlock>
                <offset>0x1C</offset>
                <size>1</size>
                <usage>registers</usage>
            </addressBlock>
            <addressBlock>
                <offset>0x10C0</offset>
                <size>1</size>
                <usage>registers</usage>
            </addressBlock>
            <registers>
                <register>
                    <dim>1</dim>
                    <dimIncrement>0x02</dimIncrement>
                    <dimIndex>0</dimIndex>
                    <name>DADR%s</name>
                    <description>D/A Data Register %s</description>
                    <addressOffset>0x00</addressOffset>
                    <size>16</size>
                    <access>read-write</access>
                    <resetValue>0x0000</resetValue>
                    <resetMask>0xffff</resetMask>
                </register>
                <register>
                    <name>DACR</name>
                    <description>D/A Control Register</description>
                    <addressOffset>0x04</addressOffset>
                    <size>8</size>
                    <access>read-write</access>
                    <resetValue>0x1f</resetValue>
                    <resetMask>0xff</resetMask>
                    <fields>
                        <field>
                            <name>DAOE0</name>
                            <description>D/A Output Enable 0</description>
                            <lsb>6</lsb>
                            <msb>6</msb>
                            <access>read-write</access>
                            <enumeratedValues>
                                <enumeratedValue>
                                    <name>0</name>
                                    <description>Disable analog output of channel 0 (DA0)</description>
                                    <value>#0</value>
                                </enumeratedValue>
                                <enumeratedValue>
                                    <name>1</name>
                                    <description>Enable D/A conversion of channel 0 (DA0)</description>
                                    <value>#1</value>
                                </enumeratedValue>
                            </enumeratedValues>
                        </field>
                    </fields>
                </register>
                <register>
                    <name>DADPR</name>
                    <description>DADRn Format Select Register</description>
                    <addressOffset>0x05</addressOffset>
                    <size>8</size>
                    <access>read-write</access>
                    <resetValue>0x00</resetValue>
                    <resetMask>0xff</resetMask>
                    <fields>
                        <field>
                            <name>DPSEL</name>
                            <description>DADRn Format Select</description>
                            <lsb>7</lsb>
                            <msb>7</msb>
                            <access>read-write</access>
                            <enumeratedValues>
                                <enumeratedValue>
                                    <name>0</name>
                                    <description>Right-justified format</description>
                                    <value>#0</value>
                                </enumeratedValue>
                                <enumeratedValue>
                                    <name>1</name>
                                    <description>Left-justified format</description>
                                    <value>#1</value>
                                </enumeratedValue>
                            </enumeratedValues>
                        </field>
                    </fields>
                </register>
                <register>
                    <name>DAADSCR</name>
                    <description>D/A A/D Synchronous Start Control Register</description>
                    <addressOffset>0x06</addressOffset>
                    <size>8</size>
                    <access>read-write</access>
                    <resetValue>0x00</resetValue>
                    <resetMask>0xff</resetMask>
                    <fields>
                        <field>
                            <name>DAADST</name>
                            <description>D/A A/D Synchronous Conversion</description>
                            <lsb>7</lsb>
                            <msb>7</msb>
                            <access>read-write</access>
                            <enumeratedValues>
                                <enumeratedValue>
                                    <name>0</name>
                                    <description>Do not synchronize DAC12 with ADC12 (unit 1) operation (disable interference reduction between D/A and A/D conversion).</description>
                                    <value>#0</value>
                                </enumeratedValue>
                                <enumeratedValue>
                                    <name>1</name>
                                    <description>Synchronize DAC12 with ADC12 (unit 1) operation (enable interference reduction between D/A and A/D conversion).</description>
                                    <value>#1</value>
                                </enumeratedValue>
                            </enumeratedValues>
                        </field>
                    </fields>
                </register>
                <register>
                    <name>DAAMPCR</name>
                    <description>D/A Output Amplifier Control Register</description>
                    <addressOffset>0x08</addressOffset>
                    <size>8</size>
                    <access>read-write</access>
                    <resetValue>0x00</resetValue>
                    <resetMask>0xff</resetMask>
                    <fields>
                        <field>
                            <name>DAAMP0</name>
                            <description>Amplifier Control 0</description>
                            <lsb>6</lsb>
                            <msb>6</msb>
                            <access>read-write</access>
                            <enumeratedValues>
                                <enumeratedValue>
                                    <name>0</name>
                                    <description>Do not use channel 0 output amplifier</description>
                                    <value>#0</value>
                                </enumeratedValue>
                                <enumeratedValue>
                                    <name>1</name>
                                    <description>Use channel 0 output amplifier</description>
                                    <value>#1</value>
                                </enumeratedValue>
                            </enumeratedValues>
                        </field>
                    </fields>
                </register>
                <register>
                    <name>DAASWCR</name>
                    <description>D/A Amplifier Stabilization Wait Control Register</description>
                    <addressOffset>0x1C</addressOffset>
                    <size>8</size>
                    <access>read-write</access>
                    <resetValue>0x00</resetValue>
                    <resetMask>0xff</resetMask>
                    <fields>
                        <field>
                            <name>DAASW0</name>
                            <description>D/A Amplifier Stabilization Wait 0 and D/A internal output control</description>
                            <lsb>6</lsb>
                            <msb>6</msb>
                            <access>read-write</access>
                            <enumeratedValues>
                                <enumeratedValue>
                                    <name>0</name>
                                    <description>For output to external pin: Amplifier stabilization wait off (output) for channel 0 For output to internal module: Disable output for channel 0 </description>
                                    <value>#0</value>
                                </enumeratedValue>
                                <enumeratedValue>
                                    <name>1</name>
                                    <description>For output to external pin: Amplifier stabilization wait on (high-Z) for channel 0 For output to internal module: Enable output for channel 0 </description>
                                    <value>#1</value>
                                </enumeratedValue>
                            </enumeratedValues>
                        </field>
                    </fields>
                </register>
                <register>
                    <name>DAADUSR</name>
                    <description>D/A A/D Synchronous Unit Select Register</description>
                    <addressOffset>0x10C0</addressOffset>
                    <size>8</size>
                    <access>read-write</access>
                    <resetValue>0x00</resetValue>
                    <resetMask>0xff</resetMask>
                    <fields>
                        <field>
                            <name>AMADSEL1</name>
                            <description>A/D Unit 1 Select</description>
                            <lsb>1</lsb>
                            <msb>1</msb>
                            <access>read-write</access>
                            <enumeratedValues>
                                <enumeratedValue>
                                    <name>0</name>
                                    <description>Do not select unit 1</description>
                                    <value>#0</value>
                                </enumeratedValue>
                                <enumeratedValue>
                                    <name>1</name>
                                    <description>Select unit 1</description>
                                    <value>#1</value>
                                </enumeratedValue>
                            </enumeratedValues>
                        </field>
                    </fields>
                </register>
            </registers>
        </peripheral>
        <peripheral>
            <name>CEU_NS</name>
            <description>Capture Engine Unit</description>
            <baseAddress>0x50348000</baseAddress>
            <addressBlock>
                <offset>0x00</offset>
                <size>28</size>
                <usage>registers</usage>
            </addressBlock>
            <addressBlock>
                <offset>0x28</offset>
                <size>40</size>
                <usage>registers</usage>
            </addressBlock>
            <addressBlock>
                <offset>0x5C</offset>
                <size>12</size>
                <usage>registers</usage>
            </addressBlock>
            <addressBlock>
                <offset>0x70</offset>
                <size>8</size>
                <usage>registers</usage>
            </addressBlock>
            <addressBlock>
                <offset>0x7C</offset>
                <size>4</size>
                <usage>registers</usage>
            </addressBlock>
            <addressBlock>
                <offset>0x84</offset>
                <size>4</size>
                <usage>registers</usage>
            </addressBlock>
            <addressBlock>
                <offset>0x90</offset>
                <size>20</size>
                <usage>registers</usage>
            </addressBlock>
            <addressBlock>
                <offset>0x1010</offset>
                <size>8</size>
                <usage>registers</usage>
            </addressBlock>
            <addressBlock>
                <offset>0x1030</offset>
                <size>32</size>
                <usage>registers</usage>
            </addressBlock>
            <addressBlock>
                <offset>0x1060</offset>
                <size>8</size>
                <usage>registers</usage>
            </addressBlock>
            <addressBlock>
                <offset>0x1090</offset>
                <size>16</size>
                <usage>registers</usage>
            </addressBlock>
            <addressBlock>
                <offset>0x2010</offset>
                <size>8</size>
                <usage>registers</usage>
            </addressBlock>
            <addressBlock>
                <offset>0x2030</offset>
                <size>32</size>
                <usage>registers</usage>
            </addressBlock>
            <addressBlock>
                <offset>0x2060</offset>
                <size>8</size>
                <usage>registers</usage>
            </addressBlock>
            <addressBlock>
                <offset>0x2090</offset>
                <size>16</size>
                <usage>registers</usage>
            </addressBlock>
            <registers>
                <register>
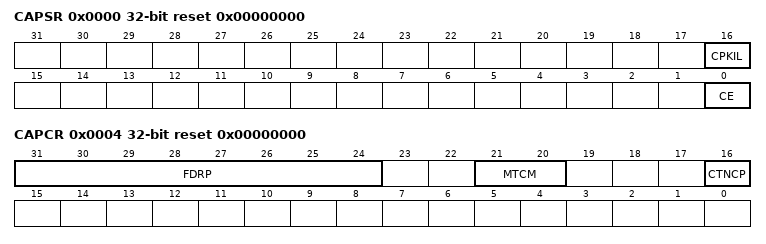
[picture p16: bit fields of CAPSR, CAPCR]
                    <name>CAPSR</name>
                    <description>Capture Start Register</description>
                    <addressOffset>0x0000</addressOffset>
                    <size>32</size>
                    <access>read-write</access>
                    <resetValue>0x00000000</resetValue>
                    <resetMask>0xffffffff</resetMask>
                    <fields>
                        <field>
                            <name>CE</name>
                            <description>Capture enable</description>
                            <lsb>0</lsb>
                            <msb>0</msb>
                            <access>read-write</access>
                            <enumeratedValues>
                                <enumeratedValue>
                                    <name>0</name>
                                    <description>Stops capturing</description>
                                    <value>#0</value>
                                </enumeratedValue>
                                <enumeratedValue>
                                    <name>1</name>
                                    <description>Starts capturing</description>
                                    <value>#1</value>
                                </enumeratedValue>
                            </enumeratedValues>
                        </field>
                        <field>
                            <name>CPKIL</name>
                            <description>Software reset of capturing</description>
                            <lsb>16</lsb>
                            <msb>16</msb>
                            <access>read-write</access>
                            <enumeratedValues>
                                <enumeratedValue>
                                    <name>0</name>
                                    <description>Normal state</description>
                                    <value>#0</value>
                                </enumeratedValue>
                                <enumeratedValue>
                                    <name>1</name>
                                    <description>Software reset of capturing</description>
                                    <value>#1</value>
                                </enumeratedValue>
                            </enumeratedValues>
                        </field>
                    </fields>
                </register>
                <register>
                    <name>CAPCR</name>
                    <description>Capture Control Register</description>
                    <addressOffset>0x0004</addressOffset>
                    <size>32</size>
                    <access>read-write</access>
                    <resetValue>0x00000000</resetValue>
                    <resetMask>0xffffffff</resetMask>
                    <fields>
                        <field>
                            <name>CTNCP</name>
                            <description>Continuous capture</description>
                            <lsb>16</lsb>
                            <msb>16</msb>
                            <access>read-write</access>
                            <enumeratedValues>
                                <enumeratedValue>
                                    <name>0</name>
                                    <description>One-frame capture when CAPSR.CE = 1</description>
                                    <value>#0</value>
                                </enumeratedValue>
                                <enumeratedValue>
                                    <name>1</name>
                                    <description>Continuous capture until CAPSR.CE = 0</description>
                                    <value>#1</value>
                                </enumeratedValue>
                            </enumeratedValues>
                        </field>
                        <field>
                            <name>MTCM</name>
                            <description>Specify the unit for transferring data to a bus bridge module.</description>
                            <lsb>20</lsb>
                            <msb>21</msb>
                            <access>read-write</access>
                            <enumeratedValues>
                                <enumeratedValue>
                                    <name>00</name>
                                    <description>Image capture: Y data and C data are transferred in 32-byte units Data fetch : Data is transferred in 32-byte units </description>
                                    <value>#00</value>
                                </enumeratedValue>
                                <enumeratedValue>
                                    <name>01</name>
                                    <description>Image capture: Y data and C data are transferred in 64-byte units Data fetch : Data is transferred in 64-byte </description>
                                    <value>#01</value>
                                </enumeratedValue>
                                <enumeratedValue>
                                    <name>10</name>
                                    <description>Image capture: Y data and C data are transferred in 128-byte units Data fetch : Data is transferred in 128-byte </description>
                                    <value>#10</value>
                                </enumeratedValue>
                                <enumeratedValue>
                                    <name>11</name>
                                    <description>Image capture: Y data and C data are transferred in 256-byte units Data fetch : Data is transferred in 256-byte </description>
                                    <value>#11</value>
                                </enumeratedValue>
                            </enumeratedValues>
                        </field>
                        <field>
                            <name>FDRP</name>
                            <description>Set the frame drop interval in continuous-frame capture.</description>
                            <lsb>24</lsb>
                            <msb>31</msb>
                            <access>read-write</access>
                        </field>
                    </fields>
                </register>
                <register>
                    <name>CAMCR</name>
                    <description>Capture Interface Control Register</description>
                    <addressOffset>0x0008</addressOffset>
                    <size>32</size>
                    <access>read-write</access>
                    <resetValue>0x00000000</resetValue>
                    <resetMask>0xffffffff</resetMask>
                    <fields>
                        <field>
                            <name>HDPOL</name>
                            <description>Sets the polarity for detection of the horizontal sync signal (HD) input from an external module.</description>
                            <lsb>0</lsb>
                            <msb>0</msb>
                            <access>read-write</access>
                            <enumeratedValues>
                                <enumeratedValue>
                                    <name>0</name>
                                    <description>Horizontal sync signal (HD) from an external module is detected as high active</description>
                                    <value>#0</value>
                                </enumeratedValue>
                                <enumeratedValue>
                                    <name>1</name>
                                    <description>Horizontal sync signal (HD) from an external module is detected as low active</description>
                                    <value>#1</value>
                                </enumeratedValue>
                            </enumeratedValues>
                        </field>
                        <field>
                            <name>VDPOL</name>
                            <description>Sets the polarity for detection of the vertical sync signal (VD) input from an external module.</description>
                            <lsb>1</lsb>
                            <msb>1</msb>
                            <access>read-write</access>
                            <enumeratedValues>
                                <enumeratedValue>
                                    <name>0</name>
                                    <description>Vertical sync signal (VD) from an external module is detected as high active</description>
                                    <value>#0</value>
                                </enumeratedValue>
                                <enumeratedValue>
                                    <name>1</name>
                                    <description>Vertical sync signal (VD) from an external module is detected as low active</description>
                                    <value>#1</value>
                                </enumeratedValue>
                            </enumeratedValues>
                        </field>
                        <field>
                            <name>JPG</name>
                            <description>These bits select the fetched data type.</description>
                            <lsb>4</lsb>
                            <msb>5</msb>
                            <access>read-write</access>
                            <enumeratedValues>
                                <enumeratedValue>
                                    <name>00</name>
                                    <description>Image capture mode (input data are separated into the luminance component data (Y) and the chrominance component data (CbCr) for output to the memory) </description>
                                    <value>#00</value>
                                </enumeratedValue>
                                <enumeratedValue>
                                    <name>01</name>
                                    <description>Data synchronous fetch mode (specified size of input data are output to the specified memory addresses in order of input and in synchronization with the sync signal) </description>
                                    <value>#01</value>
                                </enumeratedValue>
                                <enumeratedValue>
                                    <name>10</name>
                                    <description>Data enable fetch mode (input data are fetched with HD as an enable signal and output to the specified addresses in memory in order of input) </description>
                                    <value>#10</value>
                                </enumeratedValue>
                                <enumeratedValue>
                                    <name>11</name>
                                    <description>Setting prohibited</description>
                                    <value>#11</value>
                                </enumeratedValue>
                            </enumeratedValues>
                        </field>
                        <field>
                            <name>DTARY</name>
                            <description>Set the input order of the luminance component and chrominance component.</description>
                            <lsb>8</lsb>
                            <msb>9</msb>
                            <access>read-write</access>
                            <enumeratedValues>
                                <enumeratedValue>
                                    <name>00</name>
                                    <description>Image input data is fetched in the order of Cb0, Y0, Cr0, and Y1 </description>
                                    <value>#00</value>
                                </enumeratedValue>
                                <enumeratedValue>
                                    <name>01</name>
                                    <description>Image input data is fetched in the order of Cr0, Y0, Cb0, and Y1 </description>
                                    <value>#01</value>
                                </enumeratedValue>
                                <enumeratedValue>
                                    <name>10</name>
                                    <description>Image input data is fetched in the order of Y0, Cb0, Y1, and Cr0 </description>
                                    <value>#10</value>
                                </enumeratedValue>
                                <enumeratedValue>
                                    <name>11</name>
                                    <description>Image input data is fetched in the order of Y0, Cr0, Y1, and Cb0 </description>
                                    <value>#11</value>
                                </enumeratedValue>
                            </enumeratedValues>
                        </field>
                        <field>
                            <name>FLDPOL</name>
                            <description>Sets the polarity of the field identification signal (FLD) from an external module.</description>
                            <lsb>16</lsb>
                            <msb>16</msb>
                            <access>read-write</access>
                            <enumeratedValues>
                                <enumeratedValue>
                                    <name>0</name>
                                    <description>When the FLD signal is high-active, the field is detected as the top field and when low-active, the field is detected as the bottom field. </description>
                                    <value>#0</value>
                                </enumeratedValue>
                                <enumeratedValue>
                                    <name>1</name>
                                    <description>When the FLD signal is low-active, the field is detected as the top field and when high-active, the field is detected as the bottom field. </description>
                                    <value>#1</value>
                                </enumeratedValue>
                            </enumeratedValues>
                        </field>
                        <field>
                            <name>DSEL</name>
                            <description>Sets the edge for fetching the image data (D7 to D0) from an external module.</description>
                            <lsb>24</lsb>
                            <msb>24</msb>
                            <access>read-write</access>
                            <enumeratedValues>
                                <enumeratedValue>
                                    <name>0</name>
                                    <description>D7 to D0 are fetched at the rising edge of the camera clock.</description>
                                    <value>#0</value>
                                </enumeratedValue>
                                <enumeratedValue>
                                    <name>1</name>
                                    <description>D7 to D0 are fetched at the falling edge of the camera clock.</description>
                                    <value>#1</value>
                                </enumeratedValue>
                            </enumeratedValues>
                        </field>
                        <field>
                            <name>FLDSEL</name>
                            <description>Sets the edge for capturing FLD from an external module.</description>
                            <lsb>25</lsb>
                            <msb>25</msb>
                            <access>read-write</access>
                            <enumeratedValues>
                                <enumeratedValue>
                                    <name>0</name>
                                    <description>FLD is captured at the rising edge of the camera clock.</description>
                                    <value>#0</value>
                                </enumeratedValue>
                                <enumeratedValue>
                                    <name>1</name>
                                    <description>FLD is captured at the falling edge of the camera clock.</description>
                                    <value>#1</value>
                                </enumeratedValue>
                            </enumeratedValues>
                        </field>
                        <field>
                            <name>HDSEL</name>
                            <description>Sets the edge for capturing HD from an external module.</description>
                            <lsb>26</lsb>
                            <msb>26</msb>
                            <access>read-write</access>
                            <enumeratedValues>
                                <enumeratedValue>
                                    <name>0</name>
                                    <description>HD is captured at the rising edge of the camera clock.</description>
                                    <value>#0</value>
                                </enumeratedValue>
                                <enumeratedValue>
                                    <name>1</name>
                                    <description>HD is captured at the falling edge of the camera clock.</description>
                                    <value>#1</value>
                                </enumeratedValue>
                            </enumeratedValues>
                        </field>
                        <field>
                            <name>VDSEL</name>
                            <description>Sets the edge for capturing VD from an external module.</description>
                            <lsb>27</lsb>
                            <msb>27</msb>
                            <access>read-write</access>
                            <enumeratedValues>
                                <enumeratedValue>
                                    <name>0</name>
                                    <description>VD is captured at the rising edge of the camera clock.</description>
                                    <value>#0</value>
                                </enumeratedValue>
                                <enumeratedValue>
                                    <name>1</name>
                                    <description>VD is captured at the falling edge of the camera clock.</description>
                                    <value>#1</value>
                                </enumeratedValue>
                            </enumeratedValues>
                        </field>
                    </fields>
                </register>
                <register>
                    <name>CMCYR</name>
                    <description>Capture Interface Cycle Register</description>
                    <addressOffset>0x000C</addressOffset>
                    <size>32</size>
                    <access>read-write</access>
                    <resetValue>0x00000000</resetValue>
                    <resetMask>0xffffffff</resetMask>
                    <fields>
                        <field>
                            <name>HCYL</name>
                            <description>Horizontal Cycle Count of External Module</description>
                            <lsb>0</lsb>
                            <msb>13</msb>
                            <access>read-write</access>
                        </field>
                        <field>
                            <name>VCYL</name>
                            <description>Vertical HD Count of External Module</description>
                            <lsb>16</lsb>
                            <msb>29</msb>
                            <access>read-write</access>
                        </field>
                    </fields>
                </register>
                <register>
                    <name>CAMOR</name>
                    <description>Capture Interface Offset Register</description>
                    <addressOffset>0x0010</addressOffset>
                    <size>32</size>
                    <access>read-write</access>
                    <resetValue>0x00000000</resetValue>
                    <resetMask>0xffffffff</resetMask>
                    <fields>
                        <field>
                            <name>HOFST</name>
                            <description>Specify the capture start location in terms of the number of clock cycles from a horizontal sync signal (1-cycle units).</description>
                            <lsb>0</lsb>
                            <msb>12</msb>
                            <access>read-write</access>
                        </field>
                        <field>
                            <name>VOFST</name>
                            <description>Specify the capture start location in terms of the HD count from a vertical sync signal (1-HD units).</description>
                            <lsb>16</lsb>
                            <msb>27</msb>
                            <access>read-write</access>
                        </field>
                    </fields>
                </register>
                <register>
                    <name>CAPWR</name>
                    <description>Capture Interface Width Register</description>
                    <addressOffset>0x0014</addressOffset>
                    <size>32</size>
                    <access>read-write</access>
                    <resetValue>0x00000000</resetValue>
                    <resetMask>0xffffffff</resetMask>
                    <fields>
                        <field>
                            <name>HWDTH</name>
                            <description>Specify the horizontal capture period.</description>
                            <lsb>0</lsb>
                            <msb>12</msb>
                            <access>read-write</access>
                        </field>
                        <field>
                            <name>VWDTH</name>
                            <description>Specify the vertical capture period (4-HD units).</description>
                            <lsb>16</lsb>
                            <msb>27</msb>
                            <access>read-write</access>
                        </field>
                    </fields>
                </register>
                <register>
                    <name>CAIFR</name>
                    <description>Capture Interface Input Format Register</description>
                    <addressOffset>0x0018</addressOffset>
                    <size>32</size>
                    <access>read-write</access>
                    <resetValue>0x00000000</resetValue>
                    <resetMask>0xffffffff</resetMask>
                    <fields>
                        <field>
                            <name>FCI</name>
                            <description>Set the timing to start capturing.</description>
                            <lsb>0</lsb>
                            <msb>1</msb>
                            <access>read-write</access>
                            <enumeratedValues>
                                <enumeratedValue>
                                    <name>00</name>
                                    <description>Capture starts from the VD input immediately after the CEU activation regardless of it being a top or bottom field </description>
                                    <value>#00</value>
                                </enumeratedValue>
                                <enumeratedValue>
                                    <name>01</name>
                                    <description>After the CEU activation, input of a top-field image is waited, and then capture starts from the top field </description>
                                    <value>#01</value>
                                </enumeratedValue>
                                <enumeratedValue>
                                    <name>10</name>
                                    <description>After the CEU activation, input of a bottom-field image is waited, and then capture starts from the bottom field </description>
                                    <value>#10</value>
                                </enumeratedValue>
                                <enumeratedValue>
                                    <name>11</name>
                                    <description>Setting prohibited</description>
                                    <value>#11</value>
                                </enumeratedValue>
                            </enumeratedValues>
                        </field>
                        <field>
                            <name>CIM</name>
                            <description>Sets the images to be captured.</description>
                            <lsb>4</lsb>
                            <msb>4</msb>
                            <access>read-write</access>
                            <enumeratedValues>
                                <enumeratedValue>
                                    <name>0</name>
                                    <description>Capture of frame image (1 VD) or both-field image (2 VD)</description>
                                    <value>#0</value>
                                </enumeratedValue>
                                <enumeratedValue>
                                    <name>1</name>
                                    <description>Capture of one-field image (1 VD)</description>
                                    <value>#1</value>
                                </enumeratedValue>
                            </enumeratedValues>
                        </field>
                        <field>
                            <name>IFS</name>
                            <description>Sets the input mode for capturing images.</description>
                            <lsb>8</lsb>
                            <msb>8</msb>
                            <access>read-write</access>
                            <enumeratedValues>
                                <enumeratedValue>
                                    <name>0</name>
                                    <description>Progressive</description>
                                    <value>#0</value>
                                </enumeratedValue>
                                <enumeratedValue>
                                    <name>1</name>
                                    <description>Interlace</description>
                                    <value>#1</value>
                                </enumeratedValue>
                            </enumeratedValues>
                        </field>
                    </fields>
                </register>
                <register>
                    <name>CRCNTR</name>
                    <description>CEU Register Control Register</description>
                    <addressOffset>0x0028</addressOffset>
                    <size>32</size>
                    <access>read-write</access>
                    <resetValue>0x00000000</resetValue>
                    <resetMask>0xffffffff</resetMask>
                    <fields>
                        <field>
                            <name>RC</name>
                            <description>Specifies switching of the register plane used by the CEU in synchronization with VD.</description>
                            <lsb>0</lsb>
                            <msb>0</msb>
                            <access>read-write</access>
                            <enumeratedValues>
                                <enumeratedValue>
                                    <name>0</name>
                                    <description>Uses the specified register plane in synchronization with VD</description>
                                    <value>#0</value>
                                </enumeratedValue>
                                <enumeratedValue>
                                    <name>1</name>
                                    <description>Switches the register plane in synchronization with VD</description>
                                    <value>#1</value>
                                </enumeratedValue>
                            </enumeratedValues>
                        </field>
                        <field>
                            <name>RS</name>
                            <description>Specifies which register plane is used by the CEU in synchronization with VD.</description>
                            <lsb>1</lsb>
                            <msb>1</msb>
                            <access>read-write</access>
                            <enumeratedValues>
                                <enumeratedValue>
                                    <name>0</name>
                                    <description>Uses plane A of the register</description>
                                    <value>#0</value>
                                </enumeratedValue>
                                <enumeratedValue>
                                    <name>1</name>
                                    <description>Uses plane B of the register</description>
                                    <value>#1</value>
                                </enumeratedValue>
                            </enumeratedValues>
                        </field>
                        <field>
                            <name>RVS</name>
                            <description>Sets the timing to switch the register plane in both-field capture.</description>
                            <lsb>4</lsb>
                            <msb>4</msb>
                            <access>read-write</access>
                            <enumeratedValues>
                                <enumeratedValue>
                                    <name>0</name>
                                    <description>Switches the register plane every 2 VD</description>
                                    <value>#0</value>
                                </enumeratedValue>
                                <enumeratedValue>
                                    <name>1</name>
                                    <description>Switches the register plane every 1 VD</description>
                                    <value>#1</value>
                                </enumeratedValue>
                            </enumeratedValues>
                        </field>
                    </fields>
                </register>
                <register>
                    <name>CRCMPR</name>
                    <description>CEU Register Forcible Control Register</description>
                    <addressOffset>0x002C</addressOffset>
                    <size>32</size>
                    <access>read-write</access>
                    <resetValue>0x00000000</resetValue>
                    <resetMask>0xffffffff</resetMask>
                    <fields>
                        <field>
                            <name>RA</name>
                            <description>Indicates the register plane currently specified.</description>
                            <lsb>0</lsb>
                            <msb>0</msb>
                            <access>read-write</access>
                            <enumeratedValues>
                                <enumeratedValue>
                                    <name>0</name>
                                    <description>Specifies plane A of the register</description>
                                    <value>#0</value>
                                </enumeratedValue>
                                <enumeratedValue>
                                    <name>1</name>
                                    <description>Specifies plane B of the register</description>
                                    <value>#1</value>
                                </enumeratedValue>
                            </enumeratedValues>
                        </field>
                    </fields>
                </register>
                <register>
                    <name>CFLCR</name>
                    <description>Capture Filter Control Register</description>
                    <addressOffset>0x0030</addressOffset>
                    <size>32</size>
                    <access>read-write</access>
                    <resetValue>0x00000000</resetValue>
                    <resetMask>0xffffffff</resetMask>
                    <fields>
                        <field>
                            <name>HFRAC</name>
                            <description>Fraction Part of Horizontal Scale-Down Factor</description>
                            <lsb>0</lsb>
                            <msb>11</msb>
                            <access>read-write</access>
                        </field>
                        <field>
                            <name>HMANT</name>
                            <description>Mantissa Part of Horizontal Scale-Down Factor</description>
                            <lsb>12</lsb>
                            <msb>15</msb>
                            <access>read-write</access>
                        </field>
                        <field>
                            <name>VFRAC</name>
                            <description>Fraction Part of Vertical Scale-Down Factor</description>
                            <lsb>16</lsb>
                            <msb>27</msb>
                            <access>read-write</access>
                        </field>
                        <field>
                            <name>VMANT</name>
                            <description>Mantissa Part of Vertical Scale-Down Factor</description>
                            <lsb>28</lsb>
                            <msb>31</msb>
                            <access>read-write</access>
                        </field>
                    </fields>
                </register>
                <register>
                    <name>CFSZR</name>
                    <description>Capture Filter Size Clip Register</description>
                    <addressOffset>0x0034</addressOffset>
                    <size>32</size>
                    <access>read-write</access>
                    <resetValue>0x00000000</resetValue>
                    <resetMask>0xffffffff</resetMask>
                    <fields>
                        <field>
                            <name>HFCLP</name>
                            <description>Specify the horizontal clipping value of the filter output size (8-pixel units).</description>
                            <lsb>0</lsb>
                            <msb>11</msb>
                            <access>read-write</access>
                        </field>
                        <field>
                            <name>VFCLP</name>
                            <description>Specify the vertical clipping value of the filter output size (4-pixel units).</description>
                            <lsb>16</lsb>
                            <msb>27</msb>
                            <access>read-write</access>
                        </field>
                    </fields>
                </register>
                <register>
                    <name>CDWDR</name>
                    <description>Capture Destination Width Register</description>
                    <addressOffset>0x0038</addressOffset>
                    <size>32</size>
                    <access>read-write</access>
                    <resetValue>0x00000000</resetValue>
                    <resetMask>0xffffffff</resetMask>
                    <fields>
                        <field>
                            <name>CHDW</name>
                            <description>Specify the horizontal image size in the memory area where the captured image is to be stored (8-byte units).</description>
                            <lsb>0</lsb>
                            <msb>12</msb>
                            <access>read-write</access>
                        </field>
                    </fields>
                </register>
                <register>
                    <name>CDAYR</name>
                    <description>Capture Data Address Y Register</description>
                    <addressOffset>0x003C</addressOffset>
                    <size>32</size>
                    <access>read-write</access>
                    <resetValue>0x00000000</resetValue>
                    <resetMask>0xffffffff</resetMask>
                    <fields>
                        <field>
                            <name>CAYR</name>
                            <description>Capture Data Address Y</description>
                            <lsb>0</lsb>
                            <msb>31</msb>
                            <access>read-write</access>
                        </field>
                    </fields>
                </register>
                <register>
                    <name>CDACR</name>
                    <description>Capture Data Address C Register</description>
                    <addressOffset>0x0040</addressOffset>
                    <size>32</size>
                    <access>read-write</access>
                    <resetValue>0x00000000</resetValue>
                    <resetMask>0xffffffff</resetMask>
                    <fields>
                        <field>
                            <name>CACR</name>
                            <description>Capture Data Address C</description>
                            <lsb>0</lsb>
                            <msb>31</msb>
                            <access>read-write</access>
                        </field>
                    </fields>
                </register>
                <register>
                    <name>CDBYR</name>
                    <description>Capture Data Bottom-Field Address Y Register</description>
                    <addressOffset>0x0044</addressOffset>
                    <size>32</size>
                    <access>read-write</access>
                    <resetValue>0x00000000</resetValue>
                    <resetMask>0xffffffff</resetMask>
                    <fields>
                        <field>
                            <name>CBYR</name>
                            <description>Set the address for storing the luminance component data of the captured bottom-field data (8-pixel units).</description>
                            <lsb>0</lsb>
                            <msb>31</msb>
                            <access>read-write</access>
                        </field>
                    </fields>
                </register>
                <register>
                    <name>CDBCR</name>
                    <description>Capture Data Bottom-Field Address C Register</description>
                    <addressOffset>0x0048</addressOffset>
                    <size>32</size>
                    <access>read-write</access>
                    <resetValue>0x00000000</resetValue>
                    <resetMask>0xffffffff</resetMask>
                    <fields>
                        <field>
                            <name>CBCR</name>
                            <description>Set the address for storing the chrominance component data of the captured bottom-field data (8-pixel units).</description>
                            <lsb>0</lsb>
                            <msb>31</msb>
                            <access>read-write</access>
                        </field>
                    </fields>
                </register>
                <register>
                    <name>CBDSR</name>
                    <description>Capture Bundle Destination Size Register</description>
                    <addressOffset>0x004C</addressOffset>
                    <size>32</size>
                    <access>read-write</access>
                    <resetValue>0x00000000</resetValue>
                    <resetMask>0xffffffff</resetMask>
                    <fields>
                        <field>
                            <name>CBVS</name>
                            <description>Select the number of lines or number of bytes for output to the memory in a bundle write.</description>
                            <lsb>0</lsb>
                            <msb>22</msb>
                            <access>read-write</access>
                        </field>
                    </fields>
                </register>
                <register>
                    <name>CFWCR</name>
                    <description>Firewall Operation Control Register</description>
                    <addressOffset>0x005C</addressOffset>
                    <size>32</size>
                    <access>read-write</access>
                    <resetValue>0x00000100</resetValue>
                    <resetMask>0xffffffff</resetMask>
                    <fields>
                        <field>
                            <name>FWE</name>
                            <description>Firewall Operation</description>
                            <lsb>0</lsb>
                            <msb>0</msb>
                            <access>read-write</access>
                            <enumeratedValues>
                                <enumeratedValue>
                                    <name>0</name>
                                    <description>Firewall is not activated.</description>
                                    <value>#0</value>
                                </enumeratedValue>
                                <enumeratedValue>
                                    <name>1</name>
                                    <description>Firewall is activated.</description>
                                    <value>#1</value>
                                </enumeratedValue>
                            </enumeratedValues>
                        </field>
                        <field>
                            <name>FWV</name>
                            <description>Specify the upper limit of a write address.</description>
                            <lsb>5</lsb>
                            <msb>31</msb>
                            <access>read-write</access>
                        </field>
                    </fields>
                </register>
                <register>
                    <name>CLFCR</name>
                    <description>Capture Low-Pass Filter Control Register</description>
                    <addressOffset>0x0060</addressOffset>
                    <size>32</size>
                    <access>read-write</access>
                    <resetValue>0x00000000</resetValue>
                    <resetMask>0xffffffff</resetMask>
                    <fields>
                        <field>
                            <name>LPF</name>
                            <description>Enables or disables operation of the low-pass filter.</description>
                            <lsb>0</lsb>
                            <msb>0</msb>
                            <access>read-write</access>
                            <enumeratedValues>
                                <enumeratedValue>
                                    <name>0</name>
                                    <description>Low-pass filter not used</description>
                                    <value>#0</value>
                                </enumeratedValue>
                                <enumeratedValue>
                                    <name>1</name>
                                    <description>Low-pass filter used (only in the horizontal direction)</description>
                                    <value>#1</value>
                                </enumeratedValue>
                            </enumeratedValues>
                        </field>
                    </fields>
                </register>
                <register>
                    <name>CDOCR</name>
                    <description>Capture Data Output Control Register</description>
                    <addressOffset>0x0064</addressOffset>
                    <size>32</size>
                    <access>read-write</access>
                    <resetValue>0x00000000</resetValue>
                    <resetMask>0xffffffff</resetMask>
                    <fields>
                        <field>
                            <name>COBS</name>
                            <description>Controls swapping in 8-bit units for data output from the CEU.</description>
                            <lsb>0</lsb>
                            <msb>0</msb>
                            <access>read-write</access>
                            <enumeratedValues>
                                <enumeratedValue>
                                    <name>0</name>
                                    <description>Data is not swapped in 8-bit units</description>
                                    <value>#0</value>
                                </enumeratedValue>
                                <enumeratedValue>
                                    <name>1</name>
                                    <description>Data is swapped in 8-bit units</description>
                                    <value>#1</value>
                                </enumeratedValue>
                            </enumeratedValues>
                        </field>
                        <field>
                            <name>COWS</name>
                            <description>Controls swapping in 16-bit units for data output from the CEU.</description>
                            <lsb>1</lsb>
                            <msb>1</msb>
                            <access>read-write</access>
                            <enumeratedValues>
                                <enumeratedValue>
                                    <name>0</name>
                                    <description>Data is not swapped in 16-bit units</description>
                                    <value>#0</value>
                                </enumeratedValue>
                                <enumeratedValue>
                                    <name>1</name>
                                    <description>Data is swapped in 16-bit units</description>
                                    <value>#1</value>
                                </enumeratedValue>
                            </enumeratedValues>
                        </field>
                        <field>
                            <name>COLS</name>
                            <description>Controls swapping in 32-bit units for data output from the CEU.</description>
                            <lsb>2</lsb>
                            <msb>2</msb>
                            <access>read-write</access>
                            <enumeratedValues>
                                <enumeratedValue>
                                    <name>0</name>
                                    <description>Data is not swapped in 32-bit units</description>
                                    <value>#0</value>
                                </enumeratedValue>
                                <enumeratedValue>
                                    <name>1</name>
                                    <description>Data is swapped in 32-bit units</description>
                                    <value>#1</value>
                                </enumeratedValue>
                            </enumeratedValues>
                        </field>
                        <field>
                            <name>CDS</name>
                            <description>Sets the image format when outputting the image data captured in the YCbCr422 format to the memory.</description>
                            <lsb>4</lsb>
                            <msb>4</msb>
                            <access>read-write</access>
                            <enumeratedValues>
                                <enumeratedValue>
                                    <name>0</name>
                                    <description>Converts the YCbCr422 format to the YCbCr420 format before outputting data to the memory</description>
                                    <value>#0</value>
                                </enumeratedValue>
                                <enumeratedValue>
                                    <name>1</name>
                                    <description>Outputs data in the YCbCr422 format to the memory without conversion</description>
                                    <value>#1</value>
                                </enumeratedValue>
                            </enumeratedValues>
                        </field>
                        <field>
                            <name>CBE</name>
                            <description> Controls the number of lines of captured data to be written to the memory.</description>
                            <lsb>16</lsb>
                            <msb>16</msb>
                            <access>read-write</access>
                            <enumeratedValues>
                                <enumeratedValue>
                                    <name>0</name>
                                    <description>Normal write</description>
                                    <value>#0</value>
                                </enumeratedValue>
                                <enumeratedValue>
                                    <name>1</name>
                                    <description>Bundle write</description>
                                    <value>#1</value>
                                </enumeratedValue>
                            </enumeratedValues>
                        </field>
                    </fields>
                </register>
                <register>
                    <name>CEIER</name>
                    <description>Capture Event Interrupt Enable Register</description>
                    <addressOffset>0x0070</addressOffset>
                    <size>32</size>
                    <access>read-write</access>
                    <resetValue>0x00000000</resetValue>
                    <resetMask>0xffffffff</resetMask>
                    <fields>
                        <field>
                            <name>CPEIE</name>
                            <description>One-Frame Capture End Interrupt Enable</description>
                            <lsb>0</lsb>
                            <msb>0</msb>
                            <access>read-write</access>
                            <enumeratedValues>
                                <enumeratedValue>
                                    <name>0</name>
                                    <description>Disables a one-frame capture end interrupt</description>
                                    <value>#0</value>
                                </enumeratedValue>
                                <enumeratedValue>
                                    <name>1</name>
                                    <description>Enables a one-frame capture end interrupt</description>
                                    <value>#1</value>
                                </enumeratedValue>
                            </enumeratedValues>
                        </field>
                        <field>
                            <name>CFEIE</name>
                            <description>CFE Interrupt Enable</description>
                            <lsb>1</lsb>
                            <msb>1</msb>
                            <access>read-write</access>
                            <enumeratedValues>
                                <enumeratedValue>
                                    <name>0</name>
                                    <description>Disables a CFE interrupt</description>
                                    <value>#0</value>
                                </enumeratedValue>
                                <enumeratedValue>
                                    <name>1</name>
                                    <description>Enables a CFE interrupt</description>
                                    <value>#1</value>
                                </enumeratedValue>
                            </enumeratedValues>
                        </field>
                        <field>
                            <name>IGRWIE</name>
                            <description>Register-Access-During-Capture Interrupt Enable</description>
                            <lsb>4</lsb>
                            <msb>4</msb>
                            <access>read-write</access>
                            <enumeratedValues>
                                <enumeratedValue>
                                    <name>0</name>
                                    <description>Disables a register-access-during-capture interrupt</description>
                                    <value>#0</value>
                                </enumeratedValue>
                                <enumeratedValue>
                                    <name>1</name>
                                    <description>Enables a register-access-during-capture interrupt</description>
                                    <value>#1</value>
                                </enumeratedValue>
                            </enumeratedValues>
                        </field>
                        <field>
                            <name>HDIE</name>
                            <description>HD Interrupt Enable</description>
                            <lsb>8</lsb>
                            <msb>8</msb>
                            <access>read-write</access>
                            <enumeratedValues>
                                <enumeratedValue>
                                    <name>0</name>
                                    <description>Disables an HD interrupt</description>
                                    <value>#0</value>
                                </enumeratedValue>
                                <enumeratedValue>
                                    <name>1</name>
                                    <description>Enables an HD interrupt</description>
                                    <value>#1</value>
                                </enumeratedValue>
                            </enumeratedValues>
                        </field>
                        <field>
                            <name>VDIE</name>
                            <description>VD Interrupt Enable</description>
                            <lsb>9</lsb>
                            <msb>9</msb>
                            <access>read-write</access>
                            <enumeratedValues>
                                <enumeratedValue>
                                    <name>0</name>
                                    <description>Disables a VD interrupt</description>
                                    <value>#0</value>
                                </enumeratedValue>
                                <enumeratedValue>
                                    <name>1</name>
                                    <description>Enables a VD interrupt</description>
                                    <value>#1</value>
                                </enumeratedValue>
                            </enumeratedValues>
                        </field>
                        <field>
                            <name>CPBE1IE</name>
                            <description>CPBE1 Interrupt Enable</description>
                            <lsb>12</lsb>
                            <msb>12</msb>
                            <access>read-write</access>
                            <enumeratedValues>
                                <enumeratedValue>
                                    <name>0</name>
                                    <description>Disables a CPBE1 interrupt</description>
                                    <value>#0</value>
                                </enumeratedValue>
                                <enumeratedValue>
                                    <name>1</name>
                                    <description>Enables a CPBE1 interrupt</description>
                                    <value>#1</value>
                                </enumeratedValue>
                            </enumeratedValues>
                        </field>
                        <field>
                            <name>CPBE2IE</name>
                            <description>CPBE2 Interrupt Enable</description>
                            <lsb>13</lsb>
                            <msb>13</msb>
                            <access>read-write</access>
                            <enumeratedValues>
                                <enumeratedValue>
                                    <name>0</name>
                                    <description>Disables a CPBE2 interrupt</description>
                                    <value>#0</value>
                                </enumeratedValue>
                                <enumeratedValue>
                                    <name>1</name>
                                    <description>Enables a CPBE2 interrupt</description>
                                    <value>#1</value>
                                </enumeratedValue>
                            </enumeratedValues>
                        </field>
                        <field>
                            <name>CPBE3IE</name>
                            <description>CPBE3 Interrupt Enable</description>
                            <lsb>14</lsb>
                            <msb>14</msb>
                            <access>read-write</access>
                            <enumeratedValues>
                                <enumeratedValue>
                                    <name>0</name>
                                    <description>Disables a CPBE3 interrupt</description>
                                    <value>#0</value>
                                </enumeratedValue>
                                <enumeratedValue>
                                    <name>1</name>
                                    <description>Enables a CPBE3 interrupt</description>
                                    <value>#1</value>
                                </enumeratedValue>
                            </enumeratedValues>
                        </field>
                        <field>
                            <name>CPBE4IE</name>
                            <description>CPBE4 Interrupt Enable</description>
                            <lsb>15</lsb>
                            <msb>15</msb>
                            <access>read-write</access>
                            <enumeratedValues>
                                <enumeratedValue>
                                    <name>0</name>
                                    <description>Disables a CPBE4 interrupt</description>
                                    <value>#0</value>
                                </enumeratedValue>
                                <enumeratedValue>
                                    <name>1</name>
                                    <description>Enables a CPBE4 interrupt</description>
                                    <value>#1</value>
                                </enumeratedValue>
                            </enumeratedValues>
                        </field>
                        <field>
                            <name>CDTOFIE</name>
                            <description>CDTOF Interrupt Enable</description>
                            <lsb>16</lsb>
                            <msb>16</msb>
                            <access>read-write</access>
                            <enumeratedValues>
                                <enumeratedValue>
                                    <name>0</name>
                                    <description>Disables a CDTOF interrupt</description>
                                    <value>#0</value>
                                </enumeratedValue>
                                <enumeratedValue>
                                    <name>1</name>
                                    <description>Enables a CDTOF interrupt</description>
                                    <value>#1</value>
                                </enumeratedValue>
                            </enumeratedValues>
                        </field>
                        <field>
                            <name>IGHSIE</name>
                            <description>IGHS Interrupt Enable</description>
                            <lsb>17</lsb>
                            <msb>17</msb>
                            <access>read-write</access>
                            <enumeratedValues>
                                <enumeratedValue>
                                    <name>0</name>
                                    <description>Disables an IGHS interrupt</description>
                                    <value>#0</value>
                                </enumeratedValue>
                                <enumeratedValue>
                                    <name>1</name>
                                    <description>Enables an IGHS interrupt</description>
                                    <value>#1</value>
                                </enumeratedValue>
                            </enumeratedValues>
                        </field>
                        <field>
                            <name>IGVSIE</name>
                            <description>IGVS Interrupt Enable</description>
                            <lsb>18</lsb>
                            <msb>18</msb>
                            <access>read-write</access>
                            <enumeratedValues>
                                <enumeratedValue>
                                    <name>0</name>
                                    <description>Disables an IGVS interrupt</description>
                                    <value>#0</value>
                                </enumeratedValue>
                                <enumeratedValue>
                                    <name>1</name>
                                    <description>Enables an IGVS interrupt</description>
                                    <value>#1</value>
                                </enumeratedValue>
                            </enumeratedValues>
                        </field>
                        <field>
                            <name>VBPIE</name>
                            <description>VBP Interrupt Enable</description>
                            <lsb>20</lsb>
                            <msb>20</msb>
                            <access>read-write</access>
                            <enumeratedValues>
                                <enumeratedValue>
                                    <name>0</name>
                                    <description>Disables a VBP interrupt</description>
                                    <value>#0</value>
                                </enumeratedValue>
                                <enumeratedValue>
                                    <name>1</name>
                                    <description>Enables a VBP interrupt</description>
                                    <value>#1</value>
                                </enumeratedValue>
                            </enumeratedValues>
                        </field>
                        <field>
                            <name>FWFIE</name>
                            <description>FWF Interrupt Enable</description>
                            <lsb>23</lsb>
                            <msb>23</msb>
                            <access>read-write</access>
                            <enumeratedValues>
                                <enumeratedValue>
                                    <name>0</name>
                                    <description>Disables a FWF interrupt</description>
                                    <value>#0</value>
                                </enumeratedValue>
                                <enumeratedValue>
                                    <name>1</name>
                                    <description>Enables a FWF interrupt</description>
                                    <value>#1</value>
                                </enumeratedValue>
                            </enumeratedValues>
                        </field>
                        <field>
                            <name>NHDIE</name>
                            <description>Non-HD Interrupt Enable</description>
                            <lsb>24</lsb>
                            <msb>24</msb>
                            <access>read-write</access>
                            <enumeratedValues>
                                <enumeratedValue>
                                    <name>0</name>
                                    <description>Disables a non-HD interrupt</description>
                                    <value>#0</value>
                                </enumeratedValue>
                                <enumeratedValue>
                                    <name>1</name>
                                    <description>Enables a non-HD interrupt</description>
                                    <value>#1</value>
                                </enumeratedValue>
                            </enumeratedValues>
                        </field>
                        <field>
                            <name>NVDIE</name>
                            <description>Non-VD Interrupt Enable</description>
                            <lsb>25</lsb>
                            <msb>25</msb>
                            <access>read-write</access>
                            <enumeratedValues>
                                <enumeratedValue>
                                    <name>0</name>
                                    <description>Disables a non-VD interrupt</description>
                                    <value>#0</value>
                                </enumeratedValue>
                                <enumeratedValue>
                                    <name>1</name>
                                    <description>Enables a non-VD interrupt</description>
                                    <value>#1</value>
                                </enumeratedValue>
                            </enumeratedValues>
                        </field>
                    </fields>
                </register>
                <register>
                    <name>CETCR</name>
                    <description>Capture Event Flag Clear Register</description>
                    <addressOffset>0x0074</addressOffset>
                    <size>32</size>
                    <access>read-write</access>
                    <resetValue>0x00000000</resetValue>
                    <resetMask>0xfffffcff</resetMask>
                    <fields>
                        <field>
                            <name>CPE</name>
                            <description>An interrupt indicating that capturing of one frame from an external module has finished.</description>
                            <lsb>0</lsb>
                            <msb>0</msb>
                            <access>read-write</access>
                        </field>
                        <field>
                            <name>CFE</name>
                            <description>An interrupt indicating that capturing of one field from an external module has finished.</description>
                            <lsb>1</lsb>
                            <msb>1</msb>
                            <access>read-write</access>
                        </field>
                        <field>
                            <name>IGRW</name>
                            <description>An interrupt indicating that during capturing, access was attempted to a register to which writing during operation is prohibited.</description>
                            <lsb>4</lsb>
                            <msb>4</msb>
                            <access>read-write</access>
                        </field>
                        <field>
                            <name>HD</name>
                            <description>An interrupt indicating that HD (horizontal sync signal) was input from an external module.</description>
                            <lsb>8</lsb>
                            <msb>8</msb>
                            <access>read-write</access>
                        </field>
                        <field>
                            <name>VD</name>
                            <description>An interrupt indicating that VD (vertical sync signal) was input from an external module.</description>
                            <lsb>9</lsb>
                            <msb>9</msb>
                            <access>read-write</access>
                        </field>
                        <field>
                            <name>CPBE1</name>
                            <description>An interrupt indicating that writing to CDAYR and CDACR in a bundle write has finished.</description>
                            <lsb>12</lsb>
                            <msb>12</msb>
                            <access>read-write</access>
                        </field>
                        <field>
                            <name>CPBE2</name>
                            <description>An interrupt indicating that writing to CDAYR2 and CDACR2 in a bundle write has finished.</description>
                            <lsb>13</lsb>
                            <msb>13</msb>
                            <access>read-write</access>
                        </field>
                        <field>
                            <name>CPBE3</name>
                            <description>An interrupt indicating that writing to CDBYR and CDBCR in a bundle write has finished.</description>
                            <lsb>14</lsb>
                            <msb>14</msb>
                            <access>read-write</access>
                        </field>
                        <field>
                            <name>CPBE4</name>
                            <description>An interrupt indicating that writing to CDBYR2 and CDBCR2 in a bundle write has finished.</description>
                            <lsb>15</lsb>
                            <msb>15</msb>
                            <access>read-write</access>
                        </field>
                        <field>
                            <name>CDTOF</name>
                            <description>An interrupt indicating that data overflowed in the CRAM of the write buffer</description>
                            <lsb>16</lsb>
                            <msb>16</msb>
                            <access>read-write</access>
                        </field>
                        <field>
                            <name>IGHS</name>
                            <description>An interrupt generated when the number of HD cycles set in CMCYR differ from the number of HD cycles input from an external module.</description>
                            <lsb>17</lsb>
                            <msb>17</msb>
                            <access>read-write</access>
                        </field>
                        <field>
                            <name>IGVS</name>
                            <description>An interrupt generated when the number of VD cycles set in CMCYR differ from the number of VD cycles input from an external module.</description>
                            <lsb>18</lsb>
                            <msb>18</msb>
                            <access>read-write</access>
                        </field>
                        <field>
                            <name>VBP</name>
                            <description>An interrupt indicating that VD has been input while the CEU holds data (insufficient vertical-sync front porch).</description>
                            <lsb>20</lsb>
                            <msb>20</msb>
                            <access>read-write</access>
                        </field>
                        <field>
                            <name>FWF</name>
                            <description>The interrupt is generated when data is written to the address that exceeds the value specified with CFWCR.FMV.</description>
                            <lsb>23</lsb>
                            <msb>23</msb>
                            <access>read-write</access>
                        </field>
                        <field>
                            <name>NHD</name>
                            <description>An interrupt indicating that no HD was input.</description>
                            <lsb>24</lsb>
                            <msb>24</msb>
                            <access>read-write</access>
                        </field>
                        <field>
                            <name>NVD</name>
                            <description>An interrupt indicating that no VD was input.</description>
                            <lsb>25</lsb>
                            <msb>25</msb>
                            <access>read-write</access>
                        </field>
                    </fields>
                </register>
                <register>
                    <name>CSTSR</name>
                    <description>Capture Status Register</description>
                    <addressOffset>0x007C</addressOffset>
                    <size>32</size>
                    <access>read-only</access>
                    <resetValue>0x00000000</resetValue>
                    <resetMask>0xffffffff</resetMask>
                    <fields>
                        <field>
                            <name>CPTON</name>
                            <description>Indicates that the CEU is operating.</description>
                            <lsb>0</lsb>
                            <msb>0</msb>
                            <access>read-only</access>
                        </field>
                        <field>
                            <name>CPFLD</name>
                            <description>Indicates which field is being captured.</description>
                            <lsb>16</lsb>
                            <msb>16</msb>
                            <access>read-only</access>
                            <enumeratedValues>
                                <enumeratedValue>
                                    <name>0</name>
                                    <description>Bottom field is being captured</description>
                                    <value>#0</value>
                                </enumeratedValue>
                                <enumeratedValue>
                                    <name>1</name>
                                    <description>Top field is being captured</description>
                                    <value>#1</value>
                                </enumeratedValue>
                            </enumeratedValues>
                        </field>
                        <field>
                            <name>CRST</name>
                            <description>Indicates which register plane is currently used.</description>
                            <lsb>24</lsb>
                            <msb>24</msb>
                            <access>read-only</access>
                            <enumeratedValues>
                                <enumeratedValue>
                                    <name>0</name>
                                    <description>Plane A of the register is being used</description>
                                    <value>#0</value>
                                </enumeratedValue>
                                <enumeratedValue>
                                    <name>1</name>
                                    <description>Plane B of the register is being used</description>
                                    <value>#1</value>
                                </enumeratedValue>
                            </enumeratedValues>
                        </field>
                    </fields>
                </register>
                <register>
                    <name>CDSSR</name>
                    <description>Capture Data Size Register</description>
                    <addressOffset>0x0084</addressOffset>
                    <size>32</size>
                    <access>read-only</access>
                    <resetValue>0x00000000</resetValue>
                    <resetMask>0xffffffff</resetMask>
                    <fields>
                        <field>
                            <name>CDSS</name>
                            <description>Indicate the size of data written to the memory in data enable fetch.</description>
                            <lsb>0</lsb>
                            <msb>31</msb>
                            <access>read-only</access>
                        </field>
                    </fields>
                </register>
                <register>
                    <name>CDAYR2</name>
                    <description>Capture Data Address Y Register 2</description>
                    <addressOffset>0x0090</addressOffset>
                    <size>32</size>
                    <access>read-write</access>
                    <resetValue>0x00000000</resetValue>
                    <resetMask>0xffffffff</resetMask>
                    <fields>
                        <field>
                            <name>CAYR2</name>
                            <description>Capture Data Address Y</description>
                            <lsb>0</lsb>
                            <msb>31</msb>
                            <access>read-write</access>
                        </field>
                    </fields>
                </register>
                <register>
                    <name>CDACR2</name>
                    <description>Capture Data Address C Register 2</description>
                    <addressOffset>0x0094</addressOffset>
                    <size>32</size>
                    <access>read-write</access>
                    <resetValue>0x00000000</resetValue>
                    <resetMask>0xffffffff</resetMask>
                    <fields>
                        <field>
                            <name>CACR2</name>
                            <description>Capture Data Address C</description>
                            <lsb>0</lsb>
                            <msb>31</msb>
                            <access>read-write</access>
                        </field>
                    </fields>
                </register>
                <register>
                    <name>CDBYR2</name>
                    <description>Capture Data Bottom-Field Address Y Register 2</description>
                    <addressOffset>0x0098</addressOffset>
                    <size>32</size>
                    <access>read-write</access>
                    <resetValue>0x00000000</resetValue>
                    <resetMask>0xffffffff</resetMask>
                    <fields>
                        <field>
                            <name>CBYR2</name>
                            <description>Set the address for storing the luminance component data of the captured bottom-field data (8-pixel units).</description>
                            <lsb>0</lsb>
                            <msb>31</msb>
                            <access>read-write</access>
                        </field>
                    </fields>
                </register>
                <register>
                    <name>CDBCR2</name>
                    <description>Capture Data Bottom-Field Address C Register 2</description>
                    <addressOffset>0x009C</addressOffset>
                    <size>32</size>
                    <access>read-write</access>
                    <resetValue>0x00000000</resetValue>
                    <resetMask>0xffffffff</resetMask>
                    <fields>
                        <field>
                            <name>CBCR2</name>
                            <description>Set the address for storing the chrominance component data of the captured bottom-field data (8-pixel units).</description>
                            <lsb>0</lsb>
                            <msb>31</msb>
                            <access>read-write</access>
                        </field>
                    </fields>
                </register>
                <register>
                    <name>CBWER</name>
                    <description>CEU Bufferable Write Enable Register</description>
                    <addressOffset>0x00A0</addressOffset>
                    <size>32</size>
                    <access>read-write</access>
                    <resetValue>0x00000000</resetValue>
                    <resetMask>0xffffffff</resetMask>
                    <fields>
                        <field>
                            <name>BWE</name>
                            <lsb>0</lsb>
                            <msb>0</msb>
                            <access>read-write</access>
                            <enumeratedValues>
                                <enumeratedValue>
                                    <name>0</name>
                                    <description>Disables Bufferable Write</description>
                                    <value>#0</value>
                                </enumeratedValue>
                                <enumeratedValue>
                                    <name>1</name>
                                    <description>Enables Bufferable Write</description>
                                    <value>#1</value>
                                </enumeratedValue>
                            </enumeratedValues>
                        </field>
                    </fields>
                </register>
                <register>
                    <name>CAMOR_B</name>
                    <description>Capture Interface Offset Register</description>
                    <addressOffset>0x1010</addressOffset>
                    <size>32</size>
                    <access>read-write</access>
                    <resetValue>0x00000000</resetValue>
                    <resetMask>0xffffffff</resetMask>
                    <fields>
                        <field>
                            <name>HOFST</name>
                            <description>Specify the capture start location in terms of the number of clock cycles from a horizontal sync signal (1-cycle units).</description>
                            <lsb>0</lsb>
                            <msb>12</msb>
                            <access>read-write</access>
                        </field>
                        <field>
                            <name>VOFST</name>
                            <description>Specify the capture start location in terms of the HD count from a vertical sync signal (1-HD units).</description>
                            <lsb>16</lsb>
                            <msb>27</msb>
                            <access>read-write</access>
                        </field>
                    </fields>
                </register>
                <register>
                    <name>CAPWR_B</name>
                    <description>Capture Interface Width Register</description>
                    <addressOffset>0x1014</addressOffset>
                    <size>32</size>
                    <access>read-write</access>
                    <resetValue>0x00000000</resetValue>
                    <resetMask>0xffffffff</resetMask>
                    <fields>
                        <field>
                            <name>HWDTH</name>
                            <description>Specify the horizontal capture period.</description>
                            <lsb>0</lsb>
                            <msb>12</msb>
                            <access>read-write</access>
                        </field>
                        <field>
                            <name>VWDTH</name>
                            <description>Specify the vertical capture period (4-HD units).</description>
                            <lsb>16</lsb>
                            <msb>27</msb>
                            <access>read-write</access>
                        </field>
                    </fields>
                </register>
                <register>
                    <name>CFLCR_B</name>
                    <description>Capture Filter Control Register</description>
                    <addressOffset>0x1030</addressOffset>
                    <size>32</size>
                    <access>read-write</access>
                    <resetValue>0x00000000</resetValue>
                    <resetMask>0xffffffff</resetMask>
                    <fields>
                        <field>
                            <name>HFRAC</name>
                            <description>Fraction Part of Horizontal Scale-Down Factor</description>
                            <lsb>0</lsb>
                            <msb>11</msb>
                            <access>read-write</access>
                        </field>
                        <field>
                            <name>HMANT</name>
                            <description>Mantissa Part of Horizontal Scale-Down Factor</description>
                            <lsb>12</lsb>
                            <msb>15</msb>
                            <access>read-write</access>
                        </field>
                        <field>
                            <name>VFRAC</name>
                            <description>Fraction Part of Vertical Scale-Down Factor</description>
                            <lsb>16</lsb>
                            <msb>27</msb>
                            <access>read-write</access>
                        </field>
                        <field>
                            <name>VMANT</name>
                            <description>Mantissa Part of Vertical Scale-Down Factor</description>
                            <lsb>28</lsb>
                            <msb>31</msb>
                            <access>read-write</access>
                        </field>
                    </fields>
                </register>
                <register>
                    <name>CFSZR_B</name>
                    <description>Capture Filter Size Clip Register</description>
                    <addressOffset>0x1034</addressOffset>
                    <size>32</size>
                    <access>read-write</access>
                    <resetValue>0x00000000</resetValue>
                    <resetMask>0xffffffff</resetMask>
                    <fields>
                        <field>
                            <name>HFCLP</name>
                            <description>Specify the horizontal clipping value of the filter output size (8-pixel units).</description>
                            <lsb>0</lsb>
                            <msb>11</msb>
                            <access>read-write</access>
                        </field>
                        <field>
                            <name>VFCLP</name>
                            <description>Specify the vertical clipping value of the filter output size (4-pixel units).</description>
                            <lsb>16</lsb>
                            <msb>27</msb>
                            <access>read-write</access>
                        </field>
                    </fields>
                </register>
                <register>
                    <name>CDWDR_B</name>
                    <description>Capture Destination Width Register</description>
                    <addressOffset>0x1038</addressOffset>
                    <size>32</size>
                    <access>read-write</access>
                    <resetValue>0x00000000</resetValue>
                    <resetMask>0xffffffff</resetMask>
                    <fields>
                        <field>
                            <name>CHDW</name>
                            <description>Specify the horizontal image size in the memory area where the captured image is to be stored (8-byte units).</description>
                            <lsb>0</lsb>
                            <msb>12</msb>
                            <access>read-write</access>
                        </field>
                    </fields>
                </register>
                <register>
                    <name>CDAYR_B</name>
                    <description>Capture Data Address Y Register</description>
                    <addressOffset>0x103C</addressOffset>
                    <size>32</size>
                    <access>read-write</access>
                    <resetValue>0x00000000</resetValue>
                    <resetMask>0xffffffff</resetMask>
                    <fields>
                        <field>
                            <name>CAYR</name>
                            <description>Capture Data Address Y</description>
                            <lsb>0</lsb>
                            <msb>31</msb>
                            <access>read-write</access>
                        </field>
                    </fields>
                </register>
                <register>
                    <name>CDACR_B</name>
                    <description>Capture Data Address C Register</description>
                    <addressOffset>0x1040</addressOffset>
                    <size>32</size>
                    <access>read-write</access>
                    <resetValue>0x00000000</resetValue>
                    <resetMask>0xffffffff</resetMask>
                    <fields>
                        <field>
                            <name>CACR</name>
                            <description>Capture Data Address C</description>
                            <lsb>0</lsb>
                            <msb>31</msb>
                            <access>read-write</access>
                        </field>
                    </fields>
                </register>
                <register>
                    <name>CDBYR_B</name>
                    <description>Capture Data Bottom-Field Address Y Register</description>
                    <addressOffset>0x1044</addressOffset>
                    <size>32</size>
                    <access>read-write</access>
                    <resetValue>0x00000000</resetValue>
                    <resetMask>0xffffffff</resetMask>
                    <fields>
                        <field>
                            <name>CBYR</name>
                            <description>Set the address for storing the luminance component data of the captured bottom-field data (8-pixel units).</description>
                            <lsb>0</lsb>
                            <msb>31</msb>
                            <access>read-write</access>
                        </field>
                    </fields>
                </register>
                <register>
                    <name>CDBCR_B</name>
                    <description>Capture Data Bottom-Field Address C Register</description>
                    <addressOffset>0x1048</addressOffset>
                    <size>32</size>
                    <access>read-write</access>
                    <resetValue>0x00000000</resetValue>
                    <resetMask>0xffffffff</resetMask>
                    <fields>
                        <field>
                            <name>CBCR</name>
                            <description>Set the address for storing the chrominance component data of the captured bottom-field data (8-pixel units).</description>
                            <lsb>0</lsb>
                            <msb>31</msb>
                            <access>read-write</access>
                        </field>
                    </fields>
                </register>
                <register>
                    <name>CBDSR_B</name>
                    <description>Capture Bundle Destination Size Register</description>
                    <addressOffset>0x104C</addressOffset>
                    <size>32</size>
                    <access>read-write</access>
                    <resetValue>0x00000000</resetValue>
                    <resetMask>0xffffffff</resetMask>
                    <fields>
                        <field>
                            <name>CBVS</name>
                            <description>Select the number of lines or number of bytes for output to the memory in a bundle write.</description>
                            <lsb>0</lsb>
                            <msb>22</msb>
                            <access>read-write</access>
                        </field>
                    </fields>
                </register>
                <register>
                    <name>CLFCR_B</name>
                    <description>Capture Low-Pass Filter Control Register</description>
                    <addressOffset>0x1060</addressOffset>
                    <size>32</size>
                    <access>read-write</access>
                    <resetValue>0x00000000</resetValue>
                    <resetMask>0xffffffff</resetMask>
                    <fields>
                        <field>
                            <name>LPF</name>
                            <description>Enables or disables operation of the low-pass filter.</description>
                            <lsb>0</lsb>
                            <msb>0</msb>
                            <access>read-write</access>
                            <enumeratedValues>
                                <enumeratedValue>
                                    <name>0</name>
                                    <description>Low-pass filter not used</description>
                                    <value>#0</value>
                                </enumeratedValue>
                                <enumeratedValue>
                                    <name>1</name>
                                    <description>Low-pass filter used (only in the horizontal direction)</description>
                                    <value>#1</value>
                                </enumeratedValue>
                            </enumeratedValues>
                        </field>
                    </fields>
                </register>
                <register>
                    <name>CDOCR_B</name>
                    <description>Capture Data Output Control Register</description>
                    <addressOffset>0x1064</addressOffset>
                    <size>32</size>
                    <access>read-write</access>
                    <resetValue>0x00000000</resetValue>
                    <resetMask>0xffffffff</resetMask>
                    <fields>
                        <field>
                            <name>COBS</name>
                            <description>Controls swapping in 8-bit units for data output from the CEU.</description>
                            <lsb>0</lsb>
                            <msb>0</msb>
                            <access>read-write</access>
                            <enumeratedValues>
                                <enumeratedValue>
                                    <name>0</name>
                                    <description>Data is not swapped in 8-bit units</description>
                                    <value>#0</value>
                                </enumeratedValue>
                                <enumeratedValue>
                                    <name>1</name>
                                    <description>Data is swapped in 8-bit units</description>
                                    <value>#1</value>
                                </enumeratedValue>
                            </enumeratedValues>
                        </field>
                        <field>
                            <name>COWS</name>
                            <description>Controls swapping in 16-bit units for data output from the CEU.</description>
                            <lsb>1</lsb>
                            <msb>1</msb>
                            <access>read-write</access>
                            <enumeratedValues>
                                <enumeratedValue>
                                    <name>0</name>
                                    <description>Data is not swapped in 16-bit units</description>
                                    <value>#0</value>
                                </enumeratedValue>
                                <enumeratedValue>
                                    <name>1</name>
                                    <description>Data is swapped in 16-bit units</description>
                                    <value>#1</value>
                                </enumeratedValue>
                            </enumeratedValues>
                        </field>
                        <field>
                            <name>COLS</name>
                            <description>Controls swapping in 32-bit units for data output from the CEU.</description>
                            <lsb>2</lsb>
                            <msb>2</msb>
                            <access>read-write</access>
                            <enumeratedValues>
                                <enumeratedValue>
                                    <name>0</name>
                                    <description>Data is not swapped in 32-bit units</description>
                                    <value>#0</value>
                                </enumeratedValue>
                                <enumeratedValue>
                                    <name>1</name>
                                    <description>Data is swapped in 32-bit units</description>
                                    <value>#1</value>
                                </enumeratedValue>
                            </enumeratedValues>
                        </field>
                        <field>
                            <name>CDS</name>
                            <description>Sets the image format when outputting the image data captured in the YCbCr422 format to the memory.</description>
                            <lsb>4</lsb>
                            <msb>4</msb>
                            <access>read-write</access>
                            <enumeratedValues>
                                <enumeratedValue>
                                    <name>0</name>
                                    <description>Converts the YCbCr422 format to the YCbCr420 format before outputting data to the memory</description>
                                    <value>#0</value>
                                </enumeratedValue>
                                <enumeratedValue>
                                    <name>1</name>
                                    <description>Outputs data in the YCbCr422 format to the memory without conversion</description>
                                    <value>#1</value>
                                </enumeratedValue>
                            </enumeratedValues>
                        </field>
                        <field>
                            <name>CBE</name>
                            <description> Controls the number of lines of captured data to be written to the memory.</description>
                            <lsb>16</lsb>
                            <msb>16</msb>
                            <access>read-write</access>
                            <enumeratedValues>
                                <enumeratedValue>
                                    <name>0</name>
                                    <description>Normal write</description>
                                    <value>#0</value>
                                </enumeratedValue>
                                <enumeratedValue>
                                    <name>1</name>
                                    <description>Bundle write</description>
                                    <value>#1</value>
                                </enumeratedValue>
                            </enumeratedValues>
                        </field>
                    </fields>
                </register>
                <register>
                    <name>CDAYR2_B</name>
                    <description>Capture Data Address Y Register 2</description>
                    <addressOffset>0x1090</addressOffset>
                    <size>32</size>
                    <access>read-write</access>
                    <resetValue>0x00000000</resetValue>
                    <resetMask>0xffffffff</resetMask>
                    <fields>
                        <field>
                            <name>CAYR2</name>
                            <description>Capture Data Address Y</description>
                            <lsb>0</lsb>
                            <msb>31</msb>
                            <access>read-write</access>
                        </field>
                    </fields>
                </register>
                <register>
                    <name>CDACR2_B</name>
                    <description>Capture Data Address C Register 2</description>
                    <addressOffset>0x1094</addressOffset>
                    <size>32</size>
                    <access>read-write</access>
                    <resetValue>0x00000000</resetValue>
                    <resetMask>0xffffffff</resetMask>
                    <fields>
                        <field>
                            <name>CACR2</name>
                            <description>Capture Data Address C</description>
                            <lsb>0</lsb>
                            <msb>31</msb>
                            <access>read-write</access>
                        </field>
                    </fields>
                </register>
                <register>
                    <name>CDBYR2_B</name>
                    <description>Capture Data Bottom-Field Address Y Register 2</description>
                    <addressOffset>0x1098</addressOffset>
                    <size>32</size>
                    <access>read-write</access>
                    <resetValue>0x00000000</resetValue>
                    <resetMask>0xffffffff</resetMask>
                    <fields>
                        <field>
                            <name>CBYR2</name>
                            <description>Set the address for storing the luminance component data of the captured bottom-field data (8-pixel units).</description>
                            <lsb>0</lsb>
                            <msb>31</msb>
                            <access>read-write</access>
                        </field>
                    </fields>
                </register>
                <register>
                    <name>CDBCR2_B</name>
                    <description>Capture Data Bottom-Field Address C Register 2</description>
                    <addressOffset>0x109C</addressOffset>
                    <size>32</size>
                    <access>read-write</access>
                    <resetValue>0x00000000</resetValue>
                    <resetMask>0xffffffff</resetMask>
                    <fields>
                        <field>
                            <name>CBCR2</name>
                            <description>Set the address for storing the chrominance component data of the captured bottom-field data (8-pixel units).</description>
                            <lsb>0</lsb>
                            <msb>31</msb>
                            <access>read-write</access>
                        </field>
                    </fields>
                </register>
                <register>
                    <name>CAMOR_M</name>
                    <description>Capture Interface Offset Register</description>
                    <addressOffset>0x2010</addressOffset>
                    <size>32</size>
                    <access>read-write</access>
                    <resetValue>0x00000000</resetValue>
                    <resetMask>0xffffffff</resetMask>
                    <fields>
                        <field>
                            <name>HOFST</name>
                            <description>Specify the capture start location in terms of the number of clock cycles from a horizontal sync signal (1-cycle units).</description>
                            <lsb>0</lsb>
                            <msb>12</msb>
                            <access>read-write</access>
                        </field>
                        <field>
                            <name>VOFST</name>
                            <description>Specify the capture start location in terms of the HD count from a vertical sync signal (1-HD units).</description>
                            <lsb>16</lsb>
                            <msb>27</msb>
                            <access>read-write</access>
                        </field>
                    </fields>
                </register>
                <register>
                    <name>CAPWR_M</name>
                    <description>Capture Interface Width Register</description>
                    <addressOffset>0x2014</addressOffset>
                    <size>32</size>
                    <access>read-write</access>
                    <resetValue>0x00000000</resetValue>
                    <resetMask>0xffffffff</resetMask>
                    <fields>
                        <field>
                            <name>HWDTH</name>
                            <description>Specify the horizontal capture period.</description>
                            <lsb>0</lsb>
                            <msb>12</msb>
                            <access>read-write</access>
                        </field>
                        <field>
                            <name>VWDTH</name>
                            <description>Specify the vertical capture period (4-HD units).</description>
                            <lsb>16</lsb>
                            <msb>27</msb>
                            <access>read-write</access>
                        </field>
                    </fields>
                </register>
                <register>
                    <name>CFLCR_M</name>
                    <description>Capture Filter Control Register</description>
                    <addressOffset>0x2030</addressOffset>
                    <size>32</size>
                    <access>read-write</access>
                    <resetValue>0x00000000</resetValue>
                    <resetMask>0xffffffff</resetMask>
                    <fields>
                        <field>
                            <name>HFRAC</name>
                            <description>Fraction Part of Horizontal Scale-Down Factor</description>
                            <lsb>0</lsb>
                            <msb>11</msb>
                            <access>read-write</access>
                        </field>
                        <field>
                            <name>HMANT</name>
                            <description>Mantissa Part of Horizontal Scale-Down Factor</description>
                            <lsb>12</lsb>
                            <msb>15</msb>
                            <access>read-write</access>
                        </field>
                        <field>
                            <name>VFRAC</name>
                            <description>Fraction Part of Vertical Scale-Down Factor</description>
                            <lsb>16</lsb>
                            <msb>27</msb>
                            <access>read-write</access>
                        </field>
                        <field>
                            <name>VMANT</name>
                            <description>Mantissa Part of Vertical Scale-Down Factor</description>
                            <lsb>28</lsb>
                            <msb>31</msb>
                            <access>read-write</access>
                        </field>
                    </fields>
                </register>
                <register>
                    <name>CFSZR_M</name>
                    <description>Capture Filter Size Clip Register</description>
                    <addressOffset>0x2034</addressOffset>
                    <size>32</size>
                    <access>read-write</access>
                    <resetValue>0x00000000</resetValue>
                    <resetMask>0xffffffff</resetMask>
                    <fields>
                        <field>
                            <name>HFCLP</name>
                            <description>Specify the horizontal clipping value of the filter output size (8-pixel units).</description>
                            <lsb>0</lsb>
                            <msb>11</msb>
                            <access>read-write</access>
                        </field>
                        <field>
                            <name>VFCLP</name>
                            <description>Specify the vertical clipping value of the filter output size (4-pixel units).</description>
                            <lsb>16</lsb>
                            <msb>27</msb>
                            <access>read-write</access>
                        </field>
                    </fields>
                </register>
                <register>
                    <name>CDWDR_M</name>
                    <description>Capture Destination Width Register</description>
                    <addressOffset>0x2038</addressOffset>
                    <size>32</size>
                    <access>read-write</access>
                    <resetValue>0x00000000</resetValue>
                    <resetMask>0xffffffff</resetMask>
                    <fields>
                        <field>
                            <name>CHDW</name>
                            <description>Specify the horizontal image size in the memory area where the captured image is to be stored (8-byte units).</description>
                            <lsb>0</lsb>
                            <msb>12</msb>
                            <access>read-write</access>
                        </field>
                    </fields>
                </register>
                <register>
                    <name>CDAYR_M</name>
                    <description>Capture Data Address Y Register</description>
                    <addressOffset>0x203C</addressOffset>
                    <size>32</size>
                    <access>read-write</access>
                    <resetValue>0x00000000</resetValue>
                    <resetMask>0xffffffff</resetMask>
                    <fields>
                        <field>
                            <name>CAYR</name>
                            <description>Capture Data Address Y</description>
                            <lsb>0</lsb>
                            <msb>31</msb>
                            <access>read-write</access>
                        </field>
                    </fields>
                </register>
                <register>
                    <name>CDACR_M</name>
                    <description>Capture Data Address C Register</description>
                    <addressOffset>0x2040</addressOffset>
                    <size>32</size>
                    <access>read-write</access>
                    <resetValue>0x00000000</resetValue>
                    <resetMask>0xffffffff</resetMask>
                    <fields>
                        <field>
                            <name>CACR</name>
                            <description>Capture Data Address C</description>
                            <lsb>0</lsb>
                            <msb>31</msb>
                            <access>read-write</access>
                        </field>
                    </fields>
                </register>
                <register>
                    <name>CDBYR_M</name>
                    <description>Capture Data Bottom-Field Address Y Register</description>
                    <addressOffset>0x2044</addressOffset>
                    <size>32</size>
                    <access>read-write</access>
                    <resetValue>0x00000000</resetValue>
                    <resetMask>0xffffffff</resetMask>
                    <fields>
                        <field>
                            <name>CBYR</name>
                            <description>Set the address for storing the luminance component data of the captured bottom-field data (8-pixel units).</description>
                            <lsb>0</lsb>
                            <msb>31</msb>
                            <access>read-write</access>
                        </field>
                    </fields>
                </register>
                <register>
                    <name>CDBCR_M</name>
                    <description>Capture Data Bottom-Field Address C Register</description>
                    <addressOffset>0x2048</addressOffset>
                    <size>32</size>
                    <access>read-write</access>
                    <resetValue>0x00000000</resetValue>
                    <resetMask>0xffffffff</resetMask>
                    <fields>
                        <field>
                            <name>CBCR</name>
                            <description>Set the address for storing the chrominance component data of the captured bottom-field data (8-pixel units).</description>
                            <lsb>0</lsb>
                            <msb>31</msb>
                            <access>read-write</access>
                        </field>
                    </fields>
                </register>
                <register>
                    <name>CBDSR_M</name>
                    <description>Capture Bundle Destination Size Register</description>
                    <addressOffset>0x204C</addressOffset>
                    <size>32</size>
                    <access>read-write</access>
                    <resetValue>0x00000000</resetValue>
                    <resetMask>0xffffffff</resetMask>
                    <fields>
                        <field>
                            <name>CBVS</name>
                            <description>Select the number of lines or number of bytes for output to the memory in a bundle write.</description>
                            <lsb>0</lsb>
                            <msb>22</msb>
                            <access>read-write</access>
                        </field>
                    </fields>
                </register>
                <register>
                    <name>CLFCR_M</name>
                    <description>Capture Low-Pass Filter Control Register</description>
                    <addressOffset>0x2060</addressOffset>
                    <size>32</size>
                    <access>read-write</access>
                    <resetValue>0x00000000</resetValue>
                    <resetMask>0xffffffff</resetMask>
                    <fields>
                        <field>
                            <name>LPF</name>
                            <description>Enables or disables operation of the low-pass filter.</description>
                            <lsb>0</lsb>
                            <msb>0</msb>
                            <access>read-write</access>
                            <enumeratedValues>
                                <enumeratedValue>
                                    <name>0</name>
                                    <description>Low-pass filter not used</description>
                                    <value>#0</value>
                                </enumeratedValue>
                                <enumeratedValue>
                                    <name>1</name>
                                    <description>Low-pass filter used (only in the horizontal direction)</description>
                                    <value>#1</value>
                                </enumeratedValue>
                            </enumeratedValues>
                        </field>
                    </fields>
                </register>
                <register>
                    <name>CDOCR_M</name>
                    <description>Capture Data Output Control Register</description>
                    <addressOffset>0x2064</addressOffset>
                    <size>32</size>
                    <access>read-write</access>
                    <resetValue>0x00000000</resetValue>
                    <resetMask>0xffffffff</resetMask>
                    <fields>
                        <field>
                            <name>COBS</name>
                            <description>Controls swapping in 8-bit units for data output from the CEU.</description>
                            <lsb>0</lsb>
                            <msb>0</msb>
                            <access>read-write</access>
                            <enumeratedValues>
                                <enumeratedValue>
                                    <name>0</name>
                                    <description>Data is not swapped in 8-bit units</description>
                                    <value>#0</value>
                                </enumeratedValue>
                                <enumeratedValue>
                                    <name>1</name>
                                    <description>Data is swapped in 8-bit units</description>
                                    <value>#1</value>
                                </enumeratedValue>
                            </enumeratedValues>
                        </field>
                        <field>
                            <name>COWS</name>
                            <description>Controls swapping in 16-bit units for data output from the CEU.</description>
                            <lsb>1</lsb>
                            <msb>1</msb>
                            <access>read-write</access>
                            <enumeratedValues>
                                <enumeratedValue>
                                    <name>0</name>
                                    <description>Data is not swapped in 16-bit units</description>
                                    <value>#0</value>
                                </enumeratedValue>
                                <enumeratedValue>
                                    <name>1</name>
                                    <description>Data is swapped in 16-bit units</description>
                                    <value>#1</value>
                                </enumeratedValue>
                            </enumeratedValues>
                        </field>
                        <field>
                            <name>COLS</name>
                            <description>Controls swapping in 32-bit units for data output from the CEU.</description>
                            <lsb>2</lsb>
                            <msb>2</msb>
                            <access>read-write</access>
                            <enumeratedValues>
                                <enumeratedValue>
                                    <name>0</name>
                                    <description>Data is not swapped in 32-bit units</description>
                                    <value>#0</value>
                                </enumeratedValue>
                                <enumeratedValue>
                                    <name>1</name>
                                    <description>Data is swapped in 32-bit units</description>
                                    <value>#1</value>
                                </enumeratedValue>
                            </enumeratedValues>
                        </field>
                        <field>
                            <name>CDS</name>
                            <description>Sets the image format when outputting the image data captured in the YCbCr422 format to the memory.</description>
                            <lsb>4</lsb>
                            <msb>4</msb>
                            <access>read-write</access>
                            <enumeratedValues>
                                <enumeratedValue>
                                    <name>0</name>
                                    <description>Converts the YCbCr422 format to the YCbCr420 format before outputting data to the memory</description>
                                    <value>#0</value>
                                </enumeratedValue>
                                <enumeratedValue>
                                    <name>1</name>
                                    <description>Outputs data in the YCbCr422 format to the memory without conversion</description>
                                    <value>#1</value>
                                </enumeratedValue>
                            </enumeratedValues>
                        </field>
                        <field>
                            <name>CBE</name>
                            <description> Controls the number of lines of captured data to be written to the memory.</description>
                            <lsb>16</lsb>
                            <msb>16</msb>
                            <access>read-write</access>
                            <enumeratedValues>
                                <enumeratedValue>
                                    <name>0</name>
                                    <description>Normal write</description>
                                    <value>#0</value>
                                </enumeratedValue>
                                <enumeratedValue>
                                    <name>1</name>
                                    <description>Bundle write</description>
                                    <value>#1</value>
                                </enumeratedValue>
                            </enumeratedValues>
                        </field>
                    </fields>
                </register>
                <register>
                    <name>CDAYR2_M</name>
                    <description>Capture Data Address Y Register 2</description>
                    <addressOffset>0x2090</addressOffset>
                    <size>32</size>
                    <access>read-write</access>
                    <resetValue>0x00000000</resetValue>
                    <resetMask>0xffffffff</resetMask>
                    <fields>
                        <field>
                            <name>CAYR2</name>
                            <description>Capture Data Address Y</description>
                            <lsb>0</lsb>
                            <msb>31</msb>
                            <access>read-write</access>
                        </field>
                    </fields>
                </register>
                <register>
                    <name>CDACR2_M</name>
                    <description>Capture Data Address C Register 2</description>
                    <addressOffset>0x2094</addressOffset>
                    <size>32</size>
                    <access>read-write</access>
                    <resetValue>0x00000000</resetValue>
                    <resetMask>0xffffffff</resetMask>
                    <fields>
                        <field>
                            <name>CACR2</name>
                            <description>Capture Data Address C</description>
                            <lsb>0</lsb>
                            <msb>31</msb>
                            <access>read-write</access>
                        </field>
                    </fields>
                </register>
                <register>
                    <name>CDBYR2_M</name>
                    <description>Capture Data Bottom-Field Address Y Register 2</description>
                    <addressOffset>0x2098</addressOffset>
                    <size>32</size>
                    <access>read-write</access>
                    <resetValue>0x00000000</resetValue>
                    <resetMask>0xffffffff</resetMask>
                    <fields>
                        <field>
                            <name>CBYR2</name>
                            <description>Set the address for storing the luminance component data of the captured bottom-field data (8-pixel units).</description>
                            <lsb>0</lsb>
                            <msb>31</msb>
                            <access>read-write</access>
                        </field>
                    </fields>
                </register>
                <register>
                    <name>CDBCR2_M</name>
                    <description>Capture Data Bottom-Field Address C Register 2</description>
                    <addressOffset>0x209C</addressOffset>
                    <size>32</size>
                    <access>read-write</access>
                    <resetValue>0x00000000</resetValue>
                    <resetMask>0xffffffff</resetMask>
                    <fields>
                        <field>
                            <name>CBCR2</name>
                            <description>Set the address for storing the chrominance component data of the captured bottom-field data (8-pixel units).</description>
                            <lsb>0</lsb>
                            <msb>31</msb>
                            <access>read-write</access>
                        </field>
                    </fields>
                </register>
            </registers>
        </peripheral>
        <peripheral>
            <name>EDMAC0_NS</name>
            <description>DMA Controller for the Ethernet Controller Channel 0</description>
            <baseAddress>0x50354000</baseAddress>
            <addressBlock>
                <offset>0x00</offset>
                <size>4</size>
                <usage>registers</usage>
            </addressBlock>
            <addressBlock>
                <offset>0x08</offset>
                <size>4</size>
                <usage>registers</usage>
            </addressBlock>
            <addressBlock>
                <offset>0x10</offset>
                <size>4</size>
                <usage>registers</usage>
            </addressBlock>
            <addressBlock>
                <offset>0x18</offset>
                <size>4</size>
                <usage>registers</usage>
            </addressBlock>
            <addressBlock>
                <offset>0x20</offset>
                <size>4</size>
                <usage>registers</usage>
            </addressBlock>
            <addressBlock>
                <offset>0x28</offset>
                <size>4</size>
                <usage>registers</usage>
            </addressBlock>
            <addressBlock>
                <offset>0x30</offset>
                <size>4</size>
                <usage>registers</usage>
            </addressBlock>
            <addressBlock>
                <offset>0x38</offset>
                <size>4</size>
                <usage>registers</usage>
            </addressBlock>
            <addressBlock>
                <offset>0x40</offset>
                <size>4</size>
                <usage>registers</usage>
            </addressBlock>
            <addressBlock>
                <offset>0x48</offset>
                <size>4</size>
                <usage>registers</usage>
            </addressBlock>
            <addressBlock>
                <offset>0x50</offset>
                <size>4</size>
                <usage>registers</usage>
            </addressBlock>
            <addressBlock>
                <offset>0x58</offset>
                <size>4</size>
                <usage>registers</usage>
            </addressBlock>
            <addressBlock>
                <offset>0x64</offset>
                <size>16</size>
                <usage>registers</usage>
            </addressBlock>
            <addressBlock>
                <offset>0x78</offset>
                <size>8</size>
                <usage>registers</usage>
            </addressBlock>
            <addressBlock>
                <offset>0xC8</offset>
                <size>8</size>
                <usage>registers</usage>
            </addressBlock>
            <addressBlock>
                <offset>0xD4</offset>
                <size>8</size>
                <usage>registers</usage>
            </addressBlock>
            <registers>
                <register>
                    <name>EDMR</name>
                    <description>EDMAC Mode Register</description>
                    <addressOffset>0x00</addressOffset>
                    <size>32</size>
                    <access>read-write</access>
                    <resetValue>0x00000000</resetValue>
                    <resetMask>0xffffffff</resetMask>
                    <fields>
                        <field>
                            <name>SWR</name>
                            <description>Software Reset</description>
                            <lsb>0</lsb>
                            <msb>0</msb>
                            <access>read-write</access>
                        </field>
                        <field>
                            <name>DL</name>
                            <description>Transmit/Receive Descriptor Length</description>
                            <lsb>4</lsb>
                            <msb>5</msb>
                            <access>read-write</access>
                            <enumeratedValues>
                                <enumeratedValue>
                                    <name>00</name>
                                    <description>16 bytes</description>
                                    <value>#00</value>
                                </enumeratedValue>
                                <enumeratedValue>
                                    <name>01</name>
                                    <description>32 bytes</description>
                                    <value>#01</value>
                                </enumeratedValue>
                                <enumeratedValue>
                                    <name>10</name>
                                    <description>64 bytes</description>
                                    <value>#10</value>
                                </enumeratedValue>
                                <enumeratedValue>
                                    <name>11</name>
                                    <description>16 bytes.</description>
                                    <value>#11</value>
                                </enumeratedValue>
                            </enumeratedValues>
                        </field>
                        <field>
                            <name>DE</name>
                            <description>Big Endian Mode/Little Endian Mode</description>
                            <lsb>6</lsb>
                            <msb>6</msb>
                            <access>read-write</access>
                            <enumeratedValues>
                                <enumeratedValue>
                                    <name>0</name>
                                    <description>Big endian mode</description>
                                    <value>#0</value>
                                </enumeratedValue>
                                <enumeratedValue>
                                    <name>1</name>
                                    <description>Little endian mode.</description>
                                    <value>#1</value>
                                </enumeratedValue>
                            </enumeratedValues>
                        </field>
                    </fields>
                </register>
                <register>
                    <name>EDTRR</name>
                    <description>EDMAC Transmit Request Register</description>
                    <addressOffset>0x08</addressOffset>
                    <size>32</size>
                    <access>read-write</access>
                    <resetValue>0x00000000</resetValue>
                    <resetMask>0xffffffff</resetMask>
                    <fields>
                        <field>
                            <name>TR</name>
                            <description>Transmit Request</description>
                            <lsb>0</lsb>
                            <msb>0</msb>
                            <access>read-write</access>
                        </field>
                    </fields>
                </register>
                <register>
                    <name>EDRRR</name>
                    <description>EDMAC Receive Request Register</description>
                    <addressOffset>0x10</addressOffset>
                    <size>32</size>
                    <access>read-write</access>
                    <resetValue>0x00000000</resetValue>
                    <resetMask>0xffffffff</resetMask>
                    <fields>
                        <field>
                            <name>RR</name>
                            <description>Receive Request</description>
                            <lsb>0</lsb>
                            <msb>0</msb>
                            <access>read-write</access>
                            <enumeratedValues>
                                <enumeratedValue>
                                    <name>0</name>
                                    <description>Disable the receive function</description>
                                    <value>#0</value>
                                </enumeratedValue>
                                <enumeratedValue>
                                    <name>1</name>
                                    <description>Read receive descriptor and enable the receive function.</description>
                                    <value>#1</value>
                                </enumeratedValue>
                            </enumeratedValues>
                        </field>
                    </fields>
                </register>
                <register>
                    <name>TDLAR</name>
                    <description>Transmit Descriptor List Start Address Register</description>
                    <addressOffset>0x18</addressOffset>
                    <size>32</size>
                    <access>read-write</access>
                    <resetValue>0x00000000</resetValue>
                    <resetMask>0xffffffff</resetMask>
                </register>
                <register>
                    <name>RDLAR</name>
                    <description>Receive Descriptor List Start Address Register</description>
                    <addressOffset>0x20</addressOffset>
                    <size>32</size>
                    <access>read-write</access>
                    <resetValue>0x00000000</resetValue>
                    <resetMask>0xffffffff</resetMask>
                </register>
                <register>
                    <name>EESR</name>
                    <description>ETHERC/EDMAC Status Register</description>
                    <addressOffset>0x28</addressOffset>
                    <size>32</size>
                    <access>read-write</access>
                    <resetValue>0x00000000</resetValue>
                    <resetMask>0xffffffff</resetMask>
                    <fields>
                        <field>
                            <name>CERF</name>
                            <description>CRC Error Flag</description>
                            <lsb>0</lsb>
                            <msb>0</msb>
                            <access>read-write</access>
                            <enumeratedValues>
                                <enumeratedValue>
                                    <name>0</name>
                                    <description>CRC error not detected</description>
                                    <value>#0</value>
                                </enumeratedValue>
                                <enumeratedValue>
                                    <name>1</name>
                                    <description>CRC error detected.</description>
                                    <value>#1</value>
                                </enumeratedValue>
                            </enumeratedValues>
                        </field>
                        <field>
                            <name>PRE</name>
                            <description>PHY-LSI Receive Error Flag</description>
                            <lsb>1</lsb>
                            <msb>1</msb>
                            <access>read-write</access>
                            <enumeratedValues>
                                <enumeratedValue>
                                    <name>0</name>
                                    <description>PHY-LSI receive error not detected</description>
                                    <value>#0</value>
                                </enumeratedValue>
                                <enumeratedValue>
                                    <name>1</name>
                                    <description>PHY-LSI receive error detected.</description>
                                    <value>#1</value>
                                </enumeratedValue>
                            </enumeratedValues>
                        </field>
                        <field>
                            <name>RTSF</name>
                            <description>Frame-Too-Short Error Flag</description>
                            <lsb>2</lsb>
                            <msb>2</msb>
                            <access>read-write</access>
                            <enumeratedValues>
                                <enumeratedValue>
                                    <name>0</name>
                                    <description>Frame-too-short error not detected</description>
                                    <value>#0</value>
                                </enumeratedValue>
                                <enumeratedValue>
                                    <name>1</name>
                                    <description>Frame-too-short error detected.</description>
                                    <value>#1</value>
                                </enumeratedValue>
                            </enumeratedValues>
                        </field>
                        <field>
                            <name>RTLF</name>
                            <description>Frame-Too-Long Error Flag</description>
                            <lsb>3</lsb>
                            <msb>3</msb>
                            <access>read-write</access>
                            <enumeratedValues>
                                <enumeratedValue>
                                    <name>0</name>
                                    <description>Frame-too-long error not detected</description>
                                    <value>#0</value>
                                </enumeratedValue>
                                <enumeratedValue>
                                    <name>1</name>
                                    <description>Frame-too-long error detected.</description>
                                    <value>#1</value>
                                </enumeratedValue>
                            </enumeratedValues>
                        </field>
                        <field>
                            <name>RRF</name>
                            <description>Alignment Error Flag</description>
                            <lsb>4</lsb>
                            <msb>4</msb>
                            <access>read-write</access>
                            <enumeratedValues>
                                <enumeratedValue>
                                    <name>0</name>
                                    <description>Alignment error not detected</description>
                                    <value>#0</value>
                                </enumeratedValue>
                                <enumeratedValue>
                                    <name>1</name>
                                    <description>Alignment error detected.</description>
                                    <value>#1</value>
                                </enumeratedValue>
                            </enumeratedValues>
                        </field>
                        <field>
                            <name>RMAF</name>
                            <description>Multicast Address Frame Receive Flag</description>
                            <lsb>7</lsb>
                            <msb>7</msb>
                            <access>read-write</access>
                            <enumeratedValues>
                                <enumeratedValue>
                                    <name>0</name>
                                    <description>Multicast address frame not received</description>
                                    <value>#0</value>
                                </enumeratedValue>
                                <enumeratedValue>
                                    <name>1</name>
                                    <description>Multicast address frame received.</description>
                                    <value>#1</value>
                                </enumeratedValue>
                            </enumeratedValues>
                        </field>
                        <field>
                            <name>TRO</name>
                            <description>Transmit Retry Over Flag</description>
                            <lsb>8</lsb>
                            <msb>8</msb>
                            <access>read-write</access>
                            <enumeratedValues>
                                <enumeratedValue>
                                    <name>0</name>
                                    <description>Transmit retry-over condition not detected</description>
                                    <value>#0</value>
                                </enumeratedValue>
                                <enumeratedValue>
                                    <name>1</name>
                                    <description>Transmit retry-over condition detected.</description>
                                    <value>#1</value>
                                </enumeratedValue>
                            </enumeratedValues>
                        </field>
                        <field>
                            <name>CD</name>
                            <description>Late Collision Detect Flag</description>
                            <lsb>9</lsb>
                            <msb>9</msb>
                            <access>read-write</access>
                            <enumeratedValues>
                                <enumeratedValue>
                                    <name>0</name>
                                    <description>Late collision not detected</description>
                                    <value>#0</value>
                                </enumeratedValue>
                                <enumeratedValue>
                                    <name>1</name>
                                    <description>Late collision detected during frame transmission.</description>
                                    <value>#1</value>
                                </enumeratedValue>
                            </enumeratedValues>
                        </field>
                        <field>
                            <name>DLC</name>
                            <description>Loss of Carrier Detect Flag</description>
                            <lsb>10</lsb>
                            <msb>10</msb>
                            <access>read-write</access>
                            <enumeratedValues>
                                <enumeratedValue>
                                    <name>0</name>
                                    <description>Loss of carrier not detected</description>
                                    <value>#0</value>
                                </enumeratedValue>
                                <enumeratedValue>
                                    <name>1</name>
                                    <description>Loss of carrier detected during frame transmission.</description>
                                    <value>#1</value>
                                </enumeratedValue>
                            </enumeratedValues>
                        </field>
                        <field>
                            <name>CND</name>
                            <description>Carrier Not Detect Flag</description>
                            <lsb>11</lsb>
                            <msb>11</msb>
                            <access>read-write</access>
                            <enumeratedValues>
                                <enumeratedValue>
                                    <name>0</name>
                                    <description>Carrier detected when transmission started</description>
                                    <value>#0</value>
                                </enumeratedValue>
                                <enumeratedValue>
                                    <name>1</name>
                                    <description>Carrier not detected during preamble transmission.</description>
                                    <value>#1</value>
                                </enumeratedValue>
                            </enumeratedValues>
                        </field>
                        <field>
                            <name>RFOF</name>
                            <description>Receive FIFO Overflow Flag</description>
                            <lsb>16</lsb>
                            <msb>16</msb>
                            <access>read-write</access>
                            <enumeratedValues>
                                <enumeratedValue>
                                    <name>0</name>
                                    <description>No overflow occurred</description>
                                    <value>#0</value>
                                </enumeratedValue>
                                <enumeratedValue>
                                    <name>1</name>
                                    <description>Overflow occurred.</description>
                                    <value>#1</value>
                                </enumeratedValue>
                            </enumeratedValues>
                        </field>
                        <field>
                            <name>RDE</name>
                            <description>Receive Descriptor Empty Flag</description>
                            <lsb>17</lsb>
                            <msb>17</msb>
                            <access>read-write</access>
                            <enumeratedValues>
                                <enumeratedValue>
                                    <name>0</name>
                                    <description>EDMAC detected that the receive descriptor valid bit (RD0.RACT) is 1 </description>
                                    <value>#0</value>
                                </enumeratedValue>
                                <enumeratedValue>
                                    <name>1</name>
                                    <description>EDMAC detected that the receive descriptor valid bit (RD0.RACT) is 0. </description>
                                    <value>#1</value>
                                </enumeratedValue>
                            </enumeratedValues>
                        </field>
                        <field>
                            <name>FR</name>
                            <description>Frame Receive Flag</description>
                            <lsb>18</lsb>
                            <msb>18</msb>
                            <access>read-write</access>
                            <enumeratedValues>
                                <enumeratedValue>
                                    <name>0</name>
                                    <description>Frame not received</description>
                                    <value>#0</value>
                                </enumeratedValue>
                                <enumeratedValue>
                                    <name>1</name>
                                    <description>Frame received and update of the receive descriptor is complete. </description>
                                    <value>#1</value>
                                </enumeratedValue>
                            </enumeratedValues>
                        </field>
                        <field>
                            <name>TFUF</name>
                            <description>Transmit FIFO Underflow Flag</description>
                            <lsb>19</lsb>
                            <msb>19</msb>
                            <access>read-write</access>
                            <enumeratedValues>
                                <enumeratedValue>
                                    <name>0</name>
                                    <description>No underflow occurred</description>
                                    <value>#0</value>
                                </enumeratedValue>
                                <enumeratedValue>
                                    <name>1</name>
                                    <description>Underflow occurred.</description>
                                    <value>#1</value>
                                </enumeratedValue>
                            </enumeratedValues>
                        </field>
                        <field>
                            <name>TDE</name>
                            <description>Transmit Descriptor Empty Flag</description>
                            <lsb>20</lsb>
                            <msb>20</msb>
                            <access>read-write</access>
                            <enumeratedValues>
                                <enumeratedValue>
                                    <name>0</name>
                                    <description>EDMAC detected that the transmit descriptor valid bit (TD0.TACT) is 1 </description>
                                    <value>#0</value>
                                </enumeratedValue>
                                <enumeratedValue>
                                    <name>1</name>
                                    <description>EDMAC detected that the transmit descriptor valid bit (TD0.TACT) is 0. </description>
                                    <value>#1</value>
                                </enumeratedValue>
                            </enumeratedValues>
                        </field>
                        <field>
                            <name>TC</name>
                            <description>Frame Transfer Complete Flag</description>
                            <lsb>21</lsb>
                            <msb>21</msb>
                            <access>read-write</access>
                            <enumeratedValues>
                                <enumeratedValue>
                                    <name>0</name>
                                    <description>Transfer not complete or no transfer requested</description>
                                    <value>#0</value>
                                </enumeratedValue>
                                <enumeratedValue>
                                    <name>1</name>
                                    <description>All frames indicated in the transmit descriptor were completely transferred to the transmit FIFO. </description>
                                    <value>#1</value>
                                </enumeratedValue>
                            </enumeratedValues>
                        </field>
                        <field>
                            <name>ECI</name>
                            <description>ETHERC Status Register Source Flag</description>
                            <lsb>22</lsb>
                            <msb>22</msb>
                            <access>read-only</access>
                            <enumeratedValues>
                                <enumeratedValue>
                                    <name>0</name>
                                    <description>ETHERC status interrupt source not detected</description>
                                    <value>#0</value>
                                </enumeratedValue>
                                <enumeratedValue>
                                    <name>1</name>
                                    <description>ETHERC status interrupt source detected.</description>
                                    <value>#1</value>
                                </enumeratedValue>
                            </enumeratedValues>
                        </field>
                        <field>
                            <name>ADE</name>
                            <description>Address Error Flag</description>
                            <lsb>23</lsb>
                            <msb>23</msb>
                            <access>read-write</access>
                            <enumeratedValues>
                                <enumeratedValue>
                                    <name>0</name>
                                    <description>Invalid memory address not detected (normal operation)</description>
                                    <value>#0</value>
                                </enumeratedValue>
                                <enumeratedValue>
                                    <name>1</name>
                                    <description>Invalid memory address detected.</description>
                                    <value>#1</value>
                                </enumeratedValue>
                            </enumeratedValues>
                        </field>
                        <field>
                            <name>RFCOF</name>
                            <description>Receive Frame Counter Overflow Flag</description>
                            <lsb>24</lsb>
                            <msb>24</msb>
                            <access>read-write</access>
                            <enumeratedValues>
                                <enumeratedValue>
                                    <name>0</name>
                                    <description>Receive frame counter did not overflow</description>
                                    <value>#0</value>
                                </enumeratedValue>
                                <enumeratedValue>
                                    <name>1</name>
                                    <description>Receive frame counter overflowed.</description>
                                    <value>#1</value>
                                </enumeratedValue>
                            </enumeratedValues>
                        </field>
                        <field>
                            <name>RABT</name>
                            <description>Receive Abort Detect Flag</description>
                            <lsb>25</lsb>
                            <msb>25</msb>
                            <access>read-write</access>
                            <enumeratedValues>
                                <enumeratedValue>
                                    <name>0</name>
                                    <description>Frame reception not aborted or no reception requested</description>
                                    <value>#0</value>
                                </enumeratedValue>
                                <enumeratedValue>
                                    <name>1</name>
                                    <description>Frame reception aborted.</description>
                                    <value>#1</value>
                                </enumeratedValue>
                            </enumeratedValues>
                        </field>
                        <field>
                            <name>TABT</name>
                            <description>Transmit Abort Detect Flag</description>
                            <lsb>26</lsb>
                            <msb>26</msb>
                            <access>read-write</access>
                            <enumeratedValues>
                                <enumeratedValue>
                                    <name>0</name>
                                    <description>Frame transmission not aborted or no transmission requested. </description>
                                    <value>#0</value>
                                </enumeratedValue>
                                <enumeratedValue>
                                    <name>1</name>
                                    <description>Frame transmission aborted.</description>
                                    <value>#1</value>
                                </enumeratedValue>
                            </enumeratedValues>
                        </field>
                        <field>
                            <name>TWB</name>
                            <description>Write-Back Complete Flag</description>
                            <lsb>30</lsb>
                            <msb>30</msb>
                            <access>read-write</access>
                            <enumeratedValues>
                                <enumeratedValue>
                                    <name>0</name>
                                    <description>Write-back not complete or no transmission requested</description>
                                    <value>#0</value>
                                </enumeratedValue>
                                <enumeratedValue>
                                    <name>1</name>
                                    <description>Write-back to the transmit descriptor completed.</description>
                                    <value>#1</value>
                                </enumeratedValue>
                            </enumeratedValues>
                        </field>
                    </fields>
                </register>
                <register>
                    <name>EESIPR</name>
                    <description>ETHERC/EDMAC Status Interrupt Enable Register</description>
                    <addressOffset>0x30</addressOffset>
                    <size>32</size>
                    <access>read-write</access>
                    <resetValue>0x00000000</resetValue>
                    <resetMask>0xffffffff</resetMask>
                    <fields>
                        <field>
                            <name>CERFIP</name>
                            <description>CRC Error Interrupt Request Enable</description>
                            <lsb>0</lsb>
                            <msb>0</msb>
                            <access>read-write</access>
                            <enumeratedValues>
                                <enumeratedValue>
                                    <name>0</name>
                                    <description>Disable CRC error interrupt requests</description>
                                    <value>#0</value>
                                </enumeratedValue>
                                <enumeratedValue>
                                    <name>1</name>
                                    <description>Enable CRC error interrupt requests.</description>
                                    <value>#1</value>
                                </enumeratedValue>
                            </enumeratedValues>
                        </field>
                        <field>
                            <name>PREIP</name>
                            <description>PHY-LSI Receive Error Interrupt Request Enable</description>
                            <lsb>1</lsb>
                            <msb>1</msb>
                            <access>read-write</access>
                            <enumeratedValues>
                                <enumeratedValue>
                                    <name>0</name>
                                    <description>Disable PHY-LSI receive error interrupt requests</description>
                                    <value>#0</value>
                                </enumeratedValue>
                                <enumeratedValue>
                                    <name>1</name>
                                    <description>Enable PHY-LSI receive error interrupt requests.</description>
                                    <value>#1</value>
                                </enumeratedValue>
                            </enumeratedValues>
                        </field>
                        <field>
                            <name>RTSFIP</name>
                            <description>Frame-Too-Short Error Interrupt Request Enable</description>
                            <lsb>2</lsb>
                            <msb>2</msb>
                            <access>read-write</access>
                            <enumeratedValues>
                                <enumeratedValue>
                                    <name>0</name>
                                    <description>Disable frame-too-short error interrupt requests</description>
                                    <value>#0</value>
                                </enumeratedValue>
                                <enumeratedValue>
                                    <name>1</name>
                                    <description>Enable frame-too-short error interrupt requests.</description>
                                    <value>#1</value>
                                </enumeratedValue>
                            </enumeratedValues>
                        </field>
                        <field>
                            <name>RTLFIP</name>
                            <description>Frame-Too-Long Error Interrupt Request Enable</description>
                            <lsb>3</lsb>
                            <msb>3</msb>
                            <access>read-write</access>
                            <enumeratedValues>
                                <enumeratedValue>
                                    <name>0</name>
                                    <description>Disable frame-too-long error interrupt requests</description>
                                    <value>#0</value>
                                </enumeratedValue>
                                <enumeratedValue>
                                    <name>1</name>
                                    <description>Enable frame-too-long error interrupt requests.</description>
                                    <value>#1</value>
                                </enumeratedValue>
                            </enumeratedValues>
                        </field>
                        <field>
                            <name>RRFIP</name>
                            <description>Alignment Error Interrupt Request Enable</description>
                            <lsb>4</lsb>
                            <msb>4</msb>
                            <access>read-write</access>
                            <enumeratedValues>
                                <enumeratedValue>
                                    <name>0</name>
                                    <description>Disable alignment error interrupt requests</description>
                                    <value>#0</value>
                                </enumeratedValue>
                                <enumeratedValue>
                                    <name>1</name>
                                    <description>Enable alignment error interrupt requests.</description>
                                    <value>#1</value>
                                </enumeratedValue>
                            </enumeratedValues>
                        </field>
                        <field>
                            <name>RMAFIP</name>
                            <description>Multicast Address Frame Receive Interrupt Request Enable</description>
                            <lsb>7</lsb>
                            <msb>7</msb>
                            <access>read-write</access>
                            <enumeratedValues>
                                <enumeratedValue>
                                    <name>0</name>
                                    <description>Disable multicast address frame receive interrupt requests </description>
                                    <value>#0</value>
                                </enumeratedValue>
                                <enumeratedValue>
                                    <name>1</name>
                                    <description>Enable multicast address frame receive interrupt requests. </description>
                                    <value>#1</value>
                                </enumeratedValue>
                            </enumeratedValues>
                        </field>
                        <field>
                            <name>TROIP</name>
                            <description>Transmit Retry Over Interrupt Request Enable</description>
                            <lsb>8</lsb>
                            <msb>8</msb>
                            <access>read-write</access>
                            <enumeratedValues>
                                <enumeratedValue>
                                    <name>0</name>
                                    <description>Disable transmit retry over interrupt requests</description>
                                    <value>#0</value>
                                </enumeratedValue>
                                <enumeratedValue>
                                    <name>1</name>
                                    <description>Enable transmit retry over interrupt requests.</description>
                                    <value>#1</value>
                                </enumeratedValue>
                            </enumeratedValues>
                        </field>
                        <field>
                            <name>CDIP</name>
                            <description>Late Collision Detect Interrupt Request Enable</description>
                            <lsb>9</lsb>
                            <msb>9</msb>
                            <access>read-write</access>
                            <enumeratedValues>
                                <enumeratedValue>
                                    <name>0</name>
                                    <description>Disable late collision detected interrupt requests</description>
                                    <value>#0</value>
                                </enumeratedValue>
                                <enumeratedValue>
                                    <name>1</name>
                                    <description>Enable late collision detected interrupt requests.</description>
                                    <value>#1</value>
                                </enumeratedValue>
                            </enumeratedValues>
                        </field>
                        <field>
                            <name>DLCIP</name>
                            <description>Loss of Carrier Detect Interrupt Request Enable</description>
                            <lsb>10</lsb>
                            <msb>10</msb>
                            <access>read-write</access>
                            <enumeratedValues>
                                <enumeratedValue>
                                    <name>0</name>
                                    <description>Disable loss of carrier detected interrupt requests</description>
                                    <value>#0</value>
                                </enumeratedValue>
                                <enumeratedValue>
                                    <name>1</name>
                                    <description>Enable loss of carrier detected interrupt requests.</description>
                                    <value>#1</value>
                                </enumeratedValue>
                            </enumeratedValues>
                        </field>
                        <field>
                            <name>CNDIP</name>
                            <description>Carrier Not Detect Interrupt Request Enable</description>
                            <lsb>11</lsb>
                            <msb>11</msb>
                            <access>read-write</access>
                            <enumeratedValues>
                                <enumeratedValue>
                                    <name>0</name>
                                    <description>Disable carrier not detected interrupt requests</description>
                                    <value>#0</value>
                                </enumeratedValue>
                                <enumeratedValue>
                                    <name>1</name>
                                    <description>Enable carrier not detected interrupt requests.</description>
                                    <value>#1</value>
                                </enumeratedValue>
                            </enumeratedValues>
                        </field>
                        <field>
                            <name>RFOFIP</name>
                            <description>Receive FIFO Overflow Interrupt Request Enable</description>
                            <lsb>16</lsb>
                            <msb>16</msb>
                            <access>read-write</access>
                            <enumeratedValues>
                                <enumeratedValue>
                                    <name>0</name>
                                    <description>Disable overflow interrupt requests</description>
                                    <value>#0</value>
                                </enumeratedValue>
                                <enumeratedValue>
                                    <name>1</name>
                                    <description>Enable overflow interrupt requests.</description>
                                    <value>#1</value>
                                </enumeratedValue>
                            </enumeratedValues>
                        </field>
                        <field>
                            <name>RDEIP</name>
                            <description>Receive Descriptor Empty Interrupt Request Enable</description>
                            <lsb>17</lsb>
                            <msb>17</msb>
                            <access>read-write</access>
                            <enumeratedValues>
                                <enumeratedValue>
                                    <name>0</name>
                                    <description>Disable receive descriptor empty interrupt requests</description>
                                    <value>#0</value>
                                </enumeratedValue>
                                <enumeratedValue>
                                    <name>1</name>
                                    <description>Enable receive descriptor empty interrupt requests.</description>
                                    <value>#1</value>
                                </enumeratedValue>
                            </enumeratedValues>
                        </field>
                        <field>
                            <name>FRIP</name>
                            <description>Frame Receive Interrupt Request Enable</description>
                            <lsb>18</lsb>
                            <msb>18</msb>
                            <access>read-write</access>
                            <enumeratedValues>
                                <enumeratedValue>
                                    <name>0</name>
                                    <description>Disable frame reception interrupt requests</description>
                                    <value>#0</value>
                                </enumeratedValue>
                                <enumeratedValue>
                                    <name>1</name>
                                    <description>Enable frame reception interrupt requests.</description>
                                    <value>#1</value>
                                </enumeratedValue>
                            </enumeratedValues>
                        </field>
                        <field>
                            <name>TFUFIP</name>
                            <description>Transmit FIFO Underflow Interrupt Request Enable</description>
                            <lsb>19</lsb>
                            <msb>19</msb>
                            <access>read-write</access>
                            <enumeratedValues>
                                <enumeratedValue>
                                    <name>0</name>
                                    <description>Disable underflow interrupt requests</description>
                                    <value>#0</value>
                                </enumeratedValue>
                                <enumeratedValue>
                                    <name>1</name>
                                    <description>Enable underflow interrupt requests.</description>
                                    <value>#1</value>
                                </enumeratedValue>
                            </enumeratedValues>
                        </field>
                        <field>
                            <name>TDEIP</name>
                            <description>Transmit Descriptor Empty Interrupt Request Enable</description>
                            <lsb>20</lsb>
                            <msb>20</msb>
                            <access>read-write</access>
                            <enumeratedValues>
                                <enumeratedValue>
                                    <name>0</name>
                                    <description>Disable transmit descriptor empty interrupt requests</description>
                                    <value>#0</value>
                                </enumeratedValue>
                                <enumeratedValue>
                                    <name>1</name>
                                    <description>Enable transmit descriptor empty interrupt requests.</description>
                                    <value>#1</value>
                                </enumeratedValue>
                            </enumeratedValues>
                        </field>
                        <field>
                            <name>TCIP</name>
                            <description>Frame Transfer Complete Interrupt Request Enable</description>
                            <lsb>21</lsb>
                            <msb>21</msb>
                            <access>read-write</access>
                            <enumeratedValues>
                                <enumeratedValue>
                                    <name>0</name>
                                    <description>Disable frame transmission complete interrupt requests </description>
                                    <value>#0</value>
                                </enumeratedValue>
                                <enumeratedValue>
                                    <name>1</name>
                                    <description>Enable frame transmission complete interrupt requests. </description>
                                    <value>#1</value>
                                </enumeratedValue>
                            </enumeratedValues>
                        </field>
                        <field>
                            <name>ECIIP</name>
                            <description>ETHERC Status Register Source Interrupt Request Enable</description>
                            <lsb>22</lsb>
                            <msb>22</msb>
                            <access>read-write</access>
                            <enumeratedValues>
                                <enumeratedValue>
                                    <name>0</name>
                                    <description>Disable ETHERC status interrupt requests</description>
                                    <value>#0</value>
                                </enumeratedValue>
                                <enumeratedValue>
                                    <name>1</name>
                                    <description>Enable ETHERC status interrupt requests.</description>
                                    <value>#1</value>
                                </enumeratedValue>
                            </enumeratedValues>
                        </field>
                        <field>
                            <name>ADEIP</name>
                            <description>Address Error Interrupt Request Enable</description>
                            <lsb>23</lsb>
                            <msb>23</msb>
                            <access>read-write</access>
                            <enumeratedValues>
                                <enumeratedValue>
                                    <name>0</name>
                                    <description>Disable address error interrupt requests</description>
                                    <value>#0</value>
                                </enumeratedValue>
                                <enumeratedValue>
                                    <name>1</name>
                                    <description>Enable address error interrupt requests.</description>
                                    <value>#1</value>
                                </enumeratedValue>
                            </enumeratedValues>
                        </field>
                        <field>
                            <name>RFCOFIP</name>
                            <description>Receive Frame Counter Overflow Interrupt Request Enable</description>
                            <lsb>24</lsb>
                            <msb>24</msb>
                            <access>read-write</access>
                            <enumeratedValues>
                                <enumeratedValue>
                                    <name>0</name>
                                    <description>Disable receive frame counter overflow interrupt requests </description>
                                    <value>#0</value>
                                </enumeratedValue>
                                <enumeratedValue>
                                    <name>1</name>
                                    <description>Enable receive frame counter overflow interrupt requests. </description>
                                    <value>#1</value>
                                </enumeratedValue>
                            </enumeratedValues>
                        </field>
                        <field>
                            <name>RABTIP</name>
                            <description>Receive Abort Detect Interrupt Request Enable</description>
                            <lsb>25</lsb>
                            <msb>25</msb>
                            <access>read-write</access>
                            <enumeratedValues>
                                <enumeratedValue>
                                    <name>0</name>
                                    <description>Disable receive abort detected interrupt requests</description>
                                    <value>#0</value>
                                </enumeratedValue>
                                <enumeratedValue>
                                    <name>1</name>
                                    <description>Enable receive abort detected interrupt requests.</description>
                                    <value>#1</value>
                                </enumeratedValue>
                            </enumeratedValues>
                        </field>
                        <field>
                            <name>TABTIP</name>
                            <description>Transmit Abort Detect Interrupt Request Enable</description>
                            <lsb>26</lsb>
                            <msb>26</msb>
                            <access>read-write</access>
                            <enumeratedValues>
                                <enumeratedValue>
                                    <name>0</name>
                                    <description>Disable transmit abort detected interrupt requests</description>
                                    <value>#0</value>
                                </enumeratedValue>
                                <enumeratedValue>
                                    <name>1</name>
                                    <description>Enable transmit abort detected interrupt requests.</description>
                                    <value>#1</value>
                                </enumeratedValue>
                            </enumeratedValues>
                        </field>
                        <field>
                            <name>TWBIP</name>
                            <description>Write-Back Complete Interrupt Request Enable</description>
                            <lsb>30</lsb>
                            <msb>30</msb>
                            <access>read-write</access>
                            <enumeratedValues>
                                <enumeratedValue>
                                    <name>0</name>
                                    <description>Disable write-back complete interrupt requests</description>
                                    <value>#0</value>
                                </enumeratedValue>
                                <enumeratedValue>
                                    <name>1</name>
                                    <description>Enable write-back complete interrupt requests.</description>
                                    <value>#1</value>
                                </enumeratedValue>
                            </enumeratedValues>
                        </field>
                    </fields>
                </register>
                <register>
                    <name>TRSCER</name>
                    <description>ETHERC/EDMAC Transmit/Receive Status Copy Enable Register</description>
                    <addressOffset>0x38</addressOffset>
                    <size>32</size>
                    <access>read-write</access>
                    <resetValue>0x00000000</resetValue>
                    <resetMask>0xffffffff</resetMask>
                    <fields>
                        <field>
                            <name>RRFCE</name>
                            <description>RRF Flag Copy Enable</description>
                            <lsb>4</lsb>
                            <msb>4</msb>
                            <access>read-write</access>
                            <enumeratedValues>
                                <enumeratedValue>
                                    <name>0</name>
                                    <description>Reflect the EESR.RRF flag status in the RD0.RFE bit of the receive descriptor </description>
                                    <value>#0</value>
                                </enumeratedValue>
                                <enumeratedValue>
                                    <name>1</name>
                                    <description>Do not reflect the EESR.RRF flag status in the RD0.RFE bit of the receive descriptor. </description>
                                    <value>#1</value>
                                </enumeratedValue>
                            </enumeratedValues>
                        </field>
                        <field>
                            <name>RMAFCE</name>
                            <description>RMAF Flag Copy Enable</description>
                            <lsb>7</lsb>
                            <msb>7</msb>
                            <access>read-write</access>
                            <enumeratedValues>
                                <enumeratedValue>
                                    <name>0</name>
                                    <description>Reflect the EESR.RMAF flag status in the RD0.RFE bit of the receive descriptor </description>
                                    <value>#0</value>
                                </enumeratedValue>
                                <enumeratedValue>
                                    <name>1</name>
                                    <description>Do not reflect the EESR.RMAF flag status in the RD0.RFE bit of the receive descriptor. </description>
                                    <value>#1</value>
                                </enumeratedValue>
                            </enumeratedValues>
                        </field>
                    </fields>
                </register>
                <register>
                    <name>RMFCR</name>
                    <description>Missed-Frame Counter Register</description>
                    <addressOffset>0x40</addressOffset>
                    <size>32</size>
                    <access>read-write</access>
                    <resetValue>0x00000000</resetValue>
                    <resetMask>0xffffffff</resetMask>
                    <fields>
                        <field>
                            <name>MFC</name>
                            <description>Missed-Frame Counter</description>
                            <lsb>0</lsb>
                            <msb>15</msb>
                            <access>read-write</access>
                        </field>
                    </fields>
                </register>
                <register>
                    <name>TFTR</name>
                    <description>Transmit FIFO Threshold Register</description>
                    <addressOffset>0x48</addressOffset>
                    <size>32</size>
                    <access>read-write</access>
                    <resetValue>0x00000000</resetValue>
                    <resetMask>0xffffffff</resetMask>
                    <fields>
                        <field>
                            <name>TFT</name>
                            <description>Transmit FIFO Threshold</description>
                            <lsb>0</lsb>
                            <msb>10</msb>
                            <access>read-write</access>
                        </field>
                    </fields>
                </register>
                <register>
                    <name>FDR</name>
                    <description>FIFO Depth Register</description>
                    <addressOffset>0x50</addressOffset>
                    <size>32</size>
                    <access>read-write</access>
                    <resetValue>0x00000000</resetValue>
                    <resetMask>0xffffffff</resetMask>
                    <fields>
                        <field>
                            <name>RFD</name>
                            <description>Receive FIFO Depth</description>
                            <lsb>0</lsb>
                            <msb>4</msb>
                            <access>read-write</access>
                            <enumeratedValues>
                                <enumeratedValue>
                                    <name>0x0F</name>
                                    <description>4096 bytes</description>
                                    <value>0x0f</value>
                                </enumeratedValue>
                                <enumeratedValue>
                                    <name>Others</name>
                                    <description>settings prohibited</description>
                                    <isDefault>true</isDefault>
                                </enumeratedValue>
                            </enumeratedValues>
                        </field>
                        <field>
                            <name>TFD</name>
                            <description>Transmit FIFO Depth</description>
                            <lsb>8</lsb>
                            <msb>12</msb>
                            <access>read-write</access>
                            <enumeratedValues>
                                <enumeratedValue>
                                    <name>0x07</name>
                                    <description>2048 bytes</description>
                                    <value>0x07</value>
                                </enumeratedValue>
                                <enumeratedValue>
                                    <name>Others</name>
                                    <description>settings prohibited</description>
                                    <isDefault>true</isDefault>
                                </enumeratedValue>
                            </enumeratedValues>
                        </field>
                    </fields>
                </register>
                <register>
                    <name>RMCR</name>
                    <description>Receive Method Control Register</description>
                    <addressOffset>0x58</addressOffset>
                    <size>32</size>
                    <access>read-write</access>
                    <resetValue>0x00000000</resetValue>
                    <resetMask>0xffffffff</resetMask>
                    <fields>
                        <field>
                            <name>RNR</name>
                            <description>Receive Request Reset</description>
                            <lsb>0</lsb>
                            <msb>0</msb>
                            <access>read-write</access>
                            <enumeratedValues>
                                <enumeratedValue>
                                    <name>0</name>
                                    <description>EDRRR.RR bit (receive request bit) is cleared to 0 when one frame is received </description>
                                    <value>#0</value>
                                </enumeratedValue>
                                <enumeratedValue>
                                    <name>1</name>
                                    <description>EDRRR.RR bit (receive request bit) is not cleared to 0 when one frame is received. </description>
                                    <value>#1</value>
                                </enumeratedValue>
                            </enumeratedValues>
                        </field>
                    </fields>
                </register>
                <register>
                    <name>TFUCR</name>
                    <description>Transmit FIFO Underflow Counter</description>
                    <addressOffset>0x64</addressOffset>
                    <size>32</size>
                    <access>read-write</access>
                    <resetValue>0x00000000</resetValue>
                    <resetMask>0xffffffff</resetMask>
                    <fields>
                        <field>
                            <name>UNDER</name>
                            <description>Transmit FIFO Underflow Count</description>
                            <lsb>0</lsb>
                            <msb>15</msb>
                            <access>read-write</access>
                        </field>
                    </fields>
                </register>
                <register>
                    <name>RFOCR</name>
                    <description>Receive FIFO Overflow Counter</description>
                    <addressOffset>0x68</addressOffset>
                    <size>32</size>
                    <access>read-write</access>
                    <resetValue>0x00000000</resetValue>
                    <resetMask>0xffffffff</resetMask>
                    <fields>
                        <field>
                            <name>OVER</name>
                            <description>Receive FIFO Overflow Count</description>
                            <lsb>0</lsb>
                            <msb>15</msb>
                            <access>read-write</access>
                        </field>
                    </fields>
                </register>
                <register>
                    <name>IOSR</name>
                    <description>Independent Output Signal Setting Register</description>
                    <addressOffset>0x6C</addressOffset>
                    <size>32</size>
                    <access>read-write</access>
                    <resetValue>0x00000000</resetValue>
                    <resetMask>0xffffffff</resetMask>
                    <fields>
                        <field>
                            <name>ELB</name>
                            <description>External Loopback Mode</description>
                            <lsb>0</lsb>
                            <msb>0</msb>
                            <access>read-write</access>
                            <enumeratedValues>
                                <enumeratedValue>
                                    <name>0</name>
                                    <description>Output low on the ET0_EXOUT pin</description>
                                    <value>#0</value>
                                </enumeratedValue>
                                <enumeratedValue>
                                    <name>1</name>
                                    <description>Output high on the ET0_EXOUT pin.</description>
                                    <value>#1</value>
                                </enumeratedValue>
                            </enumeratedValues>
                        </field>
                    </fields>
                </register>
                <register>
                    <name>FCFTR</name>
                    <description>Flow Control Start FIFO Threshold Setting Register</description>
                    <addressOffset>0x70</addressOffset>
                    <size>32</size>
                    <access>read-write</access>
                    <resetValue>0x00070007</resetValue>
                    <resetMask>0xffffffff</resetMask>
                    <fields>
                        <field>
                            <name>RFDO</name>
                            <description>Receive FIFO Data PAUSE Output Threshold</description>
                            <lsb>0</lsb>
                            <msb>2</msb>
                            <access>read-write</access>
                        </field>
                        <field>
                            <name>RFFO</name>
                            <description>Receive FIFO Frame PAUSE Output Threshold</description>
                            <lsb>16</lsb>
                            <msb>18</msb>
                            <access>read-write</access>
                        </field>
                    </fields>
                </register>
                <register>
                    <name>RPADIR</name>
                    <description>Receive Data Padding Insert Register</description>
                    <addressOffset>0x78</addressOffset>
                    <size>32</size>
                    <access>read-write</access>
                    <resetValue>0x00000000</resetValue>
                    <resetMask>0xffffffff</resetMask>
                    <fields>
                        <field>
                            <name>PADR</name>
                            <description>Padding Slot</description>
                            <lsb>0</lsb>
                            <msb>5</msb>
                            <access>read-write</access>
                        </field>
                        <field>
                            <name>PADS</name>
                            <description>Padding Size</description>
                            <lsb>16</lsb>
                            <msb>17</msb>
                            <access>read-write</access>
                            <enumeratedValues>
                                <enumeratedValue>
                                    <name>00</name>
                                    <description>Do not insert padding</description>
                                    <value>#00</value>
                                </enumeratedValue>
                                <enumeratedValue>
                                    <name>Others</name>
                                    <description>settings prohibited</description>
                                    <isDefault>true</isDefault>
                                </enumeratedValue>
                            </enumeratedValues>
                        </field>
                    </fields>
                </register>
                <register>
                    <name>TRIMD</name>
                    <description>Transmit Interrupt Setting Register</description>
                    <addressOffset>0x7C</addressOffset>
                    <size>32</size>
                    <access>read-write</access>
                    <resetValue>0x00000000</resetValue>
                    <resetMask>0xffffffff</resetMask>
                    <fields>
                        <field>
                            <name>TIS</name>
                            <description>Transmit Interrupt Enable</description>
                            <lsb>0</lsb>
                            <msb>0</msb>
                            <access>read-write</access>
                            <enumeratedValues>
                                <enumeratedValue>
                                    <name>0</name>
                                    <description>Disable transmit interrupts</description>
                                    <value>#0</value>
                                </enumeratedValue>
                                <enumeratedValue>
                                    <name>1</name>
                                    <description>Enable transmit Interrupts.</description>
                                    <value>#1</value>
                                </enumeratedValue>
                            </enumeratedValues>
                        </field>
                        <field>
                            <name>TIM</name>
                            <description>Transmit Interrupt Mode</description>
                            <lsb>4</lsb>
                            <msb>4</msb>
                            <access>read-write</access>
                            <enumeratedValues>
                                <enumeratedValue>
                                    <name>0</name>
                                    <description>Select transmission complete interrupt mode, where an interrupt occurs when a frame is transmitted </description>
                                    <value>#0</value>
                                </enumeratedValue>
                                <enumeratedValue>
                                    <name>1</name>
                                    <description>Select write-back complete interrupt mode, where an interrupt occurs when write-back to the transmit descriptor is complete while the TWBI bit is 1. </description>
                                    <value>#1</value>
                                </enumeratedValue>
                            </enumeratedValues>
                        </field>
                    </fields>
                </register>
                <register>
                    <name>RBWAR</name>
                    <description>Receive Buffer Write Address Register</description>
                    <addressOffset>0xC8</addressOffset>
                    <size>32</size>
                    <access>read-only</access>
                    <resetValue>0x00000000</resetValue>
                    <resetMask>0xffffffff</resetMask>
                </register>
                <register>
                    <name>RDFAR</name>
                    <description>Receive Descriptor Fetch Address Register</description>
                    <addressOffset>0xCC</addressOffset>
                    <size>32</size>
                    <access>read-only</access>
                    <resetValue>0x00000000</resetValue>
                    <resetMask>0xffffffff</resetMask>
                </register>
                <register>
                    <name>TBRAR</name>
                    <description>Transmit Buffer Read Address Register</description>
                    <addressOffset>0xD4</addressOffset>
                    <size>32</size>
                    <access>read-only</access>
                    <resetValue>0x00000000</resetValue>
                    <resetMask>0xffffffff</resetMask>
                </register>
                <register>
                    <name>TDFAR</name>
                    <description>Transmit Descriptor Fetch Address Register</description>
                    <addressOffset>0xD8</addressOffset>
                    <size>32</size>
                    <access>read-only</access>
                    <resetValue>0x00000000</resetValue>
                    <resetMask>0xffffffff</resetMask>
                </register>
            </registers>
        </peripheral>
        <peripheral>
            <name>ETHERC0_NS</name>
            <description>Ethernet Controller Channel 0</description>
            <baseAddress>0x50354100</baseAddress>
            <addressBlock>
                <offset>0x00</offset>
                <size>4</size>
                <usage>registers</usage>
            </addressBlock>
            <addressBlock>
                <offset>0x08</offset>
                <size>4</size>
                <usage>registers</usage>
            </addressBlock>
            <addressBlock>
                <offset>0x10</offset>
                <size>4</size>
                <usage>registers</usage>
            </addressBlock>
            <addressBlock>
                <offset>0x18</offset>
                <size>4</size>
                <usage>registers</usage>
            </addressBlock>
            <addressBlock>
                <offset>0x20</offset>
                <size>4</size>
                <usage>registers</usage>
            </addressBlock>
            <addressBlock>
                <offset>0x28</offset>
                <size>4</size>
                <usage>registers</usage>
            </addressBlock>
            <addressBlock>
                <offset>0x40</offset>
                <size>4</size>
                <usage>registers</usage>
            </addressBlock>
            <addressBlock>
                <offset>0x50</offset>
                <size>12</size>
                <usage>registers</usage>
            </addressBlock>
            <addressBlock>
                <offset>0x60</offset>
                <size>16</size>
                <usage>registers</usage>
            </addressBlock>
            <addressBlock>
                <offset>0xC0</offset>
                <size>4</size>
                <usage>registers</usage>
            </addressBlock>
            <addressBlock>
                <offset>0xC8</offset>
                <size>4</size>
                <usage>registers</usage>
            </addressBlock>
            <addressBlock>
                <offset>0xD0</offset>
                <size>16</size>
                <usage>registers</usage>
            </addressBlock>
            <addressBlock>
                <offset>0xE4</offset>
                <size>24</size>
                <usage>registers</usage>
            </addressBlock>
            <registers>
                <register>
                    <name>ECMR</name>
                    <description>ETHERC Mode Register</description>
                    <addressOffset>0x00</addressOffset>
                    <size>32</size>
                    <access>read-write</access>
                    <resetValue>0x00000000</resetValue>
                    <resetMask>0xffffffff</resetMask>
                    <fields>
                        <field>
                            <name>PRM</name>
                            <description>Promiscuous Mode</description>
                            <lsb>0</lsb>
                            <msb>0</msb>
                            <access>read-write</access>
                            <enumeratedValues>
                                <enumeratedValue>
                                    <name>0</name>
                                    <description>Disable promiscuous mode</description>
                                    <value>#0</value>
                                </enumeratedValue>
                                <enumeratedValue>
                                    <name>1</name>
                                    <description>Enable promiscuous mode.</description>
                                    <value>#1</value>
                                </enumeratedValue>
                            </enumeratedValues>
                        </field>
                        <field>
                            <name>DM</name>
                            <description>Duplex Mode</description>
                            <lsb>1</lsb>
                            <msb>1</msb>
                            <access>read-write</access>
                            <enumeratedValues>
                                <enumeratedValue>
                                    <name>0</name>
                                    <description>Half-duplex mode</description>
                                    <value>#0</value>
                                </enumeratedValue>
                                <enumeratedValue>
                                    <name>1</name>
                                    <description>Full-duplex mode.</description>
                                    <value>#1</value>
                                </enumeratedValue>
                            </enumeratedValues>
                        </field>
                        <field>
                            <name>RTM</name>
                            <description>Bit Rate</description>
                            <lsb>2</lsb>
                            <msb>2</msb>
                            <access>read-write</access>
                            <enumeratedValues>
                                <enumeratedValue>
                                    <name>0</name>
                                    <description>10 Mbps</description>
                                    <value>#0</value>
                                </enumeratedValue>
                                <enumeratedValue>
                                    <name>1</name>
                                    <description>100 Mbps.</description>
                                    <value>#1</value>
                                </enumeratedValue>
                            </enumeratedValues>
                        </field>
                        <field>
                            <name>ILB</name>
                            <description>Internal Loopback Mode</description>
                            <lsb>3</lsb>
                            <msb>3</msb>
                            <access>read-write</access>
                            <enumeratedValues>
                                <enumeratedValue>
                                    <name>0</name>
                                    <description>Perform normal data transmission or reception</description>
                                    <value>#0</value>
                                </enumeratedValue>
                                <enumeratedValue>
                                    <name>1</name>
                                    <description>Loop data back in the ETHERC when full-duplex mode is selected.</description>
                                    <value>#1</value>
                                </enumeratedValue>
                            </enumeratedValues>
                        </field>
                        <field>
                            <name>TE</name>
                            <description>Transmission Enable</description>
                            <lsb>5</lsb>
                            <msb>5</msb>
                            <access>read-write</access>
                            <enumeratedValues>
                                <enumeratedValue>
                                    <name>0</name>
                                    <description>Disable transmit function</description>
                                    <value>#0</value>
                                </enumeratedValue>
                                <enumeratedValue>
                                    <name>1</name>
                                    <description>Enable transmit function.</description>
                                    <value>#1</value>
                                </enumeratedValue>
                            </enumeratedValues>
                        </field>
                        <field>
                            <name>RE</name>
                            <description>Reception Enable</description>
                            <lsb>6</lsb>
                            <msb>6</msb>
                            <access>read-write</access>
                            <enumeratedValues>
                                <enumeratedValue>
                                    <name>0</name>
                                    <description>Disable receive function</description>
                                    <value>#0</value>
                                </enumeratedValue>
                                <enumeratedValue>
                                    <name>1</name>
                                    <description>Enable receive function.</description>
                                    <value>#1</value>
                                </enumeratedValue>
                            </enumeratedValues>
                        </field>
                        <field>
                            <name>MPDE</name>
                            <description>Magic Packet Detection Enable</description>
                            <lsb>9</lsb>
                            <msb>9</msb>
                            <access>read-write</access>
                            <enumeratedValues>
                                <enumeratedValue>
                                    <name>0</name>
                                    <description>Disable Magic Packet detection</description>
                                    <value>#0</value>
                                </enumeratedValue>
                                <enumeratedValue>
                                    <name>1</name>
                                    <description>Enable Magic Packet detection.</description>
                                    <value>#1</value>
                                </enumeratedValue>
                            </enumeratedValues>
                        </field>
                        <field>
                            <name>PRCEF</name>
                            <description>CRC Error Frame Receive Mode</description>
                            <lsb>12</lsb>
                            <msb>12</msb>
                            <access>read-write</access>
                            <enumeratedValues>
                                <enumeratedValue>
                                    <name>0</name>
                                    <description>Notify EDMAC of a CRC error</description>
                                    <value>#0</value>
                                </enumeratedValue>
                                <enumeratedValue>
                                    <name>1</name>
                                    <description>Do not notify EDMAC of a CRC error.</description>
                                    <value>#1</value>
                                </enumeratedValue>
                            </enumeratedValues>
                        </field>
                        <field>
                            <name>TXF</name>
                            <description>Transmit Flow Control Operating Mode</description>
                            <lsb>16</lsb>
                            <msb>16</msb>
                            <access>read-write</access>
                            <enumeratedValues>
                                <enumeratedValue>
                                    <name>0</name>
                                    <description>Disable automatic PAUSE frame transmission (PAUSE frame is not automatically transmitted) </description>
                                    <value>#0</value>
                                </enumeratedValue>
                                <enumeratedValue>
                                    <name>1</name>
                                    <description>Enable automatic PAUSE frame transmission (PAUSE frame is automatically transmitted as required). </description>
                                    <value>#1</value>
                                </enumeratedValue>
                            </enumeratedValues>
                        </field>
                        <field>
                            <name>RXF</name>
                            <description>Receive Flow Control Operating Mode</description>
                            <lsb>17</lsb>
                            <msb>17</msb>
                            <access>read-write</access>
                            <enumeratedValues>
                                <enumeratedValue>
                                    <name>0</name>
                                    <description>Disable PAUSE frame detection</description>
                                    <value>#0</value>
                                </enumeratedValue>
                                <enumeratedValue>
                                    <name>1</name>
                                    <description>Enable PAUSE frame detection.</description>
                                    <value>#1</value>
                                </enumeratedValue>
                            </enumeratedValues>
                        </field>
                        <field>
                            <name>PFR</name>
                            <description>PAUSE Frame Receive Mode</description>
                            <lsb>18</lsb>
                            <msb>18</msb>
                            <access>read-write</access>
                            <enumeratedValues>
                                <enumeratedValue>
                                    <name>0</name>
                                    <description>Do not transfer PAUSE frame to the EDMAC</description>
                                    <value>#0</value>
                                </enumeratedValue>
                                <enumeratedValue>
                                    <name>1</name>
                                    <description>Transfer PAUSE frame to the EDMAC.</description>
                                    <value>#1</value>
                                </enumeratedValue>
                            </enumeratedValues>
                        </field>
                        <field>
                            <name>ZPF</name>
                            <description>0 Time PAUSE Frame Enable</description>
                            <lsb>19</lsb>
                            <msb>19</msb>
                            <access>read-write</access>
                            <enumeratedValues>
                                <enumeratedValue>
                                    <name>0</name>
                                    <description>Do not use PAUSE frames that containing a pause_time parameter of 0 </description>
                                    <value>#0</value>
                                </enumeratedValue>
                                <enumeratedValue>
                                    <name>1</name>
                                    <description>Use PAUSE frames that containing a pause_time parameter of 0.</description>
                                    <value>#1</value>
                                </enumeratedValue>
                            </enumeratedValues>
                        </field>
                        <field>
                            <name>TPC</name>
                            <description>PAUSE Frame Transmit</description>
                            <lsb>20</lsb>
                            <msb>20</msb>
                            <access>read-write</access>
                            <enumeratedValues>
                                <enumeratedValue>
                                    <name>0</name>
                                    <description>Transmit PAUSE frame even during a PAUSE period</description>
                                    <value>#0</value>
                                </enumeratedValue>
                                <enumeratedValue>
                                    <name>1</name>
                                    <description>Do not transmit PAUSE frame during a PAUSE period.</description>
                                    <value>#1</value>
                                </enumeratedValue>
                            </enumeratedValues>
                        </field>
                    </fields>
                </register>
                <register>
                    <name>RFLR</name>
                    <description>Receive Frame Maximum Length Register</description>
                    <addressOffset>0x08</addressOffset>
                    <size>32</size>
                    <access>read-write</access>
                    <resetValue>0x00000000</resetValue>
                    <resetMask>0xffffffff</resetMask>
                    <fields>
                        <field>
                            <name>RFL</name>
                            <description>Receive Frame Maximum Length</description>
                            <lsb>0</lsb>
                            <msb>11</msb>
                            <access>read-write</access>
                        </field>
                    </fields>
                </register>
                <register>
                    <name>ECSR</name>
                    <description>ETHERC Status Register</description>
                    <addressOffset>0x10</addressOffset>
                    <size>32</size>
                    <access>read-write</access>
                    <resetValue>0x00000000</resetValue>
                    <resetMask>0xffffffff</resetMask>
                    <fields>
                        <field>
                            <name>ICD</name>
                            <description>False Carrier Detect Flag</description>
                            <lsb>0</lsb>
                            <msb>0</msb>
                            <access>read-write</access>
                            <enumeratedValues>
                                <enumeratedValue>
                                    <name>0</name>
                                    <description>PHY-LSI has not detected a false carrier on the line</description>
                                    <value>#0</value>
                                </enumeratedValue>
                                <enumeratedValue>
                                    <name>1</name>
                                    <description>PHY-LSI detected a false carrier on the line.</description>
                                    <value>#1</value>
                                </enumeratedValue>
                            </enumeratedValues>
                        </field>
                        <field>
                            <name>MPD</name>
                            <description>Magic Packet Detect Flag</description>
                            <lsb>1</lsb>
                            <msb>1</msb>
                            <access>read-write</access>
                            <enumeratedValues>
                                <enumeratedValue>
                                    <name>0</name>
                                    <description>Magic Packet not detected</description>
                                    <value>#0</value>
                                </enumeratedValue>
                                <enumeratedValue>
                                    <name>1</name>
                                    <description>Magic Packet detected.</description>
                                    <value>#1</value>
                                </enumeratedValue>
                            </enumeratedValues>
                        </field>
                        <field>
                            <name>LCHNG</name>
                            <description>Link Signal Change Flag</description>
                            <lsb>2</lsb>
                            <msb>2</msb>
                            <access>read-write</access>
                            <enumeratedValues>
                                <enumeratedValue>
                                    <name>0</name>
                                    <description>Change in the ET0_LINKSTA signal not detected</description>
                                    <value>#0</value>
                                </enumeratedValue>
                                <enumeratedValue>
                                    <name>1</name>
                                    <description>Change in the ET0_LINKSTA signal detected (high to low, or low to high). </description>
                                    <value>#1</value>
                                </enumeratedValue>
                            </enumeratedValues>
                        </field>
                        <field>
                            <name>PSRTO</name>
                            <description>PAUSE Frame Retransmit Over Flag</description>
                            <lsb>4</lsb>
                            <msb>4</msb>
                            <access>read-write</access>
                            <enumeratedValues>
                                <enumeratedValue>
                                    <name>0</name>
                                    <description>PAUSE frame retransmit count has not reached the upper limit</description>
                                    <value>#0</value>
                                </enumeratedValue>
                                <enumeratedValue>
                                    <name>1</name>
                                    <description>PAUSE frame retransmit count reached the upper limit.</description>
                                    <value>#1</value>
                                </enumeratedValue>
                            </enumeratedValues>
                        </field>
                        <field>
                            <name>BFR</name>
                            <description>Continuous Broadcast Frame Reception Flag</description>
                            <lsb>5</lsb>
                            <msb>5</msb>
                            <access>read-write</access>
                            <enumeratedValues>
                                <enumeratedValue>
                                    <name>0</name>
                                    <description>Continuous reception of broadcast frames not detected</description>
                                    <value>#0</value>
                                </enumeratedValue>
                                <enumeratedValue>
                                    <name>1</name>
                                    <description>Continuous reception of broadcast frames detected.</description>
                                    <value>#1</value>
                                </enumeratedValue>
                            </enumeratedValues>
                        </field>
                    </fields>
                </register>
                <register>
                    <name>ECSIPR</name>
                    <description>ETHERC Interrupt Enable Register</description>
                    <addressOffset>0x18</addressOffset>
                    <size>32</size>
                    <access>read-write</access>
                    <resetValue>0x00000000</resetValue>
                    <resetMask>0xffffffff</resetMask>
                    <fields>
                        <field>
                            <name>ICDIP</name>
                            <description>False Carrier Detect Interrupt Enable</description>
                            <lsb>0</lsb>
                            <msb>0</msb>
                            <access>read-write</access>
                            <enumeratedValues>
                                <enumeratedValue>
                                    <name>0</name>
                                    <description>Disable interrupt notification</description>
                                    <value>#0</value>
                                </enumeratedValue>
                                <enumeratedValue>
                                    <name>1</name>
                                    <description>Enable interrupt notification.</description>
                                    <value>#1</value>
                                </enumeratedValue>
                            </enumeratedValues>
                        </field>
                        <field>
                            <name>MPDIP</name>
                            <description>Magic Packet Detect Interrupt Enable</description>
                            <lsb>1</lsb>
                            <msb>1</msb>
                            <access>read-write</access>
                            <enumeratedValues>
                                <enumeratedValue>
                                    <name>0</name>
                                    <description>Disable interrupt notification</description>
                                    <value>#0</value>
                                </enumeratedValue>
                                <enumeratedValue>
                                    <name>1</name>
                                    <description>Enable interrupt notification.</description>
                                    <value>#1</value>
                                </enumeratedValue>
                            </enumeratedValues>
                        </field>
                        <field>
                            <name>LCHNGIP</name>
                            <description>LINK Signal Change Interrupt Enable</description>
                            <lsb>2</lsb>
                            <msb>2</msb>
                            <access>read-write</access>
                            <enumeratedValues>
                                <enumeratedValue>
                                    <name>0</name>
                                    <description>Disable interrupt notification</description>
                                    <value>#0</value>
                                </enumeratedValue>
                                <enumeratedValue>
                                    <name>1</name>
                                    <description>Enable interrupt notification.</description>
                                    <value>#1</value>
                                </enumeratedValue>
                            </enumeratedValues>
                        </field>
                        <field>
                            <name>PSRTOIP</name>
                            <description>PAUSE Frame Retransmit Over Interrupt Enable</description>
                            <lsb>4</lsb>
                            <msb>4</msb>
                            <access>read-write</access>
                            <enumeratedValues>
                                <enumeratedValue>
                                    <name>0</name>
                                    <description>Disable interrupt notification</description>
                                    <value>#0</value>
                                </enumeratedValue>
                                <enumeratedValue>
                                    <name>1</name>
                                    <description>Enable interrupt notification.</description>
                                    <value>#1</value>
                                </enumeratedValue>
                            </enumeratedValues>
                        </field>
                        <field>
                            <name>BFSIPR</name>
                            <description>Continuous Broadcast Frame Reception Interrupt Enable</description>
                            <lsb>5</lsb>
                            <msb>5</msb>
                            <access>read-write</access>
                            <enumeratedValues>
                                <enumeratedValue>
                                    <name>0</name>
                                    <description>Disable interrupt notification</description>
                                    <value>#0</value>
                                </enumeratedValue>
                                <enumeratedValue>
                                    <name>1</name>
                                    <description>Enable interrupt notification.</description>
                                    <value>#1</value>
                                </enumeratedValue>
                            </enumeratedValues>
                        </field>
                    </fields>
                </register>
                <register>
                    <name>PIR</name>
                    <description>PHY Interface Register</description>
                    <addressOffset>0x20</addressOffset>
                    <size>32</size>
                    <access>read-write</access>
                    <resetValue>0x00000000</resetValue>
                    <resetMask>0xfffffff7</resetMask>
                    <fields>
                        <field>
                            <name>MDC</name>
                            <description>MII/RMII Management Data Clock</description>
                            <lsb>0</lsb>
                            <msb>0</msb>
                            <access>read-write</access>
                        </field>
                        <field>
                            <name>MMD</name>
                            <description>MII/RMII Management Mode</description>
                            <lsb>1</lsb>
                            <msb>1</msb>
                            <access>read-write</access>
                            <enumeratedValues>
                                <enumeratedValue>
                                    <name>0</name>
                                    <description>Read</description>
                                    <value>#0</value>
                                </enumeratedValue>
                                <enumeratedValue>
                                    <name>1</name>
                                    <description>Write.</description>
                                    <value>#1</value>
                                </enumeratedValue>
                            </enumeratedValues>
                        </field>
                        <field>
                            <name>MDO</name>
                            <description>MII/RMII Management Data-Out</description>
                            <lsb>2</lsb>
                            <msb>2</msb>
                            <access>read-write</access>
                        </field>
                        <field>
                            <name>MDI</name>
                            <description>MII/RMII Management Data-In</description>
                            <lsb>3</lsb>
                            <msb>3</msb>
                            <access>read-only</access>
                        </field>
                    </fields>
                </register>
                <register>
                    <name>PSR</name>
                    <description>PHY Status Register</description>
                    <addressOffset>0x28</addressOffset>
                    <size>32</size>
                    <access>read-only</access>
                    <resetValue>0x00000000</resetValue>
                    <resetMask>0xfffffffe</resetMask>
                    <fields>
                        <field>
                            <name>LMON</name>
                            <description>ET0_LINKSTA Pin Status Flag</description>
                            <lsb>0</lsb>
                            <msb>0</msb>
                            <access>read-only</access>
                        </field>
                    </fields>
                </register>
                <register>
                    <name>RDMLR</name>
                    <description>Random Number Generation Counter Upper Limit Setting Register</description>
                    <addressOffset>0x40</addressOffset>
                    <size>32</size>
                    <access>read-write</access>
                    <resetValue>0x00000000</resetValue>
                    <resetMask>0xffff0000</resetMask>
                    <fields>
                        <field>
                            <name>RMD</name>
                            <description>Random Number Generation Counter</description>
                            <lsb>0</lsb>
                            <msb>19</msb>
                            <access>read-write</access>
                        </field>
                    </fields>
                </register>
                <register>
                    <name>IPGR</name>
                    <description>Interpacket Gap Register</description>
                    <addressOffset>0x50</addressOffset>
                    <size>32</size>
                    <access>read-write</access>
                    <resetValue>0x00000014</resetValue>
                    <resetMask>0xffffffff</resetMask>
                    <fields>
                        <field>
                            <name>IPG</name>
                            <lsb>0</lsb>
                            <msb>4</msb>
                            <access>read-write</access>
                        </field>
                    </fields>
                </register>
                <register>
                    <name>APR</name>
                    <description>Automatic PAUSE Frame Register</description>
                    <addressOffset>0x54</addressOffset>
                    <size>32</size>
                    <access>read-write</access>
                    <resetValue>0x00000000</resetValue>
                    <resetMask>0xffffffff</resetMask>
                    <fields>
                        <field>
                            <name>AP</name>
                            <description>Automatic PAUSE Time Setting</description>
                            <lsb>0</lsb>
                            <msb>15</msb>
                            <access>read-write</access>
                        </field>
                    </fields>
                </register>
                <register>
                    <name>MPR</name>
                    <description>Manual PAUSE Frame Register</description>
                    <addressOffset>0x58</addressOffset>
                    <size>32</size>
                    <access>read-write</access>
                    <resetValue>0x00000000</resetValue>
                    <resetMask>0xffff0000</resetMask>
                    <fields>
                        <field>
                            <name>MP</name>
                            <description>Manual PAUSE Time Setting</description>
                            <lsb>0</lsb>
                            <msb>15</msb>
                            <access>read-write</access>
                        </field>
                    </fields>
                </register>
                <register>
                    <name>RFCF</name>
                    <description>Received PAUSE Frame Counter</description>
                    <addressOffset>0x60</addressOffset>
                    <size>32</size>
                    <access>read-only</access>
                    <resetValue>0x00000000</resetValue>
                    <resetMask>0xffffffff</resetMask>
                    <fields>
                        <field>
                            <name>RPAUSE</name>
                            <description>Received PAUSE Frame Count</description>
                            <lsb>0</lsb>
                            <msb>7</msb>
                            <access>read-only</access>
                        </field>
                    </fields>
                </register>
                <register>
                    <name>TPAUSER</name>
                    <description>PAUSE Frame Retransmit Count Setting Register</description>
                    <addressOffset>0x64</addressOffset>
                    <size>32</size>
                    <access>read-write</access>
                    <resetValue>0x00000000</resetValue>
                    <resetMask>0xffffffff</resetMask>
                    <fields>
                        <field>
                            <name>TPAUSE</name>
                            <lsb>0</lsb>
                            <msb>15</msb>
                            <access>read-write</access>
                        </field>
                    </fields>
                </register>
                <register>
                    <name>TPAUSECR</name>
                    <description>PAUSE Frame Retransmit Counter</description>
                    <addressOffset>0x68</addressOffset>
                    <size>32</size>
                    <access>read-only</access>
                    <resetValue>0x00000000</resetValue>
                    <resetMask>0xffffffff</resetMask>
                    <fields>
                        <field>
                            <name>TXP</name>
                            <description>PAUSE Frame Retransmit Count</description>
                            <lsb>0</lsb>
                            <msb>7</msb>
                            <access>read-only</access>
                        </field>
                    </fields>
                </register>
                <register>
                    <name>BCFRR</name>
                    <description>Broadcast Frame Receive Count Setting Register</description>
                    <addressOffset>0x6C</addressOffset>
                    <size>32</size>
                    <access>read-write</access>
                    <resetValue>0x00000000</resetValue>
                    <resetMask>0xffffffff</resetMask>
                    <fields>
                        <field>
                            <name>BCF</name>
                            <lsb>0</lsb>
                            <msb>15</msb>
                            <access>read-write</access>
                        </field>
                    </fields>
                </register>
                <register>
                    <name>MAHR</name>
                    <description>MAC Address Upper Bit Register</description>
                    <addressOffset>0xC0</addressOffset>
                    <size>32</size>
                    <access>read-write</access>
                    <resetValue>0x00000000</resetValue>
                    <resetMask>0xffffffff</resetMask>
                    <fields>
                        <field>
                            <name>MAHR</name>
                            <description>MAC Address Upper Bit</description>
                            <lsb>0</lsb>
                            <msb>31</msb>
                            <access>read-write</access>
                        </field>
                    </fields>
                </register>
                <register>
                    <name>MALR</name>
                    <description>MAC Address Lower Bit Register</description>
                    <addressOffset>0xC8</addressOffset>
                    <size>32</size>
                    <access>read-write</access>
                    <resetValue>0x00000000</resetValue>
                    <resetMask>0xffffffff</resetMask>
                    <fields>
                        <field>
                            <name>MALR</name>
                            <description>MAC Address Lower Bit</description>
                            <lsb>0</lsb>
                            <msb>15</msb>
                            <access>read-write</access>
                        </field>
                    </fields>
                </register>
                <register>
                    <name>TROCR</name>
                    <description>Transmit Retry Over Counter Register</description>
                    <addressOffset>0xD0</addressOffset>
                    <size>32</size>
                    <access>read-write</access>
                    <resetValue>0x00000000</resetValue>
                    <resetMask>0xffffffff</resetMask>
                    <fields>
                        <field>
                            <name>TROCR</name>
                            <description>Transmit Retry Over Counter</description>
                            <lsb>0</lsb>
                            <msb>31</msb>
                            <access>read-write</access>
                        </field>
                    </fields>
                </register>
                <register>
                    <name>CDCR</name>
                    <description>Late Collision Detect Counter Register</description>
                    <addressOffset>0xD4</addressOffset>
                    <size>32</size>
                    <access>read-write</access>
                    <resetValue>0x00000000</resetValue>
                    <resetMask>0xffffffff</resetMask>
                    <fields>
                        <field>
                            <name>CDCR</name>
                            <description>Late Collision Detect Counter</description>
                            <lsb>0</lsb>
                            <msb>31</msb>
                            <access>read-write</access>
                        </field>
                    </fields>
                </register>
                <register>
                    <name>LCCR</name>
                    <description>Lost Carrier Counter Register</description>
                    <addressOffset>0xD8</addressOffset>
                    <size>32</size>
                    <access>read-write</access>
                    <resetValue>0x00000000</resetValue>
                    <resetMask>0xffffffff</resetMask>
                    <fields>
                        <field>
                            <name>LCCR</name>
                            <description>Lost Carrier Counter</description>
                            <lsb>0</lsb>
                            <msb>31</msb>
                            <access>read-write</access>
                        </field>
                    </fields>
                </register>
                <register>
                    <name>CNDCR</name>
                    <description>Carrier Not Detect Counter Register</description>
                    <addressOffset>0xDC</addressOffset>
                    <size>32</size>
                    <access>read-write</access>
                    <resetValue>0x00000000</resetValue>
                    <resetMask>0xffffffff</resetMask>
                    <fields>
                        <field>
                            <name>CNDCR</name>
                            <description>Carrier Not Detect Counter</description>
                            <lsb>0</lsb>
                            <msb>31</msb>
                            <access>read-write</access>
                        </field>
                    </fields>
                </register>
                <register>
                    <name>CEFCR</name>
                    <description>CRC Error Frame Receive Counter Register</description>
                    <addressOffset>0xE4</addressOffset>
                    <size>32</size>
                    <access>read-write</access>
                    <resetValue>0x00000000</resetValue>
                    <resetMask>0xffffffff</resetMask>
                    <fields>
                        <field>
                            <name>CEFCR</name>
                            <description>CRC Error Frame Receive Counter</description>
                            <lsb>0</lsb>
                            <msb>31</msb>
                            <access>read-write</access>
                        </field>
                    </fields>
                </register>
                <register>
                    <name>FRECR</name>
                    <description>Frame Receive Error Counter Register</description>
                    <addressOffset>0xE8</addressOffset>
                    <size>32</size>
                    <access>read-write</access>
                    <resetValue>0x00000000</resetValue>
                    <resetMask>0xffffffff</resetMask>
                    <fields>
                        <field>
                            <name>FRECR</name>
                            <description>Frame Receive Error Counter</description>
                            <lsb>0</lsb>
                            <msb>31</msb>
                            <access>read-write</access>
                        </field>
                    </fields>
                </register>
                <register>
                    <name>TSFRCR</name>
                    <description>Too-Short Frame Receive Counter Register</description>
                    <addressOffset>0xEC</addressOffset>
                    <size>32</size>
                    <access>read-write</access>
                    <resetValue>0x00000000</resetValue>
                    <resetMask>0xffffffff</resetMask>
                    <fields>
                        <field>
                            <name>TSFRCR</name>
                            <description>Too-Short Frame Receive Counter</description>
                            <lsb>0</lsb>
                            <msb>31</msb>
                            <access>read-write</access>
                        </field>
                    </fields>
                </register>
                <register>
                    <name>TLFRCR</name>
                    <description>Too-Long Frame Receive Counter Register</description>
                    <addressOffset>0xF0</addressOffset>
                    <size>32</size>
                    <access>read-write</access>
                    <resetValue>0x00000000</resetValue>
                    <resetMask>0xffffffff</resetMask>
                    <fields>
                        <field>
                            <name>TLFRCR</name>
                            <description>Too-Long Frame Receive Counter</description>
                            <lsb>0</lsb>
                            <msb>31</msb>
                            <access>read-write</access>
                        </field>
                    </fields>
                </register>
                <register>
                    <name>RFCR</name>
                    <description>Received Alignment Error Frame Counter Register</description>
                    <addressOffset>0xF4</addressOffset>
                    <size>32</size>
                    <access>read-write</access>
                    <resetValue>0x00000000</resetValue>
                    <resetMask>0xffffffff</resetMask>
                    <fields>
                        <field>
                            <name>RFCR</name>
                            <description>Received Alignment Error Frame Counter</description>
                            <lsb>0</lsb>
                            <msb>31</msb>
                            <access>read-write</access>
                        </field>
                    </fields>
                </register>
                <register>
                    <name>MAFCR</name>
                    <description>Multicast Address Frame Receive Counter Register</description>
                    <addressOffset>0xF8</addressOffset>
                    <size>32</size>
                    <access>read-write</access>
                    <resetValue>0x00000000</resetValue>
                    <resetMask>0xffffffff</resetMask>
                    <fields>
                        <field>
                            <name>MAFCR</name>
                            <description>Multicast Address Frame Receive Counter</description>
                            <lsb>0</lsb>
                            <msb>31</msb>
                            <access>read-write</access>
                        </field>
                    </fields>
                </register>
            </registers>
        </peripheral>
        <peripheral>
            <name>SCI0_B_NS</name>
            <description>Serial Communication Interface 0</description>
            <baseAddress>0x50358000</baseAddress>
            <addressBlock>
                <offset>0x00</offset>
                <size>4</size>
                <usage>registers</usage>
            </addressBlock>
            <addressBlock>
                <offset>0x04</offset>
                <size>4</size>
                <usage>registers</usage>
            </addressBlock>
            <addressBlock>
                <offset>0x08</offset>
                <size>21</size>
                <usage>registers</usage>
            </addressBlock>
            <addressBlock>
                <offset>0x20</offset>
                <size>8</size>
                <usage>registers</usage>
            </addressBlock>
            <addressBlock>
                <offset>0x2C</offset>
                <size>20</size>
                <usage>registers</usage>
            </addressBlock>
            <addressBlock>
                <offset>0x48</offset>
                <size>28</size>
                <usage>registers</usage>
            </addressBlock>
            <addressBlock>
                <offset>0x68</offset>
                <size>20</size>
                <usage>registers</usage>
            </addressBlock>
            <registers>
                <register>
                    <name>RDR</name>
                    <description>Receive Data Register</description>
                    <addressOffset>0x00</addressOffset>
                    <size>32</size>
                    <access>read-only</access>
                    <resetValue>0x00000000</resetValue>
                    <resetMask>0xffffffff</resetMask>
                    <fields>
                        <field>
                            <name>RDAT</name>
                            <description>Serial receive data</description>
                            <lsb>0</lsb>
                            <msb>8</msb>
                            <access>read-only</access>
                        </field>
                        <field>
                            <name>MPB</name>
                            <description>Multi-processor flag</description>
                            <lsb>9</lsb>
                            <msb>9</msb>
                            <access>read-only</access>
                            <enumeratedValues>
                                <enumeratedValue>
                                    <name>0</name>
                                    <description>Data transmission cycles</description>
                                    <value>#0</value>
                                </enumeratedValue>
                                <enumeratedValue>
                                    <name>1</name>
                                    <description>ID transmission cycles</description>
                                    <value>#1</value>
                                </enumeratedValue>
                            </enumeratedValues>
                        </field>
                        <field>
                            <name>DR</name>
                            <description>Receive data ready flag</description>
                            <lsb>10</lsb>
                            <msb>10</msb>
                            <access>read-only</access>
                        </field>
                        <field>
                            <name>FPER</name>
                            <description>FIFO parity error flag</description>
                            <lsb>11</lsb>
                            <msb>11</msb>
                            <access>read-only</access>
                            <enumeratedValues>
                                <enumeratedValue>
                                    <name>0</name>
                                    <description>There is no parity error in the data read from the receive-FIFO</description>
                                    <value>#0</value>
                                </enumeratedValue>
                                <enumeratedValue>
                                    <name>1</name>
                                    <description>There is parity error in the data read from the receive-FIFO</description>
                                    <value>#1</value>
                                </enumeratedValue>
                            </enumeratedValues>
                        </field>
                        <field>
                            <name>FFER</name>
                            <description>FIFO framing error flag</description>
                            <lsb>12</lsb>
                            <msb>12</msb>
                            <access>read-only</access>
                            <enumeratedValues>
                                <enumeratedValue>
                                    <name>0</name>
                                    <description>There is no framing error in the data read from the receive-FIFO</description>
                                    <value>#0</value>
                                </enumeratedValue>
                                <enumeratedValue>
                                    <name>1</name>
                                    <description>There is framing error in the data read from the receive-FIFO</description>
                                    <value>#1</value>
                                </enumeratedValue>
                            </enumeratedValues>
                        </field>
                        <field>
                            <name>ORER</name>
                            <description>Overrun Error flag</description>
                            <lsb>24</lsb>
                            <msb>24</msb>
                            <access>read-only</access>
                        </field>
                        <field>
                            <name>PER</name>
                            <description>Parity error flag</description>
                            <lsb>27</lsb>
                            <msb>27</msb>
                            <access>read-only</access>
                        </field>
                        <field>
                            <name>FER</name>
                            <description>Framing error flag</description>
                            <lsb>28</lsb>
                            <msb>28</msb>
                            <access>read-only</access>
                        </field>
                    </fields>
                </register>
                <register>
                    <name>RDR_BY</name>
                    <description>Receive Data Register</description>
                    <alternateRegister>RDR</alternateRegister>
                    <addressOffset>0x00</addressOffset>
                    <size>8</size>
                    <access>read-only</access>
                    <resetValue>0x00</resetValue>
                    <resetMask>0xff</resetMask>
                    <fields>
                        <field>
                            <name>ORER</name>
                            <description>Overrun Error flag</description>
                            <lsb>0</lsb>
                            <msb>0</msb>
                            <access>read-only</access>
                        </field>
                        <field>
                            <name>PER</name>
                            <description>Parity error flag</description>
                            <lsb>3</lsb>
                            <msb>3</msb>
                            <access>read-only</access>
                        </field>
                        <field>
                            <name>FER</name>
                            <description>Framing error flag</description>
                            <lsb>4</lsb>
                            <msb>4</msb>
                            <access>read-only</access>
                        </field>
                    </fields>
                </register>
                <register>
                    <name>TDR</name>
                    <description>Transmit Data Register</description>
                    <addressOffset>0x04</addressOffset>
                    <size>32</size>
                    <access>read-write</access>
                    <resetValue>0xffffffff</resetValue>
                    <resetMask>0xffffffff</resetMask>
                    <fields>
                        <field>
                            <name>TDAT</name>
                            <description>Serial transmit data</description>
                            <lsb>0</lsb>
                            <msb>8</msb>
                            <access>read-write</access>
                        </field>
                        <field>
                            <name>MPBT</name>
                            <description>Multi-processor transfer bit flag</description>
                            <lsb>9</lsb>
                            <msb>9</msb>
                            <access>read-write</access>
                            <enumeratedValues>
                                <enumeratedValue>
                                    <name>0</name>
                                    <description>Data transmission cycles</description>
                                    <value>#0</value>
                                </enumeratedValue>
                                <enumeratedValue>
                                    <name>1</name>
                                    <description>ID transmission cycles</description>
                                    <value>#1</value>
                                </enumeratedValue>
                            </enumeratedValues>
                        </field>
                        <field>
                            <name>TSYNC</name>
                            <description>Transmit SYNC data</description>
                            <lsb>12</lsb>
                            <msb>12</msb>
                            <access>read-write</access>
                            <enumeratedValues>
                                <enumeratedValue>
                                    <name>0</name>
                                    <description>The Start Bit is transmitted as DATA SYNC.</description>
                                    <value>#0</value>
                                </enumeratedValue>
                                <enumeratedValue>
                                    <name>1</name>
                                    <description>The Start Bit is transmitted as COMMAND SYNC.</description>
                                    <value>#1</value>
                                </enumeratedValue>
                            </enumeratedValues>
                        </field>
                    </fields>
                </register>
                <register>
                    <name>TDRLL</name>
                    <description>Transmit Data Register</description>
                    <alternateRegister>TDR</alternateRegister>
                    <addressOffset>0x04</addressOffset>
                    <size>16</size>
                    <access>read-write</access>
                    <resetValue>0xffff</resetValue>
                    <resetMask>0xffff</resetMask>
                </register>
                <register>
                    <name>TDRLH</name>
                    <description>Transmit Data Register</description>
                    <alternateRegister>TDR</alternateRegister>
                    <addressOffset>0x05</addressOffset>
                    <size>16</size>
                    <access>read-write</access>
                    <resetValue>0xffff</resetValue>
                    <resetMask>0xffff</resetMask>
                    <fields>
                        <field>
                            <name>TDAT</name>
                            <description>Serial transmit data</description>
                            <lsb>0</lsb>
                            <msb>0</msb>
                            <access>read-write</access>
                        </field>
                        <field>
                            <name>MPBT</name>
                            <description>Multi-processor transfer bit flag</description>
                            <lsb>1</lsb>
                            <msb>1</msb>
                            <access>read-write</access>
                            <enumeratedValues>
                                <enumeratedValue>
                                    <name>0</name>
                                    <description>Data transmission cycles</description>
                                    <value>#0</value>
                                </enumeratedValue>
                                <enumeratedValue>
                                    <name>1</name>
                                    <description>ID transmission cycles</description>
                                    <value>#1</value>
                                </enumeratedValue>
                            </enumeratedValues>
                        </field>
                        <field>
                            <name>TSYNC</name>
                            <description>Transmit SYNC data</description>
                            <lsb>4</lsb>
                            <msb>4</msb>
                            <access>read-write</access>
                            <enumeratedValues>
                                <enumeratedValue>
                                    <name>0</name>
                                    <description>The Start Bit is transmitted as DATA SYNC.</description>
                                    <value>#0</value>
                                </enumeratedValue>
                                <enumeratedValue>
                                    <name>1</name>
                                    <description>The Start Bit is transmitted as COMMAND SYNC.</description>
                                    <value>#1</value>
                                </enumeratedValue>
                            </enumeratedValues>
                        </field>
                    </fields>
                </register>
                <register>
                    <name>CCR0</name>
                    <description>Common Control Register 0</description>
                    <addressOffset>0x08</addressOffset>
                    <size>32</size>
                    <access>read-write</access>
                    <resetValue>0x00000000</resetValue>
                    <resetMask>0xffffffff</resetMask>
                    <fields>
                        <field>
                            <name>RE</name>
                            <description>Receive Enable</description>
                            <lsb>0</lsb>
                            <msb>0</msb>
                            <access>read-write</access>
                            <enumeratedValues>
                                <enumeratedValue>
                                    <name>0</name>
                                    <description>Serial reception is disabled</description>
                                    <value>#0</value>
                                </enumeratedValue>
                                <enumeratedValue>
                                    <name>1</name>
                                    <description>Serial reception is enabled</description>
                                    <value>#1</value>
                                </enumeratedValue>
                            </enumeratedValues>
                        </field>
                        <field>
                            <name>TE</name>
                            <description>Transmit Enable</description>
                            <lsb>4</lsb>
                            <msb>4</msb>
                            <access>read-write</access>
                            <enumeratedValues>
                                <enumeratedValue>
                                    <name>0</name>
                                    <description>Serial transmission is disabled</description>
                                    <value>#0</value>
                                </enumeratedValue>
                                <enumeratedValue>
                                    <name>1</name>
                                    <description>Serial transmission is enabled</description>
                                    <value>#1</value>
                                </enumeratedValue>
                            </enumeratedValues>
                        </field>
                        <field>
                            <name>MPIE</name>
                            <description>Multi-Processor Interrupt Enable</description>
                            <lsb>8</lsb>
                            <msb>8</msb>
                            <access>read-write</access>
                            <enumeratedValues>
                                <enumeratedValue>
                                    <name>0</name>
                                    <description>Non-multi-processor reception</description>
                                    <value>#0</value>
                                </enumeratedValue>
                                <enumeratedValue>
                                    <name>1</name>
                                    <description>Multi-processor reception When the data with the multi-processor bit set to 0 is received, the data is not read, and setting the status flags to 1 is disabled. When the data with the multi-processor bit set to 1 is received, the MPIE bit is automatically cleared to 0, and non-multi-processor reception is resumed. If you want to continue receiving operation using the multiprocessor function, set this bit to 1 sufficiently earlier than receiving the STOP bit of the next received frame (consider the synchronization delay time). </description>
                                    <value>#1</value>
                                </enumeratedValue>
                            </enumeratedValues>
                        </field>
                        <field>
                            <name>DCME</name>
                            <description>Data Compare Match Enable</description>
                            <lsb>9</lsb>
                            <msb>9</msb>
                            <access>read-write</access>
                            <enumeratedValues>
                                <enumeratedValue>
                                    <name>0</name>
                                    <description>Address match function is disabled</description>
                                    <value>#0</value>
                                </enumeratedValue>
                                <enumeratedValue>
                                    <name>1</name>
                                    <description>Address match function is enabled</description>
                                    <value>#1</value>
                                </enumeratedValue>
                            </enumeratedValues>
                        </field>
                        <field>
                            <name>IDSEL</name>
                            <description>ID Frame Select</description>
                            <lsb>10</lsb>
                            <msb>10</msb>
                            <access>read-write</access>
                            <enumeratedValues>
                                <enumeratedValue>
                                    <name>0</name>
                                    <description>Compare data irrespective of the value of the MPB bit</description>
                                    <value>#0</value>
                                </enumeratedValue>
                                <enumeratedValue>
                                    <name>1</name>
                                    <description>Compare data only when the MPB bit is 1 (ID frame)</description>
                                    <value>#1</value>
                                </enumeratedValue>
                            </enumeratedValues>
                        </field>
                        <field>
                            <name>RIE</name>
                            <description>Receive Interrupt Enable</description>
                            <lsb>16</lsb>
                            <msb>16</msb>
                            <access>read-write</access>
                            <enumeratedValues>
                                <enumeratedValue>
                                    <name>0</name>
                                    <description>SCIn_RXI and SCIn_ERI interrupt requests are disabled</description>
                                    <value>#0</value>
                                </enumeratedValue>
                                <enumeratedValue>
                                    <name>1</name>
                                    <description>SCIn_RXI and SCIn_ERI interrupt requests are enabled</description>
                                    <value>#1</value>
                                </enumeratedValue>
                            </enumeratedValues>
                        </field>
                        <field>
                            <name>TIE</name>
                            <description>Transmit Interrupt Enable</description>
                            <lsb>20</lsb>
                            <msb>20</msb>
                            <access>read-write</access>
                            <enumeratedValues>
                                <enumeratedValue>
                                    <name>0</name>
                                    <description>SCIn_TXI interrupt request is disabled</description>
                                    <value>#0</value>
                                </enumeratedValue>
                                <enumeratedValue>
                                    <name>1</name>
                                    <description>SCIn_TXI interrupt request is enabled</description>
                                    <value>#1</value>
                                </enumeratedValue>
                            </enumeratedValues>
                        </field>
                        <field>
                            <name>TEIE</name>
                            <description>Transmit End Interrupt Enable</description>
                            <lsb>21</lsb>
                            <msb>21</msb>
                            <access>read-write</access>
                            <enumeratedValues>
                                <enumeratedValue>
                                    <name>0</name>
                                    <description>SCIn_TEI interrupt request is disabled</description>
                                    <value>#0</value>
                                </enumeratedValue>
                                <enumeratedValue>
                                    <name>1</name>
                                    <description>SCIn_TEI interrupt request is enabled</description>
                                    <value>#1</value>
                                </enumeratedValue>
                            </enumeratedValues>
                        </field>
                        <field>
                            <name>SSE</name>
                            <description>SSn Pin Function Enable</description>
                            <lsb>24</lsb>
                            <msb>24</msb>
                            <access>read-write</access>
                            <enumeratedValues>
                                <enumeratedValue>
                                    <name>0</name>
                                    <description>SSn pin function is disabled</description>
                                    <value>#0</value>
                                </enumeratedValue>
                                <enumeratedValue>
                                    <name>1</name>
                                    <description>SSn pin function is enabled</description>
                                    <value>#1</value>
                                </enumeratedValue>
                            </enumeratedValues>
                        </field>
                    </fields>
                </register>
                <register>
                    <name>CCR1</name>
                    <description>Common Control Register 1</description>
                    <addressOffset>0x0C</addressOffset>
                    <size>32</size>
                    <access>read-write</access>
                    <resetValue>0x00000010</resetValue>
                    <resetMask>0xffffffff</resetMask>
                    <fields>
                        <field>
                            <name>CTSE</name>
                            <description>CTS Enable</description>
                            <lsb>0</lsb>
                            <msb>0</msb>
                            <access>read-write</access>
                            <enumeratedValues>
                                <enumeratedValue>
                                    <name>0</name>
                                    <description>CTS function is disabled (RTS output function is enabled)</description>
                                    <value>#0</value>
                                </enumeratedValue>
                                <enumeratedValue>
                                    <name>1</name>
                                    <description>CTS function is enabled</description>
                                    <value>#1</value>
                                </enumeratedValue>
                            </enumeratedValues>
                        </field>
                        <field>
                            <name>CTSPEN</name>
                            <description>CTS External Pin Enable</description>
                            <lsb>1</lsb>
                            <msb>1</msb>
                            <access>read-write</access>
                            <enumeratedValues>
                                <enumeratedValue>
                                    <name>0</name>
                                    <description>Alternate setting to use CTS and RTS functions as either 1 pin</description>
                                    <value>#0</value>
                                </enumeratedValue>
                                <enumeratedValue>
                                    <name>1</name>
                                    <description>Dedicated setting for separately using CTS and RTS functions with 2 pins</description>
                                    <value>#1</value>
                                </enumeratedValue>
                            </enumeratedValues>
                        </field>
                        <field>
                            <name>SPB2DT</name>
                            <description>Serial Port Break Data Select</description>
                            <lsb>4</lsb>
                            <msb>4</msb>
                            <access>read-write</access>
                            <enumeratedValues>
                                <enumeratedValue>
                                    <name>0</name>
                                    <description>When TINV is 0, low level is output in TXDn pin. When TINV is 1, high level is output in TXDn pin. </description>
                                    <value>#0</value>
                                </enumeratedValue>
                                <enumeratedValue>
                                    <name>1</name>
                                    <description>When TINV is 0, high level is output in TXDn pin. When TINV is 1, low level is output in TXDn pin. </description>
                                    <value>#1</value>
                                </enumeratedValue>
                            </enumeratedValues>
                        </field>
                        <field>
                            <name>SPB2IO</name>
                            <description>Serial Port Break I/O</description>
                            <lsb>5</lsb>
                            <msb>5</msb>
                            <access>read-write</access>
                            <enumeratedValues>
                                <enumeratedValue>
                                    <name>0</name>
                                    <description>The value of SPB2DT bit is not output in TXDn pin</description>
                                    <value>#0</value>
                                </enumeratedValue>
                                <enumeratedValue>
                                    <name>1</name>
                                    <description>The value of SPB2DT bit is output in TXDn pin</description>
                                    <value>#1</value>
                                </enumeratedValue>
                            </enumeratedValues>
                        </field>
                        <field>
                            <name>PE</name>
                            <description>Parity Enable</description>
                            <lsb>8</lsb>
                            <msb>8</msb>
                            <access>read-write</access>
                            <enumeratedValues>
                                <enumeratedValue>
                                    <name>0</name>
                                    <description>When transmitting: Do not add parity bit When receiving: Do not check parity bit </description>
                                    <value>#0</value>
                                </enumeratedValue>
                                <enumeratedValue>
                                    <name>1</name>
                                    <description>When transmitting: Add parity bit When receiving: Check parity bit </description>
                                    <value>#1</value>
                                </enumeratedValue>
                            </enumeratedValues>
                        </field>
                        <field>
                            <name>PM</name>
                            <description>Parity Mode</description>
                            <lsb>9</lsb>
                            <msb>9</msb>
                            <access>read-write</access>
                            <enumeratedValues>
                                <enumeratedValue>
                                    <name>0</name>
                                    <description>Selects even parity</description>
                                    <value>#0</value>
                                </enumeratedValue>
                                <enumeratedValue>
                                    <name>1</name>
                                    <description>Selects odd parity</description>
                                    <value>#1</value>
                                </enumeratedValue>
                            </enumeratedValues>
                        </field>
                        <field>
                            <name>TINV</name>
                            <description>TXD Invert</description>
                            <lsb>12</lsb>
                            <msb>12</msb>
                            <access>read-write</access>
                            <enumeratedValues>
                                <enumeratedValue>
                                    <name>0</name>
                                    <description>Transmit data is not inverted and output to TXDn</description>
                                    <value>#0</value>
                                </enumeratedValue>
                                <enumeratedValue>
                                    <name>1</name>
                                    <description>Transmit data is inverted and output to TXDn</description>
                                    <value>#1</value>
                                </enumeratedValue>
                            </enumeratedValues>
                        </field>
                        <field>
                            <name>RINV</name>
                            <description>RXD Invert</description>
                            <lsb>13</lsb>
                            <msb>13</msb>
                            <access>read-write</access>
                            <enumeratedValues>
                                <enumeratedValue>
                                    <name>0</name>
                                    <description>Received data from RXDn is not inverted and input</description>
                                    <value>#0</value>
                                </enumeratedValue>
                                <enumeratedValue>
                                    <name>1</name>
                                    <description>Received data from RXDn is inverted and input</description>
                                    <value>#1</value>
                                </enumeratedValue>
                            </enumeratedValues>
                        </field>
                        <field>
                            <name>SPLP</name>
                            <description>Loopback Control</description>
                            <lsb>16</lsb>
                            <msb>16</msb>
                            <access>read-write</access>
                            <enumeratedValues>
                                <enumeratedValue>
                                    <name>0</name>
                                    <description>Normal mode</description>
                                    <value>#0</value>
                                </enumeratedValue>
                                <enumeratedValue>
                                    <name>1</name>
                                    <description>Loopback mode</description>
                                    <value>#1</value>
                                </enumeratedValue>
                            </enumeratedValues>
                        </field>
                        <field>
                            <name>SHARPS</name>
                            <description>Half-Duplex Communication Select</description>
                            <lsb>20</lsb>
                            <msb>20</msb>
                            <access>read-write</access>
                            <enumeratedValues>
                                <enumeratedValue>
                                    <name>0</name>
                                    <description>TXDn pin, RXDn pin independent</description>
                                    <value>#0</value>
                                </enumeratedValue>
                                <enumeratedValue>
                                    <name>1</name>
                                    <description>TXDn/RXDn pin combination use (half-duplex communication using TXDn pin) </description>
                                    <value>#1</value>
                                </enumeratedValue>
                            </enumeratedValues>
                        </field>
                        <field>
                            <name>NFCS</name>
                            <description>Noise Filter Clock Select</description>
                            <lsb>24</lsb>
                            <msb>26</msb>
                            <access>read-write</access>
                            <enumeratedValues>
                                <enumeratedValue>
                                    <name>000</name>
                                    <description>The base clock signal divided by 1</description>
                                    <value>#000</value>
                                </enumeratedValue>
                                <enumeratedValue>
                                    <name>001</name>
                                    <description>The on-chip baud rate generator source clock divided by 1</description>
                                    <value>#001</value>
                                </enumeratedValue>
                                <enumeratedValue>
                                    <name>010</name>
                                    <description>The on-chip baud rate generator source clock divided by 2</description>
                                    <value>#010</value>
                                </enumeratedValue>
                                <enumeratedValue>
                                    <name>011</name>
                                    <description>The on-chip baud rate generator source clock divided by 4</description>
                                    <value>#011</value>
                                </enumeratedValue>
                                <enumeratedValue>
                                    <name>100</name>
                                    <description>The on-chip baud rate generator source clock divided by 8</description>
                                    <value>#100</value>
                                </enumeratedValue>
                                <enumeratedValue>
                                    <name>others</name>
                                    <description>Setting prohibited</description>
                                    <isDefault>true</isDefault>
                                </enumeratedValue>
                            </enumeratedValues>
                        </field>
                        <field>
                            <name>NFEN</name>
                            <description>Digital Noise Filter Function Enable</description>
                            <lsb>28</lsb>
                            <msb>28</msb>
                            <access>read-write</access>
                            <enumeratedValues>
                                <enumeratedValue>
                                    <name>0</name>
                                    <description>In Asynchronous, Manchester, Simple LIN modes: Disable noise cancellation function for RXDn input signal In Simple IIC mode: Disable noise cancellation function for SCLn and SDAn input signals </description>
                                    <value>#0</value>
                                </enumeratedValue>
                                <enumeratedValue>
                                    <name>1</name>
                                    <description>In Asynchronous, Manchester, Simple LIN modes: Enable noise cancellation function for RXDn input signal In Simple IIC mode: Enable noise cancellation function for SCLn and SDAn input signals </description>
                                    <value>#1</value>
                                </enumeratedValue>
                            </enumeratedValues>
                        </field>
                        <field>
                            <name>NFM</name>
                            <description>Noise Filter Mode</description>
                            <lsb>29</lsb>
                            <msb>29</msb>
                            <access>read-write</access>
                            <enumeratedValues>
                                <enumeratedValue>
                                    <name>0</name>
                                    <description>3-point matching mode</description>
                                    <value>#0</value>
                                </enumeratedValue>
                                <enumeratedValue>
                                    <name>1</name>
                                    <description>Majority vote mode</description>
                                    <value>#1</value>
                                </enumeratedValue>
                            </enumeratedValues>
                        </field>
                    </fields>
                </register>
                <register>
                    <name>CCR2</name>
                    <description>Common Control Register 2</description>
                    <addressOffset>0x10</addressOffset>
                    <size>32</size>
                    <access>read-write</access>
                    <resetValue>0xff00ff04</resetValue>
                    <resetMask>0xffffffff</resetMask>
                    <fields>
                        <field>
                            <name>BCP</name>
                            <description>Base Clock Pulse</description>
                            <lsb>0</lsb>
                            <msb>2</msb>
                            <access>read-write</access>
                            <enumeratedValues>
                                <enumeratedValue>
                                    <name>000</name>
                                    <description>93 clock cycles (S = 93)</description>
                                    <value>#000</value>
                                </enumeratedValue>
                                <enumeratedValue>
                                    <name>001</name>
                                    <description>128 clock cycles (S = 128)</description>
                                    <value>#001</value>
                                </enumeratedValue>
                                <enumeratedValue>
                                    <name>010</name>
                                    <description>186 clock cycles (S = 186)</description>
                                    <value>#010</value>
                                </enumeratedValue>
                                <enumeratedValue>
                                    <name>011</name>
                                    <description>512 clock cycles (S = 512)</description>
                                    <value>#011</value>
                                </enumeratedValue>
                                <enumeratedValue>
                                    <name>100</name>
                                    <description>32 clock cycles (S = 32) (Initial value)</description>
                                    <value>#100</value>
                                </enumeratedValue>
                                <enumeratedValue>
                                    <name>101</name>
                                    <description>64 clock cycles (S = 64)</description>
                                    <value>#101</value>
                                </enumeratedValue>
                                <enumeratedValue>
                                    <name>110</name>
                                    <description>372 clock cycles (S = 372)</description>
                                    <value>#110</value>
                                </enumeratedValue>
                                <enumeratedValue>
                                    <name>111</name>
                                    <description>256 clock cycles (S = 256)</description>
                                    <value>#111</value>
                                </enumeratedValue>
                            </enumeratedValues>
                        </field>
                        <field>
                            <name>BGDM</name>
                            <description>Baud Rate Generator Double-Speed Mode Select</description>
                            <lsb>4</lsb>
                            <msb>4</msb>
                            <access>read-write</access>
                            <enumeratedValues>
                                <enumeratedValue>
                                    <name>0</name>
                                    <description>Baud rate generator outputs the clock with single frequency</description>
                                    <value>#0</value>
                                </enumeratedValue>
                                <enumeratedValue>
                                    <name>1</name>
                                    <description>Baud rate generator outputs the clock with doubled frequency</description>
                                    <value>#1</value>
                                </enumeratedValue>
                            </enumeratedValues>
                        </field>
                        <field>
                            <name>ABCS</name>
                            <description>Asynchronous Mode Base Clock Select</description>
                            <lsb>5</lsb>
                            <msb>5</msb>
                            <access>read-write</access>
                            <enumeratedValues>
                                <enumeratedValue>
                                    <name>0</name>
                                    <description>Selects 16 base clock cycles for 1-bit period</description>
                                    <value>#0</value>
                                </enumeratedValue>
                                <enumeratedValue>
                                    <name>1</name>
                                    <description>Selects 8 base clock cycles for 1-bit period</description>
                                    <value>#1</value>
                                </enumeratedValue>
                            </enumeratedValues>
                        </field>
                        <field>
                            <name>ABCSE</name>
                            <description>Asynchronous Mode Extended Base Clock Select</description>
                            <lsb>6</lsb>
                            <msb>6</msb>
                            <access>read-write</access>
                            <enumeratedValues>
                                <enumeratedValue>
                                    <name>0</name>
                                    <description>Clock cycles for 1-bit period is determined by combination between CCR2.BGDM and CCR2.ABCS.</description>
                                    <value>#0</value>
                                </enumeratedValue>
                                <enumeratedValue>
                                    <name>1</name>
                                    <description>Baud rate is 6 base clock cycles for 1-bit period and the clock of a double frequency is output from the baud rate generator.</description>
                                    <value>#1</value>
                                </enumeratedValue>
                            </enumeratedValues>
                        </field>
                        <field>
                            <name>ABCSE2</name>
                            <description>Asynchronous Mode Extended Base Clock Select 2</description>
                            <lsb>7</lsb>
                            <msb>7</msb>
                            <access>read-write</access>
                            <enumeratedValues>
                                <enumeratedValue>
                                    <name>0</name>
                                    <description>Clock cycles for 1-bit period is decided with combination between CCR2.BGDM and CCR2.ABCS.</description>
                                    <value>#0</value>
                                </enumeratedValue>
                                <enumeratedValue>
                                    <name>1</name>
                                    <description>Baud rate is 4 base clock cycles for 1-bit period and the clock of a double frequency is output from the baud rate generator.</description>
                                    <value>#1</value>
                                </enumeratedValue>
                            </enumeratedValues>
                        </field>
                        <field>
                            <name>BRR</name>
                            <description>Bit Rate Setting</description>
                            <lsb>8</lsb>
                            <msb>15</msb>
                            <access>read-write</access>
                        </field>
                        <field>
                            <name>BRME</name>
                            <description>Bit Rate Modulation Enable</description>
                            <lsb>16</lsb>
                            <msb>16</msb>
                            <access>read-write</access>
                            <enumeratedValues>
                                <enumeratedValue>
                                    <name>0</name>
                                    <description>Bit rate modulation function is disabled</description>
                                    <value>#0</value>
                                </enumeratedValue>
                                <enumeratedValue>
                                    <name>1</name>
                                    <description>Bit rate modulation function is enabled</description>
                                    <value>#1</value>
                                </enumeratedValue>
                            </enumeratedValues>
                        </field>
                        <field>
                            <name>CKS</name>
                            <description>Clock Select</description>
                            <lsb>20</lsb>
                            <msb>21</msb>
                            <access>read-write</access>
                            <enumeratedValues>
                                <enumeratedValue>
                                    <name>00</name>
                                    <description>TCLK clock (n = 0)</description>
                                    <value>#00</value>
                                </enumeratedValue>
                                <enumeratedValue>
                                    <name>01</name>
                                    <description>TCLK/4 clock (n = 1)</description>
                                    <value>#01</value>
                                </enumeratedValue>
                                <enumeratedValue>
                                    <name>10</name>
                                    <description>TCLK/16 clock (n = 2)</description>
                                    <value>#10</value>
                                </enumeratedValue>
                                <enumeratedValue>
                                    <name>11</name>
                                    <description>TCLK/64 clock (n = 3)</description>
                                    <value>#11</value>
                                </enumeratedValue>
                            </enumeratedValues>
                        </field>
                        <field>
                            <name>MDDR</name>
                            <description>Modulation Duty Setting</description>
                            <lsb>24</lsb>
                            <msb>31</msb>
                            <access>read-write</access>
                        </field>
                    </fields>
                </register>
                <register>
                    <name>CCR3</name>
                    <description>Common Control Register 3</description>
                    <addressOffset>0x14</addressOffset>
                    <size>32</size>
                    <access>read-write</access>
                    <resetValue>0x00001203</resetValue>
                    <resetMask>0xffffffff</resetMask>
                    <fields>
                        <field>
                            <name>CPHA</name>
                            <description>Clock Phase Select</description>
                            <lsb>0</lsb>
                            <msb>0</msb>
                            <access>read-write</access>
                            <enumeratedValues>
                                <enumeratedValue>
                                    <name>0</name>
                                    <description>Data is sampled at an odd edge and changes at an even edge (clock is delayed)</description>
                                    <value>#0</value>
                                </enumeratedValue>
                                <enumeratedValue>
                                    <name>1</name>
                                    <description>Data changes at an odd edge and is sampled at an even edge (clock is not delayed)</description>
                                    <value>#1</value>
                                </enumeratedValue>
                            </enumeratedValues>
                        </field>
                        <field>
                            <name>CPOL</name>
                            <description>Clock Polarity Select</description>
                            <lsb>1</lsb>
                            <msb>1</msb>
                            <access>read-write</access>
                            <enumeratedValues>
                                <enumeratedValue>
                                    <name>0</name>
                                    <description>SCKn in idle state is 0</description>
                                    <value>#0</value>
                                </enumeratedValue>
                                <enumeratedValue>
                                    <name>1</name>
                                    <description>SCKn in idle state is 1</description>
                                    <value>#1</value>
                                </enumeratedValue>
                            </enumeratedValues>
                        </field>
                        <field>
                            <name>BPEN</name>
                            <description>Synchronizer Bypass Enable</description>
                            <lsb>7</lsb>
                            <msb>7</msb>
                            <access>read-write</access>
                            <enumeratedValues>
                                <enumeratedValue>
                                    <name>0</name>
                                    <description>Synchronizer circuit is not bypassed</description>
                                    <value>#0</value>
                                </enumeratedValue>
                                <enumeratedValue>
                                    <name>1</name>
                                    <description>Synchronizer circuit is bypassed</description>
                                    <value>#1</value>
                                </enumeratedValue>
                            </enumeratedValues>
                        </field>
                        <field>
                            <name>CHR</name>
                            <description>Character Length</description>
                            <lsb>8</lsb>
                            <msb>9</msb>
                            <access>read-write</access>
                            <enumeratedValues>
                                <enumeratedValue>
                                    <name>00</name>
                                    <description>Transmit/receive in 9-bit data length</description>
                                    <value>#00</value>
                                </enumeratedValue>
                                <enumeratedValue>
                                    <name>01</name>
                                    <description>Transmit/receive in 9-bit data length</description>
                                    <value>#01</value>
                                </enumeratedValue>
                                <enumeratedValue>
                                    <name>10</name>
                                    <description>Transmit/receive in 8-bit data length (initial value)</description>
                                    <value>#10</value>
                                </enumeratedValue>
                                <enumeratedValue>
                                    <name>11</name>
                                    <description>Transmit/receive in 7-bit data length</description>
                                    <value>#11</value>
                                </enumeratedValue>
                            </enumeratedValues>
                        </field>
                        <field>
                            <name>LSBF</name>
                            <description>LSB First select</description>
                            <lsb>12</lsb>
                            <msb>12</msb>
                            <access>read-write</access>
                            <enumeratedValues>
                                <enumeratedValue>
                                    <name>0</name>
                                    <description>MSB-first</description>
                                    <value>#0</value>
                                </enumeratedValue>
                                <enumeratedValue>
                                    <name>1</name>
                                    <description>LSB-first</description>
                                    <value>#1</value>
                                </enumeratedValue>
                            </enumeratedValues>
                        </field>
                        <field>
                            <name>SINV</name>
                            <description>Transmitted/Received Data Invert</description>
                            <lsb>13</lsb>
                            <msb>13</msb>
                            <access>read-write</access>
                            <enumeratedValues>
                                <enumeratedValue>
                                    <name>0</name>
                                    <description>TDR contents are transmitted to TSR as is. RSR contents are stored to RDR as is. </description>
                                    <value>#0</value>
                                </enumeratedValue>
                                <enumeratedValue>
                                    <name>1</name>
                                    <description>TDR contents are inverted before being transmitted to TSR. RSR contents are inverted and stored to RDR. </description>
                                    <value>#1</value>
                                </enumeratedValue>
                            </enumeratedValues>
                        </field>
                        <field>
                            <name>STP</name>
                            <description>Stop Bit Length</description>
                            <lsb>14</lsb>
                            <msb>14</msb>
                            <access>read-write</access>
                            <enumeratedValues>
                                <enumeratedValue>
                                    <name>0</name>
                                    <description>1 stop bit/break delimiter length is 1-bit</description>
                                    <value>#0</value>
                                </enumeratedValue>
                                <enumeratedValue>
                                    <name>1</name>
                                    <description>2 stop bits/break delimiter length is 2-bit</description>
                                    <value>#1</value>
                                </enumeratedValue>
                            </enumeratedValues>
                        </field>
                        <field>
                            <name>RXDESEL</name>
                            <description>Asynchronous Start Bit Edge Detection Select</description>
                            <lsb>15</lsb>
                            <msb>15</msb>
                            <access>read-write</access>
                            <enumeratedValues>
                                <enumeratedValue>
                                    <name>0</name>
                                    <description>The low level on the RXDn pin is detected as the start bit</description>
                                    <value>#0</value>
                                </enumeratedValue>
                                <enumeratedValue>
                                    <name>1</name>
                                    <description>A falling edge on the RXDn pin is detected as the start bit</description>
                                    <value>#1</value>
                                </enumeratedValue>
                            </enumeratedValues>
                        </field>
                        <field>
                            <name>MOD</name>
                            <description>Communication Mode Select</description>
                            <lsb>16</lsb>
                            <msb>18</msb>
                            <access>read-write</access>
                            <enumeratedValues>
                                <enumeratedValue>
                                    <name>000</name>
                                    <description>Asynchronous mode (multi-processor mode)</description>
                                    <value>#000</value>
                                </enumeratedValue>
                                <enumeratedValue>
                                    <name>001</name>
                                    <description>Smart card interface mode</description>
                                    <value>#001</value>
                                </enumeratedValue>
                                <enumeratedValue>
                                    <name>010</name>
                                    <description>Clock synchronous mode</description>
                                    <value>#010</value>
                                </enumeratedValue>
                                <enumeratedValue>
                                    <name>011</name>
                                    <description>Simple SPI mode</description>
                                    <value>#011</value>
                                </enumeratedValue>
                                <enumeratedValue>
                                    <name>100</name>
                                    <description>Simple IIC mode</description>
                                    <value>#100</value>
                                </enumeratedValue>
                                <enumeratedValue>
                                    <name>101</name>
                                    <description>Manchester mode</description>
                                    <value>#101</value>
                                </enumeratedValue>
                                <enumeratedValue>
                                    <name>110</name>
                                    <description>Simple LIN mode</description>
                                    <value>#110</value>
                                </enumeratedValue>
                                <enumeratedValue>
                                    <name>111</name>
                                    <description>Setting prohibited</description>
                                    <value>#111</value>
                                </enumeratedValue>
                            </enumeratedValues>
                        </field>
                        <field>
                            <name>MP</name>
                            <description>Multi-Processor Mode</description>
                            <lsb>19</lsb>
                            <msb>19</msb>
                            <access>read-write</access>
                            <enumeratedValues>
                                <enumeratedValue>
                                    <name>0</name>
                                    <description>Multi-processor communications function is disabled</description>
                                    <value>#0</value>
                                </enumeratedValue>
                                <enumeratedValue>
                                    <name>1</name>
                                    <description>Multi-processor communications function is enabled</description>
                                    <value>#1</value>
                                </enumeratedValue>
                            </enumeratedValues>
                        </field>
                        <field>
                            <name>FM</name>
                            <description>FIFO Mode Select</description>
                            <lsb>20</lsb>
                            <msb>20</msb>
                            <access>read-write</access>
                            <enumeratedValues>
                                <enumeratedValue>
                                    <name>0</name>
                                    <description>TDR register and RDR register are non-FIFO buffer configuration</description>
                                    <value>#0</value>
                                </enumeratedValue>
                                <enumeratedValue>
                                    <name>1</name>
                                    <description>TDR register and RDR register are FIFO buffer configuration</description>
                                    <value>#1</value>
                                </enumeratedValue>
                            </enumeratedValues>
                        </field>
                        <field>
                            <name>DEN</name>
                            <description>Driver Enable</description>
                            <lsb>21</lsb>
                            <msb>21</msb>
                            <access>read-write</access>
                            <enumeratedValues>
                                <enumeratedValue>
                                    <name>0</name>
                                    <description>RS-485 driver control function disabled</description>
                                    <value>#0</value>
                                </enumeratedValue>
                                <enumeratedValue>
                                    <name>1</name>
                                    <description>RS-485 driver control function enabled</description>
                                    <value>#1</value>
                                </enumeratedValue>
                            </enumeratedValues>
                        </field>
                        <field>
                            <name>CKE</name>
                            <description>Clock Enable</description>
                            <lsb>24</lsb>
                            <msb>25</msb>
                            <access>read-write</access>
                        </field>
                        <field>
                            <name>ACS0</name>
                            <description>Asynchronous Mode Clock Source Select</description>
                            <lsb>26</lsb>
                            <msb>26</msb>
                            <access>read-write</access>
                            <enumeratedValues>
                                <enumeratedValue>
                                    <name>0</name>
                                    <description>External clock input</description>
                                    <value>#0</value>
                                </enumeratedValue>
                                <enumeratedValue>
                                    <name>1</name>
                                    <description>Logical AND of compare matches output from the internal GPT</description>
                                    <value>#1</value>
                                </enumeratedValue>
                            </enumeratedValues>
                        </field>
                        <field>
                            <name>GM</name>
                            <description>GSM Mode</description>
                            <lsb>28</lsb>
                            <msb>28</msb>
                            <access>read-write</access>
                            <enumeratedValues>
                                <enumeratedValue>
                                    <name>0</name>
                                    <description>Non-GSM mode operation</description>
                                    <value>#0</value>
                                </enumeratedValue>
                                <enumeratedValue>
                                    <name>1</name>
                                    <description>GSM mode operation</description>
                                    <value>#1</value>
                                </enumeratedValue>
                            </enumeratedValues>
                        </field>
                        <field>
                            <name>BLK</name>
                            <description>Block Transfer Mode</description>
                            <lsb>29</lsb>
                            <msb>29</msb>
                            <access>read-write</access>
                            <enumeratedValues>
                                <enumeratedValue>
                                    <name>0</name>
                                    <description>Non-block transfer mode operation</description>
                                    <value>#0</value>
                                </enumeratedValue>
                                <enumeratedValue>
                                    <name>1</name>
                                    <description>Block transfer mode operation</description>
                                    <value>#1</value>
                                </enumeratedValue>
                            </enumeratedValues>
                        </field>
                    </fields>
                </register>
                <register>
                    <name>CCR4</name>
                    <description>Common Control Register 4</description>
                    <addressOffset>0x18</addressOffset>
                    <size>32</size>
                    <access>read-write</access>
                    <resetValue>0x00000000</resetValue>
                    <resetMask>0xffffffff</resetMask>
                    <fields>
                        <field>
                            <name>CMPD</name>
                            <description>Compare Match Data</description>
                            <lsb>0</lsb>
                            <msb>8</msb>
                            <access>read-write</access>
                        </field>
                        <field>
                            <name>ASEN</name>
                            <description>Adjust Receive Sampling Timing Enable</description>
                            <lsb>16</lsb>
                            <msb>16</msb>
                            <access>read-write</access>
                            <enumeratedValues>
                                <enumeratedValue>
                                    <name>0</name>
                                    <description>Adjust sampling timing disabled</description>
                                    <value>#0</value>
                                </enumeratedValue>
                                <enumeratedValue>
                                    <name>1</name>
                                    <description>Adjust sampling timing enabled</description>
                                    <value>#1</value>
                                </enumeratedValue>
                            </enumeratedValues>
                        </field>
                        <field>
                            <name>ATEN</name>
                            <description>Adjust Transmit Timing Enable</description>
                            <lsb>17</lsb>
                            <msb>17</msb>
                            <access>read-write</access>
                            <enumeratedValues>
                                <enumeratedValue>
                                    <name>0</name>
                                    <description>Adjust transmit timing disabled</description>
                                    <value>#0</value>
                                </enumeratedValue>
                                <enumeratedValue>
                                    <name>1</name>
                                    <description>Adjust transmit timing enabled</description>
                                    <value>#1</value>
                                </enumeratedValue>
                            </enumeratedValues>
                        </field>
                        <field>
                            <name>SCKSEL</name>
                            <description>Master receive clock selection</description>
                            <lsb>19</lsb>
                            <msb>19</msb>
                            <access>read-write</access>
                            <enumeratedValues>
                                <enumeratedValue>
                                    <name>0</name>
                                    <description>Master receive clock is disabled</description>
                                    <value>#0</value>
                                </enumeratedValue>
                                <enumeratedValue>
                                    <name>1</name>
                                    <description>Master receive clock is enabled</description>
                                    <value>#1</value>
                                </enumeratedValue>
                            </enumeratedValues>
                        </field>
                        <field>
                            <name>AST</name>
                            <description>Adjustment Value for Receive Sampling Timing</description>
                            <lsb>24</lsb>
                            <msb>26</msb>
                            <access>read-write</access>
                            <enumeratedValues>
                                <enumeratedValue>
                                    <name>000</name>
                                    <description>1-TCLK delay</description>
                                    <value>#000</value>
                                </enumeratedValue>
                                <enumeratedValue>
                                    <name>001</name>
                                    <description>2-TCLK delay</description>
                                    <value>#001</value>
                                </enumeratedValue>
                                <enumeratedValue>
                                    <name>010</name>
                                    <description>3-TCLK delay</description>
                                    <value>#010</value>
                                </enumeratedValue>
                                <enumeratedValue>
                                    <name>011</name>
                                    <description>4-TCLK delay</description>
                                    <value>#011</value>
                                </enumeratedValue>
                                <enumeratedValue>
                                    <name>Others</name>
                                    <description>Setting prohibited</description>
                                    <isDefault>true</isDefault>
                                </enumeratedValue>
                            </enumeratedValues>
                        </field>
                        <field>
                            <name>AJD</name>
                            <description>Adjustment Direction for Receive Sampling Timing</description>
                            <lsb>27</lsb>
                            <msb>27</msb>
                            <access>read-write</access>
                            <enumeratedValues>
                                <enumeratedValue>
                                    <name>0</name>
                                    <description>The sampling timing is adjusted backward to the middle of bit.</description>
                                    <value>#0</value>
                                </enumeratedValue>
                                <enumeratedValue>
                                    <name>1</name>
                                    <description>The sampling timing is adjusted forward to the middle of bit.</description>
                                    <value>#1</value>
                                </enumeratedValue>
                            </enumeratedValues>
                        </field>
                        <field>
                            <name>ATT</name>
                            <description>Adjustment Value for Transmit Timing</description>
                            <lsb>28</lsb>
                            <msb>30</msb>
                            <access>read-write</access>
                        </field>
                        <field>
                            <name>AET</name>
                            <description>Adjustment Edge for Transmit Timing</description>
                            <lsb>31</lsb>
                            <msb>31</msb>
                            <access>read-write</access>
                            <enumeratedValues>
                                <enumeratedValue>
                                    <name>0</name>
                                    <description>When CCR1.TINV is 0, adjust the rising edge timing. When CCR1.TINV is 1, adjust the falling edge timing. </description>
                                    <value>#0</value>
                                </enumeratedValue>
                                <enumeratedValue>
                                    <name>1</name>
                                    <description>When CCR1.TINV is 0, adjust the falling edge timing. When CCR1.TINV is 1, adjust the rising edge timing. </description>
                                    <value>#1</value>
                                </enumeratedValue>
                            </enumeratedValues>
                        </field>
                    </fields>
                </register>
                <register>
                    <name>CESR</name>
                    <description>Communication Enable Status Register</description>
                    <addressOffset>0x1C</addressOffset>
                    <size>8</size>
                    <access>read-only</access>
                    <resetValue>0x00</resetValue>
                    <resetMask>0xff</resetMask>
                    <fields>
                        <field>
                            <name>RIST</name>
                            <description>RE Internal Status</description>
                            <lsb>0</lsb>
                            <msb>0</msb>
                            <access>read-only</access>
                            <enumeratedValues>
                                <enumeratedValue>
                                    <name>0</name>
                                    <description>RE signal internal state value 0</description>
                                    <value>#0</value>
                                </enumeratedValue>
                                <enumeratedValue>
                                    <name>1</name>
                                    <description>RE signal internal state value 1</description>
                                    <value>#1</value>
                                </enumeratedValue>
                            </enumeratedValues>
                        </field>
                        <field>
                            <name>TIST</name>
                            <description>TE Internal Status</description>
                            <lsb>4</lsb>
                            <msb>4</msb>
                            <access>read-only</access>
                            <enumeratedValues>
                                <enumeratedValue>
                                    <name>0</name>
                                    <description>TE signal internal state value 0</description>
                                    <value>#0</value>
                                </enumeratedValue>
                                <enumeratedValue>
                                    <name>1</name>
                                    <description>TE signal internal state value 1</description>
                                    <value>#1</value>
                                </enumeratedValue>
                            </enumeratedValues>
                        </field>
                    </fields>
                </register>
                <register>
                    <name>ICR</name>
                    <description>Simple IIC Control Register</description>
                    <addressOffset>0x20</addressOffset>
                    <size>32</size>
                    <access>read-write</access>
                    <resetValue>0x00000000</resetValue>
                    <resetMask>0xffffffff</resetMask>
                    <fields>
                        <field>
                            <name>IICDL</name>
                            <description>SDA Delay Output Select</description>
                            <lsb>0</lsb>
                            <msb>4</msb>
                            <access>read-write</access>
                        </field>
                        <field>
                            <name>IICINTM</name>
                            <description>IIC Interrupt Mode Select</description>
                            <lsb>8</lsb>
                            <msb>8</msb>
                            <access>read-write</access>
                            <enumeratedValues>
                                <enumeratedValue>
                                    <name>0</name>
                                    <description>Use ACK/NACK interrupts</description>
                                    <value>#0</value>
                                </enumeratedValue>
                                <enumeratedValue>
                                    <name>1</name>
                                    <description>Use reception and transmission interrupts</description>
                                    <value>#1</value>
                                </enumeratedValue>
                            </enumeratedValues>
                        </field>
                        <field>
                            <name>IICCSC</name>
                            <description>Clock Synchronization</description>
                            <lsb>9</lsb>
                            <msb>9</msb>
                            <access>read-write</access>
                            <enumeratedValues>
                                <enumeratedValue>
                                    <name>0</name>
                                    <description>No synchronization with the clock signal</description>
                                    <value>#0</value>
                                </enumeratedValue>
                                <enumeratedValue>
                                    <name>1</name>
                                    <description>Synchronization with the clock signal</description>
                                    <value>#1</value>
                                </enumeratedValue>
                            </enumeratedValues>
                        </field>
                        <field>
                            <name>IICACKT</name>
                            <description>ACK Transmission Data</description>
                            <lsb>13</lsb>
                            <msb>13</msb>
                            <access>read-write</access>
                            <enumeratedValues>
                                <enumeratedValue>
                                    <name>0</name>
                                    <description>ACK transmission</description>
                                    <value>#0</value>
                                </enumeratedValue>
                                <enumeratedValue>
                                    <name>1</name>
                                    <description>NACK transmission and reception of ACK/NACK</description>
                                    <value>#1</value>
                                </enumeratedValue>
                            </enumeratedValues>
                        </field>
                        <field>
                            <name>IICSTAREQ</name>
                            <description>Start Condition Generation</description>
                            <lsb>16</lsb>
                            <msb>16</msb>
                            <access>read-write</access>
                            <enumeratedValues>
                                <enumeratedValue>
                                    <name>0</name>
                                    <description>A start condition is not generated</description>
                                    <value>#0</value>
                                </enumeratedValue>
                                <enumeratedValue>
                                    <name>1</name>
                                    <description>A start condition is generated </description>
                                    <value>#1</value>
                                </enumeratedValue>
                            </enumeratedValues>
                        </field>
                        <field>
                            <name>IICRSTAREQ</name>
                            <description>Restart Condition Generation</description>
                            <lsb>17</lsb>
                            <msb>17</msb>
                            <access>read-write</access>
                            <enumeratedValues>
                                <enumeratedValue>
                                    <name>0</name>
                                    <description>A restart condition is not generated</description>
                                    <value>#0</value>
                                </enumeratedValue>
                                <enumeratedValue>
                                    <name>1</name>
                                    <description>A restart condition is generated </description>
                                    <value>#1</value>
                                </enumeratedValue>
                            </enumeratedValues>
                        </field>
                        <field>
                            <name>IICSTPREQ</name>
                            <description>Stop Condition Generation</description>
                            <lsb>18</lsb>
                            <msb>18</msb>
                            <access>read-write</access>
                            <enumeratedValues>
                                <enumeratedValue>
                                    <name>0</name>
                                    <description>A stop condition is not generated.</description>
                                    <value>#0</value>
                                </enumeratedValue>
                                <enumeratedValue>
                                    <name>1</name>
                                    <description>A stop condition is generated </description>
                                    <value>#1</value>
                                </enumeratedValue>
                            </enumeratedValues>
                        </field>
                        <field>
                            <name>IICSDAS</name>
                            <description>SDA Output Select</description>
                            <lsb>20</lsb>
                            <msb>21</msb>
                            <access>read-write</access>
                            <enumeratedValues>
                                <enumeratedValue>
                                    <name>00</name>
                                    <description>Serial data output</description>
                                    <value>#00</value>
                                </enumeratedValue>
                                <enumeratedValue>
                                    <name>01</name>
                                    <description>Generate a start, restart, or stop condition</description>
                                    <value>#01</value>
                                </enumeratedValue>
                                <enumeratedValue>
                                    <name>10</name>
                                    <description>Output the low level on the SDAn pin</description>
                                    <value>#10</value>
                                </enumeratedValue>
                                <enumeratedValue>
                                    <name>11</name>
                                    <description>Place the SDAn pin in the high-impedance state</description>
                                    <value>#11</value>
                                </enumeratedValue>
                            </enumeratedValues>
                        </field>
                        <field>
                            <name>IICSCLS</name>
                            <description>SCL Output Select</description>
                            <lsb>22</lsb>
                            <msb>23</msb>
                            <access>read-write</access>
                            <enumeratedValues>
                                <enumeratedValue>
                                    <name>00</name>
                                    <description>Serial clock output</description>
                                    <value>#00</value>
                                </enumeratedValue>
                                <enumeratedValue>
                                    <name>01</name>
                                    <description>Generate a start, restart, or stop condition</description>
                                    <value>#01</value>
                                </enumeratedValue>
                                <enumeratedValue>
                                    <name>10</name>
                                    <description>Output the low level on the SCLn pin</description>
                                    <value>#10</value>
                                </enumeratedValue>
                                <enumeratedValue>
                                    <name>11</name>
                                    <description>Place the SCLn pin in the high-impedance state</description>
                                    <value>#11</value>
                                </enumeratedValue>
                            </enumeratedValues>
                        </field>
                    </fields>
                </register>
                <register>
                    <name>FCR</name>
                    <description>FIFO Control Register</description>
                    <addressOffset>0x24</addressOffset>
                    <size>32</size>
                    <access>read-write</access>
                    <resetValue>0x1f1f0000</resetValue>
                    <resetMask>0xffffffff</resetMask>
                    <fields>
                        <field>
                            <name>DRES</name>
                            <description>Receive Data Ready Error Select Bit</description>
                            <lsb>0</lsb>
                            <msb>0</msb>
                            <access>read-write</access>
                            <enumeratedValues>
                                <enumeratedValue>
                                    <name>0</name>
                                    <description>Reception data full interrupt (SCIn_RXI)</description>
                                    <value>#0</value>
                                </enumeratedValue>
                                <enumeratedValue>
                                    <name>1</name>
                                    <description>Receive error interrupt (SCIn_ERI)</description>
                                    <value>#1</value>
                                </enumeratedValue>
                            </enumeratedValues>
                        </field>
                        <field>
                            <name>TTRG</name>
                            <description>Transmit FIFO Data Trigger Number</description>
                            <lsb>8</lsb>
                            <msb>12</msb>
                            <access>read-write</access>
                        </field>
                        <field>
                            <name>TFRST</name>
                            <description>Transmit FIFO Data Register Reset</description>
                            <lsb>15</lsb>
                            <msb>15</msb>
                            <access>write-only</access>
                            <enumeratedValues>
                                <enumeratedValue>
                                    <name>0</name>
                                    <description>When set, this bit is invalid and does not affect operation</description>
                                    <value>#0</value>
                                </enumeratedValue>
                                <enumeratedValue>
                                    <name>1</name>
                                    <description>The number of data stored in Transmit-FIFO (TDR register) is 0</description>
                                    <value>#1</value>
                                </enumeratedValue>
                            </enumeratedValues>
                        </field>
                        <field>
                            <name>RTRG</name>
                            <description>Receive FIFO Data Trigger Number</description>
                            <lsb>16</lsb>
                            <msb>20</msb>
                            <access>read-write</access>
                        </field>
                        <field>
                            <name>RFRST</name>
                            <description>Receive FIFO Data Register Reset</description>
                            <lsb>23</lsb>
                            <msb>23</msb>
                            <access>write-only</access>
                            <enumeratedValues>
                                <enumeratedValue>
                                    <name>0</name>
                                    <description>When set, this bit is invalid and does not affect operation</description>
                                    <value>#0</value>
                                </enumeratedValue>
                                <enumeratedValue>
                                    <name>1</name>
                                    <description>The number of data stored in Receive-FIFO(RDR register) is 0</description>
                                    <value>#1</value>
                                </enumeratedValue>
                            </enumeratedValues>
                        </field>
                        <field>
                            <name>RSTRG</name>
                            <description>RTS Output Active Trigger Number Select</description>
                            <lsb>24</lsb>
                            <msb>28</msb>
                            <access>read-write</access>
                        </field>
                    </fields>
                </register>
                <register>
                    <name>MCR</name>
                    <description>Manchester Control Register</description>
                    <addressOffset>0x2C</addressOffset>
                    <size>32</size>
                    <access>read-write</access>
                    <resetValue>0x00000000</resetValue>
                    <resetMask>0xffffffff</resetMask>
                    <fields>
                        <field>
                            <name>RMPOL</name>
                            <description>Polarity of Received Manchester Code</description>
                            <lsb>0</lsb>
                            <msb>0</msb>
                            <access>read-write</access>
                            <enumeratedValues>
                                <enumeratedValue>
                                    <name>0</name>
                                    <description>Logic 0 is coded as a zero-to-one transition in Manchester code Logic 1 is coded as a one-to-zero transition in Manchester code </description>
                                    <value>#0</value>
                                </enumeratedValue>
                                <enumeratedValue>
                                    <name>1</name>
                                    <description>Logic 0 is coded as a one-to-zero transition in Manchester code Logic 1 is coded as a zero-to-one transition in Manchester code </description>
                                    <value>#1</value>
                                </enumeratedValue>
                            </enumeratedValues>
                        </field>
                        <field>
                            <name>TMPOL</name>
                            <description>Polarity of Transmit Manchester Code</description>
                            <lsb>1</lsb>
                            <msb>1</msb>
                            <access>read-write</access>
                            <enumeratedValues>
                                <enumeratedValue>
                                    <name>0</name>
                                    <description>Logic 0 is coded as a zero-to-one transition in Manchester code Logic 1 is coded as a one-to-zero transition in Manchester code </description>
                                    <value>#0</value>
                                </enumeratedValue>
                                <enumeratedValue>
                                    <name>1</name>
                                    <description>Logic 0 is coded as a one-to-zero transition in Manchester code Logic 1 is coded as a zero-to-one transition in Manchester code </description>
                                    <value>#1</value>
                                </enumeratedValue>
                            </enumeratedValues>
                        </field>
                        <field>
                            <name>ERTEN</name>
                            <description>Manchester Edge Retiming Enable</description>
                            <lsb>2</lsb>
                            <msb>2</msb>
                            <access>read-write</access>
                            <enumeratedValues>
                                <enumeratedValue>
                                    <name>0</name>
                                    <description>Disables the receive retiming function</description>
                                    <value>#0</value>
                                </enumeratedValue>
                                <enumeratedValue>
                                    <name>1</name>
                                    <description>Enables the receive retiming function</description>
                                    <value>#1</value>
                                </enumeratedValue>
                            </enumeratedValues>
                        </field>
                        <field>
                            <name>SYNVAL</name>
                            <description>SYNC value Setting</description>
                            <lsb>4</lsb>
                            <msb>4</msb>
                            <access>read-write</access>
                        </field>
                        <field>
                            <name>SYNSEL</name>
                            <description>SYNC Select</description>
                            <lsb>5</lsb>
                            <msb>5</msb>
                            <access>read-write</access>
                            <enumeratedValues>
                                <enumeratedValue>
                                    <name>0</name>
                                    <description>The start bit pattern is set with the SYNVAL bit</description>
                                    <value>#0</value>
                                </enumeratedValue>
                                <enumeratedValue>
                                    <name>1</name>
                                    <description>The start bit pattern is set with the TSYNC bit</description>
                                    <value>#1</value>
                                </enumeratedValue>
                            </enumeratedValues>
                        </field>
                        <field>
                            <name>SBSEL</name>
                            <description>Start Bit Select</description>
                            <lsb>6</lsb>
                            <msb>6</msb>
                            <access>read-write</access>
                            <enumeratedValues>
                                <enumeratedValue>
                                    <name>0</name>
                                    <description>The start bit area consists of one bit</description>
                                    <value>#0</value>
                                </enumeratedValue>
                                <enumeratedValue>
                                    <name>1</name>
                                    <description>The start bit area consists of three bits (COMMAND SYNC or DATA SYNC) </description>
                                    <value>#1</value>
                                </enumeratedValue>
                            </enumeratedValues>
                        </field>
                        <field>
                            <name>TPLEN</name>
                            <description>Transmit Preface Length</description>
                            <lsb>8</lsb>
                            <msb>11</msb>
                            <access>read-write</access>
                            <enumeratedValues>
                                <enumeratedValue>
                                    <name>0x0</name>
                                    <description>Disables the transmit preface generation</description>
                                    <value>0x0</value>
                                </enumeratedValue>
                                <enumeratedValue>
                                    <name>Others</name>
                                    <description>Transmit preface length (bit length)</description>
                                    <isDefault>true</isDefault>
                                </enumeratedValue>
                            </enumeratedValues>
                        </field>
                        <field>
                            <name>TPPAT</name>
                            <description>Transmit Preface Pattern</description>
                            <lsb>12</lsb>
                            <msb>13</msb>
                            <access>read-write</access>
                            <enumeratedValues>
                                <enumeratedValue>
                                    <name>00</name>
                                    <description>ALL ZERO</description>
                                    <value>#00</value>
                                </enumeratedValue>
                                <enumeratedValue>
                                    <name>01</name>
                                    <description>ZERO ONE</description>
                                    <value>#01</value>
                                </enumeratedValue>
                                <enumeratedValue>
                                    <name>10</name>
                                    <description>ONE ZERO</description>
                                    <value>#10</value>
                                </enumeratedValue>
                                <enumeratedValue>
                                    <name>11</name>
                                    <description>ALL ONE</description>
                                    <value>#11</value>
                                </enumeratedValue>
                            </enumeratedValues>
                        </field>
                        <field>
                            <name>RPLEN</name>
                            <description>Receive Preface Length</description>
                            <lsb>16</lsb>
                            <msb>19</msb>
                            <access>read-write</access>
                            <enumeratedValues>
                                <enumeratedValue>
                                    <name>0x0</name>
                                    <description>Disables the receive preface generation</description>
                                    <value>0x0</value>
                                </enumeratedValue>
                                <enumeratedValue>
                                    <name>Others</name>
                                    <description>Receive preface length (bit length)</description>
                                    <isDefault>true</isDefault>
                                </enumeratedValue>
                            </enumeratedValues>
                        </field>
                        <field>
                            <name>RPPAT</name>
                            <description>Receive Preface Pattern</description>
                            <lsb>20</lsb>
                            <msb>21</msb>
                            <access>read-write</access>
                            <enumeratedValues>
                                <enumeratedValue>
                                    <name>00</name>
                                    <description>ALL ZERO</description>
                                    <value>#00</value>
                                </enumeratedValue>
                                <enumeratedValue>
                                    <name>01</name>
                                    <description>ZERO ONE</description>
                                    <value>#01</value>
                                </enumeratedValue>
                                <enumeratedValue>
                                    <name>10</name>
                                    <description>ONE ZERO</description>
                                    <value>#10</value>
                                </enumeratedValue>
                                <enumeratedValue>
                                    <name>11</name>
                                    <description>ALL ONE</description>
                                    <value>#11</value>
                                </enumeratedValue>
                            </enumeratedValues>
                        </field>
                        <field>
                            <name>PFEREN</name>
                            <description>Preface Error Enable</description>
                            <lsb>24</lsb>
                            <msb>24</msb>
                            <access>read-write</access>
                            <enumeratedValues>
                                <enumeratedValue>
                                    <name>0</name>
                                    <description>Does not handle a preface error as an interrupt source</description>
                                    <value>#0</value>
                                </enumeratedValue>
                                <enumeratedValue>
                                    <name>1</name>
                                    <description>Handles a preface error as an interrupt source</description>
                                    <value>#1</value>
                                </enumeratedValue>
                            </enumeratedValues>
                        </field>
                        <field>
                            <name>SYEREN</name>
                            <description>Receive SYNC Error Enable</description>
                            <lsb>25</lsb>
                            <msb>25</msb>
                            <access>read-write</access>
                            <enumeratedValues>
                                <enumeratedValue>
                                    <name>0</name>
                                    <description>Does not handle a receive SYNC error as an interrupt source</description>
                                    <value>#0</value>
                                </enumeratedValue>
                                <enumeratedValue>
                                    <name>1</name>
                                    <description>Handles a receive SYNC error as an interrupt source</description>
                                    <value>#1</value>
                                </enumeratedValue>
                            </enumeratedValues>
                        </field>
                        <field>
                            <name>SBEREN</name>
                            <description>Start Bit Error Enable</description>
                            <lsb>26</lsb>
                            <msb>26</msb>
                            <access>read-write</access>
                            <enumeratedValues>
                                <enumeratedValue>
                                    <name>0</name>
                                    <description>Does not handle a start bit error as an interrupt source</description>
                                    <value>#0</value>
                                </enumeratedValue>
                                <enumeratedValue>
                                    <name>1</name>
                                    <description>Handles a start bit error as an interrupt source</description>
                                    <value>#1</value>
                                </enumeratedValue>
                            </enumeratedValues>
                        </field>
                    </fields>
                </register>
                <register>
                    <name>DCR</name>
                    <description>Driver Control Register</description>
                    <addressOffset>0x30</addressOffset>
                    <size>32</size>
                    <access>read-write</access>
                    <resetValue>0x00000000</resetValue>
                    <resetMask>0xffffffff</resetMask>
                    <fields>
                        <field>
                            <name>DEPOL</name>
                            <description>Driver Effective Polarity Select</description>
                            <lsb>0</lsb>
                            <msb>0</msb>
                            <access>read-write</access>
                            <enumeratedValues>
                                <enumeratedValue>
                                    <name>0</name>
                                    <description>The DEn signal is active-high</description>
                                    <value>#0</value>
                                </enumeratedValue>
                                <enumeratedValue>
                                    <name>1</name>
                                    <description>The DEn signal is active-low</description>
                                    <value>#1</value>
                                </enumeratedValue>
                            </enumeratedValues>
                        </field>
                        <field>
                            <name>DEAST</name>
                            <description>Driver Assertion Time</description>
                            <lsb>8</lsb>
                            <msb>12</msb>
                            <access>read-write</access>
                        </field>
                        <field>
                            <name>DENGT</name>
                            <description>Driver Negate Time</description>
                            <lsb>16</lsb>
                            <msb>20</msb>
                            <access>read-write</access>
                        </field>
                    </fields>
                </register>
                <register>
                    <name>XCR0</name>
                    <description>Simple LIN Control Register 0</description>
                    <addressOffset>0x34</addressOffset>
                    <size>32</size>
                    <access>read-write</access>
                    <resetValue>0x00000000</resetValue>
                    <resetMask>0xffffffff</resetMask>
                    <fields>
                        <field>
                            <name>TCSS</name>
                            <description>Timer Count Clock Source Selection</description>
                            <lsb>0</lsb>
                            <msb>1</msb>
                            <access>read-write</access>
                            <enumeratedValues>
                                <enumeratedValue>
                                    <name>01</name>
                                    <description>TCLK/4</description>
                                    <value>#01</value>
                                </enumeratedValue>
                                <enumeratedValue>
                                    <name>10</name>
                                    <description>TCLK/16</description>
                                    <value>#10</value>
                                </enumeratedValue>
                                <enumeratedValue>
                                    <name>11</name>
                                    <description>TCLK/64</description>
                                    <value>#11</value>
                                </enumeratedValue>
                            </enumeratedValues>
                        </field>
                        <field>
                            <name>BFE</name>
                            <description>Break Field Enable</description>
                            <lsb>8</lsb>
                            <msb>8</msb>
                            <access>read-write</access>
                            <enumeratedValues>
                                <enumeratedValue>
                                    <name>0</name>
                                    <description>No Break Field</description>
                                    <value>#0</value>
                                </enumeratedValue>
                                <enumeratedValue>
                                    <name>1</name>
                                    <description>With Break Field</description>
                                    <value>#1</value>
                                </enumeratedValue>
                            </enumeratedValues>
                        </field>
                        <field>
                            <name>CF0RE</name>
                            <description>Control Field 0 Enable</description>
                            <lsb>9</lsb>
                            <msb>9</msb>
                            <access>read-write</access>
                            <enumeratedValues>
                                <enumeratedValue>
                                    <name>0</name>
                                    <description>No Control Field 0</description>
                                    <value>#0</value>
                                </enumeratedValue>
                                <enumeratedValue>
                                    <name>1</name>
                                    <description>With Control Field 0</description>
                                    <value>#1</value>
                                </enumeratedValue>
                            </enumeratedValues>
                        </field>
                        <field>
                            <name>CF1DS</name>
                            <description>Control Field1 Compare Data Select</description>
                            <lsb>10</lsb>
                            <msb>11</msb>
                            <access>read-write</access>
                            <enumeratedValues>
                                <enumeratedValue>
                                    <name>00</name>
                                    <description>Select XCR1.PCF1D[7:0] as the compare data</description>
                                    <value>#00</value>
                                </enumeratedValue>
                                <enumeratedValue>
                                    <name>01</name>
                                    <description>Select XCR1.SCF1D[7:0] as the compare data</description>
                                    <value>#01</value>
                                </enumeratedValue>
                                <enumeratedValue>
                                    <name>10</name>
                                    <description>Select both XCR1.PCF1D[7:0] and XCR1.SCF1D[7:0] as the compare data</description>
                                    <value>#10</value>
                                </enumeratedValue>
                                <enumeratedValue>
                                    <name>11</name>
                                    <description>Setting prohibited</description>
                                    <value>#11</value>
                                </enumeratedValue>
                            </enumeratedValues>
                        </field>
                        <field>
                            <name>PIBE</name>
                            <description>Priority Interrupt Bit Enable</description>
                            <lsb>12</lsb>
                            <msb>12</msb>
                            <access>read-write</access>
                            <enumeratedValues>
                                <enumeratedValue>
                                    <name>0</name>
                                    <description>Priority interrupt bit disabled</description>
                                    <value>#0</value>
                                </enumeratedValue>
                                <enumeratedValue>
                                    <name>1</name>
                                    <description>Priority interrupt bit enabled</description>
                                    <value>#1</value>
                                </enumeratedValue>
                            </enumeratedValues>
                        </field>
                        <field>
                            <name>PIBS</name>
                            <description>Priority Interrupt Bit Select</description>
                            <lsb>13</lsb>
                            <msb>15</msb>
                            <access>read-write</access>
                            <enumeratedValues>
                                <enumeratedValue>
                                    <name>000</name>
                                    <description>Bit 0 of Control Field 1</description>
                                    <value>#000</value>
                                </enumeratedValue>
                                <enumeratedValue>
                                    <name>001</name>
                                    <description>Bit 1 of Control Field 1</description>
                                    <value>#001</value>
                                </enumeratedValue>
                                <enumeratedValue>
                                    <name>010</name>
                                    <description>Bit 2 of Control Field 1</description>
                                    <value>#010</value>
                                </enumeratedValue>
                                <enumeratedValue>
                                    <name>011</name>
                                    <description>Bit 3 of Control Field 1</description>
                                    <value>#011</value>
                                </enumeratedValue>
                                <enumeratedValue>
                                    <name>100</name>
                                    <description>Bit 4 of Control Field 1</description>
                                    <value>#100</value>
                                </enumeratedValue>
                                <enumeratedValue>
                                    <name>101</name>
                                    <description>Bit 5 of Control Field 1</description>
                                    <value>#101</value>
                                </enumeratedValue>
                                <enumeratedValue>
                                    <name>110</name>
                                    <description>Bit 6 of Control Field 1</description>
                                    <value>#110</value>
                                </enumeratedValue>
                                <enumeratedValue>
                                    <name>111</name>
                                    <description>Bit 7 of Control Field 1</description>
                                    <value>#111</value>
                                </enumeratedValue>
                            </enumeratedValues>
                        </field>
                        <field>
                            <name>BFOIE</name>
                            <description>Break Field Output Completion Interrupt Enable</description>
                            <lsb>16</lsb>
                            <msb>16</msb>
                            <access>read-write</access>
                            <enumeratedValues>
                                <enumeratedValue>
                                    <name>0</name>
                                    <description>Break Field output completion is not included in SCIn_TXI interrupt factor</description>
                                    <value>#0</value>
                                </enumeratedValue>
                                <enumeratedValue>
                                    <name>1</name>
                                    <description>Break Field output completion is included in SCIn_TXI interrupt factor</description>
                                    <value>#1</value>
                                </enumeratedValue>
                            </enumeratedValues>
                        </field>
                        <field>
                            <name>BCDIE</name>
                            <description>Bus Conflict Detection Interrupt Enable</description>
                            <lsb>17</lsb>
                            <msb>17</msb>
                            <access>read-write</access>
                            <enumeratedValues>
                                <enumeratedValue>
                                    <name>0</name>
                                    <description>Bus conflict detection is not included in SCIn_ERI interrupt factor</description>
                                    <value>#0</value>
                                </enumeratedValue>
                                <enumeratedValue>
                                    <name>1</name>
                                    <description>Bus conflict detection is included in SCIn_ERI interrupt factor</description>
                                    <value>#1</value>
                                </enumeratedValue>
                            </enumeratedValues>
                        </field>
                        <field>
                            <name>BFDIE</name>
                            <description>Break Field Detection Interrupt Enable</description>
                            <lsb>20</lsb>
                            <msb>20</msb>
                            <access>read-write</access>
                            <enumeratedValues>
                                <enumeratedValue>
                                    <name>0</name>
                                    <description>Break Field detection interrupt disabled</description>
                                    <value>#0</value>
                                </enumeratedValue>
                                <enumeratedValue>
                                    <name>1</name>
                                    <description>Break Field detection interrupt enabled</description>
                                    <value>#1</value>
                                </enumeratedValue>
                            </enumeratedValues>
                        </field>
                        <field>
                            <name>COFIE</name>
                            <description>Counter Overflow Interrupt Enable</description>
                            <lsb>21</lsb>
                            <msb>21</msb>
                            <access>read-write</access>
                            <enumeratedValues>
                                <enumeratedValue>
                                    <name>0</name>
                                    <description>Counter overflow is not included in SCIn_ERI interrupt factor</description>
                                    <value>#0</value>
                                </enumeratedValue>
                                <enumeratedValue>
                                    <name>1</name>
                                    <description>Counter overflow is included in SCIn_ERI interrupt factor</description>
                                    <value>#1</value>
                                </enumeratedValue>
                            </enumeratedValues>
                        </field>
                        <field>
                            <name>AEDIE</name>
                            <description>Active Edge Detection Interrupt Enable</description>
                            <lsb>22</lsb>
                            <msb>22</msb>
                            <access>read-write</access>
                            <enumeratedValues>
                                <enumeratedValue>
                                    <name>0</name>
                                    <description>Active edge detection interrupt disabled</description>
                                    <value>#0</value>
                                </enumeratedValue>
                                <enumeratedValue>
                                    <name>1</name>
                                    <description>Active edge detection interrupt enabled</description>
                                    <value>#1</value>
                                </enumeratedValue>
                            </enumeratedValues>
                        </field>
                        <field>
                            <name>BCCS</name>
                            <description>Bus Conflict Detection Clock Selection</description>
                            <lsb>24</lsb>
                            <msb>25</msb>
                            <access>read-write</access>
                            <enumeratedValues>
                                <enumeratedValue>
                                    <name>00</name>
                                    <description>Base clock</description>
                                    <value>#00</value>
                                </enumeratedValue>
                                <enumeratedValue>
                                    <name>01</name>
                                    <description>Base clock/2</description>
                                    <value>#01</value>
                                </enumeratedValue>
                                <enumeratedValue>
                                    <name>10</name>
                                    <description>Base clock/4</description>
                                    <value>#10</value>
                                </enumeratedValue>
                                <enumeratedValue>
                                    <name>11</name>
                                    <description>Setting prohibited</description>
                                    <value>#11</value>
                                </enumeratedValue>
                            </enumeratedValues>
                        </field>
                    </fields>
                </register>
                <register>
                    <name>XCR1</name>
                    <description>Simple LIN Control Register 1</description>
                    <addressOffset>0x38</addressOffset>
                    <size>32</size>
                    <access>read-write</access>
                    <resetValue>0x00000000</resetValue>
                    <resetMask>0xffffffff</resetMask>
                    <fields>
                        <field>
                            <name>TCST</name>
                            <description>Break Field Output Timer Count Start Trigger</description>
                            <lsb>0</lsb>
                            <msb>0</msb>
                            <access>read-write</access>
                            <enumeratedValues>
                                <enumeratedValue>
                                    <name>0</name>
                                    <description>Break Field output timer count stopped</description>
                                    <value>#0</value>
                                </enumeratedValue>
                                <enumeratedValue>
                                    <name>1</name>
                                    <description>Break Field output timer count start</description>
                                    <value>#1</value>
                                </enumeratedValue>
                            </enumeratedValues>
                        </field>
                        <field>
                            <name>SDST</name>
                            <description>Start Frame Detection Enable</description>
                            <lsb>4</lsb>
                            <msb>4</msb>
                            <access>read-write</access>
                            <enumeratedValues>
                                <enumeratedValue>
                                    <name>0</name>
                                    <description>Start Frame/Break Field detection disabled</description>
                                    <value>#0</value>
                                </enumeratedValue>
                                <enumeratedValue>
                                    <name>1</name>
                                    <description>Start Frame/Break Field detection enabled</description>
                                    <value>#1</value>
                                </enumeratedValue>
                            </enumeratedValues>
                        </field>
                        <field>
                            <name>BMEN</name>
                            <description>Bit Rate Measurement Enable</description>
                            <lsb>5</lsb>
                            <msb>5</msb>
                            <access>read-write</access>
                            <enumeratedValues>
                                <enumeratedValue>
                                    <name>0</name>
                                    <description>Bit rate measurement disabled</description>
                                    <value>#0</value>
                                </enumeratedValue>
                                <enumeratedValue>
                                    <name>1</name>
                                    <description>Bit rate measurement enabled</description>
                                    <value>#1</value>
                                </enumeratedValue>
                            </enumeratedValues>
                        </field>
                        <field>
                            <name>PCF1D</name>
                            <description>Priority Compare Data for Control Field 1</description>
                            <lsb>8</lsb>
                            <msb>15</msb>
                            <access>read-write</access>
                        </field>
                        <field>
                            <name>SCF1D</name>
                            <description>Secondary Compare Data for Control Field 1</description>
                            <lsb>16</lsb>
                            <msb>23</msb>
                            <access>read-write</access>
                        </field>
                        <field>
                            <name>CF1CE</name>
                            <description>Control Field 1 Compare Bit Enable</description>
                            <lsb>24</lsb>
                            <msb>31</msb>
                            <access>read-write</access>
                            <enumeratedValues>
                                <enumeratedValue>
                                    <name>0</name>
                                    <description>Control Field 1 bit N compare disabled</description>
                                    <value>#0</value>
                                </enumeratedValue>
                                <enumeratedValue>
                                    <name>1</name>
                                    <description>Control Field 1 bit N compare enabled</description>
                                    <value>#1</value>
                                </enumeratedValue>
                            </enumeratedValues>
                        </field>
                    </fields>
                </register>
                <register>
                    <name>XCR2</name>
                    <description>Simple LIN Control Register 2</description>
                    <addressOffset>0x3C</addressOffset>
                    <size>32</size>
                    <access>read-write</access>
                    <resetValue>0xfffe0000</resetValue>
                    <resetMask>0xffffffff</resetMask>
                    <fields>
                        <field>
                            <name>CF0D</name>
                            <description>Control Field 0 Compare Data</description>
                            <lsb>0</lsb>
                            <msb>7</msb>
                            <access>read-write</access>
                        </field>
                        <field>
                            <name>CF0CE</name>
                            <description>Control Field 0 Compare Bit Enable</description>
                            <lsb>8</lsb>
                            <msb>15</msb>
                            <access>read-write</access>
                            <enumeratedValues>
                                <enumeratedValue>
                                    <name>0</name>
                                    <description>Control Field 0 bit N compare disabled</description>
                                    <value>#0</value>
                                </enumeratedValue>
                                <enumeratedValue>
                                    <name>1</name>
                                    <description>Control Field 0 bit N compare enabled</description>
                                    <value>#1</value>
                                </enumeratedValue>
                            </enumeratedValues>
                        </field>
                        <field>
                            <name>BFLW</name>
                            <description>Break Field Length Setting</description>
                            <lsb>16</lsb>
                            <msb>31</msb>
                            <access>read-write</access>
                        </field>
                    </fields>
                </register>
                <register>
                    <name>CSR</name>
                    <description>Common Status Register</description>
                    <addressOffset>0x48</addressOffset>
                    <size>32</size>
                    <access>read-only</access>
                    <resetValue>0x60008000</resetValue>
                    <resetMask>0xffffffff</resetMask>
                    <fields>
                        <field>
                            <name>ERS</name>
                            <description>Error Signal Status Flag</description>
                            <lsb>4</lsb>
                            <msb>4</msb>
                            <access>read-only</access>
                            <enumeratedValues>
                                <enumeratedValue>
                                    <name>0</name>
                                    <description>Error signal low not responded</description>
                                    <value>#0</value>
                                </enumeratedValue>
                                <enumeratedValue>
                                    <name>1</name>
                                    <description>Error signal low responded</description>
                                    <value>#1</value>
                                </enumeratedValue>
                            </enumeratedValues>
                        </field>
                        <field>
                            <name>RXDMON</name>
                            <description>Serial Input Data Monitor Bit</description>
                            <lsb>15</lsb>
                            <msb>15</msb>
                            <access>read-only</access>
                            <enumeratedValues>
                                <enumeratedValue>
                                    <name>0</name>
                                    <description>When RINV is 0, RXDn pin is the low level. When RINV is 1, RXDn pin is the high level. </description>
                                    <value>#0</value>
                                </enumeratedValue>
                                <enumeratedValue>
                                    <name>1</name>
                                    <description>When RINV is 0, RXDn pin is the high level. When RINV is 1, RXDn pin is the low level. </description>
                                    <value>#1</value>
                                </enumeratedValue>
                            </enumeratedValues>
                        </field>
                        <field>
                            <name>DCMF</name>
                            <description>Data Compare Match Flag</description>
                            <lsb>16</lsb>
                            <msb>16</msb>
                            <access>read-only</access>
                            <enumeratedValues>
                                <enumeratedValue>
                                    <name>0</name>
                                    <description>No matched</description>
                                    <value>#0</value>
                                </enumeratedValue>
                                <enumeratedValue>
                                    <name>1</name>
                                    <description>Matched</description>
                                    <value>#1</value>
                                </enumeratedValue>
                            </enumeratedValues>
                        </field>
                        <field>
                            <name>DPER</name>
                            <description>Data Compare Match Parity Error Flag</description>
                            <lsb>17</lsb>
                            <msb>17</msb>
                            <access>read-only</access>
                            <enumeratedValues>
                                <enumeratedValue>
                                    <name>0</name>
                                    <description>No parity error occurred at address match detection</description>
                                    <value>#0</value>
                                </enumeratedValue>
                                <enumeratedValue>
                                    <name>1</name>
                                    <description>A parity error has occurred at address match detection</description>
                                    <value>#1</value>
                                </enumeratedValue>
                            </enumeratedValues>
                        </field>
                        <field>
                            <name>DFER</name>
                            <description>Data Compare Match Framing Error Flag</description>
                            <lsb>18</lsb>
                            <msb>18</msb>
                            <access>read-only</access>
                            <enumeratedValues>
                                <enumeratedValue>
                                    <name>0</name>
                                    <description>No framing error occurred at address match detection</description>
                                    <value>#0</value>
                                </enumeratedValue>
                                <enumeratedValue>
                                    <name>1</name>
                                    <description>A framing error has occurred at address match detection</description>
                                    <value>#1</value>
                                </enumeratedValue>
                            </enumeratedValues>
                        </field>
                        <field>
                            <name>ORER</name>
                            <description>Overrun Error Flag</description>
                            <lsb>24</lsb>
                            <msb>24</msb>
                            <access>read-only</access>
                            <enumeratedValues>
                                <enumeratedValue>
                                    <name>0</name>
                                    <description>No overrun error occurred</description>
                                    <value>#0</value>
                                </enumeratedValue>
                                <enumeratedValue>
                                    <name>1</name>
                                    <description>An overrun error has occurred</description>
                                    <value>#1</value>
                                </enumeratedValue>
                            </enumeratedValues>
                        </field>
                        <field>
                            <name>MFF</name>
                            <description>Mode Fault Error Flag</description>
                            <lsb>26</lsb>
                            <msb>26</msb>
                            <access>read-only</access>
                            <enumeratedValues>
                                <enumeratedValue>
                                    <name>0</name>
                                    <description>No mode fault error</description>
                                    <value>#0</value>
                                </enumeratedValue>
                                <enumeratedValue>
                                    <name>1</name>
                                    <description>Mode fault error</description>
                                    <value>#1</value>
                                </enumeratedValue>
                            </enumeratedValues>
                        </field>
                        <field>
                            <name>PER</name>
                            <description>Parity Error Flag</description>
                            <lsb>27</lsb>
                            <msb>27</msb>
                            <access>read-only</access>
                            <enumeratedValues>
                                <enumeratedValue>
                                    <name>0</name>
                                    <description>Non-FIFO selected (CCR3.FM = 0): No parity error occurred FIFO selected (CCR3.FM = 1): No parity error in all received data in receive-FIFO </description>
                                    <value>#0</value>
                                </enumeratedValue>
                                <enumeratedValue>
                                    <name>1</name>
                                    <description>Non-FIFO selected (CCR3.FM = 0): A parity error has occurred FIFO selected (CCR3.FM = 1): One or more parity errors occurred in received data in receive-FIFO </description>
                                    <value>#1</value>
                                </enumeratedValue>
                            </enumeratedValues>
                        </field>
                        <field>
                            <name>FER</name>
                            <description>Framing Error Flag</description>
                            <lsb>28</lsb>
                            <msb>28</msb>
                            <access>read-only</access>
                            <enumeratedValues>
                                <enumeratedValue>
                                    <name>0</name>
                                    <description>Non-FIFO selected (CCR3.FM = 0): No framing error occurred FIFO selected (CCR3.FM = 1): No framing error in all received data in receive-FIFO </description>
                                    <value>#0</value>
                                </enumeratedValue>
                                <enumeratedValue>
                                    <name>1</name>
                                    <description>Non-FIFO selected (CCR3.FM = 0): A framing error has occurred FIFO selected (CCR3.FM = 1): One or more framing errors occurred in received data in receive-FIFO </description>
                                    <value>#1</value>
                                </enumeratedValue>
                            </enumeratedValues>
                        </field>
                        <field>
                            <name>TDRE</name>
                            <description>Transmit Data Empty Flag</description>
                            <lsb>29</lsb>
                            <msb>29</msb>
                            <access>read-only</access>
                            <enumeratedValues>
                                <enumeratedValue>
                                    <name>0</name>
                                    <description>Non-FIFO selected (CCR3.FM = 0): Transmit data is in TDR register FIFO selected (CCR3.FM = 1): The quantity of transmit data written in transmit-FIFO exceeds the specified transmit triggering number. </description>
                                    <value>#0</value>
                                </enumeratedValue>
                                <enumeratedValue>
                                    <name>1</name>
                                    <description>Non-FIFO selected (CCR3.FM = 0): No transmit data is in TDR register FIFO selected (CCR3.FM = 1): The quantity of transmit data written in transmit-FIFO is equal to or less than the specified transmit triggering number. </description>
                                    <value>#1</value>
                                </enumeratedValue>
                            </enumeratedValues>
                        </field>
                        <field>
                            <name>TEND</name>
                            <description>Transmit End Flag</description>
                            <lsb>30</lsb>
                            <msb>30</msb>
                            <access>read-only</access>
                            <enumeratedValues>
                                <enumeratedValue>
                                    <name>0</name>
                                    <description>A character is being transmitted or standing by for transmission.</description>
                                    <value>#0</value>
                                </enumeratedValue>
                                <enumeratedValue>
                                    <name>1</name>
                                    <description>Character transfer has been completed, or sending Break Field.</description>
                                    <value>#1</value>
                                </enumeratedValue>
                            </enumeratedValues>
                        </field>
                        <field>
                            <name>RDRF</name>
                            <description>Receive Data Full Flag</description>
                            <lsb>31</lsb>
                            <msb>31</msb>
                            <access>read-only</access>
                            <enumeratedValues>
                                <enumeratedValue>
                                    <name>0</name>
                                    <description>Non-FIFO selected (CCR3.FM = 0): No received data is in RDR register FIFO selected (CCR3.FM = 1): The quantity of receive data written in receive-FIFO falls below the specified receive triggering number. </description>
                                    <value>#0</value>
                                </enumeratedValue>
                                <enumeratedValue>
                                    <name>1</name>
                                    <description>Non-FIFO selected (CCR3.FM = 0): Received data is in RDR register FIFO selected (CCR3.FM = 1): The quantity of receive data written in receive-FIFO is equal to or greater than the specified receive triggering number. </description>
                                    <value>#1</value>
                                </enumeratedValue>
                            </enumeratedValues>
                        </field>
                    </fields>
                </register>
                <register>
                    <name>ISR</name>
                    <description>Simple IIC Status Register</description>
                    <addressOffset>0x4C</addressOffset>
                    <size>32</size>
                    <access>read-only</access>
                    <resetValue>0x00000000</resetValue>
                    <resetMask>0xffffffff</resetMask>
                    <fields>
                        <field>
                            <name>IICACKR</name>
                            <description>ACK Reception Data Flag</description>
                            <lsb>0</lsb>
                            <msb>0</msb>
                            <access>read-only</access>
                            <enumeratedValues>
                                <enumeratedValue>
                                    <name>0</name>
                                    <description>ACK received</description>
                                    <value>#0</value>
                                </enumeratedValue>
                                <enumeratedValue>
                                    <name>1</name>
                                    <description>NACK received</description>
                                    <value>#1</value>
                                </enumeratedValue>
                            </enumeratedValues>
                        </field>
                        <field>
                            <name>IICSTIF</name>
                            <description>Issuing of Start, Restart, or Stop Condition Completed Flag</description>
                            <lsb>3</lsb>
                            <msb>3</msb>
                            <access>read-only</access>
                            <enumeratedValues>
                                <enumeratedValue>
                                    <name>0</name>
                                    <description>There are no requests for generating conditions or a condition is being generated.</description>
                                    <value>#0</value>
                                </enumeratedValue>
                                <enumeratedValue>
                                    <name>1</name>
                                    <description>A start, restart, or stop condition is completely generated.</description>
                                    <value>#1</value>
                                </enumeratedValue>
                            </enumeratedValues>
                        </field>
                    </fields>
                </register>
                <register>
                    <name>FRSR</name>
                    <description>FIFO Receive Status Register</description>
                    <addressOffset>0x50</addressOffset>
                    <size>32</size>
                    <access>read-only</access>
                    <resetValue>0x00000000</resetValue>
                    <resetMask>0xfffffffd</resetMask>
                    <fields>
                        <field>
                            <name>DR</name>
                            <description>Receive Data Ready Flag</description>
                            <lsb>0</lsb>
                            <msb>0</msb>
                            <access>read-only</access>
                            <enumeratedValues>
                                <enumeratedValue>
                                    <name>0</name>
                                    <description>Receiving is in progress, or no received data remains in the receive-FIFO after a successful reception (receive-FIFO is empty)</description>
                                    <value>#0</value>
                                </enumeratedValue>
                                <enumeratedValue>
                                    <name>1</name>
                                    <description>The following receive data is not received for a fixed period after storing data under the threshold in the receive-FIFO</description>
                                    <value>#1</value>
                                </enumeratedValue>
                            </enumeratedValues>
                        </field>
                        <field>
                            <name>R</name>
                            <description>Receive-FIFO Data Count</description>
                            <lsb>8</lsb>
                            <msb>13</msb>
                            <access>read-only</access>
                        </field>
                        <field>
                            <name>PNUM</name>
                            <description>Parity Error Count</description>
                            <lsb>16</lsb>
                            <msb>21</msb>
                            <access>read-only</access>
                        </field>
                        <field>
                            <name>FNUM</name>
                            <description>Framing Error Count</description>
                            <lsb>24</lsb>
                            <msb>29</msb>
                            <access>read-only</access>
                        </field>
                    </fields>
                </register>
                <register>
                    <name>FTSR</name>
                    <description>FIFO Transmit Status Register</description>
                    <addressOffset>0x54</addressOffset>
                    <size>32</size>
                    <access>read-only</access>
                    <resetValue>0x00000000</resetValue>
                    <resetMask>0xffffffff</resetMask>
                    <fields>
                        <field>
                            <name>T</name>
                            <description>Transmit-FIFO Data Count</description>
                            <lsb>0</lsb>
                            <msb>5</msb>
                            <access>read-only</access>
                        </field>
                    </fields>
                </register>
                <register>
                    <name>MSR</name>
                    <description>Manchester Status Register</description>
                    <addressOffset>0x58</addressOffset>
                    <size>32</size>
                    <access>read-only</access>
                    <resetValue>0x00000000</resetValue>
                    <resetMask>0xffffffff</resetMask>
                    <fields>
                        <field>
                            <name>PFER</name>
                            <description>Preface Error Flag</description>
                            <lsb>0</lsb>
                            <msb>0</msb>
                            <access>read-only</access>
                            <enumeratedValues>
                                <enumeratedValue>
                                    <name>0</name>
                                    <description>No preface error detected</description>
                                    <value>#0</value>
                                </enumeratedValue>
                                <enumeratedValue>
                                    <name>1</name>
                                    <description>Preface error detected</description>
                                    <value>#1</value>
                                </enumeratedValue>
                            </enumeratedValues>
                        </field>
                        <field>
                            <name>SYER</name>
                            <description>SYNC Error Flag</description>
                            <lsb>1</lsb>
                            <msb>1</msb>
                            <access>read-only</access>
                            <enumeratedValues>
                                <enumeratedValue>
                                    <name>0</name>
                                    <description>No receive SYNC error detected</description>
                                    <value>#0</value>
                                </enumeratedValue>
                                <enumeratedValue>
                                    <name>1</name>
                                    <description>Receive SYNC error detected</description>
                                    <value>#1</value>
                                </enumeratedValue>
                            </enumeratedValues>
                        </field>
                        <field>
                            <name>SBER</name>
                            <description>Start Bit Error Flag</description>
                            <lsb>2</lsb>
                            <msb>2</msb>
                            <access>read-only</access>
                            <enumeratedValues>
                                <enumeratedValue>
                                    <name>0</name>
                                    <description>No start bit error detected</description>
                                    <value>#0</value>
                                </enumeratedValue>
                                <enumeratedValue>
                                    <name>1</name>
                                    <description>Start bit error detected</description>
                                    <value>#1</value>
                                </enumeratedValue>
                            </enumeratedValues>
                        </field>
                        <field>
                            <name>MER</name>
                            <description>Manchester Error Flag</description>
                            <lsb>4</lsb>
                            <msb>4</msb>
                            <access>read-only</access>
                            <enumeratedValues>
                                <enumeratedValue>
                                    <name>0</name>
                                    <description>No Manchester error occurred</description>
                                    <value>#0</value>
                                </enumeratedValue>
                                <enumeratedValue>
                                    <name>1</name>
                                    <description>Manchester error has occurred</description>
                                    <value>#1</value>
                                </enumeratedValue>
                            </enumeratedValues>
                        </field>
                        <field>
                            <name>RSYNC</name>
                            <description>Receive SYNC Data Bit</description>
                            <lsb>6</lsb>
                            <msb>6</msb>
                            <access>read-only</access>
                            <enumeratedValues>
                                <enumeratedValue>
                                    <name>0</name>
                                    <description>The received start bit is DATA SYNC</description>
                                    <value>#0</value>
                                </enumeratedValue>
                                <enumeratedValue>
                                    <name>1</name>
                                    <description>The received start bit is COMMAND SYNC</description>
                                    <value>#1</value>
                                </enumeratedValue>
                            </enumeratedValues>
                        </field>
                    </fields>
                </register>
                <register>
                    <name>XSR0</name>
                    <description>Simple LIN Status Register 0</description>
                    <addressOffset>0x5C</addressOffset>
                    <size>32</size>
                    <access>read-only</access>
                    <resetValue>0x00000000</resetValue>
                    <resetMask>0xffffffff</resetMask>
                    <fields>
                        <field>
                            <name>SFSF</name>
                            <description>Start Frame Status Flag</description>
                            <lsb>0</lsb>
                            <msb>0</msb>
                            <access>read-only</access>
                            <enumeratedValues>
                                <enumeratedValue>
                                    <name>0</name>
                                    <description>Start Frame detection disabled or Start Frame detection complete</description>
                                    <value>#0</value>
                                </enumeratedValue>
                                <enumeratedValue>
                                    <name>1</name>
                                    <description>Before Start Frame detection or during detection</description>
                                    <value>#1</value>
                                </enumeratedValue>
                            </enumeratedValues>
                        </field>
                        <field>
                            <name>RXDSF</name>
                            <description>RXDn Input Status Flag</description>
                            <lsb>1</lsb>
                            <msb>1</msb>
                            <access>read-only</access>
                            <enumeratedValues>
                                <enumeratedValue>
                                    <name>0</name>
                                    <description>RXDn input to SCI is enabled</description>
                                    <value>#0</value>
                                </enumeratedValue>
                                <enumeratedValue>
                                    <name>1</name>
                                    <description>RXDn input to SCI is disabled</description>
                                    <value>#1</value>
                                </enumeratedValue>
                            </enumeratedValues>
                        </field>
                        <field>
                            <name>BFOF</name>
                            <description>Break Field Output Completion Flag</description>
                            <lsb>8</lsb>
                            <msb>8</msb>
                            <access>read-only</access>
                            <enumeratedValues>
                                <enumeratedValue>
                                    <name>0</name>
                                    <description>Break Field is being output or is not being output</description>
                                    <value>#0</value>
                                </enumeratedValue>
                                <enumeratedValue>
                                    <name>1</name>
                                    <description>Completed BF output</description>
                                    <value>#1</value>
                                </enumeratedValue>
                            </enumeratedValues>
                        </field>
                        <field>
                            <name>BCDF</name>
                            <description>Bus Conflict Detection Flag</description>
                            <lsb>9</lsb>
                            <msb>9</msb>
                            <access>read-only</access>
                            <enumeratedValues>
                                <enumeratedValue>
                                    <name>0</name>
                                    <description>No bus collision detected</description>
                                    <value>#0</value>
                                </enumeratedValue>
                                <enumeratedValue>
                                    <name>1</name>
                                    <description>Detected a bus collision</description>
                                    <value>#1</value>
                                </enumeratedValue>
                            </enumeratedValues>
                        </field>
                        <field>
                            <name>BFDF</name>
                            <description>Break Field Detection Flag</description>
                            <lsb>10</lsb>
                            <msb>10</msb>
                            <access>read-only</access>
                            <enumeratedValues>
                                <enumeratedValue>
                                    <name>0</name>
                                    <description>Break Field is not detected</description>
                                    <value>#0</value>
                                </enumeratedValue>
                                <enumeratedValue>
                                    <name>1</name>
                                    <description>Break Field is detected</description>
                                    <value>#1</value>
                                </enumeratedValue>
                            </enumeratedValues>
                        </field>
                        <field>
                            <name>CF0MF</name>
                            <description>Control Field 0 Compare Match Flag</description>
                            <lsb>11</lsb>
                            <msb>11</msb>
                            <access>read-only</access>
                            <enumeratedValues>
                                <enumeratedValue>
                                    <name>0</name>
                                    <description>Control Field 0 received data does not match the setting data</description>
                                    <value>#0</value>
                                </enumeratedValue>
                                <enumeratedValue>
                                    <name>1</name>
                                    <description>Control Field 0 received data matches the setting data</description>
                                    <value>#1</value>
                                </enumeratedValue>
                            </enumeratedValues>
                        </field>
                        <field>
                            <name>CF1MF</name>
                            <description>Control Field 1 Compare Match Flag</description>
                            <lsb>12</lsb>
                            <msb>12</msb>
                            <access>read-only</access>
                            <enumeratedValues>
                                <enumeratedValue>
                                    <name>0</name>
                                    <description>Control Field 1 received data does not match the setting data</description>
                                    <value>#0</value>
                                </enumeratedValue>
                                <enumeratedValue>
                                    <name>1</name>
                                    <description>Control Field 1 received data matches the setting data</description>
                                    <value>#1</value>
                                </enumeratedValue>
                            </enumeratedValues>
                        </field>
                        <field>
                            <name>PIBDF</name>
                            <description>Priority Interrupt Bit Detection Flag</description>
                            <lsb>13</lsb>
                            <msb>13</msb>
                            <access>read-only</access>
                            <enumeratedValues>
                                <enumeratedValue>
                                    <name>0</name>
                                    <description>Priority interrupt bit is not detected</description>
                                    <value>#0</value>
                                </enumeratedValue>
                                <enumeratedValue>
                                    <name>1</name>
                                    <description>Priority interrupt bit is detected</description>
                                    <value>#1</value>
                                </enumeratedValue>
                            </enumeratedValues>
                        </field>
                        <field>
                            <name>COF</name>
                            <description>Counter Overflow Flag</description>
                            <lsb>14</lsb>
                            <msb>14</msb>
                            <access>read-only</access>
                            <enumeratedValues>
                                <enumeratedValue>
                                    <name>0</name>
                                    <description>Break Field detection counter has not overflowed</description>
                                    <value>#0</value>
                                </enumeratedValue>
                                <enumeratedValue>
                                    <name>1</name>
                                    <description>Break Field detection counter overflowed</description>
                                    <value>#1</value>
                                </enumeratedValue>
                            </enumeratedValues>
                        </field>
                        <field>
                            <name>AEDF</name>
                            <description>Active Edge Detection Flag</description>
                            <lsb>15</lsb>
                            <msb>15</msb>
                            <access>read-only</access>
                            <enumeratedValues>
                                <enumeratedValue>
                                    <name>0</name>
                                    <description>No valid edge detected</description>
                                    <value>#0</value>
                                </enumeratedValue>
                                <enumeratedValue>
                                    <name>1</name>
                                    <description>Detected a valid edge</description>
                                    <value>#1</value>
                                </enumeratedValue>
                            </enumeratedValues>
                        </field>
                        <field>
                            <name>CF0RD</name>
                            <description>Control Field 0 received data</description>
                            <lsb>16</lsb>
                            <msb>23</msb>
                            <access>read-only</access>
                        </field>
                        <field>
                            <name>CF1RD</name>
                            <description>Control Field 1 received data</description>
                            <lsb>24</lsb>
                            <msb>31</msb>
                            <access>read-only</access>
                        </field>
                    </fields>
                </register>
                <register>
                    <name>XSR1</name>
                    <description>Simple LIN Status Register 1</description>
                    <addressOffset>0x60</addressOffset>
                    <size>32</size>
                    <access>read-only</access>
                    <resetValue>0x00000000</resetValue>
                    <resetMask>0xffffffff</resetMask>
                    <fields>
                        <field>
                            <name>TCNT</name>
                            <description>Timer Count Capture Value</description>
                            <lsb>0</lsb>
                            <msb>15</msb>
                            <access>read-only</access>
                        </field>
                    </fields>
                </register>
                <register>
                    <name>CFCLR</name>
                    <description>Common Flag Clear Register</description>
                    <addressOffset>0x68</addressOffset>
                    <size>32</size>
                    <access>write-only</access>
                    <resetValue>0x00000000</resetValue>
                    <resetMask>0xffffffff</resetMask>
                    <fields>
                        <field>
                            <name>ERSC</name>
                            <description>ERS Clear Bit</description>
                            <lsb>4</lsb>
                            <msb>4</msb>
                            <access>write-only</access>
                        </field>
                        <field>
                            <name>DCMFC</name>
                            <description>DCMF Clear Bit</description>
                            <lsb>16</lsb>
                            <msb>16</msb>
                            <access>write-only</access>
                        </field>
                        <field>
                            <name>DPERC</name>
                            <description>DPER Clear Bit</description>
                            <lsb>17</lsb>
                            <msb>17</msb>
                            <access>write-only</access>
                        </field>
                        <field>
                            <name>DFERC</name>
                            <description>DFER Clear Bit</description>
                            <lsb>18</lsb>
                            <msb>18</msb>
                            <access>write-only</access>
                        </field>
                        <field>
                            <name>ORERC</name>
                            <description>ORER Clear Bit</description>
                            <lsb>24</lsb>
                            <msb>24</msb>
                            <access>write-only</access>
                        </field>
                        <field>
                            <name>MFFC</name>
                            <description>MFF Clear Bit</description>
                            <lsb>26</lsb>
                            <msb>26</msb>
                            <access>write-only</access>
                        </field>
                        <field>
                            <name>PERC</name>
                            <description>PER Clear Bit</description>
                            <lsb>27</lsb>
                            <msb>27</msb>
                            <access>write-only</access>
                        </field>
                        <field>
                            <name>FERC</name>
                            <description>FER Clear Bit</description>
                            <lsb>28</lsb>
                            <msb>28</msb>
                            <access>write-only</access>
                        </field>
                        <field>
                            <name>TDREC</name>
                            <description>TDRE Clear Bit</description>
                            <lsb>29</lsb>
                            <msb>29</msb>
                            <access>write-only</access>
                        </field>
                        <field>
                            <name>RDRFC</name>
                            <description>RDRF Clear Bit</description>
                            <lsb>31</lsb>
                            <msb>31</msb>
                            <access>write-only</access>
                        </field>
                    </fields>
                </register>
                <register>
                    <name>ICFCLR</name>
                    <description>Simple IIC Flag Clear Register</description>
                    <addressOffset>0x6C</addressOffset>
                    <size>32</size>
                    <access>write-only</access>
                    <resetValue>0x00000000</resetValue>
                    <resetMask>0xffffffff</resetMask>
                    <fields>
                        <field>
                            <name>IICSTIFC</name>
                            <description>IICSTIF Clear Bit</description>
                            <lsb>3</lsb>
                            <msb>3</msb>
                            <access>write-only</access>
                        </field>
                    </fields>
                </register>
                <register>
                    <name>FFCLR</name>
                    <description>FIFO Flag Clear Register</description>
                    <addressOffset>0x70</addressOffset>
                    <size>32</size>
                    <access>write-only</access>
                    <resetValue>0x00000000</resetValue>
                    <resetMask>0xffffffff</resetMask>
                    <fields>
                        <field>
                            <name>DRC</name>
                            <description>DR Clear Bit</description>
                            <lsb>0</lsb>
                            <msb>0</msb>
                            <access>write-only</access>
                        </field>
                    </fields>
                </register>
                <register>
                    <name>MFCLR</name>
                    <description>Manchester Flag Clear Register</description>
                    <addressOffset>0x74</addressOffset>
                    <size>32</size>
                    <access>write-only</access>
                    <resetValue>0x00000000</resetValue>
                    <resetMask>0xffffffff</resetMask>
                    <fields>
                        <field>
                            <name>PFERC</name>
                            <description>PFER Clear Bit</description>
                            <lsb>0</lsb>
                            <msb>0</msb>
                            <access>write-only</access>
                        </field>
                        <field>
                            <name>SYERC</name>
                            <description>SYER Clear Bit</description>
                            <lsb>1</lsb>
                            <msb>1</msb>
                            <access>write-only</access>
                        </field>
                        <field>
                            <name>SBERC</name>
                            <description>SBER Clear Bit</description>
                            <lsb>2</lsb>
                            <msb>2</msb>
                            <access>write-only</access>
                        </field>
                        <field>
                            <name>MERC</name>
                            <description>MER Clear Bit</description>
                            <lsb>4</lsb>
                            <msb>4</msb>
                            <access>write-only</access>
                        </field>
                    </fields>
                </register>
                <register>
                    <name>XFCLR</name>
                    <description>Simple LIN Flag Clear Register</description>
                    <addressOffset>0x78</addressOffset>
                    <size>32</size>
                    <access>write-only</access>
                    <resetValue>0x00000000</resetValue>
                    <resetMask>0xffffffff</resetMask>
                    <fields>
                        <field>
                            <name>BFOC</name>
                            <description>BFOF Clear Bit</description>
                            <lsb>8</lsb>
                            <msb>8</msb>
                            <access>write-only</access>
                        </field>
                        <field>
                            <name>BCDC</name>
                            <description>BCDF Clear Bit</description>
                            <lsb>9</lsb>
                            <msb>9</msb>
                            <access>write-only</access>
                        </field>
                        <field>
                            <name>BFDC</name>
                            <description>BFDF Clear Bit</description>
                            <lsb>10</lsb>
                            <msb>10</msb>
                            <access>write-only</access>
                        </field>
                        <field>
                            <name>CF0MC</name>
                            <description>CF0MF Clear Bit</description>
                            <lsb>11</lsb>
                            <msb>11</msb>
                            <access>write-only</access>
                        </field>
                        <field>
                            <name>CF1MC</name>
                            <description>CF1MF Clear Bit</description>
                            <lsb>12</lsb>
                            <msb>12</msb>
                            <access>write-only</access>
                        </field>
                        <field>
                            <name>PIBDC</name>
                            <description>PIBDF Clear Bit</description>
                            <lsb>13</lsb>
                            <msb>13</msb>
                            <access>write-only</access>
                        </field>
                        <field>
                            <name>COFC</name>
                            <description>COFF Clear Bit</description>
                            <lsb>14</lsb>
                            <msb>14</msb>
                            <access>write-only</access>
                        </field>
                        <field>
                            <name>AEDC</name>
                            <description>AEDF Clear Bit</description>
                            <lsb>15</lsb>
                            <msb>15</msb>
                            <access>write-only</access>
                        </field>
                    </fields>
                </register>
            </registers>
        </peripheral>
        <peripheral derivedFrom="SCI0_B_NS">
            <name>SCI1_B_NS</name>
            <description>Serial Communication Interface 1</description>
            <baseAddress>0x50358100</baseAddress>
        </peripheral>
        <peripheral derivedFrom="SCI0_B_NS">
            <name>SCI2_B_NS</name>
            <description>Serial Communication Interface 2</description>
            <baseAddress>0x50358200</baseAddress>
        </peripheral>
        <peripheral derivedFrom="SCI0_B_NS">
            <name>SCI3_B_NS</name>
            <description>Serial Communication Interface 3</description>
            <baseAddress>0x50358300</baseAddress>
        </peripheral>
        <peripheral derivedFrom="SCI0_B_NS">
            <name>SCI4_B_NS</name>
            <description>Serial Communication Interface 4</description>
            <baseAddress>0x50358400</baseAddress>
        </peripheral>
        <peripheral derivedFrom="SCI0_B_NS">
            <name>SCI9_B_NS</name>
            <description>Serial Communication Interface 9</description>
            <baseAddress>0x50358900</baseAddress>
        </peripheral>
        <peripheral>
            <name>SPI0_B_NS</name>
            <description>Serial Peripheral Interface 0</description>
            <baseAddress>0x5035C000</baseAddress>
            <addressBlock>
                <offset>0x00</offset>
                <size>52</size>
                <usage>registers</usage>
            </addressBlock>
            <addressBlock>
                <offset>0x40</offset>
                <size>8</size>
                <usage>registers</usage>
            </addressBlock>
            <addressBlock>
                <offset>0x50</offset>
                <size>4</size>
                <usage>registers</usage>
            </addressBlock>
            <addressBlock>
                <offset>0x58</offset>
                <size>12</size>
                <usage>registers</usage>
            </addressBlock>
            <addressBlock>
                <offset>0x68</offset>
                <size>8</size>
                <usage>registers</usage>
            </addressBlock>
            <registers>
                <register>
                    <name>SPDR</name>
                    <description>SPI Data Register</description>
                    <addressOffset>0x00</addressOffset>
                    <size>32</size>
                    <access>read-write</access>
                    <resetValue>0x00000000</resetValue>
                    <resetMask>0xffffffff</resetMask>
                    <fields>
                        <field>
                            <name>SPD</name>
                            <description>These bits are the interface with the buffers that hold data for transmission and reception by the SPI.</description>
                            <lsb>0</lsb>
                            <msb>31</msb>
                            <access>read-write</access>
                        </field>
                    </fields>
                </register>
                <register>
                    <name>SPDECR</name>
                    <description>SPI Delay Control Register</description>
                    <addressOffset>0x04</addressOffset>
                    <size>32</size>
                    <access>read-write</access>
                    <resetValue>0x00000000</resetValue>
                    <resetMask>0xffffffff</resetMask>
                    <fields>
                        <field>
                            <name>SCKDL</name>
                            <description>RSPCK Delay</description>
                            <lsb>0</lsb>
                            <msb>2</msb>
                            <access>read-write</access>
                            <enumeratedValues>
                                <enumeratedValue>
                                    <name>000</name>
                                    <description>1RSPCK</description>
                                    <value>#000</value>
                                </enumeratedValue>
                                <enumeratedValue>
                                    <name>001</name>
                                    <description>2RSPCK</description>
                                    <value>#001</value>
                                </enumeratedValue>
                                <enumeratedValue>
                                    <name>010</name>
                                    <description>3RSPCK</description>
                                    <value>#010</value>
                                </enumeratedValue>
                                <enumeratedValue>
                                    <name>011</name>
                                    <description>4RSPCK</description>
                                    <value>#011</value>
                                </enumeratedValue>
                                <enumeratedValue>
                                    <name>100</name>
                                    <description>5RSPCK</description>
                                    <value>#100</value>
                                </enumeratedValue>
                                <enumeratedValue>
                                    <name>101</name>
                                    <description>6RSPCK</description>
                                    <value>#101</value>
                                </enumeratedValue>
                                <enumeratedValue>
                                    <name>110</name>
                                    <description>7RSPCK</description>
                                    <value>#110</value>
                                </enumeratedValue>
                                <enumeratedValue>
                                    <name>111</name>
                                    <description>8RSPCK</description>
                                    <value>#111</value>
                                </enumeratedValue>
                            </enumeratedValues>
                        </field>
                        <field>
                            <name>SLNDL</name>
                            <description>SSL Negation Delay</description>
                            <lsb>8</lsb>
                            <msb>10</msb>
                            <access>read-write</access>
                            <enumeratedValues>
                                <enumeratedValue>
                                    <name>000</name>
                                    <description>1RSPCK</description>
                                    <value>#000</value>
                                </enumeratedValue>
                                <enumeratedValue>
                                    <name>001</name>
                                    <description>2RSPCK</description>
                                    <value>#001</value>
                                </enumeratedValue>
                                <enumeratedValue>
                                    <name>010</name>
                                    <description>3RSPCK</description>
                                    <value>#010</value>
                                </enumeratedValue>
                                <enumeratedValue>
                                    <name>011</name>
                                    <description>4RSPCK</description>
                                    <value>#011</value>
                                </enumeratedValue>
                                <enumeratedValue>
                                    <name>100</name>
                                    <description>5RSPCK</description>
                                    <value>#100</value>
                                </enumeratedValue>
                                <enumeratedValue>
                                    <name>101</name>
                                    <description>6RSPCK</description>
                                    <value>#101</value>
                                </enumeratedValue>
                                <enumeratedValue>
                                    <name>110</name>
                                    <description>7RSPCK</description>
                                    <value>#110</value>
                                </enumeratedValue>
                                <enumeratedValue>
                                    <name>111</name>
                                    <description>8RSPCK</description>
                                    <value>#111</value>
                                </enumeratedValue>
                            </enumeratedValues>
                        </field>
                        <field>
                            <name>SPNDL</name>
                            <description>SPI Next-Access Delay</description>
                            <lsb>16</lsb>
                            <msb>18</msb>
                            <access>read-write</access>
                            <enumeratedValues>
                                <enumeratedValue>
                                    <name>000</name>
                                    <description>1RSPCK + 5TCLK</description>
                                    <value>#000</value>
                                </enumeratedValue>
                                <enumeratedValue>
                                    <name>001</name>
                                    <description>2RSPCK + 5TCLK</description>
                                    <value>#001</value>
                                </enumeratedValue>
                                <enumeratedValue>
                                    <name>010</name>
                                    <description>3RSPCK + 5TCLK</description>
                                    <value>#010</value>
                                </enumeratedValue>
                                <enumeratedValue>
                                    <name>011</name>
                                    <description>4RSPCK + 5TCLK</description>
                                    <value>#011</value>
                                </enumeratedValue>
                                <enumeratedValue>
                                    <name>100</name>
                                    <description>5RSPCK + 5TCLK</description>
                                    <value>#100</value>
                                </enumeratedValue>
                                <enumeratedValue>
                                    <name>101</name>
                                    <description>6RSPCK + 5TCLK</description>
                                    <value>#101</value>
                                </enumeratedValue>
                                <enumeratedValue>
                                    <name>110</name>
                                    <description>7RSPCK + 5TCLK</description>
                                    <value>#110</value>
                                </enumeratedValue>
                                <enumeratedValue>
                                    <name>111</name>
                                    <description>8RSPCK + 5TCLK</description>
                                    <value>#111</value>
                                </enumeratedValue>
                            </enumeratedValues>
                        </field>
                    </fields>
                </register>
                <register>
                    <name>SPCR</name>
                    <description>SPI Control Register</description>
                    <addressOffset>0x08</addressOffset>
                    <size>32</size>
                    <access>read-write</access>
                    <resetValue>0x00000000</resetValue>
                    <resetMask>0xffffffff</resetMask>
                    <fields>
                        <field>
                            <name>SPE</name>
                            <description>SPI Function Enable</description>
                            <lsb>0</lsb>
                            <msb>0</msb>
                            <access>read-write</access>
                            <enumeratedValues>
                                <enumeratedValue>
                                    <name>0</name>
                                    <description>SPI function is disabled.</description>
                                    <value>#0</value>
                                </enumeratedValue>
                                <enumeratedValue>
                                    <name>1</name>
                                    <description>SPI function is enabled.</description>
                                    <value>#1</value>
                                </enumeratedValue>
                            </enumeratedValues>
                        </field>
                        <field>
                            <name>SPPE</name>
                            <description>Parity Enable</description>
                            <lsb>8</lsb>
                            <msb>8</msb>
                            <access>read-write</access>
                            <enumeratedValues>
                                <enumeratedValue>
                                    <name>0</name>
                                    <description>A parity bit is not added to transmit data. Received-data parity check is not performed. </description>
                                    <value>#0</value>
                                </enumeratedValue>
                                <enumeratedValue>
                                    <name>1</name>
                                    <description>A parity bit is added to transmit data. Received-data parity check is performed. </description>
                                    <value>#1</value>
                                </enumeratedValue>
                            </enumeratedValues>
                        </field>
                        <field>
                            <name>SPOE</name>
                            <description>Parity Mode</description>
                            <lsb>9</lsb>
                            <msb>9</msb>
                            <access>read-write</access>
                            <enumeratedValues>
                                <enumeratedValue>
                                    <name>0</name>
                                    <description>Even parity is used for transmission and reception.</description>
                                    <value>#0</value>
                                </enumeratedValue>
                                <enumeratedValue>
                                    <name>1</name>
                                    <description>Odd parity is used for transmission and reception.</description>
                                    <value>#1</value>
                                </enumeratedValue>
                            </enumeratedValues>
                        </field>
                        <field>
                            <name>PTE</name>
                            <description>Parity Self-Diagnosis Enable</description>
                            <lsb>11</lsb>
                            <msb>11</msb>
                            <access>read-write</access>
                            <enumeratedValues>
                                <enumeratedValue>
                                    <name>0</name>
                                    <description>Parity circuit self-diagnosis function is disabled.</description>
                                    <value>#0</value>
                                </enumeratedValue>
                                <enumeratedValue>
                                    <name>1</name>
                                    <description>Parity circuit self-diagnosis function is enabled.</description>
                                    <value>#1</value>
                                </enumeratedValue>
                            </enumeratedValues>
                        </field>
                        <field>
                            <name>SCKASE</name>
                            <description>RSPCK Auto-Stop Function Enable</description>
                            <lsb>12</lsb>
                            <msb>12</msb>
                            <access>read-write</access>
                            <enumeratedValues>
                                <enumeratedValue>
                                    <name>0</name>
                                    <description>RSPCK auto-stop function is disabled.</description>
                                    <value>#0</value>
                                </enumeratedValue>
                                <enumeratedValue>
                                    <name>1</name>
                                    <description>RSPCK auto-stop function is enabled.</description>
                                    <value>#1</value>
                                </enumeratedValue>
                            </enumeratedValues>
                        </field>
                        <field>
                            <name>BFDS</name>
                            <description>Between Burst Transfer Frames Delay Select</description>
                            <lsb>13</lsb>
                            <msb>13</msb>
                            <access>read-write</access>
                            <enumeratedValues>
                                <enumeratedValue>
                                    <name>0</name>
                                    <description>Delay (RSPCK delay, SSL negation delay and next-access delay) between frames is inserted in burst transfer</description>
                                    <value>#0</value>
                                </enumeratedValue>
                                <enumeratedValue>
                                    <name>1</name>
                                    <description>Delay between frames is not inserted in burst transfer.</description>
                                    <value>#1</value>
                                </enumeratedValue>
                            </enumeratedValues>
                        </field>
                        <field>
                            <name>MODFEN</name>
                            <description>Mode Fault Error Detection Enable</description>
                            <lsb>14</lsb>
                            <msb>14</msb>
                            <access>read-write</access>
                            <enumeratedValues>
                                <enumeratedValue>
                                    <name>0</name>
                                    <description>Mode fault error detection is disabled.</description>
                                    <value>#0</value>
                                </enumeratedValue>
                                <enumeratedValue>
                                    <name>1</name>
                                    <description>Mode fault error detection is enabled.</description>
                                    <value>#1</value>
                                </enumeratedValue>
                            </enumeratedValues>
                        </field>
                        <field>
                            <name>SPEIE</name>
                            <description>SPI Error Interrupt Enable</description>
                            <lsb>16</lsb>
                            <msb>16</msb>
                            <access>read-write</access>
                            <enumeratedValues>
                                <enumeratedValue>
                                    <name>0</name>
                                    <description>SPI error interrupt request is disabled.</description>
                                    <value>#0</value>
                                </enumeratedValue>
                                <enumeratedValue>
                                    <name>1</name>
                                    <description>SPI error interrupt request is enabled.</description>
                                    <value>#1</value>
                                </enumeratedValue>
                            </enumeratedValues>
                        </field>
                        <field>
                            <name>SPRIE</name>
                            <description>SPI Receive Buffer Full Interrupt Enable</description>
                            <lsb>17</lsb>
                            <msb>17</msb>
                            <access>read-write</access>
                            <enumeratedValues>
                                <enumeratedValue>
                                    <name>0</name>
                                    <description>SPI receive buffer full interrupt request is disabled.</description>
                                    <value>#0</value>
                                </enumeratedValue>
                                <enumeratedValue>
                                    <name>1</name>
                                    <description>SPI receive buffer full interrupt request is enabled.</description>
                                    <value>#1</value>
                                </enumeratedValue>
                            </enumeratedValues>
                        </field>
                        <field>
                            <name>SPIIE</name>
                            <description>SPI Idle Interrupt Enable</description>
                            <lsb>18</lsb>
                            <msb>18</msb>
                            <access>read-write</access>
                            <enumeratedValues>
                                <enumeratedValue>
                                    <name>0</name>
                                    <description>Idle interrupt request is disabled.</description>
                                    <value>#0</value>
                                </enumeratedValue>
                                <enumeratedValue>
                                    <name>1</name>
                                    <description>Idle interrupt request is enabled.</description>
                                    <value>#1</value>
                                </enumeratedValue>
                            </enumeratedValues>
                        </field>
                        <field>
                            <name>SPDRES</name>
                            <description>SPI receive data ready error select</description>
                            <lsb>19</lsb>
                            <msb>19</msb>
                            <access>read-write</access>
                            <enumeratedValues>
                                <enumeratedValue>
                                    <name>0</name>
                                    <description>Receive data full interrupt</description>
                                    <value>#0</value>
                                </enumeratedValue>
                                <enumeratedValue>
                                    <name>1</name>
                                    <description>Error interrupt</description>
                                    <value>#1</value>
                                </enumeratedValue>
                            </enumeratedValues>
                        </field>
                        <field>
                            <name>SPTIE</name>
                            <description>SPI Transmit Buffer Empty Interrupt Enable</description>
                            <lsb>20</lsb>
                            <msb>20</msb>
                            <access>read-write</access>
                            <enumeratedValues>
                                <enumeratedValue>
                                    <name>0</name>
                                    <description>SPI transmit buffer empty interrupt request is disabled.</description>
                                    <value>#0</value>
                                </enumeratedValue>
                                <enumeratedValue>
                                    <name>1</name>
                                    <description>SPI transmit buffer empty interrupt request is enabled.</description>
                                    <value>#1</value>
                                </enumeratedValue>
                            </enumeratedValues>
                        </field>
                        <field>
                            <name>CENDIE</name>
                            <description>SPI Communication End Interrupt Enable</description>
                            <lsb>21</lsb>
                            <msb>21</msb>
                            <access>read-write</access>
                            <enumeratedValues>
                                <enumeratedValue>
                                    <name>0</name>
                                    <description>Communication end interrupt request is disabled.</description>
                                    <value>#0</value>
                                </enumeratedValue>
                                <enumeratedValue>
                                    <name>1</name>
                                    <description>Communication end interrupt request is enabled.</description>
                                    <value>#1</value>
                                </enumeratedValue>
                            </enumeratedValues>
                        </field>
                        <field>
                            <name>SPMS</name>
                            <description>SPI Mode Select</description>
                            <lsb>24</lsb>
                            <msb>24</msb>
                            <access>read-write</access>
                            <enumeratedValues>
                                <enumeratedValue>
                                    <name>0</name>
                                    <description>SPI operation (4-wire)</description>
                                    <value>#0</value>
                                </enumeratedValue>
                                <enumeratedValue>
                                    <name>1</name>
                                    <description>Clock synchronous operation (3-wire)</description>
                                    <value>#1</value>
                                </enumeratedValue>
                            </enumeratedValues>
                        </field>
                        <field>
                            <name>SPFRF</name>
                            <description>SPI Frame Format Select</description>
                            <lsb>25</lsb>
                            <msb>25</msb>
                            <access>read-write</access>
                            <enumeratedValues>
                                <enumeratedValue>
                                    <name>0</name>
                                    <description>Motorola-SPI</description>
                                    <value>#0</value>
                                </enumeratedValue>
                                <enumeratedValue>
                                    <name>1</name>
                                    <description>TI-SSP</description>
                                    <value>#1</value>
                                </enumeratedValue>
                            </enumeratedValues>
                        </field>
                        <field>
                            <name>TXMD</name>
                            <description>Communication Mode Select</description>
                            <lsb>28</lsb>
                            <msb>29</msb>
                            <access>read-write</access>
                            <enumeratedValues>
                                <enumeratedValue>
                                    <name>00</name>
                                    <description>Transmit-Receive</description>
                                    <value>#00</value>
                                </enumeratedValue>
                                <enumeratedValue>
                                    <name>01</name>
                                    <description>Transmit only</description>
                                    <value>#01</value>
                                </enumeratedValue>
                                <enumeratedValue>
                                    <name>Others</name>
                                    <description>Receive only</description>
                                    <isDefault>true</isDefault>
                                </enumeratedValue>
                            </enumeratedValues>
                        </field>
                        <field>
                            <name>MSTR</name>
                            <description>SPI Master/Slave Mode Select</description>
                            <lsb>30</lsb>
                            <msb>30</msb>
                            <access>read-write</access>
                            <enumeratedValues>
                                <enumeratedValue>
                                    <name>0</name>
                                    <description>Slave mode</description>
                                    <value>#0</value>
                                </enumeratedValue>
                                <enumeratedValue>
                                    <name>1</name>
                                    <description>Master mode</description>
                                    <value>#1</value>
                                </enumeratedValue>
                            </enumeratedValues>
                        </field>
                        <field>
                            <name>BPEN</name>
                            <description>Synchronization Circuit Bypass Enable</description>
                            <lsb>31</lsb>
                            <msb>31</msb>
                            <access>read-write</access>
                            <enumeratedValues>
                                <enumeratedValue>
                                    <name>0</name>
                                    <description>Non-Bypass</description>
                                    <value>#0</value>
                                </enumeratedValue>
                                <enumeratedValue>
                                    <name>1</name>
                                    <description>Bypass</description>
                                    <value>#1</value>
                                </enumeratedValue>
                            </enumeratedValues>
                        </field>
                    </fields>
                </register>
                <register>
                    <name>SPCR2</name>
                    <description>SPI Control Register 2</description>
                    <addressOffset>0x0C</addressOffset>
                    <size>32</size>
                    <access>read-write</access>
                    <resetValue>0x00000000</resetValue>
                    <resetMask>0xffffffff</resetMask>
                    <fields>
                        <field>
                            <name>RMFM</name>
                            <description>Frame processing count setting in Master Receive only</description>
                            <lsb>0</lsb>
                            <msb>4</msb>
                            <access>read-write</access>
                        </field>
                        <field>
                            <name>RMEDTG</name>
                            <description>End Trigger in Master Receive only</description>
                            <lsb>6</lsb>
                            <msb>6</msb>
                            <access>write-only</access>
                            <enumeratedValues>
                                <enumeratedValue>
                                    <name>1</name>
                                    <description>Receive End (Writable only when Master Receive only) Reading value is always 0 </description>
                                    <value>#1</value>
                                </enumeratedValue>
                            </enumeratedValues>
                        </field>
                        <field>
                            <name>RMSTTG</name>
                            <description>Start Trigger in Master Receive only</description>
                            <lsb>7</lsb>
                            <msb>7</msb>
                            <access>write-only</access>
                            <enumeratedValues>
                                <enumeratedValue>
                                    <name>1</name>
                                    <description>Receive Start (Writable only when Master Receive only)  Reading value is always 0</description>
                                    <value>#1</value>
                                </enumeratedValue>
                            </enumeratedValues>
                        </field>
                        <field>
                            <name>SPDRC</name>
                            <description>SPI received data ready detect adjustment</description>
                            <lsb>8</lsb>
                            <msb>15</msb>
                            <access>read-write</access>
                        </field>
                        <field>
                            <name>SPLP</name>
                            <description>SPI Loopback</description>
                            <lsb>16</lsb>
                            <msb>16</msb>
                            <access>read-write</access>
                            <enumeratedValues>
                                <enumeratedValue>
                                    <name>0</name>
                                    <description>Normal mode</description>
                                    <value>#0</value>
                                </enumeratedValue>
                                <enumeratedValue>
                                    <name>1</name>
                                    <description>Loopback mode (inverted transmit data = receive data)</description>
                                    <value>#1</value>
                                </enumeratedValue>
                            </enumeratedValues>
                        </field>
                        <field>
                            <name>SPLP2</name>
                            <description>SPI Loopback 2</description>
                            <lsb>17</lsb>
                            <msb>17</msb>
                            <access>read-write</access>
                            <enumeratedValues>
                                <enumeratedValue>
                                    <name>0</name>
                                    <description>Normal mode</description>
                                    <value>#0</value>
                                </enumeratedValue>
                                <enumeratedValue>
                                    <name>1</name>
                                    <description>Loopback mode (transmit data = receive data)</description>
                                    <value>#1</value>
                                </enumeratedValue>
                            </enumeratedValues>
                        </field>
                        <field>
                            <name>MOIFV</name>
                            <description>MOSI Idle Fixed Value</description>
                            <lsb>20</lsb>
                            <msb>20</msb>
                            <access>read-write</access>
                            <enumeratedValues>
                                <enumeratedValue>
                                    <name>0</name>
                                    <description>The fixed value of MOSI idle = 0.</description>
                                    <value>#0</value>
                                </enumeratedValue>
                                <enumeratedValue>
                                    <name>1</name>
                                    <description>The fixed value of MOSI idle = 1.</description>
                                    <value>#1</value>
                                </enumeratedValue>
                            </enumeratedValues>
                        </field>
                        <field>
                            <name>MOIFE</name>
                            <description>MOSI Idle Fixed Value Enable</description>
                            <lsb>21</lsb>
                            <msb>21</msb>
                            <access>read-write</access>
                            <enumeratedValues>
                                <enumeratedValue>
                                    <name>0</name>
                                    <description>The MOSI output value is the last data of previous transfer.</description>
                                    <value>#0</value>
                                </enumeratedValue>
                                <enumeratedValue>
                                    <name>1</name>
                                    <description>The MOSI output value is the set MOIFV bit value.</description>
                                    <value>#1</value>
                                </enumeratedValue>
                            </enumeratedValues>
                        </field>
                    </fields>
                </register>
                <register>
                    <name>SPCR3</name>
                    <description>SPI Control Register 3</description>
                    <addressOffset>0x10</addressOffset>
                    <size>32</size>
                    <access>read-write</access>
                    <resetValue>0x0000ff00</resetValue>
                    <resetMask>0xffffffff</resetMask>
                    <fields>
                        <field>
                            <name>SSL0P</name>
                            <description>SSL0 Signal Polarity</description>
                            <lsb>0</lsb>
                            <msb>0</msb>
                            <access>read-write</access>
                            <enumeratedValues>
                                <enumeratedValue>
                                    <name>0</name>
                                    <description>The SSL0 signal is active low.</description>
                                    <value>#0</value>
                                </enumeratedValue>
                                <enumeratedValue>
                                    <name>1</name>
                                    <description>The SSL0 signal is active high.</description>
                                    <value>#1</value>
                                </enumeratedValue>
                            </enumeratedValues>
                        </field>
                        <field>
                            <name>SSL1P</name>
                            <description>SSL1 Signal Polarity</description>
                            <lsb>1</lsb>
                            <msb>1</msb>
                            <access>read-write</access>
                            <enumeratedValues>
                                <enumeratedValue>
                                    <name>0</name>
                                    <description>The SSL1 signal is active low.</description>
                                    <value>#0</value>
                                </enumeratedValue>
                                <enumeratedValue>
                                    <name>1</name>
                                    <description>The SSL1 signal is active high.</description>
                                    <value>#1</value>
                                </enumeratedValue>
                            </enumeratedValues>
                        </field>
                        <field>
                            <name>SSL2P</name>
                            <description>SSL2 Signal Polarity</description>
                            <lsb>2</lsb>
                            <msb>2</msb>
                            <access>read-write</access>
                            <enumeratedValues>
                                <enumeratedValue>
                                    <name>0</name>
                                    <description>The SSL2 signal is active low.</description>
                                    <value>#0</value>
                                </enumeratedValue>
                                <enumeratedValue>
                                    <name>1</name>
                                    <description>The SSL2 signal is active high.</description>
                                    <value>#1</value>
                                </enumeratedValue>
                            </enumeratedValues>
                        </field>
                        <field>
                            <name>SSL3P</name>
                            <description>SSL3 Signal Polarity</description>
                            <lsb>3</lsb>
                            <msb>3</msb>
                            <access>read-write</access>
                            <enumeratedValues>
                                <enumeratedValue>
                                    <name>0</name>
                                    <description>The SSL3 signal is active low.</description>
                                    <value>#0</value>
                                </enumeratedValue>
                                <enumeratedValue>
                                    <name>1</name>
                                    <description>The SSL3 signal is active high.</description>
                                    <value>#1</value>
                                </enumeratedValue>
                            </enumeratedValues>
                        </field>
                        <field>
                            <name>SPBR</name>
                            <description>SPI Bit Rate</description>
                            <lsb>8</lsb>
                            <msb>15</msb>
                            <access>read-write</access>
                        </field>
                        <field>
                            <name>SPSLN</name>
                            <description>SPI Sequence Length</description>
                            <lsb>24</lsb>
                            <msb>26</msb>
                            <access>read-write</access>
                            <enumeratedValues>
                                <enumeratedValue>
                                    <name>000</name>
                                    <description>Sequence Length is 1 (Referenced SPCMDn, n = 0→0→…)</description>
                                    <value>#000</value>
                                </enumeratedValue>
                                <enumeratedValue>
                                    <name>001</name>
                                    <description>Sequence Length is 2 (Referenced SPCMDn, n = 0→1→0→…)</description>
                                    <value>#001</value>
                                </enumeratedValue>
                                <enumeratedValue>
                                    <name>010</name>
                                    <description>Sequence Length is 3 (Referenced SPCMDn, n = 0→1→2→0→…)</description>
                                    <value>#010</value>
                                </enumeratedValue>
                                <enumeratedValue>
                                    <name>011</name>
                                    <description>Sequence Length is 4 (Referenced SPCMDn, n = 0→1→2→3→0→…)</description>
                                    <value>#011</value>
                                </enumeratedValue>
                                <enumeratedValue>
                                    <name>100</name>
                                    <description>Sequence Length is 5 (Referenced SPCMDn, n = 0→1→2→3→4→0→…)</description>
                                    <value>#100</value>
                                </enumeratedValue>
                                <enumeratedValue>
                                    <name>101</name>
                                    <description>Sequence Length is 6 (Referenced SPCMDn, n = 0→1→2→3→4→5→0→…)</description>
                                    <value>#101</value>
                                </enumeratedValue>
                                <enumeratedValue>
                                    <name>110</name>
                                    <description>Sequence Length is 7 (Referenced SPCMDn, n = 0→1→2→3→4→5→6→0→…)</description>
                                    <value>#110</value>
                                </enumeratedValue>
                                <enumeratedValue>
                                    <name>111</name>
                                    <description>Sequence Length is 8 (Referenced SPCMDn, n = 0→1→2→3→4→5→6→7→0→…)</description>
                                    <value>#111</value>
                                </enumeratedValue>
                            </enumeratedValues>
                        </field>
                    </fields>
                </register>
                <register>
                    <dim>8</dim>
                    <dimIncrement>0x04</dimIncrement>
                    <dimIndex>0-7</dimIndex>
                    <name>SPCMD%s</name>
                    <description>SPI Command Register</description>
                    <addressOffset>0x14</addressOffset>
                    <size>32</size>
                    <access>read-write</access>
                    <resetValue>0x00070000</resetValue>
                    <resetMask>0xffffffff</resetMask>
                    <fields>
                        <field>
                            <name>CPHA</name>
                            <description>RSPCK Phase</description>
                            <lsb>0</lsb>
                            <msb>0</msb>
                            <access>read-write</access>
                            <enumeratedValues>
                                <enumeratedValue>
                                    <name>0</name>
                                    <description>Data is sampled at an odd edge and changes at an even edge.</description>
                                    <value>#0</value>
                                </enumeratedValue>
                                <enumeratedValue>
                                    <name>1</name>
                                    <description>Data changes at an odd edge and is sampled at an even edge.</description>
                                    <value>#1</value>
                                </enumeratedValue>
                            </enumeratedValues>
                        </field>
                        <field>
                            <name>CPOL</name>
                            <description>RSPCK Polarity</description>
                            <lsb>1</lsb>
                            <msb>1</msb>
                            <access>read-write</access>
                            <enumeratedValues>
                                <enumeratedValue>
                                    <name>0</name>
                                    <description>RSPCK in idle state is 0.</description>
                                    <value>#0</value>
                                </enumeratedValue>
                                <enumeratedValue>
                                    <name>1</name>
                                    <description>RSPCK in idle state is 1.</description>
                                    <value>#1</value>
                                </enumeratedValue>
                            </enumeratedValues>
                        </field>
                        <field>
                            <name>BRDV</name>
                            <description>Bit Rate Division</description>
                            <lsb>2</lsb>
                            <msb>3</msb>
                            <access>read-write</access>
                            <enumeratedValues>
                                <enumeratedValue>
                                    <name>00</name>
                                    <description>Base bit rate</description>
                                    <value>#00</value>
                                </enumeratedValue>
                                <enumeratedValue>
                                    <name>01</name>
                                    <description>Base bit rate divided by 2</description>
                                    <value>#01</value>
                                </enumeratedValue>
                                <enumeratedValue>
                                    <name>10</name>
                                    <description>Base bit rate divided by 4</description>
                                    <value>#10</value>
                                </enumeratedValue>
                                <enumeratedValue>
                                    <name>11</name>
                                    <description>Base bit rate divided by 8</description>
                                    <value>#11</value>
                                </enumeratedValue>
                            </enumeratedValues>
                        </field>
                        <field>
                            <name>SSLKP</name>
                            <description>SSL Signal Level Hold</description>
                            <lsb>7</lsb>
                            <msb>7</msb>
                            <access>read-write</access>
                            <enumeratedValues>
                                <enumeratedValue>
                                    <name>0</name>
                                    <description>All SSL signals are negated at the end of transfer.</description>
                                    <value>#0</value>
                                </enumeratedValue>
                                <enumeratedValue>
                                    <name>1</name>
                                    <description>SSL signal level is held after the transfer ends until the next access starts.</description>
                                    <value>#1</value>
                                </enumeratedValue>
                            </enumeratedValues>
                        </field>
                        <field>
                            <name>LSBF</name>
                            <description>SPI LSB First</description>
                            <lsb>12</lsb>
                            <msb>12</msb>
                            <access>read-write</access>
                            <enumeratedValues>
                                <enumeratedValue>
                                    <name>0</name>
                                    <description>MSB first</description>
                                    <value>#0</value>
                                </enumeratedValue>
                                <enumeratedValue>
                                    <name>1</name>
                                    <description>LSB first</description>
                                    <value>#1</value>
                                </enumeratedValue>
                            </enumeratedValues>
                        </field>
                        <field>
                            <name>SPNDEN</name>
                            <description>SPI Next-Access Delay Enable</description>
                            <lsb>13</lsb>
                            <msb>13</msb>
                            <access>read-write</access>
                            <enumeratedValues>
                                <enumeratedValue>
                                    <name>0</name>
                                    <description>Next-access delay is 1RSPCK + 5TCLK</description>
                                    <value>#0</value>
                                </enumeratedValue>
                                <enumeratedValue>
                                    <name>1</name>
                                    <description>Next-access delay is the set value of the SPI next-access delay (SPDECR.SPNDL).</description>
                                    <value>#1</value>
                                </enumeratedValue>
                            </enumeratedValues>
                        </field>
                        <field>
                            <name>SLNDEN</name>
                            <description>SSL Negation Delay Setting Enable</description>
                            <lsb>14</lsb>
                            <msb>14</msb>
                            <access>read-write</access>
                            <enumeratedValues>
                                <enumeratedValue>
                                    <name>0</name>
                                    <description>[Master] SSL negation delay is 1RSPCK. [Slave in the TI-SSP] SSL negation delay is 1TCLK </description>
                                    <value>#0</value>
